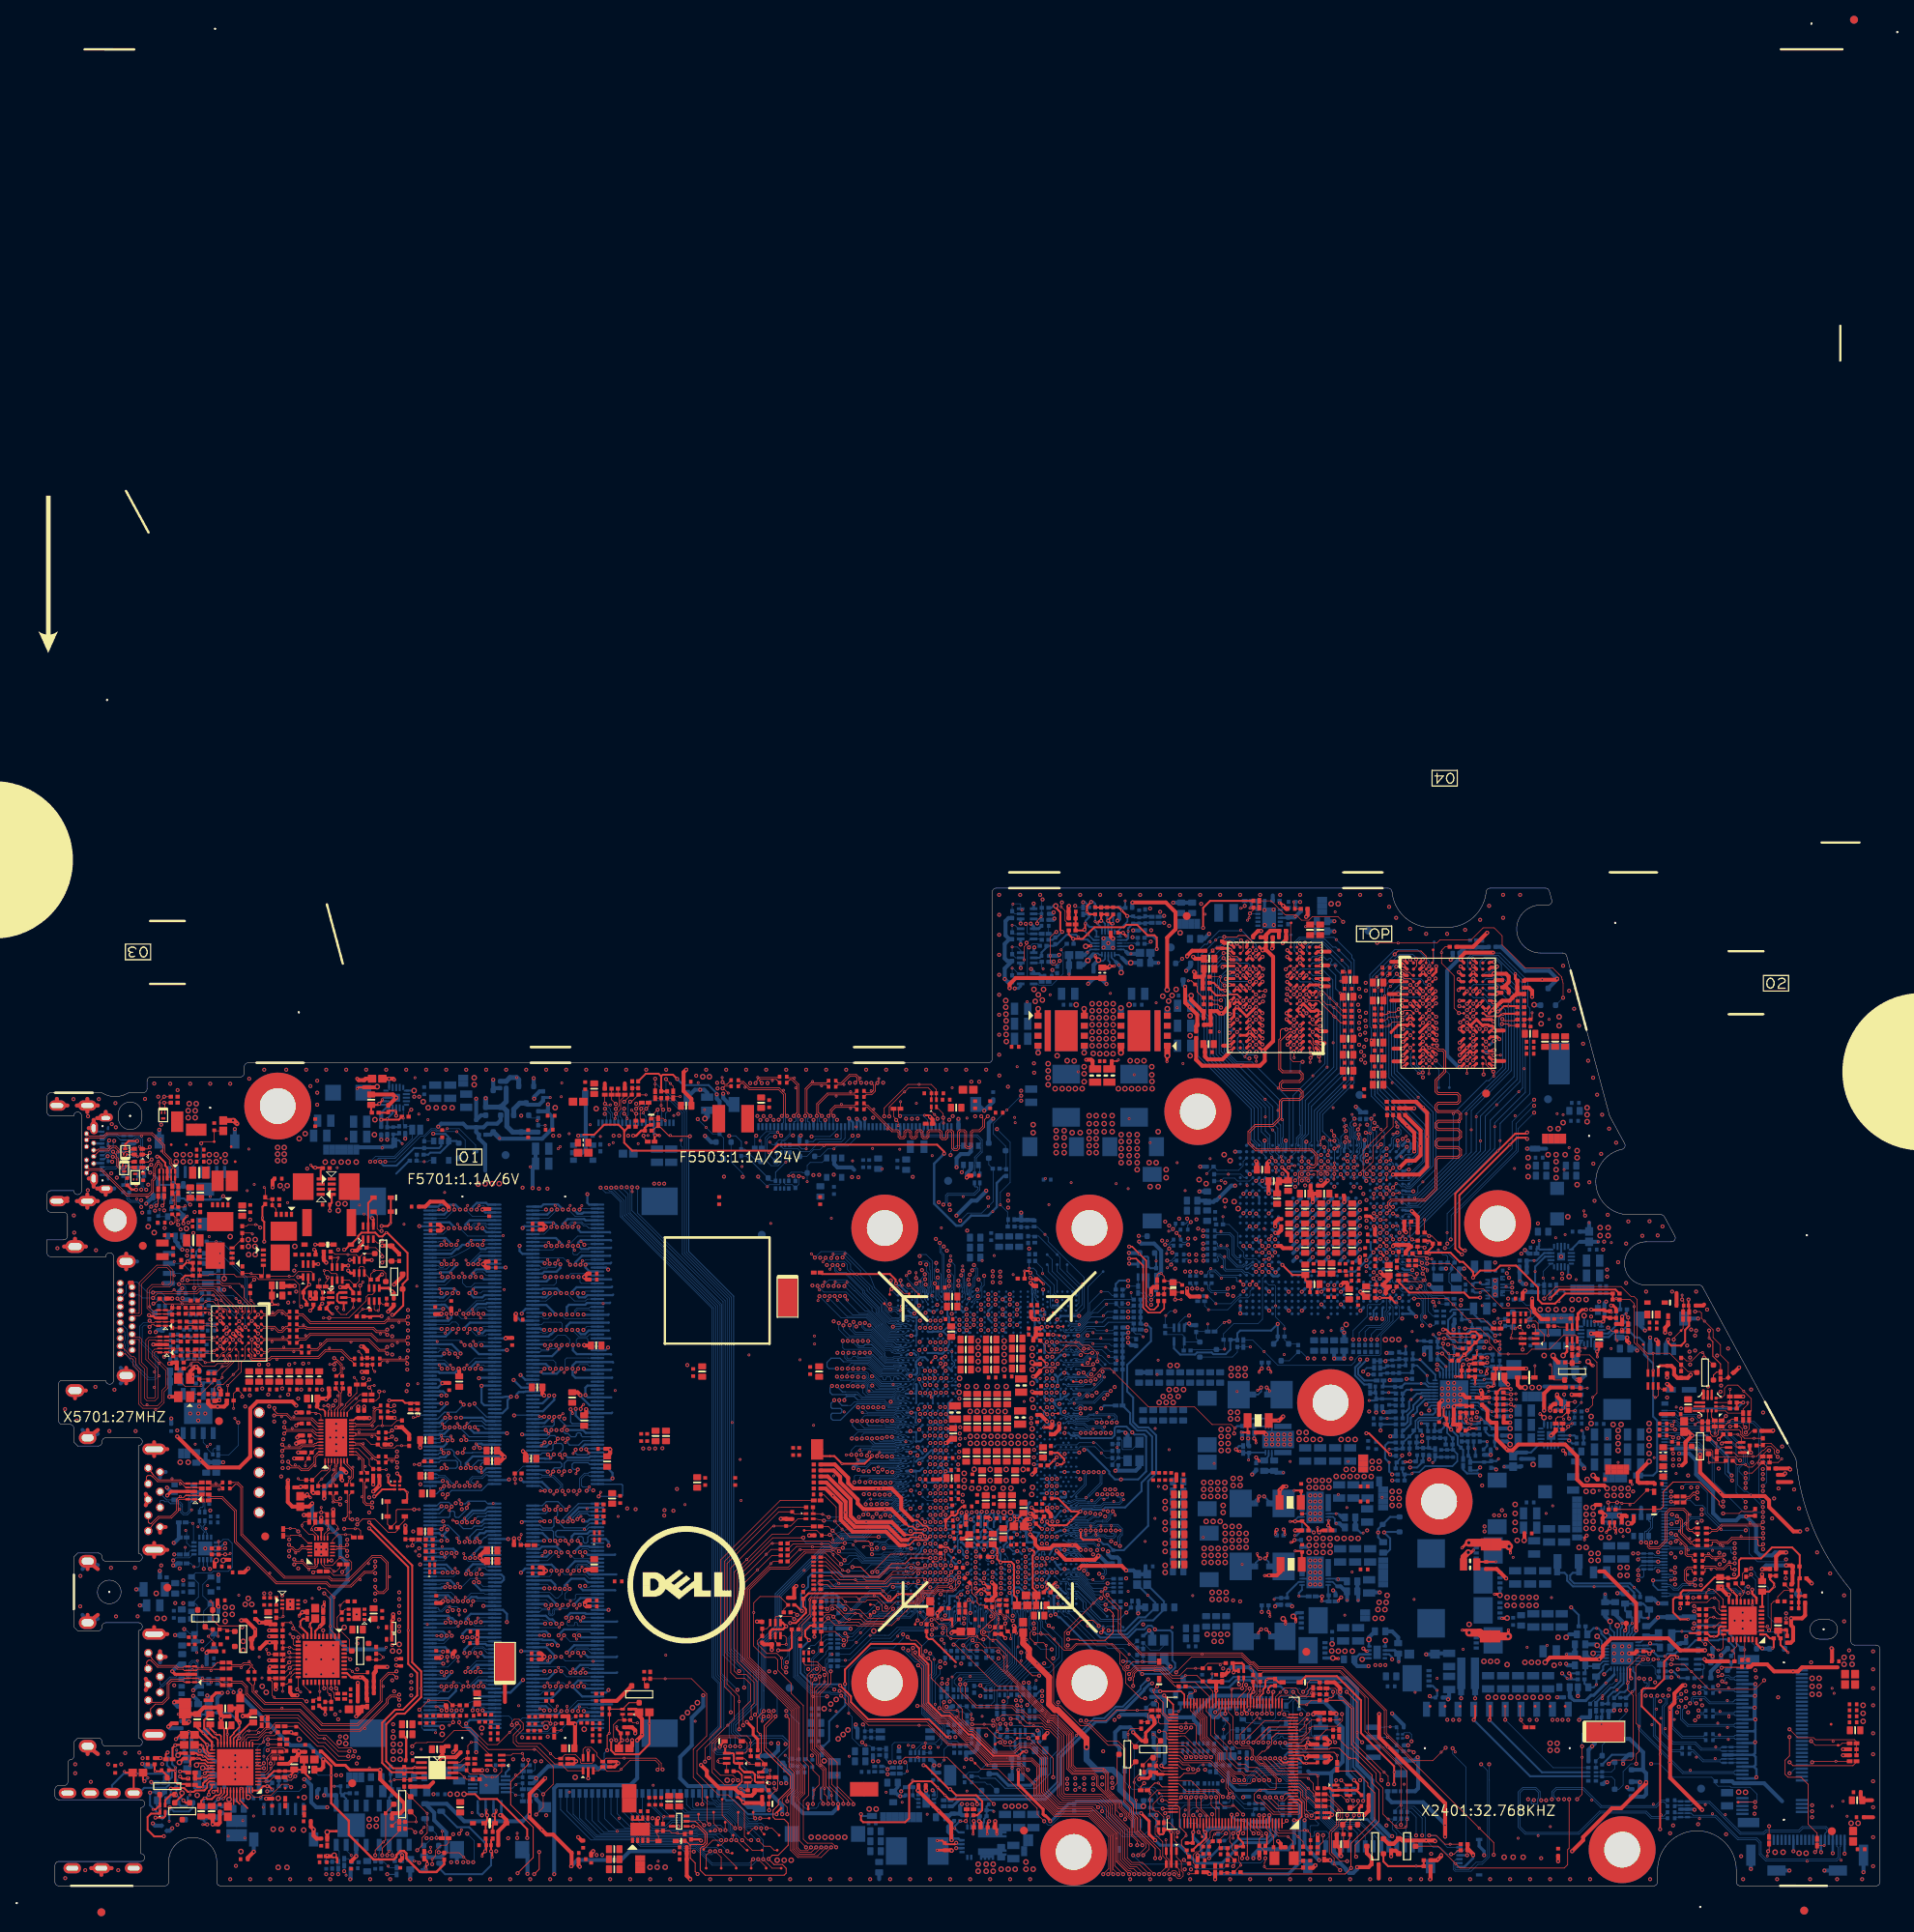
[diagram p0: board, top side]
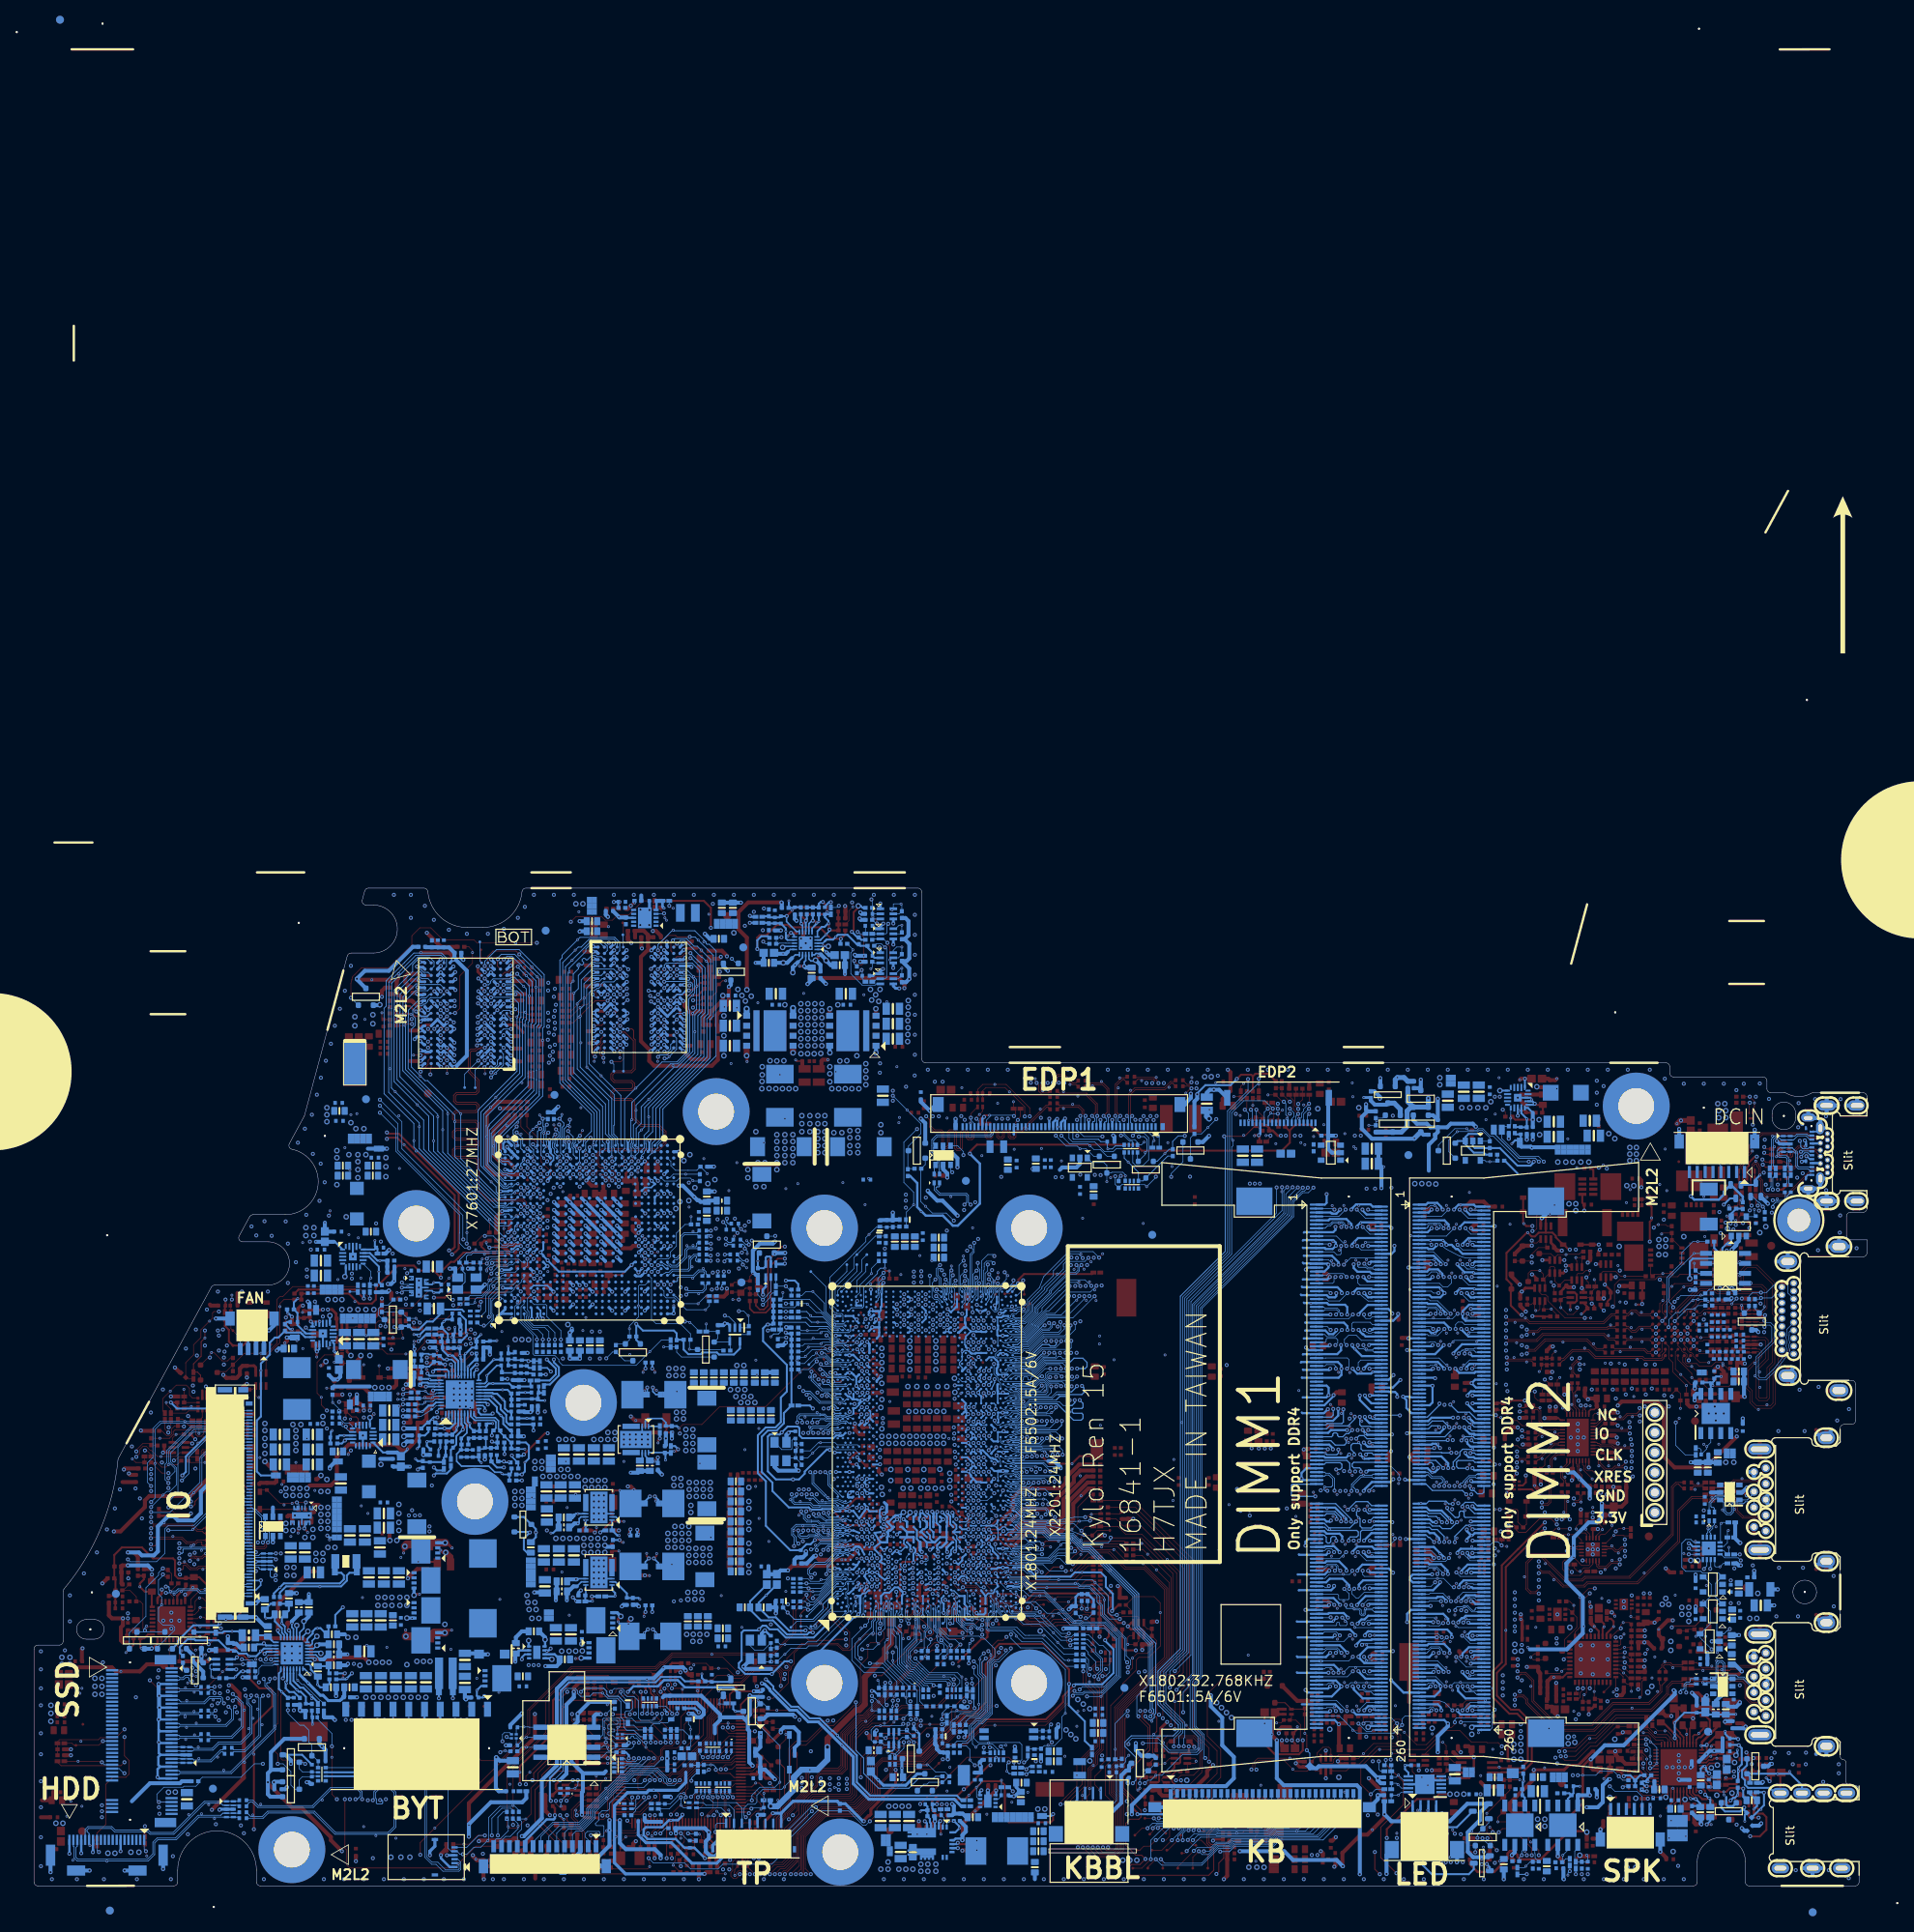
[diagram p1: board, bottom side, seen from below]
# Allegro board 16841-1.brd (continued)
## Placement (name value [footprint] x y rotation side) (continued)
R6801  0R2J-2-GP  [R402H16]  171.22 8.98 180 bottom
R6802  0R2J-2-GP  [R402H16]  171.98 8.98 180 bottom
R6803  0R2J-2-GP  [R402H16]  172.74 8.98 180 bottom
R7002  0R2J-2-GP  [R402H16]  213.66 54.04 90 top
R7003  -  [0R0402-PAD]  218.33 54.57 270 top
R7004  -  [0R0603-PAD]  207.92 58.38 180 top
R7005  10KR2J-3-GP  [R402H16]  214.17 61.43 270 top
R7006  10KR2J-3-GP  [R402H16]  214.17 60.67 90 top
R7007  -  [0R0402-PAD]  214.17 62.19 270 top
R7008  -  [0R0402-PAD]  212.06 54.72 0 top
R7009  -  [0R0402-PAD]  212.24 58.38 270 top
R7010  -  [0R0402-PAD]  210.97 58.51 180 top
R7012  -  [0R0402-PAD]  212.24 59.14 270 top
R7013  -  [0R0402-PAD]  210.21 58.51 180 top
R7014  -  [0R0402-PAD]  215.41 59.65 180 top
R7015  -  [0R0402-PAD]  216.17 59.65 180 top
R7018  100KR2J-1-GP  [R402H16]  213.33 57.39 90 top
R7301  2K49R2F-GP  [R402H16]  147.72 91.4 90 bottom
R7302  10KR2F-2-GP  [R402H16]  148.91 84.06 90 bottom
R7303  10KR2J-3-GP  [R402H16]  156.74 69.81 90 bottom
R7304  0R2J-2-GP  [R402H16]  142.01 70.7 180 bottom
R7305  0R2J-2-GP  [R402H16]  158.9 68.29 0 bottom
R7306  100KR2F-L1-GP  [R402H16]  145.94 70.83 0 bottom
R7307  200R2F-L-GP  [R402H16]  148.23 90 180 bottom
R7312  10KR2J-3-GP  [R402H16]  149.85 69.4 270 bottom
R7313  0R2J-2-GP  [R402H16]  144.8 68.03 270 bottom
R7501  60D4R2F-GP  [R402H16]  170.96 98.39 180 top
R7503  60D4R2F-GP  [R402H16]  170.2 98.39 180 top
R7505  40D2R2F-GP  [R402H16]  170.58 99.66 270 top
R7506  60D4R2F-GP  [R402H16]  171.72 98.39 180 top
R7507  42D2R2F-GP  [R402H16]  172.49 98.39 0 top
R7516  10KR2F-2-GP  [R402H16]  169.06 110.74 270 top
R7518  10KR2J-3-GP  [R402H16]  170.33 75.02 225 top
R7519  0R2J-2-GP  [R402H16]  168.65 75.14 180 top
R7520  10KR2F-2-GP  [R402H16]  167.53 97.88 180 bottom
R7521  10KR2F-2-GP  [R402H16]  166.77 97.88 180 bottom
R7524  10KR2F-2-GP  [R402H16]  165.25 109.69 90 top
R7601  10KR2J-3-GP  [R402H16]  172.99 80.35 270 top
R7602  10KR2J-3-GP  [R402H16]  171.67 81.02 180 top
R7603  1MR2J-1-GP  [R402H16]  178.33 79.21 90 bottom
R7604  1K3R2J-GP  [R402H16]  176.55 79.21 270 bottom
R7605  100KR2J-1-GP  [R402H16]  176.93 71.59 90 bottom
R7607  40K2R2F-GP  [R402H16]  169.23 76.4 270 top
R7608  49K9R2F-L-GP  [R402H16]  168.17 68.29 180 bottom
R7609  49K9R2F-L-GP  [R402H16]  179.6 67.52 270 top
R7610  100KR2J-1-GP  [R402H16]  170.96 76.16 270 top
R7611  49K9R2F-L-GP  [R402H16]  167.41 68.29 180 bottom
R7614  49K9R2F-L-GP  [R402H16]  181 69.05 270 top
R7615  49K9R2F-L-GP  [R402H16]  166.64 68.29 180 bottom
R7617  10KR2J-3-GP  [R402H16]  171.44 79.01 180 top
R7618  10KR2F-2-GP  [R402H16]  174.52 82 270 top
R7619  49K9R2F-L-GP  [R402H16]  180.23 68.29 270 top
R7620  4K99R2F-L-GP  [R402H16]  174.77 80.48 270 top
R7621  4K99R2F-L-GP  [R402H16]  173.63 81.24 270 top
R7623  -  [0R0402-PAD]  212.54 64.86 0 top
R7624  10KR2F-2-GP  [R402H16]  174.52 83.02 270 top
R7625  49K9R2F-L-GP  [R402H16]  181.63 69.81 270 top
R7626  49K9R2F-L-GP  [R402H16]  165.88 68.29 180 bottom
R7627  10KR2J-3-GP  [R402H16]  213.84 64.91 135 top
R7628  49K9R2F-L-GP  [R402H16]  178.84 66.76 270 top
R7629  49K9R2F-L-GP  [R402H16]  168.93 68.29 180 bottom
R7630  -  [0R0402-PAD]  151.94 68.92 180 bottom
R7631  10KR2J-3-GP  [R402H16]  151.18 68.92 180 bottom
R7632  4K99R2F-L-GP  [R402H16]  172.82 84.42 270 top
R7633  10KR2J-3-GP  [R402H16]  185.57 72.22 0 top
R7634  -  [0R0402-PAD]  147.85 70.45 90 bottom
R7635  4K99R2F-L-GP  [R402H16]  176.42 81.62 90 top
R7636  -  [0R0402-PAD]  184.17 70.83 90 top
R7643  10KR2J-3-GP  [R402H16]  168.68 79.21 0 top
R7644  10KR2J-3-GP  [R402H16]  188.62 73.37 180 bottom
R7648  10KR2J-3-GP  [R402H16]  186.71 74.51 90 bottom
R7649  10KR2J-3-GP  [R402H16]  185.19 71.59 180 bottom
R7657  -  [0R0402-PAD]  186.33 72.22 0 top
R7801  40D2R2F-GP  [R402H16]  187.17 109.33 90 top
R7802  40D2R2F-GP  [R402H16]  187.17 110.1 90 top
R7803  931R2F-1-GP  [R402H16]  183.54 119.34 270 bottom
R7804  931R2F-1-GP  [R402H16]  187.17 115.02 90 top
R7805  549R2F-GP  [R402H16]  178.96 118.58 270 bottom
R7806  549R2F-GP  [R402H16]  187.17 114.16 270 top
R7807  1K33R2F-GP  [R402H16]  187.63 112.92 0 top
R7808  121R2F-GP  [R402H16]  187.17 111.67 90 top
R7809  1K33R2F-GP  [R402H16]  182.27 119.72 0 bottom
R7810  1KR2J-1-GP  [R402H16]  178.58 119.34 270 top
R7811  1KR2J-1-GP  [R402H16]  169.06 109.21 90 top
R7812  1KR2J-1-GP  [R402H16]  169.06 109.97 270 top
R7813  121R2F-GP  [R402H16]  187.17 110.88 90 top
R7901  1K33R2F-GP  [R402H16]  156.92 121.38 90 top
R7902  931R2F-1-GP  [R402H16]  146.52 109.42 270 top
R7903  549R2F-GP  [R402H16]  147.79 109.01 180 top
R7904  1K33R2F-GP  [R402H16]  147.33 111.17 270 top
R7905  931R2F-1-GP  [R402H16]  145.94 108.16 180 top
R7906  40D2R2F-GP  [R402H16]  147.36 112.87 270 top
R7907  549R2F-GP  [R402H16]  155.24 120.56 270 top
R7908  40D2R2F-GP  [R402H16]  147.36 112.03 270 top
R7909  1KR2J-1-GP  [R402H16]  147.21 115.53 90 top
R7910  1KR2J-1-GP  [R402H16]  165.25 110.45 90 top
R7911  1KR2J-1-GP  [R402H16]  165.25 111.21 270 top
R7912  121R2F-GP  [R402H16]  147.21 114.01 270 top
R7913  121R2F-GP  [R402H16]  147.21 114.77 270 top
R8301  0R2J-2-GP  [R402H16]  199.28 75.27 270 top
R8303  0R2J-2-GP  [R402H16]  207.54 66.66 0 top
R8304  1MR2J-1-GP  [R402H16]  207.54 64.98 0 top
R8305  0R2J-2-GP  [R402H16]  138.96 119.72 270 bottom
R8306  0R2J-2-GP  [R402H16]  128.29 116.42 0 bottom
R8307  10KR2F-2-GP  [R402H16]  121.81 90.64 0 bottom
R8308  0R2J-2-GP  [R402H16]  120.54 91.15 90 bottom
R9101  0R2J-2-GP  [R402H16]  223.29 36.41 180 top
R9102  0R2J-2-GP  [R402H16]  222.14 40.6 90 top
R9103  0R2J-2-GP  [R402H16]  223.03 39.08 270 top
R9110  0R2J-2-GP  [R402H16]  210.28 36.69 90 top
R9119  10KR2J-3-GP  [R402H16]  207.92 36.66 90 top
R9120  10KR2J-3-GP  [R402H16]  221.13 38.31 90 top
R9129  100R2F-L1-GP-U  [R402H14]  215.79 39.71 180 top
R9130  0R2J-2-GP  [R402H16]  210.28 34.4 270 top
R9131  10KR2J-3-GP  [R402H16]  220.24 36.16 90 top
R9132  33R2J-2-GP  [R402H16]  210.28 35.17 90 top
R9133  0R2J-2-GP  [R402H16]  214.9 38.44 90 top
R9134  33R2J-2-GP  [R402H16]  210.28 31.36 90 top
R9138  10KR2J-3-GP  [R402H16]  222.02 37.55 270 top
R9139  33R2J-2-GP  [R402H16]  210.28 32.88 90 top
R9140  10KR2J-3-GP  [R402H16]  210.28 33.64 90 top
R9141  10KR2J-3-GP  [R402H16]  216.05 28.28 0 top
R9142  0R2J-2-GP  [R402H16]  215.29 28.28 0 top
R9143  0R2J-2-GP  [R402H16]  221 31.33 180 top
R9144  0R2J-2-GP  [R402H16]  219.73 31.46 270 top
R9145  0R2J-2-GP  [R402H16]  218.84 39.84 0 top
R9146  0R2J-2-GP  [R402H16]  219.6 39.84 0 top
R9147  0R2J-2-GP  [R402H16]  213.51 38.7 0 top
R9148  10KR2J-3-GP  [R402H16]  213.89 28.54 270 top
R9149  0R2J-2-GP  [R402H16]  210.28 32.12 90 top
R9150  0R2J-2-GP  [R402H16]  207.92 35.9 90 top
RN801  SRN2K2J-1-GP  [ARES2H16]  125.12 21.8 180 bottom
RN803  SRN2K2J-1-GP  [ARES2H16]  123.59 21.8 180 bottom
RN1201  SRN1KJ-7-GP  [SMD-ARES4H18]  69.83 44.43 0 top
RN1301  SRN1KJ-7-GP  [SMD-ARES4H18]  48.92 40.35 0 top
RN1601  SRN10KJ-6-GP  [ARES8-CN24-MUH20]  135.91 38.19 270 bottom
RN1703  SRN10KJ-5-GP  [ARES2H18]  105.56 14.85 90 bottom
RN1704  SRN10KJ-6-GP  [ARES8-CN24-MUH20]  110.51 16.47 180 bottom
RN1801  SRN20KJ-1-GP  [SMD-ARES4H20]  73.55 22.14 90 top
RN1802  SRN1KJ-7-GP  [SMD-ARES4H18]  96.41 29.17 180 top
RN1803  SRN10J-1-GP  [ARES8-CN24-UH18]  99.97 31.08 90 bottom
RN1807  SRN2K2J-4-GP  [ARES8-CN24-UH20]  115.97 24.47 180 bottom
RN1810  SRN10KJ-5-GP  [ARES2H18]  65.68 15.84 90 top
RN1811  SRN2K2J-1-GP  [ARES2H16]  71.01 15.45 90 top
RN1812  SRN10KJ-6-GP  [ARES8-CN24-MUH20]  97.81 40.93 270 top
RN1813  SRN10KJ-6-GP  [ARES8-CN24-MUH20]  97.81 38.54 270 top
RN1902  SRN33J-5-GP-U  [SMD-ARES4H18]  96.84 46.98 270 top
RN2007  SRN1KJ-7-GP  [SMD-ARES4H18]  121.31 24.73 0 bottom
RN2008  SRN2K2J-1-GP  [ARES2H16]  119.53 24.47 0 bottom
RN2009  SRN10KJ-5-GP  [ARES2H18]  121.38 36 90 top
RN2402  SRN4K7J-8-GP  [SMD-ARES4H18]  161.82 8.98 90 top
RN2403  SRN100KJ-5-GP  [ARES8-CN24H20]  145.31 12.53 0 bottom
RN2404  SRN100KJ-5-GP  [ARES8-CN24H20]  147.85 12.53 0 bottom
RN2405  SRN100KJ-6-GP  [SMD-ARES4]  165.48 12.08 90 bottom
RN2406  SRN100KJ-6-GP  [SMD-ARES4]  151.66 26.88 0 top
RN2407  SRN100KJ-6-GP  [SMD-ARES4]  157.37 10.12 270 bottom
RN2409  SRN100KJ-5-GP  [ARES8-CN24H20]  154.58 23.33 0 bottom
RN2410  SRN100KJ-5-GP  [ARES8-CN24H20]  146.58 17.61 0 bottom
RN2411  SRN100KJ-6-GP  [SMD-ARES4]  144.55 17.61 0 bottom
RN2412  SRN100KJ-5-GP  [ARES8-CN24H20]  158.62 15.33 270 bottom
RN2413  SRN2K2J-1-GP  [ARES2H16]  141.5 7.58 0 top
RN2502  SRN10J-8-GP  [SMD-ARES4-2H18-U]  171.85 19.01 90 bottom
RN2503  SRN10J-8-GP  [SMD-ARES4-2H18-U]  158.39 19.01 90 bottom
RN2602  SRN2K2J-1-GP  [ARES2H16]  53.87 15.84 90 top
RN2701  SRN2K2J-1-GP  [ARES2H16]  30 18.3 270 top
RN2702  SRN1KJ-7-GP  [SMD-ARES4H18]  14.68 9.82 0 top
RN2901  SRN2K2J-1-GP  [ARES2H16]  18.03 16.52 90 top
RN3701  SRN2K2J-1-GP  [ARES2H16]  37.36 24.09 90 top
RN3702  SRN2K2J-1-GP  [ARES2H16]  29.48 27.52 270 top
RN4302  SRN100J-4-GP  [ARES8-CN24H20]  196.24 14.18 270 bottom
RN5501  SRN100J-4-GP  [ARES8-CN24H20]  93.49 93.69 0 bottom
RN5502  SRN100KJ-5-GP  [ARES8-CN24H20]  93.37 89.11 180 bottom
RN5503  SRN33J-5-GP-U  [SMD-ARES4H18]  112.63 99.46 0 top
RN6501  SRN10KJ-5-GP  [ARES2H18]  153.94 10.12 270 bottom
RN6502  SRN33J-5-GP-U  [SMD-ARES4H18]  149.12 10.25 270 bottom
RN6503  SRN2K2J-1-GP  [ARES2H16]  123.77 15.89 180 bottom
RN7401  SRN1K8J-GP  [ARES2H18]  178.25 74.28 90 bottom
RN7601  SRN4K7J-8-GP  [SMD-ARES4H18]  187.48 72.24 0 top
RN7602  SRN10KJ-5-GP  [ARES2H18]  146.58 74.64 90 bottom
RN7604  SRN2K2J-1-GP  [ARES2H16]  173.37 79.17 270 top
RN7605  SRN2K2J-1-GP  [ARES2H16]  172.11 77.3 270 top
RN7610  SRN100KJ-6-GP  [SMD-ARES4]  176.93 72.73 90 bottom
SKT251  SKT-G6179HT0321-001-GP  [G6179HT0321-001]  165.12 18.25 270 bottom
SPI25  MX25L12873FM2I-10G-GP  [SOIC8-1H86]  165.12 18.25 90 bottom
SPK1  ACES-CON6-20-GP-U  [50224-0060N-W01]  30.05 5.9 180 bottom
SPR1  SPRING-171-GP  [SPR5128H111]  94.05 76.6 90 top
SPR2  SPRING-171-GP  [SPR5128H111]  196.05 19.6 180 top
SPR3  SPRING-171-GP  [SPR5128H111]  58.15 26.6 270 top
SPR4  SPRING-63-GP  [SPR5630H142]  192.05 106.6 90 bottom
SSD1  SKT-MINI67P-1-GP-U  [APCI0079-P002A]  220.6 18.4 90 bottom
TC3501  SC100U6D3V6MX-GP  [C1206H71]  13.61 37.68 90 bottom
TCBD1  ACES-CON20-29-GP-U  [51530-02001-W01-U]  74.8 100.15 0 bottom
THM261  NCT7718W-GP  [MSOP8-1H44]  49.55 14.69 270 top
TP401  TPAD14-OP-GP  [TPAD14-OP]  129.05 71.08 270 top
TP402  TPAD14-OP-GP  [TPAD14-OP]  134.13 78.07 270 bottom
TP405  TPAD14-OP-GP  [TPAD14-OP]  132.48 66.98 270 top
TP406  TPAD14-OP-GP  [TPAD14-OP]  131.46 66.22 270 top
TP612  TPAD14-OP-GP  [TPAD14-OP]  127.78 72.86 90 top
TP613  TPAD14-OP-GP  [TPAD14-OP]  127.66 71.08 90 top
TP617  TPAD14-OP-GP  [TPAD14-OP]  113.56 67.02 90 top
TP618  TPAD14-OP-GP  [TPAD14-OP]  112.29 66.51 0 top
TP638  TPAD14-OP-GP  [TPAD14-OP]  134.64 34.25 180 bottom
TP801  TPAD14-OP-GP  [TPAD14-OP]  130.32 64.1 0 top
TP1603  TPAD14-OP-GP  [TPAD14-OP]  116.48 32.47 180 bottom
TP1604  TPAD14-OP-GP  [TPAD14-OP]  117.37 33.36 180 bottom
TP1605  TPAD14-OP-GP  [TPAD14-OP]  134.39 66.25 180 bottom
TP1606  TPAD14-OP-GP  [TPAD14-OP]  128.54 69.94 0 top
TP1705  TPAD14-OP-GP  [TPAD14-OP]  128.29 80.22 270 bottom
TP1708  TPAD14-OP-GP  [TPAD14-OP]  115.16 41.72 270 top
TP1709  TPAD14-OP-GP  [TPAD14-OP]  134.13 32.98 180 bottom
TP1802  TPAD14-OP-GP  [TPAD14-OP]  126.13 60.79 0 top
TP1803  TPAD14-OP-GP  [TPAD14-OP]  128.42 60.03 0 top
TP1903  TPAD14-OP-GP  [TPAD14-OP]  96.16 45.17 0 top
TP2101  TPAD14-OP-GP  [TPAD14-OP]  113.78 40.3 0 top
TP2102  TPAD14-OP-GP  [TPAD14-OP]  112.51 41.2 0 top
TP2301  TPAD14-OP-GP  [TPAD14-OP]  107.03 75.16 0 top
TP2302  TPAD14-OP-GP  [TPAD14-OP]  106.35 74 0 top
TP2303  TPAD14-OP-GP  [TPAD14-OP]  109.5 75.24 0 top
TP2304  TPAD14-OP-GP  [TPAD14-OP]  110.72 75.16 0 top
TP2305  TPAD14-OP-GP  [TPAD14-OP]  104.52 34.53 0 top
TP2306  TPAD14-OP-GP  [TPAD14-OP]  104.57 35.75 0 top
TP2307  TPAD14-OP-GP  [TPAD14-OP]  110.26 33.23 0 top
TP2308  TPAD14-OP-GP  [TPAD14-OP]  135.4 32.98 180 bottom
TP2309  TPAD14-OP-GP  [TPAD14-OP]  136.67 32.85 180 bottom
TP2310  TPAD14-OP-GP  [TPAD14-OP]  128.29 78.95 180 bottom
TP2311  TPAD14-OP-GP  [TPAD14-OP]  129.56 78.95 180 bottom
TP2312  TPAD14-OP-GP  [TPAD14-OP]  127.02 80.22 180 bottom
TP2313  TPAD14-OP-GP  [TPAD14-OP]  127.02 78.95 180 bottom
TP2401  TPAD14-OP-GP  [TPAD14-OP]  160.04 21.17 0 top
TP3701  TPAD14-OP-GP  [TPAD14-OP]  33.42 24.62 0 top
TP4401  TPAD28-2-GP  [TPAD28]  200.55 33.36 90 top
TP4601  TPAD14-OP-GP  [TPAD14-OP]  182.3 60.57 180 bottom
TP7503  TPAD14-OP-GP  [TPAD14-OP]  170.12 89.7 0 top
TP7601  TPAD14-OP-GP  [TPAD14-OP]  151.53 76.87 90 top
TP7602  TPAD14-OP-GP  [TPAD14-OP]  153.97 75.93 0 top
TP7603  TPAD14-OP-GP  [TPAD14-OP]  169.75 81.74 0 top
TP7604  TPAD14-OP-GP  [TPAD14-OP]  168.8 80.96 0 top
TP7605  TPAD14-OP-GP  [TPAD14-OP]  153.11 76.85 90 top
TP7701  TPAD14-OP-GP  [TPAD14-OP]  169.75 80.08 90 top
TP7801  TPAD14-OP-GP  [TPAD14-OP]  176.76 101.44 270 bottom
TP7802  TPAD14-OP-GP  [TPAD14-OP]  176.17 119.97 270 bottom
TP7803  TPAD14-OP-GP  [TPAD14-OP]  176.04 118.96 90 top
TP7804  TPAD14-OP-GP  [TPAD14-OP]  178.1 101.45 270 bottom
TP7901  TPAD14-OP-GP  [TPAD14-OP]  159.16 103.53 90 bottom
TP7902  TPAD14-OP-GP  [TPAD14-OP]  158.01 122.39 270 top
TP7903  TPAD14-OP-GP  [TPAD14-OP]  158.01 120.86 90 bottom
TP7904  TPAD14-OP-GP  [TPAD14-OP]  157.94 103.53 90 bottom
TP8301  TPAD14-OP-GP  [TPAD14-OP]  192.68 75.53 180 bottom
TP8304  TPAD14-OP-GP  [TPAD14-OP]  201.06 27.52 90 top
TPCON1  ACES-CON8-66-GP  [51574-0084N-W01]  141.4 4.65 180 bottom
U3401  TPS2544RTER-GP  [QFN16-G1D8-UH32]  20.09 42.89 0 bottom
U3501  SY6288DAAC-GP  [SOT-23-5H56]  19.58 34.89 90 bottom
U3502  SY6288DAAC-GP  [SOT-23-5H56]  19.58 38.31 90 bottom
U3503  SY6288DAAC-GP  [SOT-23-5H56]  19.96 31.08 90 bottom
U3701  CYPD4125-40LQXI-4-GP  [QFN40G6-G4D7H24]  34.82 28.79 0 top
U3702  TPS70933DRVR-GP-U  [DFN6F2-G1711-UH32]  39.31 34.5 270 top
U3703  AP2151DFMG-7-GP-U  [DFN6G1820-G1511-UH24]  30.88 35.77 90 top
U3801  TUSB546-DCIRNQR-GP  [QFN40J4060-G2848H32]  36.72 56.98 180 top
U3802  TS3DS10224RUKR-GP  [QFN20J3-G1D8H32]  34.82 42.76 180 top
U4001  G5016KD1U-GP  [DFN14J3020-G255D85H32]  198.78 47.08 180 bottom
U4002  TPS22961DNYT-GP  [DFN8F3-G2517H32]  75.33 7.2 180 top
U4006  APE8937GN2-GP-U  [DFN8G2-G1710-U1H32]  111.65 10.78 270 bottom
U4007  TC7SZ08FU-LJ-CT-GP  [SC70-5H44]  80.28 8.22 270 top
U4301  S-1004NA23I-M5T1U-GP  [SOT-23-5H52]  50.06 93.43 0 bottom
U4302  S-1004NA23I-M5T1U-GP  [SOT-23-5H52]  16.28 83.81 180 bottom
U5501  RT9724GB-GP  [SOT-23-5H51]  99.97 91.27 0 bottom
U5502  APL5324BI-TRG-GP  [SOT-23-5H58]  68.09 93.18 90 bottom
U5701  PS175HDMBGA64GTR2-B1-GP  [BGA64D7H51]  24.4 70.19 270 top
U5702  MX25L2006EM1I-12G-GP-U  [SOIC8H69]  17.95 78.47 90 bottom
U5801  AOZ2023PI-GP  [SOIC8-G3627H67]  19.2 60.03 180 bottom
U7001  LNG2DMTR-GP  [LGA12G2H40]  211.17 61.17 270 top
U7301  U74LVC1G08G-AL5-R-GP-U  [SC70-5-1H44]  143.78 70.06 0 bottom
U8301  G5016KD1U-GP  [DFN14J3020-G255D85H32]  183.92 76.03 90 bottom
U9101  NPCT650JB2YX-GP  [QFN32G5-G3D6H32]  215.36 33.71 270 top
USB1  SKT-USB34-20-GP-U  [SKT-USB34-124102-U]  1.25 93.1 90 bottom
USB2  SKT-USB13-18-GP-U  [SKT-USB13-160166-2]  5.15 49.1 90 bottom
USB3  SKT-USB13-18-GP-U  [SKT-USB13-160166-2]  5.15 25.6 90 bottom
VRAM1  H5GQ2H24AFR-T2C-GP  [BGA170D1214H48]  177.95 110.9 0 bottom
VRAM2  H5GQ2H24AFR-T2C-GP  [BGA170D1214H48]  177.95 110.9 0 top
VRAM3  H5GQ2H24AFR-T2C-GP  [BGA170D1214H48]  155.95 112.9 180 top
VRAM4  H5GQ2H24AFR-T2C-GP  [BGA170D1214H48]  155.95 112.9 180 bottom
X1801  XTAL-24MHZ-87-GP  [OSC-3225-4P-4H30]  137.99 55.21 270 bottom
X1802  X-32D768KHZ-65-GP  [SMD-OSC2H56]  108.99 19.26 0 bottom
X2201  XTAL-24MHZ-87-GP  [OSC-3225-4P-4H30]  141.12 30.06 90 bottom
X2401  XTAL-32D768KHZ-89-GP  [SMD49-12H36]  157.12 3.52 90 top
X5701  XTAL-27MHZ-137-GP  [OSC-3225-4P-4H36]  17.42 63.33 90 top
X7601  XTAL-27MHZ-85-GP-U  [OSC-3225-4P-4H30]  177.82 76.54 180 bottom

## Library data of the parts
AFTP2601-AFTP2604 AFTP2901-AFTP2904 AFTP4301-AFTP4316 AFTP6301 AFTP6303 AFTP6304 AFTP6529-AFTP6537 AFTP6540-AFTP6566 = AFTE14P-75: tolerance: ZZ.AFT14.101
BATT1 = A2014WRA-SF-10PNLNG1NS1R: tolerance: 020.F0867.0010
C715 C1120 C1202-C1206 C1208-C1210 C1303-C1310 C1324 C1325 C1704 C2601 C3513 C3514 C3718 C3819 C4006 C4009 C4012 C4013 C5843-C5845 C5853 C5855 C7004 C7323 C7517 C7604 C7804 C7813 C7907 C7918 PC1107-PC1109 = C603H38: tolerance: 78.10610.5BL
C716 C717 C719 C1101-C1111 C1114 C1116 C1117 C1119 C1121 C1124-C1127 C1207 C1214-C1221 C1225 C1226 C1313 C1315-C1322 C1326 C1327 C1805 C1806 C2101-C2109 C2116 C2117 C2120 C2121 C2418 C2714 C3401 C3508 C3516 C3517 C3703 C3704 C3715 C3722 C4031 C4032 C4034 C5508 C5725 C7312 C7319 C7711-C7714 C7728 C7736 C8305 C8307 C8309 C8310 EC1005 = C402H22: tolerance: 78.10523.5FL
C718 C720 C721 C1229 C1301 C1601 C1602 C1613 C1614 C2110-C2112 C2118 C2406-C2408 C2410-C2414 C2416 C2420-C2423 C2428 C2429 C2602 C2605 C2612 C2722 C2726 C2729 C2740 C2742 C2744 C2747-C2749 C3402 C3403 C3507 C3518 C3601-C3604 C3701 C3702 C3705 C3709 C3716 C3717 C3719 C3721 C3723 C3801-C3818 C3861-C3865 C4007 C4033 C5501 C5504 C5506 C5507 C5509-C5511 C5519 C5531-C5533 C5726-C5728 C5731-C5741 C5824-C5826 C5828 C5829 C5834 C5838 C5839 C5846 C5848 C5849 C5858 C6002 C6307 C6501 C6502 C6505 C7003 C7318 C7501 C7502 C7505 C7506 C7601 C7602 C7605 C7729 C7734 C7735 EC2712-EC2714 PC4313 PC4406 PC4420 PC4501 PC4506 PC4508 PC4513 PC4518 PC4521 PC4522 PC4530-PC4532 PC4602 PC4603 PC4630 PC4631 PC4633 PC4634 PC5004 PC5114 PC5116 PC5118 PC5123 PC5204 PC5208 PC5427 PC8202 PC8220 PC8221 PC8225 PC8226 PC8314 PC8319 = C402H22: tolerance: 78.10422.5FLDL
C1112 C1113 C1115 C1118 C2113-C2115 C2119 C2122 C3404 C3405 C3519 C3520 C4035 C4036 C6317 C6318 C7326 C7518 C7520 C7710 C7717 PC1101-PC1106 PC1114 PC1115 = C603H40: tolerance: 78.22610.5BL
C1211 C1212 C1223 C1224 C1227 C1230-C1232 C1311 C1312 C1330 C1331 = C402H22: tolerance: 078.47510.05FD
C1213 C1314 C5856 = C402H22: tolerance: 78.10523.L2L
C1222 C1323 PC4625 PC4626 = C402H22: tolerance: 78.22321.2FL
C1228 C1328 = C402H22: tolerance: 78.10421.L0L
C1329 R1216 = C603H36: tolerance: 78.22523.L1L
C1605-C1612 C3720 C4003 C6302 C6303 C6311-C6316 C7301-C7308 = C402H22: tolerance: 78.22423.5FL
C1701 EC6401 EC6402 = C402H22: tolerance: 78.22124.2FL
C1710 = C402H22: tolerance: 78.47423.5FL
C1711 = C402H22: tolerance: 78.10324.2FL
C1801 C2202 = C402H22: tolerance: 78.15034.1FL
C1802 C2201 = C402H24: tolerance: 78.12034.1FL
C1803 C1804 C2738 EC2708 PC4430 = C402H22: tolerance: 78.10034.1FLDL
C2405 = C402H22: tolerance: 78.10134.1FL
C2409 C5832 C5833 C5837 C5841 C5842 C5847 C5851 C5852 C6001 C6003 C6005 C6006 C7801 C7901 PC4303-PC4305 PC4431 PC4609 PC4613 PC4615 PC4620 PC4622 PC4635 PC4637 PC4644 PC5213 PC8204 PC8309 = C402H22: tolerance: 78.10324.2FLDL
C2424 C2425 EC1801 EC1901 EC2503 EC2601 EC2602 EC4306 EC4309 EC4310 EC6505-EC6507 = C402H22: tolerance: 78.10034.1FL
C2426 = C402H22: tolerance: 78.22523.5FL
C2430 C2431 C2435 C2603 C2607 C9101 C9104 EC8906 EC8933 EC8935 = C402H22: tolerance: 78.22224.2FL
C2501 C5535-C5537 = C805H54: tolerance: 78.10623.51L
C2502 C2608-C2610 C2614 C2721 C3503 C3515 C4017 C6504 C8308 C9102 C9113 EC1707 EC1712 EC1806-EC1808 EC1902 = C402H22: tolerance: 78.10421.2FL
C2503 C5827 C5831 C5836 C5840 C5850 = C402H22: tolerance: 078.47423.05FD
C2604 C5502 C5503 C5505 C5515 C7310 C7315 C7317 C7324 C7513 C7514 C7603 C7701-C7704 C7708 C7709 C7719-C7726 C7730-C7732 C9105 C9106 C9114 = C603H36: tolerance: 78.47520.5BL
C2606 = C603H36: tolerance: 78.47134.1BL
C2613 EC1102 EC2905 EC2906 EC8920 EC8934 PC4310 PC4311 PC4315 = C402H22: tolerance: 78.10134.1FLDL
C2727 C2730-C2736 C2743 C2745 C2907 C2908 PC5122 PC5402 PC5403 PC5413 PC5414 PC8306 PC8307 = C603H36: tolerance: 78.10610.5BLDL
C2737 C7606 PC4524 PC5001 PC5112 PC8317 = C603H36: tolerance: 78.22523.5BLDL
C2739 C2741 PC4301 PC4416 PC4417 PC4419 PC4424-PC4426 PC4439 PC4440 = C603H36: tolerance: 078.10524.05BD
C2746 PC5119 PC5120 PC8201 PC8316 = C402H22: tolerance: 78.10421.2FLDL
C3502 PC4314 = C402H22: tolerance: 078.10522.05FD
C3512 = C805H58: tolerance: 78.22610.51L
C3707 C7805-C7807 C7809-C7812 C7814 C7904-C7906 C7915-C7917 C7919 C7924 = C603H32: tolerance: 78.10524.5BL
C3710 = C603H36: tolerance: 78.22523.5BL
C3711 C3712 = C402H24: tolerance: 78.39124.2FL
C3821 C7316 C7808 C7815-C7825 C7909-C7914 C7920-C7923 C7925 C7926 EC1203 EC1903 EC2101 EC3601 EC3602 EC4302 EC4311 EC4313 EC5502 EC8901-EC8904 EC8908 EC8909 EC8911-EC8915 EC8917 EC8921 EC8923-EC8925 EC8936 EC8938 EC8951-EC8956 EC8958 PC1110-PC1113 PC4312 = C402H22: tolerance: 78.10422.5FL
C4001 C4002 C8302 C8306 = C402H22: tolerance: 78.47124.2FL
C4004 C4005 C5517 C6004 C8301 C8304 EC4301 PC4306 PC4401-PC4405 PC4407-PC4414 PC4427 PC4428 PC4502-PC4505 PC4519 PC4523 PC4701-PC4704 PC4802-PC4805 PC4814-PC4817 PC5002 PC5003 PC5111 PC5115 PC5209-PC5211 PC5216 PC8210 PC8214 PC8215 PC8224 PC8310 PC8315 = C805H58: tolerance: 78.10622.51LDL
C5512 C5516 C5542 EC4308 = C603H36: tolerance: 78.10424.2BL
C5513 C5534 EC2002 EC2709-EC2711 EC2901-EC2904 EC4307 EC4312 EC8907 EC8910 EC8916 EC8919 EC8922 EC8937 EC8941 EC8945 EC8947 EC8957 EC8959 EC8961 EC8963 EC8967 EC8974-EC8977 EC8979 EC8983 EC8984 EC8987 EC8988 EC8994 EC8996 EC8999 PC4307 PC4432 PC4433 PC4435 PC4526 PC4533 PC4616-PC4619 PC4642 PC4643 PC4651 PC4706 PC4810 PC4813 PC5215 PC8203 = C402H22: tolerance: 78.10224.2FLDL
C5514 PC8208 PC8209 PC8212 PC8213 = C805H54: tolerance: 78.47522.51LDL
C5724 = C0201H13: tolerance: 078.R7574.01S1
C5729 C5730 C7607 C7608 = C402H22: tolerance: 78.18034.1FL
C5857 C5860 C5861 = C603H38: tolerance: 78.10610.L0L
C5859 = C402H22: tolerance: 78.68034.1FL
C6304 C6305 EC5505 EC6501-EC6504 EC6601-EC6603 = C402H22: tolerance: 78.33034.1FL
C6306 C6308 = C402H22: tolerance: 78.47322.2FL
C7507 C7525 PC4438 PC4607 PC4708 PC4809 PC4812 PC5110 PC5121 PC5202 PC5401 PC5410 PC8301 PC8318 = C402H22: tolerance: 78.10523.5FLDL
C7802 C7803 C7826 C7902 C7903 C7908 = C402H22: tolerance: 78.82124.2FL
CCGDB1 = JD11P8204-061: tolerance: 21.61836.106
CPU1 = BGA1356M4224-U2H52: tolerance: 071.SKYLA.000U
D502 EC401 EC1701-EC1705 EC1708 EC1709 ED1217 ED1302 ED2403 ED5502 = SOD882-10D6-1H20: tolerance: 83.05725.0A0
D1701 D2402 D2403 D4002-D4005 PD4306-PD4310 PD4407 = SOD323AKH38: tolerance: 83.R2004.G8F
D2401 D2702 D5501 D5502 D8301 PD4401 PD4408 = SOT-23-9H44: tolerance: 75.00054.A7D
D2501 = SOT-23-9H44: tolerance: 75.00040.07D
D2601 = SOD323AKH38: tolerance: 83.R5003.H8H
D3701 D3702 = D1006-0305AK-UH22: tolerance: 083.00520.0F8F
D4001 = SOT23-2D4-312H44: tolerance: 83.00016.P11
D4304-D4306 PD4302 = SOT23-2D4-312H44: tolerance: 75.00099.O7D
D5701 = SOT23-2D4-312H44: tolerance: 83.00056.Y11
D7001 = SOT23-2D4-312H48: tolerance: 75.00054.R7D
D7301 = SOT-23-9H44: tolerance: 75.BAT54.07D
DB1 = DM-87212-1400N-01: tolerance: ZZ.F0765.01401
DBEC1 = 50696-00601-001: tolerance: 20.K0691.006
DCIN1 = 50224-0080N-W02-U: tolerance: 20.F1295.008
DM1 = ADDR0206-P013A: tolerance: 062.10011.01C1
DM2 = ADDR0205-P012A: tolerance: 062.10011.01B1
EC1001-EC1004 EC1006 EC1007 = C402H22: tolerance: 78.10422.L1L
EC1103 EC1202 EC1302 EC1303 EC1710 = C402H22: tolerance: 78.22510.5FLDL
EC1706 EC8905 EC8918 EC8927-EC8929 EC8939 EC8940 EC8942-EC8944 EC8946 EC8948 EC8949 EC8960 EC8962 EC8964-EC8966 EC8968-EC8973 EC8978 EC8980-EC8982 EC8985 EC8986 EC8989 EC8992 EC8993 EC8995 EC8997 EC8998 = C402H22: tolerance: 78.10224.2FL
EC1803 EC2501 EC2502 = C402H22: tolerance: 78.4R7B4.1FL
EC2907 EC2908 PC4621 PC8312 = C402H22: tolerance: 78.68124.2FLDL
EC5501 = C402H22: tolerance: 78.6R874.1FLDL
EC5503 = C402H22: tolerance: 78.22034.1FL
EC5504 PC4610 PC4624 PC4639 = C402H22: tolerance: 78.33034.1FLDL
ED2901-ED2903 = SOT23-2D4-312H46: tolerance: 75.05125.07D
ED3601 ED3603 ED3801 ED3802 ED5701 ED5702 ED6001 ED6301 ED6602 = SLP2510P8-1H22: tolerance: 075.00550.0071
ED3602 ED3604 ED5501 ED6601 = SOT-6H58: tolerance: 75.09904.07C
ED3803-ED3806 = SOT883-1D0-321H20: tolerance: 83.05315.0A0
ED6401 ED6402 = SOD-523-2H26: tolerance: 83.0005V.0AF
EL3602 EL3603 EL3801 EL3802 EL5501 EL6601 EL6603 = L125100-4P-4H24: tolerance: 68.00396.001
EL4301-EL4304 PR4414 PR4420 R705 R2707 R2712 R2739 R4101 = 0R0805-PAD: tolerance: ZZ.R0805.ZZZ
ER5744 ER5745 ER5758 ER5759 = R402H16: tolerance: 63.18134.1DL
F5502 F6501 = POLYSW-2114H50: tolerance: 69.50007.921
F5503 = POLYSW-4633-UH43: tolerance: 69.50007.A31
F5701 = POLYSW-2114H30: tolerance: 69.48001.081
FAN1 = 50224-0040N-001: tolerance: 20.F1639.004
G1801 = CON2O-U: tolerance: ZZ.CON2O.XXX
GPU1 = BGA595M23H83: tolerance: 071.0N16S.0A0U
H1-H8 H11 H12 H14 = HOLE335R178: tolerance: ZZ.00PAD.7F1
HDA27 = QFN48J6-G465H40: tolerance: 071.03254.0003
HDD1 = 50406-02071-001: tolerance: 20.F2036.020
HDMI2 = SKT-HDMI23-187137-1: tolerance: 022.10025.0191
HPMIC1 = AJ3R1S-Y050-412: tolerance: 022.10002.0931
HS2 = STF217R115H101: tolerance: 434.04X0C.1001
IOBD1 = 20525-060E-02-U: tolerance: 020.F0200.0060
KB1 = 196528-30041-3: tolerance: 020.K0210.0030
KBBL2 = 50698-00401-W01-U: tolerance: 020.K0298.0004
KBC24 = TQFP128-2H48: tolerance: 071.01416.000G
L3801 = L402H22: tolerance: 068.00006.0141
L5801-L5805 = L603H38: tolerance: 68.00084.J11
L7301 = L1608-UH38: tolerance: 68.00230.041
L7501 L7601 = L603H38: tolerance: 68.00335.051
L7602 = L603H38: tolerance: 68.00909.261
LCD1 = 300E50-1030RA-G4: tolerance: 020.F0688.0050
LEDCN1 = 50524-00401-001: tolerance: 020.K0037.0004
PC1001-PC1032 PC1034 PC1036-PC1084 PC5201 PC5203 PC5205 PC5206 PC8303 PC8304 PC8311 PC8313 PC8320 PC8321 = C603H40: tolerance: 78.22610.5BLDL
PC4302 PC5214 PC8207 PC8211 PC8216 = C603H35: tolerance: 78.10424.2BLDL
PC4415 PC4421 PC4422 PC4507 PC4520 = C603H36: tolerance: 78.47520.5BLDL
PC4423 PC4436 PC4606 PC4707 PC4808 PC4811 PC5005 = C603H36: tolerance: 78.22422.2BLDL
PC4429 PC5406 = C402H22: tolerance: 78.47224.2FLDL
PC4441-PC4443 = C805H58: tolerance: 078.22612.051D
PC4509-PC4512 PC4514-PC4517 PC4525 PC4527 PC4529 PC5104 PC5105 PC5107 PC5109 PC5124 PC5404 PC5412 = C805H54: tolerance: 78.22610.51LDL
PC4601 PC4611 PC4612 PC4623 PC4632 PC4640 = C402H22: tolerance: 78.22224.2FLDL
PC4604 PC4614 PC4629 PC4638 PC4641 PC8308 = C402H22: tolerance: 78.33124.2FLDL
PC4605 PC4653 = C402H22: tolerance: 078.47322.02FD
PC4608 PC4652 = C402H22: tolerance: 78.22321.2FLDL
PC4628 = C402H22: tolerance: 78.33321.2FLDL
PC5113 = C402H22: tolerance: 78.47124.2FLDL
PC5212 = C402H22: tolerance: 78.22124.2FLDL
PC5405 PC5411 = C402H22: tolerance: 78.68034.1FLDL
PC8205 PC8219 PC8222 PC8322 = C402H22: tolerance: 78.47034.1FLDL
PC8206 PC8218 = C402H22: tolerance: 78.33134.1FLDL
PC8223 = C402H22: tolerance: 78.27224.2FLDL
PC8302 PC8323 = C402H22: tolerance: 78.22034.1FLDL
PD4301 = DO214AAAKH97: tolerance: 83.P6SMB.JAG
PD4303 = SOT23-2D4-312H60: tolerance: 83.03024.0A1
PD4304 = SOD123AK-2H43: tolerance: 83.SMF18.AAH
PD4305 = SOD323AKH38: tolerance: 83.R2004.B8F
PD4404 = SOD323AKH44: tolerance: 83.00355.G1F
PG4401 PG4402 PG4405 PG4406 PG4408 PG4501-PG4524 PG4527-PG4532 PG4701-PG4708 PG4802-PG4806 PG4808-PG4816 PG5001-PG5003 PG5011 PG5105-PG5115 PG5120 PG5121 PG5201 PG5204 PG5206-PG5216 PG5223 PG5405-PG5409 PG5801-PG5803 PG8301-PG8320 = GAP-CLOSE-PWR-3: tolerance: ZZ.CLOSE.001
PL4401 = L11510030H158: tolerance: 68.2R210.20C
PL4501 = L4947-1015H119: tolerance: 68.1R550.20C
PL4502 PL5201 = L7066-1830-UH119: tolerance: 68.1R01A.20B
PL4701 PL4801 PL4802 = L7366-1930H158: tolerance: 68.R1510.20A
PL5001 = L7066-1830-UH119: tolerance: 68.R4710.10M
PL5101 = L4947-1115H119: tolerance: 68.1R010.20R
PL8201 PL8202 = L6965-1530H158: tolerance: 68.R361A.10B
PL8301 = L2520-D620H48: tolerance: 068.1R010.1131
PL8302 = L4947-1015H119: tolerance: 68.R6810.20E
PQ4301 PQ4314 Q501 Q6105 = SOT23DGS2D4H48: tolerance: 84.05067.031
PQ4302 Q2603 = SOT23CBE2D4H46-U: tolerance: 84.T3904.K11
PQ4304 = SOT323CBE2D2H40: tolerance: 84.05212.B11
PQ4305 = SC70-2D2-312H44: tolerance: 84.00024.01K
PQ4306 PQ4312 PQ4402 Q1802 Q2408 Q2414 Q2505 Q2602 Q2701 Q3701 Q6503 Q7301 Q7606 Q7801 Q7901 Q8301 = SOT23DGS2D4H44: tolerance: 84.2N702.031
PQ4307-PQ4311 PQ4313 PQ4405 PQ4415 PQ4416 PQ8301 PQ8305-PQ8308 Q1702 Q1801 Q2416 Q2417 Q2601 Q6504 Q7001 Q7601 = SOT-363H44: tolerance: 84.2N702.A3F
PQ4408 = SOT23CBE2D4H44: tolerance: 84.T3906.A11
PR4302 PR8327 = R402H16: tolerance: 64.15025.6DL
PR4303 PR4335 PR8258 PR8259 R802 R1503 R1606-R1608 R1701 R1707 R1714 R1717 R1726 R1738 R1816 R1820 R1911-R1920 R2002 R2009 R2010 R2029-R2038 R2040-R2047 R2050-R2053 R2415 R2426 R2429 R2430 R2458 R2464 R2473 R2607 R2726 R2743 R3738 R3818 R4003 R4009 R5736 R5737 R5741 R6120 R6303 R6304 R6511 R7005 R7006 R7303 R7312 R7518 R7601 R7602 R7617 R7627 R7631 R7633 R7643 R7644 R7648 R7649 R9119 R9120 R9131 R9138 R9140 R9141 R9148 = R402H16: tolerance: 63.10334.1DL
PR4304 R1836 R2745 R3707 R5751 R5755 = R402H16: tolerance: 63.22234.1DL
PR4305 PR4306 R9132 R9134 R9139 = R402H16: tolerance: 63.33034.1DL
PR4307 = R603H22: tolerance: 63.24434.15L
PR4308 PR4321 R1719 R2517 = R402H16: tolerance: 64.47025.6DL
PR4309 PR4318 PR4345 PR4473 PR4505 PR4510 PR5104 PR5208 PR8203 PR8307 PR8315 PR8317 PR8319 PR8328 R404 R603 R803 R1715 R1727 R1737 R2407 R2417 R2434 R2436 R2449-R2451 R2454 R2480 R2484 R2489 R2496 R2742 R2744 R2747 R3501 R4031 R4032 R5504 R5545 R5758 R6508 R6509 R6604 R7018 R7605 R7610 = R402H16: tolerance: 63.10434.1DL
PR4310 PR8256 PR8310 R401 R417 R419 R604 R605 R1702 R1822-R1825 R1909 R1910 R2007 R2019 R2432 R2463 R3840-R3843 R3845-R3847 R3852 R3870-R3874 R4005 R6513 R7810-R7812 R7909-R7911 = R402H16: tolerance: 63.10234.1DL
PR4311 PR4323 PR4324 PR4332 PR4340 PR4342 PR4347 PR4406 PR4409 PR4417 PR4474 PR4821-PR4824 PR5203 PR5402 PR8304 PR8311 R1716 R2441 R2444 R3730 R3734 R6305 R7306 = R402H16: tolerance: 64.10035.6DL
PR4312 = R402H16: tolerance: 64.47035.6DL
PR4313 = R402H16: tolerance: 64.84525.6DL
PR4315 = R402H16: tolerance: 64.18725.6DL
PR4316 R1731 R2727 = R402H16: tolerance: 63.20334.1DL
PR4317 PR4501 PR4502 PR8210 PR8211 PR8324 R1102-R1104 R1711 R2106-R2111 R2446 R2705 R2724 R2749 R2751 R2906 R2907 R2909 R2911 R2923 R3732 R3736 R3812 R5507 R5520 R5527 R5528 R6006 R6302 R6307 R6514 R7004 = 0R0603-PAD: tolerance: ZZ.R0603.ZZZ
PR4319 PR4343 R2741 = R402H16: tolerance: 64.20035.6DL
PR4320 PR4330 PR4337 = R402H16: tolerance: 64.24035.6DL
PR4322 PR4327 PR4333 PR4450 PR5204 PR5410 R1306 R2001 R2448 R3709 R3725 R3726 R5542 R5803 R7302 R7516 R7520 R7521 R7524 R7618 R7624 R8307 = R402H16: tolerance: 64.10025.6DL
PR4328 PR5101 PR5107 PR8206 PR8222 R2424 R3403 R4006 R6504 = R402H16: tolerance: 64.20025.6DL
PR4336 PR4344 = R402H16: tolerance: 63.68434.1DL
PR4338 = R2512H28: tolerance: 63.10135.17L
PR4339 = R402H16: tolerance: 64.64925.6DL
PR4341 PR4412 PR4462 PR4476 PR4477 PR4504 PR4515 PR4516 PR5114 PR5118 PR5125 PR5209 PR5210 PR5406 PR5408 PR5417 PR8207 PR8220 PR8221 PR8257 PR8308 PR8320-PR8322 PR8325 PR8330 PR8331 R410 R504 R602 R709 R732 R804 R1205 R1210 R1212 R1303 R1311 R1609 R1610 R1704 R1706 R1708 R1713 R1720 R1728 R1812 R1813 R1908 R2003 R2004 R2020 R2021 R2023 R2024 R2101 R2402 R2406 R2428 R2435 R2445 R2447 R2459 R2462 R2470 R2472 R2477 R2478 R2490 R2515 R2602 R2611-R2614 R2617 R2721 R2729 R2730 R2737 R2738 R2740 R2752 R2753 R2905 R2912-R2915 R2921 R2922 R3401 R3402 R3405 R3406 R3605 R3606 R3609-R3614 R3727-R3729 R3731 R3733 R3814 R3816 R3832-R3839 R3849 R3853-R3860 R4002 R4011 R4024 R4029 R4030 R4036 R4038 R4042 R4301 R5501 R5503 R5521-R5523 R5540 R5543 R5544 R5710-R5717 R6001 R6002 R6301 R6308 R6403 R6404 R6510 R6512 R6605 R6606 R7003 R7007-R7010 R7012-R7015 R7623 R7630 R7634 R7636 R7657 = 0R0402-PAD: tolerance: ZZ.R0402.ZZZ
PR4346 = R402H16: tolerance: 64.13735.6DL
PR4401 = R1206H24: tolerance: 64.R0205.81L
PR4402 PR4408 PR4804 PR4810 = R603H22: tolerance: 64.2R205.55L
PR4403 PR4416 = R805H24: tolerance: 63.2R231.16L
PR4404 = R402H16: tolerance: 64.40235.6DL
PR4405 = R402H16: tolerance: 64.4R705.6DL
PR4407 = R3720H40: tolerance: 64.R0105.7FL
PR4410 = R402H16: tolerance: 64.10535.60L
PR4411 PR4636 PR4658 R403 R6401 = R402H16: tolerance: 64.49905.6DL
PR4413 = R402H16: tolerance: 64.60415.6DL
PR4422 PR4423 = R402H16: tolerance: 64.3R305.6DL
PR4424 PR4425 = R402H16: tolerance: 64.1R005.L0L
PR4426 = R402H16: tolerance: 64.19635.6DL
PR4427 PR4429 = R402H16: tolerance: 64.10035.L1L
PR4435 PR4472 = R402H16: tolerance: 64.10035.L3L
PR4436 PR4513 PR4514 PR5105 R1802 R2201 R3706 R4304 R7603 R8304 = R402H16: tolerance: 63.10534.1DL
PR4463 PR4503 PR4530 PR5103 PR5106 PR5126 PR8323 R738 R1809 R1810 R1838 R2025-R2028 R2039 R2202 R2203 R2408 R2409 R2418 R2427 R2439 R2461 R2471 R2475 R2479 R2494 R2499 R2601 R2615 R2616 R2746 R2754 R3861-R3864 R4010 R4017 R4033 R4037 R4305 R4306 R5502 R5761 R6505 R6506 R6801-R6803 R7002 R7304 R7305 R7313 R7519 R8301 R8303 R8305 R8306 R8308 R9101-R9103 R9110 R9130 R9133 R9142-R9147 R9149 R9150 = R402H16: tolerance: 63.R0034.1DL
PR4475 = R402H16: tolerance: 64.68035.6DL
PR4478 PR4627 PR4631 PR4639 PR4659 PR4663 PR8212 PR8213 R503 R719-R722 R726 R734 R735 R1501 R1604 R9129 = R402H14: tolerance: 64.10005.6DL
PR4506 PR4507 PR4509 PR4511 PR4603 PR4615 PR4635 R4303 R5760 = R402H16: tolerance: 64.10015.6DL
PR4508 PR4512 = R402H16: tolerance: 64.20035.L0L
PR4551 = R402H16: tolerance: 64.34835.6DL
PR4601 PR4602 PR4612 PR4613 PR4623 PR4647 PR4649 PR4665-PR4668 PR4701 PR4702 PR4706 PR4802 PR4806 PR4811 PR4812 PR5004 R5801 = 0R0402-PAD: tolerance: ZZ.R0402.001
PR4604 PR4607 = R402H16: tolerance: 64.10005.L1L
PR4605 = R402H16: tolerance: 64.75R05.6DL
PR4606 = R402H16: tolerance: 64.45R35.6DL
PR4608 = R402H16: tolerance: 64.90925.6DL
PR4609 PR4616 PR4662 R1204 R1208 R1211 R1302 R1310 R3742 = R402H15: tolerance: 64.10025.L0L
PR4610 = R402H16: tolerance: 63.1R034.1DL
PR4611 PR4646 PR4650 = NTC-402H22-U: tolerance: 69.60037.011
PR4614 PR4669 R1307 = R402H15: tolerance: 63.R0034.L0L
PR4617 PR4654 = NTC-402H22-U: tolerance: 69.60037.021
PR4618 PR4643 PR4652 = R402H16: tolerance: 64.11025.6DL
PR4620 = R402H16: tolerance: 64.39205.6DL
PR4621 PR4655 = R402H16: tolerance: 64.27425.6DL
PR4622 PR4809 PR4815 = R402H16: tolerance: 64.10R05.L1L
PR4624 = R402H16: tolerance: 64.49R95.L0L
PR4625 PR4641 PR4653 = R402H16: tolerance: 64.26115.6DL
PR4626 = R402H16: tolerance: 64.33015.6DL
PR4628 = R402H16: tolerance: 64.93115.6DL
PR4629 PR4672 PR5201 = R402H16: tolerance: 64.88725.6DL
PR4630 PR4638 PR4657 = R402H16: tolerance: 64.20015.L0L
PR4632 = R402H16: tolerance: 64.30105.6DL
PR4633 = R402H16: tolerance: 64.30115.6DL
PR4637 = R402H16: tolerance: 64.16915.6DL
PR4640 = R402H16: tolerance: 64.24915.L0L
PR4642 = R402H16: tolerance: 64.32405.6DL
PR4644 = R402H16: tolerance: 64.11335.6DL
PR4645 PR4651 = R402H15: tolerance: 64.10015.L3L
PR4648 = R402H16: tolerance: 64.27405.6DL
PR4656 = R402H16: tolerance: 64.28715.6DL
PR4660 = R402H16: tolerance: 64.19115.6DL
PR4661 = R402H16: tolerance: 64.86625.6DL
PR4670 = R402H16: tolerance: 64.26705.6DL
PR4671 = R402H16: tolerance: 64.15415.6DL
PR4703 PR4805 PR4814 = R1206H28: tolerance: 63.2R232.11L
PR4704 PR4803 PR4813 PR8202 PR8301 = R402H16: tolerance: 64.2R205.6DL
PR4705 PR5001 = R603H24: tolerance: 64.2R205.L0L
PR4708 PR4808 PR4816 PR5003 = R402H16: tolerance: 64.36515.6DL
PR4712 PR4817 PR4818 = R402H16: tolerance: 64.51115.6DL
PR5102 = 0R0603-PAD-U: tolerance: ZZ.R0603.001
PR5202 = R402H16: tolerance: 64.25515.6DL
PR5401 PR5409 = R402H16: tolerance: 63.47334.1DL
PR5403 = R402H16: tolerance: 64.16525.6DL
PR5404 = R402H16: tolerance: 64.13325.6DL
PR5419 = R402H16: tolerance: 64.29425.6DL
PR5420 = R402H16: tolerance: 64.13725.6DL
PR8201 = R402H16: tolerance: 64.49935.6DL
PR8208 = R402H16: tolerance: 64.20015.6DL
PR8209 PR8313 = R402H16: tolerance: 64.18025.6DL
PR8215 PR8216 = R805H24: tolerance: 64.2R205.16L
PR8223 = R603H22: tolerance: 63.2R233.15L
PR8224 = R402H16: tolerance: 64.84515.6DL
PR8260 = R402H16: tolerance: 64.13025.6DL
PR8302 = R402H16: tolerance: 64.51025.6DL
PR8303 = R402H16: tolerance: 64.38325.6DL
PR8306 PR8309 PR8316 PR8318 PR8329 R5506 = R402H14: tolerance: 63.10134.1DL
PR8326 = R402H16: tolerance: 64.12025.6DL
PT4402 PT4805 = CT7343H83: tolerance: 79.33612.20L
PT4701 PT4801 PT4803 PT8206-PT8208 = CT7343H83: tolerance: 79.33719.20C
PU4301-PU4304 = PPAK-8P-3232H36: tolerance: 84.07403.037
PU4305 PU4306 = PPAK-8P-2H45: tolerance: 84.07625.037
PU4307 = XSON6H24: tolerance: 73.01G04.01V
PU4401 = QFN32J4-G2D85H34: tolerance: 074.09538.0073
PU4403-PU4406 = PPAK-8P-3232H36: tolerance: 084.07380.0037
PU4412 = PPAK-8P-3232H36: tolerance: 84.07401.037
PU4501 = QFN20Z3-G1D1H36: tolerance: 074.08286.0043
PU4502 = QFN20Z3-G1D1H36: tolerance: 074.08288.0B43
PU4601 = QFN40J5-G3D6-DIFF-H34: tolerance: 074.95859.0B33
PU4701 PU4801 PU4802 = DFN8J4535-G4122-U1H40: tolerance: 074.97396.0043
PU5001 = DFN8G2-G1710-U1H40: tolerance: 074.95808.0B73
PU5002 PU5003 = PPAK-8P-3232H36: tolerance: 84.07410.A37
PU5101 PU8302 = QFN20Z3-G1H36: tolerance: 074.08288.0043
PU5102 = MSOP10-G2D5H44: tolerance: 74.05338.079
PU5201 = QFN22G4-G2PH42: tolerance: 074.02262.0043
PU5401 PU5403 = SOIC8-G3530H63: tolerance: 74.05930.03D
PU8201 = QFN20-G1D75H32: tolerance: 74.08812.073
PU8202 PU8204 PU8206 PU8208 = PPAK-8P-G5324H44-COLAY: tolerance: ZZ.00215.037
PU8301 = DFN10G3-G265175H32: tolerance: 74.08068.A43
PWSW1 = TJE-533-S-V-T-R-744: tolerance: 62.40009.E51
Q1701 Q2001 = SOT-363H44: tolerance: 075.00138.0A7C
Q2702 Q6502 Q9102 = SOT23DGS2D4H48: tolerance: 84.02130.031
Q6401 Q6402 Q6505 = SOT23CBE2D6H62: tolerance: 084.02418.0011
Q6501 = SOT23DGS2D4H44: tolerance: 084.03402.0031
Q9104 = SOT23DGS2D4H44: tolerance: 84.2N702.J31
R402 R406-R409 R416 R421-R423 = R402H16: tolerance: 63.51034.1DL
R412-R415 R601 = R402H16: tolerance: 64.49R95.6DL
R501 R7808 R7813 R7912 R7913 = R402H16: tolerance: 64.12105.6DL
R502 = R402H16: tolerance: 64.80R65.6DL
R505 R5748 = R402H16: tolerance: 64.47005.6DL
R506 = R402H16: tolerance: 64.22035.6DL
R723 = R402H16: tolerance: 64.54R95.6DL
R727 = R402H16: tolerance: 63.56034.1DL
R728 = R402H16: tolerance: 63.22134.1DL
R736 R742 R743 = R805H20: tolerance: 063.R0007.0161
R801 R1209 R1309 = R402H16: tolerance: 64.24R95.6DL
R1101 R4045 = 0R1206-PAD: tolerance: ZZ.R1206.ZZZ
R1206 R1305 = R402H16: tolerance: 64.2R005.6DL
R1215 R1312 = R402H16: tolerance: 64.24005.6DL
R1502 R1901 R7307 = R402H16: tolerance: 64.20005.6DL
R1603 = R402H16: tolerance: 64.11305.6DL
R1730 = R402H16: tolerance: 63.33434.1DL
R1803 = R402H16: tolerance: 64.27015.6DL
R1805 R1827-R1830 = R402H16: tolerance: 64.15R05.6DL
R1811 R2503 R2609 R2908 R2910 = R402H14: tolerance: 64.10R05.6DL
R1815 R2504 = R402H16: tolerance: 63.10634.1DL
R1818 = R402H16: tolerance: 64.82015.6DL
R1837 = R402H16: tolerance: 63.15434.1DL
R2048 R2049 R6507 = R402H16: tolerance: 63.51334.1DL
R2414 R2501 R3724 R3821 R5517 R5518 R5735 R5738-R5740 R5742 R5743 R5754 R5756 R5757 = R402H16: tolerance: 63.47234.1DL
R2421 R2483 R6402 = R402H16: tolerance: 63.33134.1DL
R2437 = R402H16: tolerance: 63.43034.1DL
R2442 = R402H16: tolerance: 64.15435.6DL
R2443 R7608 R7609 R7611 R7614 R7615 R7619 R7625 R7626 R7628 R7629 = R402H16: tolerance: 64.49925.6DL
R2481 = R402H16: tolerance: 64.15035.6DL
R2482 = R402H16: tolerance: 64.11535.6DL
R2505 = R402H16: tolerance: 64.16015.6DL
R2603 R2604 = R402H16: tolerance: 64.75015.6DL
R2608 = R402H16: tolerance: 64.27025.6DL
R2610 = NTC-603H38: tolerance: 69.60035.041
R2748 R2750 R5526 R6502 R6601 R6602 = R603H22: tolerance: 63.00000.00L
R3404 = R402H16: tolerance: 64.22125.6DL
R3708 = R402H16: tolerance: 63.30334.1DL
R3735 = R402H16: tolerance: 63.20534.1DL
R3739 = R402H16: tolerance: 64.90935.6DL
R3740 = R402H16: tolerance: 64.30135.6DL
R3741 = R402H16: tolerance: 64.30025.6DL
R3801 R3802 = R402H15: tolerance: 63.10334.L0L
R3830 R3831 = R402H16: tolerance: 64.20045.6DL
R3844 = R402H16: tolerance: 63.20334.L0L
R5541 = R402H16: tolerance: 64.31625.6DL
R5701-R5708 = R402H16: tolerance: 64.5R105.6DL
R5734 = R402H16: tolerance: 64.43015.6DL
R5750 = R402H16: tolerance: 63.10534.L1L
R5762 R5763 = R402H16: tolerance: 64.68R05.6DL
R5802 = R402H16: tolerance: 64.51015.6DL
R6503 = R603H22: tolerance: 63.10133.15L
R7301 = R402H16: tolerance: 64.24915.6DL
R7501 R7503 R7506 = R402H16: tolerance: 64.60R45.6DL
R7505 R7801 R7802 R7906 R7908 = R402H16: tolerance: 64.40R25.6DL
R7507 = R402H16: tolerance: 64.42R25.6DL
R7604 = R402H16: tolerance: 63.13234.1DL
R7607 = R402H16: tolerance: 64.40225.6DL
R7620 R7621 R7632 R7635 = R402H16: tolerance: 64.49915.6DL
R7803 R7804 R7902 R7905 = R402H16: tolerance: 64.93105.6DL
R7805 R7806 R7903 R7907 = R402H16: tolerance: 64.54905.6DL
R7807 R7809 R7901 R7904 = R402H16: tolerance: 64.13315.6DL
RN801 RN803 RN1811 RN2008 RN2413 RN2602 RN2701 RN2901 RN3701 RN3702 RN6503 RN7604 RN7605 = ARES2H16: tolerance: 66.22236.04L
RN1201 RN1301 RN1802 RN2007 RN2702 = SMD-ARES4H18: tolerance: 66.10236.04L
RN1601 RN1704 RN1812 RN1813 = ARES8-CN24-MUH20: tolerance: 66.10336.08L
RN1703 RN1810 RN2009 RN6501 RN7602 = ARES2H18: tolerance: 66.10336.04L
RN1801 = SMD-ARES4H20: tolerance: 66.20336.04L
RN1803 = ARES8-CN24-UH18: tolerance: 66.10036.08A
RN1807 = ARES8-CN24-UH20: tolerance: 66.22236.A8L
RN1902 RN5503 RN6502 = SMD-ARES4H18: tolerance: 66.33036.04L
RN2402 RN7601 = SMD-ARES4H18: tolerance: 66.47236.04L
RN2403 RN2404 RN2409 RN2410 RN2412 RN5502 = ARES8-CN24H20: tolerance: 66.10436.A8L
RN2405-RN2407 RN2411 RN7610 = SMD-ARES4: tolerance: 66.10436.04L
RN2502 RN2503 = SMD-ARES4-2H18-U: tolerance: 66.10035.04L
RN4302 RN5501 = ARES8-CN24H20: tolerance: 66.10136.A8L
RN7401 = ARES2H18: tolerance: 66.18236.04L
SKT251 = G6179HT0321-001: tolerance: 62.10089.011
SPI25 = SOIC8-1H86: tolerance: 72.12873.001
SPK1 = 50224-0060N-W01: tolerance: 20.F1639.006
SPR1-SPR3 = SPR5128H111: tolerance: 34.4YW18.001
SPR4 = SPR5630H142: tolerance: 34.4Y806.001
SSD1 = APCI0079-P002A: tolerance: 62.10043.J01
TC3501 = C1206H71: tolerance: 78.10710.52L
TCBD1 = 51530-02001-W01-U: tolerance: 20.K0637.020
THM261 = MSOP8-1H44: tolerance: 74.07718.0B9
TP401 TP402 TP405 TP406 TP612 TP613 TP617 TP618 TP638 TP801 TP1603-TP1606 TP1705 TP1708 TP1709 TP1802 TP1803 TP1903 TP2101 TP2102 TP2301-TP2313 TP2401 TP3701 TP4601 TP7503 TP7601-TP7605 TP7701 TP7801-TP7804 TP7901-TP7904 TP8301 TP8304 = TPAD14-OP: tolerance: ZZ.PAD14.001
TP4401 = TPAD28: tolerance: ZZ.PAD28.XXX
TPCON1 = 51574-0084N-W01: tolerance: 020.K0151.0008
U3401 = QFN16-G1D8-UH32: tolerance: 74.02544.073
U3501-U3503 = SOT-23-5H56: tolerance: 074.06288.009B
U3701 = QFN40G6-G4D7H24: tolerance: 074.04125.0A73
U3702 = DFN6F2-G1711-UH32: tolerance: 074.70933.0033
U3703 = DFN6G1820-G1511-UH24: tolerance: 074.02151.0073
U3801 = QFN40J4060-G2848H32: tolerance: 071.00546.0003
U3802 = QFN20J3-G1D8H32: tolerance: 071.10224.0003
U4001 U8301 = DFN14J3020-G255D85H32: tolerance: 074.05016.0093
U4002 = DFN8F3-G2517H32: tolerance: 074.22961.0093
U4006 = DFN8G2-G1710-U1H32: tolerance: 074.08937.0093
U4007 = SC70-5H44: tolerance: 073.7SZ08.000G
U4301 U4302 = SOT-23-5H52: tolerance: 074.01004.00BF
U5501 = SOT-23-5H51: tolerance: 74.09724.09F
U5502 = SOT-23-5H58: tolerance: 074.05324.003F
U5701 = BGA64D7H51: tolerance: 071.17564.0B0U
U5702 = SOIC8H69: tolerance: 72.25200.001
U5801 = SOIC8-G3627H67: tolerance: 074.02023.0031
U7001 = LGA12G2H40: tolerance: 074.LNG2D.00BZ
U7301 = SC70-5-1H44: tolerance: 73.01G08.EHG
U9101 = QFN32G5-G3D6H32: tolerance: 071.00650.0J03
USB1 = SKT-USB34-124102-U: tolerance: 022.10005.M022
USB2 USB3 = SKT-USB13-160166-2: tolerance: 22.10339.331
VRAM1-VRAM4 = BGA170D1214H48: tolerance: 72.05224.A0U
X1801 X2201 = OSC-3225-4P-4H30: tolerance: 82.30004.901
X1802 = SMD-OSC2H56: tolerance: 82.30001.A41
X2401 = SMD49-12H36: tolerance: 082.30003.0201
X5701 = OSC-3225-4P-4H36: tolerance: 82.30034.A61
X7601 = OSC-3225-4P-4H30: tolerance: 82.30034.641

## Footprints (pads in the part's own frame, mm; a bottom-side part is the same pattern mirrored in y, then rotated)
0R0402-PAD
  custom 0.127x0.127 smd: 1(0,0.432) 2(0,-0.432)
0R0603-PAD
  custom 0.254x0.254 smd: 1(0,0.66) 2(0,-0.66)
0R0603-PAD-U
  custom 0.254x0.254 smd: 1(0,0.66) 2(0,-0.66)
0R0805-PAD
  rect 1.549x1.346 smd: 1(0,0.838) 2(0,-0.838)
0R1206-PAD
  rect 1.854x1.829 smd: 1(0,1.347) 2(0,-1.347)
300E50-1030RA-G4
  rect 0.305x0.889 smd: 1(-12.25,2.82) 2(-11.75,2.82) 3(-11.25,2.82) 4(-10.75,2.82) 5(-10.25,2.82) 6(-9.75,2.82) 7(-9.25,2.82) 8(-8.75,2.82) 9(-8.25,2.82) 10(-7.75,2.82) 11(-7.25,2.82) 12(-6.75,2.82) 13(-6.25,2.82) 14(-5.75,2.82) 15(-5.25,2.82) 16(-4.75,2.82) 17(-4.25,2.82) 18(-3.75,2.82) 19(-3.25,2.82) 20(-2.75,2.82) 21(-2.25,2.82) 22(-1.75,2.82) 23(-1.25,2.82) 24(-0.75,2.82) 25(-0.25,2.82) 26(0.25,2.82) 27(0.75,2.82) 28(1.25,2.82) 29(1.75,2.82) 30(2.25,2.82) 31(2.75,2.82) 32(3.25,2.82) 33(3.75,2.82) 34(4.25,2.82) 35(4.75,2.82) 36(5.25,2.82) 37(5.75,2.82) 38(6.25,2.82) 39(6.75,2.82) 40(7.25,2.82) 41(7.75,2.82) 42(8.25,2.82) 43(8.75,2.82) 44(9.25,2.82) 45(9.75,2.82) 46(10.25,2.82) 47(10.75,2.82) 48(11.25,2.82) 49(11.75,2.82) 50(12.25,2.82)
  rect 1.397x1.905 smd: 51(-15.35,0) 52(15.35,0)
  rect 0.559x0.889 smd: 53(-13.15,2.82) 54(13.15,2.82)
20525-060E-02-U
  rect 0.203x0.813 smd: 1(11.8,3.125) 2(11.4,3.125) 3(11,3.125) 4(10.6,3.125) 5(10.2,3.125) 6(9.8,3.125) 7(9.4,3.125) 8(9,3.125) 9(8.6,3.125) 10(8.2,3.125) 11(7.8,3.125) 12(7.4,3.125) 13(7,3.125) 14(6.6,3.125) 15(6.2,3.125) 16(5.8,3.125) 17(5.4,3.125) 18(5,3.125) 19(4.6,3.125) 20(4.2,3.125) 21(3.8,3.125) 22(3.4,3.125) 23(3,3.125) 24(2.6,3.125) 25(2.2,3.125) 26(1.8,3.125) 27(1.4,3.125) 28(1,3.125) 29(0.6,3.125) 30(0.2,3.125) 31(-0.2,3.125) 32(-0.6,3.125) 33(-1,3.125) 34(-1.4,3.125) 35(-1.8,3.125) 36(-2.2,3.125) 37(-2.6,3.125) 38(-3,3.125) 39(-3.4,3.125) 40(-3.8,3.125) 41(-4.2,3.125) 42(-4.6,3.125) 43(-5,3.125) 44(-5.4,3.125) 45(-5.8,3.125) 46(-6.2,3.125) 47(-6.6,3.125) 48(-7,3.125) 49(-7.4,3.125) 50(-7.8,3.125) 51(-8.2,3.125) 52(-8.6,3.125) 53(-9,3.125) 54(-9.4,3.125) 55(-9.8,3.125) 56(-10.2,3.125) 57(-10.6,3.125) 58(-11,3.125) 59(-11.4,3.125) 60(-11.8,3.125)
  rect 0.559x0.889 smd: 61(12.7,3.075) 62(-12.7,3.075)
  rect 0.711x1.295 smd: 63(14.445,2.325) 64(-14.445,2.325)
  rect 0.711x1.854 smd: 65(14.445,0) 66(-14.445,0)
50224-0040N-001
  rect 0.61x1.549 smd: 1(-1.5,3.875) 2(-0.5,3.875) 3(0.5,3.875) 4(1.5,3.875)
  rect 1.194x1.803 smd: 5(-2.797,0) 6(2.797,0)
50224-0060N-W01
  rect 0.406x1.549 smd: 1(-2.5,3.875) 2(-1.5,3.875) 3(-0.5,3.875) 4(0.5,3.875) 5(1.5,3.875) 6(2.5,3.875)
  rect 1.194x1.803 smd: 7(-3.8,0) 8(3.8,0)
50224-0080N-W02-U
  rect 0.406x1.549 smd: 1(-3.5,3.875) 2(-2.5,3.875) 3(-1.5,3.875) 4(-0.5,3.875) 5(0.5,3.875) 6(1.5,3.875) 7(2.5,3.875) 8(3.5,3.875)
  rect 1.194x1.803 smd: 9(-4.797,0) 10(4.797,0)
50406-02071-001
  rect 0.305x1.295 smd: 1(-4.75,-1.95) 2(-4.25,-1.95) 3(-3.75,-1.95) 4(-3.25,-1.95) 5(-2.75,-1.95) 6(-2.25,-1.95) 7(-1.75,-1.95) 8(-1.25,-1.95) 9(-0.75,-1.95) 10(-0.25,-1.95) 11(0.25,-1.95) 12(0.75,-1.95) 13(1.25,-1.95) 14(1.75,-1.95) 15(2.25,-1.95) 16(2.75,-1.95) 17(3.25,-1.95) 18(3.75,-1.95) 19(4.25,-1.95) 20(4.75,-1.95)
  rect 1.194x2.692 smd: 21(-7.15,0) 24(7.15,0)
  rect 2.311x1.295 smd: 22(-3.9,1.95) 23(3.9,1.95)
50524-00401-001
  rect 0.305x1.295 smd: 1(-1.5,5.65) 2(-0.5,5.65) 3(0.5,5.65) 4(1.5,5.65)
  rect 1.803x2.21 smd: 5(-4.15,0) 6(4.15,0)
50696-00601-001
  rect 0.305x0.813 smd: 1(1.25,2.5) 2(0.75,2.5) 3(0.25,2.5) 4(-0.25,2.5) 5(-0.75,2.5) 6(-1.25,2.5)
  rect 0.406x0.813 smd: 7(2.25,0) 8(-2.25,0)
50698-00401-W01-U
  rect 0.305x1.6 smd: 1(1.5,5.2) 2(0.5,5.2) 3(-0.5,5.2) 4(-1.5,5.2)
  rect 1.803x2.007 smd: 5(4.21,0) 6(-4.21,0)
51530-02001-W01-U
  rect 0.305x0.838 smd: 1(-4.75,3.175) 2(-4.25,3.175) 3(-3.75,3.175) 4(-3.25,3.175) 5(-2.75,3.175) 6(-2.25,3.175) 7(-1.75,3.175) 8(-1.25,3.175) 9(-0.75,3.175) 10(-0.25,3.175) 11(0.25,3.175) 12(0.75,3.175) 13(1.25,3.175) 14(1.75,3.175) 15(2.25,3.175) 16(2.75,3.175) 17(3.25,3.175) 18(3.75,3.175) 19(4.25,3.175) 20(4.75,3.175)
  rect 0.813x2.007 smd: 21(-6.45,0) 22(6.45,0)
51574-0084N-W01
  rect 0.305x1.194 smd: 1(-3.5,3.3) 2(-2.5,3.3) 3(-1.5,3.3) 4(-0.5,3.3) 5(0.5,3.3) 6(1.5,3.3) 7(2.5,3.3) 8(3.5,3.3)
  rect 0.406x0.813 smd: 9(-5.185,0) 10(5.185,0)
196528-30041-3
  rect 0.508x1.092 smd: 1(-11.6,1.75) 2(-10.8,1.75) 3(-10,1.75) 4(-9.2,1.75) 5(-8.4,1.75) 6(-7.6,1.75) 7(-6.8,1.75) 8(-6,1.75) 9(-5.2,1.75) 10(-4.4,1.75) 11(-3.6,1.75) 12(-2.8,1.75) 13(-2,1.75) 14(-1.2,1.75) 15(-0.4,1.75) 16(0.4,1.75) 17(1.2,1.75) 18(2,1.75) 19(2.8,1.75) 20(3.6,1.75) 21(4.4,1.75) 22(5.2,1.75) 23(6,1.75) 24(6.8,1.75) 25(7.6,1.75) 26(8.4,1.75) 27(9.2,1.75) 28(10,1.75) 29(10.8,1.75) 30(11.6,1.75)
  rect 1.651x1.295 smd: 31(-13.625,0) 32(13.625,0)
A2014WRA-SF-10PNLNG1NS1R
  round 0.254 hole 1.803 unplated: (-9.2,0) (9.2,0)
  rect 0.889x1.905 smd: 1(9,4.95) 2(7,4.95) 3(5,4.95) 4(3,4.95) 5(1,4.95) 6(-1,4.95) 7(-3,4.95) 8(-5,4.95) 9(-7,4.95) 10(-9,4.95)
ADDR0205-P012A
  round 0.254 hole 1.118 unplated: (-34.4,0)
  round 0.254 hole 1.6 unplated: (34.4,0)
  custom 0.089x0.089 smd: 1(33.375,4.1) 2(33.125,-4.1) 3(32.875,4.1) 4(32.625,-4.1) 5(32.375,4.1) 6(32.125,-4.1) 7(31.875,4.1) 8(31.625,-4.1) 9(31.375,4.1) 10(31.125,-4.1) 11(30.875,4.1) 12(30.625,-4.1) 13(30.375,4.1) 14(30.125,-4.1) 15(29.875,4.1) 16(29.625,-4.1) 17(29.375,4.1) 18(29.125,-4.1) 19(28.875,4.1) 20(28.625,-4.1) 21(28.375,4.1) 22(28.125,-4.1) 23(27.875,4.1) 24(27.625,-4.1) 25(27.375,4.1) 26(27.125,-4.1) 27(26.875,4.1) 28(26.625,-4.1) 29(26.375,4.1) 30(26.125,-4.1) 31(25.875,4.1) 32(25.625,-4.1) 33(25.375,4.1) 34(25.125,-4.1) 35(24.875,4.1) 36(24.625,-4.1) 37(24.375,4.1) 38(24.125,-4.1) 39(23.875,4.1) 40(23.625,-4.1) 41(23.375,4.1) 42(23.125,-4.1) 43(22.875,4.1) 44(22.625,-4.1) 45(22.375,4.1) 46(22.125,-4.1) 47(21.875,4.1) 48(21.625,-4.1) 49(21.375,4.1) 50(21.125,-4.1) 51(20.875,4.1) 52(20.625,-4.1) 53(20.375,4.1) 54(20.125,-4.1) 55(19.875,4.1) 56(19.625,-4.1) 57(19.375,4.1) 58(19.125,-4.1) 59(18.875,4.1) 60(18.625,-4.1) 61(18.375,4.1) 62(18.125,-4.1) 63(17.875,4.1) 64(17.625,-4.1) 65(17.375,4.1) 66(17.125,-4.1) 67(16.875,4.1) 68(16.625,-4.1) 69(16.375,4.1) 70(16.125,-4.1) 71(15.875,4.1) 72(15.625,-4.1) 73(15.375,4.1) 74(15.125,-4.1) 75(14.875,4.1) 76(14.625,-4.1) 77(14.375,4.1) 78(14.125,-4.1) 79(13.875,4.1) 80(13.625,-4.1) 81(13.375,4.1) 82(13.125,-4.1) 83(12.875,4.1) 84(12.625,-4.1) 85(12.375,4.1) 86(12.125,-4.1) 87(11.875,4.1) 88(11.625,-4.1) 89(11.375,4.1) 90(11.125,-4.1) 91(10.875,4.1) 92(10.625,-4.1) 93(10.375,4.1) 94(10.125,-4.1) 95(9.875,4.1) 96(9.625,-4.1) 97(9.375,4.1) 98(9.125,-4.1) 99(8.875,4.1) 100(8.625,-4.1) 101(8.375,4.1) 102(8.125,-4.1) 103(7.875,4.1) 104(7.625,-4.1) 105(7.375,4.1) 106(7.125,-4.1) 107(6.875,4.1) 108(6.625,-4.1) 109(6.375,4.1) 110(6.125,-4.1) 111(5.875,4.1) 112(5.625,-4.1) 113(5.375,4.1) 114(5.125,-4.1) 115(4.875,4.1) 116(4.625,-4.1) 117(4.375,4.1) 118(4.125,-4.1) 119(3.875,4.1) 120(3.625,-4.1) 121(3.375,4.1) 122(3.125,-4.1) 123(2.875,4.1) 124(2.625,-4.1) 125(2.375,4.1) 126(2.125,-4.1) 127(1.875,4.1) 128(1.625,-4.1) 129(1.375,4.1) 130(1.125,-4.1) 131(0.875,4.1) 132(0.625,-4.1) 133(0.375,4.1) 134(0.125,-4.1) 135(-0.125,4.1) 136(-0.375,-4.1) 137(-0.625,4.1) 138(-0.875,-4.1) 139(-1.125,4.1) 140(-1.375,-4.1) 141(-1.625,4.1) 142(-1.875,-4.1) 143(-2.125,4.1) 144(-2.375,-4.1) 145(-4.625,4.1) 146(-4.875,-4.1) 147(-5.125,4.1) 148(-5.375,-4.1) 149(-5.625,4.1) 150(-5.875,-4.1) 151(-6.125,4.1) 152(-6.375,-4.1) 153(-6.625,4.1) 154(-6.875,-4.1) 155(-7.125,4.1) 156(-7.375,-4.1) 157(-7.625,4.1) 158(-7.875,-4.1) 159(-8.125,4.1) 160(-8.375,-4.1) 161(-8.625,4.1) 162(-8.875,-4.1) 163(-9.125,4.1) 164(-9.375,-4.1) 165(-9.625,4.1) 166(-9.875,-4.1) 167(-10.125,4.1) 168(-10.375,-4.1) 169(-10.625,4.1) 170(-10.875,-4.1) 171(-11.125,4.1) 172(-11.375,-4.1) 173(-11.625,4.1) 174(-11.875,-4.1) 175(-12.125,4.1) 176(-12.375,-4.1) 177(-12.625,4.1) 178(-12.875,-4.1) 179(-13.125,4.1) 180(-13.375,-4.1) 181(-13.625,4.1) 182(-13.875,-4.1) 183(-14.125,4.1) 184(-14.375,-4.1) 185(-14.625,4.1) 186(-14.875,-4.1) 187(-15.125,4.1) 188(-15.375,-4.1) 189(-15.625,4.1) 190(-15.875,-4.1) 191(-16.125,4.1) 192(-16.375,-4.1) 193(-16.625,4.1) 194(-16.875,-4.1) 195(-17.125,4.1) 196(-17.375,-4.1) 197(-17.625,4.1) 198(-17.875,-4.1) 199(-18.125,4.1) 200(-18.375,-4.1) 201(-18.625,4.1) 202(-18.875,-4.1) 203(-19.125,4.1) 204(-19.375,-4.1) 205(-19.625,4.1) 206(-19.875,-4.1) 207(-20.125,4.1) 208(-20.375,-4.1) 209(-20.625,4.1) 210(-20.875,-4.1) 211(-21.125,4.1) 212(-21.375,-4.1) 213(-21.625,4.1) 214(-21.875,-4.1) 215(-22.125,4.1) 216(-22.375,-4.1) 217(-22.625,4.1) 218(-22.875,-4.1) 219(-23.125,4.1) 220(-23.375,-4.1) 221(-23.625,4.1) 222(-23.875,-4.1) 223(-24.125,4.1) 224(-24.375,-4.1) 225(-24.625,4.1) 226(-24.875,-4.1) 227(-25.125,4.1) 228(-25.375,-4.1) 229(-25.625,4.1) 230(-25.875,-4.1) 231(-26.125,4.1) 232(-26.375,-4.1) 233(-26.625,4.1) 234(-26.875,-4.1) 235(-27.125,4.1) 236(-27.375,-4.1) 237(-27.625,4.1) 238(-27.875,-4.1) 239(-28.125,4.1) 240(-28.375,-4.1) 241(-28.625,4.1) 242(-28.875,-4.1) 243(-29.125,4.1) 244(-29.375,-4.1) 245(-29.625,4.1) 246(-29.875,-4.1) 247(-30.125,4.1) 248(-30.375,-4.1) 249(-30.625,4.1) 250(-30.875,-4.1) 251(-31.125,4.1) 252(-31.375,-4.1) 253(-31.625,4.1) 254(-31.875,-4.1) 255(-32.125,4.1) 256(-32.375,-4.1) 257(-32.625,4.1) 258(-32.875,-4.1) 259(-33.125,4.1) 260(-33.375,-4.1)
  rect 3.505x4.597 smd: 261(33.8,-12) 262(-33.8,-12)
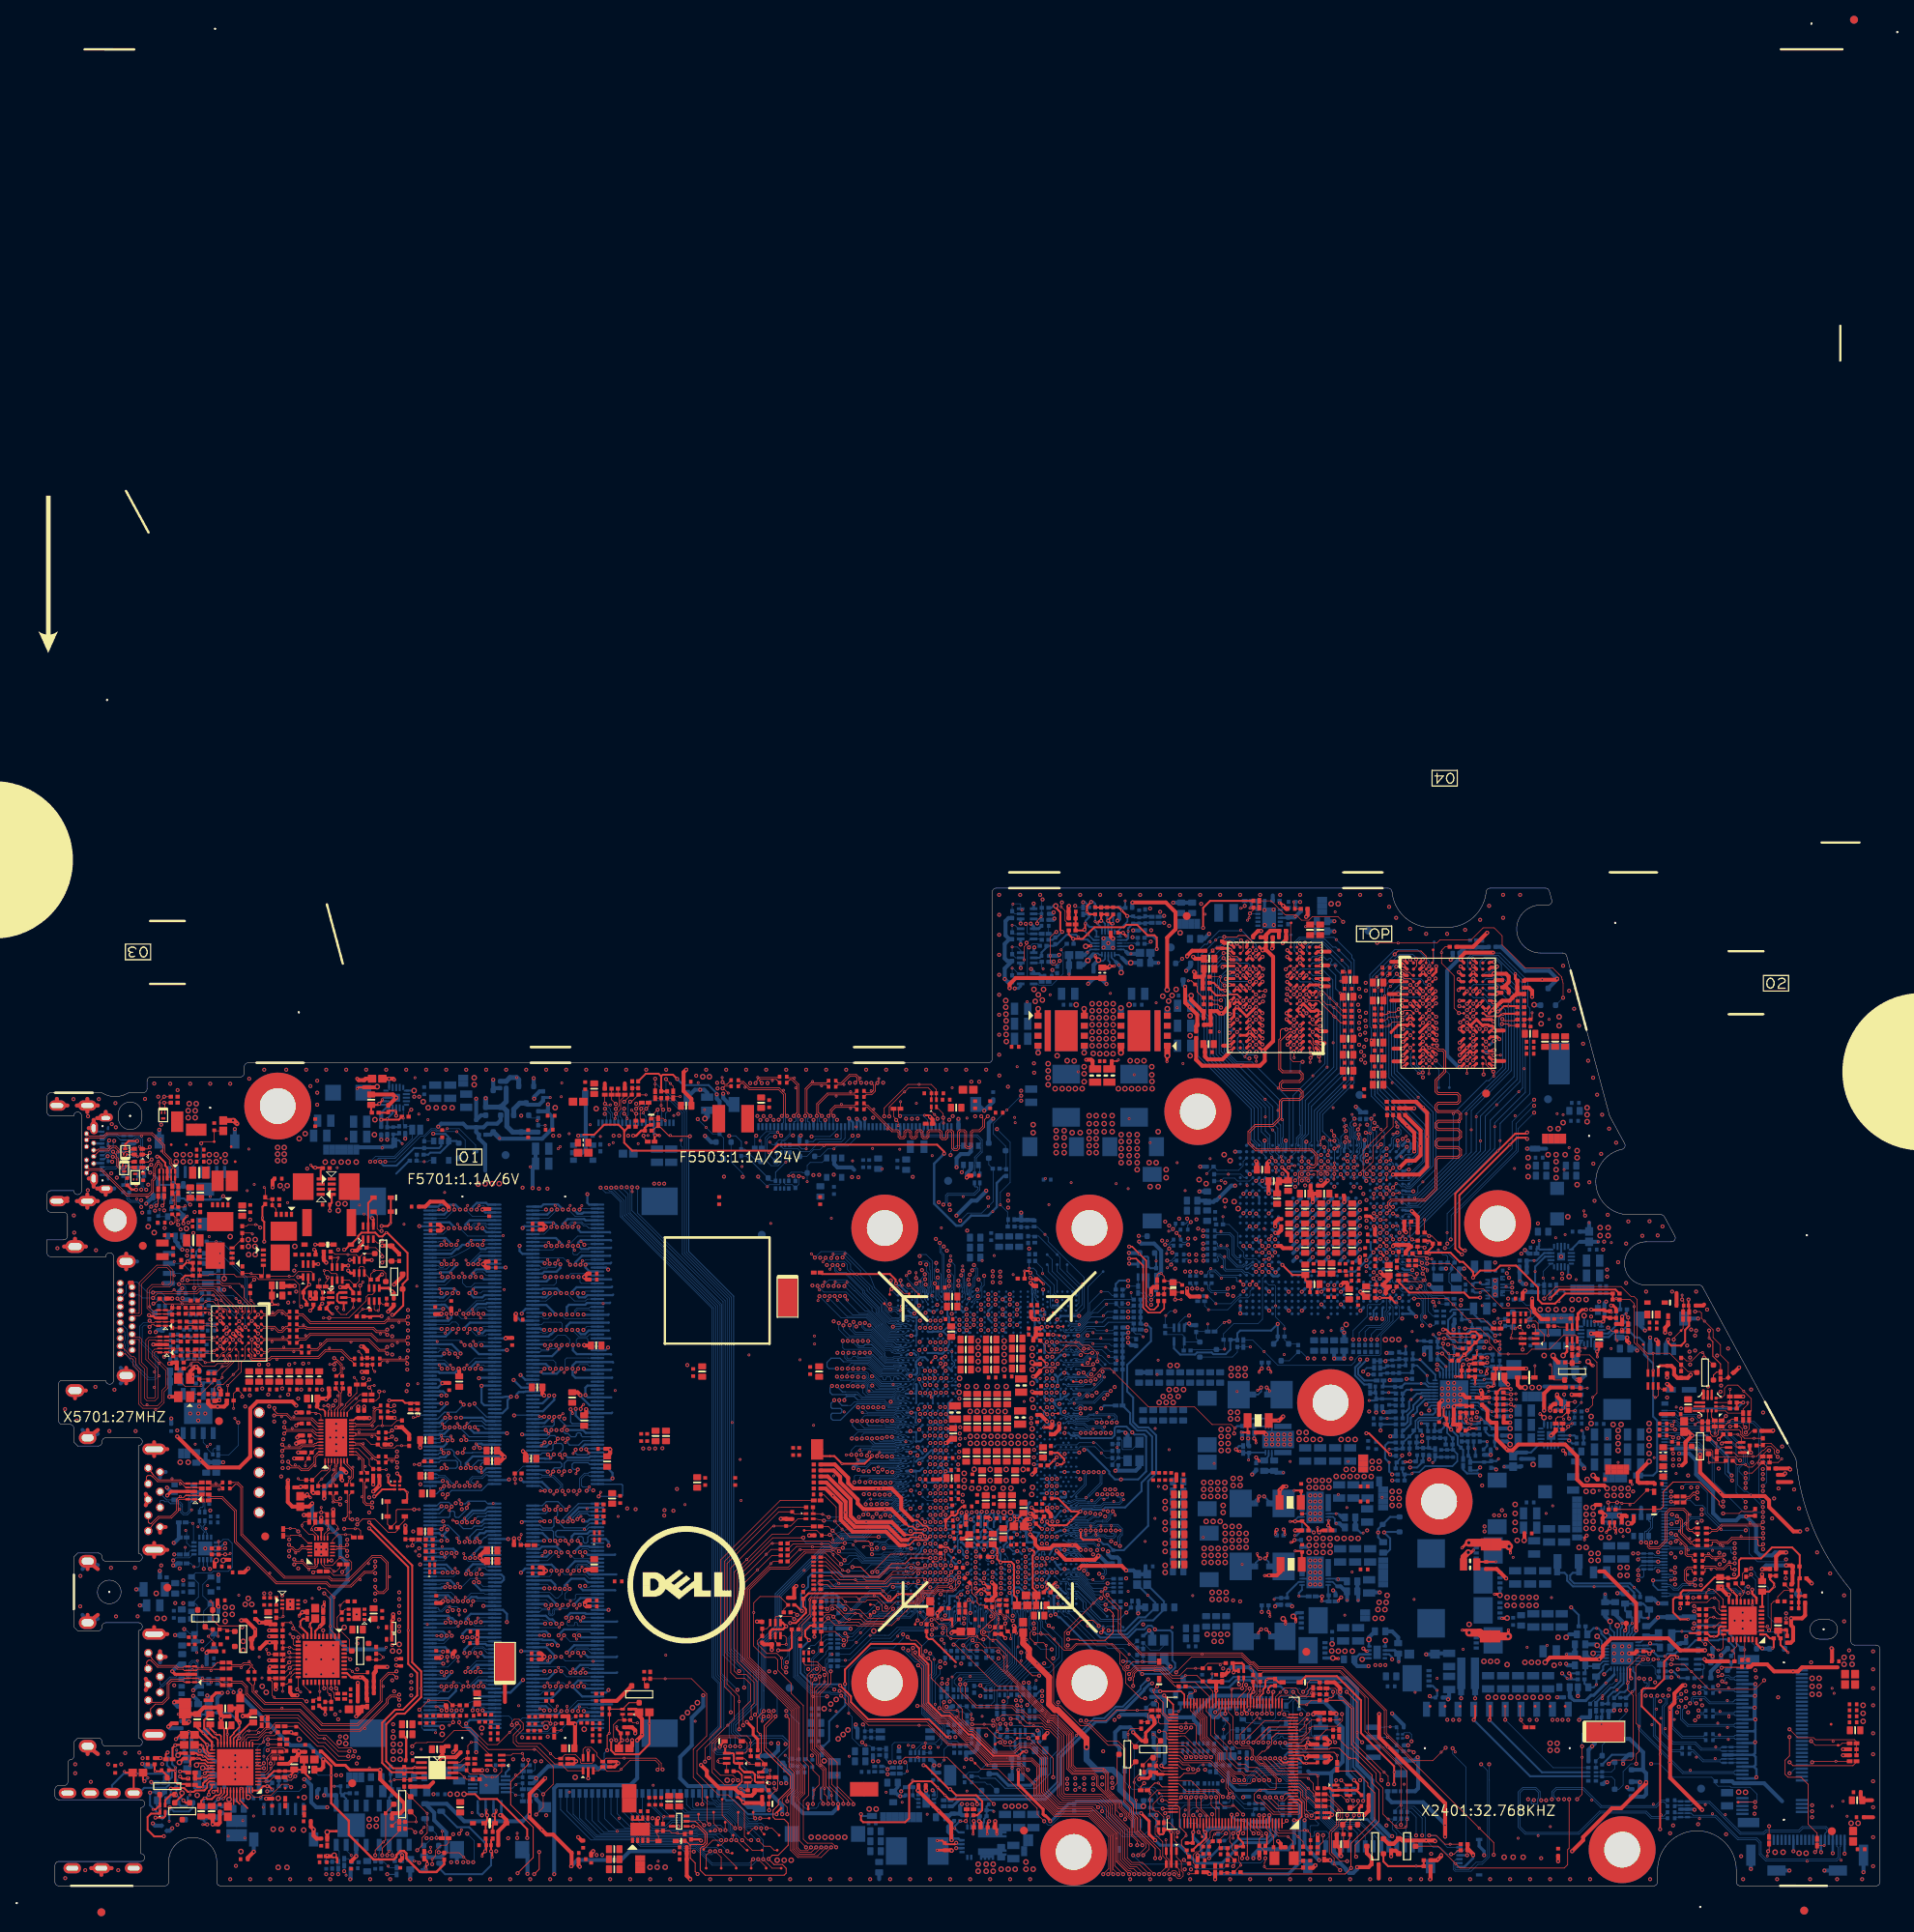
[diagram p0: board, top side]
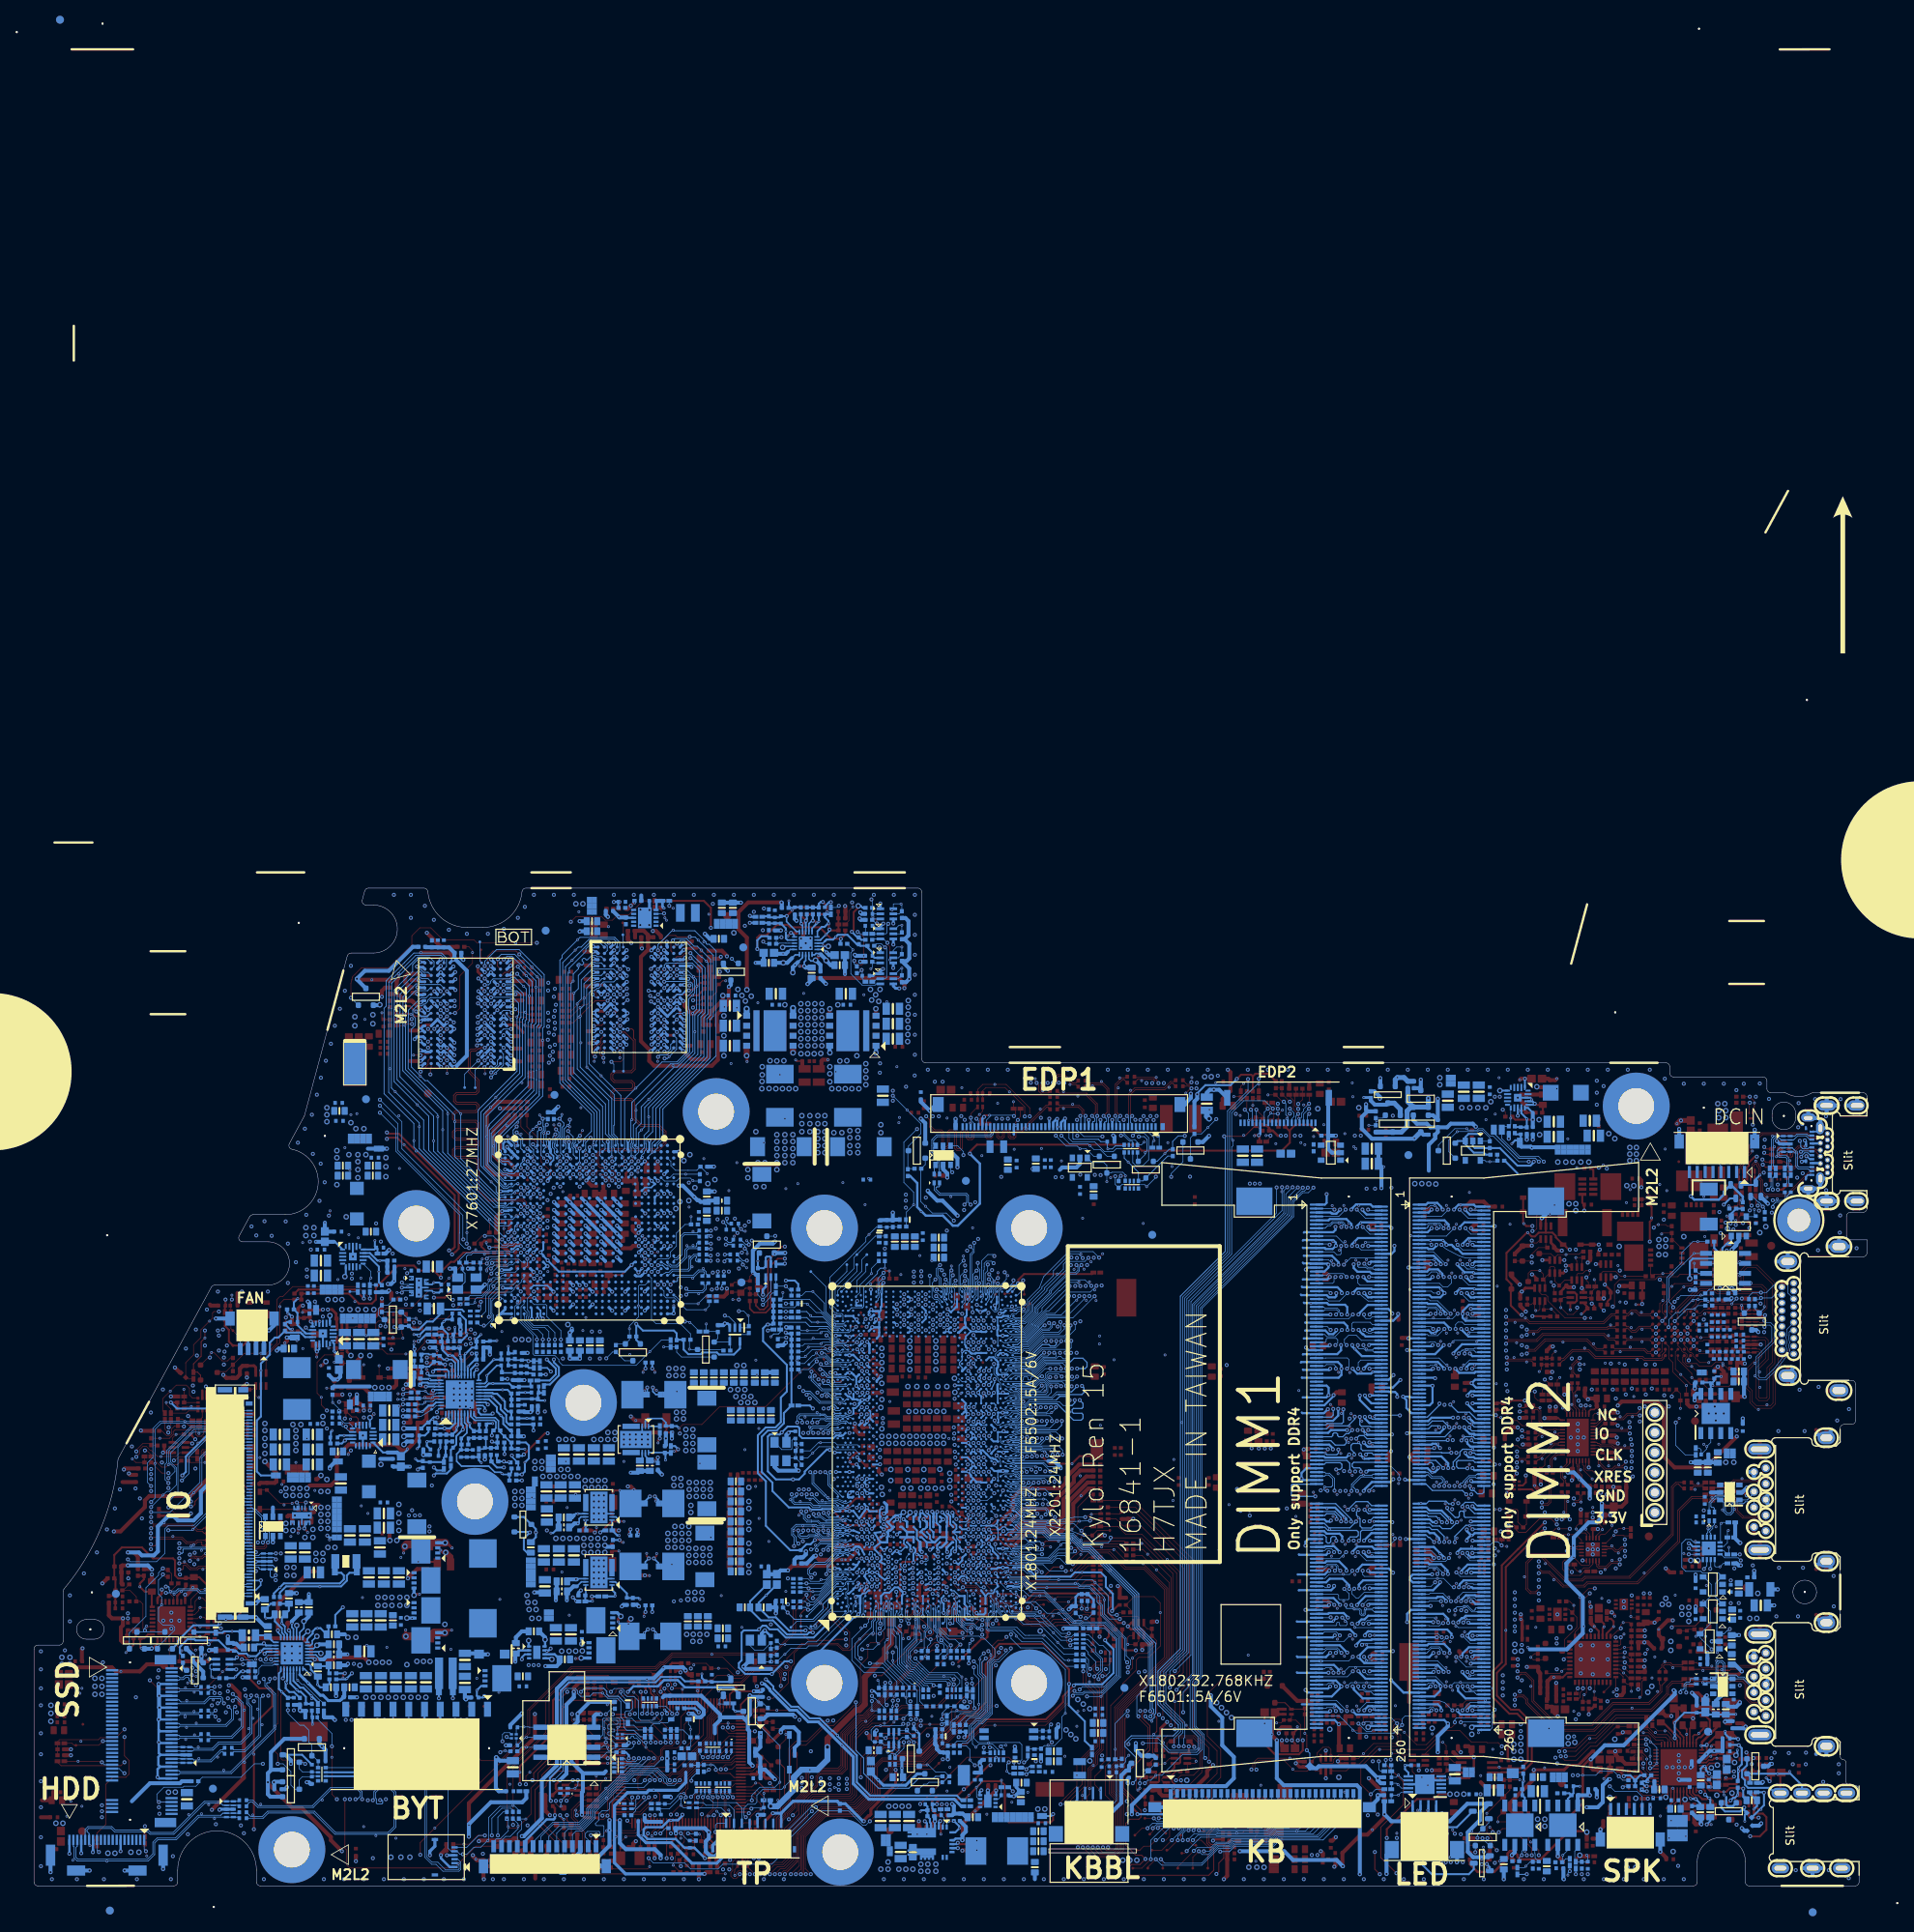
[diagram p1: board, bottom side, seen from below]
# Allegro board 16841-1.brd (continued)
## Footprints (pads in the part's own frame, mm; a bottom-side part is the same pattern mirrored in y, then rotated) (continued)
QFN16-G1D8-UH32
  rect 0.305x0.66 smd: 1(0.75,1.487) 2(0.25,1.487) 3(-0.25,1.487) 4(-0.75,1.487) 9(-0.75,-1.487) 10(-0.25,-1.487) 11(0.25,-1.487) 12(0.75,-1.487)
  rect 0.66x0.305 smd: 5(-1.487,0.75) 6(-1.487,0.25) 7(-1.487,-0.25) 8(-1.487,-0.75) 13(1.487,-0.75) 14(1.487,-0.25) 15(1.487,0.25) 16(1.487,0.75)
  rect 1.778x1.778 smd: 17(0,0)
QFN20-G1D75H32
  rect 0.203x0.66 smd: 1(0.8,1.487) 2(0.4,1.487) 3(0,1.487) 4(-0.4,1.487) 5(-0.8,1.487) 11(-0.8,-1.487) 12(-0.4,-1.487) 13(0,-1.487) 14(0.4,-1.487) 15(0.8,-1.487)
  rect 0.66x0.203 smd: 6(-1.487,0.8) 7(-1.487,0.4) 8(-1.487,0) 9(-1.487,-0.4) 10(-1.487,-0.8) 16(1.487,-0.8) 17(1.487,-0.4) 18(1.487,0) 19(1.487,0.4) 20(1.487,0.8)
  rect 1.753x1.753 smd: 21(0,0)
QFN20J3-G1D8H32
  rect 0.203x0.635 smd: 1(0.8,1.437) 2(0.4,1.437) 3(0,1.437) 4(-0.4,1.437) 5(-0.8,1.437) 11(-0.8,-1.437) 12(-0.4,-1.437) 13(0,-1.437) 14(0.4,-1.437) 15(0.8,-1.437)
  rect 0.635x0.203 smd: 6(-1.437,0.8) 7(-1.437,0.4) 8(-1.437,0) 9(-1.437,-0.4) 10(-1.437,-0.8) 16(1.437,-0.8) 17(1.437,-0.4) 18(1.437,0) 19(1.437,0.4) 20(1.437,0.8)
  rect 1.803x1.803 smd: 21(0,0)
QFN20Z3-G1D1H36
  custom 0.064x0.064 smd: 1(0.9,1.297) 5(-0.9,1.297) 6(-1.297,0.9) 10(-1.297,-0.9) 11(-0.9,-1.297) 15(0.9,-1.297) 16(1.297,-0.9) 20(1.297,0.9)
  rect 0.254x0.914 smd: 2(0.45,1.297) 3(0,1.297) 4(-0.45,1.297) 12(-0.45,-1.297) 13(0,-1.297) 14(0.45,-1.297)
  rect 0.914x0.254 smd: 7(-1.297,0.45) 8(-1.297,0) 9(-1.297,-0.45) 17(1.297,-0.45) 18(1.297,0) 19(1.297,0.45)
  rect 1.092x1.092 smd: 21(0,0)
QFN20Z3-G1H36
  custom 0.064x0.064 smd: 1(0.9,1.297) 5(-0.9,1.297) 6(-1.297,0.9) 10(-1.297,-0.9) 11(-0.9,-1.297) 15(0.9,-1.297) 16(1.297,-0.9) 20(1.297,0.9)
  rect 0.254x0.914 smd: 2(0.45,1.297) 3(0,1.297) 4(-0.45,1.297) 12(-0.45,-1.297) 13(0,-1.297) 14(0.45,-1.297)
  rect 0.914x0.254 smd: 7(-1.297,0.45) 8(-1.297,0) 9(-1.297,-0.45) 17(1.297,-0.45) 18(1.297,0) 19(1.297,0.45)
  rect 0.991x0.991 smd: 21(0,0)
QFN22G4-G2PH42
  rect 0.305x0.66 smd: 1(1.25,1.924) 2(0.75,1.924) 3(0.25,1.924) 4(-0.25,1.924) 5(-0.75,1.924) 6(-1.25,1.924) 16(0.75,-1.924) 17(1.25,-1.924)
  custom 0.326x0.326 smd: 7(-1.924,1.25)
  rect 0.025x0.025 smd: 8(-1.924,0.75) 9(-1.924,0.25) 10(-1.924,-0.75) 13(-0.75,-1.924) 14(-0.25,-1.924) 15(0.25,-1.924)
  custom 0.232x0.232 smd: 11(-1.924,-1.25)
  custom 0.165x0.165 smd: 12(-1.25,-1.924)
  rect 0.66x0.305 smd: 18(1.924,-1.25) 19(1.924,-0.75) 20(1.924,-0.25) 21(1.924,0.25) 22(1.924,1.25)
QFN32G5-G3D6H32
  rect 0.305x0.66 smd: 1(1.75,2.487) 8(-1.75,2.487) 17(-1.75,-2.487) 24(1.75,-2.487)
  rect 0.305x0.737 smd: 2(1.25,2.449) 3(0.75,2.449) 4(0.25,2.449) 5(-0.25,2.449) 6(-0.75,2.449) 7(-1.25,2.449) 18(-1.25,-2.449) 19(-0.75,-2.449) 20(-0.25,-2.449) 21(0.25,-2.449) 22(0.75,-2.449) 23(1.25,-2.449)
  rect 0.66x0.305 smd: 9(-2.487,1.75) 16(-2.487,-1.75) 25(2.487,-1.75) 32(2.487,1.75)
  rect 0.737x0.305 smd: 10(-2.449,1.25) 11(-2.449,0.75) 12(-2.449,0.25) 13(-2.449,-0.25) 14(-2.449,-0.75) 15(-2.449,-1.25) 26(2.449,-1.25) 27(2.449,-0.75) 28(2.449,-0.25) 29(2.449,0.25) 30(2.449,0.75) 31(2.449,1.25)
  rect 3.607x3.607 smd: 33(0,0)
QFN32J4-G2D85H34
  rect 0.203x0.61 smd: 1(1.4,1.958) 2(1,1.958) 3(0.6,1.958) 4(0.2,1.958) 5(-0.2,1.958) 6(-0.6,1.958) 7(-1,1.958) 8(-1.4,1.958) 17(-1.4,-1.958) 18(-1,-1.958) 19(-0.6,-1.958) 20(-0.2,-1.958) 21(0.2,-1.958) 22(0.6,-1.958) 23(1,-1.958) 24(1.4,-1.958)
  rect 0.61x0.203 smd: 9(-1.958,1.4) 10(-1.958,1) 11(-1.958,0.6) 12(-1.958,0.2) 13(-1.958,-0.2) 14(-1.958,-0.6) 15(-1.958,-1) 16(-1.958,-1.4) 25(1.958,-1.4) 26(1.958,-1) 27(1.958,-0.6) 28(1.958,-0.2) 29(1.958,0.2) 30(1.958,0.6) 31(1.958,1) 32(1.958,1.4)
  rect 2.845x2.845 smd: 33(0,0)
QFN40G6-G4D7H24
  rect 0.305x0.66 smd: 1(2.25,2.911) 10(-2.25,2.911) 21(-2.25,-2.911) 30(2.25,-2.911)
  rect 0.305x0.686 smd: 2(1.75,2.911) 3(1.25,2.911) 4(0.75,2.911) 5(0.25,2.911) 6(-0.25,2.911) 7(-0.75,2.911) 8(-1.25,2.911) 9(-1.75,2.911) 22(-1.75,-2.911) 23(-1.25,-2.911) 24(-0.75,-2.911) 25(-0.25,-2.911) 26(0.25,-2.911) 27(0.75,-2.911) 28(1.25,-2.911) 29(1.75,-2.911)
  rect 0.66x0.305 smd: 11(-2.911,2.25) 20(-2.911,-2.25) 31(2.911,-2.25) 40(2.911,2.25)
  rect 0.686x0.305 smd: 12(-2.911,1.75) 13(-2.911,1.25) 14(-2.911,0.75) 15(-2.911,0.25) 16(-2.911,-0.25) 17(-2.911,-0.75) 18(-2.911,-1.25) 19(-2.911,-1.75) 32(2.911,-1.75) 33(2.911,-1.25) 34(2.911,-0.75) 35(2.911,-0.25) 36(2.911,0.25) 37(2.911,0.75) 38(2.911,1.25) 39(2.911,1.75)
  rect 4.699x4.699 smd: 41(0,0)
QFN40J5-G3D6-DIFF-H34
  rect 0.203x0.66 smd: 1(1.8,2.388) 10(-1.8,2.388) 21(-1.8,-2.388) 30(1.8,-2.388)
  rect 0.203x0.737 smd: 2(1.4,2.388) 3(1,2.388) 4(0.6,2.388) 5(0.2,2.388) 6(-0.2,2.388) 7(-0.6,2.388) 8(-1,2.388) 9(-1.4,2.388) 22(-1.4,-2.388) 23(-1,-2.388) 24(-0.6,-2.388) 25(-0.2,-2.388) 26(0.2,-2.388) 27(0.6,-2.388) 28(1,-2.388) 29(1.4,-2.388)
  rect 0.66x0.203 smd: 11(-2.388,1.8) 20(-2.388,-1.8) 31(2.388,-1.8) 40(2.388,1.8)
  rect 0.737x0.203 smd: 12(-2.388,1.4) 13(-2.388,1) 14(-2.388,0.6) 15(-2.388,0.2) 16(-2.388,-0.2) 17(-2.388,-0.6) 18(-2.388,-1) 19(-2.388,-1.4) 32(2.388,-1.4) 33(2.388,-1) 34(2.388,-0.6) 35(2.388,-0.2) 36(2.388,0.2) 37(2.388,0.6) 38(2.388,1) 39(2.388,1.4)
  rect 3.607x3.607 smd: 41(0,0)
QFN40J4060-G2848H32
  rect 0.203x0.635 smd: 1(1.4,2.936) 2(1,2.936) 3(0.6,2.936) 4(0.2,2.936) 5(-0.2,2.936) 6(-0.6,2.936) 7(-1,2.936) 8(-1.4,2.936) 21(-1.4,-2.936) 22(-1,-2.936) 23(-0.6,-2.936) 24(-0.2,-2.936) 25(0.2,-2.936) 26(0.6,-2.936) 27(1,-2.936) 28(1.4,-2.936)
  rect 0.635x0.203 smd: 9(-1.936,2.2) 10(-1.936,1.8) 11(-1.936,1.4) 12(-1.936,1) 13(-1.936,0.6) 14(-1.936,0.2) 15(-1.936,-0.2) 16(-1.936,-0.6) 17(-1.936,-1) 18(-1.936,-1.4) 19(-1.936,-1.8) 20(-1.936,-2.2) 29(1.936,-2.2) 30(1.936,-1.8) 31(1.936,-1.4) 32(1.936,-1) 33(1.936,-0.6) 34(1.936,-0.2) 35(1.936,0.2) 36(1.936,0.6) 37(1.936,1) 38(1.936,1.4) 39(1.936,1.8) 40(1.936,2.2)
  rect 2.794x4.801 smd: 41(0,0)
QFN48J6-G465H40
  rect 0.203x0.711 smd: 1(2.2,2.962) 2(1.8,2.962) 3(1.4,2.962) 4(1,2.962) 5(0.6,2.962) 6(0.2,2.962) 7(-0.2,2.962) 8(-0.6,2.962) 9(-1,2.962) 10(-1.4,2.962) 11(-1.8,2.962) 12(-2.2,2.962) 25(-2.2,-2.962) 26(-1.8,-2.962) 27(-1.4,-2.962) 28(-1,-2.962) 29(-0.6,-2.962) 30(-0.2,-2.962) 31(0.2,-2.962) 32(0.6,-2.962) 33(1,-2.962) 34(1.4,-2.962) 35(1.8,-2.962) 36(2.2,-2.962)
  rect 0.711x0.203 smd: 13(-2.962,2.2) 14(-2.962,1.8) 15(-2.962,1.4) 16(-2.962,1) 17(-2.962,0.6) 18(-2.962,0.2) 19(-2.962,-0.2) 20(-2.962,-0.6) 21(-2.962,-1) 22(-2.962,-1.4) 23(-2.962,-1.8) 24(-2.962,-2.2) 37(2.962,-2.2) 38(2.962,-1.8) 39(2.962,-1.4) 40(2.962,-1) 41(2.962,-0.6) 42(2.962,-0.2) 43(2.962,0.2) 44(2.962,0.6) 45(2.962,1) 46(2.962,1.4) 47(2.962,1.8) 48(2.962,2.2)
  rect 4.648x4.648 smd: 49(0,0)
R402H14
  custom 0.127x0.127 smd: 1(0,0.432) 2(0,-0.432)
R402H15
  custom 0.127x0.127 smd: 1(0,0.432) 2(0,-0.432)
R402H16
  custom 0.127x0.127 smd: 1(0,0.432) 2(0,-0.432)
R603H22
  custom 0.197x0.197 smd: 1(0,0.66) 2(0,-0.66)
R603H24
  custom 0.197x0.197 smd: 1(0,0.66) 2(0,-0.66)
R805H20
  rect 1.549x0.94 smd: 1(0,0.838) 2(0,-0.838)
R805H24
  rect 1.549x0.94 smd: 1(0,0.838) 2(0,-0.838)
R1206H24
  rect 1.854x1.016 smd: 1(0,1.346) 2(0,-1.346)
R1206H28
  rect 1.854x1.016 smd: 1(0,1.346) 2(0,-1.346)
R2512H28
  rect 3.454x1.219 smd: 1(0,2.819) 2(0,-2.819)
R3720H40
  rect 4.013x1.041 smd: 1(0,0.867) 2(0,-0.867)
SC70-2D2-312H44
  custom 0.152x0.152 smd: 1(-0.65,-0.864) 2(0.65,-0.864) 3(0,0.864)
SC70-5-1H44
  rect 0.356x1.092 smd: 1(-0.65,-0.859) 2(0,-0.859) 3(0.65,-0.859) 4(0.65,0.857) 5(-0.65,0.857)
SC70-5H44
  rect 0.356x0.762 smd: 1(0.65,0.935) 2(0,0.935) 3(-0.65,0.935) 4(-0.65,-0.935) 5(0.65,-0.935)
SKT-HDMI23-187137-1
  oval 0.813x0.914 hole 0.559: 1(-4.5,5.75) 2(-4,7.25) 3(-3.5,5.75) 4(-3,7.25) 5(-2.5,5.75) 6(-2,7.25) 7(-1.5,5.75) 8(-1,7.25) 9(-0.5,5.75) 10(0,7.25) 11(0.5,5.75) 12(1,7.25) 13(1.5,5.75) 14(2,7.25) 15(2.5,5.75) 16(3,7.25) 17(3.5,5.75) 18(4,7.25) 19(4.5,5.75)
  oval 1.626x2.413 hole 0.914x1.702: 20(-9.15,0) 21(-7.25,6.5) 22(7.25,6.5) 23(9.15,0)
SKT-USB13-160166-2
  round 1.067 hole 0.711: 1(3.5,9.2) 2(1,9.2) 3(-1,9.2) 4(-3.5,9.2) 5(-4,7.7) 6(-2,7.7) 7(0,7.7) 8(2,7.7) 9(4,7.7)
  oval 1.422x2.997 hole 0.711x2.286: 10(6.4,8.45) 11(-6.4,8.45)
  oval 1.626x2.235 hole 0.914x1.524: 12(7.85,0) 13(-7.85,0)
SKT-USB34-124102-U
  round 0.254 hole 0.762 unplated: (-3.45,5.8) (3.45,5.8)
  oval 1.321x2.134 hole 0.61x1.6: 13(-6.075,0) 22(6.075,0)
  oval 1.321x2.311 hole 0.61x1.6: 14(-6.075,3.865) 21(6.075,3.865)
  oval 1.041x1.829 hole 0.508x1.118: 15(-4.475,6.2) 20(4.475,6.2)
  custom 0.076x0.076 smd: 16(-3.2,6.49) 19(3.2,6.49) A1(-2.75,5.74) A12(2.75,5.74)
  rect 0.508x0.305 smd: 17(-1,6.49) 18(1,6.49)
  rect 0.305x0.61 smd: A2(-2.25,5.74) A3(-1.75,5.74) A4(-1.25,5.74) A5(-0.75,5.74) A6(-0.25,5.74) A7(0.25,5.74) A8(0.75,5.74) A9(1.25,5.74) A10(1.75,5.74) A11(2.25,5.74)
  oval 1.651x0.991 hole 1.016x0.508: B1(3.2,4.665) B12(-3.2,4.665)
  round 0.66 hole 0.406: B2(2.5,3.765) B3(1.7,3.765) B4(1.3,4.665) B5(0.85,3.765) B6(0.4,4.665) B7(-0.4,4.665) B8(-0.85,3.765) B9(-1.3,4.665) B10(-1.7,3.765) B11(-2.5,3.765)
SLP2510P8-1H22
  rect 0.305x0.635 smd: 1(-1,-0.437) 5(1,-0.437) 6(1,0.437) 10(-1,0.437)
  rect 0.203x0.635 smd: 2(-0.5,-0.437) 4(0.5,-0.437) 7(0.5,0.437) 9(-0.5,0.437)
  rect 0.406x0.635 smd: 3(0,-0.437) 8(0,0.437)
SMD49-12H36
  rect 1.753x1.27 smd: 1(0,1.231) 2(0,-1.231)
SMD-ARES4
  rect 0.356x0.61 smd: 1(-0.325,-0.457) 2(0.325,-0.457) 3(0.325,0.457) 4(-0.325,0.457)
SMD-ARES4-2H18-U
  rect 0.305x0.406 smd: 1(-0.25,-0.305) 2(0.25,-0.305) 3(0.25,0.305) 4(-0.25,0.305)
SMD-ARES4H18
  rect 0.356x0.61 smd: 1(-0.325,-0.457) 2(0.325,-0.457) 3(0.325,0.457) 4(-0.325,0.457)
SMD-ARES4H20
  rect 0.356x0.61 smd: 1(-0.325,-0.457) 2(0.325,-0.457) 3(0.325,0.457) 4(-0.325,0.457)
SMD-OSC2H56
  rect 1.194x0.61 smd: 1(-3.147,-0.457) 2(3.147,-0.457) 3(3.147,0.457) 4(-3.147,0.457)
SOD123AK-2H43
  rect 1.143x1.245 smd: A(0,1.631) K(0,-1.631)
SOD323AKH38
  rect 0.559x0.813 smd: A(0,1.1) K(0,-1.1)
SOD323AKH44
  rect 0.559x0.813 smd: A(0,1.1) K(0,-1.1)
SOD882-10D6-1H20
  rect 0.61x0.457 smd: 1(0,0.457) 2(0,-0.457)
SOD-523-2H26
  rect 0.559x0.762 smd: 1(0,0.724) 2(0,-0.724)
SOIC8-1H86
  rect 0.635x1.524 smd: 1(-1.905,-3.442) 2(-0.635,-3.442) 3(0.635,-3.442) 4(1.905,-3.442) 5(1.905,3.442) 6(0.635,3.442) 7(-0.635,3.442) 8(-1.905,3.442)
SOIC8-G3530H63
  rect 0.635x1.524 smd: 1(-1.905,-2.492) 2(-0.635,-2.492) 3(0.635,-2.492) 4(1.905,-2.492) 5(1.905,2.492) 6(0.635,2.492) 7(-0.635,2.492) 8(-1.905,2.492)
  rect 3.505x2.997 smd: 9(0,0)
SOIC8-G3627H67
  rect 0.635x1.524 smd: 1(-1.905,-2.489) 2(-0.635,-2.489) 3(0.635,-2.489) 4(1.905,-2.489) 5(1.905,2.489) 6(0.635,2.489) 7(-0.635,2.489) 8(-1.905,2.489)
  rect 3.607x2.692 smd: 9(0,0)
SOIC8H69
  rect 0.635x1.524 smd: 1(-1.905,-2.477) 2(-0.635,-2.477) 3(0.635,-2.477) 4(1.905,-2.477) 5(1.905,2.477) 6(0.635,2.477) 7(-0.635,2.477) 8(-1.905,2.477)
SOT23-2D4-312H44
  custom 0.171x0.171 smd: 1(-0.95,-1.069) 2(0.95,-1.069) 3(0,1.069)
SOT23-2D4-312H46
  custom 0.171x0.171 smd: 1(-0.95,-1.069) 2(0.95,-1.069) 3(0,1.069)
SOT23-2D4-312H48
  custom 0.171x0.171 smd: 1(-0.95,-1.069) 2(0.95,-1.069) 3(0,1.069)
SOT23-2D4-312H60
  custom 0.171x0.171 smd: 1(-0.95,-1.069) 2(0.95,-1.069) 3(0,1.069)
SOT23CBE2D4H44
  custom 0.165x0.165 smd: B(-0.95,-1.073) C(0,1.073) E(0.95,-1.073)
SOT23CBE2D4H46-U
  custom 0.165x0.165 smd: B(-0.95,-1.073) C(0,1.073) E(0.95,-1.073)
SOT23CBE2D6H62
  custom 0.165x0.165 smd: B(-0.95,-1.016) C(0,1.016) E(0.95,-1.016)
SOT23DGS2D4H44
  custom 0.171x0.171 smd: D(0,1.069) G(-0.95,-1.069) S(0.95,-1.069)
SOT23DGS2D4H48
  custom 0.171x0.171 smd: D(0,1.069) G(-0.95,-1.069) S(0.95,-1.069)
SOT323CBE2D2H40
  custom 0.152x0.152 smd: B(-0.65,-0.864) C(0,0.864) E(0.65,-0.864)
SOT883-1D0-321H20
  rect 0.203x0.305 smd: 1(0.203,-0.35) 2(-0.203,-0.35)
  rect 0.559x0.305 smd: 3(0,0.35)
SOT-6H58
  rect 0.61x0.813 smd: 1(-0.95,-1.219) 2(0,-1.219) 3(0.95,-1.219) 4(0.95,1.219) 5(0,1.219) 6(-0.95,1.219)
SOT-23-5H51
  rect 0.686x0.864 smd: 1(-0.953,-1.232) 2(0,-1.232) 3(0.953,-1.232) 4(0.953,1.232) 5(-0.953,1.232)
SOT-23-5H52
  rect 0.686x0.864 smd: 1(-0.953,-1.232) 2(0,-1.232) 3(0.953,-1.232) 4(0.953,1.232) 5(-0.953,1.232)
SOT-23-5H56
  rect 0.686x0.864 smd: 1(-0.953,-1.232) 2(0,-1.232) 3(0.953,-1.232) 4(0.953,1.232) 5(-0.953,1.232)
SOT-23-5H58
  rect 0.686x0.864 smd: 1(-0.953,-1.232) 2(0,-1.232) 3(0.953,-1.232) 4(0.953,1.232) 5(-0.953,1.232)
SOT-23-9H44
  custom 0.165x0.165 smd: 1(-0.953,-1.056) 2(0.953,-1.056) 3(0,1.056)
SOT-363H44
  rect 0.356x0.965 smd: 1(-0.65,-0.826) 2(0,-0.826) 3(0.65,-0.826) 4(0.65,0.826) 5(0,0.826) 6(-0.65,0.826)
SPR5128H111
  rect 4.801x2.489 smd: 1(-1.397,0)
SPR5630H142
  rect 5.283x2.692 smd: 1(-2.413,0)
STF217R115H101
  round 5.512 hole 2.921: 1(0,0)
TJE-533-S-V-T-R-744
  rect 0.61x0.991 smd: 1(-1.845,2.205) 2(-1.845,-2.205) 3(1.845,2.205) 4(1.845,-2.205)
  rect 0.457x1.397 smd: 5(-2.521,0) 6(2.521,0)
TPAD14-OP
  round 0.356 smd: 1(0,0)
TPAD28
  round 0.711 smd: 1(0,0)
TQFP128-2H48
  rect 0.203x1.27 smd: 1(6.2,7.62) 2(5.8,7.62) 3(5.4,7.62) 4(5,7.62) 5(4.6,7.62) 6(4.2,7.62) 7(3.8,7.62) 8(3.4,7.62) 9(3,7.62) 10(2.6,7.62) 11(2.2,7.62) 12(1.8,7.62) 13(1.4,7.62) 14(0.999,7.62) 15(0.599,7.62) 16(0.199,7.62) 17(-0.199,7.62) 18(-0.599,7.62) 19(-0.999,7.62) 20(-1.4,7.62) 21(-1.8,7.62) 22(-2.2,7.62) 23(-2.6,7.62) 24(-3,7.62) 25(-3.4,7.62) 26(-3.8,7.62) 27(-4.2,7.62) 28(-4.6,7.62) 29(-5,7.62) 30(-5.4,7.62) 31(-5.8,7.62) 32(-6.2,7.62) 65(-6.2,-7.62) 66(-5.8,-7.62) 67(-5.4,-7.62) 68(-5,-7.62) 69(-4.6,-7.62) 70(-4.2,-7.62) 71(-3.8,-7.62) 72(-3.4,-7.62) 73(-3,-7.62) 74(-2.6,-7.62) 75(-2.2,-7.62) 76(-1.8,-7.62) 77(-1.4,-7.62) 78(-0.999,-7.62) 79(-0.599,-7.62) 80(-0.199,-7.62) 81(0.199,-7.62) 82(0.599,-7.62) 83(0.999,-7.62) 84(1.4,-7.62) 85(1.8,-7.62) 86(2.2,-7.62) 87(2.6,-7.62) 88(3,-7.62) 89(3.4,-7.62) 90(3.8,-7.62) 91(4.2,-7.62) 92(4.6,-7.62) 93(5,-7.62) 94(5.4,-7.62) 95(5.8,-7.62) 96(6.2,-7.62)
  rect 1.27x0.203 smd: 33(-7.62,6.2) 34(-7.62,5.8) 35(-7.62,5.4) 36(-7.62,5) 37(-7.62,4.6) 38(-7.62,4.2) 39(-7.62,3.8) 40(-7.62,3.4) 41(-7.62,3) 42(-7.62,2.6) 43(-7.62,2.2) 44(-7.62,1.8) 45(-7.62,1.4) 46(-7.62,0.999) 47(-7.62,0.599) 48(-7.62,0.199) 49(-7.62,-0.199) 50(-7.62,-0.599) 51(-7.62,-0.999) 52(-7.62,-1.4) 53(-7.62,-1.8) 54(-7.62,-2.2) 55(-7.62,-2.6) 56(-7.62,-3) 57(-7.62,-3.4) 58(-7.62,-3.8) 59(-7.62,-4.2) 60(-7.62,-4.6) 61(-7.62,-5) 62(-7.62,-5.4) 63(-7.62,-5.8) 64(-7.62,-6.2) 97(7.62,-6.2) 98(7.62,-5.8) 99(7.62,-5.4) 100(7.62,-5) 101(7.62,-4.6) 102(7.62,-4.2) 103(7.62,-3.8) 104(7.62,-3.4) 105(7.62,-3) 106(7.62,-2.6) 107(7.62,-2.2) 108(7.62,-1.8) 109(7.62,-1.4) 110(7.62,-0.999) 111(7.62,-0.599) 112(7.62,-0.199) 113(7.62,0.199) 114(7.62,0.599) 115(7.62,0.999) 116(7.62,1.4) 117(7.62,1.8) 118(7.62,2.2) 119(7.62,2.6) 120(7.62,3) 121(7.62,3.4) 122(7.62,3.8) 123(7.62,4.2) 124(7.62,4.6) 125(7.62,5) 126(7.62,5.4) 127(7.62,5.8) 128(7.62,6.2)
unnamed#2
  round 0.254 hole 2.184 unplated: (0,0)
XSON6H24
  rect 0.305x0.381 smd: 1(-0.5,-0.417) 2(0,-0.417) 3(0.5,-0.417) 4(0.5,0.417) 5(0,0.417) 6(-0.5,0.417)

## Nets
1.8V_RUN_FB: PC5405.2 PR5403.2 PR5404.1 PU5401.2
3V3_AON_CT_2: C8306.1 U8301.10
3V3_AON_S0: C7315.1 C7316.1 C7324.1 C7704.1 C7735.1 C7736.1 C8301.1 GPU1.AA8 GPU1.AA9 GPU1.AB8 GPU1.G10 GPU1.G12 PR8203.1 PR8258.1 PR8304.1 PR8311.1 PR8316.1 Q7301.G Q7606.G R7303.2 R7312.2 R7605.1 R7609.1 R7614.1 R7617.1 R7619.1 R7625.1 R7628.1 R7631.1 R7633.1 R7643.2 R7649.2 R7657.1 R8301.1 RN7601.3(B) RN7601.4(B) RN7604.1(A) RN7604.2(A) RN7605.1(A) RN7605.2(A) RN7610.3(B) RN7610.4(B) U7301.5 U8301.8 U8301.9
3V3_AON_S0_DISCHG: PQ8306.3 PR8316.2
3V5V_CT1: C4001.1 U4001.12
3V5V_CT2: C4002.1 U4001.10
3V5V_S0_ON: C4003.2 D4005.A R4010.2 U4001.3 U4001.5
3V_5V_EN: C4009.1 D4001.1 PR4515.1 PR4516.1 R4006.1 R4009.1
3V_5V_POK: C1710.1 EC1705.1 PG4529.1 PG4531.1 PR5210.1 PR5406.1 R1728.2 R4033.1
3V_5V_POK#: Q1701.5 Q1701.6 R1726.1
3V_5V_POK_C: Q1701.2 R1727.2 R1728.1
5V_AUX_S5: PG4528.2 PR4510.2
5V_HDD_SIP: C6002.1 HDD1.8 HDD1.9 HDD1.10 HDD1.11 R6006.2
5V_HDMI_S5: C5736.1 F5701.2 HDMI2.18
5V_S0: C4005.1 C5535.1 C5536.1 C6004.1 D5701.3 EC8916.1 EC8917.1 EC8984.1 EC8985.1 EC8986.1 EC8987.1 EC8988.1 EC8989.1 EC8992.1 ED5501.5 F5701.1 F6501.1 PR8223.1 R2612.1 R2705.2 R2707.1 R2712.1 R5507.1 R6006.1 R6510.1 U4001.8 U4001.9 U5502.1 U5502.3 U8301.4
5V_S5: C3402.1 C3502.1 C3503.1 C3515.1 C3516.1 C3704.1 C3705.1 C3718.1 C3719.1 C4031.1 C4032.1 C5856.1 EC8914.1 EC8915.1 EC8941.1 EC8942.1 EC8943.1 EC8944.1 EC8945.1 EC8946.1 EC8947.1 EC8948.1 EC8949.1 ED6601.5 IOBD1.36 IOBD1.37 IOBD1.38 IOBD1.39 IOBD1.40 PC5001.1 PC5202.1 PC5401.1 PC5410.1 PG4507.2 PG4508.2 PG4509.2 PG4510.2 PG4511.2 PG4512.2 PG4513.2 PG4514.2 PR4303.1 PR4610.1 PR4635.1 PR4704.2 PR4803.2 PR4813.2 PR5118.2 PU5001.6 PU5201.21 PU5401.6 PU5403.6 Q6401.E Q6402.E Q6505.E R3402.1 R3405.1 R3406.1 R3734.1 U3401.1 U3501.5 U3502.5 U3503.5 U3703.2 U4001.4 U4001.6 U4001.7 U4002.3 U4006.4 U5801.4
5V_VCONN_EN: R3734.2 U3703.3
5V_VCONN_P1: R3706.1 R3736.1 U3703.5 U3703.6
5V_VCONN_P1_CCG4: R3736.2 U3701.8
20V_DCBATOUT: PC4402.1 PC4403.1 PC4404.1 PC4405.1 PG4402.1 PR4401.2 PU4403.5 PU4403.6 PU4403.7 PU4403.8
+3V_1D8V_AVDD: C2729.1 C2743.1 C2747.1 HDA27.3 R2742.1 R2743.2 R2744.2 R2748.2 R2749.1
+3V_1D8V_AVDD_IO: C2744.1 C2745.1 HDA27.18 R2750.2 R2751.1
+5V_AVDD: C2727.1 C2749.1 HDA27.40 R2705.1
+5V_KB_BL: AFTP6529.1 C6501.1 F6501.2 KBBL2.1
+5V_PVDD: C2732.1 C2733.1 C2742.1 C2748.1 HDA27.41 HDA27.46 R2707.2 R2712.2
+V1.00A_SIP: C1112.1 C2101.1 C2104.1 C2116.1 C2121.1 CPU1.A10 CPU1.A14 CPU1.AB17 CPU1.AB19 CPU1.AB20 CPU1.AK20 CPU1.K17 CPU1.L1 CPU1.L21 CPU1.P18 CPU1.T1 CPU1.Y18 R1102.2 R1803.2 R2108.1 R2109.1 R2110.1 R2111.1
+V1.00U_CPU: C4012.1 R4036.1 R4038.1 U4006.7 U4006.8
+V1.8A: C2714.1 C2722.1 PG5405.2 PG5406.2 PG5407.2 PG5801.1 PG5803.1 Q2702.S R1104.2 R2462.2 R2726.1
+V1.8A_SIP: C2108.1 CPU1.AA1 CPU1.AF11 CPU1.AF16 CPU1.AH10 CPU1.AH11 CPU1.AH12 CPU1.AK15 R1104.1 R1607.1 R1738.1 R1818.2 R1820.1 R1913.1 R1914.1 R1916.1 R1919.1
+V3.3A_SIP: C1113.1 C2105.1 C2106.1 C2107.1 C2109.1 C2110.1 C2111.1 CPU1.AD15 CPU1.AG15 CPU1.AJ16 CPU1.AJ21 CPU1.AK17 CPU1.T16 CPU1.V19 CPU1.Y15 CPU1.Y16 R1103.2 R1701.1 R1731.1 R2101.1
+VCCAMPHYPLL_1P0: C2113.1 CPU1.K15 CPU1.L15 R2107.2
+VCCAPLL_1P0: C2114.1 CPU1.V15 R2108.2
+VCCCLK2: C2115.1 CPU1.K19 R2109.2
+VCCCLK4: C2119.1 CPU1.N20 R2110.2
+VCCCLK5: C2122.1 CPU1.L19 R2111.2
+VCCDSW_1P0: C2103.1 CPU1.AL1
+VCCGT: C1102.1 C1103.1 C1104.1 C1105.1 C1106.1 C1107.1 CPU1.A58 CPU1.A62 CPU1.A66 CPU1.AA63 CPU1.AA64 CPU1.AA66 CPU1.AA67 CPU1.AA69 CPU1.AA70 CPU1.AA71 CPU1.AC64 CPU1.AC65 CPU1.AC66 CPU1.AC67 CPU1.AC68 CPU1.AC69 CPU1.AC70 CPU1.AC71 CPU1.J53 CPU1.J55 CPU1.J56 CPU1.J58 CPU1.J60 CPU1.K53 CPU1.K55 CPU1.K56 CPU1.K58 CPU1.K60 CPU1.L62 CPU1.L63 CPU1.L64 CPU1.L65 CPU1.L66 CPU1.L67 CPU1.L68 CPU1.L69 CPU1.L70 CPU1.L71 CPU1.M62 CPU1.N63 CPU1.N64 CPU1.N66 CPU1.N67 CPU1.N69 CPU1.N70 CPU1.N71 CPU1.R63 CPU1.R64 CPU1.R65 CPU1.R66 CPU1.R67 CPU1.R68 CPU1.R69 CPU1.R70 CPU1.R71 CPU1.T62 CPU1.U65 CPU1.U68 CPU1.U71 CPU1.W63 CPU1.W64 CPU1.W65 CPU1.W66 CPU1.W67 CPU1.W68 CPU1.W69 CPU1.W70 CPU1.W71 CPU1.Y62 EC1005.1 EC1006.1 PC1001.1 PC1037.1 PC1038.1 PC1039.1 PC1040.1 PC1041.1 PC1042.1 PC1043.1 PC1044.1 PC1045.1 PC1046.1 PC1047.1 PC1048.1 PC1049.1 PC1050.1 PC1051.1 PC1052.1 PC1053.1 PC1054.1 PC1055.1 PC1056.1 PC1057.1 PC1058.1 PC1059.1 PC1060.1 PC1061.1 PC1062.1 PC1063.1 PC1064.1 PC1065.1 PC1066.1 PC1067.1 PC1068.1 PC1069.1 PC1070.1 PG4708.2 PL4701.2 PR4663.1 PT4701.1 R721.1 R738.1 R742.2
+VCCIO: C1108.1 C1109.1 C1110.1 C1111.1 CPU1.AK28 CPU1.AK30 CPU1.AL30 CPU1.AL42 CPU1.AM28 CPU1.AM30 CPU1.AM42 EC8972.1 EC8973.1 EC8974.1 PC1102.1 PC1103.1 PC1104.1 R801.1 R4042.1 R4045.2
+VCCIO_SIP: C4007.1 R4045.1 U4002.6 U4002.7 U4002.8
+VCCPAZIO: CPU1.AJ19 R2101.2
+VCCPDSW_3P3: CPU1.AD17 CPU1.AD18 CPU1.AJ17 R1707.1 R1711.2
+VCCPRIM_CORE: C2102.1 C2120.1 CPU1.AF18 CPU1.AF19 CPU1.V20 CPU1.V21 EC2101.1 PC1105.1 PC1106.1 R1101.2
+VCCPRTC_3P3: C2117.1 C2118.1 CPU1.AK19 CPU1.BB14 R2106.2
+VCCSA: CPU1.AK23 CPU1.AK25 CPU1.G23 CPU1.G25 CPU1.G27 CPU1.G28 CPU1.J22 CPU1.J23 CPU1.J27 CPU1.K23 CPU1.K25 CPU1.K27 CPU1.K28 CPU1.K30 EC1001.1 EC1007.1 EC8971.1 PC1071.1 PC1072.1 PC1073.1 PC1074.1 PC1075.1 PC1076.1 PC1077.1 PC1078.1 PG5001.2 PL5001.2 R735.1
+VCCSFR: C720.1 C721.1 CPU1.K20 CPU1.K21 R4038.2
+VCCST_CPU: C716.1 CPU1.A18 PC4602.1 PR4603.1 PR4604.1 PR4605.1 PR4606.1 R419.1 R603.2 R723.1 R726.1 R727.1 R4036.2
+VCCSTG: C717.1 CPU1.A22 CPU1.G20 R401.1 R408.2 R409.2 R416.2 R417.2 R421.2 R422.2 R423.2 R4042.2
+VDDQ_CPU_CLK: C715.1 CPU1.AM40 R705.2
AV1_TP: CPU1.AV1 TP2307.1
AV71_TP: CPU1.AV71 TP2304.1
DVSS: HDA27.13 R2746.2
GND: AFTP2604.1 AFTP4306.1 AFTP4307.1 AFTP4308.1 AFTP6540.1 BATT1.8 BATT1.9 BATT1.10 C715.2 C716.2 C717.2 C718.2 C719.2 C720.2 C721.2 C1101.2 C1102.2 C1103.2 C1104.2 C1105.2 C1106.2 C1107.2 C1108.2 C1109.2 C1110.2 C1111.2 C1112.2 C1113.2 C1114.2 C1115.2 C1116.2 C1117.2 C1118.2 C1119.2 C1120.2 C1121.2 C1124.2 C1125.2 C1126.2 C1127.2 C1202.2 C1203.2 C1204.2 C1205.2 C1206.2 C1207.2 C1208.2 C1209.2 C1210.2 C1211.2 C1212.2 C1213.2 C1214.2 C1215.2 C1216.2 C1217.2 C1218.2 C1219.2 C1220.2 C1221.2 C1223.2 C1224.2 C1225.2 C1226.2 C1227.2 C1228.2 C1229.2 C1230.2 C1231.2 C1232.2 C1301.2 C1303.2 C1304.2 C1305.2 C1306.2 C1307.2 C1308.2 C1309.2 C1310.2 C1311.2 C1312.2 C1313.2 C1314.2 C1315.2 C1316.2 C1317.2 C1318.2 C1319.2 C1320.2 C1321.2 C1322.2 C1324.2 C1325.2 C1326.2 C1327.2 C1328.2 C1329.2 C1330.2 C1331.2 C1701.2 C1704.2 C1710.2 C1711.2 C1801.1 C1802.1 C1803.1 C1804.1 C1805.2 C1806.2 C2101.2 C2102.2 C2103.2 C2104.2 C2105.2 C2106.2 C2107.2 C2108.2 C2109.2 C2110.2 C2111.2 C2112.2 C2113.2 C2114.2 C2115.2 C2116.2 C2117.2 C2118.2 C2119.2 C2120.2 C2121.2 C2122.2 C2201.1 C2202.1 C2405.2 C2406.2 C2409.2 C2410.2 C2411.2 C2412.2 C2413.2 C2414.2 C2416.2 C2418.2 C2420.2 C2421.2 C2423.2 C2424.1 C2425.1 C2426.2 C2428.2 C2429.2 C2501.2 C2502.2 C2503.2 C2601.2 C2602.2 C2603.2 C2604.2 C2605.2 C2608.2 C2609.2 C2610.2 C2614.2 C2721.2 C2722.2 C2729.2 C2732.2 C2733.2 C2736.2 C2738.1 C2742.2 C2743.2 C2744.2 C2745.2 C2746.2 C2747.2 C2748.2 C3401.2 C3402.2 C3403.2 C3404.2 C3405.2 C3502.2 C3503.2 C3507.2 C3508.2 C3512.2 C3513.2 C3514.2 C3515.2 C3516.2 C3517.2 C3518.2 C3519.2 C3520.2 C3701.2 C3702.2 C3703.2 C3704.2 C3705.2 C3707.2 C3709.2 C3710.2 C3711.2 C3712.2 C3715.2 C3716.2 C3717.1 C3718.2 C3719.2 C3720.1 C3721.2 C3722.2 C3723.2 C3815.2 C3816.2 C3817.2 C3818.2 C3819.2 C3821.2 C3865.2 C4001.2 C4002.2 C4003.1 C4004.2 C4005.2 C4006.2 C4007.2 C4009.2 C4012.2 C4013.2 C4017.2 C4031.2 C4032.2 C4033.2 C4034.2 C4035.2 C4036.2 C5502.2 C5503.2 C5505.2 C5507.2 C5508.1 C5512.2 C5513.2 C5514.2 C5515.2 C5516.2 C5517.2 C5534.2 C5535.2 C5536.2 C5537.2 C5542.1 C5725.1 C5726.1 C5729.2 C5730.2 C5736.2 C5824.1 C5825.1 C5826.1 C5827.2 C5828.1 C5829.1 C5831.2 C5832.2 C5833.2 C5834.1 C5836.2 C5837.2 C5838.1 C5839.1 C5840.2 C5841.2 C5842.2 C5843.2 C5844.2 C5845.2 C5846.1 C5847.2 C5848.1 C5849.1 C5850.2 C5851.2 C5852.2 C5853.2 C5855.2 C5856.2 C5857.2 C5858.2 C5860.2 C5861.2 C6002.2 C6004.2 C6304.2 C6305.2 C6306.2 C6307.2 C6308.2 C6317.2 C6318.2 C6501.2 C6504.2 C6505.2 C7003.2 C7004.2 C7310.2 C7312.2 C7315.2 C7316.2 C7317.2 C7318.2 C7319.2 C7323.2 C7324.2 C7326.2 C7501.2 C7502.2 C7505.2 C7506.2 C7507.2 C7513.2 C7514.2 C7517.2 C7518.2 C7520.2 C7525.2 C7601.2 C7602.2 C7603.2 C7604.2 C7605.2 C7606.2 C7607.1 C7608.1 C7701.2 C7702.2 C7703.2 C7704.2 C7708.2 C7709.2 C7710.2 C7711.2 C7712.2 C7713.2 C7714.2 C7717.2 C7719.2 C7720.2 C7721.2 C7722.2 C7723.2 C7724.2 C7725.2 C7726.2 C7728.2 C7729.2 C7730.2 C7731.2 C7732.2 C7734.2 C7735.2 C7736.2 C7801.1 C7802.2 C7803.2 C7804.2 C7805.2 C7806.2 C7807.2 C7808.2 C7809.2 C7810.2 C7811.2 C7812.2 C7813.2 C7814.2 C7815.2 C7816.2 C7817.2 C7818.2 C7819.2 C7820.2 C7821.2 C7822.2 C7823.2 C7824.2 C7825.2 C7826.2 C7901.1 C7902.2 C7903.2 C7904.2 C7905.2 C7906.2 C7907.2 C7908.2 C7909.2 C7910.2 C7911.2 C7912.2 C7913.2 C7914.2 C7915.2 C7916.2 C7917.2 C7918.2 C7919.2 C7920.2 C7921.2 C7922.2 C7923.2 C7924.2 C7925.2 C7926.2 C8301.2 C8302.2 C8304.2 C8305.2 C8306.2 C8307.2 C8308.1 C8309.2 C8310.2 C9101.2 C9102.2 C9104.2 C9105.2 C9106.2 C9113.2 C9114.2 CCGDB1.2 CPU1.AA2 CPU1.AA4 CPU1.AA65 CPU1.AA68 CPU1.AB8 CPU1.AB15 CPU1.AB16 CPU1.AB18 CPU1.AB21 CPU1.AD8 CPU1.AD13 CPU1.AD16 CPU1.AD19 CPU1.AD20 CPU1.AD21 CPU1.AD62 CPU1.AE64 CPU1.AE65 CPU1.AE66 CPU1.AE67 CPU1.AE68 CPU1.AE69 CPU1.AF1 CPU1.AF2 CPU1.AF4 CPU1.AF10 CPU1.AF15 CPU1.AF17 CPU1.AF63 CPU1.AG16 CPU1.AG17 CPU1.AG18 CPU1.AG19 CPU1.AG20 CPU1.AG21 CPU1.AG71 CPU1.AH6 CPU1.AH13 CPU1.AH63 CPU1.AH64 CPU1.AH67 CPU1.AJ4 CPU1.AJ15 CPU1.AJ18 CPU1.AJ20 CPU1.AK8 CPU1.AK11 CPU1.AK16 CPU1.AK18 CPU1.AK21 CPU1.AK22 CPU1.AK27 CPU1.AK63 CPU1.AK68 CPU1.AK69 CPU1.AL2 CPU1.AL4 CPU1.AL28 CPU1.AL32 CPU1.AL35 CPU1.AL38 CPU1.AL45 CPU1.AL48 CPU1.AL52 CPU1.AL55 CPU1.AL58 CPU1.AL64 CPU1.AL65 CPU1.AL66 CPU1.AM8 CPU1.AM13 CPU1.AM21 CPU1.AM25 CPU1.AM27 CPU1.AM43 CPU1.AM45 CPU1.AM46 CPU1.AM55 CPU1.AM60 CPU1.AM61 CPU1.AM68 CPU1.AM71 CPU1.AN20 CPU1.AN23 CPU1.AN28 CPU1.AN30 CPU1.AN32 CPU1.AN33 CPU1.AN35 CPU1.AN37 CPU1.AN38 CPU1.AN40 CPU1.AN42 CPU1.AN58 CPU1.AN63 CPU1.AP10 CPU1.AP18 CPU1.AP20 CPU1.AP23 CPU1.AP28 CPU1.AP32 CPU1.AP35 CPU1.AP38 CPU1.AP42 CPU1.AP58 CPU1.AP63 CPU1.AP68 CPU1.AP70 CPU1.AR5 CPU1.AR8 CPU1.AR11 CPU1.AR15 CPU1.AR16 CPU1.AR20 CPU1.AR23 CPU1.AR28 CPU1.AR35 CPU1.AR42 CPU1.AR43 CPU1.AR45 CPU1.AR46 CPU1.AR48 CPU1.AR50 CPU1.AR52 CPU1.AR53 CPU1.AR55 CPU1.AR58 CPU1.AR63 CPU1.AT2 CPU1.AT4 CPU1.AT20 CPU1.AT23 CPU1.AT28 CPU1.AT35 CPU1.AT42 CPU1.AT56 CPU1.AT58 CPU1.AT63 CPU1.AT68 CPU1.AT71 CPU1.AU10 CPU1.AU15 CPU1.AU20 CPU1.AU32 CPU1.AU38 CPU1.AV68 CPU1.AV69 CPU1.AV70 CPU1.AW6 CPU1.AW8 CPU1.AW10 CPU1.AW12 CPU1.AW14 CPU1.AW16 CPU1.AW18 CPU1.AW21 CPU1.AW23 CPU1.AW26 CPU1.AW28 CPU1.AW30 CPU1.AW32 CPU1.AW34 CPU1.AW36 CPU1.AW38 CPU1.AW41 CPU1.AW43 CPU1.AW45 CPU1.AW47 CPU1.AW49 CPU1.AW51 CPU1.AW53 CPU1.AW55 CPU1.AW57 CPU1.AW60 CPU1.AW62 CPU1.AW64 CPU1.AW66 CPU1.AY66 CPU1.B10 CPU1.B14 CPU1.B18 CPU1.B22 CPU1.B30 CPU1.B34 CPU1.B39 CPU1.B44 CPU1.B48 CPU1.B53 CPU1.B58 CPU1.B62 CPU1.B66 CPU1.BA6 CPU1.BA10 CPU1.BA14 CPU1.BA18 CPU1.BA23 CPU1.BA28 CPU1.BA32 CPU1.BA36 CPU1.BA41 CPU1.BA45 CPU1.BA49 CPU1.BA53 CPU1.BA57 CPU1.BA62 CPU1.BA66 CPU1.BB6 CPU1.BB18 CPU1.BB26 CPU1.BB30 CPU1.BB34 CPU1.BB38 CPU1.BB43 CPU1.BB55 CPU1.BB60 CPU1.BB64 CPU1.C5 CPU1.C25 CPU1.D6 CPU1.D10 CPU1.D11 CPU1.D14 CPU1.D18 CPU1.D22 CPU1.D25 CPU1.D26 CPU1.D30 CPU1.D34 CPU1.D39 CPU1.D44 CPU1.D45 CPU1.D47 CPU1.D48 CPU1.D53 CPU1.D58 CPU1.D62 CPU1.D66 CPU1.D69 CPU1.E6 CPU1.E11 CPU1.E15 CPU1.E18 CPU1.E21 CPU1.E46 CPU1.E50 CPU1.E53 CPU1.E56 CPU1.E65 CPU1.F1 CPU1.F2 CPU1.F4 CPU1.F8 CPU1.F13 CPU1.F22 CPU1.F23 CPU1.F27 CPU1.F28 CPU1.F32 CPU1.F33 CPU1.F35 CPU1.F37 CPU1.F38 CPU1.F40 CPU1.F42 CPU1.F68 CPU1.G5 CPU1.G6 CPU1.G10 CPU1.G22 CPU1.G43 CPU1.G45 CPU1.G48 CPU1.G52 CPU1.G55 CPU1.G58 CPU1.G60 CPU1.G63 CPU1.G66 CPU1.H15 CPU1.H18 CPU1.H71 CPU1.J8 CPU1.J11 CPU1.J13 CPU1.J25 CPU1.J28 CPU1.J32 CPU1.J35 CPU1.J38 CPU1.J42 CPU1.K16 CPU1.K18 CPU1.K22 CPU1.K61 CPU1.K63 CPU1.K64 CPU1.K65 CPU1.K66 CPU1.K67 CPU1.K68 CPU1.K70 CPU1.K71 CPU1.L2 CPU1.L4 CPU1.L8 CPU1.L11 CPU1.L16 CPU1.L17 CPU1.L18 CPU1.L20 CPU1.N6 CPU1.N10 CPU1.N13 CPU1.N19 CPU1.N21 CPU1.N65 CPU1.N68 CPU1.P17 CPU1.P19 CPU1.P20 CPU1.P21 CPU1.R6 CPU1.R13 CPU1.T2 CPU1.T4 CPU1.T15 CPU1.T17 CPU1.T18 CPU1.T21 CPU1.U10 CPU1.U63 CPU1.U64 CPU1.U66 CPU1.U67 CPU1.U69 CPU1.U70 CPU1.V16 CPU1.V17 CPU1.V18 CPU1.W6 CPU1.W9 CPU1.W13 CPU1.Y17 CPU1.Y19 CPU1.Y20 CPU1.Y21 D502.1 D2601.A D4304.1 D4305.1 D4306.1 DB1.3 DB1.15 DB1.16 DBEC1.4 DBEC1.7 DBEC1.8 DCIN1.9 DCIN1.10 DM1.1 DM1.2 DM1.5 DM1.6 DM1.9 DM1.10 DM1.14 DM1.15 DM1.18 DM1.19 DM1.22 DM1.23 DM1.26 DM1.27 DM1.30 DM1.31 DM1.35 DM1.36 DM1.39 DM1.40 DM1.43 DM1.44 DM1.47 DM1.48 DM1.51 DM1.52 DM1.56 DM1.57 DM1.60 DM1.61 DM1.64 DM1.65 DM1.68 DM1.69 DM1.72 DM1.73 DM1.77 DM1.78 DM1.81 DM1.82 DM1.85 DM1.86 DM1.89 DM1.90 DM1.93 DM1.94 DM1.98 DM1.99 DM1.102 DM1.103 DM1.106 DM1.107 DM1.167 DM1.168 DM1.171 DM1.172 DM1.175 DM1.176 DM1.180 DM1.181 DM1.184 DM1.185 DM1.188 DM1.189 DM1.192 DM1.193 DM1.196 DM1.197 DM1.201 DM1.202 DM1.205 DM1.206 DM1.209 DM1.210 DM1.213 DM1.214 DM1.217 DM1.218 DM1.222 DM1.223 DM1.226 DM1.227 DM1.230 DM1.231 DM1.234 DM1.235 DM1.238 DM1.239 DM1.243 DM1.244 DM1.247 DM1.248 DM1.251 DM1.252 DM1.261 DM1.262 DM2.1 DM2.2 DM2.5 DM2.6 DM2.9 DM2.10 DM2.14 DM2.15 DM2.18 DM2.19 DM2.22 DM2.23 DM2.26 DM2.27 DM2.30 DM2.31 DM2.35 DM2.36 DM2.39 DM2.40 DM2.43 DM2.44 DM2.47 DM2.48 DM2.51 DM2.52 DM2.56 DM2.57 DM2.60 DM2.61 DM2.64 DM2.65 DM2.68 DM2.69 DM2.72 DM2.73 DM2.77 DM2.78 DM2.81 DM2.82 DM2.85 DM2.86 DM2.89 DM2.90 DM2.93 DM2.94 DM2.98 DM2.99 DM2.102 DM2.103 DM2.106 DM2.107 DM2.167 DM2.168 DM2.171 DM2.172 DM2.175 DM2.176 DM2.180 DM2.181 DM2.184 DM2.185 DM2.188 DM2.189 DM2.192 DM2.193 DM2.196 DM2.197 DM2.201 DM2.202 DM2.205 DM2.206 DM2.209 DM2.210 DM2.213 DM2.214 DM2.217 DM2.218 DM2.222 DM2.223 DM2.226 DM2.227 DM2.230 DM2.231 DM2.234 DM2.235 DM2.238 DM2.239 DM2.243 DM2.244 DM2.247 DM2.248 DM2.251 DM2.252 DM2.261 DM2.262 EC401.2 EC1001.2 EC1002.2 EC1003.2 EC1004.2 EC1005.2 EC1006.2 EC1007.2 EC1102.2 EC1103.2 EC1202.2 EC1203.2 EC1302.2 EC1303.2 EC1701.2 EC1702.2 EC1703.2 EC1704.2 EC1705.2 EC1706.2 EC1707.2 EC1708.2 EC1709.2 EC1710.2 EC1712.2 EC1801.2 EC1803.1 EC1806.2 EC1807.2 EC1808.2 EC1901.1 EC1902.2 EC1903.2 EC2002.2 EC2101.2 EC2501.2 EC2502.2 EC2503.2 EC2601.2 EC2602.2 EC2708.2 EC2709.2 EC2710.2 EC2711.2 EC2712.2 EC2713.2 EC2714.2 EC2901.2 EC2902.2 EC2903.2 EC2904.2 EC3601.2 EC3602.2 EC4306.1 EC4307.2 EC4308.2 EC4309.2 EC4310.2 EC4311.2 EC5501.2 EC5502.2 EC5503.2 EC5504.2 EC5505.2 EC6401.2 EC6402.2 EC6501.2 EC6502.2 EC6503.2 EC6504.2 EC6505.2 EC6506.2 EC6507.2 EC6601.2 EC6602.2 EC6603.2 EC8901.2 EC8902.2 EC8903.2 EC8904.2 EC8905.2 EC8906.2 EC8907.2 EC8908.2 EC8909.2 EC8910.2 EC8911.2 EC8912.2 EC8913.2 EC8914.2 EC8915.2 EC8916.2 EC8917.2 EC8918.2 EC8919.2 EC8920.2 EC8921.2 EC8922.2 EC8923.2 EC8924.2 EC8925.2 EC8927.2 EC8928.2 EC8929.2 EC8933.2 EC8934.2 EC8935.2 EC8936.2 EC8937.2 EC8938.2 EC8939.2 EC8940.2 EC8941.2 EC8942.2 EC8943.2 EC8944.2 EC8945.2 EC8946.2 EC8947.2 EC8948.2 EC8949.2 EC8951.2 EC8952.2 EC8953.2 EC8954.2 EC8955.2 EC8956.2 EC8957.2 EC8958.2 EC8959.2 EC8960.2 EC8961.2 EC8962.2 EC8963.2 EC8964.2 EC8965.2 EC8966.2 EC8967.2 EC8968.2 EC8969.2 EC8970.2 EC8971.2 EC8972.2 EC8973.2 EC8974.2 EC8975.2 EC8976.2 EC8977.2 EC8978.2 EC8979.2 EC8980.2 EC8981.2 EC8982.2 EC8983.2 EC8984.2 EC8985.2 EC8986.2 EC8987.2 EC8988.2 EC8989.2 EC8992.2 EC8993.2 EC8994.2 EC8995.2 EC8996.2 EC8997.2 EC8998.2 EC8999.2 ED1217.2 ED1302.2 ED2403.2 ED2901.3 ED2902.3 ED2903.3 ED3601.3 ED3601.8 ED3602.2 ED3603.3 ED3603.8 ED3604.2 ED3801.3 ED3801.8 ED3802.3 ED3802.8 ED3803.3 ED3804.3 ED3805.3 ED3806.3 ED5501.2 ED5502.2 ED5701.3 ED5701.8 ED5702.3 ED5702.8 ED6001.3 ED6001.8 ED6301.3 ED6301.8 ED6401.2 ED6402.2 ED6601.2 ED6602.3 ED6602.8 EL4303.2 EL4304.2 FAN1.2 FAN1.5 FAN1.6 G1801.1 GPU1.A2 GPU1.A26 GPU1.AA7 GPU1.AB7 GPU1.AB11 GPU1.AB14 GPU1.AB17 GPU1.AB20 GPU1.AB24 GPU1.AC2 GPU1.AC5 GPU1.AC8 GPU1.AC22 GPU1.AC26 GPU1.AD12 GPU1.AD13 GPU1.AD15 GPU1.AD16 GPU1.AD18 GPU1.AD19 GPU1.AD21 GPU1.AD22 GPU1.AE11 GPU1.AE14 GPU1.AE17 GPU1.AE20 GPU1.AF1 GPU1.AF5 GPU1.AF8 GPU1.AF11 GPU1.AF14 GPU1.AF17 GPU1.AF20 GPU1.AF23 GPU1.AG2 GPU1.AG26 GPU1.B1 GPU1.B5 GPU1.B8 GPU1.B11 GPU1.B14 GPU1.B17 GPU1.B20 GPU1.B23 GPU1.B27 GPU1.E2 GPU1.E5 GPU1.E8 GPU1.E11 GPU1.E14 GPU1.E17 GPU1.E20 GPU1.E22 GPU1.E25 GPU1.H2 GPU1.H5 GPU1.H23 GPU1.H25 GPU1.K11 GPU1.K13 GPU1.K15 GPU1.K17 GPU1.L2 GPU1.L5 GPU1.L10 GPU1.L12 GPU1.L14 GPU1.L16 GPU1.L18 GPU1.L23 GPU1.L25 GPU1.M11 GPU1.M13 GPU1.M15 GPU1.M17 GPU1.N10 GPU1.N12 GPU1.N14 GPU1.N16 GPU1.N18 GPU1.P2 GPU1.P5 GPU1.P11 GPU1.P13 GPU1.P15 GPU1.P17 GPU1.P23 GPU1.P26 GPU1.R10 GPU1.R12 GPU1.R14 GPU1.R16 GPU1.R18 GPU1.T11 GPU1.T13 GPU1.T15 GPU1.T17 GPU1.U2 GPU1.U5 GPU1.U10 GPU1.U12 GPU1.U14 GPU1.U16 GPU1.U18 GPU1.U23 GPU1.U26 GPU1.V11 GPU1.V13 GPU1.V15 GPU1.V17 GPU1.Y2 GPU1.Y5 GPU1.Y23 GPU1.Y26 H1.1 H2.1 H3.1 H4.1 H5.1 H6.1 H7.1 H8.1 H11.1 H12.1 H14.1 HDA27.49 HDD1.2 HDD1.3 HDD1.4 HDD1.7 HDD1.14 HDD1.17 HDD1.20 HDD1.21 HDD1.22 HDD1.23 HDD1.24 HDMI2.2 HDMI2.5 HDMI2.8 HDMI2.11 HDMI2.17 HDMI2.20 HDMI2.21 HDMI2.22 HDMI2.23 HS2.1 IOBD1.3 IOBD1.6 IOBD1.9 IOBD1.12 IOBD1.15 IOBD1.18 IOBD1.21 IOBD1.24 IOBD1.61 IOBD1.62 IOBD1.63 IOBD1.64 IOBD1.65 IOBD1.66 KB1.1 KB1.31 KB1.32 KBBL2.5 KBBL2.6 KBC24.17 KBC24.51 KBC24.64 KBC24.84 KBC24.100 KBC24.124 LCD1.12 LCD1.15 LCD1.18 LCD1.24 LCD1.25 LCD1.26 LCD1.27 LCD1.28 LCD1.39 LCD1.40 LCD1.41 LCD1.51 LCD1.52 LCD1.53 LCD1.54 LEDCN1.1 LEDCN1.4 LEDCN1.5 LEDCN1.6 PC1001.2 PC1002.2 PC1003.2 PC1004.2 PC1005.2 PC1006.2 PC1007.2 PC1008.2 PC1009.2 PC1010.2 PC1011.2 PC1012.2 PC1013.2 PC1014.2 PC1015.2 PC1016.2 PC1017.2 PC1018.2 PC1019.2 PC1020.2 PC1021.2 PC1022.2 PC1023.2 PC1024.2 PC1025.2 PC1026.2 PC1027.2 PC1028.2 PC1029.2 PC1030.2 PC1031.2 PC1032.2 PC1034.2 PC1036.2 PC1037.2 PC1038.2 PC1039.2 PC1040.2 PC1041.2 PC1042.2 PC1043.2 PC1044.2 PC1045.2 PC1046.2 PC1047.2 PC1048.2 PC1049.2 PC1050.2 PC1051.2 PC1052.2 PC1053.2 PC1054.2 PC1055.2 PC1056.2 PC1057.2 PC1058.2 PC1059.2 PC1060.2 PC1061.2 PC1062.2 PC1063.2 PC1064.2 PC1065.2 PC1066.2 PC1067.2 PC1068.2 PC1069.2 PC1070.2 PC1071.2 PC1072.2 PC1073.2 PC1074.2 PC1075.2 PC1076.2 PC1077.2 PC1078.2 PC1079.2 PC1080.2 PC1081.2 PC1082.2 PC1083.2 PC1084.2 PC1101.2 PC1102.2 PC1103.2 PC1104.2 PC1105.2 PC1106.2 PC1107.2 PC1108.2 PC1109.2 PC1110.2 PC1111.2 PC1112.2 PC1113.2 PC1114.2 PC1115.2 PC4302.2 PC4303.2 PC4304.2 PC4305.2 PC4306.2 PC4307.2 PC4311.2 PC4313.1 PC4314.2 PC4315.2 PC4401.2 PC4402.2 PC4403.2 PC4404.2 PC4405.2 PC4406.2 PC4407.2 PC4408.2 PC4409.2 PC4410.2 PC4411.2 PC4412.2 PC4413.2 PC4414.2 PC4416.1 PC4417.1 PC4419.2 PC4420.1 PC4421.2 PC4422.2 PC4424.1 PC4426.1 PC4427.2 PC4428.2 PC4429.2 PC4430.2 PC4431.2 PC4432.2 PC4433.2 PC4435.2 PC4439.1 PC4440.1 PC4441.2 PC4442.2 PC4443.2 PC4501.2 PC4502.2 PC4503.2 PC4504.2 PC4505.2 PC4507.2 PC4508.2 PC4509.2 PC4510.2 PC4511.2 PC4512.2 PC4513.2 PC4514.2 PC4515.2 PC4516.2 PC4517.2 PC4518.2 PC4519.2 PC4520.2 PC4522.2 PC4523.2 PC4524.2 PC4525.2 PC4527.2 PC4529.2 PC4530.2 PC4531.2 PC4532.2 PC4601.2 PC4602.2 PC4603.1 PC4604.1 PC4606.2 PC4607.2 PC4610.1 PC4612.2 PC4613.2 PC4614.2 PC4615.1 PC4620.2 PC4621.1 PC4622.2 PC4624.2 PC4629.1 PC4631.2 PC4633.2 PC4637.2 PC4638.2 PC4639.2 PC4640.2 PC4641.2 PC4644.2 PC4651.2 PC4701.2 PC4702.2 PC4703.2 PC4704.2 PC4706.2 PC4708.2 PC4802.2 PC4803.2 PC4804.2 PC4805.2 PC4809.2 PC4810.2 PC4812.2 PC4813.2 PC4814.2 PC4815.2 PC4816.2 PC4817.2 PC5001.2 PC5002.2 PC5003.2 PC5004.2 PC5104.2 PC5105.2 PC5107.2 PC5109.2 PC5110.2 PC5111.2 PC5112.2 PC5115.2 PC5116.2 PC5118.2 PC5119.2 PC5120.2 PC5121.2 PC5122.2 PC5123.2 PC5124.2 PC5201.2 PC5202.2 PC5203.2 PC5205.2 PC5206.2 PC5208.2 PC5209.2 PC5210.2 PC5211.2 PC5213.2 PC5214.2 PC5215.2 PC5216.2 PC5401.2 PC5402.2 PC5403.2 PC5404.2 PC5406.2 PC5410.2 PC5412.2 PC5413.2 PC5414.2 PC5427.2 PC8202.1 PC8203.1 PC8205.2 PC8206.2 PC8207.2 PC8208.2 PC8209.2 PC8210.2 PC8212.2 PC8213.2 PC8214.2 PC8215.2 PC8218.2 PC8220.2 PC8221.2 PC8222.2 PC8224.2 PC8225.1 PC8226.1 PC8301.2 PC8302.2 PC8303.2 PC8304.2 PC8306.2 PC8307.2 PC8309.2 PC8310.2 PC8311.2 PC8313.2 PC8314.2 PC8315.2 PC8316.2 PC8317.2 PC8318.2 PC8320.2 PC8321.2 PC8322.2 PD4301.A PD4302.1 PD4303.3 PD4304.A PQ4302.E PQ4304.E PQ4306.S PQ4307.1 PQ4307.4 PQ4308.1 PQ4308.4 PQ4309.1 PQ4310.1 PQ4310.4 PQ4311.1 PQ4311.4 PQ4312.S PQ4313.4 PQ4314.S PQ4402.S PQ4405.1 PQ4405.4 PQ4415.1 PQ4415.4 PQ4416.1 PQ4416.4 PQ8301.1 PQ8301.4 PQ8305.1 PQ8305.4 PQ8306.1 PQ8306.4 PQ8307.1 PQ8307.4 PQ8308.1 PQ8308.4 PR4302.2 PR4308.2 PR4313.2 PR4315.1 PR4316.2 PR4323.2 PR4324.2 PR4328.1 PR4332.2 PR4340.2 PR4344.1 PR4347.2 PR4406.2 PR4410.1 PR4413.2 PR4417.1 PR4426.2 PR4436.2 PR4474.1 PR4475.2 PR4508.2 PR4512.2 PR4513.2 PR4514.2 PR4530.2 PR4551.2 PR4608.1 PR4614.2 PR4617.2 PR4621.1 PR4627.1 PR4628.2 PR4629.2 PR4639.2 PR4644.2 PR4654.2 PR4655.1 PR4659.1 PR4661.2 PR4672.1 PR4712.2 PR4817.2 PR4818.2 PR5101.2 PR5105.2 PR5106.1 PR5203.2 PR5204.2 PR5401.2 PR5404.2 PR5409.2 PR5420.2 PR8213.2 PR8224.2 PR8259.2 PR8302.2 PR8313.2 PR8323.1 PR8326.2 PT4402.2 PT4701.2 PT4801.2 PT4803.2 PT4805.2 PT8206.2 PT8207.2 PT8208.2 PU4307.3 PU4401.33 PU4404.1 PU4404.2 PU4404.3 PU4406.1 PU4406.2 PU4406.3 PU4501.7 PU4501.8 PU4501.18 PU4501.21 PU4502.7 PU4502.8 PU4502.18 PU4502.21 PU4601.41 PU4701.3 PU4701.9 PU4801.3 PU4801.9 PU4802.3 PU4802.9 PU5001.4 PU5001.9 PU5003.1 PU5003.2 PU5003.3 PU5101.7 PU5101.8 PU5101.18 PU5101.21 PU5102.4 PU5102.8 PU5102.11 PU5201.4 PU5201.12 PU5201.13 PU5201.14 PU5201.15 PU5201.19 PU5401.1 PU5403.1 PU8201.21 PU8202.5 PU8202.6 PU8202.7 PU8204.5 PU8204.6 PU8204.7 PU8206.5 PU8206.6 PU8206.7 PU8208.5 PU8208.6 PU8208.7 PU8301.11 PU8302.7 PU8302.8 PU8302.18 PU8302.21 PWSW1.1 PWSW1.2 PWSW1.5 PWSW1.6 Q1701.1 Q1701.4 Q1702.1 Q1702.4 Q1802.S Q2001.1 Q2001.4 Q2408.S Q2505.S Q2701.S Q3701.S Q6501.S Q6503.S Q7001.1 Q7001.4 Q7801.S Q7901.S Q8301.S Q9104.S R402.2 R406.2 R407.2 R412.2 R413.2 R414.2 R415.2 R501.2 R502.2 R503.2 R601.2 R602.2 R604.2 R605.2 R720.2 R722.2 R734.2 R803.1 R1205.2 R1209.2 R1210.2 R1212.2 R1216.2 R1303.2 R1307.2 R1309.2 R1311.2 R1501.2 R1502.2 R1603.2 R1609.2 R1610.2 R1714.2 R1715.2 R1717.2 R1719.2 R1816.2 R1823.2 R1825.2 R1901.2 R1911.2 R1915.2 R1917.2 R1918.2 R1920.2 R2002.1 R2009.2 R2019.2 R2030.2 R2031.1 R2032.1 R2033.1 R2034.1 R2035.1 R2036.1 R2037.2 R2051.2 R2417.2 R2426.1 R2436.2 R2445.1 R2448.2 R2449.1 R2454.2 R2504.2 R2517.2 R2611.2 R2739.2 R2745.2 R2746.1 R3403.1 R3404.1 R3501.2 R3709.2 R3726.1 R3735.2 R3740.2 R3741.2 R3802.1 R3830.2 R3831.2 R3841.2 R3843.2 R3844.2 R3846.2 R3857.1 R3858.1 R3870.2 R3872.2 R3873.2 R4006.2 R4301.1 R4303.2 R4304.2 R5501.2 R5542.2 R5545.1 R5734.2 R5735.1 R5741.2 R5743.1 R5754.1 R5757.1 R5758.1 R5762.2 R5763.2 R5803.2 R6304.2 R6508.2 R6509.2 R7007.1 R7301.2 R7302.2 R7306.2 R7506.2 R7507.1 R7518.2 R7520.1 R7521.1 R7601.2 R7602.2 R7607.1 R7608.2 R7610.2 R7611.2 R7615.2 R7621.2 R7624.2 R7626.2 R7627.2 R7629.2 R7632.2 R7807.2 R7808.2 R7809.2 R7810.1 R7811.1 R7813.2 R7901.2 R7904.2 R7909.1 R7911.1 R7912.2 R7913.2 R8304.2 R9131.2 R9148.2 RN1201.2(A) RN1301.2(A) RN1703.1(A) RN1703.2(A) RN2009.1(A) RN2009.2(A) RN5502.1(A) RN5502.2(A) RN5502.3(A) RN5502.4(A) RN7401.3(B) RN7401.4(B) RN7602.1(A) RN7602.2(A) SKT251.4 SPI25.4 SPK1.6 SPK1.7 SPK1.8 SPR1.1 SPR2.1 SPR3.1 SPR4.1 SSD1.1 SSD1.3 SSD1.9 SSD1.15 SSD1.21 SSD1.27 SSD1.33 SSD1.39 SSD1.45 SSD1.51 SSD1.57 SSD1.71 SSD1.73 SSD1.75 SSD1.76 SSD1.77 TC3501.2 TCBD1.9 TCBD1.10 TCBD1.11 TCBD1.12 TCBD1.21 TCBD1.22 THM261.5 TPCON1.5 TPCON1.9 TPCON1.10 U3401.14 U3401.17 U3501.2 U3502.2 U3503.2 U3701.41 U3702.3 U3702.7 U3703.1 U3703.7 U3801.41 U3802.5 U3802.21 U4001.11 U4001.15 U4002.5 U4006.5 U4006.9 U4007.3 U4301.3 U4302.3 U5501.2 U5502.2 U5701.B3 U5701.B6 U5701.D4 U5701.D5 U5701.E4 U5701.E5 U5701.G3 U5701.G6 U5702.4 U5801.8 U5801.9 U7001.5 U7001.6 U7001.7 U7001.8 U7301.3 U8301.11 U8301.15 U9101.9 U9101.16 U9101.23 U9101.32 U9101.33 USB1.13 USB1.14 USB1.15 USB1.16 USB1.17 USB1.18 USB1.19 USB1.20 USB1.21 USB1.22 USB1.A1 USB1.A12 USB1.B1 USB1.B12 USB2.4 USB2.7 USB2.10 USB2.11 USB2.12 USB2.13 USB3.4 USB3.7 USB3.10 USB3.11 USB3.12 USB3.13 VRAM1.A1 VRAM1.A3 VRAM1.A12 VRAM1.A14 VRAM1.B5 VRAM1.B10 VRAM1.C1 VRAM1.C3 VRAM1.C4 VRAM1.C11 VRAM1.C12 VRAM1.C13 VRAM1.C14 VRAM1.D10 VRAM1.E1 VRAM1.E3 VRAM1.E12 VRAM1.E14 VRAM1.F5 VRAM1.F10 VRAM1.G5 VRAM1.G10 VRAM1.H1 VRAM1.H2 VRAM1.H13 VRAM1.H14 VRAM1.K1 VRAM1.K2 VRAM1.K13 VRAM1.K14 VRAM1.L5 VRAM1.L10 VRAM1.M5 VRAM1.M10 VRAM1.N1 VRAM1.N3 VRAM1.N12 VRAM1.N14 VRAM1.P10 VRAM1.R1 VRAM1.R3 VRAM1.R4 VRAM1.R11 VRAM1.R12 VRAM1.R14 VRAM1.T5 VRAM1.T10 VRAM1.U1 VRAM1.U3 VRAM1.U12 VRAM1.U14 VRAM2.A1 VRAM2.A3 VRAM2.A12 VRAM2.A14 VRAM2.B5 VRAM2.B10 VRAM2.C1 VRAM2.C3 VRAM2.C4 VRAM2.C11 VRAM2.C12 VRAM2.C13 VRAM2.C14 VRAM2.D10 VRAM2.E1 VRAM2.E3 VRAM2.E12 VRAM2.E14 VRAM2.F5 VRAM2.F10 VRAM2.G5 VRAM2.G10 VRAM2.H1 VRAM2.H2 VRAM2.H13 VRAM2.H14 VRAM2.K1 VRAM2.K2 VRAM2.K13 VRAM2.K14 VRAM2.L5 VRAM2.L10 VRAM2.M5 VRAM2.M10 VRAM2.N1 VRAM2.N3 VRAM2.N12 VRAM2.N14 VRAM2.P10 VRAM2.R1 VRAM2.R3 VRAM2.R4 VRAM2.R11 VRAM2.R12 VRAM2.R14 VRAM2.T5 VRAM2.T10 VRAM2.U1 VRAM2.U3 VRAM2.U12 VRAM2.U14 VRAM3.A1 VRAM3.A3 VRAM3.A12 VRAM3.A14 VRAM3.B5 VRAM3.B10 VRAM3.C1 VRAM3.C3 VRAM3.C4 VRAM3.C11 VRAM3.C12 VRAM3.C13 VRAM3.C14 VRAM3.D10 VRAM3.E1 VRAM3.E3 VRAM3.E12 VRAM3.E14 VRAM3.F5 VRAM3.F10 VRAM3.G5 VRAM3.G10 VRAM3.H1 VRAM3.H2 VRAM3.H13 VRAM3.H14 VRAM3.K1 VRAM3.K2 VRAM3.K13 VRAM3.K14 VRAM3.L5 VRAM3.L10 VRAM3.M5 VRAM3.M10 VRAM3.N1 VRAM3.N3 VRAM3.N12 VRAM3.N14 VRAM3.P10 VRAM3.R1 VRAM3.R3 VRAM3.R4 VRAM3.R11 VRAM3.R12 VRAM3.R14 VRAM3.T5 VRAM3.T10 VRAM3.U1 VRAM3.U3 VRAM3.U12 VRAM3.U14 VRAM4.A1 VRAM4.A3 VRAM4.A12 VRAM4.A14 VRAM4.B5 VRAM4.B10 VRAM4.C1 VRAM4.C3 VRAM4.C4 VRAM4.C11 VRAM4.C12 VRAM4.C13 VRAM4.C14 VRAM4.D10 VRAM4.E1 VRAM4.E3 VRAM4.E12 VRAM4.E14 VRAM4.F5 VRAM4.F10 VRAM4.G5 VRAM4.G10 VRAM4.H1 VRAM4.H2 VRAM4.H13 VRAM4.H14 VRAM4.K1 VRAM4.K2 VRAM4.K13 VRAM4.K14 VRAM4.L5 VRAM4.L10 VRAM4.M5 VRAM4.M10 VRAM4.N1 VRAM4.N3 VRAM4.N12 VRAM4.N14 VRAM4.P10 VRAM4.R1 VRAM4.R3 VRAM4.R4 VRAM4.R11 VRAM4.R12 VRAM4.R14 VRAM4.T5 VRAM4.T10 VRAM4.U1 VRAM4.U3 VRAM4.U12 VRAM4.U14 X1801.2 X1801.4 X2201.2 X2201.4 X5701.2 X5701.4 X7601.2 X7601.4
V0.85A_VID0: CPU1.AN11 TP2101.1
V0.85A_VID1: CPU1.AN13 TP2102.1
VBUS_PRODECT#: PQ4311.5 PQ4311.6 PR4337.1
VBUS_PRODECT_G: PQ4314.G PR4345.2 U4301.1
VBUS_SENSE: PR4346.2 PR4347.1 U4301.5
VCC1R05VIDEO_PEX_PLLVDD: C7317.1 C7318.1 C7319.1 GPU1.AA14 GPU1.AA15 L7301.1
VCC3PD: D3701.K D3702.K PR4337.2 PR4342.1 PR4345.1 R3732.1 R3733.1 U4301.2
VCC_CORE: C1101.1 C1124.1 C1125.1 C1126.1 C1127.1 CPU1.A30 CPU1.A34 CPU1.A39 CPU1.A44 CPU1.AK33 CPU1.AK35 CPU1.AK37 CPU1.AK38 CPU1.AK40 CPU1.AL33 CPU1.AL37 CPU1.AL40 CPU1.AM32 CPU1.AM33 CPU1.AM35 CPU1.AM37 CPU1.AM38 CPU1.G30 CPU1.G32 CPU1.G33 CPU1.G35 CPU1.G37 CPU1.G38 CPU1.G40 CPU1.G42 CPU1.J30 CPU1.J33 CPU1.J37 CPU1.J40 CPU1.K33 CPU1.K35 CPU1.K37 CPU1.K38 CPU1.K40 CPU1.K42 CPU1.K43 EC1002.1 EC1003.1 EC1004.1 EC8969.1 EC8970.1 PC1002.1 PC1003.1 PC1004.1 PC1005.1 PC1006.1 PC1007.1 PC1008.1 PC1009.1 PC1010.1 PC1011.1 PC1012.1 PC1013.1 PC1014.1 PC1015.1 PC1016.1 PC1017.1 PC1018.1 PC1019.1 PC1020.1 PC1021.1 PC1022.1 PC1023.1 PC1024.1 PC1025.1 PC1026.1 PC1027.1 PC1028.1 PC1029.1 PC1030.1 PC1031.1 PC1032.1 PC1034.1 PC1036.1 PC1079.1 PC1080.1 PC1081.1 PC1082.1 PC1083.1 PC1084.1 PG4809.2 PG4815.2 PL4801.2 PL4802.2 PR4631.2 PT4801.1 PT4803.1 R719.1 R736.1 R743.1
VCC_SENSE: CPU1.E32 PR4665.1 R719.2
VCCG0: CPU1.K32
VCCG1: CPU1.AK32
VCCGT_SENSE: CPU1.J70 PR4667.1 R721.2
VCCPD_VBUS: C3707.1 C3821.1 PC4310.2 PR4319.1 PR4336.2 PR4338.1 PR4343.1 PR4346.1 PU4303.1 PU4303.2 PU4303.3 PU4305.5 PU4305.6 PU4305.7 PU4305.8 R3730.1 R3739.1 U3702.6 USB1.A4 USB1.A9 USB1.B4 USB1.B9
VCCRTCEXT: C2112.1 CPU1.BB10
VCCSA_SENSE: CPU1.H20 PR4601.2 R735.2
VCCSTG_EN_L: R4037.1 U4007.4
VCCSTG_EN_R: C4033.1 D4004.A R4003.2 R4017.2 R4037.2 U4002.4
VCCSTU_EN_R: C4034.1 R4024.2 U4006.3
VDD: PC4422.1 PR4405.2 PR4427.1 PR4429.1 PU4401.18
VDD12: C5828.2 C5829.2 C5832.1 C5833.1 C5843.1 L5802.2 U5701.D6 U5701.F5
VDD33: C5824.2 C5825.2 C5826.2 C5855.1 L5801.2 U5701.B2 U5701.G2 U5701.G4
VDDA12: C5834.2 C5837.1 C5844.1 L5803.2 U5701.F4
VDDD: C3701.1 C3702.1 C3703.1 CCGDB1.1 R3708.1 R3724.1 R3725.1 R3732.2 R3742.1 RN3701.1(A) RN3701.2(A) RN3702.1(A) RN3702.2(A) U3701.31
VDDIO: C3721.1 C3722.1 C3723.1 R3733.2 U3701.32
VDDRX12: C5838.2 C5839.2 C5841.1 C5842.1 C5845.1 C5846.2 C5847.1 L5804.2 U5701.B4 U5701.B5 U5701.B7
VDDTX12: C5848.2 C5849.2 C5851.1 C5852.1 C5853.1 L5805.2 U5701.G5 U5701.G7
VSS_AY71: CPU1.AY71 R602.1
VSS_SENSE: CPU1.E33 PR4666.1 R720.1
VSSGT_SENSE: CPU1.J69 PR4668.1 R722.1
VSSSA_SENSE: CPU1.H21 PR4602.2 R734.1
0D6V_PWR: PC5124.1 PG5120.1 PG5121.1 PU5102.3 PU5102.5
0D6V_S0: C1223.1 C1224.1 C1225.1 C1226.1 C1227.1 C1230.1 C1324.1 C1325.1 C1326.1 C1327.1 DM1.258 DM2.258 PG5120.2 PG5121.2
1D0V_PWR: PC5201.1 PC5203.1 PC5205.1 PC5206.1 PC5208.1 PG5201.1 PG5204.1 PG5206.1 PG5207.1 PG5208.1 PG5209.1 PG5211.1 PG5213.1 PG5215.1 PG5216.1 PG5223.2 PL5201.2
1D0V_S5: C1114.1 C1115.1 C1116.1 C1117.1 C1118.1 C1119.1 C1120.1 C1121.1 C1704.1 C4013.1 CPU1.AF20 CPU1.AF21 CPU1.N15 CPU1.N16 CPU1.N17 CPU1.N18 CPU1.P15 CPU1.P16 CPU1.T19 CPU1.T20 EC1710.1 PG5201.2 PG5204.2 PG5206.2 PG5207.2 PG5208.2 PG5209.2 PG5211.2 R1101.1 R1102.1 R2107.1 R2402.1 U4006.1 U4006.2
1D0V_S5_PWRGD: PR5209.1 R4029.1
1D0V_S5_VCCIO: C4006.1 C4035.1 C4036.1 PG5213.2 PG5215.2 PG5216.2 U4002.1 U4002.2 U4002.9
1D2V_HDMI: C5831.1 C5836.1 C5840.1 C5850.1 L5802.1 L5803.1 L5804.1 L5805.1 PG5802.2
1D2V_HDMI_EN: R5801.1 U5701.G8
1D2V_HDMI_EN_R: C5858.1 R5801.2 U5801.2
1D2V_HDMI_FB: C5859.2 R5802.2 R5803.1 U5801.7
1D2V_HDMI_VIN: C5857.1 PG5801.2 PG5803.2 U5801.3
1D2V_S3: C718.1 C719.1 C1202.1 C1203.1 C1204.1 C1205.1 C1206.1 C1208.1 C1209.1 C1210.1 C1214.1 C1215.1 C1216.1 C1217.1 C1218.1 C1219.1 C1220.1 C1221.1 C1303.1 C1304.1 C1305.1 C1306.1 C1307.1 C1308.1 C1309.1 C1310.1 C1315.1 C1316.1 C1317.1 C1318.1 C1319.1 C1320.1 C1321.1 C1322.1 CPU1.AL23 CPU1.AU23 CPU1.AU28 CPU1.AU35 CPU1.AU42 CPU1.BB23 CPU1.BB32 CPU1.BB41 CPU1.BB47 CPU1.BB51 DM1.12 DM1.33 DM1.54 DM1.75 DM1.96 DM1.111 DM1.112 DM1.117 DM1.118 DM1.123 DM1.124 DM1.129 DM1.130 DM1.135 DM1.136 DM1.141 DM1.142 DM1.147 DM1.148 DM1.153 DM1.154 DM1.159 DM1.160 DM1.163 DM1.178 DM1.199 DM1.220 DM1.241 DM2.12 DM2.33 DM2.54 DM2.75 DM2.96 DM2.111 DM2.112 DM2.117 DM2.118 DM2.123 DM2.124 DM2.129 DM2.130 DM2.135 DM2.136 DM2.141 DM2.142 DM2.147 DM2.148 DM2.153 DM2.154 DM2.159 DM2.160 DM2.163 DM2.178 DM2.199 DM2.220 DM2.241 EC1102.1 EC1103.1 EC1202.1 EC1203.1 EC1303.1 EC8918.1 EC8919.1 EC8920.1 EC8921.1 EC8922.1 EC8923.1 EC8924.1 EC8925.1 EC8933.1 EC8934.1 EC8935.1 EC8936.1 EC8937.1 EC8938.1 PC1101.1 PC1107.1 PC1108.1 PC1109.1 PC1110.1 PC1111.1 PC1112.1 PC1113.1 PC1114.1 PC1115.1 PC5118.1 PC5122.1 PG5106.2 PG5107.2 PG5108.2 PG5109.2 PG5111.2 PG5115.2 PU5102.1 PU5102.2 Q501.G R505.1 R705.1 R1215.1 R1312.1 RN1201.1(A) RN1301.1(A)
1D2V_VTT_PWRGD: PG5114.1 R4011.1
1D05V_PWR: PC8303.1 PC8304.1 PC8323.1 PG8304.2 PG8305.2 PG8306.2 PG8307.2 PL8301.2 PR8303.1
1D05V_VGA_EN: C8308.2 PQ8301.2 PR8308.1 PR8310.2 R8305.2
1D05V_VGA_EN#: PQ8301.5 PQ8301.6 PR8307.2
1D05V_VGA_S0: C7310.1 C7312.1 C7323.1 C7326.1 GPU1.AA10 GPU1.AA12 GPU1.AA13 GPU1.AA16 GPU1.AA18 GPU1.AA19 GPU1.AA20 GPU1.AA21 GPU1.AA22 GPU1.AB22 GPU1.AB23 GPU1.AC23 GPU1.AC24 GPU1.AD24 GPU1.AD25 GPU1.AE25 GPU1.AE26 GPU1.AE27 GPU1.AF26 GPU1.AF27 L7301.2 L7501.2 L7601.1 L7602.1 PG8304.1 PG8305.1 PG8306.1 PG8307.1 PR8306.1
1D05V_VGA_S0_DISCHG: PQ8301.3 PR8306.2
1D05V_VGA_S0_PWRGD: D8301.2 PR8320.2 R8303.1
1D8V_EN#: Q2701.D R2726.2 R2727.1
1D8V_EN_R#: C2714.2 Q2702.G R2727.2
1D8V_PWR: PC5402.1 PC5404.1 PC5405.1 PG5405.1 PG5406.1 PG5407.1 PR5403.1 PU5401.3 PU5401.4
1D8V_S0: C2721.1 Q2702.D R2724.1 R2748.1 R2750.1 R6120.1
1D8V_S5_KBC: C2423.1 KBC24.54 R2462.1 R2464.2
1D35V_PGOOD: PR8321.1 TP8301.1
1D35V_PWR: PC8311.1 PC8313.1 PC8314.1 PC8320.1 PC8321.1 PG8308.1 PG8309.1 PG8310.1 PG8311.1 PG8312.1 PG8313.1 PG8318.1 PG8319.1 PG8320.1 PL8302.2
1D35V_VGA_EN: D8301.3 PQ8308.2 PR8322.1 R8303.2 R8304.1
1D35V_VGA_EN#: PQ8308.5 PQ8308.6 PR8328.1
1D35V_VGA_S0: C7501.1 C7502.1 C7507.1 C7513.1 C7514.1 C7517.1 C7520.1 C7525.1 C7804.1 C7805.1 C7806.1 C7807.1 C7808.1 C7809.1 C7810.1 C7811.1 C7812.1 C7813.1 C7814.1 C7815.1 C7816.1 C7817.1 C7818.1 C7819.1 C7820.1 C7821.1 C7822.1 C7823.1 C7824.1 C7825.1 C7904.1 C7905.1 C7906.1 C7907.1 C7909.1 C7910.1 C7911.1 C7912.1 C7913.1 C7914.1 C7915.1 C7916.1 C7917.1 C7918.1 C7919.1 C7920.1 C7921.1 C7922.1 C7923.1 C7924.1 C7925.1 C7926.1 GPU1.B26 GPU1.C25 GPU1.E23 GPU1.E26 GPU1.F14 GPU1.F21 GPU1.G13 GPU1.G14 GPU1.G15 GPU1.G16 GPU1.G18 GPU1.G19 GPU1.G20 GPU1.G21 GPU1.H24 GPU1.H26 GPU1.J21 GPU1.K21 GPU1.L22 GPU1.L24 GPU1.L26 GPU1.M21 GPU1.N21 GPU1.R21 GPU1.T21 GPU1.V21 GPU1.W21 PG8308.2 PG8309.2 PG8310.2 PG8311.2 PG8312.2 PG8318.2 PG8319.2 PG8320.2 R7501.2 R7503.2 R7505.2 R7516.2 R7524.2 R7805.1 R7806.1 R7812.2 R7903.1 R7907.1 R7910.2 VRAM1.B1 VRAM1.B3 VRAM1.B12 VRAM1.B14 VRAM1.C5 VRAM1.C10 VRAM1.D1 VRAM1.D3 VRAM1.D11 VRAM1.D12 VRAM1.D14 VRAM1.E5 VRAM1.E10 VRAM1.F1 VRAM1.F3 VRAM1.F12 VRAM1.F14 VRAM1.G1 VRAM1.G2 VRAM1.G4 VRAM1.G11 VRAM1.G13 VRAM1.G14 VRAM1.H3 VRAM1.H12 VRAM1.K3 VRAM1.K12 VRAM1.L1 VRAM1.L2 VRAM1.L4 VRAM1.L11 VRAM1.L13 VRAM1.L14 VRAM1.M1 VRAM1.M3 VRAM1.M12 VRAM1.M14 VRAM1.N5 VRAM1.N10 VRAM1.P1 VRAM1.P3 VRAM1.P11 VRAM1.P12 VRAM1.P14 VRAM1.R5 VRAM1.R10 VRAM1.T1 VRAM1.T3 VRAM1.T12 VRAM1.T14 VRAM2.B1 VRAM2.B3 VRAM2.B12 VRAM2.B14 VRAM2.C5 VRAM2.C10 VRAM2.D1 VRAM2.D3 VRAM2.D11 VRAM2.D12 VRAM2.D14 VRAM2.E5 VRAM2.E10 VRAM2.F1 VRAM2.F3 VRAM2.F12 VRAM2.F14 VRAM2.G1 VRAM2.G2 VRAM2.G4 VRAM2.G11 VRAM2.G13 VRAM2.G14 VRAM2.H3 VRAM2.H12 VRAM2.K3 VRAM2.K12 VRAM2.L1 VRAM2.L2 VRAM2.L4 VRAM2.L11 VRAM2.L13 VRAM2.L14 VRAM2.M1 VRAM2.M3 VRAM2.M12 VRAM2.M14 VRAM2.N5 VRAM2.N10 VRAM2.P1 VRAM2.P3 VRAM2.P11 VRAM2.P12 VRAM2.P14 VRAM2.R5 VRAM2.R10 VRAM2.T1 VRAM2.T3 VRAM2.T12 VRAM2.T14 VRAM3.B1 VRAM3.B3 VRAM3.B12 VRAM3.B14 VRAM3.C5 VRAM3.C10 VRAM3.D1 VRAM3.D3 VRAM3.D11 VRAM3.D12 VRAM3.D14 VRAM3.E5 VRAM3.E10 VRAM3.F1 VRAM3.F3 VRAM3.F12 VRAM3.F14 VRAM3.G1 VRAM3.G2 VRAM3.G4 VRAM3.G11 VRAM3.G13 VRAM3.G14 VRAM3.H3 VRAM3.H12 VRAM3.K3 VRAM3.K12 VRAM3.L1 VRAM3.L2 VRAM3.L4 VRAM3.L11 VRAM3.L13 VRAM3.L14 VRAM3.M1 VRAM3.M3 VRAM3.M12 VRAM3.M14 VRAM3.N5 VRAM3.N10 VRAM3.P1 VRAM3.P3 VRAM3.P11 VRAM3.P12 VRAM3.P14 VRAM3.R5 VRAM3.R10 VRAM3.T1 VRAM3.T3 VRAM3.T12 VRAM3.T14 VRAM4.B1 VRAM4.B3 VRAM4.B12 VRAM4.B14 VRAM4.C5 VRAM4.C10 VRAM4.D1 VRAM4.D3 VRAM4.D11 VRAM4.D12 VRAM4.D14 VRAM4.E5 VRAM4.E10 VRAM4.F1 VRAM4.F3 VRAM4.F12 VRAM4.F14 VRAM4.G1 VRAM4.G2 VRAM4.G4 VRAM4.G11 VRAM4.G13 VRAM4.G14 VRAM4.H3 VRAM4.H12 VRAM4.K3 VRAM4.K12 VRAM4.L1 VRAM4.L2 VRAM4.L4 VRAM4.L11 VRAM4.L13 VRAM4.L14 VRAM4.M1 VRAM4.M3 VRAM4.M12 VRAM4.M14 VRAM4.N5 VRAM4.N10 VRAM4.P1 VRAM4.P3 VRAM4.P11 VRAM4.P12 VRAM4.P14 VRAM4.R5 VRAM4.R10 VRAM4.T1 VRAM4.T3 VRAM4.T12 VRAM4.T14
1D35V_VGA_S0_DISCHG: PQ8308.3 PR8329.2
2D5V_S3: C1207.1 C1211.1 C1212.1 C1213.1 C1231.1 C1232.1 C1311.1 C1312.1 C1313.1 C1314.1 C1330.1 C1331.1 DM1.257 DM1.259 DM2.257 DM2.259 PG5408.2 PG5409.2
3D3V_AUX_S5: PG4532.2 PR4503.1 PR4505.1 PR8307.1 PR8315.2 PR8317.2 PR8319.2 PR8328.2 R1726.2 R1727.1 R1737.1 R2463.1 R2505.1 R2754.1
3D3V_CABLE: IOBD1.44 IOBD1.45 R6601.2 R6602.1
3D3V_CAMERA_S0: C5503.1 EC5502.1 F5502.2 LCD1.37
3D3V_GSEN2: C7003.1 C7004.1 R7004.2 R7005.1 R7006.2 U7001.9 U7001.10
3D3V_LDO: R5507.2 R5526.2 R5527.1 R5541.1 U5502.5
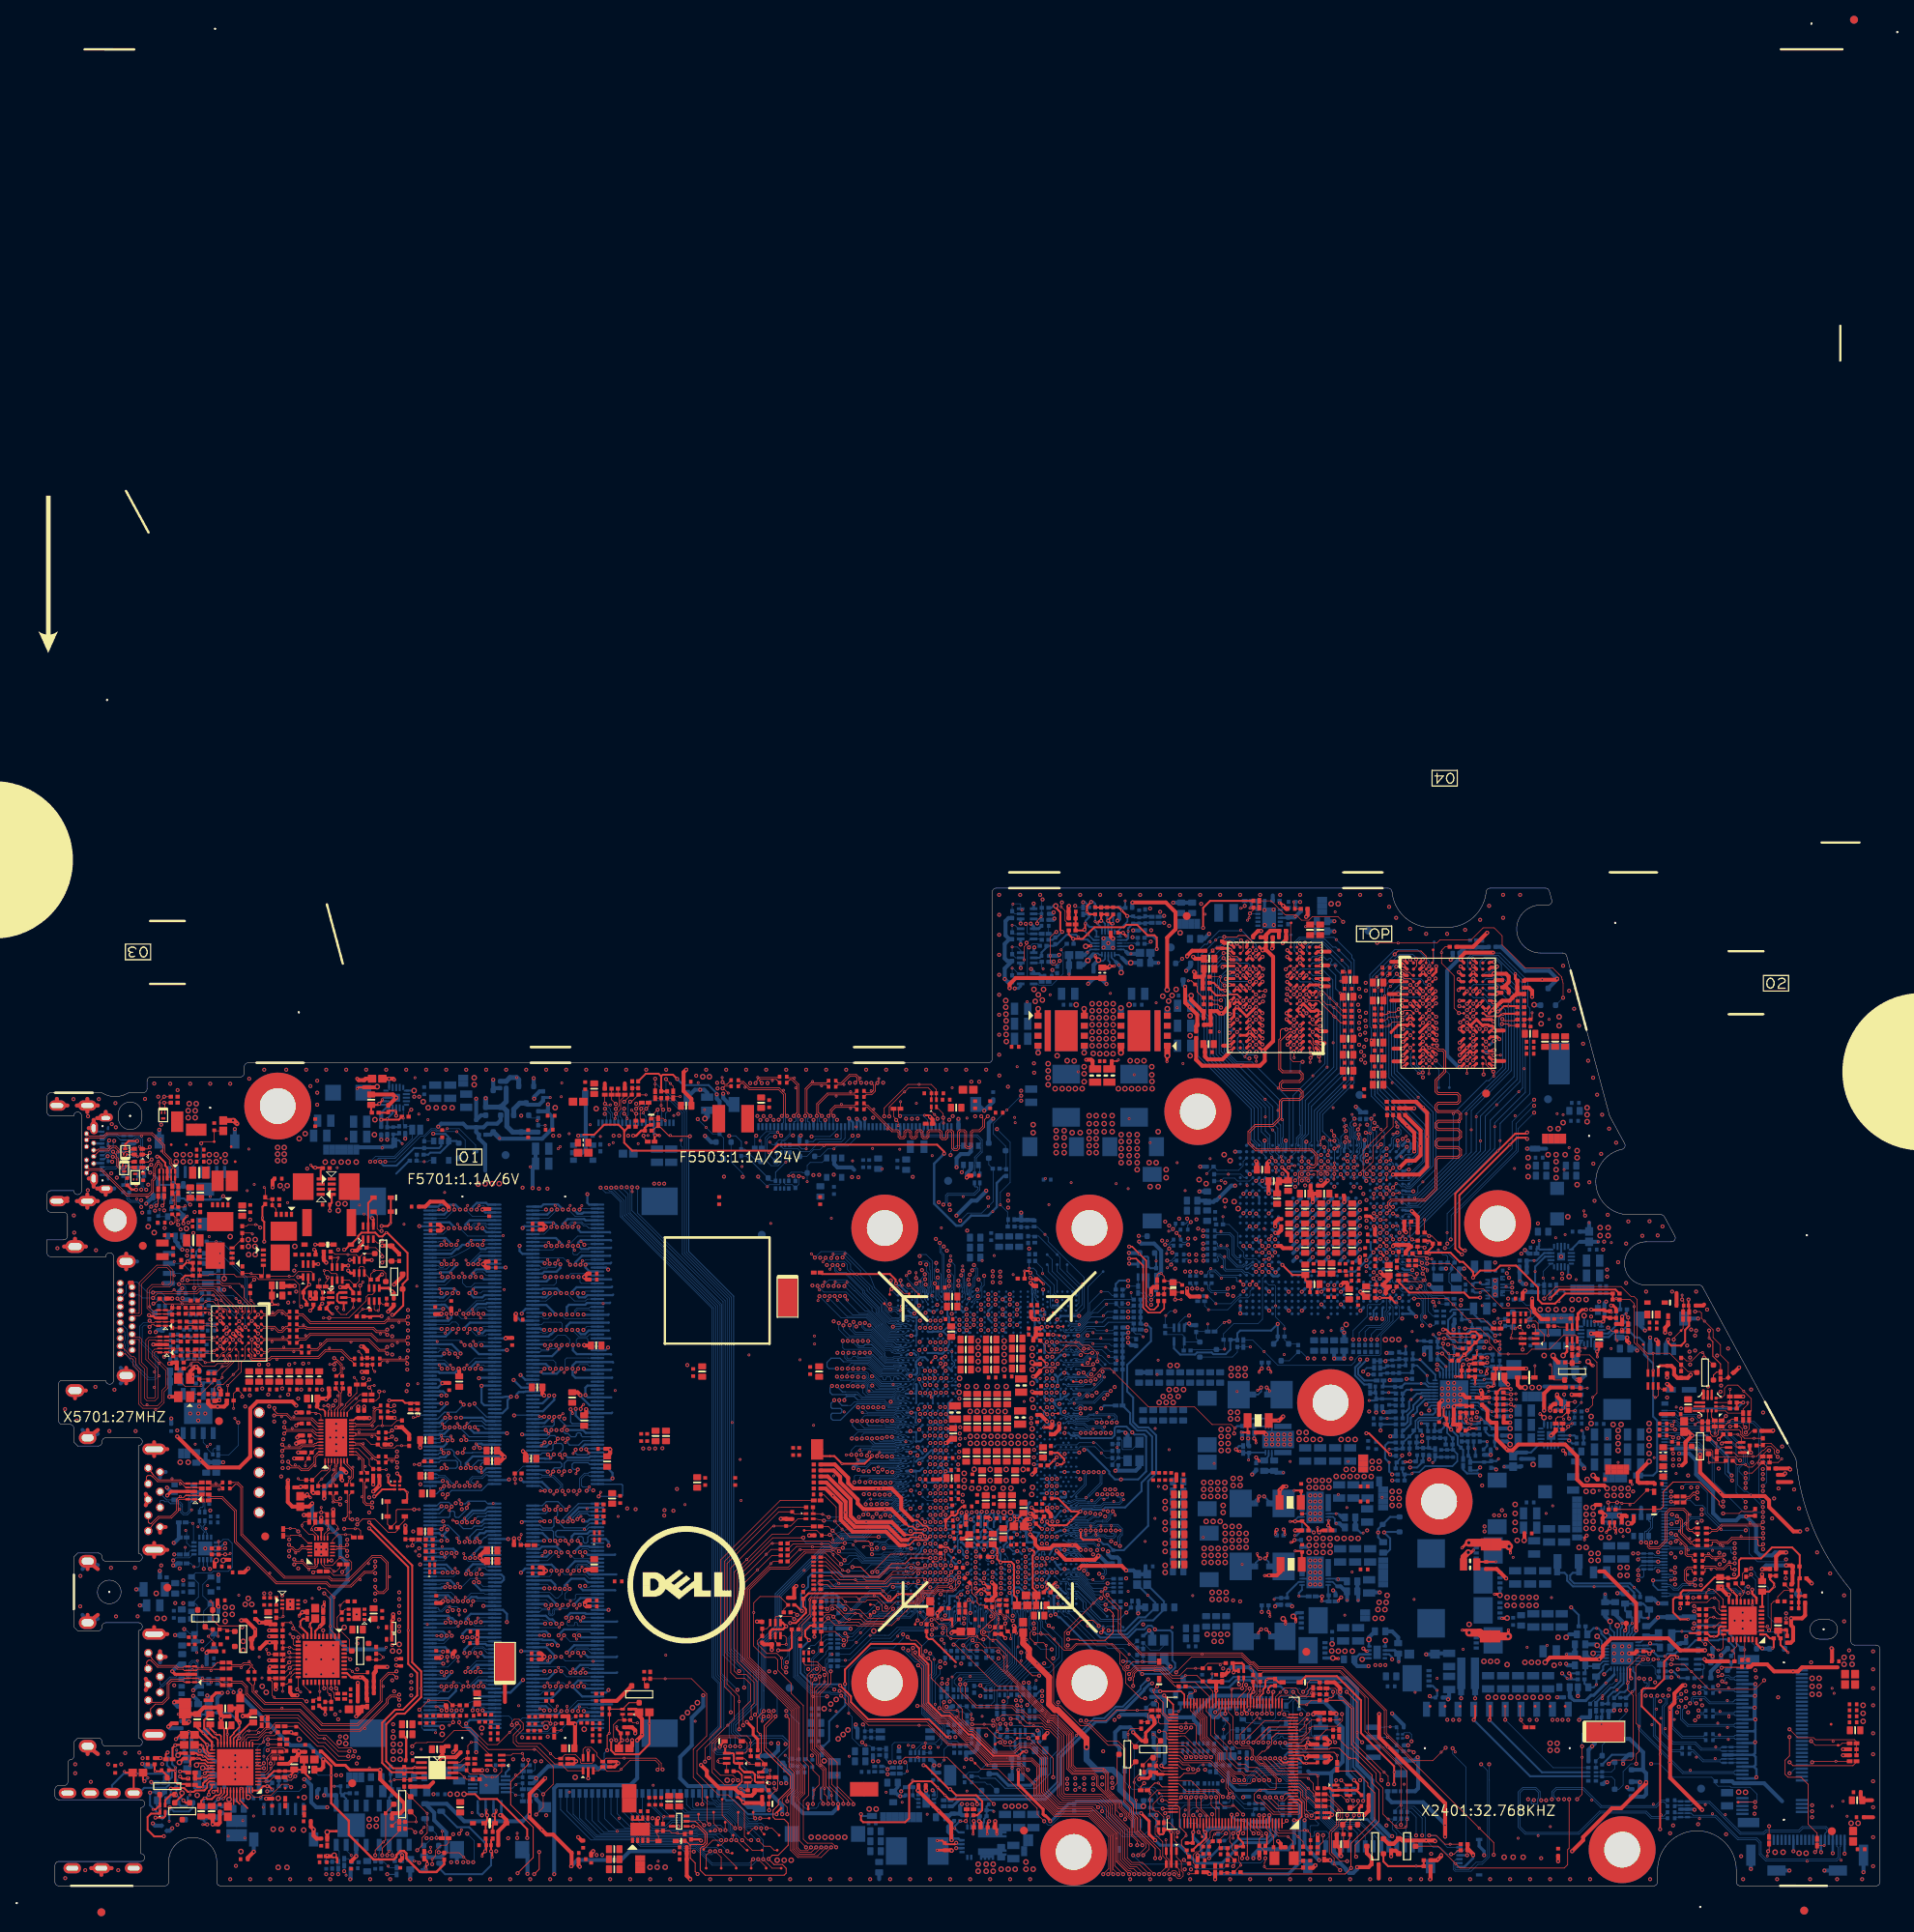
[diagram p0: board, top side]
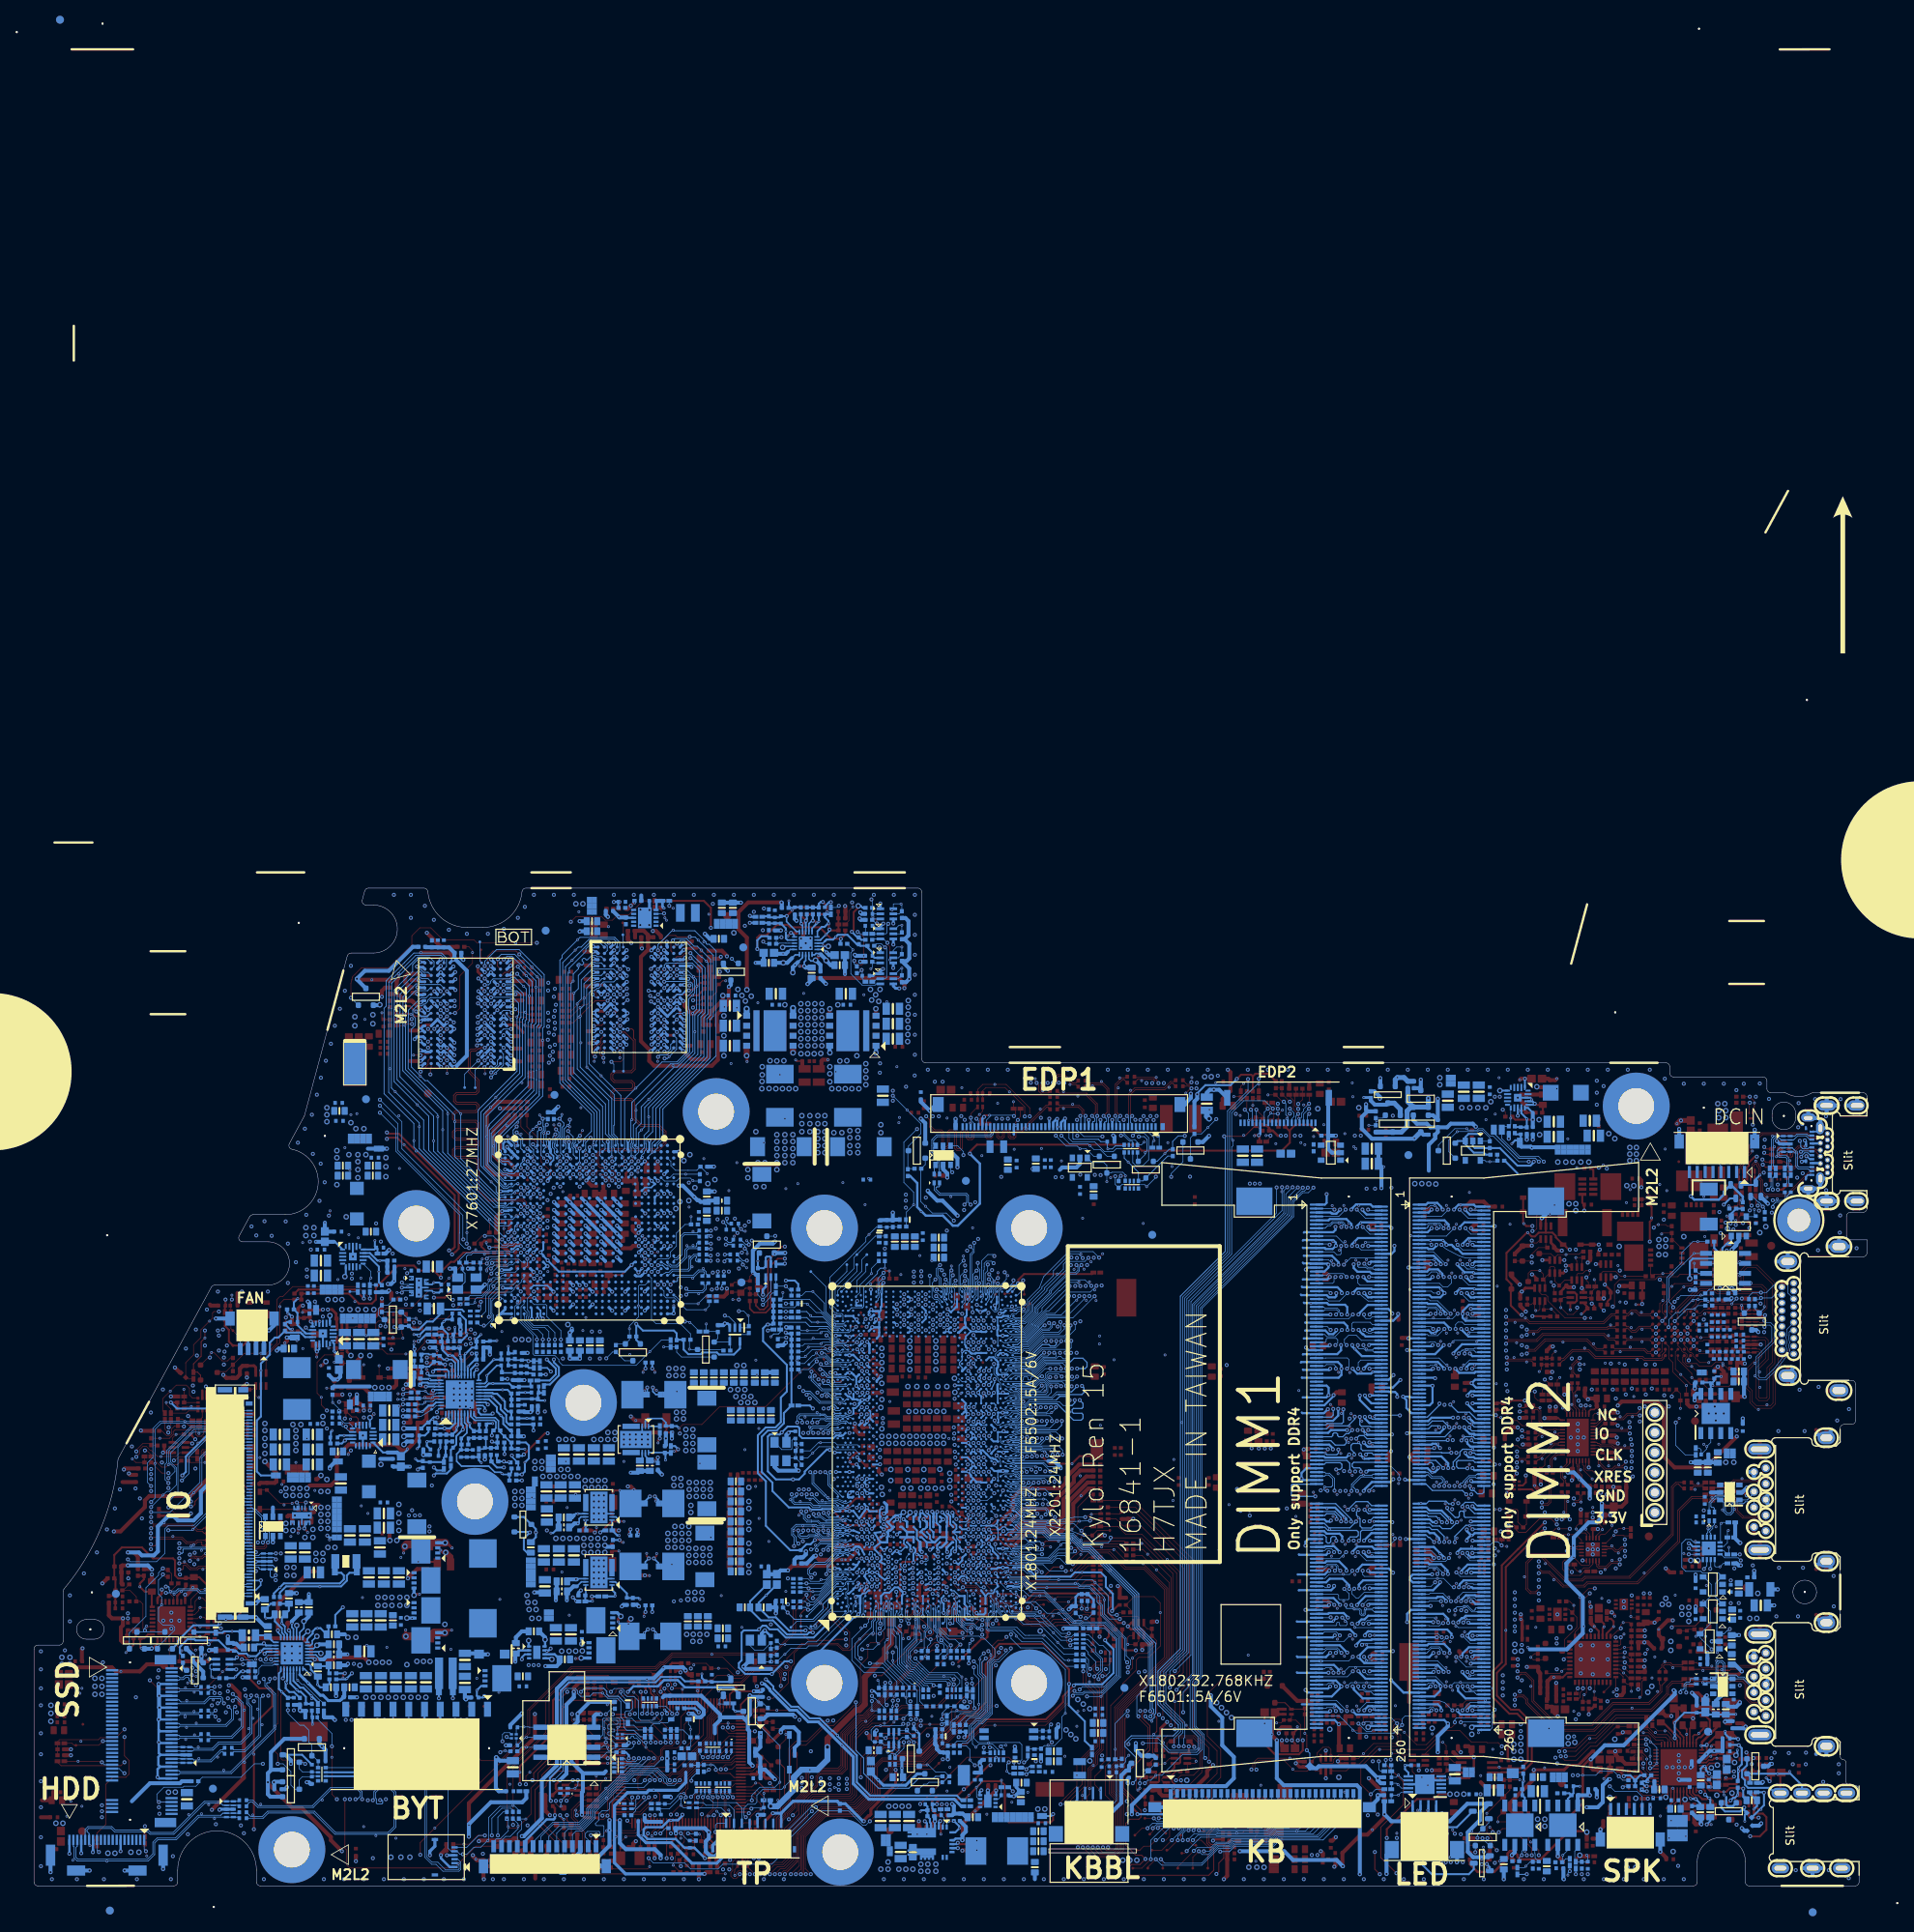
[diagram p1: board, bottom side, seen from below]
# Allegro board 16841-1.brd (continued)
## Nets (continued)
3D3V_LDO_SET: R5541.2 R5542.1 U5502.4
3D3V_MUX: C3815.1 C3816.1 C3817.1 C3818.1 C3819.1 L3801.2 R3801.1 R3818.1 R3821.1 R3840.1 R3842.1 R3845.1 R3847.1 R3852.1 R3871.1 R3874.1 U3801.1 U3801.6 U3801.20 U3801.28
3D3V_MUX2: C3865.1 R3812.2 U3802.13
3D3V_RTC_SYS: D2501.1 R2505.2 R2517.1
3D3V_S0: C1228.1 C1328.1 C1329.1 C2601.1 C2602.1 C4004.1 C5726.2 C5827.1 C8305.1 C8307.1 DB1.10 DM1.255 DM2.255 EC8909.1 EC8910.1 EC8911.1 EC8975.1 EC8976.1 EC8977.1 EC8978.1 EC8979.1 EC8980.1 EC8981.1 EC8982.1 EC8983.1 F5502.1 IOBD1.42 IOBD1.43 L5801.1 PG8301.2 PG8302.2 PG8303.2 PR4609.1 PR8325.2 Q1801.2 Q1801.5 Q2414.G Q2601.2 Q2601.5 R506.1 R802.2 R1204.2 R1208.2 R1211.2 R1216.1 R1302.2 R1306.2 R1310.2 R1503.1 R1606.1 R1608.1 R1910.1 R2010.1 R2029.1 R2038.1 R2042.1 R2043.1 R2044.1 R2045.1 R2046.1 R2047.1 R2048.1 R2049.1 R2052.1 R2053.1 R2429.2 R2430.2 R2489.2 R2603.1 R2604.1 R2609.1 R2749.2 R2751.2 R4003.1 R4005.1 R5504.2 R5517.1 R5518.1 R5526.1 R5528.1 R5736.1 R5737.1 R5738.1 R5739.1 R5740.2 R5742.2 R5756.1 R6302.1 R6307.1 R6502.1 R6602.2 R7004.1 R7018.1 R7648.2 R8307.1 R9102.1 R9120.2 R9141.2 R9145.1 RN801.1(A) RN801.2(A) RN803.1(A) RN803.2(A) RN1810.1(A) RN1810.2(A) RN1812.1(A) RN1812.2(A) RN1812.3(A) RN1813.1(A) RN1813.2(A) RN1813.3(A) RN2007.3(B) RN2007.4(B) RN2008.3(B) RN2008.4(B) RN2602.1(A) RN2602.2(A) RN2701.3(B) RN2701.4(B) THM261.1 U4001.13 U4001.14 U5702.8 U8301.1 U8301.2 U8301.6 U8301.7
3D3V_S5: C2416.1 C2421.1 C5502.1 C6502.1 D3701.A EC1302.1 EC8912.1 EC8939.1 EC8940.1 EC8993.1 EC8994.1 EC8995.1 EC8996.1 EC8997.1 EC8998.1 EC8999.1 IOBD1.46 IOBD1.47 L3801.1 PC5110.1 PC5403.1 PC5414.1 PD4302.2 PG4519.2 PG4520.2 PG4521.2 PG4522.2 PG4523.2 PG4524.2 PR4304.1 PR4335.1 PR4435.1 PR4450.2 PR4472.1 PR5104.1 PR5208.1 PR5402.1 PR5410.1 PU4307.6 PU5101.15 PU5401.5 PU5401.9 PU5403.5 PU5403.9 Q2416.2 Q2416.5 Q6502.S R1711.1 R1912.1 R2001.1 R2050.2 R2407.2 R2434.1 R2442.1 R2446.1 R2607.1 R3738.1 R3812.1 R4031.1 R4101.1 R6601.1 R6604.2 R9101.1 R9143.1 R9146.1 RN1704.1(A) RN1704.2(A) RN1704.3(A) RN1704.4(A) RN2405.3(B) RN2405.4(B) RN2406.3(B) RN2406.4(B) U4001.1 U4001.2 U4007.5 U4302.2 U5501.4 U5501.5
3D3V_S5_KBC: C2410.1 C2411.1 C2412.1 C2413.1 C2414.1 C2420.1 C2422.1 C2429.1 D4304.2 D4305.2 D4306.2 DBEC1.1 KBC24.5 KBC24.19 KBC24.22 KBC24.43 KBC24.65 KBC24.82 KBC24.103 KBC24.115 Q2417.2 Q2417.5 R2414.2 R2415.2 R2424.2 R2443.1 R2446.2 R2450.2 R2458.1 R2473.2 R2480.2 R2484.1 R2608.1 R3707.1 R4032.1 RN2402.1(A) RN2402.2(A) RN2403.1(A) RN2403.2(A) RN2403.3(A) RN2403.4(A) RN2404.1(A) RN2404.2(A) RN2404.3(A) RN2404.4(A) RN2407.1(A) RN2407.2(A) RN2409.1(A) RN2409.2(A) RN2409.3(A) RN2409.4(A) RN2410.1(A) RN2410.2(A) RN2410.3(A) RN2411.1(A) RN2411.2(A) RN2412.1(A) RN2412.2(A) RN2412.3(A) RN2412.4(A) RN2413.1(A) RN2413.2(A)
3D3V_S5_PCH: R404.1 R1103.1 R1822.1 R1824.1 R1836.1 R1837.1 R2007.1 R2040.1 R2041.1 R2501.2 R2515.1 R4101.2 R9103.1 RN1601.1(A) RN1601.2(A) RN1601.3(A) RN1601.4(A) RN1802.1(A) RN1802.2(A) RN1807.1(A) RN1807.2(A) RN1807.3(A) RN1807.4(A) RN1811.1(A) RN1811.2(A)
3D3V_SEN_S0: C5515.1 EC5505.1 R5528.2 TCBD1.1
3D3V_SPIVCC1: C2501.1 C2502.1 R2515.2 SKT251.8 SPI25.8
3D3V_SSD: AFTP6304.1 C6304.1 C6305.1 C6306.1 C6307.1 C6308.1 C6317.1 C6318.1 R6302.2 R6303.1 R6305.1 R6307.2 SSD1.2 SSD1.4 SSD1.12 SSD1.14 SSD1.16 SSD1.18 SSD1.70 SSD1.72 SSD1.74
3D3V_TPM: C9101.1 C9102.1 C9104.1 C9105.1 Q9102.S R9101.2 R9102.2 R9103.2 R9119.1 R9138.1 R9140.1 R9147.1 R9149.1
3D3V_TPM_1: C9106.1 C9113.1 R9143.2 R9144.1
3D3V_VGA_CT_1: C8302.1 U8301.12
3D3V_VGA_S0: C7703.1 C7728.1 C7729.1 C7734.1 C8304.1 GPU1.G8 GPU1.G9 PR8256.1 PR8310.1 PR8318.1 PR8329.1 R7618.1 R7620.1 R7635.1 R8301.2 U8301.13 U8301.14
3D3V_VGA_S0_DISCHG: PQ8307.3 PR8318.2
27MHZ_IN: C7607.2 GPU1.C11 R7603.1 X7601.1
27MHZ_OUT: GPU1.B10 R7603.2 R7604.2
27MHZ_OUT_R: C7608.2 R7604.1 X7601.3
+DC_IN: EC8913.1 EL4301.2 EL4302.2 PC4301.1 PC4302.1 PQ4305.2 PR4307.1 PR4312.1 PU4301.1 PU4301.2 PU4301.3
+DC_IN_C: AFTP4303.1 AFTP4305.1 AFTP4316.1 DCIN1.6 DCIN1.7 DCIN1.8 EC4301.1 EC4302.1 EC4312.1 EC4313.1 EL4301.1 EL4302.1 PD4301.K
+RTC_VCC: D2501.2 IOBD1.48 Q2505.G R2504.1
+SDC_IN: EC8960.1 EC8961.1 EC8962.1 EC8963.1 EC8964.1 EC8965.1 EC8966.1 EC8967.1 PC4401.1 PG4401.1 PR4318.1 PR4320.1 PR4401.1 PU4302.1 PU4302.2 PU4302.3 PU4304.1 PU4304.2 PU4304.3 PU4401.16
+SDC_IN_SW: PR4318.2 PR4333.2 PU4302.4
+SDC_IN_SW_R1: PQ4310.3 PR4333.1
+UZ12_TPM: C9114.1 R9145.2 R9146.2 U9101.8
+V_VREF_PATH1: C1222.2 R1209.1
+V_VREF_PATH2: C1323.2 R1309.1
A5_TP: CPU1.A5 TP2309.1
A67_TP: CPU1.A67 TP2311.1
A70_TP: CPU1.A70 TP2310.1
AC_DIS: KBC24.69 PD4309.A R4306.1
AC_DIS_R: PD4309.K PD4310.K PQ4304.B R4303.1 R4306.2
AC_IN#_G: PR4312.2 PR4313.1 R2499.1 R4305.1 U4302.5
AC_PRESENT: CPU1.AY15 D1701.A EC1707.1 Q1702.3 RN1704.8(B)
ACOK#: PQ4415.2 PQ4415.3 PR4427.2
ACOK_IN_M: D1701.K PD4305.K PD4306.K PQ4415.6
AD+: PC4303.1 PC4304.1 PC4305.1 PC4306.1 PD4401.1 PD4408.1 PR4311.1 PR4316.1 PR4473.1 PU4301.5 PU4301.6 PU4301.7 PU4301.8 PU4302.5 PU4302.6 PU4302.7 PU4302.8
AD_IA: PC4432.1 PR4412.2 R2421.1 R2481.1 R2483.1
AD_OFF_L: PQ4304.C PQ4305.1
AD_OFF_R: PC4301.2 PQ4305.3 PR4307.2 PR4308.1 PU4301.4
ALERT#: R2603.2 THM261.6
ALWON: KBC24.121 R4009.2
AMBER_LED_BAT: EC6401.1 Q6402.C R6401.2
AUD_AGND: C2727.2 C2730.2 C2731.1 C2734.1 C2735.2 C2737.1 C2740.2 C2741.2 C2749.2 EC2709.1 EC2710.1 EC2711.1 EC2712.1 EC2713.1 EC2714.1 EC2905.2 EC2906.2 EC2907.2 EC2908.2 EC8901.1 EC8902.1 EC8903.1 EC8904.1 HDA27.22 HDA27.37 HPMIC1.MS R2739.1 R2747.1 R2905.2
AUD_HP1_JACK_L: HDA27.27 R2907.2
AUD_HP1_JACK_L1: EC2907.1 R2907.1 R2908.1 R2922.2
AUD_HP1_JACK_R: HDA27.26 R2909.2
AUD_HP1_JACK_R1: EC2908.1 R2909.1 R2910.1 R2921.2
AUD_PC_BEEP: HDA27.34 R2729.2
AUD_PC_BEEP_C: C2726.1 D2702.3 R2745.1
AUD_PC_BEEP_R: C2726.2 R2729.1
AUD_PORTA_L_R_B: ED2903.1 HPMIC1.1 R2908.2
AUD_PORTA_R_R_B: ED2901.2 HPMIC1.2 R2910.2
AUD_SENSE: R2741.2 R2923.2
AUD_SENSE_A: C2746.1 HDA27.48 R2741.1 R2742.2
AUD_SPK_L+: EC2904.1 HDA27.42 R2912.2
AUD_SPK_L+_C: AFTP2902.1 R2912.1 SPK1.1
AUD_SPK_L-: EC2903.1 HDA27.43 R2913.2
AUD_SPK_L-_C: AFTP2901.1 R2913.1 SPK1.2
AUD_SPK_R+: EC2902.1 HDA27.45 R2914.2
AUD_SPK_R+_C: AFTP2904.1 R2914.1 SPK1.4
AUD_SPK_R-: EC2901.1 HDA27.44 R2915.2
AUD_SPK_R-_C: AFTP2903.1 R2915.1 SPK1.3
AUD_VREF: C2737.2 HDA27.38
AUDIO_47: HDA27.47 R2744.1
AUX_EN_WOWL: CPU1.BB17 IOBD1.50 R2409.1
AUX_EN_WOWL_EC: KBC24.41 R2409.2
AUX_MODE: HDA27.33 R2753.2 R2754.2
AUX_ON: IOBD1.49 KBC24.3
B71_TP: CPU1.B71 TP2312.1
BA1_TP: CPU1.BA1 TP2305.1
BA2_TP: CPU1.BA2 TP2306.1
BA71_TP: CPU1.BA71 TP2303.1
BAT1_LED#: KBC24.106 Q2416.4 RN2405.1(A)
BAT2_LED#: KBC24.1 Q2416.1 RN2405.2(A)
BAT_AMBER: ED6401.1 LEDCN1.2 R6401.1
BAT_WHITE: ED6402.1 LEDCN1.3 R6402.1
BATT_WHITE_LED#: Q2416.6 R6404.1
BATT_WHITE_LED_R#: Q6105.D Q6401.B R6404.2
BB67_TP: CPU1.BB67 TP2302.1
BB70_TP: CPU1.BB70 TP2301.1
BEEP: KBC24.45 RN2702.1(A)
BKLT_CTRL: D5502.3 R5502.1 RN5501.5(B) RN5502.5(B)
BKLT_IN_EC: KBC24.67 R2435.1
BLON_OUT_C: LCD1.23 RN5501.2(A) RN5502.6(B)
BLUETOOTH_EN: CPU1.AB2 IOBD1.56 R2042.2
BOARD_ID: C2408.2 KBC24.111 R2443.2 R2444.1 R2494.2
BOARD_ID1: CPU1.AC1 R2009.1 R2010.2
BOARD_ID2: CPU1.AB3 R2051.1 R2052.2
BOT_MUX_N: ED3805.1 EL3802.2 R3864.2 USB1.B7
BOT_MUX_N_L: EL3802.1 R3864.1 U3802.9
BOT_MUX_P: ED3805.2 EL3802.3 R3863.2 USB1.B6
BOT_MUX_P_L: EL3802.4 R3863.1 U3802.8
BREATH_LED#: IOBD1.51 KBC24.70
BT+: AFTP4312.1 AFTP4313.1 AFTP4314.1 BATT1.1 BATT1.2 BATT1.3 EC4307.1 EC4308.1 PD4304.K PR4478.2 PU4412.5 PU4412.6 PU4412.7 PU4412.8
C1_TP: CPU1.C1 TP2308.1
CAD_SNK: R3818.2 U3801.29
CAP_LED: AFTP6541.1 KB1.4 R6513.2
CAP_LED#: KBC24.93 Q2414.S R2489.1
CAP_LED#_R: Q2414.D R6512.1
CAP_LED_Q: EC6507.1 Q6505.C R6513.1
CAP_LED_R#: Q6505.B R6512.2
CBN: C2739.1 HDA27.24
CBP: C2739.2 HDA27.23
CCG4_FLIP#: R3855.1 R3856.1 U3701.5
CCG4_GPIO21: TP3701.1 U3701.21
CCG4_I2C_INT#: KBC24.32 R3731.1
CCG4_I2C_SCL: Q2417.6 RN3702.3(B) U3701.17
CCG4_I2C_SDA: Q2417.3 RN3702.4(B) U3701.16
CCG4_ID_1: R3708.2 R3709.1 U3701.25
CCG4_ID_2: R3741.1 R3742.2 U3701.27
CCG4_OVP_TRIP_P1: PQ4311.2 PR4341.2 U3701.14
CCG4_OVP_TRIP_P1_G: PC4313.2 PQ4309.2 PR4340.1 PR4341.1
CFG3: CPU1.D67 R604.1
CFG4: CPU1.E70 R605.1
CFG_RCOMP: CPU1.E60 R601.1
CHG_AMBER_LED#: Q2416.3 R6403.1
CHG_AMBER_LED_R#: Q6402.B R6403.2
CLK_PCIE_LAN_REQ#: CPU1.AT8 IOBD1.59 RN1813.6(B)
CLK_PCIE_NVME_REQ#: CPU1.AU8 RN1812.6(B) SSD1.52
CLK_PCIE_PEG_REQ#: CPU1.AR10 Q7301.D R7305.1 RN1812.7(B)
CLK_PCIE_SD_REQ#: CPU1.AT10 RN1812.8(B)
CLK_PCIE_TBT_REQ#: CPU1.AU7 RN1813.8(B)
CLK_PCIE_VGA: CPU1.C42 GPU1.AE8
CLK_PCIE_VGA#: CPU1.D42 GPU1.AD8
CLK_PCIE_WLAN_REQ#: CPU1.AT7 IOBD1.53 RN1813.7(B)
CLK_TP_SIO: EC6501.1 KBC24.78 RN6501.3(B) RN6502.2(A)
CLKRUN#: CPU1.AW11 R1818.1 R2439.1
CLKRUN#_EC: KBC24.63 R2439.2
CMP_VIN0: KBC24.20 R2470.2
CMP_VIN0_R: C2612.1 C2613.1 R2470.1 R2494.1 R2608.2 R2609.2 R2610.1
CMP_VIN1: C2430.1 KBC24.21 R2481.2 R2482.1
CMP_VOUT0: KBC24.85 R2602.2 R2607.2 R2615.2
CODEC_BITCLK_R: HDA27.14 R2752.2
CODEC_SDOUT_R: HDA27.17 R2740.2
CPU_DP1_CTRL_CLK: CPU1.L13 RN801.3(B)
CPU_DP1_CTRL_DATA: CPU1.L12 RN801.4(B)
CPU_DP1_HPD: CPU1.L9 R5760.1
CPU_DP1_HPD_R: R5760.2 U5701.B1
CPU_DP2_CTRL_CLK: CPU1.N7 RN803.4(B)
CPU_DP2_CTRL_DATA: CPU1.N8 RN803.3(B)
CPU_DP2_HPD: CPU1.L7 R803.2 R804.1
CPU_DP_HPD_MUX: R3729.1 U3701.18
CPU_DP_HPD_R: R804.2 R3725.2 R3729.2 R3849.1
CPU_POPIRCOMP: CPU1.AT16 R412.1
CPU_RXN_C_DGPU_TXN0: C7302.1 CPU1.H13
CPU_RXN_C_DGPU_TXN1: C7304.1 CPU1.G11
CPU_RXN_C_DGPU_TXN2: C7306.1 CPU1.H16
CPU_RXN_C_DGPU_TXN3: C7308.1 CPU1.G15
CPU_RXP_C_DGPU_TXP0: C7301.1 CPU1.G13
CPU_RXP_C_DGPU_TXP1: C7303.1 CPU1.F11
CPU_RXP_C_DGPU_TXP2: C7305.1 CPU1.G16
CPU_RXP_C_DGPU_TXP3: C7307.1 CPU1.F15
CPVDD: C2730.1 C2740.1 HDA27.20 R2724.2
CPVEE: C2741.1 HDA27.25
CSI2_COMP: CPU1.E13 R1501.1
CTL1: R3401.2 U3401.6
CTL2: R3406.2 U3401.7
CTL3: R3402.2 U3401.8
DAT_TP_SIO: EC6502.1 KBC24.79 RN6501.4(B) RN6502.1(A)
DBC_EN_R: LCD1.6 R5503.1
DBC_PANEL_EN: CPU1.AM5 R2043.2 R5503.2
DC_IN_OK: PD4305.A PD4307.A PQ4306.G PQ4310.5 PR4311.2 PR4315.2 PR4335.2 PU4307.2 R2475.1 U4302.1
DC_IN_OK#: PD4310.A PU4307.4
DC_IN_OK_R: PD4307.K PD4308.K PQ4308.2 R4304.1 R4305.2
DCBATOUT: C5514.1 EC8905.1 EC8906.1 EC8907.1 EC8908.1 EC8927.1 EC8928.1 EC8929.1 EC8951.1 EC8952.1 EC8953.1 EC8954.1 EC8955.1 EC8956.1 EC8957.1 EC8958.1 EC8959.1 F5503.2 PC4406.1 PC4407.1 PC4408.1 PC4409.1 PC4410.1 PC4411.1 PC4412.1 PC4413.1 PC4414.1 PC4439.2 PC4441.1 PC4442.1 PC4443.1 PC8208.1 PC8209.1 PC8210.1 PC8212.1 PC8213.1 PC8214.1 PC8215.1 PC8220.1 PC8221.1 PC8224.1 PD4407.A PG4405.1 PG4501.1 PG4502.1 PG4503.1 PG4504.1 PG4505.1 PG4506.1 PG4515.1 PG4516.1 PG4517.1 PG4518.1 PG4701.1 PG4702.1 PG4703.1 PG4704.1 PG4705.1 PG4706.1 PG4802.2 PG4803.2 PG4804.2 PG4805.2 PG4806.2 PG4810.2 PG4811.2 PG4812.2 PG4814.2 PG4816.2 PG5002.2 PG5003.2 PG5105.1 PG5110.1 PG5210.1 PG5212.1 PG5214.1 PG8314.1 PG8315.1 PG8316.1 PG8317.1 PR4407.1 PR4477.1 PR4509.1 PR4511.1 PR4612.1 PR8202.1 PT4402.1 PT4805.1 PU4401.3 PU4405.5 PU4405.6 PU4405.7 PU4405.8 PU8202.2 PU8202.3 PU8202.4 PU8202.10 PU8204.2 PU8204.3 PU8204.4 PU8204.10 PU8206.2 PU8206.3 PU8206.4 PU8206.10 PU8208.2 PU8208.3 PU8208.4 PU8208.10 R5520.2
DCBATOUT_CAMERA: C5534.1 C5542.2 LCD1.49 LCD1.50 R5520.1
DCBATOUT_LCD: C5512.1 C5513.1 F5503.1 LCD1.1 LCD1.2 LCD1.3 LCD1.4
DDC_CLK_HDMI: HDMI2.15 R5755.2 U5701.E1
DDC_CLK_PH1: D5701.2 R5755.1
DDC_DATA_HDMI: HDMI2.16 R5751.2 U5701.F1
DDC_DATA_PH2: D5701.1 R5751.1
DDR4_DRAMRST#: DM1.108 DM2.108 ED1217.1 ED1302.1 R504.2
DDR_VREF_S3: PC5123.1 PU5102.6
DGPU_HOLD_RST#: CPU1.P3 EC2002.1 R7304.1 RN2009.4(B) U7301.1
DGPU_PWR_EN: PQ8306.2 PR8260.1 PR8331.1 Q8301.D R8307.2 R8308.1
DGPU_PWR_EN#: CPU1.U1 Q8301.G R8308.2 RN2009.3(B)
DGPU_PWR_EN_L: PQ8306.5 PQ8306.6 PR8317.1
DGPU_PWR_EN_R: C8310.1 PR8331.2 R8306.1 U8301.5
DGPU_PWROK: CPU1.C8 PR8203.2 PU8201.13 R2471.1 R8305.1
DGPU_RXN_C_CPU_TXN0: C1606.1 GPU1.AG7
DGPU_RXN_C_CPU_TXN1: C1608.1 GPU1.AE7
DGPU_RXN_C_CPU_TXN2: C1610.1 GPU1.AF9
DGPU_RXN_C_CPU_TXN3: C1612.1 GPU1.AG10
DGPU_RXP_C_CPU_TXP0: C1605.1 GPU1.AG6
DGPU_RXP_C_CPU_TXP1: C1607.1 GPU1.AF7
DGPU_RXP_C_CPU_TXP2: C1609.1 GPU1.AE9
DGPU_RXP_C_CPU_TXP3: C1611.1 GPU1.AG9
DGPU_TXN_CPU_RXN0: C7302.2 GPU1.AB9
DGPU_TXN_CPU_RXN1: C7304.2 GPU1.AC10
DGPU_TXN_CPU_RXN2: C7306.2 GPU1.AC11
DGPU_TXN_CPU_RXN3: C7308.2 GPU1.AB12
DGPU_TXP_CPU_RXP0: C7301.2 GPU1.AC9
DGPU_TXP_CPU_RXP1: C7303.2 GPU1.AB10
DGPU_TXP_CPU_RXP2: C7305.2 GPU1.AD11
DGPU_TXP_CPU_RXP3: C7307.2 GPU1.AC12
DGPUHOT#: GPU1.D7 PQ4402.D R2477.1 R7605.2
DMIC_CLK: C2738.2 EC5504.1 R2721.1 RN5503.4(B)
DMIC_CLK_C: LCD1.46 RN5503.1(A)
DMIC_CLK_R: HDA27.5 R2721.2
DMIC_DATA: EC5503.1 R2738.1 RN5503.3(B)
DMIC_DATA_C: LCD1.47 RN5503.2(A)
DMIC_DATA_R: HDA27.4 R2738.2
DOCK_USB_EN_A: R3859.2 U3701.26
DOCK_USB_EN_B: R3860.2 U3701.36
DP_DATA0_N: C5731.1 CPU1.E55
DP_DATA0_N_R: C5731.2 U5701.A7
DP_DATA0_P: C5737.1 CPU1.F55
DP_DATA0_P_R: C5737.2 U5701.A8
DP_DATA1_N: C5734.1 CPU1.E58
DP_DATA1_N_R: C5734.2 U5701.A5
DP_DATA1_P: C5732.1 CPU1.F58
DP_DATA1_P_R: C5732.2 U5701.A6
DP_DATA2_N: C5727.1 CPU1.F53
DP_DATA2_N_R: C5727.2 U5701.A3
DP_DATA2_P: C5728.1 CPU1.G53
DP_DATA2_P_R: C5728.2 U5701.A4
DP_DATA3_N: C5733.1 CPU1.F56
DP_DATA3_N_R: C5733.2 U5701.A1
DP_DATA3_P: C5735.1 CPU1.G56
DP_DATA3_P_R: C5735.2 U5701.A2
DPB_AUXN: C3802.1 CPU1.E48
DPB_AUXN_C: C3802.2 R3801.2 U3801.25
DPB_AUXP: C3801.1 CPU1.F48
DPB_AUXP_C: C3801.2 R3802.2 U3801.24
DPEQ0_A1: R3871.2 R3872.1 U3801.14
DPEQ1: R3847.2 R3870.1 U3801.2
E71_TP: CPU1.E71 TP2313.1
EAPD#: HDA27.2 R2737.2
EC_AGND: C2407.1 C2408.1 C2422.2 C2430.2 C2431.2 C2435.2 KBC24.112 R2441.2 R2444.2 R2445.2 R2482.2
EC_SLP_S0IX#: KBC24.88 R2478.2
EC_VCIN1#: KBC24.126 R2496.1
ECVBAT: C2428.1 KBC24.122 R2451.2 R2472.1 R2496.2
EDP_AUX: C5510.1 LCD1.7
EDP_AUX#: C5511.1 LCD1.8
EDP_AUX_DN: C5511.2 CPU1.E45
EDP_AUX_DP: C5510.2 CPU1.F45
EDP_COMP: CPU1.E52 R801.2
EDP_DISP_UTIL: CPU1.B52 TP801.1
EDP_HPD: CPU1.L10 R5506.2 RN5502.7(B)
EDP_HPD_CONN: LCD1.21 R5506.1
EDP_TX0: C5509.1 LCD1.20
EDP_TX0#: C5506.1 LCD1.19
EDP_TX0_DN: C5506.2 CPU1.C47
EDP_TX0_DP: C5509.2 CPU1.C46
EDP_TX1: C5504.1 LCD1.17
EDP_TX1#: C5501.1 LCD1.16
EDP_TX1_DN: C5501.2 CPU1.D46
EDP_TX1_DP: C5504.2 CPU1.C45
EDP_TX2: C5519.1 LCD1.14
EDP_TX2#: C5533.1 LCD1.13
EDP_TX2_DN: C5533.2 CPU1.A45
EDP_TX2_DP: C5519.2 CPU1.B45
EDP_TX3: C5531.1 LCD1.11
EDP_TX3#: C5532.1 LCD1.10
EDP_TX3_DN: C5532.2 CPU1.A47
EDP_TX3_DP: C5531.2 CPU1.B47
EDP_VDD_EN: CPU1.U13 D5501.1
EDRAM_OPIO_RCOMP: CPU1.H66 R414.1
EMMC_RCOMP: CPU1.AT1 R1502.1
EOPIO_RCOMP: CPU1.H65 R415.1
EQ0: R3842.2 R3843.1 U3801.38
EQ1: R3840.2 R3841.1 U3801.35
ESPI_ALERT#: CPU1.AY11 KBC24.55 R2464.1
ESPI_CLK: DB1.2 EC1801.1 KBC24.57 R1805.2
ESPI_CS#: CPU1.BA12 DB1.5 KBC24.58
ESPI_IO0: DB1.9 KBC24.59 R1827.1
ESPI_IO1: DB1.8 KBC24.60 R1828.1
ESPI_IO2: DB1.7 KBC24.61 R1829.1
ESPI_IO3: DB1.6 KBC24.62 R1830.1
ESPI_RESET#: CPU1.BA11 DB1.4 KBC24.53
EXT_PWR_GATE#: CPU1.AM10 R1731.2
FALL_INT2: Q7001.2 Q7001.3 R7018.2
FAN1_PWM: EC2601.1 KBC24.47 R2614.1
FAN1_TACH: D2403.A KBC24.40 R2430.1
FAN_PWM1_C: AFTP2602.1 FAN1.4 R2614.2
FAN_TACH1: D2403.K EC2602.1 R2613.1
FAN_TACH1_C: AFTP2601.1 FAN1.3 R2613.2
FAN_VCC_1: AFTP2603.1 C2603.1 C2604.1 C2605.1 D2601.K FAN1.1 R2612.2
FB_CAL_PD_VDDQ: GPU1.D22 R7505.1
FB_CAL_PU_GND: GPU1.C24 R7507.2
FB_CAL_TERM_GND: GPU1.B25 R7506.1
FB_CLAM: GPU1.F3 R7518.1 R7519.1
FB_VREF: GPU1.D23 TP7503.1
FBA_CLK0_MIDPT: C7801.2 R7801.2 R7802.2
FBA_CLK0N: GPU1.D25 R7802.1 VRAM1.J11 VRAM2.J11
FBA_CLK0P: GPU1.D24 R7801.1 VRAM1.J12 VRAM2.J12
FBA_CLK1_MIDPT: C7901.2 R7906.2 R7908.2
FBA_CLK1N: GPU1.M22 R7906.1 VRAM3.J11 VRAM4.J11
FBA_CLK1P: GPU1.N22 R7908.1 VRAM3.J12 VRAM4.J12
FBA_CMD0: GPU1.C27 VRAM1.G12 VRAM2.L12
FBA_CMD1: GPU1.C26 VRAM1.H10 VRAM2.K10
FBA_CMD2: GPU1.E24 VRAM1.H11 VRAM2.K11
FBA_CMD3: GPU1.F24 VRAM1.K11 VRAM2.H11
FBA_CMD4: GPU1.D27 VRAM1.K10 VRAM2.H10
FBA_CMD5: GPU1.D26 VRAM1.L12 VRAM2.G12
FBA_CMD6: GPU1.F25 VRAM1.K4 VRAM2.H4
FBA_CMD7: GPU1.F26 VRAM1.K5 VRAM2.H5
FBA_CMD8: GPU1.F23 VRAM1.J4 VRAM2.J4
FBA_CMD9: GPU1.G22 VRAM1.J5 VRAM2.J5
FBA_CMD10: GPU1.G23 VRAM1.H4 VRAM2.K4
FBA_CMD11: GPU1.G24 VRAM1.H5 VRAM2.K5
FBA_CMD12: GPU1.F27 VRAM1.G3 VRAM2.L3
FBA_CMD13: GPU1.G25 R7520.2 VRAM1.J2 VRAM2.J2
FBA_CMD14: GPU1.G27 R7516.1 VRAM1.J3 VRAM2.J3
FBA_CMD15: GPU1.G26 VRAM1.L3 VRAM2.G3
FBA_CMD16: GPU1.M24 VRAM3.G12 VRAM4.L12
FBA_CMD17: GPU1.M23 VRAM3.H10 VRAM4.K10
FBA_CMD18: GPU1.K24 VRAM3.H11 VRAM4.K11
FBA_CMD19: GPU1.K23 VRAM3.K11 VRAM4.H11
FBA_CMD20: GPU1.M27 VRAM3.K10 VRAM4.H10
FBA_CMD21: GPU1.M26 VRAM3.L12 VRAM4.G12
FBA_CMD22: GPU1.M25 VRAM3.K4 VRAM4.H4
FBA_CMD23: GPU1.K26 VRAM3.K5 VRAM4.H5
FBA_CMD24: GPU1.K22 VRAM3.J4 VRAM4.J4
FBA_CMD25: GPU1.J23 VRAM3.J5 VRAM4.J5
FBA_CMD26: GPU1.J25 VRAM3.H4 VRAM4.K4
FBA_CMD27: GPU1.J24 VRAM3.H5 VRAM4.K5
FBA_CMD28: GPU1.K27 VRAM3.G3 VRAM4.L3
FBA_CMD29: GPU1.K25 R7521.2 VRAM3.J2 VRAM4.J2
FBA_CMD30: GPU1.J27 R7524.1 VRAM3.J3 VRAM4.J3
FBA_CMD31: GPU1.J26 VRAM3.L3 VRAM4.G3
FBA_D0: GPU1.E18 VRAM1.A4
FBA_D1: GPU1.F18 VRAM1.A2
FBA_D2: GPU1.E16 VRAM1.B4
FBA_D3: GPU1.F17 VRAM1.B2
FBA_D4: GPU1.D20 VRAM1.E4
FBA_D5: GPU1.D21 VRAM1.E2
FBA_D6: GPU1.F20 VRAM1.F4
FBA_D7: GPU1.E21 VRAM1.F2
FBA_D8: GPU1.E15 VRAM2.U11
FBA_D9: GPU1.D15 VRAM2.U13
FBA_D10: GPU1.F15 VRAM2.T11
FBA_D11: GPU1.F13 VRAM2.T13
FBA_D12: GPU1.C13 VRAM2.N11
FBA_D13: GPU1.B13 VRAM2.N13
FBA_D14: GPU1.E13 VRAM2.M11
FBA_D15: GPU1.D13 VRAM2.M13
FBA_D16: GPU1.B15 VRAM1.U11
FBA_D17: GPU1.C16 VRAM1.U13
FBA_D18: GPU1.A13 VRAM1.T11
FBA_D19: GPU1.A15 VRAM1.T13
FBA_D20: GPU1.B18 VRAM1.N11
FBA_D21: GPU1.A18 VRAM1.N13
FBA_D22: GPU1.A19 VRAM1.M11
FBA_D23: GPU1.C19 VRAM1.M13
FBA_D24: GPU1.B24 VRAM2.A4
FBA_D25: GPU1.C23 VRAM2.A2
FBA_D26: GPU1.A25 VRAM2.B4
FBA_D27: GPU1.A24 VRAM2.B2
FBA_D28: GPU1.A21 VRAM2.E4
FBA_D29: GPU1.B21 VRAM2.E2
FBA_D30: GPU1.C20 VRAM2.F4
FBA_D31: GPU1.C21 VRAM2.F2
FBA_D32: GPU1.R22 VRAM3.A4
FBA_D33: GPU1.R24 VRAM3.A2
FBA_D34: GPU1.T22 VRAM3.B4
FBA_D35: GPU1.R23 VRAM3.B2
FBA_D36: GPU1.N25 VRAM3.E4
FBA_D37: GPU1.N26 VRAM3.E2
FBA_D38: GPU1.N23 VRAM3.F4
FBA_D39: GPU1.N24 VRAM3.F2
FBA_D40: GPU1.V23 VRAM4.U11
FBA_D41: GPU1.V22 VRAM4.U13
FBA_D42: GPU1.T23 VRAM4.T11
FBA_D43: GPU1.U22 VRAM4.T13
FBA_D44: GPU1.Y24 VRAM4.N11
FBA_D45: GPU1.AA24 VRAM4.N13
FBA_D46: GPU1.Y22 VRAM4.M11
FBA_D47: GPU1.AA23 VRAM4.M13
FBA_D48: GPU1.AD27 VRAM3.U11
FBA_D49: GPU1.AB25 VRAM3.U13
FBA_D50: GPU1.AD26 VRAM3.T11
FBA_D51: GPU1.AC25 VRAM3.T13
FBA_D52: GPU1.AA27 VRAM3.N11
FBA_D53: GPU1.AA26 VRAM3.N13
FBA_D54: GPU1.W26 VRAM3.M11
FBA_D55: GPU1.Y25 VRAM3.M13
FBA_D56: GPU1.R26 VRAM4.A4
FBA_D57: GPU1.T25 VRAM4.A2
FBA_D58: GPU1.N27 VRAM4.B4
FBA_D59: GPU1.R27 VRAM4.B2
FBA_D60: GPU1.V26 VRAM4.E4
FBA_D61: GPU1.V27 VRAM4.E2
FBA_D62: GPU1.W27 VRAM4.F4
FBA_D63: GPU1.W25 VRAM4.F2
FBA_DEBUG0: GPU1.F22 R7501.1
FBA_DEBUG1: GPU1.J22 R7503.1
FBA_DQM0: GPU1.D19 VRAM1.D2
FBA_DQM1: GPU1.D14 VRAM2.P13
FBA_DQM2: GPU1.C17 VRAM1.P13
FBA_DQM3: GPU1.C22 VRAM2.D2
FBA_DQM4: GPU1.P24 VRAM3.D2
FBA_DQM5: GPU1.W24 VRAM4.P13
FBA_DQM6: GPU1.AA25 VRAM3.P13
FBA_DQM7: GPU1.U25 VRAM4.D2
FBA_EDC0: GPU1.E19 VRAM1.C2
FBA_EDC1: GPU1.C15 VRAM2.R13
FBA_EDC2: GPU1.B16 VRAM1.R13
FBA_EDC3: GPU1.B22 VRAM2.C2
FBA_EDC4: GPU1.R25 VRAM3.C2
FBA_EDC5: GPU1.W23 VRAM4.R13
FBA_EDC6: GPU1.AB26 VRAM3.R13
FBA_EDC7: GPU1.T26 VRAM4.C2
FBA_MF1: R7811.2 VRAM1.J1
FBA_MF2: R7812.1 VRAM2.J1
FBA_MF3: R7911.2 VRAM3.J1
FBA_MF4: R7910.1 VRAM4.J1
FBA_PLL_AVDD: C7505.1 C7506.1 C7518.1 GPU1.F16 GPU1.H22 GPU1.P22 L7501.1
FBA_SEN0: R7810.2 VRAM1.J10 VRAM2.J10
FBA_SEN2: R7909.2 VRAM3.J10 VRAM4.J10
FBA_VREF_FET_H: Q7901.D R7902.2 R7905.2
FBA_VREF_FET_L: Q7801.D R7803.2 R7804.2
FBA_VREFC0: C7803.1 R7804.1 R7806.2 R7807.1 VRAM1.J14 VRAM2.J14
FBA_VREFC1: C7902.1 R7902.1 R7903.2 R7904.1 VRAM3.J14 VRAM4.J14
FBA_VREFD_H: C7903.1 C7908.1 R7901.1 R7905.1 R7907.2 VRAM3.A10 VRAM3.U10 VRAM4.A10 VRAM4.U10
FBA_VREFD_L: C7802.1 C7826.1 R7803.1 R7805.2 R7809.1 VRAM1.A10 VRAM1.U10 VRAM2.A10 VRAM2.U10
FBA_WCK01: GPU1.D18 VRAM1.D4 VRAM2.P4
FBA_WCK01#: GPU1.C18 VRAM1.D5 VRAM2.P5
FBA_WCK23: GPU1.D17 VRAM1.P4 VRAM2.D4
FBA_WCK23#: GPU1.D16 VRAM1.P5 VRAM2.D5
FBA_WCK45: GPU1.T24 VRAM3.D4 VRAM4.P4
FBA_WCK45#: GPU1.U24 VRAM3.D5 VRAM4.P5
FBA_WCK67: GPU1.V24 VRAM3.P4 VRAM4.D4
FBA_WCK67#: GPU1.V25 VRAM3.P5 VRAM4.D5
FBA_ZQ0: R7808.1 VRAM1.J13
FBA_ZQ1: R7813.1 VRAM2.J13
FBA_ZQ2: R7912.1 VRAM3.J13
FBA_ZQ3: R7913.1 VRAM4.J13
FFS_INT1: CPU1.M3 R7012.1
FFS_INT2: CPU1.AC2 D7001.3 R2044.2 R7008.2
FFS_INT2_Q: Q7001.6 R6001.1
FFS_INT2_Q_R: HDD1.1 R6001.2
FP1_USB20_N: CPU1.AG1 TP1603.1
FP1_USB20_P: CPU1.AG2 TP1604.1
FPR_SCAN#: KBC24.42 R2458.2
GC6_FB_EN: D8301.1 R2004.1 R7519.2 R7623.1
GC6_FB_EN_GPU: GPU1.C6 R7623.2 R7627.1
GC6_FB_EN_MCP: CPU1.AP7 R2004.2
GC6_THM_DIS#: CPU1.AB13 R2490.1
GC6_THM_DIS#_EC: KBC24.23 R2426.2 R2471.2 R2490.2
GPD11/LANPHYPC: CPU1.AW17 RN1704.5(B)
GPIO5_GC6_PWR_EN: PQ8307.2 PR8330.1 R7633.2 R7636.2
GPIO5_GC6_PWR_EN#: PQ8307.5 PQ8307.6 PR8319.1
GPIO5_GC6_PWR_EN_GPU: GPU1.A3 R7636.1
GPIO5_GC6_PWR_EN_R: C8309.1 PR8330.2 R8306.2 U8301.3
GPIO9_ALERT: GPU1.F8 RN7610.2(A)
GPIO10_FBVREF: GPU1.C5 Q7801.G Q7901.G R7610.1
GPU_CLKREQ#: GPU1.AC6 Q7301.S R7303.1 R7305.2
GPU_EVENT#: Q7606.D R2003.1 R7644.1 R7648.1
GPU_EVENT_GPU#: GPU1.A4 Q7606.S R7644.2 R7649.1
GPU_EVENT_MCP#: CPU1.AN8 R2003.2
GPU_I2CA_SCL: GPU1.B7 RN7401.1(A)
GPU_I2CA_SDA: GPU1.A7 RN7401.2(A)
GPU_NC_F11: GPU1.F11 TP7701.1
GPU_PEX_RST#: D7301.3 GPU1.AC7 R7312.1 R7313.2
GPU_PEX_RST_HOLD: D7301.1 R7630.2 R7631.2
GPU_PEX_RST_HOLD_GPU#: GPU1.C4 R7630.1
GPU_PLL_VDD: C7605.1 C7606.1 GPU1.L6 L7601.2
GPU_PWR_LEVEL: KBC24.10 R2477.2
GPU_ROM_SCLK: GPU1.C12 R7620.2 R7621.1
GPU_ROM_SI: GPU1.B12 R7624.1 R7635.2
GPU_ROM_SO: GPU1.A12 R7618.2 R7632.1
GPU_THM_SMBCLK: KBC24.12 R2459.1
GPU_THM_SMBDAT: KBC24.11 R2447.1
GSEN2_INT1: R7009.2 R7012.2 U7001.12
GSEN2_INT1_C: R2025.2 R7009.1
GSEN2_INT1_ISH: CPU1.BA7 R2025.1 R2033.2
GSEN2_INT2: R7010.2 R7013.2 U7001.11
GSEN2_INT2_C: R2026.2 R7010.1
GSEN2_INT2_ISH: CPU1.AY7 R2026.1 R2034.2
GSEN_INT1: R2023.2 TCBD1.5
GSEN_INT1_ISH: CPU1.BA8 R2023.1 R2031.2
GSEN_INT2: R2024.2 TCBD1.6
GSEN_INT2_ISH: CPU1.BB7 R2024.1 R2032.2
GSENSOR_CS: R7006.1 U7001.2
GSENSOR_SDO: R7005.2 R7007.2 U7001.3
GT_CORE: CPU1.A48 CPU1.A53 CPU1.J43 CPU1.J45 CPU1.J46 CPU1.J48 CPU1.J50 CPU1.J52 CPU1.K48 CPU1.K50 R736.2 R742.1
GTX_CORE: CPU1.AK42 CPU1.AK43 CPU1.AK45 CPU1.AK46 CPU1.AK48 CPU1.AK50 CPU1.AL43 CPU1.AL46 CPU1.AL50 CPU1.AM48 CPU1.AM50 CPU1.AM52 R743.2
GYRO_DRDY: R2028.2 TCBD1.8
GYRO_DRDY_ISH: CPU1.AP13 R2028.1 R2036.2 R2053.2
GYRO_INT: R7002.2 R7003.2 TCBD1.7
GYRO_INT_C: R2027.2 R7003.1
GYRO_INT_ISH: CPU1.AW7 R2027.1 R2035.2
GYRO_INT_P11: D7001.1 R7002.1
H_CATERR#: CPU1.D63 TP401.1
H_CPU_SVIDALRT#: CPU1.B63 R728.2
H_CPU_SVIDCLK: CPU1.A63 R732.1
H_CPU_SVIDDAT: CPU1.D64 R709.1 R726.2
H_CPUPWRGD: CPU1.A68 EC1701.1 R1714.1 TP1705.1
H_PECI: C2405.1 KBC24.94 R2437.1
H_PECI_CPU: CPU1.A54 R2437.2
H_PROCHOT#: ED2403.1 PQ4416.3 PR4476.2 PR4603.2 PR4607.1 Q2408.D R401.2 R403.1 R2418.2
H_PROCHOT#_R: CPU1.C65 R403.2
H_VCCST_PWRGD: C1711.1 CPU1.B65 EC1708.1 R1716.2 R1719.1
HDA_BITCLK: CPU1.AY22 RN1902.3(B)
HDA_CODEC_BITCLK: EC1901.2 EC2708.1 R2752.1 RN1902.2(A)
HDA_CODEC_SDIN0: HDA27.16 R2730.2
HDA_CODEC_SDOUT: EC1903.1 R2740.1 RN1902.1(A)
HDA_CODEC_SYNC: HDA27.15 R1908.1
HDA_RST#: CPU1.AW22 EC1902.1 TP1903.1
HDA_SDIN0: CPU1.BA21 R2730.1
HDA_SDOUT: CPU1.BB22 R1909.2 RN1902.4(B)
HDA_SPKR_R: D2702.2 RN2702.3(B)
HDA_SYNC: CPU1.BA22 R1908.2
HDD_DEVSLP: CPU1.J1 R6002.1
HDD_DEVSLP_R: HDD1.13 R6002.2
HDMI_27MHZ_OUT: C5730.1 R5748.1 X5701.3
HDMI_AUXN: C5739.1 CPU1.G50
HDMI_AUXN_L: C5739.2 C5741.1 R5763.1
HDMI_AUXN_R: C5741.2 U5701.C8
HDMI_AUXP: C5738.1 CPU1.F50
HDMI_AUXP_L: C5738.2 C5740.1 R5762.1
HDMI_AUXP_R: C5740.2 U5701.C7
HDMI_CEC: R5761.1 U5701.F2
HDMI_CEC_C: HDMI2.13 R5761.2
HDMI_CLK#_C: R5708.1 R5716.2
HDMI_CLK#_L_C: C5724.2 R5716.1 U5701.H1
HDMI_CLK#_R_C: ED5702.5 ED5702.6 ER5745.1 HDMI2.12 R5708.2
HDMI_CLK_C: R5707.1 R5717.2
HDMI_CLK_L_C: C5724.1 R5717.1 U5701.H2
HDMI_CLK_R_C: ED5702.4 ED5702.7 ER5745.2 HDMI2.10 R5707.2
HDMI_DATA0#_C: R5706.1 R5714.2
HDMI_DATA0#_L_C: R5714.1 U5701.H3
HDMI_DATA0#_R_C: ED5702.2 ED5702.9 ER5759.2 HDMI2.9 R5706.2
HDMI_DATA0_C: R5705.1 R5715.2
HDMI_DATA0_L_C: R5715.1 U5701.H4
HDMI_DATA0_R_C: ED5702.1 ED5702.10 ER5759.1 HDMI2.7 R5705.2
HDMI_DATA1#_C: R5704.1 R5712.2
HDMI_DATA1#_L_C: R5712.1 U5701.H5
HDMI_DATA1#_R_C: ED5701.5 ED5701.6 ER5758.2 HDMI2.6 R5704.2
HDMI_DATA1_C: R5703.1 R5713.2
HDMI_DATA1_L_C: R5713.1 U5701.H6
HDMI_DATA1_R_C: ED5701.4 ED5701.7 ER5758.1 HDMI2.4 R5703.2
HDMI_DATA2#_C: R5702.1 R5711.2
HDMI_DATA2#_L_C: R5711.1 U5701.H7
HDMI_DATA2#_R_C: ED5701.2 ED5701.9 ER5744.2 HDMI2.3 R5702.2
HDMI_DATA2_C: R5701.1 R5710.2
HDMI_DATA2_L_C: R5710.1 U5701.H8
HDMI_DATA2_R_C: ED5701.1 ED5701.10 ER5744.1 HDMI2.1 R5701.2
HOLD#_HDMI: R5742.1 U5702.7
HOST_DEBUG_TX: DBEC1.5 KBC24.81 R2480.1 R6801.1
HOST_DEBUG_TX_CON: DB1.11 R6801.2
HPD_HDMI_CON: HDMI2.19 R5758.2 U5701.G1
HPDIN: R3821.2 U3801.32
HW_ACAV_IN: KBC24.128 PG4408.2 PQ4415.5
HW_ACAVIN_NB: KBC24.24 R2475.2 R2499.2
I2C0_SCL_R: AFTP6534.1 Q6504.6 R6505.2 RN6503.3(B) TPCON1.6
I2C0_SCL_TCH_PAD: CPU1.U6 EC6503.1 Q6504.1 R6505.1
I2C0_SCL_TCH_PNL: CPU1.U9 R5521.2
I2C0_SDA_R: AFTP6535.1 Q6504.3 R6506.2 RN6503.4(B) TPCON1.7
I2C0_SDA_TCH_PAD: CPU1.U7 EC6504.1 Q6504.4 R6506.1
I2C0_SDA_TCH_PNL: CPU1.U8 R5522.2
I2C1_SCL: CPU1.N2 RN2008.1(A)
I2C1_SDA: CPU1.N1 RN2008.2(A)
I2C_CLK_PD: R3814.1 RN3701.3(B) U3701.29
I2C_CLK_PD_MUX: R3814.2 U3801.21
I2C_DATA_PD: R3816.1 RN3701.4(B) U3701.28
I2C_DATA_PD_MUX: R3816.2 U3801.22
I2CB_SCL: GPU1.C9 RN7605.3(B)
I2CB_SDA: GPU1.C8 RN7605.4(B)
I2CC_SCL: GPU1.A9 RN7604.4(B)
I2CC_SDA: GPU1.B9 RN7604.3(B)
I2CEN: R3873.1 R3874.2 U3801.17
I_ADP: C2435.1 KBC24.110 R2421.2
I_BATT: C2431.1 KBC24.114 R2483.2
IC_DELAY: PC4307.1 U4302.4
ICSP_CLK: DBEC1.2 KBC24.101
ICSP_CLR: DBEC1.6 KBC24.87 R2414.1
ICSP_DAT: DBEC1.3 KBC24.102
IE_DELAY_G: PC4315.1 PQ4313.2 PQ4313.3 PR4343.2
IE_DELAY_S: PC4314.1 PQ4313.1 PR4344.2
ILIM_HI: R3404.2 U3401.16
ILIM_LO: R3403.2 U3401.15
ILIM_SEL: R3405.2 U3401.4
INT2_SELECT: D7001.2 Q7001.5 R7008.1 R7013.1
INT#_TYPEC_R: R3707.2 R3731.2 U3701.15
IR_CAM_DET#: CPU1.P4 R2046.2 R5540.2
IR_CAMERA_DET#_R: LCD1.44 R5540.1
ISH_I2C0_SCL: CPU1.N3 R2020.1 RN2007.1(A)
ISH_I2C0_SDA: CPU1.M4 R2021.1 RN2007.2(A)
ISH_KB_DISABLE: CPU1.AY8 Q2001.2
ITP_PMODE: CPU1.E8 TP638.1
JACK_PLUG: ED2902.1 HPMIC1.5 R2923.1
JACK_PLUG_DET: ED2902.2 HPMIC1.6 R2905.1
JGND: AFTP4301.1 AFTP4302.1 DCIN1.1 DCIN1.2 DCIN1.3 EC4301.2 EC4302.2 EC4312.2 EC4313.2 EL4303.1 EL4304.1
KB_BL_CTRL#: AFTP6530.1 EC6505.1 KBBL2.4 Q6501.D
KB_DET#: CPU1.AD4 KB1.30 R2045.2
KB_DISABLE_CPU_R: Q2001.5 Q2001.6 R2001.2
KB_LED_BL_DET: CPU1.W8 R6507.1 R6508.1
KB_LED_DET_C: C6504.1 EC6506.1 KBBL2.2 R6507.2
KB_LED_PWM: KBC24.44 Q6501.G R6509.1
KBC_BEEP_R: D2702.1 RN2702.4(B)
KBC_PWRBTN#: EC6601.1 IOBD1.54 PWSW1.3 PWSW1.4 R2432.1
KSI0: AFTP6548.1 KB1.22 KBC24.98 RN2403.7(B)
KSI1: AFTP6547.1 KB1.24 KBC24.99 RN2403.6(B)
KSI2: AFTP6545.1 KB1.26 KBC24.6 RN2407.3(B)
KSI3: AFTP6550.1 KB1.23 KBC24.7 RN2407.4(B)
KSI4: AFTP6544.1 KB1.27 KBC24.104 RN2403.5(B)
KSI5: AFTP6546.1 KB1.25 KBC24.105 RN2404.8(B)
KSI6: AFTP6543.1 KB1.28 KBC24.107 RN2404.7(B)
KSI7: AFTP6542.1 KB1.29 KBC24.108 RN2404.6(B)
KSO0: AFTP6557.1 KB1.13 KBC24.2 R2484.2
KSO1: AFTP6558.1 KB1.15 KBC24.14 RN2412.6(B)
KSO2: AFTP6556.1 KB1.14 KBC24.15 RN2412.7(B)
KSO3: AFTP6555.1 KB1.16 KBC24.16 RN2412.8(B)
KSO4: AFTP6551.1 KB1.20 KBC24.37 RN2409.5(B)
KSO5: AFTP6549.1 KB1.21 KBC24.38 RN2409.6(B)
KSO6: AFTP6553.1 KB1.18 KBC24.39 RN2409.7(B)
KSO7: AFTP6552.1 KB1.19 KBC24.50 RN2412.5(B)
KSO8: AFTP6554.1 KB1.17 KBC24.46 RN2409.8(B)
KSO9: AFTP6563.1 KB1.7 KBC24.68 R2449.2 R2450.1
KSO10: AFTP6566.1 KB1.5 KBC24.72 RN2410.6(B)
KSO11: AFTP6565.1 KB1.6 KBC24.74 RN2410.7(B)
KSO12: AFTP6559.1 KB1.12 KBC24.75 RN2410.8(B)
KSO13: AFTP6562.1 KB1.9 KBC24.76 RN2411.3(B)
KSO14: AFTP6564.1 KB1.8 KBC24.77 RN2411.4(B)
KSO15: AFTP6561.1 KB1.10 KBC24.86 RN2404.5(B)
KSO16: AFTP6560.1 KB1.11 KBC24.92 RN2403.8(B)
L_BKLT_CTRL: CPU1.R11 D5502.1 R5502.2
L_BKLT_EN: CPU1.R12 R2427.2 R2435.2 R2436.1
L_BKLT_EN_L: D2401.2 R2427.1
LAN_CLK_CPU: CPU1.C41 IOBD1.23
LAN_CLK_CPU#: CPU1.D41 IOBD1.22
LAN_WAKE#: CPU1.AM15 R1707.2 R2408.1 R2428.1
LANWAKE#: KBC24.35 R2428.2
LANWAKE#_IC: IOBD1.60 R2406.2 R2408.2
LCD_BRIGHTNESS: EC5501.1 LCD1.22 RN5501.4(A)
LCD_CBL_DET#: CPU1.W4 R2039.2
LCD_TST: D5502.2 KBC24.26 RN5501.8(B)
LCD_TST_C: LCD1.9 RN5501.1(A)
LCD_VCC_TEST_EN: D5501.2 KBC24.113
LCDVDD: C5505.1 C5507.1 C5508.2 LCD1.30 LCD1.31 LCD1.32 LCD1.33 U5501.3
LDO1_CAP: C2731.2 HDA27.39 R2747.2
LDO2_CAP: C2734.2 HDA27.21
LDO3_CAP: C2736.1 HDA27.19
LID_CL_SIO#: D2402.K IOBD1.30 KBC24.66 RN2406.1(A)
LID_CL_SIO_TAB#: IOBD1.27 KBC24.97 R6604.1
LINE1-L_C: C2907.2 R2922.1
LINE1-L_R: C2908.2 R2921.1
LINE1_L: C2907.1 HDA27.36
LINE1_R: C2908.1 HDA27.35
LVDS_VDD_EN_R: D5501.3 RN5502.8(B) U5501.1
M2_SSD_PEDET: AFTP6303.1 CPU1.G4 R6305.2 SSD1.69
M_A_A0: CPU1.AY50 DM1.144
M_A_A1: CPU1.BB50 DM1.133
M_A_A2: CPU1.AY51 DM1.132
M_A_A3: CPU1.BA50 DM1.131
M_A_A4: CPU1.BB52 DM1.128
M_A_A5: CPU1.BA51 DM1.126
M_A_A6: CPU1.BA52 DM1.127
M_A_A7: CPU1.AW52 DM1.122
M_A_A8: CPU1.AY52 DM1.125
M_A_A9: CPU1.BB54 DM1.121
M_A_A10: CPU1.AT50 DM1.146
M_A_A11: CPU1.BA54 DM1.120
M_A_A12: CPU1.AW54 DM1.119
M_A_A13: CPU1.AU46 DM1.158
M_A_A14: CPU1.AT46 DM1.151
M_A_A15: CPU1.AU48 DM1.156
M_A_A16: CPU1.AU50 DM1.152
M_A_ACT_N: CPU1.BA55 DM1.114
M_A_ALERT_N: CPU1.AW50 DM1.116
M_A_BA0: CPU1.AU52 DM1.150
M_A_BA1: CPU1.AT48 DM1.145
M_A_BG0: CPU1.AY55 DM1.115
M_A_BG1: CPU1.AY54 DM1.113
M_A_CKE0: CPU1.BA56 DM1.109
M_A_CKE1: CPU1.BB56 DM1.110
M_A_CLK0: CPU1.AT53 DM1.137
M_A_CLK1: CPU1.AT55 DM1.138
M_A_CLK#0: CPU1.AU53 DM1.139
M_A_CLK#1: CPU1.AU55 DM1.140
M_A_CS#0: CPU1.AU45 DM1.149
M_A_CS#1: CPU1.AU43 DM1.157
M_A_DIMA_ODT0: CPU1.AT45 DM1.155
M_A_DIMA_ODT1: CPU1.AT43 DM1.161
M_A_DQ0: CPU1.AL71 DM1.8
M_A_DQ1: CPU1.AL68 DM1.7
M_A_DQ2: CPU1.AN68 DM1.20
M_A_DQ3: CPU1.AN69 DM1.21
M_A_DQ4: CPU1.AL70 DM1.4
M_A_DQ5: CPU1.AL69 DM1.3
M_A_DQ6: CPU1.AN70 DM1.16
M_A_DQ7: CPU1.AN71 DM1.17
M_A_DQ8: CPU1.AR70 DM1.28
M_A_DQ9: CPU1.AR68 DM1.29
M_A_DQ10: CPU1.AU71 DM1.41
M_A_DQ11: CPU1.AU68 DM1.42
M_A_DQ12: CPU1.AR71 DM1.24
M_A_DQ13: CPU1.AR69 DM1.25
M_A_DQ14: CPU1.AU70 DM1.38
M_A_DQ15: CPU1.AU69 DM1.37
M_A_DQ16: CPU1.BB65 DM1.50
M_A_DQ17: CPU1.AW65 DM1.49
M_A_DQ18: CPU1.AW63 DM1.62
M_A_DQ19: CPU1.AY63 DM1.63
M_A_DQ20: CPU1.BA65 DM1.46
M_A_DQ21: CPU1.AY65 DM1.45
M_A_DQ22: CPU1.BA63 DM1.58
M_A_DQ23: CPU1.BB63 DM1.59
M_A_DQ24: CPU1.BA61 DM1.70
M_A_DQ25: CPU1.AW61 DM1.71
M_A_DQ26: CPU1.BB59 DM1.83
M_A_DQ27: CPU1.AW59 DM1.84
M_A_DQ28: CPU1.BB61 DM1.66
M_A_DQ29: CPU1.AY61 DM1.67
M_A_DQ30: CPU1.BA59 DM1.79
M_A_DQ31: CPU1.AY59 DM1.80
M_A_DQ32: CPU1.AY39 DM1.174
M_A_DQ33: CPU1.AW39 DM1.173
M_A_DQ34: CPU1.AY37 DM1.187
M_A_DQ35: CPU1.AW37 DM1.186
M_A_DQ36: CPU1.BB39 DM1.170
M_A_DQ37: CPU1.BA39 DM1.169
M_A_DQ38: CPU1.BA37 DM1.183
M_A_DQ39: CPU1.BB37 DM1.182
M_A_DQ40: CPU1.AY35 DM1.195
M_A_DQ41: CPU1.AW35 DM1.194
M_A_DQ42: CPU1.AY33 DM1.207
M_A_DQ43: CPU1.AW33 DM1.208
M_A_DQ44: CPU1.BB35 DM1.191
M_A_DQ45: CPU1.BA35 DM1.190
M_A_DQ46: CPU1.BA33 DM1.203
M_A_DQ47: CPU1.BB33 DM1.204
M_A_DQ48: CPU1.AY31 DM1.216
M_A_DQ49: CPU1.AW31 DM1.215
M_A_DQ50: CPU1.AY29 DM1.228
M_A_DQ51: CPU1.AW29 DM1.229
M_A_DQ52: CPU1.BB31 DM1.211
M_A_DQ53: CPU1.BA31 DM1.212
M_A_DQ54: CPU1.BA29 DM1.224
M_A_DQ55: CPU1.BB29 DM1.225
M_A_DQ56: CPU1.AY27 DM1.237
M_A_DQ57: CPU1.AW27 DM1.236
M_A_DQ58: CPU1.AY25 DM1.249
M_A_DQ59: CPU1.AW25 DM1.250
M_A_DQ60: CPU1.BB27 DM1.232
M_A_DQ61: CPU1.BA27 DM1.233
M_A_DQ62: CPU1.BA25 DM1.245
M_A_DQ63: CPU1.BB25 DM1.246
M_A_DQS_DN0: CPU1.AM70 DM1.11
M_A_DQS_DN1: CPU1.AT69 DM1.32
M_A_DQS_DN2: CPU1.BA64 DM1.53
M_A_DQS_DN3: CPU1.AY60 DM1.74
M_A_DQS_DN4: CPU1.BA38 DM1.177
M_A_DQS_DN5: CPU1.AY34 DM1.198
M_A_DQS_DN6: CPU1.BA30 DM1.219
M_A_DQS_DN7: CPU1.AY26 DM1.240
M_A_DQS_DP0: CPU1.AM69 DM1.13
M_A_DQS_DP1: CPU1.AT70 DM1.34
M_A_DQS_DP2: CPU1.AY64 DM1.55
M_A_DQS_DP3: CPU1.BA60 DM1.76
M_A_DQS_DP4: CPU1.AY38 DM1.179
M_A_DQS_DP5: CPU1.BA34 DM1.200
M_A_DQS_DP6: CPU1.AY30 DM1.221
M_A_DQS_DP7: CPU1.BA26 DM1.242
M_A_PARITY: CPU1.AT52 DM1.143
M_B_A0: CPU1.BA46 DM2.144
M_B_A1: CPU1.AY46 DM2.133
M_B_A2: CPU1.AY47 DM2.132
M_B_A3: CPU1.BB46 DM2.131
M_B_A4: CPU1.BA47 DM2.128
M_B_A5: CPU1.AY48 DM2.126
M_B_A6: CPU1.BA48 DM2.127
M_B_A7: CPU1.AP48 DM2.122
M_B_A8: CPU1.BB48 DM2.125
M_B_A9: CPU1.AP50 DM2.121
M_B_A10: CPU1.AW46 DM2.146
M_B_A11: CPU1.AN48 DM2.120
M_B_A12: CPU1.AN50 DM2.119
M_B_A13: CPU1.BA43 DM2.158
M_B_A14: CPU1.AY44 DM2.151
M_B_A15: CPU1.AY43 DM2.156
M_B_A16: CPU1.AW44 DM2.152
M_B_ACT_N: CPU1.AN53 DM2.114
M_B_ALERT_N: CPU1.AN43 DM2.116
M_B_BA0: CPU1.BB44 DM2.150
M_B_BA1: CPU1.BA44 DM2.145
M_B_BG0: CPU1.AP52 DM2.115
M_B_BG1: CPU1.AN52 DM2.113
M_B_CKE0: CPU1.AN56 DM2.109
M_B_CKE1: CPU1.AP55 DM2.110
M_B_CLK0: CPU1.AP45 DM2.137
M_B_CLK1: CPU1.AP46 DM2.138
M_B_CLK#0: CPU1.AN45 DM2.139
M_B_CLK#1: CPU1.AN46 DM2.140
M_B_CS#0: CPU1.BB42 DM2.149
M_B_CS#1: CPU1.AY42 DM2.157
M_B_DIMB_ODT0: CPU1.BA42 DM2.155
M_B_DIMB_ODT1: CPU1.AW42 DM2.161
M_B_DQ0: CPU1.AF65 DM2.28
M_B_DQ1: CPU1.AF64 DM2.29
M_B_DQ2: CPU1.AK65 DM2.41
M_B_DQ3: CPU1.AK64 DM2.42
M_B_DQ4: CPU1.AF66 DM2.24
M_B_DQ5: CPU1.AF67 DM2.25
M_B_DQ6: CPU1.AK67 DM2.38
M_B_DQ7: CPU1.AK66 DM2.37
M_B_DQ8: CPU1.AF70 DM2.8
M_B_DQ9: CPU1.AF68 DM2.7
M_B_DQ10: CPU1.AH71 DM2.20
M_B_DQ11: CPU1.AH68 DM2.21
M_B_DQ12: CPU1.AF71 DM2.4
M_B_DQ13: CPU1.AF69 DM2.3
M_B_DQ14: CPU1.AH70 DM2.16
M_B_DQ15: CPU1.AH69 DM2.17
M_B_DQ16: CPU1.AT66 DM2.50
M_B_DQ17: CPU1.AU66 DM2.49
M_B_DQ18: CPU1.AP65 DM2.62
M_B_DQ19: CPU1.AN65 DM2.63
M_B_DQ20: CPU1.AN66 DM2.46
M_B_DQ21: CPU1.AP66 DM2.45
M_B_DQ22: CPU1.AT65 DM2.58
M_B_DQ23: CPU1.AU65 DM2.59
M_B_DQ24: CPU1.AT61 DM2.70
M_B_DQ25: CPU1.AU61 DM2.71
M_B_DQ26: CPU1.AP60 DM2.83
M_B_DQ27: CPU1.AN60 DM2.84
M_B_DQ28: CPU1.AN61 DM2.66
M_B_DQ29: CPU1.AP61 DM2.67
M_B_DQ30: CPU1.AT60 DM2.79
M_B_DQ31: CPU1.AU60 DM2.80
M_B_DQ32: CPU1.AU40 DM2.174
M_B_DQ33: CPU1.AT40 DM2.173
M_B_DQ34: CPU1.AT37 DM2.187
M_B_DQ35: CPU1.AU37 DM2.186
M_B_DQ36: CPU1.AR40 DM2.170
M_B_DQ37: CPU1.AP40 DM2.169
M_B_DQ38: CPU1.AP37 DM2.183
M_B_DQ39: CPU1.AR37 DM2.182
M_B_DQ40: CPU1.AT33 DM2.195
M_B_DQ41: CPU1.AU33 DM2.194
M_B_DQ42: CPU1.AU30 DM2.207
M_B_DQ43: CPU1.AT30 DM2.208
M_B_DQ44: CPU1.AR33 DM2.191
M_B_DQ45: CPU1.AP33 DM2.190
M_B_DQ46: CPU1.AR30 DM2.203
M_B_DQ47: CPU1.AP30 DM2.204
M_B_DQ48: CPU1.AU27 DM2.216
M_B_DQ49: CPU1.AT27 DM2.215
M_B_DQ50: CPU1.AT25 DM2.228
M_B_DQ51: CPU1.AU25 DM2.229
M_B_DQ52: CPU1.AP27 DM2.211
M_B_DQ53: CPU1.AN27 DM2.212
M_B_DQ54: CPU1.AN25 DM2.224
M_B_DQ55: CPU1.AP25 DM2.225
M_B_DQ56: CPU1.AT22 DM2.237
M_B_DQ57: CPU1.AU22 DM2.236
M_B_DQ58: CPU1.AU21 DM2.249
M_B_DQ59: CPU1.AT21 DM2.250
M_B_DQ60: CPU1.AN22 DM2.232
M_B_DQ61: CPU1.AP22 DM2.233
M_B_DQ62: CPU1.AP21 DM2.245
M_B_DQ63: CPU1.AN21 DM2.246
M_B_DQS_DN0: CPU1.AH66 DM2.32
M_B_DQS_DN1: CPU1.AG69 DM2.11
M_B_DQS_DN2: CPU1.AR66 DM2.53
M_B_DQS_DN3: CPU1.AR61 DM2.74
M_B_DQS_DN4: CPU1.AT38 DM2.177
M_B_DQS_DN5: CPU1.AT32 DM2.198
M_B_DQS_DN6: CPU1.AR25 DM2.219
M_B_DQS_DN7: CPU1.AR22 DM2.240
M_B_DQS_DP0: CPU1.AH65 DM2.34
M_B_DQS_DP1: CPU1.AG70 DM2.13
M_B_DQS_DP2: CPU1.AR65 DM2.55
M_B_DQS_DP3: CPU1.AR60 DM2.76
M_B_DQS_DP4: CPU1.AR38 DM2.179
M_B_DQS_DP5: CPU1.AR32 DM2.200
M_B_DQS_DP6: CPU1.AR27 DM2.221
M_B_DQS_DP7: CPU1.AR21 DM2.242
M_B_PARITY: CPU1.AP43 DM2.143
M_VREF_CA_DIMMA: C1229.1 DM1.164 R1206.1 RN1201.3(B) RN1201.4(B)
M_VREF_CA_DIMMB: C1301.1 DM2.164 R1305.1 RN1301.3(B) RN1301.4(B)
MASK_SATA_LED#: KBC24.56 Q6105.G R6120.2
ME_FWP: KBC24.80 R1909.1
ME_SUS_PWR_ACK_R: CPU1.AR13 R1708.1 R1738.2
MEC_XTAL1_R: C2425.2 KBC24.123 X2401.1
MEC_XTAL2: C2424.2 KBC24.125 R2461.2 X2401.2
MEM_SMBCLK: CPU1.R7 Q1801.3 RN1811.4(B)
MEM_SMBDATA: CPU1.R8 Q1801.6 RN1811.3(B)
MIC2_VREFO_L: HDA27.28 RN2901.2(A)
MIC2_VREFO_R: HDA27.29 RN2901.1(A)
MIC_CAP: C2735.1 HDA27.32
MIC_GND: LCD1.45 R5501.1
MODEL_ID: C2407.2 KBC24.109 R2441.1 R2442.2
MSATA_CLK_CPU: CPU1.A40 SSD1.55
MSATA_CLK_CPU#: CPU1.B40 SSD1.53
MSATA_DEVSLP_R: AFTP6301.1 R6301.2 SSD1.38
MSATA_RST#: R6308.2 SSD1.50
MSM#: CPU1.AP56 TP617.1
MUX_ENA_L: R3859.1 U3802.16
MUX_ENB_L: R3860.1 U3802.10
MUX_HPD_PD: R3849.2 U3801.23
MUX_INB_N: R3854.2 U3802.4
MUX_INB_P: R3853.2 U3802.3
MUX_SAI: R3855.2 U3802.14
MUX_SAO: R3857.2 U3802.15
MUX_SBI: R3856.2 U3802.12
MUX_SBO: R3858.2 U3802.11
MUX_TYPEC_RXN1: R3835.1 U3801.31
MUX_TYPEC_RXN2: R3837.1 U3801.39
MUX_TYPEC_RXP1: R3834.1 U3801.30
MUX_TYPEC_RXP2: R3836.1 U3801.40
MUX_TYPEC_TXN1: C3863.1 U3801.34
MUX_TYPEC_TXN1_C: C3863.2 R3833.1
MUX_TYPEC_TXN2: C3862.1 U3801.36
MUX_TYPEC_TXN2_C: C3862.2 R3839.1
MUX_TYPEC_TXP1: C3864.1 U3801.33
MUX_TYPEC_TXP1_C: C3864.2 R3832.1
MUX_TYPEC_TXP2: C3861.1 U3801.37
MUX_TYPEC_TXP2_C: C3861.2 R3838.1
N12P_JTAG_TCK: GPU1.AE5 RN7602.4(B)
N12P_JTAG_TDI: GPU1.AE6 TP7605.1
N12P_JTAG_TDO: GPU1.AF6 TP7601.1
N12P_JTAG_TMS: GPU1.AD6 TP7602.1
N12P_JTAG_TRST: GPU1.AG4 RN7602.3(B)
N12P_XTAL_OUTBUFF: GPU1.C10 R7602.1 R7617.2
NB_MODE#: KBC24.96 Q2001.3 R2002.2 R2050.1
NB_MUTE#: KBC24.119 R2737.1 R2743.1
NCT7718_DXN: C2606.2 C2607.2 Q2603.E THM261.3
NCT7718_DXP: C2606.1 C2607.1 Q2603.B Q2603.C THM261.2
NRB_BIT: CPU1.AR7 R2007.2 R2019.1
OVERT_GPU#: GPU1.A6 RN7610.1(A)
P2800_VGA_DXN: GPU1.E12 TP7603.1
P2800_VGA_DXP: GPU1.F12 TP7604.1
P_SYS: PR4413.1 PU4401.30
PANEL_BKEN: D2401.3 RN5501.7(B)
PANEL_BKEN_EC: D2401.1 KBC24.117
PBAT_CHG_SMBCLK: D4306.3 EC4309.1 KBC24.9 PU4401.22 RN2402.3(B) RN4302.3(A)
PBAT_CHG_SMBDAT: D4305.3 EC4310.1 KBC24.8 PU4401.21 RN2402.4(B) RN4302.2(A)
PBAT_PRES1#: AFTP4309.1 BATT1.6 RN4302.8(B)
PBAT_PRES#: D4304.3 EC4306.2 KBC24.29 PQ4313.5 PR4409.2 R2415.1 RN4302.1(A)
PBAT_SMBCLK1: AFTP4311.1 BATT1.4 RN4302.6(B)
PBAT_SMBDAT1: AFTP4310.1 BATT1.5 RN4302.7(B)
PCH_BATLOW#: CPU1.AU13 RN1704.6(B)
PCH_DPC_N0: C3813.1 CPU1.C50
PCH_DPC_N0_C: C3813.2 U3801.10
PCH_DPC_N1: C3807.1 CPU1.C52
PCH_DPC_N1_C: C3807.2 U3801.13
PCH_DPC_N2: C3808.1 CPU1.A50
PCH_DPC_N2_C: C3808.2 U3801.16
PCH_DPC_N3: C3810.1 CPU1.D51
PCH_DPC_N3_C: C3810.2 U3801.19
PCH_DPC_P0: C3812.1 CPU1.D50
PCH_DPC_P0_C: C3812.2 U3801.9
PCH_DPC_P1: C3814.1 CPU1.D52
PCH_DPC_P1_C: C3814.2 U3801.12
PCH_DPC_P2: C3809.1 CPU1.B50
PCH_DPC_P2_C: C3809.2 U3801.15
PCH_DPC_P3: C3811.1 CPU1.C51
PCH_DPC_P3_C: C3811.2 U3801.18
PCH_DPWROK: CPU1.BB20 R1704.2
PCH_ESPI_CLK: CPU1.AW9 R1805.1
PCH_ESPI_IO0: CPU1.AY13 R1827.2
PCH_ESPI_IO1: CPU1.BA13 R1828.2
PCH_ESPI_IO2: CPU1.BB13 R1829.2
PCH_ESPI_IO3: CPU1.AY12 R1830.2
PCH_JTAG_TCK: CPU1.B56 R407.1
PCH_JTAG_TDI: CPU1.D59 R408.1
PCH_JTAG_TDO: CPU1.A56 R409.1
PCH_JTAG_TMS: CPU1.C59 R416.1
PCH_PLTRST#: CPU1.AN10 R1713.2
PCH_POPIRCOMP: CPU1.AU16 R413.1
PCH_RSMRST#: EC1712.1 KBC24.27 R1702.2 TP2401.1
PCH_SMBCLK: DM1.253 DM2.253 Q1801.4 RN1810.3(B)
PCH_SMBDATA: DM1.254 DM2.254 Q1801.1 RN1810.4(B)
PCH_THERMTRIP#: CPU1.C63 EC401.1 R419.2
PCIE_CLK_XDP_N: CPU1.F43 TP1802.1
PCIE_CLK_XDP_P: CPU1.E43 TP1803.1
PCIE_RCOMPN: CPU1.F5 R1604.1
PCIE_RCOMPP: CPU1.E5 R1604.2
PCIE_RX_CPU_N5: CPU1.F16 IOBD1.17
PCIE_RX_CPU_N6: CPU1.G18 IOBD1.1
PCIE_RX_CPU_N9: CPU1.E22 SSD1.5
PCIE_RX_CPU_N10: CPU1.F25 SSD1.17
PCIE_RX_CPU_N11: CPU1.E28 SSD1.29
PCIE_RX_CPU_P5: CPU1.E16 IOBD1.16
PCIE_RX_CPU_P6: CPU1.F18 IOBD1.2
PCIE_RX_CPU_P9: CPU1.E23 SSD1.7
PCIE_RX_CPU_P10: CPU1.E25 SSD1.19
PCIE_RX_CPU_P11: CPU1.E27 SSD1.31
PCIE_TX_CON_N9: C6316.1 SSD1.11
PCIE_TX_CON_N10: C6314.1 SSD1.23
PCIE_TX_CON_N11: C6312.1 SSD1.35
PCIE_TX_CON_P9: C6315.1 SSD1.13
PCIE_TX_CON_P10: C6313.1 SSD1.25
PCIE_TX_CON_P11: C6311.1 SSD1.37
PCIE_TX_CPU_N5: C1601.2 CPU1.C19
PCIE_TX_CPU_N6: C1613.2 CPU1.D20
PCIE_TX_CPU_N9: C6316.2 CPU1.B23
PCIE_TX_CPU_N10: C6314.2 CPU1.D23
PCIE_TX_CPU_N11: C6312.2 CPU1.D24
PCIE_TX_CPU_P5: C1602.2 CPU1.D19
PCIE_TX_CPU_P6: C1614.2 CPU1.C20
PCIE_TX_CPU_P9: C6315.2 CPU1.A23
PCIE_TX_CPU_P10: C6313.2 CPU1.C23
PCIE_TX_CPU_P11: C6311.2 CPU1.C24
PCIE_TX_LAN_N5: C1601.1 IOBD1.19
PCIE_TX_LAN_P5: C1602.1 IOBD1.20
PCIE_TX_WLAN_N6: C1613.1 IOBD1.4
PCIE_TX_WLAN_P6: C1614.1 IOBD1.5
PCIE_WAKE#: KBC24.4 R2406.1 R2407.1
PCIE_WAKE#_CPU: CPU1.BB15 RN1704.7(B)
PD4403_A: PD4404.A PQ4408.B
PD4403_K: PD4404.K PR4477.2
PD_CC1: R3728.1 U3701.9
PD_CC2: R3727.1 U3701.7
PD_SWD_CLK: CCGDB1.4 U3701.2
PD_SWD_IO: CCGDB1.5 U3701.1
PD_VBUS_C_CTRL1: PQ4312.G PR4323.1 U3701.12
PD_VBUS_C_CTRL1_A: PC4311.1 PQ4306.D PQ4307.5 PQ4307.6 PQ4311.3 PQ4313.6 PR4319.2
PD_VBUS_C_CTRL1_R: PQ4307.2 PQ4312.D PR4342.2
PD_VBUS_DISCHG: PQ4310.2 PR4332.1 U3701.20
PD_VBUS_P_CTRL1: PD4308.A PR4310.1 U3701.11
PD_VBUS_P_CTRL1_R: PQ4309.5 PQ4314.D PR4310.2 PR4324.1
PD_VBUS_R: C3717.2 R3726.2 R3730.2 U3701.13
PD_VCCD: C3715.1 U3701.33
PD_XRES: C3716.1 CCGDB1.3 R3724.2 U3701.10
PEG_CLK1_CPU: CPU1.A42 IOBD1.8
PEG_CLK1_CPU#: CPU1.B42 IOBD1.7
PEG_TX_CPU_N0: C1606.2 CPU1.B17
PEG_TX_CPU_N1: C1608.2 CPU1.D16
PEG_TX_CPU_N2: C1610.2 CPU1.D17
PEG_TX_CPU_N3: C1612.2 CPU1.B19
PEG_TX_CPU_P0: C1605.2 CPU1.A17
PEG_TX_CPU_P1: C1607.2 CPU1.C16
PEG_TX_CPU_P2: C1609.2 CPU1.C17
PEG_TX_CPU_P3: C1611.2 CPU1.A19
PEX_TERMP: GPU1.AF25 R7301.1
PEXTSTCLK_OUT: GPU1.AF22 R7307.1
PEXTSTCLK_OUT#: GPU1.AE22 R7307.2
PIRQA#: CPU1.BB11 R1607.2
PLT_RST#: C1701.1 EC1703.1 EC6602.1 IOBD1.52 R1713.1 R1715.1 R2616.1 R6308.1 R9110.1 U7301.2
PLT_RST#_Q_TPM2: R9110.2 U9101.17
PM_PCH_PWROK: CPU1.BA20 R1706.2 RN1703.3(B)
PM_RSMRST#: CPU1.AY17 Q1701.3 R1702.1 R1704.1 R1720.2 RN1703.4(B)
PM_RSMRST#_M: Q1702.5 Q1702.6 R1737.2
PM_RSMRST#_R: Q1702.2 R1720.1
POWER_SW_IN#: C2426.1 KBC24.127 R2432.2 R2451.1
PQ3802_1: PQ4302.B PR4302.1 PR4309.2
PQ4405_2: PQ4405.2 PR4462.1 PR4463.1
PQ4405_3: PQ4405.3 PR4476.1
PQ4405_5: PC4438.1 PQ4405.5 PR4474.2
PQ4405_6: PC4438.2 PQ4405.6 PR4450.1
PQ4408_C: PQ4408.C PR4462.2 PR4475.1
PQ4408_E: PQ4408.E PR4436.1 PR4473.2
PRIM_PWRGD: KBC24.30 PR5408.1 R4030.1
PROC_SELECT#: CPU1.C64 R603.1
PROCHOT: KBC24.83 Q2408.G R2417.1 R2418.1
PROJECT_ID0: CPU1.AK6 R1916.2 R1920.1
PROJECT_ID1: CPU1.AK7 R1915.1 R1919.2
PROJECT_ID2: CPU1.AK9 R1914.2 R1918.1
PROJECT_ID3: CPU1.AK10 R1913.2 R1917.1
PS175_CEC_EN: R5756.2 R5757.2 U5701.E7
PS175_CSCL: R5739.2 U5701.E6
PS175_CSDA: R5738.2 U5701.F6
PS175_GPIO0: R5735.2 U5701.C4
PS175_GPIO2: R5754.2 U5701.E3
PS175_PD#: R5736.2 U5701.C3
PS175_RST#: C5725.2 R5737.2 U5701.B8
PS_ID: KBC24.36 PD4302.3 PR4304.2 PR4305.2
PS_ID_R: AFTP4304.1 DCIN1.4 EC4311.1 PR4317.1
PS_ID_R1: PQ4301.S PR4305.1 PR4306.2
PS_ID_R2: PD4303.1 PD4303.2 PQ4301.D PR4306.1 PR4309.1 PR4317.2
PSID_DISABLE#_R_C: PQ4301.G PQ4302.C PR4303.2
PSYS: PR4614.1 PU4601.1
PTP_DIS#: AFTP6537.1 KBC24.90 TPCON1.3
PURE_HW_SHUTDOWN#: C2610.1 D4001.3 Q2602.D R2615.1
PWR_0D6V_S3EN: PC5120.1 PR5125.2 PR5126.2 PU5102.7
PWR_0D6V_S5EN: PC5119.1 PR5114.2 PU5102.9
PWR_0D6V_VCNTL: PC5121.1 PR5118.1 PU5102.10
PWR_1D0V_BT: PC5204.1 PU5201.20
PWR_1D0V_EN: PC5215.1 PR5210.2 PU5201.2
PWR_1D0V_FB: PC5212.2 PR5202.2 PR5204.1 PU5201.5
PWR_1D0V_FB_A: PC5212.1 PG5223.1 PR5202.1
PWR_1D0V_PFM: PR5203.1 PU5201.3
PWR_1D0V_PG: PR5208.2 PR5209.2 PU5201.1
PWR_1D0V_PH: PC5204.2 PL5201.1 PU5201.10 PU5201.11 PU5201.16 PU5201.17 PU5201.18
PWR_1D0V_SS: PC5213.1 PU5201.22
PWR_1D0V_TON: PR5201.2 PU5201.6
PWR_1D2V: C5859.1 C5860.1 C5861.1 PG5802.1 R5802.1 U5801.6
PWR_1D05V_EN: PC8302.1 PR8308.2 PU8301.5
PWR_1D05V_FB: PC8312.1 PC8323.2 PR8302.1 PR8303.2 PU8301.6
PWR_1D05V_FB_R: PC8312.2 PR8313.1
PWR_1D05V_PGOOD: PR8304.2 PR8320.1 PU8301.4
PWR_1D05V_PHASE: PL8301.1 PU8301.1 PU8301.2 PU8301.3
PWR_1D05V_PVDD: PC8306.1 PC8307.1 PG8301.1 PG8302.1 PG8303.1 PR8301.1 PU8301.9 PU8301.10
PWR_1D05V_SVIN: PC8301.1 PR8301.2 PU8301.8
PWR_1D8V_EN: PC5406.1 PR5401.1 PR5406.2 PU5401.8
PWR_1D8V_POK: PR5402.2 PR5408.2 PU5401.7
PWR_1D35V_BOOT: PR8324.1 PU8302.1
PWR_1D35V_BOOT_R: PC8319.1 PR8324.2
PWR_1D35V_BYP: PC8318.1 PR8325.1 PU8302.15
PWR_1D35V_EN: PC8316.1 PR8322.2 PU8302.11
PWR_1D35V_IMAX: PR8323.2 PU8302.13
PWR_1D35V_LDO_P5: PC8317.1 PU8302.16 PU8302.17
PWR_1D35V_PGOOD: PR8311.2 PR8321.2 PU8302.9 PU8302.10
PWR_1D35V_PHASE: PC8319.2 PL8302.1 PU8302.6 PU8302.19 PU8302.20
PWR_1D35V_VFB: PC8308.2 PR8326.1 PR8327.2 PU8302.14
PWR_1D35V_VFB1: PC8308.1 PG8313.2 PR8327.1
PWR_2D5V: PC5411.1 PC5412.1 PC5413.1 PG5408.1 PG5409.1 PR5419.1 PU5403.3 PU5403.4
PWR_2D5V_EN: PC5427.1 PR5409.1 PR5417.2 PU5403.8
PWR_2D5V_FB: PC5411.2 PR5419.2 PR5420.1 PU5403.2
PWR_2D5V_PG: PG5112.1 PR5114.1 PR5410.2 PU5403.7
PWR_3D3V: PC4509.1 PC4510.1 PC4511.1 PC4512.1 PC4513.1 PC4525.1 PG4519.1 PG4520.1 PG4521.1 PG4522.1 PG4523.1 PG4524.1 PG4530.2 PL4501.2
PWR_3D3V_BOOT: PR4501.1 PU4501.1
PWR_3D3V_BOOT_A: PC4506.1 PR4501.2
PWR_3D3V_EN: PC4508.1 PR4508.1 PR4509.2 PU4501.11
PWR_3D3V_EN1: PC4532.1 PR4514.1 PR4516.2 PU4501.12
PWR_3D3V_FB: PC4533.1 PU4501.13
PWR_3D3V_FB2: PC4533.2 PR4506.2
PWR_3D3V_LDO: PC4507.1 PG4532.1 PU4501.16 PU4501.17
PWR_3D3V_PH: PC4506.2 PL4501.1 PU4501.6 PU4501.19 PU4501.20
PWR_3D3V_VOUT: PG4530.1 PR4506.1 PU4501.14
PWR_3V_PG: PG4531.2 PR4505.2 PU4501.9 PU4501.10
PWR_5V: PC4514.1 PC4515.1 PC4516.1 PC4517.1 PC4518.1 PC4527.1 PC4529.1 PG4507.1 PG4508.1 PG4509.1 PG4510.1 PG4511.1 PG4512.1 PG4513.1 PG4514.1 PG4527.2 PL4502.1
PWR_5V_BOOT: PR4502.1 PU4502.1
PWR_5V_BOOT_A: PC4521.1 PR4502.2
PWR_5V_EN: PC4530.1 PR4511.2 PR4512.1 PU4502.11
PWR_5V_EN1: PC4531.1 PR4504.2 PR4513.1 PU4502.12
PWR_5V_EN1_R: PR4503.2 PR4504.1 PR4515.2 PR4530.1
PWR_5V_FB: PC4526.1 PR4551.1 PU4502.13
PWR_5V_FB_A: PC4526.2 PR4507.1
PWR_5V_LDO: PC4520.1 PG4528.1 PU4502.15
PWR_5V_PG: PG4529.2 PR4510.1 PU4502.9 PU4502.10
PWR_5V_PH: PC4521.2 PL4502.2 PU4502.6 PU4502.19 PU4502.20
PWR_5V_VCC: PC4524.1 PU4502.16 PU4502.17
PWR_5V_VOUT: PG4527.1 PR4507.2 PU4502.14
PWR_CHG_ACIN: PC4420.2 PR4404.2 PR4406.1 PU4401.19
PWR_CHG_ACOK: PG4408.1 PR4426.1 PR4429.2 PR4463.2 PU4401.24
PWR_CHG_AIN: PD4408.3 PR4404.1
PWR_CHG_AMON: PR4412.1 PU4401.29
PWR_CHG_ASGATE: PU4401.13 TP4401.1
PWR_CHG_BATGONE: PC4430.1 PR4409.1 PU4401.25
PWR_CHG_BGATE: PC4429.1 PU4401.32 PU4412.4
PWR_CHG_BOOT1: PR4402.2 PU4401.12
PWR_CHG_BOOT2: PR4408.2 PU4401.4
PWR_CHG_BT1_R: PC4436.2 PR4402.1
PWR_CHG_BT2_R: PC4423.1 PR4408.1
PWR_CHG_COMP: PC4433.1 PR4411.1 PU4401.28
PWR_CHG_COMP_R: PC4431.1 PR4411.2
PWR_CHG_CSIN: PC4415.1 PC4417.2 PR4423.2 PU4401.14
PWR_CHG_CSIN_R: PG4402.2 PR4423.1
PWR_CHG_CSIP: PC4415.2 PC4416.2 PR4422.2 PU4401.15
PWR_CHG_CSIP_R: PG4401.2 PR4422.1
PWR_CHG_CSON: PC4425.2 PC4426.2 PR4425.2 PU4401.1
PWR_CHG_CSON_R: PG4406.2 PR4425.1
PWR_CHG_CSOP: PC4424.2 PC4425.1 PR4424.2 PU4401.2
PWR_CHG_CSOP_R: PG4405.2 PR4424.1
PWR_CHG_DCIN: PC4419.1 PR4403.1 PU4401.17
PWR_CHG_DCIN_R: PD4401.3 PD4407.K PR4403.2
PWR_CHG_HG1_R: PR4414.1 PU4403.4
PWR_CHG_HG2_R: PR4420.2 PU4405.4
PWR_CHG_LGATE1: PU4401.9 PU4404.4
PWR_CHG_LGATE2: PU4401.7 PU4406.4
PWR_CHG_OTGEN: PR4417.2 PU4401.20
PWR_CHG_OTGPG: PU4401.26 TP8304.1
PWR_CHG_PHASE1: PC4436.1 PL4401.1 PR4416.1 PU4401.10 PU4403.1 PU4403.2 PU4403.3 PU4404.5 PU4404.6 PU4404.7 PU4404.8
PWR_CHG_PHASE2: PC4423.2 PL4401.2 PU4401.6 PU4405.1 PU4405.2 PU4405.3 PU4406.5 PU4406.6 PU4406.7 PU4406.8
PWR_CHG_PROCHOT#: PQ4416.2 PR4435.2 PU4401.23
PWR_CHG_PROCHOT#_R: PQ4402.G PQ4416.5 PQ4416.6 PR4472.2
PWR_CHG_PROG: PR4410.2 PU4401.27
PWR_CHG_SNB: PC4435.1 PR4416.2
PWR_CHG_UGATE1: PR4414.2 PU4401.11
PWR_CHG_UGATE2: PR4420.1 PU4401.5
PWR_CHG_VBAT1: PC4440.2 PR4478.1 PU4401.31
PWR_CHG_VBATIN: PC4427.1 PC4428.1 PG4406.1 PR4407.2 PU4412.1 PU4412.2 PU4412.3
PWR_CHG_VDDP: PC4421.1 PR4405.1 PU4401.8
PWR_DCBATOUT_1D0V: PC5209.1 PC5210.1 PC5211.1 PC5214.1 PC5216.1 PG5210.2 PG5212.2 PG5214.2 PR5201.1 PU5201.7 PU5201.8 PU5201.9
PWR_DCBATOUT_1D35V: PC8309.1 PC8310.1 PC8315.1 PG8314.2 PG8315.2 PG8316.2 PG8317.2 PU8302.2 PU8302.3 PU8302.4 PU8302.5
PWR_DCBATOUT_3D3V: PC4501.1 PC4502.1 PC4503.1 PC4504.1 PG4515.2 PG4516.2 PG4517.2 PG4518.2 PU4501.2 PU4501.3 PU4501.4 PU4501.5
PWR_DCBATOUT_5V: PC4505.1 PC4519.1 PC4522.1 PC4523.1 PG4501.2 PG4502.2 PG4503.2 PG4504.2 PG4505.2 PG4506.2 PU4502.2 PU4502.3 PU4502.4 PU4502.5
PWR_DCBATOUT_VCCGTA: PC4802.1 PC4803.1 PC4804.1 PC4805.1 PG4802.1 PG4803.1 PG4804.1 PG4805.1 PG4806.1 PU4801.5
PWR_DCBATOUT_VCCGTB: PC4814.1 PC4815.1 PC4816.1 PC4817.1 PG4810.1 PG4811.1 PG4812.1 PG4814.1 PG4816.1 PU4802.5
PWR_DCBATOUT_VCCSA: PC5002.1 PC5003.1 PC5004.1 PG5002.1 PG5003.1 PU5002.5 PU5002.6 PU5002.7 PU5002.8
PWR_DCBATOUT_VCORE: PC4701.1 PC4702.1 PC4703.1 PC4704.1 PG4701.2 PG4702.2 PG4703.2 PG4704.2 PG4705.2 PG4706.2 PU4701.5
PWR_DCBATOUT_VDDQ: PC5111.1 PC5115.1 PC5116.1 PG5105.2 PG5110.2 PU5101.2 PU5101.3 PU5101.4 PU5101.5
PWR_VCCGT_BOOTA: PR4804.2 PU4801.7
PWR_VCCGT_BOOTA_RC: PC4808.1 PR4804.1
PWR_VCCGT_BOOTB: PR4810.2 PU4802.7
PWR_VCCGT_BOOTB_RC: PC4811.1 PR4810.1
PWR_VCCGT_BOOTRA: PC4808.2 PU4801.6
PWR_VCCGT_BOOTRB: PC4811.2 PU4802.6
PWR_VCCGT_COMP: PC4610.2 PR4626.2 PU4601.4
PWR_VCCGT_COMP1: PC4612.1 PC4651.1 PR4626.1
PWR_VCCGT_FB: PR4630.2 PR4633.2 PR4636.2 PR4671.2 PU4601.5
PWR_VCCGT_FB1: PC4614.1 PR4630.1
PWR_VCCGT_FB2: PC4615.2 PC4618.2 PC4619.1 PR4631.1 PR4633.1 PR4665.2 PR4671.1
PWR_VCCGT_FB_RC: PC4618.1 PR4636.1
PWR_VCCGT_FCCM#: PR4806.2 PR4812.2 PU4601.11
PWR_VCCGT_FCCM#_RA: PR4806.1 PU4801.1
PWR_VCCGT_FCCM#_RB: PR4812.1 PU4802.1
PWR_VCCGT_IMON: PC4604.2 PR4608.2 PR4672.2 PU4601.2
PWR_VCCGT_ISEN1: PC4625.1 PR4669.2 PR4821.1 PR4824.2 PU4601.9
PWR_VCCGT_ISEN2: PC4626.1 PR4635.2 PR4669.1 PR4822.2 PR4823.1 PU4601.10
PWR_VCCGT_ISUMN: PC4625.2 PC4626.2 PC4630.2 PC4633.1 PR4642.2 PR4643.2 PR4645.2 PR4646.2 PR4647.1 PR4670.2 PR4809.2 PR4815.2
PWR_VCCGT_ISUMN_GA: PG4809.1 PR4809.1 PR4822.1
PWR_VCCGT_ISUMN_GB: PG4815.1 PR4815.1 PR4824.1
PWR_VCCGT_ISUMN_P_1: PC4609.2 PC4628.2 PC4653.2 PR4647.2
PWR_VCCGT_ISUMN_P_2: PR4641.2 PR4646.1
PWR_VCCGT_ISUMN_RC: PC4623.1 PR4645.1
PWR_VCCGT_ISUMNB: PC4623.2 PR4642.1 PR4670.1 PU4601.8
PWR_VCCGT_ISUMP: PC4609.1 PC4628.1 PC4630.1 PC4653.1 PR4641.1 PR4643.1 PR4808.1 PR4816.1 PU4601.7
PWR_VCCGT_ISUMP_GA: PG4808.1 PR4808.2 PR4821.2
PWR_VCCGT_ISUMP_GB: PG4813.1 PR4816.2 PR4823.2
PWR_VCCGT_NTC: PR4616.1 PU4601.3
PWR_VCCGT_NTC1: PR4616.2 PR4617.1 PR4621.2
PWR_VCCGT_PWMA: PR4802.2 PU4601.12
PWR_VCCGT_PWMA_RA: PR4802.1 PR4817.1 PU4801.8
PWR_VCCGT_PWMB: PR4811.2 PU4601.13
PWR_VCCGT_PWMB_RA: PR4811.1 PR4818.1 PU4802.8
PWR_VCCGT_RTN: PC4619.2 PC4622.1 PR4639.1 PR4666.2 PU4601.6
PWR_VCCGT_SNB1: PC4810.1 PR4805.2
PWR_VCCGT_SNB2: PC4813.1 PR4814.2
PWR_VCCGT_SWA: PG4808.2 PL4801.1 PR4805.1 PU4801.4
PWR_VCCGT_SWB: PG4813.2 PL4802.1 PR4814.1 PU4802.4
PWR_VCCGT_VCCDA: PC4809.1 PR4803.1 PU4801.2
PWR_VCCGT_VCCDB: PC4812.1 PR4813.1 PU4802.2
PWR_VCCSA_BST: PR5001.2 PU5001.2
PWR_VCCSA_BST_RC: PC5005.1 PR5001.1
PWR_VCCSA_COMP: PC4624.1 PR4640.1 PU4601.24
PWR_VCCSA_COMP_RC: PC4601.1 PR4640.2
PWR_VCCSA_DRVH: PU5001.1 PU5002.4
PWR_VCCSA_DRVL: PU5001.5 PU5003.4
PWR_VCCSA_FB: PR4632.2 PR4637.1 PR4638.2 PU4601.25
PWR_VCCSA_FB1: PC4621.2 PR4638.1
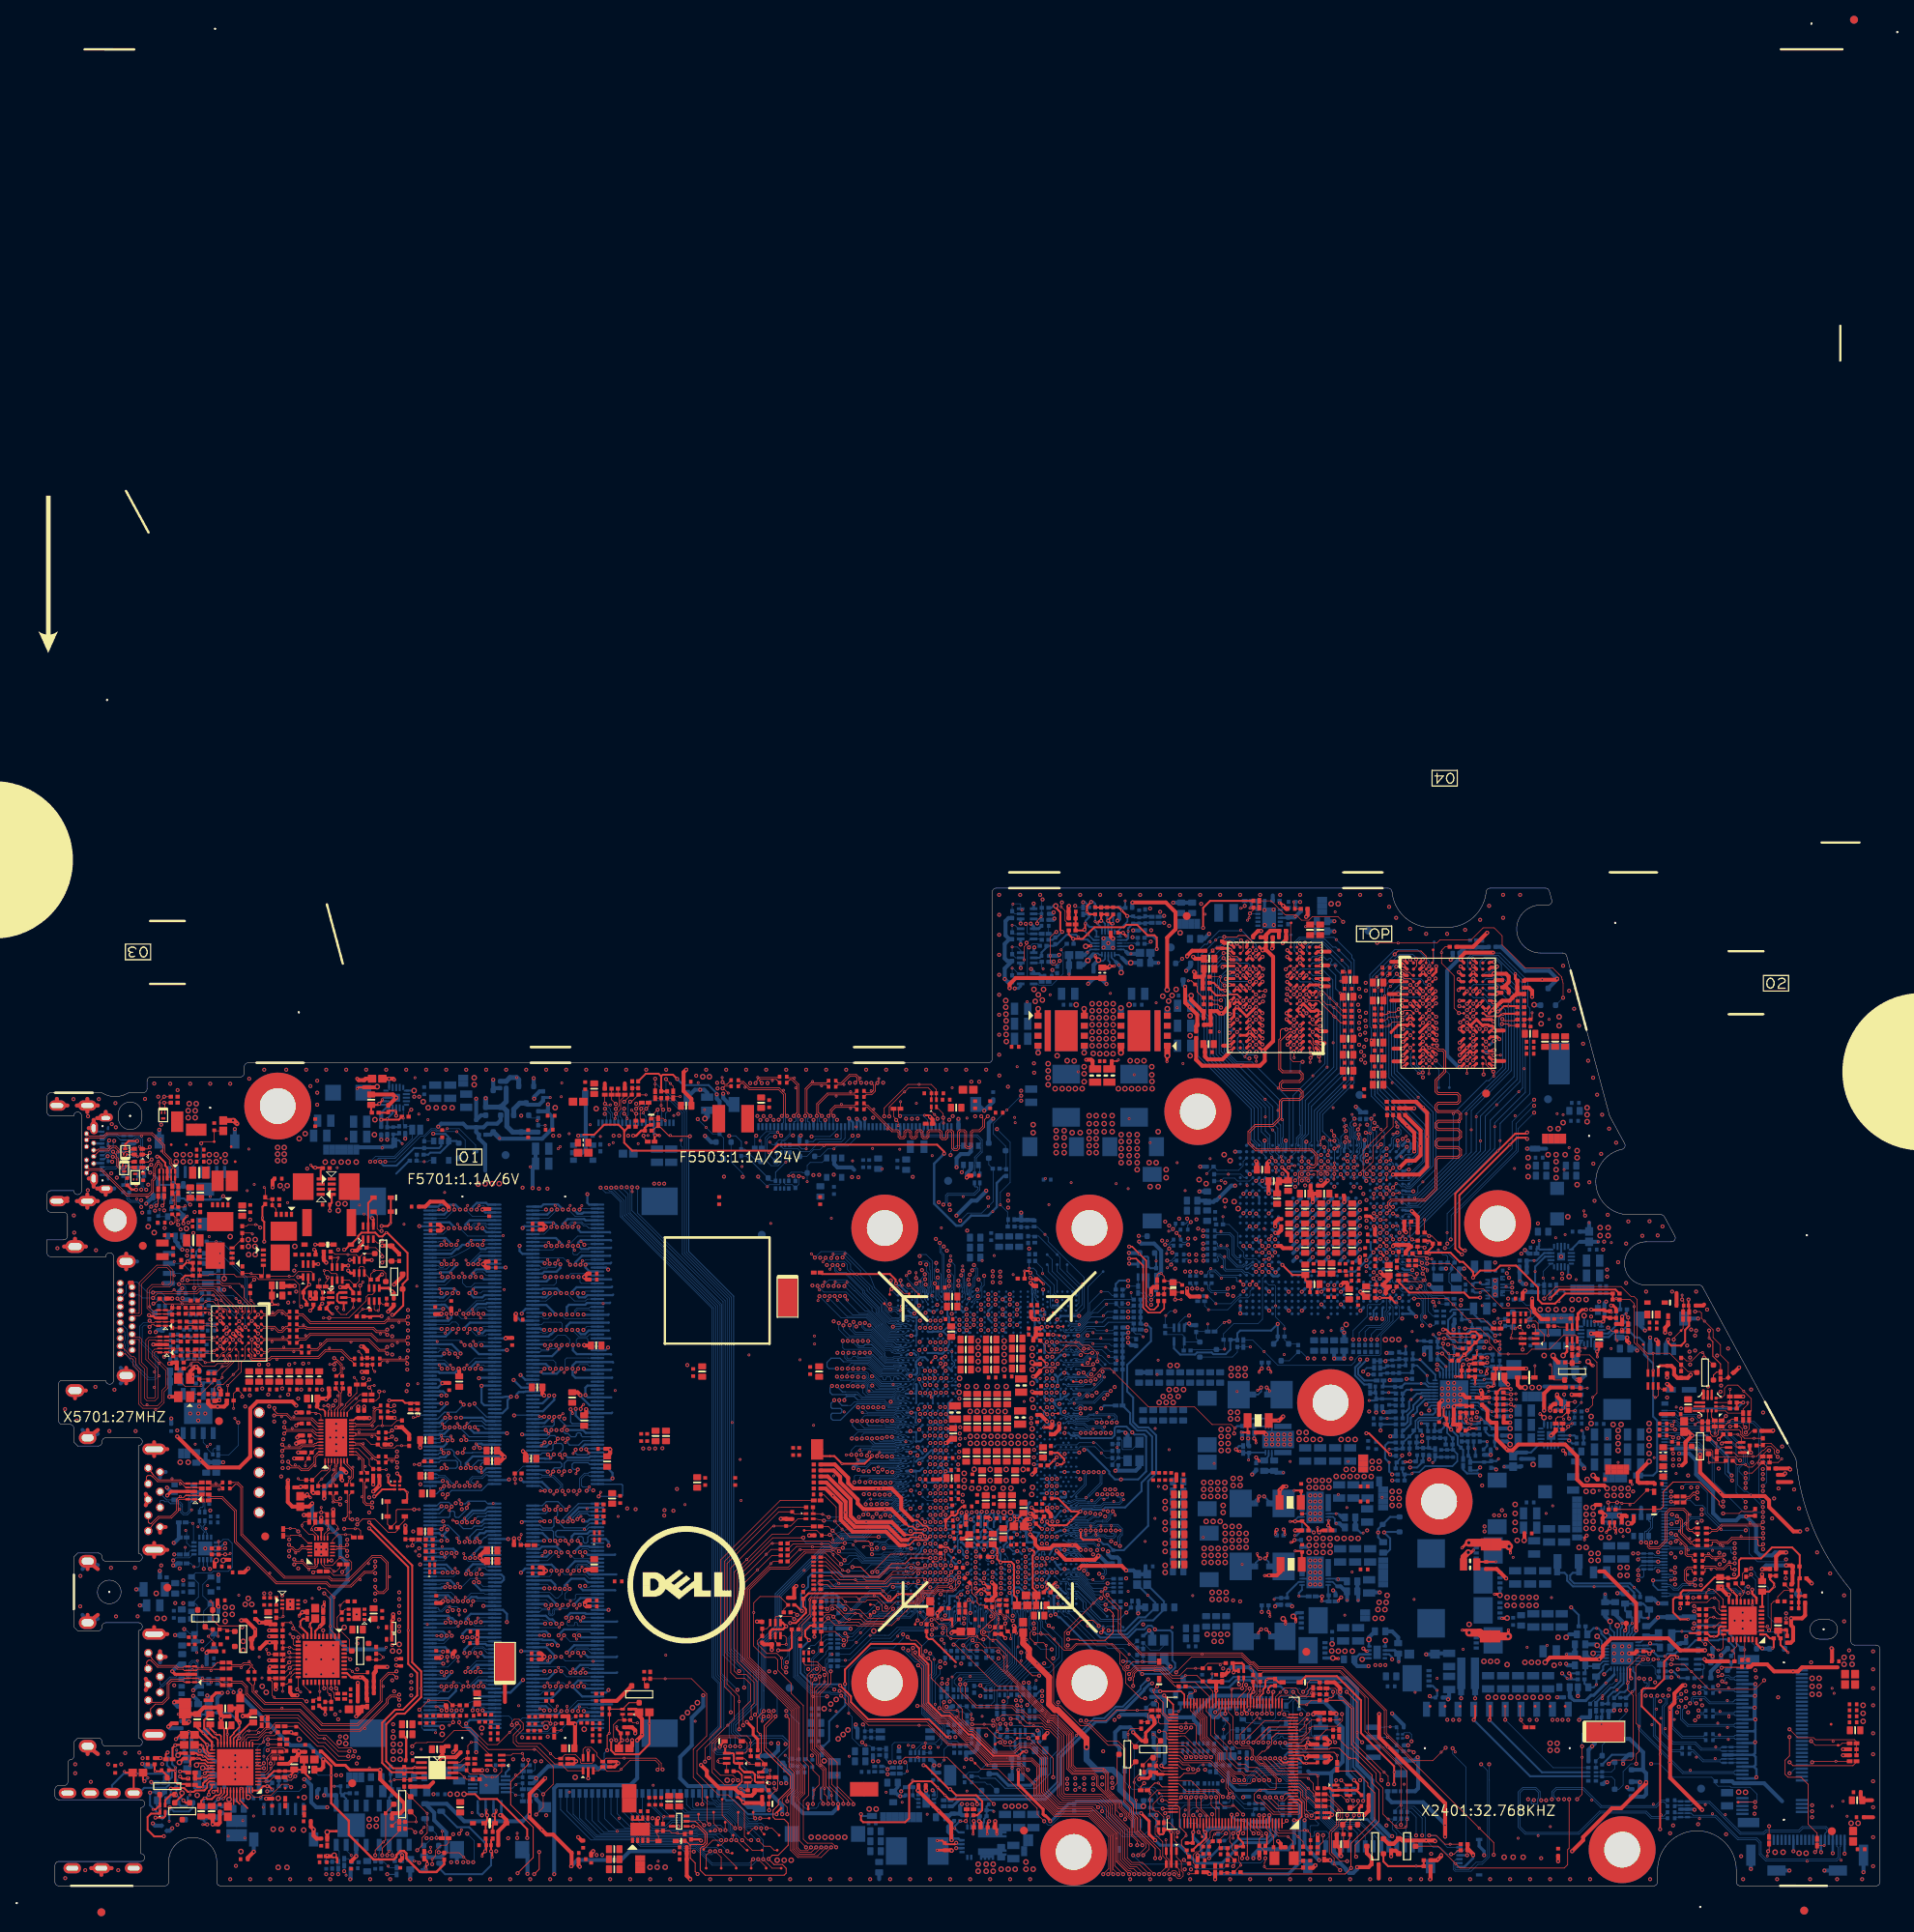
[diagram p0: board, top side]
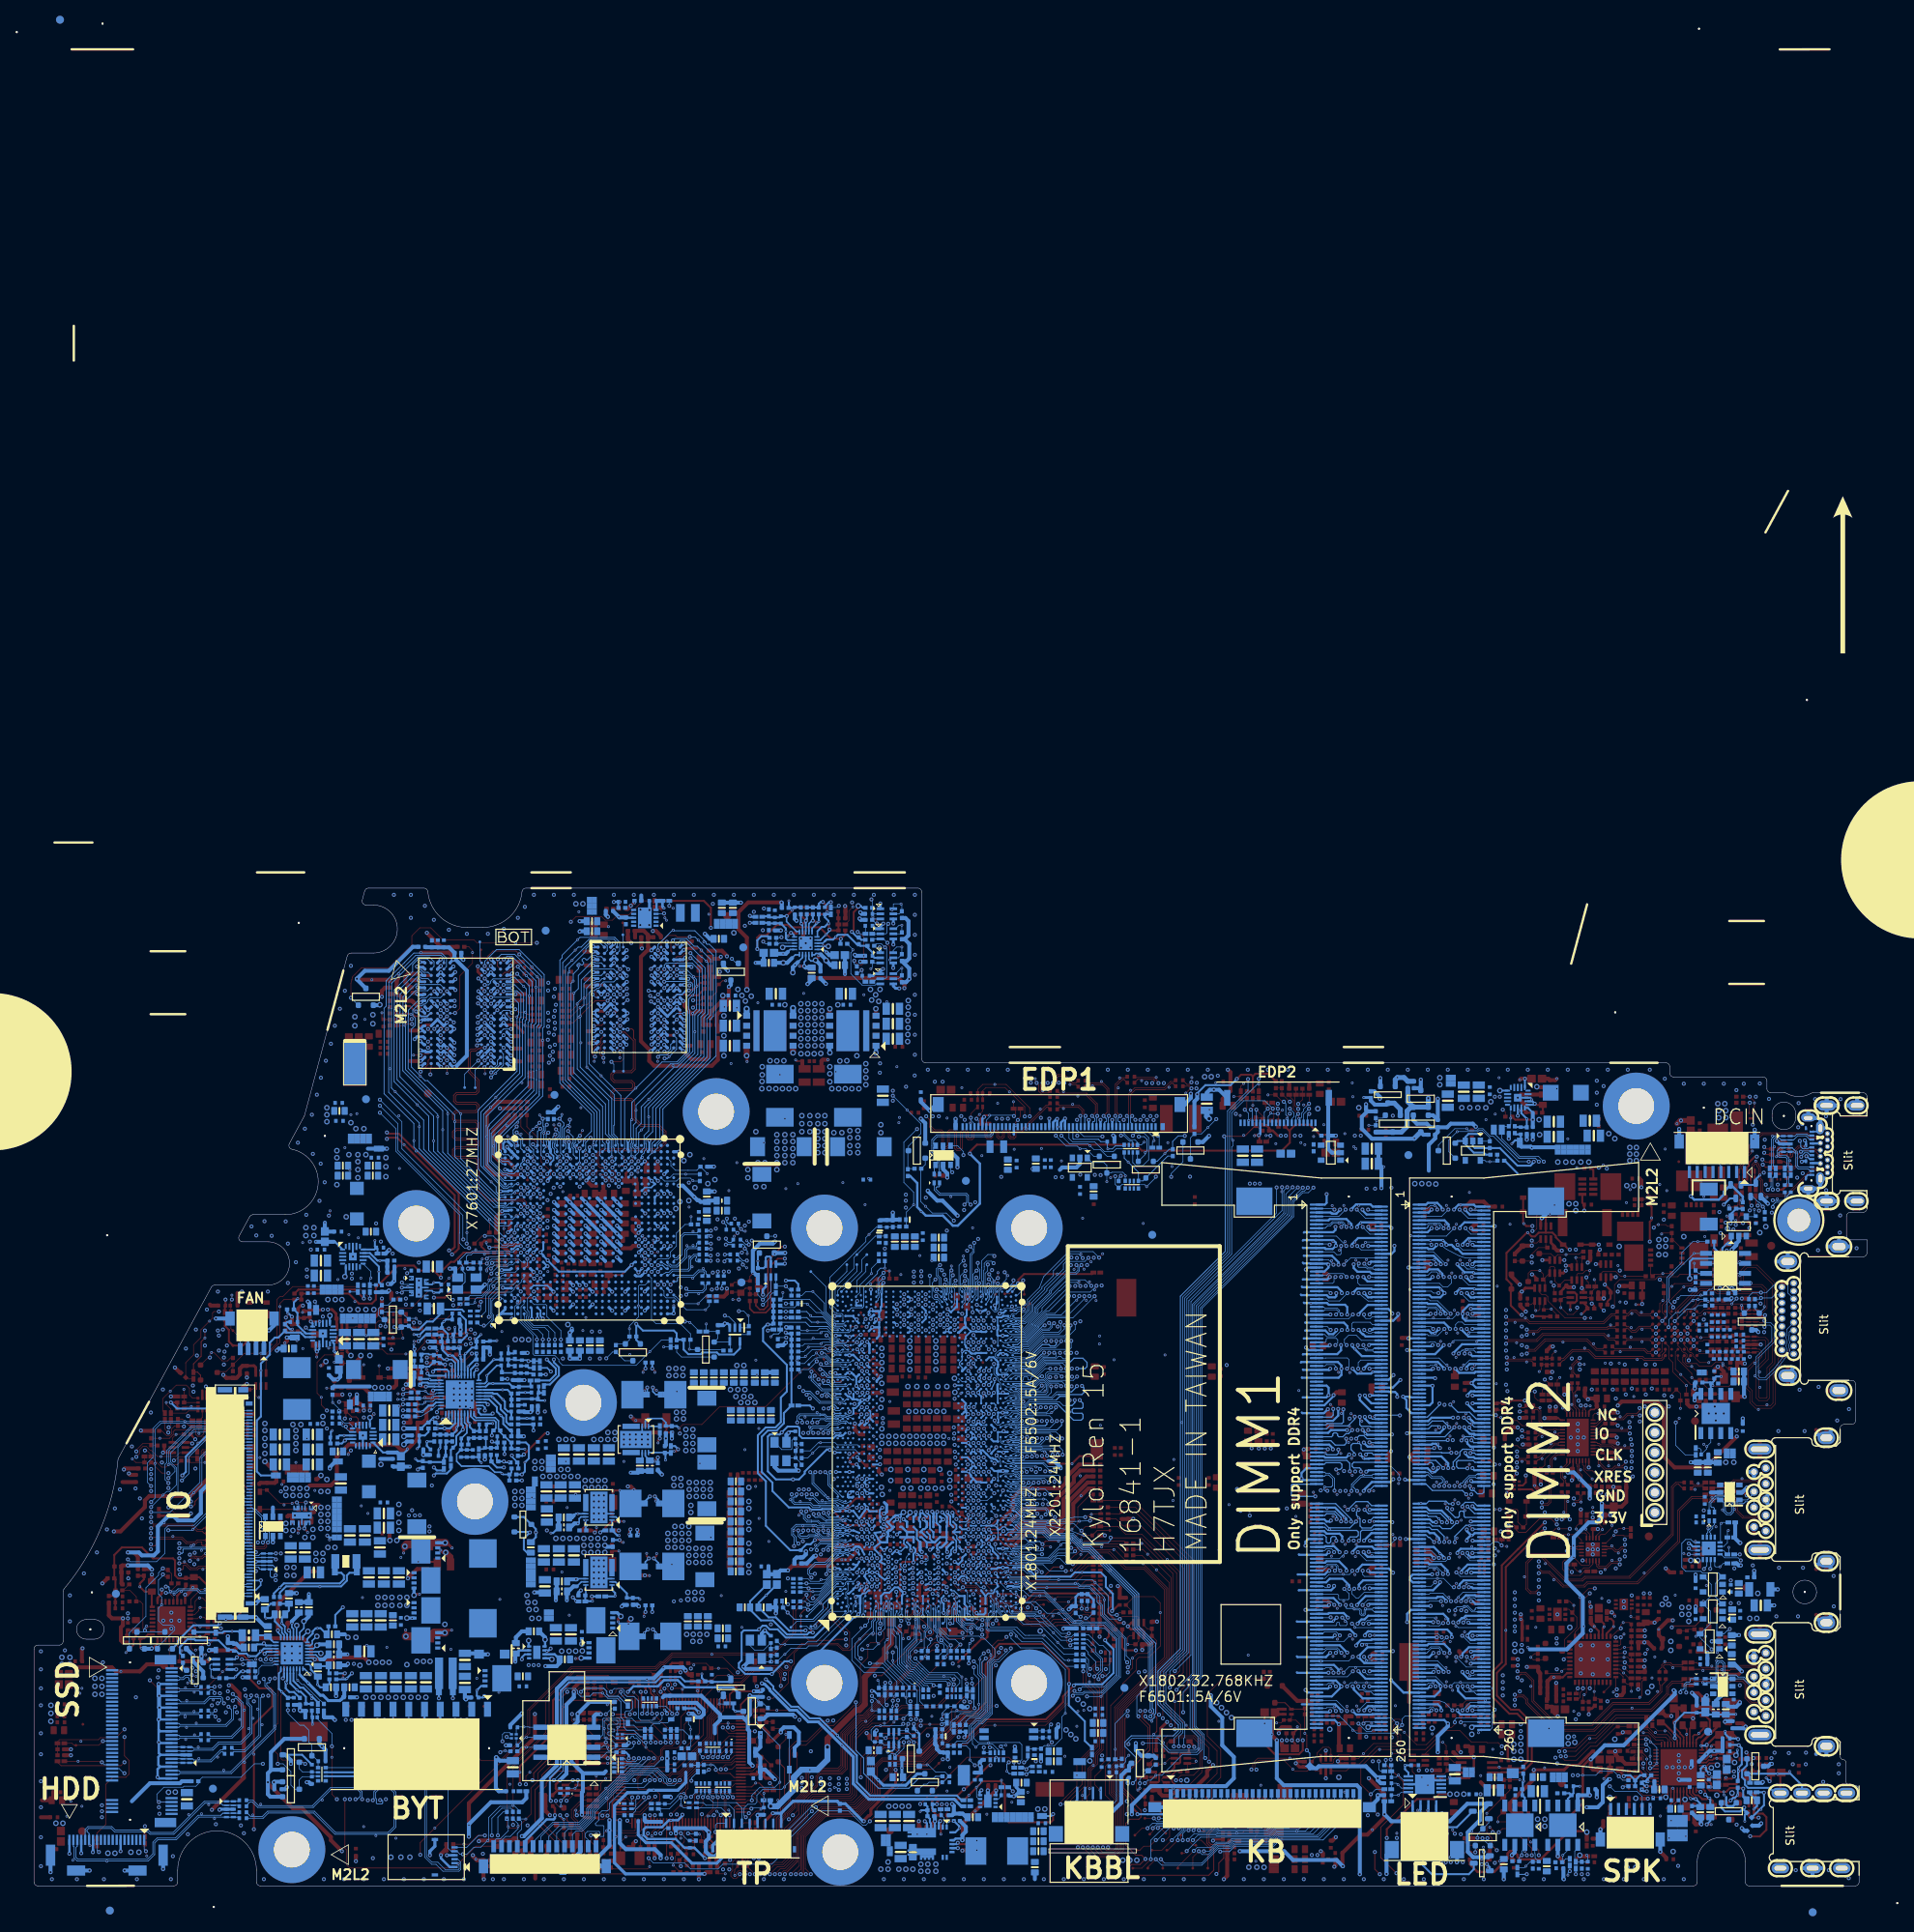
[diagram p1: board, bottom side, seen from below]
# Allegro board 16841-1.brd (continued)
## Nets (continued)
PWR_VCCSA_FB2: PC4616.2 PC4617.2 PC4620.1 PR4601.1 PR4637.2
PWR_VCCSA_FB_RC: PC4617.1 PR4632.1
PWR_VCCSA_FCCM: PU4601.29 PU5001.7
PWR_VCCSA_IMON: PC4629.2 PR4644.1 PU4601.23
PWR_VCCSA_ISUMN: PC4603.2 PC4605.1 PR4611.1 PR4613.1 PR4615.1 PR4618.2 PR4620.1 PR5004.2
PWR_VCCSA_ISUMN_P_1: PC4608.2 PR4613.2
PWR_VCCSA_ISUMN_P_2: PR4611.2 PR4625.2
PWR_VCCSA_ISUMN_R: PG5001.1 PR5004.1
PWR_VCCSA_ISUMN_RC: PC4611.2 PR4615.2
PWR_VCCSA_ISUMNB: PC4611.1 PR4620.2 PU4601.28
PWR_VCCSA_ISUMP: PC4605.2 PC4608.1 PR4618.1 PR4625.1 PR5003.2 PU4601.27
PWR_VCCSA_ISUMP_R: PG5011.1 PR5003.1
PWR_VCCSA_PWM: PU4601.30 PU5001.3
PWR_VCCSA_RTN: PC4613.1 PC4616.1 PR4602.1 PR4627.2 PU4601.26
PWR_VCCSA_SW: PC5005.2 PG5011.2 PL5001.1 PU5001.8 PU5002.1 PU5002.2 PU5002.3 PU5003.5 PU5003.6 PU5003.7 PU5003.8
PWR_VCORE_ALERT#: PR4623.2 PU4601.36
PWR_VCORE_BOOT: PR4705.2 PU4701.7
PWR_VCORE_BOOT_RC: PC4707.1 PR4705.1
PWR_VCORE_BOOTR: PC4707.2 PU4701.6
PWR_VCORE_COMP: PC4639.1 PR4656.1 PU4601.16
PWR_VCORE_COMP1: PC4640.1 PR4656.2
PWR_VCORE_FB: PR4657.1 PR4658.1 PR4660.1 PU4601.17
PWR_VCORE_FB1: PC4641.1 PR4657.2
PWR_VCORE_FB2: PC4642.2 PC4643.2 PC4644.1 PR4660.2 PR4663.2 PR4667.2
PWR_VCORE_FB_RC: PC4643.1 PR4658.2
PWR_VCORE_FCCM#: PR4706.2 PU4601.21
PWR_VCORE_FCCM#_R: PR4706.1 PU4701.1
PWR_VCORE_IMON: PC4638.1 PR4661.1 PU4601.14
PWR_VCORE_ISUMN: PC4631.1 PC4634.1 PR4648.2 PR4649.2 PR4650.1 PR4651.2 PR4652.2 PR4701.2
PWR_VCORE_ISUMN_G: PG4708.1 PR4701.1
PWR_VCORE_ISUMN_P_1: PC4635.1 PC4652.1 PR4649.1
PWR_VCORE_ISUMN_P_2: PR4650.2 PR4653.2
PWR_VCORE_ISUMN_RC: PC4632.1 PR4651.1
PWR_VCORE_ISUMNA: PC4632.2 PR4648.1 PU4601.20
PWR_VCORE_ISUMP: PC4634.2 PC4635.2 PC4652.2 PR4652.1 PR4653.1 PR4708.2 PU4601.19
PWR_VCORE_ISUMP_G: PG4707.1 PR4708.1
PWR_VCORE_NTC: PR4662.1 PU4601.15
PWR_VCORE_NTC1: PR4654.1 PR4655.2 PR4662.2
PWR_VCORE_PROG1: PR4629.1 PU4601.32
PWR_VCORE_PROG2: PR4628.1 PU4601.31
PWR_VCORE_PWM: PR4702.2 PU4601.22
PWR_VCORE_PWM_R: PR4702.1 PR4712.1 PU4701.8
PWR_VCORE_RTN: PC4637.1 PC4642.1 PR4659.2 PR4668.2 PU4601.18
PWR_VCORE_SCLK: PR4624.2 PU4601.37
PWR_VCORE_SDIO: PR4622.2 PU4601.35
PWR_VCORE_SNB: PC4706.1 PR4703.2
PWR_VCORE_SW: PG4707.2 PL4701.1 PR4703.1 PU4701.4
PWR_VCORE_VCC: PC4607.1 PR4610.2 PU4601.34
PWR_VCORE_VCC_R: PC4708.1 PR4704.1 PU4701.2
PWR_VCORE_VIN: PC4606.1 PR4612.2 PU4601.33
PWR_VCORE_VRHOT#: PR4607.2 PU4601.38
PWR_VDDQ: PC5104.1 PC5105.1 PC5107.1 PC5109.1 PG5106.1 PG5107.1 PG5108.1 PG5109.1 PG5111.1 PG5113.2 PG5115.1 PL5101.2
PWR_VDDQ_BOOT: PR5102.1 PU5101.1
PWR_VDDQ_BOOT_A: PC5114.1 PR5102.2
PWR_VDDQ_EN: PG5112.2 PR5105.1 PU5101.11
PWR_VDDQ_FB: PC5113.2 PR5101.1 PR5107.2 PU5101.14
PWR_VDDQ_FB_A: PC5113.1 PG5113.1 PR5107.1
PWR_VDDQ_ILMT: PR5103.1 PR5106.2 PU5101.13
PWR_VDDQ_PG: PG5114.2 PR5104.2 PU5101.9 PU5101.10
PWR_VDDQ_PH: PC5114.2 PL5101.1 PU5101.6 PU5101.19 PU5101.20
PWR_VDDQ_VCC: PC5112.1 PR5103.2 PU5101.16 PU5101.17
PWR_VGA_CORE_BOOT1: PR8210.1 PU8201.1
PWR_VGA_CORE_BOOT1_1: PC8211.1 PR8210.2
PWR_VGA_CORE_BOOT2: PR8211.1 PU8201.15
PWR_VGA_CORE_BOOT2_1: PC8216.1 PR8211.2
PWR_VGA_CORE_EN: PC8225.2 PQ8305.2 PR8256.2 PR8260.2 PU8201.3
PWR_VGA_CORE_EN#: PQ8305.5 PQ8305.6 PR8315.1
PWR_VGA_CORE_LGATE1: PR8224.1 PU8201.19 PU8202.8 PU8204.8
PWR_VGA_CORE_LGATE2: PU8201.17 PU8206.8 PU8208.8
PWR_VGA_CORE_PHASE1: PC8211.2 PL8201.1 PR8216.1 PU8201.20 PU8202.9 PU8204.9
PWR_VGA_CORE_PHASE2: PC8216.2 PL8202.1 PR8215.1 PU8201.16 PU8206.9 PU8208.9
PWR_VGA_CORE_PSI: PC8226.2 PR8257.2 PR8258.2 PR8259.1 PU8201.4
PWR_VGA_CORE_REFADJ: PR8222.1 PU8201.6
PWR_VGA_CORE_REFIN: PC8204.1 PR8208.1 PR8209.1 PU8201.7
PWR_VGA_CORE_RGND: PC8201.1 PC8204.2 PC8219.2 PC8223.2 PC8322.1 PR8209.2 PR8213.1 PR8220.1 PU8201.10
PWR_VGA_CORE_SS: PC8205.1 PU8201.11
PWR_VGA_CORE_TON: PR8201.2 PU8201.9
PWR_VGA_CORE_TON_1: PC8202.2 PR8201.1 PR8202.2
PWR_VGA_CORE_UGATE1: PU8201.2 PU8202.1 PU8204.1
PWR_VGA_CORE_UGATE2: PU8201.14 PU8206.1 PU8208.1
PWR_VGA_CORE_VID: PC8203.2 PR8207.2 PU8201.5
PWR_VGA_CORE_VREF: PC8201.2 PR8206.1 PU8201.8
PWR_VGA_CORE_VSNS: PC8219.1 PC8222.1 PR8212.2 PR8221.1 PU8201.12
PWR_VGA_SNUB1: PC8206.1 PR8216.2
PWR_VGA_SNUB2: PC8218.1 PR8215.2
Q6204_G: Q6504.2 Q6504.5 R6510.2
Q6205_Q: Q6503.D R6503.2
Q6502_D: Q6502.D R6514.1
Q7601_G: Q7601.2 Q7601.5 R7657.2
Q9102_G: Q9102.G R9129.1
REFIN_VREF: PC8223.1 PR8206.2 PR8208.2 PR8222.2
RESET_OUT#: EC1704.1 KBC24.73 R1706.1 R2617.1
RESET_OUT#_G: C2614.1 Q2602.G R2616.2 R2617.2
REXT: R5734.1 U5701.C6
RING2: EC2905.1 HDA27.30 R2906.2 RN2901.3(B)
RING2_R: ED2901.1 HPMIC1.3 R2906.1
RSMRST_PWRGD#: D4002.K R4029.2 R4030.2 R4031.2 R4032.2 R4033.2
RSVD_F65: CPU1.F65 TP612.1
RSVD_G65: CPU1.G65 TP613.1
RT8812_PVCC: PC8207.1 PR8223.2 PU8201.18
RTC_AUX_S5: C2503.1 D2501.3 R1730.1 R2106.1 R2472.2 R2753.1 RN1801.1(A) RN1801.2(A)
RTC_DET#: CPU1.P1 Q2505.D R2040.2
RTC_RST#: C1806.1 CPU1.AM16 EC1807.1 G1801.2 Q1802.D RN1801.3(B)
RTC_X1: C1804.2 CPU1.AM18 R1815.1 X1802.1
RTC_X2: C1803.2 CPU1.AM20 R1815.2 X1802.4
RTCRST_ON: EC1808.1 KBC24.31 Q1802.G R1816.1
RUNPWROK: D4002.A D4003.A EC1709.1 KBC24.48 R1716.1 R4002.1 R4005.2 R4011.2
SA0_CHA_DIM0: DM1.256 R1204.1 R1205.1
SA0_CHB_DIM0: DM2.256 R1302.1 R1303.1
SA1_CHA_DIM0: DM1.260 R1208.1 R1210.1
SA1_CHB_DIM0: DM2.260 R1306.1 R1307.1
SA2_CHA_DIM0: DM1.166 R1211.1 R1212.1
SA2_CHB_DIM0: DM2.166 R1310.1 R1311.1
SATA_LED#: CPU1.H1 Q6105.S R1606.2
SATA_RX_CPU_N0: C6006.1 CPU1.F20
SATA_RX_CPU_N2: CPU1.E30 ED6301.4 ED6301.7 SSD1.43
SATA_RX_CPU_P0: C6005.1 CPU1.E20
SATA_RX_CPU_P2: CPU1.F30 ED6301.5 ED6301.6 SSD1.41
SATA_RXN0_R: C6006.2 ED6001.4 ED6001.7 HDD1.18
SATA_RXP0_R: C6005.2 ED6001.5 ED6001.6 HDD1.19
SATA_TX_CPU_N0: C6003.1 CPU1.B21
SATA_TX_CPU_N2: C6303.2 CPU1.A25
SATA_TX_CPU_N2_C: C6303.1 ED6301.2 ED6301.9 SSD1.47
SATA_TX_CPU_P0: C6001.1 CPU1.A21
SATA_TX_CPU_P2: C6302.2 CPU1.B25
SATA_TX_CPU_P2_C: C6302.1 ED6301.1 ED6301.10 SSD1.49
SATA_TXN0_R: C6003.2 ED6001.1 ED6001.10 HDD1.16
SATA_TXP0_R: C6001.2 ED6001.2 ED6001.9 HDD1.15
SD_RCOMP: CPU1.AB7 R1901.1
SENSOR_I2C_SCL: R2020.2 R7014.1 TCBD1.4
SENSOR_I2C_SCL_2G: R7014.2 U7001.1
SENSOR_I2C_SDA: R2021.2 R7015.1 TCBD1.3
SENSOR_I2C_SDA_2G: R7015.2 U7001.4
SERIRQ_TPM: R9148.1 U9101.27
SIO_EXT_SCI#: CPU1.J2 R1608.2
SIO_EXT_SMI#: CPU1.L6 R802.1
SIO_EXT_WAKE#: CPU1.AD3 KBC24.116 R2041.2
SIO_PWRBTN#: CPU1.BA15 KBC24.52
SIO_RCIN#: CPU1.AW13 R1820.2
SIO_SLP_S0#: CPU1.AT11 R2478.1 R9142.2 U4007.2
SIO_SLP_S3#: CPU1.AP15 D4003.K D4004.K D4005.K PR5126.1 Q2701.G R2479.1 R4010.1 R4017.1 U4007.1
SIO_SLP_S3#_EC: KBC24.34 R2479.2
SIO_SLP_S4#: CPU1.BA16 PR5417.1 R4024.1
SKTOCC#: CPU1.A65 TP402.1
SLEEVE: EC2906.1 HDA27.31 R2911.2 RN2901.4(B)
SLEEVE_R: ED2903.2 HPMIC1.4 R2911.1
SM_DRAMRST#: CPU1.AT13 D502.2 R504.1 R505.2
SM_INTRUDER#: CPU1.AP16 R1730.2
SM_PGCNTL: CPU1.AW67 Q501.S
SM_PGCNTL_R: PR5125.1 Q501.D R506.2
SM_RCOMP_0: CPU1.AR18 R501.1
SM_RCOMP_1: CPU1.AT18 R502.1
SM_RCOMP_2: CPU1.AU18 R503.1
SMB_ALERT#: CPU1.R10 R1836.2
SMBC_THERM_NV: GPU1.D9 Q7601.1 RN7601.2(A)
SMBD_THERM_NV: GPU1.D8 Q7601.4 RN7601.1(A)
SML0_ALERT#: CPU1.W1 R1822.2 R1823.1
SML0_SMBCLK: CPU1.R9 RN1807.5(B)
SML0_SMBDATA: CPU1.W2 RN1807.6(B)
SML1_SMBCLK: CPU1.W3 Q2601.3 Q7601.6 R2459.2 RN1807.7(B)
SML1_SMBDATA: CPU1.V3 Q2601.6 Q7601.3 R2447.2 RN1807.8(B)
SML1ALERT#: CPU1.AM7 R1837.2
SP_PLLVDD: C7601.1 C7602.1 C7603.1 C7604.1 GPU1.M6 GPU1.N6 L7602.2
SPI_CK_OUT_HDMI: R5743.2 U5701.D2 U5702.6
SPI_CLK_CPU: CPU1.AV2 RN1803.8(B)
SPI_CLK_ROM: R9132.1 RN1803.1(A) RN2502.4(B)
SPI_CLK_ROM_R: EC2503.1 RN2502.1(A) SKT251.6 SPI25.6
SPI_CLK_ROM_TPM2: R9132.2 U9101.19
SPI_CS2#_R_TPM2: R9130.1 R9140.2 U9101.20
SPI_CS_CPU_N0: CPU1.AU3 R1812.2
SPI_CS_CPU_N1: CPU1.AU1 R1838.2
SPI_CS_HDMI: R5740.1 U5701.C1 U5702.1
SPI_CS_ROM_N0: R1812.1 R2501.1 SKT251.1 SPI25.1
SPI_CS_ROM_N1: Q9104.G R1838.1 R9129.2 R9130.2 R9133.2
SPI_D_IN_HDMI: U5701.C2 U5702.2
SPI_D_OUT_HDMI: U5701.D1 U5702.5
SPI_HOLD_CPU: CPU1.AU4 R1811.2
SPI_HOLD_ROM: R1811.1 R2503.2 RN1802.4(B)
SPI_HOLD_ROM_R: R2503.1 SKT251.7 SPI25.7
SPI_IRQ#_TPM2: R9119.2 R9150.2 U9101.18
SPI_SI_CPU: CPU1.AV3 R1824.2 R1825.1 RN1803.6(B)
SPI_SI_ROM: R9139.1 RN1803.3(A) RN2502.3(B)
SPI_SI_ROM_R: EC2501.1 RN2502.2(A) SKT251.5 SPI25.5
SPI_SI_ROM_TPM2: R9139.2 U9101.21
SPI_SO_CPU: CPU1.AW3 RN1803.7(B)
SPI_SO_ROM: R9134.1 RN1803.2(A) RN2503.1(A)
SPI_SO_ROM_R: EC2502.1 RN2503.4(B) SKT251.2 SPI25.2
SPI_SO_ROM_TPM2: R9134.2 U9101.24
SPI_WP_CPU: CPU1.AW2 RN1803.5(B)
SPI_WP_ROM: RN1802.3(B) RN1803.4(A) RN2503.2(A)
SPI_WP_ROM_R: RN2503.3(B) SKT251.3 SPI25.3
SPI_WR_PROT_HDMI: R5741.1 U5701.E2 U5702.3
SPK_I2C_CLK: HDA27.7 RN2701.2(A)
SPK_I2C_DATA: HDA27.6 RN2701.1(A)
SPK_ID: CPU1.AB1 R2047.2 SPK1.5
SPKR: CPU1.AW5 R1910.2 RN2702.2(A)
SRTC_RST#: C1805.1 CPU1.AN18 EC1806.1 RN1801.4(B)
SSD_DEVSLP: CPU1.J3 R6301.1 R6303.2 R6304.1
SSEQ0_A0: R3845.2 R3846.1 U3801.11
SSEQ1: R3844.1 R3852.2 U3801.3
STRAP0: GPU1.D1 R7608.1 R7619.2
STRAP1: GPU1.D2 R7609.2 R7611.1
STRAP2: GPU1.E4 R7614.2 R7615.1
STRAP3: GPU1.E3 R7625.2 R7626.1
STRAP4: GPU1.D3 R7628.2 R7629.1
STRAP_REF0_GND_N9: GPU1.F6 R7607.2
SUS_CLK: R1813.1 R2461.1
SUSACK#_R: CPU1.AP11 R1708.2
SUSCLK: CPU1.BA17 EC1803.2 R1813.2
SYS_PEX_RST_MON#: D7301.2 R7304.2 R7306.1 R7313.1 R7634.2 U7301.4
SYS_PEX_RST_MON_GPU#: GPU1.E9 R7634.1 R7643.1
SYS_PRES1#: AFTP4315.1 BATT1.7 R4301.2
SYS_PWROK: CPU1.B6 EC1702.1 KBC24.28 R1717.1
SYSPWR_PRES: KBC24.120 R2454.1 R2463.2
T_CRIT#: R2601.1 R2604.2 THM261.4
TCH_I2C_SCL: ED5501.3 R5517.2 R5521.1 TCBD1.18
TCH_I2C_SDA: ED5501.4 R5518.2 R5522.1 TCBD1.17
TCH_INTR#: ED5502.1 R5523.1 TCBD1.16
TCH_REPORT_SWITCH: R5543.1 TCBD1.14
TCH_RST#: R5544.1 TCBD1.15
TESTMODE: GPU1.AD9 R7302.1
THERM_SYS_SHDN#: Q2602.S R2601.2 R2602.1
THM_SML1_CLK: C2608.1 Q2601.4 RN2602.3(B) THM261.8
THM_SML1_DATA: C2609.1 Q2601.1 RN2602.4(B) THM261.7
TOP_MUX_N: ED3804.1 EL3801.3 R3862.2 USB1.A7
TOP_MUX_N_L: EL3801.4 R3862.1 U3802.17
TOP_MUX_P: ED3804.2 EL3801.2 R3861.2 USB1.A6
TOP_MUX_P_L: EL3801.1 R3861.1 U3802.18
TOUCH_DETECT: R2039.1 R5504.1 TCBD1.13
TOUCH_PAD_INTR#: CPU1.BA5 R404.2 R410.2
TOUCH_PANEL_INTR#: CPU1.A7 R2429.1 R5523.2 R5545.2
TOUCH_PANEL_PD#: CPU1.AY5 R5544.2
TOUCH_REPORT_SW: D2402.A R5543.2
TP_EN#: KBC24.49 R6504.1 RN2406.2(A)
TP_ON#_GATE: C6502.2 Q6502.G Q6503.G R6504.2
TP_VDD: AFTP6531.1 C6505.1 R6502.2 R6503.1 R6511.1 R6514.2 RN6501.1(A) RN6501.2(A) RN6503.1(A) RN6503.2(A) TPCON1.8
TP_VPPNC3: TP7803.1 VRAM2.A5
TP_VPPNC4: TP7804.1 VRAM2.U5
TP_VPPNC5: TP7901.1 VRAM3.A5
TP_VPPNC6: TP7902.1 VRAM3.U5
TP_VPPNC7: TP7903.1 VRAM4.A5
TP_VPPNC8: TP7904.1 VRAM4.U5
TP_WAKE_KBC#: AFTP6536.1 KBC24.33 R410.1 R6511.2 TPCON1.4
TPAN_VDD: C5516.1 C5517.1 C5537.1 R5527.2 TCBD1.20
TPCLK_C: AFTP6532.1 RN6502.3(B) TPCON1.1
TPDATA_C: AFTP6533.1 RN6502.4(B) TPCON1.2
TPM_GPIO0: R9141.1 R9142.1 U9101.29
TPM_GPIO2: Q9102.D Q9104.D R9120.1 R9131.1 R9138.2 U9101.3
TPM_GPIO4: R9133.1 U9101.13
TPM_ID: CPU1.D8 R1911.1 R1912.2
TPM_SPI_IRQ#: CPU1.M2 R9150.1
TPM_VDD14: R9147.2 U9101.14
TPM_VDD22: R9149.2 U9101.22
TPM_VSB: R9144.2 U9101.1
TPS70933_EN: Q3701.D R3739.2 R3740.1 U3702.4
TPS70933_EN_G: C3720.2 Q3701.G R3738.2
TS#_DIMM0_1: DM1.134 R1215.2
TS#_DIMM1_1: DM2.134 R1312.2
TYPEC_5V: PQ4309.3 PR4339.2
TYPEC_5V_L: PQ4309.4 PQ4309.6
TYPEC_5V_SW: PC4312.2 PR4330.2 PU4305.1 PU4305.2 PU4305.3 PU4306.1 PU4306.2 PU4306.3
TYPEC_5V_SW_R: PC4312.1 PR4330.1 PR4339.1 PU4305.4 PU4306.4
TYPEC_CON_RXN1: ED3801.4 ED3801.7 R3835.2 USB1.B10
TYPEC_CON_RXN2: ED3802.2 ED3802.9 R3837.2 USB1.A10
TYPEC_CON_RXP1: ED3801.5 ED3801.6 R3834.2 USB1.B11
TYPEC_CON_RXP2: ED3802.1 ED3802.10 R3836.2 USB1.A11
TYPEC_CON_TXN1: ED3802.4 ED3802.7 R3833.2 USB1.A3
TYPEC_CON_TXN2: ED3801.2 ED3801.9 R3839.2 USB1.B3
TYPEC_CON_TXP1: ED3802.5 ED3802.6 R3832.2 USB1.A2
TYPEC_CON_TXP2: ED3801.1 ED3801.10 R3838.2 USB1.B2
TYPEC_SMBCLK: KBC24.91 Q2417.1 R3853.1 RN2413.3(B)
TYPEC_SMBDA: KBC24.89 Q2417.4 R3854.1 RN2413.4(B)
U22_POWER_K52: CPU1.K52 R738.2
U4006_CT: C4017.1 U4006.6
UART_2_CRXD_DTXD: CPU1.AD1 R2048.2 R6803.1
UART_2_CRXD_DTXD_CON: DB1.14 R6803.2
UART_2_CTXD_DRXD: CPU1.AD2 R2049.2 R6802.1
UART_2_CTXD_DRXD_CON: DB1.13 R6802.2
USB2_ID: CPU1.AG3 R1609.1
USB2_VBUSSENSE: CPU1.AG4 R1610.1
USB20_DN0_C: ED3602.1 EL3602.2 USB2.2
USB20_DN1_C: ED3604.1 EL3603.2 USB3.2
USB20_DP0_C: ED3602.6 EL3602.3 USB2.3
USB20_DP1_C: ED3604.6 EL3603.3 USB3.3
USB30_RX_CPU_N1: CPU1.H8 R3609.1
USB30_RX_CPU_N2: CPU1.J6 R3612.1
USB30_RX_CPU_N3: CPU1.J10 ED6602.2 ED6602.9 IOBD1.11
USB30_RX_CPU_N4: C3806.1 CPU1.E10
USB30_RX_CPU_N4_C: C3806.2 U3801.4
USB30_RX_CPU_P1: CPU1.G8 R3610.1
USB30_RX_CPU_P2: CPU1.H6 R3613.1
USB30_RX_CPU_P3: CPU1.H10 ED6602.1 ED6602.10 IOBD1.10
USB30_RX_CPU_P4: C3805.1 CPU1.F10
USB30_RX_CPU_P4_C: C3805.2 U3801.5
USB30_RXDN1_C: ED3601.1 ED3601.10 R3609.2 USB2.5
USB30_RXDN2_C: ED3603.1 ED3603.10 R3612.2 USB3.5
USB30_RXDP1_C: ED3601.2 ED3601.9 R3610.2 USB2.6
USB30_RXDP2_C: ED3603.2 ED3603.9 R3613.2 USB3.6
USB30_TX_CPU_N1: C3601.1 CPU1.C13
USB30_TX_CPU_N2: C3603.1 CPU1.B13
USB30_TX_CPU_N3: CPU1.B15 ED6602.4 ED6602.7 IOBD1.13
USB30_TX_CPU_N4: C3804.1 CPU1.C15
USB30_TX_CPU_N4_C: C3804.2 U3801.7
USB30_TX_CPU_P1: C3602.1 CPU1.D13
USB30_TX_CPU_P2: C3604.1 CPU1.A13
USB30_TX_CPU_P3: CPU1.A15 ED6602.5 ED6602.6 IOBD1.14
USB30_TX_CPU_P4: C3803.1 CPU1.D15
USB30_TX_CPU_P4_C: C3803.2 U3801.8
USB30_TXDN1_C: ED3601.4 ED3601.7 R3605.2 USB2.8
USB30_TXDN1_R: C3601.2 R3605.1
USB30_TXDN2_C: ED3603.4 ED3603.7 R3611.2 USB3.8
USB30_TXDN2_R: C3603.2 R3611.1
USB30_TXDP1_C: ED3601.5 ED3601.6 R3606.2 USB2.9
USB30_TXDP1_R: C3602.2 R3606.1
USB30_TXDP2_C: ED3603.5 ED3603.6 R3614.2 USB3.9
USB30_TXDP2_R: C3604.2 R3614.1
USB30_VCCA: C3401.1 C3403.1 C3404.1 C3405.1 EC3601.1 ED3602.5 U3401.12 USB2.1
USB30_VCCB: C3507.1 C3508.1 C3512.1 C3513.1 C3514.1 PU4306.5 PU4306.6 PU4306.7 PU4306.8 R3501.1 TC3501.1 U3501.1 U3502.1
USB30_VCCC: C3517.1 C3518.1 C3519.1 C3520.1 EC3602.1 ED3604.5 U3503.1 USB3.1
USB_ADT: PD4401.2 PD4408.2 PR4327.2 PU4303.5 PU4303.6 PU4303.7 PU4303.8 PU4304.5 PU4304.6 PU4304.7 PU4304.8
USB_ADT_R1: PD4306.A PQ4308.5 PQ4308.6 PR4327.1 PR4328.2
USB_ADT_SW: PR4320.2 PR4321.1 PU4304.4
USB_ADT_SW_R: PQ4308.3 PR4321.2
USB_CAMERA_N: ED5501.1 EL5501.2 LCD1.43
USB_CAMERA_P: ED5501.6 EL5501.3 LCD1.42
USB_CPU_PN0: CPU1.AB9 U3401.2
USB_CPU_PN1: CPU1.AD6 EL3603.1
USB_CPU_PN2: CPU1.AH3 EL6601.2
USB_CPU_PN2_C: ED6601.1 EL6601.1 IOBD1.28
USB_CPU_PN3: CPU1.AD9 U3802.2
USB_CPU_PN4: CPU1.AJ1 EL5501.1
USB_CPU_PN5: CPU1.AF6 EL6603.3
USB_CPU_PN5_C: EL6603.4 IOBD1.25
USB_CPU_PN7: CPU1.AH1 R6606.2
USB_CPU_PN7_C: IOBD1.31 R6606.1
USB_CPU_PP0: CPU1.AB10 U3401.3
USB_CPU_PP1: CPU1.AD7 EL3603.4
USB_CPU_PP2: CPU1.AJ3 EL6601.3
USB_CPU_PP2_C: ED6601.6 EL6601.4 IOBD1.29
USB_CPU_PP3: CPU1.AD10 U3802.1
USB_CPU_PP4: CPU1.AJ2 EL5501.4
USB_CPU_PP5: CPU1.AF7 EL6603.2
USB_CPU_PP5_C: EL6603.1 IOBD1.26
USB_CPU_PP7: CPU1.AH2 R6605.2
USB_CPU_PP7_C: IOBD1.32 R6605.1
USB_EN#: IOBD1.58 KBC24.13 R2434.2 U3501.4 U3502.4 U3503.4
USB_OC0#: CPU1.A9 RN1601.6(B) U3401.13 U3501.3 U3502.3 U3503.3
USB_OC1#: CPU1.C9 IOBD1.57 RN1601.7(B)
USB_OC2#: CPU1.D9 RN1601.8(B)
USB_OC3#: CPU1.B9 RN1601.5(B)
USB_PN0_R: EL3602.1 U3401.11
USB_POWERSHARE_VBUS_EN: KBC24.71 U3401.5
USB_PP0_R: EL3602.4 U3401.10
USB_PWR_SHR_EN_L#: KBC24.118 R2473.1 R3401.1
USB_TYPEC_DIS: PQ4310.6 PR4338.2
USB_TYPEC_R: PC4310.1 PR4322.1 PR4336.1 PU4303.4
USB_TYPEC_SW: PQ4307.3 PR4322.2
USBC1_CC1_CONN: C3711.1 ED3806.2 R3728.2 USB1.A5
USBC1_CC2_CONN: C3712.1 ED3806.1 R3727.2 USB1.B5
USBC_DPAUX1: ED3803.2 R3830.1 U3801.27 USB1.A8
USBC_DPAUX2: ED3803.1 R3831.1 U3801.26 USB1.B8
USBCOMP: CPU1.AB6 R1603.1
V_SM_VREF_CNTA: C1222.1 CPU1.AY67 R1206.2
V_SM_VREF_CNTB: C1323.1 CPU1.BA67 R1305.2
VCONN_MON_P1: R3706.2 R3735.1 U3701.19
VCREF0: C2409.1 KBC24.25 R2424.1 R2448.1
VD_IN1_C: C2612.2 C2613.2 R2610.2 R2611.1
VGA_CORE: C7701.1 C7702.1 C7708.1 C7709.1 C7710.1 C7711.1 C7712.1 C7713.1 C7714.1 C7717.1 C7719.1 C7720.1 C7721.1 C7722.1 C7723.1 C7724.1 C7725.1 C7726.1 C7730.1 C7731.1 C7732.1 EC8968.1 GPU1.K10 GPU1.K12 GPU1.K14 GPU1.K16 GPU1.K18 GPU1.L11 GPU1.L13 GPU1.L15 GPU1.L17 GPU1.M10 GPU1.M12 GPU1.M14 GPU1.M16 GPU1.M18 GPU1.N11 GPU1.N13 GPU1.N15 GPU1.N17 GPU1.P10 GPU1.P12 GPU1.P14 GPU1.P16 GPU1.P18 GPU1.R11 GPU1.R13 GPU1.R15 GPU1.R17 GPU1.T10 GPU1.T12 GPU1.T14 GPU1.T16 GPU1.T18 GPU1.U11 GPU1.U13 GPU1.U15 GPU1.U17 GPU1.V10 GPU1.V12 GPU1.V14 GPU1.V16 GPU1.V18 PL8201.2 PL8202.2 PR8212.1 PR8309.1 PT8206.1 PT8207.1 PT8208.1
VGA_CORE_DISCHG: PQ8305.3 PR8309.2
VGA_CORE_PSI: GPU1.B4 PR8257.1
VGA_CORE_VID: GPU1.E7 PR8207.1
VGACORE_GND_SENSE_1: GPU1.F1 PR8220.2
VGACORE_VDD_SENSE_1: GPU1.F2 PR8221.2
VIDEO_CLK_XTAL_SS: GPU1.A10 R7601.1
VPP1: TP7801.1 VRAM1.A5
VPP2: TP7802.1 VRAM1.U5
VR_CAP: C2418.1 KBC24.18
VR_EN: PU4601.40 R4002.2
VR_RDY: PR4609.2 PU4601.39 TP4601.1
VR_SVID_ALERT#: PR4605.2 PR4623.1 R727.2 R728.1
VR_SVID_CLK: PR4606.2 PR4624.1 R723.2 R732.2
VR_SVID_DATA: PR4604.2 PR4622.1 R709.2
VRALERT#: CPU1.AM11 TP1708.1
VRAM_ID1: CPU1.AP8 R2029.2 R2030.1
VRAM_ID2: CPU1.U2 R2037.1 R2038.2
VREF_CPU: C2406.1 KBC24.95 R2402.2
VREG3PD: C3709.1 C3710.1 D3702.A U3702.1
WHITE_LED_BAT: EC6402.1 Q6401.C R6402.2
WIFI_RF_EN: CPU1.B7 EC6603.1 IOBD1.55 R1503.2
XCLK_BIASREF: CPU1.E42 R1803.1
XDP_BPM0: CPU1.C55 TP405.1
XDP_BPM1: CPU1.D55 TP406.1
XDP_DBRESET#: CPU1.B5 EC1706.1 R1701.2 TP1709.1
XDP_PRDY#: CPU1.D56 TP1605.1
XDP_PREQ#: CPU1.D61 TP1606.1
XDP_TCK_JTAGX: CPU1.A59 R417.1
XDP_TCLK: CPU1.B61 R406.1
XDP_TDI: CPU1.D60 R422.1
XDP_TDO_CPU: CPU1.A61 R423.1
XDP_TMS: CPU1.C60 R421.1
XDP_TRST#: CPU1.B59 CPU1.C61 R402.1
XTAL24_IN: CPU1.E37 R1809.2
XTAL24_IN_R: C1801.2 R1802.1 R1809.1 X1801.1
XTAL24_IN_R_U42: C2201.2 R2201.1 R2203.1 X2201.1
XTAL24_IN_U42: CPU1.E3 R2203.2
XTAL24_OUT: CPU1.E35 R1810.2
XTAL24_OUT_R: C1802.2 R1802.2 R1810.1 X1801.3
XTAL24_OUT_R_U42: C2202.2 R2201.2 R2202.1 X2201.3
XTAL24_OUT_U42: CPU1.C7 R2202.2
XTLI_HDMI: C5729.1 R5750.1 U5701.E8 X5701.1
XTLO_HDMI: R5748.2 R5750.2 U5701.F8
ZVM#: CPU1.AR56 TP618.1

Pads without a net: CCGDB1 6; CPU1 A3 A4 A6 A11 A26 A27 A29 A31 A33 A36 A38 A52 A69 AB4 AB11 AB12 AB62 AC3 AC63 AD11 AD12 AE62 AE63 AF8 AF9 AF12 AF13 AG62 AH7 AH8 AH9 AJ62 AK12 AK13 AK52 AK53 AK55 AK56 AK58 AK60 AK62 AK70 AL25 AL27 AL53 AL56 AL60 AL61 AL63 AM1 AM2 AM3 AM4 AM22 AM23 AM53 AM56 AM58 AN1 AN2 AN3 AN5 AN7 AN15 AN16 AN55 AP1 AP2 AP3 AP4 AP5 AP53 AT5 AT15 AU2 AU5 AU11 AU56 AU58 AU63 AW1 AW15 AW20 AW48 AW56 AW68 AW69 AW70 AW71 AY1 AY2 AY3 AY4 AY9 AY16 AY20 AY21 AY56 AY68 B2 B3 B11 B26 B27 B29 B31 B33 B36 B38 B54 B67 B69 B70 BA3 BA4 BA9 BA68 BA70 BB2 BB3 BB4 BB5 BB9 BB57 BB66 BB68 BB69 C2 C4 C11 C12 C21 C27 C28 C29 C31 C32 C33 C36 C37 C38 C40 C54 C56 C67 C68 C70 C71 D1 D3 D4 D5 D7 D12 D21 D27 D28 D29 D31 D32 D33 D36 D37 D38 D40 D54 D65 D68 D71 E1 E2 E38 E40 E61 E63 E66 E68 F6 F21 F46 F52 F60 F61 F63 F66 F70 F71 G1 G2 G3 G21 G46 G61 G68 G69 G70 G71 H2 H3 H5 H11 H63 H69 H70 J4 J5 J68 J71 K45 K46 M1 N9 N11 N12 P2 P62 U3 U4 U11 U12 V1 V2 V62 W7 W10 W11 W12; D4001 2; DB1 1 12; DCIN1 5; DM1 87 88 91 92 95 97 100 101 104 105 162 165; DM2 87 88 91 92 95 97 100 101 104 105 162 165; ED3602 3 4; ED3604 3 4; ED6601 3 4; GPU1 A16 A22 AA1 AA2 AA3 AA4 AA5 AA6 AB1 AB2 AB3 AB4 AB5 AB6 AB13 AB15 AB16 AB18 AB19 AB21 AB27 AC3 AC4 AC13 AC14 AC15 AC16 AC17 AC18 AC19 AC20 AC21 AD1 AD2 AD3 AD4 AD5 AD7 AD10 AD14 AD17 AD20 AD23 AE1 AE2 AE3 AE4 AE10 AE12 AE13 AE15 AE16 AE18 AE19 AE21 AE23 AE24 AF2 AF3 AF4 AF10 AF12 AF13 AF15 AF16 AF18 AF19 AF21 AF24 AG3 AG12 AG13 AG15 AG16 AG18 AG19 AG21 AG22 AG24 AG25 B2 B3 B6 B19 C1 C2 C3 C7 C14 D4 D5 D6 D10 D11 D12 E6 E10 F4 F5 F7 F9 F10 F19 G1 G2 G3 G4 G5 G6 G7 H3 H4 H6 J1 J2 J3 J4 J5 J6 J7 K1 K2 K3 K4 K5 K6 K7 L3 L4 M1 M2 M3 M4 M5 M7 N1 N2 N3 N4 N5 N7 P3 P4 P6 P25 R1 R2 R3 R4 R5 R6 R7 T1 T2 T3 T4 T5 T6 T7 T27 U3 U4 U6 V1 V2 V3 V4 V5 V6 V7 W1 W2 W3 W4 W5 W6 W7 W22 Y3 Y4 Y6; HDA27 1 8 9 10 11 12; HDD1 5 6 12; HDMI2 14; IOBD1 33 34 35 41; KB1 2 3; KBBL2 3; LCD1 5 29 34 35 36 38 48; PU4307 1 5; PU4501 15; PU5101 12; PU8301 7; PU8302 12; RN1812 4 5; RN1813 4 5; RN2410 4 5; RN4302 4 5; RN5501 3 6; SSD1 6 8 10 20 22 24 26 28 30 32 34 36 40 42 44 46 48 54 56 58 67 68; TCBD1 2 19; U3401 9; U3701 3 4 6 22 23 24 30 34 35 37 38 39 40; U3702 2 5; U3703 4; U3802 6 7 19 20; U4301 4; U5701 C5 D3 D7 D8 F3 F7; U5801 1 5; U9101 2 4 5 6 7 10 11 12 15 25 26 28 30 31; VRAM1 A11 A13 B11 B13 D13 E11 E13 F11 F13 M2 M4 N2 N4 P2 R2 T2 T4 U2 U4; VRAM2 A11 A13 B11 B13 D13 E11 E13 F11 F13 M2 M4 N2 N4 P2 R2 T2 T4 U2 U4; VRAM3 A11 A13 B11 B13 D13 E11 E13 F11 F13 M2 M4 N2 N4 P2 R2 T2 T4 U2 U4; VRAM4 A11 A13 B11 B13 D13 E11 E13 F11 F13 M2 M4 N2 N4 P2 R2 T2 T4 U2 U4; X1802 2 3

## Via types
v1: diameter 0.356, hole 0.178, TOP to BOTTOM, 1764 vias
v2: diameter 0.508, hole 0.254, TOP to BOTTOM, 4267 vias
v3: diameter 0.711, hole 0.406, TOP to BOTTOM, 759 vias

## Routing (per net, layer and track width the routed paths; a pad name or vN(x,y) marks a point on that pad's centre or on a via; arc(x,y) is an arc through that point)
1.8V_RUN_FB: length 4.6
  BOTTOM w0.254: PR5404.1 37.79,11.77 PR5403.2 ; PR5404.1 37.99,11.06 PU5401.2 ; PR5404.1 37.28,11.77 PC5405.2 v1(36.47,12.66)
3V3_AON_CT_2: length 2.1
  BOTTOM w0.203: U8301.10 182.25,75.63 v1(182.01,75.4)
  BOTTOM w0.254: C8306.1 181.33,75.4 v1(182.01,75.4)
3V3_AON_S0: length 186.3
  TOP w0.254: C7735.1 160.4,76.36 C7324.1 159.81,76.95 C7315.1 158.17,77.63 v2(156.9,78.91) ; v2(177.31,70.7) 177.7,70.7 178.21,70.19 180.61,70.19 180.87,70.45 181.43,70.45 R7625.1 182.06,69.68 R7614.1 R7619.1 180.66,68.16 R7609.1 R7628.1 ; v2(146.83,121.75) 146.83,124.29 147.72,125.18 PR8304.1 ; v2(190.9,74.64) 192.04,75.78 199.21,75.78 R8301.1 ; RN7605.2 171.66,76.75 172.89,75.53 173.02,75.39 179.99,75.39 180.61,74.76 v2(182.01,74.76) ; v2(140.94,119.06) 140.94,120.51 140.63,120.81 139.77,120.81 138.45,122.13 137.08,122.13 136.76,121.82 133,121.82 131.54,120.36 v2(130.32,120.36) 129.76,120.92 PR8258.1
  L3 w0.254: v2(140.94,119.06) 143.36,119.06 146.05,121.75 v2(146.83,121.75) 147.59,121.75 148.1,121.25 148.1,120.36 147.69,119.94 147.69,104.26 149.88,102.07 149.88,96.86 152.17,94.58 152.17,92.8 149.63,90.26 v2(149.63,89.37)
  L4 w0.254: v2(149.63,89.37) 149.63,89.02 152.58,86.07 153.82,86.07 155.41,84.47 156.05,84.47 156.74,83.78 156.74,79.07 v2(156.9,78.91) 156.9,78.84 v2(156.03,77.97)
  L6 w0.254: v2(190.9,74.64) 190.27,75.27 188.23,75.27 187.73,74.76 187.15,74.76 186.08,73.69 186.08,73.66 185.78,73.37 184.3,73.37 183.92,73.75 183.03,73.75 v2(182.01,74.76) ; v2(156.31,71.41) 156.03,71.69 v2(156.03,77.97)
  BOTTOM w0.254: GPU1.G12 168.11,80.87 v2(168.47,80.51) 168.11,80.15 GPU1.G10 168.11,80.05 v2(167.55,79.5) 167.55,79.48 166.14,78.07 157.74,78.07 v2(156.9,78.91) 156.53,79.28 GPU1.AA9 ; 178.2,72.99 178.46,73.24 180.61,73.24 ; v2(130.32,120.36) 130.37,120.31 PR8316.1 ; v2(140.94,119.06) 140.94,120.16 140.42,120.69 139.59,120.69 PR8203.1 ; Q7301.G 156.31,69.39 R7303.2 v2(156.31,71.41) 155.47,70.57 151.53,70.57 151.18,70.22 R7631.1 151.12,69.4 R7312.2 150.29,68.16 149.7,67.58 148.13,67.58 147.91,67.79 146.07,67.79 145.8,67.52 143.91,67.52 143.13,68.3 U7301.5 ; GPU1.AB8 155.59,78.41 v2(156.03,77.97) 156.45,78.39 GPU1.AA8 ; 181.25,72.6 182.14,71.72 182.9,71.72 183.92,70.7 184.73,70.7 R7649.2 186.01,71.16 Q7606.G ; PR8311.1 v2(190.9,74.64)
  vias: v1(182.27,73.75)
3V3_AON_S0_DISCHG: length 8.6
  BOTTOM w0.089: PQ8306.3 125.83,114.63 125.98,114.47 127.61,114.47 129.05,115.91 129.05,118.58 128.8,118.83 v1(128.8,118.96) 128.8,119.01 PR8316.2
3V5V_CT1: length 2.2
  TOP w0.254: v1(198.04,44.92) 198.04,44.99 v2(198.48,45.43) 198.47,45.43 C4001.1
  BOTTOM w0.203: v2(198.48,45.43) 198.38,45.53 U4001.12
3V5V_CT2: length 2.1
  TOP w0.254: v1(199.26,44.84) 199.26,45.3 v2(199.13,45.43) 199.08,45.48 C4002.1
  BOTTOM w0.203: U4001.10 199.18,45.47 v2(199.13,45.43)
3V5V_S0_ON: length 9.2
  TOP w0.089: R4010.2 198.34,48.65 v2(198.27,48.73) v2(199.41,48.73) 199.89,48.73 v1(200.02,48.6) 201.52,48.6 C4003.2 203.89,50.3 D4005.A
  BOTTOM w0.089: U4001.3 198.38,48.62 v2(198.27,48.73) ; U4001.5 199.18,48.49 v2(199.41,48.73)
3V_5V_EN: length 127.5
  TOP w0.127: R4009.1 165.5,6.05 165.06,5.61 165.06,5.34 C4009.1 164.66,5.65 R4006.1 164.55,6.68 D4001.1 165.12,8.35 v2(165.12,8.98) ; v2(193.31,59.4) 193.19,59.52 PR4515.1 ; v1(194.08,60.41) 194.03,60.36 PR4515.1 ; PR4515.1 192.43,59.6 191.87,59.6 191.61,59.35 PR4516.1
  L4 w0.127: v2(215.72,48.09) 214.26,48.09 208.47,53.89 208.47,55.25 207.62,56.09 206.24,56.09 205.38,56.96 205.38,57.27 205.38,59.28 205.13,59.54 197.49,59.54 196.17,60.86 194.95,60.86 193.49,59.4 v2(193.31,59.4)
  L6 w0.127: v2(165.12,8.98) 165.56,8.53 167.67,8.53 169.47,10.34 179.5,10.34 180.87,11.71 190.86,11.71 191.9,12.75 195.85,12.75 197.12,14.02 198.07,14.02 198.51,14.46 200.61,14.46 200.91,14.76 204.2,14.76 204.39,14.95 212,14.95 218.52,21.47 218.52,27.15 218.4,27.28 218.4,28.41 217.23,29.58 217.23,33.09 217.25,33.11 217.25,38 215.98,39.27 215.98,40.53 216.24,40.79 216.24,47.58 v2(215.72,48.09)
3V_5V_POK: length 316.8
  TOP w0.102: v2(91.71,9.61) EC1705.1 91.74,10.45 C1710.1 v1(92.61,12.18) 92.81,12.38 92.81,13.52 R1728.2
  L3 w0.102: v2(131.72,12.91) 132.18,13.37 132.18,13.99 133.71,15.52 134.69,15.52 136.86,17.69 149.62,17.69 149.87,17.44 151.79,17.44 v2(152.57,18.22) 153.36,19.01 158.26,19.01 159.46,17.82 165.7,17.82 166.57,18.68 167.86,18.68 173.79,12.75 193,12.75 195.41,12.75 197.11,11.05 207.58,11.05 210.18,13.65 214.78,13.65 218.53,17.41 220.77,17.41 222.02,18.66 222.02,20.16 221.71,20.47 221.71,29.22 220.11,30.82 220.11,34.89 221.58,36.36 221.58,43.8 220.44,44.95 220.44,49.36 218.79,51.01 218.79,53.38 217.39,54.77 217.39,57.94 214.35,60.99 214.35,64.27 212.57,66.05 212.57,67.58 211.53,68.62 211.53,68.85 211.27,69.1 210.48,69.1 210.03,69.56 210.03,70.6 209.62,71 209.16,71 208.58,71.59 207.22,71.59 205.75,73.06 200.76,73.06 198.93,74.89 197.75,74.89 197.38,74.52 197.38,74.51 v2(197.12,74.26)
  L4 w0.102: v2(116.86,10.37) 116.35,10.88 115.56,10.88 115.02,10.34 110.7,10.34 108.37,8.01 96.69,8.01 94.7,9.99 92.1,9.99 v2(91.71,9.61) 91.68,9.64 88.89,9.64 88.27,9.03 83.85,9.03 82.48,7.66 82.48,7.39 81.45,6.36 72.84,6.36 71.59,5.11 64.83,5.11 64.64,4.91 58.95,4.91 58.01,3.97 50.95,3.97 50.32,3.35 47.08,3.35 46.23,2.5 39.64,2.5 38.5,1.36 37.1,1.36 v2(36.98,1.48)
  L6 w0.102: v2(131.72,12.91) 131.21,13.43 131.21,14.06 130.96,14.31 129.36,14.31 128.87,13.82 128.87,12.88 128.33,12.34 127.25,12.34 126.15,11.24 117.72,11.24 v2(116.86,10.37) ; v2(192.68,62.44) 193.19,61.94 193.35,61.94 193.4,61.89 193.82,61.89 193.87,61.94 195.02,61.94 197.38,59.57 202.23,59.57 204.5,61.85 204.5,67.9 200.64,71.77 199.61,71.77 v2(197.12,74.26)
  BOTTOM w0.102: R4033.1 152.67,18.33 v2(152.57,18.22) ; PG4529.1 196.97,74.1 v2(197.12,74.26) ; PG4531.1 v2(192.68,62.44) ; v2(116.86,10.37) 116.78,10.3 PR5210.1 ; PR5406.1 v2(36.98,1.48)
3V_5V_POK#: length 3.5
  TOP w0.089: v1(88.08,12.41) 88.29,12.41 88.54,12.15 R1726.1 88.98,12.17 Q1701.6 89.31,13.15 89.56,13.4 89.56,13.58 89.33,13.8 Q1701.5
3V_5V_POK_C: length 3.9
  TOP w0.089: R1728.1 91.29,13.43 91.29,12.5 R1727.2 ; R1728.1 91.84,13.98 v1(91.84,14.69) ; R1728.1 Q1701.2
5V_AUX_S5: length 8
  TOP w0.508: v2(200.68,69.68) 200.68,69.25 v1(200.93,69)
  L3 w0.508: v2(198.01,74.26) 198.01,72.23 198.27,71.98 198.27,71.97 200.55,69.68 v2(200.68,69.68)
  BOTTOM w0.508: v2(198.01,74.26) 197.81,74.05 PR4510.2 ; PG4528.2 v2(200.68,69.68)
5V_HDD_SIP:
  vias: v1(223.54,3.14) v1(227.86,3.26) v3(222.52,4.15) v3(223.41,4.15)
5V_HDMI_S5: length 1.3
  TOP w0.508: 10.48,76.68 HDMI2.18 10.8,76.68
  vias: v1(16.15,79.34)
5V_S0: length 270.5
  TOP w0.508: v2(67.65,2.44) 67.51,2.58 EC8988.1 ; v2(205.51,70.32) 205.51,70.93 205.89,71.31 R2612.1 ; v2(122.25,114.09) 122.25,114.59 123.04,115.38 PR8223.1 ; v2(25.55,40.35) 25.04,39.84 EC8992.1 ; EC8987.1 201.52,46.32 201.26,46.06 v3(200.81,46.06) ; EC8985.1 v2(191.92,3.14)
  L3 w0.254: v2(205.76,62.06) 204.29,63.54 204.29,68.11 203.09,69.3 203.09,69.89 203.52,70.32 v2(205.51,70.32)
  L3 w0.508: v2(122.25,114.09) 122.25,113.46 122.66,113.05 122.66,103.52 116.89,97.75 116.89,92.7 v2(115.51,91.32) ; v2(64.28,95.34) 64.28,95.97 66.44,98.13 66.44,99.78 65.36,100.86 51.39,100.86 50.3,101.95 43.72,101.95 43.71,101.94 43.07,101.94 41.94,103.08 27.44,103.08 25.67,101.31 17.93,101.31 15.26,98.64 15.26,95.08 14.75,94.58 14.75,88.81 13.78,87.84 11.6,87.84 11.15,87.39 11.15,85.48 v3(12.85,83.78)
  L4 w0.254: v2(205.51,70.32) 202.77,73.05 197.06,73.05 196.24,73.87 187.85,73.87 187.09,74.64 187.09,75.4 186.46,76.03 v2(186.08,76.03)
  L4 w0.508: v2(65.04,95.34) 67.46,92.92 82.25,92.92 82.5,93.18 112.74,93.18 114.6,91.32 v2(115.51,91.32)
  L6 w0.508: v2(205.76,62.06) 205.63,62.06 202.33,58.76 202.33,50.9 202.46,50.77 202.46,47.46 201.06,46.06 v3(200.81,46.06) ; v3(98.7,15.89) 94.74,11.92 87.44,11.92 86.56,11.04 85.41,11.04 83.71,9.33 82.36,9.33 81.22,8.2 81.22,7.17 79.6,5.55 75.42,5.55 72.31,2.44 v2(67.65,2.44)
  BOTTOM w0.203: U8301.4 v2(186.08,76.03)
  BOTTOM w0.508: v2(13.8,70.38) 14.06,70.65 D5701.3 ; v2(115.51,91.32) 115.51,92.47 116.05,93 117.01,93 117.34,93.32 ED5501.5
  vias: v1(23.01,6.31) v1(64.92,93.69) v1(65.17,93.94) v1(200.17,44.41) v1(228.62,8.85) v2(206.27,42.25) v2(206.78,41.74) v3(13.61,83.02) v3(24.62,4.37) v3(28.72,7.2) v3(29.36,2.35) v3(29.74,7.2) v3(30.47,2.35) v3(199.92,45.17) v3(200.81,45.17) v3(214.85,11.92) v3(215.72,11.9) v3(229.13,7.96) v3(230.02,7.96)
5V_S5: length 384.3
  TOP w0.254: v2(170.58,54.82) 167.89,57.52 v2(167.56,57.52)
  TOP w0.381: EC8948.1 44.42,28.87 v2(44.34,28.79)
  TOP w0.508: EC8947.1 51.94,17.33 v2(51.58,16.98) ; PC5410.1 45.11,3.47 v2(45.11,3.9) ; v2(66.57,2.5) 66.62,2.55 EC8946.1 64.28,6.51 63.44,6.51 v1(62.83,7.13) 61.28,8.67 v2(61.28,9.1) 61.28,11.7 v2(63.27,13.68) ; v2(114.89,5.8) 114.84,5.86 114.84,7.93 v1(113.25,9.51) 110.67,12.1 110.64,12.1 v2(110.61,12.13) 110.69,12.21 EC8941.1 ; PC5401.1 38.63,3.14 v2(39.26,3.77) ; PR4610.1 182.95,60.44 182.95,59.32 183.41,58.86 EC8944.1 184.09,56.78 185.52,55.36 186.13,55.36 186.86,56.09 192.81,56.09 194.33,54.57 194.33,51.65 195.09,50.89 197.76,50.89 v3(198.14,50.51) ; v3(21.48,41.36) 21.28,41.16 EC8949.1 ; v2(31.64,61.05) 31.14,61.56 26.69,61.56 25.8,60.67 25.8,54.54 24.44,53.17 20.47,53.17 v1(19.52,54.12) v2(16.53,57.11) ; v3(22.37,41.36) 22.45,41.44 C3402.1 ; PR4813.2 v2(158.52,45.17)
  L4 w0.508: v2(31.64,75.53) 31.9,75.53 32.53,76.16 32.53,78.03 35.37,80.86 v2(36.98,80.86) ; v2(39.26,3.77) 40.15,4.66 44.34,4.66 v2(45.11,3.9) 45.36,4.15 45.36,6.82 48.19,9.65 59.04,9.65 59.58,9.1 v2(61.28,9.1)
  L6 w0.254: v2(151.79,56.86) 153.69,54.95 166.31,54.95 167.56,56.2 v2(167.56,57.52)
  L6 w0.508: 152.93,35.47 152.8,35.34 152.8,30.54 155.69,27.65 167.56,27.65 v2(167.84,27.93) 169.13,26.63 191.91,26.63 192.16,26.38 195.85,26.38 197.26,27.79 201.45,27.79 201.82,28.15 201.82,30.44 202.46,31.08 202.46,35.65 198.9,39.2 198.9,41.49 196.64,43.75 194.99,43.75 194.33,44.41 194.33,50.13 195.09,50.89 197.76,50.89 v3(198.14,50.51) ; 152.93,35.47 153.18,35.72 155.77,35.72 v2(155.98,35.52) ; 152.93,35.47 152.93,42.12 154.45,43.65 ; 154.45,43.65 153.56,44.54 153.56,45.81 152.42,46.95 152.42,53.94 151.79,54.57 v2(151.79,56.86) ; 154.45,43.65 156.99,43.65 v2(158.52,45.17) ; v2(36.98,80.86) 36.98,81.24 39.31,83.57 39.31,87.25 46.55,94.5 46.55,95.48 49.07,98 58.45,98 60.48,100.04 v2(61.87,100.04) ; v2(31.64,75.53) 31.64,72.73 33.42,70.95 33.42,65.75 31.26,63.59 31.26,61.43 v2(31.64,61.05)
  BOTTOM w0.254: PR4635.1 170.76,54.65 v2(170.58,54.82)
  BOTTOM w0.305: PC5001.1 166.67,29.43 PU5001.6 ; Q6505.E 143.34,24.54 144.04,25.23 150.13,25.23 151.04,26.14 152.79,26.14 153.56,25.36 156.67,25.36 v2(157.37,24.66) ; PU5201.21 115.95,5.8 115.74,6.01 115.09,6.01 v2(114.89,5.8) ; U4006.4 v2(110.61,12.13)
  BOTTOM w0.508: Q6402.E 48.09,3.64 50,3.64 50.69,4.34 50.69,6.82 49.17,8.34 49.17,9.29 Q6401.E 50.76,10.44 52.98,8.22 60.4,8.22 v2(61.28,9.1) PR5118.2 ; PU5403.6 44.72,4.28 v2(45.11,3.9) ; R3402.1 16.73,44.41 R3406.1 16.16,43.59 v2(16.09,43.59) ; PR4803.2 156.18,35.72 v2(155.98,35.52) ; PC5202.1 114.45,7.5 114.45,6.9 114.89,6.46 114.89,5.8 v2(114.89,5.8) ; PU5401.6 v2(39.26,3.77) ; v2(16.02,40.73) 16.29,40.73 16.54,40.98 R3405.1 ; v2(61.87,100.04) 61.87,100.29 62.55,100.98 PR4303.1 ; v2(66.57,2.5) 67.36,3.29 72.89,3.29 74.01,4.41 v2(79.65,4.41) ; v2(167.84,27.93) 166.42,27.93 166.03,28.31 PC5001.1 ; PR4704.2 v2(151.79,56.86) ; ED6601.5 202.46,48.09
  vias: v1(24.35,36.94) v1(201.04,48.42) v1(201.32,51.01) v2(16.53,57.87) v2(201.44,50.13) v3(22.63,35.39) v3(22.63,34.5) v3(22.63,33.62) v3(23.52,35.39) v3(23.52,34.5) v3(43.96,18.88) v3(43.96,17.99) v3(43.96,17.11) v3(44.85,17.99) v3(44.85,17.11) v3(198.14,49.62) v3(199.03,50.51) v3(199.03,49.62) v3(199.92,50.51) v3(199.92,49.62) v3(200.81,50.51) v3(200.81,49.62)
5V_VCONN_EN: length 2
  TOP w0.089: R3734.2 29.81,34.07 v1(29.99,34.25) 29.99,35.16 U3703.3
5V_VCONN_P1: length 15.5
  TOP w0.508: R3706.1 v2(29.05,24.98)
  L3 w0.508: v2(29.05,24.98) 28.85,24.98 27.33,26.5 27.33,29.81 27.66,30.14 28.75,30.14 29.76,31.15 29.76,33.13 v2(32.79,36.16)
  vias: v1(33.68,36.54)
5V_VCONN_P1_CCG4: length 2.6
  TOP w0.254: U3701.8 33.57,32.76 v1(33.4,32.93) 33.4,33.31 R3736.2
20V_DCBATOUT:
  vias: v1(186.2,41.74)
+3V_1D8V_AVDD: length 14
  TOP w0.203: 28,13.77 27.91,13.68 27.62,13.68 27.61,13.67 HDA27.3
  TOP w0.254: C2743.1 31.41,14.77 R2748.2 ; C2743.1 31.19,14.59 C2729.1 C2747.1 28.82,14.59 28,13.77 ; C2743.1 31.39,14.52 31.01,14.14 31.01,14.06 v2(30.88,13.93) ; v1(33.42,13.63) 32.63,14.42 R2748.2 ; R2748.2 R2749.1
  BOTTOM w0.254: R2743.2 30.07,14.06 30.75,14.06 v2(30.88,13.93) ; R2743.2 28.8,14.06 R2742.1 ; R2743.2 R2744.2
+3V_1D8V_AVDD_IO: length 11.3
  TOP w0.203: HDA27.18 24.1,18.47 v2(24.4,18.78)
  BOTTOM w0.254: v2(24.4,18.78) 24.4,20.79 23.18,22.01 C2744.1 20.59,22.01 R2751.1 20.21,21.78 R2750.2 C2745.1 17.8,21.78 17.77,21.8 v1(16.66,21.8)
+5V_AVDD: length 1.1
  TOP w0.203: 22.44,11.15 22.9,11.61 HDA27.40
  vias: v1(22.44,11.13)
+5V_KB_BL: length 0.7
  TOP w0.254: v2(96.62,10.4) 96.67,10.35 AFTP6529.1
  vias: v1(98.27,15.3)
+5V_PVDD: length 2.2
  TOP w0.203: HDA27.46 25.3,11.51 v3(25.55,11.26) ; HDA27.41 23.3,11.17 v3(23.11,10.98)
  vias: v1(24.66,12.41)
+V1.00A_SIP: length 50
  TOP w0.508: v2(131.08,40.35) 131.4,40.66 136.48,40.66 v2(137.05,40.09) ; C2121.1 119.57,46.82 v2(119.8,46.59) ; R1803.2 127.93,57.39 128.54,58 v2(128.54,58.76) ; R2110.1 124.11,46.33 124.35,46.57 124.37,46.57 124.42,46.57 124.5,46.6 124.54,46.61 v2(124.86,46.61) ; v2(131.29,42.69) 130.68,43.3 v1(130.2,43.3) 127.81,43.3 127.4,42.89 126,42.89 125.5,43.39 125.5,44.03 124.87,44.66 v2(124.86,44.66)
  L3 w0.508: v2(131.29,42.69) 131.08,42.49 v2(131.08,40.35)
  L6 w0.508: 124.1,46.95 124.1,50.6 125.03,51.52 125.22,51.52 126,52.31 126,56.22 v2(128.54,58.76)
  BOTTOM w0.127: v2(125.32,33.36) 125.32,35.1 CPU1.L1 ; v2(122.65,34.33) 122.58,34.4 122.58,35.09 CPU1.T1
  BOTTOM w0.152: v2(131.29,42.69) CPU1.A14 ; CPU1.AK20 114.39,46.26 114.13,46.53 v2(114.13,47.15)
  BOTTOM w0.254: CPU1.K17 125.21,44.31 v2(124.86,44.66) ; CPU1.A10 130.53,40.35 v2(131.08,40.35) ; v2(123.19,44.66) 122.88,44.96 CPU1.P18 ; CPU1.AB19 119.69,45.33 119.88,45.33 CPU1.Y18 120.06,44.96 CPU1.AB17
  BOTTOM w0.305: v2(124.86,46.61) 124.74,46.61 CPU1.L21 ; CPU1.AB19 CPU1.AB20 119.5,46.26 119.8,46.57 119.8,46.59 v2(119.8,46.59)
  BOTTOM w0.508: C2101.1 139.52,39.81 R2111.1 R2109.1 137.97,40.09 v2(137.05,40.09)
+V1.00U_CPU:
  vias: v1(111.78,9.1)
+V1.8A: length 240.1
  TOP w0.508: v2(150.05,27.37) 150.05,27.27 149.61,26.83 149.32,26.83 149.3,26.81 R2462.2 ; v2(114.88,32.14) 115.06,32.32 R1104.2
  L3 w0.508: v2(93.37,9.1) 93.37,8.72 93.87,8.22 103.5,8.22 104.01,8.73 109.56,8.73 111.31,10.48 115.38,10.48 115.94,11.04 124.88,11.04 126.81,9.1 132.13,9.1 134.54,6.69 141.24,6.69 142.77,5.17 146.71,5.17 149.09,7.55 152.95,7.55 153.2,7.3 155.1,7.3 156.09,6.31 156.62,6.31 157.13,5.8 162.71,5.8 163.22,6.31 v2(170.84,6.31)
  L4 w0.508: v2(39.34,15.56) 41.09,13.8 61.23,13.8 61.97,14.54 69.97,14.54 72.92,17.49 77.86,17.49 83.33,22.96 v2(83.33,24.22)
  L6 w0.508: v2(114.88,32.14) 114.7,32.32 114.7,34.59 114,35.29 109.42,35.29 107.8,33.67 101.21,33.67 98.14,30.59 93.27,30.59 93.24,30.62 89.73,30.62 v2(83.33,24.22)
  BOTTOM w0.508: v2(150.05,27.37) 150.05,27.43 150.39,27.77 152.67,27.77 154.07,26.38 165.07,26.38 166.39,25.06 166.39,15.33 168.3,13.42 168.3,8.59 170.57,6.31 v2(170.84,6.31) ; v2(93.37,9.1) 93.37,10.25 90.94,12.68 81.41,12.68 80.41,13.68 80.41,16.39 81.88,17.87 81.88,21.37 83.33,22.82 v2(83.33,24.22)
  vias: v1(26.94,29.09) v1(27.3,26.43) v3(16.91,53.83) v3(17.93,53.83) v3(24.91,31.08) v3(24.91,29.93) v3(27.33,25.36) v3(27.83,24.6)
+V1.8A_SIP: length 68.7
  TOP w0.203: v2(114.86,42.56) 114.39,43.03 113.94,43.03 113.83,43.14 R1607.1
  TOP w0.254: v2(96.77,31.23) 96.77,31.23 96.29,31.71 96.29,32.45 96.92,33.08 R1919.1 R1914.1 R1916.1 R1913.1 R1820.1 ; v2(114.65,18.89) 114.29,18.89 112.01,21.16 104.29,21.16 102.1,23.35 102.1,24.09 v2(100.73,25.46)
  L3 w0.508: v2(117.97,42.48) 117.31,43.14 115.44,43.14 v2(114.86,42.56)
  L6 w0.254: v2(116.86,40.98) 116.86,40.93 116.38,40.45 116.38,38.42 114.07,36.11 109.58,36.11 107.64,34.17 100.71,34.17 99.53,33 98,33 96.77,31.76 v2(96.77,31.23)
  BOTTOM w0.178: CPU1.AA1 119.91,35.21 v2(119.91,34.25)
  BOTTOM w0.254: R1738.1 R1818.2 114.45,19.09 v2(114.65,18.89) ; v2(96.77,31.23) 96.77,31.15 95.7,30.09 95.7,27.04 97.12,25.61 100.58,25.61 v2(100.73,25.46) ; CPU1.AF16 118.11,43.29 118.11,42.85 117.97,42.72 v2(117.97,42.48)
  BOTTOM w0.305: v2(114.86,42.56) 115.22,42.92 CPU1.AK15
  vias: v1(118.38,32.98) v2(117.93,41.19)
+V3.3A_SIP: length 8.3
  BOTTOM w0.254: v2(121.38,42.6) 121.5,42.72 121.5,43.24 121.55,43.28 CPU1.T16 ; CPU1.Y16 120.67,44.08 120.67,45.19 CPU1.V19
  BOTTOM w0.279: v2(114.69,44.4) 114.74,44.4 114.83,44.31 CPU1.AK17
  BOTTOM w0.305: v2(116.82,42.44) 116.89,42.51 CPU1.AG15 116.83,43.01 116.18,43.66 CPU1.AJ16 ; CPU1.AD15 118.87,42.71 v2(118.99,42.71) ; CPU1.AJ21 116.06,47.33 v2(116.15,47.43)
  BOTTOM w0.406: v2(120.04,42.44) 120.25,42.65 CPU1.Y15 CPU1.Y16
  vias: v1(115.34,43.14) v2(113.49,37.07)
+VCCAMPHYPLL_1P0: length 8.9
  TOP w0.254: v2(124.82,42.68) 125.17,42.68 125.37,42.48 v1(125.37,42.16) 125.19,41.98 125.19,40.96 125.19,40.95 125.19,40.55 125.19,40.55 125.19,37.86 125.65,37.4 R2107.2 125.62,36.89 C2113.1
  BOTTOM w0.254: CPU1.K15 124.95,42.68 124.83,42.68 v2(124.82,42.68) 124.81,42.69 124.76,42.69 CPU1.L15
+VCCAPLL_1P0: length 12.1
  TOP w0.254: R2108.2 123.18,36.56 122.8,36.94 122.8,40.83 122.45,41.19 121.19,41.19 v2(121.1,41.1) 120.67,41.53 v1(120.67,42.09) 120.67,42.85 C2114.1
  BOTTOM w0.254: v2(121.1,41.1) 121.1,42.19 120.85,42.45 120.85,42.77 CPU1.V15
+VCCCLK2: length 32.6
  L3 w0.254: v2(134.81,32.47) 134.77,32.42 134.77,32.37 134.01,31.61 132,31.61 129.94,33.67 129.94,33.73 129.85,33.82 129.85,34.1 129.85,38.02 128.74,39.14 128.74,41.23 127.84,42.13 126.55,42.13 124.38,44.3 124.38,44.86 124.82,45.3 v2(124.86,45.3)
  BOTTOM w0.254: CPU1.K19 v2(124.86,45.3) ; R2109.2 v1(139.81,36.93) 140.76,35.98 C2115.1 139.49,34.12 138.58,34.12 136.88,32.42 134.86,32.42 v2(134.81,32.47)
+VCCCLK4: length 3.3
  TOP w0.254: v2(123.18,46.57) 124,47.38 C2119.1 ; v2(123.18,46.57) 122.85,46.9 v1(122.85,47.02) ; v2(123.18,46.57) 122.79,46.18 R2110.2
  BOTTOM w0.254: CPU1.N20 v2(123.18,46.57)
+VCCCLK5: length 34.7
  TOP w0.254: v2(133.88,32.2) 134.13,32.45 v1(134.13,32.73)
  L3 w0.254: v2(133.88,32.2) 131.95,32.2 130.2,33.96 130.2,40.57 128.71,42.06 128.71,42.78 128.43,43.06 128.03,43.06 127.98,43.01 126.15,43.01 125.37,43.79 125.37,45.47 124.89,45.95 v2(124.86,45.95)
  BOTTOM w0.254: v2(133.88,32.2) 134.36,32.2 134.62,31.95 137.16,31.95 138.96,33.74 140.48,33.74 141.85,35.11 C2122.1 141.85,36.16 R2111.2 ; CPU1.L19 v2(124.86,45.95)
+VCCDSW_1P0: length 4.3
  TOP w0.254: v1(114.96,32.98) 114.96,33.79 C2103.1 114.85,33.84 113.69,33.84 v2(113.66,33.87)
  BOTTOM w0.254: v2(113.66,33.87) 113.69,33.84 114.3,33.84 114.62,34.16 114.62,35.2 CPU1.AL1
+VCCGT: length 23.2
  TOP w0.508: v3(125.12,66.51) 125.32,66.31 R738.1
  L6 w0.508: v2(168.8,60.16) 168.8,61.05 165.5,64.35 156.1,64.35 155.6,64.86 v3(152.17,64.86)
  BOTTOM w0.152: CPU1.A58 131.29,67.47 v2(131.29,67.47)
  BOTTOM w0.254: CPU1.A66 v2(131.08,72.43) ; v2(130.96,69.93) 130.94,69.95 CPU1.A62
  BOTTOM w0.508: PR4663.1 v2(168.8,60.16)
  vias: v1(117.11,74.64) v1(117.25,70.95) v1(118.77,79.46) v1(120.29,80.1) v1(122.7,77.68) v1(131.08,71.33) v1(135.91,66.76) v1(140.99,64.98) v1(151.15,62.83) v2(119.54,75.19) v2(119.55,74.54) v2(119.55,73.85) v2(119.53,70.62) v2(120.11,78.11) v2(120.11,77.48) v2(120.11,76.72) v2(120.45,75.19) v2(120.47,74.54) v2(120.44,73.87) v2(120.45,72.58) v2(120.44,71.94) v2(120.47,71.28) v2(120.44,70.64) v2(121.05,78.07) v2(121.05,77.43) v2(121.05,76.67) v2(121.38,73.29) v2(121.38,71.33) v2(122.28,75.19) v2(122.3,74.54) v2(122.28,73.89) v2(122.28,72.58) v2(122.3,71.92) v2(122.28,71.28) v2(123.16,72.58) v2(123.21,73.93) v3(118.26,69.25) v3(118.26,68.41) v3(118.26,67.52) v3(118.26,66.64) v3(118.26,65.62) v3(125.12,68.31) v3(125.12,67.4) v3(125.12,65.62) v3(141.24,61.43) v3(141.75,62.19) v3(142.13,61.43) v3(142.51,63.07) v3(142.64,62.19) v3(143.02,61.43) v3(143.4,63.07) v3(143.66,62.19) v3(144.34,63.07) v3(150.39,65.75) v3(150.39,64.86) v3(150.31,60.18) v3(150.31,59.35) v3(151.28,65.75) v3(151.28,64.86) v3(151.2,60.18) v3(151.2,59.35) v3(152.17,65.75)
+VCCIO: length 15.8
  TOP w0.508: v2(125.12,62.83) 125.27,62.67 125.52,62.67 125.54,62.65 R801.1
  L6 w0.508: v2(115.97,58.27) 115.97,60.92 117.37,62.32 124.61,62.32 v2(125.12,62.83)
  BOTTOM w0.254: v2(133.88,60.67) 134.26,61.05 R4042.1
  vias: v1(76.98,12.79) v1(82.32,20.92) v1(130.45,61.3) v3(80.71,21.38) v3(81.34,22.02) v3(81.98,22.65) v3(82.6,23.29) v3(116.48,52.43) v3(116.48,51.54) v3(116.48,50.65)
+VCCIO_SIP:
  vias: v1(72.66,8.6)
+VCCPAZIO: length 2.9
  TOP w0.254: R2101.2 116.71,47.42 v2(116.79,47.5)
  BOTTOM w0.254: CPU1.AJ19 116.43,45.99 116.43,47 116.79,47.35 v2(116.79,47.5)
+VCCPDSW_3P3: length 64
  TOP w0.254: v1(72.34,20.22) 72.34,19.92 R1707.1 72.87,18.68 v2(73.05,18.5) 72.64,18.1 R1711.2
  L4 w0.254: v2(115.85,42.49) 115.85,42.78 119.3,46.23 119.3,47.48 v2(119.35,47.53)
  L6 w0.102: 113.66,41.24 113.65,41.23 113.18,41.23
  L6 w0.254: 111.27,41.74 110.35,41.74 106.49,37.89 104.86,37.89 101.6,34.63 100.15,34.63 100.08,34.71 99.33,34.71 99.16,34.53 96.97,34.53 94.91,32.47 89.17,32.47 76.61,19.91 73.94,19.91 73.05,19.01 v2(73.05,18.5)
  BOTTOM w0.203: v2(115.85,42.49) 115.66,42.68 115.66,43.84 116.06,44.23 CPU1.AJ17
  BOTTOM w0.229: v2(119.35,47.53) 119.35,47.38 119,47.02 119,45.39 CPU1.AD18
  BOTTOM w0.254: CPU1.AD17 CPU1.AD18
+VCCPRIM_CORE: length 4.2
  BOTTOM w0.254: v2(118.08,47.53) 118.18,47.43 118.18,46.16 117.73,45.71 CPU1.AF19
  BOTTOM w0.305: v2(120.8,47.5) 120.8,47.12 121.01,46.91 CPU1.V21 CPU1.V20 ; CPU1.AF18 CPU1.AF19
  vias: v1(99.46,22.31) v1(100.22,22.19) v1(101.87,16.47) v3(98.7,22.52) v3(99.54,23.1) v3(100.22,23.68)
+VCCPRTC_3P3: length 83.2
  TOP w0.203: C2118.1 116.23,48.22 115.67,47.67 115.67,47.38 115.58,47.29
  TOP w0.254: 115.58,47.29 115.37,47.08 114.81,47.08 114.36,46.63 114.3,46.63 C2117.1 114.13,46.43 v2(114.13,45.32) ; v2(71.65,18.5) 71.65,17.22 72.14,16.72 75.2,16.72 76.5,18.02 v1(76.5,20.64) R2106.2
  L3 w0.203: v2(114.13,45.32) 114.13,46.28 113.71,46.69 111.3,46.69
  L3 w0.254: v2(71.65,18.5) 71.65,18.97 73.2,20.52 80.71,20.52 86.88,26.69 87.8,26.69 89.17,26.69 89.68,26.19 93.75,26.19 95.12,27.56 95.12,28.59 95.6,29.07 98.55,29.07 99.97,30.48 99.97,32.09 101.11,33.23 104.29,33.23 106.07,35.01 106.07,35.9 106.37,36.21 107.19,36.21 107.99,37.01 107.99,41.19 v2(106.27,42.91) 106.3,42.93 107.24,42.93 108.88,44.58 108.88,45.46 109.8,46.39 111,46.39 111.3,46.69
  BOTTOM w0.127: CPU1.BB14 106.31,42.87 v2(106.27,42.91)
  BOTTOM w0.254: CPU1.AK19 114.92,45.32 v2(114.13,45.32)
+VCCSA: length 2.7
  TOP w0.508: v2(124.86,47.31) 125.04,47.31 125.45,46.9 R735.1
  BOTTOM w0.381: v2(124.86,47.31) 124.73,47.31 124.5,47.54 124.5,48.42 124.81,48.73
  vias: v1(124.1,50.25) v1(131.97,49.36) v1(139.47,43.78) v1(142.9,32.85) v1(146.71,29.42) v1(149,28.08) v2(116.3,49.69) v2(116.28,48.85) v2(131.21,51.7) v2(134.39,50.38) v2(135.02,50.38) v2(135.66,50.38) v3(117.45,50.53) v3(118.34,50.53) v3(119.28,50.54) v3(120.17,50.54) v3(121.44,50.54) v3(122.42,50.53) v3(125.06,49.74) v3(125.16,50.65) v3(147.34,31.96) v3(148.23,31.96) v3(148.23,31.08) v3(149.07,31.96) v3(149.12,31.08) v3(149.91,31.96)
+VCCSFR: length 70.9
  TOP w0.254: C720.1 126.39,47.62 C721.1 125.51,47.62 v2(125.06,48.07)
  L3 w0.381: 125.78,44.89 125.78,47.35 v2(125.06,48.07) ; v2(140.36,25.74) 140.61,26 140.61,26.88 136.21,31.29 136.21,33.55 135.91,33.84 135.91,41.24 137.31,42.63 137.31,43.9 136.61,44.6 130.51,44.6 129.92,44.01 128.93,44.01
  BOTTOM w0.254: v2(125.06,48.07) 125.37,47.76 125.37,47.01 CPU1.K21 125.35,46.84 125.35,46.33 CPU1.K20
  BOTTOM w0.381: v2(140.36,25.74) 140.27,25.66 140.02,25.66 139.34,24.98 139.34,24.85 136.81,22.33 135.93,22.33 134.45,20.85 133.18,20.85 v1(130.18,17.85) 128.73,16.4 128.73,12.98 126.77,11.01 115.92,11.01 115.03,10.12 R4038.2
+VCCST_CPU: length 157.5
  TOP w0.254: v2(185.9,63.13) 185.82,63.21 184.63,63.21 PR4604.1 PR4605.1 PR4606.1 PR4603.1 184.12,59.68 PC4602.1 ; v2(131.29,45.17) 131.29,44.28 131.59,43.98 133.52,43.98 133.55,43.95 v2(133.62,43.95)
  L3 w0.254: v2(133.62,43.95) 134.18,43.39 134.72,43.39 135.45,42.66 135.45,33.38 135.76,33.07 135.76,31.07 139.85,26.99 v2(139.85,26.25)
  L4 w0.254: v2(139.59,71.33) 140.27,71.33 142.75,68.86 151.48,68.86 152.04,68.3 156.46,68.3 159.93,68.3 160.55,67.68 162.48,67.68 162.86,67.3 162.86,66.48 163.72,65.61 164.79,65.61 167.77,62.63 175.05,62.63 177.42,65 180.85,65 181.76,64.1 183.46,64.1 184.42,63.13 v2(185.9,63.13)
  BOTTOM w0.152: v2(131.29,45.17) CPU1.A18
  BOTTOM w0.254: R4036.2 115,10.88 115.59,11.48 126.6,11.48 128.29,13.17 128.29,16.58 130.75,19.05 v1(130.75,19.14) 131.31,19.7 131.4,19.7 133,21.29 134.27,21.29 135.75,22.77 136.63,22.77 138.89,25.04 138.89,25.35 139.54,26 139.59,26 v2(139.85,26.25) ; v2(133.62,43.95) 134.16,43.42 134.69,43.42 135.4,42.71 C716.1 136.75,42.66 139.85,45.76 139.85,51.42 140.86,52.44 140.86,57.26 139.87,58.25 138.63,58.25 137.94,58.94 137.94,62.06 137.18,62.83 137.18,66.2 140.2,69.23 140.2,70.85 139.72,71.33 v2(139.59,71.33) 139.01,71.33 R726.1 R723.1 R727.1 R419.1 R603.2
+VCCSTG: length 53.3
  TOP w0.254: C717.1 128.42,49.24 130.07,47.59 v2(131.24,47.59) v1(130.03,46.38) 129.49,45.84 128.58,45.84 128.57,45.83 128.56,45.83 128.55,45.82 128.15,45.82 128.14,45.83 127.88,45.83 127.87,45.81 127.47,45.81 127.46,45.83 127.44,45.83 127.43,45.84 127.32,45.84 127.03,46.13 127.03,46.29 v2(127.02,46.3)
  L4 w0.254: v2(137.33,70.32) 137.21,70.32 136.75,70.79 136.75,76.62 137.05,76.92 v2(137.31,76.92)
  BOTTOM w0.254: R401.1 135.73,76.49 136.16,76.92 v2(137.31,76.92) ; CPU1.A22 130.45,47.59 v2(131.24,47.59) 131.24,47.64 131.49,47.89 132.71,47.89 132.77,47.83 134.14,47.83 134.41,48.09 136.93,48.09 139.01,50.18 139.01,51.24 140.36,52.59 140.36,57.1 139.58,57.87 138.47,57.87 137.56,58.78 137.56,59.35 137.56,59.35 137.56,60.08 R4042.2 R422.2 R409.2 R408.2 R417.2 R416.2 R421.2 R423.2 137.2,70.19 v2(137.33,70.32) ; CPU1.G20 127.02,46.24 v2(127.02,46.3)
+VDDQ_CPU_CLK: length 18.9
  TOP w0.254: C715.1 115.05,58.12 v2(114.16,58.12) ; R705.2 99.45,54.62 99.46,54.62 100,54.62 v1(100.96,53.65) 103.83,53.65 104.77,54.59 v2(104.77,54.64)
  L4 w0.127: 113.76,58.53 113.74,58.55 112.09,58.55
  L4 w0.254: v2(104.77,54.64) 104.77,54.78 106.12,56.12 109.66,56.12 111.22,57.69 111.33,57.69
  BOTTOM w0.254: v2(114.16,58.12) 114.45,57.83 CPU1.AM40
AV1_TP: length 1.8
  TOP w0.089: TP2307.1 110.26,33.43 110.57,33.74 v2(110.57,33.75)
  BOTTOM w0.089: CPU1.AV1 110.57,33.75 v2(110.57,33.75)
AV71_TP: length 3.3
  TOP w0.089: TP2304.1 109.62,76.26 109.61,76.26 109.5,76.36 v2(109.4,76.36)
  BOTTOM w0.089: v2(109.4,76.36) 109.67,76.36 110.08,75.94 110.11,75.94 110.5,75.56 CPU1.AV71
DVSS: length 4.1
  TOP w0.089: HDA27.13 27.24,18.04 v1(27.5,18.3) 27.5,18.81 27.79,19.09 28.88,19.09 R2746.2
GND: length 2295.7
  TOP w0.203: v2(154.44,116.53) 154.06,116.9 VRAM3.P10 ; U3802.5 36.07,41.32 v2(36.11,41.36) ; v2(145.56,6.82) 145.56,6.84 145.64,6.92 KBC24.100 ; KBC24.17 157.6,15.78 157.48,15.66 157.01,15.66 156.61,16.06 v2(156.61,16.22) ; Q7001.4 212.85,56.36 v2(212.71,56.22) ; KBC24.124 v2(155.24,8.98) ; KBC24.64 144.44,24.32 144.04,24.73 v2(141.37,24.73) ; KBC24.84 141.75,14.18 ; KBC24.51 v2(149.64,21.88)
  TOP w0.254: ED1217.2 ED1302.2 45.46,61.38 45.16,61.68 v2(43.45,61.68) ; C1106.2 126.23,67.07 v2(126.97,66.33) ; ED3801.3 15.26,91.27 15.01,91.53 15.01,91.91 14.24,92.67 v2(13.99,92.67) ; PU4307.3 42.57,50.39 41.68,49.49 v2(41.55,49.49) ; v2(151.79,3.52) 151.79,3.95 C2420.2 ; R1825.2 v2(97.45,31.66) ; Q1701.1 90.06,13.15 89.9,13.32 89.9,14.17 89.61,14.45 Q1701.4 88.52,14.45 87.97,15.01 Q1702.1 87.36,15.57 87.23,15.69 87.23,16.74 87.1,16.87 Q1702.4 86.22,16.87 86.13,16.96 v2(86.13,17.72) ; PR4344.1 40.96,72.35 PC4314.2 41.17,72.4 v2(42.49,72.4) ; C2413.2 145.51,6.77 v2(145.56,6.82) ; ED3805.3 9.93,94.23 10.36,94.66 v2(11.45,94.66)
  TOP w0.305: THM261.5 50.53,13.72 49.93,14.31 v2(49.93,16.34) ; Q2001.4 91.85,32.35 92.1,32.6 93.47,32.6 93.71,32.85 93.74,32.85 v2(93.87,32.98) 93.39,33.46 Q2001.1 ; VRAM3.U1 161.69,119.3 v2(161.79,119.4) ; R3709.2 34.95,22.52 R3741.2 v2(35.33,21.8) ; v2(88.42,10.64) 87.79,11.26 AFTP6540.1 ; U7001.5 211.42,62.95 ; v2(213.61,37.02) U9101.16 ; v2(216.56,37.66) 216.56,37.48 216.58,37.46 216.58,37.12 217.11,36.59 U9101.9 ; v2(11.32,88.48) 10.74,88.48 C3711.2 ; U7001.8 209.32,61.42 ; v2(24.4,70.19) U5701.D5 ; PC4311.2 38.5,75.96 38.5,75.92 38.88,75.54 PR4324.2 ; v2(178.71,60.92) 178.89,61.1 PC4604.1 180.11,61.1 PR4608.1 PR4614.2 ; v2(74.44,95.34) 74.82,95.34 75.46,95.97 R5545.1 75.92,96.3 76.27,96.66 ED5502.2 ; v2(150.34,106.09) 150.74,106.5 VRAM3.A14 ; v2(26.8,70.99) U5701.B3 ; v2(215.36,32.69) 215.12,32.46 U9101.23 ; ED3801.8 ED3801.3 ; v2(26.8,68.59) U5701.B6 ; v3(192.55,67.4) 193.04,67.89 PQ4405.1 ; C2405.2 C2413.2 ; C7520.2 157.63,90.55 v2(156.86,91.32) ; EC2708.2 31.21,19.32 v2(31.01,19.52) ; C1325.2 45.61,18.73 45.61,16.04 C2602.2 ; v2(12.95,72.52) 13.06,72.4 13.51,72.4 13.74,72.17 ED5702.8 ; U9101.32 217.11,30.78 217.7,30.19 v2(217.85,30.19) ; U7001.6 210.92,62.91
  TOP w0.33: v2(179.42,104.77) 179.95,105.3 VRAM2.T10 ; VRAM2.R11 180.75,106.1 v2(180.34,105.7)
  TOP w0.356: v2(216.41,55.06) Q7001.1 ; v2(159.13,107.69) 159.54,108.1 VRAM3.C3 ; VRAM2.R14 183.46,106.1 183.56,106.2 v2(183.74,106.2) ; VRAM2.C4 174.79,116.06 174.79,116.08 v2(174.77,116.1) 174.77,116.08 174.39,115.7 VRAM2.C3 ; 151.15,112.51 151.15,112.5 150.75,112.1 VRAM3.H14 ; 151.15,112.51 151.55,112.11 VRAM3.H13 ; 151.15,112.51 v2(151.15,112.52) ; PQ4311.4 37.69,78.83 v2(38.25,78.83) ; v2(157.53,118.91) 157.94,118.5 VRAM3.T5 ; v2(158.34,107.72) 158.37,107.72 VRAM3.C4 ; U5701.E4 v2(24.4,70.19) ; v2(154.38,114.91) 153.97,114.5 VRAM3.L10 ; VRAM3.E14 150.72,109.7 150.29,109.27 v2(150.21,109.27) ; PR4328.1 34.11,80.68 v2(33.93,80.86) ; VRAM2.R12 181.15,105.7 v2(181.14,105.7) 180.75,106.09 VRAM2.R11 ; v2(195.47,73.24) 194.95,73.24 194.43,72.72 194.43,72.15 PR4474.1 194.35,72.06 PQ4405.4 ; v2(24.4,70.95) 24.44,70.95 U5701.D4 ; v2(41.23,79.53) PQ4307.1 ; 152.76,108.5 v2(152.76,108.51) ; 152.76,108.5 152.76,108.49 VRAM3.C11 153.15,108.09 153.54,107.7 v2(153.54,107.7) ; 152.76,108.5 VRAM3.C12 VRAM3.C13 ; v2(159.15,115.7) 159.55,116.1 VRAM3.N3 ; v2(184.45,107.61) 184.16,107.9 183.35,107.9 VRAM2.N14 ; v2(157.56,106.91) VRAM3.B5 ; v2(154.35,115.7) 153.96,115.3 VRAM3.M10 ; v2(181.15,113.7) 181.55,114.1 VRAM2.E12 ; v2(172.34,104.09) 172.74,104.5 VRAM2.U1 ; VRAM2.H2 173.15,112.1 v2(173.15,112.1) ; v2(179.38,112.47) 179.4,112.5 VRAM2.G10 ; v2(154.36,110.08) 154.36,110.09 VRAM3.F10 ; v2(179.53,116.84) 179.57,116.84 179.92,116.5 VRAM2.B10 ; VRAM2.T5 175.94,105.3 v2(175.54,105.7) 175.54,105.7 175.15,106.09 VRAM2.R4 174.75,106.5 174.75,106.5 ; 173.15,110.51 173.55,110.11 VRAM2.K2 ; 173.15,110.51 173.15,110.5 172.75,110.1 VRAM2.K1 ; 173.15,110.51 v2(173.15,110.52) ; VRAM3.R3 159.53,117.7 v2(159.13,118.1) 158.75,117.72 VRAM3.R4 ; v2(176.48,108.92) 176.33,108.92 VRAM2.L5 ; VRAM2.A12 181.55,117.31 181.15,117.71 v2(181.15,117.73) ; VRAM3.R12 152.37,117.7 v2(152.77,118.1) 152.77,118.03 153.1,117.7 VRAM3.R11 ; v2(153.54,118.11) 153.56,118.11 VRAM3.T10 ; VRAM2.D10 179.6,114.9 v2(179.28,115.23) ; PR4332.2 39.72,81.32 40.14,81.74 PQ4310.1 ; v2(181.1,104.07) 181.18,104.14 181.19,104.14 VRAM2.U12 ; PQ4309.1 36.02,75.78 v2(36.22,75.97) 36.2,75.99 PQ4311.1 ; U5701.E5 23.64,70.15 23.64,70.16 v2(23.63,70.18) ; v2(152.75,115.7) VRAM3.N12 ; v2(174.73,117.73) 174.49,117.5 174.49,117.44 VRAM2.A3 ; v2(161.7,107.73) 161.32,108.1 VRAM3.C1 ; VRAM2.C11 181.13,116.08 v2(181.13,116.09) 181.16,116.09 VRAM2.C12 ; v2(180.34,105.7) 179.95,105.3 VRAM2.T10 ; VRAM3.K13 151.15,114.1 v2(151.15,114.1) 150.75,113.7 VRAM3.K14 ; VRAM3.K2 v2(160.75,113.3) 161.15,113.7 VRAM3.K1 ; v2(159.15,109.3) 159.55,109.7 VRAM3.E3 ; VRAM2.H1 172.27,111.7 v2(172.08,111.88) ; VRAM2.H13 v2(182.75,111.3) 183.15,111.7 VRAM2.H14 ; VRAM2.L10 179.82,109.3 v2(179.42,108.91) 179.83,108.5 VRAM2.M10 ; VRAM3.N1 v2(161.74,116.1) ; v2(184.11,114.21) 184.01,114.1 VRAM2.E14 ; v2(152.75,110.1) 152.35,109.7 VRAM3.E12 ; VRAM2.F5 175.96,113.3 v2(176.35,113.7) ; PQ4313.4 43.39,75.97 v2(43.84,75.53) ; PQ8308.1 204.63,65.89 204.85,66.1 205.73,66.1 EC8980.2 ; v2(150.08,117.96) 150.34,117.7 VRAM3.R14 ; VRAM3.E1 161.53,110.08 161.67,110.08 v2(161.7,110.11) ; v2(152.77,106.9) 152.37,106.5 VRAM3.A12 ; VRAM3.H1 160.76,111.71 v2(160.73,111.71) 160.35,112.09 VRAM3.H2 ; VRAM3.B10 154.32,106.93 v2(154.36,106.93) ; v2(172.21,107.27) 172.29,107.27 172.72,107.7 VRAM2.N1 ; VRAM2.N3 174.35,107.7 v2(174.75,108.1) ; v2(183.79,117.4) 183.25,117.4 VRAM2.A14 ; v2(181.15,107.3) 181.55,107.7 VRAM2.N12 ; VRAM3.U14 150.75,119.32 v2(150.34,119.73) ; VRAM3.L5 157.91,114.5 157.53,114.88 v2(157.5,114.88) ; v2(150.21,107.52) 150.21,107.54 150.75,108.08 VRAM3.C14 ; v2(159.15,119.73) 159.15,119.71 159.55,119.31 VRAM3.U3 ; VRAM2.R1 172.75,106.06 v2(172.21,105.52) ; VRAM2.U14 183.23,104.5 183.62,104.11 v2(183.7,104.11) ; v2(34.44,79.02) PQ4308.4 ; VRAM3.N14 150.27,116.1 v2(150.21,116.04) ; v2(152.42,119.98) 152.42,119.43 152.35,119.36 VRAM3.U12 ; VRAM2.E1 v2(172.11,114.1) ; VRAM2.C1 172.49,115.7 172.29,115.91 172.14,115.91 v2(172.08,115.96) ; v2(159.1,106.07) 159.18,106.14 159.2,106.14 VRAM3.A3 ; VRAM3.G5 157.82,111.3 v2(157.42,110.91) 157.83,110.5 VRAM3.F5 ; VRAM3.G10 154.34,110.91 v2(154.36,110.91) ; VRAM2.R3 174.75,106.5 ; 174.75,106.5 v2(174.75,106.51) ; v2(41.3,84.87) 41.44,84.72 PQ4310.4 ; v2(183.69,109.85) 183.44,110.1 VRAM2.K14 VRAM2.K13 ; v2(174.75,113.7) VRAM2.E3 ; v2(180.35,113.7) 179.95,113.3 VRAM2.F10 ; VRAM2.G5 175.97,112.5 v2(176.38,112.91) ; v2(154.38,108.51) 153.99,108.9 VRAM3.D10 ; v2(176.48,108.13) 176.43,108.13 176.06,108.5 VRAM2.M5 ; v2(38.25,78.19) 38.56,77.88 PQ4307.4 ; VRAM2.A1 172.34,117.71 v2(172.34,117.73) ; v2(161.76,117.85) 161.61,117.7 VRAM3.R1 ; VRAM3.A1 161.46,106.19 v2(161.46,106.01) ; v2(175.54,116.11) 175.93,116.5 VRAM2.B5 ; v2(158.35,115.7) 157.95,115.3 VRAM3.M5 ; VRAM2.U3 174.36,104.5 v2(174.76,104.9) ; VRAM2.C13 VRAM2.C14 183.49,115.7 v2(183.75,115.96) ; v2(31.9,77.37) PQ4308.1 ; VRAM2.P10 179.4,106.35 v2(179.4,106.35)
  TOP w0.381: PR4512.2 197.91,73.04 PC4530.2 196.16,73.19 v2(196.11,73.24) ; v2(42.31,14.74) 38.45,14.74 37.87,15.33 36.65,15.33 34.89,17.08 EC8975.2 ; v2(216.41,55.06) 216.25,55.23 R2034.1 ; EC1712.2 90.27,18.63 89.68,19.21 89.68,20.03 v2(88.89,20.83) ; v2(44.34,28.03) 44.42,27.95 EC8948.2
  TOP w0.406: 141.75,14.18 141.07,14.18 R2417.2 140.81,14.44 ED2403.2 140.18,14.01 139.85,13.68 138.83,13.68 v2(138.7,13.55) ; U7001.7 210.36,62.92 ; R2449.1 140.56,21.3 140.56,21.16 140.66,21.06 R2436.2 140.66,20.59 139.53,19.46 Q2408.S 139.03,18.43 v2(137.94,19.52) ; v2(22.22,24.52) 21.46,24.52 20.92,23.99 EC8901.2 EC2710.2 ; v2(15.9,27.27) 16.28,26.88 ED3603.8 ED3603.3 ; v2(15.26,49.62) 15.77,50.13 ED3601.8 ED3601.3 ; v2(22.8,69.39) U5701.G6 ; v2(13.48,68.79) ED5701.8 ED5701.3 ; ED5702.3 ED5702.8 ; v2(22,71.79) U5701.G3
  TOP w0.508: v2(60.44,55.23) 60.82,54.86 C1204.2 ; PC4602.2 EC8944.2 185.8,58.86 v2(185.82,58.89) ; C7513.2 160.75,87.67 v2(160.75,86.9) ; C7513.2 C7514.2 ; C7513.2 160.47,88 C7506.2 ; C2426.2 v2(161.39,6.49) ; v2(44.09,76.41) 45.16,77.48 PQ4306.S ; v2(145.69,116.17) 145.82,116.04 C7901.1 145.87,115.53 R7909.1 ; R7624.2 174.09,85.02 v2(173.35,85.75) ; v2(185.57,63.71) 185.08,64.2 PC4606.2 ; C1318.2 54.68,31.64 v2(54.63,31.59) EC8938.2 ; C1205.2 71.52,54.98 v2(71.52,55.46) 71.44,55.54 C1219.2 ; EC8994.2 197.45,47.51 v2(197.89,47.08) 197.56,46.75 C4001.2 ; C4002.2 199.99,46.75 v2(199.66,47.08) 200.48,47.08 EC8987.2 ; EC8996.2 167.84,11.49 EC8979.2 167.84,9.54 v2(167.28,8.98) ; v2(156.94,119.82) 157.37,120.25 C7908.2 157.37,121.36 R7901.2 ; C7312.2 158.01,82.61 C7730.2 ; 184.98,114.18 185.64,114.85 185.64,115.58 185.31,115.91 183.79,115.91 v2(183.75,115.96) ; 184.98,114.18 C7817.2 ; 184.98,114.18 185.34,114.18 185.64,113.88 C7816.2 ; EC1801.2 C2112.2 94.89,37.85 v2(95.14,38.11) ; C1315.2 50.25,63.92 v2(50.21,63.88) ; C1310.2 v2(47.39,55.71) ; v2(43.2,27.82) C3720.1 41.75,27.77 41.75,27.27 C3715.2 41.5,27.01 C3722.2 C3721.2 C3723.2 ; EC2709.2 15.84,20.66 v2(15.41,20.23) ; PR4475.2 191.28,67.22 v3(191.28,67.4) ; AFTP2604.1 204.62,69.16 v2(204.36,69.41) ; v2(68.29,40.05) 68.43,40.19 C1209.2 ; C1206.2 68.46,60.05 v2(68.46,60.58) ; v2(36.34,47.84) R3858.1 ; R2035.1 221.25,53.05 v2(221.38,52.92) ; EC6401.2 57.31,6.93 ED6401.2 58.33,8.38 57.74,8.98 v2(57.55,8.98) ; PC4435.2 184.12,40.27 v2(185.31,39.08) ; C2736.2 26.03,22.08 25.55,21.6 24.86,21.6 v2(24.84,21.58) ; C1304.2 55.38,41.29 v2(55,41.67) 55,41.98 55.65,42.63 C1305.2 ; C2608.2 51.89,16.34 v2(49.93,16.34) 50.21,16.62 C2601.2 50.59,17.74 EC8947.2 ; C2503.2 169.13,0.93 ; PC8205.2 135.1,120.66 v2(135.38,120.38) ; EC8910.2 226.72,28.59 226.72,30.11 v2(226.64,30.19) ; R2454.2 v2(153.97,3.52) ; R2448.2 161.46,21.98 C2409.2 161,22.01 v2(160.8,21.81) ; 2.58,87.4 USB1.13 2.58,87.02 ; v2(50.29,36.18) 50.06,35.95 C1316.2 ; v2(120.05,41.8) 119.52,41.8 C2107.2 ; C3821.2 28.65,89.62 v2(28.65,88.78) ; C6306.2 230.35,11.09 C6317.2 231.8,10.88 ; PC4311.2 37.97,76.08 v2(37.23,76.08) ; C2428.2 160.78,2.3 v2(161.1,2.62) ; PC4706.2 154.58,57.62 v2(154.83,57.36) ; EC8980.2 206.32,66.08 206.65,65.75 206.65,64.98 207.08,64.55 R8304.2 208.38,64.55 v2(208.76,64.93) ; v3(145.31,113.14) 145.31,112.58 146.72,111.17 R7904.2 146.9,110.31 C7902.2 ; v3(196.36,52.16) 196.84,51.68 EC8945.2 ; R4006.2 163.8,5.4 C4009.2 164.23,4.76 164.23,3.92 v2(164.36,3.8) ; v2(170.71,3.77) R2504.2 171.28,4.48 Q2505.S ; 2.17,81.25 HDMI2.23 ; HDMI2.23 4.93,81.25 ; HDMI2.23 3.55,82.24 ; C1321.2 55.72,79.34 v2(55.39,79.01) 55.82,78.57 EC8923.2 ; PR4514.2 191.61,57.82 v2(191.03,57.24) ; C1220.2 68.6,36.28 68.31,36 v2(68.31,35.71) 68.5,35.52 EC1203.2 ; v2(140.21,75.12) 140.23,75.14 140.23,75.83 140.51,76.11 R2611.2 ; v2(81.17,103.72) 80.84,103.39 EC8907.2 80.84,101 81.83,100.01 C5516.2 ; v2(50.11,29.11) 49.97,28.97 C1317.2 ; 5.92,97.34 USB1.B1 5.29,96.3 ; v2(178.71,60.92) 178.66,60.87 PC4622.2 178.63,59.37 PR4639.2 PR4672.1 179.47,58.28 179.45,58.26 179.45,58.08 PC4610.1 ; v3(203.47,53.94) 202.03,52.49 EC8915.2 202.2,51.22 C4003.1 204.06,51.22 EC8976.2 ; v2(118.38,8.21) 118.56,8.03 PR5203.2 ; v2(50.74,22.31) 50.74,22.85 R1307.2 ; R601.2 C1104.2 ; C1104.2 C1105.2 126.16,70.83 v2(126.33,71) ; C1104.2 125.6,69.89 125.27,69.56 R407.2 ; v2(156.36,5.68) 156.69,5.35 C2425.1 C2424.1 ; C2738.1 31.92,17.16 v2(31.97,17.11) ; C1126.2 C1124.2 ; 5.15,40.26 USB2.13 6.45,40.26 ; EC2901.2 33.5,7.54 v2(33.85,7.18) 33.85,6.39 34.23,6.01 EC2903.2 ; v2(58.23,69.58) 58.28,69.63 C1320.2 ; C2418.2 162.58,15.71 v2(163.09,16.22) 162.84,16.47 C2410.2 ; USB1.14 6.45,87.02 ; USB1.14 5.12,86.19 ; USB1.14 3.78,87.02 ; USB1.14 5.12,87.86 ; C715.2 114.8,56.83 114.26,56.29 v2(114.13,56.29) ; R7912.2 R7913.2 R7909.1 ; v2(34.82,46.82) C3865.2 ; EC8977.2 187.42,75.35 v2(187.73,75.65) ; C5855.2 29.94,76.24 C5827.2 v2(31.47,76.24) ; v2(88.42,10.64) 88.53,10.53 90.7,10.53 EC1705.2 90.83,10.45 C1710.2 ; 12.54,26.32 USB3.7 12.54,24.88 ; C1113.2 116.56,44.13 C2109.2 ; 6.36,88.62 USB1.15 7.45,87.84 ; v2(38.76,80.73) 39.34,80.73 PR4332.2 ; v2(52.27,65.73) 52.34,65.65 C1303.2 ; 1.25,100.01 USB1.22 2.58,99.17 ; R2426.1 162.45,18.76 v2(162.96,18.25) 162.71,17.99 C2429.2 ; 210.46,73.87 210.33,73.75 EC2602.2 ; v2(37.49,51.55) 37.36,51.68 C3818.2 ; EC8925.2 68.55,77.05 v2(68.22,77.39) 68.64,77.81 C1214.2 ; R2002.1 90.77,33.59 v2(90.16,33.59) ; v2(31.01,19.52) R2746.1 ; 12.54,48.38 USB2.7 12.54,49.82 ; 5.29,89.9 USB1.B12 5.92,88.86 ; SPR3.1 58.15,23.36 ; 10.05,65.84 HDMI2.21 10.05,63.86 ; C3701.2 C3703.2 C3702.2 v2(39.47,25.79) ; EC1302.2 48.03,86.32 48.66,86.96 50.31,86.96 51.03,86.24 v2(51.03,85.95) ; EC8935.2 62.72,29.55 v2(63.16,29.11) 62.84,28.79 C1218.2 ; 5.12,98.34 USB1.21 ; USB1.21 5.12,100.01 ; USB1.21 6.45,99.17 ; USB1.21 3.78,99.17 ; 6.45,57.94 USB2.12 5.15,57.94 ; R3872.2 45.99,57.36 R3873.2 44.37,58.28 v2(44.34,58.25) ; 6.45,16.76 USB3.13 5.15,16.76 ; v2(51.35,72.71) 51.35,72.97 51.33,73 EC8920.2 ; R4304.2 v2(33.42,74.66) 33.45,74.64 PR4340.2 34.13,75.37 PC4313.1 ; PC4524.2 197.02,70.19 v2(196.11,70.19) ; v2(124.91,76.64) 125.31,76.24 R722.2 ; v2(129.79,124.52) 129.74,124.47 PC8226.1 129.74,122.99 PR8259.2 ; 206.95,75.35 EC2601.2 ; v2(120.01,38.57) 120.47,38.11 R1901.2 120.37,37.83 120.37,37.25 R1603.2 120.46,36.92 120.04,36.49 R2051.2 119.32,36.31 EC1706.2 ; 113.48,51.72 113.41,51.65 EC8924.2 ; EC2902.2 27.83,11.09 v2(27.83,11.09) ; v2(93.19,46.65) EC1901.1 93.9,46.62 EC1903.2 ; v2(51.54,29.11) 51.54,29.37 51.56,29.39 51.56,29.58 EC8922.2 ; C7907.2 147.06,106.77 C7914.2 147.06,105.4 147.42,105.04 149.28,105.04 v2(150.34,106.09) ; v2(21.86,63.21) 22.07,63 R5734.2 ; EC8962.2 176.8,61.3 v2(177.19,61.68) ; v2(31.97,17.11) 31.97,16.84 31.86,16.73 31.86,16.59 C2743.2 31.27,16.12 30.66,15.51 C2729.2 C2747.2 ; v2(31.97,17.11) 32.05,17.03 EC8911.2 ; v2(63.14,62.32) 62.91,62.55 C1202.2 ; R3841.2 32.02,57.24 v2(31.77,56.98) ; R3843.2 v2(31.9,55.08) ; PC4607.2 180.23,62.06 179.85,62.44 v2(179.47,62.44) ; 81.71,0.88 v2(81.68,0.85) 81.25,1.28 EC8943.2 C4031.2 C4032.2 ; R6304.2 v2(228.11,16.6) ; 13.6,32.89 USB3.10 15.28,32 ; v2(59.55,72.69) 59.51,72.65 C1215.2 ; C7818.2 149.45,119.85 150.22,119.85 v2(150.34,119.73) ; R7506.2 R7507.1 v2(173.63,98.82) ; v2(145.56,118.07) 145.81,117.82 C7904.2 ; v2(67.74,62.37) 67.38,62.72 C1203.2 ; R5763.2 v2(39.97,65.32) ; R7810.1 181.12,119.34 v2(182.9,121.12) ; v2(55.29,85.95) 55.37,86.02 EC1103.2 ; C7726.2 156.23,89.32 C7326.2 157.53,89.55 C7520.2 ; EC8916.2 25.5,3.58 v2(26.25,4.34) ; R9148.2 210.79,28.54 v2(210.52,28.81) ; 10.05,78.36 HDMI2.22 10.05,80.34 ; v2(32.61,47.13) R3857.1 ; v2(200.93,29.55) 201.65,29.55 PR4417.1 ; R7007.1 v2(215.41,62.19) ; C7910.2 145.43,118.84 144.8,118.21 v2(144.8,118.13) ; v2(175.66,0.85) 175.71,0.9 R2517.2 ; v2(43.84,75.53) 44.04,75.32 PC4315.2 ; PR4530.2 191.33,61.23 190.9,60.79 v2(190.9,60.41) ; R3870.2 33.68,50.08 v2(33.8,49.95) R3844.2 ; C2722.2 20.44,29.81 v2(20.26,29.63) ; X5701.2 18.18,65.36 18.79,65.97 v2(18.94,65.97) 18.97,65.97 19.32,65.62 C5730.2 ; v2(159.91,123.15) 160.09,123.33 PR8313.2 ; v2(77.62,8.6) 77.46,8.44 C4033.2 ; USB2.10 13.6,56.39 ; USB2.10 13.6,54.61 ; USB2.10 15.28,55.5 ; EC8960.2 117.04,90.26 v2(116.81,90.03) ; R7627.2 214.24,65.21 v2(214.9,65.87) ; C7003.2 204.92,59.96 ; v2(39.52,60.9) C3817.2 ; R3735.2 30.88,24.59 31.14,24.22 v2(31.77,24.22) ; v2(213.61,37.02) 213.38,37.02 C9105.2 ; C1221.2 72.35,23.51 Q1802.S ; v2(144.8,75.91) 144.8,75.27 145.18,74.89 EC8957.2 ; v2(164.75,86.9) 164.75,87.66 C7501.2 ; C1805.2 EC1806.2 74.32,20.15 74.7,19.77 v2(74.7,19.4) ; 3.55,61.96 HDMI2.20 4.93,62.95 ; C2609.2 v2(55.27,14.69) ; C1216.2 62.99,83.4 v2(63.33,83.74) 62.91,84.16 EC8919.2 ; USB2.11 13.6,43.59 ; USB2.11 15.28,42.7 ; USB2.11 13.6,41.81 ; v2(190.14,60.41) 190.14,62.57 190.9,63.33 PR4436.2 ; EC1902.2 v2(96.79,44.54) ; C7703.2 167.44,74.87 v2(166.81,75.5) ; R5762.2 40.66,68.03 40.15,68.55 v2(39.9,68.55) ; C2614.2 43.81,9.13 C2610.2 44.85,9.23 45.36,9.74 45.36,10.5 42.31,13.55 v2(42.31,14.74) ; 6.36,97.57 USB1.20 7.45,98.36 ; v2(38.42,62.44) R3802.1 ; C1306.2 57.6,53.99 v2(58.11,54.49) 57.27,55.33 C1307.2 ; v2(122.78,33.06) 122.88,32.96 R2037.2 ; C1322.2 49.98,83.27 v2(50.29,83.58) 49.84,84.03 EC8918.2 ; 14.35,44.89 USB2.4 15.06,45.6 ; v2(68.22,68.72) 68.27,68.67 C1210.2 ; R3846.2 v2(41.42,51.01) ; C1319.2 50.03,72.66 v2(50.08,72.71) ; PC4531.2 200.02,71.41 PR4513.2 v2(200.05,72.33) ; v2(127.02,48.07) 127.02,47.71 127.48,47.25 R734.2 ; EC8978.2 221.56,51.32 ; R7909.1 146.93,115.68 C7807.2 ; EC8942.2 26.51,33.92 v2(26.97,33.46) C3718.2 28.32,33.23 C3716.2 ; R2033.1 219.17,57.82 v2(219.22,57.87) ; EC8936.2 62.94,40.47 v2(63.36,40.05) 63.02,39.71 C1217.2 ; 5.15,34.44 USB3.12 6.45,34.44 ; C1127.2 126.18,59.85 v2(127,59.04) ; v2(21.76,35.5) 21.66,35.6 EC8914.2 ; v2(169.33,78.01) 169.77,77.57 C7704.2 170.4,77.13 R7607.1 169.9,76.16 R7610.2 170.02,75.65 R7518.2 ; v3(187.6,43.9) 187.65,43.95 EC8961.2 ; R2739.2 16.23,23.41 v2(16.15,23.33) ; C7323.2 154.99,91.85 v2(155.23,92.09) ; R5758.1 v2(15.9,74.64) ; C7318.2 156.74,83.35 156.66,83.28 156.66,83.27 156.37,82.98 v2(156.02,82.98) ; R5757.1 21.5,61.63 21.58,61.72 v2(21.88,61.72) ; C3717.1 29.03,30.92 R3726.1 v2(28.26,30.95) 27.83,30.95 27.07,30.19 C2721.2 ; EC8941.2 111.6,12.18 v2(111.65,12.13) ; R2031.1 70.84,101.99 ; v2(40.28,60.9) C3815.2 ; C7903.2 153.18,120.74 153.79,121.35 v2(154.2,121.35) ; PC5112.2 43.94,100.57 v2(44.34,100.16) 43.38,99.2 PR5106.1 ; X5701.4 v2(15.54,62.16) ; PR4323.2 44.72,80.34 PQ4312.S 43.7,81.37 v2(42.57,81.37) ; R7632.2 172.38,83.26 v2(172.59,83.05) ; v2(148.36,0.85) R2445.1 ; EC8984.2 231.92,8.72 ; R7601.2 172.56,80.61 R7621.2 172.99,81.45 R7602.2 171.09,81.45 v2(170.95,81.31) ; C9114.2 v2(217.83,39.58) ; R2032.1 73.38,101.99
  L3 w0.305: v2(15.64,101.94) 15.77,101.94
  L3 w0.508: 2.58,87.02 USB1.13 2.58,87.4 ; 6.36,97.57 USB1.20 7.45,98.36 ; 5.12,98.34 USB1.21 ; USB1.21 6.45,99.17 ; USB1.21 5.12,100.01 ; USB1.21 3.78,99.17 ; 9.36,65.84 HDMI2.21 9.36,63.86 ; HDMI2.23 4.93,81.25 ; HDMI2.23 3.55,82.24 ; HDMI2.23 2.17,81.25 ; USB1.15 8.54,88.62 ; USB1.15 7.45,87.84 ; USB1.15 6.36,88.62 ; HDMI2.22 11.44,79.35 ; HDMI2.22 10.05,78.36 ; HDMI2.22 10.05,80.34 ; 4.5,57.94 USB2.12 6.45,57.45 ; 3.78,87.02 USB1.14 ; USB1.14 5.12,86.19 ; USB1.14 6.45,87.02 ; USB1.14 5.12,87.86 ; 12.54,26.32 USB3.7 12.54,24.88 ; 12.54,48.38 USB2.7 12.54,49.82 ; 5.92,97.34 USB1.B1 5.29,96.3 ; 2.58,99.17 USB1.22 1.25,100.01 ; 4.5,40.26 USB2.13 6.45,40.75 ; 5.29,89.9 USB1.B12 5.92,88.86 ; 4.5,34.44 USB3.12 6.45,33.95
  L4 w0.127: v2(112.81,39.83) 112.83,39.83 113.28,39.38 113.66,39.38 114.12,38.92 v2(114.13,38.92) ; 155.59,125.79 154.55,125.79
  L4 w0.508: 6.36,97.57 USB1.20 7.45,98.36 ; 1.25,100.01 USB1.22 2.58,99.17 ; 5.12,98.34 USB1.21 ; USB1.21 3.78,99.17 ; USB1.21 6.45,99.17 ; USB1.21 5.12,100.01 ; 6.45,57.45 USB2.12 4.5,57.94 ; 12.54,49.82 USB2.7 12.54,48.38 ; 5.12,86.19 USB1.14 ; USB1.14 5.12,87.86 ; USB1.14 3.78,87.02 ; USB1.14 6.45,87.02 ; 5.29,96.3 USB1.B1 5.92,97.34 ; 4.5,34.44 USB3.12 6.45,33.95 ; v2(112.83,40.75) 112.83,40.74 112.83,39.84 v2(112.81,39.83) ; 5.92,88.86 USB1.B12 5.29,89.9 ; HDMI2.22 10.05,80.34 ; HDMI2.22 10.05,78.36 ; HDMI2.22 11.44,79.35 ; HDMI2.23 3.55,82.24 ; HDMI2.23 4.93,81.25 ; HDMI2.23 2.17,81.25 ; 12.54,24.88 USB3.7 12.54,26.32 ; 6.36,88.62 USB1.15 ; USB1.15 8.54,88.62 ; USB1.15 7.45,87.84 ; 2.58,87.02 USB1.13 2.58,87.4 ; 6.45,40.75 USB2.13 4.5,40.26 ; 9.36,65.84 HDMI2.21 9.36,63.86
  L6 w0.127: v2(114.13,38.92) 113.7,39.35 113.31,39.35 112.83,39.83 v2(112.81,39.83)
  L6 w0.508: 5.12,98.34 USB1.21 ; USB1.21 6.45,99.17 ; USB1.21 5.12,100.01 ; USB1.21 3.78,99.17 ; USB1.14 6.45,87.02 ; USB1.14 5.12,86.19 ; USB1.14 3.78,87.02 ; USB1.14 5.12,87.86 ; 6.36,88.62 USB1.15 7.45,87.84 ; HDMI2.23 3.55,82.24 ; HDMI2.23 2.17,81.25 ; HDMI2.23 4.93,81.25 ; 4.5,34.44 USB3.12 6.45,33.95 ; 6.45,40.75 USB2.13 4.5,40.26 ; 12.54,26.32 USB3.7 12.54,24.88 ; 9.36,78.36 HDMI2.22 9.36,80.34 ; 5.29,89.9 USB1.B12 5.92,88.86 ; 2.58,99.17 USB1.22 1.25,100.01 ; 5.29,96.3 USB1.B1 5.92,97.34 ; 4.5,57.94 USB2.12 6.45,57.45 ; 2.58,87.4 USB1.13 2.58,87.02 ; 7.45,98.36 USB1.20 6.36,97.57 ; 9.36,63.86 HDMI2.21 9.36,65.84 ; 12.54,49.82 USB2.7 12.54,48.38
  BOTTOM w0.089: 103.98,53.99 107.64,53.99 107.67,54.02 CPU1.BB34 ; EC401.2 v2(137.31,74)
  BOTTOM w0.102: CPU1.P21 122.77,46.9 122.77,46.27 CPU1.P20 ; CPU1.D44 128.95,59.8 129.15,59.8 129.27,59.82 129.41,59.84 CPU1.B44
  BOTTOM w0.127: CPU1.AR42 112.48,58.55 111.88,58.55 CPU1.AT42 ; CPU1.BB60 108.1,68.79 107.87,68.79 107.52,69.14 106.69,69.14 104.6,71.23 v2(104.44,71.23) ; CPU1.AT71 111.89,76 v2(111.59,76.42) ; CPU1.BB38 107.79,56.37 107.66,56.24 105.15,56.24 104.77,56.62 v2(104.77,56.85) ; CPU1.BB43 107.46,58.97 v2(107.33,59.1) ; CPU1.AP70 112.88,74.65 112.88,76.45 v2(112.75,76.57) ; CPU1.AW60 110.39,68.67 110.39,69.89 CPU1.AW62 ; v2(107.44,71.06) 107.47,71.09 CPU1.BB64 ; CPU1.AG71 116.9,76.2 v2(117.11,76.41) ; CPU1.BB55 108.39,66.12 107.54,66.12 107.47,66.05 106.37,66.05 104.9,67.49 v2(104.5,67.76) ; CPU1.BB30 107.36,51.39 107.21,51.24 v2(107.13,51.24) ; v2(107.03,49.7) 107.23,49.91 107.83,49.91 107.98,50.06 108.75,50.06 CPU1.BA28 ; CPU1.BB26 107.77,49.03 107.29,48.55 106.67,48.55 v2(106.67,48.55) ; CPU1.AW32 110.39,52.68 110.39,51.92 110.36,51.89 CPU1.AW30 ; v2(114.57,77.51) 114.57,77.5 114.13,77.07 114.13,76.07 114.25,75.96 CPU1.AM71
  BOTTOM w0.152: CPU1.AP42 113.18,58.55 113.78,58.55 CPU1.AN42 ; v2(153.53,78.87) 152.97,78.87 152.54,78.44 GPU1.AF8 ; CPU1.AK16 115.22,43.78 115.59,44.15 115.59,44.5 CPU1.AJ18 ; CPU1.AW16 CPU1.AW18 110.09,45.29 109.85,45.52 109.85,45.52 109.76,45.62 109.47,45.62 109.14,45.29 CPU1.BA18 ; CPU1.AR20 CPU1.AT20 ; CPU1.AJ4 115.94,37.5 116.22,37.5 CPU1.AH6 ; v2(114.13,68.18) 114.27,68.04 114.59,68.04 114.93,67.7 CPU1.AL58 114.93,66.82 115.26,66.49 115.26,66.22 114.93,65.89 CPU1.AL55
  BOTTOM w0.178: 110.45,72.24 110.42,72.21 110.42,71.25 CPU1.AW64 ; CPU1.T15 122.19,43.01 122.65,42.55 123.19,42.55 ; CPU1.AP20 113.17,45.76 113.79,45.76 CPU1.AN20 ; CPU1.AM61 114.58,69.42 114.58,68.76 CPU1.AM60
  BOTTOM w0.203: IOBD1.21 v2(206.27,44.8) ; CPU1.BB18 CPU1.BA18 ; CPU1.G43 126.57,59.61 126.57,60.28 CPU1.G45 ; USB1.A1 7.51,90.35 7.74,90.12 USB1.16 ; IOBD1.9 v2(204.62,40) ; GPU1.E5 169.36,76.29 167.6,76.29 GPU1.H5 ; v2(124.91,76.64) 125.09,76.46 125.09,75.81 125.09,75.81 125.09,75.24 CPU1.K71 CPU1.K70 ; USB1.A12 6.36,95.85 USB1.B1 ; CPU1.AN63 114.3,70.96 CPU1.AL64 ; CPU1.AN63 CPU1.AP63 ; CPU1.AN63 114.45,69.81 CPU1.AM61 ; 119.89,36.84 119.89,35.88 CPU1.AA2 ; U4001.11 U4001.15 ; CPU1.T15 121.92,43.1 122.32,43.5 122.32,43.92 CPU1.T17 ; IOBD1.6 204.01,38.8 ; 204.01,38.8 204.01,38.21 204.62,37.6 IOBD1.3 ; 204.01,38.8 v2(203.98,38.82) ; v2(156.36,56.73) 155.56,57.53 PU4701.3 ; CPU1.E46 128.01,61.3 128.01,61.14 128.44,60.71 CPU1.D45 ; CPU1.AR45 112.5,60.4 112.34,60.23 112.24,60.1 112.24,60.02 v2(112.19,59.97) 112.24,59.92 112.24,59.75 112.49,59.49 CPU1.AR43 ; GPU1.AD21 154.4,88.75 155.2,88.75 GPU1.AB20 ; IOBD1.15 v2(204.62,42.4) ; CPU1.AW43 110.31,58.92 110.31,59.31 110.39,59.39 110.39,59.7 110.36,59.72 CPU1.AW45 v2(109.77,60.15) ; 110.38,56.49 110.38,57.65 CPU1.AW41 109.77,57.67 v2(109.64,57.79) ; CPU1.AW47 110.4,61.4 110.4,62.52 CPU1.AW49 109.89,62.56 v2(109.74,62.71) ; R2030.2 v2(114.07,28.28) ; CPU1.AR46 CPU1.AR48 112.54,62.23 112.71,62.41 v2(112.87,62.68) 112.7,62.98 112.53,63.15 CPU1.AR50 ; CPU1.AT20 CPU1.AU20 ; v2(160.42,47.33) 160.38,47.29 PU4802.3 ; CPU1.AR52 112.75,64.31 v2(112.75,64.51) ; v2(109.66,55.07) 110.13,55.19 CPU1.AW36 ; VRAM3.P10 154.06,116.9 v2(154.44,116.53) ; U8301.11 v2(183.92,76.03) ; IOBD1.24 v2(206.33,46) ; CPU1.AW53 109.83,64.96 v2(109.67,64.8) ; IOBD1.18 v2(206.22,43.6) ; GPU1.B11 171.94,80.92 171.55,81.31 v2(170.95,81.31) ; IOBD1.12 v2(204.62,41.2) ; PU4801.3 160.26,39.04 v2(161.06,39.84) ; CPU1.AJ15 116.06,42.95 116.33,42.67 CPU1.AH13 ; CPU1.AF2 117.54,36.14 117.54,36.56 CPU1.AF4 ; CPU1.G5 126.82,37.55 127.19,37.18 127.52,37.18 CPU1.F4 ; v2(126.98,39.84) v2(126.35,39.84) v2(125.71,39.84) ; CPU1.AW6 110.83,37.6 110.83,37.36 111.01,37.18 111.61,37.18 CPU1.AT4 ; CPU1.AL52 v2(115.84,63.61) ; v2(109.77,69.92) CPU1.AW62
  BOTTOM w0.229: CPU1.AJ20 115.64,45.85 115.64,45.39 116.06,44.98 CPU1.AJ18 ; CPU1.AL2 114.61,35.78 114.27,35.44 114.27,34.63 114.06,34.41 v2(114.06,34.37) ; CPU1.AB18 118.99,44.55 118.99,44.08 CPU1.AD16
  BOTTOM w0.254: v2(114.13,52.68) 114.18,52.63 CPU1.AL32 ; v2(114.13,52.68) CPU1.AN30 113.8,52.04 113.48,51.72 ; v2(114.13,52.68) 113.8,53.01 CPU1.AN32 113.54,53.36 v2(113.54,53.55) ; v2(131.72,55.41) 131.77,55.46 132.1,55.46 134.91,52.65 134.91,52.38 135.64,51.65 v2(136.4,51.65) 138.57,51.65 139.59,52.68 139.59,57.11 139.34,57.36 138.09,57.36 v2(137.83,57.62) 137.08,58.37 135.78,58.37 135.59,58.18 135.59,57.25 135.23,56.89 134.17,56.89 134.17,56.89 131.27,56.89 130.92,57.24 130.6,57.24 130.59,57.22 130.53,57.22 130.49,57.19 130.29,57.19 130.25,57.22 130.07,57.22 CPU1.B39 ; CPU1.AV70 CPU1.AV69 110.5,74.03 v2(110.77,73.77) 110.69,73.49 CPU1.AV68 ; CPU1.E11 128.25,40.75 ; 128.25,40.75 CPU1.D11 ; 128.25,40.75 CPU1.D10 129.17,40.21 v2(129.23,40.27) 129.26,40.27 129.3,40.22 129.31,40.22 129.32,40.21 CPU1.B10 ; v2(122.25,37.24) 122.56,36.93 CPU1.T4 CPU1.T2 ; CPU1.AL38 v2(114.13,56.29) 114.13,56.16 CPU1.AN37 ; 113.48,51.72 113.8,51.39 CPU1.AN28 ; 113.48,51.72 113.15,51.39 CPU1.AP28 113.09,51.32 112.56,51.32 CPU1.AR28 CPU1.AT28 ; 123.19,42.55 v2(123.21,42.55) ; v2(123.21,42.55) 122.83,42.17 CPU1.R13 ; v2(123.21,42.55) 123.42,42.55 CPU1.N13 ; U3401.14 22.11,43.14 22.5,43.52 v2(22.63,43.52) ; v2(116.8,70.62) 116.62,70.81 116.6,70.81 116.44,70.96 CPU1.AH64 ; v2(116.8,70.62) 116.49,70.31 CPU1.AH63 ; v2(116.8,70.62) 117.11,70.31 CPU1.AF63 ; CPU1.AW32 110.83,52.72 CPU1.AU32 ; CPU1.AW38 110.38,56.49 110.94,56.49 CPU1.AU38 ; CPU1.U67 121.69,72.91 v2(121.37,72.59) 121.69,72.26 CPU1.U66 ; CPU1.AM13 114.86,41.76 114.9,41.71 114.9,41.35 CPU1.AK11 v2(115.86,41.18) ; CPU1.AW34 110.69,54.25 110.92,54.25 111.05,54.37 111.31,54.37 CPU1.AT35 112.3,55.37 112.82,55.37 ; 112.83,58.94 112.83,58.9 CPU1.AR42 ; 112.83,58.94 v2(112.83,59.01) ; 112.83,58.94 113.15,58.62 CPU1.AP42 ; GPU1.AB17 v2(155.17,85.46) ; CPU1.T17 CPU1.T18 ; CPU1.D30 v2(129.23,52.6) CPU1.B30 ; CPU1.Y19 CPU1.Y20 120.39,46.41 120.39,46.77 CPU1.Y21 ; PU5101.18 v2(44.34,100.16) ; CPU1.K18 CPU1.H18 125.57,44.08 CPU1.K16 CPU1.H15 126.04,42.77 CPU1.J13 125.12,41.84 125.12,41.48 CPU1.J11 CPU1.L11 ; v2(111.53,43.49) CPU1.AU15 111.03,42.86 111.03,42.56 110.36,41.89 CPU1.AW12 ; CPU1.D44 128.72,60.67 CPU1.D45 ; CPU1.B22 v2(129.23,47.65) CPU1.D22 CPU1.E21 CPU1.F22 v2(127.02,48.07) ; U4301.3 51.01,94.26 49.93,93.18 48.66,93.18 48.41,92.92 PR4347.2 ; U4301.3 51.01,95.15 50.59,95.57 49.3,95.57 49.27,95.59 v2(49.04,95.59) ; U4301.3 52.01,94.66 PQ4314.S ; v2(109.66,55.07) 109.4,55.19 CPU1.BA36 ; v2(117.45,47.48) 116.89,46.92 CPU1.AG21 116.83,46.85 116.83,46.33 CPU1.AG20 116.89,46.24 116.84,46.18 116.84,45.78 116.89,45.72 CPU1.AG19 CPU1.AG18 CPU1.AG17 ; v2(126.51,75.78) 126.5,75.76 CPU1.H71 ; GPU1.AC22 v2(154.35,89.6) GPU1.AD21 ; CPU1.AU10 110.52,40.29 CPU1.AW10 v2(109.73,40.45) CPU1.BA10 ; GPU1.AD22 v2(153.55,89.6) ; v2(155.23,92.09) 155.61,91.7 GPU1.AB24 ; CPU1.U64 121.69,70.96 v2(121.37,70.64) 121.69,70.31 CPU1.U63 ; CPU1.AJ4 CPU1.AL4 ; USB1.18 7.74,94.58 v2(7.89,94.73) ; 136.68,28.54 137.47,28.54 v2(139.09,26.93) 142.47,26.93 143.28,27.73 143.28,28.31 142.92,28.66 142.92,32.19 142.64,32.47 140.85,32.47 v2(140.71,32.61) 140.26,33.06 139.82,33.06 139.36,32.6 138.35,32.6 137.32,31.57 133.77,31.57 v2(132.23,33.11) ; CPU1.K66 CPU1.K67 125.25,73.14 CPU1.K68 125.14,73.65 CPU1.K70 ; v2(114.17,59.95) 114.45,59.67 CPU1.AM43 ; CPU1.AG16 CPU1.AG17 ; CPU1.AG17 CPU1.AF17 ; CPU1.AW8 v2(110.67,39.73) ; v2(126.97,50.81) CPU1.F28 v2(126.99,51.73) CPU1.J28 ; v2(127.02,48.07) 127.02,48.1 127.32,48.52 CPU1.F23 ; v2(127.02,48.07) CPU1.G22 CPU1.K22 ; CPU1.AL45 114.72,60.16 114.7,60.16 CPU1.AM45 114.45,60.54 114.56,60.64 114.56,61.04 114.45,61.15 CPU1.AM46 114.91,61.78 CPU1.AL48 ; CPU1.AM68 114.34,72.47 CPU1.AL66 CPU1.AL65 114.54,71.6 114.54,71.49 114.48,71.43 114.48,71.04 114.54,70.98 114.54,70.98 CPU1.AL64 ; v2(109.64,57.79) 109.52,57.67 CPU1.BA41 ; 120.09,47.55 119.61,47.08 119.6,47.08 119.44,46.91 CPU1.AB21 ; v2(126.39,24.77) 126.1,24.77 125.63,24.29 R803.1 ; CPU1.BA6 109.06,38.11 108.49,38.11 CPU1.BB6 107.46,38.03 v2(107.44,38) ; CPU1.AR5 CPU1.AT4 CPU1.AT2 ; CPU1.G6 CPU1.F8 v2(126.98,39.84) CPU1.G10 ; CPU1.F68 CPU1.D69 128.37,74.2 v2(128.24,74.33) ; GPU1.AD13 v2(153.55,82.16) GPU1.AD12 ; CPU1.AD13 118.14,41.84 v2(117.99,41.84) ; CPU1.U69 121.69,74.21 v2(121.37,74.54) 121.69,74.86 CPU1.U70 ; CPU1.AW6 v2(110.64,38.71) ; CPU1.AR15 v2(112.18,43.49) CPU1.AR16 ; CPU1.AW64 110.36,70.72 110.46,70.63 110.46,70.01 CPU1.AW62 ; PU4502.18 v2(196.11,70.19) ; CPU1.AW66 110.45,72.24 109.89,72.24 CPU1.AY66 CPU1.BA66 ; CPU1.AD16 CPU1.AB16 ; CPU1.AB16 CPU1.AB15 ; CPU1.AB16 120.06,44.31 CPU1.Y17 ; PR4551.2 200.65,72.94 v2(200.05,72.33) ; CPU1.K61 125.73,69.58 125.72,69.64 125.45,69.9 CPU1.K63 CPU1.K64 CPU1.K65 ; v2(109.77,60.15) CPU1.BA45 ; GPU1.AF11 v2(151.95,81.32) ; CPU1.L2 CPU1.L4 124.8,37.25 124.17,37.25 CPU1.N6 123.48,37.93 123.05,37.93 CPU1.R6 ; CPU1.E18 CPU1.D18 v2(129.23,45.17) CPU1.B18 ; CPU1.BA14 v2(109.73,42.87) CPU1.AW14 ; v2(117.26,34.68) CPU1.AF1 CPU1.AF2 ; CPU1.AA68 119.54,73.11 v2(119.54,72.59) 119.54,72.06 CPU1.AA65 ; GPU1.E2 169.58,73.38 v2(169.58,72.04) ; v2(131.59,125.01) 131.82,125.01 132.35,124.48 PC8203.1 ; CPU1.D62 v2(129.2,69.76) CPU1.B62 ; GPU1.AF1 151.6,72.7 v2(151.55,72.75) ; CPU1.D58 128.06,66.81 CPU1.E56 ; CPU1.F27 v2(126.97,49.9) ; CPU1.AP38 113.15,56.88 v2(113.48,57.21) ; CPU1.AR53 112.65,64.83 112.75,64.69 v2(112.75,64.51) ; v2(192.3,79.97) PU8302.18 ; CPU1.AR11 v2(112.83,40.75) CPU1.AP10 ; CPU1.AR8 v2(112.81,39.83) ; v2(135.68,52.77) 136.06,53.15 C1802.1 ; v2(116.75,73.31) 116.35,72.91 CPU1.AH67 115.69,73.56 CPU1.AK68 CPU1.AK69 ; 112.82,55.37 v2(112.83,55.38) ; 112.82,55.37 112.5,55.05 CPU1.AR35 ; EC4310.2 197.63,15.53 197.63,15.54 198.75,16.66 200.86,16.66 ; v2(123.2,71.29) 123.52,71.61 CPU1.N65 ; v2(127,59.04) 127,59.22 126.72,59.49 CPU1.G43 126.68,59.49 CPU1.J42 ; CPU1.L20 124.42,46.28 124.23,46.28 CPU1.N21 ; CPU1.D47 128.86,61.84 129.24,62.22 129.44,62.22 CPU1.B48 ; CPU1.D47 128.3,61.84 128.21,61.75 v2(127.61,61.75) 127.59,61.75 127.56,61.78 v2(126.95,61.78) ; CPU1.D47 128.72,61.88 CPU1.D48 ; CPU1.BA62 v2(109.77,69.92) ; CPU1.F13 127.59,42.58 127.59,42.67 127.91,43.03 CPU1.E15 ; CPU1.AP35 113.48,55.24 v2(113.48,55.38) 113.8,55.05 CPU1.AN35 ; CPU1.E65 128.29,71.77 128.29,71.97 v2(128.29,71.98) 128.38,71.98 128.72,72.32 CPU1.D66 CPU1.B66 ; CPU1.U10 v2(121.18,40.42) ; CPU1.AP68 112.93,73.1 v2(112.6,72.93) ; v2(123.2,73.24) 123.33,73.24 CPU1.N68 ; CPU1.E50 127.99,63.16 128.35,63.52 v2(128.35,63.54) 128.36,63.56 128.36,64.63 CPU1.D53 128.94,65.21 v2(129.2,65.21) 129.53,65.21 CPU1.B53 ; CPU1.F2 CPU1.F1 127.87,34.74 v2(128.09,34.52) 128.48,34.12 128.67,34.12 130.44,32.36 130.44,32.35 132.99,29.79 ; CPU1.D14 v2(129.23,42.69) CPU1.B14 ; C1801.1 136.78,57.77 v2(136.97,57.58) ; CPU1.AT56 111.48,67.17 110.94,67.17 110.61,66.84 110.6,66.84 110.36,66.61 CPU1.AW55 110.36,65.95 110.54,65.77 ; v2(118.38,8.21) PU5201.4 ; v2(153.55,87.92) GPU1.AD19 GPU1.AD18 ; CPU1.AL35 114.26,54.46 CPU1.AN33 113.54,53.74 v2(113.54,53.55) ; CPU1.W13 v2(120.05,41.8) ; CPU1.AT58 CPU1.AR58 CPU1.AP58 113.23,67.64 113.72,67.64 CPU1.AN58 114.13,68.05 v2(114.13,68.18) 114.45,68.5 CPU1.AM60 ; DM1.231 68.4,27.07 v2(68.39,27.09) ; GPU1.AD16 v2(153.55,85.44) ; GPU1.AE17 v2(152.75,85.48) ; GPU1.AF20 v2(151.95,87.96) ; v2(124.26,39.23) CPU1.L8 CPU1.J8 v2(125.71,39.84) ; v2(125.34,53.58) 125.38,53.55 CPU1.J32 ; v2(112.79,65.4) 112.78,65.4 112.78,65.41 112.66,65.74 CPU1.AR55 ; CPU1.AW57 110.36,67.44 110.11,67.7 109.82,67.7 v2(109.72,67.59) 109.69,67.57 109.27,67.57 CPU1.BA57 ; CPU1.E6 v2(128.29,38.04) CPU1.D6 128.72,37.67 129.31,37.15 CPU1.C5 ; CPU1.AD8 v2(117.94,39.13) ; GPU1.AF5 v2(151.95,75.55) ; CPU1.AP32 113.15,53.17 v2(113.54,53.55) ; CPU1.BA49 109.57,62.56 109.68,62.67 109.7,62.67 v2(109.74,62.71) ; CPU1.AU20 110.62,45.78 v2(110.59,45.8) ; v2(114.13,38.92) CPU1.AM8 114.98,39.37 115.39,38.97 CPU1.AK8 ; GPU1.AE20 v2(152.75,87.96) ; v2(126.97,64.5) 126.97,64.34 CPU1.G52 ; v2(123.36,40.52) 123.36,40.5 CPU1.N10 ; CPU1.BA53 109.51,64.96 v2(109.67,64.8) ; GPU1.AF17 v2(151.95,85.48) ; v2(110.59,45.8) CPU1.AW21 ; v2(110.59,45.8) CPU1.AW18 ; CPU1.AK18 CPU1.AJ18 ; R2009.2 v2(118.1,30.52) ; CPU1.AT63 111.93,70.39 112.43,70.39 CPU1.AR63 112.53,70.44 113.13,70.44 CPU1.AP63 ; GPU1.AE11 v2(152.75,81.32) ; PU4501.18 v2(191.03,57.24)
  BOTTOM w0.279: DM2.5 56.85,85.57 55.66,85.57 v2(55.29,85.95) ; DM1.44 62.88,75.82 62.96,75.9 64.75,75.9 65.09,75.56 65.09,75.51 v2(65.27,75.33) ; DM1.217 66.95,30.57 66.02,29.65 v2(66.01,29.65) ; CPU1.AA4 119.89,36.84 ; DM2.201 53.82,34.57 53.18,33.94 53.18,33.53 53.19,33.53 v2(53.19,33.42) ; v2(66.01,72.61) 66.01,73.57 66.29,73.85 68.35,73.85 68.57,74.07 DM1.51 71.47,74.07 71.52,74.13 ; v2(64.87,30.55) 64.87,30.61 64.69,30.8 64.69,30.83 64.28,31.24 62.97,31.24 62.89,31.32 DM1.214 ; v2(50.25,39.81) 50.23,39.82 DM2.180 ; DM2.222 49.9,29.32 v2(50.11,29.11) ; DM2.99 57.77,62.07 58.27,62.17 v2(58.92,62.17) 58.49,61.74 58.49,60.73 57.83,60.07 DM2.107 ; DM2.68 50.62,69.82 51.36,70.56 51.36,70.6 v2(51.54,70.78) ; v2(51.99,25.36) 51.94,25.31 51.94,24.78 50.99,23.82 DM2.244 ; v2(50.44,67.65) 50.11,67.32 48.65,67.32 DM2.78 ; DM1.168 62.57,42.82 62.86,43.12 64.71,43.12 65.32,42.5 v2(65.32,42.35) ; DM1.26 60.37,80.32 60.01,80.68 v2(60.01,81.34) ; v2(55.04,27.19) 55.16,27.07 DM2.231 ; DM1.60 60.16,71.82 59.55,72.44 v2(59.55,72.69) ; DM1.188 63.15,37.82 v2(63.16,37.82) ; v2(64.76,35.69) 64.59,35.87 64.59,35.92 63.68,36.82 DM1.192 ; DM1.10 61.7,84.32 64.3,84.32 64.76,83.87 v2(64.76,83.71) ; DM1.9 69.9,84.57 68.39,84.57 68.23,84.74 66.11,84.74 65.47,84.1 v2(65.47,83.71) ; DM2.48 49.82,74.82 49.87,74.78 50.3,74.78 50.63,75.11 50.63,75.16 v2(50.8,75.33) ; DM2.239 55.78,25.07 55.49,25.36 v2(55.41,25.36) ; v2(66.97,42.4) 66.97,42.46 67.67,43.16 68.81,43.16 68.89,43.07 DM1.167 ; v2(68.29,40.05) 68.39,40.05 68.86,39.57 DM1.181 72.27,39.57 72.28,39.58 ; v2(68.31,35.71) 68.45,35.57 DM1.197 ; v2(50.11,79.01) 49.79,79.32 DM2.30 ; v2(65.93,34.09) 66.11,34.27 66.11,34.31 66.46,34.67 66.47,34.67 68.33,34.67 68.42,34.57 DM1.201 ; v2(50.9,77.39) 50.72,77.21 50.72,77.16 50.39,76.82 DM2.40 ; DM1.22 61.7,81.32 63.34,81.32 v2(63.34,81.32) ; DM2.44 49.82,75.82 49.92,75.92 51.68,75.92 52.04,75.56 52.04,75.51 v2(52.22,75.33) ; DM2.184 51.23,38.82 51.73,38.32 51.73,38.05 v2(51.83,37.96) ; v2(64.59,27.28) 64.41,27.1 64.41,27.06 63.67,26.32 DM1.234 ; v2(50.08,81.47) 50.06,81.47 49.91,81.32 48.65,81.32 DM2.22 ; DM2.230 49.97,27.32 v2(50.11,27.19) ; DM2.167 55.01,43.07 53.83,41.89 53.83,41.77 v2(53.73,41.67) ; v2(50.08,25.36) 50.03,25.36 50,25.32 DM2.238 ; 71.65,62.06 71.64,62.07 DM1.99 68.67,62.07 v2(68.37,62.37) 68.37,62.37 68.37,63.31 68.64,63.57 DM1.93 ; v2(54.63,31.59) 55.93,31.59 55.94,31.57 DM2.213 ; v2(67.4,75.33) 67.4,74.94 67.55,74.79 68.34,74.79 68.62,75.07 DM1.47 71.83,75.07 71.9,75.14 ; 71.65,77.05 71.62,77.07 DM1.39 68.53,77.07 v2(68.22,77.39) ; v2(52.01,42.3) 51.99,42.33 51.99,42.45 51.6,42.84 49.79,42.84 49.78,42.82 DM2.168 ; v2(159.93,94.57) 159.84,94.48 159.84,93.37 GPU1.U26 ; DM1.40 63.44,76.82 63.77,77.16 63.77,77.21 v2(63.95,77.39) ; DM2.36 49.87,77.82 50.02,77.98 51.1,77.98 51.91,78.78 51.91,78.9 v2(52.01,79.01) ; 71.78,60.16 71.69,60.07 DM1.107 68.97,60.07 v2(68.46,60.58) ; v2(64.97,31.83) 64.97,31.91 65.65,32.59 69.89,32.59 DM1.209 ; v2(51.03,85.95) 51.03,85.89 50.46,85.32 48.65,85.32 DM2.6 ; GPU1.AC26 154.8,93.37 154.65,93.53 v2(154.65,94.72) ; 71.65,79.21 71.55,79.11 70.72,79.11 70.68,79.07 DM1.31 68.52,79.07 v2(68.39,78.94) 68.39,78.59 68.9,78.07 DM1.35 ; DM2.206 50.49,33.32 v2(50.62,33.46) ; v2(54.12,79.01) 54.12,79.18 55.01,80.07 DM2.27 ; DM1.56 62.95,72.82 v2(63.16,72.61) ; DM2.188 50.05,37.82 50.19,37.96 v2(50.56,37.96) ; DM2.223 55.59,29.07 v2(55.06,29.6) ; v2(53.51,72.71) 53.59,72.78 53.59,72.91 54.64,73.96 55.76,73.96 55.88,74.07 DM2.51 ; v2(67.74,62.37) 67.76,62.34 67.76,62.22 68.91,61.07 DM1.103 ; DM2.171 55.4,42.07 v2(55,41.67) ; GPU1.AE14 153.15,83.42 v2(152.75,83.82) 152.35,83.42 GPU1.AF14 ; v2(53.74,77.39) 53.92,77.56 53.92,77.78 54.49,78.35 55.57,78.35 55.85,78.07 DM2.35 ; v2(64.59,72.61) 64.41,72.79 64.41,72.84 63.42,73.82 DM1.52 ; v2(52.96,70.78) 53.14,70.96 53.14,71.01 53.7,71.57 DM2.61 ; v2(65.98,70.65) 65.98,71.13 66.43,71.57 DM1.61 71.32,71.57 71.34,71.59 ; v2(55.41,35.57) 56.85,35.57 DM2.197 ; v2(52.01,22.31) 51.96,22.26 51.96,22.14 51.6,21.78 49.8,21.78 49.75,21.82 DM2.252 ; v2(167.61,92.9) 167.52,92.81 GPU1.H25 ; v2(68.14,72.61) 68.18,72.57 69.9,72.57 DM1.57 71.27,72.57 71.34,72.64 ; DM1.252 62.8,21.82 62.86,21.77 64.86,21.77 v2(65.32,22.23) ; DM1.98 v2(63.14,62.32) ; DM1.222 61.7,29.33 62.95,29.33 v2(63.16,29.11) ; DM2.14 48.65,83.32 50.03,83.32 v2(50.29,83.58) ; DM1.94 60.22,63.32 v2(59.26,64.29) ; v2(68.35,42.4) 68.68,42.07 DM1.171 72.11,42.07 72.16,42.12 ; DM2.19 53.88,82.07 53.49,81.68 53.49,81.55 v2(53.4,81.47) 52.74,81.47 52.52,81.25 52.52,81.25 52.21,80.94 51.97,80.94 51.36,80.32 DM2.26 ; v2(64.48,37.82) 64.53,37.87 64.53,38.28 63.99,38.82 DM1.184 ; GPU1.E20 170.12,87.99 v2(170.12,87.94) ; v2(63.21,79.12) 63,79.32 DM1.30 ; DM2.185 56.85,38.57 57.68,38.57 58.01,38.9 58.01,39.25 57.68,39.57 56.85,39.57 DM2.181 55.25,39.57 v2(55.23,39.6) ; v2(172.83,94.72) 173.2,94.35 173.2,93.7 172.95,93.45 GPU1.A26 ; v2(55.17,68.72) 55.32,68.57 56.85,68.57 DM2.73 ; DM2.192 49.67,36.82 49.77,36.93 50.93,36.93 51.56,36.3 v2(51.56,36.18) ; v2(55.39,79.01) 55.46,79.07 DM2.31 ; v2(173.53,88.27) 172.57,88.27 172.54,88.3 172.48,88.36 GPU1.B20 ; DM1.72 63.14,68.82 v2(63.24,68.72) ; GPU1.E22 169.37,89.62 v2(169.28,89.62) ; v2(162.62,90.48) 162.62,90.53 GPU1.P23 ; v2(68.22,68.72) 68.37,68.57 69.9,68.57 DM1.73 ; DM1.193 67.74,36.57 66.92,35.75 v2(66.92,35.71) ; v2(66.79,68.72) 66.79,68.06 67.28,67.57 69.9,67.57 DM1.77 70.71,67.57 70.72,67.57 71.61,67.57 71.65,67.52 ; DM2.72 51.42,68.82 52.52,67.72 v2(52.52,67.65) ; 71.52,80.1 71.5,80.07 DM1.27 67.94,80.07 67.12,79.25 v2(67.12,78.94) ; 72.41,33.62 72.37,33.57 DM1.205 67.87,33.57 v2(67.35,34.09) ; 71.52,83.02 71.47,83.07 DM1.15 67.78,83.07 67.5,83.36 v2(67.5,83.74) ; DM2.172 49.83,41.82 49.89,41.77 50.33,41.77 50.64,42.08 50.64,42.2 v2(50.74,42.3) ; 71.52,69.56 71.5,69.57 69.9,69.57 DM1.69 ; v2(53.74,68.72) 53.92,68.55 53.92,68.5 54.85,67.57 56.85,67.57 DM2.77 ; v2(63.85,22.31) 63.85,22.35 63.36,22.84 62.85,22.84 62.84,22.82 DM1.248 ; v2(68.17,29.62) 68.71,29.07 DM1.223 72.31,29.07 72.41,29.17 ; v2(50.08,72.71) 50.02,72.71 49.9,72.82 DM2.56 ; v2(63.34,35.69) 63.2,35.82 DM1.196 ; DM1.180 63.08,39.82 63.31,40.05 v2(63.36,40.05) ; v2(67.68,38.12) 67.68,37.95 68.05,37.57 DM1.189 72.13,37.57 72.16,37.55 ; DM1.251 69.9,22.07 68.32,22.07 v2(68.17,22.23) ; DM2.227 54.53,28.07 53.77,27.31 v2(53.77,27.19) ; DM1.235 69.87,26.1 67.45,26.1 66.92,25.57 66.92,25.53 v2(66.74,25.35) 66.92,25.17 66.92,25.12 67.97,24.07 DM1.243 ; v2(63.85,75.33) 63.67,75.15 63.67,75.11 63.36,74.79 62.92,74.79 62.89,74.82 DM1.48 ; v2(64.73,40.05) 64.73,40.11 64.59,40.26 64.59,40.31 64.07,40.82 DM1.176 ; v2(54.38,70.78) 54.56,70.6 54.56,70.56 54.87,70.25 55.32,70.25 55.65,70.57 DM2.65 ; v2(64.08,85.95) 64.08,85.85 63.55,85.32 61.7,85.32 DM1.6 ; v2(67.58,31.84) 67.85,31.57 DM1.213 72.27,31.57 72.28,31.58 ; v2(65.19,78.99) 65.19,78.53 64.71,78.05 63.14,78.05 62.92,77.82 DM1.36 ; GPU1.P26 162.25,93.82 v2(162.22,93.86) ; DM2.60 50.98,71.82 51.35,72.2 v2(51.35,72.71) 51.35,73.03 50.52,73.86 50.07,73.86 50.03,73.82 DM2.52 ; DM1.230 63.12,27.32 v2(63.16,27.28) ; DM2.18 48.65,82.32 50.62,82.32 51.3,81.64 51.3,81.52 v2(51.35,81.47) ; DM2.205 55.15,33.57 v2(55.09,33.51) ; DM2.193 56.85,36.57 54.69,36.57 54.55,36.71 53.88,36.71 53.49,36.33 53.49,36.21 v2(53.46,36.18) ; v2(64.69,33.33) 64.51,33.5 64.51,33.55 64.2,33.86 63.81,33.86 63.35,34.32 DM1.202 ; DM2.202 50.98,34.32 51.28,34.02 51.46,34.02 51.81,33.67 51.81,33.59 v2(51.91,33.49) ; v2(68.62,87.91) 68.62,86.8 68.85,86.57 DM1.1 ; v2(66.92,85.95) 66.92,85.89 67.38,85.44 67.4,85.44 67.42,85.42 67.85,85.42 67.86,85.44 67.98,85.44 68.12,85.57 69.9,85.57 DM1.5 ; DM2.248 49.87,22.82 49.89,22.85 50.33,22.85 50.64,22.53 50.64,22.41 v2(50.74,22.31) ; DM2.93 55.2,63.57 v2(55.18,63.55) 55.18,61.43 55.53,61.07 DM2.103 ; v2(53.87,85.95) 54.05,86.12 54.05,86.28 54.57,86.8 55.77,86.8 56,86.57 DM2.1 ; v2(68.17,25.35) 68.44,25.07 DM1.239 ; v2(50.29,36.18) 50.08,36.18 49.73,35.82 DM2.196 ; DM2.251 55.55,22.07 v2(55.32,22.31) ; v2(50.08,61.32) 48.65,61.32 DM2.102 ; v2(54.21,38.6) 54.25,38.56 54.25,38.42 55.1,37.57 56.85,37.57 DM2.189 ; DM2.82 50.47,66.32 50.85,65.95 v2(50.85,65.73) ; v2(53.14,83.58) 53.14,84.06 53.65,84.57 56.85,84.57 DM2.9 ; v2(67.12,27.1) 67.12,27.5 67.69,28.07 DM1.227 ; DM1.64 62.65,70.82 62.78,70.7 63.09,70.7 v2(63.14,70.65) ; DM1.68 63.68,69.82 63.98,70.12 64.07,70.12 64.38,70.43 64.38,70.48 v2(64.56,70.65) ; DM2.106 48.65,60.32 49.84,60.32 50.77,61.25 v2(50.77,61.33) ; v2(65.32,25.35) 65.17,25.2 65.17,24.96 64.04,23.82 DM1.244 ; DM2.23 55.83,81.07 55.69,80.94 55.09,80.94 54.73,81.29 54.73,81.41 v2(54.67,81.47) ; v2(60.14,64.92) 60.73,64.32 DM1.90 ; DM1.86 62.76,65.32 62.99,65.1 64.74,65.1 65.32,65.68 v2(65.32,65.73) ; DM1.14 61.7,83.32 63.08,83.32 63.33,83.58 v2(63.33,83.74) ; 71.65,65.62 71.6,65.57 DM1.85 ; v2(52.73,31.61) 52.78,31.66 52.78,32.05 53.3,32.57 DM2.209 ; v2(54.05,22.31) 54.12,22.39 54.12,22.7 54.5,23.07 56.85,23.07 ; 71.34,70.57 71.33,70.57 DM1.65 68.79,70.57 68.34,70.12 67.78,70.12 67.4,70.5 v2(67.4,70.65) ; DM2.98 48.65,62.32 v2(50.09,62.32) ; GPU1.U23 159.77,90.85 v2(159.37,90.45) ; 71.9,66.51 71.84,66.57 DM1.81 67.19,66.57 66.74,66.13 v2(66.74,65.73) 66.74,64.94 67.11,64.57 DM1.89 71.75,64.57 71.78,64.6 ; DM2.90 49.77,64.32 v2(50.21,63.88) 49.66,63.32 48.65,63.32 DM2.94 ; DM2.176 50.72,40.82 51.48,40.07 51.48,39.88 v2(51.52,39.84) ; v2(65.75,37.74) 65.75,38.2 66.59,39.04 68.22,39.04 68.68,38.57 DM1.185 ; GPU1.AC8 v2(155.17,78.02) GPU1.AB7 155.72,77.47 156.32,77.47 GPU1.AA7 ; DM2.64 50.07,70.82 v2(50.11,70.78) ; v2(51.71,83.58) 51.71,83.73 51.12,84.32 DM2.10 ; GPU1.Y23 157.28,90.9 v2(156.86,91.32) ; DM1.172 63.42,41.82 63.93,42.33 v2(63.93,42.43) ; DM2.217 55.85,30.57 55.68,30.75 53.71,30.75 53,30.04 v2(53,29.6) ; v2(172.59,83.05) 172.51,83.05 172.17,83.4 GPU1.B14 ; DM2.15 55.79,83.07 v2(55.29,83.58) ; v2(63.77,31.83) 63.7,31.9 63.7,32.02 63.4,32.32 63.38,32.32 63.35,32.35 62.92,32.35 62.89,32.32 DM1.210 ; GPU1.B23 172.47,90.85 172.62,91.01 172.93,91.01 v2(172.96,91.03) ; DM2.43 54.34,76.07 53.64,75.38 v2(53.64,75.33) 54.18,74.79 55.29,74.79 55.57,75.07 DM2.47 ; v2(63.19,25.35) 63.16,25.32 DM1.238 ; v2(58.23,69.58) 58.23,69.57 56.85,69.57 DM2.69 ; v2(66.74,22.23) 66.74,22.29 67.53,23.07 DM1.247 69.9,23.07 71.78,23.07 ; v2(65.5,85.95) 65.32,86.12 65.32,86.17 64.88,86.61 63.05,86.61 62.77,86.32 DM1.2 ; 71.78,76.16 71.69,76.07 DM1.43 67.24,76.07 66.69,75.52 v2(66.69,75.33) ; v2(52.27,65.73) 52.09,65.55 52.09,65.51 51.78,65.19 49.85,65.19 49.72,65.32 DM2.86 ; v2(165.15,92.87) 165.14,92.87 164.77,92.5 GPU1.L25 ; DM2.218 50.57,30.32 51.36,29.53 51.36,29.29 v2(51.54,29.11) ; v2(55.12,65.73) 55.27,65.57 56.85,65.57 DM2.85 ; v2(63.77,62.32) 63.72,62.27 63.72,62.11 62.93,61.32 DM1.102 ; DM1.226 63.84,28.32 64.41,28.89 64.41,28.93 v2(64.59,29.11) 64.41,29.29 64.41,29.34 63.42,30.32 DM1.218 ; v2(63.9,65.73) 63.72,65.9 63.72,65.95 63.34,66.32 DM1.82 ; DM2.243 54.92,24.07 54.17,24.82 54.17,25.33 v2(54.14,25.36) 54.22,25.44 54.22,25.56 54.77,26.11 55.84,26.11 55.88,26.07 DM2.235 ; 72.41,27.14 72.35,27.07 DM1.231 ; DM2.2 49.68,86.32 49.92,86.56 51.88,86.56 52.27,86.17 52.27,86.12 v2(52.45,85.95) ; DM2.214 49.77,31.32 49.84,31.25 50.31,31.25 50.62,31.57 50.62,31.64 v2(50.77,31.79) 50.77,31.86 50.3,32.32 DM2.210 ; v2(65.4,81.33) 65.4,81.42 65.39,81.42 65.39,81.56 64.63,82.32 61.7,82.32 DM1.18 ; DM1.206 63.26,33.32 v2(63.26,33.33) ; v2(55.17,77.39) 55.48,77.07 DM2.39 ; DM2.175 55.78,41.07 55.58,40.88 54.09,40.88 53.26,40.05 53.26,39.68 v2(53.21,39.64) ; v2(64.41,62.32) 64.41,61.75 62.98,60.32 DM1.106 ; GPU1.H23 167.61,90.5 v2(167.61,90.46) ; DM2.226 50.22,28.32 v2(50.31,28.23) ; v2(65.37,68.72) 65.37,68.55 64.14,67.32 DM1.78 ; v2(55.41,72.71) 55.44,72.71 55.57,72.57 56.85,72.57 DM2.57 ; 71.65,82 71.58,82.07 DM1.19 67.78,82.07 67.45,81.74 v2(67.45,81.35) 67.86,80.95 68.74,80.95 68.85,81.05 68.85,81.05 68.88,81.07 DM1.23 71.61,81.07 71.65,81.11 ; v2(66.1,40.05) 66.1,40.31 67.05,41.25 68.65,41.25 68.83,41.07 DM1.175 ; v2(53.69,65.73) 53.87,65.9 53.87,65.95 54.5,66.57 56.85,66.57 DM2.81 ; DM2.234 50.63,26.32 51.28,26.97 51.28,27.09 v2(51.38,27.19) ; DM2.89 54.91,64.57 v2(54.85,64.51)
  BOTTOM w0.305: ED6602.3 ED6602.8 204.58,41.24 v2(204.62,41.2) ; CPU1.G63 126.33,70.94 v2(126.33,71) 126.31,70.98 CPU1.K64 ; 216.97,19.84 216.78,19.65 SSD1.33 ; 216.97,19.84 216.97,18.29 v2(216.94,18.25) ; 216.97,19.84 v2(216.97,21.15) SSD1.27 ; CPU1.R6 122.36,37.24 v2(122.25,37.24) ; v2(8.27,92.03) 8.2,92.1 USB1.17 ; v2(225.32,4.28) 225.32,4.53 225.3,4.55 HDD1.14 ; C2202.1 139.29,31.79 v2(139.97,32.47) ; CPU1.AM55 114.91,65.43 CPU1.AL55 ; v2(120.09,39.86) 120.3,39.86 CPU1.W9 ; CPU1.K67 125.55,73.03 126.25,73.03 v2(126.46,73.24) 126.75,72.94 CPU1.G66 ; v2(57.55,8.98) 57.7,9.13 LEDCN1.1 ; CPU1.AW51 110.43,63.68 110.43,62.92 110.39,62.88 110.39,62.58 CPU1.AW49 ; v2(97.35,97.34) 97.35,97.34 LCD1.15 ; CPU1.N21 123.55,46.91 123.39,47.08 122.97,47.08 122.84,46.95 122.8,46.95 CPU1.P21 122.76,47.15 122.43,47.48 v3(122.37,47.48) ; CPU1.P19 122.57,45.61 CPU1.T18 CPU1.V18 ; v2(173.41,78.25) 173.38,78.25 173.34,78.29 172.36,78.29 172.2,78.44 GPU1.B8 ; v2(169.31,82.97) 169.74,83.4 GPU1.E14 ; CPU1.J25 126.96,49.89 v2(126.97,49.9) ; CPU1.G48 126.69,62.04 v2(126.95,61.78) ; PQ4415.4 207.12,27.5 v2(207.12,27.51) ; v2(145.05,71.46) 144.69,71.46 144.43,71.21 U7301.3 ; CPU1.AM45 114.45,60.23 v2(114.17,59.95) ; v2(118.72,47.55) 118.59,47.43 118.59,47.32 118.55,47.28 118.55,46.93 CPU1.AD21 CPU1.AD20 CPU1.AD19 ; LCD1.12 95.85,97.33 v2(95.85,97.33) ; 216.78,15.15 217,15.37 217,16.38 216.73,16.65 ; 216.78,15.15 SSD1.51 ; 216.78,15.15 217.1,14.83 v2(217.1,13.8) 216.95,13.65 SSD1.57 ; SSD1.39 216.83,18.15 v2(216.94,18.25) ; CPU1.K16 CPU1.L16 CPU1.L17 124.33,44.42 124.33,44.85 CPU1.L18 124.22,45.18 124.04,45.18 CPU1.N19 123.79,45.61 CPU1.L20 ; GPU1.Y26 157.29,93.48 157.38,93.56 157.38,94.66 v2(157.32,94.71) ; CPU1.AG16 117.54,43.01 CPU1.AF15 ; v2(140.21,75.12) 140.23,75.14 140.23,75.78 139.86,76.15 PQ4416.1 ; SSD1.15 v2(216.91,24.15) ; CPU1.V16 CPU1.V17 CPU1.T17 CPU1.P17 ; CPU1.AT68 111.97,73.16 v2(112.6,72.93) ; R1915.2 98.22,36.37 98.91,37.07 R1917.2 R1920.2 100.15,37.07 100.5,36.71 R1918.2 ; VRAM2.A14 183.25,117.4 v2(183.79,117.4) ; v2(121.05,20.59) EC6504.2 121.01,19.98 120.36,19.33 Q6503.S ; LCD1.26 v2(102.85,97.47) 102.92,97.47 103.35,97.04 LCD1.27 ; CPU1.AF10 117.4,40.17 116.92,39.69 v2(116.89,39.69) ; 110.54,65.77 110.52,65.74 110.52,65.18 110.36,65.02 CPU1.AW53 ; CPU1.AL4 CPU1.AL2 ; v2(216.94,18.25) 216.94,16.85 216.73,16.65 ; CPU1.E15 128.07,43.11 128.45,43.11 128.72,42.84 CPU1.D14 ; CPU1.T21 121.54,47.3 v3(121.54,47.45) ; LEDCN1.4 54.7,9.29 55.01,8.98 55.23,8.98 v2(55.24,8.97) ; v2(116.81,41.79) 116.79,41.81 116.66,41.81 116.33,42.14 CPU1.AH13 ; PQ4415.1 v2(210.52,28.81) ; GPU1.B17 172.48,85.88 172.57,85.79 173.31,85.79 v2(173.35,85.75) ; v2(68.17,65.73) 68.32,65.57 DM1.85 ; GPU1.E17 169.73,85.88 v2(169.32,85.48) ; VRAM3.A14 150.74,106.5 v2(150.34,106.09) ; v2(127,59.04) 127,58.88 127.3,58.58 CPU1.F42 ; GPU1.AD15 153.95,84.21 v2(153.54,83.81) ; LCD1.18 98.85,97.32 v2(98.83,97.33) ; 216.73,16.65 SSD1.45 213.91,16.65 ED6301.8 213.63,16.64 ; CPU1.Y21 120.25,47.29 120.09,47.46 v2(120.09,47.59) ; v2(128.42,36.71) 128.3,36.84 CPU1.F4 ; GPU1.E25 170.09,92.89 v2(170.12,92.89) ; CPU1.AK63 115.34,70.31 114.69,70.96 CPU1.AL64 ; CPU1.AD16 118.38,43.66 CPU1.AF17 ; CPU1.B58 129.28,67.47 v2(129.23,67.42) 129.18,67.47 CPU1.D58 ; v2(216.97,25.65) SSD1.9 ; DBEC1.4 v2(180.36,3.89) ; v2(115.46,4.8) PU5201.19 ; LCD1.25 102.35,97.02 v2(101.85,97.52) LCD1.24 ; HDD1.20 v2(228.3,4.09) ; CPU1.G58 CPU1.G60 126.69,68.84 v2(126.98,69.13) ; 55.65,13.42 PU5102.4 ; v2(173.25,76.01) 173.23,76.01 173.16,75.95 GPU1.B5 ; 128.36,64.63 128.02,64.98 CPU1.E53 ; CPU1.D25 128.85,49.36 129.33,49.36 CPU1.C25 129.41,49.74 v2(129.23,49.92) 129.03,50.12 CPU1.D26 ; v2(126.97,66.33) 126.97,66.17 CPU1.G55 ; GPU1.AG2 v2(151.55,72.75) ; GPU1.B1 173.53,72.7 ; v2(112.47,12.15) 112.7,11.92 U4006.5 ; PU5102.8 PU5102.11 ; HDD1.7 v2(221.8,4.41) ; CPU1.AN40 113.48,57.34 v2(113.48,57.21) 113.48,57.07 CPU1.AN38 ; HDD1.17 v2(226.8,4.15) ; v2(140.9,8.98) TPCON1.5 ; VRAM3.U1 161.69,119.3 v2(161.79,119.4) ; LCD1.28 v2(103.85,97.5) ; SSD1.21 v2(216.87,22.65)
  BOTTOM w0.33: v2(181.15,117.73) 181.15,117.71 181.55,117.31 VRAM2.A12 ; v2(180.34,105.7) 180.75,106.1 VRAM2.R11 ; VRAM3.U3 159.55,119.31 159.15,119.71 v2(159.15,119.73) ; v2(172.21,107.27) 172.32,107.27 VRAM2.N1 ; VRAM3.E14 150.32,109.27 v2(150.21,109.27)
  BOTTOM w0.356: v2(183.74,106.2) 183.56,106.2 183.46,106.1 VRAM2.R14 183.04,105.99 182.46,105.99 VRAM1.C13 ; v2(124.97,116.52) 125.31,116.19 PQ8306.1 125.99,115.93 126.26,115.66 C8310.2 ; VRAM2.B5 175.93,116.5 v2(175.54,116.11) ; VRAM3.U12 152.35,119.36 152.42,119.43 v2(152.42,119.98) ; v2(184.45,107.61) 184.16,107.9 183.35,107.9 VRAM2.N14 ; VRAM2.K1 173.15,110.5 173.15,110.51 ; 173.15,110.51 v2(173.15,110.52) ; 173.15,110.51 173.55,110.11 VRAM2.K2 ; v2(179.53,116.84) 179.57,116.84 179.92,116.5 VRAM2.B10 ; VRAM3.E1 161.53,110.08 161.67,110.08 v2(161.7,110.11) ; v2(159.13,107.69) 159.54,108.1 VRAM3.C3 ; v2(125.39,119.26) 125.32,119.19 PQ8305.1 ; VRAM3.F5 157.83,110.5 v2(157.42,110.91) 157.82,111.3 VRAM3.G5 ; VRAM3.C1 161.32,108.1 v2(161.7,107.73) ; VRAM2.U3 174.36,104.5 v2(174.76,104.9) ; VRAM2.C1 172.69,115.76 172.28,115.76 v2(172.08,115.96) ; VRAM3.G10 154.34,110.91 v2(154.36,110.91) ; VRAM3.C14 150.75,108.08 150.21,107.54 v2(150.21,107.52) ; VRAM2.C3 174.37,115.7 v2(174.77,116.1) 174.77,116.07 175.13,115.7 VRAM2.C4 ; VRAM3.K2 v2(160.75,113.3) 161.15,113.7 VRAM3.K1 ; VRAM2.L5 176.33,108.92 v2(176.48,108.92) ; 151.15,112.5 150.75,112.1 VRAM3.H14 ; 151.15,112.5 151.15,112.5 VRAM3.H13 ; 151.15,112.5 v2(151.15,112.52) ; v2(161.46,106.01) 161.46,106.19 VRAM3.A1 ; v2(174.75,108.1) 174.35,107.7 VRAM2.N3 ; GPU1.AB14 155.6,83.4 v2(156.02,82.98) ; v2(179.42,104.77) 179.95,105.3 VRAM2.T10 179.95,105.3 v2(180.34,105.7) ; 174.75,106.5 v2(174.75,106.51) ; 174.75,106.5 174.75,106.5 VRAM2.R4 175.15,106.09 v2(175.54,105.7) 175.94,105.3 VRAM2.T5 ; 174.75,106.5 VRAM2.R3 ; VRAM3.R11 152.77,118.08 v2(152.77,118.1) 152.37,117.7 VRAM3.R12 ; GPU1.H5 v2(166.81,75.5) ; v2(172.08,111.88) 172.27,111.7 VRAM2.H1 ; VRAM3.A12 152.37,106.5 v2(152.77,106.9) ; VRAM2.H2 173.55,111.7 v2(173.15,112.1) ; VRAM3.D10 153.99,108.9 v2(154.38,108.51) ; v2(155.98,80.52) 155.59,80.9 GPU1.AB11 ; VRAM2.A3 174.35,117.36 v2(174.73,117.73) ; GPU1.P5 v2(161.85,75.5) ; CPU1.F4 CPU1.F2 ; VRAM3.R1 161.39,117.7 161.47,117.78 161.68,117.78 v2(161.76,117.85) ; v2(174.75,113.7) VRAM2.E3 ; v2(158.35,115.7) 157.95,115.3 VRAM3.M5 ; v2(150.08,117.96) 150.34,117.7 VRAM3.R14 VRAM4.C13 ; PQ8305.4 v2(123.67,116.65) ; VRAM3.R3 159.53,117.7 v2(159.13,118.1) 158.75,117.72 VRAM3.R4 ; PQ8306.4 123.65,114.35 123.36,114.06 122.91,114.06 v2(122.9,114.05) ; CPU1.E46 127.61,61.7 v2(127.61,61.75) ; VRAM2.G10 179.4,112.5 v2(179.38,112.47) ; v2(172.34,104.09) 172.74,104.5 VRAM2.U1 ; VRAM3.F10 154.36,110.09 v2(154.36,110.08) ; VRAM2.F10 179.95,113.3 v2(180.35,113.7) ; VRAM3.C12 152.35,108.1 v2(152.76,108.51) 153.15,108.11 VRAM3.C11 ; v2(154.38,114.91) 153.97,114.5 VRAM3.L10 ; VRAM2.G5 175.97,112.5 v2(176.38,112.91) ; v2(157.5,114.88) 157.53,114.88 157.91,114.5 VRAM3.L5 ; VRAM3.B10 154.32,106.93 v2(154.36,106.93) ; VRAM3.T5 157.94,118.5 v2(157.53,118.91) ; VRAM2.R11 180.75,106.09 v2(181.14,105.7) 181.54,106.1 VRAM2.R12 ; VRAM3.M10 153.96,115.3 v2(154.35,115.7) ; C8309.2 125.94,121.64 PQ8307.1 125.31,121.92 v2(124.94,122.29) ; VRAM2.M5 176.06,108.5 176.43,108.13 v2(176.48,108.13) ; VRAM2.U14 183.23,104.5 183.62,104.11 v2(183.7,104.11) ; VRAM2.H14 183.15,111.7 v2(182.75,111.3) VRAM2.H13 ; v2(184.11,114.21) 184.09,114.18 183.83,114.18 183.8,114.15 183.2,114.15 VRAM2.E14 ; VRAM3.K14 150.75,113.7 v2(151.15,114.1) 151.55,113.7 VRAM3.K13 ; VRAM2.E1 v2(172.11,114.1) ; GPU1.B27 172.15,94.14 172.73,94.72 v2(172.83,94.72) ; v2(170.16,80.48) 170.16,80.51 GPU1.E11 ; GPU1.H2 v2(166.81,73.1) ; VRAM2.K13 182.73,110.1 182.75,110.08 183.13,110.08 VRAM2.K14 183.18,110.07 183.47,110.07 v2(183.69,109.85) ; v2(179.4,106.35) 179.4,106.35 VRAM2.P10 ; VRAM3.H1 160.76,111.71 v2(160.73,111.71) 160.35,112.09 VRAM3.H2 ; v2(137.43,79.08) 137.5,79.02 PQ4416.4 ; GPU1.U2 v2(159.37,73.1) ; VRAM2.C12 181.16,116.09 v2(181.13,116.09) 181.13,116.09 180.75,115.71 VRAM2.C11 ; PQ8301.1 v2(125.31,124.84) ; v2(109.73,52.75) 109.37,52.72 CPU1.BA32 ; GPU1.A2 172.95,73.28 v2(173.88,72.35) ; VRAM2.C14 183.46,115.7 183.62,115.87 183.66,115.87 v2(183.75,115.96) ; v2(181.15,113.7) 181.55,114.1 VRAM2.E12 ; VRAM2.R1 172.75,106.06 v2(172.21,105.52) ; v2(159.15,109.3) 159.55,109.7 VRAM3.E3 ; v2(152.75,110.1) 152.35,109.7 VRAM3.E12 ; VRAM2.M10 179.83,108.5 v2(179.42,108.91) 179.82,109.3 VRAM2.L10 ; v2(150.21,116.04) 150.27,116.1 VRAM3.N14 ; v2(159.15,115.7) 159.55,116.1 VRAM3.N3 ; VRAM2.U12 181.53,104.5 v2(181.1,104.07) ; VRAM3.U14 150.75,119.32 v2(150.34,119.73) ; VRAM2.F5 175.96,113.3 v2(176.35,113.7) ; GPU1.E8 169.75,78.43 v2(169.33,78.01) ; GPU1.L5 v2(164.33,75.5) ; GPU1.U5 v2(159.37,75.5) ; PQ8307.4 v2(123.65,119.63) ; VRAM3.A3 159.53,106.5 v2(159.1,106.07) ; v2(179.28,115.23) 179.6,114.9 VRAM2.D10 ; VRAM2.N12 181.55,107.7 v2(181.15,107.3) ; GPU1.P2 v2(161.85,73.9) ; GPU1.L2 v2(164.33,73.9) ; v2(153.54,118.11) 153.93,118.5 VRAM3.T10 ; GPU1.AF23 v2(152.75,90.45) ; v2(158.34,107.72) 158.37,107.72 VRAM3.C4 ; v2(172.34,117.73) 172.34,117.71 VRAM2.A1 ; v2(152.75,115.7) VRAM3.N12 ; v2(157.56,106.91) VRAM3.B5 ; VRAM3.N1 v2(161.74,116.1) ; PQ8301.4 v2(123.65,122.3)
  BOTTOM w0.381: PC8302.2 154.63,125.16 v2(154.63,124.01) ; GPU1.L23 v2(165.13,90.5) ; v2(155.22,73.11) 154.84,73.5 GPU1.AC2 ; GPU1.Y2 157.32,73.5 v2(157.72,73.1) ; GPU1.Y5 157.3,75.9 v2(157.7,75.5) ; v2(109.73,52.75) 110,52.72 CPU1.AW32 ; v2(108.37,11.39) 108.91,11.39 C4034.2 ; v2(155.21,75.53) 155.21,75.54 GPU1.AC5
  BOTTOM w0.406: v2(145.56,6.82) 145.56,6.18 146.58,5.16 TPCON1.9 ; v2(11.45,94.66) 11.09,94.3 10.62,94.3 ED3802.3 ED3802.8 ; DBEC1.8 181.88,5.04 182.52,4.41 v2(182.52,3.9) ; v2(163.34,37.55) 163.65,37.25 163.65,36.92 PR4817.2 ; v2(209.24,9.67) 209.17,9.74 ED6001.3 ED6001.8 ; GPU1.AG26 150.9,93.3 v2(150.9,93.31) ; C1115.2 108.05,12.53 C4013.2 107.65,11.76 107.86,11.76 108.03,11.58 108.03,11.58 108.22,11.39 v2(108.37,11.39) ; ED6301.3 213.63,16.64
  BOTTOM w0.457: GPU1.U18 v2(158.75,86.9) GPU1.V17 ; GPU1.V15 v2(158.75,84.9) GPU1.U16 GPU1.T17 v2(160.75,86.9) GPU1.R18 ; GPU1.L18 v2(164.75,86.9) GPU1.M17 GPU1.N16 v2(162.75,84.9) GPU1.P15 GPU1.R14 v2(160.75,82.9) GPU1.T13 GPU1.U12 v2(158.75,80.9) GPU1.V11 ; GPU1.K11 v2(166.75,80.9) ; 135.66,18.09 136.18,17.57 PWSW1.6 ; GPU1.K13 v2(166.75,82.9) ; X2201.2 140.36,32.08 140.1,32.34 140.1,32.35 v2(139.97,32.47) ; GPU1.V13 v2(158.75,82.9) GPU1.U14 GPU1.T15 v2(160.75,84.9) GPU1.R16 GPU1.P17 v2(162.75,86.9) GPU1.N18 ; GPU1.M11 v2(164.75,80.9) ; GPU1.T11 v2(160.75,80.9) ; GPU1.P11 v2(162.75,80.9) ; GPU1.K15 v2(166.75,84.9) ; GPU1.M13 v2(164.75,82.9) ; GPU1.K17 v2(166.75,86.9) ; GPU1.M15 v2(164.75,84.9) ; GPU1.P13 v2(162.75,82.9)
  BOTTOM w0.508: ED3604.2 19.07,25.36 v2(18.56,24.85) ; PC1045.2 PC1070.2 ; v3(188.87,111.97) 188.92,111.92 Q7801.S ; 6.45,57.45 USB2.12 4.5,57.94 ; v2(41.3,84.87) 40.75,85.41 DM2.261 ; v2(209.7,72.1) 207.9,72.1 FAN1.6 ; v2(62.12,13.68) 62,13.8 PC5120.2 ; v2(62.12,13.68) 63.65,15.2 69.62,15.2 69.87,14.95 G1801.1 ; v2(62.12,13.68) 62.12,13.42 61.74,13.04 PC5119.2 ; KB1.1 v2(88.42,10.64) 89.06,10 KB1.31 ; v2(61.67,88.68) 61.67,91.4 C5535.2 C5536.2 ; EC2711.2 23.82,13.47 v2(23.9,13.55) ; LCD1.51 86.61,99.3 86.51,99.4 86.51,99.5 85.87,100.13 v2(85.87,100.67) ; v2(92.86,18.12) 92.86,17.23 92.16,16.53 Q6501.S 90.58,16.53 R6509.2 ; 1.25,100.01 USB1.22 2.58,99.17 ; PR4617.2 160.12,43.09 v3(160.29,43.27) ; v2(101.37,35.14) 100.96,35.55 R1918.2 ; Q8301.S 119.6,96.94 v2(120.16,97.5) ; R1719.2 v2(123.72,85.56) ; R1719.2 123.64,84.67 EC1709.2 ; R1719.2 123.74,84.62 C1711.2 EC1708.2 ; v2(136.97,57.58) 137.24,57.31 X1801.4 ; PC8304.2 PC8303.2 v2(143.02,124.95) ; 4.5,40.26 USB2.13 6.45,40.75 ; v2(67.46,95.34) R5542.2 ; R5542.2 68.42,100.08 TCBD1.21 ; R5542.2 68.42,93.64 67.97,93.18 U5502.2 ; v2(17.2,74.68) 17.34,74.54 R5741.2 ; EC8993.2 C2416.2 152.37,16.18 v2(152.38,16.19) 152.37,16.2 C2421.2 ; 9.36,65.84 HDMI2.21 9.36,63.86 ; v2(102.42,53.08) 102.42,53.14 102.44,53.15 102.44,53.22 103.21,53.99 103.98,53.99 ; USB1.15 8.54,88.62 ; USB1.15 7.45,87.84 ; USB1.15 6.36,88.62 ; v2(61.02,1.52) 61.02,3.93 LEDCN1.5 ; v2(169.26,37.3) 167.99,37.3 PC4803.2 ; v2(21.86,63.21) 21.86,63.87 R5803.2 ; C5858.2 20.14,53.91 C3404.2 ; 5.29,96.3 USB1.B1 5.92,97.34 ; PC4427.2 176.38,29.55 PD4304.A 176.25,29.42 v2(175.15,29.42) ; PC4417.1 v2(199.44,37.2) ; v2(149.64,21.88) 149.16,21.88 148.71,21.44 148.11,21.44 147.74,21.81 147.74,22.34 148.65,23.25 C2414.2 ; R1715.2 118.31,19.04 EC1703.2 C1701.2 118.33,17.97 118.13,17.77 118.13,17.39 117.72,16.98 117.34,16.98 117.29,16.93 R2019.2 v2(116.73,16.09) ; EC2501.2 172.31,20.43 170.84,21.9 v2(170.84,21.91) ; v2(21.76,39.55) C3502.2 ; v2(128.54,118.32) 128.42,118.2 PC8225.1 ; v2(137.26,71) 137.21,70.95 R406.2 ; PC4431.2 198.34,22.16 PC4433.2 198.95,22.24 v2(199.03,22.31) PR4410.1 199.05,23 PC4430.2 ; v2(216.97,21.15) 216.87,21.24 v2(216.87,22.65) 216.91,22.69 v2(216.91,24.15) 216.97,24.21 v2(216.97,25.65) ; v2(164.36,3.8) 163.95,3.8 163.41,4.33 DB1.3 ; EC8999.2 35.4,11.72 v2(35.2,11.52) PR5404.2 36.72,11.47 PU5401.1 ; v2(187.73,75.65) 187.9,75.48 PR8323.1 188.64,75.45 PC8316.2 ; C4012.2 114.4,8.72 114.85,9.18 PC5202.2 PC5213.2 ; USB1.14 5.12,87.86 ; USB1.14 6.45,87.02 ; USB1.14 5.12,86.19 ; USB1.14 3.78,87.02 ; C2201.1 142.4,27.57 v2(142.68,27.86) 141.87,28.67 X2201.4 ; v2(118.38,8.21) 118.38,8.77 PR5204.2 ; EC6501.2 155.06,8.14 C6505.2 155.24,8.32 v2(155.24,8.98) ; 6.45,33.95 USB3.12 4.5,34.44 ; DB1.15 160.8,2.5 160.91,2.62 v2(161.1,2.62) ; PC5213.2 116.17,8.98 PC5215.2 ; PC5213.2 115.97,10.17 v2(116.2,10.4) ; C2746.2 26.99,12.28 C2733.2 ; HDD1.21 v2(216.4,2.15) ; FAN1.5 202.3,71.24 v2(202.95,70.59) ; v2(23.85,96.18) DCIN1.10 ; PC4809.2 157.96,35.7 v2(158.14,35.52) ; PC4603.1 184.5,64.58 PR4628.2 PR4629.2 v2(185.57,63.71) ; v2(14.32,40.04) R3501.2 ; v2(145.05,71.46) 145.26,71.26 R7306.2 ; PR5101.2 v2(43.2,94.83) ; v3(185.82,57.11) 185.69,57.24 PC4651.2 ; HDMI2.22 10.05,80.34 ; HDMI2.22 11.44,79.35 ; HDMI2.22 10.05,78.36 ; v2(15.24,50.61) 15.85,50 ED3602.2 ; PC8301.2 160.18,123.42 v2(159.91,123.15) ; PC4520.2 201.7,68.29 v2(201.95,68.03) ; U5501.2 99.97,91.73 100.4,91.3 102.2,91.3 102.51,90.99 ; TCBD1.22 82.28,101.18 v2(82.95,101.18) 83.46,101.18 83.84,100.8 C5514.2 ; PC4419.2 203.5,33.01 v2(204.59,34.1) 204.65,34.15 IOBD1.63 206.26,34.12 208.52,34.12 IOBD1.65 ; PC4633.2 v2(175.53,54.19) ; LCD1.52 118.24,99.3 v2(119.03,98.51) 120.16,99.65 EC8927.2 ; EC1702.2 138.63,35.47 R1717.2 ; v2(175.53,76.41) 176.16,75.79 X7601.2 ; PC4614.2 v2(183.36,54.77) PC4615.1 ; PC4422.2 206.62,30.29 207.11,30.77 PC4420.1 207.51,30.87 PR4406.2 v2(208.17,31.71) ; 2.58,87.4 USB1.13 2.58,87.02 ; EC5501.2 95.57,95.21 v2(95.73,95.36) ; v2(138.58,34.63) 138.55,35 138.55,35.34 R1717.2 ; 6.45,16.76 USB3.13 5.15,16.76 ; R1501.2 136.21,41.46 135.94,41.73 135.41,41.73 C716.2 135.15,41.74 134.77,42.12 134.77,42.49 v2(134.75,42.51) ; v2(141.37,24.73) 140.43,24.73 C2412.2 ; PQ4304.E 13.47,87.58 v2(12.59,86.7) ; C5861.2 C5860.2 15.62,62.24 v2(15.54,62.16) ; PR8302.2 155.67,125.87 ; EC8982.2 202.28,13.12 v2(202.33,13.17) 202.27,13.23 D4306.1 ; 5.12,98.34 USB1.21 ; USB1.21 6.45,99.17 ; USB1.21 5.12,100.01 ; USB1.21 3.78,99.17 ; v2(127.85,123.72) 127.67,123.53 C8308.1 ; KB1.32 63.13,10 62.12,11.01 v2(62.12,11.52) PC5121.2 ; v2(22.37,15.07) 22.25,15.2 EC8904.2 ; EC6505.2 93.87,13.6 v2(93.87,13.04) ; PC4631.2 v2(170.12,67.73) ; v2(54.5,100.04) EC8912.2 55.11,97.93 PD4302.1 ; v2(111.65,12.13) U4006.9 ; v2(179.98,78.45) C7607.1 179.29,77.6 X7601.4 ; v2(198.14,13.17) 197.89,13.17 197.68,12.97 EC4309.2 ; HDD1.24 v2(230.7,1.74) ; C3404.2 18.99,53.83 C5857.2 ; C3404.2 C3405.2 v2(22.37,53.83) ; C2502.2 173.76,12.03 174.14,12.41 174.14,16.29 v2(174.09,16.34) 173.65,15.91 C2501.2 ; 12.54,48.38 USB2.7 12.54,49.82 ; PR4712.2 152.55,56.02 v2(152.55,56.86) PC4708.2 ; v2(22.22,24.52) 21.61,23.92 C2744.2 ; PWSW1.2 140.55,14.78 140.55,16.31 PWSW1.5 140.55,17.65 140.55,19.18 PWSW1.1 ; PWSW1.2 140.53,14.76 C2411.2 ; PWSW1.2 140.54,14.78 139.93,14.78 v2(138.7,13.55) ; U5801.8 21.66,62.52 21.88,62.3 v2(21.88,61.72) ; v2(21.76,35.5) C3503.2 ; v2(15.9,7.33) 15.57,7 EC8902.2 ; v2(137.94,19.52) 137.94,19.77 137.56,20.15 136.28,20.15 135.66,19.52 135.66,18.09 ; v2(132.23,114.64) 132.91,115.33 PR8224.2 ; PC4638.2 171.28,57.15 PR4661.2 v2(170.6,57.13) ; PR4302.2 56.94,101.38 PD4303.3 v2(56.66,102.45) ; v2(192.93,28.22) 193.12,28.03 PC4424.1 ; 5.29,89.9 USB1.B12 5.92,88.86 ; v2(20.26,29.63) C3516.2 C3515.2 ; ED2902.3 12.54,15.2 12.24,15.51 v2(12.09,15.51) ; SPI25.4 161.68,21.55 161.42,21.81 v2(160.8,21.81) ; EC4306.1 195.78,17.28 v2(196.24,17.74) 196.56,18.06 D4304.1 ; PC8306.2 163.46,121.32 v2(163.49,121.28) ; PC4612.2 185.44,56.48 v3(185.82,56.09) ; v2(144.67,116.29) 145.24,116.86 Q7901.S ; PC8202.1 136.16,122.88 v2(135.94,122.66) ; EC1707.2 112.36,16.01 112.66,15.71 v2(112.66,15.32) 112.54,15.2 C4017.2 EC8997.2 ; ED6601.2 v2(202.46,43.65) ; PR4413.2 195.98,21.5 PC4432.2 194.91,21.42 v2(194.58,21.09) ; R1717.2 138.63,35.41 138.65,35.39 C2115.2 ; v2(137.4,80.45) 137.42,80.43 PQ4402.S ; C2745.2 17.6,22.77 EC3602.2 16.6,22.77 16.15,23.22 v2(16.15,23.33) ; C3520.2 16.76,28.13 v2(15.9,27.27) ; R7520.1 R7521.1 166.77,98.47 v2(166.23,99.01) ; PC4644.2 169.57,60.39 v2(169.74,60.21) PC4641.2 170.53,60.29 PC4639.2 ; v2(146.35,88.25) C7518.2 ; PR4654.2 153.56,52.79 v2(153.06,52.28) ; 12.54,24.88 USB3.7 12.54,26.32 ; v2(204.36,69.41) 204.6,69.18 FAN1.2 ; PC4421.2 193.31,31.96 ; v2(174.9,67.52) PC4601.2 174.98,68.41 PC4624.2 PC4629.1 175.71,67.17 175.74,67.14 PR4644.2 ; v2(151.91,11.26) 151.99,11.34 EC6502.2 ; v2(11.32,37.68) TC3501.2 ; IOBD1.61 v2(204.62,35.9) 204.08,36.44 PC4416.1 ; X1801.2 138.75,53.25 138.27,52.77 v2(135.68,52.77) ; 6.36,97.57 USB1.20 7.45,98.36 ; D4305.1 200.86,16.66 200.17,15.97 v2(200.17,15.51) ; v2(52.09,3.01) 52.05,3.05 LEDCN1.6 ; R7301.2 v2(146.45,91.4) ; v2(14.25,96.09) DCIN1.9 ; C7310.2 146.96,120.36 v2(147.59,120.99) ; v2(134.55,114.61) 134.55,114.61 134.03,115.13 PC8207.2 ; C1803.1 C1804.1 102.94,19.95 102.71,20.18 v2(102.71,20.51) ; PC5110.2 v2(42.44,94.83) ; HDD1.23 v2(225.74,1.95) ; C7608.1 v2(177.69,78.45) ; PR4426.2 v2(206.32,26.5) ; v2(116.81,90.03) 116.81,90.56 117.34,91.08 ED5501.2 ; PC4613.2 v2(182.52,68.41) ; EC2502.2 157.55,17.87 v2(157.25,18.17) ; v2(114.23,22.76) 114.3,22.69 114.87,22.69 114.99,22.82 R1823.2 ; v2(11.79,35.65) C3512.2 ; PR4621.1 v3(185.82,58.13) ; v2(125.8,19.75) 126,19.54 EC6503.2 ; SPK1.7 v2(33.85,7.18) ; R402.2 138.23,68.71 137.65,68.71 137.31,69.05 v2(137.31,69.05) ; v2(170.53,64.27) PR4659.1 171.95,64.27 PC4637.2 ; v2(115.75,97.47) LCD1.54 ; PC8222.2 v2(137.94,121.42) ; PC8307.2 v2(163.49,122.59) ; HDD1.22 v2(221.3,1.95) ; v2(19.71,31.08) U3503.2 ; EC8903.2 15.62,20.03 v2(15.41,20.23) ; PC4426.1 v2(194.43,24.12) ; EC2503.2 v2(172.87,17.87) ; SPK1.8 v2(26.25,4.34) ; C2406.2 140.85,9.03 v2(140.9,8.98) ; C5726.1 v2(22.5,75.75) ; PC4429.2 177.72,23.94 v2(177.95,23.71) 178.07,23.84 PC4428.2 ; v2(16.25,31.86) C3519.2 ; PR4627.1 v2(182.77,69.18) ; PC4620.2 178.76,71.46 178.63,71.33 v2(178.63,70.7) PC4621.1 ; Q9104.S 217.9,30.13 v2(217.85,30.19) ; v2(108.22,17.69) 108.2,17.66 EC1704.2 ; PR5105.2 v2(45.49,94.96) ; PC5414.2 v2(46.12,0.85) ; 2.17,81.25 HDMI2.23 ; HDMI2.23 4.93,81.25 ; HDMI2.23 3.55,82.24 ; EC8940.2 38.55,0.9 v2(38.5,0.85) ; PC5206.2 105.68,0.85 ; v2(61.8,102.64) PQ4302.E ; v2(15.77,59.4) C5856.2
  vias: v1(19.17,45.63) v1(20.39,38.16) v1(20.72,56.12) v1(25.62,93.64) v1(48.38,97.37) v1(53.97,9.31) v1(59.89,22.9) v1(62.25,97.24) v1(65.37,102.04) v1(78.58,29.32) v1(81.02,48.45) v1(88.14,48.98) v1(89.15,67.47) v1(91.92,84.19) v1(95.63,66.86) v1(97.35,58.53) v1(97.46,69.88) v1(97.48,68.87) v1(99.61,84.85) v1(99.92,52.11) v1(102.76,96.46) v1(110.41,99.45) v1(112.39,75.04) v1(113.58,83.63) v1(114.93,67.91) v1(116.83,97.57) v1(122.88,97.65) v1(123.82,124.01) v1(127.25,86.57) v1(128.37,35.85) v1(135.05,113.42) v1(140.71,46.7) v1(141.12,66.81) v1(141.14,50.76) v1(142.51,55.43) v1(144.27,104.51) v1(145.51,36.89) v1(145.87,27.65) v1(163.95,39) v1(164,49.74) v1(186.38,91.17) v1(190.77,110.12) v1(190.93,7.53) v1(191.08,36.64) v1(197.53,23.79) v1(198.67,81.75) v1(213.61,21.45) v2(1.32,81.04) v2(2.28,60.59) v2(3.35,99.99) v2(3.4,85.2) v2(3.45,83.02) v2(3.58,15.45) v2(3.78,59.14) v2(4.24,39.38) v2(4.21,35.52) v2(5.18,88.4) v2(5.2,97.8) v2(6.14,63.41) v2(6.22,80.78) v2(6.57,99.99) v2(7.74,16.93) v2(7.77,15.45) v2(7.92,57.8) v2(8.16,90.56) v2(8.12,40.42) v2(8.22,96.81) v2(8.55,63.05) v2(8.68,99.48) v2(8.76,34.25) v2(9.42,15.45) v2(9.93,16.88) v2(11.17,40.42) v2(11.25,57.8) v2(11.5,34.25) v2(11.73,16.93) v2(12.09,85.56) v2(12.14,16.23) v2(12.44,100.01) v2(12.85,89.11) v2(12.97,94.83) v2(13.06,70.38) v2(13.1,90.64) v2(13.61,101.97) v2(13.71,85.81) v2(14.12,100.29) v2(14.5,96.73) v2(14.88,85.85) v2(14.88,67.25) v2(14.93,83.6) v2(16.28,35.94) v2(16.58,101.13) v2(16.55,7.78) v2(16.96,83.43) v2(17.29,38.82) v2(17.29,35.93) v2(17.77,80.1) v2(17.8,80.73) v2(17.95,84.3) v2(18.18,101.94) v2(18.18,60.03) v2(18.59,82.97) v2(18.74,85.64) v2(19.2,60.03) v2(19.2,59.14) v2(19.32,60.92) v2(20.09,60.03) v2(20.09,42.89) v2(20.72,101.94) v2(20.72,71.97) v2(20.72,47.71) v2(23.13,15.07) v2(23.26,101.94) v2(23.26,0.85) v2(23.9,16.6) v2(23.9,15.84) v2(23.9,15.07) v2(23.9,14.31) v2(24.66,15.07) v2(25.42,15.07) v2(25.67,102.58) v2(25.75,62.34) v2(25.8,84.67) v2(25.8,0.85) v2(27.58,103.72) v2(27.58,37.17) v2(28.09,62.44) v2(28.21,60.92) v2(28.34,37.17) v2(28.34,0.85) v2(28.85,59.02) v2(29.87,54.62) v2(29.89,53.91) v2(29.87,36.91) v2(29.99,56.76) v2(29.92,53.1) v2(30.17,58.94) v2(30.37,103.72) v2(30.63,62.44) v2(30.75,44.03) v2(30.75,41.87) v2(30.88,36.16) v2(30.88,35.39) v2(30.88,0.85) v2(31.9,61.94) v2(31.9,40.35) v2(32.91,103.72) v2(32.91,30.57) v2(32.91,28.79) v2(32.91,26.88) v2(33.42,0.85) v2(34.18,42.76) v2(34.31,102.32) v2(34.31,100.8) v2(34.31,99.27) v2(34.82,43.39) v2(34.82,42.76) v2(34.82,42.12) v2(34.82,30.57) v2(34.82,28.79) v2(34.82,26.88) v2(35.45,103.72) v2(35.45,42.76) v2(35.45,1.48) v2(35.96,56.98) v2(35.96,0.85) v2(36.22,1.48) v2(36.34,30.57) v2(36.34,28.79) v2(36.34,27.01) v2(36.47,65.62) v2(36.63,61.66) v2(36.72,58.71) v2(36.72,57.85) v2(36.72,56.98) v2(36.72,56.12) v2(36.72,55.26) v2(37.49,67.02) v2(37.61,56.98) v2(37.99,103.72) v2(38.12,43.99) v2(38.12,41.93) v2(39.39,46.57) v2(39.31,34.5) v2(39.42,31.46) v2(39.41,30.81) v2(39.57,16.29) v2(40.53,103.72) v2(40.91,49.36) v2(40.91,47.46) v2(41.04,0.85) v2(41.68,41.24) v2(41.68,38.87) v2(41.68,36.28) v2(43.07,103.72) v2(43.58,0.85) v2(43.84,71.08) v2(43.84,69.86) v2(43.84,68.71) v2(43.84,67.52) v2(43.84,26.12) v2(43.96,20.53) v2(43.96,19.67) v2(44.09,24.73) v2(44.34,56.73) v2(44.44,55.21) v2(44.44,53.17) v2(44.72,37.3) v2(44.72,34.71) v2(44.72,32.35) v2(44.72,22.95) v2(45.61,103.72) v2(45.74,65.62) v2(45.84,73.18) v2(45.84,70.59) v2(45.84,68.03) v2(46.25,26.76) v2(46.25,24.2) v2(46.5,45.05) v2(46.63,100.29) v2(47.26,100.29) v2(47.26,42) v2(47.42,51.04) v2(48.15,103.72) v2(48.66,0.85) v2(49.08,11.66) v2(50.25,49.76) v2(50.69,103.72) v2(51.2,0.85) v2(51.77,58.28) v2(51.94,59.5) v2(51.91,48.64) v2(52.15,55.04) v2(52.38,50.82) v2(52.6,56.65) v2(52.68,47.87) v2(53.04,50.82) v2(53.05,43.71) v2(53.23,103.72) v2(53.74,0.85) v2(54.97,50.82) v2(55.77,103.72) v2(55.9,14.69) v2(56.28,0.85) v2(58.31,103.72) v2(58.82,0.85) v2(59.2,16.09) v2(60.35,18.88) v2(60.85,103.72) v2(61.36,0.85) v2(63.39,103.72) v2(63.6,18.96) v2(63.88,46.33) v2(63.9,0.85) v2(64.69,57.92) v2(64.99,52.67) v2(65.19,43.89) v2(65.24,47.81) v2(65.37,77.39) v2(65.5,56.83) v2(65.7,59.39) v2(65.93,103.72) v2(66.22,50.2) v2(66.42,52.72) v2(66.44,0.85) v2(66.79,77.39) v2(66.91,50.18) v2(68.47,103.72) v2(68.98,0.85) v2(69.37,50.26) v2(69.79,3.92) v2(70.51,3.92) v2(71.01,103.72) v2(71.52,0.85) v2(73.55,103.72) v2(73.68,47.97) v2(73.81,95.34) v2(74.06,0.85) v2(75.71,55.59) v2(76.09,103.72) v2(76.47,55.59) v2(76.6,0.85) v2(76.89,8.6) v2(77.11,89.24) v2(77.24,55.59) v2(77.74,89.24) v2(78.15,55.62) v2(78.38,89.24) v2(78.39,47.06) v2(78.42,47.75) v2(78.63,103.72) v2(79.14,0.85) v2(79.55,47.67) v2(80,50.44) v2(81.32,66.19) v2(82.57,10.37) v2(83.71,103.72) v2(84.22,0.85) v2(85.11,102.06) v2(85.16,101.34) v2(85.97,90.13) v2(86.25,103.72) v2(86.76,0.85) v2(88.79,103.72) v2(89.3,102.02) v2(89.3,0.85) v2(91.33,103.72) v2(91.51,102.02) v2(91.84,0.85) v2(92.92,97.35) v2(93.87,103.72) v2(94.39,97.34) v2(94.38,0.85) v2(96.41,103.72) v2(96.67,27.55) v2(96.92,0.85) v2(97.14,16.56) v2(97.2,76.3) v2(98.19,79.83) v2(98.76,74.95) v2(98.95,103.72) v2(99.05,78.9) v2(99.22,76.24) v2(99.46,0.85) v2(99.91,71.74) v2(100.33,97.34) v2(100.34,79.8) v2(100.38,67.74) v2(100.55,76.23) v2(100.71,74.95) v2(100.98,65.73) v2(100.97,64.71) v2(101.01,63.49) v2(101.11,78.89) v2(101.49,103.72) v2(101.49,71.75) v2(101.69,69.26) v2(101.95,102.04) v2(102,0.85) v2(102.23,90.08) v2(102.48,67.74) v2(102.77,71.08) v2(102.84,56.82) v2(103,64.68) v2(102.97,63.48) v2(103.04,90.05) v2(103.03,65.73) v2(103.12,46.87) v2(103.61,69.25) v2(104.03,103.72) v2(104.06,102.04) v2(104.29,60.81) v2(104.37,52.68) v2(104.41,49.78) v2(104.54,0.85) v2(104.67,48.51) v2(104.79,59.08) v2(104.85,46.87) v2(104.91,97.61) v2(105.2,51.24) v2(105.56,60.82) v2(105.54,52.59) v2(105.56,15.84) v2(105.76,49.71) v2(106.19,102.07) v2(106.57,103.72) v2(106.67,57.05) v2(107.08,0.85) v2(109.11,103.72) v2(109.1,97.5) v2(109.62,0.85) v2(109.85,97.48) v2(109.95,90.11) v2(110.56,97.51) v2(111.12,78.26) v2(111.65,103.72) v2(112.16,0.85) v2(112.36,31.91) v2(112.88,82.22) v2(112.83,45.32) v2(113.25,86.88) v2(114.19,103.72) v2(114.13,49.89) v2(114.13,48.98) v2(114.29,80.73) v2(114.55,78.84) v2(114.68,85.89) v2(114.7,0.85) v2(115.64,46.61) v2(115.74,76.28) v2(116.73,103.72) v2(116.86,83.27) v2(117.19,77.68) v2(117.24,0.85) v2(117.88,97.8) v2(118.62,73.89) v2(118.62,73.24) v2(118.62,71.94) v2(118.62,71.29) v2(118.62,70.64) v2(119.27,103.72) v2(119.78,0.85) v2(120.92,125.94) v2(120.92,123.4) v2(120.92,120.86) v2(120.92,118.32) v2(120.92,115.78) v2(120.92,113.24) v2(120.92,110.7) v2(120.92,108.16) v2(120.92,105.62) v2(122.32,0.85) v2(123.59,125.94) v2(124.73,80.99) v2(124.86,0.85) v2(126.13,125.94) v2(128.67,125.94) v2(129.23,57.56) v2(129.26,54.9) v2(129.64,30.57) v2(131.21,125.94) v2(132.51,60.67) v2(132.86,42.12) v2(132.94,52.58) v2(133.17,64.37) v2(133.19,57.56) v2(133.3,62.69) v2(133.39,49.76) v2(133.75,125.94) v2(134.18,120.41) v2(134.18,119.24) v2(134.26,61.93) v2(134.39,46.95) v2(134.46,45.17) v2(134.59,58.89) v2(134.78,119.8) v2(135.1,57.56) v2(135.15,43.8) v2(135.3,49.76) v2(135.38,119.21) v2(135.59,63.4) v2(136.29,125.94) v2(136.67,28.54) v2(137.56,0.85) v2(138.83,125.94) v2(140.1,124.21) v2(140.1,0.85) v2(141.37,125.94) v2(141.37,123.79) v2(141.63,82) v2(142.01,84.42) v2(142.51,122.01) v2(142.51,83.91) v2(142.64,0.85) v2(142.9,80.48) v2(143.28,78.45) v2(143.78,84.8) v2(143.91,125.94) v2(144.55,78.07) v2(145.18,0.85) v2(145.82,82.26) v2(145.98,84.71) v2(145.94,80.22) v2(145.94,79.46) v2(146.2,83.53) v2(146.45,125.94) v2(146.58,77.94) v2(146.71,75.78) v2(148.99,125.94) v2(149.37,27.62) v2(150.26,0.85) v2(150.67,76.07) v2(150.64,74.97) v2(151.53,125.94) v2(152.8,0.85) v2(154.07,125.94) v2(154.66,122.11) v2(154.83,56.73) v2(154.83,56.09) v2(155.34,0.85) v2(155.6,57.36) v2(155.6,56.73) v2(155.6,56.09) v2(155.77,124.07) v2(155.8,122.11) v2(156.36,57.36) v2(156.36,56.09) v2(156.61,125.94) v2(157.12,57.36) v2(157.12,56.73) v2(157.12,56.09) v2(157.88,57.36) v2(157.88,56.73) v2(157.88,56.09) v2(157.88,0.85) v2(159.15,125.94) v2(160.42,49.62) v2(160.42,48.86) v2(160.42,48.09) v2(160.42,46.57) v2(160.42,41.36) v2(160.42,40.6) v2(160.42,39.84) v2(160.42,39.08) v2(160.42,38.31) v2(160.42,0.85) v2(160.93,67.02) v2(161.06,49.62) v2(161.06,48.86) v2(161.06,48.09) v2(161.06,47.33) v2(161.06,46.57) v2(161.06,41.36) v2(161.06,40.6) v2(161.06,39.08) v2(161.06,38.31) v2(161.69,49.62) v2(161.69,48.86) v2(161.69,48.09) v2(161.69,47.33) v2(161.69,46.57) v2(161.69,41.36) v2(161.69,40.6) v2(161.69,39.84) v2(161.69,39.08) v2(161.69,38.31) v2(162.2,67.02) v2(162.96,0.85) v2(164.23,125.94) v2(165.5,0.85) v2(165.63,67.02) v2(166.52,111.97) v2(166.64,114.01) v2(166.64,111.21) v2(166.64,108.93) v2(166.64,106.89) v2(166.77,125.94) v2(166.77,112.99) v2(166.77,108.16) v2(166.9,106.01) v2(166.89,104.99) v2(167.28,106.64) v2(167.28,105.49) v2(167.48,114.77) v2(167.41,108.42) v2(167.41,104.61) v2(167.51,113.78) v2(167.51,109.21) v2(167.53,107.53) v2(167.66,45.17) v2(167.91,60.29) v2(168.04,0.85) v2(168.7,28.05) v2(169.31,125.94) v2(169.34,28.05) v2(169.97,28.05) v2(170.45,124.42) v2(170.58,0.85) v2(171.34,123.02) v2(173.12,121.63) v2(173.12,0.85) v2(174.52,0.85) v2(175.15,120.99) v2(177.19,63.21) v2(177.19,62.44) v2(177.82,120.99) v2(177.95,63.92) v2(177.95,63.21) v2(177.95,62.44) v2(177.95,61.68) v2(177.95,60.92) v2(178.2,0.85) v2(178.71,63.92) v2(178.71,63.21) v2(178.73,62.43) v2(178.71,61.68) v2(179.47,63.21) v2(179.47,61.68) v2(179.6,74.46) v2(179.55,73.79) v2(180.11,121.5) v2(180.74,0.85) v2(182.01,122.77) v2(182.27,50.89) v2(183.15,124.55) v2(183.28,0.85) v2(183.79,73.11) v2(183.92,79.21) v2(183.92,76.92) v2(183.92,75.14) v2(184.93,125.94) v2(184.93,123.02) v2(185.82,0.85) v2(187.09,125.94) v2(187.25,80.35) v2(188.11,11.01) v2(188.31,21.09) v2(188.36,0.85) v2(188.74,81.88) v2(189.2,21.09) v2(189.35,84.19) v2(189.76,3.52) v2(190.39,10.88) v2(190.9,59.52) v2(190.9,0.85) v2(191.2,21.09) v2(191.84,21.09) v2(192.17,28.22) v2(192.43,77.81) v2(192.43,77.18) v2(192.47,21.09) v2(192.55,116.93) v2(192.68,11.01) v2(193.2,21.09) v2(193.31,113.75) v2(193.44,0.85) v2(193.95,111.47) v2(194.58,109.31) v2(195.09,107.02) v2(195.6,58.13) v2(195.73,104.86) v2(195.88,89.42) v2(195.98,0.85) v2(196.11,72.35) v2(196.36,102.7) v2(196.39,91.78) v2(196.54,87.06) v2(196.87,100.54) v2(197.38,93.03) v2(197.51,98) v2(198.22,85.28) v2(198.39,96.23) v2(199.03,30.44) v2(199.03,29.55) v2(199.03,28.66) v2(199.28,94.45) v2(199.54,79.26) v2(199.79,22.31) v2(200.05,30.44) v2(200.05,29.55) v2(200.05,28.66) v2(200.55,81.62) v2(200.55,76.62) v2(200.83,84.44) v2(200.93,30.44) v2(200.93,28.66) v2(201.44,42.25) v2(202.1,38.85) v2(202.2,26.38) v2(202.61,82.61) v2(203.09,75.53) v2(203.04,24.17) v2(203.52,84.47) v2(203.6,0.85) v2(204.24,25.87) v2(204.36,43.65) v2(204.57,82.66) v2(204.87,23.46) v2(205.18,83.81) v2(206.01,24.98) v2(206.14,6.69) v2(206.27,50.13) v2(206.4,75.53) v2(206.78,40.47) v2(206.78,38.31) v2(207.03,22.06) v2(208.17,24.73) v2(208.17,23.84) v2(208.43,22.06) v2(208.81,70.7) v2(209.19,25.36) v2(209.19,24.47) v2(209.31,21.04) v2(209.44,75.53) v2(209.56,46.19) v2(209.61,50.65) v2(209.7,7.83) v2(210.05,38.92) v2(210.05,38.21) v2(210.16,47.84) v2(210.21,22.95) v2(210.84,73.24) v2(210.97,63.46) v2(212.24,70.7) v2(212.24,27.27) v2(212.24,25.49) v2(212.39,42.33) v2(212.44,40.88) v2(213.25,6.56) v2(213.51,68.29) v2(214.27,39.58) v2(214.35,43.54) v2(214.35,41.63) v2(214.34,33.71) v2(215.16,3.77) v2(215.36,34.72) v2(215.36,33.71) v2(215.41,0.85) v2(216.37,33.71) v2(216.43,63.08) v2(216.87,9.16) v2(216.97,27.4) v2(216.94,9.99) v2(217.95,60.16) v2(217.93,46.88) v2(217.95,44.82) v2(217.95,42.78) v2(219.73,0.85) v2(220.37,55.84) v2(220.87,34.63) v2(220.87,34) v2(221.89,50.38) v2(222.52,47.97) v2(223.54,45.3) v2(223.92,0.85) v2(224.81,42.38) v2(226.46,39.71) v2(227.35,0.85) v2(228.24,36.92) v2(228.24,33.62) v2(228.87,29.93) v2(230.53,0.85) v2(231.92,29.81) v2(231.92,27.52) v2(231.92,25.11) v2(231.92,22.95) v2(231.92,19.39) v2(231.92,16.72) v2(231.92,13.3) v2(231.92,9.99) v2(231.92,6.18) v2(231.92,2.5) v3(17.7,83.53) v3(17.93,98.51) v3(17.93,97.62) v3(18.05,99.4) v3(18.82,98.51) v3(18.82,97.62) v3(18.94,99.4) v3(32.02,94.96) v3(32.79,95.59) v3(41.57,95.46) v3(41.64,97.37) v3(47.77,99.66) v3(48.41,98.89) v3(49.42,98.89) v3(50.44,98.89) v3(51.46,98.89) v3(97.05,6.18) v3(97.94,6.18) v3(98.8,6.18) v3(99.64,6.18) v3(100.48,6.18) v3(101.32,6.18) v3(117.24,60.3) v3(117.75,52.94) v3(118.13,60.3) v3(118.26,2.75) v3(118.26,1.87) v3(119.02,60.3) v3(119.27,2.75) v3(119.27,1.87) v3(119.78,52.92) v3(119.91,60.3) v3(120.16,2.75) v3(120.16,1.87) v3(120.8,60.3) v3(121.18,2.12) v3(121.56,69.25) v3(121.56,68.41) v3(121.56,67.52) v3(121.56,66.64) v3(121.56,65.62) v3(121.69,60.29) v3(121.76,112.51) v3(121.76,111.67) v3(121.79,110.78) v3(121.79,109.05) v3(121.71,10.12) v3(121.81,109.94) v3(121.81,108.19) v3(121.84,107.3) v3(121.81,52.92) v3(122.07,2.12) v3(122.55,10.12) v3(122.96,2.12) v3(123.39,10.13) v3(123.97,52.92) v3(124.23,10.12) v3(125.24,96.73) v3(125.24,95.72) v3(130.7,111.97) v3(132.74,112.1) v3(132.74,111.21) v3(132.74,110.32) v3(132.74,109.43) v3(132.74,108.55) v3(132.74,107.66) v3(132.74,106.77) v3(132.87,105.79) v3(133.62,112.1) v3(133.62,111.21) v3(133.62,110.32) v3(133.62,109.43) v3(133.62,108.55) v3(133.62,107.66) v3(133.62,106.77) v3(133.71,105.75) v3(134.51,112.1) v3(134.51,111.21) v3(134.51,110.32) v3(134.51,109.43) v3(134.51,108.55) v3(134.51,107.66) v3(134.51,106.77) v3(134.55,105.75) v3(135.39,105.75) v3(135.4,112.1) v3(135.4,111.21) v3(135.4,110.32) v3(135.4,109.43) v3(135.4,108.55) v3(135.4,107.66) v3(135.4,106.77) v3(137.43,111.97) v3(141.12,95.85) v3(142.01,50.63) v3(142.01,48.86) v3(142.01,47.97) v3(142.01,46.19) v3(142.01,45.3) v3(142.01,43.52) v3(142.01,42.51) v3(142.01,40.73) v3(142.01,39.84) v3(142.64,66.14) v3(143.53,66.14) v3(145.18,110.58) v3(145.18,108.04) v3(145.18,105.5) v3(147.98,37.3) v3(147.98,36.41) v3(148.86,37.3) v3(148.86,36.41) v3(149.12,58) v3(149.12,57.11) v3(149.12,56.22) v3(149.12,55.33) v3(149.75,37.3) v3(149.75,36.41) v3(150.01,58) v3(150.01,57.11) v3(150.01,56.22) v3(150.01,55.33) v3(159.02,57.62) v3(159.02,56.73) v3(159.91,57.62) v3(159.91,56.73) v3(160.29,51.52) v3(160.29,50.63) v3(160.29,44.16) v3(160.29,42.38) v3(160.8,56.73) v3(161.13,51.52) v3(161.13,50.63) v3(161.18,44.16) v3(161.18,43.27) v3(161.18,42.38) v3(161.69,56.73) v3(161.97,51.52) v3(161.97,50.63) v3(162.07,44.16) v3(162.07,43.27) v3(162.07,42.38) v3(162.81,51.52) v3(162.81,50.63) v3(162.96,44.16) v3(162.96,43.27) v3(162.96,42.38) v3(163.16,29.86) v3(163.22,30.75) v3(163.72,52.03) v3(163.85,44.16) v3(164,29.83) v3(164.36,56.73) v3(164.61,52.03) v3(164.74,44.16) v3(164.84,29.83) v3(165.25,56.73) v3(165.5,52.03) v3(165.63,44.16) v3(165.78,29.83) v3(166.14,56.73) v3(166.39,52.03) v3(166.52,44.16) v3(167.28,52.03) v3(168.17,52.03) v3(183.03,23.96) v3(183.99,23.96) v3(184.93,23.96) v3(185.44,36.66) v3(185.44,35.65) v3(185.9,23.96) v3(186.33,36.66) v3(186.33,35.65) v3(186.46,48.47) v3(186.46,47.33) v3(186.46,46.19) v3(186.46,45.17) v3(186.71,43.9) v3(186.84,23.96) v3(187.35,36.66) v3(187.35,35.65) v3(187.8,23.96) v3(188.11,92.54) v3(188.11,91.4) v3(188.11,90.13) v3(188.23,36.66) v3(188.23,35.65) v3(188.74,23.96) v3(189.12,36.66) v3(189.12,35.65) v3(189.76,110.7) v3(189.76,109.56) v3(189.71,23.96) v3(190.14,67.4) v3(190.65,23.96) v3(191.41,28.03) v3(191.92,31.58) v3(192.04,110.45) v3(192.04,109.31) v3(192.93,31.58) v3(194.33,93.43) v3(194.33,92.54) v3(194.33,89.11) v3(195.6,98.89) v3(195.6,98) v3(195.6,97.12) v3(195.6,51.65) v3(196.11,59.65) v3(196.11,58.76) v3(197.25,83.65) v3(197.25,82.64) v3(198.27,83.65) v3(198.27,82.64) v3(199.79,40.47) v3(199.79,39.46) v3(200.68,40.47) v3(200.68,39.46) v3(203.47,58.76) v3(203.47,57.87) v3(203.47,56.86) v3(203.47,55.97) v3(203.47,54.95) v3(219.48,4.28) v3(220.49,4.28) v3(230.65,22.95) v3(230.65,21.93) v3(230.65,20.92)
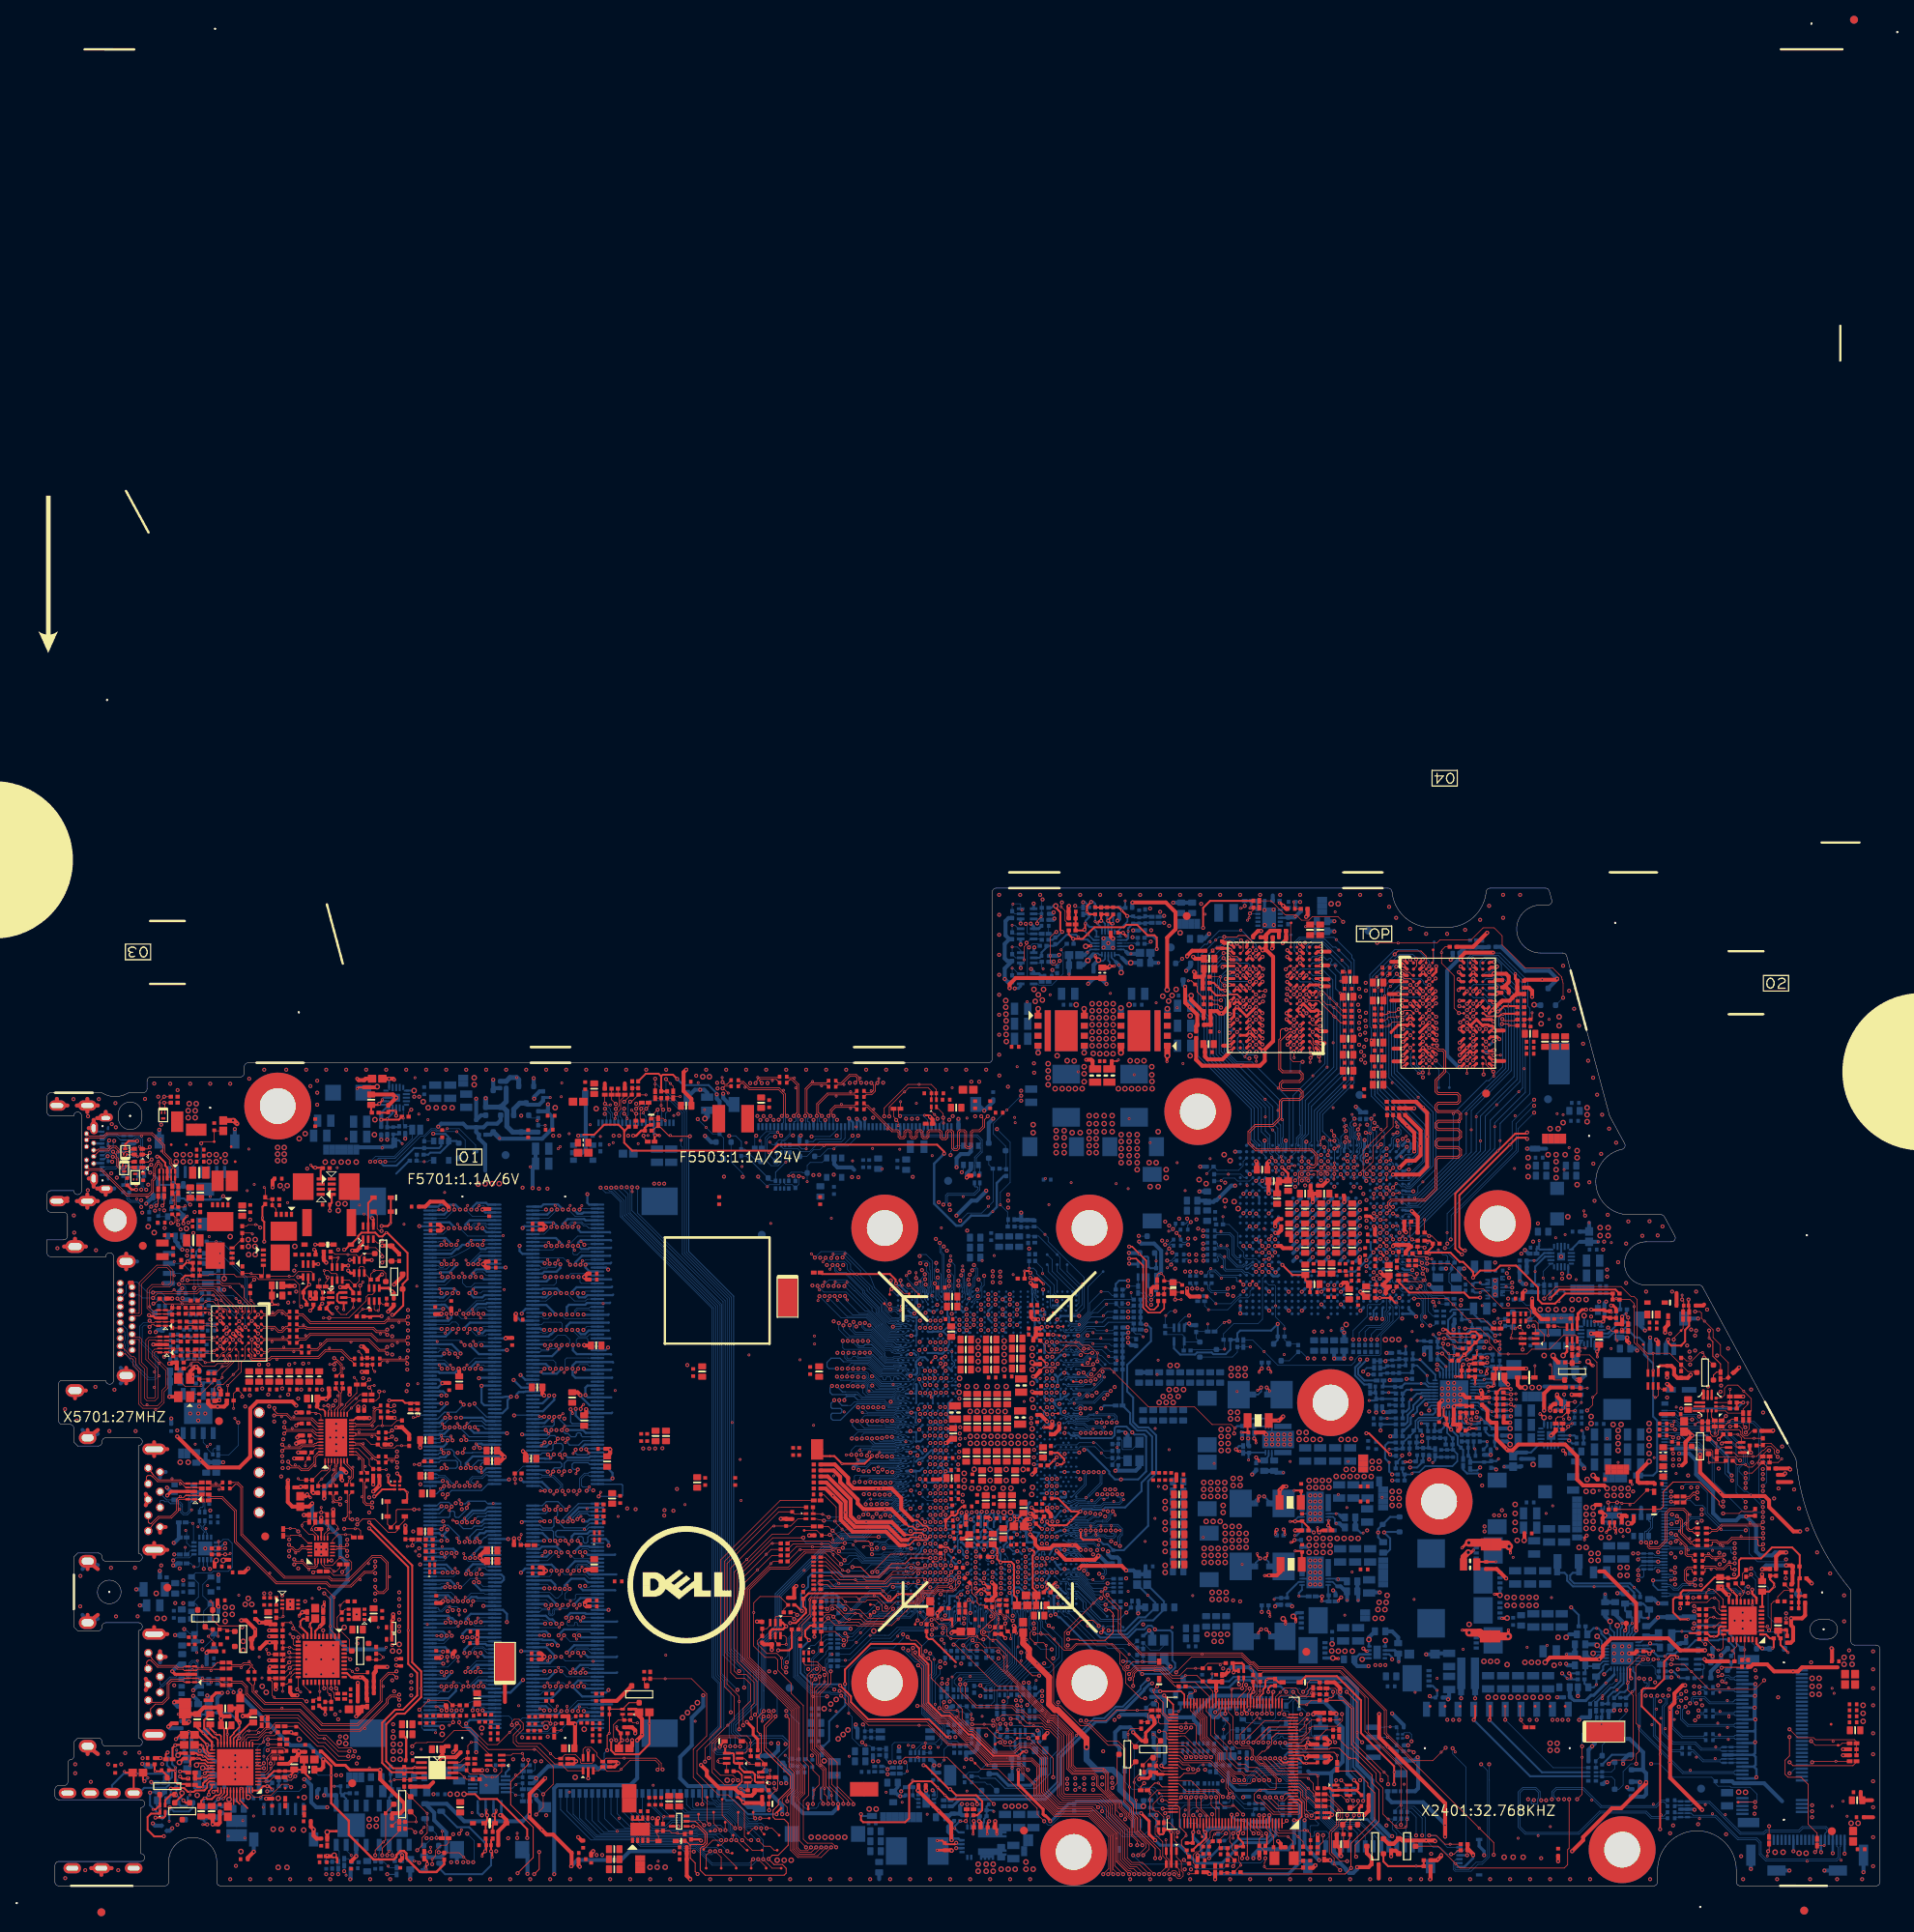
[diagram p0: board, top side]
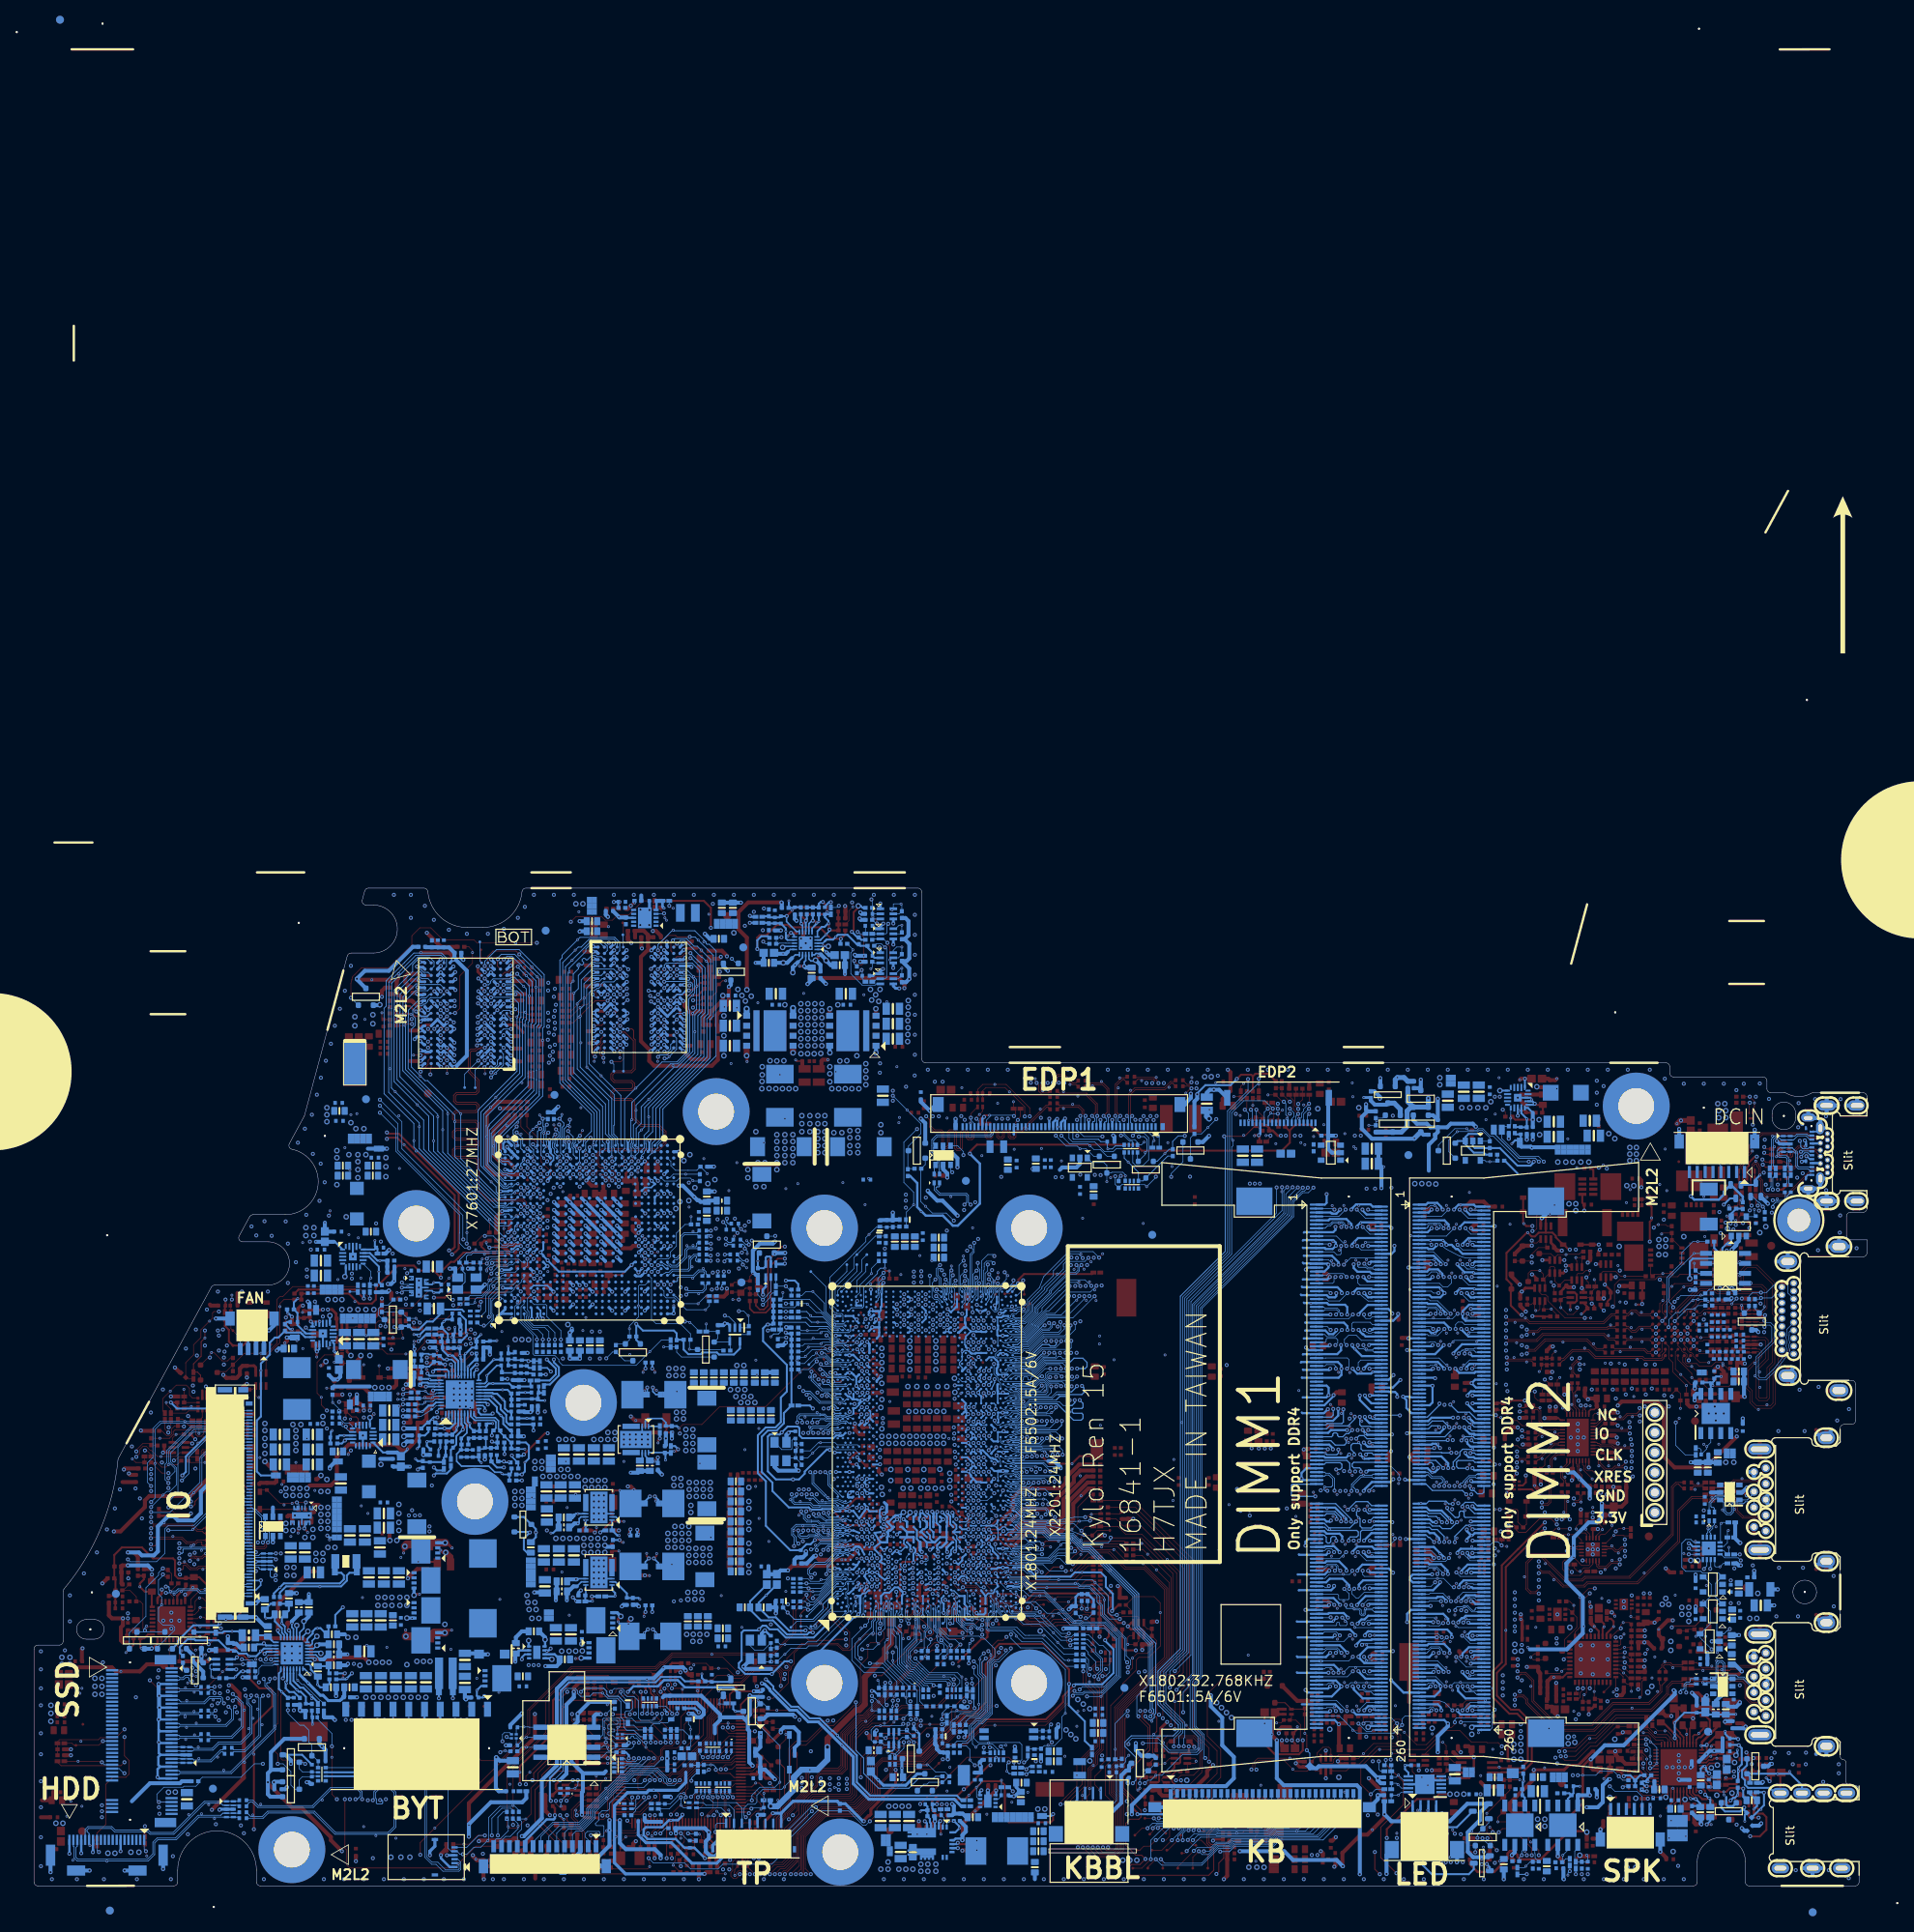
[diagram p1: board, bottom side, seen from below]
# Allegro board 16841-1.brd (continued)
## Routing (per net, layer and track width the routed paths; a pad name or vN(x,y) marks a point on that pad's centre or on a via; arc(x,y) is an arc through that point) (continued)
V0.85A_VID0: length 1.2
  TOP w0.089: v2(114.13,40.75) 113.78,40.4 TP2101.1
  BOTTOM w0.089: CPU1.AN11 v2(114.13,40.75)
V0.85A_VID1: length 1.7
  TOP w0.089: v2(113.48,41.64) 113.05,41.2 TP2102.1
  BOTTOM w0.089: CPU1.AN13 v2(113.48,41.64)
VBUS_PRODECT#: length 3.5
  TOP w0.089: PQ4311.6 36.2,79.66 PR4337.1 v1(36.98,79.84) 36.98,79.56 36.85,79.44 PQ4311.5
VBUS_PRODECT_G: length 10.4
  BOTTOM w0.089: U4301.1 49.07,94.63 PR4345.2 47.9,95.07 48.87,96.04 49.25,96.04 49.42,95.86 52.03,95.86 v1(52.05,95.85) 53.11,94.79 53.11,93.3 PQ4314.G
VBUS_SENSE: length 3.1
  BOTTOM w0.089: PR4347.1 46.93,92.9 PR4346.2 47.06,92.04 v1(47.9,92.04) 48.37,92.04 48.53,92.2 U4301.5
VCC1R05VIDEO_PEX_PLLVDD: length 1.4
  TOP w0.508: C7318.1 156.39,84.75 155.99,84.34 v2(155.99,83.82)
  vias: v1(149.6,86.27)
VCC3PD: length 113.6
  TOP w0.406: D3701.K D3702.K 43.79,33.7 v1(43.96,33.87)
  TOP w0.508: PR4342.1 PR4337.2 35.15,79.51 v2(35.45,79.21) ; R3733.1 40,22.77 R3732.1 39.67,21.96 v2(39.26,21.55) ; v2(43.96,34.5) v1(43.96,33.87)
  L3 w0.508: v2(43.96,34.5) 43.96,34.35 42.1,32.49 42.1,27.69 40.28,25.87 40.28,22.44 39.39,21.55 v2(39.26,21.55)
  L6 w0.254: v2(42.31,92.04) 42.31,91.86 38.45,88 38.45,84.11 35.45,81.11 v2(35.45,79.21)
  L6 w0.508: v2(39.26,21.55) 39.26,24.98 37.74,26.5 37.74,31.33 36.85,32.22 36.85,38.21 38.17,39.53 38.17,40.98 37.36,41.79 37.36,43.01 35.66,44.72 33.92,44.72 31.57,47.07 31.57,51.09 34.22,53.74 34.22,63.25 35.58,64.61 35.58,67.52 36.89,68.84 36.89,72.31 35.58,73.62 35.58,76.36 36.28,77.06 36.28,78.39 v2(35.45,79.21)
  BOTTOM w0.254: v2(42.31,92.04) 42.44,91.91 42.44,91.83 42.74,91.53 44.38,91.53 46.62,93.76 PR4345.1 49.8,93.76 50.06,94.02 U4301.2
VCC_CORE: length 45.1
  TOP w0.508: C1125.1 125.52,52.69 v2(125.12,52.28)
  L4 w0.254: v3(152.29,44.79) 152.62,44.46 159.23,44.46 160.19,45.43 162.38,45.43 162.63,45.17 166.39,45.17 167.03,45.81 168.96,45.81 170.61,47.46 173.25,47.46 173.88,48.09 173.88,50.33 175.2,51.65 182.77,51.65 v2(184.04,52.92)
  L6 w0.508: v2(115.97,56.83) 114.98,56.83 114.62,57.19 v2(114.19,57.19) ; v2(114.19,55.36) 115.67,55.36 v2(115.84,55.18)
  BOTTOM w0.152: v2(131.29,60.04) CPU1.A44 ; v2(131.29,57.56) CPU1.A39
  BOTTOM w0.203: CPU1.A34 v2(131.08,55.08) ; CPU1.A30 v2(130.94,52.6)
  BOTTOM w0.254: PR4631.2 183.84,53.12 v2(184.04,52.92)
  vias: v1(116.61,56.86) v1(126.13,57.11) v1(129.33,58.21) v1(135.91,55.71) v1(140.74,58.13) v1(146.83,44.28) v1(148.23,53.68) v1(151.79,40.85) v2(114.2,53.55) v2(115.79,54.44) v2(115.72,53.55) v2(115.87,56.04) v2(115.92,57.49) v2(124.99,59.45) v2(124.99,58.81) v2(125.37,55.41) v2(125.34,54.47) v3(116.86,63.46) v3(117.27,57.13) v3(117.27,56.24) v3(118,63.46) v3(118.11,57.13) v3(118.11,56.24) v3(119,57.13) v3(119,56.24) v3(119.4,63.46) v3(119.78,51.52) v3(119.89,57.13) v3(119.89,56.24) v3(120.67,63.46) v3(120.72,57.13) v3(120.72,56.24) v3(121.56,57.13) v3(121.56,56.24) v3(121.81,63.46) v3(121.81,51.52) v3(122.45,57.13) v3(122.45,56.24) v3(123.34,57.13) v3(123.34,56.24) v3(123.97,51.52) v3(124.23,57.13) v3(124.23,56.24) v3(125.12,58.08) v3(125.12,57.13) v3(125.12,56.24) v3(146.91,51.27) v3(146.91,50.38) v3(146.91,49.49) v3(146.96,42.89) v3(146.96,42) v3(146.96,41.11) v3(147.21,46.32) v3(147.8,51.27) v3(147.8,50.38) v3(147.8,49.49) v3(147.85,42.89) v3(147.85,42) v3(147.85,41.11) v3(148.1,46.32) v3(148.69,51.27) v3(148.69,50.38) v3(148.69,49.49) v3(148.74,42.89) v3(148.74,42) v3(148.74,41.11) v3(148.99,46.32) v3(149.37,48.35) v3(149.37,47.46) v3(149.58,51.27) v3(149.58,50.38) v3(149.58,49.49) v3(149.63,45.68) v3(149.63,44.79) v3(149.63,43.9) v3(149.63,42.89) v3(149.63,42) v3(149.63,41.11) v3(150.52,45.68) v3(150.52,44.79) v3(150.52,43.9) v3(150.52,43.01) v3(150.64,51.78) v3(150.64,50.89) v3(151.4,45.68) v3(151.4,44.79) v3(151.4,43.9) v3(151.4,43.01) v3(151.53,51.78) v3(151.53,50.89) v3(152.29,43.9) v3(152.29,43.01)
VCC_SENSE: length 72.1
  TOP w0.254: v2(128.32,53.55) 128.88,53.55 v1(129.19,53.86) 129.19,54.25 128.41,55.03 R719.2
  L4 w0.254: v2(128.32,53.55) 128.03,53.8 127.63,53.77 127.14,54.26 127.14,55.08 128.66,56.6 129.71,56.6 130.22,57.11 130.22,58.05 131.31,59.14 131.97,59.14 132.86,60.03 141.25,60.03 148.01,53.28 154.3,53.28 154.83,53.81 163.6,53.81 165.63,55.84 170.99,55.84 171.6,55.24 171.6,53.17 172.36,52.41 174.11,52.41 174.61,52.92 181.76,52.92 v2(182.01,53.17)
  BOTTOM w0.254: PR4665.1 180.94,52.79 181.63,52.79 v2(182.01,53.17) ; CPU1.E32 127.99,53.23 v2(128.32,53.55)
VCCGT_SENSE: length 63
  TOP w0.254: v2(124.89,77.92) 124.66,78.15 v1(124.16,78.15) 124.15,78.14 R721.2
  L4 w0.254: v2(166.77,66.89) 167.28,66.38 168.04,66.38 168.3,66.64 168.3,67.68 167.95,68.03 165.78,68.03 164.36,69.46 161.11,69.46 160.06,70.51 143.43,70.51 140.95,72.99 139.69,72.99 138.96,73.72 138.96,77.05 137.82,78.19 129.2,78.19 128.67,77.66 125.64,77.66 125.39,77.92 v2(124.89,77.92)
  BOTTOM w0.089: CPU1.J70 125.62,75.07 125.62,75.28 125.56,75.41 125.56,75.6 125.56,75.6 125.61,75.73 125.62,75.78 125.62,77.18 v2(124.89,77.92)
  BOTTOM w0.254: v2(166.77,66.89) 166.77,66.54 166.14,65.9 166.14,64.86 167.28,63.71 167.84,63.71 PR4667.1
VCCPD_VBUS: length 20
  TOP w0.305: v2(42.54,77.71) 42.46,77.71 41.98,77.23 PR4319.1
  TOP w0.508: v2(43.33,72.99) 44.01,73.67 PR4343.1 ; v2(28.21,31.71) R3730.1
  L4 w0.508: v3(37.74,32.85) 37.23,33.36 30.63,33.36 28.98,31.71 v2(28.21,31.71)
  L6 w0.508: 5.92,94.91 USB1.B4 6.42,94.4 ; 5.92,91.29 USB1.B9 6.42,91.8
  BOTTOM w0.254: PR4346.1 45.99,92.16 44.34,90.51
  BOTTOM w0.305: USB1.A9 5.97,94.35 USB1.B4 ; USB1.A4 5.97,91.85 USB1.B9
  vias: v1(30.07,88.48) v1(30.55,86.83) v3(29.61,88.99) v3(30.5,88.99)
VCCRTCEXT: length 18.7
  TOP w0.254: C2112.1 95.07,35.7 95.83,34.94 v2(95.88,34.94)
  BOTTOM w0.254: v2(95.88,34.94) 95.78,35.04 95.78,37.12 96.67,38.01 96.67,39.2 97.3,39.84 v1(99.72,39.84) 100.6,39.84 101.14,39.3 105.51,39.3 106.18,39.97 106.4,39.97 106.93,40.49 108.37,40.49 CPU1.BB10
VCCSA_SENSE: length 105.2
  TOP w0.254: v2(126.37,45.38) 126.36,45.39 126.24,45.39 125.6,46.04 R735.2
  L3 w0.254: v2(151.53,36.16) 151.42,36.16 150.49,35.22 142.54,35.22 140.2,37.57 140.2,37.63 137.94,39.88 137.94,44.41 136.55,45.81 135.52,45.81 135.51,45.82 127.87,45.82 127.87,45.81 127.22,45.81 127.22,45.81 126.67,45.81 126.39,45.53 126.39,45.39 v2(126.37,45.38)
  L4 w0.254: v2(183.92,69.94) 183.97,69.89 184.47,69.89 186.71,67.65 188.11,67.65 191.28,64.48 191.28,62.38 187.59,58.69 187.59,52.7 179.3,44.41 178.88,44.41 170.92,44.41 166.64,40.14 166.64,37.34 164.31,35.01 160.8,35.01 159.66,36.16 v2(151.53,36.16)
  BOTTOM w0.254: PR4601.2 183.03,70.83 v2(183.92,69.94) 184.04,70.06 v1(184.55,70.06) ; v2(126.37,45.38) 126.37,45.41 126.11,45.67 CPU1.H20
VCCSTG_EN_L: length 2
  TOP w0.089: U4007.4 78.39,8.87 v1(78.33,8.81) 78.23,8.7 R4037.1
VCCSTG_EN_R: length 7.3
  TOP w0.089: R4003.2 81.17,6.77 R4017.2 80.18,6.59 v1(80.06,6.72) 79.34,6.72 79.06,7 R4037.2 78.2,6.97 C4033.1 77.46,6.54 77.66,6.34 D4004.A 77.66,5.68 77.55,5.79 U4002.4
VCCSTU_EN_R: length 2.9
  BOTTOM w0.089: U4006.3 110.31,11.03 109.95,11.39 C4034.1 109.95,12.51 R4024.2 v1(109.93,13.42)
VDD: length 26.9
  L3 w0.254: v2(203.6,30.82) 204.54,29.88 204.54,28.99 v2(206.27,27.27)
  L4 w0.254: v2(203.6,30.82) 202.97,31.46 201.57,31.46 201.06,31.96 201.06,34 199.66,35.39 v2(193.57,35.39)
  BOTTOM w0.203: 202.71,30.55 PU4401.18
  BOTTOM w0.254: 202.71,30.55 203.33,30.55 v2(203.6,30.82) 203.73,30.69 204.44,30.69 PC4422.1 ; PR4429.1 v2(206.27,27.27) 206.52,27.27 v1(207.21,26.58) 207.39,26.4 PR4427.1 ; v2(193.57,35.39) 194.53,34.43 PR4405.2
VDD12: length 1.1
  TOP w0.254: v2(23.6,69.39) U5701.F5 ; U5701.D6 24.8,69 v2(24.43,69.38)
  vias: v1(21.23,68.03) v2(28.09,66.25)
VDD33: length 4.9
  TOP w0.254: v2(26.8,72.59) U5701.B2 ; v2(22.8,70.98) 22.41,70.59 U5701.G4 ; v1(29.36,73.87) 28.62,73.87 v2(28.54,73.95) 28.57,73.98 L5801.2 28.54,75.04 C5855.1 ; v2(22,72.59) U5701.G2
  vias: v1(20.59,72.71)
VDDA12: length 22
  TOP w0.254: v2(22.8,70.19) U5701.F4
  L6 w0.254: v2(32.52,66.37) 30.63,64.48 21.1,64.48 19.58,66 19.58,69.56 20.21,70.19 v2(22.8,70.19)
  vias: v1(33.24,66.43)
VDDD: length 50.1
  TOP w0.457: RN3702.1 v2(28.3,27.85) 28.21,27.77 R3725.1 28.22,27.18 RN3702.2
  TOP w0.508: v2(28.21,32.47) R3724.1
  L3 w0.508: CCGDB1.1 28.98,45.43 28.98,36.16 28.21,35.39 v2(28.21,32.47)
  L4 w0.508: v2(28.21,32.47) 27.96,32.47 27.52,32.03 27.52,28.07 ; 27.52,28.07 27.55,28.03 28.12,28.03 v2(28.3,27.85) ; 27.52,28.07 25.6,26.15 22.14,26.15 21.37,25.37 21.37,24.33 22.85,22.85 28.77,22.85 30.45,21.17 35.96,21.17 v2(36.6,21.8)
  vias: v1(37.23,22.19)
VDDIO: length 5.7
  TOP w0.254: 39.01,26.5 38.62,26.5 38.08,27.04 U3701.32
  TOP w0.508: 39.01,26.5 v1(39.77,26.5) 40.08,26.5 C3722.1 C3721.1 C3723.1 40.58,23.71 R3733.2
VDDRX12: length 1.7
  TOP w0.254: v2(26.8,69.39) U5701.B5 ; v2(26.8,67.79) U5701.B7 ; v2(26.8,70.19) U5701.B4
  vias: v1(31.47,66.43) v2(30.75,66.25)
VDDTX12: length 1.1
  TOP w0.254: v2(22,69.39) U5701.G5 ; v2(22,68.59) U5701.G7
  vias: v1(21.1,69.68) v2(26.94,66.25)
VSS_AY71: length 12.2
  TOP w0.254: v2(107.83,76.57) 107.77,76.63 107.77,77.04 107.05,77.76 v1(102.84,77.76) 98.42,77.76 R602.1
  BOTTOM w0.254: CPU1.AY71 109.11,75.51 108.3,76.32 108.05,76.32 107.83,76.55 v2(107.83,76.57)
VSS_SENSE: length 70.4
  TOP w0.254: R720.1 127.21,53.43 v1(127.85,54.07) 128.24,54.46 v2(128.24,54.47)
  L4 w0.254: v2(182.01,52.16) 181.63,52.54 174.77,52.54 174.26,52.03 172.2,52.03 171.22,53.02 171.22,55.08 170.84,55.46 165.79,55.46 163.75,53.43 154.99,53.43 154.46,52.89 147.85,52.89 141.1,59.65 133.02,59.65 132.13,58.76 131.47,58.76 130.6,57.89 130.6,56.95 129.87,56.22 128.82,56.22 127.52,54.92 127.52,54.41 127.77,54.16 127.99,54.18 v2(128.24,54.47)
  BOTTOM w0.254: v2(128.24,54.47) 127.99,54.22 CPU1.E33 ; v2(182.01,52.16) 181.76,52.41 180.36,52.41 179.85,52.92 PR4666.1
VSSGT_SENSE: length 60.3
  TOP w0.254: v2(124.89,77.28) 125.07,77.1 R722.1 125.92,77.1 v1(126.54,76.48)
  L4 w0.254: v2(124.89,77.28) 128.83,77.28 129.36,77.81 137.66,77.81 138.58,76.89 138.58,73.56 139.53,72.6 140.8,72.6 143.27,70.13 159.9,70.13 160.95,69.07 164.2,69.07 165.62,67.65 167.41,67.65 167.66,67.4 v2(167.66,66.89)
  BOTTOM w0.089: CPU1.J69 125.61,74.44 125.61,74.63 125.43,74.81 125.43,75.27 125.37,75.39 125.37,75.64 125.43,75.77 125.43,76.74 v2(124.89,77.28)
  BOTTOM w0.254: PR4668.1 167.31,64.22 166.52,65.02 166.52,65.75 v2(167.66,66.89)
VSSSA_SENSE: length 103.2
  TOP w0.254: v1(184.52,69.2) 183.99,69.2 v2(183.96,69.22) ; v2(126.36,46.29) 126.36,46.68 R734.1
  L3 w0.254: v2(150.64,36.28) 150.13,35.77 142.77,35.77 138.45,40.09 138.45,44.66 136.8,46.32 136.33,46.32 129.94,46.32 129.43,46.82 126.64,46.82 126.36,46.54 v2(126.36,46.29)
  L4 w0.254: v2(183.96,69.22) 184.01,69.18 184.42,69.18 186.46,67.14 187.9,67.14 188.7,66.34 189.5,65.54 190.77,64.27 190.77,62.59 187.08,58.9 187.08,52.91 179.09,44.92 170.71,44.92 166.14,40.35 166.14,37.55 164.1,35.52 161.01,35.52 159.87,36.66 151.02,36.66 v2(150.64,36.28)
  BOTTOM w0.254: v2(183.96,69.22) 183.87,69.22 183.03,70.06 PR4602.2 ; CPU1.H21 126.35,46.29 v2(126.36,46.29)
0D6V_PWR:
  vias: v1(49.06,14.01)
0D6V_S0: length 3.3
  BOTTOM w0.279: DM1.258 63.2,20.32 v3(63.36,20.16) ; 50.02,20.32 DM2.258
  BOTTOM w0.305: v3(50.19,20.15) 50.02,20.32
  vias: v1(49.34,19.47) v3(50.19,19.26)
1D0V_PWR:
  vias: v1(77.62,3.14) v3(76.58,2.36) v3(77.49,2.37) v3(78.51,2.37) v3(92.73,3.26) v3(93.62,3.26) v3(94.51,3.26)
1D0V_S5: length 70.3
  TOP w0.762: R1102.1 123.97,30.82 124.71,30.08 124.71,29.08 127.27,26.52 127.27,23.06 127.99,22.35 128.38,22.35 132.02,18.71 v3(132.02,17.64)
  L3 w0.762: v3(139.24,10.12) 136.98,10.12 136.66,9.8 136.17,9.8 134.96,8.6 133.82,8.6 132.55,9.87 127.12,9.87 125.19,11.8 115.62,11.8 115.19,11.37 111.12,11.37 109.25,9.49 105.58,9.49 v3(105.3,9.77)
  BOTTOM w0.305: CPU1.AF21 v2(117.32,46.56) CPU1.AF20 ; v2(122.37,46.59) CPU1.T20 CPU1.T19
  BOTTOM w0.508: v3(139.24,10.12) 139.29,10.17 R2402.1
  BOTTOM w0.762: v3(139.24,10.12) 138.38,10.12 136.29,12.21 136.29,13.8 135.34,14.76 v1(134.26,14.76) 133.31,14.76 132.02,16.04 v3(132.02,17.64)
  vias: v1(100.35,20.28) v1(106.57,11.9) v1(108.61,10.63) v1(123.97,44.41) v1(124.73,39.58) v2(124.05,42.62) v3(100.48,18.68) v3(101.11,19.24) v3(101.72,19.82) v3(104.41,9.77)
1D0V_S5_PWRGD: length 43.7
  TOP w0.089: v2(117.5,10.37) 117.67,10.2 PR5209.1
  L3 w0.089: v2(130.58,12.2) 131.3,12.92 131.3,13.85 131.55,14.1 131.59,14.1 133.39,15.91 134.53,15.91 136.83,18.2 149.65,18.2 150.03,17.82 150.68,17.82 v2(151.09,18.23)
  L6 w0.089: v2(117.5,10.37) 118.16,11.04 126.24,11.04 127.33,12.14 128.41,12.14 129.06,12.8 129.06,13.74 129.44,14.11 130.88,14.11 131.01,13.98 131.01,12.46 130.75,12.2 v2(130.58,12.2)
  BOTTOM w0.089: v2(130.58,12.2) 130.89,12.51 v1(131.13,12.51) ; v2(151.09,18.23) 151.15,18.29 R4029.1
1D0V_S5_VCCIO:
  vias: v1(72.41,6.95)
1D2V_HDMI:
  vias: v1(29.61,62.19) v2(27.33,63.21) v2(29.87,63.21) v2(32.28,63.08) v2(34.95,63.08)
1D2V_HDMI_EN: length 15.9
  TOP w0.089: v2(24.28,58.89) 23.85,59.32 v1(23.85,59.42) ; v2(22.63,66.79) 22.63,67.17 U5701.G8
  L3 w0.089: v2(22.63,66.79) 24.28,65.14 v2(24.28,58.89)
  BOTTOM w0.089: v2(24.28,58.89) 24.28,55.97 23.08,54.77 R5801.1
1D2V_HDMI_EN_R: length 4.6
  BOTTOM w0.089: R5801.2 21.28,55.64 21.05,55.41 C5858.1 20.34,55.54 v1(20.34,55.84) 19.83,56.35 U5801.2
1D2V_HDMI_FB: length 4.3
  BOTTOM w0.254: U5801.7 19.83,63.77 R5802.2 ; R5802.2 19.88,63.97 R5803.1 ; R5802.2 19.4,64.2 C5859.2 19.17,64.73 v1(18.51,64.73)
1D2V_HDMI_VIN:
  vias: v1(18.82,56.13)
1D2V_S3: length 259
  TOP w0.254: v2(60.98,6.09) 60.98,7.2 57.14,11.04 54.99,11.04 54.36,11.66 v3(52.95,11.66)
  L3 w0.254: v2(104.9,15.84) 103.68,14.62 92.17,14.62 90.15,12.6 87.72,12.6 87.15,12.03 82.64,12.03 77.31,6.69 61.59,6.69 v2(60.98,6.09)
  L4 w0.508: v2(83.56,95.31) 83.56,94.32 83.18,93.94 82.19,93.94 81.94,93.69 71.39,93.69 67.46,97.62 63.77,97.62 60.4,94.25 v2(60.4,88.73)
  BOTTOM w0.089: v2(107.35,52.58) 107.37,52.58 107.47,52.68 CPU1.BB32
  BOTTOM w0.127: v2(102.25,59.09) 102.28,59.06 102.28,58.53 102.86,57.95 103.73,57.95 103.74,57.95 107.6,57.95 107.72,57.82 107.94,57.76 108.4,57.76 CPU1.BB41 ; v2(107.15,61.53) 107.35,61.33 CPU1.BB47 ; CPU1.BB51 108.37,63.83 105.97,63.83 105.05,64.75 v2(104.77,64.75)
  BOTTOM w0.203: CPU1.BB23 108.39,47.63 108.15,47.63 107.55,47.03 107.52,47.01 107.48,46.99 v2(107.08,46.99) ; CPU1.AU23 111.2,48.39 v2(110.88,48.06)
  BOTTOM w0.254: v2(110.87,51.73) 111.2,51.39 CPU1.AU28 ; CPU1.AL23 v2(114.23,48.06) ; v2(110.59,55.75) 110.59,55.63 111.2,55.02 CPU1.AU35 ; CPU1.AU42 111.2,58.57 110.79,58.16 110.79,58.02 v2(110.77,57.99)
  BOTTOM w0.279: DM2.124 50.36,55.82 50.74,56.21 50.74,56.49 v2(50.86,56.61) ; DM1.199 v2(71.32,35.07) ; DM2.130 48.65,54.32 49.78,54.32 49.93,54.48 50.59,54.48 51,54.89 v2(51,55.03) ; DM2.178 50,40.32 50.03,40.35 50.47,40.35 50.82,39.99 50.82,39.87 v2(50.88,39.81) ; v2(50.72,62.32) 50.61,62.43 50.61,62.54 50.3,62.85 49.87,62.85 49.85,62.82 DM2.96 ; v2(71.32,43.24) 71.32,43.73 70.97,44.07 DM1.163 ; DM1.12 60.62,83.82 v2(60.4,83.6) ; v2(71.27,78.32) 71.01,78.57 69.9,78.57 DM1.33 ; DM1.135 71.21,53.07 71.81,52.47 v2(71.81,51.8) 71.59,51.57 DM1.141 ; v2(59.66,62.16) 59.67,62.16 59.67,62.5 59.93,62.77 60.51,62.77 60.53,62.79 60.73,62.79 60.76,62.82 DM1.96 ; DM1.220 60.22,29.82 v2(60.21,29.83) ; v2(52.57,59.5) 55.3,59.5 55.72,59.07 DM2.111 ; v2(50.3,73.33) 50.3,73.32 DM2.54 ; DM2.199 57.9,35.07 58.4,34.57 v2(58.4,33.53) ; DM1.147 67.55,48.07 66.15,46.68 v2(66.15,46.3) ; DM2.163 v2(58.57,44.07) ; v2(47.28,83.84) 47.3,83.82 DM2.12 ; DM2.159 55.78,45.07 55.53,44.83 54.97,44.83 54.32,44.17 v2(54.32,43.71) ; v2(67.15,60.62) 67.15,59.77 67.82,59.1 68.7,59.1 68.73,59.07 DM1.111 ; DM2.220 50.23,29.82 v2(50.29,29.77) ; DM1.124 63.41,55.82 63.9,56.32 v2(63.9,56.34) ; DM2.141 58.59,51.57 v2(58.67,51.65) ; DM2.142 48.65,51.32 50.11,51.32 v2(50.26,51.47) ; v2(64.05,57.94) 63.87,57.76 63.87,57.72 63.48,57.32 DM1.118 60.39,57.32 v2(60.34,57.37) ; v2(71.25,68.41) 70.91,68.07 DM1.75 ; DM1.241 71,24.57 71.31,24.88 v2(71.31,24.89) ; DM2.135 55.79,53.07 55.31,52.59 54.87,52.59 54.53,52.93 54.53,53.05 v2(54.45,53.12) ; DM1.117 68.42,57.57 68.07,57.92 v2(66.03,57.92) ; v2(50.1,48.25) 49.68,47.82 DM2.148 ; v2(63.87,43.87) 63.87,43.89 62.94,44.82 DM1.160 ; v2(58.23,78.58) 58.23,78.57 56.85,78.57 DM2.33 ; DM1.154 60.4,46.32 60.3,46.23 60.3,46.23 v2(60.29,46.21) ; DM1.148 61.7,47.82 63.13,47.82 v2(63.16,47.8) ; v2(67.83,55.47) 67.83,55.61 68.3,56.07 DM1.123 ; DM2.123 55.3,56.07 55.19,56.19 54.74,56.19 54.23,55.67 v2(54.23,55.65) ; v2(50.57,59.5) 50.2,59.13 50.17,59.13 49.86,58.82 DM2.112 ; v2(60.16,51.68) 60.52,51.32 DM1.142 62.87,51.32 63.77,50.43 63.77,50.34 v2(63.92,50.19) ; DM2.136 49.86,52.82 50.11,53.07 v2(50.11,53.09) ; DM1.159 68.94,45.07 68.62,44.76 66.98,44.76 66.64,44.42 v2(66.64,43.85) ; v2(65.75,54.81) 66.14,54.43 68.81,54.43 68.95,54.57 DM1.129 ; DM2.154 50.1,46.32 50.11,46.32 v2(50.31,46.32) ; v2(68.08,46.43) 68.09,46.43 68.2,46.31 68.21,46.31 68.23,46.3 68.63,46.3 68.91,46.57 DM1.153 ; DM2.160 49.82,44.82 50.06,44.58 50.29,44.58 ; DM2.147 55.93,48.07 55.56,47.7 54.03,47.7 52.73,46.4 52.73,46.24 v2(52.7,46.22) ; DM1.136 61.7,52.82 63.31,52.82 63.49,52.64 v2(63.6,52.64) ; DM1.54 60.78,73.32 60.29,72.83 v2(60.29,72.72) ; v2(51.14,58.28) 51.14,58.13 50.45,57.44 49.89,57.44 49.77,57.32 48.65,57.32 DM2.118 ; v2(58.41,57.52) 58.36,57.57 DM2.117 54.23,57.57 53.77,58.04 53.77,58.19 v2(53.68,58.28) ; v2(60.18,39.8) 60.71,40.32 DM1.178 ; v2(64.36,54.83) 64.36,54.8 63.84,54.28 63.27,54.28 63.23,54.32 DM1.130 ; v2(54.73,46.21) 55.17,46.21 55.53,46.57 DM2.153 ; v2(58.4,68.1) 58.38,68.07 DM2.75 ; DM1.112 63.19,58.82 63.77,59.41 v2(63.77,59.6) ; v2(53.18,53.1) 53.18,53.71 54.05,54.57 DM2.129
  BOTTOM w0.305: v2(50.82,45.29) 50.82,45.11 50.29,44.58 50.82,44.05 v2(50.82,43.87) ; v2(60.44,26.16) 58.85,24.57 56.85,24.57 DM2.241
  BOTTOM w0.508: v2(83.56,95.31) 84.35,94.53 Q501.G ; R505.1 v2(104.9,15.84)
  vias: v1(48.28,33.23) v1(49.55,69.18) v1(56.66,48.6) v1(57.93,82.64) v1(58.06,75.78) v1(69.36,28.54) v1(70.63,74) v1(72.16,62.95) v1(87.02,58.89) v1(88.03,54.19) v1(101.24,60.23) v1(103.25,55.35) v1(107.46,63.71) v1(109.07,56.44) v2(47.39,40.85) v2(50.89,34.91) v2(52.32,77.39) v2(53.09,34.98) v2(53.65,61.14) v3(35.33,91.99) v3(36.34,91.99) v3(37.36,91.99) v3(38.25,91.99) v3(39.26,91.99) v3(51.2,11.66) v3(52.09,11.66)
1D2V_VTT_PWRGD: length 233.4
  TOP w0.127: v1(47.9,7.45) 47.52,7.07 v2(47.52,6.82)
  L3 w0.127: v2(154.48,18.22) 153.26,17 149.69,17 149.44,17.26 137.04,17.26 134.87,15.09 133.98,15.09 132.87,13.98 v2(132.87,13.68)
  L4 w0.127: v2(132.87,13.68) 132.18,14.36 129.36,14.36 128.16,13.16 127.81,13.16 127.69,13.04 118.37,13.04 117.42,13.99 114.21,13.99 113.66,13.44 108.69,13.44 107.54,12.29 96.64,12.29 93.33,15.6 85.28,15.6 82.79,13.11 75.14,13.11 70.12,8.09 52.6,8.09 51.63,8.09 51.61,8.11 48.81,8.11 v2(47.52,6.82)
  L6 w0.127: v2(41.68,92.04) 41.68,92.21 41.31,92.58 34.35,92.58 33.48,91.72 33.48,78.12 34.12,77.48 34.12,72.14 34.48,71.78 34.48,65 33.17,63.69 33.17,54.19 29.48,50.51 29.48,41.24 34.15,36.57 34.15,15.87 39.52,10.5 39.52,7.58 40.74,6.36 47.05,6.36 v2(47.52,6.82)
  BOTTOM w0.127: PG5114.1 47.39,95.66 44.21,92.48 42.12,92.48 v2(41.68,92.04) ; R4011.1 154.45,18.25 v2(154.48,18.22)
1D05V_PWR: length 14.2
  L3 w0.254: v2(146.58,124.8) 147.06,125.28 158.91,125.28 v2(159.15,125.04)
  BOTTOM w0.254: PR8303.1 158.59,124.32 PC8323.1 159.14,125.06 v2(159.15,125.04)
  vias: v1(147.09,123.48)
1D05V_VGA_EN: length 40.7
  TOP w0.089: v1(151.61,124.24) 151.81,124.24 v2(152.12,124.55)
  L3 w0.089: v2(152.12,124.55) 151.73,124.93 147.34,124.93 145.56,123.15 145.56,121.71 143.85,120 v2(140.18,120) 140.94,120.76 140.94,121.9 139.95,122.89 138.21,122.89 137.34,123.76 132.45,123.76 131.03,122.34 127.31,122.34 126.41,123.24 126.41,125.33 v2(126.44,125.36)
  BOTTOM w0.089: PQ8301.2 C8308.2 126.31,124.27 PR8310.2 126.33,125.26 v2(126.44,125.36) ; PR8308.1 v2(152.12,124.55) ; R8305.2 139.9,119.72 v2(140.18,120)
1D05V_VGA_EN#: length 3.7
  BOTTOM w0.089: PQ8301.5 122.91,123.53 PR8307.2 122.58,124.67 v1(122.68,124.78) 122.7,124.8 123.59,124.8 123.65,124.74 PQ8301.6
1D05V_VGA_S0: length 28.5
  TOP w0.508: C7323.1 153.66,91.99 v2(153.56,92.09) ; v2(155.17,88.01) 155.14,88.04 C7326.1 ; C7312.1 156.99,81.04 156.71,81.32 v2(155.98,81.32)
  L3 w0.508: v3(143.91,121.12) 143.91,123.15 142.01,125.06 138.84,125.06 138.07,124.28 132.34,124.28 131.02,122.96 127.98,122.96 v2(127.94,122.92)
  BOTTOM w0.508: PR8306.1 127.79,122.77 v2(127.94,122.92) ; L7602.1 v2(163.47,67.02) v2(164.74,67.02) L7601.1
  vias: v1(144.55,88.35) v1(147.72,92.42) v2(155.98,82.16) v3(149.5,92.92) v3(150.26,92.16)
1D05V_VGA_S0_DISCHG: length 2.9
  TOP w0.089: v1(126.26,123.15) 125.75,122.64 v2(125.75,122.31)
  BOTTOM w0.089: PQ8301.3 126.22,122.88 PR8306.2 125.88,122.31 v2(125.75,122.31)
1D05V_VGA_S0_PWRGD: length 105.1
  TOP w0.089: PR8320.2 155.47,125.18 157.25,123.4 158.64,123.4 159.32,122.73 160.25,122.73 160.68,123.15 163.98,123.15 v2(164.61,122.52) ; R8303.1 207.84,67.09 208.22,66.72 208.89,66.72 209.95,67.78 v1(210.26,67.78) 210.46,67.58 v2(210.46,67.14) 210.69,67.14 D8301.2
  L6 w0.089: v2(164.61,122.52) 169.95,122.52 172.3,120.17 183.98,120.17 193.63,110.51 193.63,104.17 194.97,102.84 194.97,97.24 194.37,96.65 194.37,94.4 194.97,93.81 194.97,87.62 198.14,84.44 198.52,84.44 198.9,84.06 198.9,77.61 201.01,75.51 201.76,75.19 201.78,75.19 201.81,75.18 201.81,75.18 202.16,75.11 202.65,75.02 205.63,75.02 207.41,73.24 207.41,73.06 209.31,71.16 209.45,71.16 209.87,70.75 209.87,70.27 209.95,70.19 209.95,67.65 v2(210.46,67.14)
1D8V_EN#: length 3.5
  TOP w0.089: R2726.2 21.18,31 v1(20.47,31.71) 21.05,32.3 R2727.1 20.41,32.6 Q2701.D
1D8V_EN_R#: length 3
  TOP w0.089: v1(21.74,31.71) 21.74,32.42 R2727.2 22.7,32.6 C2714.2 23.75,32.42 Q2702.G
1D8V_PWR:
  vias: v1(40.94,15)
1D8V_S0: length 68.6
  TOP w0.305: v2(35.07,16.09) 35.22,16.09 36.09,15.22 36.09,10.5 38.32,8.27 38.32,6.5 41.46,3.36 44.06,3.36 44.37,3.68 44.37,3.92 44.88,4.43 45.33,4.43 45.64,4.12 45.64,3.48 47.35,1.77 49.45,1.77 50.44,2.75 R6120.1
  TOP w0.508: v2(35.07,16.09) 35.07,15.07 34.77,14.77 R2748.1 ; R2724.1 v2(24.53,24.85) ; C2721.1 25.98,30.31 Q2702.D 26.44,31.84 v1(26.44,32.6) 25.29,33.74 v2(24.66,33.74)
  L3 w0.508: v2(24.66,33.74) 23.83,32.92 23.83,29.11 24.53,28.41 v2(24.53,24.85) 24.53,24.22 23.52,23.2 19.45,23.2 18.56,24.09 v2(18.56,24.15)
  BOTTOM w0.508: v2(18.56,24.15) 18.56,24.13 19.2,23.49 R2750.1 ; v2(35.07,16.09) 33.29,17.87 30.88,17.87 24.4,24.34 24.4,24.73 v2(24.53,24.85)
1D8V_S5_KBC: length 4.4
  TOP w0.203: KBC24.54 148.44,24.71 v1(148.51,24.78)
  TOP w0.508: R2464.2 147.7,25.95 148.46,25.95 C2423.1 ; C2423.1 148.51,25.95 R2462.1 ; C2423.1 148.48,24.8 v1(148.51,24.78)
1D35V_PGOOD: length 1
  BOTTOM w0.089: PR8321.1 192.63,75.48 TP8301.1
1D35V_PWR: length 1.1
  BOTTOM w0.508: PG8313.1 190.39,93.69
  vias: v1(192.68,91.02) v1(193.31,93.81) v3(190.65,92.92) v3(191.66,92.92) v3(191.66,92.04) v3(191.66,91.02) v3(191.66,90) v3(192.81,92.92)
1D35V_VGA_EN: length 32
  TOP w0.089: R8304.1 R8303.2 ; R8303.2 206.08,67.69 v1(203.98,67.69) ; R8303.2 208.41,65.36 209.41,65.36 D8301.3 ; v2(190.14,74.64) 191.66,76.16 199.92,76.16 201.19,74.89 201.57,74.89 201.95,74.51 201.95,68.96 203.22,67.69 v1(203.98,67.69) ; v1(203.98,67.69) PQ8308.2
  BOTTOM w0.089: PR8322.1 v2(190.14,74.64)
1D35V_VGA_EN#: length 4.3
  TOP w0.089: PQ8308.5 203.98,62.32 v1(204.24,62.06) 204.38,62.06 204.63,62.32 PQ8308.6 205.08,63.08 PR8328.1
1D35V_VGA_S0: length 189.7
  TOP w0.089: 161.35,90.72 161.53,90.89 162.24,90.89 162.35,90.78 ; 163.09,91.13 163.09,91.13 163.09,91.46 163.09,91.46
  TOP w0.102: 160.02,90.05 159.78,89.81 159.78,89.48 ; 160.02,90.05 160.3,90.05 160.3,90.05 ; 160.02,90.05 159.09,90.05 ; 161.35,90.23 161.35,90.72 161.21,90.86 159.2,90.86 158.97,90.62 158.97,90.17 159.09,90.05 ; 163.89,90.89 163.88,90.89 163.35,90.89 163.34,90.89 ; 159.09,90.05 158.95,89.91 158.95,89.09 158.94,89.07 ; 162.22,90.18 162.22,90.65 162.46,90.89 163.06,90.89
  TOP w0.203: VRAM3.P11 153.15,116.9 v2(153.56,116.5)
  TOP w0.305: VRAM3.G13 VRAM3.F12
  TOP w0.356: VRAM3.E5 157.86,109.7 v2(157.43,110.13) ; C7818.1 150.07,119.14 v2(150.26,118.95) 150.71,118.5 VRAM3.T14 ; VRAM2.T1 172.75,105.25 172.27,104.78 v2(172.22,104.78) ; VRAM3.P1 161.73,116.9 v2(161.8,116.98) ; 173.15,109.7 v2(173.15,109.71) ; 173.15,109.7 VRAM2.L1 172.62,109.43 171.63,109.43 170.71,108.51 170.71,108.42 ; 173.15,109.7 173.55,109.3 VRAM2.L2 ; v2(180.35,112.09) 180.75,112.49 VRAM2.G11 ; VRAM2.M14 183.2,108.5 183.42,108.72 183.74,108.72 v2(183.75,108.7) 183.75,109.08 183.53,109.3 VRAM2.L14 183.02,109.43 182.53,109.43 182.39,109.3 VRAM2.L13 VRAM2.K12 VRAM2.L11 ; VRAM3.L13 151.55,114.5 v2(151.95,114.1) 152.35,113.7 VRAM3.K12 ; VRAM2.M1 172.73,108.5 v2(172.21,107.98) ; v2(174.77,105.7) 174.37,105.3 VRAM2.T3 ; v2(179.42,105.57) VRAM2.R10 v2(180.35,106.5) VRAM2.P11 ; v2(157.52,115.64) 157.52,115.67 VRAM3.N5 ; v2(181.13,104.9) 181.53,105.3 VRAM2.T12 ; VRAM3.F1 161.22,110.5 161.67,110.95 v2(161.7,110.95) 161.34,111.3 VRAM3.G1 161,111.15 160.5,111.15 VRAM3.G2 VRAM3.H3 159.55,112.1 159.16,111.71 159.16,111.71 v2(159.16,111.7) 159.15,111.7 VRAM3.G4 v2(159.15,110.9) VRAM3.F3 ; VRAM3.D12 152.35,108.91 v2(152.75,109.3) ; VRAM3.D11 v2(153.54,108.51) ; v2(153.55,111.7) VRAM3.G11 VRAM3.F12 ; VRAM3.R5 157.88,117.7 v2(157.51,118.07) ; VRAM2.F12 181.55,113.3 v2(181.95,113.7) ; VRAM3.N10 153.95,116.08 v2(153.55,115.67) ; VRAM2.D11 181.1,115.25 181.12,115.25 v2(181.15,115.28) 181.54,114.9 VRAM2.D12 ; VRAM3.M3 159.55,115.3 v2(159.95,115.7) ; v2(174.75,107.3) 174.35,106.91 VRAM2.P3 ; v2(161.74,114.32) 161.57,114.5 VRAM3.L1 VRAM3.L2 160.35,114.5 v2(159.95,114.1) 159.55,113.7 VRAM3.K3 ; v2(172.17,112.52) 172.19,112.5 VRAM2.G1 ; VRAM3.D1 161.31,108.9 161.6,108.61 v2(161.7,108.61) ; VRAM2.K3 174.35,110.11 v2(174.75,110.5) ; VRAM3.C5 157.56,107.71 v2(157.56,107.69) ; v2(150.17,114.52) 150.19,114.5 VRAM3.L14 ; v2(171.63,113.34) 171.67,113.3 VRAM2.F1 ; v2(179.28,113.85) 179.52,114.1 VRAM2.E10 ; VRAM2.R5 176.36,105.69 v2(176.38,105.69) ; VRAM3.L4 158.75,114.49 v2(158.35,114.09) ; VRAM2.D14 183.73,114.9 183.92,115.09 v2(183.94,115.09) ; VRAM2.D1 172.15,114.9 v2(172.06,114.99) ; v2(175.57,113.71) 175.95,114.09 VRAM2.E5 ; VRAM3.M14 149.74,115.3 v2(149.7,115.26) ; VRAM2.G2 v2(173.95,112.1) 174.35,111.7 VRAM2.H3 ; v2(161.72,107.09) 161.58,107.09 161.37,107.3 VRAM3.B1 ; VRAM2.L11 v2(181.15,108.9) VRAM2.M12 ; VRAM2.L11 180.35,109.7 v2(180.35,109.71) ; v2(150.21,109.98) 150.73,110.5 VRAM3.F14 VRAM3.G14 151.15,111.7 ; VRAM3.M1 161.66,115.3 v2(161.74,115.21) ; v2(151.95,115.7) VRAM3.M12 ; 151.15,111.7 151.55,111.3 VRAM3.G13 ; 151.15,111.7 v2(151.15,111.71) ; VRAM2.M3 VRAM2.L4 v2(175.55,109.7) ; v2(173.94,114.5) 174.34,114.9 VRAM2.D3 ; VRAM2.G4 175.15,112.5 v2(175.55,112.9) ; v2(159.13,106.91) 159.13,106.91 159.53,107.3 VRAM3.B3 ; VRAM3.L11 153.15,114.5 v2(153.55,114.9) ; v2(154.38,107.69) 154.36,107.69 VRAM3.C10 ; v2(176.45,107.45) 176.2,107.45 VRAM2.N5 ; v2(172.19,106.41) 172.68,106.9 VRAM2.P1 ; v2(184.15,113.38) 184.07,113.3 VRAM2.F14 ; VRAM2.P12 181.54,106.9 v2(181.15,106.51) ; v2(152.77,107.7) 152.37,107.3 VRAM3.B12 ; VRAM2.C10 179.73,115.7 v2(179.3,116.12) ; v2(154.36,109.32) 154.23,109.45 154.2,109.45 VRAM3.E10 ; VRAM2.N10 v2(179.41,107.16) ; VRAM2.T14 183.22,105.3 v2(183.69,104.83) ; VRAM3.P3 159.53,116.9 v2(159.15,117.28) ; v2(183.69,112.25) 183.69,112.29 183.48,112.5 VRAM2.G14 ; v2(151.94,116.5) 152.34,116.9 VRAM3.P12 ; v2(176.43,116.87) 176.43,116.18 VRAM2.C5 ; v2(173.95,113.7) VRAM2.F3 ; v2(149.3,116.78) 149.42,116.9 VRAM3.P14 ; v2(159.13,108.51) 159.52,108.9 VRAM3.D3 ; VRAM2.G13 182.35,112.5 v2(181.95,112.1) 181.55,111.7 VRAM2.H12 ; v2(150.22,106.78) 150.43,106.98 150.43,106.98 VRAM3.B14 ; v2(172.26,116.95) 172.71,116.5 VRAM2.B1 ; v2(154.38,118.08) 154.33,118.08 VRAM3.R10 ; VRAM3.H12 152.03,111.78 152.03,111.77 v2(151.97,111.71)
  TOP w0.381: C7818.1 149.22,119.16 148.56,119.16
  TOP w0.406: v2(184.16,116.82) 184.06,116.72 183.37,116.72 VRAM2.B14 ; v2(174.78,116.9) 174.38,116.5 VRAM2.B3 ; v2(159.13,118.9) 159.15,118.9 159.55,118.5 VRAM3.T3 ; v2(152.78,118.9) 152.58,118.71 152.56,118.71 VRAM3.T12 ; VRAM3.T1 161.38,118.73 v2(161.79,118.73) ; v2(181.13,116.9) 181.15,116.9 181.55,116.5 VRAM2.B12
  TOP w0.508: 162.77,114.32 v2(161.74,114.32) ; C7816.1 184.27,113.5 v2(184.15,113.38) ; R7806.1 188.21,114.16 188.62,113.75 v2(188.62,112.99) ; v2(172.26,116.95) 171.77,117.44 170.71,117.44 ; v2(168.52,83.81) 168.65,83.68 C7502.1 ; v2(183.94,115.09) 183.95,115.1 C7817.1 ; 171.27,107.98 v2(172.21,107.98) ; 185,108.7 v2(183.75,108.7) ; R7907.1 155.67,119.21 v2(155.6,119.14) ; 162.26,107.09 v2(161.72,107.09) ; 162.9,118.73 v2(161.79,118.73) ; 185.06,104.83 v2(183.69,104.83) ; 162.76,116.98 v2(161.8,116.98) ; 170.99,106.41 v2(172.19,106.41) ; 149.36,106.78 v2(150.22,106.78) ; 170.99,104.78 v2(172.22,104.78) ; 170.73,112.52 v2(172.17,112.52) ; 162.48,108.61 v2(161.7,108.61) ; 162.77,115.21 v2(161.74,115.21) ; 170.4,113.34 v2(171.63,113.34) ; 170.61,114.99 v2(172.06,114.99)
  BOTTOM w0.203: GPU1.H26 167.21,93.15 166.82,92.75 166.82,92.24 167.21,91.85 GPU1.H24 ; VRAM3.P11 153.15,116.9 v2(153.56,116.5)
  BOTTOM w0.305: v2(164.3,91.29) 164.71,91.7 GPU1.L24 ; v2(170.14,93.71) 170.11,93.71 GPU1.E26 ; GPU1.L26 164.73,93.63 164.85,93.75 164.85,94.52 v2(164.85,94.52) ; v2(171.63,113.34) 171.69,113.34 171.73,113.3 VRAM2.F1 ; VRAM3.M14 150.56,115.3 150.52,115.27 149.71,115.27 v2(149.7,115.26) ; v2(183.94,115.09) 183.92,115.09 183.73,114.9 VRAM2.D14 ; VRAM3.F12 VRAM3.G13 ; VRAM3.P1 161.73,116.9 v2(161.8,116.98)
  BOTTOM w0.33: v2(150.21,109.98) 150.73,110.5 VRAM3.F14
  BOTTOM w0.356: VRAM2.B14 183.38,116.73 183.8,116.73 183.89,116.82 v2(184.16,116.82) ; VRAM3.K12 152.35,113.7 v2(151.95,114.1) 151.55,114.5 VRAM3.L13 ; v2(181.13,104.9) 181.53,105.3 VRAM2.T12 ; GPU1.H26 167.21,93.59 167.32,93.7 167.32,94.78 v2(167.33,94.79) ; VRAM2.N5 176.2,107.45 v2(176.45,107.45) ; VRAM3.M1 161.36,115.3 161.66,115.3 v2(161.74,115.21) ; VRAM3.F12 VRAM3.G11 v2(153.55,111.7) ; v2(179.28,113.85) 179.52,114.1 VRAM2.E10 ; v2(154.38,118.08) 154.33,118.08 VRAM3.R10 ; v2(172.22,104.78) 172.3,104.78 172.75,105.23 VRAM2.T1 ; 151.15,111.7 v2(151.15,111.71) ; 151.15,111.7 VRAM3.G14 ; 151.15,111.7 151.55,111.3 VRAM3.G13 ; v2(169.3,90.4) 169.3,90.45 GPU1.E23 ; v2(159.15,117.28) 159.17,117.28 VRAM3.P3 ; v2(176.38,105.69) 176.36,105.69 VRAM2.R5 ; VRAM2.B1 172.38,116.87 172.34,116.87 v2(172.26,116.95) ; v2(161.7,108.61) 161.6,108.61 161.31,108.9 VRAM3.D1 ; VRAM2.D11 181.1,115.25 181.12,115.25 v2(181.15,115.28) 181.54,114.9 VRAM2.D12 ; v2(159.13,108.51) 159.16,108.51 159.55,108.9 VRAM3.D3 ; VRAM2.L13 VRAM2.K12 VRAM2.L11 180.35,109.7 v2(180.35,109.71) ; 173.15,109.7 173.55,109.3 VRAM2.L2 ; 173.15,109.7 VRAM2.L1 ; 173.15,109.7 v2(173.15,109.71) ; VRAM2.M14 183.2,108.5 183.42,108.72 183.74,108.72 v2(183.75,108.7) 183.75,108.86 183.31,109.3 VRAM2.L14 ; VRAM3.P14 149.42,116.9 v2(149.3,116.78) ; v2(153.55,115.67) 153.95,116.08 VRAM3.N10 ; VRAM3.R5 157.88,117.7 v2(157.51,118.07) ; v2(150.19,108.41) 150.68,108.9 VRAM3.D14 ; VRAM2.G2 v2(173.95,112.1) 174.35,111.7 VRAM2.H3 ; v2(153.55,114.9) 153.15,114.5 VRAM3.L11 ; v2(179.3,116.12) 179.73,115.7 VRAM2.C10 ; v2(150.22,106.78) 150.43,106.98 150.43,106.98 VRAM3.B14 ; v2(161.74,114.32) 161.62,114.32 161.53,114.41 161.41,114.41 161.32,114.5 VRAM3.L1 ; VRAM2.G1 172.19,112.5 v2(172.17,112.52) ; v2(181.95,113.7) 181.55,113.3 VRAM2.F12 ; VRAM2.G4 175.15,112.5 v2(175.55,112.9) ; v2(151.95,115.7) VRAM3.M12 ; v2(154.36,109.32) 154.23,109.45 154.2,109.45 VRAM3.E10 ; v2(173.95,113.7) VRAM2.F3 ; v2(172.06,114.99) 172.15,114.9 VRAM2.D1 ; v2(183.74,107.37) 183.27,106.9 VRAM2.P14 ; VRAM3.L14 150.19,114.5 v2(150.17,114.52) ; v2(161.72,107.09) 161.72,107.09 161.36,107.09 VRAM3.B1 ; v2(157.52,115.64) 157.52,115.67 VRAM3.N5 ; v2(152.77,107.7) 152.37,107.3 VRAM3.B12 ; v2(172.71,93.91) 172.71,93.86 172.15,93.3 GPU1.B26 GPU1.C25 ; VRAM2.M3 VRAM2.L4 v2(175.55,109.7) ; VRAM2.T3 174.37,105.3 v2(174.77,105.7) ; v2(183.69,112.25) 183.56,112.39 183.48,112.39 183.37,112.5 VRAM2.G14 ; VRAM3.T1 161.37,118.72 161.78,118.72 v2(161.79,118.73) ; v2(174.75,110.5) 174.35,110.11 VRAM2.K3 ; VRAM2.P3 174.35,106.91 v2(174.75,107.3) ; v2(150.26,118.95) 150.34,118.87 150.38,118.87 VRAM3.T14 ; VRAM2.D3 174.34,114.9 v2(173.94,114.5) ; VRAM2.N10 v2(179.41,107.16) ; VRAM3.B3 159.53,107.3 159.13,106.91 v2(159.13,106.91) ; VRAM3.L4 158.75,114.49 v2(158.35,114.09) ; VRAM3.P12 152.34,116.9 v2(151.94,116.5) ; VRAM3.L2 160.35,114.5 v2(159.95,114.1) 159.55,113.7 VRAM3.K3 ; VRAM2.F14 183.35,113.3 183.42,113.22 183.99,113.22 v2(184.15,113.38) ; v2(183.69,104.83) 183.62,104.91 183.54,104.91 VRAM2.T14 ; v2(151.97,111.71) 152.03,111.77 152.03,111.78 VRAM3.H12 ; VRAM3.D11 v2(153.54,108.51) ; v2(172.19,106.41) 172.68,106.9 VRAM2.P1 ; VRAM2.H12 181.55,111.7 v2(181.95,112.1) 182.35,112.5 VRAM2.G13 ; VRAM2.P12 181.54,106.9 v2(181.15,106.51) 180.75,106.9 VRAM2.P11 v2(180.35,106.5) ; VRAM2.G11 180.75,112.49 v2(180.35,112.09) ; v2(179.42,105.57) VRAM2.R10 ; VRAM2.M1 172.73,108.5 v2(172.21,107.98) ; VRAM3.F1 161.22,110.5 161.67,110.95 v2(161.7,110.95) 161.34,111.3 VRAM3.G1 ; v2(159.15,110.9) VRAM3.F3 ; VRAM3.E5 157.86,109.7 v2(157.43,110.13) ; VRAM3.G2 VRAM3.H3 159.16,111.71 159.16,111.71 v2(159.16,111.7) 159.15,111.7 VRAM3.G4 ; VRAM3.C10 154.36,107.69 v2(154.38,107.69) ; v2(159.95,115.7) 159.55,115.3 VRAM3.M3 ; VRAM3.D12 152.35,108.91 v2(152.75,109.3) ; v2(181.15,108.9) VRAM2.M12 ; VRAM3.C5 157.56,107.71 v2(157.56,107.69)
  BOTTOM w0.406: v2(174.78,116.9) 174.38,116.5 VRAM2.B3 ; v2(159.13,118.9) 159.15,118.9 VRAM3.T3 ; v2(152.78,118.9) 152.38,118.5 VRAM3.T12 ; v2(181.13,116.9) 181.15,116.9 VRAM2.B12
  BOTTOM w0.508: v2(178.28,117.69) 178.53,117.94 R7805.1
  vias: v1(147.72,119.98) v1(148.86,108.55) v1(163.34,107.15) v1(163.34,98.89) v1(163.6,116.93) v1(165.63,88.23) v1(170.84,102.07) v1(171.98,92.67) v1(186.46,97.88) v1(187.6,103.85) v1(191.79,98.13) v1(192.55,98) v2(158.53,88.86) v2(159.79,119.85) v2(159.79,89.01) v2(163.49,88.86) v2(165.97,88.86) v2(166.64,109.69) v2(166.77,110.45) v2(166.8,88.73) v2(167.18,87.95) v2(167.44,109.97) v2(167.51,110.96) v2(167.58,87.15) v2(167.58,84.54) v2(167.58,83.67) v3(190.9,96.23) v3(191.92,96.23) v3(192.55,96.99)
1D35V_VGA_S0_DISCHG: length 11.6
  TOP w0.089: PR8329.2 201.06,74.51 201.57,74 v1(201.57,73.62) 201.57,69.05 203.33,67.29 PQ8308.3
2D5V_S3:
  vias: v1(55.21,19.32) v3(43.96,16.09) v3(44.85,16.09) v3(55.21,20.03) v3(68.22,19.9)
3D3V_AUX_S5: length 483.6
  TOP w0.203: R1737.1 87.78,14.57 88.25,14.1 88.25,13.24 87.95,12.94 87.93,12.94 87.4,12.41 ; v2(154.83,6.67) 154.93,6.56 154.93,5.29 R2463.1
  TOP w0.254: R2754.1 17.16,13.63 v2(16.89,13.9)
  TOP w0.508: v2(83.06,15.36) 83.8,14.61 83.8,13.99 85.39,12.41 87.4,12.41 87.4,12.3 87.85,11.85 88.08,11.85 88.47,11.46 89.5,11.46 89.86,11.82 R1726.2 R1727.1 ; PR8328.2 206.32,63.29 205.89,63.71 205.83,63.71 v2(205.76,63.78) ; v2(208.05,25.49) 207.73,25.49 206.7,24.45 206.7,23.25 206.14,22.69 206.14,13.73 v2(210.21,9.66) ; v2(191.79,62.44) 191.79,62.19 192.3,61.68 PR4503.1 ; R2505.1 176.55,3.26 v1(176.68,3.39) 177.06,3.77 v2(177.06,3.9)
  L3 w0.508: v2(210.21,9.66) 209.57,10.3 199.08,10.3 195.22,6.44 179.6,6.44 v2(177.06,3.9) 175.8,5.15 174.42,5.15 174.41,5.17 172.47,5.17 172.45,5.15 162.96,5.15 162.84,5.04 156.09,5.04 154.83,6.3 v2(154.83,6.67) ; v2(191.79,62.44) 192.04,62.19 192.04,62.18 192.67,61.56 192.93,61.56 194.58,59.9 194.58,53.68 v2(195.22,53.05) 195.67,53.05 195.9,53.28 197.34,53.28 198.4,52.22 202.82,52.22 203.14,51.9 208.17,51.9 v2(208.43,52.16) 208.99,52.16 210.24,50.91 210.24,48.66 210.8,48.1 210.8,42.97 207.54,39.71 207.54,38.06 205.76,36.28 205.76,34.5 206.9,33.36 206.9,30.82 208.05,29.68 v2(208.05,25.49)
  L4 w0.254: v2(121.64,115.25) 121.64,114.37 121.62,114.35 121.62,113.82 122.68,112.76 122.68,99.81 124.35,98.13 124.35,95.57 128.14,91.78 135.5,91.78 137,90.28 138.76,90.28 139.19,90.71 139.19,92.42 141.73,94.96 151.91,94.96 153.94,92.92 153.94,92.39 157.98,88.35 162.2,88.35 163.47,87.08 163.47,81.11 164.17,80.42 167.59,80.42 168.93,79.08 170.98,79.08 173.85,81.95 173.85,83.75 178.2,88.1 185.82,88.1 188.62,85.3 188.62,84.03 191.16,81.49 197.38,81.49 v2(197.76,81.88)
  L4 w0.508: v2(154.83,6.67) 153.98,5.82 142.86,5.82 141.37,7.3 139.36,7.3 136.06,10.6 136.06,14 134.83,15.23 127.43,15.23 125.9,13.7 118.64,13.7 117.69,14.65 113.91,14.65 113.36,14.1 108.41,14.1 107.27,12.95 96.92,12.95 93.4,16.47 85.31,16.47 84.84,16.94 83.77,16.94 82.9,16.08 82.9,15.51 v2(83.06,15.36) 83.06,15.03 81.58,13.55 74.96,13.55 71.91,10.5 36.09,10.5 v2(35.58,9.99) ; v2(16.89,13.9) 17.87,12.91 27.2,12.91 28.85,14.57 32.28,14.57 32.66,14.18 v2(32.66,13.55)
  L6 w0.508: v2(208.43,52.16) 208.43,55.21 208.01,55.62 206.56,55.62 205.38,56.8 205.38,58.82 206.21,59.65 207.42,59.65 208.17,60.4 208.17,62.32 206.71,63.78 v2(205.76,63.78) 205.57,63.97 205.5,63.97 205.13,64.34 205.13,69.8 204.87,70.06 204.87,70.06 203.47,71.46 202.47,71.46 201.07,72.86 200.62,72.86 197.63,75.84 197.48,75.84 196.49,76.84 196.49,78.07 198.39,79.97 198.39,81.24 v2(197.76,81.88)
  BOTTOM w0.508: v2(32.66,13.55) 32.79,13.55 33.55,12.79 33.55,10.63 34.18,9.99 v2(35.58,9.99) ; PR8317.2 122.04,114.85 v2(121.64,115.25) 121.64,116.6 PR8315.2 121.97,117.54 121.63,117.87 121.63,119.72 122.22,120.31 ; 122.22,120.31 121.73,120.79 121.73,122.61 122.12,123 PR8307.1 ; 122.22,120.31 PR8319.2 ; v2(195.22,53.05) 195.22,53.22 PG4532.2 ; PR4505.1 v2(191.79,62.44)
3D3V_CABLE:
  vias: v1(204.11,54.42) v2(206.52,54.19) v2(207.28,54.19)
3D3V_CAMERA_S0: length 1
  BOTTOM w0.305: 108.35,95.52 LCD1.37
  vias: v1(108.3,93.61)
3D3V_GSEN2: length 12.2
  TOP w0.254: 209.19,60.92 U7001.9 ; v2(215.41,61.43) R7005.1 R7006.2 ; U7001.10 209.11,60.37
  BOTTOM w0.254: v2(207.54,60.67) 214.65,60.67 v2(215.41,61.43)
  vias: v1(206.93,60.84)
3D3V_LDO:
  vias: v1(71.39,94.19) v1(71.9,94.45) v2(71.95,95.34) v2(72.66,95.34)
3D3V_LDO_SET:
  vias: v1(70.28,95.24)
3D3V_MUX: length 67.2
  TOP w0.203: C3817.1 39.19,59.45 38.92,59.18 U3801.20 ; U3801.1 v2(35.32,53.18) ; C3818.1 37.32,53.03 U3801.6 ; U3801.28 35.32,60.29 35.07,60.54 34.64,60.54 C3816.1
  TOP w0.305: v2(31.64,58.51) 31.9,58.76 R3821.1
  TOP w0.508: R3874.1 43.32,59.48 v2(44.13,59.48) ; L3801.2 32.13,50.63 v2(32.2,50.71) R3847.1 ; v2(31.64,56.22) 31.72,56.22 31.85,56.35 32.03,56.35 32.16,56.48 R3840.1 ; C3817.1 C3815.1 v2(40.96,59.45) ; R3842.1 v2(31.39,54.32) ; R3801.1 35.78,63.01 35.83,62.96 35.83,62.24 v2(35.43,61.84) 35.33,61.94 C3819.1 34.34,61 C3816.1 ; R3871.1 v2(43.71,56.09) ; v2(37.99,52.54) 37.54,53 C3818.1 ; R3852.1 v2(35.2,49.24) ; R3818.1 v2(31.64,60.16) ; R3845.1 42.21,52.08 v1(42.21,50.86) 41.47,50.13 v2(41.42,50.13)
  L3 w0.508: v2(40.96,59.45) 44.1,59.45 v2(44.13,59.48) 44.13,59.11 43.17,58.15 43.17,56.63 v2(43.71,56.09) 43.58,56.09 40.53,53.05 40.53,50.38 40.79,50.13 v2(41.42,50.13) ; v2(32.2,50.71) 32.2,53.5 v2(31.39,54.32)
  L6 w0.508: v2(35.2,49.24) 35.2,49.45 33.94,50.71 v2(32.2,50.71) 33.98,52.49 34.63,52.49 v2(35.32,53.18) 35.07,53.43 35.07,61.43 35.4,61.76 35.4,61.81 v2(35.43,61.84) 35.53,61.94 35.58,61.94 38.16,64.52 v2(40.15,64.52)
  BOTTOM w0.508: v2(35.2,49.24) 35.2,50.51 37.23,52.54 v2(37.99,52.54)
3D3V_MUX2: length 8.2
  TOP w0.203: U3802.13 C3865.1
  TOP w0.356: v2(33.04,49.74) v1(33.45,49.34)
  TOP w0.508: R3812.2 32.81,49.52 v2(33.04,49.74) ; C3865.1 v2(34.18,45.35)
  L6 w0.508: v2(33.04,49.74) 33.04,48.3 33.68,47.66 33.68,45.86 v2(34.18,45.35)
3D3V_RTC_SYS: length 7.1
  TOP w0.254: D2501.1 169.73,3.1 170.33,2.5 v1(173.88,2.5) R2517.1 R2505.2
3D3V_S0: length 672.2
  TOP w0.203: v2(137.43,79.72) 138.32,79.72 139.21,78.83 139.21,73.49 139.85,72.86 141.37,72.86 141.88,73.37 R2609.1
  TOP w0.254: v2(80.03,102.55) 79.5,103.08 78.2,103.08 78,102.88 ; R5517.1 R5518.1 78,102.88 ; R2043.1 111.7,31.63 111.98,31.36 112.47,31.36 113.23,30.59 113.25,30.59 115.44,28.41 ; R7018.1 212.9,57.34 v2(212.31,56.76) ; 68.09,95.46 69.49,95.46 70.76,96.73 72.59,96.73 73.36,95.96 ; 73.36,95.96 73.3,95.9 73.3,94.45 74.32,93.43 92.1,93.43 92.86,94.19 113.05,94.19 113.94,93.31 v2(113.94,93.05) ; 73.36,95.96 R5504.2 ; R2430.2 155.44,25.44 155.11,25.11 v2(155.11,24.66) ; 78,102.88 77.67,103.21 76.04,103.21 R2053.1
  TOP w0.305: R4003.1 82.9,5.9 v2(83.05,5.75) ; v2(121.71,31.48) R2038.1 R2052.1 ; EC8979.1 166.64,9.87 v2(166.64,8.98)
  TOP w0.356: Q1801.2 v2(68.73,13.68) ; Q1801.5 v2(68.73,17.19)
  TOP w0.406: RN1810.2 66.87,16.17 v2(67.2,15.84) 66.87,15.5 RN1810.1
  TOP w0.508: R1216.1 67.05,17.56 67.05,20.51 v2(67.08,20.53) 66.95,20.66 R1208.2 C1228.1 R1204.2 ; EC8980.1 v2(205.76,64.6) ; R5737.1 22.83,61.25 22.49,60.91 v2(21.66,60.91) 20.84,60.91 20.47,61.28 R5756.1 ; v2(220.87,40.73) 221.58,40.73 R9102.1 221.71,39.86 R2046.1 221.69,38.44 R9120.2 ; R1211.2 v2(59.3,44.16) ; 227.41,27.77 222.91,27.77 222.39,27.26 v1(221.76,27.26) 219.36,27.26 218.46,28.15 216.68,28.15 216.38,27.85 R9141.2 ; R2604.1 48.48,12.61 49.04,13.17 ; R7004.1 208.45,57.72 v2(208.94,57.24) 208.1,56.4 EC8981.1 208.1,53.86 207.67,53.43 ; R2045.1 126.64,19.01 v2(127.05,19.42) ; v2(15.51,66.38) 15.8,66.38 15.92,66.51 R5738.1 R5739.1 ; EC8983.1 69.11,4.15 v2(69.36,4.41) ; v2(45.51,45.78) R1310.2 ; v2(220.75,52.41) 220.57,52.23 EC8978.1 ; v2(217.83,40.22) 217.88,40.27 R9145.1
  L3 w0.254: v2(118.54,24.14) 121.36,26.96 121.36,31.13 v2(121.71,31.48) ; v2(148.37,22.07) 146.87,22.07 146.63,22.31 136.95,22.31 v2(136.14,21.5) ; v2(137.05,35.77) 137.05,35.48 137.59,34.94 137.59,31.12 142.09,26.61 153.33,26.61 154.68,25.26 154.68,25.09 v2(155.11,24.66) 155.24,24.78 155.24,25.39 155.98,26.12 165.4,26.12 166.5,25.02 173.79,25.02 174.9,26.12 178.93,26.12 179.95,27.14 186.2,27.14 186.84,27.77 186.84,28.92 187.98,30.06 189.89,30.06 190.77,30.95 190.77,39.64 188.54,41.87 188.54,44.94 187.57,45.91 187.57,48.5 ; v3(197.38,45.3) 197.23,45.45 197.23,50.43 196.69,50.96 194.56,50.96 193.97,50.38 193.97,49.52 192.96,48.5 187.57,48.5 ; 187.57,48.5 186.08,50 186.08,54.82 186.84,55.59 186.84,59.14 186.31,59.67 v2(185.93,59.67) ; v2(137.43,79.72) 123.72,79.72 120.67,82.76 120.67,88.23 119.78,89.11 116.61,89.11 113.94,91.78 v2(113.94,93.05) ; v2(212.31,56.76) 212.41,56.86 213,56.86 213.96,55.89 v2(213.96,52.16)
  L3 w0.508: v2(187.7,80.81) 187.69,80.81 187.51,80.98 184.8,80.98 184.3,80.48 ; v3(64.54,98.89) 64.16,98.51 62.12,98.51 61.11,99.53 58.69,99.53 57.23,98.07 48.01,98.07 47.06,97.12 43.96,97.12 42.57,98.51 40.28,98.51 39.33,97.56 31.78,97.56 30.48,96.26 27.73,96.26 24.15,92.67 24.15,86.32 22.5,84.67 v3(22.5,77.18) ; v2(127.05,19.42) 129.94,22.31 135.33,22.31 v2(136.14,21.5) ; v2(68.73,13.68) 68.73,14.31 v2(67.2,15.84) ; v2(21.66,60.91) 21.66,46.24 18.82,43.39 18.82,37.54 21.23,35.13 21.23,27.22 19.93,25.92 19.93,24.6 v2(20.34,24.19)
  L4 w0.254: v2(96.03,38.12) 96.03,36.66 90.88,31.51 89.32,31.51 78.62,20.81 73.86,20.81
  L4 w0.508: v2(59.3,44.16) 59.3,43.91 ; 59.3,43.91 56.25,40.85 48.29,40.85 47.65,40.22 47.13,40.22 45.51,41.84 v2(45.51,45.78) ; 59.3,43.91 59.3,21.32 59.33,21.3 ; v2(20.34,24.19) 20.31,24.17 20.31,23.55 21.65,22.21 27.3,22.21 30.87,18.64 v3(32.02,18.64) 32.92,18.64 34.31,20.03 38.37,20.03 43.05,15.35 45.64,15.35 46.38,16.09 v2(46.38,16.85)
  L6 w0.254: v2(123.06,23.58) 123.06,23.94 123.85,24.73 124.34,24.73 125.82,26.21 126.96,26.21 131.32,30.57 134.51,30.57 137.94,34 137.94,34.89 v2(137.05,35.77)
  L6 w0.508: 17.83,76.04 18.97,77.18 v3(22.5,77.18) ; 17.83,76.04 17.3,76.04 17.22,75.96 v2(17.17,75.96) ; 17.83,76.04 17.83,68.42 15.8,66.38 v2(15.51,66.38) 15.51,66.27 16.16,65.62 16.95,65.62 v2(21.66,60.91) ; v3(64.54,98.89) 65.93,100.29 80.16,100.29 81.05,99.4 83.87,99.4 v2(85.06,100.6)
  BOTTOM w0.254: v3(22.5,77.18) 22.5,79.34 22.12,79.72 19.32,79.72 18.94,80.1 18.94,80.61 19.4,81.06 R5736.1 ; v2(213.96,52.16) 213.51,52.62 213.51,54.57 210.84,57.24 v2(208.94,57.24) ; v2(80.03,102.55) 80.82,101.76 84.02,101.76 85.06,100.72 v2(85.06,100.6)
  BOTTOM w0.279: v2(67.08,20.53) 67.62,21.07 DM1.255 ; DM2.255 53.68,21.07 v2(53.22,20.61)
  BOTTOM w0.305: v2(166.64,8.98) 166.64,8.6 166.8,8.44 167.69,8.44 170.41,5.72 DB1.10 ; R8307.1 121.51,90.21 120.62,89.32 120.62,86.27 119.53,85.18 117.37,85.18 116.1,83.91 115.46,83.91 112.67,86.7 112.67,91.78 v2(113.94,93.05) ; R4005.1 148.86,22.57 v2(148.37,22.07)
  BOTTOM w0.508: v2(17.17,75.96) 16.73,75.53 R5740.2 ; v2(200.68,12.53) 200.93,12.28 EC8982.1 ; PR8325.2 188.16,80.35 187.7,80.81 v2(187.7,80.81) ; v2(136.14,21.5) 136.39,21.75 R2489.2 140.11,21.24 Q2414.G ; v2(20.34,24.19) 20.52,24.01 R2751.2 ; v2(53.22,20.61) 53.22,20.29 54.5,19.01 v2(54.5,16.98) ; R506.1 85.41,99.69 85.06,100.05 v2(85.06,100.6) ; v2(220.87,40.73) 218.33,40.73 v2(217.83,40.22) ; PR4609.1 v2(185.93,59.67)
  vias: v1(31.36,74.21) v1(47.52,17.36) v1(55.77,12.79) v1(65.3,100.29) v1(66.31,95.59) v1(96.16,40.09) v1(112.42,92.8) v1(115.34,27.9) v1(117.24,26.63) v1(122.07,23.96) v1(127.15,20.92) v1(163.6,123.79) v1(185.31,76.16) v1(185.69,78.45) v1(206.9,52.41) v2(30.63,74.13) v2(116.1,28.25) v2(121.48,23.46) v2(185.41,77.86) v2(185.57,74.64) v2(185.57,73.87) v2(185.68,77.29) v2(206.52,53.43) v2(207.28,53.43) v3(163.09,124.8) v3(163.98,124.8) v3(197.38,44.28) v3(198.39,44.28) v3(228.24,29.04) v3(228.24,28.15) v3(229.26,29.04) v3(229.26,28.15)
3D3V_S5: length 374.1
  TOP w0.254: v2(111.32,15.34) 111.41,15.25 111.6,15.25 114.57,12.28 v2(114.7,12.28) 115.46,11.52 118,11.52 118.77,10.76 118.77,9.61 118.13,8.98 PR5208.1 ; PU4307.6 44.89,52 v2(44.47,52.41) ; v2(42.44,97.37) 44.67,97.37 PR5104.1
  TOP w0.305: v2(166.01,13.42) 166.52,12.91 166.52,12.36 166.31,12.15 ; R6604.2 215.87,47.03 v2(215.79,46.95) ; 166.31,12.15 EC8996.1 ; 166.31,12.15 Q2416.5 Q2416.2 163.22,12.15 162.96,12.41 R2434.1 ; RN2406.4 150.9,27.34 v2(150.69,27.14) 150.69,28.18 R1912.1 151.76,28.31 151.98,28.08 RN2406.3 ; U4007.5 v2(80.16,7.57)
  TOP w0.508: v2(74.32,18.5) 74.32,17.84 R1711.1 ; v2(147.64,1.52) 147.61,1.52 147.39,1.74 R2442.1 ; v3(196.36,48.09) 196.69,48.42 EC8994.1 ; PR4450.2 189.81,72.02 188.89,72.93 188.89,73.24 188.62,73.52 v2(188.62,74.64) ; R9101.1 223.29,34.38 222.91,34 v2(221.51,34) 221.51,33.11 221.76,32.85 221.76,31.2 221.46,30.9 R9143.1 ; v2(67.46,6.18) 67.89,5.75 EC8998.1 ; v2(164.23,24.66) 164.23,25.16 163.52,25.87 R2407.2 ; v2(92.04,29.98) R2001.1 91.03,30.69 R2050.2 ; v2(33.68,48.6) 33.27,48.2 R3812.1 31.16,48.2 30.58,48.78 L3801.1 30.58,51.52 v1(30.63,51.57) ; v2(220.87,42.38) 220.11,42.38 219.6,41.87 R9146.1
  L3 w0.254: v2(206.52,54.95) 208.05,56.48 208.05,62.7 207.28,63.46 207.28,69.56 206.65,70.19 v2(206.14,70.19)
  L3 w0.508: v2(33.45,101.64) 33.01,102.07 27.33,102.07 25.94,100.67 18.19,100.67 15.9,98.38 15.9,94.82 15.51,94.44 15.51,91.05 19.45,87.11 19.45,82.51 18.94,82 17.93,82 17.17,81.24 v2(17.17,80.86) ; v2(42.44,97.37) 43.33,96.48 v2(49.68,96.48) ; v2(99.92,90.38) 100.68,91.15 111.27,91.15 115.5,86.92 v2(115.5,85.18)
  L4 w0.254: v2(206.14,70.19) 206.14,70.57 203.28,73.44 199.98,73.44 198.27,75.14 189.12,75.14 v2(188.62,74.64) ; v2(92.04,29.98) 91.23,30.8 89.15,30.8 76.35,17.99 74.57,17.99 74.32,18.25 v2(74.32,18.5)
  L4 w0.508: v2(119.27,88.35) 119.78,88.35 120.29,87.84 120.29,86.71 122.27,84.73 123.98,84.73 128.11,80.61 134.76,80.61 136.03,81.88 v2(138.7,81.88) ; v2(220.87,42.38) 221.51,41.74 v2(221.51,34) ; v2(33.45,101.64) 33.45,98.87 34.08,98.23 41.96,98.23 42.44,97.75 v2(42.44,97.37)
  L6 w0.254: v2(164.23,24.66) 164.19,24.66 163.68,25.16 154.9,25.16 152.62,27.44 150.95,27.44 150.69,27.19 v2(150.69,27.14)
  BOTTOM w0.254: 42.44,98.26 43.05,98.87 PU5101.15
  BOTTOM w0.406: 150.01,14.44 150.01,13.17 151.02,12.15 v1(154.1,12.15) 154.71,12.15 155.01,11.85 157.42,11.85 159.07,10.2 159.07,2.93 157.67,1.52 v2(147.64,1.52)
  BOTTOM w0.508: v2(115.5,85.18) 117.4,87.08 118.08,87.08 119.27,88.28 v2(119.27,88.35) ; v2(33.68,48.6) 33.68,46.82 34.31,46.19 35.33,46.19 37.23,44.28 37.23,41.92 38.17,40.98 38.17,38.75 36.09,36.66 36.09,32.09 38.12,30.06 42.82,30.06 ; EC8912.1 55.44,96.4 55.9,96.86 57.17,96.86 57.61,97.3 PD4302.2 ; EC8912.1 54.5,95.8 PR4304.1 54.83,95.01 55.65,94.19 55.65,90.89 ; EC8912.1 53.31,96.4 52.85,96.86 50.06,96.86 v2(49.68,96.48) ; v2(164.23,24.66) 164.23,23.96 165.17,23.02 165.17,14.26 v2(166.01,13.42) ; 42.44,98.26 v2(42.44,97.37) PC5110.1 ; v2(138.7,81.88) 138.96,81.62 140.61,81.62 141.5,80.73 141.5,78.06 141.07,77.63 PR4472.1 PR4435.1 ; EC8999.1 34.31,12.1 v2(34.31,11.26) ; v2(207.28,54.95) 208.55,54.95 209.44,54.06 209.44,52.28 211.6,50.13 211.6,47.37 212.53,46.44 214.52,46.44 215.03,46.95 v2(215.79,46.95) 217.06,45.68 217.06,42.51 217.57,42 219.1,42 219.48,42.38 v2(220.87,42.38) ; U4302.2 16.28,81.95 PR4335.1 16.61,81.42 v2(17.17,80.86)
  vias: v1(43.07,30.31) v1(45.33,84.09) v1(46.96,76.21) v1(47.09,63.82) v1(50.49,88.12) v1(66.34,11.92) v1(116.83,12.05) v1(197.12,50.25) v2(37.21,18.99) v2(43.84,30.62) v2(45.66,62.88) v2(45.84,63.69) v2(63.39,8.97) v2(97.33,90.33) v2(98.06,90.36) v2(151.45,16.22) v3(37.1,18.25) v3(37.94,18.91) v3(37.94,18.07) v3(40.91,8.47) v3(40.91,7.58) v3(41.83,8.47) v3(41.8,7.58) v3(43.89,29.86) v3(44.72,30.69) v3(44.72,29.81) v3(54.76,89.19) v3(55.65,89.22) v3(56.54,89.24) v3(57.42,89.24) v3(67.08,13.8) v3(86.38,13.42) v3(190.9,18.12) v3(190.9,17.23) v3(191.79,18.12) v3(191.79,17.23) v3(195.47,50.13) v3(195.47,48.09) v3(195.47,47.2) v3(195.47,46.32) v3(195.47,45.43) v3(196.36,50.13) v3(196.36,47.2) v3(196.36,46.32) v3(196.36,45.43)
3D3V_S5_KBC: length 628.4
  TOP w0.203: KBC24.103 146.84,7.06 v2(147.09,6.82) ; v2(141.53,15.28) 141.82,14.98 KBC24.82 ; v2(158.39,8.34) 158.92,8.34 159.35,8.77 159.35,10.58 158.95,10.98 KBC24.5 ; v2(153.21,24.66) 152.84,24.29 KBC24.43 ; v2(160.17,18.25) 159.7,17.78 KBC24.22 ; v2(159.93,16.22) 159.57,16.58 KBC24.19 ; KBC24.65 143.02,23.05 v2(141.88,24.2) ; R2608.1 141.12,73.75 140.61,73.24 140.1,73.24 139.59,73.75 139.59,79.46 v1(138.74,80.32) 137.82,81.24 v2(137.43,81.24) ; KBC24.115 151.64,7.1 151.28,6.73 v2(151.28,6.67)
  TOP w0.254: RN2413.1 141.16,6.69 141.29,6.56 141.71,6.56 141.83,6.69 RN2413.2 ; C2413.1 145.51,4.56 146.22,5.27 146.35,5.27 147.21,6.13 147.21,6.69 v2(147.09,6.82) ; R2458.1 153.18,25.34 153.23,25.29 153.23,24.68 v2(153.21,24.66) ; v2(151.28,6.67) 151.28,6.11 151.91,5.47 C2420.1 151.05,4.99 R2443.1
  TOP w0.305: RN2413.2 142.45,7.14 v2(142.77,6.82) 142.79,6.79 Q2417.2 Q2417.5
  TOP w0.356: RN2402.2 162.95,9.3 v2(163.22,9.04) 162.83,8.65 RN2402.1
  TOP w0.508: v2(203.09,13.17) 203.09,13.03 199.93,9.87 198.76,9.87 195.09,6.2 195.09,5.8 v2(193.7,4.41) ; v2(160.17,18.25) 160.42,17.99 C2429.1 ; C2410.1 160.18,16.47 v2(159.93,16.22) ; R2424.2 163.01,21.93 163.67,21.93 v2(163.75,21.86) ; v2(28.21,28.66) R3707.1 ; C2422.1 v2(146.12,3.9) ; R2414.2 R2480.2 180.62,4.53 181.12,4.03 v2(181.12,3.9)
  L3 w0.508: v2(153.21,3.52) 153.21,4.47 ; 153.21,4.47 153.52,4.79 154.96,4.79 155.34,4.41 163.11,4.41 163.22,4.52 172.72,4.52 172.73,4.53 173.26,4.53 173.27,4.52 173.61,4.52 173.62,4.53 174.15,4.53 174.16,4.52 175.35,4.52 v2(175.79,4.08) ; 153.21,4.47 151.28,6.4 v2(151.28,6.67) ; v2(181.12,3.9) 181.12,4.03 182.64,5.55 192.56,5.55 193.44,4.67 193.44,4.66 v2(193.7,4.41) 194.97,4.41 199.54,8.98 210.71,8.98 218.71,16.98 220.95,16.98 222.45,18.48 222.45,20.34 222.14,20.65 222.14,43.9 220.87,45.17 220.87,50.51 219.35,52.03 219.35,53.43 217.83,54.95 217.83,58.12 214.78,61.17 214.78,64.45 213,66.23 213,67.78 211.96,68.82 211.96,69.03 211.27,69.71 211.02,69.71 210.46,70.27 210.46,70.78 209.8,71.44 209.34,71.44 208.68,72.1 207.32,72.1 205.67,73.75 200.68,73.75 199.11,75.32 189.93,75.32 189.5,74.9 189.5,74.48 188.67,73.64 188.67,72.43 189.91,71.19 189.91,70.47 189.25,69.81 185.31,69.81 184.55,70.57 182.77,70.57 181.65,71.69 177.41,71.69 176.08,70.37 174.3,70.37 173.27,71.4 166.71,71.4 164.36,69.05 151.79,69.05 145.88,74.95 144.74,74.95 138.45,81.24 v2(137.43,81.24) ; v2(119.53,87.46) 117.37,87.46 108.48,96.35 81.81,96.35 81.17,96.99 81.17,98.39 79.99,99.57 77.53,99.57 75.26,101.84 69.62,101.84 68.56,100.78 68.56,98.08 68.73,97.91 68.73,94.19 68.09,93.56 63.14,93.56 62,94.7 50.95,94.7 50.31,94.07 41.04,94.07 39.98,95.13 33.37,95.13 32.33,94.09 31.39,94.09 30.75,94.73 28.75,94.73 27.96,93.94 27.96,86.57 28.98,85.56 28.98,75.27 29.87,74.38 29.87,69.18 31.77,67.27 33.42,67.27 37.1,63.59 37.1,62.7 38.73,61.07 38.73,49.9 40.09,48.54 40.09,33.04 40.91,32.22 40.91,28.28 40.15,27.52 v2(39.39,27.52) ; v2(141.88,24.2) 152.75,24.2 v2(153.21,24.66) ; v2(147.09,6.82) 147.09,6.72 146.55,6.18 143.15,6.18 142.77,6.56 v2(142.77,6.82)
  L4 w0.508: v2(163.22,9.04) 162.69,9.56 158.85,9.56 158.39,9.1 v2(158.39,8.34) ; v2(119.53,87.46) 119.53,86.57 122,84.1 123.72,84.1 127.85,79.97 135.02,79.97 136.29,81.24 v2(137.43,81.24) ; v2(28.21,28.66) 28.6,28.66 30.37,26.88 31.52,26.88 32.41,27.77 39.14,27.77 v2(39.39,27.52)
  L6 w0.508: v2(181.12,3.9) 181.12,3.76 180.62,3.26 176.6,3.26 v2(175.79,4.08) ; v2(153.21,24.66) 153.21,24.17 154.43,22.95 162.66,22.95 v2(163.75,21.86) ; v2(160.17,18.25) 160.17,16.45 v2(159.93,16.22)
  BOTTOM w0.305: v2(181.12,3.9) 181.12,3.52 180,2.39 DBEC1.1
  BOTTOM w0.508: 145.67,21.42 145.67,21.78 148.05,24.17 C2414.1 152.72,24.17 152.93,23.96 ; 145.67,21.42 142.77,21.42 142.13,20.79 ; 145.67,21.42 145.67,21.06 146.32,20.41 146.32,19.39 ; v2(141.53,15.28) 141.96,15.7 141.96,19.69 142.13,19.87 142.13,20.79 ; 142.13,20.79 142.13,21.5 141.88,21.75 v2(141.88,24.2) 141.7,24.01 C2412.1 ; 202.65,14.76 203.09,14.31 v2(203.09,13.17) 203.09,11.64 202.78,11.33 D4306.2 ; 202.65,14.76 202.71,14.82 202.71,16.98 201.01,18.68 D4304.2 ; 202.65,14.76 D4305.2 ; 163.09,14.31 163.09,11.99 163.22,11.86 v2(163.22,9.04) ; 163.09,14.31 160.42,14.31 160.17,14.57 ; 163.09,14.31 164.54,15.76 164.54,20.08 163.75,20.87 v2(163.75,21.86) 162.22,23.38 R2415.2 ; v2(153.21,3.52) 153.21,3.92 153.94,4.66 157.63,4.66 158.39,5.42 v2(158.39,8.34) ; v2(146.12,3.9) 146.25,3.77 146.89,3.77 147.47,4.35 147.47,5.68 147.09,6.06 v2(147.09,6.82) 147.59,7.33 R2473.2 151.28,7.25 v2(151.28,6.67)
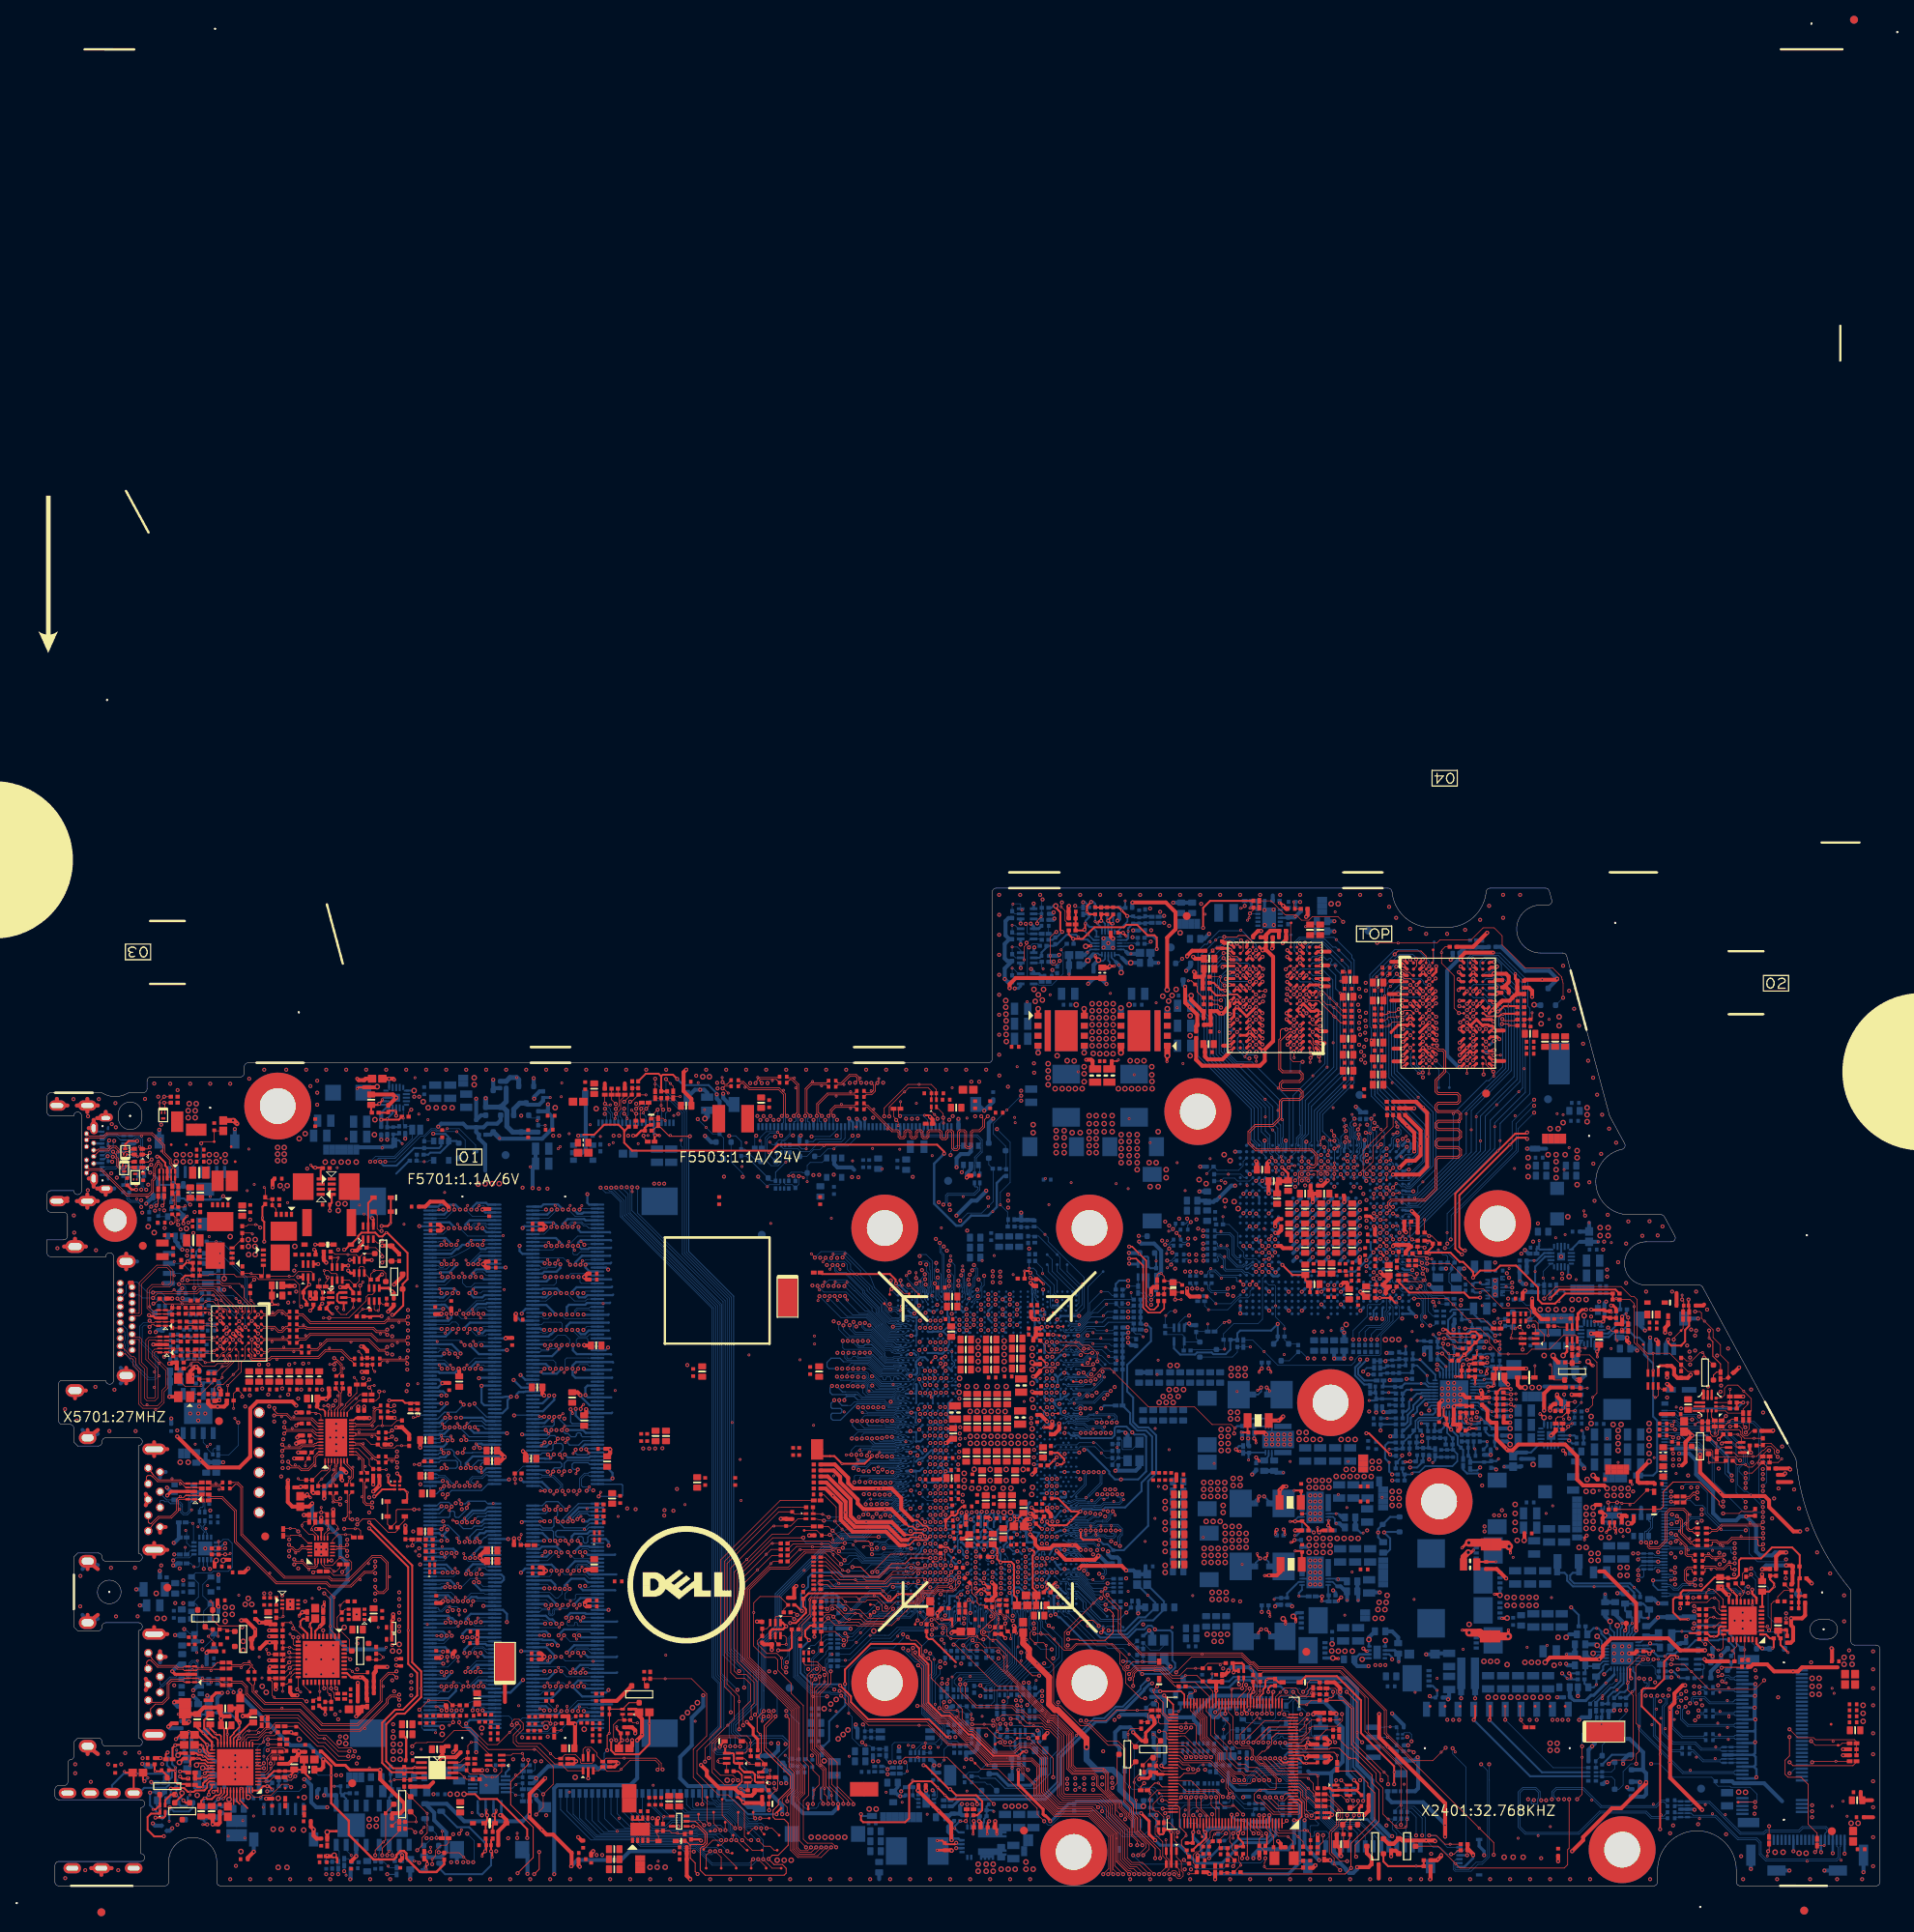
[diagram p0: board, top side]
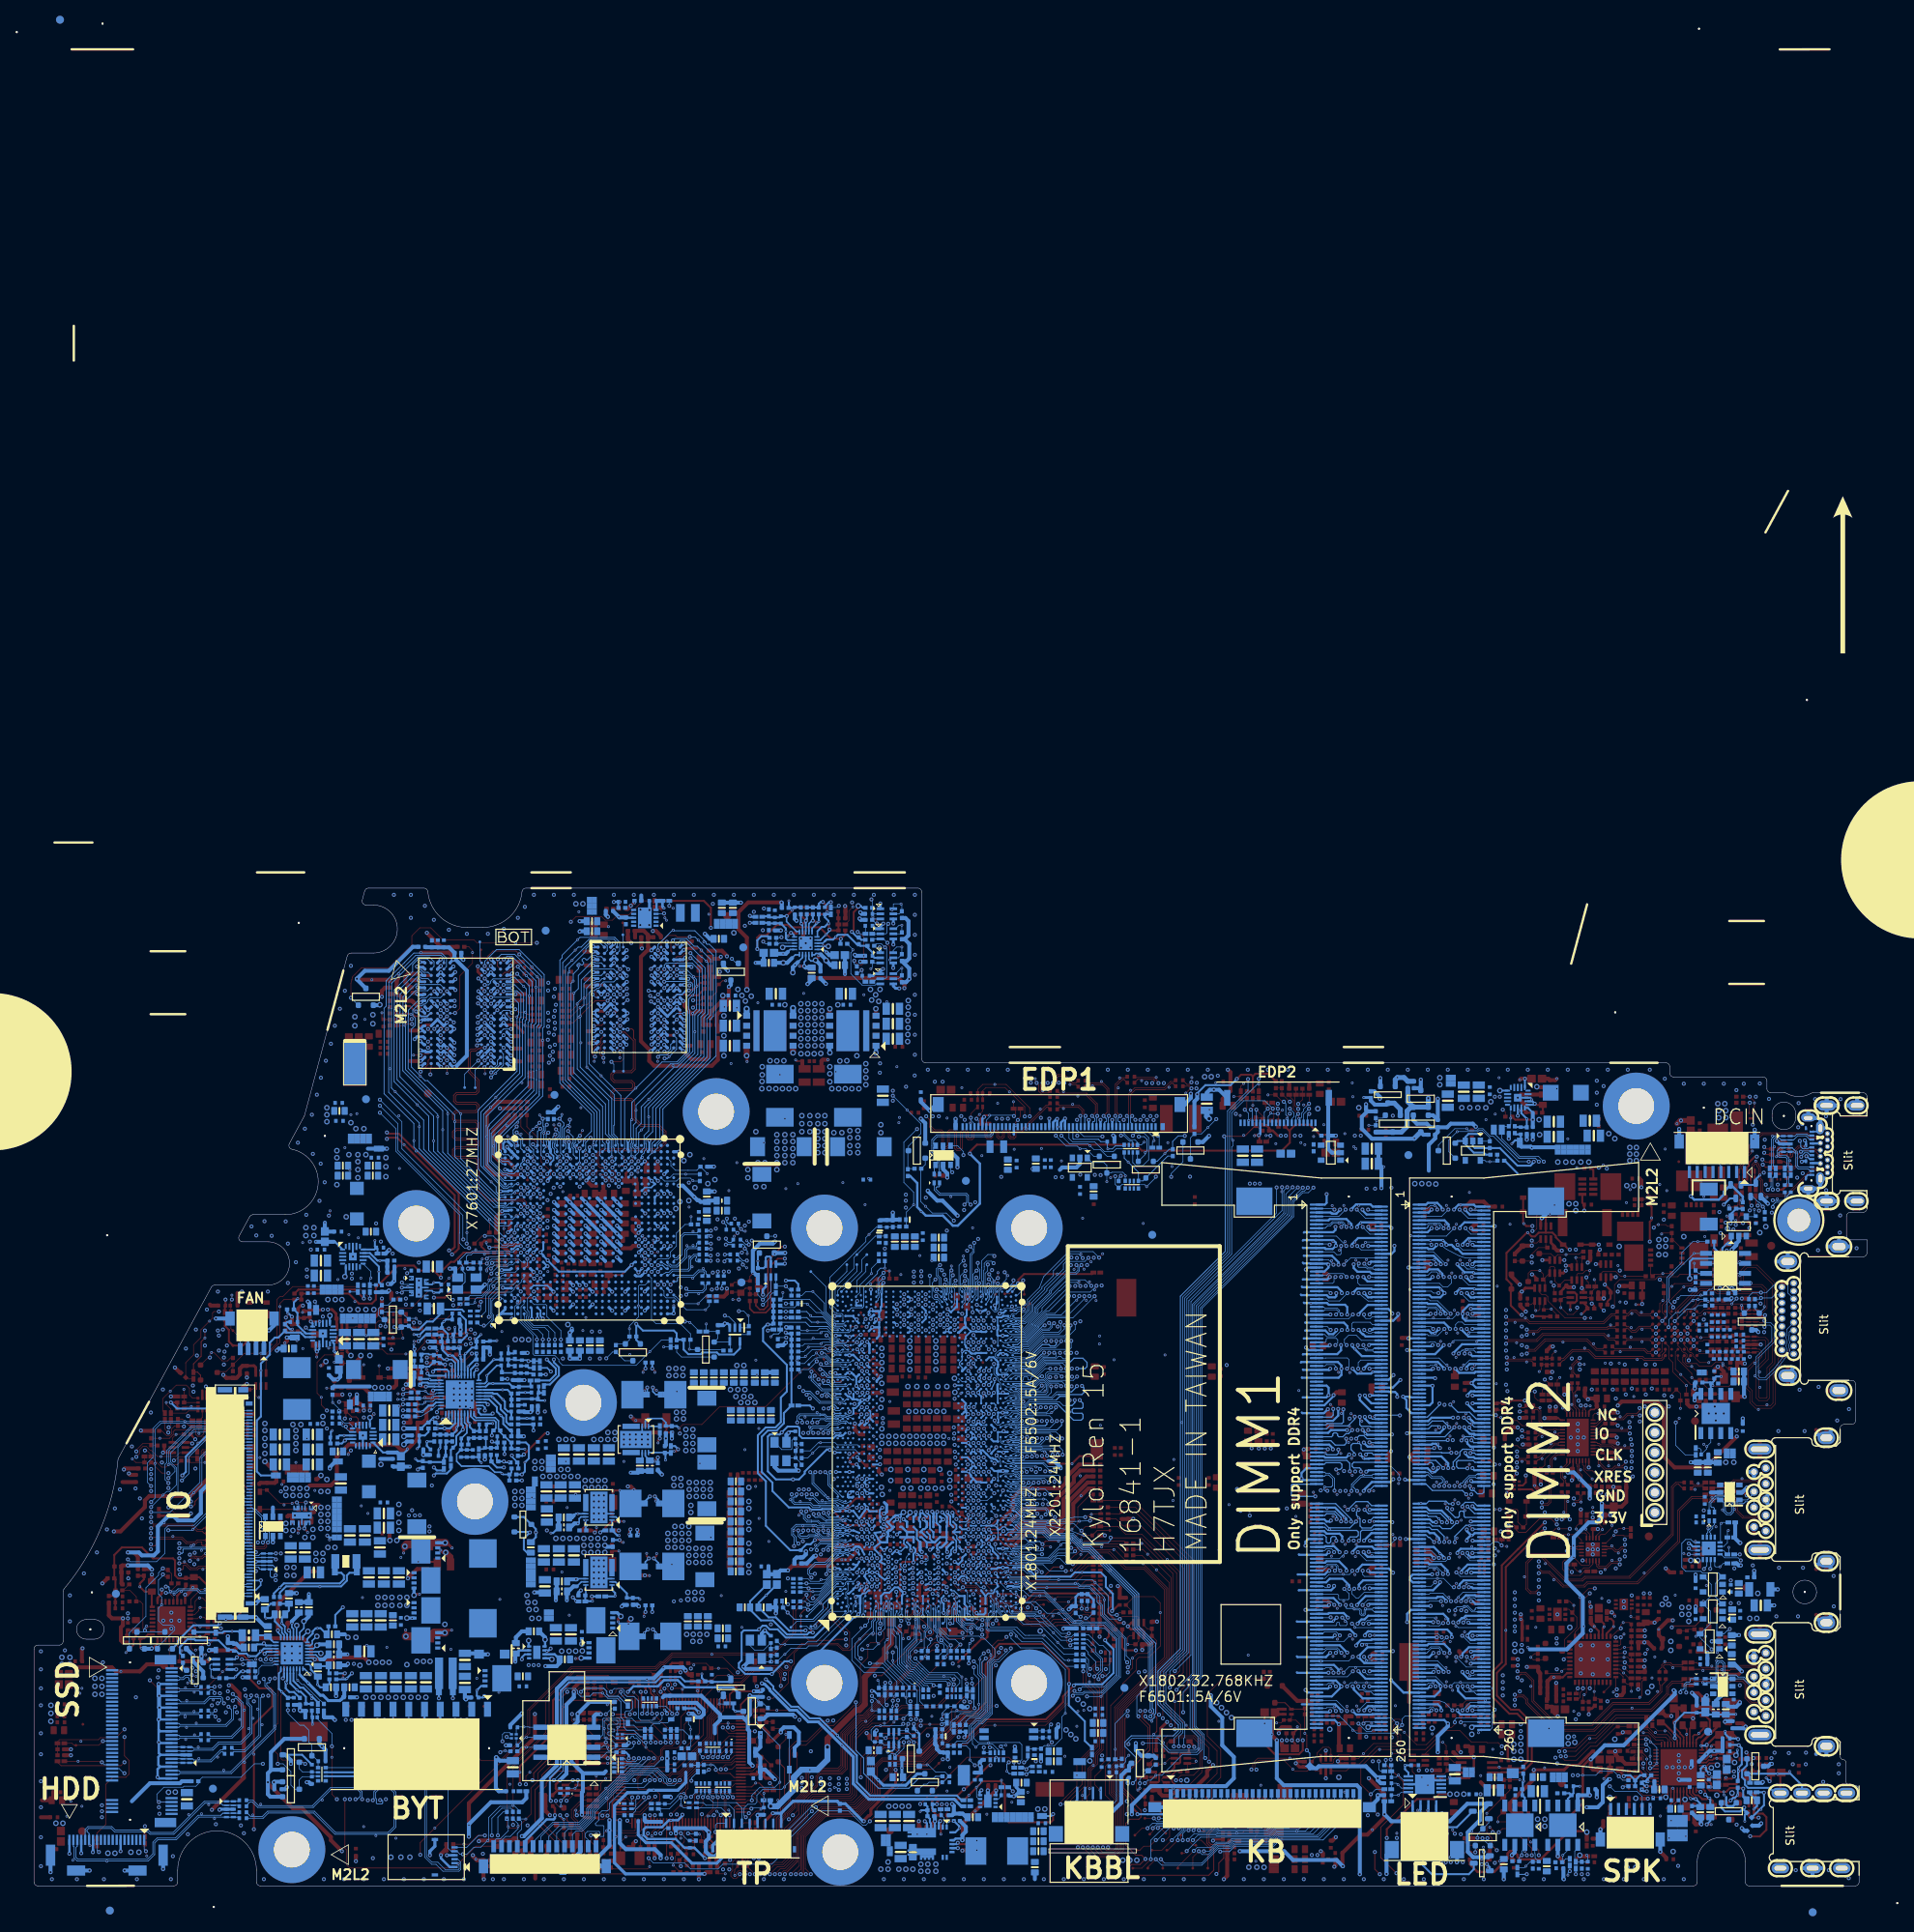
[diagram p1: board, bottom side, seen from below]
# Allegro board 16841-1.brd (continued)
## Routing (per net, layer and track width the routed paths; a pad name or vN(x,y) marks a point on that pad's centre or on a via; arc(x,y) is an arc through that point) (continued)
3D3V_S5_PCH: length 248
  TOP w0.406: RN1811.2 72.33,15.79 v2(72.54,15.58) 72.08,15.12 RN1811.1
  TOP w0.508: v2(169.18,21.84) 169.18,18.88 177.57,10.5 v1(177.57,7.71) v2(177.57,6.26) ; R9103.1 v2(224.12,38.44)
  L3 w0.254: v2(157.25,16.22) 158.14,15.33 169.39,15.33 173.12,11.6 173.12,10.71 v2(177.57,6.26)
  L4 w0.254: v2(224.12,38.44) 223.23,37.55 223.23,18.18 225.55,15.86 225.55,7.43 225.03,6.91 214.81,6.91 213.33,8.4 205.94,8.4 205.56,8.01 197.05,8.01 194.34,5.3 186.08,5.3 185.12,6.26 v2(177.57,6.26) ; v2(91.71,27.27) 90.7,27.27 89.4,25.97 89.4,23.47 84.94,19.01 81.09,19.01 79.01,16.93 73.88,16.93 v2(72.54,15.58)
  L6 w0.254: v2(91.71,27.27) 91.71,27.14 92.27,26.58 92.73,26.58 93.24,27.09 93.24,28.79 94.18,29.73 97.29,29.73 v2(97.3,29.73)
  L6 w0.508: 141.63,31.57 141.63,32.98 139.72,34.89 139.72,36.41 v2(137.05,39.08) ; 141.63,31.57 139.56,29.5 131.28,29.5 127.18,25.4 126.12,25.4 125.62,24.9 125.62,22.79 122.57,19.73 119.86,19.73 v2(119.27,19.14) ; 141.63,31.57 142.66,31.57 147.8,26.42 151,26.42 151.04,26.46 152.69,26.46 153.84,25.3 153.84,24.9 154.91,23.84 167.18,23.84 v2(169.18,21.84)
  BOTTOM w0.254: v2(157.25,16.22) 157.25,16.6 157.63,16.98 R2501.2
  BOTTOM w0.508: R2515.1 170.28,11.14 170.78,10.63 174.77,10.63 177.57,7.83 v2(177.57,6.26) ; v2(102.06,32.67) 102,32.73 R404.1
  vias: v1(99.72,29.42) v1(110.89,34.76) v1(116.48,15.07) v1(118.77,21.55) v1(137.31,37.43) v2(114.65,23.43) v3(105,32.39)
3D3V_SEN_S0:
  vias: v1(68.98,96.73) v3(69.74,98.77)
3D3V_SPIVCC1:
  vias: v1(172.36,12.91)
3D3V_SSD: length 9.5
  TOP w0.508: R6303.1 v2(228.11,17.36)
  BOTTOM w0.508: R6305.1 214.02,13.3 214.27,13.04 218.08,13.04 220.37,10.76
  vias: v1(226.72,25.11) v1(226.72,10.12) v1(226.84,18.38) v1(226.97,24.47) v1(228.11,10.76) v2(224.18,10.25) v2(224.18,9.49) v2(224.18,8.72) v3(224.18,26.38) v3(224.18,25.36) v3(224.18,24.34) v3(225.06,26.38) v3(225.06,25.36) v3(225.06,24.34)
3D3V_TPM: length 41.2
  TOP w0.254: C9101.1 C9102.1 C9104.1 ; 208.58,32.12 R9149.1 ; v1(208.43,33.87) 207.41,33.87 206.52,34.76 206.52,36.41 206.78,36.66 R9119.1 207.49,37.25 207.79,37.55 210.13,37.55 211.81,39.23 C9105.1 212.59,39.13 R9147.1 213.57,39.07 214.48,39.07 214.89,39.48 214.89,41.36 215.14,41.62 217.7,41.62 219.1,43.01 221.64,43.01 222.6,42.05 222.6,40.63 R9102.2 222.6,40.58 R9103.2 222.45,38.92 R9138.1 222.47,36.89 C9104.1 ; C9104.1 222.52,36.84 R9101.2
  BOTTOM w0.254: Q9102.S 214.52,30.83 214.52,31.15 212.57,33.11 209.44,33.11 v2(209.19,33.36)
3D3V_TPM_1: length 5.2
  TOP w0.254: v1(221.13,29.65) 220.16,30.62 R9144.1 219.86,31.76 C9106.1 219.93,32.52 C9113.1 221,32.4 R9143.2
3D3V_VGA_CT_1: length 2.1
  BOTTOM w0.203: U8301.12 182.25,76.43 v1(182.01,76.67)
  BOTTOM w0.254: v1(182.01,76.67) 181.33,76.67 C8302.1
3D3V_VGA_S0: length 176.2
  TOP w0.254: R7618.1 175.61,82 R7635.1 175.99,81.27 R7620.1 178.24,80.48 179.42,79.3 179.85,79.3 181.12,78.02 v2(181.12,77.3) 182.01,78.19 183.92,78.19 184.55,78.83 186.58,78.83 189.38,76.03 189.38,74.5 189.88,74 191.54,74 192.81,75.27 R8301.2 PR8329.1 ; v2(128.93,121.25) 128.69,121.48 128.69,123.74 128.11,124.32 v3(128.11,124.54)
  L3 w0.254: v2(181.12,77.3) 181.12,77.05 177.69,73.62 174.39,73.62 v2(174.14,73.87) ; v2(167.58,78.74) 167.58,75.36 170.84,72.1 v2(172.11,72.1)
  L6 w0.254: v3(128.11,124.54) 128.89,123.76 137.59,123.76 138.88,125.06 142.2,125.06 144.91,122.35 147.76,122.35 148.74,121.37 151.02,121.37 151.75,120.64 151.85,120.64 152.01,120.48 171.22,120.48 171.98,119.72 183.66,119.72 192.93,110.45 192.93,103.47 194.08,102.32 194.08,95.11 193.04,94.07 190.93,94.07 189.25,92.39 189.25,90 188.21,88.96 188.21,80.24 186.54,78.57 182.39,78.57 v2(181.12,77.3) ; v2(172.11,72.1) 173.88,73.87 v2(174.14,73.87)
  BOTTOM w0.254: GPU1.G8 168.03,78.44 167.73,78.74 v2(167.58,78.74) 167.58,78.75 GPU1.G9 ; PR8318.1 127.73,120.23 PR8256.1 128.21,120.53 v2(128.93,121.25) ; PR8310.1 127.54,124.29 127.78,124.54 v3(128.11,124.54)
  vias: v1(167.53,78.07)
3D3V_VGA_S0_DISCHG: length 4.5
  TOP w0.089: v1(124.1,117.69) 124.1,119.34 124.4,119.65 v2(124.4,119.85)
  BOTTOM w0.089: v2(124.4,119.85) 124.9,120.34 PQ8307.3 126.22,120.34 PR8318.2
27MHZ_IN: length 12.6
  BOTTOM w0.089: v1(176.7,80.83) 176.7,80.68 ; 176.7,80.68 177.13,80.68 177.37,80.44 177.86,80.44 178.76,79.54 R7603.1 178.38,78.83 C7607.2 178.38,78.16 178.06,77.84 178.06,76.72 X7601.1 ; 176.7,80.68 172.43,80.68 172.33,80.58 171.89,80.58 171.55,80.92 GPU1.C11
27MHZ_OUT: length 7.9
  BOTTOM w0.089: GPU1.B10 172.39,80.32 172.4,80.32 172.53,80.44 175.58,80.44 ; 175.58,80.44 177.03,80.44 177.27,80.2 177.67,80.2 177.9,79.97 R7603.2 R7604.2 ; 175.58,80.44 v1(175.58,80.28)
27MHZ_OUT_R: length 2.2
  BOTTOM w0.14: X7601.3 176.09,77.85 C7608.2 176.12,78.47 R7604.1
+DC_IN: length 9.1
  BOTTOM w0.305: v2(22.37,87.64) 21.94,87.21 18.82,87.21 18.18,87.84 18.18,88.22 PQ4305.2 17.27,89.09 15.77,87.59 PR4312.1
  vias: v1(25.42,88.35)
+DC_IN_C:
  vias: v3(20.59,92.92) v3(20.59,92.04) v3(21.48,92.92) v3(21.48,92.04) v3(22.63,92.92) v3(22.63,92.04)
+RTC_VCC: length 117
  TOP w0.508: D2501.2 170.38,5.35 R2504.1 171.03,5.35 Q2505.G 171.92,5.99 172.14,5.76 v1(175.15,5.76) 176.21,5.76 v2(176.3,5.68) ; v2(209.95,54.82) 209.95,52.53 212.94,49.54 218.15,49.54 218.71,48.98 218.71,48.14 221.81,45.05 v2(222.65,45.05)
  L3 w0.508: v2(222.65,45.05) 222.69,45.01 222.74,44.85 223.1,44.17 223.1,29.36 v2(224.05,28.41)
  L6 w0.508: v2(176.3,5.68) 176.6,5.37 195.47,5.37 198.45,8.36 203.19,8.36 205.74,10.91 212.44,10.91 214.83,8.53 217.89,8.53 225.57,16.21 225.57,23.16 225.8,23.39 225.8,26.68 225.37,27.11 225.34,27.11 v2(224.05,28.41)
  BOTTOM w0.203: 206.78,55.6 IOBD1.48
  BOTTOM w0.508: v2(209.95,54.82) 209.95,55.33 209.68,55.6 206.78,55.6
+SDC_IN: length 10.9
  TOP w0.508: v2(201.82,32.47) 201.82,35.93 197.78,39.97 197.12,39.97
  BOTTOM w0.203: v2(201.82,32.47) 201.82,32.22 201.45,31.84 PU4401.16
  vias: v1(26.31,89.14) v1(37.99,94.93) v1(61.36,91.38) v1(88.26,91.42) v1(106.07,91.12) v1(120.11,85.69) v1(131.52,76.52) v1(157.12,67.52) v1(191.23,48.3) v3(25.55,82.13) v3(25.57,81.27) v3(25.6,80.22) v3(26.44,82.13) v3(26.41,81.27) v3(26.44,80.22) v3(29.28,93.84) v3(29.28,93) v3(29.28,92.16) v3(30.12,93.84) v3(30.12,93) v3(30.12,92.16) v3(194.58,43.01) v3(195.47,43.01) v3(196.11,42.25) v3(196.11,41.36) v3(197,42.25) v3(197,41.36)
+SDC_IN_SW: length 4
  TOP w0.089: v1(26.08,82.84) 25.95,82.97 PR4333.2 PR4318.2 24.58,82.05 23.6,81.07 PU4302.4
+SDC_IN_SW_R1: length 22.1
  TOP w0.089: PQ4310.3 41.93,81.7 42.26,81.7 v2(42.57,82) ; v2(27.07,83.65) 26.69,84.03 v1(26.49,84.03) 25.55,84.03 25.34,83.83 PR4333.1
  L4 w0.089: v2(42.57,82) 42.06,82.51 33.65,82.51 31.69,80.56 29.7,80.56 27.07,83.18 v2(27.07,83.65)
+UZ12_TPM: length 6.1
  TOP w0.254: U9101.8 217.84,37.38 C9114.1 218.74,37.4 v1(219.35,38.01) 219.35,38.44 218.84,38.95 R9145.2 R9146.2
+V_VREF_PATH1:
  vias: v1(68.57,47.94)
+V_VREF_PATH2:
  vias: v1(50.21,44.51)
A5_TP: length 8.1
  BOTTOM w0.089: TP2309.1 135.91,33.62 133.75,33.62 131.97,35.39 131.97,35.96 130.78,37.15 CPU1.A5
A67_TP: length 7
  BOTTOM w0.089: CPU1.A67 131.47,73.85 131.47,76.16 129.56,78.07 TP2311.1
A70_TP: length 4.9
  BOTTOM w0.089: CPU1.A70 130.71,75.64 128.29,78.07 TP2310.1
AC_DIS: length 188.6
  TOP w0.102: v2(52.34,6.63) 52.62,6.91 v1(52.62,7.11) ; KBC24.69 143.99,20.18 v2(144.04,20.13) ; PD4309.A 45.44,46.48 R4306.1 44.52,45.22 44.22,44.92 43.33,44.92 41.63,46.62 40.08,46.62 v2(39.39,45.93)
  L3 w0.102: v2(129.56,12.31) 130.15,12.89 130.15,13.86 130.4,14.11 130.7,14.11 133.09,16.5 134.28,16.5 136.65,18.86 138.33,18.86 139.82,20.36 143.81,20.36 v2(144.04,20.13) ; v2(29.74,52.03) 29.74,51.29 35.1,45.93 v2(39.39,45.93)
  L4 w0.102: v2(52.34,6.63) 52.78,6.2 56.55,6.2 57.17,6.82 70.61,6.82 75.84,12.05 83.58,12.05 86.1,14.57 88.38,14.57 90.7,12.25 90.71,12.25 90.75,12.21 90.92,12.21 94.27,12.21 95.39,11.09 106.58,11.09 107.37,10.31 108.77,10.31 110.06,11.59 113.3,11.59 114.67,12.96 116.99,12.96 117.94,12.01 129.27,12.01 v2(129.56,12.31)
  L6 w0.102: v2(29.74,52.03) 29.24,51.54 29.24,41.14 33.9,36.47 33.9,15.61 38.95,10.57 38.95,7.64 40.48,6.11 47.58,6.11 48.03,6.56 50.48,6.56 50.93,6.11 51.82,6.11 v2(52.34,6.63)
AC_DIS_R: length 88.1
  TOP w0.102: PD4310.K PD4309.K 43.24,45.97 R4306.2 44.34,46.24 44.34,47.71 44.47,47.84 v2(46.63,47.84) v1(47.26,47.84)
  L3 w0.102: v2(46.63,47.84) 46.63,57.62 47.76,58.75 47.76,62.38 44.27,65.87 43.33,65.87 38.88,70.32 34.44,70.32 33.93,70.83 33.93,75.14 32.86,76.21 32.86,90.97 v2(33.04,91.15)
  L6 w0.102: v2(13.23,86.32) 13.23,87.08 14.24,88.1 31.39,88.1 33.04,89.75 v2(33.04,91.15)
  BOTTOM w0.102: PQ4304.B 14.5,87.59 13.79,86.88 13.68,86.88 13.43,86.63 13.43,86.52 v2(13.23,86.32) 12.97,86.07 R4303.1
AC_IN#_G: length 38.9
  TOP w0.254: v2(17.17,76.97) 17.17,77.18 17.55,77.56 R2499.1 ; v2(17.32,84.19) 17.32,84.64 v1(17.8,85.13) ; v2(33.42,73.11) 33.83,73.52 R4305.1
  L3 w0.254: v2(17.32,84.19) 16.76,84.75 15.36,84.75 14.42,83.81 14.42,79.72 v2(17.17,76.97)
  L6 w0.254: v2(33.42,73.11) 33.42,73.75 32.79,74.38 32.79,75.78 31.71,76.86 31.69,76.86 31.39,77.16 31.39,77.28 30.35,78.32 17.8,78.32 17.17,77.68 v2(17.17,76.97)
  BOTTOM w0.254: PR4312.2 15.81,86.07 PR4313.1 17.23,85.44 U4302.5 17.23,84.28 v2(17.32,84.19)
AC_PRESENT: length 92.5
  TOP w0.089: v2(87.75,13.42) 87.12,14.06 85.53,14.06 84.73,14.86 84.73,17.23 v1(84.86,17.36) 84.86,18.13 85.56,18.83 87.65,18.83 88.11,18.38 D1701.A 88.67,18.38 88.92,18.12 88.92,17.11 88.68,16.87 Q1702.3
  L3 w0.089: v2(87.75,13.42) 87.95,13.63 89.27,13.63 90.79,15.15 103.35,15.15 106.34,18.14 111.61,18.14 v2(112.16,17.59)
  L4 w0.089: v2(104.77,42.15) 104.44,42.15 103.81,41.52 103.81,40.55 99.74,36.49 98.7,36.49 97.84,35.62 97.84,34.45 94.97,31.59 94.97,20.47 97.77,17.67 100.21,17.67 100.84,17.04 109.44,17.04 109.64,16.85 111.41,16.85 v2(112.16,17.59)
  BOTTOM w0.089: RN1704.8 112.15,16.92 EC1707.1 v2(112.16,17.59) ; CPU1.AY15 109.35,43.49 108.76,42.9 108.76,42.81 108.59,42.63 108.49,42.61 108.32,42.61 108.2,42.65 107.73,42.65 107.48,42.4 106.27,42.4 106.01,42.15 v2(104.77,42.15)
ACOK#: length 4.2
  BOTTOM w0.127: PR4427.2 210.05,26.4 v1(210.21,26.55) 210.32,26.67 210.32,27.5 ; 210.32,27.5 PQ4415.3 ; 210.32,27.5 210.46,27.65 210.46,28.03 210.33,28.15 PQ4415.2
ACOK_IN_M: length 286.9
  TOP w0.254: D1701.K 85.62,17.95 85.62,17.84 v2(85.44,17.66) ; v2(204.87,7.2) v1(204.87,16.72) 204.87,20.48 202.53,22.82 202.53,24.85 202.79,25.11 204.19,25.11 205.38,26.29 205.38,28.49 206.18,29.3 206.78,29.3 v2(207.03,29.04) ; v2(34.06,81.49) PD4306.K PD4305.K
  L4 w0.254: v2(204.87,7.2) 204.75,7.32 197.62,7.32 194.2,3.9 191.41,3.9 190.62,4.69 185.82,4.69 185.57,4.94 173.38,4.94 172.74,5.57 161.36,5.57 160.5,6.44 156.36,6.44 155.47,7.33 151.67,7.33 151.48,7.52 147.41,7.52 147.39,7.54 146.83,7.54 146.62,7.75 142.21,7.75 141.75,8.22 140.36,8.22 139.85,8.73 139.85,10.37 139.78,10.44 137.1,13.12 137.1,14.85 135.8,16.15 126.91,16.15 126.07,15.31 118.33,15.31 118.05,15.58 115.72,15.58 115.46,15.84 112.46,15.84 112.03,15.41 112.03,15.33 111.52,14.82 108.11,14.82 106.97,13.68 97.22,13.68 93.69,17.21 85.9,17.21 v2(85.44,17.66) 81.96,17.66 79.96,15.66 74.96,15.66 71.56,12.27 39.15,12.27 v2(37.36,14.06)
  L6 w0.254: v2(37.36,14.06) 37.36,14.57 34.46,17.46 34.46,25.64 35.33,26.5 35.33,31.08 34.54,31.86 34.54,36.64 29.8,41.38 29.8,50.37 33.48,54.05 33.48,63.56 34.61,64.68 34.79,64.87 34.79,71.45 34.79,71.91 34.44,72.27 34.44,77.91 33.93,78.42 33.93,79.23 34.44,79.74 34.44,81.07 34.06,81.45 v2(34.06,81.49)
  BOTTOM w0.254: PQ4415.6 207.27,28.81 v2(207.03,29.04)
AD+: length 311.2
  TOP w0.508: PR4473.1 193.68,62.39 v2(193.63,62.44)
  L3 w0.508: v2(212.62,29.32) 212.62,28.55 211.6,27.53 210.2,27.53 209.06,28.66 209.06,31.84 208.81,32.09 208.8,32.09 208.3,32.59 208.3,39.4 211.56,42.65 211.56,48.42 211,48.97 211,51.36 209.44,52.92 208.11,52.92 207.86,52.67 204.36,52.67 203.86,53.17 198.52,53.17 196.84,54.85 196.84,60.95 195.35,62.44 v2(193.63,62.44)
  L4 w0.254: v3(23.26,82.51) 24.4,83.65 26.21,83.65 31.74,89.19 31.74,90.94 34.59,93.79 45.77,93.79 46.18,93.37 50.5,93.37 58.82,101.69 63.14,101.69 63.9,102.45 76.46,102.45 77.06,101.86 81.13,101.86 83.03,99.96 87.93,99.96 89.19,101.22 120.15,101.22 123.59,97.79 123.59,95.25 127.82,91.02 135.19,91.02 136.69,89.52 139.52,89.52 144.32,94.32 151.53,94.32 152.8,93.05 152.8,92.16 153.11,91.86 153.59,91.38 154.17,90.79 154.84,90.79 157.64,88 161.03,88 161.95,87.08 161.95,79.72 162.45,79.21 165.88,79.21 166.9,78.19 167.79,78.19 168.17,78.57 170.98,78.57 174.39,81.99 174.39,83.4 178.58,87.59 185.57,87.59 187.85,85.3 187.85,83.66 190.78,80.73 197.51,80.73 v2(197.63,80.86)
  L6 w0.508: v2(193.63,62.44) 193.73,62.55 195.24,62.55 197.66,60.13 202,60.13 203.94,62.08 203.94,67.67 200.71,70.9 199.34,70.9 196.49,73.76 196.49,75.4 195.73,76.16 195.73,78.95 v2(197.63,80.86)
  BOTTOM w0.508: PD4408.1 211.31,27.23 212.62,28.55 v2(212.62,29.32) PD4401.1
  vias: v1(20.59,82.51)
AD_IA: length 62.6
  TOP w0.089: v2(194.33,11.01) 194.97,11.64 v1(194.97,16.34) v2(194.97,17.74) ; R2481.1 148.91,4.94 R2421.1 148.91,5.85 v2(149.73,6.67)
  L6 w0.089: v2(194.33,11.01) 192.98,9.66 181.21,9.66 180.97,9.43 169.8,9.43 168.05,7.68 164.12,7.68 163.92,7.89 160.89,7.89 160.05,7.05 157.21,7.05 156.69,7.57 150.63,7.57 v2(149.73,6.67)
  BOTTOM w0.089: PR4412.2 196.74,21.5 PC4432.1 196.82,21.23 194.97,19.37 v2(194.97,17.74) ; R2483.1 149.68,6.62 v2(149.73,6.67)
AD_OFF_L: length 3.2
  BOTTOM w0.254: v1(13.58,90.33) 14.12,89.8 PQ4304.C 14.35,89.09 PQ4305.1
AD_OFF_R: length 1.9
  BOTTOM w0.254: PQ4305.3 17.39,87.36 v2(18.18,86.57)
  vias: v1(20.72,87.59)
ALERT#: length 2.9
  TOP w0.102: THM261.6 52.43,14.37 v1(52.98,13.82) 53.25,13.55 R2603.2
ALWON: length 16.9
  TOP w0.127: KBC24.121 154.04,8.88 v2(153.94,8.98) ; R4009.2 165.5,8.21 165.99,8.7 v2(165.99,8.98)
  L3 w0.127: v2(153.94,8.98) 153.94,8.67 154.1,8.52 155.9,8.52 156.81,7.61 159.89,7.61 160.5,8.22 165.23,8.22 v2(165.99,8.98)
  BOTTOM w0.127: v2(165.99,8.98) 165.94,8.93 165.94,8.91 v1(165.5,8.47)
AMBER_LED_BAT: length 12.3
  TOP w0.254: R6401.2 56.39,5.8 EC6401.1 v2(56.39,4.41) 56.54,4.26 v1(56.54,3.64)
  BOTTOM w0.254: v2(56.39,4.41) 56.39,2.61 55.27,1.48 50.57,1.48 49.93,2.12 Q6402.C
AUD_AGND: length 43
  TOP w0.203: HDA27.37 21.29,12.11 v2(21.13,11.95) ; HDA27.22 22.5,20 C2734.1
  TOP w0.508: 6.9,1.41 HPMIC1.MS ; HPMIC1.MS 8.2,2.25 ; HPMIC1.MS 5.6,2.25 ; v2(18.03,20.87) 17.83,20.66 EC2709.1 17.37,21.58 R2739.1 17.62,21.83 C2741.2 19.91,22.67 EC2710.1 EC8901.1 21.86,22.67 C2730.2 21.97,21.93 22.09,21.8 v2(22.09,21.3) ; v2(22.09,21.3) C2734.1 ; v2(22.09,21.3) 22.35,21.55 C2740.2 ; C2737.1 C2727.2 21.03,8.7 v2(21.03,7.83) EC2712.1 21.94,8.04 C2749.2 ; EC2713.1 v2(14.4,16.24)
  L3 w0.508: HPMIC1.MS 8.2,2.25 ; HPMIC1.MS 6.9,1.41 ; HPMIC1.MS 5.6,2.25
  L4 w0.508: 5.6,2.25 HPMIC1.MS ; HPMIC1.MS 8.2,2.25 ; HPMIC1.MS 6.9,1.41
  BOTTOM w0.508: v2(18.03,20.87) 17.95,20.94 EC8903.1 ; 18.33,17.16 EC2907.2 EC2908.2 ; 18.33,17.16 v2(19.4,17.16) 19.98,17.16 v1(20.39,16.75) EC8904.1 ; 18.33,17.16 EC2906.2 ; v2(21.03,7.83) 21.1,7.91 21.1,8.62 C2731.1 21.64,8.7 R2747.1 ; EC8902.1 13.72,7.65 v2(13.43,7.94) ; v2(13.23,13.19) 13.33,13.09 R2905.2 ; 6.9,1.41 HPMIC1.MS ; HPMIC1.MS 8.2,2.25 ; HPMIC1.MS 5.6,2.25
  vias: v2(2.31,0.98) v2(3.58,14.31) v2(4.85,1.99) v2(5.56,13.22) v2(9.04,1.99) v2(14.63,15.48)
AUD_HP1_JACK_L: length 3.1
  TOP w0.203: HDA27.27 20.54,16.47 19.96,17.05 19.96,17.28
  TOP w0.254: 19.96,17.28 19.96,17.32 19.83,17.44 19.83,17.68 v1(19.77,17.74) 19.59,17.92 R2907.2
AUD_HP1_JACK_L1: length 9.1
  TOP w0.254: R2907.1 16.33,17.92 v2(16.28,17.87) 15.95,17.54 R2922.2
  BOTTOM w0.254: R2907.1 16.33,17.92 v2(16.28,17.87) 15.9,17.49 15.9,15.45 v1(16.32,15.03) 16.37,14.98 16.37,13.38 R2908.1
AUD_HP1_JACK_R: length 4.4
  TOP w0.203: HDA27.26 20.61,16.87 20.34,17.14 20.34,17.44
  TOP w0.254: 20.34,17.44 v2(20.34,17.92) 19.07,19.19 R2909.2
  BOTTOM w0.254: v2(20.34,17.92) 20.44,17.82 v1(21.08,17.82)
AUD_HP1_JACK_R1: length 16.6
  TOP w0.254: R2909.1 16.9,19.19 v2(16.36,18.65)
  L3 w0.254: v2(13.08,11.85) 13.86,12.64 13.86,16.43 16.09,18.65 v2(16.36,18.65)
  BOTTOM w0.254: v2(16.36,18.65) 16.44,18.73 EC2908.1 18,19.32 v1(18,19.65) ; R2921.2 13.13,11.9 v2(13.08,11.85) 13.08,10.25 R2910.1
AUD_PC_BEEP: length 3
  TOP w0.203: 20.02,13.23 20.13,13.34 20.22,13.34 20.55,13.67 HDA27.34
  TOP w0.254: 20.02,13.23 19.8,13.01 v1(19.8,12.56) 19.07,12.56 R2729.2
AUD_PC_BEEP_C: length 3.1
  TOP w0.254: D2702.3 15.26,13.98 C2726.1 14.42,14.57 v1(13.74,14.57) 13.66,14.64 R2745.1
AUD_PC_BEEP_R: length 4
  TOP w0.254: R2729.1 17.71,12.84 17.61,12.94 16.58,12.94 16.28,13.25 v1(16.28,14.57) 16.15,14.69 C2726.2
AUD_PORTA_L_R_B: length 16.4
  TOP w0.254: ED2903.1 17.62,10.55 v2(17.32,10.86)
  L3 w0.254: HPMIC1.1 12.85,2.25 13.2,2.6 13.2,6.54 14.36,7.7 14.36,9.73 15.49,10.86 v2(17.32,10.86)
  BOTTOM w0.254: v2(17.32,10.86) 17,11.18 16.79,11.18 v1(16.41,11.56) 16.4,11.57 16.4,12.47 R2908.2
AUD_PORTA_R_R_B: length 17.9
  L6 w0.254: v2(15.59,9.97) 15.59,10.12 13.2,12.51 12.34,12.51 11.86,12.99 6.69,12.99 HPMIC1.2
  BOTTOM w0.254: v1(15.51,8.22) 15.51,9.03 R2910.2 15.59,9.61 v2(15.59,9.97) 16.1,9.46 18.03,9.46 18.5,9.93 ED2901.2
AUD_SENSE: length 20.1
  TOP w0.254: v2(12.36,13.3) 12.19,13.47 R2923.2
  L4 w0.254: v2(12.36,13.3) 13.01,12.65 13.9,12.65 16.25,10.3 26.23,10.3 v2(27.96,12.03)
  BOTTOM w0.254: R2741.2 28.39,12.03 v2(27.96,12.03) ; v1(12.8,13.74) v2(12.36,13.3)
AUD_SENSE_A: length 5.4
  TOP w0.254: v1(28.57,12.28) 28.19,12.66 v2(27.96,12.66) 27.45,12.66 26.9,12.11 HDA27.48
  BOTTOM w0.254: v2(27.96,12.66) 28.16,12.66 R2741.1 28.39,13.3 C2746.1 27.91,13.55 R2742.2
AUD_SPK_L+: length 1.7
  TOP w0.203: 23.69,10.36 23.69,10.88 23.7,10.89 HDA27.42
  vias: v1(25.13,6.07)
AUD_SPK_L+_C: length 8.1
  TOP w0.305: AFTP2902.1 36.85,3.52 v3(36.47,3.9)
  TOP w0.508: R2912.1 36.34,3.77 v3(36.47,3.9)
  L4 w1.016: v3(36.47,3.9) 34.33,3.9 32.59,5.63 v3(32.59,7.09)
AUD_SPK_L-: length 1.9
  TOP w0.203: 24.48,10.39 24.1,10.77 HDA27.43
  vias: v1(24.86,8.29)
AUD_SPK_L-_C: length 7.8
  TOP w0.305: AFTP2901.1 35.69,6.95 v3(35.58,6.84)
  TOP w0.508: R2913.1 v3(35.58,6.84)
  L4 w1.016: v3(35.58,6.84) 34.01,8.4 32.08,8.4 31.26,7.58 v3(31.26,7.2)
AUD_SPK_R+: length 1
  TOP w0.203: HDA27.45 24.9,11.14 24.94,11.1
  vias: v1(27.45,9.99)
AUD_SPK_R+_C:
  vias: v3(29.36,11.14)
AUD_SPK_R-: length 2.7
  TOP w0.203: 25.48,9.86 24.5,10.84 HDA27.44
  vias: v1(26.23,8.88)
AUD_SPK_R-_C:
  vias: v3(32.66,11.24)
AUD_VREF: length 4
  TOP w0.203: HDA27.38 22.1,11.79 21.82,11.52 21.41,11.52 21.2,11.31
  TOP w0.254: C2737.2 19.58,10.79 v1(19.96,11.17) 20.2,11.17 20.35,11.02 20.92,11.02 21.2,11.31
AUDIO_47: length 7.4
  TOP w0.089: HDA27.47 25.7,11.88 26.28,11.29 v1(27.15,11.29) 27.38,11.52 28.44,11.52 29.84,12.91 30.63,12.91 v2(31.01,12.53)
  BOTTOM w0.089: R2744.1 30.88,12.66 v2(31.01,12.53)
AUX_EN_WOWL: length 269.7
  TOP w0.089: v2(171.95,7.75) v1(171.95,10.25) 171.95,15.08 167.38,19.66 167.38,23.97 164.17,27.18 154.45,27.18 R2409.1 ; v2(94,9.1) 94,9.99 93.37,10.63 93.37,11.05 94.64,12.32 94.64,14.24 91.31,17.56 91.31,20.13 92.53,21.35 v2(92.53,21.55)
  L3 w0.089: v2(94,9.1) 102.74,9.1 104.33,10.69 107.15,10.69 107.81,10.04 109.02,10.04 110.12,11.14 110.12,12.24 110.59,12.71 115.29,12.71 115.65,12.35 125.42,12.35 125.45,12.32 127.35,10.42 136.49,10.42 136.75,10.67 139.59,10.67 140.1,10.17 140.1,8.98 141.11,7.97 148.26,7.97 148.72,8.43 153.32,8.43 153.54,8.21 155.44,8.21 155.71,7.94 156.41,7.24 159.85,7.24 160.37,7.75 167.69,7.75 168.27,7.17 171.38,7.17 v2(171.95,7.75)
  L6 w0.089: v2(171.95,7.75) 172.34,8.14 194.18,8.14 196.92,10.88 202.79,10.88 205.11,13.21 212.89,13.21 215.83,16.14 216.96,16.14 219.98,19.15 219.98,22.09 221.15,23.27 221.15,26.3 219.65,27.8 219.65,30.49 219.53,30.61 219.53,32.42 218.51,33.44 218.51,35.19 218.97,35.65 218.97,41.16 217.52,42.6 217.52,43.7 217.49,43.73 217.49,47.08 v2(217.93,47.51)
  BOTTOM w0.089: v2(217.93,47.51) 217.87,47.46 215.54,47.46 211.73,51.27 211.73,54.45 209.83,56.35 206.17,56.35 206.12,56.4 IOBD1.50 ; v2(92.53,21.55) 92.53,21.58 92.73,21.78 92.73,24.09 91.26,25.56 91.26,30.7 93.23,32.67 93.23,36.8 98.93,42.51 99.79,42.51 100.22,42.94 100.22,43.05 101.15,43.97 101.49,43.97 101.51,43.95 103.95,43.95 104.76,44.76 105.78,44.76 105.91,44.63 CPU1.BB17
AUX_EN_WOWL_EC: length 2.9
  TOP w0.089: R2409.2 154.05,25.92 v1(154.05,24.78) 154.05,24.45 153.64,24.05 KBC24.41
AUX_MODE: length 3.1
  TOP w0.203: HDA27.33 20.48,14.07 20.21,13.8 19.74,13.8 v1(19.71,13.84)
  TOP w0.254: v1(19.71,13.84) 19.49,13.63 R2754.2
  TOP w0.508: R2754.2 R2753.2
AUX_ON: length 109.9
  TOP w0.089: KBC24.3 156.42,10.18 v2(155.34,11.26)
  L6 w0.089: v2(212.87,48.86) 213.79,47.94 213.79,45.36 213.71,45.28 213.71,39.92 212.97,39.18 212.97,33.96 213.35,33.57 213.35,30.98 214.45,29.89 214.45,21.47 210.77,17.79 205.91,17.79 205.66,18.04 197.16,18.04 194.64,15.53 189.51,15.53 187.86,17.18 181.02,17.18 177.43,13.59 170.34,13.59 169.51,12.76 158.17,12.76 157.18,11.77 155.77,11.77 155.34,11.34 v2(155.34,11.26)
  BOTTOM w0.089: IOBD1.49 206.24,56 206.27,56.03 209.86,56.03 211.48,54.42 211.48,51.01 v1(212.52,49.97) 212.87,49.62 v2(212.87,48.86)
B71_TP: length 6
  BOTTOM w0.089: TP2312.1 127.66,79.59 127.66,78.11 CPU1.B71
BA1_TP: length 4.2
  TOP w0.089: TP2305.1 104.78,34.53 v2(105.05,34.8)
  BOTTOM w0.089: v2(105.05,34.8) 108.47,34.8 CPU1.BA1
BA2_TP: length 4.9
  TOP w0.089: TP2306.1 105.02,35.75 v2(105.51,35.26)
  BOTTOM w0.089: v2(105.51,35.26) 106.2,35.95 107.13,35.95 107.22,36.03 107.63,36.03 107.96,35.7 108.35,35.7 108.53,35.51 CPU1.BA2
BA71_TP: length 5.5
  TOP w0.089: v2(107.17,76.95) 107.17,76.65 107.66,76.16 107.96,76.16 108.88,75.24 TP2303.1
  BOTTOM w0.089: CPU1.BA71 108.3,75.76 108.3,75.81 108.29,75.83 108.29,75.84 108.09,76.04 108.08,76.04 108.07,76.05 107.63,76.05 107.37,76.32 107.37,76.73 107.17,76.93 v2(107.17,76.95)
BAT1_LED#: length 22.8
  TOP w0.089: v2(165.88,10.82) 165.76,10.82 165.31,11.27 Q2416.4 ; v2(147.98,9.1) 148.04,9.04 KBC24.106
  L3 w0.089: v2(147.98,9.1) 149.29,10.42 159.84,10.42 159.89,10.37 165.44,10.37 v2(165.88,10.82)
  BOTTOM w0.089: RN2405.1 165.02,11.68 v2(165.88,10.82) v1(165.88,10.12)
BAT2_LED#: length 18.6
  TOP w0.089: v2(163.72,13.42) 163.66,13.36 Q2416.1 ; v2(153.89,11.35) 155.86,9.38 KBC24.1
  L6 w0.089: v2(153.89,11.35) 153.94,11.35 154.64,12.05 157.12,12.05 158.02,12.95 163.25,12.95 v2(163.72,13.42)
  BOTTOM w0.089: v2(163.72,13.42) 163.72,12.76 v1(164.08,12.4) RN2405.2
BAT_AMBER: length 4.4
  TOP w0.254: R6401.1 56.6,7.67 ED6401.1 56.89,8.78 56.7,8.97 v2(56.7,8.98) 57.04,9.32 v1(57.04,9.61)
  BOTTOM w0.254: LEDCN1.2 v2(56.7,8.98)
BAT_WHITE: length 4.4
  TOP w0.254: R6402.1 55.71,7.8 ED6402.1 55.9,8.32 v2(55.9,8.98) 55.79,9.09 v1(55.79,9.62)
  BOTTOM w0.254: v2(55.9,8.98) 55.7,9.18 LEDCN1.3
BATT_WHITE_LED#: length 130.7
  TOP w0.089: Q2416.6 164.98,12.8 v2(164.36,13.42) ; v2(48.92,2.75) v1(48.92,3.39) 49.31,3.79 49.31,4.46 50.03,5.17 50.69,5.17 51,5.47 R6404.1
  L3 w0.089: v2(134.01,13.8) 134.59,14.38 135.16,14.38 136.94,16.15 142.64,16.15 143.34,15.45 149.11,15.45 149.88,14.68 158.87,14.68 159.12,14.44 163.34,14.44 v2(164.36,13.42)
  L4 w0.089: v2(134.01,13.8) 133.78,13.8 133.29,13.32 133.29,11.97 132,10.67 120.97,10.67 120.67,10.37 120.67,10.12 120.42,9.87 110.51,9.87 108.37,7.73 96.69,7.73 94.68,9.74 92.44,9.74 91.81,9.1 88.63,9.1 88.35,8.83 83.93,8.83 82.68,7.57 82.68,7.3 81.54,6.16 73.03,6.16 71.78,4.91 64.91,4.91 63.71,3.71 51.26,3.71 50.31,2.75 v2(48.92,2.75)
BATT_WHITE_LED_R#: length 4.6
  TOP w0.089: v2(49.47,6.1) 49.51,6.1 49.55,6.06 R6404.2 50.19,6.11 v1(50.19,6.95)
  BOTTOM w0.089: Q6401.B 48.03,8.01 Q6105.D 49.47,6.57 v2(49.47,6.1)
BB67_TP: length 2.1
  TOP w0.089: TP2302.1 107.06,73.28 v2(107.11,73.28)
  BOTTOM w0.089: CPU1.BB67 108.04,73.1 107.83,73.31 107.16,73.31 107.13,73.28 v2(107.11,73.28)
BB70_TP: length 2
  TOP w0.089: v2(107.26,75.85) 107.03,75.62 TP2301.1
  BOTTOM w0.089: v2(107.26,75.85) 107.31,75.8 107.31,75.66 107.92,75.05 CPU1.BB70
BEEP: length 160.3
  TOP w0.203: v2(152.39,21.88) 152.24,22.03 152.24,22.07 152.04,22.28 KBC24.45
  TOP w0.254: RN2702.1 14.17,9.18 13.2,9.18 12.77,8.75 12.77,7.12 13.61,6.29 14.8,6.29 v2(14.83,6.31)
  L6 w0.254: v2(14.83,6.31) 14.9,6.31 15.29,6.69 16.15,6.69 16.73,7.27 16.76,7.27 16.98,7.5 19.93,7.5 20.13,7.3 20.37,7.3 24.53,3.14 38.88,3.14 38.92,3.1 39.2,2.82 45.56,2.82 46.2,2.18 47.72,2.18 47.72,2.18 50.03,2.18 50.05,2.16 54.56,2.16 55.29,2.89 64.02,2.89 65.51,1.4 72.64,1.4 76.16,4.91 80.11,4.91 82.55,7.36 82.55,8.01 83.05,8.51 83.84,8.51 85.29,9.95 86.97,9.95 88.31,11.29 95,11.29 97.62,13.91 98.56,13.91 99.89,13.91 102.97,16.99 104.03,16.99 104.31,17.26 107.52,17.26 107.65,17.13 110.21,17.13 111.19,18.11 113.5,18.11 114.04,17.57 123.38,17.57 124.07,18.26 124.82,18.26 125.15,18.58 125.15,19.87 127.15,21.87 133.87,21.87 135.03,23.03 137.31,23.03 137.71,22.63 151.72,22.63 152.27,22.09 152.27,22.01 v2(152.39,21.88)
  BOTTOM w0.254: v2(152.39,21.88) 152.39,22.06 v1(152.7,22.36)
BKLT_CTRL: length 10
  BOTTOM w0.114: R5502.1 88.8,92.75 D5502.3 91.95,89.6 RN5502.5 92.53,90.69 v1(93.83,91.99) 94.33,92.49 RN5501.5
BKLT_IN_EC: length 3.8
  TOP w0.089: KBC24.67 142.43,20.98 142.21,21.21 142.21,21.27 R2435.1 141.17,23.2 v1(140.84,23.53)
BLON_OUT_C: length 23.9
  L3 w0.089: v2(94.74,95.36) 90.32,90.94 v2(90.32,90.13)
  BOTTOM w0.089: v2(94.74,95.36) 94.38,95.36 93.66,94.64 93.33,94.64 93.24,94.55 RN5501.2 93.24,93.96 93.52,93.69 95.35,93.69 95.72,93.31 96.84,93.31 98.07,94.55 100.89,94.55 101.35,95.01 LCD1.23 ; RN5502.6 93.11,89.25 92.98,89.11 91.74,89.11 v1(91.49,88.86) 90.32,90.03 v2(90.32,90.13)
BLUETOOTH_EN: length 177.8
  TOP w0.089: v2(138.45,5.17) 138.45,5.67 137.69,6.43 137.69,8.31 137.14,8.86 137.14,9.16 136.29,10.01 136.29,10.51 135.26,11.54 134.63,12.18 134.63,14.26 134.12,14.76 130.58,14.76 130.12,15.22 130.12,19.36 127.93,21.55 127.45,21.55 126.94,22.05 121.56,27.44 121.56,29.04 v1(121.52,29.09) v2(120.8,29.81)
  L6 w0.089: v2(215.72,51.19) 216.68,50.24 216.68,43.39 216.69,43.38 216.71,43.13 216.71,42.27 217.27,41.71 217.32,41.65 217.32,39.48 217.69,39.11 217.69,32.93 217.67,32.9 217.67,31.32 218.84,30.15 218.84,27.46 218.97,27.34 218.97,21.28 212.19,14.5 204.57,14.5 204.39,14.32 201.1,14.32 200.79,14.01 199.62,14.01 197.78,12.18 194.89,12.18 193.9,11.19 193.9,10.98 192.78,9.87 181.12,9.87 180.89,9.63 169.7,9.63 167.95,7.89 164.21,7.89 164.01,8.09 160.8,8.09 160.09,7.38 157.17,7.38 156.71,7.83 150.39,7.83 149.65,7.09 149.55,7.09 148.71,6.25 145.41,6.25 144.47,5.31 140.5,5.31 139.75,6.06 138.78,6.06 138.45,5.73 v2(138.45,5.17)
  BOTTOM w0.089: v2(120.8,29.81) 120.1,29.81 R2042.2 119.73,30.18 119.73,32.4 119.31,32.82 119.31,34.5 119.47,34.67 119.51,34.8 119.51,34.97 119.46,35.16 119.46,35.32 CPU1.AB2 ; v2(215.72,51.19) 216.16,51.62 216.16,53.57 215.92,53.81 215.92,55.33 212.8,58.45 207.39,58.45 206.9,58.94 206.19,58.94 206.05,58.8 IOBD1.56
BOARD_ID: length 8.9
  TOP w0.089: R2444.1 149.85,1.69 C2408.2 150.64,1.66 R2494.2 v1(151.61,2.63) 151.61,2.88 151.35,3.14 151.35,3.78 R2443.2 150.52,4.61 150.52,5.29 150.21,5.6 150.21,6.9 150.04,7.06 KBC24.111
BOARD_ID1: length 7.2
  BOTTOM w0.089: R2010.2 117.24,29.88 R2009.1 117.24,30.59 117.45,30.8 117.72,30.8 118.11,31.19 v1(118.11,31.71) 118.11,32.09 118.56,32.55 118.56,35.19 CPU1.AC1
BOARD_ID2: length 8.9
  TOP w0.089: R2051.1 120.04,35 120.37,34.67 120.85,34.19 v1(120.85,33.87) 120.85,33.34 R2052.2 119.76,32.24 v2(118.99,32.24)
  BOTTOM w0.089: v2(118.99,32.24) 118.89,32.35 118.89,35.59 119.25,35.95 CPU1.AB3
BOT_MUX_N: length 6.6
  TOP w0.102: v1(8.96,93.26) 9.08,93.37 ; 9.08,93.37 8.67,93.78 8.2,93.78 7.81,93.4 6.61,93.4 USB1.B7 ; 9.08,93.37 9.44,93.01 9.44,92.73 9.55,92.63 9.9,92.63 10.13,92.86 ED3805.1 10.14,92.97 EL3802.2
BOT_MUX_N_L: length 73.6
  TOP w0.102: v2(13.05,93.16) 12.85,92.97 EL3802.1 ; U3802.9 36.75,43.16 36.83,43.07 37.28,43.07 ; 37.28,43.07 37.83,43.07 v2(38.11,43.36) ; 37.28,43.07 v1(37.28,43.24)
  L4 w0.14: v2(13.05,93.16) 13.31,93.42 14.37,93.42 15.25,92.54 15.25,91.67 20.87,86.05 20.87,81.89 25.12,77.64 26.54,77.64 29.34,74.83 29.34,71.68 34.78,66.25 34.78,64.77 35.41,64.14 35.41,62.91 34.44,61.93 34.44,54.06 31.38,51 31.38,46.67 33.52,44.53 38.77,44.53 39.25,44.04 39.25,43.25 39.14,43.14 38.33,43.14 v2(38.11,43.36)
BOT_MUX_P: length 6.2
  TOP w0.102: EL3802.3 10.77,93.65 10.43,93.31 9.97,93.31 9.72,93.05 9.72,93.05 ; 9.72,93.05 8.77,94.01 8.1,94.01 7.98,93.88 ; 9.72,93.05 ED3805.2 ; USB1.B6 6.39,93.5 6.52,93.62 7.72,93.62 7.98,93.88 ; 7.98,93.88 v1(7.87,93.99)
BOT_MUX_P_L: length 74.4
  TOP w0.102: EL3802.4 12.8,93.65 v2(13.04,93.89) ; U3802.8 36.75,42.76 36.83,42.85 37.83,42.85 v2(38.11,42.57)
  L4 w0.14: v2(38.11,42.57) 38.42,42.87 39.25,42.87 39.52,43.14 39.52,44.15 38.88,44.79 33.63,44.79 31.64,46.78 31.64,50.89 34.7,53.95 34.7,61.82 35.68,62.8 35.68,64.25 35.05,64.88 35.05,66.36 29.61,71.79 29.61,74.94 26.65,77.9 25.23,77.9 21.13,82 21.13,86.16 15.51,91.78 15.51,92.65 14.48,93.69 13.25,93.69 v2(13.04,93.89)
BREATH_LED#: length 109.5
  TOP w0.089: KBC24.70 143.78,19.78 143.91,19.65 144.19,19.65 v2(144.67,20.13)
  L6 w0.089: v2(144.67,20.13) 144.67,20.41 144.93,20.66 145.94,20.66 146.4,20.2 157.2,20.2 157.5,20.51 164.74,20.51 165.17,20.08 173.53,20.08 174.98,21.53 178.02,21.53 178.02,21.53 185.02,21.53 185.02,21.53 185.38,21.53 185.38,21.53 189.55,21.53 190.39,22.36 198.09,22.36 198.77,21.68 205.16,21.68 206.97,23.5 206.97,25.79 208.31,27.13 208.31,30.15 207.67,30.8 207.67,33.49 208.25,34.07 208.25,35.37 208.99,36.11 210.28,36.11 211.04,36.87 211.04,40.02 210.66,40.4 210.66,45.38 210.92,45.63 210.92,55.97 210.26,56.63 207.52,56.63 v2(207.21,56.93)
  BOTTOM w0.089: v2(144.67,20.13) 144.65,20.16 v1(144.65,20.69) ; v2(207.21,56.93) 206.83,56.55 206.26,56.55 206.01,56.8 IOBD1.51
BT+: length 14.5
  L3 w0.508: v2(179.34,21.09) 180.82,22.57 190.39,22.57 v2(191.79,23.96)
  BOTTOM w0.508: PR4478.2 v2(191.79,23.96)
  vias: v2(177.84,21.11) v2(178.58,21.09)
C1_TP: length 7.1
  BOTTOM w0.089: CPU1.C1 131.7,34.89 132.86,33.73 132.86,33.18 133.41,32.63 134.28,32.63 134.64,32.98 TP2308.1
CAD_SNK: length 2.3
  TOP w0.089: R3818.2 34.03,60.16 v1(34.16,60.03) 34.56,60.03 34.79,59.81 U3801.29
CAP_LED: length 123.2
  TOP w0.254: AFTP6541.1 92.65,9.28 v2(92.65,9.1)
  L3 w0.254: v2(92.65,9.1) 92.65,9.16 93.11,9.61 102.86,9.61 104.22,10.97 107.27,10.97 107.92,10.31 108.91,10.31 109.85,11.26 109.85,12.35 110.47,12.98 115.78,12.98 116.14,12.62 125.53,12.62 125.56,12.6 125.62,12.54 127.46,10.69 136.38,10.69 136.67,10.98 140.2,10.98 140.74,11.52 142.01,11.52 143.78,9.74 146.4,9.74 147.54,8.6 148.23,8.6 149.78,10.15 159.05,10.15 159.18,10.02 166.75,10.02 167.15,10.43 v2(167.15,10.81)
  BOTTOM w0.254: v2(92.65,9.1) 91.38,9.1 91.38,9.1 89.51,9.1 89.51,9.1 89.02,9.1 87.24,10.88 86.25,10.88 86.02,11.12 KB1.4 ; R6513.2 150.13,26 150.68,26.55 153.18,26.55 153.86,25.87 164.86,25.87 165.88,24.85 165.88,15.12 167.28,13.72 167.28,10.93 v2(167.15,10.81)
CAP_LED#: length 19.1
  TOP w0.089: KBC24.93 142.44,10.58 142.16,10.87 v2(141.63,10.87)
  BOTTOM w0.089: R2489.1 140.11,23.14 Q2414.S 141.14,22.55 141.14,20.87 138.07,17.8 v1(138.07,13.17) 138.7,12.53 140.61,12.53 141.63,11.52 v2(141.63,10.87)
CAP_LED#_R: length 2.2
  BOTTOM w0.254: R6512.1 143.99,22.46 v1(143.71,22.18) 143.71,22.19 Q2414.D
CAP_LED_Q: length 4.5
  BOTTOM w0.254: v1(147.98,26.94) 147.98,26.43 R6513.1 146.78,26 EC6507.1 144.62,25.92 Q6505.C
CAP_LED_R#: length 2.3
  BOTTOM w0.089: R6512.2 144.94,23.11 v1(145.77,23.11) 145.77,23.69 Q6505.B
CBN: length 5
  TOP w0.203: HDA27.24 21.7,18.54 21.36,18.88 21.1,18.88
  TOP w0.254: C2739.1 19.96,21.07 19.96,20.03 21.1,18.88
CBP: length 3.3
  TOP w0.203: HDA27.23 22.1,19.03 21.93,19.2 21.55,19.2 v1(21.36,19.39)
  TOP w0.254: v1(21.36,19.39) 20.72,20.03 C2739.2
CCG4_FLIP#: length 35
  TOP w0.089: v1(34.82,48.09) v2(34.82,47.46) ; v2(34.82,47.46) 35.25,47.46 R3856.1 ; v2(34.82,47.46) 34.39,47.46 R3855.1 ; v2(35.07,32.47) U3701.5
  L4 w0.089: v2(35.07,32.47) 35.45,32.09 38.4,32.09 38.76,32.45 43.33,32.45 43.97,31.82 45.03,31.82 45.28,32.07 45.28,37.46 42.25,40.49 42.25,42.13 38.57,45.81 36.47,45.81 v2(34.82,47.46)
CCG4_GPIO21: length 1.6
  TOP w0.089: TP3701.1 32.57,25.48 U3701.21
CCG4_I2C_INT#: length 160
  TOP w0.089: v2(159.28,21.81) 159.25,21.78 KBC24.32 ; R3731.1 28.23,29.42 v2(28.15,29.5) 27.88,29.77 v1(27.88,30.06)
  L3 w0.089: v2(28.15,29.5) 28.61,29.04 31.14,29.04 32.48,27.7 32.48,25.1 34.22,23.37 35.97,23.37 37.49,21.85 37.49,20.95 36.04,19.5 36.04,14.14 37.77,12.41 38.88,12.41 46.13,5.16 50.29,5.16 50.47,5.33 57.71,5.33 58.07,4.97 61.36,4.97 61.79,5.41 77.09,5.41 80.85,9.16 83.34,9.16 85.27,11.09 87.45,11.09 88.02,11.66 94.22,11.66 95.75,13.19 106.75,13.19 107.84,14.29 122.24,14.29 122.61,13.91 126.38,13.91 132.49,20.03 136.36,20.03 137.68,21.35 146.12,21.35 146.77,20.69 158.16,20.69 v2(159.28,21.81)
CCG4_I2C_SCL: length 147
  TOP w0.089: Q2417.6 143.44,2.43 143.8,2.08 143.8,1.81 143.89,1.73 143.89,1.43 v1(143.78,1.33) 143.57,1.54 143.57,1.66 143.33,1.91 142.94,1.91 v2(142.51,1.48) ; U3701.17 31.15,28.04 v2(30.82,27.71) 30.29,27.18 RN3702.3
  L3 w0.127: v2(30.82,27.71) 30.82,21.23 34.56,17.49 34.56,14.51 39.43,9.65 39.43,9.56 39.43,9.55 39.43,4.24 40.68,2.99 44.91,2.99 45.8,2.1 49.21,2.1 50.95,3.83 54.46,3.83 54.5,3.8 54.51,3.8 55.8,2.5 58.94,2.5 59.58,3.14 64.38,3.14 64.76,3.52 68.12,3.52 69.14,2.5 75.17,2.5 75.97,3.3 78.94,3.3 79.49,2.75 83.49,2.75 84.04,2.21 100.8,2.21 100.8,2.21 101.12,2.21 105.71,6.8 110.38,6.8 112.13,8.54 115.1,8.54 116.26,7.39 116.58,7.39 124.17,7.39 125.12,6.44 128.78,6.44 129.3,6.95 131.53,6.95 133.05,5.43 133.05,3.61 133.97,2.69 141.82,2.69 142.51,1.99 v2(142.51,1.48)
CCG4_I2C_SDA: length 148.4
  TOP w0.089: v1(142.11,5.85) 142.11,4.45 Q2417.3 142.14,3.68 142.47,3.36 142.47,2.07 v2(141.88,1.48) ; RN3702.4 30.2,27.85 v2(30.75,28.41) 30.89,28.54 U3701.16
  L3 w0.127: v2(30.75,28.41) 30.37,28.03 30.37,18.07 38.82,9.62 38.82,3.48 39.69,2.61 44.75,2.61 45.64,1.71 49.37,1.71 51.1,3.45 54.31,3.45 55.65,2.12 59.1,2.12 59.74,2.75 64.54,2.75 64.92,3.14 67.97,3.14 68.98,2.12 75.33,2.12 76.13,2.92 78.78,2.92 79.33,2.37 83.34,2.37 83.88,1.83 100.64,1.83 100.96,1.83 101.28,1.83 105.87,6.42 110.54,6.42 112.28,8.16 114.95,8.16 116.1,7.01 116.74,7.01 123.55,7.01 128.11,2.45 128.94,1.61 132.58,1.61 133.28,2.31 141.31,2.31 141.88,1.74 v2(141.88,1.48)
CCG4_ID_1: length 3
  TOP w0.089: U3701.25 34.57,24.77 v1(34.64,24.7) 34.64,23.84 R3709.1 34.06,23.76 R3708.2
CCG4_ID_2: length 3.5
  TOP w0.089: U3701.27 35.57,25.34 35.62,25.28 35.62,24.58 v1(35.91,24.29) 36.09,24.12 R3742.2 R3741.1
CCG4_OVP_TRIP_P1: length 73
  TOP w0.089: v2(30.75,29.68) 30.88,29.68 31.02,29.54 U3701.14 ; PQ4311.2 36.85,77.68 36.72,77.81 36.11,77.81 35.73,78.19 v1(35.2,78.19) 35.2,77.76 v2(35.63,77.33) 35.63,76.95 35.38,76.69 PR4341.2
  L4 w0.089: v2(30.75,29.68) 30.75,31.68 31.09,32.01 33.69,32.01 33.8,31.9 38.48,31.9 38.84,32.26 43.16,32.26 43.8,31.63 45.11,31.63 45.47,31.99 45.47,37.56 42.45,40.58 42.45,42.37 39.9,44.92 39.9,47.33 39.39,47.84 39.39,60.16 38.88,60.67 38.88,62.98 38.69,63.17 38.69,72.89 35.63,75.95 v2(35.63,77.33)
CCG4_OVP_TRIP_P1_G: length 3.8
  TOP w0.089: PQ4309.2 35.33,74.76 35.2,74.64 PR4340.1 35,75.25 35.02,75.27 PC4313.2 35.02,75.45 34.51,75.96 PR4341.1 34.51,76.93 v1(34.63,77.05)
CFG3: length 9.4
  BOTTOM w0.114: R604.1 v1(124.73,78.5) 125.28,78.5 125.68,78.1 125.68,77.81 127.43,76.06 127.43,74.71 127.42,74.7 127.42,73.64 127.6,73.46 128.96,73.46 129.32,73.1 CPU1.D67
CFG4: length 5.8
  BOTTOM w0.089: CPU1.E70 128.41,74.9 127.91,75.4 127.91,76.34 v1(126.44,77.81) 126.44,78.47 R605.1
CFG_RCOMP: length 0.6
  BOTTOM w0.305: v2(127.62,69.12) 127.62,69.01 CPU1.E60
  vias: v1(127.25,68.62)
CHG_AMBER_LED#: length 126.2
  TOP w0.089: Q2416.3 164.37,11.5 165.06,10.82 v2(165.15,10.82) ; R6403.1 v2(48.66,4.33) 48.71,4.38 v1(48.71,4.91)
  L3 w0.089: v2(165.15,10.82) 160.1,10.82 158.62,12.31 158.13,12.79 140.66,12.79 139.7,11.83 136.32,11.83 136.04,11.55 128.9,11.55 126.99,13.47 116.98,13.47 116.6,13.84 108.41,13.84 107.32,12.75 95.93,12.75 94.4,11.22 88.2,11.22 87.63,10.65 85.46,10.65 83.28,8.47 82.24,8.47 78.73,4.96 61.98,4.96 61.54,4.53 57.89,4.53 57.53,4.89 50.68,4.89 50.5,4.7 49.04,4.7 v2(48.66,4.33)
CHG_AMBER_LED_R#: length 2.5
  TOP w0.254: R6403.2 47.95,3.47 48.28,3.14 v2(48.28,2.77) 48.15,2.64 v1(48.15,2.23)
  BOTTOM w0.254: v2(48.28,2.77) 48.28,2.75 47.9,2.37 Q6402.B
CLK_PCIE_LAN_REQ#: length 222.4
  TOP w0.089: v2(106.99,36.69) v1(106.19,37.49) 105.87,37.81 99.59,37.81 99.11,38.29 RN1813.6 ; v2(136.67,1.48) 135.6,2.56 135.6,6.56 132.58,9.59 128.29,9.59 126.09,11.79 126.09,15.27 125.11,16.24 121.89,16.24 120.01,16.24 117.33,18.92 116.9,18.92 114.55,21.27 113.51,21.27 111.63,23.15 111.63,28.05 110.26,29.42 v2(110.26,29.68)
  L4 w0.089: v2(112.16,39.84) 111.77,40.24 111.36,40.24 111.26,40.14 110.5,40.14 110.26,39.9 110.26,39.18 110.04,38.96 110.04,38.11 110.95,37.2 110.95,36.54 109.88,35.46 109.88,32.98 110.42,32.43 110.42,30.02 110.26,29.85 v2(110.26,29.68)
  L6 w0.089: v2(112.16,39.84) 112.16,39.84 111.65,39.32 110.5,39.32 107.84,36.66 107.02,36.66 v2(106.99,36.69) ; v2(136.67,1.48) 136.83,1.48 137.51,2.16 138.08,2.16 140.45,4.53 144.86,4.53 145.5,5.17 147.81,5.17 148.06,5.42 149.21,5.42 149.39,5.24 156.54,5.24 156.85,5.56 162.17,5.56 162.71,6.11 167.91,6.11 168.7,5.33 171.05,5.33 173.38,7.65 194.45,7.65 197.2,10.4 203.04,10.4 205.35,12.71 212.93,12.71 215.99,15.76 217.27,15.76 220.36,18.85 220.36,21.94 221.81,23.39 221.81,28.95 221.43,29.33 221.43,29.39 220.01,30.81 220.01,32.62 219.32,33.31 219.32,35.32 219.45,35.45 219.45,42.48 218.64,43.29 218.64,47.44 218.61,47.47 218.61,50.13 v2(217.93,50.81)
  BOTTOM w0.089: v2(217.93,50.81) 218.38,51.27 218.38,53.76 217.7,54.44 217.7,58.13 216.81,59.02 209.82,59.02 209.13,59.7 207.1,59.7 206.81,60 IOBD1.59 ; CPU1.AT8 111.85,39.53 v2(112.16,39.84)
CLK_PCIE_NVME_REQ#: length 160.3
  TOP w0.089: RN1812.6 98.94,40.68 100.73,38.89 v1(102.66,38.89) 102.94,38.62 106.37,38.62 107.32,39.57 109.94,39.57 110.5,40.13 110.83,40.13 111.13,39.83 v2(111.53,39.83)
  L4 w0.089: v2(111.53,39.83) 111.39,39.83 110.68,39.12 110.48,39.12 110.24,38.88 110.24,38.18 111.13,37.29 111.13,34.76 111.42,34.47 111.42,31.94 110.68,31.2 110.68,28.68 110.21,28.21 110.21,27.85 112.83,25.23 114.45,25.23 115.72,23.96 115.72,19.34 118.88,16.18 125.71,16.18 126.59,17.06 133.2,17.06 133.67,17.53 135.4,17.53 137.99,14.94 137.99,13.28 140.83,10.44 142,10.44 143.89,8.55 146.97,8.55 147.24,8.28 155.78,8.28 156.68,7.38 164.19,7.38 164.81,6.76 172.78,6.76 173.55,5.98 175.71,5.98 176.42,6.69 185.67,6.69 186.73,5.62 193.67,5.62 196.45,8.39 204.92,8.39 205.76,9.23 214.85,9.23 219.93,14.31 v2(221.31,14.31)
  BOTTOM w0.089: CPU1.AU8 111.2,39.5 v2(111.53,39.83) ; SSD1.52 221.98,14.9 221.39,14.31 v2(221.31,14.31)
CLK_PCIE_PEG_REQ#: length 289.4
  TOP w0.089: RN1812.7 98.92,41.18 100.86,39.25 103.58,39.25 104.03,38.8 106.3,38.8 107.47,39.97 v1(109.11,39.97) 109.9,39.97 110.26,40.32 111.75,40.32 v2(112.18,40.75) ; v2(109.97,30.25) 109.97,30.16 109.82,30.01 109.82,29.45 111.32,27.95 111.32,23.17 113.47,21.02 114.5,21.02 116.81,18.71 117.23,18.71 119.94,16 125.08,16 125.9,15.19 125.9,11.71 128.21,9.4 132.5,9.4 135.41,6.49 135.41,2.11 v2(136.04,1.48)
  L3 w0.089: v2(160.12,67.04) 160.68,67.61 165.07,67.61 165.45,67.99 168.97,67.99 169.66,67.3 170.25,67.3 170.41,67.14 171.54,67.14 173.49,65.19 176.73,65.19 177.57,66.03 177.57,67.4 179.13,68.97 179.64,68.97 180.36,69.68 182.9,69.68 183.9,68.68 184.28,68.68 184.98,69.38 189.43,69.38 190.34,70.29 190.34,71.37 189.1,72.61 189.1,73.46 189.41,73.77 197.25,73.77 197.58,74.1 197.58,74.43 197.83,74.69 198.84,74.69 200.67,72.86 205.67,72.86 210.9,67.63 210.9,66.1 213.3,63.69 213.3,60.55 214.46,59.39 214.46,57.3 215.46,56.3 215.46,53.88 215.29,53.71 215.29,50.99 v2(215.72,50.56)
  L4 w0.089: v2(109.97,30.25) 109.97,32.25 109.47,32.76 109.47,35.67 109.33,35.8 109.33,40.62 109.57,40.85 109.9,40.85 110.19,40.57 110.78,40.57 111.12,40.91 111.12,40.92 111.36,41.15 111.77,41.15 v2(112.18,40.75)
  L6 w0.089: v2(215.72,50.56) 216.48,49.8 216.48,43.3 216.5,43.29 216.5,43.13 216.5,42.18 216.9,41.79 216.99,41.68 216.99,38.7 217.49,38.2 217.49,33.01 217.47,32.99 217.47,31.23 218.64,30.07 218.64,27.38 218.76,27.25 218.76,21.37 212.1,14.71 204.49,14.71 204.3,14.52 201.01,14.52 200.71,14.22 198.61,14.22 198.17,13.78 197.22,13.78 195.85,12.41 191.9,12.41 190.96,11.47 182.15,11.47 180.72,10.04 169.52,10.04 167.77,8.29 164.54,8.29 164.33,8.5 160.57,8.5 159.86,7.78 157.34,7.78 156.88,8.24 150.09,8.24 149.46,7.61 145.21,7.61 144.93,7.33 144.93,6.33 144.3,5.7 141.75,5.7 140.91,6.55 138.29,6.55 136.04,4.29 v2(136.04,1.48)
  BOTTOM w0.089: CPU1.AR10 v2(112.18,40.75) ; v2(160.12,67.04) 159.3,67.86 R7305.1 157.78,66.74 Q7301.D
CLK_PCIE_SD_REQ#: length 15.9
  TOP w0.089: v2(111.53,40.75) 111.3,40.52 110.33,40.52 109.95,40.91 109.47,40.91 108.98,40.42 v1(107.97,40.42) 107,40.42 105.71,39.13 104.06,39.13 103.73,39.46 101.11,39.46 98.8,41.77 RN1812.8
  BOTTOM w0.089: v2(111.53,40.75) 111.85,40.42 CPU1.AT10
CLK_PCIE_TBT_REQ#: length 14.6
  TOP w0.089: v2(111.53,38.92) 111.33,39.12 107.25,39.12 106.57,38.44 102.86,38.44 102.86,38.45 v1(100.56,38.45) 99.62,39.38 RN1813.8
  BOTTOM w0.089: CPU1.AU7 111.2,38.59 v2(111.53,38.92)
CLK_PCIE_VGA: length 57.8
  L6 w0.127: v2(135.22,58.89) 135.22,59.3 135.3,59.37 135.95,59.37 136.22,59.65 136.86,59.65 140.96,63.75 140.96,67.29 141.65,67.97 141.65,75.41 139.81,77.25 139.81,83.94 141.44,85.57 146.46,85.57 148.55,83.48 148.55,81.81 153.08,77.28 153.77,77.28 153.98,77.49 153.98,77.82 153.76,78.04 v2(153.55,78.04)
  BOTTOM w0.089: 132.93,59.75 132.91,59.75 132.89,59.78 132.43,59.78 132.1,59.44 131.04,59.44 130.87,59.62 130.6,59.62 130.48,59.58 130.26,59.58 130.16,59.62 129.96,59.62 129.68,59.52 CPU1.C42
  BOTTOM w0.102: v1(134.87,59.57) 134.87,59.75 ; 134.87,59.75 132.93,59.75 ; 134.87,59.75 135.49,59.75 135.66,59.58 135.66,59.4 135.58,59.32 135.3,59.32 135.22,59.24 v2(135.22,58.89) ; GPU1.AE8 v2(153.55,78.04)
CLK_PCIE_VGA#: length 57.7
  L6 w0.127: v2(154.35,78.04) 154.24,77.93 154.24,77.38 153.88,77.01 152.97,77.01 148.28,81.7 148.28,83.37 146.35,85.3 141.55,85.3 140.08,83.83 140.08,77.36 141.92,75.52 141.92,67.86 141.23,67.18 141.23,63.64 136.98,59.38 136.33,59.38 135.86,58.91 v2(135.86,58.89)
  BOTTOM w0.089: CPU1.D42 129.33,59.64 129.6,59.68 129.93,59.8 130.2,59.8 130.29,59.76 130.45,59.76 130.58,59.8 130.94,59.8 131.12,59.62 132.03,59.62 132.36,59.96 132.89,59.96 132.91,59.98 132.93,59.98
  BOTTOM w0.102: v1(133.34,60.16) 133.34,59.98 ; 133.34,59.98 135.58,59.98 135.88,59.68 135.88,58.92 v2(135.86,58.89) ; 133.34,59.98 132.93,59.98 ; GPU1.AD8 v2(154.35,78.04)
CLK_PCIE_WLAN_REQ#: length 211.6
  TOP w0.089: v2(112.18,38.92) 111.57,38.31 110.47,38.31 110.35,38.43 v1(109.37,38.43) 107.14,38.43 106.77,38.06 99.97,38.06 99.24,38.79 RN1813.7 ; v2(110.64,28.03) 111.09,27.58 111.09,23.12 113.41,20.79 114.44,20.79 116.72,18.5 117.15,18.5 119.84,15.81 125,15.81 125.71,15.11 125.71,11.63 128.13,9.21 132.42,9.21 135.22,6.41 135.22,1.67 v2(135.4,1.48)
  L4 w0.089: v2(112.18,38.92) 111.77,39.32 111.36,39.32 111.05,39.01 111.05,38.55 110.93,38.43 110.93,37.76 111.46,37.23 111.46,34.68 111.61,34.53 111.61,30.69 111.15,30.22 111.15,28.54 v2(110.64,28.03)
  L6 w0.089: v2(215.72,48.81) 215.29,48.37 215.29,44.54 215.69,44.14 215.69,39.22 217.01,37.9 217.01,33.21 216.99,33.19 216.99,29.48 217.6,28.86 217.6,21.17 212.14,15.71 205.16,15.71 204.5,16.37 197.87,16.37 195.38,13.88 191.43,13.88 190.39,12.84 180.4,12.84 179.03,11.47 159.45,11.47 156.43,8.44 150.01,8.44 149.37,7.8 145.13,7.8 144.74,7.41 144.74,6.41 144.22,5.89 141.83,5.89 140.99,6.74 138.21,6.74 135.08,3.61 135.08,1.8 v2(135.4,1.48)
  BOTTOM w0.089: v2(112.18,38.92) 111.85,38.6 CPU1.AT7 ; v2(215.72,48.81) 214.52,50.01 214.52,55.7 212.55,57.67 207.99,57.67 207.89,57.57 206.32,57.57 206.29,57.6 IOBD1.53
CLK_TP_SIO: length 17.5
  TOP w0.089: v2(150.64,11.26) 150.64,11.86 149.99,12.51 149.99,13.74 147.82,15.92 144.47,15.92 143.8,16.58 KBC24.78
  BOTTOM w0.089: EC6501.1 153.18,9.46 RN6501.3 152.12,9.79 v2(150.64,11.26) 150.64,10.25 v1(150.63,10.24) 150.32,9.92 RN6502.2
CLKRUN#: length 71.1
  TOP w0.102: v2(121.69,18.25) 121.18,18.76 120.72,18.76 119.42,20.06 117.36,20.06 116.23,21.19 116.23,22.47 113.97,24.73 v1(113.94,24.73) 113.94,24.75 112.31,26.38 112.31,28.52 v2(111.91,28.92) 111.91,28.92 111.63,28.92 111.07,29.47 111.07,30.52 110.38,31.21 109.7,31.21 v2(109.28,31.63) ; v2(137.94,25.41) 137.94,26.12 137.94,26.12 137.94,26.45 138.09,26.6 138.09,26.96 138.49,27.36 140.56,27.36 140.63,27.29 141.35,27.29 143.28,25.36 R2439.1
  L4 w0.102: v2(110.61,40.98) 110.05,40.98 109.98,41.04 109.49,41.04 109.14,40.69 109.14,35.73 109.28,35.59 v2(109.28,31.63)
  L6 w0.102: v2(137.94,25.41) 137.51,25.41 136.03,23.93 134.66,23.93 133.59,22.87 130.56,22.87 129.55,23.88 128.24,23.88 127.64,23.28 127.64,22.97 123.36,18.69 122.12,18.69 v2(121.69,18.25)
  BOTTOM w0.102: R1818.1 114.45,20.9 114.43,20.92 114.41,20.92 113.93,21.4 112.7,21.4 111.9,22.19 111.9,26.56 112.42,27.08 112.42,28.42 v2(111.91,28.92) ; CPU1.AW11 110.53,41.06 v2(110.61,40.98)
CLKRUN#_EC: length 3.7
  TOP w0.089: R2439.2 145.26,25.36 v1(145.84,24.78) 145.47,24.41 145.12,24.41 144.84,24.13 KBC24.63
CMP_VIN0: length 6.7
  TOP w0.114: R2470.2 v1(163.85,16.6) 163.47,16.98 KBC24.20
CMP_VIN0_R: length 243.4
  TOP w0.114: R2494.1 151.8,1.52 164.87,1.52 v2(165.63,2.27) 165.6,2.3 165.6,5.39 168.63,8.41 168.63,11.82 167.75,12.7 167.75,13.06 166.22,14.6 164.02,14.6 R2470.1 ; R2610.1 142.44,75.96 C2612.1 R2609.2 R2608.2 ; R2610.1 143.28,75.12 v2(143.28,74.51) v1(144.04,74.51) ; R2610.1 143.1,75.45 C2613.1
  L4 w0.114: v2(212.54,62.8) 209.85,65.49 206.14,65.49 202.47,69.16 199.17,69.16 197.6,70.73 193.53,70.73 192.54,71.72 186.32,71.72 185.91,72.13 183.58,72.13 181.57,70.12 177.37,70.12 176.93,69.68 173.88,69.68 173.15,70.41 167.26,70.41 164.86,72.81 161.71,72.81 160.99,73.53 152.94,73.53 152.86,73.44 150.15,73.44 149.48,72.76 148.45,72.76 147.99,73.22 144.57,73.22 v2(143.28,74.51)
  L6 w0.102: v2(212.54,62.8) 216.35,59 216.35,56.86 216.65,56.55 216.65,55.59 220.94,51.31 220.94,51.04 221.19,50.46 221.44,49.82 221.44,49.81 221.44,48.39 221.95,47.88 221.95,45.11 223.37,43.69 223.37,33.22 223.31,33.15 223.31,31.83 224.14,31 224.29,30.84 224.39,30.84 227.74,27.49 227.74,22.58 227.52,22.35 227.52,7.8 225.43,5.71 214.89,5.71 212.34,8.27 206.5,8.27 206.09,7.86 206.09,7.66 203.52,5.08 203.52,3.59 201.36,1.44 166.46,1.44 v2(165.63,2.27)
CMP_VIN1: length 42.7
  TOP w0.114: R2481.2 149.93,4.05 C2430.1 150.06,4.02 R2482.1 150.82,2.68 v2(150.64,2.5) ; KBC24.21 162.86,17.38 162.99,17.51 164.08,17.51 v1(165.37,16.22) 166.16,16.22 168.28,14.1 168.28,13.08 169.16,12.2 169.16,8.19 166.14,5.17 166.14,3.83 v2(166.26,3.71)
  L6 w0.102: v2(166.26,3.71) 164.93,3.71 164.17,2.95 163.84,2.95 163.07,2.18 150.96,2.18 v2(150.64,2.5)
CMP_VOUT0: length 7.2
  TOP w0.114: v2(146.2,14.76) 146.2,14.69 145.8,14.3 144.41,14.3 143.89,13.78 KBC24.85
  BOTTOM w0.114: R2607.2 148.53,15.33 R2602.2 R2615.2 v1(146.83,15.38) 146.5,15.38 146.2,15.07 v2(146.2,14.76)
CODEC_BITCLK_R: length 4.7
  TOP w0.089: R2752.2 28.49,19.47 v1(28.39,19.47) 27.73,19.47 26.79,18.53 25.95,18.53 25.7,18.27 HDA27.14
CODEC_SDOUT_R: length 4.2
  TOP w0.089: HDA27.17 24.5,18.27 24.84,18.61 24.84,19.19 25.34,19.7 v1(25.65,19.7) 26.55,19.7 R2740.2
CPU_DP1_CTRL_CLK: length 22.8
  L3 w0.127: v2(126.38,24.13) 126.29,24.13 125.88,24.54 125.88,24.97 126.79,25.88 126.79,26.61 124.92,28.47 124.92,31.03 124.9,31.05 124.9,34.22 125.25,34.56 125.25,40.86 v2(124.28,41.83)
  BOTTOM w0.089: RN801.3 124.78,22.62 v1(125.53,23.37) 126,23.84 126.12,23.84 126.38,24.11 v2(126.38,24.13) ; CPU1.L13 v2(124.28,41.83)
CPU_DP1_CTRL_DATA: length 21.7
  L3 w0.127: v2(124.27,41.18) 125.03,40.42 125.03,35.16 124.54,34.67 124.54,28.31 125.48,27.38 125.48,24.4 v2(126.39,23.49)
  BOTTOM w0.089: v2(126.39,23.49) v1(126.39,22.31) 126.32,22.25 RN801.4 ; CPU1.L12 v2(124.27,41.18)
CPU_DP1_HPD: length 194.8
  TOP w0.089: v1(59.71,6.69) v2(59.71,6.09) ; v2(26.31,77.05) 25.8,76.54 R5760.1
  L3 w0.089: v2(25.17,60.92) 25.17,61.05 26.44,62.32 26.44,63.59 26.46,63.61 26.46,63.61 27.66,64.82 27.66,66.43 28.09,66.86 28.09,72.35 27.34,73.09 27.34,75.1 27.66,75.42 27.66,75.7 v2(26.31,77.05) ; v2(59.71,6.09) 61.02,7.4 71.19,7.4 74.29,10.5 78.38,10.5 81.5,13.61 84.11,13.61 85.26,14.76 89.7,14.76 91.17,16.23 94.58,16.23 95.44,17.08 103.07,17.08 104.31,18.31 105.65,18.31 105.96,18.63 113.1,18.63 113.79,17.94 116.78,17.94 117.34,18.5 119.45,18.5 120.14,19.19 122.47,19.19 125.12,21.84 125.12,27.23 124.18,28.16 124.18,30.57 124.35,30.73 124.35,34.75 124.83,35.24 124.83,39.36 124.33,39.87 v2(124.25,39.87)
  L6 w0.089: v2(25.17,60.92) 25.17,59.65 26.18,58.63 27.58,58.63 28.58,57.63 28.58,39.98 31.97,36.59 31.97,32.84 32.41,32.41 32.41,20.01 32.77,19.65 32.77,15.32 37.37,10.72 37.37,7.78 39.83,5.32 58.94,5.32 v2(59.71,6.09)
  BOTTOM w0.089: CPU1.L9 124.44,39.87 v2(124.25,39.87)
CPU_DP1_HPD_R: length 2.6
  TOP w0.089: U5701.B1 26.31,73.09 26.31,74 v1(25.93,74.38) 25.8,74.51 R5760.2
CPU_DP2_CTRL_CLK: length 19
  TOP w0.089: v2(123.72,23.53) 123.72,23.84 v1(123.46,24.09)
  L4 w0.102: v2(123.31,38.56) 123.31,37.95 123.82,37.45 123.82,37.27
  L4 w0.127: v2(123.72,23.53) 125.13,24.94 125.13,29.73 124.44,30.41 124.44,34.07 123.82,34.69 123.82,37.27
  BOTTOM w0.089: RN803.4 123.74,22.43 123.74,22.71 123.72,22.73 v2(123.72,23.53) ; CPU1.N7 v2(123.31,38.56)
CPU_DP2_CTRL_DATA: length 20.4
  TOP w0.089: v2(123.21,22.95) 123.35,22.81 v1(123.75,22.81)
  L4 w0.102: v2(123.31,39.23) 123.78,38.76 123.78,37.75 124.04,37.5 124.04,37.32
  L4 w0.127: 124.04,37.32 124.04,34.78 124.66,34.16 124.66,30.74 125.51,29.88 125.51,24.7 123.76,22.95 v2(123.21,22.95)
  BOTTOM w0.089: RN803.3 123.26,22.9 v2(123.21,22.95) ; CPU1.N8 123.31,39.2 v2(123.31,39.23)
CPU_DP2_HPD: length 17.1
  L3 w0.089: v2(124.69,25.82) 124.35,26.15 124.35,27.39 123.24,28.51 123.24,29.46 123.24,30 124.06,30.83 124.06,34.77 124.62,35.33 124.62,38.23 v2(124.26,38.59)
  BOTTOM w0.089: v1(125.62,26.12) 125.5,26 R803.2 R804.1 124.73,25.77 v2(124.69,25.82) ; CPU1.L7 v2(124.26,38.59)
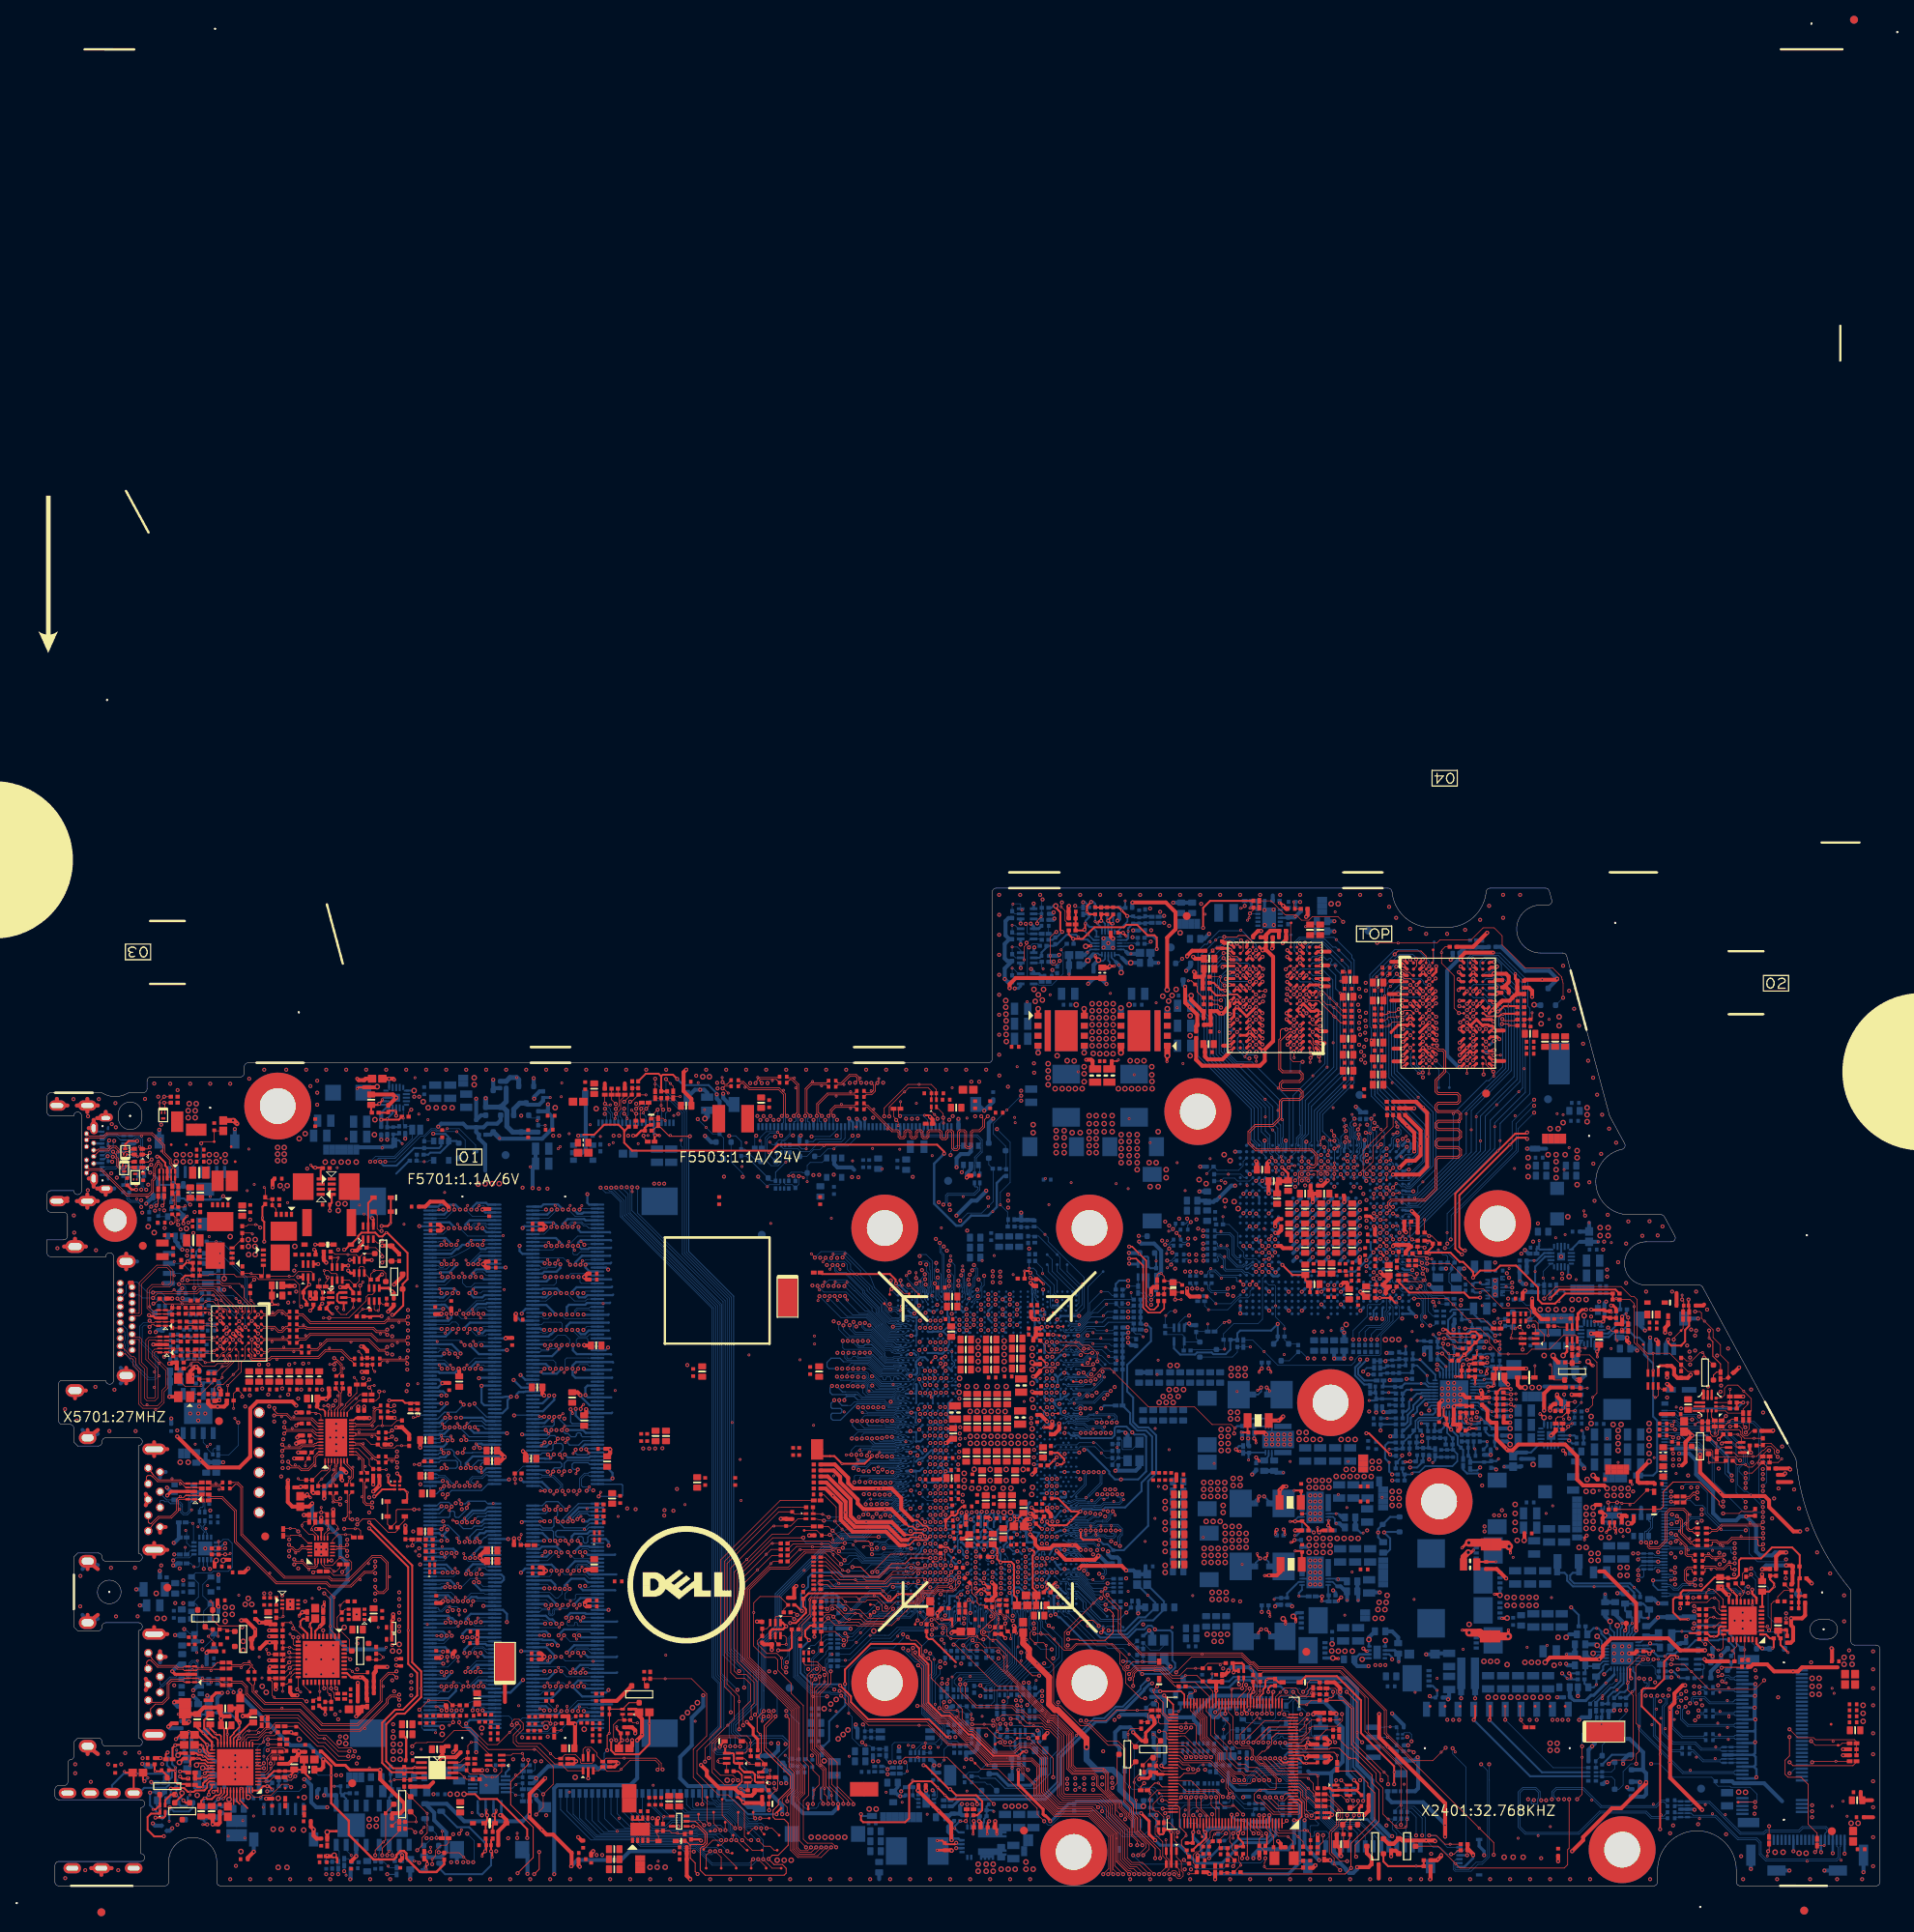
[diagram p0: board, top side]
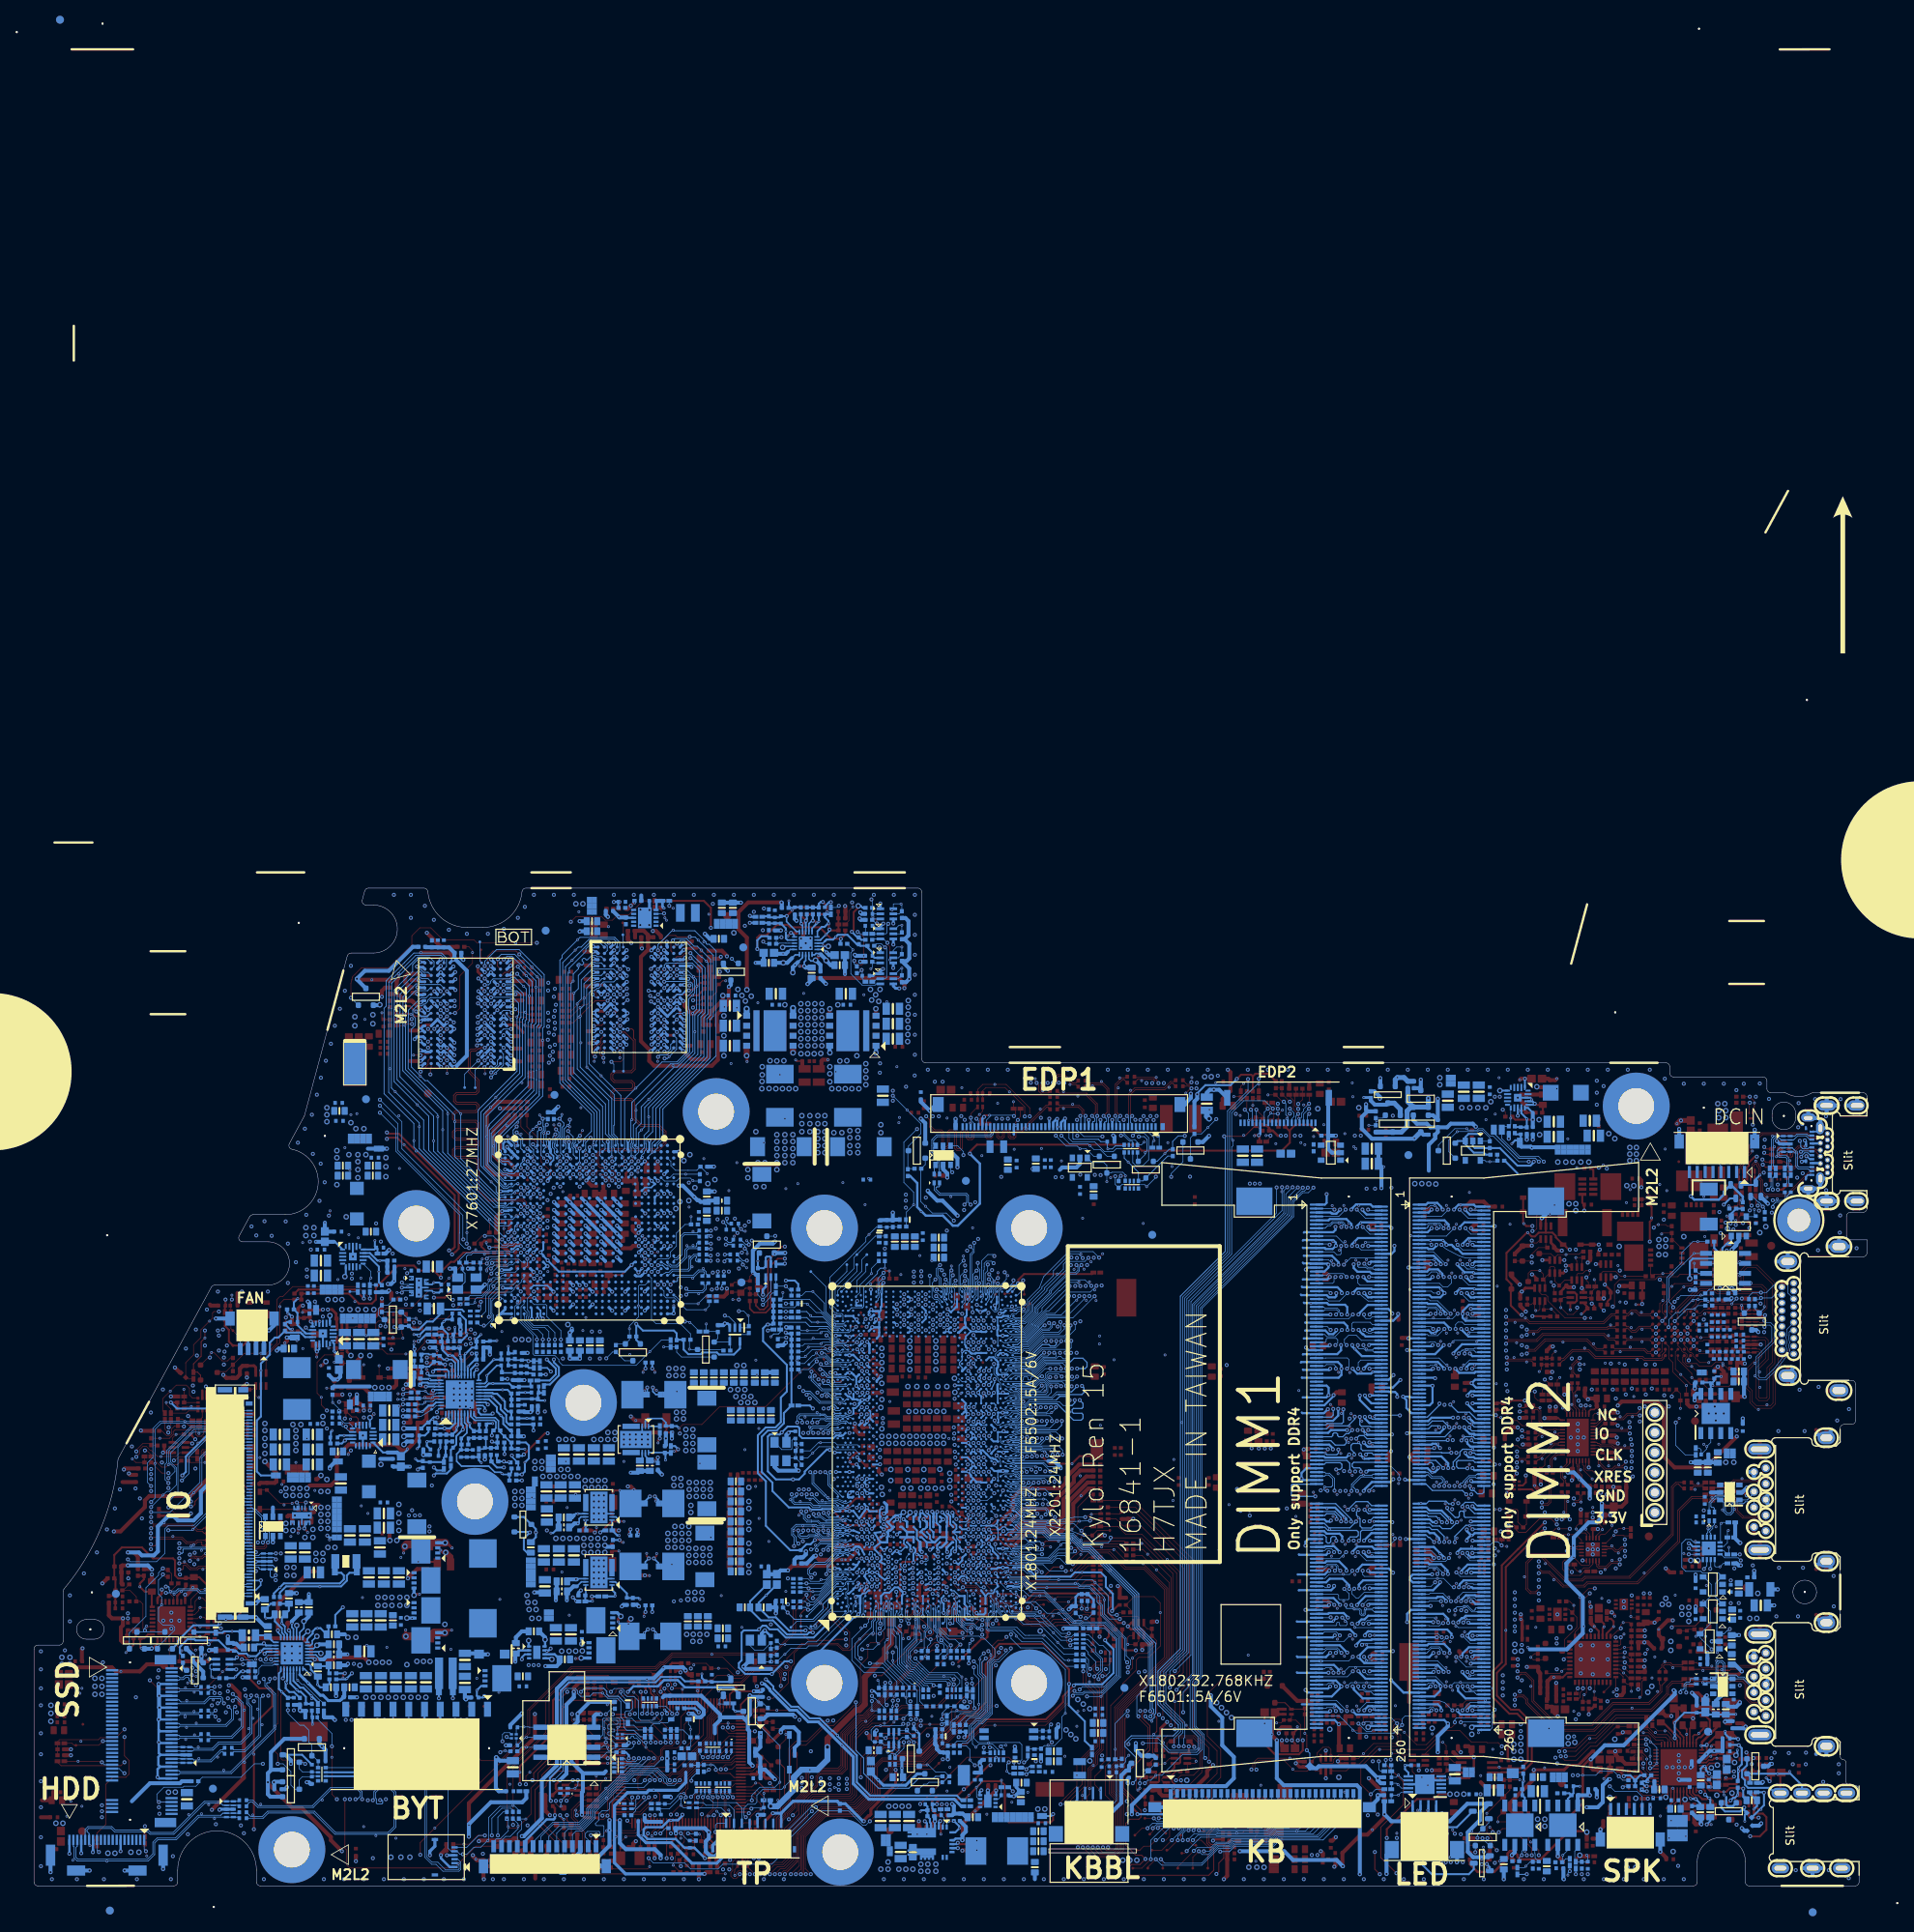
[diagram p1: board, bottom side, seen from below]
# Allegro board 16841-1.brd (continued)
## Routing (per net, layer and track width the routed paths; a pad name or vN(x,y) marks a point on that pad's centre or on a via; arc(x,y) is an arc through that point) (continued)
CPU_DP_HPD_MUX: length 2.5
  TOP w0.089: U3701.18 31.38,27.54 v1(30.91,27.06) 30.22,26.38 R3729.1
CPU_DP_HPD_R: length 187.1
  TOP w0.089: R3849.1 40.58,64.1 40.66,64.1 v2(40.91,64.35) ; R3729.2 28.26,26.38 R3725.2 28.6,25.95 28.6,24.22 v1(28.85,23.96) 29.02,23.79 32.49,23.79 32.82,23.46 v2(32.96,23.46)
  L3 w0.089: v2(124.49,22.99) 123.57,22.06 123.57,21 122.49,19.92 117.98,19.92 116.39,18.33 113.94,18.33 113.14,19.13 103.43,19.13 101.83,17.52 94.79,17.52 94.13,16.86 91.09,16.86 89.47,15.24 84.9,15.24 83.78,14.12 80.78,14.12 77.89,11.23 74.48,11.23 71.09,7.84 60.35,7.84 v2(58.57,6.06)
  L4 w0.089: v2(40.91,64.35) 42.2,64.35 43.71,62.85 43.71,62.19 43.96,61.94 43.96,61.56 42.82,60.41 42.82,52.03 44.47,50.38 44.47,41.24 47.89,37.82 47.89,22.05 47.14,21.3 42.31,21.3 41.3,22.31 36.69,22.31 35.55,23.46 v2(32.96,23.46)
  L6 w0.089: v2(58.57,6.06) 58.02,5.51 39.91,5.51 37.56,7.85 37.56,10.8 32.96,15.4 v2(32.96,23.46)
  BOTTOM w0.089: R804.2 124.73,23.23 v2(124.49,22.99)
CPU_POPIRCOMP: length 18.5
  TOP w0.203: 108.91,44.6 109.86,44.6 110.12,44.86 111.08,44.86 111.35,44.59 111.35,44.59 v2(111.53,44.41)
  TOP w0.508: 108.91,44.6 107.27,46.24 v1(104.03,46.24) 102.81,46.24 102.05,47 102.05,49.14 99.16,52.03 R412.1
  BOTTOM w0.305: CPU1.AT16 111.55,44.25 111.55,44.39 v2(111.53,44.41)
CPU_RXN_C_DGPU_TXN0: length 49
  L6 w0.127: v2(125.72,41.64) 125.74,41.64 126.19,41.19 126.48,41.19 126.55,41.12 126.69,40.98 126.93,40.74 128.25,40.74 129.51,42 129.52,42 129.92,42.4 129.92,42.41 129.96,42.45 129.96,43.7 130.72,44.47 130.72,47.92 133.74,50.94 136.8,50.94 137.31,51.45 137.31,52.07 146.55,61.32 146.55,74.44 146.07,74.93 v2(146.07,75.91)
  BOTTOM w0.102: CPU1.H13 v2(125.72,41.64) ; v2(146.07,75.91) 145.94,76.03 C7302.1
CPU_RXN_C_DGPU_TXN1: length 51.1
  L6 w0.089: v2(127.03,41.65) 127.48,41.2 127.86,41.2 128.8,42.15 128.8,42.83 128.85,42.88 128.85,42.99
  L6 w0.127: 128.85,42.99 128.85,43.73 129.39,44.27 130.02,44.9 130.02,48.4 133.26,51.64 135.67,51.64 145.85,61.82 145.85,72.69 144.95,73.59 144.95,74.96 144.14,75.77 144.14,76.37 142.77,77.74 v2(142.77,78.95)
  BOTTOM w0.102: v1(142.29,78.55) 142.36,78.55 v2(142.77,78.95) 142.77,79.13 143.1,79.46 C7304.1 ; CPU1.G11 126.69,41.31 v2(127.03,41.65)
CPU_RXN_C_DGPU_TXN2: length 54.3
  L6 w0.089: v2(126.33,44.41) 126.33,44.54 125.75,45.12 125.75,46.59 126.32,47.16 126.32,47.29 126.28,47.33
  L6 w0.127: v2(142.01,81.49) 142.01,81.19 141.36,80.54 141.36,77.78 143.17,75.97 143.17,75.37 143.99,74.56 143.99,68.76 144.89,67.86 144.89,62.22 136.49,53.82 130.54,53.82 129.93,53.21 129.93,49.93 129.11,49.11 126.82,49.11 126.28,48.57 126.28,47.33
  BOTTOM w0.102: CPU1.H16 v2(126.33,44.41) ; v1(142.27,81.99) 142.01,81.73 v2(142.01,81.49) 142.39,81.49 143.02,82.13 C7306.1
CPU_RXN_C_DGPU_TXN3: length 55.8
  L6 w0.089: v2(126.35,43.5) 126.11,43.73 125.78,43.73 125.38,44.13 125.38,47.15 125.36,47.18
  L6 w0.127: v2(143,83.48) 143,83.21 142.65,82.87 141.22,82.87 140.62,82.27 140.62,77.53 142.48,75.68 142.48,67.7 141.74,66.96 141.74,63.43 134.42,56.11 128.51,56.11 127.21,54.81 127.21,52.91 126.28,51.98 126.28,50.58 125.61,49.91 125.61,47.95 125.36,47.7 125.36,47.18
  BOTTOM w0.102: v1(142.46,83.2) 142.72,83.2 v2(143,83.48) 143.33,83.81 C7308.1 ; CPU1.G15 v2(126.35,43.5)
CPU_RXP_C_DGPU_TXP0: length 50.1
  TOP w0.102: v2(126.38,41.63) 126.87,41.14 v1(126.87,40.8)
  L6 w0.127: v2(145.44,75.91) 145.44,75.5 145.54,75.4 145.73,75.4 145.8,75.32 145.8,74.81 146.29,74.33 146.29,61.43 137.04,52.18 137.04,51.56 136.69,51.21 133.63,51.21 130.46,48.03 130.46,44.58 129.69,43.82 129.69,42.56 129.65,42.52 129.65,42.52 129.4,42.27 129.4,42.27 128.14,41.01 127.04,41.01 126.74,41.31 126.41,41.63 v2(126.38,41.63)
  BOTTOM w0.102: C7301.1 145.44,76.34 v2(145.44,75.91) ; v2(126.38,41.63) 126.33,41.68 126.33,42.43 126.4,42.5 126.62,42.5 126.69,42.43 CPU1.G13
CPU_RXP_C_DGPU_TXP1: length 51
  TOP w0.102: v1(128.29,41.62) 127.69,41.62 v2(127.68,41.61)
  L6 w0.089: v2(127.68,41.61) 128.01,41.61 128.63,42.22 128.63,42.94 128.59,42.98 128.59,42.99
  L6 w0.127: v2(142.26,79.46) 142.26,78.83 142.5,78.59 142.5,77.63 143.87,76.26 143.87,75.66 144.69,74.85 144.69,73.48 145.59,72.58 145.59,61.93 135.56,51.9 133.15,51.9 129.75,48.51 129.75,45.01 129.2,44.45 128.59,43.84 128.59,42.99
  BOTTOM w0.102: v2(127.68,41.61) 127.34,41.27 CPU1.F11 ; v2(142.26,79.46) 142.77,79.46 143.45,80.14 C7303.1
CPU_RXP_C_DGPU_TXP2: length 54.4
  L6 w0.089: 126.55,47.33 126.51,47.3 126.51,47.08 125.94,46.51 125.94,45.2 126.27,44.87 126.77,44.87 126.97,44.67 v2(126.97,44.38)
  L6 w0.127: v2(142.51,80.99) 142.18,80.99 141.63,80.43 141.63,77.89 143.44,76.08 143.44,75.48 144.25,74.67 144.25,68.87 145.16,67.97 145.16,62.11 136.6,53.55 130.65,53.55 130.2,53.1 130.2,49.82 129.22,48.84 126.93,48.84 126.55,48.46 126.55,47.33
  BOTTOM w0.102: CPU1.G16 126.95,44.38 v2(126.97,44.38) ; C7305.1 142.92,81.52 142.74,81.52 142.51,81.3 v2(142.51,80.99) 142.21,80.68 v1(142.21,80.35)
CPU_RXP_C_DGPU_TXP3: length 55.7
  TOP w0.102: v1(143.86,82.56) v2(143.45,82.97)
  L6 w0.089: 125.62,47.18 125.62,47.17 125.57,47.12 125.57,44.21 125.86,43.92 126.56,43.92 v2(126.98,43.5)
  L6 w0.127: v2(143.45,82.97) 143.13,82.97 142.76,82.6 141.33,82.6 140.89,82.16 140.89,77.64 142.74,75.79 142.74,67.59 142.01,66.85 142.01,63.32 134.53,55.84 128.62,55.84 127.48,54.7 127.48,52.8 126.55,51.87 126.55,50.47 125.88,49.8 125.88,47.84 125.62,47.59 125.62,47.18
  BOTTOM w0.102: v2(143.45,82.97) 143.89,83.4 C7307.1 ; CPU1.F15 v2(126.98,43.5)
CPVDD: length 6.6
  TOP w0.203: HDA27.20 23.3,18.47 23.28,18.48 23.28,18.91 23.72,19.34 23.72,19.47 24.28,20.03 24.28,20.03 24.44,20.19 v1(24.44,20.69)
  TOP w0.508: C2730.1 24.51,22.57 R2724.2 24.1,22.11 C2740.1 24.1,21.17 24.44,20.83 v1(24.44,20.69)
CPVEE: length 4
  TOP w0.203: HDA27.25 20.93,17.78
  TOP w0.305: C2741.1 19.07,20.15 v1(19.83,19.39) 20.93,18.29 20.93,17.78
CSI2_COMP: length 8.8
  TOP w0.508: v2(128.23,42.58) 129.37,41.44 v1(130.2,41.44) 133.06,41.44 133.52,41.9 v2(133.52,41.96)
  BOTTOM w0.254: CPU1.E13 v2(128.23,42.58)
  BOTTOM w0.508: v2(133.52,41.96) 133.58,41.9 133.72,41.9 134.64,40.98 R1501.1
CTL1: length 2
  BOTTOM w0.089: v1(17.55,43.01) 17.55,42.3 R3401.2 18.24,42.64 U3401.6
CTL2: length 2.7
  BOTTOM w0.089: U3401.7 18.19,43.14 17.72,43.6 R3406.2 17.72,45.06 v1(17.61,45.17)
CTL3: length 3.4
  BOTTOM w0.089: R3402.2 18.38,46.19 v1(18.51,46.06) 18.6,45.97 U3401.8
DAT_TP_SIO: length 16.1
  TOP w0.089: v2(150.01,11.26) 150.01,12.12 149.73,12.4 149.73,13.63 147.71,15.65 144.26,15.65 143.73,16.18 KBC24.79
  BOTTOM w0.089: RN6502.1 150.08,10.57 150.26,10.76 150.26,11.01 v2(150.01,11.26) 150.01,11.52 v1(150.26,11.77) 150.74,11.77 151.07,11.44 151.07,11.35 151.99,10.43 EC6502.1 152.7,10.46 RN6501.4
DBC_EN_R: length 4.5
  BOTTOM w0.089: R5503.1 90.75,94.5 v1(90.55,94.7) 90.55,95.07 91.32,95.85 92.6,95.85 92.85,96.09 LCD1.6
DBC_PANEL_EN: length 137.4
  TOP w0.089: v1(73.68,97.5) 73.68,97.75 v2(73.3,98.13) ; v2(112.34,33.81) 111.76,33.23 R2043.2
  L3 w0.089: v2(87.68,24.91) 88.13,24.47 89.16,24.47 89.45,24.77 98.07,24.77 99.64,26.34 99.92,26.34 104.28,30.7 106.26,30.7 108.24,32.68 111.21,32.68 v2(112.34,33.81) ; v2(73.3,98.13) 73.3,97.75 75.08,95.97 75.08,93.56 73.63,92.11 v2(73.63,88.78)
  L4 w0.089: v2(90.06,95.34) 89.22,96.18 85.39,96.18 85.06,96.5 82.4,96.5 79.7,99.2 77.41,99.2 76.98,98.77 76.98,98 76.35,97.37 73.81,97.37 73.3,97.88 v2(73.3,98.13)
  BOTTOM w0.089: R5503.2 89.89,95.16 v2(90.06,95.34) ; v2(87.68,24.91) 86.42,26.18 86.42,26.23 85.67,26.98 85.67,73.91 74.06,85.52 74.06,88.35 v2(73.63,88.78) ; v2(112.34,33.81) 112.89,33.81 113.56,34.48 113.56,35.57 113.86,35.87 114.05,35.87 114.25,36.07 114.25,37.34 CPU1.AM5
DC_IN_OK: length 77.3
  TOP w0.254: PD4307.A 40.79,86.79 PQ4310.5 40.79,83.02 ; 40.79,83.02 39.94,83.02 39.52,82.59 39.52,82.43 PD4305.A 38.5,81.49 37.87,80.86 v2(37.74,80.86) ; 40.79,83.02 41.68,83.02 42.16,82.54 42.59,82.54 v1(43.07,83.02) 43.2,83.02 45.78,80.44 45.78,77.09 45.16,76.47 PQ4306.G 45.16,75.73 45.23,75.65 45.23,73.75 44.04,72.56 v2(43.84,72.56) ; R2475.1 PR4311.2 18.03,79.18 v2(17.85,79.36) 17.14,78.65 PR4315.2 ; PU4307.2 43.71,50.89 43.33,51.27 v2(43.33,52.16)
  L4 w0.254: v2(43.84,72.56) 43.84,72.35 42.57,71.08 42.57,64.86 44.22,63.21 44.22,62.32 45.11,61.43 45.11,56.6 43.33,54.82 v2(43.33,52.16) ; v2(31.39,78.19) 31.98,78.19 35.16,81.37 37.23,81.37 v2(37.74,80.86)
  L6 w0.254: v2(31.39,78.19) 30.75,78.83 23.9,78.83 23.36,79.36 v2(17.85,79.36)
  BOTTOM w0.254: v2(17.85,79.36) 18.36,79.87 18.36,81.06 17.8,81.62 PR4335.2 17.23,81.86 U4302.1
DC_IN_OK#: length 2.3
  TOP w0.254: PD4310.A 45.74,49.15 v1(45.74,50) 45.35,50.39 PU4307.4
DC_IN_OK_R: length 21.2
  TOP w0.254: v2(42.49,83.86) 43.28,83.86 v1(43.58,84.16) 43.67,84.25 PD4308.K PD4307.K ; PQ4308.2 33.17,76.54 v2(33.29,76.41) 32.56,75.68 R4304.1 32.56,74.66 32.96,74.26 R4305.2
  L3 w0.254: v2(42.49,83.86) 42.26,83.86 41.68,83.27 41.68,82.64 39.14,80.1 37.61,80.1 35.96,78.45 35.33,78.45 v2(33.29,76.41)
DCBATOUT: length 54.1
  TOP w0.381: v2(198.65,73.75) 198.9,73.75 199.28,73.37 PR4511.1
  TOP w0.508: PR4477.1 186.79,63.64 187.09,63.33 v3(187.73,63.33) ; v2(210.57,29.93) 207.41,29.93 205.89,31.46 198.65,31.46 197.61,30.42 197.61,29.27 v2(197.12,28.79) 194.84,28.79 194.61,29.02 190.88,29.02 v3(190.27,28.41) ; PR4612.1 v2(187.85,65.75) ; v2(137.86,124.98) 142.09,124.98 143.33,123.73 143.33,121.58 142.26,120.51 v3(142.26,113.88)
  BOTTOM w0.203: PU4401.3 197.29,28.95 v2(197.12,28.79)
  BOTTOM w0.508: v2(210.57,29.93) 210.53,29.98 PD4407.A ; PR4509.1 194.71,63.46 190.14,63.46 ; PR8202.1 137.82,124.93 v2(137.86,124.98)
  BOTTOM w0.711: C5514.1 83.84,97.79 v3(83.55,97.5)
  vias: v1(82.7,102.07) v1(83.51,98.64) v1(122.96,96.99) v1(123.21,104.1) v1(124.48,112.36) v1(126.79,89.9) v1(127.4,113.24) v1(137.31,88.61) v1(140.86,112.23) v1(143.53,111.59) v1(149.88,81.37) v1(151.55,73.74) v1(156.04,73.72) v1(162.71,72.22) v1(169.57,49.36) v1(173.38,70.45) v1(173.63,36.41) v1(173.76,24.6) v1(186.84,6.06) v1(187.98,30.31) v1(190.52,30.57) v1(192.04,74.26) v2(82.44,102.96) v2(117.39,102.2) v2(118.38,102.2) v2(120.95,102.98) v2(125.34,104.53) v2(125.37,103.34) v2(144.5,2.09) v2(145.28,2.09) v2(182.57,45.68) v2(182.57,45.05) v2(183.79,47.1) v2(184.42,47.08) v2(184.78,47.74) v2(185.19,47.08) v3(54.25,102.7) v3(54.25,101.81) v3(83.28,102.83) v3(84.12,102.83) v3(124.33,3.03) v3(124.33,2.12) v3(125.24,2.12) v3(125.34,113.93) v3(125.51,112.41) v3(125.9,113.24) v3(126.41,112.58) v3(126.56,113.93) v3(141.7,113.07) v3(142.45,112.44) v3(142.89,113.16) v3(143.4,113.93) v3(164.99,71.33) v3(168.3,53.94) v3(168.3,53.05) v3(168.68,34) v3(169.03,35.11) v3(169.18,53.94) v3(169.18,53.05) v3(169.18,36.03) v3(169.57,34) v3(169.98,69.4) v3(169.92,35.11) v3(170.07,36.03) v3(170.2,36.92) v3(170.84,69.43) v3(170.84,50.13) v3(170.84,49.24) v3(170.84,48.35) v3(171.67,69.43) v3(171.72,50.13) v3(171.72,49.24) v3(171.72,48.35) v3(182.49,28.54) v3(183.33,28.54) v3(184.17,28.54) v3(185.06,3.64) v3(185.44,28.12) v3(186.2,3.64) v3(187.47,3.64) v3(187.7,28.41) v3(188.54,28.41) v3(188.62,63.33) v3(189.38,28.41) v3(189.5,63.33) v3(189.63,73.24) v3(190.65,73.24) v3(191.66,73.24) v3(192.68,73.24) v3(193.7,74.51) v3(193.7,73.24) v3(194.53,74.51) v3(195.47,74.51)
DCBATOUT_CAMERA:
  vias: v1(114.96,101.43) v2(114.59,97.36) v2(115.03,97.83)
DCBATOUT_LCD:
  vias: v1(88.79,94.45) v2(90.22,97.84) v2(90.6,97.33) v2(91,97.83) v2(91.43,97.34) v2(91.87,97.83) v2(92.27,97.34)
DDC_CLK_HDMI: length 20.5
  TOP w0.089: U5701.E1 24,73.13 21.24,75.89 19.31,75.89 18.92,75.51 16.4,75.51 v1(16.13,75.78) 15.86,75.51 13.56,75.51 v2(13.46,75.4)
  BOTTOM w0.089: HDMI2.15 10.03,75.32 10.03,76.26 10.49,76.72 11.45,76.72 12.77,75.4 v2(13.46,75.4) 14.52,75.4 14.98,74.94 R5755.2
DDC_CLK_PH1: length 2.3
  BOTTOM w0.089: v1(15.92,73.77) 15.92,73.13 D5701.2 14.98,73.38 R5755.1
DDC_DATA_HDMI: length 15.2
  TOP w0.089: U5701.F1 23.2,73.3 v1(22.12,74.38) 22.12,74.64 21.14,75.62 19.42,75.62 19.03,75.24 13.98,75.24 v2(13.46,74.71)
  BOTTOM w0.089: R5751.2 13.61,74.56 v2(13.46,74.71) 12.11,74.71 11.72,75.1 HDMI2.16
DDC_DATA_PH2: length 2.2
  BOTTOM w0.089: R5751.1 14.22,73.33 D5701.1 13.02,73.44 v1(13.02,73.62)
DDR4_DRAMRST#: length 149.2
  TOP w0.127: ED1302.1 ED1217.1 47.14,60.39 v2(47.14,59.82) 46.84,59.52 v1(46.5,59.52)
  L3 w0.127: v2(47.14,59.82) 46.06,58.75 46.06,51.33 43.73,49 43.73,36.17 41.42,33.87 41.42,28.16 40.27,27.01 38.76,27.01 38.01,26.27 38.01,21.06 36.28,19.33 36.28,16.33 38.04,14.57 38.04,13.68 46.33,5.39 50.19,5.39 50.37,5.57 57.81,5.57 58.17,5.21 61.26,5.21 61.7,5.64 76.89,5.64 82.76,11.52 87.27,11.52 87.9,12.15 94.11,12.15 95.64,13.69 104.93,13.69 106.79,15.55 106.91,15.55 v2(107.06,15.7)
  L4 w0.127: v2(59.32,59.79) 58.82,60.29 49.3,60.29 48.84,59.82 v2(47.14,59.82)
  BOTTOM w0.127: DM2.108 v2(47.14,59.82) ; R504.2 106.57,16.06 106.94,15.7 v2(107.06,15.7) ; v2(59.32,59.79) 59.35,59.82 DM1.108
DDR_VREF_S3: length 2.4
  BOTTOM w0.254: PU5102.6 58.24,14.39 58.67,14.82 v1(58.67,15.33) PC5123.1
DGPU_HOLD_RST#: length 266.7
  TOP w0.089: v2(139.21,3.9) 139.97,4.66 139.97,5.19 138.27,6.9 138.27,8.53 137.71,9.09 137.71,9.95 136.93,10.73 136.93,17.49 136.04,18.38 134.62,18.38 132.43,20.57 131.81,20.57 131.37,21.02 v2(131.29,21.02) ; v2(122.65,33.69) 122.55,33.69 121.83,34.42 121.5,34.42 EC2002.1 121.05,35.56 RN2009.4
  L4 w0.089: v2(217.93,50.18) 217.24,50.18 216.95,49.88 214.64,49.88 213.25,51.28 213.25,52.71 209.61,56.36 209.61,57.52 209.21,57.91 208.59,57.91 205.83,60.67 197.96,60.67 196.58,62.06 195.27,62.06 193.09,64.25 193.09,68.94 192.31,69.72 188.22,69.72 187.99,69.94 185.69,69.94 184.74,70.9 183.5,70.9 180.72,68.12 173.79,68.12 171.93,69.99 167.08,69.99 165.05,72.02 151.68,72.02 150.95,71.3 149.81,71.3 149.79,71.32 148.81,71.32 148.15,71.97 144.34,71.97 v2(143.28,73.04) ; v2(131.29,21.02) 130.02,21.02 128.76,22.27 122.93,22.27 122.37,22.84 122.37,23.77 122.69,24.1 122.69,30.51 123.48,31.3 123.48,33.32 123.11,33.69 v2(122.65,33.69)
  L6 w0.089: v2(217.93,50.18) 218.37,49.73 218.37,47.37 218.4,47.34 218.4,43.19 219.21,42.38 219.21,35.55 219.08,35.42 219.08,33.21 219.77,32.52 219.77,30.71 221.19,29.29 221.19,29.2 221.55,28.84 221.55,23.4 220.17,22.02 220.17,19 217.12,15.95 215.91,15.95 212.9,12.95 205.25,12.95 202.94,10.64 197.1,10.64 194.35,7.89 173.35,7.89 170.97,5.52 169.19,5.52 168.36,6.35 162.61,6.35 162.18,5.92 156.74,5.92 156.54,6.12 156.17,6.12 155.66,5.61 145.63,5.61 144.74,4.72 140.04,4.72 v2(139.21,3.9)
  BOTTOM w0.089: v2(122.65,33.69) 123.05,34.09 123.05,34.58 122.82,34.82 122.82,35.71 123.23,36.11 CPU1.P3 ; U7301.1 142.21,70.92 R7304.1 142.01,72.4 v1(142.08,72.48) 142.64,73.04 v2(143.28,73.04)
DGPU_PWR_EN: length 39.8
  L4 w0.089: v2(123.72,100.42) 123.21,100.93 123.21,113.24 123.59,113.63 123.59,115.66 124.15,116.22 124.15,118.96 124.45,119.26 v2(124.71,119.26)
  BOTTOM w0.089: PR8260.1 125.83,119.72 125.17,119.72 v2(124.71,119.26) 124.51,119.06 124.51,115.45 124.68,115.28 PQ8306.2 125.75,115.28 126.13,114.9 PR8331.1 ; R8308.1 121.74,91.15 R8307.2 121.81,93.36 Q8301.D 121.74,94.01 120.16,95.59 120.16,96.86 v1(121.91,98.61) v2(123.72,100.42)
DGPU_PWR_EN#: length 77.8
  TOP w0.089: RN2009.3 120.51,36.34 120.45,36.28 120.45,34.86 120.84,34.47 121.18,34.47 v2(121.66,33.99)
  L3 w0.089: v2(121.66,33.99) 121.55,34.1 121.55,38.95 121.58,38.98 121.58,39.61 121.59,39.61 121.59,40.58 121.55,40.62 121.55,41.41 122.15,42.01 122.15,44.81 123.73,46.39 123.73,47.68 123.39,48.02 115.38,48.02 114.6,48.81 114.6,53.38 114.6,53.38 114.6,64.12 114.73,64.24 114.73,64.73 114.6,64.86 114.6,71.72 115.65,72.77 115.65,75.08 116.31,75.74 116.31,77.08 116.69,77.46 116.69,78.76 117.68,79.74 117.68,83.34 116.86,84.16 116.35,84.16 v2(115.97,84.54)
  BOTTOM w0.089: Q8301.G 119.6,91.66 R8308.2 120.16,91.1 120.16,86.96 v1(119.57,86.36) 118.71,85.5 116.93,85.5 v2(115.97,84.54) ; CPU1.U1 121.9,34.23 v2(121.66,33.99)
DGPU_PWR_EN_L: length 3.5
  BOTTOM w0.089: PQ8306.6 123.37,115.93 122.68,116.62 v1(122.58,116.62) PR8317.1 123.01,115.28 PQ8306.5
DGPU_PWR_EN_R: length 114.6
  L3 w0.089: v2(122.07,86.19) 124.61,88.73 124.61,100.16 v2(123.72,101.05)
  L4 w0.089: v2(122.07,86.19) 122.49,86.61 134.11,86.61 135.99,84.73 137.77,84.73 138.72,84.73 139.54,83.91 139.54,79.28 140.71,78.11 142.29,76.53 147.47,76.53 149.68,74.32 152.49,74.32 152.86,74.69 158.78,74.69 158.96,74.52 162.39,74.52 162.59,74.72 163.72,74.72 163.92,74.52 164.48,74.52 167.66,71.34 173.52,71.34 174.22,70.64 174.84,70.64 175.15,70.95 175.15,71.33 175.53,71.72 176.38,71.72 176.8,72.14 181.63,72.14 183.49,74 184.3,74 185.7,75.4 v2(186.08,75.4) ; v2(127.68,116.39) 126.46,116.39 124.09,114.02 124.09,101.42 v2(123.72,101.05)
  BOTTOM w0.089: R8306.1 128.09,115.99 v2(127.68,116.39) 127.6,116.32 C8310.1 127.6,115.3 PR8331.2 ; v1(186.68,75.4) v2(186.08,75.4) 185.84,75.63 U8301.5
DGPU_PWROK: length 332.5
  TOP w0.089: v2(134.68,36.98) 136.37,35.29 136.37,32.22 138.99,29.6 151.78,29.6 152.9,28.49 153.25,28.49 153.9,27.84 164.6,27.84 170.1,22.34 170.1,19.44 173.63,15.91 175.99,15.91 v1(177.07,16.99) 177.63,17.54 v2(177.63,17.54) ; v2(163.6,18.25) 163.34,18.5 R2471.1
  L3 w0.089: v2(122.04,101.56) 121.81,101.33 121.81,98.13 122.07,97.88 v2(122.07,87.84)
  L4 w0.089: v2(122.07,87.84) 123.21,87.84 123.95,87.11 134.32,87.11 136.2,85.23 137.56,85.23 143.27,85.23 144.08,86.04 147.06,86.04 148.2,87.18 148.2,89.36 148.74,89.9 150.09,89.9 150.29,89.7 150.29,88.74 152.43,86.61 154.32,86.61 154.66,86.27 155.1,86.27 157.45,83.92 157.45,77.58 158.19,76.84 158.19,75.82 159.12,74.9 162.23,74.9 162.43,75.1 163.88,75.1 164.08,74.9 165.24,74.9 166.63,73.51 172.88,73.51 173.41,74.03 173.73,74.03 174.21,74.51 175.66,74.51 178.77,77.61 178.77,80.41 179.67,81.32 180.43,81.32 182.36,79.39 182.82,79.39 183.64,78.57 185.37,78.57 187.02,76.92 189,76.92 190.48,75.44 198.39,75.44 200.1,73.73 203.46,73.73 207.16,70.04 207.16,67.91 207.92,67.14 v2(208.68,67.14)
  L6 w0.089: v2(137.87,120.56) 137.87,120.69 136.59,121.97 126.6,121.97 125.37,120.74 123.72,120.74 123.08,120.1 123.08,115.4 123.46,115.02 123.46,102.98 v2(122.04,101.56) ; v2(208.68,67.14) 209.56,66.27 209.56,66.22 209.57,66.21 209.57,64.43 208.98,63.84 208.98,60.07 208.43,59.52 208.43,58.91 211.24,56.1 211.24,44.87 210.97,44.6 210.97,40.48 211.35,40.1 211.35,33.14 211.09,32.88 211.09,32.32 211.35,32.06 211.35,30.95 211.98,30.31 211.98,28.92 211.49,28.43 211.49,23.91 211.8,23.61 211.8,22.29 211.49,21.98 211.49,20.69 210.22,19.41 207.71,19.41 207.43,19.7 190.17,19.7 189.67,19.19 178.87,19.19 177.63,17.95 v2(177.63,17.54) 175.76,15.67 166.56,15.67 164.46,17.77 164.08,17.77 v2(163.6,18.25)
  BOTTOM w0.089: CPU1.C8 129.9,38.97 130,38.88 130.94,38.88 133.74,36.08 134.21,36.08 134.68,36.55 v2(134.68,36.98) ; v2(137.87,120.56) 137.94,120.48 PR8203.2 R8305.1 138.22,119.72 138.13,119.81 137.3,119.81 137.29,119.8 136.93,119.8 136.93,119.8 PU8201.13
DGPU_RXN_C_CPU_TXN0: length 5.3
  BOTTOM w0.102: 147.8,78.27 148.41,78.27 149.08,77.6 GPU1.AG7 ; 147.8,78.27 v1(147.8,78.45) ; 147.8,78.27 147.64,78.27 147.42,78.04 147.42,77.78 C1606.1
DGPU_RXN_C_CPU_TXN1: length 6.7
  BOTTOM w0.102: C1608.1 148.33,80.25 149.02,80.25 149.42,79.84 ; 149.42,79.84 149.61,79.66 149.61,78.51 149.76,78.36 151.77,78.36 152.16,77.97 152.5,77.97 GPU1.AE7 ; 149.42,79.84 v1(149.55,79.97)
DGPU_RXN_C_CPU_TXN2: length 6.4
  BOTTOM w0.102: C1610.1 148.53,81.75 148.64,81.65 148.64,81.32 148.74,81.22 149.09,81.22 ; 149.09,81.22 149.75,81.22 150.13,80.83 150.13,79.93 151.2,78.87 151.85,78.87 151.99,79.01 152.27,79.01 152.35,79.09 GPU1.AF9 ; 149.09,81.22 v1(149.09,81.39)
DGPU_RXN_C_CPU_TXN3: length 6.4
  BOTTOM w0.102: 149.09,83.01 148.57,83.01 C1612.1 ; 149.09,83.01 v1(149.09,83.17) ; 149.09,83.01 150.24,83.01 150.74,82.5 150.74,80.27 151.22,79.79 151.45,79.79 151.55,79.9 GPU1.AG10
DGPU_RXP_C_CPU_TXP0: length 5.4
  BOTTOM w0.102: GPU1.AG6 151.17,76.8 151.07,76.9 151.07,77.28 150.98,77.37 149.14,77.37 ; 149.14,77.37 148.98,77.37 148.31,78.04 147.74,78.04 147.65,77.95 147.65,77.78 C1605.1 ; 149.14,77.37 v1(149.14,77.23)
DGPU_RXP_C_CPU_TXP1: length 6.7
  BOTTOM w0.102: v1(149.22,78.68) 149.38,78.68 ; 149.38,78.68 149.38,78.42 149.67,78.13 151.67,78.13 152.21,77.6 GPU1.AF7 ; 149.38,78.68 149.38,79.56 148.92,80.02 148.71,80.02 148.64,79.95 148.64,79.82 148.76,79.7 148.76,79.43 148.69,79.36 148.41,79.36 C1607.1
DGPU_RXP_C_CPU_TXP2: length 6.5
  BOTTOM w0.102: GPU1.AE9 152.34,78.78 152.08,78.78 151.94,78.64 151.1,78.64 149.91,79.84 149.91,80.74 149.66,80.99 C1609.1
DGPU_RXP_C_CPU_TXP3: length 6.2
  BOTTOM w0.102: C1611.1 148.57,82.78 150.15,82.78 150.52,82.41 150.52,80.17 151.12,79.57 151.45,79.57 151.55,79.46 GPU1.AG9
DGPU_TXN_CPU_RXN0: length 16.6
  TOP w0.102: v2(155.19,78.88) 155.6,78.48 v1(155.6,78.47)
  L4 w0.14: v2(145.94,78.07) 145.94,77.94 146.39,77.49 148.59,77.49 148.73,77.63 148.73,78.15 149.03,78.45 149.53,78.45 149.82,78.15 149.82,77.63 149.96,77.49 150.45,77.49 150.69,77.73 150.69,78.36 151.05,78.71 151.55,78.71 151.91,78.36 151.91,77.63 152.12,77.43 152.46,77.43 152.66,77.63 152.66,79.19 153.03,79.56 153.93,79.56 153.95,79.55 154.52,79.55 v2(155.19,78.88)
  BOTTOM w0.102: C7302.2 v2(145.94,78.07) ; GPU1.AB9 v2(155.19,78.88)
DGPU_TXN_CPU_RXN1: length 16.9
  TOP w0.102: v1(155.67,80.02) 155.21,80.48 v2(155.19,80.48)
  L4 w0.14: v2(145.1,79.36) 145.1,79.54 144.68,79.96 144.02,79.96 143.78,79.72 143.78,79.08 144.03,78.84 147.74,78.84 148.5,79.6 151.29,79.6 151.79,80.1 154.13,80.1 154.17,80.05 154.76,80.05 v2(155.19,80.48)
  BOTTOM w0.102: GPU1.AC10 154.79,80.08 v2(155.19,80.48) ; v2(145.1,79.36) 145.1,79.41 144.85,79.67 144.57,79.67 C7304.2
DGPU_TXN_CPU_RXN2: length 17.4
  TOP w0.102: v2(154.35,80.48) 153.66,80.48 v1(153.56,80.58)
  L4 w0.14: v2(154.35,80.48) 154.06,80.77 153.49,80.77 153.19,80.47 150.4,80.47 146.89,83.98 145.9,83.98 145.46,83.54 144.56,83.54 144.18,83.16 144.18,81.91 144.33,81.76 144.55,81.76 144.68,81.9 144.68,82.01 v2(144.93,82.26)
  BOTTOM w0.102: C7306.2 143.99,82.03 144.26,81.75 144.57,81.75 144.93,82.11 v2(144.93,82.26) ; v2(154.35,80.48) 154.75,80.88 GPU1.AC11
DGPU_TXN_CPU_RXN3: length 14.3
  TOP w0.102: v1(155.49,82.64) 155.49,82.46 v2(155.19,82.16)
  L4 w0.14: v2(155.19,82.16) 154.8,82.16 153.94,83.02 149.24,83.02 146.76,85.5 145.76,85.5 145.06,84.8 v2(144.8,84.8)
  BOTTOM w0.102: GPU1.AB12 v2(155.19,82.16) ; v2(144.8,84.8) 144.8,84.31 144.65,84.16 C7308.2
DGPU_TXP_CPU_RXP0: length 16.5
  TOP w0.102: v2(154.35,78.88) 154.35,78.88 v1(153.94,78.47)
  L4 w0.14: v2(145.18,78.07) 145.63,77.62 145.89,77.62 146.28,77.22 148.7,77.22 149,77.52 149,78.04 149.14,78.18 149.42,78.18 149.56,78.04 149.56,77.52 149.85,77.22 150.56,77.22 150.96,77.62 150.96,78.25 151.16,78.45 151.44,78.45 151.65,78.25 151.65,77.52 152,77.16 152.57,77.16 152.93,77.52 152.93,79.08 153.14,79.3 153.82,79.3 153.84,79.28 154.13,79.28 154.35,79.06 v2(154.35,78.88)
  BOTTOM w0.102: GPU1.AC9 v2(154.35,78.88) ; C7301.2 v2(145.18,78.07)
DGPU_TXP_CPU_RXP1: length 16.9
  TOP w0.102: v2(155.19,79.68) 154.62,79.68 v1(154.53,79.59)
  L4 w0.14: v2(155.19,79.68) 155.08,79.79 154.06,79.79 154.02,79.83 151.9,79.83 151.4,79.34 148.61,79.34 147.85,78.57 143.91,78.57 143.52,78.97 143.52,79.83 143.91,80.22 v2(145.05,80.22)
  BOTTOM w0.102: v2(145.05,80.22) 145.03,80.25 C7303.2 ; v2(155.19,79.68) GPU1.AB10
DGPU_TXP_CPU_RXP2: length 17.5
  TOP w0.102: v2(154.35,81.32) 154.15,81.52 v1(154.15,82.05)
  L4 w0.14: v2(144.93,81.49) 144.22,81.49 143.91,81.8 143.91,83.27 144.45,83.81 145.35,83.81 145.79,84.25 147,84.25 150.52,80.73 153.08,80.73 153.38,81.03 154.06,81.03 v2(154.35,81.32)
  BOTTOM w0.102: C7305.2 144.11,81.49 v2(144.93,81.49) ; v2(154.35,81.32) GPU1.AD11
DGPU_TXP_CPU_RXP3: length 14.4
  TOP w0.102: v1(154.76,80.94) 154.77,80.94 v2(155.17,81.34)
  L4 w0.14: v2(155.17,81.34) 155.17,81.42 153.83,82.75 149.13,82.75 146.65,85.23 145.87,85.23 145.26,84.62 v2(145.26,84.36)
  BOTTOM w0.102: C7307.2 144.88,83.98 v2(145.26,84.36) ; v2(155.17,81.34) GPU1.AC12
DGPUHOT#: length 222.6
  TOP w0.089: R2477.1 162.96,10.12 163.85,9.23 v2(163.85,8.98)
  L4 w0.089: v2(163.85,8.98) 163.85,8.52 165.17,7.2 185.44,7.2 186.83,5.81 193.57,5.81 196.36,8.6 203.98,8.6 205.51,10.12 215.39,10.12 220.21,14.95 221.51,14.95 221.89,15.33 221.89,16.22 220.87,17.23 220.87,21.42 222.53,23.08 222.53,42.65 218.66,46.52 218.66,47.03 220.62,48.98 220.62,50.69 218.35,52.95 218.35,54.3 217.52,55.13 217.52,57.46 213.72,61.26 213.72,63.74 210.73,66.72 206.69,66.72 205.13,68.29 205.13,69.94 202.31,72.76 197.28,72.76 196.19,71.67 193.87,71.67 192.91,72.62 186.69,72.62 186.08,73.24 185.31,73.24 185.01,73.54 183.61,73.54 182.02,71.95 176.88,71.95 176.14,71.21 v2(175.66,71.21) 175.66,71.08 175.03,70.45 174.14,70.45 173.5,71.08 167.53,71.08 165.12,73.49 163.22,73.49 162.38,74.33 158.88,74.33 158.83,74.38 152.86,74.38 152.58,74.1 149.4,74.1 148.23,75.27 144.55,75.27 143.78,76.03 142.39,76.03 139.21,79.21 139.21,82.04 v2(138.65,82.6)
  BOTTOM w0.089: v2(163.85,8.98) 163.98,9.1 v1(163.98,9.61) ; PQ4402.D 138.69,82.56 v2(138.65,82.6) ; R7605.2 176.12,71.21 v2(175.66,71.21) 175.41,71.21 174.63,71.99 174.63,72.47 174.84,72.68 174.84,74.57 173.95,75.46 172.16,75.46 171.79,75.82 171.79,75.99 171.48,76.31 171.36,76.31 170.91,76.76 170.91,76.95 170.55,77.3 GPU1.D7
DMIC_CLK: length 188.6
  TOP w0.089: R2721.1 29.76,16.98 30.25,16.98 C2738.2 30.01,17.57 28.35,17.57 v2(28.01,17.23) ; v2(106.97,97.79) 106.97,99.01 108.86,100.9 v1(108.91,100.9) 109.46,101.45 111.89,101.45 112.32,101.02 EC5504.1 112.32,99.93 RN5503.4
  L3 w0.127: v2(106.97,97.79) 106.97,98.37 106.32,99.02 88.48,99.02 87.97,98.51 83.01,98.51 80.79,100.74 78.02,100.74 75.63,103.12 68.96,103.12 67.39,101.55 67.39,97.6 67.51,97.48 67.51,96.15 66.12,94.77 63.58,94.77 62.5,95.85 62.5,96.44 62.5,96.86 60.47,98.89 58.95,98.89 57.55,97.5 52.22,97.5 49.87,95.15 48.34,95.15 47.58,95.91 43.09,95.91 42.18,96.82 31.86,96.82 30.72,95.68 28.36,95.68 27.01,94.34 27.01,86.18 28.02,85.16 28.02,75.27 27.71,74.95 27.71,73.24 28.6,72.35 28.6,65.24 26.82,63.46 26.82,61.43 26.8,61.41 26.8,61.41 25.42,60.03 25.42,44.82 26.56,43.68 26.56,34.66 26.05,34.15 26.05,24.14 27.2,23 27.2,18.05 v2(28.01,17.23)
DMIC_CLK_C: length 3
  TOP w0.089: v2(113.09,97.49) 113.09,97.66 v1(112.72,98.03) 112.3,98.45 RN5503.1
  BOTTOM w0.089: v2(113.09,97.49) 113.06,97.49 112.85,97.27 LCD1.46
DMIC_CLK_R: length 4
  TOP w0.089: HDA27.5 27.73,14.47 27.98,14.72 27.98,15.13 27.97,15.14 v1(27.97,16.12) 27.97,16.38 28.64,17.06 R2721.2
DMIC_DATA: length 189.9
  TOP w0.089: R2738.1 29.76,16.37 29.52,16.62 28.58,16.62 28.39,16.43 v2(28.39,15.56) ; RN5503.3 112.93,99.93 EC5503.1 112.93,101.22 112.3,101.85 v1(110.76,101.85) 109.33,101.85 106.33,98.86 v2(106.33,97.8)
  L3 w0.127: v2(106.33,97.8) 106.33,98 105.8,98.53 88.53,98.53 88.13,98.13 82.86,98.13 80.63,100.35 77.86,100.35 75.49,102.72 69.12,102.72 67.77,101.37 67.77,97.76 67.9,97.62 67.9,95.15 67.13,94.39 63.43,94.39 62.12,95.69 62.12,96.6 60.4,98.32 58.92,98.32 57.71,97.12 52.38,97.12 50.03,94.77 48.19,94.77 47.55,95.4 43.06,95.4 42.07,96.39 31.96,96.39 30.87,95.3 28.51,95.3 27.39,94.18 27.39,86.34 28.4,85.32 28.4,74.95 28.1,74.65 28.1,73.48 28.98,72.6 28.98,62.31 27.77,61.11 27.77,60.74 27.96,60.55 27.96,59.41 27.44,58.89 26.44,58.89 26.04,58.5 26.04,44.74 26.94,43.84 26.94,34.5 26.52,34.09 26.52,24.21 28.51,22.23 28.51,15.67 v2(28.39,15.56)
DMIC_DATA_C: length 3.8
  TOP w0.089: RN5503.2 113.81,98.14 v2(113.81,97.62) 113.86,97.57 v1(113.86,96.94)
  BOTTOM w0.089: v2(113.81,97.62) 113.81,97.32 113.35,96.86 LCD1.47
DMIC_DATA_R: length 3.5
  TOP w0.089: R2738.2 28.9,15.46 v1(28.42,14.98) 28.42,14.76 27.73,14.07 HDA27.4
DOCK_USB_EN_A: length 24.7
  TOP w0.089: v2(35.2,25.11) 35.07,25.24 U3701.26 ; R3859.2 30.07,45.43 v1(30.88,45.43) 31.52,45.43 v2(31.9,45.05)
  L6 w0.089: v2(31.9,45.05) 32.79,44.16 32.79,42.51 33.38,41.92 33.38,39.66 35.71,37.33 35.71,31.52 35.82,31.42 35.82,25.72 v2(35.2,25.11)
DOCK_USB_EN_B: length 21.3
  TOP w0.089: v2(37.74,45.38) v1(39.14,45.38) 39.56,45.38 39.82,45.12 R3860.2 ; U3701.36 38.25,29.04 v2(38.5,28.79)
  L3 w0.089: v2(38.5,28.79) 38.5,35.01 39.14,35.65 39.14,43.99 v2(37.74,45.38)
DP_DATA0_N: length 136.8
  TOP w0.102: v1(34.72,68.9) 34.82,68.79 ; 34.82,68.79 35.51,69.48 40.92,69.48 42.22,68.18 42.9,68.18 v2(43.2,68.48) ; 34.82,68.79 34.31,68.28 33.52,68.28 C5731.1
  L6 w0.127: v2(128.36,66.35) 128.61,66.6 129.54,66.6 130.07,67.13 130.07,67.65 130.54,68.12 130.54,71.5 128.4,73.63 127.64,73.63 125.73,75.54 125.23,75.54 124.37,76.4 124.37,78.26 120.34,82.28 120.34,83.47 117.85,85.96 117.85,87.14 112.54,92.45 52.25,92.45 46.2,86.39 46.2,74.71 45.11,73.62 45.11,68.92 44.42,68.24 43.45,68.24 v2(43.2,68.48)
  BOTTOM w0.102: v2(128.36,66.35) 128.36,66.26 CPU1.E55
DP_DATA0_N_R: length 5.7
  TOP w0.102: C5731.2 32.06,68.29 30.07,68.29 ; 30.07,68.29 28.21,68.29 27.83,67.91 27.49,67.91 U5701.A7 ; 30.07,68.29 v1(30.07,68.46)
DP_DATA0_P: length 136.7
  TOP w0.102: 38.6,69.25 35.6,69.25 34.4,68.05 33.52,68.05 C5737.1 ; 38.6,69.25 40.82,69.25 42.12,67.95 42.9,67.95 v2(43.2,67.65) ; 38.6,69.25 v1(38.6,69.1)
  L6 w0.127: v2(43.2,67.65) 43.52,67.97 44.53,67.97 45.37,68.81 45.37,73.51 46.46,74.6 46.46,86.28 52.36,92.18 112.43,92.18 117.58,87.03 117.58,85.85 120.07,83.36 120.07,82.17 124.1,78.15 124.1,76.29 125.12,75.27 125.62,75.27 127.53,73.37 128.29,73.37 130.27,71.39 130.27,68.23 129.8,67.76 129.8,67.24 129.43,66.86 128.21,66.86 v2(127.71,66.36)
  BOTTOM w0.102: v2(127.71,66.36) 127.71,66.26 CPU1.F55
DP_DATA0_P_R: length 5.7
  TOP w0.102: 31.34,68.06 28.31,68.06 27.93,67.68 27.49,67.68 U5701.A8 ; 31.34,68.06 32.05,68.06 C5737.2 ; 31.34,68.06 v1(31.34,67.88)
DP_DATA1_N: length 137.9
  TOP w0.102: v2(45.84,69.72) 45.54,69.42 41.98,69.42 41.21,70.19 33.34,70.19 32.96,69.81 ; 32.96,69.81 32.76,69.61 31.88,69.61 C5734.1 ; 32.96,69.81 v1(32.84,69.94)
  L6 w0.127: v2(128.24,68.19) 127.77,68.66 126.52,68.66 125.6,69.57 125.6,69.75 125.99,70.14 125.99,70.54 125.56,70.96 125.16,70.96 124.78,70.58 124.6,70.58 124.24,70.94 124.24,71.78 123.86,72.16 123.86,72.57 124.24,72.95 124.24,74.37 123.1,75.51 123.1,77.29 118.65,81.73 118.65,82.88 116.3,85.23 116.3,86.5 111.9,90.9 101.73,90.9 100.46,89.62 87.86,89.62 87.73,89.75 87.73,90.3 87.45,90.59 86.85,90.59 86.57,90.3 86.57,89.75 86.44,89.62 85.75,89.62 84.47,90.9 83.31,90.9 83.03,90.61 83.03,89.6 82.94,89.52 82.48,89.52 82.39,89.6 82.39,90.61 82.11,90.9 81.46,90.9 81.17,90.62 81.17,89.99 81.05,89.86 80.67,89.86 80.54,89.99 80.54,90.62 80.26,90.9 52.91,90.9 48.52,86.51 48.52,70.97 47.28,69.72 v2(45.84,69.72)
  BOTTOM w0.102: CPU1.E58 127.99,67.94 v2(128.24,68.19)
DP_DATA1_N_R: length 4
  TOP w0.102: 29.97,69.56 30.59,69.56 C5734.2 ; 29.97,69.56 v1(29.97,69.73) ; 29.97,69.56 27.44,69.56 U5701.A5
DP_DATA1_P: length 137.8
  TOP w0.102: 44.5,69.19 41.89,69.19 41.12,69.96 33.44,69.96 32.86,69.38 32.09,69.38 C5732.1 ; 44.5,69.19 45.54,69.19 v2(45.84,68.89) ; 44.5,69.19 v1(44.5,69.02)
  L6 w0.127: v2(45.84,68.89) 46.02,68.89 46.15,69.02 46.15,69.33 46.27,69.46 47.39,69.46 48.79,70.86 48.79,86.4 53.02,90.63 80.14,90.63 80.27,90.51 80.27,89.88 80.56,89.59 81.16,89.59 81.44,89.88 81.44,90.51 81.57,90.63 82,90.63 82.13,90.5 82.13,89.49 82.37,89.25 83.05,89.25 83.29,89.49 83.29,90.5 83.42,90.63 84.36,90.63 85.63,89.36 86.55,89.36 86.83,89.64 86.83,90.19 86.96,90.32 87.34,90.32 87.47,90.19 87.47,89.64 87.75,89.36 100.57,89.36 101.84,90.63 111.79,90.63 116.03,86.39 116.03,85.12 118.38,82.77 118.38,81.62 122.83,77.18 122.83,75.4 123.97,74.26 123.97,73.06 123.59,72.68 123.59,72.05 123.97,71.67 123.97,70.83 124.49,70.31 124.89,70.31 125.27,70.7 125.45,70.7 125.72,70.43 125.72,70.25 125.34,69.86 125.34,69.46 126.41,68.39 127.38,68.39 v2(127.6,68.16)
  BOTTOM w0.102: v2(127.6,68.16) 127.6,67.85 127.48,67.72 CPU1.F58
DP_DATA1_P_R: length 4
  TOP w0.102: C5732.2 30.49,69.33 28.57,69.33 ; U5701.A6 27.54,69.33 28.57,69.33 ; 28.57,69.33 v1(28.57,69.15)
DP_DATA2_N: length 138.6
  TOP w0.102: 32.56,71.11 32.89,71.11 33.01,70.98 41.47,70.98 41.9,70.55 43.06,70.55 v2(43.2,70.69) ; 32.56,71.11 31.99,71.11 C5727.1 ; 32.56,71.11 v1(32.56,71.28)
  L6 w0.127: v2(43.2,70.69) 43.32,70.57 44.08,70.57 44.33,70.83 44.33,73.99 45.42,75.08 45.42,86.71 51.93,93.22 112.86,93.22 118.63,87.46 118.63,86.33 121.12,83.84 121.12,82.7 124.25,79.56 128.67,75.14 129.06,74.75 129.06,73.73 131.72,71.08 131.72,69.55 131.23,69.06 131.23,68 130.87,67.64 130.87,67.11 129.75,65.99 129.18,65.99 128.79,65.59 127.78,65.59 v2(127.63,65.44)
  BOTTOM w0.102: CPU1.F53 127.63,65.27 v2(127.63,65.44)
DP_DATA2_N_R: length 4.4
  TOP w0.102: C5727.2 30.54,71.11 30.3,71.11 30.05,70.85 ; 30.05,70.85 29.8,70.6 29.43,70.6 28.92,71.11 27.49,71.11 U5701.A3 ; 30.05,70.85 v1(29.94,70.95)
DP_DATA2_P: length 138.6
  TOP w0.102: v2(43.21,70.04) 42.93,70.32 42.34,70.32 ; 42.34,70.32 41.8,70.32 41.37,70.75 32.92,70.75 32.79,70.88 31.99,70.88 C5728.1 ; 42.34,70.32 v1(42.34,70.14)
  L6 w0.127: v2(126.99,65.4) 127.21,65.61 127.21,65.62 127.46,65.86 128.67,65.86 129.07,66.25 129.64,66.25 130.6,67.22 130.6,67.75 130.96,68.11 130.96,69.17 131.45,69.66 131.45,70.97 128.8,73.62 128.8,74.64 125.67,77.76 124.06,79.38 120.85,82.59 120.85,83.73 118.36,86.22 118.36,87.35 112.75,92.96 52.04,92.96 45.69,86.6 45.69,74.97 44.6,73.87 44.6,70.72 44.19,70.31 43.48,70.31 v2(43.21,70.04)
  BOTTOM w0.102: CPU1.G53 126.99,65.28 v2(126.99,65.4)
DP_DATA2_P_R: length 4.4
  TOP w0.102: 28.57,70.88 27.49,70.88 U5701.A4 ; 28.57,70.88 v1(28.57,70.73) ; 28.57,70.88 28.82,70.88 29.33,70.37 29.89,70.37 30.4,70.88 30.54,70.88 C5728.2
DP_DATA3_N: length 139.2
  TOP w0.102: 43.38,72 45.52,72 v2(45.84,72.32) ; 43.38,72 43.11,72 42.8,71.69 33.5,71.69 32.48,72.71 31.99,72.71 C5733.1 ; 43.38,72 v1(43.38,72.17)
  L6 w0.127: v2(127.67,67.24) 127.89,67.46 128.55,67.46 129.89,68.8 129.89,71.38 128.53,72.74 125.73,72.74 125.13,73.35 125.13,74.62 123.73,76.02 123.73,77.8 119.43,82.1 119.43,83.24 117.08,85.59 117.08,86.82 112.22,91.67 92.27,91.67 91.99,91.39 91.99,90.52 91.86,90.4 91.48,90.4 91.35,90.52 91.35,91.39 91.07,91.67 52.58,91.67 47.75,86.84 47.75,86.07 47.62,85.95 47.26,85.95 46.97,85.66 46.97,85.06 47.26,84.78 47.62,84.78 47.75,84.65 47.75,81.75 47.62,81.62 47.27,81.62 46.98,81.34 46.98,80.74 47.27,80.46 47.62,80.46 47.75,80.33 47.75,79.95 47.62,79.82 47.27,79.82 46.98,79.54 46.98,78.93 47.27,78.65 47.62,78.65 47.75,78.52 47.75,78.14 47.62,78.02 47.27,78.02 46.98,77.73 46.98,77.13 47.27,76.85 47.62,76.85 47.75,76.72 47.75,73.21 46.65,72.11 46.04,72.11 v2(45.84,72.32)
  BOTTOM w0.102: CPU1.F56 127.67,67.14 v2(127.67,67.24)
DP_DATA3_N_R: length 4.4
  TOP w0.102: U5701.A1 27.49,72.71 28.65,72.71 ; v1(28.65,72.88) 28.65,72.71 ; 28.65,72.71 28.83,72.71 29.31,73.19 29.92,73.19 30.4,72.71 30.54,72.71 C5733.2
DP_DATA3_P: length 139.1
  TOP w0.102: v1(44.7,71.61) 44.7,71.77 ; 44.7,71.77 43.2,71.77 42.89,71.46 33.4,71.46 32.39,72.48 31.99,72.48 C5735.1 ; 44.7,71.77 45.52,71.77 v2(45.84,71.45)
  L6 w0.127: v2(127.02,67.25) 127.5,67.73 128.44,67.73 129.62,68.91 129.62,71.27 128.42,72.48 125.62,72.48 124.86,73.24 124.86,74.51 123.46,75.91 123.46,77.68 119.16,81.99 119.16,83.13 116.81,85.48 116.81,86.71 112.11,91.41 92.38,91.41 92.25,91.28 92.25,90.41 91.97,90.13 91.37,90.13 91.08,90.41 91.08,91.28 90.96,91.41 52.69,91.41 48.01,86.73 48.01,85.96 47.73,85.68 47.37,85.68 47.24,85.55 47.24,85.17 47.37,85.04 47.73,85.04 48.01,84.76 48.01,81.64 47.73,81.36 47.38,81.36 47.25,81.23 47.25,80.85 47.38,80.72 47.73,80.72 48.01,80.44 48.01,79.84 47.73,79.55 47.38,79.55 47.25,79.43 47.25,79.05 47.38,78.92 47.73,78.92 48.01,78.64 48.01,78.03 47.73,77.75 47.38,77.75 47.25,77.62 47.25,77.24 47.38,77.11 47.73,77.11 48.01,76.83 48.01,73.1 46.76,71.84 46.23,71.84 v2(45.84,71.45)
  BOTTOM w0.102: v2(127.02,67.25) 127.02,67.14 CPU1.G56
DP_DATA3_P_R: length 4.4
  TOP w0.102: C5735.2 30.54,72.48 30.3,72.48 29.96,72.82 ; 29.96,72.82 29.82,72.96 29.41,72.96 28.93,72.48 27.49,72.48 U5701.A2 ; 29.96,72.82 v1(29.87,72.73)
DPB_AUXN: length 159.8
  TOP w0.102: v1(35.91,66.28) v2(36.47,66.28) 36.47,66.48 36.59,66.61 36.8,66.61 36.8,66.61 37.26,66.15 37.26,65.21 36.85,64.81 C3802.1
  L6 w0.127: v2(36.47,66.28) 36.77,66.13 36.95,66.13 37.03,66.18 37.13,66.31 37.1,66.56 36.99,66.71 36.91,66.94 36.91,67.13 37.86,68.08 37.86,75.39 40.67,78.21 40.67,87.22 47.52,94.07 47.52,95.08 49.44,97 60.87,97 61.23,97.37 61.28,97.37 61.31,97.4 81.33,97.4 82.37,98.44 84.27,98.44 84.83,99.01 115.45,99.01 116.2,98.25 116.2,96.94 125.83,87.31 125.83,83.82 127.69,81.95 127.69,81.22 135.55,73.36 135.55,68.48 135.71,68.33 136.19,67.84 136.19,65.72 136.17,65.7 136.17,65.69 135.87,65.39 135.86,65.39 133.94,63.47 131.1,63.47 129.91,62.28 128.07,62.28 127.85,62.49 127.79,62.49 127.62,62.66 v2(127.58,62.69)
  BOTTOM w0.102: v2(127.58,62.69) 127.58,62.41 127.75,62.23 CPU1.E48
DPB_AUXN_C: length 4.6
  TOP w0.102: U3801.25 36.52,60.49 37.1,61.07 37.1,62.29 ; 37.1,62.29 v1(36.93,62.29) ; 37.1,62.29 37.1,62.75 R3801.2 36.72,63.28 C3802.2
DPB_AUXP: length 159.7
  TOP w0.102: v2(36.47,67.07) 36.91,66.81 36.93,66.8 36.95,66.78 37.49,66.25 37.49,65.77 ; 37.49,65.77 v1(37.65,65.77) ; 37.49,65.77 C3801.1
  L6 w0.127: v2(36.47,67.07) 37.59,68.19 37.59,75.5 40.41,78.32 40.41,87.33 47.25,94.18 47.25,95.19 49.33,97.27 60.76,97.27 61.15,97.66 81.21,97.66 82.26,98.7 84.16,98.7 84.72,99.27 115.56,99.27 116.47,98.36 116.47,97.05 126.09,87.42 126.09,83.93 127.96,82.06 127.96,81.33 131.38,77.91 135.82,73.47 135.82,68.59 136.46,67.95 136.46,67.73 136.46,65.61 136.44,65.59 136.44,65.58 135.98,65.12 135.97,65.12 134.05,63.2 131.21,63.2 130.03,62.01 127.95,62.01 127.74,62.22 127.53,62.22 127.3,62.34 v2(126.93,62.69)
  BOTTOM w0.102: CPU1.F48 v2(126.93,62.69)
DPB_AUXP_C: length 4.4
  TOP w0.102: 37.33,61.17 37.33,60.98 36.92,60.57 U3801.24 ; 37.33,61.17 v1(37.49,61.17) ; 37.33,61.17 37.33,62.6 R3802.2 37.49,63.28 C3801.2
DPEQ0_A1: length 7.9
  TOP w0.089: U3801.14 40.48,56.78 41.17,56.09 R3871.2 42.44,55.66 44.11,55.66 44.39,55.94 v1(45.03,55.94) 45.97,55.94 R3872.1
DPEQ1: length 5.6
  TOP w0.089: U3801.2 35.72,53.39 35.75,53.36 35.75,52.97 35.54,52.75 34.85,52.75 R3870.1 R3847.2 32.07,51.57 v1(31.9,51.75)
E71_TP: length 4
  BOTTOM w0.089: TP2313.1 127.15,78.83 127.15,78.07 128.3,76.91 CPU1.E71
EAPD#: length 2.7
  TOP w0.089: HDA27.2 27.78,13.27 v1(27.79,13.27) 28.19,13.27 28.72,13.8 R2737.2
EC_AGND: length 16.6
  TOP w0.203: KBC24.112 v2(150.44,9.04)
  BOTTOM w0.305: v2(150.44,9.04) 150.44,8.92 151.02,8.34 v1(151.91,8.34) 152.17,8.34 153.06,7.45 155.09,7.45 155.37,7.17 155.37,6.45 154.88,5.96 151.3,5.96 150.18,4.84 C2431.2 148.91,4.84 v2(147.59,3.52)
EC_SLP_S0IX#: length 3.8
  TOP w0.127: KBC24.88 141.63,12.58 v1(141.14,13.07) 140.69,13.07 R2478.2
EC_VCIN1#: length 5.7
  TOP w0.089: KBC24.126 156.04,7.01 156.36,6.69 158.44,6.69 v1(158.9,6.23) 159.53,5.6 R2496.1
ECVBAT: length 13
  TOP w0.203: KBC24.122 154.44,8.84 v2(154.58,8.98)
  L3 w0.508: v2(154.58,8.98) 154.61,9 154.61,9.24 154.98,9.61 158.26,9.61 158.64,9.23 158.65,9.23 159.02,8.86 159.02,8.85 159.53,8.34 v2(159.71,8.34)
  BOTTOM w0.508: v2(161.56,3.27) 161.44,3.39 161.43,3.39 159.71,5.11 v1(159.71,7.07) v2(159.71,8.34)
EDP_AUX: length 11
  TOP w0.102: v2(93.32,97.84) 93.54,98.05 93.54,100.56 92.91,101.18 89.17,101.18 88.76,101.6 ; 88.76,101.6 88.36,101.99 88.16,101.99 C5510.1 ; 88.76,101.6 v1(88.64,101.48)
  BOTTOM w0.102: LCD1.7 93.35,96.85 93.54,97.04 93.54,97.63 v2(93.32,97.84)
EDP_AUX#: length 11.2
  TOP w0.102: v1(93.54,101.1) 93.43,100.99 ; 93.43,100.99 93.01,101.41 89.27,101.41 88.46,102.22 87.96,102.22 C5511.1 ; 93.43,100.99 93.77,100.65 93.77,98.07 v2(93.99,97.84)
  BOTTOM w0.102: v2(93.99,97.84) 93.77,97.61 93.77,96.97 93.85,96.88 LCD1.8
EDP_AUX_DN: length 103.2
  TOP w0.102: v1(85.75,102.73) 85.75,102.18 v2(85.8,102.13) 86.08,101.85 86.35,101.85 C5511.2
  L6 w0.127: v2(127.66,60.82) 127.88,60.59 127.89,60.59 129.61,58.87 132.7,58.87 133.17,59.34 134.81,59.34 135.63,60.15 136.65,60.15 140.46,63.96 140.46,67.5 141.14,68.18 141.14,75.2 137.93,78.41 137.21,78.41 136.87,78.75 136.87,84.23 136.87,85.52 133.88,88.51 130.55,88.51 123.72,95.34 123.72,99.02 119.75,102.99 88.47,102.99 87.61,102.13 v2(85.8,102.13)
  BOTTOM w0.102: v2(127.66,60.82) 127.99,60.48 CPU1.E45
EDP_AUX_DP: length 103.7
  TOP w0.102: C5510.2 86.08,101.62 v2(85.8,101.34) 85.91,101.34 v1(86.51,100.75)
  L6 w0.127: v2(126.99,60.82) 127.41,61.24 127.83,61.24 128.07,60.99 128.07,60.78 129.72,59.13 132.59,59.13 133.06,59.6 134.7,59.6 135.52,60.42 136.54,60.42 140.19,64.07 140.19,67.61 140.88,68.29 140.88,75.08 137.82,78.14 137.1,78.14 136.6,78.64 136.6,84.34 136.6,85.41 133.77,88.24 130.44,88.24 123.45,95.23 123.45,98.91 119.64,102.72 88.58,102.72 87.72,101.87 86.25,101.87 85.8,101.41 v2(85.8,101.34)
  BOTTOM w0.102: CPU1.F45 127.34,60.47 v2(126.99,60.82)
EDP_COMP: length 0.5
  BOTTOM w0.305: CPU1.E52 127.68,64.37 v2(127.68,64.48)
  vias: v1(126.13,64.48)
EDP_DISP_UTIL: length 2.4
  TOP w0.089: v2(131.29,64.09) 130.33,64.09 TP801.1
  BOTTOM w0.089: v2(131.29,64.09) 131.16,63.96 130.42,63.96 CPU1.B52
EDP_HPD: length 91.1
  TOP w0.089: v1(96.06,89.99) 95.87,90.18 v2(95.47,90.18)
  L3 w0.089: v2(95.47,90.18) 95.47,92.37 98.9,95.8 108.38,95.8 119.07,85.1 119.07,78.2 118.61,77.74 118.61,77.34 118.72,77.24 118.72,74.59 117.24,73.11 117.24,69.94 116.53,69.23 116.53,66.24 115.34,65.05 115.34,63.99 115.31,63.96 115.31,49.93 115.99,49.26 123.05,49.26 124.36,47.95 124.36,45.21 124.11,44.97 124.11,43.53 123.65,43.06 123.65,42.25 123.74,42.16 123.74,41.13 124.27,40.6 v2(124.27,40.54)
  BOTTOM w0.089: v2(95.47,90.18) 95.47,89.14 R5506.2 94.62,89.13 93.8,89.13 93.62,89.32 RN5502.7 ; CPU1.L10 v2(124.27,40.54)
EDP_HPD_CONN: length 11.3
  TOP w0.089: v1(94.18,90.24) 94.19,90.23 v2(94.76,90.23)
  L3 w0.089: v2(97.1,95.24) 94.76,92.9 v2(94.76,90.23)
  BOTTOM w0.089: v2(97.1,95.24) 99.46,95.24 100.35,96.13 LCD1.21 ; v2(94.76,90.23) 95.04,89.95 R5506.1
EDP_TX0: length 5.7
  TOP w0.102: v2(99.91,97.84) 99.7,98.05 99.7,98.5 100.15,98.94 102.05,98.94 ; 102.05,98.94 102.59,98.94 C5509.1 ; 102.05,98.94 v1(102.05,98.79)
  BOTTOM w0.102: v2(99.91,97.84) 99.85,97.79 LCD1.20
EDP_TX0#: length 6.1
  TOP w0.102: 100.88,99.17 100.05,99.17 99.47,98.59 99.47,98.08 v2(99.24,97.84) ; 100.88,99.17 102.56,99.17 C5506.1 ; 100.88,99.17 v1(100.88,99.33)
  BOTTOM w0.102: v2(99.24,97.84) 99.35,97.73 LCD1.19
EDP_TX0_DN: length 83.5
  TOP w0.102: v1(105,98.72) 104.87,98.59 ; 104.87,98.59 107.39,96.07 108.08,96.07 108.32,95.84 108.32,95.29 108.42,95.19 108.72,95.19 108.83,95.29 108.83,95.84 109.06,96.07 109.56,96.07 109.79,95.84 109.79,95.29 109.89,95.19 110.2,95.19 110.3,95.29 110.3,95.84 110.53,96.07 111.03,96.07 111.26,95.84 111.26,95.29 111.37,95.19 111.67,95.19 111.77,95.29 111.77,95.84 112.01,96.07 113.42,96.07 113.65,95.84 113.65,95.16 113.76,95.06 114.06,95.06 114.16,95.16 114.16,95.84 114.4,96.07 114.89,96.07 115.13,95.84 115.13,93.81 115.25,93.69 115.51,93.69 115.64,93.81 115.64,95.84 115.87,96.07 116.54,96.07 116.78,95.84 116.78,94.07 116.91,93.94 117.16,93.94 117.29,94.07 117.29,95.84 117.52,96.07 118.39,96.07 118.85,96.53 118.85,97.6 v2(118.65,97.8) ; 104.87,98.59 104.27,99.19 104.02,99.19 C5506.2
  L6 w0.127: v2(118.65,97.8) 118.93,97.52 118.93,96.41 129.26,86.09 129.26,81.85 133.37,77.74 136.66,74.45 137.49,74.45 137.78,74.15 137.78,64.95 135.58,62.75 135.25,62.75 v2(135.09,62.9)
  BOTTOM w0.102: v2(135.09,62.9) 135.04,62.85 134.22,62.85 132.93,61.56 129.9,61.56 129.62,61.84 CPU1.C47
EDP_TX0_DP: length 83.9
  TOP w0.102: v1(106.73,96.2) 106.83,96.31 ; 106.83,96.31 104.18,98.96 104.02,98.96 C5509.2 ; 106.83,96.31 107.29,95.85 107.99,95.85 108.09,95.74 108.09,95.19 108.32,94.96 108.82,94.96 109.05,95.19 109.05,95.74 109.16,95.85 109.46,95.85 109.56,95.74 109.56,95.19 109.8,94.96 110.29,94.96 110.53,95.19 110.53,95.74 110.63,95.85 110.93,95.85 111.04,95.74 111.04,95.19 111.27,94.96 111.77,94.96 112,95.19 112,95.74 112.1,95.85 113.32,95.85 113.43,95.74 113.43,95.07 113.66,94.83 114.16,94.83 114.39,95.07 114.39,95.74 114.49,95.85 114.8,95.85 114.9,95.74 114.9,93.72 115.16,93.46 115.6,93.46 115.86,93.72 115.86,95.74 115.97,95.85 116.45,95.85 116.55,95.74 116.55,93.97 116.81,93.71 117.25,93.71 117.51,93.97 117.51,95.74 117.62,95.85 118.48,95.85 119.08,96.44 119.08,97.4 v2(119.48,97.8)
  L6 w0.127: v2(119.48,97.8) 119.2,97.52 119.2,96.52 129.52,86.2 129.52,81.96 133.63,77.85 136.77,74.71 137.6,74.71 138.05,74.26 138.05,64.84 135.69,62.48 134.73,62.48 v2(134.67,62.42)
  BOTTOM w0.102: CPU1.C46 130.01,61.27 130.07,61.33 133.02,61.33 134.26,62.57 134.51,62.57 v2(134.67,62.42)
EDP_TX1: length 8.9
  TOP w0.102: v2(98.41,97.84) 97.98,98.28 97.98,99.3 99.2,100.52 100.22,100.52 ; C5504.1 102.59,100.52 100.22,100.52 ; 100.22,100.52 v1(100.22,100.37)
  BOTTOM w0.102: v2(98.41,97.84) 98.08,97.51 98.08,97.22 98.15,97.14 98.26,97.14 98.35,97.06 LCD1.17
EDP_TX1#: length 8.9
  TOP w0.102: v2(97.75,97.84) 97.75,99.4 99.11,100.75 102.05,100.75 ; v1(102.05,100.93) 102.05,100.75 ; 102.05,100.75 102.56,100.75 C5501.1
  BOTTOM w0.102: v2(97.75,97.84) 97.85,97.75 LCD1.16
EDP_TX1_DN: length 80.6
  TOP w0.102: 104.8,100.92 104.97,101.1 104.97,101.76 v2(104.69,102.04) ; 104.8,100.92 104.65,100.77 104.01,100.77 C5501.2 ; 104.8,100.92 v1(104.67,101.05)
  L6 w0.127: v2(104.69,102.04) 104.93,101.8 104.93,101.63 105.23,101.33 119.89,101.33 122.44,98.78 122.44,95.1 130.07,87.46 133.45,87.46 135.83,85.08 135.83,84.66 135.83,84.66 135.83,77.77 136.23,77.37 137.5,77.37 139.33,75.53 139.33,72.36 140.1,71.59 140.1,68.61 139.42,67.93 139.42,64.39 136.22,61.2 135.3,61.2 135.05,60.95 134.22,60.12 132.87,60.12 132.36,59.62 130.56,59.62 129.5,60.68 129.14,60.68 v2(128.58,61.24)
  BOTTOM w0.102: v2(128.58,61.24) 128.62,61.27 CPU1.D46
EDP_TX1_DP: length 81
  TOP w0.102: C5504.2 104.03,100.54 104.74,100.54 105.2,101 105.2,101.79 v2(105.46,102.04) 105.63,102.22 v1(105.63,102.58)
  L6 w0.127: v2(105.46,102.04) 105.33,102.04 105.2,101.92 105.2,101.74 105.34,101.6 120,101.6 122.7,98.89 122.7,95.21 130.18,87.73 133.56,87.73 136.1,85.19 136.1,84.55 136.1,77.88 136.34,77.63 137.61,77.63 139.6,75.64 139.6,72.47 140.37,71.7 140.37,68.5 139.68,67.82 139.68,64.28 136.33,60.93 135.41,60.93 135.16,60.68 134.33,59.86 132.98,59.86 132.47,59.35 130.45,59.35 129.57,60.24 v2(129.21,60.24)
  BOTTOM w0.102: CPU1.C45 129.21,60.51 v2(129.21,60.24)
EDP_TX2: length 8.5
  TOP w0.102: v1(98.37,101.66) 98.37,101.83 ; 98.37,101.83 98.99,101.83 C5519.1 ; 98.37,101.83 97.12,101.83 96.52,101.23 96.52,98.28 v2(96.95,97.84)
  BOTTOM w0.102: v2(96.95,97.84) 96.67,97.57 96.66,97.57 96.58,97.48 96.58,97.18 96.68,97.08 96.78,97.08 96.85,97.01 LCD1.14
EDP_TX2#: length 8.4
  TOP w0.102: v1(97.23,102.22) 97.23,102.06 ; 97.23,102.06 97.02,102.06 96.29,101.32 v2(96.29,97.84) ; 97.23,102.06 98.99,102.06 C5533.1
  BOTTOM w0.102: LCD1.13 96.35,97.78 v2(96.29,97.84)
EDP_TX2_DN: length 81.7
  TOP w0.102: 103.09,102.65 103.09,102.81 102.79,103.11 101.9,103.11 100.84,102.06 100.44,102.06 C5533.2 ; 103.09,102.65 v1(103.27,102.65) ; 103.09,102.65 103.09,102.37 v2(103.4,102.07)
  L6 w0.127: v2(131.88,60.67) 132.3,61.09 134.41,61.09 134.97,61.64 134.99,61.64 135.05,61.7 136.01,61.7 138.83,64.52 138.83,74.58 137.92,75.49 137.09,75.49 135.32,77.26 135.32,78.05 135.04,78.34 134.51,78.34 134.39,78.46 134.39,78.84 134.51,78.97 135.04,78.97 135.32,79.25 135.32,79.86 135.04,80.14 134.39,80.14 134.26,80.27 134.26,80.65 134.39,80.77 135.04,80.77 135.32,81.06 135.32,84.87 133.24,86.96 129.86,86.96 121.69,95.13 121.69,98.38 119.25,100.82 103.58,100.82 103.22,101.18 103.22,101.89 v2(103.4,102.07)
  BOTTOM w0.102: v2(131.88,60.67) 131.45,61.1 131.07,61.1 130.71,60.74 CPU1.A45
EDP_TX2_DP: length 81.6
  TOP w0.102: 101.08,101.97 100.94,101.83 100.44,101.83 C5519.2 ; 101.08,101.97 v1(101.21,101.84) ; 101.08,101.97 101.99,102.88 102.69,102.88 102.86,102.71 102.86,102.3 v2(102.64,102.07)
  L6 w0.127: v2(131.24,60.67) 131.93,61.35 134.3,61.35 134.7,61.75 134.7,61.75 134.86,61.91 134.88,61.91 134.94,61.97 135.9,61.97 138.56,64.63 138.56,74.47 137.81,75.22 136.98,75.22 135.05,77.15 135.05,77.94 134.93,78.07 134.4,78.07 134.12,78.35 134.12,78.95 134.4,79.24 134.93,79.24 135.05,79.36 135.05,79.75 134.93,79.87 134.28,79.87 133.99,80.16 133.99,80.76 134.28,81.04 134.93,81.04 135.05,81.17 135.05,84.76 133.13,86.69 129.75,86.69 121.42,95.02 121.42,98.27 119.14,100.56 103.47,100.56 102.95,101.07 102.95,101.75 v2(102.64,102.07)
  BOTTOM w0.102: CPU1.B45 130.16,60.71 130.46,60.41 130.99,60.41 v2(131.24,60.67)
EDP_TX3: length 7.5
  TOP w0.102: C5531.1 94.08,102.7 94.64,102.7 94.79,102.55 ; 94.79,102.55 95.47,101.87 v2(95.47,97.84) ; 94.79,102.55 v1(94.91,102.68)
  BOTTOM w0.102: LCD1.11 95.35,97.73 v2(95.47,97.84)
EDP_TX3#: length 7.7
  TOP w0.102: v2(94.83,97.84) 95.24,98.26 95.24,101.41 ; C5532.1 94.36,102.48 94.54,102.48 95.24,101.78 95.24,101.41 ; 95.24,101.41 v1(95.09,101.41)
  BOTTOM w0.102: LCD1.10 94.85,97.08 94.9,97.13 95.03,97.13 95.12,97.22 95.12,97.55 v2(94.83,97.84)
EDP_TX3_DN: length 82.9
  TOP w0.102: 92.12,102.5 92.6,102.5 C5532.2 ; 92.12,102.5 90.6,102.5 90.49,102.4 90.49,102.3 v2(90.78,102.02) ; 92.12,102.5 v1(92.12,102.34)
  L6 w0.127: v2(132.1,62.26) 132.49,61.87 133.44,61.87 134.16,62.59 134.16,62.63 135.56,64.03 135.98,64.03 137.24,65.28 137.24,68.27 136.64,68.87 136.64,73.75 128.73,81.65 128.73,85.88 126.8,87.81 126.8,87.81 126.19,88.42 117.24,97.37 117.24,98.69 115.88,100.05 90.91,100.05 90.25,100.71 90.25,101.65 90.62,102.02 v2(90.78,102.02)
  BOTTOM w0.102: CPU1.A47 130.77,61.84 130.78,61.84 131.41,61.84 131.84,62.26 v2(132.1,62.26)
EDP_TX3_DP: length 83.1
  TOP w0.102: v2(89.99,102.02) 90.27,102.5 90.4,102.62 ; C5531.2 92.93,102.73 90.5,102.73 90.4,102.62 ; 90.4,102.62 v1(90.27,102.75)
  L6 w0.127: v2(89.99,102.02) 89.99,100.6 90.8,99.78 115.77,99.78 116.97,98.58 116.97,97.26 126.62,87.62 126.69,87.54 128.47,85.77 128.47,81.54 136.37,73.64 136.37,68.76 136.97,68.16 136.97,65.39 135.87,64.29 135.45,64.29 133.89,62.74 133.89,62.7 133.47,62.27 132.78,62.27 132.77,62.29 v2(132.74,62.29)
  BOTTOM w0.102: v2(132.74,62.29) 132.36,62.67 131.93,62.67 131.76,62.49 131.74,62.49 131.32,62.06 130.91,62.06 130.87,62.1 130.33,62.1 CPU1.B47
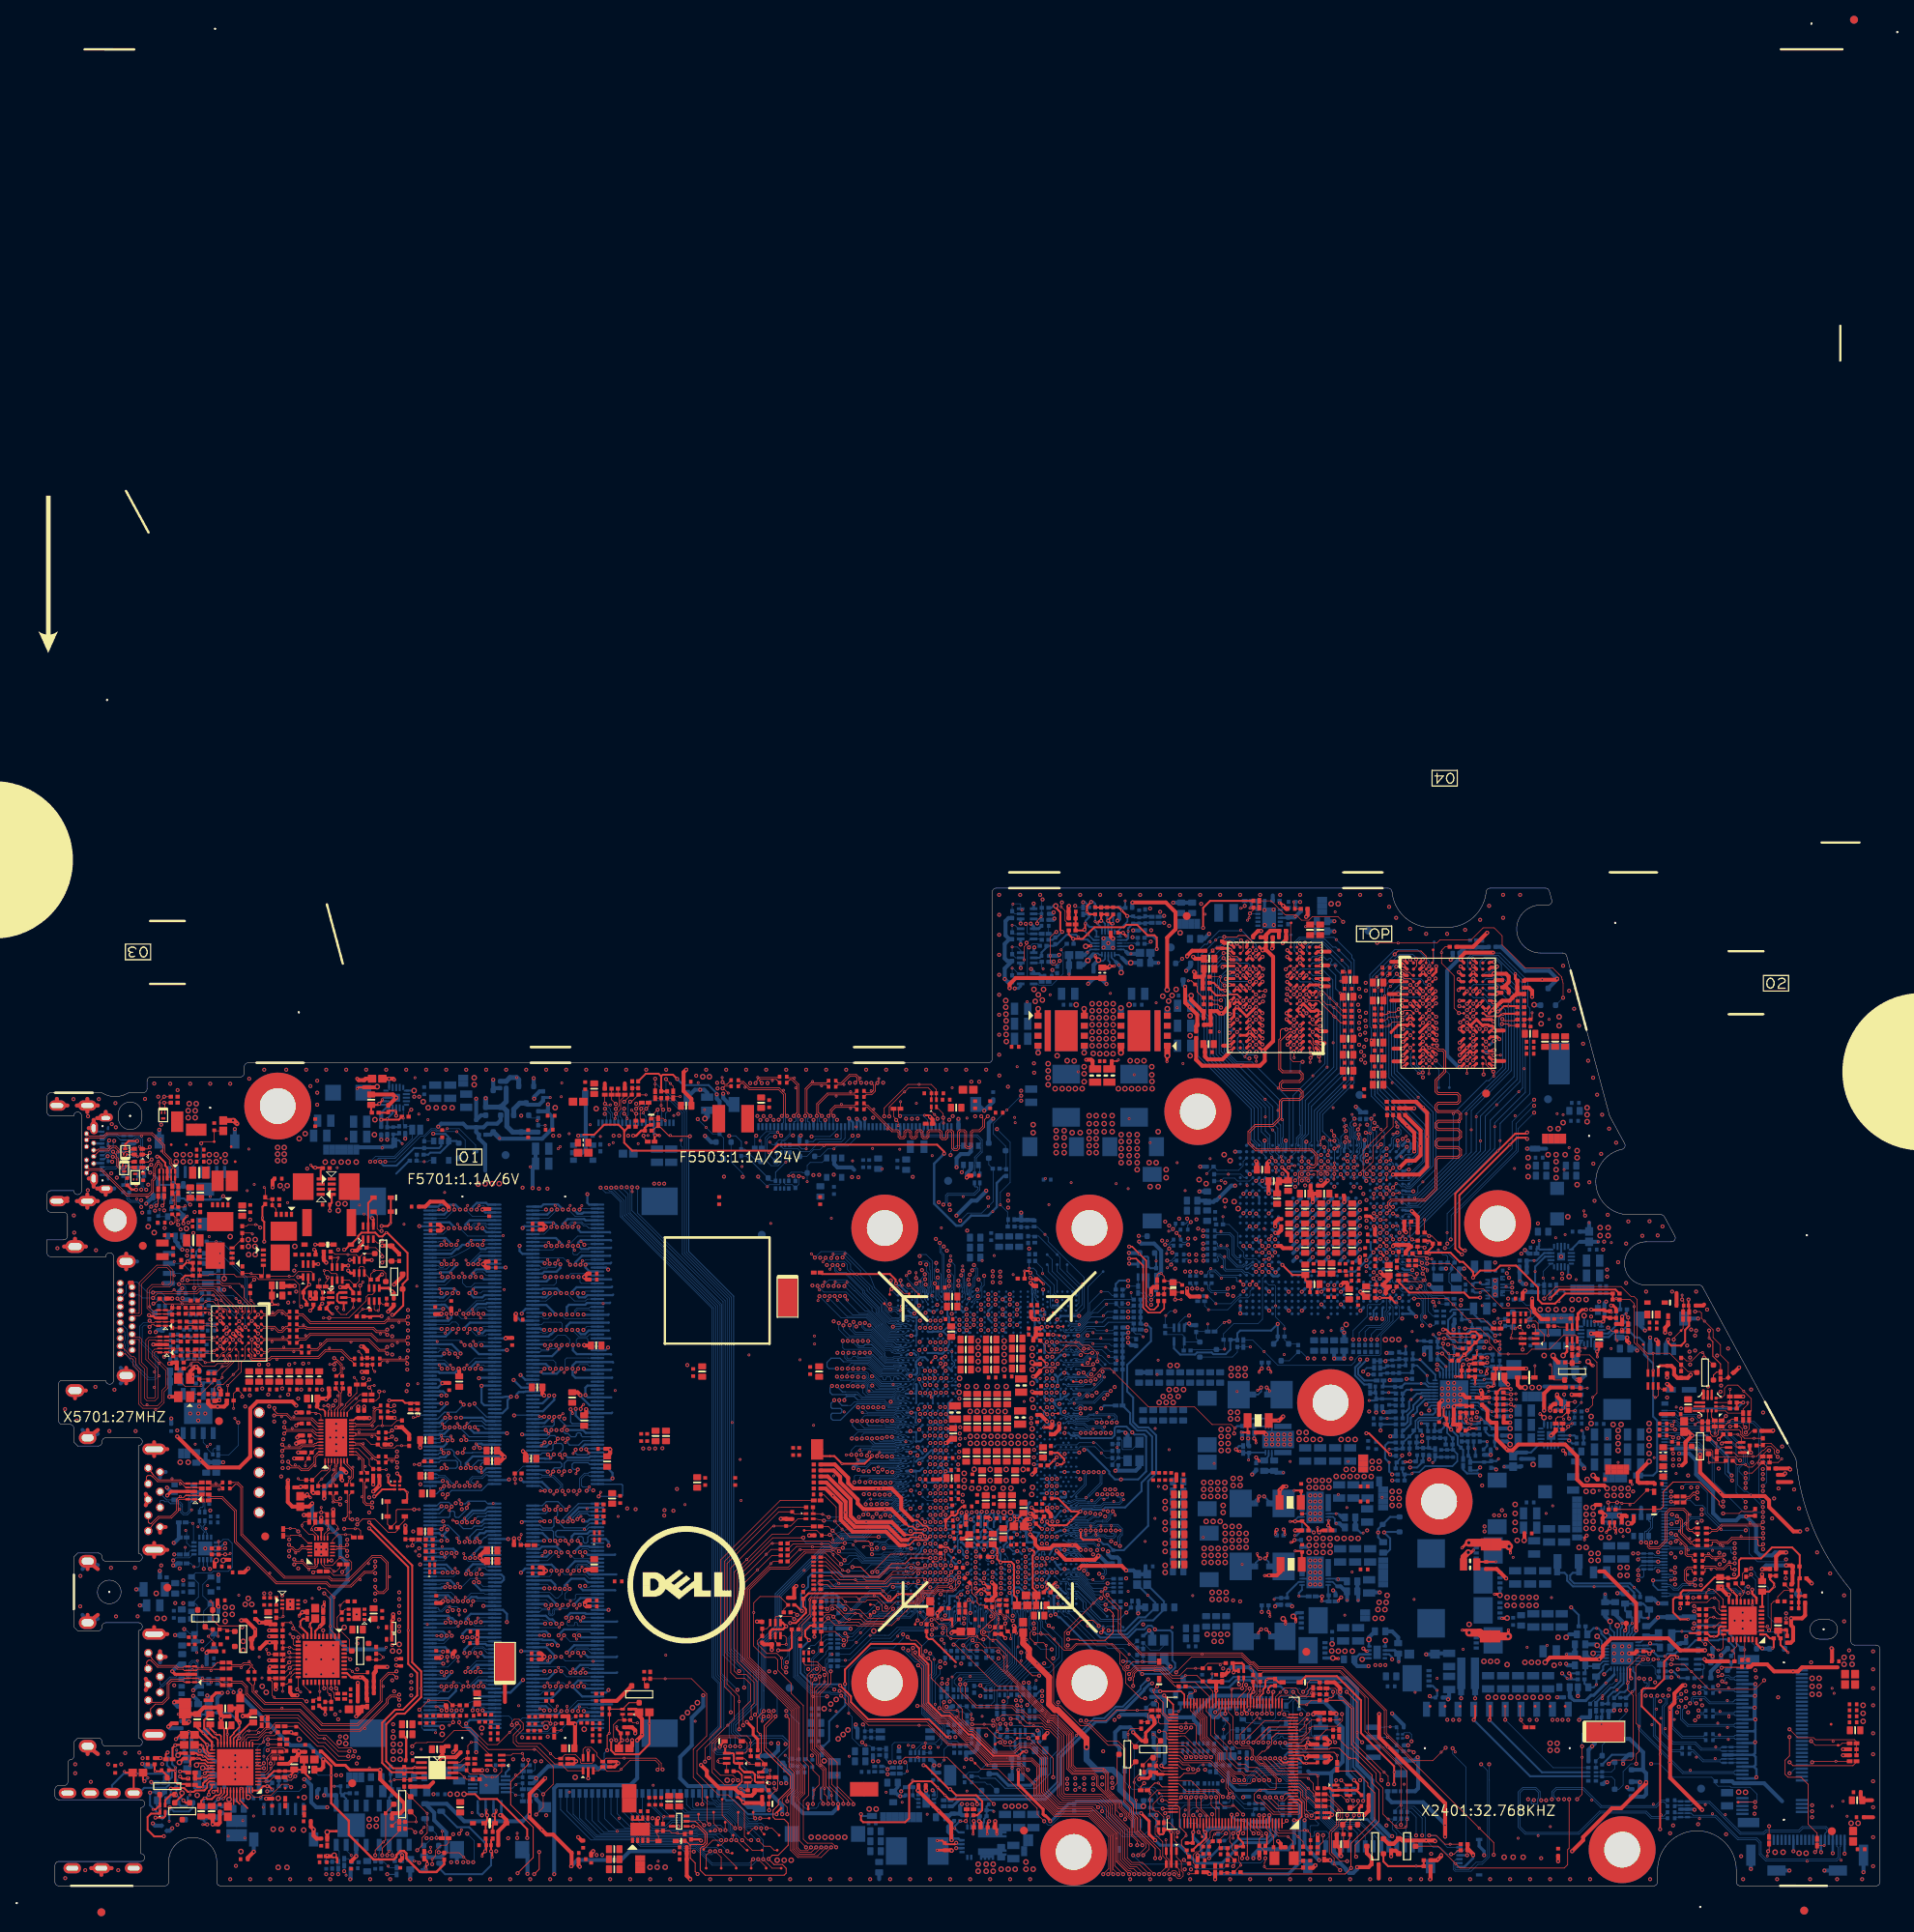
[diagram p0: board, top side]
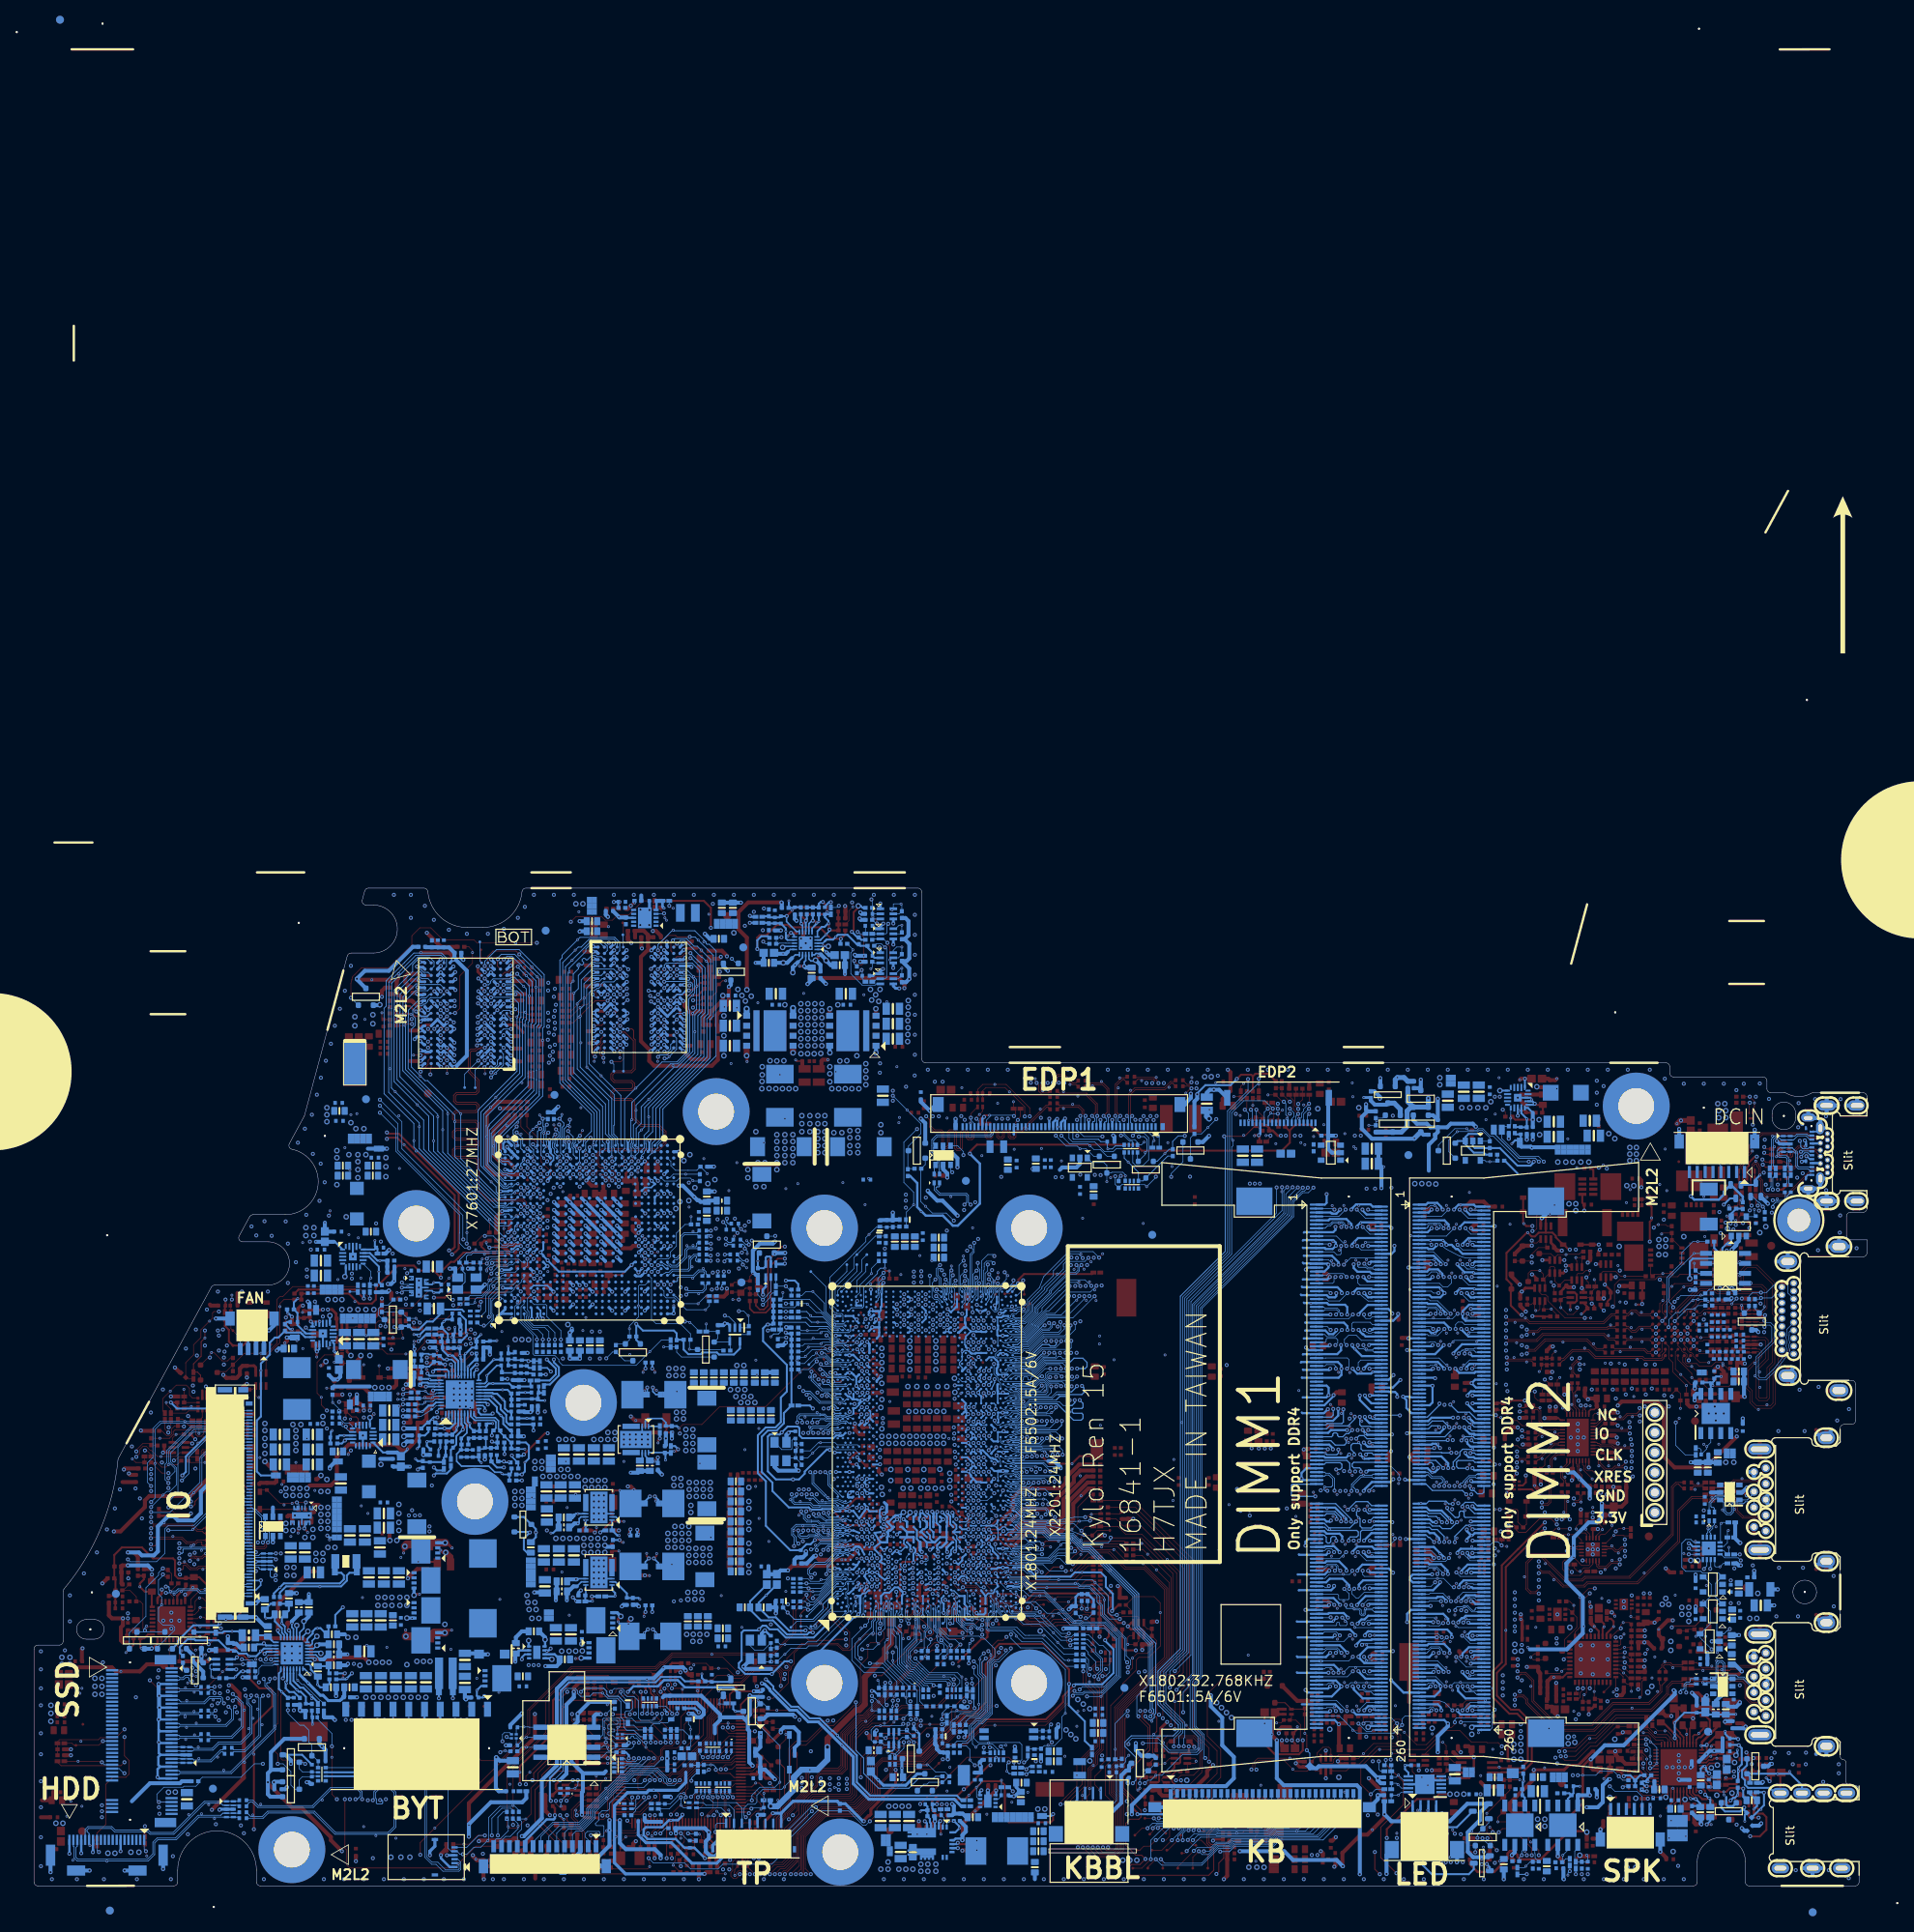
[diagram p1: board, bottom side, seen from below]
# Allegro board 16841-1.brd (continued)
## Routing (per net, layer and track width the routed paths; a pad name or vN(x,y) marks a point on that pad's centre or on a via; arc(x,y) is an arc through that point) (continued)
EDP_VDD_EN: length 85.1
  L3 w0.089: v2(102.31,95.34) 102.81,94.83 109.07,94.83 118.59,85.31 118.59,78 117.75,77.17 117.75,75.95 116.33,74.53 116.33,66.32 115.13,65.13 115.13,64.07 115.08,64.02 115.08,49.06 115.72,48.43 123.55,48.43 124.15,47.83 124.15,45.29 123.91,45.05 123.91,44.25 122.78,43.12 122.78,41.86 122.47,41.55 122.47,40.97 v2(122.2,40.7)
  BOTTOM w0.089: CPU1.U13 122.02,41.74 v2(122.2,40.7) ; D5501.1 96.5,92.71 97.38,93.59 98.19,93.59 v1(98.67,94.07) 98.93,94.32 101.29,94.32 v2(102.31,95.34)
EDRAM_OPIO_RCOMP: length 0.7
  BOTTOM w0.305: v2(126.52,72.05) 126.52,72.19 126.17,72.55 CPU1.H66
  vias: v1(126.64,72.6)
EMMC_RCOMP: length 3.3
  TOP w0.356: v2(113.08,34.68) 113.12,34.64 v1(113.12,34.01)
  TOP w0.508: v2(113.08,34.68) 113.63,35.23 R1502.1
  BOTTOM w0.254: v2(113.08,34.68) 112.9,34.5 112.14,34.5 111.96,34.68 CPU1.AT1
EOPIO_RCOMP: length 2.2
  TOP w0.508: R415.1 124.99,72.28 125.27,72 v1(125.27,71.99) v2(125.88,71.99)
  BOTTOM w0.305: v2(125.88,71.99) 125.88,71.76 CPU1.H65
EQ0: length 3.4
  TOP w0.089: v1(32.81,53.38) 32.81,53.91 R3842.2 33.22,54.7 R3843.1 34.1,55.58 U3801.38
EQ1: length 2.4
  TOP w0.089: U3801.35 34.06,56.78 33.6,57.24 R3841.1 33.34,56.6 R3840.2
ESPI_ALERT#: length 94.4
  TOP w0.089: v2(137.43,26.93) 137.43,26.93 137.48,26.93 138.32,27.77 140.73,27.77 140.8,27.7 141.57,27.7 142.9,26.38 144.22,26.38 v1(144.57,26.73) 146.04,26.73 R2464.1 148.04,24.73 KBC24.55
  L4 w0.127: v2(105.44,39.91) 105.02,40.32 104.52,40.32 99.94,35.75 98.98,35.75 98.52,35.29 98.52,34.45 95.4,31.33 95.4,20.65 97.95,18.1 100.88,18.1 101.46,17.52 106.31,17.52 106.94,18.16 108.93,18.16 109.82,17.27 110.44,17.27 110.95,17.78 110.95,17.79 111.29,18.12 114.57,18.12 v2(115.36,18.91)
  L6 w0.102: v2(115.36,18.91) 115.67,18.6 120.06,18.6 120.76,19.3 123.1,19.3 127.03,23.23 127.03,24.65 131.46,29.07 133.89,29.07 136.03,26.93 v2(137.43,26.93)
  BOTTOM w0.089: CPU1.AY11 109.07,40.75 106.81,40.75 106.28,40.23 105.76,40.23 v2(105.44,39.91)
ESPI_CLK: length 136
  TOP w0.089: KBC24.57 147.24,22.19 147.8,21.63 147.8,19.18 149.83,17.15 149.83,16.21 151.1,14.93 152.04,14.93 152.42,14.55 153.21,14.55 153.51,14.55 154.44,13.63 154.44,13.56 v2(154.58,13.42) ; v2(100.22,4.9) 99.7,5.42 96.57,5.42 96.05,5.94 96.05,10.84 96.74,11.53 96.74,15.18 96.05,15.87 96.05,22.92 94.53,24.44 94.53,25.7 92.78,27.44 92.78,28.74 92.48,29.04 91.18,29.04 89.74,30.49 89.74,34.69 89.76,34.71 v1(89.76,34.73) 89.76,35.98 90.55,36.77 93.06,36.77 EC1801.1 93.57,35.14 R1805.2
  L6 w0.102: v2(100.22,4.9) 102.12,4.9 103.57,6.36 106.65,6.36 110.5,10.2 115.61,10.2 115.94,9.87 121.13,9.87 121.9,9.1 124.88,9.1 126.11,10.34 126.53,10.34 126.59,10.4 130.84,10.4 132.08,11.64 135.7,11.64 136.58,12.52 139.55,12.52 140.46,13.42 147.72,13.42 148.68,14.38 153.7,14.38 154.45,13.63 154.45,13.55 v2(154.58,13.42)
  BOTTOM w0.089: v2(154.58,13.42) 154.58,13.28 155.35,12.5 157.69,12.5 159.73,10.47 159.73,9.75 159.93,9.54 160.66,9.54 161.03,9.17 161.03,8.39 161.49,7.93 161.49,7.78 161.36,7.66 160.5,7.66 160.41,7.57 160.41,6.37 160.5,6.29 160.87,6.29 160.95,6.37 160.95,6.84 161.03,6.92 162.5,6.92 162.76,6.66 162.76,6.18 162.41,5.84 DB1.2
ESPI_CS#: length 155.4
  TOP w0.089: v2(97.03,4.9) 96.6,4.47 95.71,4.47 95.34,4.85 95.34,11.13 96.03,11.82 96.03,14.89 95.34,15.57 95.34,22.62 90.46,27.5 89.03,28.94 89.03,37.74 91.77,40.47 94.13,40.47 96.17,42.52 99.45,42.52 v1(99.84,42.12) 99.84,41.92 v2(100.86,40.9) ; KBC24.58 146.84,22.74 146.75,22.65 146.75,21.98 147.3,21.42 147.3,18.97 149.33,16.94 149.33,16 150.9,14.44 151.84,14.44 152.22,14.06 153.31,14.06 v2(153.94,13.42)
  L6 w0.102: v2(97.03,4.9) 98.56,3.36 102.31,3.36 102.69,3.36 104.26,4.93 105.17,4.93 105.17,4.93 107.24,4.93 111.09,8.77 115.02,8.77 115.35,8.44 115.87,8.44 116.66,7.66 125.45,7.66 126.7,8.91 127.12,8.91 127.18,8.98 134.13,8.98 135.38,10.22 136.73,10.22 137.61,11.1 140.14,11.1 141.05,12 151.12,12 151.95,12.83 153.36,12.83 v2(153.94,13.42)
  BOTTOM w0.089: CPU1.BA12 108.81,41.38 108.46,41.38 108.33,41.51 107.85,41.51 107.69,41.36 106.55,41.36 106.22,41.03 103.5,41.03 102.92,41.61 102.5,41.61 101.79,40.9 v2(100.86,40.9) ; v2(153.94,13.42) 154.62,14.1 156.55,14.1 157.43,13.23 157.98,13.23 161.74,9.46 161.74,8.68 163.23,7.2 164.97,7.2 165.41,6.75 DB1.5
ESPI_IO0: length 140.5
  TOP w0.089: v2(152.05,13.42) 152.05,13.92 151.75,14.22 150.81,14.22 149.12,15.91 149.12,16.85 147.09,18.88 147.09,21.33 146.44,21.98 KBC24.59 ; R1827.1 92.22,41.24 v1(91.93,40.94) 88.81,37.83 88.81,28.83 95.12,22.52 95.12,15.48 95.81,14.8 95.81,11.91 95.12,11.22 95.12,4.76 95.62,4.26 97.04,4.26 v2(97.68,4.9)
  L6 w0.102: v2(97.68,4.9) 98.99,3.59 102.41,3.59 102.41,3.59 102.6,3.59 103.9,4.89 104.17,5.16 105.26,5.16 107.15,5.16 110.99,9 115.12,9 115.45,8.67 116.02,8.67 116.02,8.67 120.64,8.67 121.43,7.89 125.35,7.89 126.61,9.14 127.02,9.14 127.09,9.21 131.33,9.21 132.58,10.45 136.64,10.45 137.52,11.33 140.05,11.33 140.95,12.23 150.86,12.23 v2(152.05,13.42)
  BOTTOM w0.089: v2(152.05,13.42) 153.59,14.97 156.91,14.97 157.78,14.09 158.34,14.09 162.61,9.82 162.61,9.04 163.58,8.06 166.92,8.06 169.41,5.57 DB1.9
ESPI_IO1: length 140.9
  TOP w0.089: KBC24.60 146.04,22.07 146.87,21.24 146.87,18.79 148.9,16.76 148.9,15.82 150.79,13.93 150.91,13.93 v2(151.42,13.42) ; R1828.1 92.07,42 v1(90.24,40.17) 88.6,38.52 88.6,28.74 94.91,22.43 94.91,15.39 95.59,14.71 95.59,12 94.91,11.31 94.91,4.67 95.53,4.04 97.46,4.04 v2(98.32,4.9)
  L6 w0.102: v2(98.32,4.9) 99.39,3.82 102.5,3.82 103.67,4.99 104.07,5.39 105.36,5.39 107.05,5.39 110.9,9.23 115.21,9.23 115.54,8.9 115.92,8.9 115.92,8.9 120.73,8.9 121.52,8.11 125.26,8.11 126.51,9.37 126.93,9.37 126.99,9.44 131.24,9.44 132.48,10.68 136.55,10.68 137.42,11.56 139.96,11.56 140.86,12.46 150.45,12.46 v2(151.42,13.42)
  BOTTOM w0.089: DB1.8 168.41,6.27 166.83,7.85 163.5,7.85 162.39,8.95 162.39,9.73 158.25,13.87 157.69,13.87 156.82,14.75 153.68,14.75 152.48,13.54 152.48,13.25 152.23,13 151.84,13 v2(151.42,13.42)
ESPI_IO2: length 140.8
  TOP w0.089: v2(150.77,13.43) 150.77,13.65 148.69,15.73 148.69,16.67 146.66,18.7 146.66,21.15 145.64,22.17 KBC24.61 ; R1829.1 91.97,42.76 v1(91.36,42.15) 88.38,39.17 88.38,28.65 94.69,22.34 94.69,15.3 95.38,14.62 95.38,12.09 94.69,11.4 94.69,4.58 95.44,3.82 97.88,3.82 v2(98.95,4.9)
  L6 w0.102: v2(150.77,13.43) 150.03,12.69 140.76,12.69 139.86,11.78 137.17,11.78 136.29,10.91 132.39,10.91 131.28,9.8 131.14,9.66 126.9,9.66 126.83,9.6 126.42,9.6 125.16,8.34 121.62,8.34 120.83,9.13 115.64,9.13 115.31,9.46 110.8,9.46 106.96,5.62 103.98,5.62 103.44,5.08 102.52,4.17 99.69,4.17 v2(98.95,4.9)
  BOTTOM w0.089: DB1.7 167.41,6.3 166.09,7.63 163.41,7.63 162.17,8.86 162.17,9.64 158.16,13.66 157.61,13.66 156.73,14.53 153.77,14.53 152.85,13.61 152.85,13.31 152.32,12.78 151.46,12.78 150.81,13.43 v2(150.77,13.43)
ESPI_IO3: length 144.1
  TOP w0.089: v2(153.27,13.43) 152.83,12.99 150.61,12.99 150.26,13.34 150.26,13.85 148.47,15.64 148.47,16.58 146.44,18.61 146.44,19.15 146.44,21.07 145.24,22.26 KBC24.62 ; R1830.1 v1(92.12,43.52) 91.97,43.52 88.16,39.72 88.16,28.54 93.49,23.21 94.04,22.66 94.06,22.66 94.48,22.25 94.48,15.21 95.16,14.53 95.16,12.18 94.43,11.45 94.43,4.53 95.35,3.61 98.3,3.61 v2(99.59,4.9)
  L6 w0.102: v2(99.59,4.9) 99.71,4.77 99.71,4.69 100.01,4.39 102.33,4.39 103.78,5.85 106.87,5.85 110.71,9.69 115.4,9.69 115.73,9.36 120.92,9.36 121.71,8.57 125.07,8.57 126.32,9.83 126.74,9.83 126.8,9.89 131.05,9.89 132.29,11.14 135.91,11.14 136.79,12.01 139.77,12.01 140.67,12.91 149.64,12.91 150.59,13.86 152.84,13.86 v2(153.27,13.43)
  BOTTOM w0.089: v2(153.27,13.43) 154.16,14.32 156.64,14.32 157.52,13.44 158.07,13.44 161.96,9.55 161.96,8.77 163.32,7.42 165.69,7.42 166.41,6.69 DB1.6
ESPI_RESET#: length 152.1
  TOP w0.089: v2(96.39,4.9) 95.55,5.74 95.55,11.04 96.24,11.73 96.24,14.98 95.56,15.66 95.56,22.71 94.12,24.15 89.24,29.03 89.24,37.65 91.86,40.26 94.29,40.26 96.33,42.3 98.86,42.3 v1(101.04,40.12) 101.15,40.01 v2(101.75,40.01) ; KBC24.53 148.84,21.91 148.29,21.36 148.29,19.38 150.32,17.35 150.32,16.41 151.31,15.43 152.25,15.43 152.63,15.05 153.72,15.05 155.07,13.69 155.07,13.56 v2(155.21,13.42)
  L6 w0.102: v2(155.21,13.42) 154.22,12.43 152.62,12.43 151.96,11.77 141.14,11.77 140.24,10.87 137.71,10.87 137.23,10.4 136.83,9.99 135.47,9.99 134.23,8.75 128.76,8.75 127.44,7.43 116.75,7.43 116.56,7.43 115.77,8.22 115.26,8.22 114.93,8.55 111.18,8.55 107.34,4.7 105.08,4.7 105.07,4.7 104.35,4.7 102.79,3.14 102.22,3.14 98.15,3.14 v2(96.39,4.9)
  BOTTOM w0.089: v2(101.75,40.01) 103.83,40.01 104.65,40.82 106.3,40.82 106.63,41.15 107.77,41.15 107.92,41.31 108.25,41.31 108.32,41.24 108.35,41.24 108.38,41.2 108.54,41.2 CPU1.BA11 ; v2(155.21,13.42) 155.64,13 157.9,13 161.53,9.37 161.53,8.59 163.14,6.98 163.94,6.98 164.41,6.51 DB1.4
EXT_PWR_GATE#: length 2
  TOP w0.127: v1(114.5,39.38) v2(114.85,39.86) 115.44,40.45 115.46,40.45
  BOTTOM w0.127: CPU1.AM10 114.45,40.26 v2(114.85,39.86)
FALL_INT2: length 4.1
  TOP w0.089: Q7001.2 214.65,55.71 214.52,55.84 214.52,56.24 214.65,56.36 Q7001.3 215.22,56.9 v1(214.76,57.36) 214.73,57.39 R7018.2
FAN1_PWM: length 136.3
  TOP w0.102: R2614.1 207.79,73.67 EC2601.1 207.87,74.31 v2(207.67,74.51) v1(207.67,75.07) ; KBC24.47 151.24,23.83 152.29,24.87 v2(152.29,25.54)
  L3 w0.102: v2(152.29,25.54) 153.31,25.54 153.64,25.22 153.64,24.14 154.03,23.75 172.67,23.75 177,19.41 183.8,19.41 189.11,14.11 198.93,14.11 199.52,14.69 201.67,14.69 206.39,19.41 209.72,19.41 215.72,25.42 215.72,30.98 218.76,34.02 218.76,35.37 219.24,35.85 219.24,40.78 217.24,42.78 217.24,47.9 214.63,50.51 214.42,50.51 213.53,51.39 213.53,54.67 211.73,56.48 211.73,57.49 212.73,58.49 212.73,62 212.97,62.24 212.97,63.23 v2(212.62,63.59)
  L6 w0.102: v2(212.62,63.59) 212.62,68.29 212.36,68.54 212.36,69.47 211.49,71.08 211.22,71.08 210.13,72.17 210.13,72.28 209.82,72.58 209.82,73.87 208.76,74.94 208.1,74.94 v2(207.67,74.51)
FAN1_TACH: length 5.6
  TOP w0.203: 154.45,24.98 154.45,24.47 154.04,24.06 KBC24.40
  TOP w0.254: D2403.A 156.41,25.87 R2430.1 155.93,26.35 155.06,26.35 v1(154.96,26.25) 154.73,26.02 154.73,25.26 154.45,24.98
FAN_PWM1_C: length 4.3
  TOP w0.089: R2614.2 207.79,70.83 AFTP2602.1 206.6,69.63 v2(206.6,69.43)
  BOTTOM w0.089: v2(206.6,69.43) FAN1.4
FAN_TACH1: length 128.2
  TOP w0.254: v2(171.09,12.91) v1(171.09,14.44) 171.09,15.2 166.87,19.42 166.87,23.59 163.81,26.65 159.89,26.65 D2403.K ; R2613.1 208.55,73.67 EC2602.1 v2(208.48,74.51)
  L6 w0.254: v2(208.48,74.51) 208.48,72.6 209.49,71.59 209.63,71.59 210.46,70.76 210.46,67.91 211.86,66.51 211.86,59.14 213.25,57.75 213.25,50.12 214.45,48.92 214.45,44.15 214.85,43.75 214.85,34.94 214.85,34.93 214.85,30.88 215.09,30.64 215.09,21.23 211.01,17.15 205.65,17.15 205.4,17.41 197.44,17.41 194.94,14.92 189.22,14.92 187.92,16.22 181.73,16.22 178.43,12.91 v2(171.09,12.91)
FAN_TACH1_C: length 7.3
  TOP w0.254: v2(205.89,69.43) 205.89,69.05 206.27,68.67 AFTP2601.1 208.05,69.18 208.05,70.66 208.55,71.17 R2613.2
  BOTTOM w0.254: v2(205.89,69.43) 205.6,69.14 FAN1.3
FAN_VCC_1: length 1.5
  BOTTOM w0.508: FAN1.1 v2(203.6,69.68)
FB_CAL_PD_VDDQ: length 17
  TOP w0.508: R7505.1 173.88,99.66 175.28,98.26 v1(175.28,95.21) 175.28,91.4 174.28,90.4 v2(170.95,90.4)
  BOTTOM w0.356: GPU1.D22 v2(170.95,90.4)
FB_CAL_PU_GND: length 9.9
  TOP w0.508: v2(171.76,91.25) 172.67,92.16 173.76,92.16 174.44,92.85 v1(174.44,94.02) 174.44,96 R7507.2
  BOTTOM w0.305: GPU1.C24 171.76,91.29 v2(171.76,91.25)
FB_CAL_TERM_GND: length 7.3
  TOP w0.508: R7506.1 171.72,97.64 172.15,97.22 172.15,97.2 v1(172.74,96.61) 173.65,95.7 v2(173.65,93.35)
  BOTTOM w0.127: GPU1.B25 172.57,92.92 173.22,92.92 v2(173.65,93.35)
FB_CLAM: length 3.6
  TOP w0.254: v1(171.42,74.1) 171.24,74.1 R7518.1 170.62,74.72 v2(169.26,74.72) 169.25,74.71 R7519.1
  BOTTOM w0.254: GPU1.F3 168.85,74.31 v2(169.26,74.72)
FB_VREF: length 1.4
  TOP w0.089: TP7503.1 170.12,90.45 v2(170.12,90.45)
  BOTTOM w0.089: GPU1.D23 170.47,90.85 170.12,90.49 v2(170.12,90.45)
FBA_CLK0_MIDPT: length 2.5
  TOP w0.114: 187.6,109.33 R7802.2 188.39,110.1 C7801.2 188.62,110.32 v1(188.62,110.96)
FBA_CLK0N: length 47.4
  TOP w0.114: v2(184.84,110.16) 185.06,109.94 186.33,109.94 186.48,110.1 R7802.1 ; VRAM2.J11 180.76,110.9 v2(181.15,111.29) ; v1(170.56,90.84) v2(170.97,91.26)
  L3 w0.14: v2(181.15,111.29) 181.29,111.16 182.12,111.16 182.51,110.76 183.93,110.76 184.53,110.16 v2(184.84,110.16) 185.33,109.67 185.33,100.3 173.83,88.8 173.12,88.8 172.8,88.48 172.8,87.8 172.52,87.52 171.74,87.52 171.46,87.8 171.46,90.27 171.74,90.55 173.32,90.55 173.45,90.68 173.45,91.61 173.32,91.74 171.45,91.74 v2(170.97,91.26)
  BOTTOM w0.114: v2(170.97,91.26) 170.97,91.78 170.55,92.19 GPU1.D25 ; VRAM2.J11 180.76,110.9 v2(181.15,111.29)
FBA_CLK0P: length 46.5
  TOP w0.114: v2(184.78,109.53) 185.52,109.53 v1(185.69,109.36) 185.72,109.33 R7801.1 ; v2(181.15,110.49) 181.55,110.89 VRAM2.J12
  L3 w0.14: v2(181.15,110.49) 181.15,110.72 181.31,110.89 182.01,110.89 182.4,110.49 183.82,110.49 v2(184.78,109.53) 185.06,109.26 185.06,100.41 173.72,89.06 173,89.06 172.53,88.59 172.53,87.91 172.41,87.79 171.85,87.79 171.72,87.91 171.72,90.16 171.85,90.28 173.43,90.28 173.72,90.57 173.72,91.73 173.43,92.01 171.34,92.01 171.01,91.68 170.3,91.68 170.12,91.5 v2(170.12,91.24)
  BOTTOM w0.114: GPU1.D24 170.32,91.7 170.12,91.5 v2(170.12,91.24) ; v2(181.15,110.49) 181.55,110.89 VRAM2.J12
FBA_CLK1_MIDPT: length 4.1
  TOP w0.114: v1(144.95,115.02) 145.36,115.02 C7901.2 146.07,114.31 146.07,113.63 146.83,112.87 R7906.2 R7908.2
FBA_CLK1N: length 47.4
  TOP w0.114: v2(149.09,112.54) 148.12,112.54 R7906.1 ; v1(164.66,89.85) v2(164.31,90.43) ; v2(152.73,112.49) 153.13,112.9 VRAM3.J11
  L6 w0.14: v2(164.31,90.43) 164.31,88.65 163.45,87.79 160.83,87.79 160.3,88.32 159.45,88.32 158.92,87.79 157.01,87.79 156.79,87.79 155.79,88.79 155.79,88.8 155.71,88.87 152.56,92.03 152.56,100.53 148.1,104.99 148.1,111.95 148.56,112.41 148.95,112.41 v2(149.09,112.54) 149.27,112.73 149.58,112.73 150.13,113.28 152.27,113.28 152.57,112.97 152.57,112.65 v2(152.73,112.49)
  BOTTOM w0.114: GPU1.M22 163.93,90.06 v2(164.31,90.43) ; v2(152.73,112.49) 152.74,112.49 VRAM3.J11
FBA_CLK1P: length 47.5
  TOP w0.114: VRAM3.J12 152.35,112.9 v2(151.94,112.49) ; v1(163.44,89.82) v2(163.49,90.48) ; R7908.1 148.68,112.03 v2(149.1,111.62)
  L6 w0.14: v2(151.94,112.49) 152.2,112.49 152.3,112.6 152.3,112.86 152.16,113.01 150.24,113.01 149.77,112.54 149.77,111.77 149.64,111.64 149.13,111.64 v2(149.1,111.62) 149.1,111.91 148.87,112.14 148.67,112.14 148.37,111.84 148.37,105.1 152.83,100.64 152.83,92.14 155.98,88.98 156.9,88.06 158.81,88.06 159.34,88.59 160.41,88.59 160.94,88.06 163.34,88.06 164.04,88.76 164.04,90.06 163.85,90.25 163.85,90.35 163.73,90.48 v2(163.49,90.48)
  BOTTOM w0.114: v2(151.94,112.49) 152.35,112.9 VRAM3.J12 ; v2(163.49,90.48) 163.22,90.48 163.09,90.35 GPU1.N22
FBA_CMD0: length 41
  TOP w0.114: v2(181.95,108.9) 181.95,108.9 VRAM2.L12 ; v2(171.54,94.72) 171.54,94.06 v1(171.59,94.01)
  L3 w0.127: v2(181.95,108.9) 181.95,108.55 182.13,108.37 182.67,108.37 182.8,108.24 182.8,107.91 182.67,107.78 181.86,107.78 181.73,107.66 181.73,106 181.86,105.88 183.04,105.88 183.21,105.71 183.21,105.38 183.04,105.22 181.76,105.22 181.63,105.09 181.63,104.68 181.76,104.56 183.04,104.56 183.21,104.39 183.21,104.06 183.04,103.89 182.12,103.89 181.95,103.73 181.95,101.81 182.11,101.66 183.92,101.66 184.02,101.56 184.02,101.13 183.89,101 181.99,101 181.86,100.88 181.86,100.44 181.99,100.32 182.93,100.32 183.05,100.19 183.05,99.77 175.6,92.32 174.65,92.32 174.09,92.88 171.07,92.88 170.78,93.17 170.78,93.96 v2(171.54,94.72)
  BOTTOM w0.114: VRAM2.L12 181.95,108.9 v2(181.95,108.9) ; GPU1.C27 171.35,94.53 v2(171.54,94.72)
FBA_CMD1: length 38.2
  TOP w0.114: VRAM2.K10 179.84,110.1 v2(179.48,109.74) ; v1(172.64,95.26) v2(172.17,94.92)
  L3 w0.127: v2(172.17,94.92) 172.18,94.92 172.31,94.8 172.31,94.14 172.18,94.02 171.55,94.02 171.42,93.89 171.42,93.37 171.55,93.25 172.78,93.25 173.44,93.91 174.04,93.91 174.16,93.78 174.16,93.43 174.29,93.31 174.59,93.31 174.72,93.43 174.72,93.78 174.85,93.91 175.15,93.91 175.28,93.78 175.28,93.28 175.41,93.15 175.75,93.15 175.88,93.28 175.88,93.74 176.04,93.91 176.55,93.91 176.99,94.36 176.99,94.86 177.37,95.24 177.57,95.24 177.99,95.24 178.47,95.73 178.47,95.91 178.27,96.11 178.27,96.31 178.57,96.61 178.7,96.61 178.94,96.37 179.12,96.37 179.3,96.55 179.3,96.73 179.17,96.86 179.17,97.04 179.35,97.22 179.53,97.22 179.66,97.09 179.84,97.09 180.02,97.27 180.02,97.45 179.89,97.58 179.89,97.76 180.16,98.03 180.26,98.03 180.44,97.85 180.59,97.85 182.14,99.39 182.14,99.78 181.99,99.94 181.71,99.94 181.48,100.16 181.48,103.18 181.18,103.48 179.99,103.48 179.87,103.61 179.87,106.91 179.99,107.04 180.54,107.04 180.66,107.17 180.66,107.56 180.54,107.68 179.55,107.68 179.42,107.81 179.42,108.27 179.55,108.39 179.73,108.39 179.86,108.52 179.86,109.36 v2(179.48,109.74)
  BOTTOM w0.114: GPU1.C26 171.78,93.72 171.78,94.35 172.17,94.75 v2(172.17,94.92) ; VRAM2.K10 179.84,110.1 v2(179.48,109.74)
FBA_CMD2: length 39.9
  TOP w0.114: v2(180.35,110.5) 180.35,110.5 VRAM2.K11 ; v1(170.66,92.24) v2(170.1,92.09)
  L3 w0.127: v2(170.1,92.09) 170.13,92.09 170.5,92.46 174.09,92.46 174.21,92.33 174.21,90.87 174.34,90.74 174.67,90.74 174.8,90.87 174.8,91.4 175,91.6 175.53,91.6 184.48,100.56 184.48,101.92 184.35,102.04 182.57,102.04 182.44,102.17 182.44,102.55 182.57,102.68 184.35,102.68 184.48,102.81 184.48,106.41 184.12,106.76 183.34,106.76 183.21,106.89 183.21,109.76 183.09,109.88 180.97,109.88 v2(180.35,110.5)
  BOTTOM w0.114: VRAM2.K11 180.75,110.11 v2(180.35,110.5) ; v2(170.1,92.09) 169.71,91.7 GPU1.E24
FBA_CMD3: length 39.5
  TOP w0.114: v2(180.35,111.29) 180.35,111.3 VRAM2.H11 ; v1(169.49,92.67) v2(169.31,92.1)
  L3 w0.127: v2(169.31,92.1) 169.65,92.44 169.65,93.83 171.04,95.22 171.73,95.22 172.08,95.57 173.27,95.57 173.4,95.44 173.4,94.47 173.53,94.34 176.44,94.34 176.61,94.51 176.61,95.02 177.22,95.63 177.72,95.63 177.89,95.79 177.89,96.12 177.72,96.29 177.22,96.29 177.01,96.49 177.01,98.28 177.14,98.41 177.53,98.41 177.66,98.28 177.66,97.66 177.66,97.66 177.66,97.23 177.89,96.99 178.58,96.99 178.93,97.34 178.93,98.06 179.29,98.41 180.46,98.41 181.05,99 181.05,102.85 180.82,103.08 179.37,103.08 178.96,103.49 178.96,109.91 v2(180.35,111.29)
  BOTTOM w0.114: v2(180.35,111.29) 180.75,111.69 VRAM2.H11 ; v2(169.31,92.1) 168.91,91.7 GPU1.F24
FBA_CMD4: length 40
  TOP w0.114: v2(179.37,111.8) 179.46,111.7 VRAM2.H10 ; v1(170.94,95.54) v2(171.49,95.75)
  L3 w0.127: v2(171.49,95.75) 171.76,96.02 173.71,96.02 173.88,95.85 173.88,95.14 174.25,94.77 174.58,94.77 174.74,94.94 174.74,95.94 174.87,96.07 175.28,96.07 175.41,95.94 175.41,94.91 175.53,94.78 175.94,94.78 176.07,94.91 176.07,95.58 176.63,96.15 176.63,98.57 176.85,98.79 177.91,98.79 178.04,98.67 178.04,97.5 178.17,97.37 178.42,97.37 178.55,97.5 178.55,98.67 178.68,98.79 180,98.79 180.63,99.42 180.63,101.21 180.47,101.37 179.08,101.37 178.92,101.54 178.92,101.87 179.08,102.03 180.47,102.03 180.63,102.2 180.63,102.51 180.39,102.75 179.29,102.75 178.67,103.37 178.67,111.57 178.89,111.8 v2(179.37,111.8)
  BOTTOM w0.114: v2(179.37,111.8) 179.46,111.7 VRAM2.H10 ; GPU1.D27 170.73,94.28 170.73,95 v2(171.49,95.75)
FBA_CMD5: length 38.9
  TOP w0.114: v2(181.15,112.1) 181.15,112.1 VRAM2.G12 ; v1(171.34,97.04) v2(171.49,96.5)
  L3 w0.127: v2(181.15,112.1) 181.15,112.43 181.28,112.56 182.24,112.56 182.37,112.68 182.37,113.11 182.24,113.24 180.65,113.24 180.49,113.07 180.49,112.79 180.32,112.63 179.99,112.63 179.83,112.79 179.83,113.07 179.66,113.24 178.5,113.24 178.38,113.11 178.38,103.01 178.47,102.92 178.47,101.33 178.85,100.94 180.06,100.94 180.21,100.79 180.21,99.76 179.62,99.17 176.4,99.17 176.21,98.99 176.21,96.91 175.81,96.5 v2(171.49,96.5)
  BOTTOM w0.114: v2(181.15,112.1) 181.55,112.5 VRAM2.G12 ; v2(171.49,96.5) 171.95,96.04 171.95,95.57 171.66,95.29 171.45,95.29 170.98,94.81 170.98,93.73 170.81,93.56 GPU1.D26
FBA_CMD6: length 41.8
  TOP w0.114: VRAM2.H4 175.55,112.1 v2(175.55,112.1)
  L3 w0.127: v2(168.59,96.98) 168.66,97.05 168.66,102.56 169.58,103.48 169.58,109.82 169.21,110.2 169.21,114.86 169.33,114.99 169.69,114.99 169.82,114.86 169.82,114.48 169.95,114.36 170.2,114.36 170.32,114.23 170.32,113.97 170.2,113.85 169.95,113.85 169.82,113.72 169.82,113.47 169.95,113.34 170.2,113.34 170.32,113.21 170.32,112.96 170.2,112.83 169.95,112.83 169.82,112.7 169.82,112.45 169.95,112.32 170.2,112.32 170.32,112.2 170.32,111.94 170.2,111.82 169.95,111.82 169.82,111.69 169.82,110.63 170.5,109.94 171.34,109.94 171.91,110.51 172.46,110.51 172.96,111.02 173.5,111.02 173.63,110.89 173.63,109.56 173.76,109.43 174.14,109.43 174.26,109.56 174.26,110.82 v2(175.55,112.1)
  BOTTOM w0.114: VRAM2.H4 175.15,111.7 v2(175.55,112.1) ; GPU1.F25 169.35,93 169.35,93.55 169.84,94.04 169.84,95.72 v1(169.42,96.15) v2(168.59,96.98)
FBA_CMD7: length 38.7
  TOP w0.114: v2(176.4,112.15) 175.96,111.7 VRAM2.H5 ; v2(169.43,94.24) v1(169.03,93.84)
  L3 w0.127: v2(169.43,94.24) 171.03,95.84 171.03,96.69 171.31,96.96 171.7,96.96 171.73,96.94 175.65,96.94 175.79,97.08 175.79,98.44 175.67,98.56 174.39,98.56 174.26,98.69 174.26,99.5 174.39,99.62 176.42,99.62 176.42,99.62 178.1,99.62 178.27,99.79 179.65,99.79 179.78,99.91 179.78,100.39 179.65,100.51 178.31,100.51 178.05,100.77 178.05,102.8 178.09,102.84 178.09,111.61 177.82,111.87 177.82,113.57 177.7,113.7 177.16,113.7 177.04,113.57 177.04,112.27 176.91,112.15 v2(176.4,112.15)
  BOTTOM w0.114: GPU1.F26 168.85,93.61 169.43,94.19 v2(169.43,94.24) ; v2(176.4,112.15) 175.96,111.7 VRAM2.H5
FBA_CMD8: length 39.8
  TOP w0.114: v2(175.55,111.3) 175.19,110.95 175.19,110.94 VRAM2.J4
  L3 w0.127: v2(169.29,91.3) 168.86,91.73 168.86,92.27 168.92,92.33 168.92,94.39 170.71,96.18 170.71,98.28 170.84,98.41 171.11,98.41 171.24,98.28 171.24,97.48 171.37,97.36 171.67,97.36 171.8,97.48 171.8,98.26 171.93,98.39 172.21,98.39 172.33,98.26 172.33,97.48 172.46,97.36 175.24,97.36 175.37,97.49 175.37,97.9 175.25,98.02 173.1,98.02 172.97,98.15 172.97,99.88 173.1,100 177.5,100 177.63,100.13 177.63,102.87 177.79,103.03 177.79,110.92 177.41,111.3 v2(175.55,111.3)
  BOTTOM w0.114: VRAM2.J4 175.15,110.91 v2(175.55,111.3) ; GPU1.F23 168.9,90.9 v2(169.29,91.3)
FBA_CMD9: length 40.4
  TOP w0.114: VRAM2.J5 175.97,110.9 v2(176.43,110.44) ; v1(167.99,90.92) v2(168.44,90.46)
  L3 w0.127: v2(168.44,90.46) 168.01,90.89 168.01,91.85 168.09,91.92 168.09,92.34 168.34,92.59 168.34,94.68 169.95,96.29 169.95,100.29 170.25,100.6 171.42,100.6 172.8,101.97 172.8,102.53 172.63,102.69 172.27,102.69 172.11,102.86 172.11,103.19 172.27,103.36 172.63,103.36 172.8,103.52 172.8,105.87 172.92,106 173.33,106 173.46,105.87 173.46,101.07 173.61,100.92 175.22,100.92 175.45,101.15 175.45,102.2 175.75,102.5 175.75,103.06 177.21,104.51 177.21,107.37 176.96,107.62 176.96,107.88 177.21,108.13 177.21,108.39 176.96,108.64 176.96,108.9 177.21,109.15 177.21,109.87 176.63,110.44 v2(176.43,110.44)
  BOTTOM w0.114: VRAM2.J5 175.97,110.9 v2(176.43,110.44) ; v2(168.44,90.46) 168.05,90.06 GPU1.G22
FBA_CMD10: length 39
  TOP w0.114: v2(175.54,110.5) 175.15,110.11 VRAM2.K4
  L3 w0.127: v2(175.54,110.5) 175.96,110.92 177.07,110.92 177.5,110.49 177.5,103.6 177.23,103.32 176.66,103.32 176.53,103.19 176.53,102.79 176.66,102.66 177.04,102.66 177.21,102.5 177.21,100.59 177.08,100.46 176.66,100.46 176.53,100.59 176.53,101.71 176.4,101.83 176,101.83 175.87,101.71 175.87,100.59 175.74,100.46 173.2,100.46 173.07,100.59 173.07,100.93 172.94,101.05 172.44,101.05 171.6,100.21 170.5,100.21 170.38,100.09 170.38,99.58 170.5,99.45 172.44,99.45 172.54,99.35 172.54,98.89 172.44,98.79 170.45,98.79 170.33,98.67 170.33,96.25 169.08,95.01 168.63,94.55 168.63,92.47 168.46,92.3 v2(168.46,91.3)
  BOTTOM w0.114: v2(168.46,91.3) 168.06,90.9 GPU1.G23 ; v2(175.54,110.5) 175.15,110.11 VRAM2.K4
FBA_CMD11: length 40.2
  TOP w0.114: VRAM2.K5 176.01,110.1 v2(176.43,109.68) ; v1(168.04,92.49) v2(167.63,92.08)
  L3 w0.127: v2(176.43,109.68) 176.02,109.27 176.02,106.68 176.37,106.33 176.54,106.33 176.86,106.01 176.86,104.58 175.34,103.05 175.34,102.62 175.07,102.36 175.07,101.87 174.94,101.74 174.04,101.74 173.91,101.87 173.91,108.14 173.43,108.62 172.74,108.62 172.56,108.44 172.03,108.44 171.65,108.07 171.65,101.69 170.94,100.98 169.73,100.98 169.5,100.75 169.5,96.38 168.06,94.94 168.06,92.69 167.63,92.26 v2(167.63,92.08)
  BOTTOM w0.114: v2(167.63,92.08) 167.67,92.08 GPU1.G24 ; v2(176.43,109.68) 176.01,110.1 VRAM2.K5
FBA_CMD12: length 38.5
  TOP w0.114: v1(168.97,96.5) v2(168.49,96.22) ; v2(174.75,109.7) 174.75,109.7 VRAM2.L3
  L3 w0.127: v2(168.49,96.22) 168.82,96.22 169.12,96.52 169.12,101.23 169.25,101.36 170.76,101.36 170.89,101.48 170.89,101.81 170.76,101.94 169.16,101.94 169.04,102.06 169.04,102.41 169.24,102.6 171.07,102.6 171.23,102.77 171.23,103.1 171.07,103.26 170.17,103.26 170,103.43 170,103.76 170.17,103.92 171.07,103.92 171.23,104.09 171.23,104.42 171.07,104.58 170.17,104.58 170,104.75 170,105.08 170.17,105.24 171.07,105.24 171.23,105.41 171.23,105.74 171.07,105.9 170.17,105.9 170,106.07 170,106.4 170.17,106.56 171.07,106.56 171.23,106.73 171.23,107.06 171.07,107.22 170.17,107.22 170,107.39 170,107.72 170.17,107.89 171.07,107.89 171.23,108.05 171.23,108.64 171.11,108.77 170.2,108.77 170.08,108.89 170.08,109.43 170.2,109.56 172.55,109.56 172.96,109.15 173.61,109.15 174.04,108.72 174.73,108.72 174.97,108.96 174.97,109.48 v2(174.75,109.7)
  BOTTOM w0.114: VRAM2.L3 174.73,109.68 174.73,109.68 v2(174.75,109.7) ; GPU1.F27 168.85,95.86 168.52,96.18 168.49,96.22 v2(168.49,96.22)
FBA_CMD13: length 41
  TOP w0.114: v2(172.1,110.96) 172.4,111.25 173.2,111.25 VRAM2.J2
  L3 w0.127: v2(172.1,110.96) 171.65,110.96 171.27,110.58 170.83,110.58 170.71,110.7 170.71,115.15 170.26,115.6 169.66,115.6 169.47,115.79 169.47,116.06 169.66,116.26 170.26,116.26 170.42,116.42 170.42,116.74 170.22,116.95 168.99,116.95 168.79,116.74 168.79,110.02 169.16,109.65 169.16,103.72 168.14,102.69 168.14,97.54 v2(168.19,97.49)
  BOTTOM w0.114: v2(168.19,97.49) 168.13,97.55 167.63,97.55 R7520.2 ; v2(168.19,97.49) 168.15,97.46 168.15,96.56 168.08,96.48 168.08,96.05 168.4,95.73 168.4,92.85 GPU1.G25 ; v2(168.19,97.49) 168.57,97.88 v1(168.57,97.95) ; v2(172.1,110.96) 172.4,111.25 173.2,111.25 VRAM2.J2
FBA_CMD14: length 40.6
  TOP w0.114: v2(173.95,111.3) 174.35,110.9 VRAM2.J3 ; v2(171.66,111.41) 171.28,111.04 v1(170.4,111.04) 170.11,110.74 R7516.1
  L3 w0.127: v2(167.66,96.73) 167.59,96.81 167.59,100.22 167.46,100.34 167.08,100.34 166.95,100.47 166.95,100.72 167.08,100.85 167.46,100.85 167.59,100.98 167.59,101.23 167.46,101.36 167.08,101.36 166.95,101.49 166.95,101.74 167.08,101.87 167.46,101.87 167.59,101.99 167.59,102.68 168.74,103.84 168.74,109.47 168.37,109.85 168.37,117.2 168.57,117.4 170.64,117.4 170.84,117.2 170.84,115.78 171.15,115.47 171.15,111.92 v2(171.66,111.41) 173.83,111.41 v2(173.95,111.3)
  BOTTOM w0.114: v2(167.66,96.73) 167.79,96.61 167.79,96.59 167.86,96.52 167.86,95.96 168.05,95.77 GPU1.G27 ; v2(173.95,111.3) 173.95,111.3 VRAM2.J3
FBA_CMD15: length 38.6
  TOP w0.114: v1(168.04,95.64) v2(167.49,95.72) ; VRAM2.G3 174.35,112.5 v2(174.75,112.1)
  L3 w0.127: v2(167.49,95.72) 167.49,95.88 167.17,96.19 167.17,96.72 167.17,96.72 167.17,99 166.57,99.61 166.57,102.25 168.33,104.01 168.33,109.3 167.95,109.68 167.95,117.37 168.4,117.82 171.11,117.82 171.8,117.13 171.8,116.67 172.03,116.44 172.41,116.44 172.66,116.19 172.66,113.34 173.05,112.96 173.9,112.96 v2(174.75,112.1)
  BOTTOM w0.114: v2(167.49,95.72) 167.75,95.47 167.75,94.62 167.7,94.57 167.7,93.96 168.05,93.61 GPU1.G26 ; v2(174.75,112.1) 174.35,112.5 VRAM2.G3
FBA_CMD16: length 40.5
  TOP w0.114: VRAM3.G12 152.75,111.7 v2(152.75,111.7) ; v1(164.05,93.99) v2(163.5,93.7)
  L3 w0.127: v2(152.75,111.7) 152.27,111.21 152.27,110.62 152.1,110.46 151.83,110.46 151.66,110.29 151.66,109.96 151.83,109.79 152.1,109.79 152.27,109.63 152.27,109.3 152.1,109.13 151.83,109.13 151.66,108.97 151.66,108.64 151.83,108.47 152.1,108.47 152.27,108.31 152.27,107.89 152.1,107.73 150.85,107.73 150.72,107.6 150.72,107.2 150.85,107.07 152.1,107.07 152.27,106.9 152.27,106.57 152.1,106.41 150.95,106.41 150.82,106.28 150.82,105.88 150.95,105.75 152.12,105.75 152.24,105.62 152.24,104.58 152.45,104.38 154.44,104.38 154.57,104.25 154.57,103.7 154.44,103.57 153.79,103.57 153.66,103.45 153.66,103.19 153.79,103.07 154.44,103.07 154.57,102.94 154.57,102.68 154.44,102.56 153.79,102.56 153.66,102.43 153.66,102.18 153.79,102.05 154.44,102.05 154.57,101.92 154.57,98.22 157.58,95.2 160.64,95.2 161.25,94.59 162.54,94.59 163.44,93.7 v2(163.5,93.7)
  BOTTOM w0.114: v2(163.5,93.7) 163.5,93.69 163.51,93.68 163.51,92.08 GPU1.M24 ; VRAM3.G12 152.73,111.68 152.73,111.68 v2(152.75,111.7)
FBA_CMD17: length 39.5
  TOP w0.114: VRAM3.H10 154.13,112.1 v2(154.43,112.39) ; v1(163.49,91.88) v2(163.49,91.29)
  L3 w0.127: v2(163.49,91.29) 163.49,92.7 162.79,93.4 157.43,93.4 156.33,94.5 156.33,95.38 152.9,98.81 152.9,102.22 149.28,105.85 149.28,111.12 149.56,111.4 149.56,113.06 150.08,113.57 153.02,113.57 153.24,113.79 153.9,113.79 154.08,113.61 154.08,112.75 v2(154.43,112.39)
  BOTTOM w0.114: GPU1.M23 163.88,90.9 v2(163.49,91.29) ; v2(154.43,112.39) 154.13,112.1 VRAM3.H10
FBA_CMD18: length 40.7
  TOP w0.114: v1(164.61,92.39) v2(165.17,92.1) ; v2(153.54,112.5) 153.15,112.11 VRAM3.H11
  L3 w0.127: v2(153.54,112.5) 155.04,111.01 155.04,104.6 154.95,104.51 154.95,98.37 155.12,98.21 155.39,98.21 155.52,98.34 155.52,103.06 155.65,103.19 155.9,103.19 156.03,103.06 156.03,97.3 157.59,95.74 162.09,95.74 162.57,95.26 162.57,94.99 163.32,94.24 163.61,94.24 164.25,93.6 164.25,93.02 v2(165.17,92.1)
  BOTTOM w0.114: VRAM3.H11 153.15,112.11 v2(153.54,112.5) ; GPU1.K24 v2(165.17,92.1)
FBA_CMD19: length 40.4
  TOP w0.114: VRAM3.K11 153.15,113.67 v2(153.54,113.28)
  L3 w0.127: v2(165.17,91.3) 163.85,92.62 163.85,92.71 162.7,93.86 162.7,94.03 162.41,94.31 161.68,94.31 161.35,93.98 157.35,93.98 156.79,94.55 156.79,95.46 153.28,98.96 153.28,99.74 153.41,99.87 154.06,99.87 154.19,99.99 154.19,100.25 154.06,100.37 153.41,100.37 153.28,100.5 153.28,100.75 153.41,100.88 154.06,100.88 154.19,101.01 154.19,101.26 154.06,101.39 153.41,101.39 153.28,101.52 153.28,103.17 151.11,105.34 150.19,105.34 149.75,105.78 149.75,111.23 149.85,111.34 149.85,112.63 150.32,113.1 153.36,113.1 v2(153.54,113.28)
  BOTTOM w0.114: VRAM3.K11 153.15,113.67 v2(153.54,113.28) ; GPU1.K23 v2(165.17,91.3)
FBA_CMD20: length 38.9
  TOP w0.114: v2(154.74,113.76) 154.67,113.7 VRAM3.K10 ; v1(162.91,94.75) v2(163.5,94.7)
  L3 w0.127: v2(154.74,113.76) 155.33,113.17 155.33,104.33 156.41,103.26 156.41,97.85 156.53,97.73 156.81,97.73 156.94,97.85 156.94,102.37 157.07,102.5 157.37,102.5 157.5,102.37 157.5,97.88 157.77,97.61 157.77,97.43 157.24,96.9 157.24,96.72 157.42,96.54 157.6,96.54 158.13,97.07 158.31,97.07 159.25,96.13 162.05,96.13 163.48,94.7 v2(163.5,94.7)
  BOTTOM w0.114: GPU1.M27 163.89,94.12 163.5,94.5 v2(163.5,94.7) ; VRAM3.K10 154.67,113.7 v2(154.74,113.76)
FBA_CMD21: length 39.2
  TOP w0.114: VRAM3.L12 152.35,114.5 v2(152.75,114.1) ; v1(163.14,96) v2(163.46,95.33)
  L3 w0.127: v2(163.46,95.33) 163.46,95.33 163.31,95.33 162.03,96.61 159.31,96.61 158.49,97.43 158.49,97.89 158.36,98.02 158.06,98.02 157.93,98.15 157.93,98.4 158.06,98.53 158.36,98.53 158.49,98.65 158.49,99.04 157.88,99.64 157.88,101.69 158.06,101.87 158.85,101.87 158.97,101.99 158.97,102.73 158.85,102.86 157.99,102.86 157.29,103.55 157.11,103.55 156.97,103.41 156.79,103.41 156.61,103.59 156.61,103.77 156.75,103.91 156.75,104.09 156.57,104.27 156.4,104.27 156.25,104.13 156.07,104.13 155.89,104.31 155.89,104.49 156.04,104.63 156.04,104.81 155.75,105.1 155.75,116.3 155.57,116.48 155.12,116.48 154.89,116.25 154.89,114.54 154.62,114.27 152.91,114.27 v2(152.75,114.1)
  BOTTOM w0.114: v2(152.75,114.1) 152.35,114.5 VRAM3.L12 ; GPU1.M26 163.98,93.39 163.98,93.69 164.24,93.96 164.24,94.24 164.05,94.43 164.05,94.8 163.52,95.33 v2(163.46,95.33)
FBA_CMD22: length 39.3
  TOP w0.114: v2(158.35,113.29) 158.35,113.3 VRAM3.K4 ; v1(164.76,96.48) v2(164.96,95.93)
  L3 w0.127: v2(164.96,95.93) 164.74,95.93 164.14,96.53 163.85,96.83 163.85,97.24 162.22,98.87 162.22,99.5 162.1,99.63 160.68,99.63 160.55,99.75 160.55,100.01 160.68,100.13 162.1,100.13 162.22,100.26 162.22,100.51 162.1,100.64 160.68,100.64 160.55,100.77 160.55,101.02 160.68,101.15 162.1,101.15 162.22,101.28 162.22,101.53 162.1,101.66 160.68,101.66 160.55,101.78 160.55,102.04 160.68,102.17 162.7,102.17 162.86,102.32 162.86,104.41 162.73,104.53 160.47,104.53 159.73,105.27 158.47,105.27 156.94,106.79 156.94,109.03 157.87,109.95 157.87,110.73 158.43,111.29 158.43,113.1 158.35,113.17 v2(158.35,113.29)
  BOTTOM w0.114: GPU1.M25 164.31,92.92 164.31,93.68 164.46,93.83 164.46,94.33 164.32,94.47 164.32,95.2 164.96,95.83 v2(164.96,95.93) ; v2(158.35,113.29) 158.75,113.69 VRAM3.K4
FBA_CMD23: length 40.4
  TOP w0.114: VRAM3.K5 157.61,114.04 v2(157.5,114.04) ; v1(165.41,94.58) v2(165.01,95.15)
  L3 w0.127: v2(165.01,95.15) 165.01,95.23 163.89,96.35 163.69,96.35 163.47,96.57 163.47,96.99 162.71,97.75 161.84,97.75 161.71,97.88 161.71,99.12 161.59,99.24 161.33,99.24 161.21,99.12 161.21,97.88 161.08,97.75 160.83,97.75 160.7,97.88 160.7,99.12 160.57,99.24 160.32,99.24 160.19,99.12 160.19,97.9 160.06,97.78 159.76,97.78 159.63,97.9 159.63,99.55 160.17,100.09 160.17,102.2 160.52,102.55 162.38,102.55 162.48,102.65 162.48,103.87 162.35,104 158.47,104 158.34,104.13 158.34,104.81 156.67,106.48 156.67,111.28 157,111.61 157.49,111.61 158.13,112.25 158.13,112.87 157.91,113.09 157.91,113.64 v2(157.5,114.04)
  BOTTOM w0.114: v2(165.01,95.15) 165.01,95.01 165.33,94.69 165.33,94.37 165.22,94.26 165.22,93.75 165.57,93.4 GPU1.K26 ; v2(157.5,114.04) 157.56,114.04 157.9,113.7 VRAM3.K5
FBA_CMD24: length 40.5
  TOP w0.114: v1(166.01,89.9) v2(165.97,90.47) ; VRAM3.J4 158.76,112.9 v2(159.15,113.29)
  L3 w0.127: v2(165.97,90.47) 166.99,91.49 166.99,93.04 166.69,93.35 166.69,93.59 167.02,93.92 167.02,94.16 166.79,94.39 166.56,94.39 166.22,94.05 165.98,94.05 165.61,94.43 165.61,95.92 164.79,96.73 164.61,96.73 164.23,97.12 164.23,97.59 163,98.83 163,98.86 162.78,99.07 162.78,101.38 163.28,101.88 163.28,107.89 163.02,108.15 161.5,108.15 161.19,107.84 161.19,106.55 161.06,106.42 159.79,106.42 159.61,106.6 159.61,107.34 159.78,107.51 160.29,107.51 160.45,107.67 160.45,108 160.29,108.17 159.79,108.17 159.66,108.29 159.66,108.82 159.83,108.98 161.11,108.98 161.24,109.11 161.24,109.51 161.11,109.64 159.83,109.64 159.66,109.81 159.66,110.29 159.54,110.41 158.84,110.41 158.71,110.54 158.71,112.85 v2(159.15,113.29)
  BOTTOM w0.114: VRAM3.J4 158.76,112.9 v2(159.15,113.29) ; v2(165.97,90.47) 165.97,90.46 GPU1.K22
FBA_CMD25: length 39.9
  TOP w0.114: v1(166.49,91.55) v2(165.97,91.3) ; v2(157.47,113.31) 157.88,112.9 VRAM3.J5
  L3 w0.127: v2(157.47,113.31) 157.47,113.14 157.58,113.04 157.86,112.76 157.86,112.39 157.53,112.06 156.74,112.06 156.38,111.7 156.38,106.19 157.64,104.93 157.96,104.61 157.96,103.97 158.31,103.62 161.89,103.62 162.02,103.49 162.02,103.05 161.89,102.93 160.36,102.93 159.79,102.35 159.79,100.34 159.66,100.21 159.38,100.21 159.25,100.34 159.25,100.98 159.13,101.1 158.77,101.1 158.64,100.98 158.64,99.96 159.25,99.35 159.25,97.75 159.63,97.37 162.33,97.37 163.63,96.06 163.77,96.06 164.4,95.43 164.4,94.34 164.66,94.07 165.16,94.07 166.42,92.8 166.42,91.75 v2(165.97,91.3)
  BOTTOM w0.114: GPU1.J23 v2(165.97,91.3) ; v2(157.47,113.31) 157.88,112.9 VRAM3.J5
FBA_CMD26: length 39
  TOP w0.114: v1(166.59,94.91) v2(166.59,95.51) ; v2(159.16,112.5) 159.15,112.5 VRAM3.H4
  L3 w0.127: v2(159.16,112.5) 159.75,111.9 160.06,111.9 160.68,112.52 161.27,112.52 161.61,112.86 162.39,112.86 162.61,113.08 162.61,114.58 162.73,114.7 163.14,114.7 163.27,114.58 163.27,113.13 163.39,113 163.83,113 163.96,113.13 163.96,114.55 164.08,114.68 164.6,114.68 164.73,114.55 164.73,108.4 164.57,108.23 164.3,108.23 164.13,108.07 164.13,107.74 164.3,107.57 164.57,107.57 164.73,107.41 164.73,107.08 164.57,106.91 164.3,106.91 164.13,106.75 164.13,106.42 164.3,106.25 164.57,106.25 164.73,106.09 164.73,105.76 164.57,105.59 164.3,105.59 164.13,105.43 164.13,105.1 164.3,104.93 164.57,104.93 164.73,104.77 164.73,101.86 164,101.12 164,98.91 165.23,97.68 165.23,96.79 166.31,95.7 166.4,95.7 v2(166.59,95.51)
  BOTTOM w0.114: GPU1.J25 166.37,92.81 166.72,93.16 166.72,93.61 166.96,93.86 166.96,94.34 166.9,94.41 166.9,95.2 v2(166.59,95.51) ; v2(159.16,112.5) 158.76,112.11 158.76,112.11 VRAM3.H4
FBA_CMD27: length 38.8
  TOP w0.114: v2(157.4,112.57) 157.48,112.57 VRAM3.H5 ; v1(166.09,92.75) v2(165.97,92.1)
  L3 w0.127: v2(165.97,92.1) 165.77,92.3 165.77,92.89 165.2,93.46 164.9,93.46 164.87,93.47 164.06,94.28 164.06,95.38 163.65,95.78 163.34,95.78 162.13,96.99 159.47,96.99 158.87,97.59 158.87,99.19 158.26,99.8 158.26,101.13 158.61,101.48 159.23,101.48 159.35,101.61 159.35,103.11 159.23,103.24 158.15,103.24 157.58,103.81 157.58,104.4 156.09,105.89 156.09,115.85 156.23,116 156.72,116 156.87,115.85 156.87,113.11 v2(157.4,112.57)
  BOTTOM w0.114: VRAM3.H5 157.48,112.57 v2(157.4,112.57) ; GPU1.J24 v2(165.97,92.1)
FBA_CMD28: length 37.9
  TOP w0.114: v2(159.95,110.9) 159.95,110.9 159.56,111.3 VRAM3.G3
  L3 w0.127: v2(159.95,110.9) 160.94,110.9 161.2,111.16 161.2,112.04 161.73,112.57 164.17,112.57 164.31,112.42 164.31,112.07 164.15,111.91 162.37,111.91 162.2,111.74 162.2,111.41 162.37,111.25 164.15,111.25 164.31,111.08 164.31,110.75 164.15,110.59 162.37,110.59 162.2,110.42 162.2,110.09 162.37,109.93 164.15,109.93 164.31,109.76 164.31,109.43 164.15,109.27 162.37,109.27 162.2,109.1 162.2,108.77 162.37,108.61 163.37,108.61 163.7,108.28 163.7,104.19 163.83,104.06 164.22,104.06 164.35,103.93 164.35,103.68 164.22,103.55 163.83,103.55 163.7,103.43 163.7,101.62 163.38,101.29 163.38,98.99 164.74,97.62 v2(164.74,97.37)
  BOTTOM w0.114: VRAM3.G3 v2(159.95,110.9) ; GPU1.K27 165.57,94.92 165.45,95.04 165.45,96.2 v1(165,96.65) 164.74,96.91 v2(164.74,97.37)
FBA_CMD29: length 41
  TOP w0.114: VRAM3.J2 160.33,112.9 v2(159.94,113.29)
  L3 w0.127: v2(159.94,113.29) 160.45,113.81 160.45,114.7 160.81,115.06 160.81,117.19 161.05,117.44 162.34,117.44 162.49,117.58 162.49,119.19 162.65,119.35 162.98,119.35 163.15,119.19 163.15,117.58 163.31,117.42 165.27,117.42 165.57,117.12 165.57,101.12 165.18,100.73 165.18,98.8 166.05,97.93 v2(166.05,97.49)
  BOTTOM w0.114: R7521.2 166.1,97.45 v2(166.05,97.49) ; v2(166.05,97.49) 165.5,96.94 165.5,96.61 165.69,96.42 165.69,95.14 165.92,94.91 165.92,93.14 165.57,92.79 GPU1.K25 ; v2(166.05,97.49) 165.76,97.79 v1(165.76,98.03) ; VRAM3.J2 160.33,112.9 v2(159.94,113.29)
FBA_CMD30: length 45.3
  TOP w0.114: VRAM3.J3 159.94,112.51 v2(159.94,112.49) 161.5,112.49 v1(163.58,110.41) 164.31,109.69 R7524.1
  L3 w0.127: v2(159.94,112.49) 160.3,112.85 160.92,112.85 161.19,113.12 161.19,116.33 161.38,116.52 162.19,116.52 162.34,116.37 162.34,115.29 162.51,115.12 163.04,115.12 163.17,115.25 163.17,116.61 163.3,116.74 163.7,116.74 163.83,116.61 163.83,115.25 163.96,115.12 164.36,115.12 164.49,115.25 164.49,116.66 164.62,116.79 165.02,116.79 165.15,116.66 165.15,101.67 164.59,101.11 164.59,98.85 165.61,97.84 165.61,97.25 v2(166.1,96.75)
  BOTTOM w0.114: v2(166.1,96.75) 165.93,96.58 165.93,95.2 166.37,94.76 GPU1.J27 ; v2(159.94,112.49) 159.94,112.51 VRAM3.J3
FBA_CMD31: length 40.2
  TOP w0.114: v2(159.15,114.1) 159.55,114.5 VRAM3.L3 ; v1(166.77,96.71) v2(166.5,96.14)
  L3 w0.127: v2(159.15,114.1) 159.15,114.8 159.44,115.09 160.27,115.09 160.4,115.21 160.4,119.48 160.76,119.84 163.77,119.84 165.99,117.63 165.99,100.42 165.78,100.21 165.78,98.75 166.64,97.88 166.64,96.29 v2(166.5,96.14)
  BOTTOM w0.114: v2(166.5,96.14) 166.15,95.79 166.15,95.3 166.63,94.81 166.63,94.33 166.72,94.24 166.72,93.96 166.37,93.61 GPU1.J26 ; v2(159.15,114.1) 159.55,114.5 VRAM3.L3
FBA_D0: length 24.1
  TOP w0.114: v1(175.51,103.21) 175.51,103.96 v2(175.59,104.04)
  L6 w0.127: v2(175.59,104.04) 175.59,103.27 176.03,102.83 176.03,90.63 174.18,88.78 173.42,88.78 171.46,86.82 169.9,86.82 v2(169.37,86.29)
  BOTTOM w0.114: VRAM1.A4 175.59,104.06 v2(175.59,104.04) ; GPU1.E18 169.75,86.67 v2(169.37,86.29)
FBA_D1: length 24.8
  TOP w0.114: v2(174.73,103.38) 174.61,103.26 v1(174.16,103.26)
  L6 w0.127: v2(168.52,86.29) 168.54,86.29 169.39,87.14 171.34,87.14 173.3,89.1 173.73,89.1 175.68,91.04 175.68,98.43 175.27,98.84 175.27,102.89 174.77,103.38 v2(174.73,103.38)
  BOTTOM w0.114: GPU1.F18 168.91,86.68 v2(168.52,86.29) ; v2(174.73,103.38) 174.58,103.38 173.55,104.41 VRAM1.A2
FBA_D2: length 27
  TOP w0.114: v2(169.33,84.64) 169.33,84.63 v1(170.09,84.63)
  L6 w0.127: v2(169.33,84.64) 171.29,84.64 176.75,90.09 176.75,103.87 175.9,104.72 175.73,104.72 v2(175.55,104.9)
  BOTTOM w0.114: v2(175.55,104.9) VRAM1.B4 ; v2(169.33,84.64) 169.73,85.04 GPU1.E16
FBA_D3: length 29.3
  TOP w0.114: v2(168.52,85.48) 168.93,85.07 v1(168.94,85.07)
  L6 w0.127: v2(174.75,104.02) 175.2,104.46 175.82,104.46 176.39,103.89 176.39,90.24 176.02,89.87 176.02,89.82 171.12,84.92 169.92,84.92 169.78,85.06 168.94,85.06 v2(168.52,85.48)
  BOTTOM w0.114: v2(168.52,85.48) 168.91,85.87 GPU1.F17 ; VRAM1.B2 173.94,104.91 173.94,104.36 174.28,104.02 v2(174.75,104.02)
FBA_D4: length 25.9
  TOP w0.114: v1(171.34,89.26) v2(170.95,88.75)
  L6 w0.127: v2(170.95,88.75) 171.67,88.75 174.07,91.15 174.07,96.52 172.76,97.83 172.76,106.12 172.68,106.2 172.68,106.76 174.44,108.52 174.92,108.52 175.34,108.1 v2(175.55,108.1)
  BOTTOM w0.114: VRAM1.E4 175.15,107.7 v2(175.55,108.1) ; v2(170.95,88.75) 170.94,88.75 GPU1.D20
FBA_D5: length 26.6
  TOP w0.114: v1(170.55,88.34) v2(170.15,88.76)
  L6 w0.127: v2(170.15,88.76) 170.65,89.26 171.4,89.26 172.7,90.56 173.12,90.56 173.39,90.83 173.39,92.25 170.49,95.15 170.49,100.63 171.76,101.9 171.76,102.06 171.77,102.07 171.77,103 171.76,103.01 171.76,108.16 172.03,108.43 172.5,108.43 172.82,108.11 v2(173.15,108.11)
  BOTTOM w0.114: GPU1.D21 170.55,89.16 v2(170.15,88.76) ; v2(173.15,108.11) 173.15,108.1 VRAM1.E2
FBA_D6: length 31.6
  TOP w0.114: v2(168.51,87.96) 168.5,87.95 v1(168.5,87.33)
  L6 w0.127: v2(175.55,108.91) 175.3,109.15 172.82,109.15 172.55,109.41 171.95,109.41 171.06,108.52 171.06,102.42 169.35,100.72 169.35,95.23 172.18,92.4 172.18,90.92 171.14,89.88 170.2,89.88 169.52,89.2 169.16,89.2 168.87,88.91 168.87,88.32 v2(168.51,87.96)
  BOTTOM w0.114: v2(175.55,108.91) 175.15,108.51 VRAM1.F4 ; GPU1.F20 168.91,88.36 v2(168.51,87.96)
FBA_D7: length 27
  TOP w0.114: v2(169.33,88.78) 169.29,88.73 168.83,88.73 v1(168.69,88.6)
  L6 w0.127: v2(172.21,108.89) 172.12,108.89 171.41,108.18 171.41,102.21 169.92,100.73 169.92,95.21 172.53,92.6 172.53,90.9 171.12,89.49 170.17,89.49 169.46,88.78 v2(169.33,88.78)
  BOTTOM w0.114: VRAM1.F2 173.16,108.89 v2(172.21,108.89) ; GPU1.E21 169.75,89.2 v2(169.33,88.78)
FBA_D8: length 31.6
  TOP w0.114: v1(180.33,103.26) 180.33,104.04 v2(180.33,104.04) 180.33,104.08 VRAM2.U11
  L6 w0.127: v2(170.13,83.81) 170.33,83.81 170.73,83.41 171.18,83.41 171.57,83.81 171.88,83.81 172.1,84.03 173.01,84.03 179.36,90.38 179.36,99.23 182.94,102.8 182.94,103.32 182.65,103.6 180.77,103.6 v2(180.33,104.04)
  BOTTOM w0.114: v2(170.13,83.81) 169.75,84.19 GPU1.E15
FBA_D9: length 34.7
  TOP w0.114: v2(170.93,83.83) 170.98,83.88 v1(171.52,83.88) ; VRAM2.U13 182.35,103.89 182.45,103.78 v2(182.45,103.12)
  L6 w0.127: v2(170.93,83.83) 171.23,83.83 171.46,84.06 171.78,84.06 172.27,84.56 173.2,84.56 174.24,85.6 174.24,85.77 178.15,89.67 178.15,90.73 178.27,90.85 178.88,90.85 179.01,90.98 179.01,91.23 178.88,91.36 178.27,91.36 178.15,91.49 178.15,91.74 178.27,91.87 178.88,91.87 179.01,92 179.01,92.25 178.88,92.38 178.27,92.38 178.15,92.5 178.15,92.76 178.27,92.89 178.88,92.89 179.01,93.01 179.01,95.78 178.88,95.91 178.27,95.91 178.15,96.04 178.15,96.29 178.27,96.42 178.88,96.42 179.01,96.55 179.01,96.8 178.88,96.93 178.27,96.93 178.15,97.05 178.15,97.31 178.27,97.43 178.88,97.43 179.01,97.56 179.01,97.82 178.88,97.94 178.27,97.94 178.15,98.07 178.15,98.82 v2(182.45,103.12)
  BOTTOM w0.114: v2(170.93,83.83) 170.55,84.21 GPU1.D15
FBA_D10: length 35.7
  TOP w0.114: v2(180.35,104.9) 180.75,105.3 VRAM2.T11 ; v2(169.33,83.8) 169.72,83.41 v1(169.72,83.37)
  L6 w0.127: v2(169.33,83.8) 169.85,84.31 171.66,84.31 172.33,84.99 173.24,84.99 173.99,85.74 173.99,86.09 177.79,89.89 177.79,93.78 177.92,93.9 178.46,93.9 178.58,94.03 178.58,94.29 178.46,94.41 177.92,94.41 177.79,94.54 177.79,94.79 177.92,94.92 178.46,94.92 178.58,95.05 178.58,95.3 178.46,95.43 177.92,95.43 177.79,95.56 177.79,100.5 178.18,100.89 178.36,100.89 178.95,100.3 179.13,100.3 179.31,100.48 179.31,100.66 178.72,101.25 178.72,101.43 178.9,101.61 179.08,101.61 179.67,101.02 179.85,101.02 180.03,101.2 180.03,101.38 179.44,101.97 179.44,102.15 180.35,103.06 180.35,103.24 179.87,103.73 179.87,104.42 v2(180.35,104.9)
  BOTTOM w0.114: GPU1.F15 168.91,84.22 v2(169.33,83.8)
FBA_D11: length 36.3
  TOP w0.114: v1(183.74,102.91) 183.74,103.43 v2(183.69,103.48) 183.69,103.48 183.65,103.48 182.74,104.39 182.74,104.91 VRAM2.T13
  L6 w0.127: v2(169.31,82.15) 169.31,82.26 169.73,82.68 169.73,83.13 169.99,83.38 170.34,83.38 170.57,83.16 171.3,83.16 171.7,83.55 171.99,83.55 172.21,83.77 173.26,83.77 174.75,85.27 174.75,85.27 179.73,90.25 179.73,99.1 179.99,99.35 180.17,99.35 180.73,98.79 180.91,98.79 181.09,98.97 181.09,99.15 180.53,99.71 180.53,99.89 180.7,100.07 180.88,100.07 181.45,99.51 181.63,99.51 181.81,99.69 181.81,99.87 181.24,100.43 181.24,100.61 183.69,103.06 v2(183.69,103.48)
  BOTTOM w0.114: v2(169.31,82.15) 168.91,82.55 GPU1.F13
FBA_D12: length 38.7
  TOP w0.114: v2(181.15,108.11) 180.75,107.71 VRAM2.N11 ; v1(172.18,82.59) v2(171.76,82.16)
  L6 w0.127: v2(181.15,108.11) 181.23,108.03 184.63,108.03 184.87,107.78 184.87,106.84 185.23,106.47 185.23,100.89 181.23,96.89 181.23,89.63 174.07,82.47 174.07,82.19 173.58,81.7 172.22,81.7 v2(171.76,82.16)
  BOTTOM w0.114: GPU1.C13 171.36,82.56 v2(171.76,82.16)
FBA_D13: length 33.2
  TOP w0.114: v2(182.75,107.29) 182.75,107.3 VRAM2.N13
  L6 w0.127: v2(172.54,82.16) 172.73,82.16 173.31,82.75 173.84,82.75 180.88,89.78 180.88,97.03 184.88,101.03 184.88,106.02 183.98,106.91 183.13,106.91 v2(182.75,107.29)
  BOTTOM w0.114: v2(172.54,82.16) 172.15,82.55 GPU1.B13
FBA_D14: length 43.9
  TOP w0.114: VRAM2.M11 180.75,108.5 v2(180.35,108.9)
  L6 w0.127: v2(180.35,108.9) 180.87,109.42 184.27,109.42 185.94,107.74 185.94,100.59 185.74,100.38 181.94,96.59 181.94,89.27 176.04,83.37 176.04,82.38 175.57,81.91 174.5,81.91 173.81,81.22 171.73,81.22 171.22,81.73 170.78,81.73 170.36,82.15 v2(170.15,82.15)
  BOTTOM w0.114: GPU1.E13 169.75,82.55 v2(170.15,82.15)
FBA_D15: length 39.4
  TOP w0.114: v2(182.75,108.9) 182.35,108.5 VRAM2.M13 ; v1(170.75,82.67) v2(170.95,82.15)
  L6 w0.127: v2(182.75,108.9) 183.04,109.19 183.99,109.19 185.59,107.59 185.59,100.74 181.59,96.74 181.59,89.42 174.59,82.42 174.59,82.37 173.7,81.47 171.81,81.47 171.29,81.99 171.12,81.99 v2(170.95,82.15)
  BOTTOM w0.114: GPU1.D13 170.55,82.56 v2(170.95,82.15)
FBA_D16: length 47.8
  BOTTOM w0.114: GPU1.B15 172.5,83.89 174.06,83.89 183.87,93.7 v1(183.87,96.48) 183.87,96.96 187.75,100.85 187.75,111.63 187.72,111.66 187.72,114.85 184.32,118.25 181.08,118.25 180.74,117.91 180.74,117.5 180.75,117.49 VRAM1.U11
FBA_D17: length 44.4
  BOTTOM w0.114: VRAM1.U13 182.87,117.82 183.97,117.82 184.71,117.07 184.71,116.2 187.04,113.87 187.04,111.37 187.06,111.35 187.06,102.21 v1(184.12,99.27) 182.67,97.82 182.67,93.47 173.89,84.69 172.01,84.69 171.66,85.04 GPU1.C16
FBA_D18: length 50
  BOTTOM w0.114: VRAM1.T11 180.41,116.84 180.41,117.92 181.03,118.54 184.55,118.54 185.74,117.36 185.74,117.35 188.07,115.02 188.07,111.8 188.34,111.53 188.34,100.67 184.55,96.89 v1(184.55,94.7) 184.55,93.9 173.21,82.56 GPU1.A13
FBA_D19: length 45.1
  BOTTOM w0.114: GPU1.A15 173.92,84.24 183.31,93.62 183.31,97.31 v1(186.92,100.92) 187.41,101.41 187.41,111.49 187.38,111.52 187.38,114.71 184.05,118.03 182.57,118.03 181.99,117.45 181.99,116.86 VRAM1.T13
FBA_D20: length 39.6
  BOTTOM w0.114: GPU1.B18 172.46,86.72 172.81,86.37 173.09,86.37 173.19,86.46 174.1,86.46 180.89,93.25 v1(180.89,96.09) 180.89,98.52 185.96,103.6 185.96,110.89 185.93,110.92 185.93,112.97 184.29,114.62 183.94,114.62 183.87,114.55 181.2,114.55 VRAM1.N11
FBA_D21: length 35.5
  BOTTOM w0.114: GPU1.A18 173.87,86.72 180.25,93.1 v1(180.25,98.12) 180.25,98.37 185.62,103.74 185.62,110.49 185.59,110.51 185.59,112.52 184.32,113.79 183.95,113.79 183.92,113.76 182.81,113.76 182.47,114.1 VRAM1.N13
FBA_D22: length 34.6
  BOTTOM w0.114: VRAM1.M11 181.17,112.88 182.45,112.88 182.79,112.54 182.79,112.39 183.11,112.06 183.3,112.06 183.52,111.84 184.15,111.84 184.69,111.3 184.69,110.6 184.37,110.28 184.37,109.36 184.86,108.87 184.86,104.07 183.13,102.33 182.81,102.33 v1(178.6,98.12) 178.6,92.42 176.03,89.85 176.03,89.83 173.73,87.52 GPU1.A19
FBA_D23: length 35.2
  BOTTOM w0.114: GPU1.C19 171.7,87.17 173.84,87.17 179.36,92.7 v1(179.36,97.11) 179.36,97.97 185.27,103.88 185.27,110.35 185.25,110.37 185.25,111.28 183.67,112.86 183,112.86 182.57,113.3 VRAM1.M13
FBA_D24: length 37
  TOP w0.114: v2(171.16,118.38) 171.58,118.81 174.5,118.81 175.15,118.16 VRAM2.A4
  BOTTOM w0.114: v2(171.16,118.38) v1(169.57,116.79) 168.34,115.57 168.34,109.33 168.63,109.04 168.63,103.8 168.63,103.8 168.63,102.32 168.63,102.32 168.63,100.9 168.63,100.9 168.63,100.61 168.63,100.61 168.63,100.43 174.3,94.76 174.3,93.06 173.34,92.09 172.54,92.09 GPU1.B24
FBA_D25: length 35.6
  TOP w0.114: VRAM2.A2 173.55,117.31 v2(173.13,117.73)
  BOTTOM w0.114: v2(173.13,117.73) 172.71,118.15 172.09,118.15 170.94,116.99 170.94,116.91 169.05,115.03 v1(169.05,114.22) 169.05,109.63 169.31,109.36 169.31,103.52 169.31,103.52 169.31,102.6 169.31,101.05 174.73,95.63 174.73,92.16 173.16,90.59 172.67,90.59 172.58,90.5 171.85,90.5 171.5,90.85 GPU1.C23
FBA_D26: length 37.2
  TOP w0.114: v2(175.55,116.9) 175.15,116.5 VRAM2.B4
  BOTTOM w0.114: v2(175.55,116.9) 175.55,117.5 174.06,118.98 171.18,118.98 168,115.81 168,109.19 168.2,108.99 v1(168.2,107.43) 168.2,100.37 172.17,96.4 174.08,94.49 174.08,93.15 173.44,92.5 GPU1.A25
FBA_D27: length 35.2
  TOP w0.114: v2(173.88,117.77) 173.96,117.69 173.96,116.91 VRAM2.B2
  BOTTOM w0.114: v2(173.88,117.77) 173.88,117.94 173.44,118.39 171.75,118.39 v1(168.87,115.51) 168.69,115.33 168.69,109.47 168.97,109.19 168.97,103.66 168.97,102.46 168.97,102.46 168.97,100.76 174.52,95.21 174.52,92.97 173.31,91.76 173.01,91.76 GPU1.A24
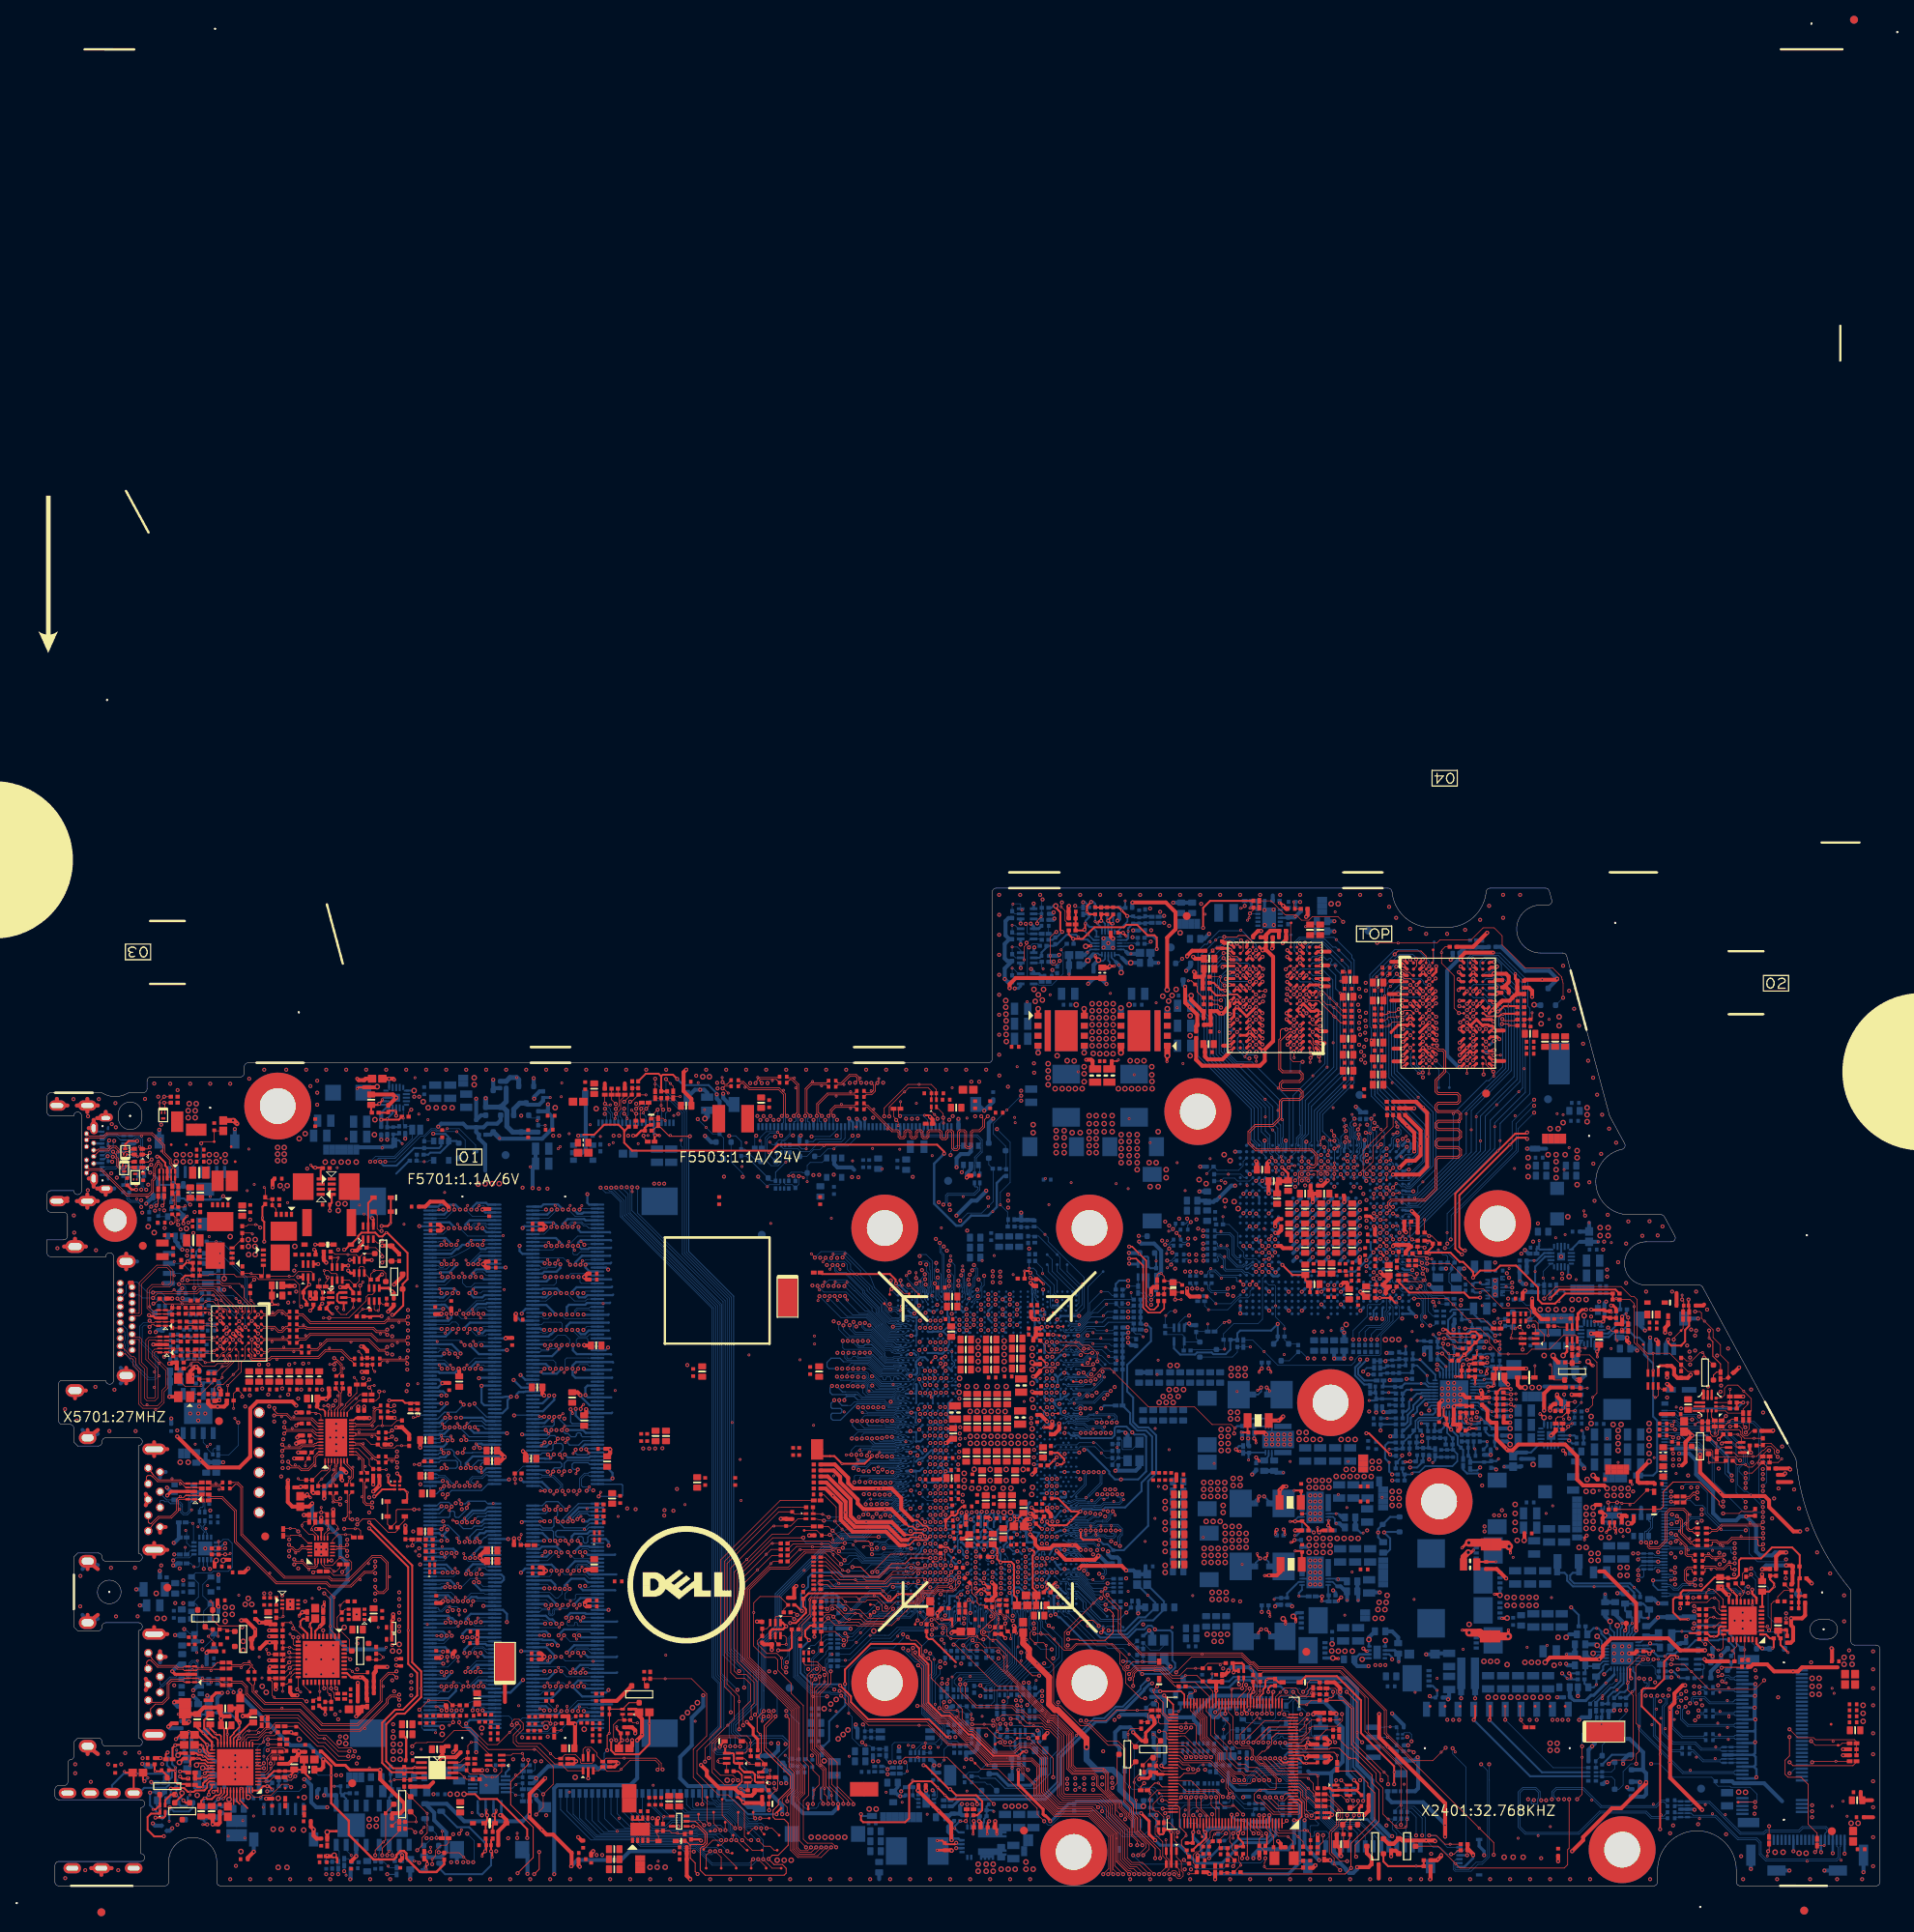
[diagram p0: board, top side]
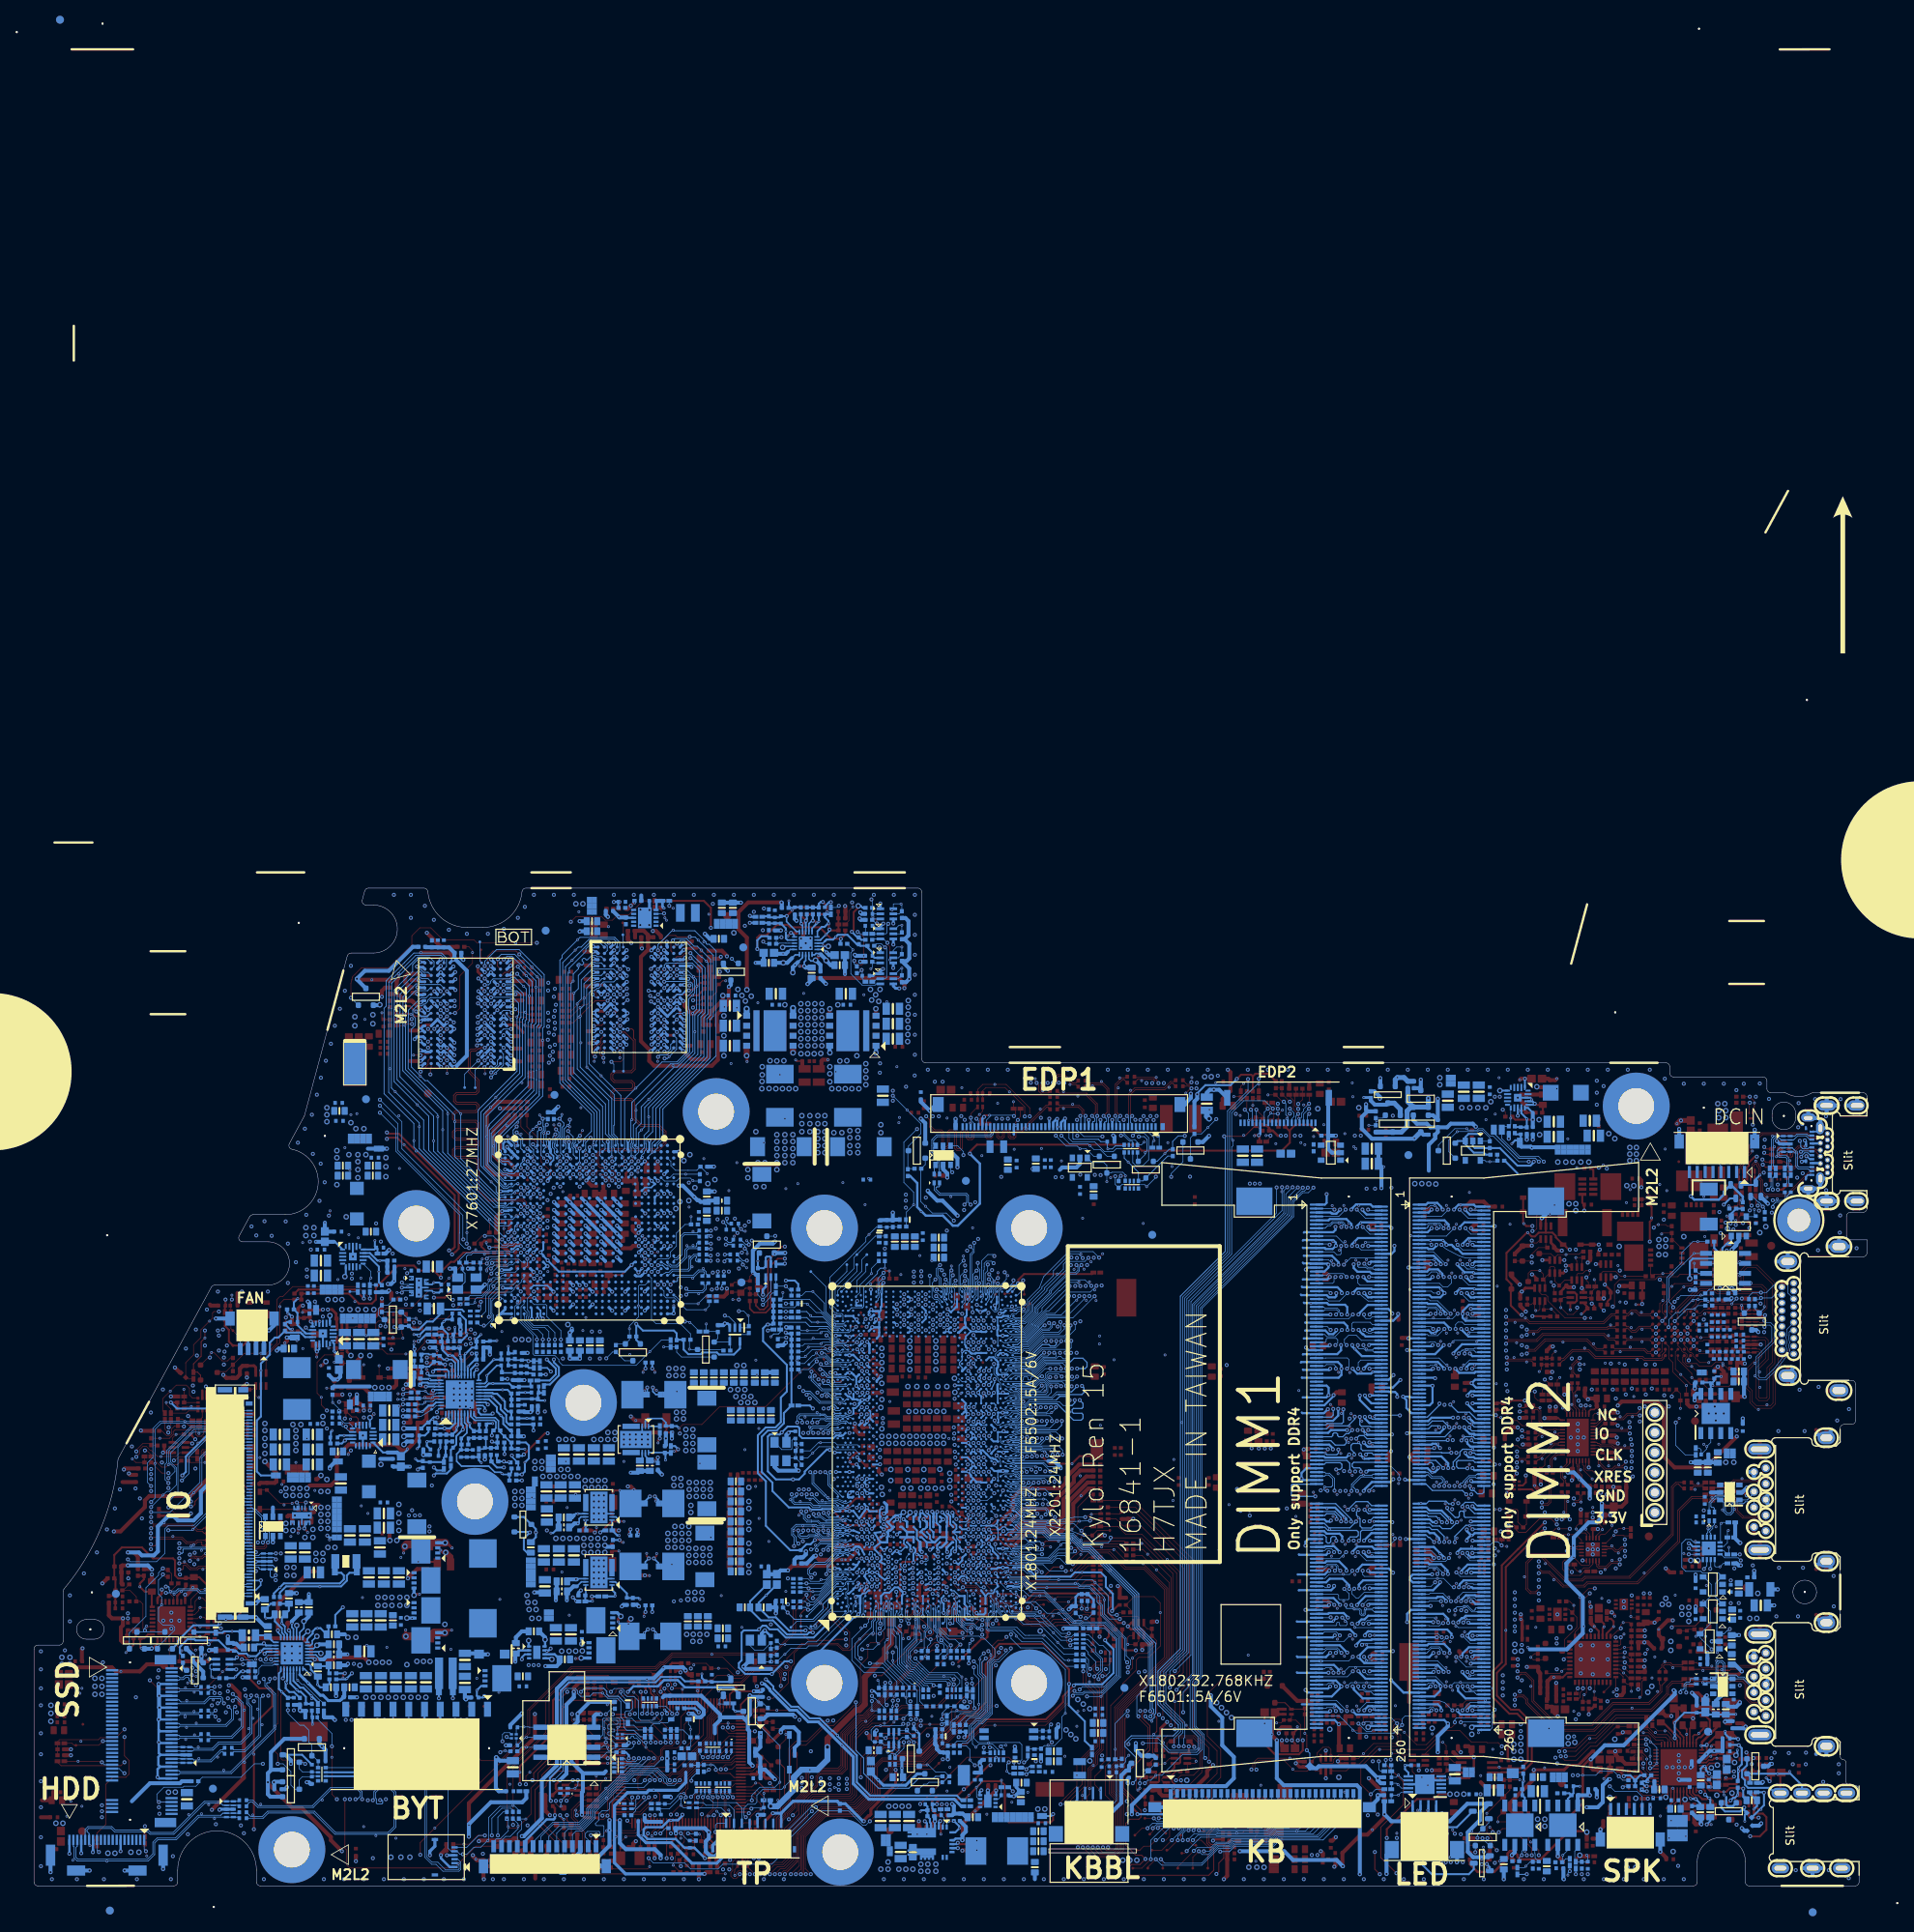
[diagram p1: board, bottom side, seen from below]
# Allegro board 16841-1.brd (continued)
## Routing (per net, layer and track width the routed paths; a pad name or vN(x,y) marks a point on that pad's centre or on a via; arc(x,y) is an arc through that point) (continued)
FBA_D28: length 34.8
  TOP w0.114: VRAM2.E4 175.55,114.5 v2(175.55,114.51)
  BOTTOM w0.114: GPU1.A21 175.38,91.63 175.38,96.58 175.36,96.6 175.36,97.78 170.42,102.71 170.42,109.94 170.28,110.08 170.28,114 v1(170.61,114.33) 171.68,115.4 172.23,115.4 172.37,115.26 174.5,115.26 174.81,114.95 174.81,114.76 175.07,114.51 v2(175.55,114.51)
FBA_D29: length 32.4
  TOP w0.114: v2(173.15,114.5) VRAM2.E2
  BOTTOM w0.114: GPU1.B21 172.46,89.2 172.81,88.85 173.09,88.85 175.7,91.45 175.7,98.06 v1(174.8,98.95) 170.76,102.99 170.76,110.08 170.62,110.22 170.62,113.39 171.74,114.51 173.14,114.51 v2(173.15,114.5)
FBA_D30: length 34.6
  TOP w0.114: v2(174.75,112.9) 175.15,113.3 VRAM2.F4
  BOTTOM w0.114: GPU1.C20 171.66,88.36 172.15,87.87 173.09,87.87 173.17,87.8 173.69,87.8 174.1,88.2 174.1,88.83 v1(174.74,89.47) 176.38,91.12 176.38,98.6 171.45,103.54 171.45,110.52 171.25,110.72 171.25,112.17 172,112.93 174.73,112.93 v2(174.75,112.9)
FBA_D31: length 33
  TOP w0.114: v2(173.16,113.7) 173.55,113.31 VRAM2.F2
  BOTTOM w0.114: v2(173.16,113.7) 173.14,113.69 171.9,113.69 171.84,113.75 171.46,113.75 170.96,113.25 170.96,110.36 171.11,110.22 171.11,103.27 v1(174.14,100.23) 176.04,98.33 176.04,91.49 173.18,88.63 172.68,88.63 172.46,88.85 172.01,88.85 171.66,89.2 GPU1.C21
FBA_D32: length 19.8
  TOP w0.114: v1(158.39,105.24) 158.39,105.98 v2(158.33,106.04) 158.33,106.08 VRAM3.A4
  L6 w0.127: v2(161.81,89.67) 160.88,90.59 160.88,92.41 160.52,92.78 160.52,95.59 159.99,96.11 159.99,102.83 158.33,104.49 v2(158.33,106.04)
  BOTTOM w0.114: v2(161.81,89.67) 161.42,90.06 GPU1.R22
FBA_D33: length 17
  TOP w0.114: v2(161.83,91.29) 162.21,91.67 v1(162.27,91.67) ; v2(160.5,105.87) 160.35,106.02 VRAM3.A2
  L6 w0.127: v2(160.5,105.87) 160.93,105.44 160.93,96.3 161.02,96.21 161.02,92.99 161.4,92.61 161.4,91.72 v2(161.83,91.29)
  BOTTOM w0.114: GPU1.R24 161.43,91.7 v2(161.83,91.29)
FBA_D34: length 20
  TOP w0.114: v2(158.34,106.88) 158.34,106.9 158.75,107.3 VRAM3.B4
  L6 w0.127: v2(158.34,106.88) 157.87,106.4 157.87,103.73 159.49,102.1 159.49,95.25 159.49,93.44 160.62,92.31 160.62,91.95 160.62,91.94 160.62,90.11 160.19,89.68 v2(160.19,89.64)
  BOTTOM w0.114: v2(160.19,89.64) 160.6,90.06 GPU1.T22
FBA_D35: length 19
  TOP w0.114: v1(160.42,104.66) 160.42,105.18 v2(160.47,105.23) 160.91,105.67 160.91,106.22 160.79,106.35 160.79,106.81 160.55,107.05 160.55,107.1 VRAM3.B2
  L6 w0.127: v2(161.79,90.48) 161.79,90.49 161.14,91.15 161.14,92.51 160.77,92.88 160.77,95.9 160.47,96.2 v2(160.47,105.23)
  BOTTOM w0.114: v2(161.79,90.48) 161.79,90.49 161.41,90.88 GPU1.R23
FBA_D36: length 23.6
  TOP w0.114: VRAM3.E4 158.74,109.7 158.34,109.31 v2(158.34,109.29) ; v1(162.78,93.48) v2(162.67,92.87)
  L6 w0.127: v2(158.34,109.29) 158.77,109.72 160.38,109.72 160.45,109.65 161.33,109.65 161.37,109.69 161.92,109.69 163.78,107.83 163.78,99.46 162.67,98.35 v2(162.67,92.87)
  BOTTOM w0.114: v2(162.67,92.87) 163.04,92.5 GPU1.N25
FBA_D37: length 20.3
  TOP w0.114: v1(161.75,94.17) 161.75,94.71 v2(162.12,95.08) ; VRAM3.E2 160.69,109.36 161.6,109.36 v2(161.7,109.27)
  L6 w0.127: v2(161.7,109.27) 161.81,109.27 163.42,107.65 163.42,99.61 162.12,98.3 v2(162.12,95.08)
  BOTTOM w0.114: GPU1.N26 162.74,93.65 162.74,94.45 v2(162.12,95.08)
FBA_D38: length 27.5
  TOP w0.114: VRAM3.F4 158.37,110.12 v2(158.37,110.11)
  L6 w0.127: v2(162.67,91.29) 163.95,92.57 163.95,97.95 164.92,98.92 164.92,101.94 164.57,102.29 164.57,108.73 161.89,111.41 161.27,111.41 159.97,110.11 v2(158.37,110.11)
  BOTTOM w0.114: GPU1.N23 163.07,90.9 v2(162.67,91.29)
FBA_D39: length 22.5
  TOP w0.114: VRAM3.F2 160.73,110.12 v2(160.73,110.11)
  L6 w0.127: v2(160.73,110.11) 161.15,110.53 161.87,110.53 164.21,108.19 164.21,99.25 163.04,98.09 163.04,93.26 163.14,93.16 163.14,92.54 v2(162.7,92.1)
  BOTTOM w0.114: v2(162.7,92.1) 162.7,92.09 GPU1.N24
FBA_D40: length 19
  L6 w0.127: v2(158.53,90.45) 158.61,90.53 158.61,91.71 158.69,91.8 158.69,94.54 156.87,96.36 156.87,102.36 154.31,104.92 154.31,105.24 153.59,105.96 v2(153.59,106.04)
  BOTTOM w0.114: VRAM4.U11 153.59,106.06 v2(153.59,106.04) ; v2(158.53,90.45) 158.93,90.85 GPU1.V23
FBA_D41: length 21.7
  TOP w0.114: v1(153.59,104.79) 153.59,105.31 v2(153.54,105.36)
  L6 w0.127: v2(158.52,89.66) 158.11,90.07 158.11,90.63 158.38,90.89 158.38,91.81 158.38,91.81 158.38,94.34 156.38,96.34 156.38,102.34 153.54,105.18 v2(153.54,105.36)
  BOTTOM w0.114: GPU1.V22 158.93,90.06 v2(158.52,89.66) ; v2(153.54,105.36) 153.3,105.6 152.36,105.6 151.55,106.41 VRAM4.U13
FBA_D42: length 21.6
  TOP w0.114: v1(160.87,90.4) 160.22,90.4 v2(160.17,90.45)
  L6 w0.127: v2(153.55,106.9) 153.63,106.82 153.88,106.82 154.18,106.51 154.74,106.51 155.02,106.23 155.02,105.21 158.64,101.59 158.64,95.77 159.26,95.15 159.26,92.84 159.78,92.31 159.78,91.91 159.77,91.9 159.77,90.85 v2(160.17,90.45)
  BOTTOM w0.114: GPU1.T23 160.61,90.89 v2(160.17,90.45) ; v2(153.55,106.9) VRAM4.T11
FBA_D43: length 24
  TOP w0.114: v2(152.73,106.04) 152.14,105.45 v1(152.14,105.37)
  L6 w0.127: v2(152.73,106.04) 153.15,106.46 153.84,106.46 153.93,106.37 154.04,106.27 154.04,105.86 154.66,105.24 154.66,105.06 157.58,102.15 157.58,96.15 158.94,94.79 158.94,91.66 158.88,91.6 158.88,90.93 158.95,90.85 158.95,90.06 158.97,90.05 v2(159.37,89.64)
  BOTTOM w0.114: v2(159.37,89.64) 159.77,90.04 GPU1.U22 ; v2(152.73,106.04) 152.7,106.02 152.28,106.02 151.94,106.36 151.94,106.91 VRAM4.T13
FBA_D44: length 24.8
  TOP w0.114: v1(156.74,92.67) v2(156.88,92.08)
  L6 w0.127: v2(156.88,92.08) 156.72,92.08 155.13,93.67 155.13,94.91 154.52,95.52 154.52,102.02 150.76,105.79 150.76,107.69 150.66,107.79 150.66,108.7 152.49,110.52 153.13,110.52 v2(153.54,110.11)
  BOTTOM w0.114: VRAM4.N11 153.54,110.09 v2(153.54,110.11) ; v2(156.88,92.08) 157.26,91.7 GPU1.Y24
FBA_D45: length 24.2
  TOP w0.114: v1(155.52,92.59) v2(156.04,92.1)
  L6 w0.127: v2(156.04,92.1) 156.04,92.22 154.17,94.09 154.17,101.46 149.73,105.9 149.73,110.13 150,110.4 150.42,110.4 150.71,110.11 v2(151.15,110.11)
  BOTTOM w0.114: v2(156.04,92.1) 156.44,91.7 GPU1.AA24 ; VRAM4.N13 151.15,110.1 v2(151.15,110.11)
FBA_D46: length 30
  L6 w0.127: v2(153.55,110.91) 151.19,110.91 150.82,111.28 150.02,111.28 149.06,110.32 149.06,105.36 153.41,101 153.41,93.72 154.2,92.94 154.2,92.04 155.75,90.49 v2(156.89,90.49)
  BOTTOM w0.114: VRAM4.M11 153.15,110.51 v2(153.55,110.91) ; GPU1.Y22 157.29,90.09 v2(156.89,90.49)
FBA_D47: length 25.8
  TOP w0.114: v1(156.1,90.69) v2(156.05,91.3)
  L6 w0.127: v2(156.05,91.3) 155.34,91.3 154.67,91.97 154.67,92.98 153.79,93.85 153.79,101.26 149.41,105.64 149.41,110.21 150.02,110.82 v2(150.22,110.82)
  BOTTOM w0.114: GPU1.AA23 156.45,90.9 v2(156.05,91.3) ; VRAM4.M13 151.16,110.89 150.29,110.89 v2(150.22,110.82)
FBA_D48: length 35.9
  TOP w0.114: VRAM3.U11 153.15,119.89 152.26,120.78 151.31,120.78 151.1,120.57 149.54,120.57 v2(149.51,120.6)
  BOTTOM w0.114: GPU1.AD27 153.95,94.17 153.31,94.81 153.31,98.84 146.96,105.19 146.96,110.09 146.52,110.53 146.52,118.27 v1(148.44,120.19) 148.82,120.57 149.47,120.57 149.5,120.6 v2(149.51,120.6)
FBA_D49: length 34.2
  TOP w0.114: v2(151.13,119.73) 151.55,119.31 VRAM3.U13
  BOTTOM w0.114: v2(151.13,119.73) 150.71,120.15 150.17,120.15 148.05,118.03 147.93,118.03 v1(147.42,117.52) 147.2,117.3 147.2,110.81 147.72,110.29 147.72,105.4 154.22,98.9 154.22,95.85 155.1,94.97 155.1,94.35 155.06,94.31 155.06,93.57 155.3,93.33 155.3,93.16 155.65,92.81 GPU1.AB25
FBA_D50: length 39.4
  TOP w0.114: VRAM3.T11 153.15,118.5 v2(153.55,118.9)
  BOTTOM w0.114: v2(153.55,118.9) 153.55,119.61 151.7,121.46 v1(151.61,121.46) 151.58,121.46 151.49,121.37 148.86,121.37 147.44,119.94 147.44,119.77 147.33,119.66 147.02,119.66 146.17,118.82 146.17,105.49 152.93,98.73 152.93,94.85 153.6,94.18 153.6,93.79 153.95,93.44 GPU1.AD26
FBA_D51: length 36.4
  TOP w0.114: VRAM3.T13 151.58,118.5 151.91,118.83 151.91,119.9 v2(151.65,120.16)
  BOTTOM w0.114: GPU1.AC25 154.8,92.66 154.3,93.16 154.3,94.36 153.82,94.84 153.82,98.81 147.34,105.29 147.34,110.19 146.86,110.67 146.86,117.72 v1(148.06,118.92) 148.55,119.42 148.95,119.42 149.92,120.39 151.42,120.39 v2(151.65,120.16)
FBA_D52: length 31.6
  TOP w0.114: VRAM3.N11 153.14,116.11 153.13,116.11 v2(152.74,116.5)
  BOTTOM w0.114: GPU1.AA27 156.32,94.23 156.32,96.28 155.68,96.92 155.68,99 v1(154.71,99.97) 148.86,105.82 148.86,110.71 148.31,111.27 148.31,116.38 149.19,117.26 152.5,117.26 152.74,117.02 v2(152.74,116.5)
FBA_D53: length 29.3
  TOP w0.114: v2(151.15,116.5) VRAM3.N13
  BOTTOM w0.114: v2(151.15,116.5) 150.86,116.5 150.85,116.49 149.94,116.49 148.65,115.2 148.65,111.42 149.12,110.95 149.12,106.05 151.12,104.05 151.51,104.05 156.34,99.22 v1(156.34,98.56) 156.34,97.02 156.67,96.69 156.67,94.37 156.8,94.24 156.8,93.96 156.45,93.61 GPU1.AA26
FBA_D54: length 30.5
  TOP w0.114: VRAM3.M11 153.15,115.3 v2(152.76,114.91)
  BOTTOM w0.114: GPU1.W26 158.13,93.35 157.78,93.7 157.78,99.96 v1(156.36,101.38) 153.03,104.71 151.14,104.71 149.77,106.08 149.77,111.19 149.87,111.28 149.87,112.97 149.13,113.7 149.13,114.61 149.37,114.85 149.9,114.85 149.98,114.93 152.51,114.93 152.53,114.91 v2(152.76,114.91)
FBA_D55: length 30.1
  TOP w0.114: VRAM3.M13 151.55,115.31 v2(151.16,115.7)
  BOTTOM w0.114: v2(151.16,115.7) 150.64,115.7 150.57,115.63 149.96,115.63 149.86,115.73 149.52,115.73 148.89,115.1 148.89,113.47 149.65,112.71 149.65,111.41 149.51,111.27 149.51,106 151.04,104.47 151.95,104.47 156.88,99.54 v1(156.88,97.36) 156.99,97.25 156.99,95.13 156.89,95.02 156.89,94.46 157.04,94.31 157.04,93.86 156.94,93.76 156.94,92.85 GPU1.Y25
FBA_D56: length 34.8
  BOTTOM w0.114: VRAM4.A4 158.75,119.49 158.74,119.5 158.74,119.91 159.13,120.3 162.31,120.3 163.3,119.31 163.67,119.31 v1(164.06,118.92) 165.65,117.33 165.65,102.19 161.65,98.19 161.65,94.72 161.76,94.6 161.76,93.65 GPU1.R26
FBA_D57: length 32.2
  BOTTOM w0.114: GPU1.T25 160.96,92.85 160.96,98.52 164.96,102.52 164.96,115.99 v1(164.82,116.13) 164.82,116.64 162.71,118.75 162.71,119.07 161.97,119.82 160.87,119.82 VRAM4.A2
FBA_D58: length 36.5
  BOTTOM w0.114: GPU1.N27 163.03,94.16 163.03,94.86 162,95.88 162,98.04 166,102.04 166,117.65 165.72,117.93 165.72,118.27 v1(163.74,120.25) 163.45,120.54 159.03,120.54 158.41,119.92 158.41,118.84 VRAM4.B4
FBA_D59: length 32.4
  BOTTOM w0.114: GPU1.R27 161.41,94.61 161.3,94.72 161.3,98.35 165.3,102.35 165.3,116.8 v1(164.46,117.65) 164.46,117.67 162.07,120.06 160.6,120.06 159.99,119.45 159.99,118.86 VRAM4.B2
FBA_D60: length 29.3
  BOTTOM w0.114: VRAM4.E4 159.16,116.51 161.91,116.51 163.3,115.13 163.3,112.7 163.8,112.19 v1(163.8,112.06) 163.8,103.82 159.8,99.82 159.8,95.5 159.28,94.97 159.28,93.96 159.08,93.76 159.08,93.45 GPU1.V26
FBA_D61: length 25.8
  BOTTOM w0.114: VRAM4.E2 160.75,115.7 161.47,115.7 161.51,115.66 161.93,115.66 162.95,114.64 162.95,111.9 163.42,111.43 v1(163.42,110.54) 163.42,104.05 159.42,100.05 159.42,95.46 158.93,94.97 GPU1.V27
FBA_D62: length 25.6
  BOTTOM w0.114: VRAM4.F4 159.17,114.88 160.48,114.88 160.79,114.57 160.79,114.35 161.08,114.06 161.3,114.06 161.59,113.77 162.03,113.77 162.3,113.5 162.3,104.49 v1(160.77,102.96) 158.27,100.46 158.27,94.24 GPU1.W27
FBA_D63: length 26.3
  BOTTOM w0.114: GPU1.W25 158.13,92.81 158.58,93.26 158.58,94.24 158.69,94.35 158.69,95.07 159.17,95.55 159.17,96.62 159.08,96.71 159.08,100.55 v1(162.58,104.05) 162.61,104.08 162.61,114.1 161.94,114.77 161.56,114.77 161.42,114.92 161.02,114.92 160.64,115.3 VRAM4.F2
FBA_DEBUG0: length 11.3
  TOP w0.089: R7501.1 170.96,96.48 v1(169.63,95.15) 168.4,93.92 168.4,92.02 167.21,90.84 167.21,90.27 167.48,90.01 168.04,90.01 v2(168.42,89.62)
  BOTTOM w0.089: GPU1.F22 168.47,89.62 v2(168.42,89.62)
FBA_DEBUG1: length 9.5
  TOP w0.089: R7503.1 170.2,96.48 v1(167.71,93.99) 167.15,93.43 167.15,91.05 166.77,90.66 v2(166.77,90.46)
  BOTTOM w0.089: GPU1.J22 v2(166.77,90.46)
FBA_DQM0: length 22.5
  TOP w0.114: v1(171.74,88.07) v2(170.96,87.93)
  L6 w0.127: v2(173.15,106.51) 173.15,98.03 174.32,96.85 174.32,91.05 171.2,87.93 v2(170.96,87.93)
  BOTTOM w0.114: VRAM1.D2 173.53,106.9 v2(173.15,106.51) ; GPU1.D19 170.96,87.93 v2(170.96,87.93)
FBA_DQM1: length 34.5
  TOP w0.114: v2(182.75,106.52) 182.37,106.9 VRAM2.P13
  L6 w0.127: v2(170.16,82.96) 170.55,82.58 172.76,82.58 173.4,83.22 173.78,83.22 180.5,89.94 180.5,97.19 184.5,101.19 184.5,106.04 183.92,106.62 182.87,106.62 182.77,106.52 v2(182.75,106.52)
  BOTTOM w0.114: v2(170.16,82.96) 170.55,83.35 GPU1.D14
FBA_DQM2: length 40.4
  BOTTOM w0.114: VRAM1.P13 182.74,115.29 183.56,115.29 183.77,115.5 184.11,115.5 186.3,113.32 186.3,111.07 186.33,111.04 186.33,102.84 181.52,98.04 v1(181.52,97.74) 181.52,93.36 174.4,86.25 173.28,86.25 173.18,86.15 172.64,86.15 172.57,86.23 171.7,86.23 GPU1.C17
FBA_DQM3: length 34.4
  TOP w0.114: v2(171.42,115.91) 171.79,115.54 172.14,115.54 172.4,115.28 173.17,115.28 VRAM2.D2
  BOTTOM w0.114: GPU1.C22 171.7,89.65 173.09,89.65 175.16,91.72 175.16,96.42 174.99,96.59 174.99,96.75 170.05,101.68 170.05,102.91 170.05,109.73 169.9,109.89 v1(169.9,113.12) 169.9,114.38 v2(171.42,115.91)
FBA_DQM4: length 19.9
  TOP w0.114: VRAM3.D2 160.37,108.9 v2(160.75,108.52)
  L6 w0.127: v2(160.75,108.52) 161.12,108.15 161.87,108.15 162.95,107.07 162.95,100.03 161.73,98.81 161.73,95.44 161.65,95.36 161.65,93.74 162.23,93.16 162.23,92.52 v2(161.82,92.12)
  BOTTOM w0.114: v2(161.82,92.12) 162.24,91.7 GPU1.P24
FBA_DQM5: length 20.9
  TOP w0.114: v1(158.01,92.65) v2(157.69,92.09)
  L6 w0.127: v2(151.15,108.51) 151.15,106.01 154.96,102.2 154.96,95.6 157.69,92.88 v2(157.69,92.09)
  BOTTOM w0.114: GPU1.W24 158.08,91.7 v2(157.69,92.09) ; VRAM4.P13 151.53,108.9 v2(151.15,108.51)
FBA_DQM6: length 32.2
  TOP w0.114: VRAM3.P13 151.53,116.9 151.12,117.31 150.01,117.31 149.42,117.89 v2(149.42,117.91)
  BOTTOM w0.114: GPU1.AA25 156.45,92.79 156,93.24 156,95.71 155.65,96.06 v1(155.65,96.07) 155.63,96.07 155.24,96.47 155.24,98.92 148.48,105.68 148.48,110.57 147.94,111.12 147.94,116.53 149.31,117.91 v2(149.42,117.91)
FBA_DQM7: length 29.8
  BOTTOM w0.114: GPU1.U25 159.42,92.85 159.42,93.79 159.5,93.87 159.5,94.85 160.22,95.58 160.22,99.36 164.22,103.36 v1(164.22,113.46) 163.66,114.02 163.66,115.7 161.97,117.39 161.6,117.39 161.5,117.29 160.74,117.29 VRAM4.D2
FBA_EDC0: length 25
  TOP w0.114: v1(169.71,87.36) 169.71,87.56 v2(169.33,87.94)
  L6 w0.127: v2(169.33,87.94) 169.81,87.46 171.28,87.46 173.22,89.41 173.61,89.41 175.3,91.1 175.3,98.2 174.75,98.75 v2(174.75,102.75)
  BOTTOM w0.114: v2(174.75,102.75) 173.19,104.31 173.19,105.74 VRAM1.C2 ; v2(169.33,87.94) 169.75,87.52 GPU1.E19
FBA_EDC1: length 35.9
  TOP w0.114: VRAM2.R13 182.74,105.71 183.57,105.71 183.71,105.57 v2(183.72,105.57) 183.72,105.57 v1(184.6,105.57)
  L6 w0.127: v2(183.72,105.57) 183.72,105.56 184.14,105.13 184.14,103.04 184.11,103.01 184.11,101.45 183.69,101.03 183.51,101.03 182.98,101.57 182.8,101.57 182.62,101.39 182.62,101.21 183.16,100.68 183.16,100.5 182.98,100.32 182.8,100.32 182.26,100.85 182.08,100.85 181.91,100.67 181.91,100.49 182.44,99.96 182.44,99.78 180.11,97.45 180.11,90.09 173.55,83.53 172.44,83.53 171.92,83 v2(171.76,83)
  BOTTOM w0.114: GPU1.C15 171.76,83.83 v2(171.76,83)
FBA_EDC2: length 41.4
  BOTTOM w0.114: GPU1.B16 172.5,85.39 173.09,85.39 173.2,85.28 173.96,85.28 182.05,93.37 v1(182.05,94.68) 182.05,97.82 186.7,102.47 186.7,111.2 186.67,111.22 186.67,113.62 183.92,116.37 183.57,116.37 183.29,116.09 182.74,116.09 VRAM1.R13
FBA_EDC3: length 34.1
  TOP w0.114: v2(171.35,116.82) 171.63,116.82 172.05,116.39 172.31,116.39 172.6,116.1 173.01,116.1 173.41,115.7 VRAM2.C2
  BOTTOM w0.114: GPU1.B22 172.34,90.19 172.6,90.19 172.77,90.35 173.23,90.35 174.95,92.07 174.95,96.05 169.68,101.32 169.68,102.75 169.68,102.75 169.68,103.36 169.68,103.36 169.68,109.51 169.53,109.66 169.53,114.93 v1(170.28,115.67) 171.35,116.74 v2(171.35,116.82)
FBA_EDC4: length 20.8
  TOP w0.114: v1(161.64,104.79) 161.64,105.29 v2(161.55,105.39) 161.88,105.71 161.88,106.29 161.33,106.83 161.32,106.83 161.22,106.94 161,106.94 160.79,107.15 160.79,107.66 VRAM3.C2
  L6 w0.127: v2(161.55,105.39) 161.55,104.83 161.67,104.7 162.36,104.7 162.48,104.57 162.48,104.32 162.36,104.19 161.67,104.19 161.55,104.07 161.55,103.81 161.67,103.68 162.36,103.68 162.48,103.56 162.48,103.3 162.36,103.18 161.67,103.18 161.31,102.81 161.31,93.39 v2(161.81,92.89)
  BOTTOM w0.114: v2(161.81,92.89) 161.42,92.5 GPU1.R25
FBA_EDC5: length 26.4
  TOP w0.114: v1(158.48,91.52) 157.93,91.52 v2(157.69,91.29)
  L6 w0.127: v2(152.7,105.15) 155.95,101.91 155.95,101.21 155.82,101.08 155.47,101.08 155.34,100.95 155.34,100.7 155.47,100.57 155.82,100.57 155.95,100.44 155.95,100.19 155.82,100.06 155.47,100.06 155.34,99.94 155.34,99.68 155.47,99.55 155.82,99.55 155.95,99.43 155.95,99.17 155.82,99.05 155.47,99.05 155.34,98.92 155.34,98.67 155.47,98.54 155.82,98.54 155.95,98.41 155.95,98.16 155.82,98.03 155.47,98.03 155.34,97.9 155.34,97.65 155.47,97.52 155.82,97.52 155.95,97.4 155.95,97.14 155.82,97.01 155.47,97.01 155.34,96.89 155.34,96.63 155.47,96.51 155.82,96.51 155.95,96.38 155.95,95.22 158.15,93.02 158.15,91.74 v2(157.69,91.29)
  BOTTOM w0.114: v2(152.7,105.15) 152.68,105.13 152.37,105.13 151.19,106.31 151.19,107.74 VRAM4.R13 ; v2(157.69,91.29) 158.08,90.9 GPU1.W23
FBA_EDC6: length 31.9
  TOP w0.114: v2(149.43,118.54) 150.1,118.54 150.54,118.1 151.15,118.1 VRAM3.R13
  BOTTOM w0.114: GPU1.AB26 155.65,93.45 155.3,93.8 155.3,94.24 155.31,94.26 155.31,95.37 154.73,95.95 v1(154.73,97.73) 154.76,97.75 154.76,98.88 148.1,105.54 148.1,110.43 147.57,110.97 147.57,116.68 v2(149.43,118.54)
FBA_EDC7: length 31.3
  BOTTOM w0.114: VRAM4.C2 160.74,118.09 161.29,118.09 161.47,118.27 161.93,118.27 162.51,117.69 162.67,117.69 162.86,117.88 163.02,117.88 163.18,117.72 163.18,117.56 162.99,117.37 162.99,117.21 163.15,117.04 163.31,117.04 163.5,117.23 163.66,117.23 163.83,117.07 163.83,116.91 163.64,116.72 163.64,116.56 164.31,115.89 v1(164.31,114.98) 164.59,114.71 164.59,103.06 160.59,99.06 160.59,94.57 160.26,94.24 160.26,93.65 GPU1.T26
FBA_MF1: length 4.1
  TOP w0.089: R7811.2 170.32,109.21 v1(170.45,109.35) 170.9,109.79 171.87,109.79 v2(172.14,110.06)
  BOTTOM w0.089: v2(172.14,110.06) 172.75,110.68 VRAM1.J1
FBA_MF2: length 3.6
  TOP w0.089: VRAM2.J1 172.33,110.48 171.53,110.48 v1(171.47,110.43) 170.4,110.43 169.95,109.97 R7812.1
FBA_MF3: length 5.2
  TOP w0.089: VRAM3.J1 161.42,113.17 161.42,113.45 161.52,113.55 161.52,113.55 161.68,113.71 162.03,113.71 v1(162.94,112.81) 164.54,111.21 R7911.2
FBA_MF4: length 5.4
  TOP w0.089: R7910.1 164.62,110.45 v1(163.44,111.62) 163.11,111.96 162.57,111.96 161.85,112.67 v2(161.85,113.3)
  BOTTOM w0.089: VRAM4.J1 161.46,112.9 v2(161.85,113.3)
FBA_PLL_AVDD: length 10.2
  TOP w0.406: C7505.1 168.05,85.1 v2(168.52,84.64)
  TOP w0.508: C7506.1 162,88.99 v2(162.65,89.64)
  BOTTOM w0.356: v2(168.52,84.64) 168.52,84.65 GPU1.F16 ; v2(162.65,89.64) 162.25,90.04 GPU1.P22 ; v2(167.55,89.59) 167.55,89.72 GPU1.H22
  BOTTOM w0.508: v2(150.9,88.99) 150.39,88.99 v1(148.95,87.55) 148.53,87.13 148.36,87.13 148.15,86.93 C7518.1 147.19,87.08 L7501.1
FBA_SEN0: length 11.4
  TOP w0.089: R7810.2 177.57,119.34 177.11,118.88 v1(177.11,118.6) 177.11,117.26 178.71,115.66 178.71,111.54 v2(179.32,110.93) 179.35,110.9 VRAM2.J10
  BOTTOM w0.089: v2(179.32,110.93) 179.35,110.9 VRAM2.J10
FBA_SEN2: length 9.6
  TOP w0.089: VRAM3.J10 154.3,112.9 154.51,113.1 v2(154.53,113.1) ; v2(149.54,114.43) 149.02,114.96 v1(149.02,115.53) R7909.2
  L6 w0.089: v2(149.54,114.43) 149.66,114.43 150.45,113.65 153.32,113.65 153.37,113.7 153.94,113.7 v2(154.53,113.1)
  BOTTOM w0.089: v2(154.53,113.1) 154.51,113.1 154.3,112.9 VRAM3.J10
FBA_VREF_FET_H: length 7.3
  TOP w0.508: R7905.2 145.94,109.27 R7902.2 146.09,110.71 v1(145.1,111.7) 144.55,112.25 v2(144.55,114.26)
  BOTTOM w0.508: Q7901.D 144.29,114.51 v2(144.55,114.26)
FBA_VREF_FET_L: length 15.5
  TOP w0.508: v2(191.79,115.28) 191.66,115.15 v1(189.89,115.15) 187.73,115.15 R7804.2
  BOTTOM w0.508: Q7801.D 191.79,115.2 v2(191.79,115.28) 190.77,116.29 187.73,116.29 184.68,119.34 R7803.2
FBA_VREFC0: length 8.8
  TOP w0.356: v2(183.57,111.28) 183.53,111.28 VRAM2.J14 ; v1(186.48,115.91) 186.48,115.28 R7804.1
  TOP w0.508: R7807.1 186.79,113.35 C7803.1 ; C7803.1 186.63,113.37 186.41,113.14 186.35,113.14 186.13,112.92 186.13,112.87 185.74,112.48 184.81,112.48 184.68,112.36 184.66,112.36 183.94,111.64 183.93,111.64 v2(183.57,111.28) ; C7803.1 186.74,113.4 R7806.2 186.74,115.02 R7804.1
  BOTTOM w0.356: v2(183.57,111.28) 183.53,111.28 VRAM2.J14
FBA_VREFC1: length 7.5
  TOP w0.33: VRAM3.J14 150.75,112.87 v2(150.33,112.45)
  TOP w0.356: 150.16,112.28 v2(150.33,112.45)
  TOP w0.508: 150.16,112.28 150.16,111.82 149.79,111.45 149.79,111.33 149.34,110.88 v1(149.14,110.88) 148.9,110.88 148.61,111.17 R7904.1 147.76,110.31 C7902.1 147.79,109.45 R7903.2 146.98,109.44 R7902.1
  BOTTOM w0.356: v2(150.33,112.45) 150.33,112.46 150.75,112.87 VRAM3.J14
FBA_VREFD_H: length 35.6
  TOP w0.305: v2(154.46,106.09) 154.45,106.09 154.05,106.5 VRAM3.A10
  TOP w0.356: VRAM3.U10 153.99,119.3 v2(154.39,118.9)
  TOP w0.508: C7908.1 156.46,121.35 R7901.1 155.35,121.38 154.81,120.84 R7907.2 ; R7905.1 145.94,104.99 146.71,104.23 v1(151.66,104.23) 154.05,104.23 154.66,104.84 154.66,105.89 v2(154.46,106.09) 155.72,107.35 155.72,118.07 154.88,118.9 v2(154.39,118.9) 154.81,119.32 R7907.2 ; R7907.2 C7903.1
  BOTTOM w0.356: VRAM3.A10 154.36,106.09 v2(154.46,106.09) ; VRAM3.U10 153.99,119.3 v2(154.39,118.9)
FBA_VREFD_L: length 27.6
  TOP w0.356: v2(179.55,117.73) 179.95,117.34 VRAM2.A10 ; v2(179.4,104.05) 179.55,104.05 179.95,104.45 VRAM2.U10
  TOP w0.508: v2(179.55,117.73) 179.55,118.05 180.11,118.6 v1(183.66,118.6)
  BOTTOM w0.356: v2(179.55,117.73) 179.95,117.34 VRAM2.A10 ; VRAM2.U10 179.95,104.42 179.58,104.05 v2(179.4,104.05)
  BOTTOM w0.508: v2(179.4,104.05) 179.28,104.05 177.82,105.51 177.82,116.29 179.26,117.73 v2(179.55,117.73) 179.39,117.89 R7805.2 180.08,119.26 C7802.1 C7826.1 181.53,119.29 R7809.1 183.05,119.29 R7803.1
FBA_WCK01: length 51.1
  TOP w0.114: v1(173.71,87.41) 173.71,87.26 ; 173.71,87.26 170.66,87.26 170.25,86.85 170.25,86.4 v2(170.14,86.28) ; 173.71,87.26 174.92,87.26 176.28,88.62 176.28,92.38 176.63,92.72 179.15,92.72 179.41,92.98 179.41,93.46 179.15,93.71 176.63,93.71 176.28,94.06 176.28,94.66 176.63,95.01 179.15,95.01 179.41,95.26 179.41,95.74 179.15,96 176.63,96 176.28,96.34 176.28,96.95 176.63,97.29 179.15,97.29 179.41,97.55 179.41,98.03 179.15,98.28 176.63,98.28 176.28,98.63 176.28,99.23 176.63,99.58 179.06,99.58 179.27,99.78 179.27,100.37 179.06,100.57 176.63,100.57 176.28,100.91 176.28,102.41 177.4,103.53 177.4,105.92 177.21,106.11 176.67,106.11 176.38,106.4 176.19,106.4 176.07,106.51 v2(175.54,106.51) VRAM2.P4
  BOTTOM w0.114: VRAM2.P4 v2(175.54,106.51) ; v2(170.14,86.28) 170.14,86.31 GPU1.D18
FBA_WCK01#: length 51.4
  TOP w0.114: 172.05,87.02 170.76,87.02 170.49,86.75 170.49,86.51 170.73,86.28 v2(170.94,86.28) ; 172.05,87.02 v1(172.05,86.85) ; 172.05,87.02 175.02,87.02 176.52,88.52 176.52,92.28 176.73,92.48 179.25,92.48 179.65,92.88 179.65,93.56 179.25,93.95 176.73,93.95 176.52,94.16 176.52,94.56 176.73,94.77 179.25,94.77 179.65,95.16 179.65,95.84 179.25,96.24 176.73,96.24 176.52,96.44 176.52,96.85 176.73,97.05 179.25,97.05 179.65,97.45 179.65,98.13 179.25,98.52 176.73,98.52 176.52,98.73 176.52,99.13 176.73,99.34 179.16,99.34 179.51,99.68 179.51,100.47 179.16,100.81 176.73,100.81 176.52,101.01 176.52,102.31 177.64,103.43 177.64,106.02 177.31,106.35 176.77,106.35 176.54,106.58 v2(176.54,106.82) 176.38,106.97 176.02,106.97 VRAM2.P5
  BOTTOM w0.114: v2(176.54,106.82) 176.38,106.97 176.02,106.97 VRAM2.P5 ; GPU1.C18 171.07,86.72 170.94,86.59 v2(170.94,86.28)
FBA_WCK23: length 47.1
  TOP w0.114: v2(175.55,115.3) 175.15,114.9 VRAM2.D4 ; v1(170.55,85.88) v2(170.16,85.48)
  L3 w0.127: v2(170.16,85.48) 170.37,85.48 170.75,85.85 171.31,85.85
  L3 w0.14: 171.31,85.85 171.79,85.85 185.97,100.03 185.97,110.59 183.87,112.69 183.83,112.69 182.12,114.41 176.28,114.41 175.71,114.97 175.71,115.14 v2(175.55,115.3)
  BOTTOM w0.114: GPU1.D17 170.16,85.49 v2(170.16,85.48) ; VRAM2.D4 175.15,114.9 v2(175.55,115.3)
FBA_WCK23#: length 47.2
  TOP w0.114: VRAM2.D5 176.33,115.28 176.33,115.29 v2(176.36,115.32) ; v1(171.55,85.17) v2(170.95,85.43)
  L3 w0.14: v2(176.36,115.32) 176.1,115.32 175.98,115.2 175.98,115.08 176.39,114.67 182.23,114.67 183.95,112.96 183.98,112.96 184,112.93 186.23,110.7 186.23,99.92 171.87,85.56 171.08,85.56 v2(170.95,85.43)
  BOTTOM w0.114: v2(176.36,115.32) 176.33,115.29 176.33,115.28 VRAM2.D5 ; GPU1.D16 170.55,85.23 170.76,85.43 v2(170.95,85.43)
FBA_WCK45: length 41.4
  TOP w0.114: v2(160.19,91.27) 160.93,91.27 161.36,91.7 161.36,92.96 160.67,93.65 156.23,93.65 ; 156.23,93.65 153.58,93.65 152.77,94.47 152.77,95.76 153.52,96.52 155.74,96.52 156.77,97.55 156.77,99.62 156.97,99.82 159.14,99.82 159.53,100.22 159.53,100.9 159.14,101.29 156.97,101.29 156.77,101.5 156.77,101.9 156.97,102.11 159.14,102.11 159.53,102.5 159.53,103.18 159.14,103.58 156.97,103.58 156.68,103.87 156.68,107.42 157.77,108.51 v2(158.37,108.51) 158.75,108.89 VRAM3.D4 ; 156.23,93.65 v1(156.23,93.81)
  BOTTOM w0.114: GPU1.T24 160.61,91.69 v2(160.19,91.27) ; VRAM3.D4 158.75,108.89 v2(158.37,108.51)
FBA_WCK45#: length 41.5
  TOP w0.114: 154.25,93.41 160.57,93.41 161.11,92.86 161.11,91.8 160.91,91.6 160.62,91.6 160.5,91.72 160.41,91.72 160.2,91.92 v2(160.2,92.08) ; 154.25,93.41 v1(154.25,93.26) ; 154.25,93.41 153.48,93.41 152.53,94.37 152.53,95.86 153.42,96.76 155.63,96.76 156.53,97.65 156.53,99.72 156.87,100.06 159.04,100.06 159.29,100.32 159.29,100.8 159.04,101.05 156.87,101.05 156.53,101.4 156.53,102 156.87,102.35 159.04,102.35 159.29,102.6 159.29,103.08 159.04,103.34 156.87,103.34 156.44,103.77 156.44,107.52 156.64,107.72 156.64,108.7 156.87,108.93 157.31,108.93 v2(157.4,108.84) 157.47,108.9 VRAM3.D5
  BOTTOM w0.114: GPU1.U24 160.01,91.7 160.2,91.9 v2(160.2,92.08) ; v2(157.4,108.84) 157.47,108.9 VRAM3.D5
FBA_WCK67: length 42.2
  TOP w0.114: VRAM3.P4 158.75,116.9 v2(158.36,116.51)
  L3 w0.14: v2(158.36,116.51) 158.11,116.76 158.11,116.98 157.84,117.25 150.44,117.25 148.4,115.21 148.4,104.37 151.01,101.76 151.01,98.99 157.43,92.57 157.95,92.57 158.24,92.28 158.24,91.62 158.58,91.28 159.33,91.28 v2(159.34,91.29)
  BOTTOM w0.114: v2(158.36,116.51) 158.75,116.9 VRAM3.P4 ; v2(159.34,91.29) GPU1.V24
FBA_WCK67#: length 43.3
  TOP w0.114: VRAM3.P5 157.74,116.9 v2(157.33,116.48) ; v2(159.36,92.08) 159.4,92.12 v1(159.4,92.66)
  L3 w0.14: v2(159.36,92.08) 159.36,91.85 159.22,91.71 159.15,91.71 158.99,91.55 158.69,91.55 158.51,91.73 158.51,92.39 158.06,92.84 157.54,92.84 157.46,92.92 151.28,99.1 151.28,101.87 148.67,104.48 148.67,115.1 150.55,116.99 157.73,116.99 157.84,116.87 157.84,116.33 157.73,116.22 157.44,116.22 157.33,116.33 v2(157.33,116.48)
  BOTTOM w0.114: v2(157.33,116.48) 157.74,116.9 VRAM3.P5 ; v2(159.36,92.08) 159.05,92.08 158.93,92.21 GPU1.V25
FBA_ZQ0: length 5.1
  TOP w0.254: R7808.1 186.61,111.8 v1(185.59,111.8) 185.05,111.8 184.38,111.13 v2(184.28,111.13)
  BOTTOM w0.203: VRAM1.J13 182.46,110.9 182.86,110.51 183.65,110.51 v2(184.28,111.13)
FBA_ZQ1: length 4.7
  TOP w0.203: VRAM2.J13 182.47,110.9 182.85,110.52 184.43,110.52 184.66,110.75 v1(184.93,110.75)
  TOP w0.254: v1(184.93,110.75) 185.02,110.83 186.68,110.83 R7813.1
FBA_ZQ2: length 4.5
  TOP w0.203: VRAM3.J13 151.15,113.3 150.06,113.3 149.93,113.17 v1(149.12,113.17)
  TOP w0.254: v1(149.12,113.17) 148.48,113.17 R7912.1
FBA_ZQ3: length 4.7
  TOP w0.254: v2(149.62,113.8) 149.52,113.89 149.06,113.89 v1(148.61,114.34) 148.18,114.77 R7913.1
  BOTTOM w0.203: 150.23,113.54 150.48,113.29 151.12,113.29 151.51,112.9 VRAM4.J13
  BOTTOM w0.254: v2(149.62,113.8) 149.98,113.8 150.23,113.54
FFS_INT1: length 174.5
  TOP w0.089: v2(125.4,32.72) 124.86,32.18 124.86,31.46 125.42,30.9 126.56,30.9 v1(126.89,30.57) 126.89,29.01 127.84,28.06 127.84,23.28 128.22,22.9 128.72,22.9 131.24,20.38 132.26,20.38 134.77,17.87 136.16,17.87 136.74,17.3 136.74,10.65 137.52,9.87 137.52,9.01 138.08,8.46 138.08,6.82 139.59,5.3 139.59,4.91 v2(138.58,3.9) ; v2(213.22,59.71) 213.22,59.7 R7012.1
  L6 w0.089: v2(138.58,3.9) 139.6,4.92 144.65,4.92 145.59,5.85 155.56,5.85 156.07,6.36 156.64,6.36 156.84,6.16 160.42,6.16 161.18,6.92 163.63,6.92 163.76,6.79 170.09,6.79 171.84,8.54 194.01,8.54 196.76,11.29 202.62,11.29 204.94,13.61 212.76,13.61 215.67,16.52 216.77,16.52 219.6,19.35 219.6,22.25 220.75,23.4 220.75,26.13 219.25,27.63 219.25,30.32 218.08,31.49 218.08,32.74 218.1,32.76 218.1,35.84 218.46,36.2 218.46,41.09 217.11,42.44 217.11,43.15 217.09,43.55 217.09,43.56 217.09,52.67 216.13,53.63 216.13,54.13 214.78,55.49 214.78,58.15 213.22,59.71 v2(213.22,59.71)
  BOTTOM w0.089: v2(125.4,32.72) 125.38,32.72 124.91,33.19 124.91,34.04 125.04,34.17 125.04,34.94 124.99,34.99 124.95,35.12 124.95,35.29 124.93,35.5 CPU1.M3
FFS_INT2: length 178.5
  TOP w0.089: D7001.3 209.32,55.43 211.37,55.43 211.56,55.24 211.56,54.44 211.7,54.29 R7008.2 212.27,54.5 214.41,54.5 214.85,54.06 v2(215.03,54.06) ; v2(117.55,31.2) 117.81,30.95 118.38,30.95 119.07,30.26 120.94,30.26 121.94,29.26 v1(121.94,27.9) 121.94,27.33 127.02,22.24 127.53,21.74 128.06,21.74 130.31,19.49 130.31,18.94 130.31,15.35 130.7,14.95 134.2,14.95 134.82,14.34 134.82,12.26 135.45,11.62 136.48,10.59 136.48,10.09 137.33,9.24 137.33,8.93 137.88,8.39 137.88,6.51 139.11,5.28 v2(139.11,5.17)
  L6 w0.089: v2(215.03,54.06) 215.43,54.06 216.89,52.61 216.89,43.47 216.89,43.46 216.91,43.14 216.91,42.35 218.26,41.01 218.26,36.28 217.9,35.92 217.9,32.84 217.88,32.82 217.88,31.4 219.04,30.23 219.04,27.55 220.54,26.05 220.54,23.47 219.41,22.33 219.41,19.45 216.67,16.71 215.59,16.71 212.69,13.82 204.86,13.82 202.53,11.49 196.67,11.49 193.92,8.75 171.77,8.75 170.02,7 163.84,7 163.71,7.12 161.09,7.12 160.33,6.36 156.93,6.36 156.73,6.56 155.99,6.56 155.48,6.06 145.48,6.06 144.54,5.12 139.16,5.12 v2(139.11,5.17)
  BOTTOM w0.089: CPU1.AC2 118.31,35.58 118.31,35.15 118.36,35.02 118.36,32.6 117.75,32 117.75,31.4 v2(117.55,31.2) 116.78,30.43 116.78,29.49 R2044.2
FFS_INT2_Q: length 65.2
  TOP w0.089: R6001.1 v2(218.71,7.58) ; Q7001.6 214.27,55.06 214.76,54.57 v1(216.68,54.57) 217.11,54.57 217.88,55.33 218.02,55.33 218.52,55.84 218.97,55.84 219.37,55.44 219.37,54.96 v2(219.81,54.52)
  L4 w0.089: v2(219.81,54.52) 219.81,52.21 221.1,50.91 221.1,44.98 222.73,43.35 222.73,18.18 225.24,15.67 225.24,7.55 224.91,7.22 219.08,7.22 v2(218.71,7.58)
FFS_INT2_Q_R: length 3.2
  TOP w0.089: v1(218.49,3.8) 218.49,4.3 v2(218.59,4.41) 218.71,4.53 R6001.2
  BOTTOM w0.089: HDD1.1 218.8,4.62 v2(218.59,4.41)
FP1_USB20_N: length 2.7
  BOTTOM w0.089: 116.88,33.87 116.88,34.23 116.67,34.44 116.67,34.82 CPU1.AG1
  BOTTOM w0.102: TP1603.1 116.88,32.87 116.88,33.87
FP1_USB20_P: length 2.5
  BOTTOM w0.089: 117.11,33.87 117.11,33.88 117.08,33.91 117.08,33.95 117.07,33.96 117.07,34.31 116.86,34.52 116.86,35.04 116.6,35.3 CPU1.AG2
  BOTTOM w0.102: 117.11,33.87 117.11,33.57 117.32,33.36 TP1604.1
FPR_SCAN#: length 5
  TOP w0.089: KBC24.42 153.24,24.02 153.65,24.43 153.65,26.34 R2458.2 153.18,27.42 v1(152.88,27.72)
GC6_FB_EN: length 249.8
  TOP w0.127: v2(113.34,22.59) 113.41,22.59 113.94,22.07 114.65,22.07 117.11,19.61 117.54,19.61 120.29,16.86 122.91,16.86 123.63,17.58 124.82,17.58 126.32,16.08 126.32,11.89 128.39,9.82 132.67,9.82 135.84,6.66 135.84,6.04 135.84,3.08 v2(137.43,1.48) ; v2(169.31,75.53) 169.26,75.58 R7519.2 ; D8301.1 211.64,64.9 212.03,65.29 R7623.1 212.54,66.34 211.57,67.31 211.57,69.16 v1(211.09,69.63) v2(211.09,70.57)
  L3 w0.127: v2(169.31,75.53) 169.31,75.5 172.46,72.35 172.91,72.35 174.47,70.79 174.82,70.79 175.24,71.21 175.24,71.38 176,72.14 181.84,72.14 182.96,71.02 184.74,71.02 185.5,70.26 187.2,70.26 187.71,70.76 187.71,74.36 189.12,75.77 199.29,75.77 200.86,74.19 205.86,74.19 207.51,72.54 209.88,72.54 211.09,71.33 v2(211.09,70.57)
  L4 w0.127: v2(211.09,70.57) 212.17,69.49 212.17,68.4 212.87,67.7 212.87,66 214.14,64.73 214.14,61.44 218.33,57.24 218.33,56.6 219.22,55.71 219.22,52.41 220.86,50.78 220.86,48.46 v2(219.1,46.7)
  L6 w0.127: v2(137.43,1.48) 137.44,1.48 137.88,1.93 138.18,1.93 140.53,4.28 144.93,4.28 145.59,4.94 147.95,4.94 148.42,4.47 149.3,4.47 149.84,5 156.64,5 156.93,5.29 161.73,5.29 161.75,5.28 162.28,5.28 162.83,5.82 167.87,5.82 168.6,5.09 171.15,5.09 173.47,7.41 194.55,7.41 197.3,10.16 203.14,10.16 205.45,12.47 213.02,12.47 216.08,15.52 217.36,15.52 220.59,18.76 220.59,21.84 222.05,23.29 222.05,29.12 220.25,30.91 220.25,32.72 219.61,33.36 219.61,35.27 219.69,35.34 219.69,42.59 219.1,43.18 v2(219.1,46.7)
  BOTTOM w0.127: R2004.1 113.43,23.91 113.43,22.68 v2(113.34,22.59)
GC6_FB_EN_GPU: length 59.6
  TOP w0.089: R7623.2 213.35,64.43 R7627.1 213.53,66.48 212.54,67.48 212.54,68.75 211.6,69.68 211.6,70.67 v1(210.5,71.77) 210.12,72.15 210.12,72.81 209.95,72.99 v2(209.32,72.99)
  L3 w0.089: v2(175.03,72.31) 175.37,72.65 182.05,72.65 182.47,72.22 184.81,72.22 186.52,70.51 187.12,70.51 187.47,70.86 187.47,74.48 189.01,76.02 199.62,76.02 201.14,74.51 206.14,74.51 207.67,72.99 v2(209.32,72.99)
  BOTTOM w0.089: GPU1.C6 171.5,76.8 171.89,76.41 173.5,76.41 175.03,74.89 v2(175.03,72.31)
GC6_FB_EN_MCP: length 15.6
  L4 w0.089: v2(112.17,37.94) 112.17,37.93 112.66,37.44 112.66,34.29 112.84,34.11 112.84,31.41 112.73,31.3 112.73,26.66 v2(113.66,25.72)
  BOTTOM w0.089: R2004.2 113.56,25.62 v2(113.66,25.72) 113.69,25.75 v1(113.69,26.38) ; CPU1.AP7 112.64,37.94 v2(112.17,37.94)
GC6_THM_DIS#: length 118.3
  TOP w0.089: v2(143.4,27.14) 145.33,29.07 151.76,29.07 152.73,28.1 153.09,28.1 153.81,27.37 164.25,27.37 167.79,23.84 167.79,19.52 172.74,14.57 v1(172.74,8.47) 172.74,7.71 172.36,7.33 171.47,7.33 169.68,9.12 169.68,12.42 168.8,13.3 168.8,14.31 165.63,17.49 165.25,17.49 164.1,18.63 R2490.1
  L3 w0.089: v2(139.21,33.23) 139.21,29.92 141.99,27.14 v2(143.4,27.14)
  L4 w0.089: v2(120.05,41.15) 120.05,40.87 119.61,40.43 119.61,35.86 120.5,34.96 120.5,34.01 120.11,33.61 119.83,33.61 119.32,33.1 119.32,32.74 119.92,32.15 119.92,31.34 119.53,30.95 119.53,28.41 120.66,27.27 120.66,21.93 v2(121.43,21.16)
  L6 w0.089: v2(139.21,33.23) 135.91,29.93 131.11,29.93 127.04,25.87 125.9,25.87 124.35,24.32 124.35,23.46 123.85,22.95 123.85,22.69 123.21,22.06 122.07,22.06 121.43,21.42 v2(121.43,21.16)
  BOTTOM w0.089: v2(120.05,41.15) 119.97,41.24 119.66,41.24 119.65,41.23 119.41,41.23 119.25,41.4 119.25,41.88 CPU1.AB13
GC6_THM_DIS#_EC: length 6.6
  TOP w0.089: KBC24.23 159.29,18.18 159.91,18.81 v1(160.12,18.81) 161.34,18.81 R2426.2 162.45,19.82 R2471.2 R2490.2
GPD11/LANPHYPC: length 40.7
  L4 w0.089: v2(110,17.72) 109.32,18.39 106.59,18.39 105.96,17.76 103.25,17.76 102.28,18.73 102.28,23.42 102.01,23.69 102.01,31.88 102.38,32.25 102.38,32.26 104.12,34 104.29,34 104.41,34.12 104.41,35.01 106.89,37.49 106.89,38.12 107.71,38.94 107.71,41.6 108.4,42.3 108.4,43.54 109.67,44.81 v2(109.67,45.09)
  BOTTOM w0.089: CPU1.AW17 110.04,44.73 v2(109.67,45.09) ; RN1704.5 109.67,17.39 109.67,17.39 v2(110,17.72) 109.85,17.87 v1(109.37,17.87)
GPIO5_GC6_PWR_EN: length 130.5
  TOP w0.089: v1(195.19,85.79) 195.19,85.33 v2(195.35,85.18) ; R7633.2 184.77,71.79 v2(184.55,71.58) 184.6,71.53 R7636.2
  L4 w0.089: v2(124.3,122.26) 127.51,125.47 168.14,125.47 173.12,120.49 185.08,120.49 187.52,118.06 187.52,116.88 193.57,110.83 193.57,94.96 195.35,93.18 v2(195.35,85.18)
  L6 w0.089: v2(195.35,85.18) 195.17,85.01 195.17,77.01 193.95,75.78 192.68,75.78 191.03,74.13 187.08,74.13 185.95,73 185.95,72.97 v2(184.55,71.58)
  BOTTOM w0.089: v2(124.3,122.26) 124.48,122.08 124.48,121.12 124.61,120.99 PQ8307.2 PR8330.1
GPIO5_GC6_PWR_EN#: length 3.3
  BOTTOM w0.089: PQ8307.6 123.37,121.64 122.93,122.08 v1(122.58,122.08) PR8319.1 122.75,120.99 PQ8307.5
GPIO5_GC6_PWR_EN_GPU: length 12.5
  TOP w0.089: R7636.1 183.66,70.83 182.39,72.1 180.36,72.1 v1(178.59,73.87) 177.82,74.64 v2(173.63,74.64)
  BOTTOM w0.089: GPU1.A3 173.29,74.64 v2(173.63,74.64)
GPIO5_GC6_PWR_EN_R: length 120.2
  TOP w0.089: v2(128.18,121.23) 128.09,121.23 127.41,120.56 v1(127.41,118.2) 127.41,117.28 127.67,117.02 128.08,117.02 v2(128.62,117.56)
  L3 w0.089: v2(122.07,87.08) 123.97,88.99 123.97,99.53 v2(123.72,99.78)
  L4 w0.089: v2(123.72,99.78) 124.61,100.67 124.61,113.97 125.98,115.34 127.25,115.34 128.62,116.71 v2(128.62,117.56) ; v2(122.07,87.08) 122.32,87.34 123.08,87.34 123.55,86.87 134.22,86.87 136.1,84.99 137.66,84.99 138.82,84.99 139.8,84.01 139.8,79.39 140.89,78.29 142.4,76.78 147.59,76.78 149.82,74.55 152.39,74.55 152.73,74.88 158.86,74.88 159.04,74.71 162.31,74.71 162.51,74.91 163.8,74.91 164,74.71 164.61,74.71 167.75,71.56 173.76,71.56 174.1,71.91 176.3,71.91 176.85,72.45 181.59,72.45 183.39,74.26 183.66,74.26 v2(186.08,76.67)
  BOTTOM w0.089: v2(186.08,76.67) 185.84,76.43 U8301.3 ; v2(128.62,117.56) 128.62,117.18 R8306.2 ; v2(128.18,121.23) 128.11,121.23 127.87,120.99 PR8330.2 127.2,121.98 C8309.1
GPIO9_ALERT: length 13.1
  TOP w0.089: v2(176.04,74.24) 176.3,73.98 v1(176.3,73.7)
  L3 w0.089: v2(168.49,77.98) 168.85,77.62 168.85,76.87 169.94,75.79 169.94,75.57 171.64,73.87 173.5,73.87 174.26,74.64 175.64,74.64 v2(176.04,74.24)
  BOTTOM w0.089: RN7610.2 176.22,73.06 176.04,73.24 v2(176.04,74.24) ; GPU1.F8 168.91,78.4 v2(168.49,77.98)
GPIO10_FBVREF: length 130.4
  TOP w0.089: v2(168.93,119.85) 168.96,119.82 v1(171.6,119.82) 176.52,119.82 176.93,120.23 180.87,120.23 182.39,121.75 183.79,121.75 184.81,120.74 184.81,119.59 187.73,116.67 191.2,116.67 192.03,115.85 192.34,115.54 192.38,115.4 192.38,115.38 192.43,115.18 192.43,115.14 192.55,114.7 v2(192.55,112.86) ; v2(170.97,75.54) 171.39,75.96 R7610.1
  L3 w0.089: v2(170.97,75.54) 170.97,77.73 175.4,82.16 v2(178.28,82.16)
  L4 w0.089: v2(188.87,99.15) 186.66,101.36 186.66,112.73 184.56,114.83 184.56,117.3 183.69,118.17 172.08,118.17 170.96,119.29 169.44,119.29 168.93,119.8 v2(168.93,119.85) 168.88,119.85 168.51,120.22 160.73,120.22 159.91,119.41 159.91,118.2 159.4,117.68 158.98,117.68 158.86,117.56 150.26,117.56 150.01,117.31 144.67,117.31 v2(144.17,117.82)
  BOTTOM w0.089: Q7901.G 143.58,117.23 v2(144.17,117.82) ; v2(192.55,112.86) 191.61,111.92 Q7801.G ; v2(178.28,82.16) 178.33,82.21 178.33,85.22 186.59,93.47 186.59,96.87 v2(188.87,99.15) ; v2(170.97,75.54) 170.98,75.54 170.98,75.59 171.34,75.95 GPU1.C5
GPU_CLKREQ#: length 10.8
  BOTTOM w0.089: R7305.2 158.74,68.87 Q7301.S 157.17,69.39 R7303.1 v1(157.17,70.8) 157.17,71.16 156.03,72.3 156.03,76.23 155.89,76.38 155.17,76.38 GPU1.AC6
GPU_EVENT#: length 213.6
  TOP w0.089: v2(138.07,1.48) 138.04,1.48 137.61,1.91 137.34,1.91 136.07,3.18 136.07,6.79 132.8,10.06 128.48,10.06 126.56,11.99 126.56,16.18 124.9,17.83 123.55,17.83 122.81,17.09 120.41,17.09 117.64,19.86 117.22,19.86 115.81,21.27 115.81,22.09 v1(115.58,22.32) 114.04,22.32 113.78,22.58 113.78,23.22 v2(113.91,23.35)
  L4 w0.089: v2(217.93,51.7) 216.72,52.91 213.74,52.91 210.33,56.32 210.33,57.48 209.4,58.41 208.65,58.41 205.99,61.07 198.13,61.07 196.74,62.45 195.44,62.45 193.57,64.32 193.57,69.14 192.32,70.38 188.42,70.38 188.16,70.65 v2(188.16,71.08)
  L6 w0.089: v2(217.93,51.7) 217.93,51.45 218.85,50.52 218.85,47.57 219.93,46.49 219.93,35.22 219.84,35.14 219.84,33.49 220.51,32.83 220.51,31.02 222.29,29.24 222.29,23.2 220.83,21.74 220.83,18.66 217.46,15.29 216.18,15.29 213.1,12.21 205.55,12.21 203.24,9.9 197.4,9.9 194.66,7.16 173.55,7.16 171.24,4.86 168.5,4.86 167.77,5.59 162.93,5.59 162.38,5.04 157.03,5.04 156.74,4.75 149.97,4.75 149.44,4.22 148.33,4.22 147.85,4.7 145.69,4.7 145.01,4.02 140.61,4.02 v2(138.07,1.48)
  BOTTOM w0.089: v2(188.16,71.08) 188.16,71.84 Q7606.D 188.49,71.97 189.04,72.52 189.04,73.37 R7644.1 187.85,73.8 R7648.1 ; R2003.1 114.32,23.9 114.26,23.84 114.26,23.69 v2(113.91,23.35)
GPU_EVENT_GPU#: length 20.8
  L3 w0.089: v2(174.65,71.21) 175.83,72.39 181.94,72.39 182.75,71.59 183.78,71.59 v2(183.8,71.57)
  BOTTOM w0.089: v2(174.65,71.21) 174.65,71.7 174.44,71.91 174.44,72.55 174.65,72.76 174.65,74.35 173.9,75.1 GPU1.A4 ; R7644.2 186.16,72.94 Q7606.S 185.25,72.02 R7649.1 185.08,72.12 v1(184.3,72.12) 183.8,71.62 v2(183.8,71.57)
GPU_EVENT_MCP#: length 16.7
  TOP w0.089: v1(114.45,26.25) 114.45,25.82 v2(114.32,25.69)
  L4 w0.089: v2(114.32,25.69) 114.11,25.9 114.11,25.91 112.99,27.03 112.99,31.25 113.23,31.5 113.23,32.81 114.48,34.05 114.48,34.88 113.94,35.41 113.94,37.23 113.48,37.69 v2(113.48,38.92)
  BOTTOM w0.089: v2(113.48,38.92) 113.8,39.24 CPU1.AN8 ; v2(114.32,25.69) R2003.2
GPU_I2CA_SCL: length 7.7
  BOTTOM w0.089: RN7401.1 176.99,73.95 v1(176.8,74.13) 176.8,74.51 176.56,74.75 175.91,74.75 174.94,75.72 174.94,76.31 174.14,77.11 173.55,77.11 173.49,77.18 172.57,77.18 GPU1.B7
GPU_I2CA_SDA: length 6.6
  BOTTOM w0.089: RN7401.2 177.41,75.02 175.92,75.02 175.13,75.8 175.13,76.66 v1(174.77,77.02) 174.49,77.3 173.63,77.3 173.33,77.6 GPU1.A7
GPU_NC_F11: length 1.2
  TOP w0.254: TP7701.1 v2(169.37,80.49)
  BOTTOM w0.254: v2(169.37,80.49) 168.93,80.92 GPU1.F11
GPU_PEX_RST#: length 17.9
  BOTTOM w0.089: GPU1.AC7 154.75,77.6 154.37,77.22 154.37,72.01 153.82,71.46 150.72,71.46 149.42,70.17 R7312.1 149.55,69.28 v1(149.55,68.21) 149.5,68.16 D7301.3 145.36,68.16 R7313.2
GPU_PEX_RST_HOLD: length 7.3
  BOTTOM w0.089: v1(152.83,68.49) R7630.2 R7631.2 151.18,67.83 150.55,67.21 D7301.1
GPU_PEX_RST_HOLD_GPU#: length 28.7
  BOTTOM w0.089: GPU1.C4 170.96,74.71 170.96,74.13 171.23,73.86 171.5,73.86 171.73,73.63 171.73,72.29 169.44,70 169.44,67.62 169.22,67.4 166.64,67.4 166.14,66.89 166.14,66.64 165.65,66.15 156.33,66.15 v1(154.58,67.91) 153.13,69.35 R7630.1
GPU_PLL_VDD: length 4
  TOP w0.508: C7606.1 165.15,76.08 165.15,76.54 C7605.1 164.66,76.67 v2(164.31,76.32)
  BOTTOM w0.356: GPU1.L6 v2(164.31,76.32)
  BOTTOM w0.508: v1(164.49,70.83) 164.49,70.57 v2(164.74,70.32) L7601.2
GPU_PWR_LEVEL: length 4.8
  TOP w0.089: KBC24.10 159.08,12.98 159.89,12.18 159.89,11.37 v1(160.1,11.17) 160.31,11.17 161.36,10.12 R2477.2
GPU_ROM_SCLK: length 6.5
  TOP w0.089: v2(174.96,81.11) 174.83,81.24 R7621.1 174.06,80.76 R7620.2
  BOTTOM w0.089: GPU1.C12 171.65,81.76 172,81.4 172.44,81.4 172.66,81.18 174.89,81.18 v2(174.96,81.11) 175.35,81.51 v1(175.35,81.75)
GPU_ROM_SI: length 8.2
  TOP w0.089: R7635.2 175.88,82.59 v2(175.53,82.59) 175.11,83.02 R7624.1 174.95,83.78 174.94,83.79 v1(174.94,84.68)
  BOTTOM w0.089: v2(175.53,82.59) 174.47,82.59 173.3,81.42 172.75,81.42 172.41,81.76 GPU1.B12
GPU_ROM_SO: length 3.8
  TOP w0.089: R7632.1 173.12,84.29 v1(173.12,83.53) 173.12,82.39 v2(173.37,82.15) 173.51,82 R7618.2
  BOTTOM w0.089: v2(173.37,82.15) 173.34,82.15 172.95,81.76 GPU1.A12
GPU_THM_SMBCLK: length 4.5
  TOP w0.089: R2459.1 160.83,12.2 160.83,13.02 v1(160.19,13.65) 160.06,13.78 KBC24.12
GPU_THM_SMBDAT: length 4.3
  TOP w0.089: KBC24.11 159.19,13.38 v1(160.17,12.41) 160.86,11.72 160.86,11.41 R2447.1
GSEN2_INT1: length 3.1
  TOP w0.102: v1(211.84,57.49) 211.84,58.34 R7009.2 R7012.2 211.42,59.53 U7001.12
GSEN2_INT1_C: length 2.2
  TOP w0.102: R7009.1 213,58.38 v1(213.63,59.02) 213.94,59.32 R2025.2
GSEN2_INT1_ISH: length 210.9
  TOP w0.089: v2(134.13,1.48) 134.83,2.19 134.83,6.25 132.26,8.82 127.94,8.82 125.32,11.44 125.32,12.84 123.79,14.37 123.79,14.92 123.48,15.23 119.44,15.23 116.8,17.87 114.45,17.87 111.91,20.41 v1(110.76,20.41) 104.33,20.41 101.42,23.32 101.42,23.61 v2(100.86,24.17) ; R2033.2 216.57,57.82 215.94,57.19 215.93,57.19 215.92,57.19 215.57,57.19 215.32,57.44 215.32,58.07 214.93,58.46 R2025.1 213.84,58.46 v2(213.76,58.38)
  L6 w0.089: v2(213.76,58.38) 214.27,57.87 214.27,55.33 214.57,55.03 214.57,52.67 214.89,52.35 214.89,44.33 215.29,43.93 215.29,37.1 215.79,36.6 215.79,32.09 215.52,31.82 215.52,21.06 211.18,16.72 205.47,16.72 205.22,16.98 197.61,16.98 195.13,14.49 181.19,14.49 178.76,12.06 159.2,12.06 157.04,9.89 149.52,9.89 147.85,8.22 145,8.22 144.88,8.1 144.35,7.57 144.35,6.57 144.06,6.28 142.06,6.28 141.21,7.12 138.05,7.12 134.64,3.72 134.64,1.99 v2(134.13,1.48)
  BOTTOM w0.089: CPU1.BA7 108.51,38.59 108.24,38.32 107.78,38.32 107.67,38.43 107.3,38.43 106.15,37.28 104.51,37.28 100.8,33.58 99.85,33.58 99.62,33.35 96.8,33.35 95.01,31.56 95.01,26.62 97.13,24.5 99.38,24.5 99.55,24.33 100.69,24.33 v2(100.86,24.17)
GSEN2_INT2: length 3.2
  TOP w0.089: v1(209.32,58.63) 209.62,58.94 R7013.2 R7010.2 210.92,58.99 U7001.11
GSEN2_INT2_C: length 8.8
  TOP w0.102: R2026.2 v1(216.81,56.88) 216.81,56.88 215.59,56.88 215.36,57.11 215.12,57.35 215.12,57.72 214.89,57.95 212.34,57.95 212.24,57.85 212.24,57.36 212.01,57.14 211.57,57.14 211.27,57.43 211.27,57.77 R7010.1
GSEN2_INT2_ISH: length 216.2
  TOP w0.089: v2(219.81,55.21) 219.81,55.38 218.97,56.22 218.13,56.22 R2026.1 217.88,55.97 R2034.2
  L3 w0.089: v2(206.52,7.68) 207.31,8.47 213.63,8.47 220.75,15.58 220.75,15.84 221.25,16.34 221.51,16.34 222.88,17.72 222.88,20.52 222.6,20.8 222.6,44.06 221.31,45.35 221.31,50.71 219.98,52.03 219.98,53.68 219.35,54.32 219.35,54.75 v2(219.81,55.21)
  L4 w0.089: v2(206.52,7.68) 206.5,7.66 197.12,7.66 194.46,5 185.95,5 185.7,5.24 173.73,5.24 173.1,5.88 165.41,5.88 164.11,7.17 156.33,7.17 155.47,8.04 147.04,8.04 146.78,8.29 143.87,8.29 141.92,10.25 140.75,10.25 137.6,13.39 137.6,15.05 136.01,16.64 126.71,16.64 125.86,15.8 118.72,15.8 117.61,16.91 112.18,16.91 111.73,16.46 109.48,16.46 109.28,16.66 100.65,16.66 100.02,17.28 97.61,17.28 93.45,21.44 93.45,22.68 94.3,23.53 94.3,28.06 v2(93.96,28.41)
  BOTTOM w0.089: CPU1.AY7 109.1,38.65 108.89,38.86 107.2,38.86 106.24,37.9 v1(104.16,37.9) 100.16,37.9 100.1,37.84 98.76,37.84 97.78,36.87 97.78,36.08 97.29,35.58 97.29,34.4 94.28,31.39 94.28,28.73 v2(93.96,28.41)
GSEN_INT1: length 4.8
  TOP w0.089: R2023.2 70.84,99.43 v2(70.86,99.4) 71.01,99.25 v1(71.55,99.25)
  BOTTOM w0.089: v2(70.86,99.4) 71.55,98.72 71.55,98.46 71.82,98.19 71.82,97.68 72.05,97.44 TCBD1.5
GSEN_INT1_ISH: length 113.3
  TOP w0.089: v1(74.32,88.23) 74.32,88.76 v2(74.29,88.78) ; R2031.2 R2023.1 71.7,99.91 v2(72.23,99.38)
  L3 w0.089: v2(72.23,99.38) 72.42,99.19 73.51,99.19 73.81,98.89 73.81,97.75 75.33,96.23 75.33,93.43 74.29,92.39 v2(74.29,88.78) ; v2(87.9,27.29) 89,27.29 89.81,26.48 93.02,26.48 93.45,26.91 93.45,27.32 93.87,27.74 v2(93.87,27.77)
  BOTTOM w0.089: CPU1.BA8 109.06,39.21 108.94,39.1 107.16,39.1 106.32,38.26 100.25,38.26 100.02,38.03 98.68,38.03 97.43,36.78 97.43,36 97.1,35.67 97.1,34.48 94.08,31.46 94.08,29.25 93.53,28.7 93.53,28.12 v2(93.87,27.77) ; v2(87.9,27.29) 85.86,29.34 85.86,74.24 74.29,85.81 v2(74.29,88.78)
GSEN_INT2: length 4.8
  TOP w0.089: R2024.2 73.38,100.37 72.85,99.84 72.85,98.71 v2(72.24,98.11) 72.16,98.02 v1(72.16,97.52)
  BOTTOM w0.089: v2(72.24,98.11) 72.55,97.8 TCBD1.6
GSEN_INT2_ISH: length 125.9
  TOP w0.089: v2(72.23,98.74) 72.66,99.17 72.66,100.4 R2024.1 R2032.2
  L3 w0.089: v2(99.06,24.07) 97.89,22.9 90.24,22.9 89.72,22.39 87.17,22.39 86.89,22.11 86.89,22.1 v2(86.84,22.06) ; v2(72.94,88.78) 72.94,92.52 71.27,94.19 71.27,96.23 71.76,96.72 71.76,98.27 v2(72.23,98.74)
  BOTTOM w0.089: v2(86.84,22.06) 86.84,24.64 86.23,25.26 86.23,26.15 85.48,26.9 85.48,73.81 73.81,85.48 73.81,87.92 v2(72.94,88.78) ; CPU1.BB7 107.78,38.59 107.75,38.62 107.24,38.62 106.15,37.53 104.49,37.53 100.73,33.77 99.77,33.77 99.54,33.54 96.72,33.54 94.81,31.63 94.81,26.54 v1(97.28,24.07) v2(99.06,24.07)
GSENSOR_CS: length 1.9
  TOP w0.089: R7006.1 213.48,60.92 v1(212.82,60.92) U7001.2
GSENSOR_SDO: length 3.5
  TOP w0.089: U7001.3 213.73,61.42 R7005.2 R7007.2 213.74,63.08 v1(213.76,63.11)
GT_CORE: length 1.4
  BOTTOM w0.203: v2(131.01,65.16) 130.85,64.99 CPU1.A53
  BOTTOM w0.254: v2(131.11,62.47) 131.07,62.51 CPU1.A48
  vias: v1(124.1,61.56) v3(125.12,63.86) v3(125.12,61.81) v3(125.24,60.79)
GTX_CORE: length 1.1
  BOTTOM w0.102: CPU1.AM52 114.92,64.06 115.34,64.48
  vias: v1(115.08,62.57) v2(115.87,61.91) v3(115.89,64.5) v3(115.84,62.72)
GYRO_DRDY: length 5.3
  TOP w0.102: v1(76.07,100.52) 75.15,100.52 R2028.2 74.24,99.66 v2(74.06,99.66)
  BOTTOM w0.102: TCBD1.8 73.55,97.73 73.81,97.99 73.81,99.4 v2(74.06,99.66)
GYRO_DRDY_ISH: length 164.5
  TOP w0.089: R2053.2 R2036.2 74.32,100.6 R2028.1 74.19,100.54 v2(73.3,99.66)
  L3 w0.089: v2(108.73,30.19) 109.12,30.58 109.54,30.58 109.92,30.95 109.92,30.99 110.43,31.5 112.53,31.5 112.77,31.74 112.77,32.06 112.82,32.12 112.82,34.02 110.72,36.12 110.72,37.11 110.06,37.76 110.06,38.95 110.21,39.1 110.21,41.14 111.23,42.17 112.42,42.17 v2(112.83,42.57) ; v2(91.71,13.04) 92.27,12.48 94.1,12.48 95.54,13.93 104.63,13.93 106.82,16.13 107.27,16.13 v2(107.69,15.71) ; v2(71.01,88.73) 71.01,89.24 70.63,89.62 70.63,93.27 70.16,93.74 70.16,96.68 70.25,96.77 70.25,98.53 70.27,98.55 70.27,98.99 70.25,99 70.25,99.53 70.38,99.66 70.38,99.91 70.51,100.04 72.92,100.04 v2(73.3,99.66)
  BOTTOM w0.089: CPU1.AP13 v2(112.83,42.57) ; v2(91.71,13.04) 91.33,13.42 90.95,13.42 v1(90.32,14.06) 89.56,14.06 86.91,16.7 85.04,16.7 84.42,17.32 84.42,19.2 85.43,20.2 85.43,25.82 84.67,26.58 84.67,73.46 73.11,85.01 73.11,85.04 73.01,85.15 73.01,87 71.7,88.31 71.44,88.31 v2(71.01,88.73) ; v2(108.73,30.19) 108.73,29.96 110.23,28.46 110.82,28.46 111.09,28.19 111.09,21.85 112.36,20.58 112.76,20.58 113.41,19.94 113.41,18.73 112.9,18.22 107.61,18.22 107.34,17.94 107.34,16.03 107.66,15.71 v2(107.69,15.71)
GYRO_INT: length 193.8
  TOP w0.089: R7002.2 214.61,53.52 v1(215.73,53.52) 216.02,53.22 216.58,53.22 217.45,54.09 217.45,54.12 R7003.2 217.9,54.77 218.46,55.33 v2(218.71,55.33)
  L4 w0.089: v2(218.71,55.33) 217.95,56.09 217.95,57.29 213.91,61.34 213.91,64.31 210.01,68.2 210.01,70.6 207.56,73.06 206.83,73.06 205.29,74.6 200.46,74.6 198.75,76.31 190.83,76.31 189.35,77.79 187.41,77.79 184.86,80.34 182.67,80.34 180.62,82.38 179.47,82.38 177.27,80.18 177.27,77.51 175.41,75.65 174.26,75.65 173.5,76.41 172.74,76.41 170.64,74.32 168.6,74.32 165.57,77.35 160.73,77.35 158.26,79.81 158.26,84.26 155.44,87.08 154.99,87.08 154.39,87.68 154.39,87.97 153.75,88.61 153.28,88.61 151.82,90.07 151.07,90.07 150.26,90.87 146.8,90.87 146.71,90.78 145.72,90.78 144.88,89.94 144.88,88.11 142.9,86.13 136.56,86.13 134.66,88.02 126.7,88.02 118.04,96.68 85.15,96.68 85.14,96.69 82.48,96.69 79.78,99.39 77.22,99.39 76.73,98.89 76.73,98.26 76.09,97.62 74.44,97.62 v2(73.3,98.77)
  BOTTOM w0.089: TCBD1.7 73.05,97.49 72.79,97.75 72.79,98.26 v2(73.3,98.77)
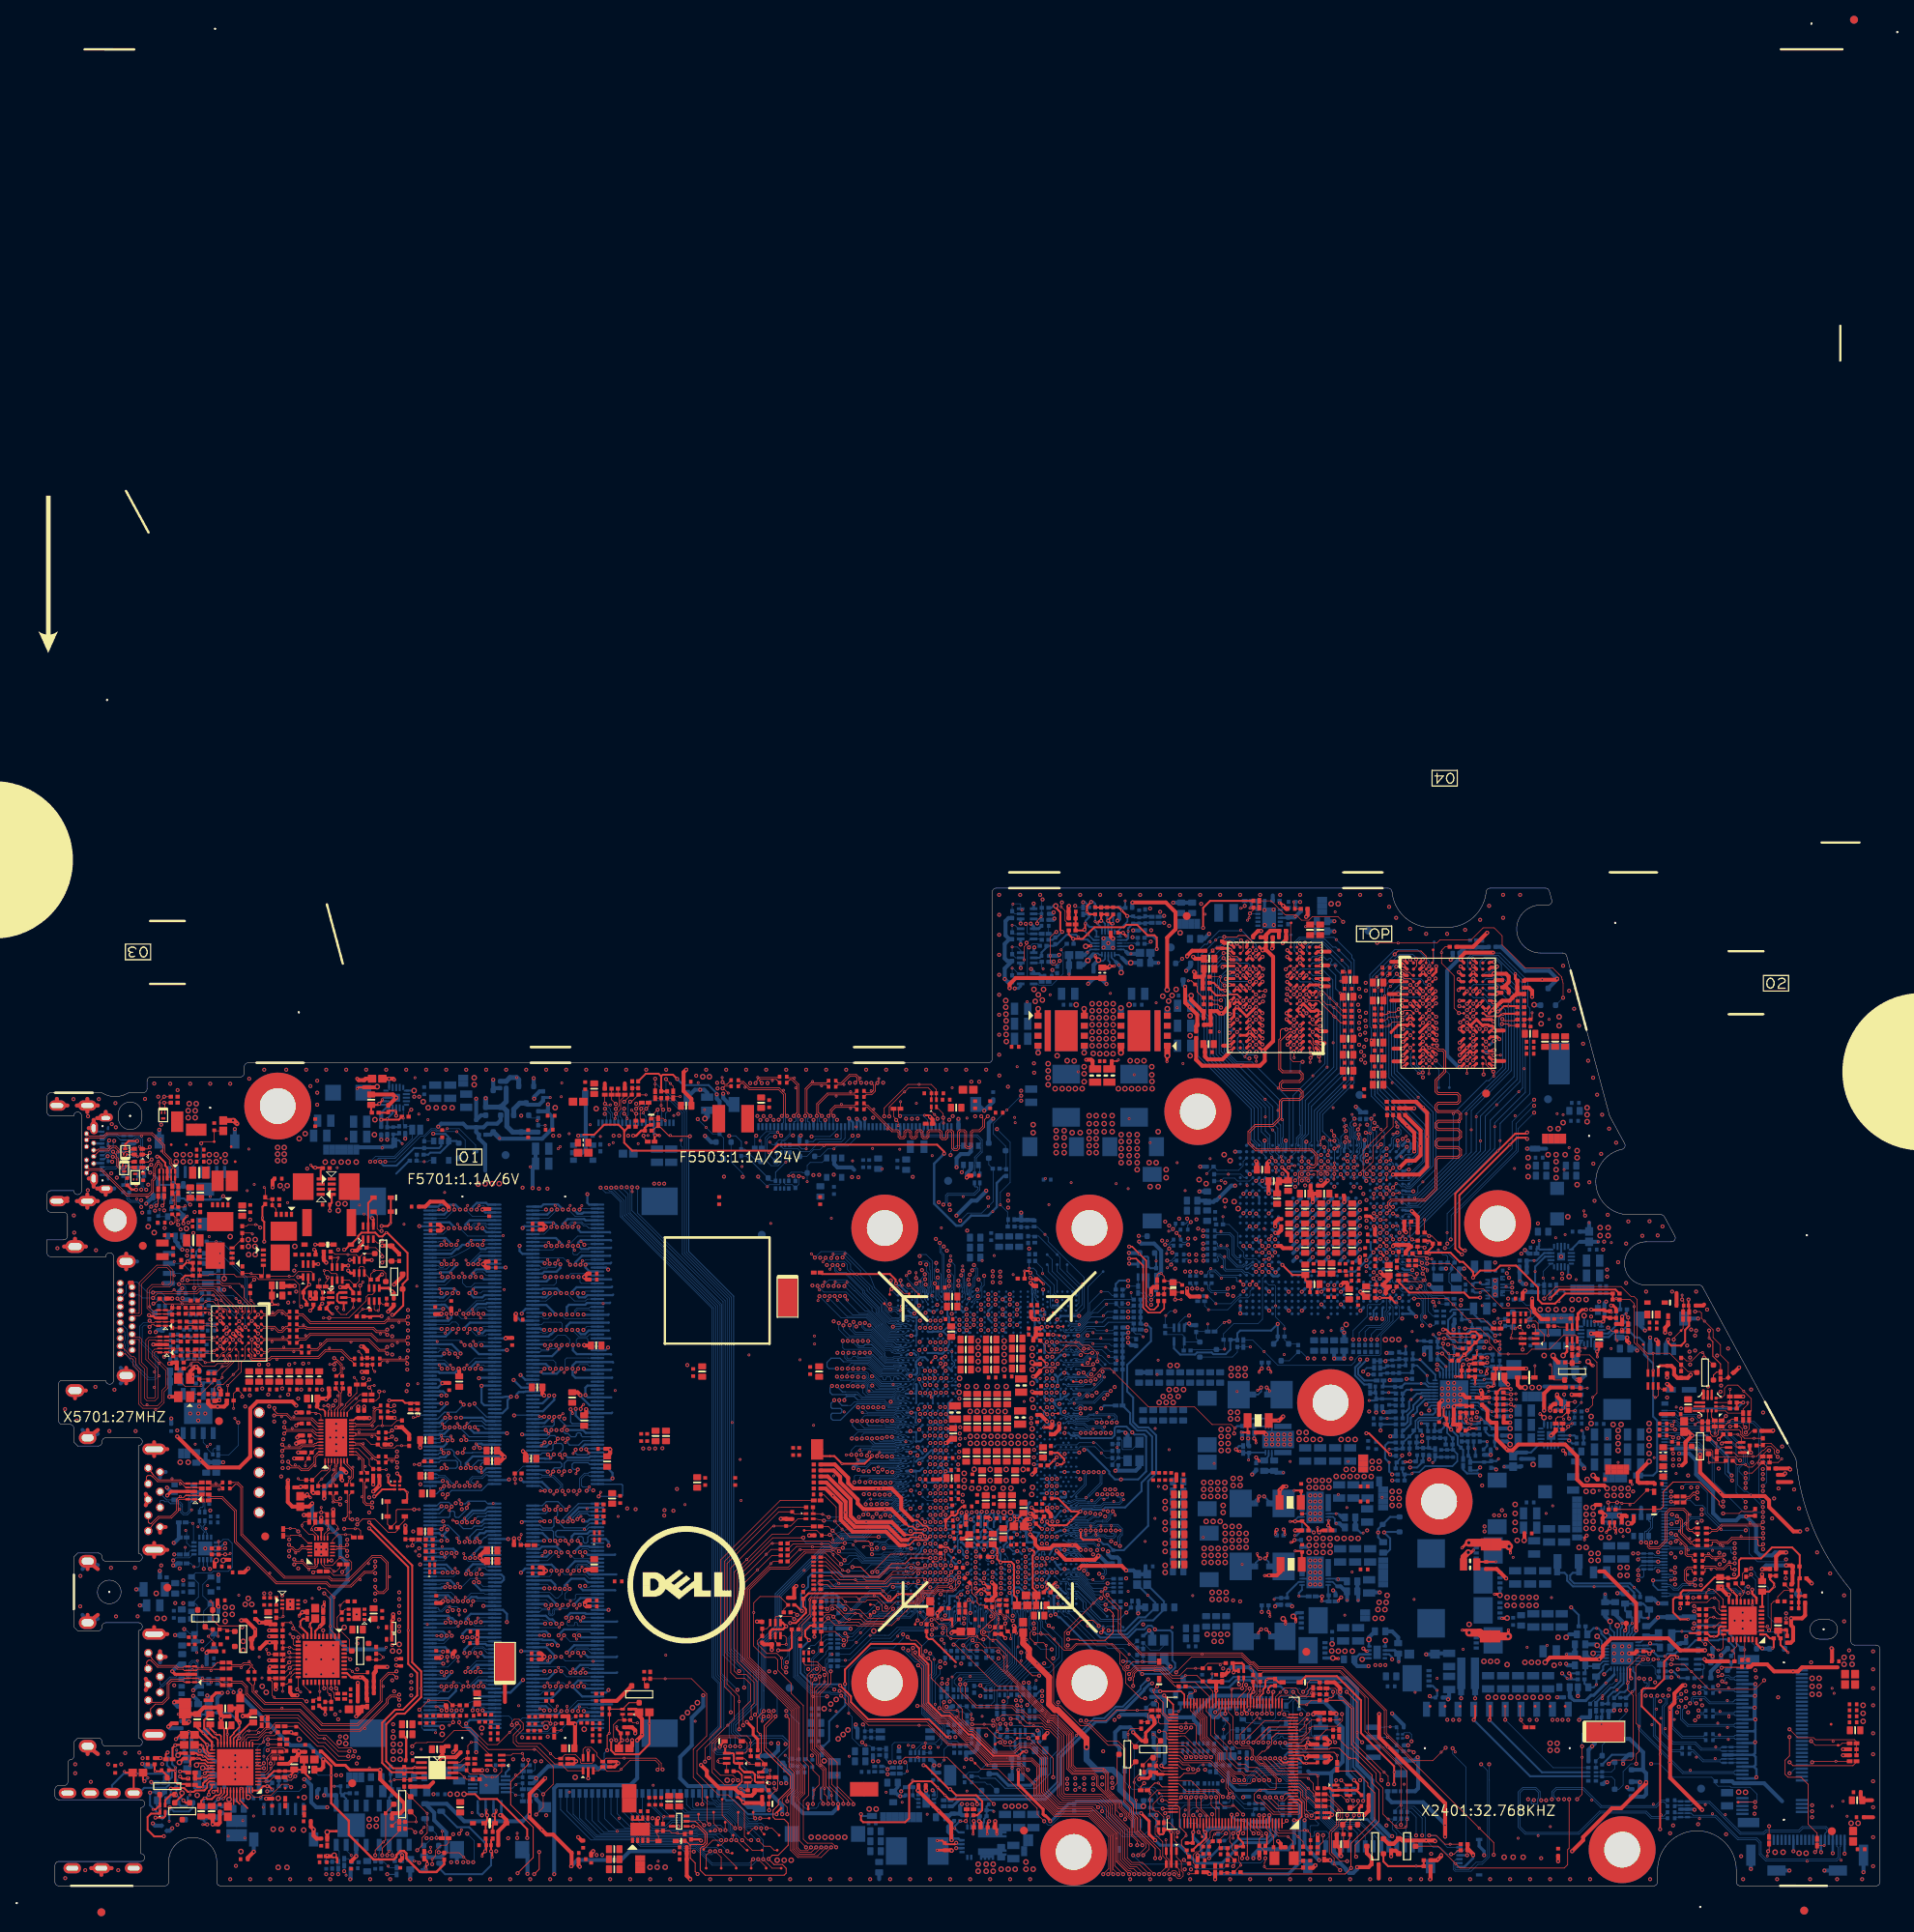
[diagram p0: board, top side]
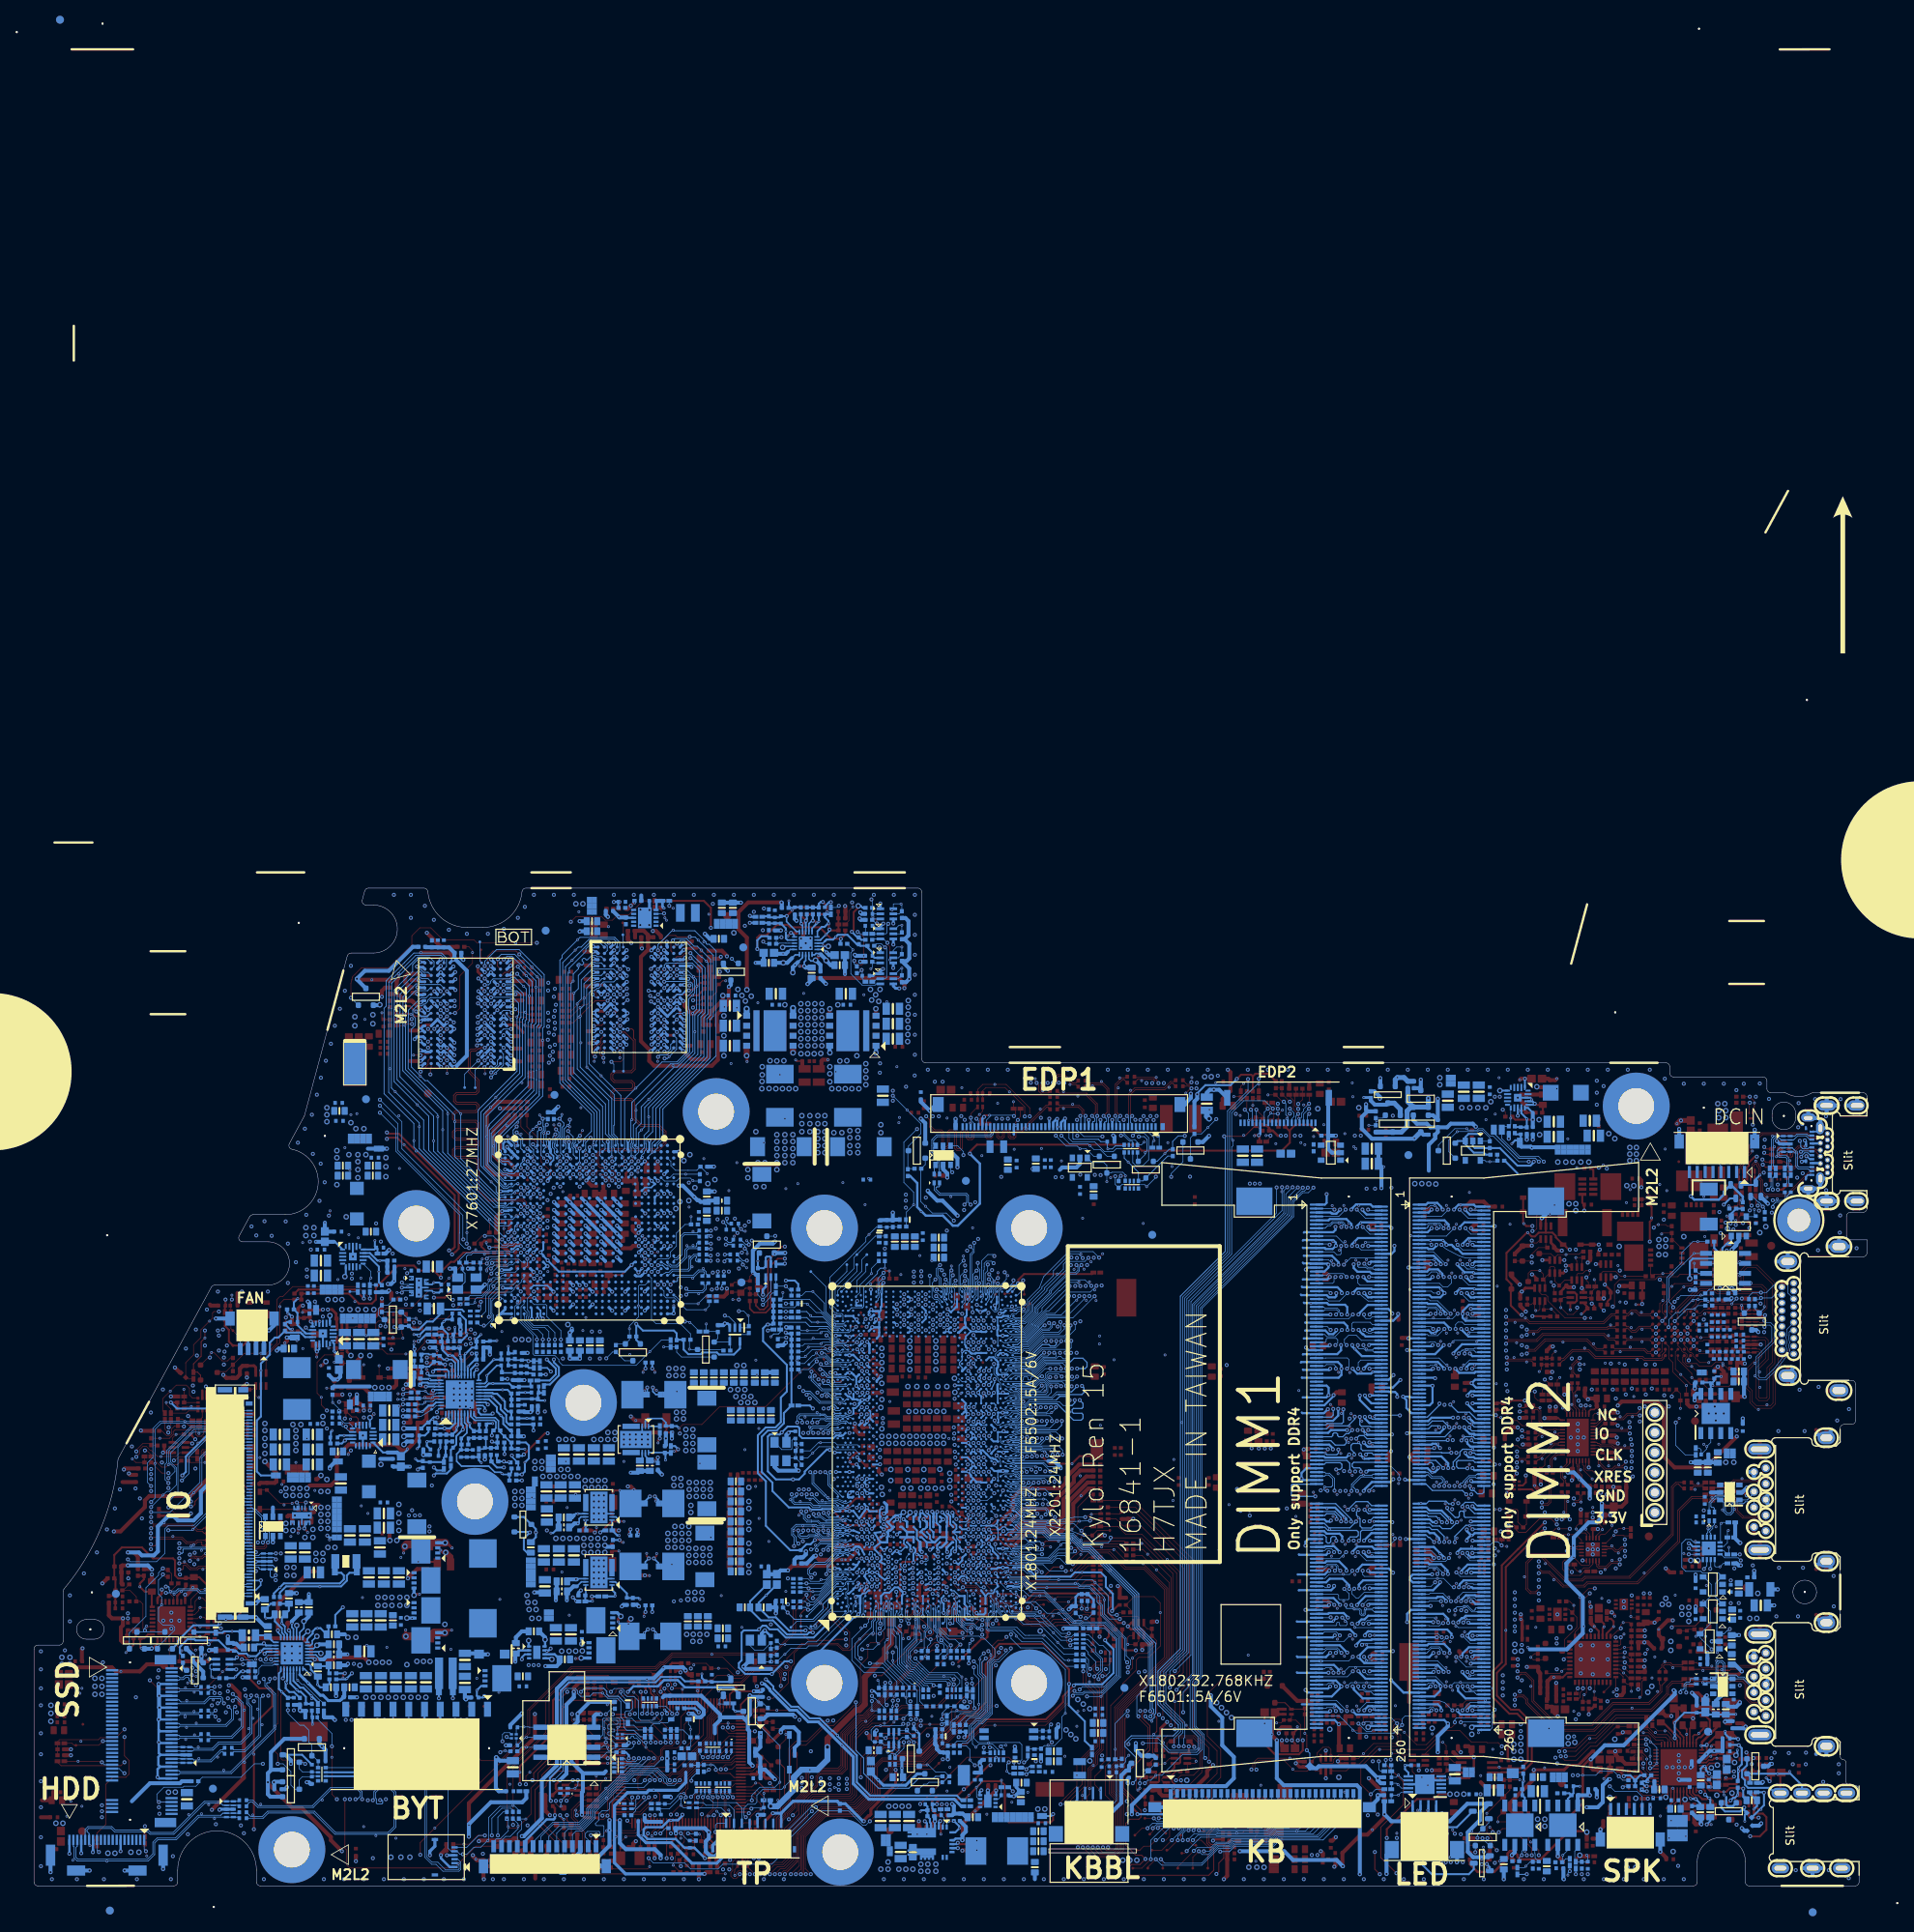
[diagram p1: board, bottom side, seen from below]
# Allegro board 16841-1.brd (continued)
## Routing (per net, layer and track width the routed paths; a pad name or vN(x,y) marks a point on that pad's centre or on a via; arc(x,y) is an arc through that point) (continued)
GYRO_INT_C: length 2.5
  TOP w0.089: v1(220.31,54.27) 220.31,54.26 219.86,53.81 R2027.2 R7003.1
GYRO_INT_ISH: length 206.3
  TOP w0.089: R2035.2 R2027.1 216.56,52.46 v2(215.72,52.46) ; v2(100.65,24.78) 100.96,24.78 101.77,23.96 101.77,23.25 104.17,20.86 111.73,20.86 114.52,18.07 116.88,18.07 119.52,15.43 123.55,15.43 124.05,14.93 124.05,14.38 124.69,13.74 125.52,12.91 125.52,11.52 128.02,9.02 132.34,9.02 135.03,6.33 135.03,1.75 v2(134.77,1.48)
  L6 w0.089: v2(215.72,52.46) 215.09,51.83 215.09,44.41 215.49,44.01 215.49,37.19 216.8,35.87 216.8,33.29 216.78,33.27 216.78,29.75 215.73,28.7 215.73,24.88 215.72,24.86 215.72,20.6 211.64,16.52 205.39,16.52 205.13,16.77 197.7,16.77 195.21,14.29 191.27,14.29 190.22,13.25 180.23,13.25 178.85,11.86 159.28,11.86 157.11,9.69 149.6,9.69 147.9,7.99 145.05,7.99 144.55,7.48 144.55,6.48 144.14,6.08 141.91,6.08 141.06,6.93 138.13,6.93 134.89,3.69 134.89,1.61 v2(134.77,1.48)
  BOTTOM w0.089: v2(100.65,24.78) 100.41,24.53 99.63,24.53 99.46,24.71 97.21,24.71 95.21,26.7 95.21,31.39 96.97,33.16 99.7,33.16 99.93,33.39 100.88,33.39 104.37,36.87 v1(105.05,36.87) 106.48,36.87 106.55,36.93 106.55,36.96 106.79,37.2 106.81,37.2 107.18,37.56 107.68,37.56 107.87,37.75 108.61,37.75 108.64,37.78 108.91,37.78 108.99,37.7 109.23,37.7 110.04,38.51 CPU1.AW7
GYRO_INT_P11: length 3.4
  TOP w0.089: R7002.1 213,53.81 v1(211.09,53.81) 211.02,53.88 D7001.1
H_CATERR#: length 1.3
  TOP w0.089: TP401.1 128.41,71.08 v2(128.39,71.05)
  BOTTOM w0.089: v2(128.39,71.05) 128.76,70.68 CPU1.D63
H_CPU_SVIDALRT#: length 6.6
  BOTTOM w0.114: R728.2 134.68,72.99 v1(134.16,72.47) 134,72.31 132.58,72.31 131.17,70.9 130.53,70.9 130.25,70.62 CPU1.B63
H_CPU_SVIDCLK: length 5.7
  BOTTOM w0.114: CPU1.A63 131.18,70.62 132.19,71.63 133.26,71.63 v1(133.27,71.63) 134.05,71.63 134.64,72.22 R732.1
H_CPU_SVIDDAT: length 12.8
  BOTTOM w0.114: CPU1.D64 129.09,70.53 129.29,70.32 130.7,70.32 130.72,70.34 131.24,70.34 131.97,71.08 134.26,71.08 134.8,71.62 137.86,71.62 R726.2 R709.1 138.02,70.37 138.25,70.14 138.86,70.14 v1(139.21,69.79)
H_CPUPWRGD: length 12.4
  BOTTOM w0.089: CPU1.A68 131.04,74.08 131.04,76.07 128.67,78.45 128.67,79.84 TP1705.1 125.93,82.59 EC1701.1 124.63,82.59 R1714.1
H_PECI: length 8.2
  TOP w0.114: KBC24.94 143.62,10.18 143.84,9.96 143.84,7.51 144.67,6.68 v1(144.67,6.39) 144.08,5.8 144.08,5.2 C2405.1 144.75,4 R2437.1
H_PECI_CPU: length 248.4
  TOP w0.089: v2(144.39,3.29) 144.86,2.83 R2437.2 ; v2(150.77,57.49) 150.77,58.25 150.39,58.63 147.98,58.63 145.74,60.87 139.9,60.87 v1(135.5,65.27) 135,65.77 133.9,65.77 133.66,65.53 133.66,65.48 132.79,64.61 132.26,64.61 v2(131.65,65.22)
  L4 w0.089: v2(219.35,49.24) 218.97,49.62 214.19,49.62 209.21,54.6 209.21,55.56 207.67,57.11 207.67,58.28 205.66,60.28 197.8,60.28 196.42,61.66 195.11,61.66 192.47,64.31 192.47,64.97 191.81,65.63 191.81,67.62 190.44,68.99 187.92,68.99 187.35,69.55 185.42,69.55 184.6,70.37 184.1,70.37 184.09,70.37 183.74,70.37 183.48,70.12 183.48,69.76 183.48,69.76 183.48,68.9 183.72,68.67 183.72,67.54 187.09,64.16 187.09,60.67 186.41,59.98 186.41,55.92 186.04,55.56 185.6,55.56 182.48,58.69 178.05,58.69 177.25,57.88 173.5,57.88 171.73,59.65 166.01,59.65 165.04,58.68 160.24,58.68 159.81,58.25 154.76,58.25 153.99,57.49 v2(150.77,57.49)
  L6 w0.089: v2(219.35,49.24) 219.35,47.77 220.16,46.96 220.16,44.44 221.61,42.99 221.61,37.91 221.2,37.51 221.2,35.62 220.44,34.86 220.44,33.77 221.13,33.08 221.13,31.28 222.93,29.47 222.93,18.28 219.34,14.69 216.43,14.69 213.32,11.59 205.81,11.59 203.32,9.1 197.73,9.1 194.46,5.83 177.29,5.83 177.01,6.11 175.97,6.11 173.06,3.21 169.31,3.21 167.52,4.99 163.18,4.99 162.6,4.42 157.29,4.42 157,4.13 151.63,4.13 151.13,3.63 148.09,3.63 147.77,3.94 147.42,3.94 146.77,3.29 v2(144.39,3.29)
  BOTTOM w0.089: CPU1.A54 131.16,65.67 131.61,65.22 v2(131.65,65.22)
H_PROCHOT#: length 247.8
  TOP w0.089: v2(141.37,3.52) 141.37,4.53 138.83,7.07 138.83,8.72 138.32,9.23 v1(138.32,10.88) 138.07,11.14 138.07,13.55 138.96,14.44 ED2403.1 139.26,15.23 R2418.2 140.12,16.29 Q2408.D ; v2(185.93,60.43) 185.91,60.41 PR4603.2
  L3 w0.127: v2(185.93,60.43) 189.53,60.43 189.95,60.86 191.09,60.86 191.47,60.48 193.12,60.48 194.01,59.59 194.01,53.44 194.98,52.48 195.91,52.48 196.14,52.7 196.96,52.7 198.01,51.65 202.59,51.65 203.6,50.63 v2(207.67,50.63)
  L4 w0.127: v2(185.93,60.43) 186.37,60.88 186.37,64.23 184.54,66.06 181.38,66.06 180.86,65.54 177.12,65.54 174.75,63.17 167.86,63.17 164.21,66.82 164.21,67.8 163.76,68.25 160.61,68.25 159.56,69.3 142.93,69.3 140.45,71.78 139.19,71.78 137.75,73.22 137.75,73.9 137.75,75.77 v2(137.31,76.21)
  L6 w0.102: v2(220.87,41.49) 221.3,41.05 221.3,38.04 220.9,37.63 220.9,35.75 220.14,34.99 220.14,33.64 220.82,32.96 220.82,31.15 222.61,29.37 222.61,18.41 219.18,14.99 216.3,14.99 213.21,11.89 205.68,11.89 203.38,9.59 197.53,9.59 194.79,6.84 173.65,6.84 171.37,4.56 168.38,4.56 167.65,5.29 163.05,5.29 162.49,4.72 157.17,4.72 156.87,4.43 151.38,4.43 150.87,3.92 148.21,3.92 147.73,4.41 145.82,4.41 145.14,3.73 141.58,3.73 v2(141.37,3.52)
  BOTTOM w0.089: v2(220.87,41.49) 220.59,41.2 217.22,41.2 216.17,42.25 216.17,45.36 215.73,45.81 212.49,45.81 210.86,47.43 210.86,49.99 209.78,51.07 208.1,51.07 v2(207.67,50.63) ; PQ4416.3 138.56,76.23 PR4476.2 v2(137.31,76.21) 136.88,75.78 R401.2 R403.1 ; PR4607.1 v2(185.93,60.43)
H_PROCHOT#_R: length 9
  BOTTOM w0.089: CPU1.C65 129.65,71.75 129.93,71.47 130.98,71.47 132.41,72.91 132.41,74.06 v1(133.88,75.53) 134.77,75.53 135.28,75.02 R403.2
H_VCCST_PWRGD: length 18.5
  BOTTOM w0.089: R1716.2 123.67,83.78 R1719.1 124.45,83.73 C1711.1 EC1708.1 125.83,83.7 v1(126.74,82.79) 127.15,82.38 127.15,81.88 128.43,80.59 128.44,80.59 128.66,80.38 128.66,80.36 129.7,79.32 129.71,79.32 131.72,77.32 131.72,73.49 131.07,72.84 130.91,72.84 130.8,72.73 130.2,72.73 130.06,72.6 CPU1.B65
HDA_BITCLK: length 12.6
  TOP w0.089: v2(98.67,46.42) 97.61,46.63 RN1902.3
  BOTTOM w0.089: v2(98.67,46.42) v1(100.02,46.34) 100.55,46.32 102.53,46.32 102.66,46.29 107,46.29 107.65,46.61 107.76,46.65 108.05,46.73 108.28,46.82 108.39,46.94 108.39,47.11 108.58,47.31 108.83,47.31 108.99,47.24 CPU1.AY22
HDA_CODEC_BITCLK: length 105
  TOP w0.089: v2(38.88,16.47) 38.37,15.96 36.88,15.96 35.11,17.74 34.33,17.74 33.94,18.13 31.84,20.23 EC2708.1 31.59,20.28 R2752.1 ; RN1902.2 95.34,46.63 94.44,45.73 EC1901.2 v1(92.32,45.73) 92.17,45.73 86.83,40.39 86.83,27.1 87.53,26.4 88.6,26.4 88.96,26.04 89.34,25.66 89.34,23.49 88.42,22.57 88.42,20.41 v2(88.41,20.41)
  L3 w0.127: v2(38.88,16.47) 38.88,15.32 39.31,14.89 39.31,14.16 45.32,8.15 54.01,8.15 54.69,7.47 57.93,7.47 60.09,9.63 70.89,9.63 78.32,17.05 82.22,17.05 83.92,18.76 87.39,18.76 88.41,19.78 v2(88.41,20.41)
HDA_CODEC_SDIN0: length 4.5
  TOP w0.089: HDA27.16 24.9,18.27 25.06,18.44 25.06,18.91 25.37,19.21 26.59,19.21 v1(26.87,19.49) 27.1,19.49 R2730.2
HDA_CODEC_SDOUT: length 107.6
  TOP w0.089: v2(39.09,17.09) 38.65,17.53 37.07,17.53 35.45,19.16 34.44,19.16 31.88,21.72 27.71,21.72 R2740.1 ; v2(87.9,19.9) v1(87.9,23.43) 87.9,24.09 86.36,25.63 86.36,40.96 92.93,47.54 EC1903.1 94.89,47.28 RN1902.1
  L3 w0.127: v2(39.09,17.09) 39.76,17.09 40.04,16.82 40.04,14.13 45.52,8.65 54.21,8.65 54.5,8.36 54.9,7.96 57.73,7.96 59.89,10.12 70.68,10.12 78.11,17.55 82.01,17.55 84.36,19.9 v2(87.9,19.9)
HDA_CODEC_SYNC: length 112.1
  TOP w0.089: R1908.1 95.14,45.68 94.17,44.71 92.11,44.71 v1(88.88,41.47) 87.3,39.9 87.3,27.29 87.73,26.87 88.8,26.87 89.81,25.85 89.81,23.2 89.43,22.82 v2(89.43,21.3) ; HDA27.15 25.3,18.63 25.57,18.91 26.87,18.91 27.89,19.93 28.29,19.93 28.72,20.37 28.72,20.44 29.03,20.75 31.95,20.75 34.49,18.21 35.3,18.21 37.04,16.47 v2(38.25,16.47)
  L3 w0.127: v2(89.43,21.3) 89.43,20.08 87.6,18.25 84.13,18.25 82.43,16.55 78.53,16.55 70.45,8.47 60.14,8.47 58.63,6.96 54.48,6.96 53.8,7.64 45.11,7.64 38.81,13.95 38.81,14.68 38.25,15.24 v2(38.25,16.47)
HDA_RST#: length 15.7
  TOP w0.089: TP1903.1 97.76,45.17 EC1902.1 99.33,44.54 v2(99.41,44.61) 99.51,44.61 99.82,44.3 v1(99.82,43.94)
  BOTTOM w0.089: v2(99.41,44.61) 99.8,44.61 101.24,45.19 104.32,45.87 107.44,45.87 107.86,46.29 108.29,46.29 108.66,46.66 108.91,46.77 109.37,46.79 109.54,46.79 CPU1.AW22
HDA_SDIN0: length 118.9
  TOP w0.089: R2730.1 28.06,21.32 31.84,21.32 34.42,18.73 v1(35.2,18.73) 35.35,18.73 36.98,17.11 v2(38.37,17.11) ; v2(96.06,44.26) 95.74,44.26 95.7,44.23 92.15,44.23 87.67,39.74 87.67,28.51 90.18,26.01 90.18,22.03 89.91,21.77 v2(89.91,21.75)
  L3 w0.127: v2(89.91,21.75) 89.87,21.79 89.1,21.79 88.54,21.23 85.14,21.23 81.85,17.94 77.95,17.94 70.52,10.51 59.71,10.51 58,8.8 58,8.79 57.56,8.36 55.12,8.36 54.44,9.04 45.69,9.04 40.43,14.3 40.43,16.98 39.82,17.59 38.86,17.59 v2(38.37,17.11)
  BOTTOM w0.089: v2(96.06,44.26) 96.06,43.92 96.37,43.62 99.62,43.62 100.8,44.8 101.83,44.8 101.85,44.79 103.5,44.79 104.38,45.67 107.49,45.67 107.93,46.11 108.37,46.11 108.73,46.48 CPU1.BA21
HDA_SDOUT: length 11.9
  TOP w0.089: R1909.2 97.28,47.33 RN1902.4 98.29,47.28 v1(98.5,47.22) v2(99.28,46.86)
  BOTTOM w0.089: CPU1.BB22 107.63,46.8 107.57,46.77 106.96,46.47 102.68,46.47 100.63,46.86 v2(99.28,46.86)
HDA_SPKR_R: length 2.1
  TOP w0.254: D2702.2 15.73,11.6 15,10.88 RN2702.3
HDA_SYNC: length 13.2
  TOP w0.089: R1908.2 99.23,45.68 v2(99.77,45.14) 100.79,44.12 v1(101.03,44.12)
  BOTTOM w0.089: v2(99.77,45.14) 99.82,45.14 100.73,46.06 107.37,46.06 107.79,46.47 108.22,46.47 108.74,46.98 CPU1.BA22
HDD_DEVSLP: length 128.9
  TOP w0.102: v2(221.3,18.92) 221.3,16.52 220.75,15.96 220.75,14.18 221.13,13.8 222.78,13.8 223.67,12.91 223.67,7.83 224.81,6.69 R6002.1
  L3 w0.102: v2(221.3,18.92) 220.2,17.82 218.37,17.82 214.61,14.06 210.03,14.06 207.42,11.45 197.27,11.45 195.58,13.14 188.71,13.14 183.83,18.02 176.67,18.02 172.16,22.53 147.39,22.53 147.18,22.74 130.57,22.74 128.93,24.39 128.93,27.77 v2(127.78,28.92)
  BOTTOM w0.102: v2(127.78,28.92) 128.16,29.3 128.16,30.42 126.44,32.14 v1(126.21,32.14) 126.21,33.54 125.93,33.82 125.93,34.83 CPU1.J1
HDD_DEVSLP_R: length 3.5
  TOP w0.089: v1(225.7,5.12) R6002.2 224.81,4.55 v2(224.56,4.3)
  BOTTOM w0.089: HDD1.13 224.8,4.54 v2(224.56,4.3)
HDMI_27MHZ_OUT: length 5.6
  TOP w0.089: X5701.3 16.66,64.34 17.55,63.46 19.45,63.46 v1(19.58,63.59) 19.58,63.97 19.32,64.22 C5730.1 20.37,64.4 R5748.1
HDMI_AUXN: length 124.5
  TOP w0.102: 43.23,66.72 v1(43.23,66.59) ; 43.23,66.72 42.63,66.72 42.26,66.36 C5739.1 ; 43.23,66.72 45.61,66.72 45.74,66.6 v2(45.74,66.37)
  L4 w0.14: v2(45.74,66.37) 45.74,66.52 46.11,66.89 47.19,66.89 48.04,67.74 48.04,82.65 49.91,84.53 58.42,84.53 60.84,86.94 63.76,86.94 64.55,87.73 64.55,88.75 66.3,90.5 82.82,90.5 83.2,90.88 112.05,90.88 122.87,80.06 122.87,75.86 124.23,74.51 124.23,70.7 126,68.92 126,64.21 126.44,63.77 126.81,63.77 v2(126.97,63.61)
  BOTTOM w0.102: v2(126.97,63.61) 127.07,63.51 127.07,63.28 126.94,63.15 CPU1.G50
HDMI_AUXN_L: length 2.4
  TOP w0.102: C5741.1 40.58,66.25 R5763.1 40.74,66.25 C5739.2 41.35,65.65 v1(41.63,65.37)
HDMI_AUXN_R: length 15.2
  TOP w0.102: v1(29.18,66.89) 29.18,67.04 ; 29.18,67.04 28.56,67.04 28.31,66.79 26.03,66.79 25.8,67.02 25.8,67.19 U5701.C8 ; 29.18,67.04 34.53,67.04 35.42,67.93 37.33,67.93 38.48,66.79 38.6,66.79 39.06,66.33 C5741.2
HDMI_AUXP: length 124.4
  TOP w0.102: v1(44.83,67.14) 44.83,66.95 ; 44.83,66.95 42.32,66.95 C5738.1 ; 44.83,66.95 45.54,66.95 v2(45.74,67.16)
  L4 w0.14: v2(45.74,67.16) 47.08,67.16 47.77,67.85 47.77,82.76 49.8,84.8 58.31,84.8 60.73,87.21 63.65,87.21 64.28,87.84 64.28,88.86 66.19,90.77 82.71,90.77 83.09,91.15 112.16,91.15 123.14,80.17 123.14,75.97 124.49,74.62 124.49,70.81 126.27,69.03 126.27,64.32 126.55,64.04 127.2,64.04 v2(127.68,63.56)
  BOTTOM w0.102: CPU1.F50 v2(127.68,63.56)
HDMI_AUXP_L: length 2.5
  TOP w0.102: v1(39.57,67.93) 39.97,67.52 C5740.1 40.58,67.02 R5762.1 40.74,67.02 C5738.2
HDMI_AUXP_R: length 15.5
  TOP w0.102: C5740.2 38.57,67.02 37.43,68.16 35.86,68.16 ; 35.86,68.16 v1(35.86,68.34) ; 35.86,68.16 35.33,68.16 34.44,67.27 28.47,67.27 28.21,67.02 26.12,67.02 26.03,67.11 26.03,67.47 25.6,67.89 U5701.C7
HDMI_CEC: length 6.2
  TOP w0.089: U5701.F2 22.85,72.55 22.85,73.05 22.55,73.35 22.34,73.35 21.74,73.95 21.74,74.45 v1(21.11,75.08) 19.82,75.08 R5761.1
HDMI_CEC_C: length 13.6
  TOP w0.089: v2(16.56,74.64) 16.96,74.23 18.1,74.23 R5761.2
  L3 w0.089: v2(16.56,74.64) 14.5,76.69 10.36,76.69 9.96,76.3 9.96,74 9.56,73.6 HDMI2.13
  BOTTOM w0.089: v1(17.17,73.95) 17.17,74.03 v2(16.56,74.64)
HDMI_CLK#_C: length 1.1
  TOP w0.076: R5708.1 17.83,73.24 18.26,73.24 R5716.2
HDMI_CLK#_L_C: length 2.8
  TOP w0.076: U5701.H1 21.36,72.74 21.19,72.74 20.67,73.27 20.21,73.27 C5724.2 19.96,73.27 19.55,73.27 R5716.1
HDMI_CLK#_R_C: length 21.8
  TOP w0.076: R5708.2 ER5745.1 15.6,73.17 ED5702.5 ED5702.6 13.7,73.17 13.61,73.08 13.47,73.08 13,73.54 13,75.68 13.43,76.11 15.59,76.11 16,76.52 16,77.56 ; 16,77.56 v1(16.15,77.56) ; 16,77.56 16,78.24 15.36,78.88 13.94,78.88 11.7,76.64 11.7,75.65 11.71,75.65 11.71,72.83 11.63,72.75 11.15,72.75 HDMI2.12
HDMI_CLK_C: length 1.1
  TOP w0.076: R5717.2 18.26,72.94 17.83,72.94 R5707.1
HDMI_CLK_L_C: length 2.8
  TOP w0.076: R5717.1 19.6,72.96 19.96,72.96 C5724.1 20.21,72.96 20.54,72.96 21.06,72.44 21.36,72.44 U5701.H2
HDMI_CLK_R_C: length 21.8
  TOP w0.076: 14.7,76.41 13.3,76.41 12.69,75.8 12.69,73.42 13.34,72.77 13.61,72.77 13.7,72.67 ED5702.7 ED5702.4 15.83,72.67 ER5745.2 16,72.71 R5707.2 ; 14.7,76.41 15.46,76.41 15.69,76.64 15.69,78.12 15.24,78.57 14.07,78.57 12.01,76.52 12.01,72.7 11.76,72.45 11.15,72.45 HDMI2.10 ; 14.7,76.41 v1(14.7,76.59)
HDMI_DATA0#_C: length 1.2
  TOP w0.076: R5706.1 17.95,71.49 18.54,71.49 R5714.2
HDMI_DATA0#_L_C: length 2.1
  TOP w0.076: R5714.1 19.86,71.49 20.77,71.49 20.87,71.39 U5701.H3
HDMI_DATA0#_R_C: length 22.3
  TOP w0.076: R5706.2 16.81,71.77 ER5759.2 15.8,71.67 ED5702.2 ED5702.9 13.7,71.67 13.56,71.54 13.31,71.54 v2(13.02,71.83)
  BOTTOM w0.076: 13.79,65.32 v1(13.63,65.32) ; 13.79,65.32 13.79,64.81 13.58,64.6 12.92,64.6 11.78,65.75 10.26,67.73 10.11,68.07 10.15,68.21 10.29,68.62 10.13,69.07 10.28,69.69 10.18,70.01 10.18,70.72 HDMI2.9 ; 13.79,65.32 13.79,67.09 11.78,69.1 11.78,71.13 12.21,71.56 12.76,71.56 v2(13.02,71.83)
HDMI_DATA0_C: length 1.2
  TOP w0.076: R5715.2 18.54,71.18 17.95,71.18 R5705.1
HDMI_DATA0_L_C: length 2.5
  TOP w0.076: R5715.1 19.86,71.18 20.65,71.18 20.74,71.09 21.4,71.09 21.6,70.88 U5701.H4
HDMI_DATA0_R_C: length 22
  TOP w0.076: v2(13.02,71.04) 13.29,71.31 13.56,71.31 13.7,71.17 ED5702.10 ED5702.1 15.63,71.17 ER5759.1 16.81,70.9 R5705.2
  BOTTOM w0.076: v2(13.02,71.04) 12.8,71.26 12.34,71.26 12.09,71 12.09,69.23 14.09,67.22 14.09,66.43 ; 14.09,66.43 v1(14.24,66.43) ; 14.09,66.43 14.09,64.68 13.71,64.3 12.8,64.3 11.68,65.42 11.55,65.55 11.45,65.67 11.35,65.81 11.16,66.06 10.78,66.55 9.99,67.57 9.78,68.05 9.87,68.31 9.97,68.62 9.81,69.06 9.96,69.68 9.87,69.97 9.87,70.4 9.67,70.6 HDMI2.7
HDMI_DATA1#_C: length 1.2
  TOP w0.076: R5712.2 18.66,69.71 18.08,69.71 R5704.1
HDMI_DATA1#_L_C: length 2.1
  TOP w0.076: U5701.H5 21.36,69.54 20.99,69.54 20.82,69.71 19.98,69.71 R5712.1
HDMI_DATA1#_R_C: length 22.9
  TOP w0.076: HDMI2.6 11.15,69.75 11.76,69.75 12.01,69.5 12.01,66.52 12.69,65.83 12.69,62.09 12.81,61.97 13.6,61.97 13.76,62.14 13.76,63.36 ; v1(13.61,63.36) 13.76,63.36 ; 13.76,63.36 13.76,65.7 12.54,66.92 12.54,69.35 12.89,69.7 13.76,69.7 13.85,69.79 ED5701.6 ED5701.5 15.83,69.79 ER5758.2 16.07,69.94 R5704.2
HDMI_DATA1_C: length 1.2
  TOP w0.076: R5713.2 18.66,69.4 18.08,69.4 R5703.1
HDMI_DATA1_L_C: length 2.1
  TOP w0.076: R5713.1 19.98,69.4 20.7,69.4 20.86,69.24 21.36,69.24 U5701.H6
HDMI_DATA1_R_C: length 22.9
  TOP w0.076: v1(14.22,64.81) 14.07,64.81 ; 14.07,64.81 14.07,65.82 12.85,67.04 12.85,69.23 13.01,69.39 13.76,69.39 13.85,69.3 ED5701.7 ED5701.4 15.85,69.3 ER5758.1 16.07,69.18 R5703.2 ; 14.07,64.81 14.07,62.01 13.72,61.67 12.68,61.67 12.39,61.96 12.39,65.71 11.71,66.39 11.71,69.37 11.63,69.45 11.15,69.45 HDMI2.4
HDMI_DATA2#_C: length 1.2
  TOP w0.076: R5702.1 18.08,67.93 18.66,67.93 R5711.2
HDMI_DATA2#_L_C: length 2
  TOP w0.076: R5711.1 19.97,67.94 21.36,67.94 U5701.H7
HDMI_DATA2#_R_C: length 22.8
  TOP w0.076: v1(12.69,61.15) 12.69,61 ; 12.69,61 14.02,61 14.56,61.55 14.56,62.92 15.06,63.42 15.06,65.52 13.33,67.25 13.33,67.88 13.66,68.21 13.96,68.21 14.05,68.29 ED5701.9 ED5701.2 15.94,68.29 ER5744.2 16.94,68.21 R5702.2 ; 12.69,61 12.29,61 11.93,61.35 11.93,65.52 11.25,66.2 11.25,67.02 10.97,67.3 10.71,67.3 9.41,68.6 HDMI2.3
HDMI_DATA2_C: length 1.2
  TOP w0.076: R5710.2 18.66,67.63 18.08,67.63 R5701.1
HDMI_DATA2_L_C: length 2.1
  TOP w0.076: R5710.1 20,67.64 21.36,67.64 U5701.H8
HDMI_DATA2_R_C: length 22.7
  TOP w0.076: v1(13.79,60.54) 13.79,60.69 ; 13.79,60.69 14.14,60.69 14.87,61.42 14.87,62.8 15.36,63.29 15.36,65.65 13.63,67.37 13.63,67.75 13.79,67.91 13.99,67.91 14.1,67.79 ED5701.10 ED5701.1 15.57,67.79 ER5744.1 16.94,67.35 R5701.2 ; 13.79,60.69 12.16,60.69 11.63,61.23 11.63,65.39 10.94,66.08 10.94,66.89 10.84,66.99 10.59,66.99 9.98,67.6 HDMI2.1
HOLD#_HDMI: length 2.5
  BOTTOM w0.089: U5702.7 21.38,77.84 R5742.1 21.91,78.37 v1(21.91,79.13)
HOST_DEBUG_TX: length 66.9
  TOP w0.089: v2(144.93,14.82) 144.17,14.82 143.61,15.38 KBC24.81 ; v2(178.33,4.02) 178.7,4.02 179.21,4.53 R2480.1 ; v2(178.52,17.49) 178.84,17.16 v1(178.84,17.02)
  L6 w0.089: v2(178.52,17.49) 178.52,16.95 176.71,15.14 148.09,15.14 147.28,14.33 145.42,14.33 v2(144.93,14.82)
  BOTTOM w0.089: v2(178.52,17.49) 178.52,16.79 180.22,15.09 180.22,4.81 179.8,4.39 DBEC1.5 179.07,4.39 178.7,4.02 v2(178.33,4.02) 177.82,4.02 176.93,4.91 176.04,4.91 175.07,5.89 175.07,8.68 173.63,10.12 171.72,10.12 171.22,9.61 R6801.1
HOST_DEBUG_TX_CON: length 4.7
  BOTTOM w0.089: 171.17,8.5 170.89,8.22 170.89,7.17 171.41,6.65 DB1.11 ; 171.17,8.5 R6801.2 ; 171.17,8.5 v1(170.33,8.5)
HPD_HDMI_CON: length 16.4
  TOP w0.089: v2(13.51,74) 13.69,74 R5758.2 15.01,73.95 19.85,73.95 v1(20.18,74.29) 21.07,74.29 21.78,73.58 21.82,73.58 U5701.G1
  L4 w0.089: HDMI2.19 9.93,76.6 10.25,76.92 11.91,76.92 12.52,76.32 12.52,74.99 v2(13.51,74)
HPDIN: length 1.9
  TOP w0.089: R3821.2 33.42,58.76 34.2,57.98 U3801.32
HW_ACAV_IN: length 88.5
  TOP w0.089: v2(218.08,26.12) 216.94,24.98 211.09,24.98 v1(208.86,27.21) 207.92,28.15 v2(206.27,28.15) ; KBC24.128 157.12,7.96 v2(157.44,8.28)
  L6 w0.089: v2(218.08,26.12) 218.08,21.36 211.9,15.19 205.39,15.19 204.42,16.16 197.95,16.16 195.47,13.68 191.52,13.68 190.48,12.64 180.49,12.64 179.12,11.26 160.42,11.26 v2(157.44,8.28)
  BOTTOM w0.089: PG4408.2 v2(206.27,28.15) PQ4415.5
HW_ACAVIN_NB: length 240.4
  TOP w0.089: R2475.2 R2499.2 20.47,77.56 20.61,77.7 23.75,77.7 24.04,77.41 26.07,77.41 26.13,77.48 26.49,77.48 26.77,77.19 26.77,77.19 26.91,77.05 31.39,77.05 32.07,76.37 32.07,73.83 v2(32.28,73.62) ; KBC24.24 159.32,18.58 160.37,19.63 v1(160.37,20) 160.38,20 160.66,20.28 163.81,20.28 164.53,21 164.53,21.77 v2(164.46,21.84)
  L3 w0.089: v2(164.46,21.84) 164.46,21.4 163.27,20.2 146.57,20.2 145.92,20.86 137.96,20.86 136.58,19.48 132.94,19.48 130.83,17.37 129.56,16.1 v2(129.56,13.6)
  L4 w0.089: v2(129.56,13.6) 129.46,13.6 128.37,12.51 118.15,12.51 117.2,13.45 114.45,13.45 113.87,12.88 109.67,12.88 108.99,12.19 108.99,11.29 108.58,10.89 107.59,10.89 106.88,11.59 96.56,11.59 93.09,15.07 85.89,15.07 83.4,12.57 83.01,12.57 83.01,12.57 82.56,12.57 75.36,12.57 70.35,7.56 49.63,7.56 48.28,6.21 48.28,6.13 v2(48.21,6.06)
  L6 w0.089: v2(32.28,73.62) 32.28,73.2 33.93,71.55 33.93,65.45 31.77,63.29 31.77,62.87 32.41,62.23 32.41,60.2 31.85,59.65 31.14,59.65 31.01,59.78 30.04,59.78 29.36,59.1 29.36,58.32 28.94,57.9 28.94,40.77 33.6,36.11 33.6,30.86 33.6,30.85 33.6,15.19 37.86,10.93 37.86,7.98 40.03,5.81 47.96,5.81 v2(48.21,6.06)
I2C0_SCL_R: length 30.9
  TOP w0.089: v2(122.32,18.25) 122.7,18.25 AFTP6534.1 123.24,18.79 v2(124.64,18.79) 124.7,18.79 125.42,18.06 127.09,16.4 127.09,16.18 127.09,12.21 128.71,10.59 133.5,10.59 134.01,10.09 v2(134.01,9.49)
  BOTTOM w0.089: v2(134.01,9.49) 134.89,8.6 134.9,8.6 136.96,6.53 139.39,6.53 139.9,7.04 TPCON1.6 ; R6505.2 124.84,18.79 v2(124.64,18.79) 124.24,19.18 Q6504.6 ; RN6503.3 123.43,16.38 122.32,17.49 v2(122.32,18.25)
I2C0_SCL_TCH_PAD: length 28
  L4 w0.127: v2(121.14,37.84) 121.57,37.41 121.57,36.97 121.23,36.63 121.23,31.84 120.35,30.96 120.35,28.73 122.01,27.07 122.01,22.66 122.91,21.76 122.91,21.1 v2(122.4,20.59)
  BOTTOM w0.089: v2(121.14,37.84) 121.37,37.61 CPU1.U6 ; v2(122.4,20.59) 122.42,20.59 122.66,20.35 v1(125.29,20.35) 125.93,20.35 126.48,19.8 126.48,18.55 126.23,18.3 EC6503.1 125.27,18.3 R6505.1 124.85,17.93 Q6504.1
I2C0_SCL_TCH_PNL: length 143
  TOP w0.089: R5521.2 79.52,101.61 v1(79.17,101.97) v2(78.61,102.53)
  L3 w0.127: v2(88.03,17.72) 91.22,20.9 98.76,20.9 101.29,23.44 105.06,23.44 105.07,23.42 106.17,22.33 112.2,22.33 114.5,24.62 116.98,24.62 117.68,25.33 117.68,28.5 120.5,31.32 120.5,39.06 121.18,39.74 v2(121.18,39.78)
  BOTTOM w0.089: v2(78.61,102.53) 78.61,101.08 81.22,98.47 81.22,80.51 86.91,74.82 86.91,30.03 89.76,27.18 89.76,23.16 87.17,20.57 87.17,19.6 88.03,18.74 v2(88.03,17.72) ; v2(121.18,39.78) 121.45,39.78 CPU1.U9
I2C0_SDA_R: length 32.3
  TOP w0.089: AFTP6535.1 120.67,18.25 v2(121.05,18.25) 121.51,17.79 123.13,17.79 123.44,18.1 125.01,18.1 126.82,16.29 126.82,12.1 128.6,10.33 133.16,10.33 v2(133.5,9.99)
  BOTTOM w0.089: TPCON1.7 138.9,7.17 138.53,6.8 137.33,6.8 134.13,9.99 v2(133.5,9.99) ; v2(121.05,18.25) 121.71,18.91 R6506.2 122.5,18.91 122.94,18.47 Q6504.3 122.94,17.93 122.94,17.25 123.37,16.82 123.91,16.82 124.1,16.62 RN6503.4
I2C0_SDA_TCH_PAD: length 24
  TOP w0.089: v1(121.94,19.9) 121.94,20.15 121.76,20.33 v2(121.76,20.59)
  L4 w0.127: v2(121.76,20.59) 121.94,20.76 121.94,22.19 121.03,23.1 121.03,27.51 119.97,28.57 119.97,30.89 121.01,31.93 121.01,35.69 120.73,35.97 120.73,38.07 v2(121.13,38.48)
  BOTTOM w0.089: 121.94,19.77 122.75,19.77 Q6504.4 ; 121.94,19.77 121.94,20.41 v2(121.76,20.59) ; 121.94,19.77 121.23,19.06 EC6504.1 ; CPU1.U7 121.34,38.26 v2(121.13,38.48)
I2C0_SDA_TCH_PNL: length 143.6
  TOP w0.089: R5522.2 v1(77.24,101.89) v2(77.24,102.58)
  L3 w0.127: v2(87.4,17.74) 87.4,17.72 87.85,17.27 88.28,17.27 91.53,20.52 98.91,20.52 101.45,23.06 104.9,23.06 106.01,21.94 114.18,21.94 116.48,24.24 117.14,24.24 118.07,25.17 118.07,28.35 120.71,31 120.71,38.68 v2(121.18,39.15)
  BOTTOM w0.089: v2(77.24,102.58) 77.24,102.07 80.95,98.35 80.95,80.4 86.65,74.71 86.65,29.92 89.31,27.25 89.31,23.09 86.9,20.68 86.9,19.46 87.4,18.96 v2(87.4,17.74) ; v2(121.18,39.15) 121.19,39.15 121.42,38.91 CPU1.U8
I2C1_SCL: length 13.4
  BOTTOM w0.089: CPU1.N2 123.84,35.86 123.63,35.65 123.63,32.58 v1(123.14,32.1) 122.86,31.82 122.86,28.23 121.59,26.95 121.3,26.95 120.55,26.21 120.5,26.21 119.77,25.47 119.34,25.47 119.19,25.32 RN2008.1
I2C1_SDA: length 12.2
  BOTTOM w0.089: CPU1.N1 123.8,35.13 123.8,32.09 123.32,31.6 123.32,30.38 v1(123.32,30.37) 123.13,30.18 123.13,28.12 121.7,26.69 121.41,26.69 120.66,25.94 120.62,25.94 119.86,25.19 RN2008.2
I2C_CLK_PD: length 57.4
  TOP w0.089: R3814.1 41.8,61.68 42.18,62.06 v2(42.18,62.83) v1(42.82,62.83) ; RN3701.3 36.92,24.91 v2(36.72,25.11) 36.57,25.26 U3701.29
  L4 w0.127: v2(42.18,62.83) 41.55,62.19 41.55,51.65 43.47,49.73 43.47,40.67 46.76,37.39 46.76,23.61 45.57,22.42 42.62,22.42 41.6,23.44 38.39,23.44 v2(36.72,25.11)
I2C_CLK_PD_MUX: length 3.1
  TOP w0.089: R3814.2 39.62,61.68 v1(38.65,60.72) 38.12,60.19 U3801.21
I2C_DATA_PD: length 61.3
  TOP w0.089: RN3701.4 36.64,23.76 36.43,23.97 36.43,24.54 36.07,24.9 v2(36.07,25.11) U3701.28 ; v1(41.55,63.59) 41.17,63.59 v2(40.91,63.33) 41.22,63.03 R3816.1
  L4 w0.127: v2(40.91,63.33) 42.44,63.33 42.69,63.08 42.69,62.44 41.93,61.68 41.93,51.9 43.85,49.98 43.85,40.83 47.14,37.54 47.14,23.46 45.73,22.04 42.46,22.04 41.45,23.06 38.12,23.06 v2(36.07,25.11)
I2C_DATA_PD_MUX: length 4
  TOP w0.089: U3801.22 37.72,60.52 39.14,61.94 v1(39.26,61.94) 39.77,62.44 R3816.2
I2CB_SCL: length 7.6
  TOP w0.089: v2(174.71,77.81) 175.03,77.5 v1(175.03,76.99) 174.84,76.8 172.72,76.8 RN7605.3
  BOTTOM w0.089: GPU1.C9 171.64,79.28 172,78.92 172.46,78.92 172.7,78.68 173.9,78.68 174.71,77.87 v2(174.71,77.81)
I2CB_SDA: length 5.1
  TOP w0.089: RN7605.4 173.29,77.64 v1(173.76,77.18) 173.99,77.41 v2(173.99,77.79)
  BOTTOM w0.089: v2(173.99,77.79) 173.65,77.79 173.59,77.85 173.24,77.85 173.11,77.99 171.68,77.99 171.6,78.07 171.35,78.31 GPU1.C8
I2CC_SCL: length 4
  TOP w0.089: RN7604.4 174.36,79.5 174.62,79.24 v2(174.62,79.17)
  BOTTOM w0.089: v1(175.28,78.14) 175.28,78.51 v2(174.62,79.17) 174.43,79.17 174.31,79.28 GPU1.A9
I2CC_SDA: length 4.7
  TOP w0.089: v1(175.34,78.28) 175.17,78.45 v2(174.77,78.45) 174.39,78.83 RN7604.3
  BOTTOM w0.089: GPU1.B9 172.4,79.28 172.79,78.9 174.29,78.9 174.45,78.74 174.48,78.74 v2(174.77,78.45)
I2CEN: length 8
  TOP w0.089: v1(42.57,58.48) 42.57,59.37 R3874.2 ; v1(42.57,58.48) 42.03,58.48 41.53,57.98 39.8,57.98 39.76,58.02 39.47,58.02 39.44,57.98 U3801.17 ; v1(42.57,58.48) 43.78,58.48 44.44,59.14 45.08,59.14
I_ADP: length 4.2
  TOP w0.089: KBC24.110 149.64,7.29 149.14,6.79 148.53,6.79 v1(148.31,6.56) 148.05,6.31 R2421.2 147.59,5.22 C2435.1
I_BATT: length 4.4
  TOP w0.089: v1(150.64,6.06) v2(150.64,6.68) 151.24,7.28 KBC24.114
  BOTTOM w0.089: v2(150.64,6.68) 149.71,5.75 C2431.1 R2483.2
IC_DELAY: length 2.2
  BOTTOM w0.089: U4302.4 14.2,85.05 PC4307.1 14.29,85.3 v1(14.29,85.97)
ICSP_CLK: length 59.4
  TOP w0.089: v2(145.56,8.98) 145.69,8.98 146.04,8.62 KBC24.101
  L6 w0.089: v2(145.56,8.98) 146.45,9.87 148.44,9.87 148.85,10.28 156.82,10.28 159.03,12.48 178.61,12.48 181.58,15.45 v2(182.14,15.45)
  BOTTOM w0.089: v2(145.56,8.98) 146.07,9.49 v1(146.1,9.49) ; v2(182.14,15.45) 182.95,14.64 182.95,3.72 182.24,3.01 181.5,3.01 180.56,2.06 178.9,2.06 178.8,2.17 178.8,2.62 179.07,2.89 DBEC1.2
ICSP_CLR: length 44.7
  TOP w0.089: R2414.1 v1(178.2,5.29) 177.57,5.29 176.45,6.41 v2(175.53,6.41) ; KBC24.87 143.75,12.98 144.71,12.03 148.36,12.03 148.91,11.47 148.91,10.58 149.37,10.12 150.85,10.12 v2(151.91,9.06)
  L4 w0.089: v2(175.53,6.41) 175.38,6.41 174.84,6.95 164.89,6.95 164.13,7.71 156.64,7.71 155.86,8.48 152.49,8.48 v2(151.91,9.06)
  BOTTOM w0.089: v2(175.53,6.41) 176.33,6.41 177.84,4.89 DBEC1.6
ICSP_DAT: length 60.3
  TOP w0.089: KBC24.102 v2(146.44,8.98)
  L6 w0.089: v2(146.44,8.98) 147.14,9.68 148.52,9.68 148.93,10.09 156.92,10.09 159.11,12.28 178.69,12.28 181.36,14.95 182.65,14.95 v2(183.15,15.45)
  BOTTOM w0.089: v2(146.44,8.98) 146.54,8.88 v1(147.21,8.88) ; v2(183.15,15.45) 183.15,13.46 183.18,13.43 183.18,3.64 182.29,2.74 181.74,2.74 180.86,1.86 178.82,1.86 178.6,2.08 178.6,3.02 178.97,3.39 DBEC1.3
IE_DELAY_G: length 4.8
  TOP w0.089: PQ4313.2 41.55,73.27 41.7,73.11 v1(42.06,73.11) 42.2,73.26 PQ4313.3 42.64,73.87 PR4343.2 43.12,73.9 PC4315.1
IE_DELAY_S: length 3.5
  TOP w0.089: PQ4313.1 40.9,73.97 41.04,73.82 PC4314.1 40.93,73.3 v1(40.09,73.3) 39.34,72.55 PR4344.2
ILIM_HI: length 2.6
  TOP w0.089: R3404.2 22.61,42.12 v2(22.63,42.14) 22.64,42.12 23.13,42.12 v1(23.26,42.25)
  BOTTOM w0.089: v2(22.63,42.14) U3401.16
ILIM_LO: length 2.9
  TOP w0.089: v1(21.79,43.78) R3403.2 v2(22.63,42.89)
  BOTTOM w0.089: U3401.15 22.38,42.64 v2(22.63,42.89)
ILIM_SEL: length 2.6
  BOTTOM w0.089: U3401.4 19.34,40.67 19.21,40.54 18.67,40.54 v1(18.66,40.55) 18.23,40.98 R3405.2
INT2_SELECT: length 5.7
  TOP w0.089: Q7001.5 212.62,55.71 R7008.1 212.06,56.18 v1(211.96,56.28) 211.42,56.82 D7001.2 210.21,57.63 R7013.1
INT#_TYPEC_R: length 2.9
  TOP w0.089: U3701.15 v1(30.86,29.04) 30.37,29.04 30,28.66 R3707.2 R3731.2
IR_CAM_DET#: length 361.1
  TOP w0.089: R2046.2 v2(220.82,39.08) ; R5540.2 107.51,97.78 107.84,97.45 v2(107.84,97.33) 108.1,97.08 v1(108.1,96.61)
  L3 w0.089: v2(74.82,99.4) 74.82,100.42 74.57,100.67 70,100.67 69.22,99.89 69.22,98.55 69.97,97.79 69.97,93.66 70.3,93.33 v2(70.3,88.73) ; v2(212.11,67.4) 212.36,67.14 212.36,65.97 214.15,64.19 214.15,60.9 217.19,57.86 217.19,54.69 218.59,53.29 218.59,50.9 220.24,49.25 220.24,44.79 221.3,43.73 221.3,40.52 220.82,40.04 v2(220.82,39.08) ; v2(84.04,16.24) 84.53,16.24 85.02,15.75 88.22,15.75 88.84,15.75 92.14,19.05 99.52,19.05 102.06,21.59 104.21,21.59 105.32,20.48 114.79,20.48 116.88,22.57 118.65,22.57 122.56,26.48 122.56,30.68 123.43,31.55 123.43,35.56 123.29,35.7 v2(123.29,37.38)
  L4 w0.089: v2(212.11,67.4) 211.52,67.99 211.52,69.55 210.46,70.61 210.46,72.99 209.32,74.13 209.32,74.38 208.72,74.98 200.62,74.98 198.91,76.69 190.99,76.69 189.51,78.17 187.6,78.17 185.03,80.75 182.85,80.75 180.6,83 178.24,83 176.55,81.31 176.55,78.46 174.88,76.8 171.72,76.8 170.85,75.93 167.53,75.93 165.73,77.73 160.88,77.73 159.61,79 159.61,85.07 159.19,85.5 157.56,85.5 155.6,87.46 155.15,87.46 154.77,87.84 154.77,88.41 154.2,88.99 153.44,88.99 151.79,90.64 151.15,90.64 150.53,91.25 147.74,91.25 147.16,91.83 145.49,91.83 144.48,90.83 144.48,89.32 141.97,86.8 136.46,86.8 134.32,88.94 126.74,88.94 121.51,94.17 121.51,96.38 121.02,96.87 108.31,96.87 v2(107.84,97.33) 107.38,96.87 85.23,96.87 85.22,96.88 82.6,96.88 79.78,99.7 75.12,99.7 v2(74.82,99.4)
  BOTTOM w0.089: v2(84.04,16.24) 84.22,16.42 84.22,19.26 85.24,20.28 85.24,25.74 84.48,26.5 84.48,73.38 72.82,85.04 72.82,86.92 71.64,88.1 70.94,88.1 v2(70.3,88.73) ; CPU1.P4 123.23,37.31 v2(123.29,37.38)
IR_CAMERA_DET#_R: length 6.7
  TOP w0.089: v2(108.34,97.83) 108.15,98.02 108.15,98.54 R5540.1 108.4,98.79 v1(108.4,99.66)
  BOTTOM w0.089: LCD1.44 111.85,97.3 111.21,97.94 108.45,97.94 v2(108.34,97.83)
ISH_I2C0_SCL: length 15.8
  BOTTOM w0.089: R2020.1 120.62,22.78 120.62,24.83 RN2007.1 120.98,25.49 121.14,25.65 121.34,25.65 121.84,26.14 121.93,26.14 124.4,28.62 v1(124.4,29.63) 124.4,30.31 124,30.72 124,34.87 124.07,34.94 124.15,35.11 124.15,35.31 124.11,35.39 124.11,35.68 124.15,35.76 124.15,35.96 124.1,36.06 124.1,36.23 123.93,36.46 CPU1.N3
ISH_I2C0_SDA: length 16
  BOTTOM w0.089: CPU1.M4 124.29,36.58 124.29,36.09 124.33,36 124.33,35.72 124.29,35.64 124.29,35.44 124.33,35.35 124.33,35.07 124.27,34.96 124.27,31.43 v1(124.41,31.3) 124.75,30.95 124.75,28.43 121.73,25.41 121.73,25.28 RN2007.2 121.98,24.83 121.98,23.23 R2021.1
ISH_KB_DISABLE: length 21.8
  TOP w0.089: v2(94.89,33.91) 94.55,34.25 92.6,34.25 92.5,34.15 Q2001.2
  BOTTOM w0.089: CPU1.AY8 109.55,39.21 109.25,39.51 108.92,39.51 108.71,39.3 107.08,39.3 106.24,38.46 100.18,38.46 99.94,38.22 98.39,38.22 96.85,36.68 v1(96.85,36.36) 96.85,34.55 96.22,33.91 v2(94.89,33.91)
ITP_PMODE: length 8.9
  BOTTOM w0.102: TP638.1 132.99,35.9 132.99,35.94 130.91,38.03 130.03,38.03 129.75,38.3 129.75,38.48 129.53,38.7 129.29,38.7 129.27,38.68 128.91,38.68 128.88,38.7 128.67,38.7 CPU1.E8
JACK_PLUG: length 12.4
  TOP w0.254: HPMIC1.5 11,14.25 R2923.1 9.98,14.39 v1(9.82,14.54)
  BOTTOM w0.254: ED2902.1 15.24,15.32 15.86,14.7 15.86,13.8 15.49,13.43 15.49,12.85 15.1,12.46 12.34,12.46 11.68,11.8 HPMIC1.5
JACK_PLUG_DET: length 9.9
  BOTTOM w0.254: R2905.1 14.85,13.87 ED2902.2 v1(11.35,14.25) 9.71,14.25 8.25,12.79 HPMIC1.6
JGND:
  vias: v3(16.4,92.92) v3(16.4,92.04) v3(17.29,92.92) v3(17.29,92.04) v3(18.18,92.92) v3(18.18,92.04)
KB_BL_CTRL#: length 14.9
  TOP w0.254: v2(100.48,10.4) AFTP6530.1
  BOTTOM w0.254: v2(100.48,10.4) 100.48,10.76 100.3,10.93 KBBL2.4
  BOTTOM w0.508: Q6501.D 93.72,15.28 EC6505.1 94.08,14.67 94.72,14.03 94.72,10.55 96.03,9.23 99.72,9.23 100.48,9.99 v2(100.48,10.4)
KB_DET#: length 102.8
  TOP w0.102: v2(127.78,13.8) 127.78,16.22 125.78,18.22 R2045.2 125.19,19.39 120.92,19.39 v1(120.67,19.65) 120.61,19.71 120.61,20.55 v2(120.16,21)
  L4 w0.102: v2(120.16,21) 120.16,27.5 119.33,28.33 119.33,29.82 118.51,30.64 118.51,32.61 119.7,33.79 120.03,33.79 120.32,34.08 120.32,34.89 118.67,36.54 v2(118.67,37.11)
  L6 w0.102: v2(82.14,4.36) 82.39,4.36 84.35,6.31 87.75,6.31 88.26,6.82 91.59,6.82 92.2,7.43 106.21,7.43 110.05,11.28 115.27,11.28 116.01,12.01 125.83,12.01 127.62,13.8 v2(127.78,13.8)
  BOTTOM w0.102: KB1.30 65.22,9.69 69.07,5.84 74.55,5.84 75.35,5.03 80.29,5.03 80.97,4.36 v2(82.14,4.36) ; CPU1.AD4 v2(118.67,37.11)
KB_DISABLE_CPU_R: length 4
  TOP w0.089: Q2001.5 92.5,31.11 R2001.2 v1(93.87,30.69) 93.87,31.58 93.65,31.81 Q2001.6
KB_LED_BL_DET: length 51.8
  L3 w0.089: v2(119.75,32.96) 119.75,32.96 119.94,32.77 119.94,31.57 117.04,28.66 117.04,25.47 116.74,25.18 110.97,25.18 107.7,28.44 105.31,28.44 103.38,26.51 103.38,26.08 100.94,23.63 100.93,23.63 99.28,21.98 96.42,21.98 96.42,21.98 94.67,21.98 94.42,22.24 v2(93.89,22.24)
  L4 w0.089: v2(120.09,39.23) 120.5,38.82 120.5,35.91 120.81,35.6 120.81,33.98 120.76,33.93 120.76,33.89 120.23,33.36 120.11,33.36 119.75,33 v2(119.75,32.96)
  BOTTOM w0.089: CPU1.W8 120.29,39.23 v2(120.09,39.23) ; v2(93.89,22.24) 95.47,20.65 v1(95.47,17.36) R6508.1 94.69,16.09 R6507.1
KB_LED_DET_C: length 11.7
  BOTTOM w0.089: v1(93.75,16.6) 94.13,16.22 94.13,15.79 R6507.2 94.71,15.2 C6504.1 EC6506.1 95.32,10.83 96.29,9.87 97.68,9.87 97.98,10.17 97.98,10.44 98.3,10.76 KBBL2.2
KB_LED_PWM: length 75.7
  TOP w0.089: v2(152.72,25.08) 152.72,24.65 152.44,24.37 KBC24.44
  L6 w0.089: v2(92.35,13.04) 92.92,13.61 95.06,13.61 98.17,16.72 99.16,16.72 99.52,16.37 101.48,16.37 102.71,17.6 103.78,17.6 104.48,18.31 109.72,18.31 110.22,18.81 113.67,18.81 114.3,18.19 120.23,18.19 120.93,18.88 123.27,18.88 127.45,23.06 127.45,23.36 128.16,24.07 129.63,24.07 130.64,23.06 133.51,23.06 134.58,24.13 135.95,24.13 138.58,26.76 138.58,27.14 138.85,27.41 141.73,27.41 143.15,26 151.15,26 151.19,26.03 152.4,26.03 152.72,25.71 v2(152.72,25.08)
  BOTTOM w0.089: R6509.1 90.51,15.4 Q6501.G 92.35,13.56 v2(92.35,13.04) v1(92.35,12.41)
KBC_BEEP_R: length 2.5
  TOP w0.254: v1(13.46,9.71) 13.79,9.71 RN2702.4 14.35,11.56 D2702.1
KBC_PWRBTN#: length 153.1
  TOP w0.089: R2432.1 162.07,5.63 v2(162.07,6.44) ; EC6601.1 v2(206.78,58)
  L4 w0.089: v2(162.07,6.44) 162.07,6.56 161.66,6.98 156.25,6.98 155.39,7.84 146.95,7.84 146.74,8.05 143.06,8.05 142.39,8.72 v2(142.39,8.72)
  L6 w0.089: v2(217.93,48.15) 217.29,47.51 217.29,43.64 217.32,43.16 217.32,43.16 217.32,42.52 218.76,41.07 218.76,35.73 218.3,35.27 218.3,32.67 218.28,32.65 218.28,31.57 219.45,30.4 219.45,27.72 220.95,26.22 220.95,23.34 219.79,22.17 219.79,19.25 216.87,16.33 215.75,16.33 212.83,13.41 205.03,13.41 202.7,11.09 196.84,11.09 194.09,8.34 171.92,8.34 170.17,6.59 162.33,6.59 162.17,6.44 v2(162.07,6.44)
  BOTTOM w0.089: v2(142.39,8.72) 142.39,8.73 142.64,8.98 142.64,9.87 142.13,10.37 141.24,10.37 140.99,10.63 140.99,11.52 140.23,12.28 137.82,12.28 136.85,13.24 136.85,14.77 PWSW1.4 PWSW1.3 ; IOBD1.54 v2(206.78,58) 212.49,58 215.46,55.03 215.46,53.88 214.71,53.13 214.71,50.96 215.55,50.13 215.95,50.13 v1(216.41,49.67) v2(217.93,48.15)
KSI0: length 90.2
  TOP w0.089: v2(86.25,5.83) 85.59,5.17 AFTP6548.1 ; v2(144.67,11.26) 144.92,11.02 144.92,8.85 144.84,8.77 KBC24.98
  L6 w0.089: v2(86.25,5.83) 86.92,5.17 88.98,5.17 89.2,5.39 95.03,5.39 96.25,4.17 97.7,2.72 102.96,2.72 104.53,4.29 104.9,4.29 107.51,4.29 111.35,8.13 114.76,8.13 115.09,7.8 115.6,7.8 116.39,7.02 116.92,7.02 127.61,7.02 128.81,8.21 134.52,8.21 135.89,9.58 138.01,9.58 138.78,8.81 139.55,8.81 140.74,9.99 140.74,10.76 141.28,11.29 143.4,11.29 143.86,10.84 144.37,10.84 144.67,11.14 v2(144.67,11.26)
  BOTTOM w0.089: v2(144.67,11.26) 145.06,11.65 RN2403.7 ; v2(86.25,5.83) 85.45,6.64 82.62,6.64 82.54,6.56 75.99,6.56 75.18,7.37 73.39,7.37 71.62,9.14 KB1.22
KSI1: length 91.7
  TOP w0.089: v2(145.31,11.26) 145.14,11.09 145.14,8.8 145.24,8.7 KBC24.99 ; AFTP6547.1 86.66,4.15 v2(86.4,4.42)
  L6 w0.089: v2(145.31,11.26) 145.31,11.01 144.95,10.65 142.01,10.65 141.8,10.44 141.57,10.44 139.47,8.34 137.56,8.34 137.05,7.83 131.94,7.83 131.76,8.01 128.89,8.01 127.7,6.83 117,6.83 116.31,6.82 115.52,7.61 115.01,7.61 114.68,7.94 111.43,7.94 107.59,4.1 104.6,4.1 103.04,2.53 97.62,2.53 96.06,4.09 94.95,5.2 89.28,5.2 88.51,4.42 v2(86.4,4.42)
  BOTTOM w0.089: RN2403.6 145.56,11.51 v2(145.31,11.26) ; KB1.24 70.02,8.26 71.29,6.99 75.02,6.99 75.83,6.18 84.63,6.18 v2(86.4,4.42)
KSI2: length 109.1
  TOP w0.089: AFTP6545.1 83.71,3.9 v2(84.22,4.41) ; v2(156.08,11.26) 156.52,10.82 157.12,10.82 157.68,11.38 KBC24.6
  L3 w0.089: v2(156.08,11.26) 155.65,10.84 153.48,10.84 151.91,12.41 140.97,12.41 140.01,11.45 136.48,11.45 136.19,11.16 127.66,11.16 125.73,13.09 116.82,13.09 116.47,13.44 109.98,13.44 109.33,12.79 109.33,11.39 108.71,10.78 108.11,10.78 107.44,11.45 96.08,11.45 94.71,10.08 93.62,10.08 93.14,10.56 90.64,10.56 88.67,8.58 88.67,7.01 88.22,6.56 85.02,6.56 84.22,5.77 v2(84.22,4.41)
  BOTTOM w0.089: v2(84.22,4.41) 83.51,4.41 82.56,5.35 81.06,5.35 80.61,5.8 75.67,5.8 74.87,6.61 70.33,6.61 68.42,8.52 KB1.26 ; v2(156.08,11.26) 156.36,10.98 156.36,10.05 156.61,9.8 RN2407.3
KSI3: length 103.8
  TOP w0.089: AFTP6550.1 84.55,5.8 v2(85.62,5.8) ; v2(156.81,11.25) 157.35,11.78 KBC24.7
  L3 w0.089: v2(85.62,5.8) 86.13,6.31 88.24,6.31 88.86,6.93 88.86,8.5 90.72,10.37 93.06,10.37 93.54,9.89 94.79,9.89 96.14,11.24 107.38,11.24 107.6,11.02 108.03,10.59 108.79,10.59 109.52,11.31 109.52,12.71 110.06,13.25 116.39,13.25 116.74,12.9 125.65,12.9 127.58,10.97 136.27,10.97 136.56,11.26 140.09,11.26 141.05,12.22 151.72,12.22 153.29,10.65 156.22,10.65 v2(156.81,11.25)
  BOTTOM w0.089: RN2407.4 156.92,11.14 v2(156.81,11.25) ; v2(85.62,5.8) 84.97,6.45 82.7,6.45 82.62,6.37 75.91,6.37 75.1,7.18 72.18,7.18 70.82,8.54 KB1.23
KSI4: length 98.4
  TOP w0.089: KBC24.104 147.24,8.82 145.94,10.12 v2(145.94,11.26) ; v2(84.86,4.41) 85.62,3.64 AFTP6544.1
  L6 w0.089: v2(84.86,4.41) 85.32,4.87 85.67,4.87 85.92,4.62 85.92,4.29 86.25,3.96 88.31,3.96 89.36,5.01 94.78,5.01 97.45,2.34 103.12,2.34 104.68,3.91 107.67,3.91 111.51,7.75 114.6,7.75 114.93,7.42 115.44,7.42 116.23,6.63 117.08,6.63 127.78,6.63 128.97,7.82 131.68,7.82 131.86,7.64 137.13,7.64 137.6,8.11 142.93,8.11 143.2,8.38 143.2,9.44 144.11,10.36 145.04,10.36 v2(145.94,11.26)
  BOTTOM w0.089: v2(145.94,11.26) 146.15,11.47 RN2403.5 ; v2(84.86,4.41) 84.43,3.98 83.66,3.98 82.48,5.16 80.98,5.16 80.53,5.61 75.59,5.61 74.79,6.42 69.83,6.42 67.62,8.63 KB1.27
KSI5: length 97.5
  TOP w0.089: AFTP6546.1 87.52,2.42 v2(85.5,4.45) ; v2(146.58,11.26) 146.58,9.79 147.64,8.73 KBC24.105
  L6 w0.089: v2(85.5,4.45) 86.17,3.77 88.39,3.77 89.44,4.82 94.7,4.82 97.37,2.15 103.19,2.15 104.76,3.72 107.75,3.72 111.59,7.56 114.52,7.56 114.85,7.23 115.37,7.23 116.15,6.44 127.86,6.44 129.05,7.63 131.6,7.63 131.8,7.43 137.22,7.43 137.7,7.92 143.01,7.92 143.39,8.3 143.39,9.37 144.19,10.17 145.24,10.17 145.91,10.84 146.15,10.84 v2(146.58,11.26)
  BOTTOM w0.089: KB1.25 69.22,8.3 70.72,6.8 74.95,6.8 75.75,5.99 80.69,5.99 81.14,5.54 82.64,5.54 83.32,4.86 85.08,4.86 v2(85.5,4.45) ; v2(146.58,11.26) 147.01,11.7 RN2404.8
KSI6: length 99.4
  TOP w0.089: KBC24.107 148.44,9.65 147.85,10.25 v2(147.85,11.26) ; AFTP6543.1 89.43,3.14 v2(89.68,3.39)
  L6 w0.089: v2(147.85,11.26) 147.21,10.63 146.02,10.63 145.37,9.97 144.27,9.97 143.58,9.29 143.58,8.23 143.07,7.71 137.76,7.71 137.3,7.24 131.72,7.24 131.52,7.44 129.12,7.44 127.94,6.25 117.24,6.25 116.07,6.25 115.29,7.04 114.77,7.04 114.44,7.37 111.67,7.37 107.81,3.52 104.92,3.52 103.27,1.87 97.33,1.87 94.57,4.63 90.92,4.63 v2(89.68,3.39)
  BOTTOM w0.089: v2(147.85,11.26) 147.6,11.51 RN2404.7 ; KB1.28 66.82,9.11 69.7,6.23 74.71,6.23 75.52,5.42 80.45,5.42 80.9,4.97 82.4,4.97 84.49,2.88 89.17,2.88 v2(89.68,3.39)
KSI7: length 101.1
  TOP w0.089: v2(148.48,11.26) 148.48,10.12 148.84,9.76 KBC24.108 ; AFTP6542.1 91.33,2.37 v2(90.32,3.39)
  L6 w0.089: v2(148.48,11.26) 147.66,10.44 146.1,10.44 145.45,9.78 144.35,9.78 143.78,9.21 143.78,8.15 143.15,7.52 137.84,7.52 137.38,7.05 131.64,7.05 131.44,7.25 129.2,7.25 128.01,6.06 117.32,6.06 115.99,6.06 115.21,6.85 114.69,6.85 114.36,7.18 111.75,7.18 107.89,3.33 105,3.33 103.35,1.68 97.25,1.68 94.49,4.44 91.36,4.44 v2(90.32,3.39)
  BOTTOM w0.089: KB1.29 66.02,9.53 69.51,6.04 74.63,6.04 75.44,5.23 80.37,5.23 80.82,4.78 82.32,4.78 84.48,2.63 89.56,2.63 v2(90.32,3.39) ; RN2404.6 148.1,11.65 v2(148.48,11.26)
KSO0: length 97.1
  TOP w0.089: v2(154.71,11.26) 156.19,9.78 KBC24.2 ; AFTP6557.1 85.75,8.98 v2(87.4,7.33)
  L3 w0.089: v2(154.71,11.26) 153.37,12.6 140.89,12.6 139.93,11.64 136.4,11.64 136.12,11.36 127.72,11.36 125.81,13.28 116.9,13.28 116.54,13.63 109.9,13.63 109.14,12.87 109.14,11.56 108.54,10.97 108.19,10.97 107.52,11.64 96,11.64 94.63,10.27 93.7,10.27 93.22,10.75 90.56,10.75 87.4,7.58 v2(87.4,7.33)
  BOTTOM w0.089: v2(154.71,11.26) 155.13,10.84 155.25,10.84 156.4,9.68 156.4,9.52 R2484.2 ; v2(87.4,7.33) 87.4,7.9 86.21,9.09 80.18,9.09 78.82,10.44 KB1.13
KSO1: length 97.1
  TOP w0.089: v2(87.52,5.8) 88.79,4.53 AFTP6558.1 ; v2(154.71,16.22) 156.34,14.58 KBC24.14
  L6 w0.089: v2(154.71,16.22) 154.22,15.73 144.11,15.73 143.65,16.19 139.24,16.19 137.94,14.89 129.12,14.89 128.29,14.06 128.29,13.12 128.09,12.92 127.01,12.92 125.91,11.82 116.14,11.82 115.41,11.08 110.13,11.08 106.29,7.24 92.28,7.24 91.67,6.62 88.34,6.62 v2(87.52,5.8)
  BOTTOM w0.089: KB1.15 77.22,9.95 78.47,8.7 86,8.7 86.78,7.93 86.78,7.04 87.52,6.3 v2(87.52,5.8) ; 158.14,15.08 157.82,15.08 157.51,15.39 155.54,15.39 v2(154.71,16.22)
KSO2: length 96.4
  TOP w0.089: v2(155.34,16.22) 156.58,14.98 KBC24.15 ; v2(88.29,5.8) 89.56,4.53 AFTP6556.1
  L6 w0.089: v2(155.34,16.22) 155.34,15.86 155.02,15.54 144.03,15.54 143.57,15.99 139.32,15.99 138.02,14.7 129.2,14.7 128.48,13.98 128.48,13.04 128.16,12.72 127.09,12.72 125.99,11.63 116.22,11.63 115.48,10.89 110.21,10.89 106.37,7.05 92.36,7.05 91.75,6.43 88.91,6.43 v2(88.29,5.8)
  BOTTOM w0.089: KB1.14 78.02,9.97 79.1,8.9 86.08,8.9 86.97,8 86.97,7.12 v2(88.29,5.8) ; v2(155.34,16.22) 155.98,15.58 158.14,15.58
KSO3: length 95.6
  TOP w0.089: KBC24.16 156.81,15.38 v2(155.98,16.22) ; AFTP6555.1 87.14,6.06 v2(86.89,5.8)
  L6 w0.089: v2(155.98,16.22) 155.98,15.84 155.49,15.35 143.95,15.35 143.49,15.8 139.4,15.8 138.1,14.51 129.28,14.51 128.67,13.9 128.67,12.96 128.24,12.53 127.17,12.53 126.07,11.44 116.3,11.44 115.56,10.7 110.29,10.7 106.45,6.86 92.44,6.86 91.83,6.24 89.1,6.24 88.71,5.85 88.71,5.63 88.46,5.38 87.31,5.38 v2(86.89,5.8)
  BOTTOM w0.089: v2(86.89,5.8) 86.89,6.66 86.59,6.96 86.59,7.85 85.92,8.51 78.33,8.51 76.42,10.43 KB1.16 ; 158.14,16.17 157.8,16.17 157.49,15.85 157.48,15.85 157.42,15.79 156.4,15.79 v2(155.98,16.22)
KSO4: length 99
  TOP w0.089: KBC24.37 155.24,22.22 v2(155.57,21.89) ; AFTP6551.1 84.65,7.95 v2(85.53,7.07)
  L6 w0.089: v2(155.57,21.89) 155.55,21.89 154.49,20.83 148.1,20.83 147.34,21.59 137.26,21.59 136.92,21.93 135.34,21.93 133.55,20.14 128.61,20.14 124.83,16.36 118.03,16.36 117.82,16.57 111.2,16.57 110.76,16.13 107.23,16.13 107.11,16.26 104.72,16.26 104.45,15.99 103.39,15.99 100.31,12.91 98.03,12.91 94.88,9.76 92.89,9.76 92.49,10.16 89.45,10.16 88.06,8.77 87.19,8.77 85.62,7.2 85.62,7.16 v2(85.53,7.07)
  BOTTOM w0.089: RN2409.5 155.42,22.04 v2(155.57,21.89) ; v2(85.53,7.07) 85.09,7.51 84.69,7.51 84.27,7.09 82.53,7.09 82.38,6.95 76.15,6.95 75.34,7.75 74.78,7.75 73.22,9.32 KB1.20
KSO5: length 98
  TOP w0.089: KBC24.38 154.84,21.98 v2(154.93,21.89) ; v2(84.86,7.07) 84.73,6.95 AFTP6549.1
  L6 w0.089: v2(84.86,7.07) 86.74,8.96 87.98,8.96 89.37,10.35 92.57,10.35 92.97,9.95 94.8,9.95 97.95,13.1 100.23,13.1 103.31,16.18 104.37,16.18 104.64,16.45 107.19,16.45 107.31,16.32 110.68,16.32 111.12,16.76 117.9,16.76 118.11,16.55 124.75,16.55 126.61,18.41 126.61,20.01 126.93,20.33 133.47,20.33 135.37,22.22 136.9,22.22 137.34,21.78 147.41,21.78 148.18,21.02 153.96,21.02 154.41,21.46 154.48,21.46 154.9,21.89 v2(154.93,21.89)
  BOTTOM w0.089: KB1.21 72.42,9.16 74.02,7.56 75.26,7.56 76.07,6.76 82.46,6.76 82.6,6.9 84.68,6.9 v2(84.86,7.07) ; RN2409.6 154.83,21.99 v2(154.93,21.89)
KSO6: length 95.8
  TOP w0.089: AFTP6553.1 82.75,8.42 v2(83.46,7.71) ; v2(154.3,21.89) 154.44,22.03 KBC24.39
  L6 w0.089: v2(154.3,21.89) 154.28,21.89 153.6,21.21 148.26,21.21 147.49,21.97 137.41,21.97 136.97,22.41 135.29,22.41 133.39,20.52 126.85,20.52 126.42,20.09 126.42,18.49 125.42,17.49 124.18,17.49 123.64,16.95 111.04,16.95 110.6,16.52 107.39,16.52 107.26,16.64 104.56,16.64 104.29,16.37 103.23,16.37 100.15,13.29 97.87,13.29 94.72,10.14 93.05,10.14 92.65,10.54 89.29,10.54 87.9,9.15 86.33,9.15 84.51,7.33 83.84,7.33 v2(83.46,7.71)
  BOTTOM w0.089: v2(83.46,7.71) 83.08,8.09 79.4,8.09 78.63,7.33 76.86,7.33 74.82,9.37 KB1.18 ; v2(154.3,21.89) 154.33,21.92 RN2409.7
KSO7: length 104.1
  TOP w0.089: v2(153.02,16.19) 153.02,17.23 152.76,17.49 151.15,17.49 150.64,17.99 150.64,21.48 150.04,22.08 KBC24.50 ; AFTP6552.1 86.13,7.11 v2(86.16,7.07)
  L6 w0.089: v2(86.16,7.07) 87.35,8.26 88.2,8.26 89.31,9.36 91.36,9.36 91.54,9.19 91.89,9.19 92.24,9.54 102.19,9.54 103.62,10.97 106.11,10.97 108.52,13.38 109.91,13.38 110,13.47 121.16,13.47 121.27,13.35 125.11,13.35 128.28,16.52 137.34,16.52 138.35,17.53 147.58,17.53 148.46,16.64 150.12,16.64 150.12,16.64 152.73,16.64 153.02,16.36 v2(153.02,16.19)
  BOTTOM w0.089: v2(153.02,16.19) 154.01,15.2 157.19,15.2 157.89,14.49 158.14,14.49 ; KB1.19 74.02,9.34 76.23,7.14 82.3,7.14 82.45,7.28 84.19,7.28 84.61,7.7 85.54,7.7 v2(86.16,7.07)
KSO8: length 95.7
  TOP w0.089: v2(151.76,21.87) 151.64,21.99 KBC24.46 ; AFTP6554.1 83.84,8.09 v2(84.11,7.82)
  L6 w0.089: v2(84.11,7.82) 85.81,9.52 88,9.52 89.21,10.73 92.73,10.73 93.13,10.33 94.64,10.33 97.79,13.48 98.38,13.48 100.07,13.48 103.15,16.56 104.21,16.56 104.48,16.83 107.34,16.83 107.47,16.71 110.52,16.71 110.96,17.14 123.56,17.14 124.24,17.83 125.49,17.83 126.23,18.57 126.23,20.34 127.32,21.44 131.46,21.44 131.47,21.44 134.04,21.44 135.21,22.6 137.05,22.6 137.49,22.16 147.57,22.16 148.28,21.46 151.34,21.46 v2(151.76,21.87)
  BOTTOM w0.089: KB1.17 75.62,8.94 76.98,7.58 78.51,7.58 79.25,8.32 83.61,8.32 v2(84.11,7.82) ; v2(151.76,21.87) 151.76,22.03 152.57,22.85 RN2409.8
KSO9: length 84
  TOP w0.089: v2(147.85,16.34) 145.94,18.25 145.94,20.33 145.69,20.58 KBC24.68 141.37,20.58 141.17,20.79 R2449.2 ; v2(91.37,7.33) 92.1,7.33 AFTP6563.1
  L6 w0.089: v2(147.85,16.34) 147.42,15.92 144.45,15.92 143.98,16.39 138.83,16.39 137.58,15.14 128.51,15.14 125.58,12.21 115.93,12.21 115.19,11.47 109.96,11.47 106.12,7.64 91.68,7.64 v2(91.37,7.33)
  BOTTOM w0.089: KB1.7 83.62,11.1 84.12,10.6 84.89,10.6 85.26,10.23 86.83,10.23 89.09,7.97 90.72,7.97 v2(91.37,7.33) ; R2450.1 148.23,16.72 v2(147.85,16.34)
KSO10: length 75.4
  TOP w0.089: v2(147.21,16.34) 144.5,19.06 143.99,19.06 143.91,18.98 KBC24.72 ; AFTP6566.1 89.68,8.84 v2(89.94,8.59)
  L6 w0.089: v2(147.21,16.34) 146.22,17.34 138.43,17.34 137.18,16.09 128.12,16.09 125.19,13.16 121.19,13.16 121.08,13.28 110.08,13.28 109.99,13.19 108.6,13.19 106.19,10.78 103.7,10.78 101.6,8.68 91.56,8.68 91.13,9.1 90.45,9.1 v2(89.94,8.59)
  BOTTOM w0.089: KB1.5 85.22,11.03 85.64,10.61 87.06,10.61 89.08,8.59 v2(89.94,8.59) ; RN2410.6 146.83,16.73 v2(147.21,16.34)
KSO11: length 74.6
  TOP w0.089: AFTP6565.1 90.58,8.6 v2(90.57,8.59) ; v2(146.58,16.34) 144.74,18.18 KBC24.74
  L6 w0.089: v2(90.57,8.59) 90.67,8.49 101.68,8.49 103.78,10.59 106.26,10.59 108.68,13 110.07,13 110.16,13.09 121,13.09 121.11,12.97 125.27,12.97 128.2,15.9 137.26,15.9 138.51,17.15 145.77,17.15 v2(146.58,16.34)
  BOTTOM w0.089: v2(146.58,16.34) 146.33,16.59 RN2410.7 ; v2(90.57,8.59) 90.15,8.16 89.23,8.16 86.97,10.42 85.44,10.42 85.01,10.84 84.64,10.84 84.42,11.07 KB1.6
KSO12: length 80.1
  TOP w0.089: AFTP6559.1 87.78,7.57 v2(88.05,7.3) ; v2(145.94,16.34) 144.51,17.78 KBC24.75
  L6 w0.089: v2(145.94,16.34) 145.33,16.96 138.59,16.96 137.34,15.71 128.27,15.71 125.35,12.78 121.04,12.78 120.92,12.9 110.24,12.9 109.48,12.13 109.48,11.85 105.92,8.3 90.88,8.3 90.75,8.16 88.91,8.16 v2(88.05,7.3)
  BOTTOM w0.089: RN2410.8 145.74,16.55 v2(145.94,16.34) ; KB1.12 79.62,10.66 81.01,9.28 86.4,9.28 88.05,7.63 v2(88.05,7.3)
KSO13: length 75.5
  TOP w0.089: v2(90.06,7.36) 89.71,7.36 AFTP6562.1 ; KBC24.76 144.27,17.38 v2(145.31,16.34)
  L6 w0.089: v2(145.31,16.34) 144.88,16.77 138.67,16.77 137.42,15.52 128.35,15.52 125.43,12.59 120.96,12.59 120.84,12.71 110.32,12.71 109.75,12.14 109.75,11.81 106.04,8.11 90.96,8.11 90.83,7.97 90.68,7.97 v2(90.06,7.36)
  BOTTOM w0.089: v2(90.06,7.36) 89.84,7.58 88.9,7.58 86.64,9.85 82.17,9.85 82.02,9.99 KB1.9 ; RN2411.3 144.87,16.78 v2(145.31,16.34)
KSO14: length 71.6
  TOP w0.089: v2(144.67,16.34) 144.04,16.98 KBC24.77 ; AFTP6564.1 90.7,6.95 v2(90.7,7.33)
  L6 w0.089: v2(90.7,7.33) 91.21,7.83 106.04,7.83 109.87,11.66 115.1,11.66 115.84,12.4 125.5,12.4 128.43,15.33 137.5,15.33 138.75,16.58 144.44,16.58 v2(144.67,16.34)
  BOTTOM w0.089: KB1.8 82.82,11.42 83.87,10.37 84.75,10.37 85.08,10.04 86.72,10.04 88.97,7.78 90.24,7.78 v2(90.7,7.33) ; RN2411.4 144.22,16.8 v2(144.67,16.34)
KSO15: length 92.1
  TOP w0.089: v2(149.35,11.31) 148.44,12.22 146.45,12.22 145.29,13.38 KBC24.86 ; AFTP6561.1 92.1,2.25 v2(90.95,3.39)
  L6 w0.089: v2(90.95,3.39) 91.81,4.25 94.41,4.25 97.18,1.48 103.43,1.48 105.08,3.14 107.97,3.14 111.83,6.99 114.28,6.99 114.61,6.66 115.13,6.66 115.92,5.87 117.4,5.87 128.09,5.87 129.28,7.06 131.36,7.06 131.56,6.86 137.46,6.86 137.92,7.33 143.23,7.33 143.97,8.07 143.97,9.13 144.43,9.59 145.53,9.59 146.18,10.25 148.28,10.25 v2(149.35,11.31)
  BOTTOM w0.089: v2(90.95,3.39) 90.95,5.8 89.36,7.39 88.83,7.39 86.56,9.66 81.89,9.66 81.22,10.33 KB1.10 ; RN2404.5 148.69,11.98 v2(149.35,11.31)
KSO16: length 77.7
  TOP w0.089: v2(90.32,5.82) 91.09,5.04 91.84,5.04 92.35,4.53 AFTP6560.1 ; KBC24.92 143.78,10.98 144.04,11.24 v2(144.04,11.26)
  L6 w0.089: v2(90.32,5.82) 94.87,5.82 96.44,4.25 97.78,2.91 102.88,2.91 104.45,4.48 104.98,4.48 107.43,4.48 111.27,8.32 114.84,8.32 115.17,7.99 115.68,7.99 116.47,7.21 116.84,7.21 127.53,7.21 128.73,8.4 134.44,8.4 135.81,9.77 136.92,9.77 137.45,10.3 137.8,10.65 140.33,10.65 141.2,11.52 143.78,11.52 v2(144.04,11.26)
  BOTTOM w0.089: v2(144.04,11.26) 144.47,11.7 RN2403.8 ; KB1.11 80.42,10.37 81.32,9.47 86.48,9.47 90.13,5.82 v2(90.32,5.82)
L_BKLT_CTRL: length 99.8
  L3 w0.114: v2(122.2,40.04) 121.78,40.45 121.78,41.16 122.57,41.95 122.57,44.82 123.92,46.17 123.92,47.76 123.46,48.22 115.66,48.22 114.89,48.98 114.89,64.13 114.93,64.16 114.93,71.57 116.1,72.74 116.1,74.82 117.53,76.24 117.53,77.33 118.16,77.96 118.16,85.27 108.99,94.45 101.19,94.45 v2(100.3,95.34)
  L4 w0.114: v2(86.63,95.31) 89.47,95.31 89.88,94.9 90.24,94.9 91.67,96.33 99.31,96.33 v2(100.3,95.34)
  BOTTOM w0.114: v2(86.63,95.31) 87.47,95.31 88.18,94.6 88.18,93.64 R5502.2 88.62,93.61 v1(89.17,93.05) 90.15,92.08 D5502.1 ; v2(122.2,40.04) 122.35,40.27 122.37,40.27 122.73,40.67 CPU1.R11
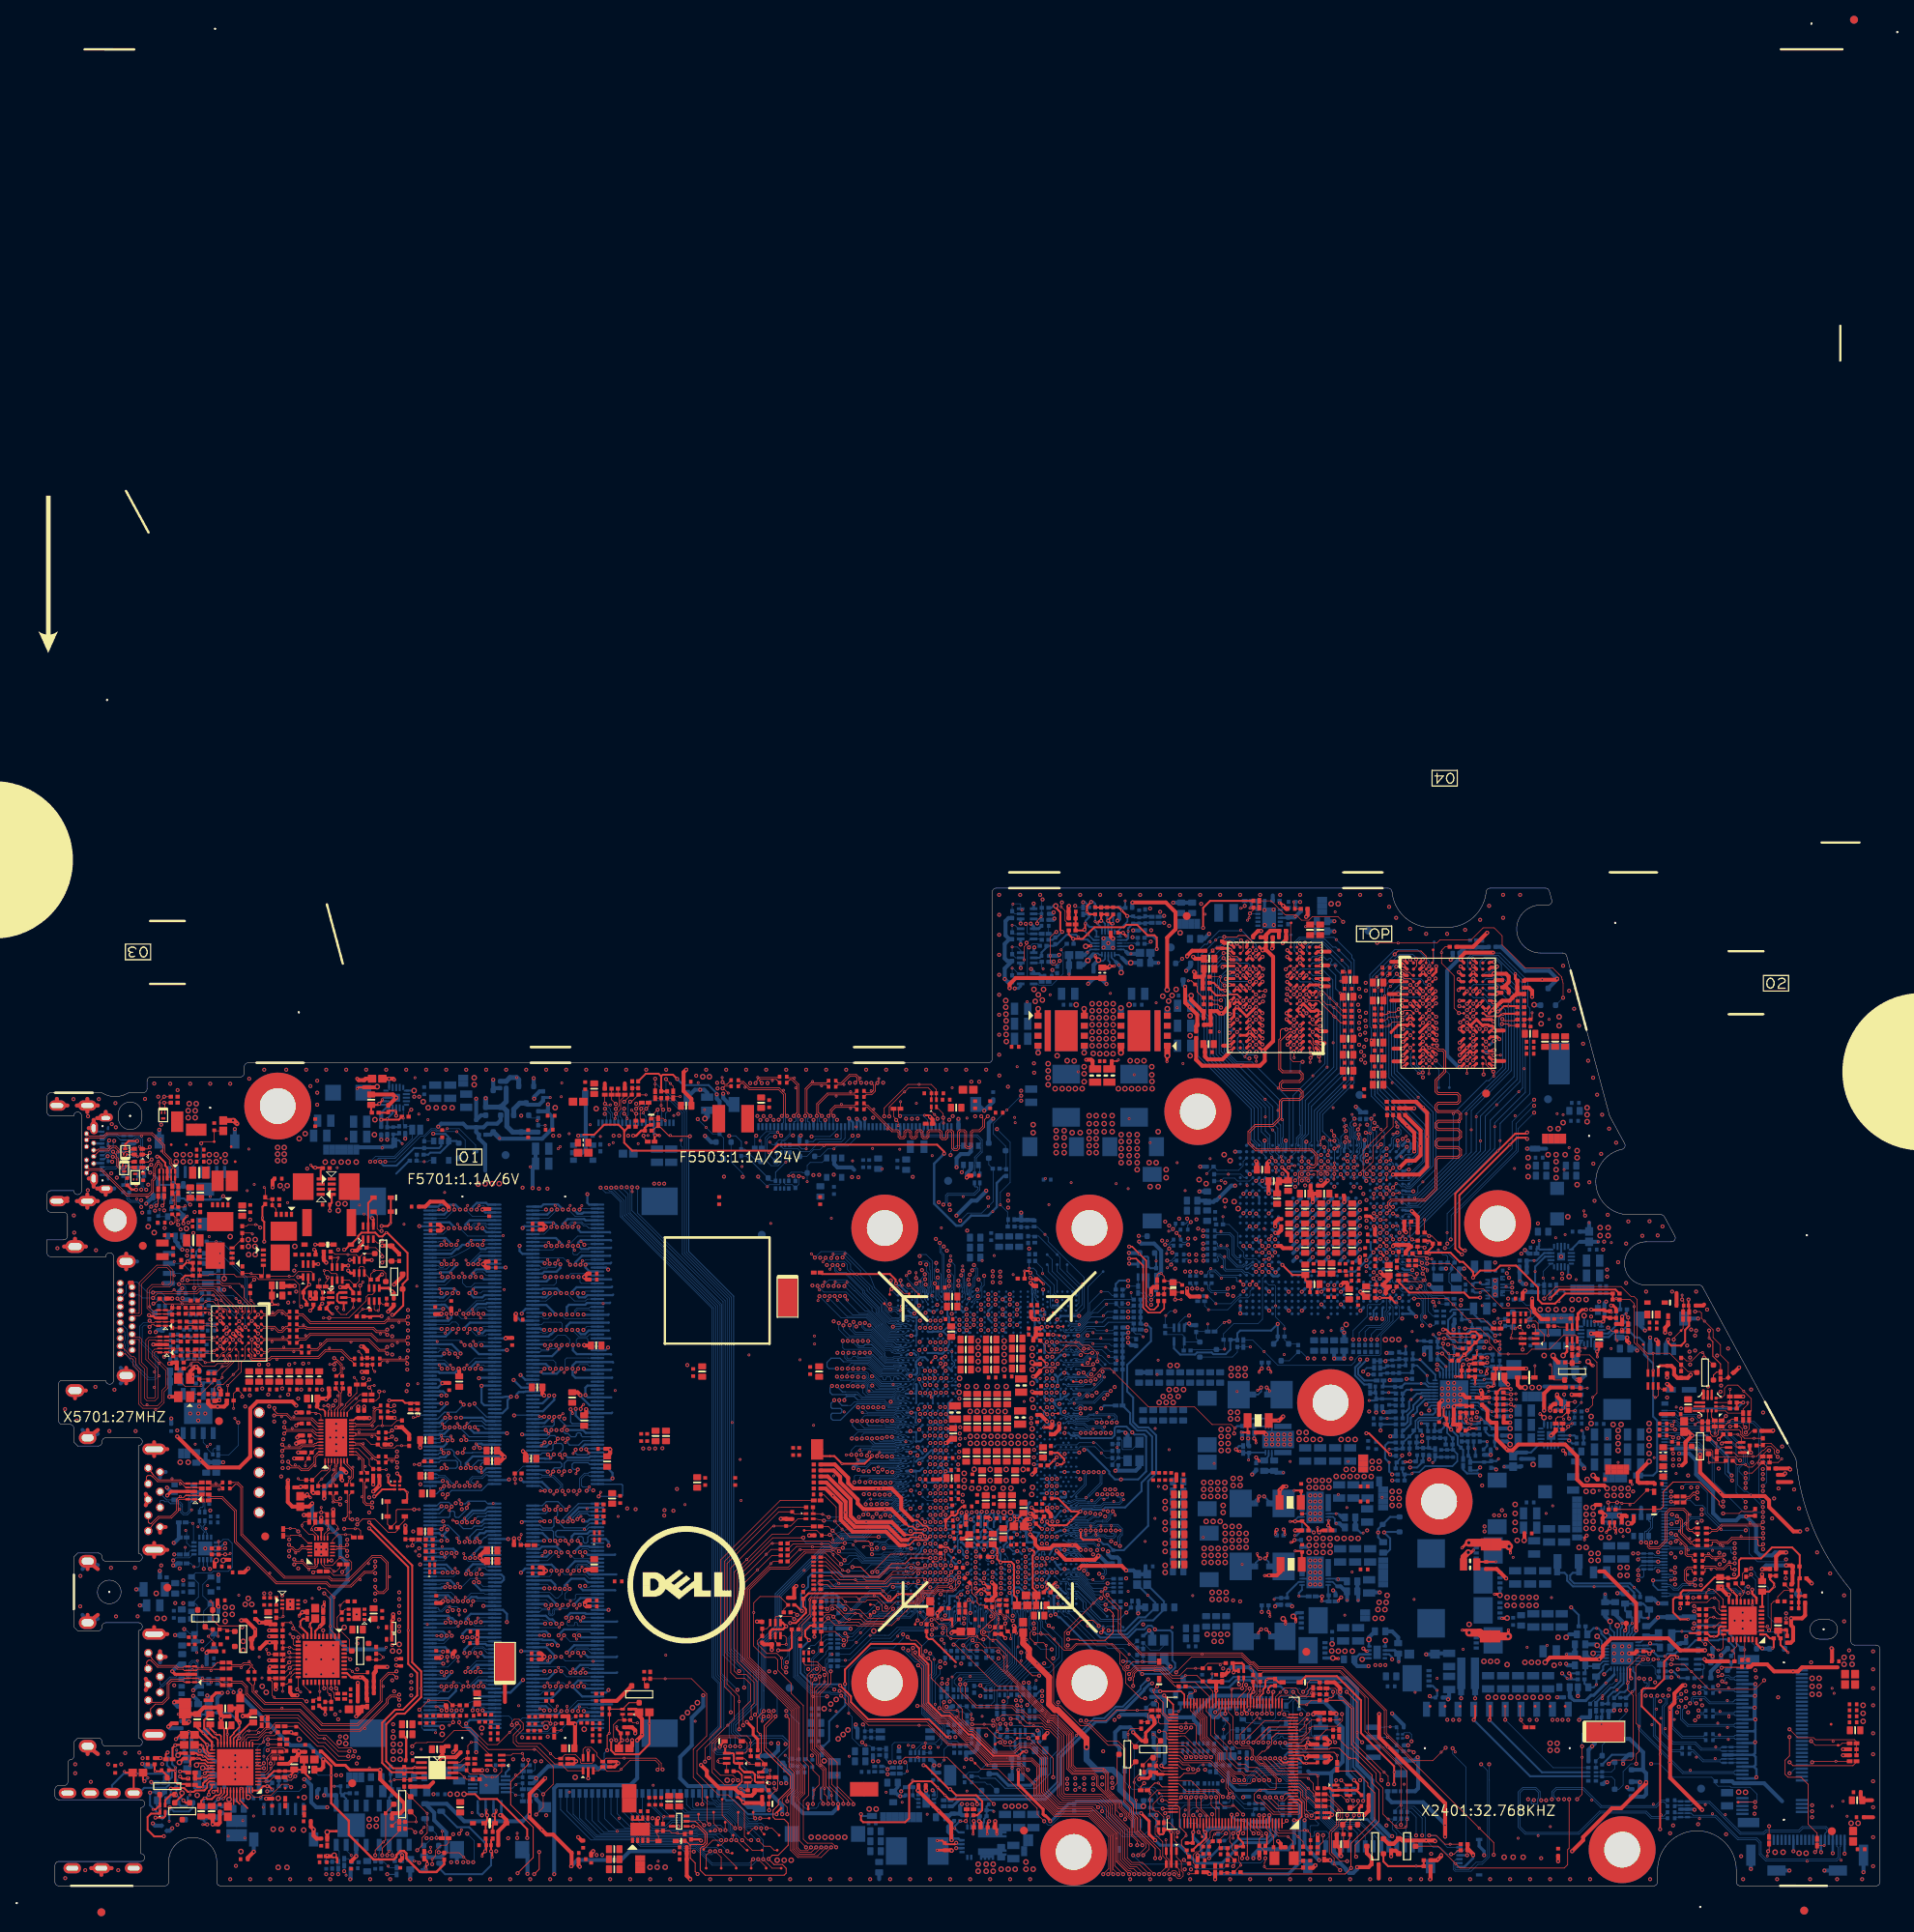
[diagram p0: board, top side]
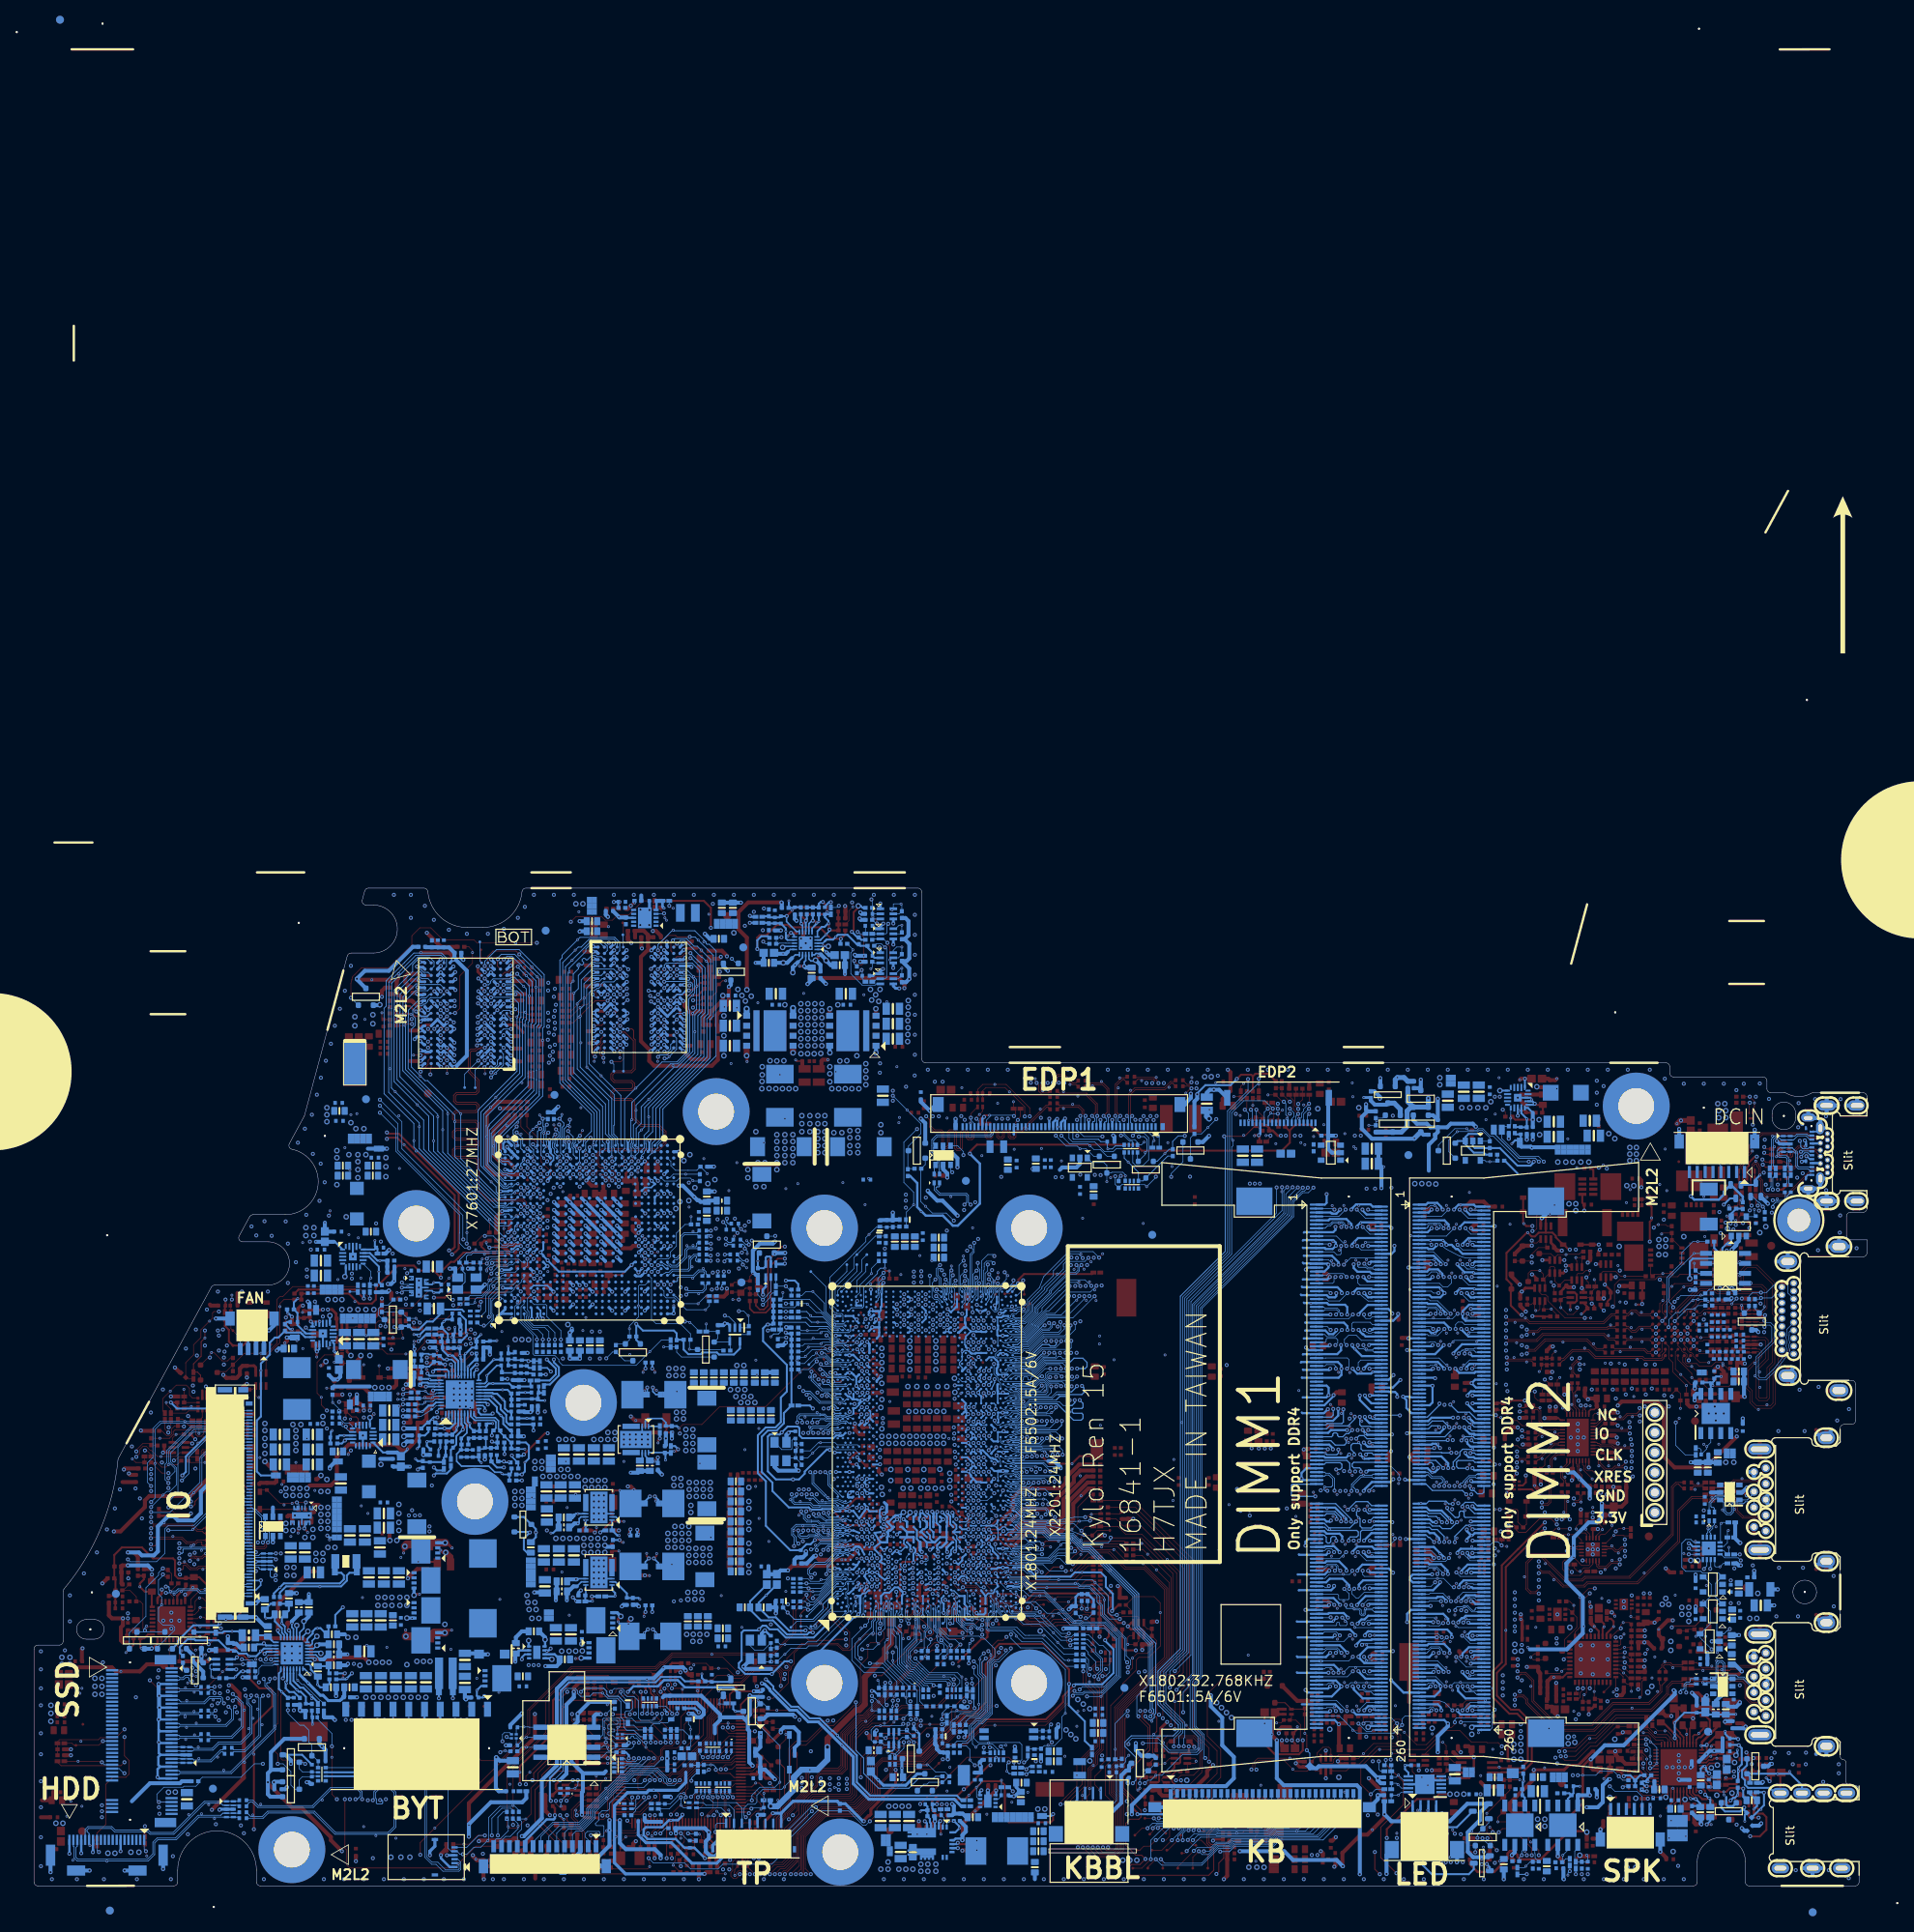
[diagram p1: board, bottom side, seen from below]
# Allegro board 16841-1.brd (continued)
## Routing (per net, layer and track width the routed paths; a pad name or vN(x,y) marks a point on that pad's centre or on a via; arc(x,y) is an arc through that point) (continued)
L_BKLT_EN: length 41.6
  TOP w0.089: R2427.2 139.75,20.84 R2436.1 139.8,21.8 R2435.2 v1(138.45,22.31) 135.82,22.31 134.51,21 v2(131.99,21)
  L4 w0.089: v2(131.99,21) 131.49,21.5 130.43,21.5 129.42,22.52 123.03,22.52 122.61,22.94 122.61,23.75 122.93,24.07 122.93,30.47 123.68,31.22 123.68,34.01 122.69,35 122.69,40.53 123.28,41.12 v2(123.28,41.21)
  BOTTOM w0.089: CPU1.R12 v2(123.28,41.21)
L_BKLT_EN_L: length 4.2
  TOP w0.089: R2427.1 137.64,19.98 137.31,19.65 v1(137.31,19.26) 137.31,18.63 D2401.2
LAN_CLK_CPU: length 130.6
  L4 w0.14: v2(210.16,47.19) 210.42,46.93 211.19,46.93 211.49,46.63 211.49,38.3 211.49,38.08 210.54,37.13 210.54,32.33 208.31,30.1 206.86,30.1 205.91,29.15 205.91,28.46 205.76,28.31 204.44,26.99 203.78,26.99 200.78,26.99 199.97,26.17 177.28,26.17 177.16,26.3 166.49,26.3 166.11,26.68 154.28,26.68 150.63,30.33 150.63,32.65 149.06,34.21 147.79,34.21 145.05,36.95 145.05,52.9 141.24,56.72 134.22,56.72 133.97,56.97 133.97,57.42 v2(133.83,57.56)
  BOTTOM w0.102: v1(132.86,58.05) 132.86,58.2 ; 132.86,58.2 133.86,58.2 134.01,58.06 134.01,57.73 v2(133.83,57.56) ; 132.86,58.2 132.08,58.2 131.68,58.61 130.67,58.61 130.43,58.73 130.28,58.8 CPU1.C41 ; v2(210.16,47.19) 209.88,46.91 208.77,46.91 207.37,45.51 206.08,45.51 206,45.6 IOBD1.23
LAN_CLK_CPU#: length 130.6
  L4 w0.14: v2(134.46,57.56) 134.23,57.33 134.23,57.08 134.33,56.98 141.35,56.98 145.32,53.01 145.32,37.06 147.9,34.48 149.17,34.48 150.9,32.76 150.9,30.44 154.39,26.95 166.22,26.95 166.6,26.57 177.27,26.57 177.39,26.44 199.85,26.44 200.67,27.25 203.89,27.25 204.32,27.25 205.65,28.57 205.65,29.26 206.75,30.36 208.2,30.36 210.27,32.44 210.27,37.24 211.22,38.19 211.22,46.52 211.08,46.66 210.42,46.66 v2(210.16,46.4)
  BOTTOM w0.102: 134.18,58.2 133.95,58.43 132.18,58.43 131.77,58.84 130.72,58.84 130.33,59.02 130,59.02 129.94,59.09 129.62,59.09 129.33,58.8 CPU1.D41 ; 134.18,58.2 134.23,58.15 134.23,57.79 v2(134.46,57.56) ; 134.18,58.2 v1(134.31,58.33) ; IOBD1.22 206,45.2 206.08,45.29 207.47,45.29 208.86,46.68 209.88,46.68 v2(210.16,46.4)
LAN_WAKE#: length 157.7
  TOP w0.089: v2(124.58,14.74) 123.71,15.62 119.76,15.62 117.11,18.27 116.68,18.27 114.37,20.59 113.35,20.59 111.06,22.87 v2(110.54,22.87) ; v2(73.68,18.5) 73.73,18.55 R1707.2 ; v2(158.26,24.66) 158.89,24.03 160.54,24.03 R2428.1 160.85,24.34 R2408.1 ; v1(114.05,41.46) 114.05,42.49 v2(114.13,42.57)
  L3 w0.089: v2(124.58,14.74) 124.58,16.06 130.2,21.68 133.5,21.68 134.51,20.66 136.04,20.66 137.38,22.01 146.5,22.01 147.24,21.27 152.41,21.27 v2(153.03,21.88) ; v2(110.54,22.87) 112.65,24.99 116.83,24.99 117.32,25.48 117.32,28.67 118.98,30.34 118.98,30.34 120.3,31.66 120.3,33.1 119.07,34.33 119.07,35.9 117.47,37.51 117.47,39.82 116.7,40.58 116.69,40.58 116.28,41 116.28,41.41 115.79,41.9 114.32,41.9 114.13,42.09 v2(114.13,42.57) 114.52,43.23 114.53,43.24 114.53,43.95 113.66,44.82 110.73,44.82 108.73,42.82 108.73,34.5 105.87,31.64 104.03,31.64 103.42,31.64 100.33,28.55 96.1,28.55 95.61,28.06 95.61,27.35 93.94,25.69 89.48,25.69 89.03,26.14 87.56,26.14 87.15,26.14 80.98,19.96 74.12,19.96 73.68,19.52 v2(73.68,18.5)
  BOTTOM w0.089: v2(158.26,24.66) 158.26,24.34 157.63,23.71 156.99,23.71 156.74,23.46 156.74,22.57 157.07,22.24 157.58,22.24 157.75,22.06 157.75,21.55 157.5,21.3 156.87,21.3 156.36,20.79 153.44,20.79 153.03,21.2 v2(153.03,21.88) ; CPU1.AM15 114.45,42.9 v2(114.13,42.57)
LANWAKE#: length 7.1
  TOP w0.089: KBC24.35 156.04,24.03 v1(156.61,24.6) 157.17,25.16 158.59,25.16 158.9,24.85 158.9,24.6 159.28,24.22 159.91,24.22 160.17,24.47 160.17,24.75 160.57,25.16 R2428.2
LANWAKE#_IC: length 111.8
  TOP w0.089: v2(170.33,12.91) 170.33,13.93 v1(169.82,14.44) 165.98,18.28 165.98,22.57 164.49,24.07 164.22,24.07 163.81,24.48 163.81,24.9 163.6,25.11 R2406.2 R2408.2
  L6 w0.089: v2(170.33,12.91) 170.45,12.91 170.92,13.38 178.29,13.38 181.55,16.65 188.1,16.65 189.41,15.34 194.76,15.34 197.26,17.84 205.57,17.84 205.83,17.59 210.84,17.59 214.65,21.4 214.65,29.97 213.58,31.04 213.58,33.63 213.17,34.04 213.17,39.09 213.91,39.83 213.91,45.2 213.99,45.27 213.99,48.75 212.75,50 212.75,55.56 210.46,57.85 210.46,59.02 v2(209.82,59.65)
  BOTTOM w0.089: IOBD1.60 206.97,60.4 207.47,59.91 209.57,59.91 v2(209.82,59.65)
LCD_BRIGHTNESS: length 9.3
  BOTTOM w0.114: RN5501.4 94.46,94.04 95.46,94.04 95.84,93.66 v1(96.41,93.66) 96.49,93.74 EC5501.1 97.3,94.58 97.61,94.88 100.76,94.88 100.85,94.97 LCD1.22
LCD_CBL_DET#: length 143.6
  TOP w0.089: R2039.2 75.33,97.55 75.33,98.64 v2(75.46,98.77)
  L3 w0.089: v2(86.76,17.74) 87.65,16.85 88.38,16.85 91.68,20.15 99.06,20.15 101.6,22.69 103.75,22.69 104.67,22.69 105.78,21.58 114.33,21.58 116.43,23.68 117.08,23.68 118.26,24.85 118.64,24.85 119.65,25.87 119.65,29.42 120.92,30.69 120.92,32.22 121.15,32.45 v2(121.15,37.15)
  BOTTOM w0.089: v2(121.15,37.15) 120.84,36.84 CPU1.W4 ; v2(86.76,17.74) 86.76,18.76 86.63,18.88 86.63,20.79 89.05,23.2 89.05,27.14 86.38,29.81 86.38,74.6 80.68,80.29 80.68,93.89 80.54,94.04 v1(80.54,94.75) 80.68,94.9 80.68,98.24 79.14,99.78 76.47,99.78 v2(75.46,98.77)
LCD_TST: length 272.8
  TOP w0.102: KBC24.26 156.1,19.38 155.54,18.82 155.54,18.02 154.63,17.11 154.35,17.11 153.64,16.4 153.64,16.04 154.1,15.58 154.43,15.58 156.56,13.45 v2(156.56,13.42)
  L4 w0.102: v2(92.48,95.22) 92.48,95.21 93.03,94.65 118.85,94.65 126.16,87.34 134.38,87.34 136.25,85.46 143.17,85.46 144.04,86.32 146.84,86.32 148,87.49 148,89.53 148.61,90.14 150.12,90.14 150.49,89.78 150.49,88.82 152.35,86.96 154.25,86.96 154.74,86.47 155.18,86.47 157.65,84 157.65,77.67 158.39,76.92 158.39,75.91 159.2,75.09 162.15,75.09 162.45,75.4 163.86,75.4 164.16,75.09 164.94,75.09 165.01,75.17 165.48,75.17 166.94,73.7 172,73.7 173.34,75.04 173.8,75.04 173.98,74.87 175.74,74.87 178.57,77.7 178.57,80.49 179.7,81.62 180.44,81.62 182.47,79.59 182.9,79.59 183.71,78.78 185.45,78.78 187.11,77.12 189.08,77.12 190.56,75.64 198.47,75.64 200.18,73.93 203.55,73.93 207.41,70.07 207.41,68.54 208.06,67.89 v2(208.6,67.89)
  L6 w0.102: v2(156.56,13.42) 157.25,13.42 158.3,14.48 177.06,14.48 180.97,18.39 189.81,18.39 190.38,18.96 206,18.96 206.28,18.68 210.43,18.68 213.49,21.74 213.49,29.59 212.47,30.62 212.47,33.21 212.08,33.59 212.08,40.05 211.45,40.68 211.45,44.4 211.73,44.68 211.73,56.29 210,58.02 210,58.84 209.32,59.52 209.32,63.71 210,64.4 210,66.05 209.75,66.3 209.75,66.74 v2(208.6,67.89)
  BOTTOM w0.102: RN5501.8 92.65,92.19 D5502.2 91.66,92.95 v1(91.66,93.2) 91.43,93.43 91.43,94.86 91.79,95.22 v2(92.48,95.22)
LCD_TST_C: length 4.4
  BOTTOM w0.089: LCD1.9 94.35,95.6 93.58,94.83 92.98,94.83 92.65,94.5 RN5501.1 92.14,94.17 v1(91.79,94.52)
LCD_VCC_TEST_EN: length 267.3
  TOP w0.089: v2(151.16,9.08) 150.84,8.76 KBC24.113
  L3 w0.089: v2(217.06,26.5) 216.54,27.03 216.54,30.93 219.37,33.77 219.37,35.12 219.83,35.58 219.83,41.26 219.56,41.53 219.56,48.04 218.19,49.42 217.72,49.42 216.81,50.33 216.81,52.26 215.68,53.39 215.68,56.38 214.66,57.39 214.66,59.46 213.49,60.63 213.49,63.77 211.09,66.17 211.09,67.71 209.44,69.36 209.44,69.81 v2(209.32,69.94)
  L4 w0.089: v2(209.32,69.94) 208.97,69.94 204.78,74.13 200.26,74.13 198.55,75.84 190.64,75.84 189.16,77.32 187.2,77.32 184.67,79.84 182.5,79.84 180.48,81.87 179.67,81.87 178.37,80.57 178.37,77.78 175.66,75.06 174.06,75.06 173.88,75.24 173.26,75.24 171.92,73.9 167.34,73.9 164.31,76.93 160.41,76.93 157.84,79.5 157.84,84.08 155.26,86.66 154.82,86.66 153.96,87.52 153.38,87.52 153.15,87.75 153.15,88.14 151.64,89.65 150.9,89.65 150.21,90.34 148.48,90.34 147.74,89.6 147.74,87.86 146.59,86.72 144.15,86.72 143.09,85.66 136.34,85.66 134.46,87.54 126.31,87.54 118.51,95.34 v2(103.02,95.34)
  L6 w0.089: v2(151.16,9.08) 151.57,9.49 157.18,9.49 159.36,11.67 178.95,11.67 180.32,13.04 190.31,13.04 191.35,14.08 195.3,14.08 197.78,16.57 204.77,16.57 205.38,15.96 211.86,15.96 216.17,20.28 216.17,25.61 v2(217.06,26.5)
  BOTTOM w0.089: D5501.2 98.2,92.71 99.16,93.66 v1(99.94,93.66) 100.3,94.02 101.7,94.02 v2(103.02,95.34)
LCDVDD:
  vias: v1(102.31,92.14) v1(104.85,93.71)
LDO1_CAP: length 4.4
  TOP w0.152: v2(21.74,11.04) 21.79,11.09 21.82,11.09 22.5,11.76 HDA27.39
  BOTTOM w0.254: v1(22.35,11.06) 21.76,11.06 v2(21.74,11.04) 21.18,10.48 C2731.2 21.31,10.15 R2747.2
LDO2_CAP: length 2.6
  TOP w0.203: HDA27.21 22.9,19.26 v1(22.9,19.26) 22.9,19.9
  TOP w0.254: C2734.2 22.9,19.9
LDO3_CAP: length 4
  TOP w0.203: v1(24.45,19.34) 24.38,19.26 24.2,19.26 23.7,18.76 HDA27.19
  TOP w0.254: C2736.1 25.88,20.76 v1(24.45,19.34)
LID_CL_SIO#: length 127.4
  TOP w0.102: RN2406.1 151.33,25.66 v2(151.39,25.61) ; KBC24.66 142.41,21.38 141.75,22.04 141.75,23.3 140.53,24.52 v1(140.53,24.85) 140.53,24.9 v2(140.99,25.36) 141.24,25.61 D2402.K
  L3 w0.102: v2(140.99,25.36) 141.17,25.54 141.5,25.54 141.55,25.59 151.38,25.59 v2(151.39,25.61) 151.84,26.05 153.09,26.05 153.84,25.3 153.84,24.24 154.13,23.95 172.75,23.95 176.86,19.85 183.66,19.85 189.19,14.31 198.85,14.31 199.5,14.96 200.49,14.96 205.38,19.85 209.81,19.85 215.49,25.53 215.49,31.03 218.56,34.11 218.56,35.46 219.02,35.91 219.02,40.71 216.43,43.31 216.43,44.51 v2(215.74,45.19)
  BOTTOM w0.102: v2(215.74,45.19) 212.72,45.19 210.59,47.32 210.59,48.02 210.26,48.35 209.37,48.35 208.69,49.02 207.33,49.02 206.7,48.4 IOBD1.30
LID_CL_SIO_TAB#: length 120.7
  TOP w0.089: R6604.1 216.63,47.59 215.16,47.59 214.9,47.33 v2(212.87,47.33) ; v2(144.44,8.98) KBC24.97
  L4 w0.089: v2(206.39,47.2) 206.39,47.66 208.3,49.57 208.3,50.89 208.81,51.4 210.46,51.4 212.36,49.49 212.36,47.84 v2(212.87,47.33)
  L6 w0.089: v2(212.87,47.33) 211.96,46.42 211.96,44.63 211.65,44.32 211.65,40.77 212.19,40.23 212.29,40.14 212.29,33.67 212.67,33.29 212.67,30.7 213.77,29.6 213.77,21.74 210.5,18.47 206.2,18.47 205.92,18.76 190.46,18.76 189.89,18.19 181.05,18.19 177.14,14.27 158.68,14.27 157.07,12.66 154.91,12.66 154.33,12.08 153.74,12.08 152.13,10.47 148.77,10.47 148.36,10.06 146.26,10.06 145.61,9.4 144.87,9.4 v2(144.44,8.98)
  BOTTOM w0.089: v2(144.44,8.98) 144.44,9.51 v1(144.57,9.64) ; IOBD1.27 v2(206.39,47.2)
LINE1-L_C: length 14.6
  TOP w0.254: v2(15.31,16.95) 15.08,16.72 R2922.1 ; v2(20.34,7.81) 20.33,7.8 v1(19.78,7.8)
  L3 w0.254: v2(15.31,16.95) 15.31,13.93 16.5,12.74 17.8,12.74 18.31,12.23 18.31,9.84 v2(20.34,7.81)
  BOTTOM w0.254: C2907.2 19.9,8.25 v2(20.34,7.81)
LINE1-L_R: length 2.8
  BOTTOM w0.254: v1(14.37,9.74) 13.96,10.15 C2908.2 14.07,10.88 14.88,11.69 R2921.1
LINE1_L: length 3.3
  TOP w0.203: v2(20.54,11.59) 20.54,12.05 20.93,12.44 HDA27.36
  BOTTOM w0.254: C2907.1 19.9,10.95 v1(20.09,11.14) v2(20.54,11.59)
LINE1_R: length 7.9
  TOP w0.203: 20.03,12.18 20.34,12.49 20.34,13 20.62,13.27 HDA27.35
  TOP w0.254: 20.03,12.18 19.98,12.13 18.82,12.13 18.64,11.95 v1(18.18,11.95) 17.89,11.95 17.4,12.43 15.79,12.43 v2(15.72,12.36)
  BOTTOM w0.254: v2(15.72,12.36) 15.72,11.31 C2908.1
LVDS_VDD_EN_R: length 8.2
  BOTTOM w0.089: U5501.1 98.45,91.93 96.92,91.93 96.54,91.55 D5501.3 ; D5501.3 96,90.6 95.91,90.69 94.51,90.69 94.2,90.38 RN5502.8 ; D5501.3 v1(96.54,89.5)
M2_SSD_PEDET: length 110.3
  TOP w0.089: AFTP6303.1 214.76,10.65 v2(216.94,10.65)
  L3 w0.089: v2(203.73,15.51) 201.75,13.53 199.1,13.53 198.32,12.74 197.96,12.74 197.71,12.99 197.71,13.35 197.53,13.53 188.87,13.53 183.7,18.7 176.71,18.7 172.37,23.04 147.6,23.04 147.38,23.26 140.88,23.26 138.18,25.95 138.18,27.63 135.3,30.52 132.56,30.52 129.06,34.01 127.83,34.01 v2(127.47,34.37)
  BOTTOM w0.089: v2(127.47,34.37) 127.47,36.57 CPU1.G4 ; SSD1.69 v2(216.94,10.65) 217.19,10.9 217.19,11.64 216.3,12.53 213.89,12.53 213.76,12.66 212.24,12.66 211.93,12.97 R6305.2 211.42,13.8 206.52,13.8 204.81,15.51 v2(203.73,15.51)
M_A_A0: length 57.4
  TOP w0.152: v1(62.66,50.2) 63.22,50.2 v2(63.23,50.21)
  L3 w0.089: 99.15,64.5 100.1,64.5 v2(100.32,64.72)
  L3 w0.203: 99.15,64.5 99.07,64.42 98.63,64.42 98.32,64.11 89.18,64.11 83.59,58.52 75.26,58.52 71.71,54.96 70.93,54.96 69.9,53.94 66.97,53.94 66.79,53.76 64.03,53.76 63.11,52.84 63.11,50.61 63.23,50.49 v2(63.23,50.21)
  BOTTOM w0.089: v2(100.32,64.72) 100.8,64.24 103.9,64.24 104.39,63.75 104.39,63.42 104.91,62.9 107.62,62.9 107.84,62.68 108.74,62.68 108.87,62.82 CPU1.AY50
  BOTTOM w0.152: v2(63.23,50.21) 62.62,50.82 DM1.144
M_A_A1: length 56.5
  TOP w0.152: v1(67.18,52.39) v2(67.41,52.92)
  L3 w0.089: 98.89,63.43 98.89,63.59 99.42,64.11 102.52,64.11 102.68,64.28 103.44,64.28 103.73,64.57 v2(103.73,64.65)
  L3 w0.203: 98.89,63.43 98.55,63.09 89.6,63.09 83.14,56.63 82.63,56.63 82.43,56.83 82.43,57.3 82.23,57.5 81.82,57.5 81.62,57.3 81.62,56.83 81.41,56.63 81.01,56.63 80.8,56.83 80.8,57.3 80.6,57.5 80.19,57.5 79.99,57.3 79.99,56.83 79.79,56.63 79.38,56.63 79.18,56.83 79.18,57.3 78.97,57.5 78.57,57.5 78.37,57.3 78.37,56.83 78.16,56.63 77.76,56.63 77.55,56.83 77.55,57.3 77.35,57.5 76.94,57.5 76.74,57.3 76.74,56.83 76.54,56.63 74.84,56.63 72.14,53.94 71.34,53.94 70.32,52.92 v2(67.41,52.92)
  BOTTOM w0.089: CPU1.BB50 107.84,63.26 105.69,63.26 104.96,63.99 104.42,63.99 103.76,64.65 v2(103.73,64.65)
  BOTTOM w0.152: v2(67.41,52.92) 66.89,52.92 66.69,53.12 66.69,53.57 66.89,53.78 68.72,53.78 68.92,53.57 DM1.133
M_A_A2: length 58.5
  TOP w0.152: v1(63.95,52.21) v2(64.28,52.67)
  L3 w0.089: 98.88,63.95 98.98,64.05 99.1,64.05 99.35,64.29 101.88,64.29 102.27,64.68 v2(102.27,64.73)
  L3 w0.203: v2(64.28,52.67) 64.28,53.03 64.49,53.23 66.99,53.23 67.18,53.43 70.11,53.43 71.13,54.44 71.93,54.44 74.63,57.14 76.02,57.14 76.23,57.34 76.23,57.8 76.43,58.01 82.44,58.01 82.73,57.71 83.5,57.71 89.39,63.6 98.53,63.6 98.88,63.95
  BOTTOM w0.089: v2(102.27,64.73) 102.32,64.73 102.67,65.08 103.93,65.08 104.14,64.88 104.14,64.52 104.5,64.17 105.08,64.17 105.79,63.45 108,63.45 108.07,63.39 108.16,63.39 108.31,63.34 108.51,63.34 108.71,63.4 109.18,63.4 CPU1.AY51
  BOTTOM w0.152: DM1.132 61.7,53.82 65.18,53.82 65.39,53.62 65.39,53.33 65.18,53.12 64.43,53.12 64.28,52.97 v2(64.28,52.67)
M_A_A3: length 57.9
  TOP w0.152: v1(65.37,52.18) v2(65.68,52.69)
  L3 w0.089: 99.05,63.1 99.16,63.21 99.16,63.57 99.53,63.94 102.95,63.94 102.95,63.94 104.44,63.94 v2(104.8,63.58)
  L3 w0.203: 99.05,63.1 98.53,62.58 89.81,62.58 83.34,56.11 81.48,56.11 81.27,55.9 81.27,55.68 81.07,55.48 80.66,55.48 80.46,55.68 80.46,55.9 80.26,56.11 79.85,56.11 79.65,55.9 79.65,55.68 79.45,55.48 79.04,55.48 78.84,55.68 78.84,55.9 78.63,56.11 75.03,56.11 72.23,53.3 71.42,53.3 70.53,52.41 67.49,52.41 66.58,51.5 65.7,51.5 65.41,51.78 65.41,52.43 v2(65.68,52.69)
  BOTTOM w0.089: CPU1.BA50 108.35,62.86 107.91,62.86 107.69,63.08 105.3,63.08 v2(104.8,63.58)
  BOTTOM w0.152: v2(65.68,52.69) 65.68,53.69 66.06,54.07 DM1.131
M_A_A4: length 57.4
  TOP w0.152: v1(63.98,54.37) v2(63.62,54.82)
  L3 w0.102: 99.38,65.33 100.81,65.33 100.81,65.33 101.31,65.33 101.49,65.14 102.16,65.14 102.36,65.35 v2(102.36,65.73)
  L3 w0.203: v2(63.62,54.82) 63.62,55.16 63.78,55.32 65.5,55.32 65.5,55.31 65.96,55.31 66.32,54.95 69.46,54.95 70.97,56.46 71.68,56.46 74.83,59.61 79.89,59.61 80.1,59.81 80.1,60.25 80.3,60.45 80.71,60.45 80.91,60.25 80.91,59.81 81.11,59.61 81.52,59.61 81.72,59.81 81.72,60.25 81.92,60.45 82.33,60.45 82.53,60.25 82.53,59.81 82.74,59.61 83.25,59.61 89.08,65.44 99.04,65.44 99.16,65.33 99.38,65.33
  BOTTOM w0.089: v2(102.36,65.73) 102.36,66.07 102.54,66.25 104.2,66.25 105.77,64.68 106.08,64.68 106.17,64.59 106.17,64.39 106.26,64.3 106.48,64.3 106.57,64.39 106.57,64.59 106.65,64.68 107.05,64.68 107.13,64.6 107.13,64.33 107.22,64.25 107.44,64.25 107.53,64.33 107.53,64.6 107.61,64.68 107.85,64.68 CPU1.BB52
  BOTTOM w0.152: v2(63.62,54.82) 63.44,55.01 62.89,55.01 62.71,54.82 61.71,54.82 DM1.128
M_A_A5: length 58.5
  TOP w0.152: v1(65.45,54.34) v2(65.12,54.81)
  L3 w0.089: v2(101.6,64.73) 101.6,64.73 101.18,65.14 100.74,65.14 100.74,65.15 100,65.15 99.79,64.94 99.36,64.94
  L3 w0.203: 99.36,64.94 97.99,64.94 97.67,64.62 97.17,64.62 96.85,64.94 96.36,64.94 96.04,64.62 95.55,64.62 95.23,64.94 94.74,64.94 94.42,64.62 93.92,64.62 93.6,64.94 93.11,64.94 92.79,64.62 92.3,64.62 91.98,64.94 91.48,64.94 91.16,64.62 90.67,64.62 90.35,64.94 89.29,64.94 83.46,59.1 83.04,59.1 83.03,59.1 75.07,59.1 74.99,59.02 74.97,59.02 71.9,55.95 71.18,55.95 69.67,54.44 66.76,54.44 66.58,54.27 65.28,54.27 65.12,54.43 v2(65.12,54.81)
  BOTTOM w0.089: v2(101.6,64.73) 101.6,65.12 101.8,65.31 104.09,65.31 104.32,65.09 104.32,64.6 104.57,64.34 105.15,64.34 105.87,63.63 108.08,63.63 108.11,63.6 108.16,63.6 108.19,63.57 108.34,63.52 108.48,63.52 108.68,63.58 CPU1.BA51
  BOTTOM w0.152: v2(65.12,54.81) 65.12,55.05 65.52,55.45 65.52,55.99 65.29,56.23 64.45,56.23 64.25,56.02 64.25,55.53 64.05,55.32 DM1.126
M_A_A6: length 57.7
  TOP w0.152: v1(66.82,54.95) v2(67.14,55.44)
  L3 w0.203: v2(67.14,55.44) 67.35,55.65 67.35,55.67 67.63,55.96 67.63,55.96 68.29,56.62 69.7,56.62 70.55,57.47 71.26,57.47 75.81,62.02 77.42,62.02 77.62,62.23 77.62,62.78 77.82,62.98 78.23,62.98 78.43,62.78 78.43,62.23 78.64,62.02 79.14,62.02 79.35,62.23 79.35,62.83 79.55,63.03 79.96,63.03 80.16,62.83 80.16,62.23 80.36,62.02 80.77,62.02 80.97,62.23 80.97,62.83 81.18,63.03 81.58,63.03 81.79,62.83 81.79,62.23 81.99,62.02 82.4,62.02 82.6,62.23 82.6,62.83 82.8,63.03 83.21,63.03 83.41,62.83 83.41,62.23 83.62,62.02 84.12,62.02 88.56,66.46 99.04,66.46 99.25,66.25 101.2,66.25 v2(101.71,65.74)
  BOTTOM w0.089: v2(101.71,65.74) 101.71,65.99 102.14,66.43 104.33,66.43 105.89,64.86 108.15,64.86 CPU1.BA52
  BOTTOM w0.152: v2(67.14,55.44) 67.14,54.99 67.34,54.79 68.6,54.79 68.89,55.07 DM1.127
M_A_A7: length 60.5
  TOP w0.152: v1(62.78,55.94) v2(63.19,56.36)
  L3 w0.203: v2(103.72,65.73) 106.12,65.73 106.32,65.94 106.32,66.34 106.12,66.54 99.54,66.54 99.11,66.97 88.35,66.97 84.92,63.54 77.25,63.54 76.86,63.15 76.22,63.15 71.05,57.98 70.34,57.98 69.49,57.13 68.08,57.13 66.76,55.82 65.72,55.82 65.71,55.82 63.72,55.82 v2(63.19,56.36)
  BOTTOM w0.089: CPU1.AW52 109.87,64.35 109.58,64.06 106.05,64.06 104.37,65.73 v2(103.72,65.73)
  BOTTOM w0.152: v2(63.19,56.36) 63.15,56.32 DM1.122
M_A_A8: length 58.4
  TOP w0.152: v1(68.8,55.03) v2(68.46,55.49)
  L3 w0.203: v2(68.46,55.49) 68.46,55.91 68.67,56.12 69.91,56.12 70.76,56.97 71.47,56.97 74.62,60.12 75.38,60.12 75.62,60.36 75.62,61.11 76.02,61.51 76.74,61.51 76.95,61.31 76.95,60.33 77.15,60.13 77.56,60.13 77.76,60.33 77.76,61.31 77.96,61.51 78.37,61.51 78.57,61.31 78.57,60.33 78.78,60.13 79.18,60.13 79.38,60.33 79.38,61.31 79.59,61.51 80.1,61.51 80.3,61.31 80.3,61.16 80.5,60.96 80.91,60.96 81.11,61.16 81.11,61.31 81.32,61.51 81.72,61.51 81.92,61.31 81.92,61.16 82.13,60.96 82.53,60.96 82.74,61.16 82.74,61.31 82.94,61.51 84.43,61.51 88.87,65.95 99.04,65.95 99.25,65.74 v2(100.32,65.74)
  BOTTOM w0.089: 101.16,66.6 104.4,66.6 105.96,65.04 108.66,65.04 109.02,64.68 109.03,64.68 CPU1.AY52
  BOTTOM w0.152: DM1.125 68.61,55.57 68.52,55.49 v2(68.46,55.49) ; 101.16,66.6 100.71,67.06 99.59,67.06 99.06,66.53 99.06,65.98 99.3,65.74 v2(100.32,65.74)
M_A_A9: length 57
  TOP w0.152: v1(65.83,56.35) v2(66.14,56.83)
  L3 w0.203: v2(101.79,67.75) 101.79,67.74 101.33,67.28 100.19,67.28 99.92,67.55 99.92,67.6 99.48,68.04 87.98,68.04 84.54,64.6 84.03,64.6 83.83,64.8 83.83,65.34 83.63,65.55 83.22,65.55 83.02,65.34 83.02,64.8 82.81,64.6 82.41,64.6 82.2,64.8 82.2,64.97 82,65.18 81.59,65.18 81.39,64.97 81.39,64.8 81.19,64.6 80.64,64.6 79.8,65.43 76.9,65.43 70.56,59.09 70.14,59.09 70.01,59.09 69.07,58.15 67.66,58.15 66.34,56.83 v2(66.14,56.83)
  BOTTOM w0.089: CPU1.BB54 106.04,65.48 104.53,66.98 103,66.98 102.7,67.28 102.38,67.28 102.09,66.98 101.71,66.98 101.58,67.11 101.58,67.55 v2(101.79,67.75)
  BOTTOM w0.152: DM1.121 68.08,56.57 67.52,56.02 66.36,56.02 66.14,56.24 v2(66.14,56.83)
M_A_A10: length 58.6
  TOP w0.152: v1(66.34,48.22) v2(65.94,47.8)
  L3 w0.089: v2(111.54,62.63) 110.83,61.93 109.18,61.93 107.31,60.06 100.44,60.06 100.3,59.92
  L3 w0.203: v2(65.94,47.8) 66.14,48 69.41,48 69.59,47.81 69.69,47.81 69.69,47.81 72.69,47.81 72.69,47.81 72.76,47.81 75.58,50.63 79.43,50.63 79.73,50.92 80.47,50.92 80.83,50.56 81.28,50.56 81.64,50.92 82.1,50.92 82.45,50.56 82.91,50.56 83.27,50.92 84.33,50.92 91.73,58.32 98.7,58.32 100.3,59.92
  BOTTOM w0.152: DM1.146 62.91,48.32 63.41,48.83 64.89,48.83 65.92,47.8 v2(65.94,47.8) ; CPU1.AT50 v2(111.54,62.63)
M_A_A11: length 58.1
  TOP w0.152: v1(64.54,56.35) v2(64.87,56.83)
  L3 w0.089: 99.74,68.54 99.75,68.55 100.16,68.55 100.97,67.74 v2(101.09,67.74)
  L3 w0.203: v2(64.87,56.83) 65.02,56.98 65.02,57.03 65.4,57.42 66.21,57.42 66.55,57.75 66.55,58.37 66.83,58.66 68.86,58.66 69.96,59.76 69.96,60.13 70.4,60.56 70.68,60.56 70.85,60.39 71.14,60.39 71.43,60.68 71.43,60.96 71.26,61.14 71.26,61.42 71.55,61.71 71.83,61.71 72,61.54 72.29,61.54 72.58,61.83 72.58,62.11 72.41,62.29 72.41,62.57 72.69,62.86 72.98,62.86 73.15,62.69 73.44,62.69 73.73,62.98 73.73,63.26 73.56,63.43 73.56,63.72 73.84,64.01 74.13,64.01 74.3,63.84 74.59,63.84 76.83,66.08 80.75,66.08 81.12,65.71 82.38,65.71 82.75,66.08 85.31,66.08 87.77,68.54 99.74,68.54
  BOTTOM w0.089: CPU1.BA54 108.48,65.22 106.05,65.22 104.46,66.81 101.6,66.81 101.31,67.1 101.31,67.52 v2(101.09,67.74)
  BOTTOM w0.152: DM1.120 63.5,56.82 63.9,57.23 64.47,57.23 v2(64.87,56.83)
M_A_A12: length 59.4
  TOP w0.152: v1(65.73,58.41) v2(65.37,57.92)
  L3 w0.089: v2(103.23,67.75) 102.8,68.18 100.81,68.18 99.94,69.05 99.69,69.05
  L3 w0.203: v2(65.37,57.92) 65.37,58.34 66.2,59.17 68.65,59.17 69.46,59.97 69.46,60.34 74.11,64.99 74.4,64.99 74.57,64.82 74.86,64.82 75.14,65.11 75.14,65.4 74.97,65.57 74.97,65.86 75.86,66.75 85.25,66.75 87.56,69.05 99.69,69.05
  BOTTOM w0.089: v2(103.23,67.75) 103.09,67.75 102.99,67.65 102.99,67.26 103.09,67.16 104.62,67.16 106.12,65.66 107.71,65.66 107.78,65.74 108.19,65.74 108.27,65.7 108.52,65.7 108.64,65.74 108.82,65.74 108.99,65.69 109.07,65.61 109.07,65.44 109.29,65.22 109.9,65.22 110.04,65.36 CPU1.AW54
  BOTTOM w0.152: v2(65.37,57.92) 65.39,57.92 65.85,57.47 66.17,57.47 66.56,57.07 67.08,57.07 67.23,57.23 67.23,57.42 67.38,57.57 67.69,57.57 67.84,57.42 67.84,57.23 67.99,57.07 DM1.119
M_A_A13: length 60.8
  TOP w0.152: v1(64.87,43.39) v2(64.53,43.86)
  L3 w0.089: 101.83,58.51 101.86,58.48 108.14,58.48 108.52,58.85 109.06,58.85 109.43,58.48 109.9,58.48 110.11,58.68 110.11,59.75 110.67,60.31 v2(110.67,60.58)
  L3 w0.203: v2(64.53,43.86) 64.51,43.88 64.51,44.55 64.81,44.85 77.17,44.85 79.48,47.16 79.73,47.16 80.4,47.84 83.2,47.84 83.71,47.33 84.67,47.33 93.01,55.67 98.31,55.67 101.15,58.51 101.83,58.51
  BOTTOM w0.152: DM1.158 62.68,45.32 62.8,45.21 64.12,45.21 64.32,45 64.32,44.06 64.52,43.86 v2(64.53,43.86) ; CPU1.AU46 110.87,61.32 110.67,61.12 v2(110.67,60.58)
M_A_A14: length 58.5
  TOP w0.152: v1(67.81,46.95) v2(67.36,46.61)
  L3 w0.089: v2(112.14,60.86) 112.31,60.86 112.5,61.05 112.5,61.3 112.31,61.48 109.42,61.48 107.63,59.7 101.91,59.7 101.65,59.44 101.42,59.44
  L3 w0.203: 101.42,59.44 100.8,59.44 98.63,57.26 92.25,57.26 84.42,49.44 77.19,49.44 76.43,48.68 76.14,48.68 75.78,49.04 75.5,49.04 75.21,48.75 75.21,48.47 75.57,48.11 75.57,47.67 75.39,47.5 75.39,46.92 75.19,46.72 74.82,46.72 74.6,46.94 74.12,46.94 73.9,46.72 69.03,46.72 68.81,46.95 67.7,46.95 v2(67.36,46.61)
  BOTTOM w0.152: DM1.151 68.85,47.07 68.63,47.3 67.67,47.3 67.36,46.98 v2(67.36,46.61) ; CPU1.AT46 111.85,61.15 v2(112.14,60.86)
M_A_A15: length 59.1
  TOP w0.152: v1(64.87,48.27) v2(64.55,47.8)
  L3 w0.089: 101.5,60.33 101.59,60.24 107.1,60.24 109.12,62.25 109.92,62.25 110.33,62.67 v2(110.89,62.67)
  L3 w0.203: v2(64.55,47.8) 64.55,47.82 64.9,48.17 64.91,48.17 65.04,48.3 65.05,48.3 65.27,48.52 69.61,48.52 69.8,48.32 69.9,48.32 69.9,48.32 72.48,48.32 72.48,48.32 72.55,48.32 75.37,51.14 79.22,51.14 79.52,51.43 83.89,51.43 91.33,58.87 98.69,58.87 100.15,60.33 101.5,60.33
  BOTTOM w0.152: v2(64.55,47.8) 64.82,47.53 64.82,47.1 64.38,46.65 64.38,45.73 64.13,45.49 62.98,45.49 62.64,45.82 61.7,45.82 DM1.156 ; v2(110.89,62.67) CPU1.AU48
M_A_A16: length 60.1
  TOP w0.152: v1(62.61,46.32) v2(63.17,46.33)
  L3 w0.089: 102.54,61.47 104.48,61.47 106.7,61.76 106.81,61.8 106.94,61.93 107.42,61.93 107.69,62.05 109.55,63.58 110.17,64.02 110.25,64.11 110.37,64.22 v2(110.79,64.39)
  L3 w0.203: 102.54,61.47 102.31,61.25 99.51,61.25 98.67,60.4 90.7,60.4 83.42,53.13 75.16,53.13 72.28,50.25 70.05,50.25 69.42,49.62 64.3,49.62 62.67,48 62.67,47.6 62.96,47.32 62.98,47.32 63.17,47.12 v2(63.17,46.33)
  BOTTOM w0.152: v2(63.17,46.33) 62.68,46.82 61.7,46.82 DM1.152 ; v2(110.79,64.39) 110.79,63.97 CPU1.AU50
M_A_ACT_N: length 57.2
  TOP w0.152: v1(64.16,59.07) v2(64.41,59.6)
  L3 w0.203: v2(64.41,59.6) 64.41,60.19 67.19,62.97 69.21,62.97 75.21,68.97 84.53,68.97 86.64,71.08 99.45,71.08 100.18,70.35 100.78,70.35 101.06,70.08 v2(101.06,69.26)
  BOTTOM w0.089: CPU1.BA55 108.78,66.35 108.68,66.35 108.49,66.4 108.32,66.4 108.19,66.36 106.44,66.36 105.72,67.09 105.72,67.16 104.7,68.18 101.26,68.18 101.06,68.38 v2(101.06,69.26)
  BOTTOM w0.152: DM1.114 62.98,58.32 63.05,58.4 64.21,58.4 64.41,58.6 v2(64.41,59.6)
M_A_ALERT_N: length 59.3
  TOP w0.152: v1(63.72,57.47) v2(63.34,57.94)
  L3 w0.203: v2(63.34,57.94) 64.11,57.17 64.11,56.89 64.67,56.33 65.92,56.33 65.93,56.32 66.55,56.32 67.87,57.64 69.28,57.64 70.13,58.49 70.84,58.49 76.01,63.66 76.65,63.66 77.04,64.05 84.71,64.05 88.14,67.48 99.32,67.48 99.86,66.94 110.27,66.94 v2(110.87,66.34)
  BOTTOM w0.089: v2(110.87,66.34) 110.88,66.33 110.88,65.07 110.36,64.54 110.36,64.22 110.04,63.9 CPU1.AW50
  BOTTOM w0.152: DM1.116 63.23,57.82 v2(63.34,57.94)
M_A_BA0: length 58.4
  TOP w0.152: v1(63.42,48.3) v2(63.81,47.8)
  L3 w0.089: 102.01,60.65 102.25,60.41 106.86,60.41 109.32,62.87 109.32,62.87 109.57,63.12 109.85,63.12 110.37,63.64 111.48,63.64 111.49,63.66 v2(111.51,63.66)
  L3 w0.203: 102.01,60.65 100.02,60.65 98.74,59.37 97.03,59.37 97.03,59.37 91.12,59.37 91.11,59.37 91.1,59.37 83.79,52.06 79.42,52.06 79.01,51.64 75.16,51.64 72.34,48.83 72.27,48.83 72.27,48.83 70.11,48.83 70.11,48.83 70.01,48.83 69.82,49.03 64.42,49.03 63.81,48.42 v2(63.81,47.8)
  BOTTOM w0.152: CPU1.AU52 111.5,63.68 111.5,63.66 v2(111.51,63.66) ; DM1.150 63.34,47.32 v2(63.81,47.8)
M_A_BA1: length 60.6
  TOP w0.152: v1(112.3,62.07) v2(112.18,62.63)
  L3 w0.089: 101.5,59.75 101.63,59.88 107.5,59.88 109.34,61.72 111.27,61.72 v2(112.18,62.63)
  L3 w0.203: 101.5,59.75 100.61,59.75 98.66,57.8 91.94,57.8 84.1,49.96 75.69,49.96 74.16,48.43 74.16,47.77 73.7,47.31 72.9,47.31 72.9,47.3 69.48,47.3 69.48,47.31 69.38,47.31 69.23,47.45 66.62,47.45 65.52,46.35 v2(65.52,46.3)
  BOTTOM w0.152: v2(65.52,46.3) 65.52,46.61 67.48,48.57 DM1.145 ; CPU1.AT48 v2(112.18,62.63)
M_A_BG0: length 58.4
  TOP w0.152: v1(65.53,60.01) v2(65.05,59.63)
  L3 w0.089: v2(102.33,69.24) 102.33,69.04 102.15,68.86 100.89,68.86 100.47,69.27 100.47,69.65
  L3 w0.203: 100.47,69.65 99.55,70.58 86.85,70.58 84.68,68.4 75.36,68.4 68.82,61.86 66.8,61.86 65.05,60.11 v2(65.05,59.63)
  BOTTOM w0.089: v2(102.33,69.24) 102.33,69.11 103.07,68.37 104.79,68.37 105.9,67.26 105.9,67.16 106.52,66.54 108.17,66.54 108.3,66.58 108.51,66.58 108.71,66.53 109.42,66.53 CPU1.AY55
  BOTTOM w0.152: v2(65.05,59.63) 65.05,59.32 65.9,58.47 68.24,58.47 68.63,58.07 DM1.115
M_A_BG1: length 59.3
  TOP w0.152: v2(66.5,60.57) 66.75,60.22 v1(66.75,60.03)
  L3 w0.089: v2(103.86,67.75) 104.36,67.25 105.09,67.25 105.29,67.45 105.29,68.07 105.11,68.25 104.35,68.25 104.21,68.39 100.85,68.39 99.88,69.36
  L3 w0.203: v2(66.5,60.57) 66.5,59.86 66.68,59.68 68.44,59.68 68.95,60.18 68.95,60.55 75.67,67.27 85.04,67.27 87.32,69.56 99.68,69.56 99.88,69.36
  BOTTOM w0.089: v2(103.86,67.75) 103.86,67.52 104.05,67.34 104.77,67.34 106.27,65.84 107.56,65.84 107.63,65.91 108.23,65.91 108.31,65.88 108.49,65.88 108.62,65.91 108.84,65.91 108.98,65.88 109.09,65.88 109.39,65.58 CPU1.AY54
  BOTTOM w0.152: v2(66.5,60.57) 66.5,58.94 66.7,58.75 68.56,58.75 68.73,58.57 DM1.113
M_A_CKE0: length 57.3
  TOP w0.152: v1(68.14,61.17) 67.91,60.94 v2(67.79,60.61)
  L3 w0.089: v2(104.28,69.24) 104.28,69.76 104.49,69.96 106.35,69.96 106.56,69.76 106.56,68.75 106.27,68.46 104.39,68.46 104.28,68.57 100.93,68.57 100.16,69.34 100.16,69.55
  L3 w0.203: v2(67.79,60.61) 67.79,61.15 67.99,61.35 69.03,61.35 75.46,67.78 84.78,67.78 87.07,70.07 99.64,70.07 100.16,69.55
  BOTTOM w0.089: v2(104.28,69.24) 104.3,69.24 104.33,69.26 104.6,69.26 106.25,67.61 106.25,67.31 106.62,66.94 107.49,66.94 107.61,67.06 108.21,67.06 CPU1.BA56
  BOTTOM w0.152: v2(67.79,60.61) 67.79,59.83 68.04,59.57 DM1.109
M_A_CKE1: length 57.2
  TOP w0.152: v1(62.55,59.65) v2(63.14,59.63)
  L3 w0.203: v2(63.14,59.63) 63.14,60.18 63.32,60.36 63.85,60.36 64.04,60.55 64.04,61.08 64.27,61.3 64.8,61.3 66.97,63.48 69,63.48 75.02,69.5 84.34,69.5 86.43,71.59 99.41,71.59 100.28,70.73 101.31,70.73 101.61,70.43 101.61,69.94 101.81,69.74 102.22,69.74 102.42,69.94 102.42,70.16 102.62,70.37 103.12,70.37 103.32,70.16 103.32,69.61 103.15,69.44 103.15,69.43 v2(102.96,69.24)
  BOTTOM w0.089: 105.97,67.56 106.07,67.45 106.07,67.24 106.58,66.73 107.72,66.73 CPU1.BB56
  BOTTOM w0.152: 105.97,67.56 104.72,68.8 103.91,68.8 103.71,68.6 103.17,68.6 102.96,68.81 v2(102.96,69.24) ; DM1.110 62.84,59.32 v2(63.14,59.63)
M_A_CLK0: length 59.4
  TOP w0.102: v1(67.3,49.74) v2(67.63,50.23)
  L3 w0.089: 109.16,64.45 109.22,64.39 109.95,64.39 110.53,64.97 111.19,64.97 111.26,64.9 111.55,64.9 111.74,64.83 112.11,64.52 112.11,64.51 v2(112.11,64.51)
  L3 w0.14: v2(67.63,50.23) 67.63,50.65 68.05,51.07 71.89,51.07 74.77,53.95 83.09,53.95 90.37,61.23 98.49,61.23 99.68,62.42 101.63,62.42 101.98,62.07 102.67,62.07 103.01,62.42 103.9,62.42 104.21,62.11 105,62.11 106,63.11 106.42,63.11 107.05,62.49 107.28,62.49 107.44,62.65 107.44,62.88 106.82,63.51 106.82,63.92 107.74,64.85 108.52,64.85 108.92,64.45 109.16,64.45
  BOTTOM w0.102: CPU1.AT53 112.11,64.55 112.11,64.51 v2(112.11,64.51) ; DM1.137 68.88,52.57 68.74,52.44 68.26,52.44 67.63,51.81 v2(67.63,50.23)
M_A_CLK1: length 59.5
  TOP w0.102: v1(65.78,49.69) v2(65.47,50.19)
  L3 w0.089: 109.87,65.29 109.91,65.33 110.25,65.33 110.42,65.16 111.25,65.16 111.34,65.08 111.78,65.08 v2(112.14,65.44)
  L3 w0.14: v2(65.47,50.19) 65.94,50.65 66.89,50.65 67.83,51.59 70.87,51.59 71.69,52.41 72.5,52.41 74.58,54.49 82.88,54.49 90.15,61.76 98.63,61.76 99.65,62.77 105.03,62.77 107.55,65.29 109.87,65.29
  BOTTOM w0.102: v2(65.47,50.19) 65.47,51.02 64.3,52.19 62.86,52.19 62.72,52.32 DM1.138 ; CPU1.AT55 v2(112.14,65.44)
M_A_CLK#0: length 59.5
  TOP w0.102: v1(68.88,50.71) v2(68.53,50.21)
  L3 w0.089: 109.15,64.18 109.17,64.18 109.2,64.22 110.02,64.22 110.6,64.79 111.09,64.79 111.27,64.62 111.39,64.5 v2(111.48,64.5)
  L3 w0.14: v2(68.53,50.21) 68.51,50.19 68.31,50.19 68,50.49 68,50.65 68.16,50.81 72,50.81 74.88,53.68 83.2,53.68 90.48,60.96 98.6,60.96 99.79,62.15 101.52,62.15 101.87,61.8 102.78,61.8 103.12,62.15 103.79,62.15 104.1,61.85 105.12,61.85 106.11,62.84 106.31,62.84 106.86,62.3 106.93,62.22 107.39,62.22 107.71,62.54 107.71,62.99 107.08,63.62 107.08,63.81 107.85,64.58 108.41,64.58 108.81,64.18 109.15,64.18
  BOTTOM w0.102: v2(111.48,64.5) 111.2,64.77 CPU1.AU53 ; DM1.139 68.88,52.07 68.74,52.21 68.35,52.21 67.86,51.72 67.86,50.88 68.06,50.68 68.81,50.68 68.94,50.55 68.94,50.33 68.81,50.21 v2(68.53,50.21)
M_A_CLK#1: length 59.5
  TOP w0.102: v1(64.36,49.77) v2(64.76,50.19)
  L3 w0.089: 109.87,65.56 109.92,65.51 110.32,65.51 110.49,65.34 111.04,65.34 111.18,65.48 v2(111.5,65.48)
  L3 w0.14: 109.87,65.56 107.44,65.56 104.92,63.04 99.54,63.04 98.52,62.03 90.04,62.03 82.77,54.76 74.47,54.76 72.39,52.68 71.58,52.68 70.76,51.86 67.72,51.86 66.92,51.06 66.78,50.92 65.26,50.92 64.76,50.41 v2(64.76,50.19)
  BOTTOM w0.102: CPU1.AU55 v2(111.5,65.48) ; v2(64.76,50.19) 65.24,50.67 65.24,50.93 64.21,51.96 62.86,51.96 62.72,51.82 DM1.140
M_A_CS#0: length 61.5
  TOP w0.152: v1(66.36,46.82) v2(66.79,46.33)
  L3 w0.089: v2(111.48,60.86) 111.16,61.18 109.44,61.18 109.23,60.98 109.23,60.64 109.03,60.44 108.73,60.44 108.5,60.21 108.5,60.08 108.63,59.96 108.63,59.83 108.48,59.68 108.35,59.68 108.22,59.8 108.1,59.8 107.82,59.53 102.09,59.53 101.7,59.14
  L3 w0.203: v2(66.79,46.33) 66.79,46.06 66.98,45.87 68.68,45.87 69.03,46.21 69.54,46.21 69.84,45.91 70.35,45.91 70.65,46.21 71.16,46.21 71.46,45.91 71.98,45.91 72.28,46.21 72.79,46.21 73.09,45.91 73.6,45.91 73.9,46.21 74.42,46.21 74.72,45.91 76.77,45.91 76.98,46.11 76.98,46.53 76.77,46.73 76.16,46.73 75.96,46.93 75.96,47.34 76.16,47.54 77.16,47.54 77.28,47.67 77.28,48.81 77.41,48.93 84.71,48.93 92.48,56.7 98.49,56.7 100.93,59.14 101.7,59.14
  BOTTOM w0.152: CPU1.AU45 111.48,60.68 v2(111.48,60.86) ; v2(66.79,46.33) 66.79,46.81 67.55,47.57 DM1.149
M_A_CS#1: length 64
  TOP w0.152: v1(66.29,43.39) v2(65.83,43.87)
  L3 w0.089: 101.04,57.97 101.32,58.25 110.46,58.25 110.95,58.75 111.16,58.75 111.4,58.99 111.4,59.47 v2(110.89,59.97)
  L3 w0.203: v2(65.83,43.87) 66.3,44.34 75.26,44.34 75.77,43.83 76.87,43.83 79.69,46.66 80.58,46.66 80.78,46.86 80.78,47.1 80.98,47.3 81.39,47.3 81.59,47.1 81.59,46.86 81.8,46.66 82.2,46.66 82.41,46.86 82.41,47.1 82.61,47.3 83.02,47.3 83.22,47.1 83.22,46.86 83.42,46.66 84.78,46.66 93.29,55.17 98.24,55.17 101.04,57.97
  BOTTOM w0.152: DM1.157 68.85,45.57 68.45,45.17 64.8,45.17 64.6,44.98 64.6,44.54 64.8,44.34 65.63,44.34 65.83,44.14 v2(65.83,43.87) ; CPU1.AU43 v2(110.89,59.97)
M_A_DIMA_ODT0: length 63.3
  TOP w0.152: v1(64.59,46.8) v2(64.88,46.3)
  L3 w0.089: 101.86,58.84 102.04,58.65 107.7,58.65 110.05,61 110.81,61 111.07,60.75 111.07,60.73 111.08,60.72 111.08,60.7 111.53,60.25 v2(111.53,60)
  L3 w0.203: 101.86,58.84 101.04,58.84 98.4,56.19 92.81,56.19 84.97,48.35 78.34,48.35 77.85,47.86 77.85,46.25 76.96,45.36 64.54,45.36 64.32,45.59 64.32,46.1 64.52,46.3 v2(64.88,46.3)
  BOTTOM w0.152: DM1.155 68.91,46.07 68.34,45.5 65.67,45.5 65.06,46.11 65.06,46.12 v2(64.88,46.3) ; CPU1.AT45 v2(111.53,60)
M_A_DIMA_ODT1: length 63.4
  TOP w0.152: v1(67.81,43.45) v2(67.4,43.86)
  L3 w0.203: v2(67.4,43.86) 67.51,43.75 69.25,43.75 69.45,43.55 69.45,43.5 69.66,43.3 70.06,43.3 70.27,43.5 70.27,43.55 70.47,43.75 71.87,43.75 72.08,43.55 72.08,43.47 72.28,43.27 72.68,43.27 72.89,43.47 72.89,43.55 73.09,43.75 73.5,43.75 73.7,43.55 73.7,43.47 73.9,43.27 74.31,43.27 74.51,43.47 74.51,43.55 74.72,43.75 75.12,43.75 75.33,43.55 75.33,43.47 75.53,43.27 77.02,43.27 79.9,46.15 85.25,46.15 93.76,54.66 98.23,54.66 101.56,57.99 107.85,57.99 108.05,57.79 108.05,55.83 108.26,55.62 109.68,55.62 109.88,55.83 109.88,56.6 109.64,56.84 109.64,57.12 109.93,57.41 110.22,57.41 110.46,57.17 110.75,57.17 111.44,57.87 111.44,58.67 111.76,58.98 v2(112.19,58.98)
  BOTTOM w0.152: CPU1.AT43 v2(112.19,58.98) ; DM1.161 68.94,44.57 68.67,44.31 68.67,43.74 68.51,43.57 68.27,43.57 68.1,43.74 68.1,44.2 67.9,44.4 67.57,44.4 67.4,44.23 v2(67.4,43.86)
M_A_DQ0: length 67.8
  TOP w0.089: v1(64.54,86.47) v2(64.79,85.95)
  L3 w0.127: v2(64.79,85.95) 65.23,85.5 67.98,85.5 68.6,86.12 68.87,86.12 69.14,86.38 69.84,86.38 70.11,86.12 73.51,86.12 73.64,86.24 73.64,86.51 73.76,86.64 74.02,86.64 74.14,86.51 74.14,86.24 74.27,86.12 74.52,86.12 74.65,86.24 74.65,86.51 74.78,86.64 78.62,86.64 80.77,88.79 109.58,88.79 115.17,83.19 115.17,78.83 v2(114.5,78.16)
  BOTTOM w0.089: v2(64.79,85.95) 63.67,84.82 DM1.8 ; v2(114.5,78.16) 115.13,77.53 115.13,75.74 CPU1.AL71
M_A_DQ1: length 68.8
  TOP w0.089: v1(66.44,86.47) v2(66.21,85.95)
  L3 w0.127: v2(114.55,76.24) 115.26,76.95 115.89,78.53 115.89,83.49 109.87,89.5 80.27,89.5 78.57,87.8 74.04,87.8 73.82,87.58 69.09,87.58 68.51,87 67.26,87 v2(66.21,85.95)
  BOTTOM w0.089: DM1.7 67.08,85.07 v2(66.21,85.95) ; v2(114.55,76.24) 114.55,75.82 114.47,75.74 114.47,75.37 114.51,75.29 114.51,75.09 114.47,74.98 114.47,74.75 114.53,74.56 114.53,74.22 114.91,73.71 CPU1.AL68
M_A_DQ2: length 69.4
  TOP w0.089: v1(63.7,81.77) v2(64.05,81.32)
  L3 w0.127: v2(113.58,72.9) 113.58,74.97 112.71,75.84 112.33,76.4 112.33,77.12 112.95,77.73 113.22,77.73 113.73,78.24 113.73,80.03 112.03,81.73 112.03,83.64 108.62,87.05 92.61,87.05 92.48,86.92 92.48,86.57 92.36,86.45 92,86.45 91.87,86.57 91.87,86.92 91.75,87.05 91.49,87.05 91.37,86.92 91.37,86.57 91.24,86.45 80.91,86.45 78.73,84.26 69.72,84.26 68.22,82.76 65.49,82.76 v2(64.05,81.32)
  BOTTOM w0.089: v2(113.58,72.9) 113.58,73.46 CPU1.AN68 ; DM1.20 63.55,81.82 v2(64.05,81.32)
M_A_DQ3: length 68.7
  TOP w0.089: v1(67.81,81.9) v2(68.24,81.48)
  L3 w0.127: v2(68.24,81.48) 70.23,83.48 78.95,83.48 81.21,85.73 98.22,85.73 98.34,85.86 98.34,86.21 98.47,86.34 98.72,86.34 98.85,86.21 98.85,85.86 98.98,85.73 99.23,85.73 99.36,85.86 99.36,86.21 99.49,86.34 99.74,86.34 99.87,86.21 99.87,85.86 99.99,85.73 100.25,85.73 100.38,85.86 100.38,86.21 100.5,86.34 100.76,86.34 100.88,86.21 100.88,85.86 101.01,85.73 101.26,85.73 101.39,85.86 101.39,86.21 101.52,86.34 101.87,86.34 102,86.21 102,85.54 102.13,85.41 102.38,85.41 102.51,85.54 102.51,86.21 102.64,86.34 102.89,86.34 103.02,86.21 103.02,85.54 103.14,85.41 103.4,85.41 103.52,85.54 103.52,86.21 103.65,86.34 108.32,86.34 110.51,84.15 110.51,83.97 109.99,83.45 109.99,83.27 110.17,83.09 110.35,83.09 110.87,83.61 111.05,83.61 111.3,83.36 111.3,82.24 111.18,82.11 110.29,82.11 110.16,81.98 110.16,81.73 110.29,81.6 111.18,81.6 111.3,81.47 111.3,81.12 112.93,79.5 v2(112.93,79.17)
  BOTTOM w0.089: DM1.21 69.9,81.57 68.33,81.57 v2(68.24,81.48) ; CPU1.AN69 113.42,74.56 113.11,74.98 113.11,75.78 113.15,75.82 113.15,76.41 113.15,76.41 113.15,76.74 112.97,76.92 112.96,76.92 112.67,77.21 112.67,78.34 112.93,78.6 v2(112.93,79.17)
M_A_DQ4: length 68.5
  L3 w0.127: v2(63.37,85.95) 64.17,85.15 68.2,85.15 68.82,85.76 75.04,85.76 75.16,85.89 75.16,86.16 75.29,86.29 75.54,86.29 75.67,86.16 75.67,85.89 75.8,85.76 76.05,85.76 76.18,85.89 76.18,86.16 76.31,86.29 76.56,86.29 76.69,86.16 76.69,85.89 76.81,85.76 77.07,85.76 77.2,85.89 77.2,86.16 77.32,86.29 77.58,86.29 77.7,86.16 77.7,85.89 77.83,85.76 78.25,85.76 80.92,88.43 109.43,88.43 114.73,83.13 v2(114.73,79.46)
  BOTTOM w0.089: CPU1.AL70 115.31,75.27 115.31,78.88 v2(114.73,79.46) 114.73,80.02 v1(114.75,80.04) ; DM1.4 63.25,85.82 v2(63.37,85.95)
M_A_DQ5: length 68.9
  TOP w0.089: v1(67.91,86.45) v2(67.63,85.95)
  L3 w0.127: v2(114.57,76.88) 115.03,77.34 115.03,78.19 115.53,78.68 115.53,83.34 109.72,89.14 80.62,89.14 78.92,87.44 77.58,87.44 77.46,87.32 77.46,87.12 77.33,87 77.08,87 76.95,87.12 76.95,87.32 76.82,87.44 76.57,87.44 76.44,87.32 76.44,87.12 76.31,87 76.06,87 75.93,87.12 75.93,87.32 75.81,87.44 75.55,87.44 75.43,87.32 75.43,87.12 75.3,87 74.94,87 74.82,87.12 74.82,87.32 74.69,87.44 74.43,87.44 74.31,87.32 74.31,87.12 74.18,87 73.19,87 73.07,86.87 73.07,86.6 72.94,86.47 72.68,86.47 72.56,86.6 72.56,86.87 72.43,87 72.18,87 72.05,86.87 72.05,86.6 71.92,86.47 71.67,86.47 71.54,86.6 71.54,86.87 71.41,87 71.16,87 71.03,86.87 71.03,86.6 70.91,86.47 70.65,86.47 70.53,86.6 70.53,86.87 70.4,87 69.17,87 68.79,86.62 67.85,86.62 67.63,86.4 v2(67.63,85.95)
  BOTTOM w0.089: CPU1.AL69 114.7,74.42 114.7,74.59 114.65,74.78 114.65,74.96 114.68,75.06 114.68,75.34 114.65,75.41 114.65,75.67 114.96,75.97 114.96,76.48 114.57,76.87 v2(114.57,76.88) ; DM1.3 67.76,86.07 v2(67.63,85.95)
M_A_DQ6: length 67.3
  TOP w0.089: v1(64.31,84.24) v2(64.05,83.74)
  L3 w0.127: v2(113.12,77.32) 114.08,78.27 114.08,80.18 112.38,81.88 112.38,83.49 112.38,83.79 108.76,87.4 90.96,87.4 90.83,87.27 90.83,86.93 90.7,86.8 90.45,86.8 90.32,86.93 90.32,87.27 90.19,87.4 89.94,87.4 89.81,87.27 89.81,86.93 89.68,86.8 89.43,86.8 89.3,86.93 89.3,87.27 89.18,87.4 88.92,87.4 88.8,87.27 88.8,86.93 88.67,86.8 80.76,86.8 78.58,84.62 69.32,84.62 67.98,83.27 64.52,83.27 v2(64.05,83.74)
  BOTTOM w0.089: v2(64.05,83.74) 63.13,82.82 DM1.16 ; v2(113.12,77.32) 113.12,77.26 113.34,77.04 113.34,75.75 113.28,75.7 113.28,75.16 CPU1.AN70
M_A_DQ7: length 66.6
  TOP w0.089: v1(66.29,81.88) v2(66.13,81.33)
  L3 w0.127: v2(113.08,78.19) 113.08,78.62 113.37,78.92 113.37,79.88 111.67,81.59 111.67,83.5 108.47,86.69 98.05,86.69 97.45,86.09 96.75,86.09 96.62,86.22 96.62,86.57 96.5,86.69 96.24,86.69 96.12,86.57 96.12,86.22 95.99,86.09 95.73,86.09 95.61,86.22 95.61,86.57 95.48,86.69 95.23,86.69 95.1,86.57 95.1,86.22 94.97,86.09 94.62,86.09 94.49,86.22 94.49,86.57 94.36,86.69 94.11,86.69 93.98,86.57 93.98,86.22 93.85,86.09 93.6,86.09 93.47,86.22 93.47,86.57 93.35,86.69 93.09,86.69 92.97,86.57 92.97,86.22 92.84,86.09 81.06,86.09 78.8,83.83 69.84,83.83 68.42,82.41 67.21,82.41 v2(66.13,81.33)
  BOTTOM w0.089: CPU1.AN71 113.54,75.56 113.54,77.73 v2(113.08,78.19) ; DM1.17 69.9,82.57 67.38,82.57 v2(66.13,81.33)
M_A_DQ8: length 61.6
  TOP w0.089: v1(66.14,79.44) v2(66.43,78.94)
  L3 w0.127: v2(66.43,78.94) 67.69,80.2 69.13,80.2 70.72,81.78 79.3,81.78 81.42,83.9 89.56,83.9 89.68,84.03 89.68,84.21 89.81,84.34 90.07,84.34 90.19,84.21 90.19,84.03 90.32,83.9 90.57,83.9 90.7,84.03 90.7,84.21 90.83,84.34 91.08,84.34 91.21,84.21 91.21,84.03 91.34,83.9 91.59,83.9 91.72,84.03 91.72,84.21 91.84,84.34 100.67,84.34 105.44,79.56 110.49,79.56 v2(110.92,79.13)
  BOTTOM w0.089: v2(66.43,78.94) 65.55,79.82 DM1.28 ; v2(110.92,79.13) 111.18,79.39 111.83,79.39 112.12,79.1 112.12,78.69 112.11,78.68 112.11,78.29 112.17,78.23 112.17,76.28 112.19,76.27 112.26,76.13 112.27,76.11 112.29,76.06 112.29,75.43 112.35,75.24 112.35,75.07 CPU1.AR70
M_A_DQ9: length 61.7
  TOP w0.089: v1(67.99,79.46) v2(67.75,78.94)
  L3 w0.127: v2(113.05,73.84) 113.05,73.9 112.01,74.95 112.01,77.96 111.29,78.69 110.65,78.69 110.12,79.21 105.29,79.21 100.95,83.54 100.13,83.54 100,83.67 100,83.85 99.87,83.98 99.62,83.98 99.49,83.85 99.49,83.67 99.36,83.54 99.11,83.54 98.98,83.67 98.98,83.85 98.86,83.98 98.6,83.98 98.47,83.85 98.47,83.67 98.35,83.54 98.09,83.54 97.97,83.67 97.97,83.85 97.84,83.98 97.59,83.98 97.46,83.85 97.46,83.67 97.33,83.54 97.08,83.54 96.95,83.67 96.95,83.85 96.82,83.98 96.57,83.98 96.44,83.85 96.44,83.67 96.32,83.54 96.06,83.54 95.93,83.67 95.93,83.85 95.81,83.98 95.55,83.98 95.43,83.85 95.43,83.67 95.3,83.54 94.94,83.54 94.82,83.67 94.82,83.85 94.69,83.98 94.44,83.98 94.31,83.85 94.31,83.67 94.18,83.54 93.93,83.54 93.8,83.67 93.8,83.85 93.67,83.98 93.42,83.98 93.29,83.85 93.29,83.67 93.17,83.54 92.91,83.54 92.78,83.67 92.78,83.85 92.66,83.98 92.4,83.98 92.28,83.85 92.28,83.67 92.15,83.54 81.57,83.54 79.45,81.42 70.86,81.42 69.28,79.84 68.02,79.84 67.75,79.57 v2(67.75,78.94)
  BOTTOM w0.089: v2(67.75,78.94) 68.39,79.57 69.9,79.57 DM1.29 ; CPU1.AR68 v2(113.05,73.84)
M_A_DQ10: length 59.3
  TOP w0.089: v2(110.38,77.24) 110.38,77.91 v1(110.36,77.93)
  L3 w0.127: v2(67.51,77.39) 67.95,76.94 68.54,76.94 70.75,79.15 71.95,79.15 72.08,79.28 72.08,79.41 72.21,79.54 72.46,79.54 72.59,79.41 72.59,79.28 72.72,79.15 72.97,79.15 73.1,79.28 73.1,79.41 73.22,79.54 73.48,79.54 73.6,79.41 73.6,79.28 73.73,79.15 74.09,79.15 74.21,79.28 74.21,79.41 74.34,79.54 74.6,79.54 74.72,79.41 74.72,79.28 74.85,79.15 75.1,79.15 75.23,79.28 75.23,79.41 75.36,79.54 75.61,79.54 75.74,79.41 75.74,79.28 75.87,79.15 76.22,79.15 76.35,79.28 76.35,79.41 76.48,79.54 76.73,79.54 76.86,79.41 76.86,79.28 76.98,79.15 77.24,79.15 77.36,79.28 77.36,79.41 77.49,79.54 77.75,79.54 77.87,79.41 77.87,79.28 78,79.15 78.25,79.15 78.38,79.28 78.38,79.41 78.51,79.54 78.76,79.54 78.89,79.41 78.89,79.28 79.02,79.15 79.76,79.15 80.1,79.49 80.1,79.67 79.99,79.77 79.99,79.95 80.17,80.13 80.35,80.13 80.46,80.03 80.64,80.03 80.81,80.21 80.81,80.39 80.71,80.49 80.71,80.67 80.89,80.85 81.07,80.85 81.17,80.75 81.35,80.75 81.53,80.93 81.53,81.11 81.43,81.21 81.43,81.39 81.61,81.57 81.79,81.57 81.89,81.46 82.07,81.46 82.77,82.16 100.38,82.16 102.6,79.94 102.6,78.65 103.32,77.92 108.61,77.92 108.92,77.6 108.92,77.09 109.16,76.85 109.98,76.85 110.37,77.24 v2(110.38,77.24)
  BOTTOM w0.089: v2(110.38,77.24) 110.49,77.13 110.58,77.13 110.79,76.92 110.79,76.14 111.23,75.7 CPU1.AU71 ; v2(67.51,77.39) 67.69,77.21 67.69,76.75 67.86,76.57 69.9,76.57 DM1.41
M_A_DQ11: length 61.6
  TOP w0.089: v1(108.61,76.29) 108.4,76.5 v2(108.4,76.95)
  L3 w0.127: v2(64.66,77.39) 65.46,76.59 68.69,76.59 70.9,78.8 79.91,78.8 82.92,81.8 100.23,81.8 102.12,79.92 102.12,78.27 102.93,77.46 103.55,77.46 103.68,77.33 103.68,76.72 103.81,76.6 104.06,76.6 104.19,76.72 104.19,77.33 104.32,77.46 107.49,77.46 107.88,77.07 108.28,77.07 v2(108.4,76.95)
  BOTTOM w0.089: DM1.42 64.37,76.32 64.66,76.61 v2(64.66,77.39) ; CPU1.AU68 111.25,73.39 110.81,72.94 110.57,72.94 110.39,73.13 110.39,73.36 110.21,73.54 110.21,75.56 109.92,75.85 109.3,75.85 108.42,76.72 108.42,76.93 v2(108.4,76.95)
M_A_DQ12: length 59.9
  TOP w0.089: v1(65.04,81.83) v2(64.74,81.32)
  L3 w0.127: v2(64.74,81.32) 65.51,80.55 68.99,80.55 70.57,82.13 79.16,82.13 81.28,84.26 89.15,84.26 89.59,84.69 100.81,84.69 105.46,80.04 v2(110.83,80.04)
  BOTTOM w0.089: CPU1.AR71 112.55,76.15 112.35,76.35 112.35,76.82 112.43,76.9 112.43,78.55 112.43,78.56 112.43,79.45 111.64,80.24 111.02,80.24 v2(110.83,80.04) ; v2(64.74,81.32) 64.24,80.82 DM1.24
M_A_DQ13: length 61.5
  TOP w0.089: v1(67,80.78) v2(66.79,81.33)
  L3 w0.127: v2(66.79,81.33) 67.21,80.91 68.84,80.91 70.42,82.49 79.01,82.49 81.13,84.61 86.45,84.61 86.58,84.74 86.58,84.92 86.7,85.05 86.96,85.05 87.08,84.92 87.08,84.74 87.21,84.61 87.47,84.61 87.59,84.74 87.59,84.92 87.72,85.05 87.97,85.05 88.1,84.92 88.1,84.74 88.23,84.61 88.48,84.61 88.61,84.74 88.61,84.92 88.74,85.05 100.96,85.05 105.5,80.51 111.41,80.51 112.04,79.88 112.04,79.34 v2(111.66,78.96)
  BOTTOM w0.089: CPU1.AR69 112.39,74.58 112.17,74.87 112.17,75.21 112.12,75.4 112.11,76.03 111.99,76.21 111.99,77.84 111.68,78.16 111.68,78.94 v2(111.66,78.96) ; DM1.25 69.9,80.57 67.71,80.57 67.34,80.21 66.92,80.21 66.79,80.34 66.79,80.83 66.79,80.83 v2(66.79,81.33)
M_A_DQ14: length 59.5
  TOP w0.089: v1(110.89,76.81) 110.67,76.81 v2(110.39,76.54)
  L3 w0.127: v2(110.39,76.54) 110.39,75.69 109.71,75.01 104.4,75.01 101.63,77.78 101.63,79.9 100.08,81.45 83.06,81.45 79.75,78.14 71.72,78.14 71.45,77.88 70.48,77.88 68.82,76.21 63.61,76.21 63.24,76.58 v2(63.24,77.39)
  BOTTOM w0.089: CPU1.AU70 110.94,75.4 110.94,75.74 110.73,75.95 110.56,76.09 110.39,76.26 v2(110.39,76.54) ; DM1.38 62.8,77.32 62.86,77.39 v2(63.24,77.39)
M_A_DQ15: length 60.5
  TOP w0.089: v1(109.11,77.56) 109.14,77.56 109.52,77.93 v2(109.52,77.98)
  L3 w0.127: v2(109.52,77.98) 109.37,78.13 104.9,78.13 100.52,82.52 82.05,82.52 79.43,79.89 79.07,79.89 78.94,80.02 78.94,80.25 78.82,80.38 78.56,80.38 78.44,80.25 78.44,80.02 78.31,79.89 78.06,79.89 77.93,80.02 77.93,80.25 77.8,80.38 77.55,80.38 77.42,80.25 77.42,80.02 77.29,79.89 77.04,79.89 76.91,80.02 76.91,80.25 76.79,80.38 76.53,80.38 76.4,80.25 76.4,80.02 76.28,79.89 75.92,79.89 75.79,80.02 75.79,80.25 75.67,80.38 75.41,80.38 75.29,80.25 75.29,80.02 75.16,79.89 74.91,79.89 74.78,80.02 74.78,80.25 74.65,80.38 74.4,80.38 74.27,80.25 74.27,80.02 74.14,79.89 73.52,79.89 73.11,80.31 72.24,80.31 71.82,79.89 70.9,79.89 68.85,77.84 66.54,77.84 v2(66.08,77.39)
  BOTTOM w0.089: v2(66.08,77.39) 66.51,77.81 68.39,77.81 68.63,77.57 69.9,77.57 DM1.37 ; CPU1.AU69 110.89,74.77 110.77,75.19 110.76,75.67 110.61,75.82 110.23,76.13 109.99,76.37 109.99,76.4 109.3,77.09 109.3,77.77 v2(109.52,77.98)
M_A_DQ16: length 54.2
  TOP w0.089: v1(98.55,79.31) v2(98.88,79.81)
  L3 w0.127: v2(64.56,75.33) 65.36,74.53 69.58,74.53 71.19,76.14 80.33,76.14 83.4,79.2 83.41,79.2 83.46,79.25 97.03,79.25 97.15,79.37 98.43,79.37 v2(98.88,79.81)
  BOTTOM w0.089: v2(98.88,79.81) 99.34,79.35 101.25,79.35 101.64,78.96 101.64,78.34 104.15,75.82 104.15,75.63 105.94,73.84 105.94,73 107.1,71.84 107.77,71.84 CPU1.BB65 ; DM1.50 63.36,74.32 v2(64.56,75.33)
M_A_DQ17: length 56.7
  TOP w0.089: v1(97.07,80.33) v2(97.52,79.84)
  L3 w0.127: v2(97.52,79.84) 97.11,79.84 96.88,79.61 83.31,79.61 83.26,79.55 83.25,79.55 80.19,76.49 71.04,76.49 69.43,74.88 66.43,74.88 v2(65.98,75.33)
  BOTTOM w0.089: v2(97.52,79.84) 98.29,80.61 101.38,80.61 104.58,77.41 104.58,77.39 104.84,76.7 105.11,76.02 106.63,74.5 106.63,73.16 106.9,72.88 107.28,72.88 107.43,73.04 107.71,73.04 108.07,72.68 108.49,72.68 108.65,72.64 108.74,72.47 108.74,72.4 108.77,72.3 108.88,72.19 109,72.15 109.14,72.11 109.31,72.11 CPU1.AW65 ; DM1.49 68.61,74.57 68.37,74.33 66.98,74.33 v2(65.98,75.33)
M_A_DQ18: length 57
  TOP w0.089: v1(98.75,76.77) v2(98.51,76.25)
  L3 w0.127: v2(65.27,70.65) 66.05,71.44 68.95,71.44 71.91,74.4 81.07,74.4 84.18,77.51 94.35,77.51 94.76,77.1 97.66,77.1 v2(98.51,76.25)
  BOTTOM w0.089: v2(65.27,70.65) 65.44,70.82 65.44,71.44 65.25,71.63 63.11,71.63 62.8,71.32 DM1.62 ; CPU1.AW63 109.55,70.83 108.33,70.83 108.32,70.84 108.19,70.87 107.85,70.87 107.64,70.66 107.27,70.66 106.5,71.44 106.5,71.61 105.28,72.83 105.28,73.31 101.58,77.01 99.31,77.01 98.55,76.25 v2(98.51,76.25)
M_A_DQ19: length 55.8
  TOP w0.089: v1(98.09,75.73) v2(97.86,76.26)
  L3 w0.127: v2(68.12,70.65) 68.67,70.65 72.05,74.04 81.47,74.04 83.86,76.44 88.04,76.44 88.17,76.56 88.17,77.03 88.3,77.16 88.55,77.16 88.68,77.03 88.68,76.56 88.8,76.44 89.06,76.44 89.19,76.56 89.19,77.03 89.31,77.16 89.57,77.16 89.69,77.03 89.69,76.56 89.82,76.44 90.07,76.44 90.2,76.56 90.2,77.03 90.33,77.16 90.58,77.16 90.71,77.03 90.71,76.56 90.84,76.44 91.09,76.44 91.22,76.56 91.22,77.03 91.34,77.16 91.6,77.16 91.73,77.03 91.73,76.56 91.85,76.44 92.11,76.44 92.23,76.56 92.23,77.03 92.36,77.16 92.61,77.16 92.74,77.03 92.74,76.56 92.87,76.44 93.12,76.44 93.25,76.56 93.25,76.99 93.38,77.11 93.63,77.11 93.76,76.99 93.76,76.73 93.93,76.56 94.37,76.56 94.55,76.74 97.38,76.74 97.64,76.48 97.64,76.47 v2(97.86,76.26)
  BOTTOM w0.089: v2(97.86,76.26) 97.86,76.26 98.65,75.46 101.5,75.46 103.91,73.05 104.22,73.05 105.89,71.38 105.89,71.25 107.01,70.13 108.84,70.13 CPU1.AY63 ; v2(68.12,70.65) 68.54,71.07 DM1.63
M_A_DQ20: length 54.6
  TOP w0.089: v1(101.34,80.35) v2(101.04,79.86)
  L3 w0.127: v2(101.04,79.86) 100.58,80.32 99.83,80.32 99.42,80.73 83.42,80.73 79.89,77.2 70.74,77.2 69.4,75.86 63.67,75.86 v2(63.14,75.33)
  BOTTOM w0.089: DM1.46 63.13,75.32 v2(63.14,75.33) ; CPU1.BA65 108.22,72 108.17,72.02 107.97,72.02 107.96,72.01 107.18,72.01 106.12,73.07 106.12,74.11 104.47,75.76 104.47,75.96 102.05,78.37 102.05,79 101.19,79.86 v2(101.04,79.86)
M_A_DQ21: length 55.6
  TOP w0.089: v1(99.84,80.3) v2(99.6,79.78)
  L3 w0.127: v2(68.12,75.33) 68.24,75.45 69.49,75.45 70.89,76.85 80.04,76.85 83.1,79.91 83.11,79.91 83.17,79.96 87.26,79.96 87.39,80.09 87.39,80.25 87.52,80.38 87.77,80.38 87.9,80.25 87.9,80.09 88.02,79.96 88.28,79.96 88.41,80.09 88.41,80.25 88.53,80.38 88.79,80.38 88.91,80.25 88.91,80.09 89.04,79.96 89.4,79.96 89.52,80.09 89.52,80.25 89.65,80.38 89.9,80.38 90.03,80.25 90.03,80.09 90.16,79.96 90.41,79.96 90.54,80.09 90.54,80.25 90.67,80.38 90.92,80.38 91.05,80.25 91.05,80.09 91.17,79.96 91.43,79.96 91.56,80.09 91.56,80.25 91.68,80.38 91.94,80.38 92.06,80.25 92.06,80.09 92.19,79.96 92.55,79.96 92.67,80.09 92.67,80.25 92.8,80.38 93.05,80.38 93.18,80.25 93.18,80.09 93.31,79.96 93.56,79.96 93.69,80.09 93.69,80.25 93.82,80.38 94.07,80.38 94.2,80.25 94.2,80.09 94.32,79.96 94.58,79.96 94.7,80.09 94.7,80.25 94.83,80.38 95.09,80.38 95.21,80.25 95.21,80.09 95.34,79.96 95.59,79.96 95.72,80.09 95.72,80.25 95.85,80.38 96.1,80.38 96.23,80.25 96.23,80.09 96.36,79.96 96.71,79.96 97.03,80.28 99.1,80.28 v2(99.6,79.78)
  BOTTOM w0.089: CPU1.AY65 109,71.97 108.62,72.07 108.5,72.12 108.27,72.18 108.19,72.2 107.8,72.2 107.8,72.19 107.34,72.19 106.4,73.14 106.4,74.29 105.33,75.36 105.32,75.36 104.79,75.89 104.79,76.09 103.32,77.56 103.32,78.18 101.22,80.29 100.11,80.29 v2(99.6,79.78) ; v2(68.12,75.33) 68.36,75.57 69.9,75.57 DM1.45
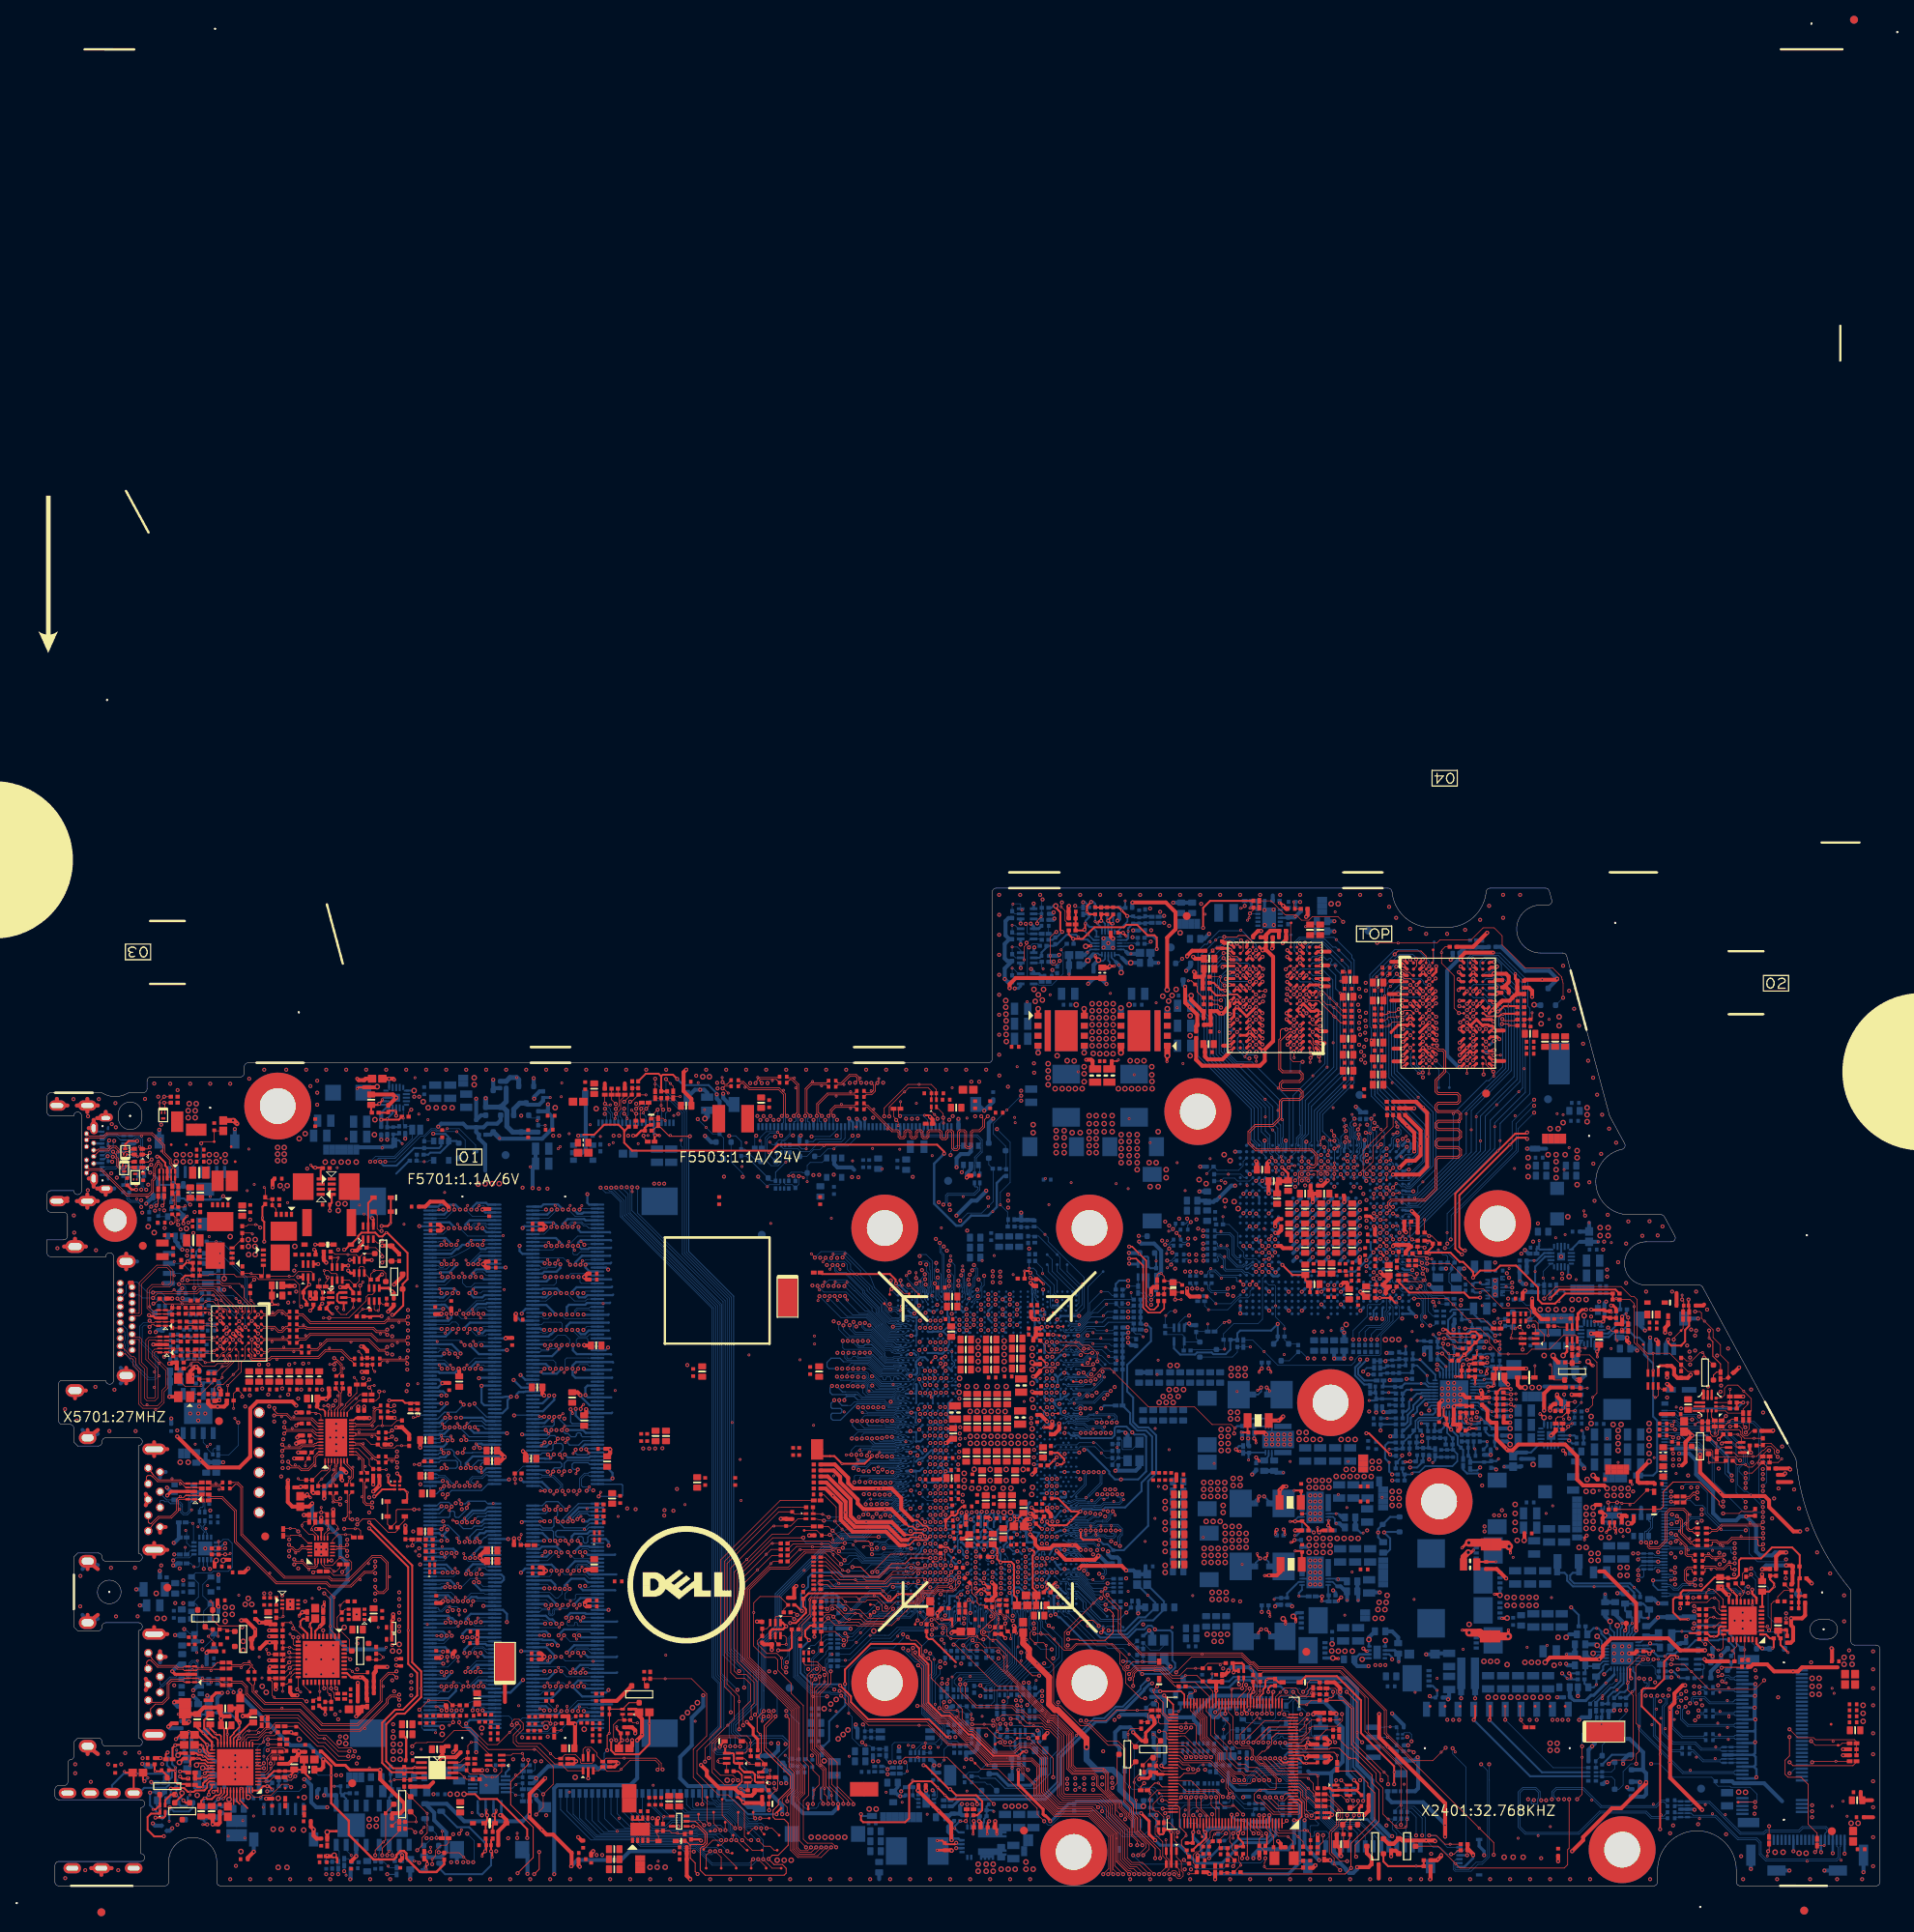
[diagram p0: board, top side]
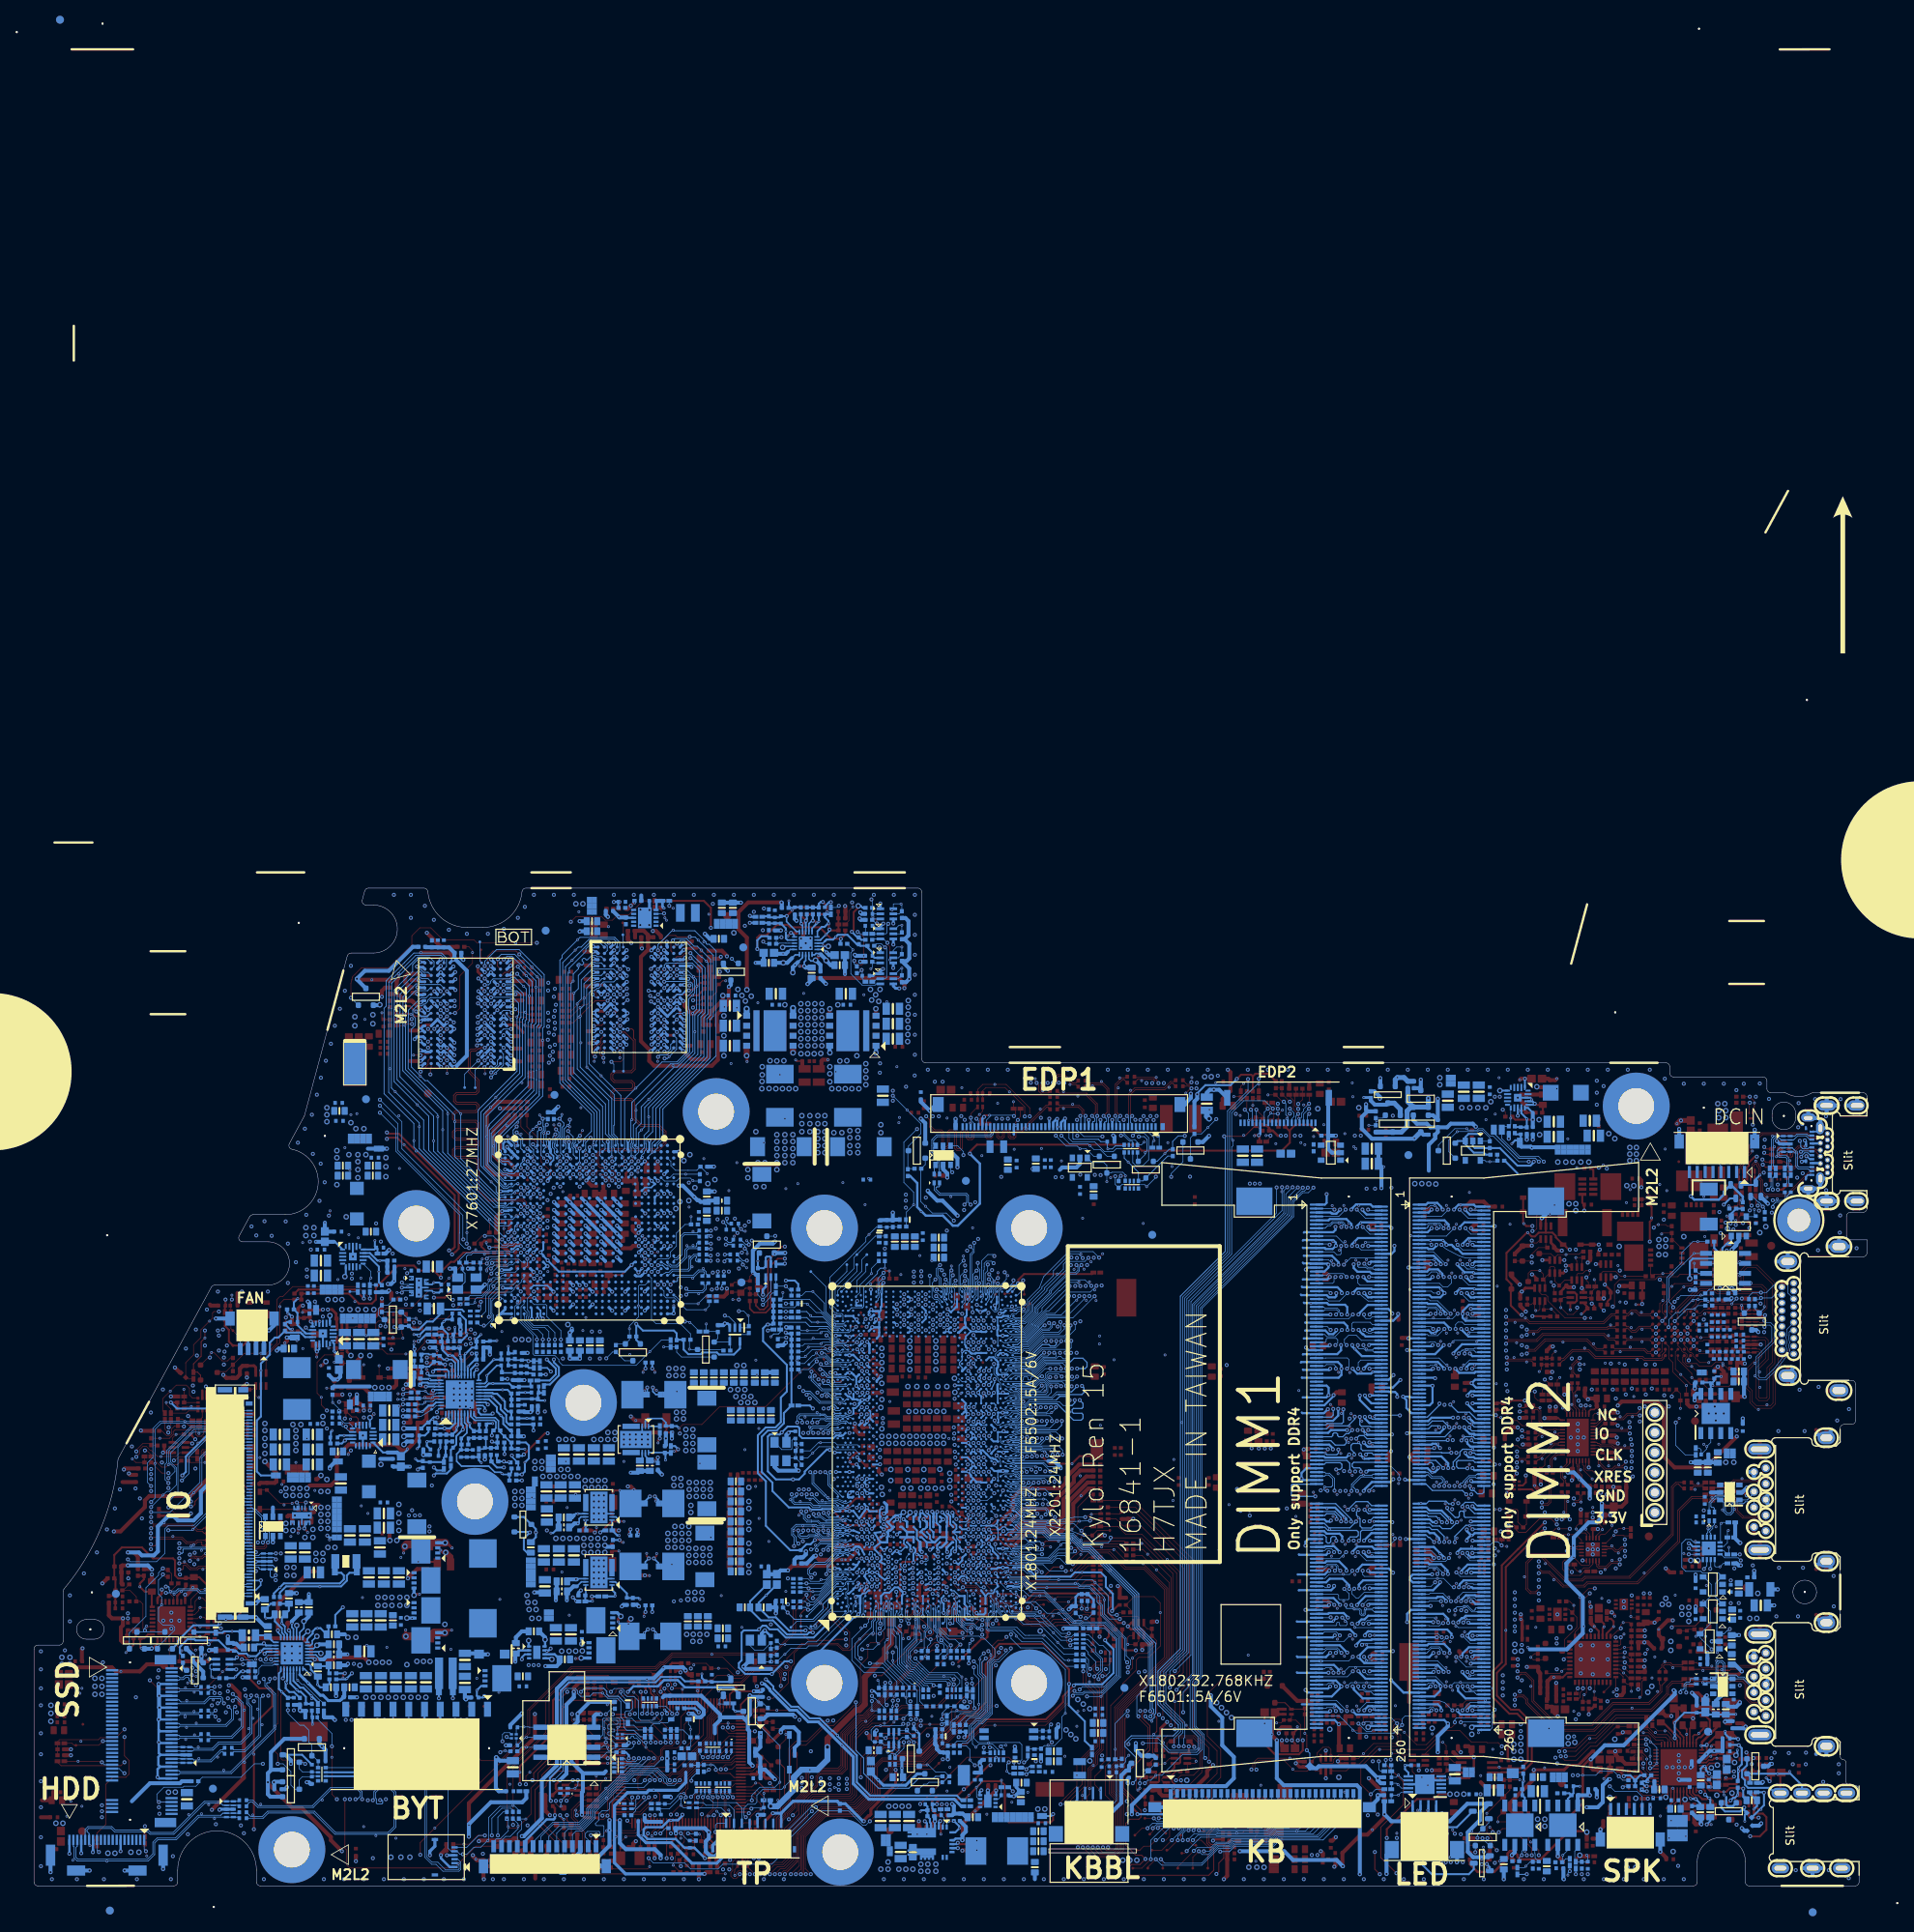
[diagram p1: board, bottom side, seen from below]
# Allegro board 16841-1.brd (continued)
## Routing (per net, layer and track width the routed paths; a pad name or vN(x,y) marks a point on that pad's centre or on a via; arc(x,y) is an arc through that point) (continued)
M_A_DQ22: length 55.1
  TOP w0.089: v1(100.1,76.77) v2(99.9,76.23)
  L3 w0.127: v2(63.87,72.61) 64.69,71.79 68.8,71.79 71.76,74.75 80.92,74.75 84.03,77.87 94.5,77.87 94.91,77.45 99,77.45 99.9,76.56 v2(99.9,76.23)
  BOTTOM w0.089: v2(63.87,72.61) 63.87,72.33 63.64,72.1 63.08,72.1 62.85,72.32 DM1.58 ; v2(99.9,76.23) 100.37,76.7 101.45,76.7 102.5,75.64 102.59,75.64 104.77,73.45 104.77,73.06 106.24,71.59 106.24,71.4 107.16,70.48 107.71,70.48 107.92,70.69 108.17,70.69 108.34,70.65 CPU1.BA63
M_A_DQ23: length 54.4
  TOP w0.089: v1(101.59,76.72) v2(101.26,76.23)
  L3 w0.127: v2(65.3,72.61) 65.74,72.17 68.67,72.17 71.61,75.11 80.77,75.11 83.89,78.22 94.64,78.22 95.06,77.81 99.9,77.81 101.26,76.44 v2(101.26,76.23)
  BOTTOM w0.089: v2(101.26,76.23) 101.44,76.05 101.47,76.05 106.07,71.46 106.07,71.32 107.08,70.31 107.84,70.31 CPU1.BB63 ; DM1.59 65.83,72.07 v2(65.3,72.61)
M_A_DQ24: length 55.6
  TOP w0.089: v1(100.38,74.43) v2(100.04,74.96)
  L3 w0.127: v2(100.04,74.96) 100.04,74.95 99.56,74.47 85.25,74.47 83.09,72.32 73.03,72.32 68.58,67.86 68.11,67.86 67.81,68.16 67.25,68.16 66.95,67.86 66.41,67.86 66.08,68.18 v2(66.08,68.72)
  BOTTOM w0.089: v2(66.08,68.72) 66.37,69.01 66.37,69.44 65.82,69.99 64.87,69.99 64.21,69.32 DM1.70 ; v2(100.04,74.96) 100.12,74.88 100.12,74.76 102.34,72.55 104.19,72.55 105.53,71.2 105.53,71.1 106.89,69.75 108.28,69.75 CPU1.BA61
M_A_DQ25: length 57
  TOP w0.089: v1(97.91,74.38) v2(98.1,74.94)
  L3 w0.127: v2(67.51,68.72) 67.25,68.98 67.25,69.3 67.45,69.5 68.44,69.5 68.64,69.3 68.64,68.98 68.79,68.83 69,68.83 69.15,68.98 69.15,69.3 69.35,69.5 69.71,69.5 69.97,69.75 69.97,70.03 70.19,70.25 70.46,70.25 70.68,70.47 70.68,70.75 70.9,70.97 71.18,70.97 71.4,71.19 71.4,71.47 71.62,71.69 71.9,71.69 72.12,71.91 72.12,72.19 72.34,72.41 72.62,72.41 72.89,72.67 82.95,72.67 84.47,74.2 84.47,74.38 84.32,74.53 84.32,74.71 84.5,74.89 84.67,74.89 84.83,74.73 85.01,74.73 85.3,75.03 86.1,75.03 86.3,74.82 86.6,74.82 86.81,75.03 87.11,75.03 87.32,74.82 87.62,74.82 87.82,75.03 88.13,75.03 88.33,74.82 88.64,74.82 88.84,75.03 89.14,75.03 89.35,74.82 89.65,74.82 89.86,75.03 90.16,75.03 90.36,74.82 90.67,74.82 90.87,75.03 91.18,75.03 91.38,74.82 91.68,74.82 91.89,75.03 92.19,75.03 92.4,74.82 92.7,74.82 92.9,75.03 93.21,75.03 93.41,74.82 93.72,74.82 93.92,75.03 94.22,75.03 94.43,74.82 94.73,74.82 94.94,75.03 95.24,75.03 95.44,74.82 95.75,74.82 95.95,75.03 96.26,75.03 96.46,74.82 96.76,74.82 96.97,75.03 98.01,75.03 v2(98.1,74.94)
  BOTTOM w0.089: v2(98.1,74.94) 100.85,72.18 104.05,72.18 105.18,71.05 105.18,70.96 106.77,69.36 107.68,69.36 107.93,69.11 108.92,69.11 109.08,69.05 109.15,69.02 109.61,69.02 CPU1.AW61 ; v2(67.51,68.72) 67.22,69.01 67.22,69.4 67.4,69.58 68.56,69.58 68.69,69.45 68.69,69.21 68.82,69.07 DM1.71
M_A_DQ26: length 55.1
  TOP w0.089: v1(67.1,65.26) v2(67.46,65.73)
  L3 w0.127: v2(67.46,65.73) 67.46,66.36 67.73,66.63 68.8,66.63 69.35,67.18 69.53,67.18 69.62,67.09 69.8,67.09 69.98,67.27 69.98,67.45 69.89,67.54 69.89,67.72 70.07,67.9 70.25,67.9 70.34,67.81 70.52,67.81 70.7,67.99 70.7,68.17 70.61,68.26 70.61,68.44 71.95,69.78 72.13,69.78 72.39,69.51 72.57,69.51 72.75,69.69 72.75,69.87 72.49,70.14 72.49,70.32 72.67,70.5 72.85,70.5 73.11,70.23 73.29,70.23 73.47,70.41 73.47,70.59 73.21,70.85 73.21,71.03 73.46,71.29 83.52,71.29 85.67,73.44 100.6,73.44 100.73,73.31 100.73,73 100.85,72.88 101.11,72.88 101.23,73 101.23,73.31 101.36,73.44 101.72,73.44 102.75,72.41 102.75,71.97 v2(102.44,71.66)
  BOTTOM w0.089: v2(67.46,65.73) 67.46,66.02 67.68,66.25 68.65,66.25 68.83,66.07 DM1.83 ; v2(102.44,71.66) 102.36,71.58 102.36,70.69 102.69,70.36 104.64,70.36 106.49,68.51 107.19,68.51 107.54,68.15 107.84,68.15 CPU1.BB59
M_A_DQ27: length 57.8
  TOP w0.089: v1(62.76,65.32) v2(63.19,65.73)
  L3 w0.127: v2(100.56,71.53) 100.56,71.77 99.95,72.37 86.11,72.37 83.96,70.22 74.79,70.22 69.02,64.45 68.73,64.45 64.46,64.45 v2(63.19,65.73)
  BOTTOM w0.089: DM1.84 63.09,65.82 v2(63.19,65.73) ; CPU1.AW59 110.14,68.05 110.32,67.96 110.7,67.58 110.7,67.3 110.5,67.1 108.86,67.1 108.74,67.16 108.46,67.16 108.21,67.25 107.55,67.25 107.41,67.12 106.69,67.12 106.43,67.38 106.43,67.77 104.52,69.67 101.59,69.67 100.56,70.71 v2(100.56,71.53)
M_A_DQ28: length 55
  TOP w0.089: v1(99.16,74.41) v2(99.41,74.94)
  L3 w0.127: v2(63.85,70.65) 63.85,70.3 64.29,69.85 65.01,69.85 65.14,69.73 65.14,69.42 65.27,69.3 65.52,69.3 65.65,69.42 65.65,69.73 65.78,69.85 69.29,69.85 72.46,73.03 82.13,73.03 82.46,73.36 82.64,73.36 82.8,73.21 82.98,73.21 83.16,73.39 83.16,73.57 83,73.72 83,73.9 83.18,74.08 83.36,74.08 83.52,73.93 83.7,73.93 83.88,74.11 83.88,74.29 83.72,74.44 83.72,74.62 84.53,75.42 99.04,75.42 99.4,75.06 99.4,74.94 v2(99.41,74.94)
  BOTTOM w0.089: v2(99.41,74.94) 99.43,74.92 99.43,74.56 101.62,72.37 104.11,72.37 105.35,71.13 105.35,71.03 106.83,69.55 107.84,69.55 108,69.49 CPU1.BB61 ; DM1.66 62.87,70.32 62.96,70.23 63.31,70.23 63.41,70.32 63.52,70.32 v2(63.85,70.65)
M_A_DQ29: length 56.2
  TOP w0.089: v1(101.65,74.46) v2(101.34,74.97)
  L3 w0.127: v2(101.34,74.97) 101.67,74.64 102.67,74.64 102.88,74.85 102.88,75.58 102.67,75.79 101.45,75.79 101.45,75.78 101.08,75.78 101.07,75.79 84.34,75.79 81.93,73.38 72.31,73.38 69.14,70.21 67.14,70.21 v2(66.69,70.65)
  BOTTOM w0.089: v2(66.69,70.65) 67.55,69.8 68.6,69.8 68.88,70.07 DM1.67 ; v2(101.34,74.97) 101.34,74.55 103.15,72.75 104.23,72.75 105.71,71.28 105.71,71.18 106.96,69.93 108.59,69.93 108.72,69.79 109.15,69.48 CPU1.AY61
M_A_DQ30: length 56.1
  TOP w0.089: v1(65.68,65.24) v2(66.03,65.73)
  L3 w0.127: v2(66.03,65.73) 66.48,65.28 68.52,65.28 71.1,67.87 71.43,67.87 71.94,68.38 71.94,68.56 71.68,68.82 71.68,69 71.86,69.18 72.04,69.18 72.3,68.92 72.48,68.92 74.5,70.93 83.67,70.93 85.82,73.08 100.06,73.08 100.87,72.27 101.61,72.27 101.93,71.96 v2(101.93,71.25)
  BOTTOM w0.089: v2(101.93,71.25) 101.93,70.78 102.58,70.13 104.57,70.13 106.42,68.28 107.08,68.28 107.4,67.96 107.73,67.96 107.87,67.82 108.18,67.82 108.31,67.86 108.41,67.97 CPU1.BA59 ; v2(66.03,65.73) 65.8,65.96 65.8,66.89 66,67.09 68.7,67.09 68.72,67.07 DM1.79
M_A_DQ31: length 56.6
  TOP w0.089: v1(64.26,65.26) v2(64.61,65.73)
  L3 w0.127: v2(101.14,71.23) 100.99,71.38 100.99,71.76 100.02,72.73 85.97,72.73 83.81,70.58 74.64,70.58 68.88,64.81 65.97,64.81 65.84,64.94 65.84,65.15 65.71,65.27 65.46,65.27 65.33,65.15 65.33,64.94 65.21,64.81 64.85,64.81 64.61,65.05 v2(64.61,65.73)
  BOTTOM w0.089: DM1.80 64.29,66.82 64.61,66.5 v2(64.61,65.73) ; v2(101.14,71.23) 101.17,71.2 101.17,70.67 101.93,69.9 104.55,69.9 106.39,68.05 107.05,68.05 107.31,67.79 107.31,67.79 107.32,67.78 107.34,67.78 107.72,67.64 108.21,67.64 108.49,67.73 108.78,67.73 CPU1.AY59
M_A_DQ32: length 58.8
  TOP w0.089: v1(64.97,41.85) v2(64.65,42.41)
  L3 w0.127: v2(102.21,56.85) 101.92,56.85 98.19,53.12 95.12,53.12 86.4,44.4 81.22,44.4 78.03,41.21 67.49,41.21 67.07,40.78 66.71,40.78 66.59,40.91 66.59,41.61 66.46,41.74 66.21,41.74 66.08,41.61 66.08,40.91 65.95,40.78 65.36,40.78 64.65,41.49 v2(64.65,42.41)
  BOTTOM w0.089: v2(102.21,56.85) 102.23,56.88 102.23,56.93 103,57.7 107.43,57.7 108.18,57.49 108.49,57.35 108.85,57.35 CPU1.AY39 ; v2(64.65,42.41) 63.57,41.32 DM1.174
M_A_DQ33: length 56.9
  TOP w0.089: v1(66.52,41.9) v2(66.15,42.41)
  L3 w0.127: v2(104.14,56.9) 103.55,57.49 101.87,57.49 98.22,53.83 94.5,53.83 85.78,45.11 80.43,45.11 77.4,42.09 69.29,42.09 68.53,42.85 68.52,42.85 68.51,42.86 66.6,42.86 v2(66.15,42.41)
  BOTTOM w0.089: v2(66.15,42.41) 66.99,41.57 DM1.173 ; v2(104.14,56.9) 104.82,56.19 104.97,56.04 107.73,56.04 107.84,56.15 108.23,56.15 108.31,56.11 108.51,56.11 108.59,56.15 108.84,56.15 108.98,56.11 109.47,56.11 109.85,56.21 109.98,56.33 110.04,56.55 CPU1.AW39
M_A_DQ34: length 58.3
  TOP w0.089: v2(102.16,54.79) 101.52,54.79 v1(101.5,54.77)
  L3 w0.127: v2(102.16,54.79) 101.8,54.79 98.39,51.38 95.84,51.38 86.96,42.5 81.78,42.5 77.61,38.33 76.28,38.33 76.15,38.45 76.15,38.86 76.02,38.98 75.77,38.98 75.64,38.86 75.64,38.45 75.51,38.33 75.16,38.33 75.03,38.45 75.03,38.86 74.9,38.98 74.65,38.98 74.52,38.86 74.52,38.45 74.4,38.33 74.14,38.33 74.02,38.45 74.02,38.86 73.89,38.98 73.63,38.98 73.51,38.86 73.51,38.45 73.38,38.33 73.02,38.33 72.9,38.45 72.9,38.86 72.77,38.98 72.52,38.98 72.39,38.86 72.39,38.45 72.26,38.33 72.01,38.33 71.88,38.45 71.88,38.86 71.75,38.98 71.5,38.98 71.37,38.86 71.37,38.45 71.25,38.33 70.99,38.33 70.87,38.45 70.87,38.86 70.74,38.98 70.48,38.98 70.36,38.86 70.36,38.45 70.23,38.33 69.98,38.33 69.85,38.45 69.85,38.86 69.72,38.98 69.47,38.98 69.34,38.86 69.34,38.45 69.21,38.33 68.54,38.33 v2(68.34,38.12)
  BOTTOM w0.089: CPU1.AY37 108.92,55.94 108.91,55.94 108.81,55.97 108.64,55.97 108.55,55.93 108.27,55.93 108.19,55.97 107.91,55.97 107.8,55.86 104.84,55.86 104.79,55.91 102.69,55.91 102.16,55.38 v2(102.16,54.79) ; v2(68.34,38.12) 68.56,37.9 68.8,37.9 68.97,38.07 DM1.187
M_A_DQ35: length 58.8
  TOP w0.089: v2(104.14,54.67) 104.14,54.82 v1(104.47,55.15)
  L3 w0.127: v2(104.14,54.67) 103.83,54.36 101.74,54.36 98.41,51.03 95.99,51.03 87.11,42.14 81.93,42.14 77.76,37.97 68.82,37.97 68.52,37.68 67.49,37.68 67.23,37.94 67.23,38.26 66.93,38.57 63.6,38.57 63.47,38.44 63.47,38.16 v2(63.82,37.82)
  BOTTOM w0.089: DM1.186 63.55,38.32 63.82,38.06 v2(63.82,37.82) ; v2(104.14,54.67) 104.19,54.72 104.19,55.1 104.32,55.23 104.84,55.23 104.93,55.33 107.74,55.33 107.79,55.27 107.8,55.27 107.81,55.27 108.55,55.27 108.55,55.27 108.57,55.27 108.75,55.45 108.89,55.45 108.94,55.49 109.61,55.49 CPU1.AW37
M_A_DQ36: length 56.3
  TOP w0.089: v1(62.89,41.97) v2(63.29,42.46)
  L3 w0.127: v2(107.31,57.06) 106.66,57.7 101.76,57.7 98.24,54.19 94.35,54.19 85.63,45.47 80.28,45.47 77.26,42.44 69.44,42.44 68.68,43.2 68.67,43.2 68.66,43.21 66.21,43.21 66.06,43.36 62.67,43.36 62.55,43.23 62.55,42.58 62.67,42.46 v2(63.29,42.46)
  BOTTOM w0.089: CPU1.BB39 107.33,57.03 v2(107.31,57.06) ; DM1.170 63.16,42.32 v2(63.29,42.46)
M_A_DQ37: length 57.5
  TOP w0.089: v1(68.02,41.9) v2(67.68,42.41)
  L3 w0.127: v2(67.68,42.41) 67.36,42.09 67.36,41.69 67.49,41.56 68.16,41.56 68.29,41.69 68.29,41.81 68.41,41.94 68.67,41.94 68.8,41.81 68.8,41.69 68.92,41.56 69.28,41.56 69.45,41.73 69.79,41.73 69.96,41.56 70.29,41.56 70.46,41.73 70.8,41.73 70.97,41.56 71.31,41.56 71.48,41.73 71.82,41.73 71.99,41.56 72.33,41.56 72.5,41.73 72.83,41.73 73,41.56 73.34,41.56 73.51,41.73 73.85,41.73 74.02,41.56 74.36,41.56 74.53,41.73 74.87,41.73 75.04,41.56 75.37,41.56 75.54,41.73 75.88,41.73 76.05,41.56 76.39,41.56 76.56,41.73 76.9,41.73 77.07,41.56 77.88,41.56 78.14,41.82 78.14,42 78.07,42.07 78.07,42.25 78.25,42.43 78.43,42.43 78.5,42.36 78.68,42.36 78.86,42.54 78.86,42.72 78.79,42.79 78.79,42.97 78.97,43.15 79.15,43.15 79.22,43.08 79.4,43.08 79.58,43.26 79.58,43.44 79.51,43.51 79.51,43.69 79.69,43.87 79.87,43.87 79.94,43.8 80.12,43.8 81.08,44.76 85.93,44.76 86.3,45.13 86.62,45.13 86.82,45.32 86.82,45.65 87.01,45.84 87.34,45.84 87.54,46.04 87.54,46.37 87.73,46.56 88.06,46.56 88.26,46.76 88.26,47.09 88.45,47.28 88.78,47.28 88.98,47.48 88.98,47.81 89.17,48 89.5,48 89.69,48.2 89.69,48.53 89.89,48.72 90.22,48.72 90.41,48.91 90.41,49.24 90.61,49.44 90.94,49.44 91.13,49.63 91.13,49.96 91.33,50.16 91.66,50.16 91.85,50.35 91.85,50.68 92.05,50.88 92.38,50.88 92.57,51.07 92.57,51.4 92.76,51.6 93.09,51.6 93.29,51.79 93.29,52.12 94.65,53.48 98.19,53.48 101.98,57.27 103.08,57.27 v2(103.5,56.85)
  BOTTOM w0.089: v2(67.68,42.41) 67.68,42.52 67.99,42.84 68.65,42.84 68.91,42.57 DM1.169 ; v2(103.5,56.85) 103.5,57.29 103.73,57.52 107.41,57.52 108.12,57.33 108.35,57.22 108.52,57.14 CPU1.BA39
M_A_DQ38: length 57.5
  TOP w0.089: v1(65.04,39.56) v2(65.37,40.05)
  L3 w0.127: v2(65.37,40.05) 65.37,39.57 65.66,39.28 66.29,39.28 66.41,39.41 66.41,39.48 66.54,39.61 66.79,39.61 66.92,39.48 66.92,39.41 67.05,39.28 67.3,39.28 67.43,39.41 67.43,39.48 67.56,39.61 68.82,39.61 68.91,39.69 77.97,39.69 81.49,43.21 86.67,43.21 95.55,52.09 98.29,52.09 101.63,55.44 102.78,55.44 v2(103.43,54.79)
  BOTTOM w0.089: CPU1.BA37 108.25,55.44 107.88,55.44 107.82,55.5 104.83,55.5 104.75,55.43 103.71,55.43 103.45,55.17 103.45,54.82 v2(103.43,54.79) ; DM1.183 68.83,39.07 68.34,39.57 65.72,39.57 65.42,39.87 65.42,40 v2(65.37,40.05)
M_A_DQ39: length 56.8
  TOP w0.089: v2(102.79,54.79) 102.79,54.34 v1(103.02,54.11)
  L3 w0.127: v2(102.79,54.79) 102.36,55.22 101.8,55.22 98.32,51.74 95.7,51.74 86.82,42.86 81.64,42.86 78.12,39.34 69.05,39.34 68.64,38.93 63.87,38.93 63.66,39.13 63.66,39.67 v2(64.05,40.05)
  BOTTOM w0.089: v2(102.79,54.79) 102.79,55.12 103.31,55.64 104.71,55.64 104.75,55.68 107.84,55.68 CPU1.BB37 ; DM1.182 63.81,39.32 64.05,39.56 v2(64.05,40.05)
M_A_DQ40: length 61.3
  TOP w0.089: v1(67.28,35.27) v2(67.65,35.71)
  L3 w0.127: v2(107.31,54.56) 107.31,54.86 107.19,54.98 106.77,54.98 106.64,55.11 106.64,55.65 106.77,55.78 107.56,55.78 108.02,55.31 108.94,55.31 109.17,55.07 109.17,53.75 108.56,53.14 108.21,53.14 108.08,53.27 108.08,53.66 107.96,53.78 107.7,53.78 107.58,53.66 107.58,53.27 107.45,53.14 106.59,53.14 106.23,53.5 102.24,53.5 101.03,52.29 101.03,52.29 100.37,51.62 100.37,51.62 98.21,49.46 97.64,49.46 93.67,45.49 93,45.49 88.07,40.56 82.83,40.56 78.48,36.21 68.16,36.21 v2(67.65,35.71)
  BOTTOM w0.089: DM1.195 68.55,36.07 68.49,36.13 68.14,36.13 68.08,36.07 68.02,36.07 v2(67.65,35.71) ; v2(107.31,54.56) 107.47,54.4 108.15,54.4 108.27,54.45 108.54,54.45 108.64,54.42 108.84,54.42 108.94,54.46 108.99,54.46 CPU1.AY35
M_A_DQ41: length 62.1
  TOP w0.089: v1(63.7,35.22) v2(64.05,35.69)
  L3 w0.127: v2(106.68,54.56) 105.83,53.71 102.15,53.71 100.15,51.71 100.15,51.71 98.28,49.84 97.51,49.84 93.52,45.85 92.85,45.85 87.93,40.92 82.64,40.92 78.29,36.57 67.86,36.57 67.46,36.18 64.65,36.18 64.53,36.3 64.53,36.68 64.4,36.81 62.82,36.81 62.7,36.68 62.7,35.2 62.82,35.07 63.43,35.07 v2(64.05,35.69)
  BOTTOM w0.089: v2(64.05,35.69) 63.42,36.32 DM1.194 ; v2(106.68,54.56) 107.08,54.16 107.48,54.16 107.54,54.22 108.18,54.22 108.22,54.24 108.22,54.24 108.31,54.28 108.51,54.28 108.6,54.24 108.88,54.24 108.97,54.28 109.49,54.28 CPU1.AW35
M_A_DQ42: length 61.8
  TOP w0.089: v1(66.26,33.62) v2(66.64,34.09)
  L3 w0.089: v2(106.72,52.62) 106.72,52.02 106.62,51.93 102.3,51.93 102.16,51.8
  L3 w0.127: 102.16,51.8 101.62,51.25 101.62,50.98 94.39,43.75 94.12,43.75 93.28,42.91 93.1,42.91 93.08,42.93 92.9,42.93 92.72,42.75 92.72,42.57 92.74,42.55 92.74,42.37 92.56,42.19 92.38,42.19 92.36,42.21 92.18,42.21 92,42.03 92,41.85 92.02,41.83 92.02,41.65 91.84,41.47 91.66,41.47 91.64,41.49 91.46,41.49 91.28,41.31 91.28,41.13 91.3,41.11 91.3,40.93 91.13,40.75 90.95,40.75 90.92,40.77 90.75,40.77 90.57,40.59 90.57,40.41 90.59,40.39 90.59,40.21 90.41,40.03 90.23,40.03 90.21,40.05 90.03,40.05 89.85,39.87 89.85,39.69 89.87,39.67 89.87,39.49 89.69,39.31 89.51,39.31 89.49,39.33 89.31,39.33 88.24,38.27 87.36,38.27 87.24,38.39 87.24,38.7 87.11,38.82 86.85,38.82 86.73,38.7 86.73,38.39 86.6,38.27 86.35,38.27 86.22,38.39 86.22,38.7 86.09,38.82 85.84,38.82 85.71,38.7 85.71,38.39 85.58,38.27 85.33,38.27 85.2,38.39 85.2,38.7 85.08,38.82 84.82,38.82 84.7,38.7 84.7,38.39 84.57,38.27 84.21,38.27 79.59,33.65 67.08,33.65 v2(66.64,34.09)
  BOTTOM w0.089: CPU1.AY33 109.28,53.25 108.86,53.06 108.72,53.06 108.37,52.98 108.31,52.94 108.22,52.92 108.19,52.91 107.86,52.91 107.78,52.99 106.96,52.99 106.72,52.74 v2(106.72,52.62) ; DM1.207 67.43,33.07 67.34,33.16 67.34,33.41 67.26,33.5 67.08,33.5 66.99,33.41 66.99,33.16 66.9,33.07 66.16,33.07 66,33.23 66,33.54 66.29,33.82 66.37,33.82 v2(66.64,34.09)
M_A_DQ43: length 60.3
  TOP w0.089: v1(65.04,32.85) v2(65.4,33.33)
  L3 w0.089: v2(110.55,54.72) 107.58,51.75 102.42,51.75 102.16,51.49
  L3 w0.127: 102.16,51.49 101.85,51.18 101.85,50.83 99.62,48.6 99.62,48.48 94.53,43.39 94.27,43.39 88.79,37.91 84.36,37.91 79.74,33.29 65.43,33.29 v2(65.4,33.33)
  BOTTOM w0.089: v2(65.4,33.33) 64.9,32.82 DM1.208 ; CPU1.AW33 110.07,54.04 110.17,54.31 110.55,54.68 v2(110.55,54.72)
M_A_DQ44: length 60.2
  TOP w0.089: v1(66.06,38.21) v2(66.38,37.74)
  L3 w0.127: v2(66.38,37.74) 66.39,37.74 66.39,37.39 66.3,37.3 65.13,37.3 65,37.17 65,36.68 65.13,36.56 67.34,36.56 67.71,36.92 78.15,36.92 82.5,41.27 87.78,41.27 92.71,46.2 93.37,46.2 97.43,50.26 98.39,50.26 99.93,51.8 99.93,51.8 102.06,53.93 105.41,53.93 v2(106.04,54.56)
  BOTTOM w0.089: v2(106.04,54.56) 106.04,54.87 106.14,54.96 107.48,54.96 107.76,54.68 CPU1.BB35 ; DM1.191 67.23,37.07 67.1,36.95 67.1,36.5 66.97,36.38 65.9,36.38 65.77,36.5 65.77,37.13 v2(66.38,37.74)
M_A_DQ45: length 60.9
  TOP w0.089: v2(105.41,54.62) 105.41,54.74 v1(105.74,55.07)
  L3 w0.127: v2(105.41,54.62) 104.94,54.15 101.97,54.15 99.72,51.89 99.72,51.89 98.44,50.61 97.28,50.61 97.07,50.4 96.3,50.4 96.04,50.14 96.04,49.96 96.24,49.75 96.24,49.57 96.06,49.39 95.88,49.39 95.68,49.6 95.5,49.6 95.32,49.42 95.32,49.24 95.52,49.03 95.52,48.86 95.34,48.68 95.16,48.68 94.96,48.88 94.78,48.88 94.6,48.7 94.6,48.52 94.8,48.32 94.8,48.14 94.62,47.96 94.44,47.96 94.24,48.16 94.06,48.16 93.88,47.98 93.88,47.8 94.08,47.6 94.08,47.42 93.9,47.24 93.72,47.24 93.52,47.44 93.34,47.44 87.53,41.63 82.35,41.63 78.04,37.32 67.11,37.32 66.88,37.56 66.88,38.1 66.76,38.22 65.37,38.22 65.11,37.96 v2(65.11,37.77)
  BOTTOM w0.089: CPU1.BA35 108.05,55.07 107.75,55.07 107.68,55.14 105.93,55.14 v2(105.41,54.62) ; DM1.190 63.83,37.32 64.57,36.59 64.88,36.59 65.4,37.11 65.4,37.47 v2(65.11,37.77)
M_A_DQ46: length 60.4
  TOP w0.089: v1(67.76,33.67) v2(68.11,34.13)
  L3 w0.089: v2(106.11,52.9) 106.11,52.23 105.98,52.11 102.16,52.11 101.87,51.81
  L3 w0.127: 101.87,51.81 101.3,51.25 101.3,51.04 98.43,48.17 98.3,48.17 94.24,44.11 93.95,44.11 93.58,44.11 88.65,39.18 83.4,39.18 83.15,38.93 83.15,38.75 83.58,38.32 83.58,38.14 83.4,37.96 83.22,37.96 82.79,38.39 82.61,38.39 82.43,38.21 82.43,38.03 82.86,37.6 82.86,37.42 82.68,37.24 82.5,37.24 82.07,37.67 81.89,37.67 81.71,37.49 81.71,37.31 82.14,36.88 82.14,36.7 81.96,36.52 81.78,36.52 81.35,36.95 81.17,36.95 80.99,36.77 80.99,36.59 81.42,36.16 81.42,35.98 81.24,35.8 81.06,35.8 80.64,36.23 80.46,36.23 80.28,36.05 80.28,35.87 80.71,35.44 80.71,35.26 80.53,35.08 80.35,35.08 79.92,35.51 79.74,35.51 79.56,35.33 79.56,35.15 79.99,34.72 79.99,34.54 79.45,34 72.01,34 71.79,34.22 71.44,34.22 71.22,34 70.93,34 70.71,34.22 70.42,34.22 70.2,34 69.91,34 69.69,34.22 69.4,34.22 69.18,34 68.9,34 68.68,34.22 68.2,34.22 v2(68.11,34.13)
  BOTTOM w0.089: DM1.203 68.17,34.07 v2(68.11,34.13) ; CPU1.BA33 108.42,53.23 108.29,53.15 108.27,53.12 108.25,53.11 108.17,53.09 107.93,53.09 107.86,53.17 106.37,53.17 v2(106.11,52.9)
M_A_DQ47: length 59.4
  L3 w0.089: v2(105.02,52.98) 104.91,52.87 104.91,52.56 104.63,52.28 102.03,52.28 101.76,52.02
  L3 w0.127: v2(63.98,33.33) 63.98,33.64 63.85,33.77 63.27,33.77 63.14,33.9 63.14,34.59 63.27,34.71 63.58,34.71 63.93,35.06 65.46,35.06 65.94,34.58 71.94,34.58 72.16,34.36 76.74,34.36 76.87,34.48 76.87,35.04 76.99,35.17 77.25,35.17 77.37,35.04 77.37,34.48 77.5,34.36 78.08,34.36 83.26,39.53 88.5,39.53 93.43,44.46 94.09,44.46 98.02,48.39 98.21,48.39 98.34,48.39 101.09,51.13 101.09,51.35 101.76,52.02
  BOTTOM w0.089: DM1.204 62.98,33.82 63.05,33.75 63.44,33.75 63.87,33.33 v2(63.98,33.33) ; v2(105.02,52.98) 105.27,53.23 v1(105.55,53.23) 105.66,53.35 107.49,53.35 CPU1.BB33
M_A_DQ48: length 61.6
  TOP w0.089: v1(63.55,30.64) v2(64.13,30.63)
  L3 w0.127: v2(104.57,51.32) 103.96,50.72 103.21,50.72 100.49,47.99 100.49,44.84 99.61,43.96 98.87,43.96 95.83,40.92 94.25,40.92 89.53,36.2 85.09,36.2 79.92,31.03 68.76,31.03 68.63,30.9 68.63,30.37 68.5,30.24 66.73,30.24 66.61,30.37 66.61,30.9 66.48,31.03 66.23,31.03 66.1,30.9 66.1,30.37 65.97,30.24 65.72,30.24 65.59,30.37 65.59,30.9 65.46,31.03 64.53,31.03 v2(64.13,30.63)
  BOTTOM w0.089: v2(104.57,51.32) 104.89,51.64 107.74,51.64 107.8,51.71 107.88,51.71 107.89,51.72 108.2,51.72 108.23,51.69 108.9,51.69 CPU1.AY31 ; DM1.216 63.94,30.82 v2(64.13,30.63)
M_A_DQ49: length 62.6
  TOP w0.089: v1(65.32,31.36) v2(65.65,31.84)
  L3 w0.127: v2(65.65,31.84) 65.65,32.51 65.78,32.64 67.92,32.64 67.92,32.63 68.62,32.63 68.75,32.5 68.75,32.22 68.88,32.1 69.13,32.1 69.26,32.22 69.26,32.5 69.38,32.63 69.64,32.63 69.76,32.5 69.76,32.22 69.89,32.1 70.15,32.1 70.27,32.22 70.27,32.5 70.4,32.63 70.76,32.63 70.88,32.5 70.88,32.23 71.01,32.1 71.26,32.1 71.39,32.23 71.39,32.5 71.52,32.63 80.01,32.63 84.64,37.27 89.09,37.27 93.81,41.98 94.61,41.98 95.39,41.98 99.84,46.44 99.84,48.51 102.53,51.2 102.53,51.28 v2(102.53,51.29)
  BOTTOM w0.089: v2(65.65,31.84) 66.42,31.07 DM1.215 ; v2(102.53,51.29) 102.53,52.05 102.66,52.18 107.52,52.18 107.85,52.51 108.22,52.51 108.37,52.44 108.44,52.37 109.54,52.37 CPU1.AW31
M_A_DQ50: length 61.3
  TOP w0.089: v1(66.8,27.57) v2(66.48,27.09)
  L3 w0.127: v2(66.48,27.09) 66.54,27.15 66.54,27.18 66.9,27.54 71.37,27.54 72.36,28.54 79.89,28.54 79.96,28.61 79.96,28.61 85.81,34.46 90.34,34.46 94.81,38.92 96.84,38.92 100.02,42.11 100.81,42.11 101.74,43.04 101.74,45.83 101.62,45.95 101.62,47.49 103.27,49.14 105.09,49.14 105.12,49.17 106.02,49.17 106.39,49.53 106.39,49.71 v2(106.39,49.72)
  BOTTOM w0.089: CPU1.AY29 108.92,50.49 108.83,50.43 108.64,50.38 108.52,50.25 107.9,50.25 107.75,50.1 106.78,50.1 v2(106.39,49.72) ; v2(66.48,27.09) 66.48,27.12 65.78,27.82 DM1.228
M_A_DQ51: length 61.2
  TOP w0.089: v1(68.07,27.57) v2(67.75,27.09)
  L3 w0.127: v2(110.61,50.91) 109.57,50.91 107.63,48.96 106.85,48.96 106.84,48.97 106.5,48.97 106.48,48.95 105.21,48.95 105.18,48.92 103.36,48.92 101.83,47.4 101.83,46.04 101.95,45.92 101.95,42.95 100.9,41.89 100.31,41.89 96.98,38.57 94.96,38.57 90.49,34.1 85.96,34.1 80.04,28.18 75.6,28.18 75.47,28.05 75.47,27.78 75.35,27.65 75.09,27.65 74.97,27.78 74.97,28.05 74.84,28.18 74.58,28.18 74.46,28.05 74.46,27.78 74.33,27.65 74.08,27.65 73.95,27.78 73.95,28.05 73.82,28.18 72.67,28.18 71.67,27.19 69.12,27.19 68.57,26.64 68.2,26.64 67.76,27.09 v2(67.75,27.09)
  BOTTOM w0.089: v2(110.61,50.91) CPU1.AW29 ; v2(67.75,27.09) 67.75,27.39 68.11,27.75 68.71,27.75 68.88,27.57 DM1.229
M_A_DQ52: length 60.2
  TOP w0.089: v1(67.25,31.36) v2(66.95,31.84)
  L3 w0.127: v2(66.95,31.84) 66.95,31.06 66.96,31.05 66.96,30.79 67.09,30.67 68.15,30.67 68.27,30.79 68.27,31.19 68.47,31.39 74.4,31.39 74.53,31.51 74.53,31.79 74.65,31.92 74.91,31.92 75.04,31.79 75.04,31.51 75.16,31.39 75.42,31.39 75.54,31.51 75.54,31.79 75.67,31.92 75.92,31.92 76.05,31.79 76.05,31.51 76.18,31.39 76.53,31.39 76.66,31.51 76.66,31.79 76.79,31.92 77.04,31.92 77.17,31.79 77.17,31.51 77.3,31.39 77.55,31.39 77.68,31.51 77.68,31.79 77.8,31.92 78.06,31.92 78.19,31.79 78.19,31.51 78.31,31.39 78.57,31.39 78.69,31.51 78.69,31.79 78.82,31.92 79.07,31.92 79.2,31.79 79.2,31.51 79.33,31.39 79.78,31.39 84.94,36.55 89.39,36.55 94.11,41.27 95.68,41.27 98.89,44.48 98.89,44.86 100.27,46.24 100.27,48.08 103.12,50.93 103.59,50.93 v2(103.93,51.28)
  BOTTOM w0.089: CPU1.BB31 107.82,51.89 107.73,51.89 107.66,51.82 104.48,51.82 v2(103.93,51.28) ; v2(66.95,31.84) 67.37,32.26 68.91,32.26 69.1,32.07 DM1.211
M_A_DQ53: length 60.4
  TOP w0.089: v1(62.55,31.84) v2(63.14,31.83)
  L3 w0.127: v2(63.14,31.83) 63.58,31.39 65.87,31.39 66.76,32.28 67.77,32.28 67.78,32.27 67.95,32.27 68.07,32.15 68.07,31.87 68.2,31.74 71.75,31.74 71.87,31.87 71.87,32.15 72,32.27 72.25,32.27 72.38,32.15 72.38,31.87 72.51,31.74 72.76,31.74 72.89,31.87 72.89,32.15 73.02,32.27 73.27,32.27 73.4,32.15 73.4,31.87 73.52,31.74 73.78,31.74 73.9,31.87 73.9,32.15 74.03,32.27 80.15,32.27 84.79,36.91 89.24,36.91 93.96,41.63 94.47,41.63 95.53,41.63 98.64,44.74 98.64,44.91 100.06,46.33 100.06,48.31 102.61,50.87 102.71,50.87 103.19,51.35 v2(103.2,51.35)
  BOTTOM w0.089: CPU1.BA31 108.37,52.18 108.32,52.24 108.27,52.28 108.18,52.31 108.15,52.33 107.92,52.33 107.67,52.08 107.67,52.08 107.59,52 103.33,52 103.2,51.87 v2(103.2,51.35) ; DM1.212 63.05,31.82 63.06,31.83 v2(63.14,31.83)
M_A_DQ54: length 60
  TOP w0.089: v1(63.6,28.61) v2(63.87,29.11)
  L3 w0.127: v2(63.87,29.11) 63.87,28.43 64.13,28.17 71.47,28.17 72.19,28.89 79.74,28.89 79.85,29 85.67,34.81 90.19,34.81 94.66,39.28 96.66,39.28 99.07,41.69 99.07,41.91 101.4,44.24 101.4,47.58 103.18,49.36 104.72,49.36 v2(105.1,49.73)
  BOTTOM w0.089: DM1.224 62.7,28.82 62.86,28.66 63.43,28.66 v2(63.87,29.11) ; CPU1.BA29 108.34,50.5 108.14,50.43 107.82,50.43 107.68,50.29 105.68,50.29 105.12,49.73 v2(105.1,49.73)
M_A_DQ55: length 59
  L3 w0.127: v2(65.3,29.11) 65.87,29.11 66.45,28.53 71.2,28.53 71.92,29.25 79.6,29.25 85.52,35.17 90.01,35.17 94.48,39.64 96.51,39.64 98.72,41.85 98.72,41.89 101.19,44.35 101.19,47.67 103.15,49.64 103.59,49.64 v2(103.73,49.78)
  BOTTOM w0.089: CPU1.BB29 107.74,50.61 107.61,50.47 105.3,50.47 v1(105.28,50.45) 104.4,50.45 v2(103.73,49.78) ; DM1.225 65.83,28.57 v2(65.3,29.11)
M_A_DQ56: length 65.5
  TOP w0.089: v1(67.81,25.82) v2(67.46,25.35)
  L3 w0.127: v2(67.46,25.35) 67.9,24.91 68.37,24.91 68.82,25.35 70.01,25.35 70.14,25.23 70.14,24.85 70.27,24.72 70.52,24.72 70.65,24.85 70.65,25.23 70.78,25.35 72.3,25.35 72.43,25.23 72.43,24.85 72.55,24.72 72.81,24.72 72.94,24.85 72.94,25.23 73.06,25.35 73.32,25.35 73.44,25.23 73.44,24.85 73.57,24.72 73.82,24.72 73.95,24.85 73.95,25.23 74.08,25.35 74.33,25.35 74.46,25.23 74.46,24.85 74.59,24.72 74.84,24.72 74.97,24.85 74.97,25.23 75.09,25.35 75.45,25.35 75.58,25.23 75.58,24.85 75.7,24.72 75.96,24.72 76.08,24.85 76.08,25.23 76.21,25.35 76.47,25.35 76.59,25.23 76.59,24.95 76.72,24.83 76.97,24.83 77.1,24.95 77.1,25.23 77.23,25.35 79.23,25.35 86.03,32.16 90.61,32.16 95.2,36.75 95.5,36.75 96.82,36.75 98.1,38.04 99.85,38.04 100.17,38.35 100.17,38.53 100.06,38.63 100.06,38.81 100.24,38.99 100.42,38.99 100.53,38.89 100.7,38.89 101.16,39.35 101.16,40.04 102.6,41.48 102.6,46.19 102.48,46.3 102.48,47.13 103.19,47.84 104.99,47.84 105.17,48.03 105.18,48.03 105.18,48.03 105.54,48.03 v2(106.04,48.53)
  BOTTOM w0.089: v2(106.04,48.53) 106.45,48.95 107.41,48.95 107.7,49.24 108.13,49.24 108.17,49.26 108.25,49.27 108.5,49.34 108.54,49.35 108.87,49.35 109.03,49.42 109.1,49.48 CPU1.AY27 ; v2(67.46,25.35) 67.88,25.78 68.39,25.78 68.59,25.57 DM1.237
M_A_DQ57: length 65.8
  TOP w0.089: v1(66.36,25.84) v2(66.03,25.35)
  L3 w0.127: v2(109.73,50.25) 109.41,50.25 106.98,47.81 105.27,47.81 105.08,47.63 103.28,47.63 102.7,47.04 102.7,46.39 102.82,46.27 102.82,41.85 102.82,41.85 102.82,41.49 102.82,41.49 102.82,40.46 100.04,37.68 98.25,37.68 96.96,36.39 95.35,36.39 90.71,31.75 86.13,31.75 78.75,24.37 78.33,24.37 78.2,24.49 78.2,24.73 78.08,24.85 77.82,24.85 77.69,24.73 77.69,24.49 77.57,24.37 66.27,24.37 66.03,24.61 v2(66.03,25.35)
  BOTTOM w0.089: v2(66.03,25.35) 65.56,25.82 DM1.236 ; CPU1.AW27 v2(109.73,50.25)
M_A_DQ58: length 65.1
  TOP w0.089: v1(67.61,22.77) v2(67.46,22.23)
  L3 w0.127: v2(67.46,22.23) 67.9,21.78 78.62,21.78 85.94,29.1 87.45,29.1 87.58,28.97 87.58,28.49 87.71,28.36 88.06,28.36 88.19,28.49 88.19,28.97 88.32,29.1 88.57,29.1 88.7,28.97 88.7,28.49 88.83,28.36 89.18,28.36 89.31,28.49 89.31,28.97 89.43,29.1 89.69,29.1 89.82,28.97 89.82,28.49 89.94,28.36 90.2,28.36 90.32,28.49 90.32,28.76 90.45,28.89 90.7,28.89 90.83,28.76 90.83,28.49 90.96,28.36 91.31,28.36 91.44,28.49 91.44,28.74 91.57,28.87 91.82,28.87 91.95,28.74 91.95,28.49 92.08,28.36 92.69,28.36 97.51,33.18 97.51,34.48 98.95,35.92 100.9,35.92 104.07,39.09 104.07,44.44 106.47,46.85 106.47,47.13 v2(106.46,47.14)
  BOTTOM w0.089: v2(106.46,47.14) 106.47,47.14 106.47,47.17 106.69,47.39 107.52,47.39 107.55,47.42 108,47.87 108.61,48.06 108.73,48.06 CPU1.AY25 ; DM1.249 68.68,22.57 68.59,22.66 67.89,22.66 v2(67.46,22.23)
M_A_DQ59: length 64.9
  TOP w0.089: v1(62.6,22.52) v2(63.14,22.3)
  L3 w0.127: v2(109.67,47.94) 109.15,47.42 108.62,47.42 107.68,46.48 106.77,46.48 105.56,45.27 105.25,45.27 104.29,44.31 104.29,38.77 101.06,35.55 100.73,35.55 99.92,34.73 99.16,34.73 98.01,33.59 98.01,33.18 92.79,27.95 87.23,27.95 87.1,28.08 87.1,28.43 86.97,28.56 86.72,28.56 86.59,28.43 86.59,28.08 86.46,27.95 85.3,27.95 78.77,21.43 64.01,21.43 v2(63.14,22.3)
  BOTTOM w0.089: v2(63.14,22.3) 63.11,22.32 DM1.250 ; CPU1.AW25 v2(109.67,47.94)
M_A_DQ60: length 63.4
  L3 w0.127: v2(103.98,48.51) 103.89,48.51 103.85,48.54 103.28,48.54 102.05,47.31 102.05,46.13 102.17,46.01 102.17,42.86 100.32,41.01 100.32,40.11 98.96,38.75 97.81,38.75 96.59,37.52 94.98,37.52 90.37,32.92 85.79,32.92 79.83,26.96 76.72,26.96 76.59,26.83 76.59,26.37 76.47,26.25 76.21,26.25 76.09,26.37 76.09,26.71 75.96,26.83 75.71,26.83 75.58,26.71 75.58,26.37 75.45,26.25 75.2,26.25 75.07,26.37 75.07,26.83 74.94,26.96 74.59,26.96 74.46,26.83 74.46,26.44 74.27,26.25 66.31,26.25 65.95,26.61 65.95,27.58 65.8,27.73 64.32,27.73 v2(63.87,27.28)
  BOTTOM w0.089: DM1.232 63.42,26.82 v2(63.87,27.28) ; v2(103.98,48.51) 103.98,48.84 104.29,49.15 v1(104.59,49.15) 105.75,49.15 105.9,49.3 107.26,49.3 107.57,49.61 107.72,49.61 CPU1.BB27
M_A_DQ61: length 64.6
  TOP w0.089: v1(64.94,27.75) v2(65.29,27.28)
  L3 w0.127: v2(65.29,27.28) 65.06,27.04 65.06,26.27 65.43,25.89 77.13,25.89 77.26,26.02 77.26,26.28 77.39,26.4 77.64,26.4 77.77,26.28 77.77,26.02 77.9,25.89 78.15,25.89 78.28,26.02 78.28,26.39 78.4,26.52 79.89,26.52 85.91,32.54 90.49,32.54 95.12,37.17 96.74,37.17 97.96,38.39 99.1,38.39 102.39,41.67 102.39,46.1 102.27,46.21 102.27,47.22 103.12,48.07 104.91,48.07 105.19,48.35 105.2,48.35 105.36,48.51 105.36,48.51 v2(105.38,48.53)
  BOTTOM w0.089: v2(65.29,27.28) 65.99,26.57 DM1.233 ; CPU1.BA27 108.27,49.46 108.11,49.42 107.63,49.42 107.33,49.12 105.97,49.12 105.38,48.54 v2(105.38,48.53)
M_A_DQ62: length 64.3
  TOP w0.089: v1(66.03,22.82) v2(66.03,22.23)
  L3 w0.127: v2(105.86,46.89) 105.86,46.82 103.85,44.8 103.85,39.38 100.75,36.28 98.81,36.28 96.95,34.42 96.95,33.12 93.29,29.46 91.35,29.46 91.23,29.58 91.23,29.96 91.1,30.09 90.85,30.09 90.72,29.96 90.72,29.76 90.59,29.63 90.34,29.63 90.21,29.76 90.21,30.03 90.08,30.16 89.83,30.16 89.7,30.03 89.7,29.58 89.58,29.46 85.8,29.46 79.1,22.76 66.57,22.76 v2(66.03,22.23)
  BOTTOM w0.089: CPU1.BA25 108.29,48.15 107.93,48.03 107.91,48.03 107.44,47.56 106.3,47.56 105.86,47.13 v2(105.86,46.89) ; DM1.245 67.38,23.57 v2(66.03,22.23)
M_A_DQ63: length 63.5
  TOP w0.089: v1(64.81,22.86) v2(64.56,22.31)
  L3 w0.127: v2(105.35,47.28) 105.35,46.68 103.6,44.94 103.6,39.63 100.6,36.63 98.66,36.63 97.39,35.36 97.18,35.36 94.89,33.07 94.89,32.9 95.32,32.46 95.32,32.28 93.63,30.59 93.28,30.59 93.15,30.72 93.15,30.98 93.02,31.1 92.77,31.1 92.64,30.98 92.64,30.72 92.52,30.59 86.43,30.59 78.95,23.12 65.37,23.12 v2(64.56,22.31)
  BOTTOM w0.089: v2(105.35,47.28) 105.81,47.74 107.32,47.74 107.82,48.24 CPU1.BB25 ; DM1.246 63.54,23.32 v2(64.56,22.31)
M_A_DQS_DN0: length 69.3
  TOP w0.089: v1(65.78,84.21) v2(66.1,83.74)
  L3 w0.14: v2(113.89,81.26) 113.89,81.68 114.27,82.05 114.27,83.05 109.27,88.05 88.32,88.05 88.04,87.76 88.04,87.58 87.9,87.44 87.62,87.44 87.48,87.58 87.48,87.76 87.19,88.05 86.52,88.05 86.23,87.76 86.23,87.58 86.09,87.44 85.81,87.44 85.67,87.58 85.67,87.76 85.39,88.05 84.9,88.05 84.61,87.76 84.61,87.58 84.47,87.44 84.19,87.44 84.05,87.58 84.05,87.76 83.76,88.05 83.27,88.05 82.98,87.76 82.98,87.58 82.84,87.44 82.56,87.44 82.42,87.58 82.42,87.76 82.13,88.05 81.1,88.05 78.31,85.26 69.06,85.26 68.56,84.76 66.36,84.76 66.1,84.5 v2(66.1,83.74)
  BOTTOM w0.089: CPU1.AM70 114.04,74.74 114.04,74.92 113.99,75.1 113.99,75.28 114.02,75.39 114.02,75.66 113.99,75.73 113.99,75.92 113.91,76 113.91,80.26 113.58,80.59 113.58,80.95 v2(113.89,81.26) ; DM1.11 68.22,84.07 68.01,84.29 68.01,84.29 67.89,84.4 66.73,84.4 66.57,84.4 66.33,84.16 66.33,83.97 v2(66.1,83.74)
M_A_DQS_DN1: length 60.9
  TOP w0.089: v1(63.57,79.59) v2(63.84,79.07)
  L3 w0.14: v2(63.84,79.07) 63.84,79.77 64.12,80.05 65.14,80.05 65.93,79.25 65.93,78.8 66.26,78.48 68.58,78.48 71.12,81.02 79.65,81.02 81.78,83.16 100.79,83.16 105.29,78.66 110.12,78.66 111.05,77.73 v2(111.48,77.73)
  BOTTOM w0.089: CPU1.AT69 111.5,74.53 111.5,74.91 111.45,75.09 111.45,75.28 111.5,75.46 111.5,75.48 111.5,75.68 110.99,76.19 110.99,77.09 v2(111.48,77.73) ; v2(63.84,79.07) 63.38,78.6 62.78,78.6 62.56,78.82 DM1.32
M_A_DQS_DN2: length 55.3
  TOP w0.089: v1(99.44,78.37) v2(99.77,78.9)
  L3 w0.14: v2(66.72,72.61) 67.05,72.94 67.05,73.81 67.38,74.14 68.13,74.14 68.44,73.83 69.43,73.83 71.35,75.75 80.51,75.75 83.62,78.86 94.91,78.86 95.32,78.45 95.62,78.45 96.03,78.86 96.53,78.86 96.95,78.45 97.24,78.45 97.65,78.86 98.39,78.86 98.8,78.45 99.69,78.45 99.77,78.53 v2(99.77,78.9)
  BOTTOM w0.089: v2(99.77,78.9) 100.03,78.64 100.03,78.16 100.44,77.75 101.45,77.75 103.62,75.58 103.62,75.33 105.51,73.44 105.51,72.85 106.89,71.47 107.61,71.47 107.77,71.31 108.19,71.31 108.34,71.36 108.48,71.36 108.68,71.3 CPU1.BA64 ; DM1.53 69.9,73.57 69,73.57 68.83,73.41 67.27,73.41 66.98,73.13 66.98,72.87 v2(66.72,72.61)
M_A_DQS_DN3: length 56.1
  TOP w0.089: v1(63.6,68.24) v2(63.95,68.72)
  L3 w0.14: v2(103.25,71.5) 103.25,72.42 101.84,73.83 85.51,73.83 83.36,71.67 73.3,71.67 68.64,67.02 64.72,67.02 64.18,67.56 64.18,68.49 v2(63.95,68.72)
  BOTTOM w0.089: CPU1.AY60 109.12,68.36 108.71,68.36 108.51,68.3 108.31,68.3 108.16,68.34 107.61,68.34 107.26,68.7 106.58,68.7 104.7,70.58 103.88,70.58 103.48,70.99 103.48,71.27 v2(103.25,71.5) ; v2(63.95,68.72) 63.95,68.57 63.55,68.16 62.75,68.16 62.59,68.32 DM1.74
M_A_DQS_DN4: length 57.4
  TOP w0.089: v1(66.49,39.61) v2(66.89,40.05)
  L3 w0.14: v2(105.41,56.9) 105.18,56.62 104.86,56.3 104.86,55.63 104.69,55.46 103.91,55.46 103.73,55.63 103.73,55.97 103.35,56.35 101.83,56.35 98.22,52.73 95.28,52.73 86.56,44.01 81.38,44.01 77.71,40.34 76.21,40.34 75.73,40.82 75.24,40.82 74.95,40.53 74.95,40.48 74.81,40.34 74.53,40.34 74.39,40.48 74.39,40.53 74.1,40.82 73.5,40.82 73.21,40.53 73.21,40.48 73.07,40.34 72.79,40.34 72.65,40.48 72.65,40.53 72.36,40.82 71.87,40.82 71.58,40.53 71.58,40.48 71.44,40.34 71.16,40.34 71.02,40.48 71.02,40.53 70.74,40.82 70.24,40.82 69.96,40.53 69.96,40.48 69.82,40.34 69.54,40.34 69.4,40.48 69.4,40.53 69.11,40.82 67.65,40.82 67.32,40.49 67.32,40.48 v2(66.89,40.05)
  BOTTOM w0.089: v2(105.41,56.9) 105.41,56.84 105.81,56.44 107.49,56.44 107.52,56.47 107.71,56.6 108.19,56.6 108.32,56.63 108.49,56.63 108.68,56.58 CPU1.BA38 ; DM1.177 68.85,40.57 68.53,40.9 67.42,40.9 67.18,40.66 67.18,40.34 v2(66.89,40.05)
M_A_DQS_DN5: length 61.8
  TOP w0.089: v1(65.12,35.19) v2(65.47,35.69)
  L3 w0.089: v2(103.71,52.68) 103.46,52.68 103.24,52.46 101.85,52.46 101.35,51.97 101.35,51.94
  L3 w0.14: 101.35,51.94 100.84,51.42 100.84,51.2 98.41,48.77 97.85,48.77 93.93,44.85 93.27,44.85 88.34,39.92 83.1,39.92 78.75,35.57 76.49,35.57 76.35,35.43 76.35,35.03 76.06,34.74 75.57,34.74 75.28,35.03 75.28,35.43 75.14,35.57 74.87,35.57 74.73,35.43 74.73,35.03 74.44,34.74 73.95,34.74 73.66,35.03 73.66,35.43 73.52,35.57 73.24,35.57 73.1,35.43 73.1,35.03 72.81,34.74 72.32,34.74 72.03,35.03 72.03,35.43 71.89,35.57 71.17,35.57 70.73,35.13 69.87,35.13 69.69,35.31 69,35.31 68.69,35 66.16,35 v2(65.47,35.69)
  BOTTOM w0.089: DM1.198 62.7,35.32 62.77,35.26 63.66,35.26 63.87,35.06 63.87,34.62 63.97,34.52 64.12,34.52 64.22,34.62 64.22,35.06 64.42,35.26 65.06,35.26 65.21,35.41 v2(65.47,35.69) ; CPU1.AY34 109.24,53.68 109.09,53.63 108.71,53.63 108.51,53.57 108.31,53.57 108.16,53.62 104.64,53.62 v2(103.71,52.68)
M_A_DQS_DN6: length 60.7
  TOP w0.089: v1(66.36,29.2) v2(66.74,29.62)
  L3 w0.14: v2(66.74,29.62) 67.45,28.91 69.01,28.91 69.3,29.2 69.3,30.11 69.43,30.24 69.73,30.24 69.86,30.11 69.86,29.2 70.15,28.91 70.75,28.91 71.04,29.2 71.04,29.7 71.18,29.84 79.64,29.84 85.36,35.56 89.8,35.56 94.39,40.14 96.47,40.14 100.96,44.64 100.96,47.79 103.41,50.24 105.58,50.24 106.09,50.75 106.09,50.86 v2(106.47,51.24)
  BOTTOM w0.089: v2(106.47,51.24) 106.87,50.84 107.45,50.84 107.57,50.95 107.79,51.17 108.19,51.17 108.34,51.12 108.48,51.12 108.68,51.18 CPU1.BA30 ; v2(66.74,29.62) 67.03,29.9 67.03,30 67.26,30.24 68.69,30.24 68.85,30.07 DM1.219
M_A_DQS_DN7: length 65.1
  TOP w0.089: v1(63.55,25.82) v2(63.9,25.35)
  L3 w0.14: v2(104.31,47.2) 104.31,46.54 103.3,45.53 103.3,39.89 100.43,37.02 98.5,37.02 97.23,35.75 95.91,35.75 91.17,31.01 86.3,31.01 78.82,23.53 64.61,23.53 63.9,24.24 v2(63.9,25.35)
  BOTTOM w0.089: CPU1.AY26 109.44,48.94 109.38,48.88 109.09,48.65 108.71,48.65 108.51,48.59 108.31,48.59 108.16,48.64 107.92,48.64 107.2,47.92 105.74,47.92 105.69,47.87 104.36,47.87 104.17,47.68 104.17,47.34 v2(104.31,47.2) ; DM1.240 63.63,24.82 63.9,25.09 v2(63.9,25.35)
M_A_DQS_DP0: length 69.2
  TOP w0.089: v1(67.05,84.24) v2(66.76,83.74)
  L3 w0.14: v2(66.76,83.74) 66.36,84.15 66.36,84.4 66.46,84.5 68.66,84.5 69.16,85 78.42,85 81.21,87.79 82.03,87.79 82.17,87.65 82.17,87.48 82.46,87.19 82.95,87.19 83.24,87.48 83.24,87.65 83.38,87.79 83.65,87.79 83.79,87.65 83.79,87.48 84.08,87.19 84.57,87.19 84.86,87.48 84.86,87.65 85,87.79 85.28,87.79 85.42,87.65 85.42,87.48 85.71,87.19 86.2,87.19 86.49,87.48 86.49,87.65 86.63,87.79 87.08,87.79 87.22,87.65 87.22,87.48 87.51,87.19 88,87.19 88.29,87.48 88.29,87.65 88.43,87.79 109.16,87.79 114.02,82.94 114.02,82.16 113.57,81.72 v2(113.38,81.72)
  BOTTOM w0.089: DM1.13 68.81,83.57 68.5,83.88 68.14,83.88 67.93,84.1 67.93,84.1 67.81,84.21 66.65,84.21 66.52,84.08 66.52,83.98 v2(66.76,83.74) ; v2(113.38,81.72) 113.39,81.71 113.39,80.52 113.72,80.18 113.72,75.9 113.81,75.81 113.81,75.69 113.84,75.62 113.84,75.42 113.81,75.31 113.81,75.08 113.86,74.89 113.86,74.54 114.25,74.04 CPU1.AM69
M_A_DQS_DP1: length 60.8
  TOP w0.089: v1(64.92,79.51) v2(64.53,79.09)
  L3 w0.14: v2(64.53,79.09) 64.1,79.53 64.1,79.66 64.23,79.79 65.04,79.79 65.68,79.15 65.68,78.69 66.15,78.22 68.69,78.22 71.23,80.77 79.75,80.77 81.89,82.9 100.69,82.9 105.18,78.41 110.01,78.41 110.93,77.48 110.93,77.21 111.06,77.09 111.52,77.09 v2(111.53,77.09)
  BOTTOM w0.089: CPU1.AT70 111.68,74.75 111.68,74.93 111.63,75.12 111.63,75.26 111.66,75.4 111.67,75.43 111.68,75.45 111.68,75.75 111.17,76.26 111.17,76.74 v2(111.53,77.09) ; v2(64.53,79.09) 64.69,78.94 64.69,78.75 64.56,78.62 63.67,78.62 63.46,78.41 62.7,78.41 62.62,78.32 DM1.34
M_A_DQS_DP2: length 55.3
  TOP w0.089: v1(100.71,78.35) v2(100.4,78.9)
  L3 w0.14: v2(100.4,78.9) 100.05,78.46 99.8,78.2 98.69,78.2 98.28,78.61 97.76,78.61 97.35,78.2 96.84,78.2 96.43,78.61 96.13,78.61 95.72,78.2 95.22,78.2 94.8,78.61 83.73,78.61 80.61,75.5 71.45,75.5 69.54,73.58 68.33,73.58 68.03,73.89 67.49,73.89 67.3,73.7 67.3,72.74 v2(67.43,72.61)
  BOTTOM w0.089: v2(67.43,72.61) 67.17,72.87 67.17,73.05 67.34,73.22 68.85,73.22 68.99,73.07 DM1.55 ; v2(100.4,78.9) 100.22,78.71 100.22,78.24 100.52,77.94 101.53,77.94 103.81,75.66 103.81,75.41 105.7,73.52 105.7,72.93 106.97,71.66 107.69,71.66 107.86,71.49 108.16,71.49 108.31,71.54 108.51,71.54 108.71,71.48 109.11,71.48 CPU1.AY64
M_A_DQS_DP3: length 56.2
  TOP w0.089: v1(65.02,68.21) v2(64.66,68.72)
  L3 w0.14: v2(103.88,71.54) 103.5,71.92 103.5,72.53 101.95,74.08 85.41,74.08 83.25,71.93 73.19,71.93 68.54,67.27 64.82,67.27 64.43,67.66 64.43,68.5 v2(64.66,68.72)
  BOTTOM w0.089: CPU1.BA60 108.68,68.54 108.48,68.47 108.34,68.47 108.19,68.52 107.71,68.52 107.34,68.89 106.66,68.89 104.78,70.77 103.96,70.77 103.67,71.07 103.67,71.33 v2(103.88,71.54) ; v2(64.66,68.72) 64.66,68.41 64.53,68.28 63.93,68.28 63.63,67.97 62.74,67.97 62.59,67.82 DM1.76
M_A_DQS_DP4: length 57.5
  TOP w0.089: v1(67.94,40.52) v2(67.58,40.05)
  L3 w0.14: v2(67.58,40.05) 67.58,40.38 67.76,40.57 69,40.57 69.14,40.43 69.14,40.37 69.43,40.08 69.92,40.08 70.21,40.37 70.21,40.43 70.35,40.57 70.63,40.57 70.77,40.43 70.77,40.37 71.06,40.08 71.55,40.08 71.84,40.37 71.84,40.43 71.98,40.57 72.26,40.57 72.4,40.43 72.4,40.37 72.68,40.08 73.17,40.08 73.46,40.37 73.46,40.43 73.6,40.57 74,40.57 74.13,40.43 74.13,40.37 74.42,40.08 74.91,40.08 75.2,40.37 75.2,40.43 75.34,40.57 75.62,40.57 76.11,40.08 77.81,40.08 81.49,43.76 86.67,43.76 95.39,52.48 98.32,52.48 101.94,56.09 103.25,56.09 103.48,55.86 103.48,55.53 103.8,55.2 104.79,55.2 105.11,55.52 105.11,56.2 105.34,56.42 105.86,56.42 106.04,56.61 v2(106.04,56.93)
  BOTTOM w0.089: DM1.179 69.08,40.07 68.45,40.71 67.5,40.71 67.37,40.58 67.37,40.25 v2(67.58,40.05) ; v2(106.04,56.93) 106.04,56.82 106.23,56.63 107.41,56.63 107.44,56.66 107.61,56.77 108.17,56.77 108.3,56.81 108.51,56.81 108.71,56.76 108.99,56.76 CPU1.AY38
M_A_DQS_DP5: length 61.9
  TOP w0.089: v1(66.47,36.21) v2(66.19,35.69)
  L3 w0.089: 101.12,52.06 101.18,52.12 101.24,52.12 101.26,52.15 101.27,52.15 101.77,52.65 102.86,52.65 v2(103.07,52.86)
  L3 w0.14: 101.12,52.06 100.59,51.53 100.59,51.31 98.3,49.02 97.74,49.02 93.83,45.1 93.16,45.1 88.23,40.18 82.99,40.18 78.64,35.83 76.39,35.83 76.1,35.54 76.1,35.14 75.96,35 75.68,35 75.54,35.14 75.54,35.54 75.25,35.83 74.76,35.83 74.47,35.54 74.47,35.14 74.33,35 74.05,35 73.91,35.14 73.91,35.54 73.62,35.83 73.13,35.83 72.85,35.54 72.85,35.14 72.71,35 72.43,35 72.29,35.14 72.29,35.54 72,35.83 71.07,35.83 70.62,35.38 69.98,35.38 69.79,35.57 68.9,35.57 68.59,35.26 66.27,35.26 66.19,35.34 v2(66.19,35.69)
  BOTTOM w0.089: DM1.200 62.57,34.82 62.82,35.07 63.59,35.07 63.67,34.98 63.67,34.54 63.89,34.33 64.2,34.33 64.41,34.54 64.41,34.98 64.5,35.07 65.14,35.07 65.34,35.26 66.09,35.26 66.19,35.36 v2(66.19,35.69) ; CPU1.BA34 108.68,53.81 108.48,53.75 108.34,53.75 108.19,53.8 104.55,53.8 104.05,53.29 103.06,53.29 102.93,53.17 102.93,52.99 103.06,52.86 v2(103.07,52.86)
M_A_DQS_DP6: length 60.8
  TOP w0.089: v1(67.81,29.17) v2(67.46,29.62)
  L3 w0.14: v2(105.84,51.24) 105.84,50.86 105.48,50.49 103.31,50.49 100.71,47.9 100.71,44.74 96.36,40.4 94.28,40.4 89.7,35.81 85.25,35.81 79.53,30.09 71.08,30.09 70.79,29.8 70.79,29.31 70.65,29.17 70.26,29.17 70.12,29.31 70.12,30.22 69.84,30.49 69.32,30.49 69.05,30.22 69.05,29.31 68.91,29.17 67.64,29.17 67.46,29.36 v2(67.46,29.62)
  BOTTOM w0.089: v2(105.84,51.24) 106.43,50.65 107.53,50.65 107.7,50.82 107.88,50.99 108.16,50.99 108.31,50.95 108.51,50.95 108.71,51.01 109.09,51.01 CPU1.AY30 ; v2(67.46,29.62) 67.34,29.62 67.22,29.75 67.22,29.92 67.34,30.05 68.61,30.05 69.09,29.57 DM1.221
M_A_DQS_DP7: length 65.2
  TOP w0.089: v1(64.94,25.84) v2(64.61,25.35)
  L3 w0.14: v2(64.61,25.35) 64.15,24.89 64.15,24.34 64.71,23.79 78.72,23.79 86.2,31.27 91.06,31.27 95.8,36 97.12,36 98.39,37.27 100.33,37.27 103.05,39.99 103.05,45.63 104,46.59 104,46.85 v2(103.67,47.18)
  BOTTOM w0.089: DM1.242 62.65,24.32 62.96,24.63 63.71,24.63 64,24.92 64.49,24.92 64.61,25.04 v2(64.61,25.35) ; v2(103.67,47.18) 103.98,47.48 103.98,47.76 104.28,48.06 105.61,48.06 105.66,48.11 107.13,48.11 107.83,48.82 108.19,48.82 108.34,48.77 108.48,48.77 108.68,48.83 CPU1.BA26
M_A_PARITY: length 57.7
  TOP w0.152: v2(70.06,49.5) 70.3,49.93 v1(70.3,50.02)
  L3 w0.089: 102.56,61.04 102.82,61.29 106.59,61.29 106.78,61.11 107.3,61.11 109.49,63.3 109.56,63.35 109.79,63.35 110.27,63.83 110.99,63.83 111.26,64.1 111.73,64.1 v2(112.16,63.66)
  L3 w0.203: v2(70.06,49.5) 70.22,49.34 70.58,49.34 70.99,49.74 71.3,49.74 71.71,49.34 72.13,49.34 75.4,52.61 83.62,52.61 83.63,52.62 83.64,52.62 90.89,59.88 90.9,59.88 90.91,59.88 97.03,59.88 97.03,59.88 98.63,59.88 99.69,60.94 102.47,60.94 102.56,61.04
  BOTTOM w0.152: v2(70.06,49.5) 72.97,49.5 73.1,49.63 73.1,50.91 72.97,51.04 70.72,51.04 70.68,51.07 DM1.143 ; CPU1.AT52 v2(112.16,63.66)
M_B_A0: length 72
  TOP w0.152: v1(49.96,50.48) v2(50.43,50.81)
  L6 w0.165: v2(100.61,61.73) 100.09,61.2 83.72,61.2 78.63,56.11 75.12,56.11 74.95,55.94 74.95,55.63 74.79,55.47 74.46,55.47 74.29,55.63 74.29,55.94 74.13,56.11 73.8,56.11 73.63,55.94 73.63,55.63 73.47,55.47 73.14,55.47 72.97,55.63 72.97,55.94 72.81,56.11 70.72,56.11 70.55,55.94 70.55,55.63 70.39,55.47 70.06,55.47 69.89,55.63 69.89,55.94 69.73,56.11 66.77,56.11 66.02,55.36 62.87,55.36 60.55,53.04 57.74,53.04 57.12,52.42 56.89,52.18 54.07,52.18 53.71,52.54 53.37,52.54 53.01,52.18 52.42,52.18 52.06,52.54 50.77,52.54 50.45,52.22 50.45,52.02 50.77,51.71 50.77,51.26 50.54,51.03 50.54,51.01 50.46,50.94 50.46,50.85 v2(50.43,50.81)
  BOTTOM w0.089: 101.65,61.05 102.09,61.05 102.54,61.5 106.36,61.5 106.92,60.95 106.94,60.92 108.17,60.92 108.39,60.87 CPU1.BA46
  BOTTOM w0.152: v2(100.61,61.73) 100.61,61.4 100.96,61.05 101.65,61.05 ; DM2.144 48.65,50.03 48.85,49.83 49.47,49.83 49.88,50.24 50.22,50.24 50.43,50.44 v2(50.43,50.81)
M_B_A1: length 72.7
  TOP w0.152: v1(55.19,52.51) v2(55.09,53.12)
  L6 w0.165: v2(55.09,53.12) 56.5,53.12 57.35,53.98 60.15,53.98 63.62,57.45 66.45,57.45 66.71,57.7 67.18,57.7 67.35,57.87 67.35,58.06 67.51,58.22 67.84,58.22 68.01,58.06 68.01,57.87 68.17,57.7 68.5,57.7 68.67,57.87 68.67,58.06 68.83,58.22 69.16,58.22 69.33,58.06 69.33,57.87 69.49,57.7 69.82,57.7 69.99,57.87 69.99,58.06 70.15,58.22 70.48,58.22 70.65,58.06 70.65,57.87 70.81,57.7 71.84,57.7 72.02,57.52 72.02,57.2 72.17,57.05 72.64,57.05 72.81,57.21 72.81,58.06 72.97,58.22 73.3,58.22 73.47,58.06 73.47,57.21 73.63,57.05 73.96,57.05 74.13,57.21 74.13,58.06 74.29,58.22 74.62,58.22 74.79,58.06 74.79,57.21 74.95,57.05 75.28,57.05 75.45,57.21 75.45,58.06 75.61,58.22 75.94,58.22 76.11,58.06 76.11,57.21 76.27,57.05 76.74,57.05 76.91,57.21 76.91,58.06 77.07,58.22 77.4,58.22 77.57,58.06 77.57,57.21 77.73,57.05 78.24,57.05 83.36,62.17 100.84,62.17 101.26,61.74 v2(101.26,61.73)
  BOTTOM w0.089: CPU1.AY46 109.1,61.05 108.39,61.05 108.19,61.1 107.02,61.1 106.99,61.13 106.36,61.75 102.97,61.75
  BOTTOM w0.152: v2(55.09,53.12) 55.09,53.58 55.3,53.8 55.57,53.8 55.79,53.57 DM2.133 ; v2(101.26,61.73) 101.26,61.73 101.28,61.75 101.28,61.9 101.58,62.21 102.51,62.21 102.97,61.75
M_B_A2: length 73.2
  TOP w0.152: v1(50.49,53.58) v2(50.74,53.07)
  L6 w0.165: v2(50.74,53.07) 50.74,53.11 50.42,53.43 50.42,53.91 50.6,54.09 51.2,54.09 51.35,53.94 51.35,53.24 51.54,53.05 51.82,53.05 52.01,53.24 52.01,53.94 52.16,54.09 53.85,54.09 53.89,54.13 53.9,54.13 53.9,54.13 56.18,54.13 57.71,55.67 59.43,55.67 62.64,58.87 66.02,58.87 66.31,59.16 79.02,59.16 82.97,63.11 97.82,63.11 97.82,63.1 99.28,63.1 99.29,63.09 100.12,63.09 100.34,63.32 v2(100.34,63.51)
  BOTTOM w0.089: 101.41,62.78 102.91,62.78 103.57,62.12 107.38,62.12 107.59,61.91 107.59,61.91 107.77,61.73 108.17,61.73 108.3,61.76 108.51,61.76 108.83,61.69 109.11,61.69 CPU1.AY47
  BOTTOM w0.152: v2(50.74,53.07) 51.92,53.07 52.12,53.28 52.12,53.86 51.92,54.06 50.01,54.06 49.78,53.82 DM2.132 ; v2(100.34,63.51) 100.34,63.46 101.02,62.78 101.41,62.78
M_B_A3: length 72.5
  TOP w0.152: v1(53.44,53.61) v2(53.82,53.1)
  L6 w0.165: v2(99.98,61.73) 99.46,61.73 99.41,61.67 83.53,61.67 78.44,56.58 71.69,56.58 71.53,56.74 71.53,57.07 71.36,57.23 71.03,57.23 70.87,57.07 70.87,56.74 70.7,56.58 70.37,56.58 70.21,56.74 70.21,57.07 70.04,57.23 69.71,57.23 69.55,57.07 69.55,56.74 69.38,56.58 69.05,56.58 68.89,56.74 68.89,57.07 68.72,57.23 68.39,57.23 68.23,57.07 68.23,56.74 68.06,56.58 67.73,56.58 67.57,56.74 67.57,57.07 67.4,57.23 67.07,57.23 66.91,57.07 66.91,56.74 66.74,56.58 66.57,56.58 65.82,55.83 62.68,55.83 60.36,53.51 57.55,53.51 56.69,52.65 54.27,52.65 53.82,53.1 v2(53.82,53.1)
  BOTTOM w0.089: 105.88,61.27 106.34,61.27 106.84,60.77 106.84,60.77 106.87,60.75 107.84,60.75 CPU1.BB46
  BOTTOM w0.152: DM2.131 54.76,54.07 53.84,53.16 53.84,53.12 v2(53.82,53.1) ; 105.88,61.27 102.85,61.27 100.77,59.19 99.79,59.19 99.57,59.42 99.57,59.91 99.72,60.06 100.78,60.06 100.94,60.21 100.94,60.52 100.78,60.67 99.72,60.67 99.57,60.82 99.57,61.31 v2(99.98,61.73)
M_B_A4: length 72.5
  TOP w0.152: v1(50.06,55.51) v2(50.36,55.01)
  L6 w0.165: v2(99.7,63.53) 99.69,63.54 99.39,63.54 99.36,63.57 82.77,63.57 78.83,59.63 77.35,59.63 77.18,59.8 77.18,60.09 77.02,60.26 76.69,60.26 76.52,60.09 76.52,59.8 76.36,59.63 76.03,59.63 75.86,59.8 75.86,60.09 75.7,60.26 75.37,60.26 75.2,60.09 75.2,59.8 75.04,59.63 74.71,59.63 74.54,59.8 74.54,60.09 74.38,60.26 74.05,60.26 73.88,60.09 73.88,59.8 73.72,59.63 73.25,59.63 73.08,59.8 73.08,60.05 72.92,60.22 72.59,60.22 72.42,60.05 72.42,59.8 72.26,59.63 71.93,59.63 71.76,59.8 71.76,60.05 71.6,60.22 71.27,60.22 71.1,60.05 71.1,59.8 70.93,59.63 70.6,59.63 70.44,59.8 70.44,60.05 70.27,60.22 69.94,60.22 69.78,60.05 69.78,59.8 69.61,59.63 66.3,59.63 66.29,59.63 66.11,59.63 65.66,60.09 62.95,60.09 60.7,57.84 60.14,57.84 59.84,57.54 59.84,56.74 59.24,56.14 57.52,56.14 56.01,54.63 53.6,54.63 53.54,54.56 50.81,54.56 50.36,55.01 v2(50.36,55.01)
  BOTTOM w0.089: CPU1.BA47 108.7,61.54 108.49,61.59 108.33,61.59 108.2,61.55 107.7,61.55 107.3,61.94 103.46,61.94 102.97,62.44 102.79,62.44
  BOTTOM w0.152: DM2.128 49.66,54.82 49.85,55.01 v2(50.36,55.01) ; 102.79,62.44 102.62,62.44 102.61,62.45 101.48,62.45 101.47,62.44 99.72,62.44 99.45,62.71 99.45,63.28 v2(99.7,63.53)
M_B_A5: length 72.9
  L6 w0.165: v2(101.71,63.53) 101.9,63.33 101.9,63.32 102.33,62.9 102.33,62.62 101.86,62.15 101.57,62.15 101.08,62.63 97.63,62.63 97.62,62.64 83.16,62.64 79.22,58.69 66.5,58.69 66.21,58.4 62.83,58.4 62.48,58.05 62.48,57.81 62.78,57.51 62.78,57.27 62.55,57.04 62.32,57.04 62.01,57.35 61.77,57.35 61.54,57.11 61.54,56.88 61.85,56.57 61.85,56.34 61.62,56.11 61.38,56.11 61.07,56.41 60.84,56.41 59.95,55.52 59.95,55.11 59.39,54.55 58.86,54.55 58.44,54.96 57.67,54.96 56.36,53.66 54.09,53.66 54.08,53.66 54.05,53.62 53.05,53.62 52.6,53.17 52.6,53.15 v2(52.55,53.1)
  BOTTOM w0.089: CPU1.AY48 108.92,62.28 108.26,62.44 107.82,62.44 107.54,62.72 104.57,62.72 v1(104.39,62.89) 104.21,63.07 104.21,63.68 103.83,64.06 102.21,64.06 101.71,63.56 v2(101.71,63.53)
  BOTTOM w0.152: DM2.126 48.65,55.32 50.01,55.32 50.16,55.47 50.79,55.47 50.81,55.49 51.35,55.49 51.69,55.14 51.69,54.72 52.55,53.86 v2(52.55,53.1)
M_B_A6: length 71.8
  TOP w0.152: v1(53.03,55.59) v2(52.79,55.04)
  L6 w0.165: v2(52.79,55.04) 53.35,55.04 53.49,55.18 55.9,55.18 57.32,56.61 59.04,56.61 59.37,56.94 59.37,58.07 59.61,58.31 60.34,58.31 60.5,58.31 63.05,60.85 63.88,60.85 64.18,60.56 64.54,60.56 64.84,60.85 65.56,60.85 66.3,60.1 66.49,60.1 66.49,60.1 68.83,60.1 69.46,60.73 77.65,60.73 77.82,60.56 77.82,60.28 77.98,60.11 78.31,60.11 78.48,60.28 78.48,60.56 78.64,60.73 79.26,60.73 79.6,61.06 79.6,61.3 79.51,61.38 79.51,61.61 79.74,61.85 79.98,61.85 80.06,61.76 80.3,61.76 80.53,62 80.53,62.23 80.45,62.31 80.45,62.55 80.68,62.78 80.91,62.78 81,62.7 81.23,62.7 81.46,62.93 81.46,63.16 81.38,63.25 81.38,63.48 81.61,63.72 81.85,63.72 81.93,63.63 82.16,63.63 82.58,64.04 83.25,64.04 83.41,64.21 83.41,64.54 83.58,64.7 83.91,64.7 84.07,64.54 84.07,64.21 84.24,64.04 84.57,64.04 84.73,64.21 84.73,64.54 84.9,64.7 85.23,64.7 85.39,64.54 85.39,64.21 85.56,64.04 99.03,64.04 99.07,64.01 102.01,64.01 102.34,63.68 v2(102.34,63.5)
  BOTTOM w0.089: CPU1.BA48 108.28,62.24 108.19,62.26 107.74,62.26 107.5,62.51 104.27,62.51 104.04,62.74 104.04,63.61 103.76,63.89 102.73,63.89 102.35,63.5 v2(102.34,63.5)
  BOTTOM w0.152: v2(52.79,55.04) 52.81,55.03 54,55.03 54.05,55.07 DM2.127
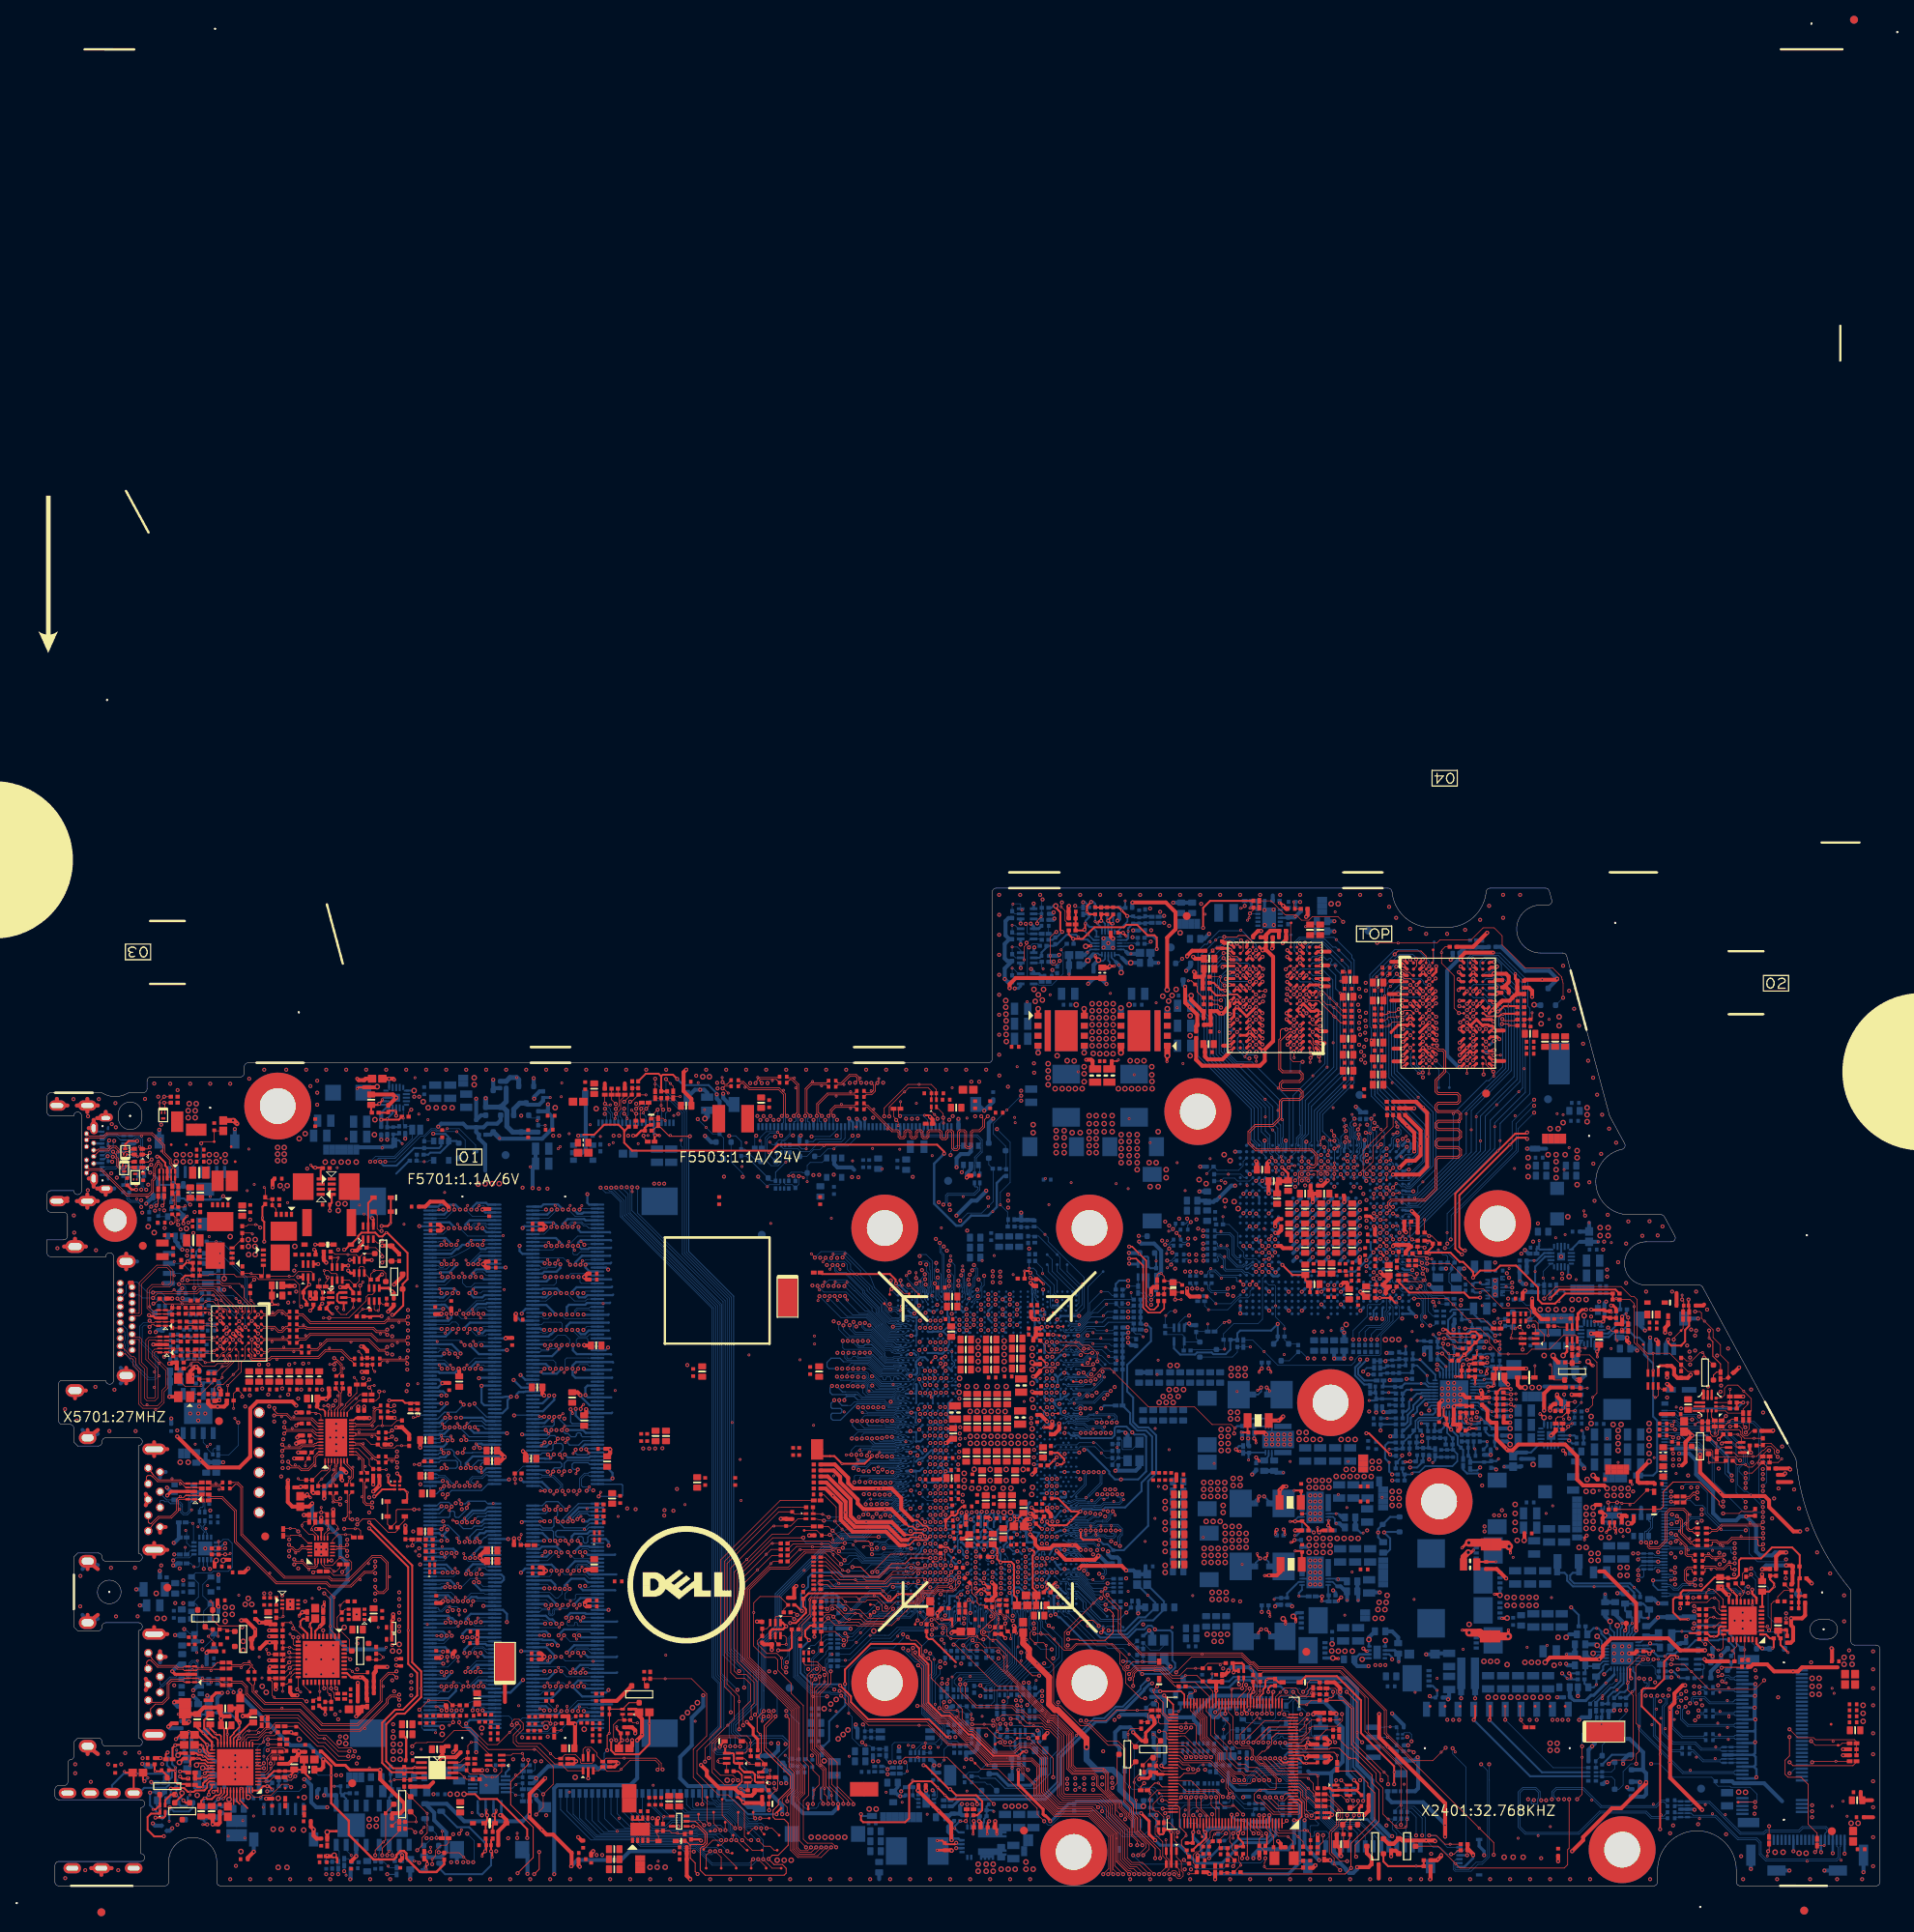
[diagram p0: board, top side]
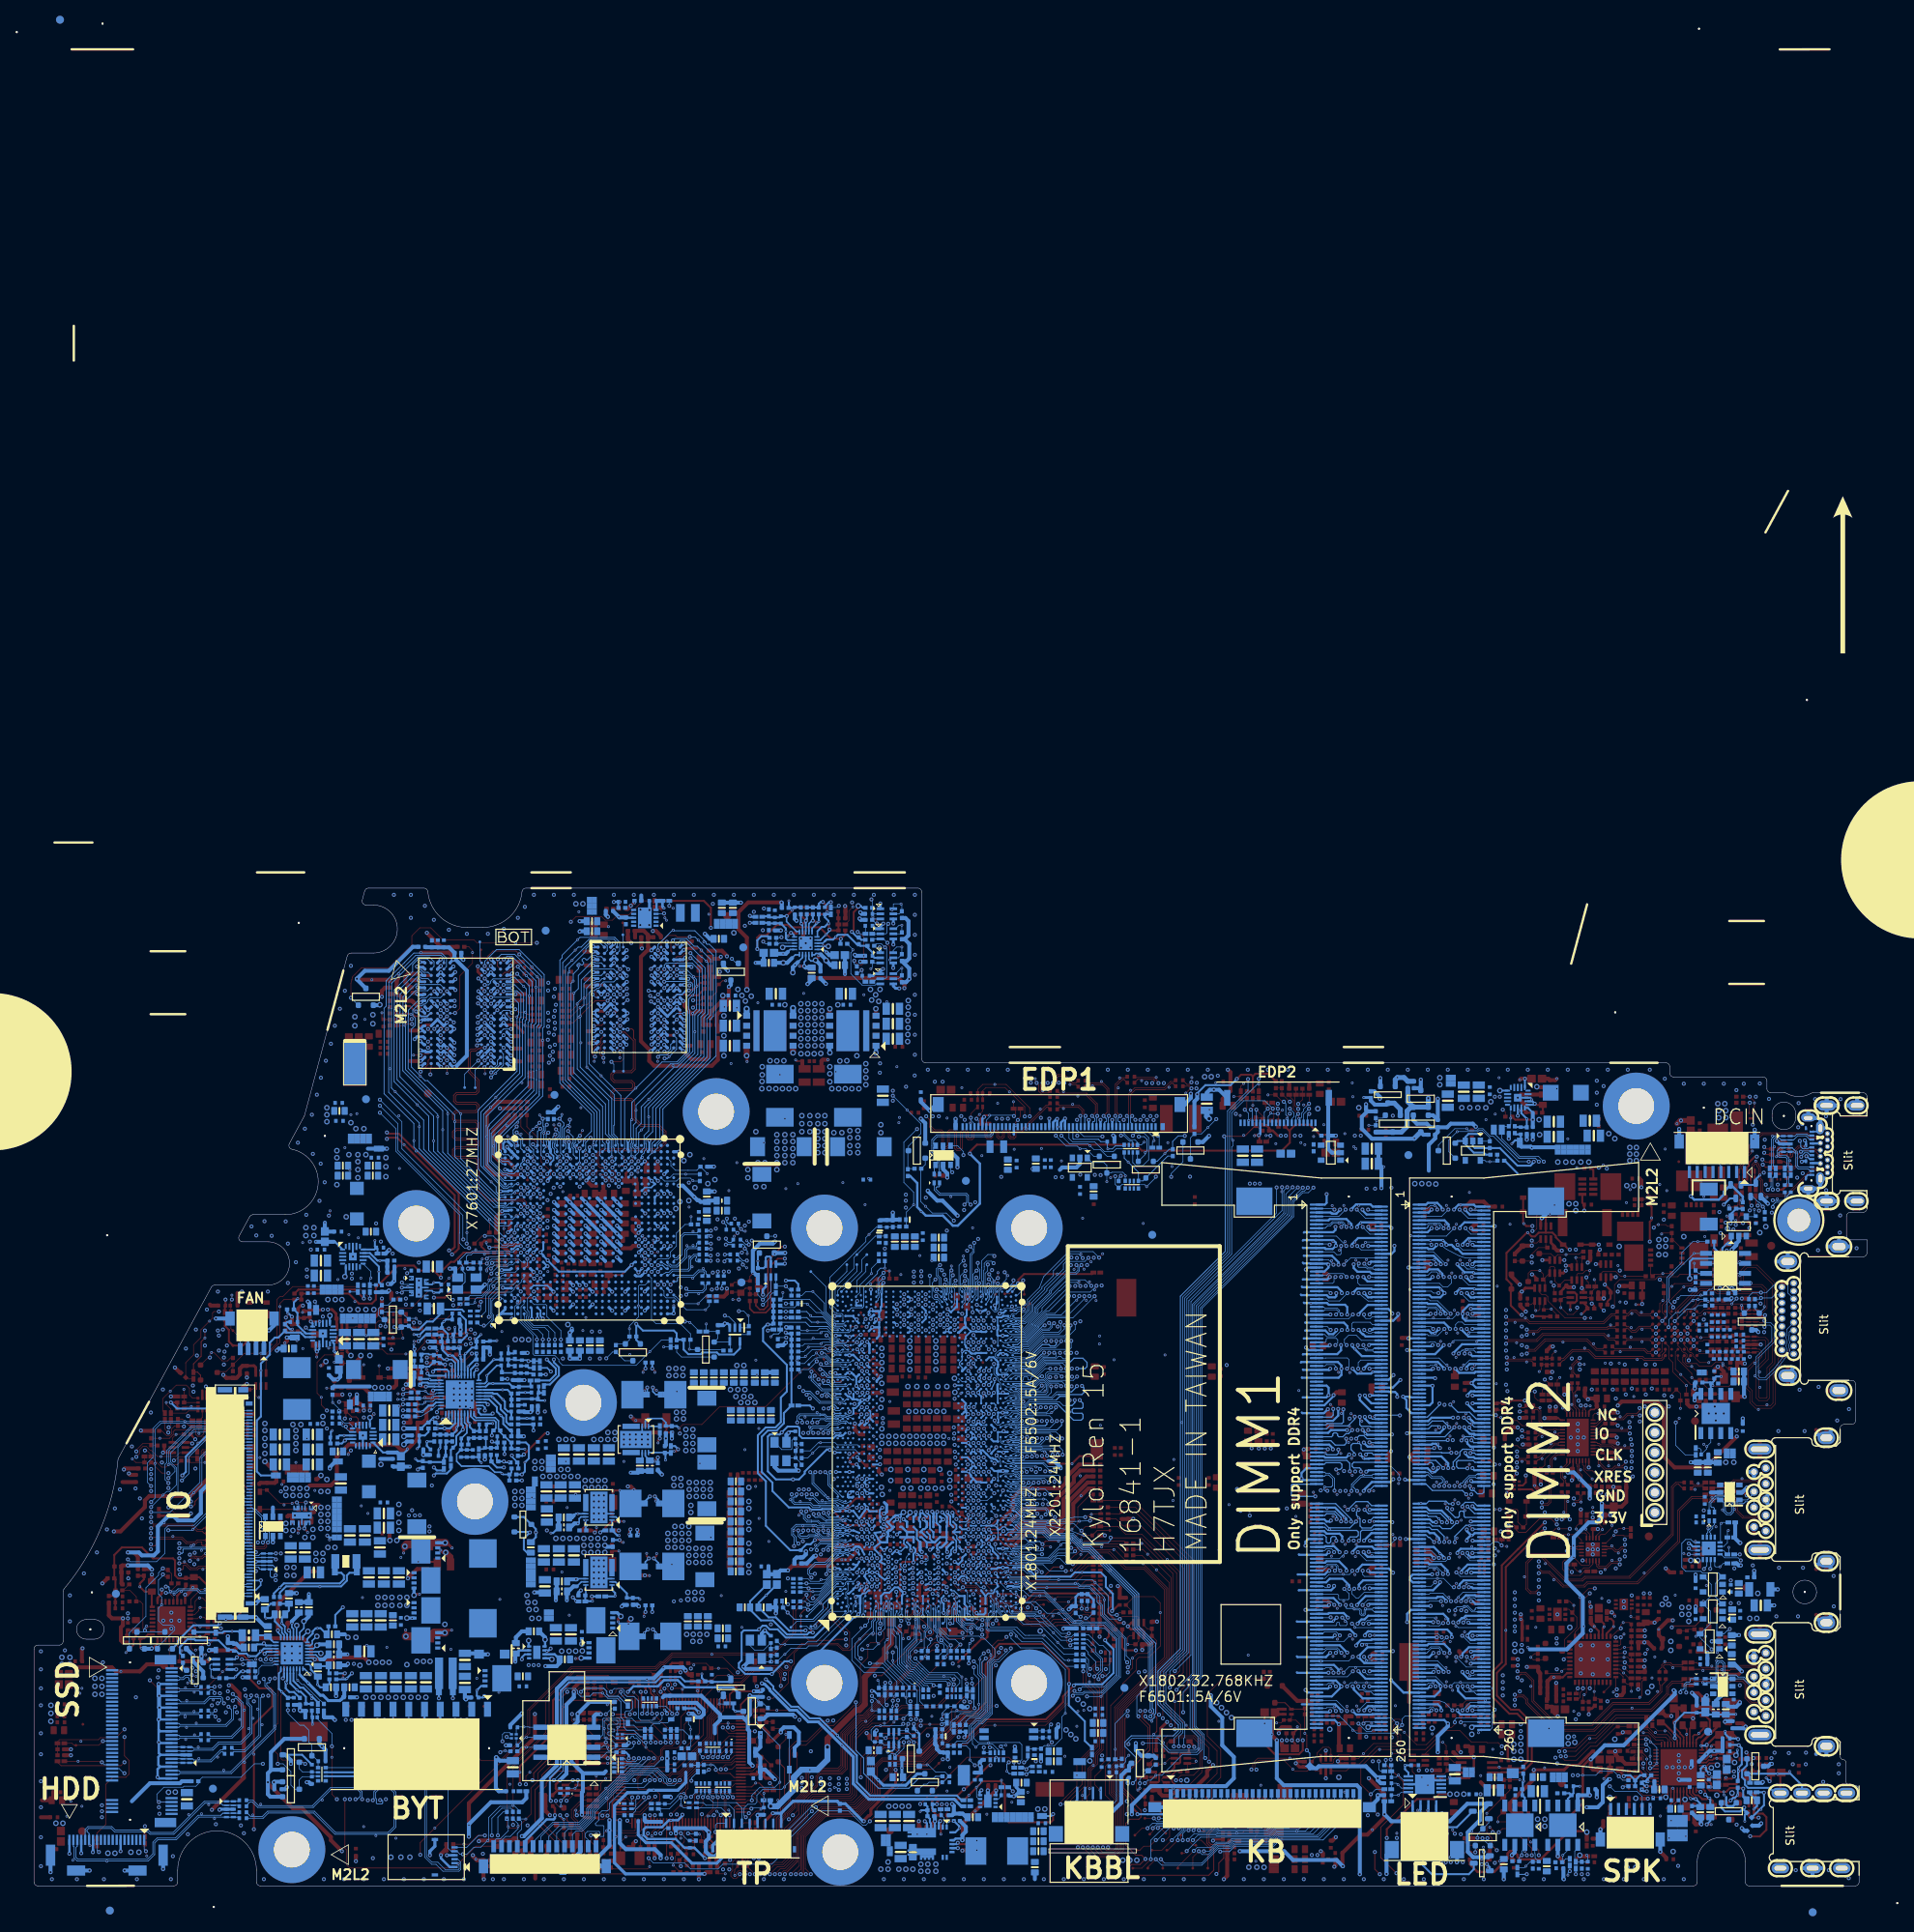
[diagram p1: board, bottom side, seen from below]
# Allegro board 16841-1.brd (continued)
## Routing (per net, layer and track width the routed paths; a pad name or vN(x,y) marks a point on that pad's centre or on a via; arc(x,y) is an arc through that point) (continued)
M_B_A7: length 73.8
  TOP w0.152: v1(50.08,57.21) v2(50.23,56.63)
  L6 w0.102: 109.4,62.39 109.56,62.22 113.07,62.22 v2(113.53,62.68)
  L6 w0.165: v2(50.23,56.63) 50.09,56.49 50.09,55.87 50.29,55.67 50.75,55.67 51.08,56 51.45,56 51.78,55.67 53.59,55.67 54.33,56.41 55.54,56.41 58.38,59.25 60.1,59.25 62.64,61.79 78.26,61.79 81.66,65.19 82.34,65.19 82.8,65.64 99.42,65.64 99.87,65.19 104.99,65.19 105.44,64.74 105.44,63.87 105.94,63.38 108.4,63.38 109.4,62.39
  BOTTOM w0.152: DM2.122 48.65,56.32 49.92,56.32 v2(50.23,56.63) ; CPU1.AP48 v2(113.53,62.68)
M_B_A8: length 69.8
  TOP w0.152: v1(54.48,56.17) v2(54.96,55.65)
  L6 w0.165: v2(103.61,63.47) 103.61,63.49 103.55,63.54 103.55,63.67 102.98,64.24 102.82,64.24 102.79,64.27 99.91,64.27 99.01,65.17 97.56,65.17 97.39,65.01 97.39,64.68 97.23,64.51 96.9,64.51 96.73,64.68 96.73,65.01 96.57,65.17 96.24,65.17 96.07,65.01 96.07,64.68 95.91,64.51 95.58,64.51 95.41,64.68 95.41,65.01 95.25,65.17 94.92,65.17 94.75,65.01 94.75,64.68 94.59,64.51 94.26,64.51 94.09,64.68 94.09,65.01 93.93,65.17 93.6,65.17 93.43,65.01 93.43,64.68 93.27,64.51 92.94,64.51 92.77,64.68 92.77,65.01 92.61,65.17 92.28,65.17 92.11,65.01 92.11,64.68 91.94,64.51 91.61,64.51 91.45,64.68 91.45,65.01 91.28,65.17 90.95,65.17 90.79,65.01 90.79,64.68 90.62,64.51 90.29,64.51 90.13,64.68 90.13,65.01 89.96,65.17 89.63,65.17 89.47,65.01 89.47,64.68 89.3,64.51 88.97,64.51 88.81,64.68 88.81,65.01 88.64,65.17 88.17,65.17 88.01,65.01 88.01,64.71 87.84,64.54 87.51,64.54 87.35,64.71 87.35,65.01 87.18,65.17 86.85,65.17 86.69,65.01 86.69,64.71 86.52,64.54 86.19,64.54 86.03,64.71 86.03,65.01 85.86,65.17 82.99,65.17 82.54,64.72 81.95,64.72 78.55,61.32 62.85,61.32 60.31,58.78 58.57,58.78 55.73,55.94 55.25,55.94 v2(54.96,55.65)
  BOTTOM w0.089: CPU1.BB48 107.72,62.03 107.67,62.09 107.66,62.09 107.45,62.3 104,62.3 103.6,62.69 103.6,63.41 103.61,63.42 v2(103.61,63.47)
  BOTTOM w0.152: v2(54.96,55.65) 55.04,55.57 DM2.125
M_B_A9: length 71.4
  TOP w0.152: v1(52.95,57.16) v2(53.24,56.66)
  L6 w0.089: 107.06,64.27 107.54,63.79 110.79,63.79 111.32,63.26 112.48,63.26 112.83,63.61 v2(112.93,63.61)
  L6 w0.165: 107.06,64.27 104.66,66.67 80.35,66.67 78.61,64.93 78.61,63.54 77.81,62.73 69.6,62.73 69.03,63.3 62.79,63.3 60.21,60.72 58.52,60.72 55.15,57.35 54.07,57.35 54.07,57.34 53.92,57.34 v2(53.24,56.66)
  BOTTOM w0.152: v2(112.93,63.61) 112.94,63.6 112.94,63.45 CPU1.AP50 ; v2(53.24,56.66) 53.32,56.57 DM2.121
M_B_A10: length 71.8
  TOP w0.152: v1(51.07,47.71) v2(51.38,48.2)
  L6 w0.102: v2(106.21,60.83) 106.21,60.74 105.12,59.65 102.92,59.65 102.79,59.52 102.04,59.52 101.38,58.86 101.12,58.86 100.28,58.02 99.42,58.02
  L6 w0.165: v2(51.38,48.2) 51.38,48.16 50.66,47.44 50.66,46.62 50.91,46.38 51.47,46.38 51.6,46.5 51.6,47.07 51.89,47.37 53.69,47.37 53.97,47.65 61.37,47.65 62.41,48.69 62.49,48.76 70.98,48.76 72.54,50.32 73.71,51.49 79.64,51.49 79.64,51.5 80.08,51.5 80.6,52.02 80.6,52.02 85.81,57.23 98.62,57.23 99.42,58.02
  BOTTOM w0.089: v2(106.21,60.83) 106.48,60.56 107.76,60.56 107.78,60.55 107.93,60.4 108.89,60.4 108.98,60.45 109.4,60.45 109.59,60.51 CPU1.AW46
  BOTTOM w0.152: DM2.146 49.52,48.32 49.94,48.74 51.03,48.74 51.38,48.39 51.38,48.21 v2(51.38,48.2)
M_B_A11: length 75
  TOP w0.152: v1(51.3,57.16) v2(51.5,56.62)
  L6 w0.102: 106.73,63.96 107.08,63.61 110.71,63.61 111.25,63.07 112.64,63.07 112.67,63.11 113.77,63.11 v2(114.19,62.69)
  L6 w0.165: v2(51.5,56.62) 51.97,56.14 53.39,56.14 54.13,56.88 55.34,56.88 58.72,60.25 60.41,60.25 62.99,62.83 64.71,62.83 64.87,62.67 64.87,62.44 65.04,62.28 65.37,62.28 65.53,62.44 65.53,62.67 65.69,62.83 66.16,62.83 66.33,62.67 66.33,62.43 66.49,62.26 66.82,62.26 66.99,62.43 66.99,62.67 67.15,62.83 68.84,62.83 69,62.67 69,62.43 69.17,62.26 78,62.26 81.4,65.66 81.61,65.66 82.13,66.18 102.44,66.18 102.46,66.2 104.08,66.2 104.49,65.8 104.89,65.8 106.73,63.96
  BOTTOM w0.152: DM2.120 49.78,56.82 50.04,57.08 51.03,57.08 51.46,56.66 51.46,56.66 v2(51.5,56.62) ; CPU1.AN48 v2(114.19,62.69)
M_B_A12: length 75.8
  TOP w0.152: v1(52.12,58.76) v2(52.41,58.28)
  L6 w0.102: v2(114.18,63.58) 114.55,64.1 114.62,64.33 114.62,64.7 114.27,65.05 113.97,65.05 113.73,65.29 113.73,65.3 112.98,66.05 112.6,66.05 112.27,66.38 111.54,66.38 111.04,65.89 110.77,65.89 110.77,65.89 109.82,65.89
  L6 w0.165: v2(52.41,58.28) 52.42,58.29 52.42,58.33 52.64,58.55 52.74,58.66 53.43,59.35 54.49,59.35 58.36,63.22 60.05,63.22 62.01,65.18 73.99,65.18 77.48,68.67 100.26,68.67 100.39,68.54 104.85,68.54 107.24,66.15 109.15,65.89 109.82,65.89
  BOTTOM w0.152: CPU1.AN50 v2(114.18,63.58) ; v2(52.41,58.28) 52.42,58.27 52.42,58.26 53.6,57.07 DM2.119
M_B_A13: length 70.3
  TOP w0.152: v1(50.46,45.76) v2(50.08,45.32)
  L6 w0.102: 98.23,55.35 98.85,55.35 101.55,58.04 104.37,58.04 105.41,59.09 v2(105.43,59.09)
  L6 w0.165: 98.23,55.35 87.44,55.35 80.53,48.44 73.31,48.44 72.66,47.78 72.66,46.29 72.13,45.76 62.14,45.76 61.5,45.11 53.73,45.11 53.07,44.45 52.6,44.45 52.43,44.61 52.43,45.26 52.27,45.42 51.94,45.42 51.77,45.26 51.77,44.61 51.61,44.45 50.95,44.45 v2(50.08,45.32)
  BOTTOM w0.089: v2(105.43,59.09) 105.91,59.57 107.48,59.57 107.86,59.2 108.2,59.2 108.33,59.23 108.49,59.23 108.64,59.19 CPU1.BA43
  BOTTOM w0.152: v2(50.08,45.32) 50.08,45.32 DM2.158
M_B_A14: length 73.1
  TOP w0.152: v1(54.35,46.65) v2(53.97,46.21)
  L6 w0.102: 99.77,57.06 99.96,57.06 101.35,58.45 102.88,58.45 v2(103.52,59.09)
  L6 w0.165: 99.77,57.06 99,56.29 87.05,56.29 80.14,49.38 79.21,49.38 79.05,49.54 79.05,50.39 78.88,50.55 78.55,50.55 78.39,50.39 78.39,49.54 78.22,49.38 77.89,49.38 77.73,49.54 77.73,50.39 77.56,50.55 77.23,50.55 77.07,50.39 77.07,49.54 76.9,49.38 76.57,49.38 76.4,49.54 76.4,50.39 76.24,50.55 75.91,50.55 75.74,50.39 75.74,49.54 75.58,49.38 75.25,49.38 75.08,49.54 75.08,50.39 74.92,50.55 74.59,50.55 74.42,50.39 74.42,49.54 74.26,49.38 72.93,49.38 71.26,47.71 66.66,47.71 66.29,47.33 62.39,47.33 61.73,46.68 54.43,46.68 v2(53.97,46.21)
  BOTTOM w0.089: CPU1.AY44 108.83,59.33 108.51,59.41 108.3,59.41 108.17,59.37 107.93,59.37 107.55,59.75 103.81,59.75 103.52,59.46 v2(103.52,59.09)
  BOTTOM w0.152: DM2.151 55.83,47.07 55.7,46.94 54.7,46.94 v2(53.97,46.21)
M_B_A15: length 74.2
  TOP w0.152: v1(52.06,44.21) v2(52.34,43.67)
  L6 w0.102: 100.58,55.96 102.05,57.43 106.4,57.43 108.11,59.14 v2(110.79,59.14)
  L6 w0.165: 100.58,55.96 98.56,53.94 88.03,53.94 78.44,44.35 77.61,44.35 77.45,44.19 77.45,43.89 77.28,43.73 76.95,43.73 76.79,43.89 76.79,44.19 76.62,44.35 76.29,44.35 76.13,44.19 76.13,43.89 75.96,43.73 75.63,43.73 75.46,43.89 75.46,44.19 75.3,44.35 62.96,44.35 62.69,44.08 61.75,43.14 52.86,43.14 52.34,43.65 v2(52.34,43.67)
  BOTTOM w0.089: v2(110.79,59.14) 110.79,58.88 110.49,58.58 110.17,58.58 110.16,58.59 CPU1.AY43
  BOTTOM w0.152: v2(52.34,43.67) 52.34,44.41 50.93,45.82 DM2.156
M_B_A16: length 72.8
  TOP w0.152: v1(53.56,48.58) v2(53.31,48.04)
  L6 w0.102: 99.37,58.51 100.5,58.51 101.04,59.05 101.3,59.05 101.96,59.71 102.71,59.71 102.88,59.87 103.61,59.87 103.71,59.98 103.71,60.3 103.81,60.4 104.02,60.4 104.12,60.3 104.12,59.98 104.22,59.87 104.62,59.87 104.92,60.17 v2(104.92,60.82)
  L6 w0.165: 99.37,58.51 98.56,57.7 85.61,57.7 80.41,52.49 79.89,51.97 79.45,51.97 79.44,51.96 73.52,51.96 72.34,50.79 72.34,50.79 71.55,50 69.77,50 69.45,49.67 68.15,49.67 67.99,49.51 67.99,49.4 67.82,49.23 67.49,49.23 67.33,49.4 67.33,49.51 67.16,49.67 66.83,49.67 66.67,49.51 66.67,49.4 66.5,49.23 66.17,49.23 66.01,49.4 66.01,49.51 65.84,49.67 65.51,49.67 65.35,49.51 65.35,49.4 65.18,49.23 64.85,49.23 64.69,49.4 64.69,49.51 64.52,49.67 64.19,49.67 64.03,49.51 64.03,49.4 63.86,49.23 63.53,49.23 63.37,49.4 63.37,49.51 63.2,49.67 62.73,49.67 61.54,48.48 61.51,48.48 61.21,48.18 53.44,48.18 v2(53.31,48.04)
  BOTTOM w0.089: CPU1.AW44 109.65,59.69 109.52,59.83 108.97,59.83 108.58,60.22 107.86,60.22 107.71,60.37 105.4,60.37 104.95,60.82 v2(104.92,60.82)
  BOTTOM w0.152: DM2.152 51.02,46.82 51.17,46.98 51.17,47.47 51.32,47.62 51.63,47.62 51.78,47.47 51.78,46.98 51.93,46.82 52.3,46.82 53.29,47.81 53.29,48.02 v2(53.31,48.04)
M_B_ACT_N: length 72.9
  TOP w0.152: v1(50.92,60.01) v2(51.2,59.5)
  L6 w0.102: v2(114.13,65.46) 113.89,65.7 113.62,65.7 113.08,66.24 113.07,66.24 112.93,66.38 112.54,66.38 112.18,66.75 111.81,66.75 111.81,66.74 110.47,66.74 110.27,66.55 109.67,66.55
  L6 w0.165: v2(51.2,59.5) 51.7,60 54.38,60 58.2,63.82 59.99,63.82 62.36,66.19 74.33,66.19 77.28,69.14 100.26,69.14 100.61,68.8 104.96,68.8 107.21,66.55 109.67,66.55
  BOTTOM w0.152: DM2.114 49.87,58.33 50.32,58.78 50.49,58.78 51.15,59.44 51.15,59.45 v2(51.2,59.5) ; CPU1.AN53 113.8,65.13 v2(114.13,65.46)
M_B_ALERT_N: length 77.6
  TOP w0.152: v1(50.21,58.74) v2(50.5,58.25)
  L6 w0.089: 107.69,64.14 107.85,63.99 111.27,63.99 111.35,64.06 111.68,64.06 111.68,64.06 113.08,64.06 113.96,63.18 114.26,63.18 114.59,62.86 114.59,59.55 114.13,59.09 v2(114.13,59.03)
  L6 w0.165: v2(50.5,58.25) 50.51,58.25 50.95,57.81 53.87,57.81 53.87,57.82 54.95,57.82 58.33,61.19 60.02,61.19 62.6,63.77 69.24,63.77 69.77,63.24 74.82,63.24 76.94,65.37 78.38,65.37 80.16,67.14 99.95,67.14 100.17,66.93 104.91,66.93 107.69,64.14
  BOTTOM w0.152: v2(50.5,58.25) 50.5,58.15 50.18,57.82 DM2.116 ; v2(114.13,59.03) CPU1.AN43
M_B_BA0: length 70.6
  L6 w0.102: v2(103.01,60.82) 102.66,60.82 101.93,60.09 101.78,60.09 101.16,59.47 100.31,59.47 100.18,59.34
  L6 w0.165: v2(50.73,48.21) 50.73,48.91 50.94,49.12 52.17,49.12 52.34,49.28 52.34,49.63 52.5,49.79 52.83,49.79 53,49.63 53,49.28 53.16,49.12 60.82,49.12 62.89,51.19 62.92,51.19 63.38,51.65 67.09,51.65 67.5,51.25 68.06,51.25 68.3,51.48 68.3,52.44 68.76,52.9 69.21,52.9 69.37,52.74 69.37,52.5 69.54,52.34 69.87,52.34 70.03,52.5 70.03,52.74 70.2,52.9 70.53,52.9 70.69,52.74 70.69,52.5 70.86,52.34 71.19,52.34 71.35,52.5 71.35,52.74 71.52,52.9 79.05,52.9 79.06,52.91 79.5,52.91 79.88,53.3 79.88,53.73 80.13,53.98 80.57,53.98 80.82,54.23 80.82,54.67 81.07,54.92 81.5,54.92 81.75,55.17 81.75,55.6 82,55.85 82.44,55.85 82.69,56.1 82.69,56.54 82.94,56.79 83.37,56.79 83.62,57.03 83.62,57.47 83.87,57.72 84.1,57.72 84.31,57.72 85.22,58.63 98.23,58.63 98.94,59.34 100.18,59.34
  BOTTOM w0.089: v2(103.01,60.82) 103.01,60.65 103.51,60.16 v1(103.56,60.16) 103.71,60.01 104.17,60.01 104.2,59.97 107.61,59.97 107.71,59.87 107.85,59.87 CPU1.BB44
  BOTTOM w0.152: DM2.150 49.85,47.32 v2(50.73,48.21)
M_B_BA1: length 72.1
  TOP w0.152: v1(52.34,49.06) v2(52.61,48.54)
  L6 w0.102: 99.55,59.02 100.67,59.02 100.92,59.27 101.25,59.27 101.88,59.9 102.63,59.9 103,60.27 103.1,60.27 v2(103.65,60.82)
  L6 w0.165: 99.55,59.02 99.32,59.02 98.47,58.16 85.42,58.16 80.21,52.96 79.69,52.44 79.25,52.44 79.25,52.43 73.26,52.43 71.55,50.72 71.08,50.72 70.91,50.89 70.91,51.67 70.72,51.87 70.45,51.87 70.25,51.67 70.25,50.89 70.09,50.72 69.56,50.72 69.43,50.86 69.43,51.6 69.22,51.81 68.97,51.81 68.77,51.6 68.77,50.86 68.63,50.72 67.23,50.72 67.06,50.89 67.06,51.01 66.9,51.18 66.57,51.18 66.4,51.01 66.4,50.89 66.24,50.72 65.91,50.72 65.74,50.89 65.74,51.01 65.58,51.18 65.25,51.18 65.08,51.01 65.08,50.89 64.92,50.72 64.59,50.72 64.42,50.89 64.42,51.01 64.26,51.18 63.93,51.18 63.76,51.01 63.76,50.89 63.6,50.72 63.09,50.72 61.01,48.65 52.79,48.65 52.69,48.54 v2(52.61,48.54)
  BOTTOM w0.089: v2(103.65,60.82) 103.65,60.7 104.17,60.18 107.65,60.18 107.79,60.05 108.32,60.05 CPU1.BA44
  BOTTOM w0.152: v2(52.61,48.54) 53.11,48.54 53.46,48.89 55.64,48.89 55.96,48.57 DM2.145
M_B_BG0: length 72.7
  TOP w0.152: v1(54.78,57.92) v2(54.31,58.29)
  L6 w0.102: v2(113.56,64.52) 113.16,64.92 111.81,64.92 111.7,65.03 110.54,65.03 110.29,64.78 110.29,64.5 110.14,64.36 109.32,64.36
  L6 w0.165: 109.32,64.36 108.09,64.36 105.17,67.27 100.22,67.27 99.88,67.61 78.52,67.61 78.16,67.25 78.16,67.01 78.63,66.54 78.63,66.31 78.39,66.08 78.16,66.08 77.69,66.55 77.46,66.55 75.15,64.24 73.59,64.24 73.42,64.08 73.42,63.89 73.26,63.72 72.93,63.72 72.76,63.89 72.76,64.08 72.6,64.24 72.27,64.24 72.1,64.08 72.1,63.89 71.94,63.72 71.61,63.72 71.44,63.89 71.44,64.08 71.28,64.24 70.94,64.24 70.78,64.08 70.78,63.89 70.61,63.72 70.28,63.72 70.12,63.89 70.12,64.08 69.95,64.24 62.4,64.24 59.82,61.66 58.13,61.66 54.76,58.29 v2(54.31,58.29)
  BOTTOM w0.152: CPU1.AP52 113.51,64.52 v2(113.56,64.52) ; DM2.115 55.69,58.07 55.3,58.46 54.49,58.46 v2(54.31,58.29)
M_B_BG1: length 73.1
  TOP w0.152: v1(53.33,58.79) v2(53.04,58.28)
  L6 w0.102: 109.73,65.33 109.73,65.33 109.75,65.36 110.78,65.36 111.57,66.15 112.24,66.15 112.52,65.86 112.9,65.86 113.19,65.57 113.19,65.55 113.89,64.86 113.89,64.84 v2(114.2,64.53)
  L6 w0.165: 109.73,65.33 107.7,65.33 104.84,68.2 78.38,68.2 74.9,64.71 62.21,64.71 60.24,62.75 58.66,62.75 58.59,62.68 58.49,62.68 54.56,58.76 53.5,58.76 53.22,58.47 53.22,58.45 v2(53.04,58.28)
  BOTTOM w0.152: v2(53.04,58.28) 53.22,58.46 53.22,58.47 53.83,59.08 55.2,59.08 55.71,58.57 DM2.113 ; CPU1.AN52 114.14,64.4 114.14,64.47 v2(114.2,64.53)
M_B_CKE0: length 71
  TOP w0.152: v1(113.74,65.88) v2(114.13,66.32)
  L6 w0.102: 108.81,67.11 108.95,67.11 109.07,66.99 110.05,66.99 110.18,67.12 111.65,67.12 111.65,67.13 112.34,67.13 112.66,66.81 112.99,66.81 113.04,66.86 113.64,66.86 114.13,66.37 v2(114.13,66.32)
  L6 w0.165: v2(54.29,61.29) 54.33,61.33 54.33,63.36 54.99,64.01 56.5,64.01 57.34,64.85 58.5,64.85 60.78,67.13 73.95,67.13 76.98,70.17 104.48,70.17 106.3,68.35 107.56,68.35 108.81,67.11
  BOTTOM w0.152: v2(54.29,61.29) 54.31,61.27 54.31,61.09 55.82,59.57 DM2.109 ; v2(114.13,66.32) CPU1.AN56
M_B_CKE1: length 72.5
  TOP w0.152: v1(52.5,61.53) v2(52.92,61.16)
  L6 w0.102: 108.19,67.02 108.53,67.02 108.69,66.87 108.93,66.87 108.99,66.8 110.12,66.8 110.26,66.93 111.73,66.93 111.73,66.94 112.26,66.94 112.58,66.62 113.26,66.62 113.45,66.43 113.47,66.43 v2(113.49,66.41)
  L6 w0.165: 108.19,67.02 107.18,68.03 106.26,68.03 104.59,69.7 77.18,69.7 74.14,66.66 60.98,66.66 58.69,64.38 58.3,64.38 57.61,64.38 54.91,61.68 54.91,61.21 54.31,60.6 53.48,60.6 v2(52.92,61.16)
  BOTTOM w0.152: v2(113.49,66.41) 113.48,66.39 113.48,66.34 CPU1.AP55 ; v2(52.92,61.16) 51.95,60.2 50.48,60.2 49.61,59.32 48.65,59.32 DM2.110
M_B_CLK0: length 75
  TOP w0.102: v1(53.39,51.32) v2(53.68,50.82)
  L6 w0.089: 110.11,61.19 110.11,61.22 110.15,61.27 112.43,61.27 112.8,60.9 112.8,60.03 v2(112.82,60)
  L6 w0.127: 110.11,61.19 109.45,60.54 108.25,60.54 107.74,61.05 107.74,61.71 107.44,62.01 106.88,62.01 106.53,61.65 105.8,61.65 105.51,61.94 105.51,62.12 105.39,62.24 105.13,62.24 105.01,62.12 105.01,61.94 104.72,61.65 102.84,61.65 101.75,60.56 101.26,60.56 100.74,60.04 98.86,60.04 98.45,59.63 84.37,59.63 79.15,54.41 78.64,53.9 66.94,53.9 66.32,53.28 63.57,53.28 63.21,52.92 62.64,52.92 62.45,52.73 62.45,52.16 62.11,51.82 61.55,51.82 61.36,51.63 61.36,51.07 60.4,50.11 58.87,50.11 58.59,50.4 58.59,50.75 58.46,50.88 58.21,50.88 58.08,50.75 58.08,50.4 57.8,50.11 56.76,50.11 56.37,50.5 55.91,50.5 55.53,50.11 54.39,50.11 v2(53.68,50.82)
  BOTTOM w0.102: v2(53.68,50.82) 53.68,51.69 54,52.01 55.2,52.01 55.77,52.57 DM2.137 ; CPU1.AP45 v2(112.82,60)
M_B_CLK1: length 73.9
  TOP w0.102: v1(52.04,51.32) v2(51.7,50.8)
  L6 w0.127: v2(51.7,50.8) 51.62,50.87 51.62,51.27 51.75,51.39 57.22,51.39 58.07,52.25 60.88,52.25 62.68,54.05 65.99,54.05 66.62,54.67 78.32,54.67 84.05,60.41 98.5,60.41 98.63,60.53 100.48,60.53 100.99,61.04 101.55,61.04 103.25,62.74 108.02,62.74 109.01,61.75 113.63,61.75 113.81,61.57 113.81,61.22 v2(113.43,60.85)
  BOTTOM w0.102: v2(113.43,60.85) 113.15,61.13 CPU1.AP46 ; v2(51.7,50.8) 51.7,51.07 51.59,51.18 51.39,51.18 51.27,51.31 51.27,51.4 50.54,52.13 49.73,52.13 49.54,52.32 48.65,52.32 DM2.138
M_B_CLK#0: length 74.9
  TOP w0.102: v1(54.66,51.32) v2(54.34,50.82)
  L6 w0.089: v2(113.5,59.94) 112.99,60.45 112.99,60.98 112.51,61.46 110,61.46 109.88,61.34
  L6 w0.127: 109.88,61.34 109.34,60.81 108.36,60.81 108,61.16 108,61.82 107.55,62.27 106.77,62.27 106.42,61.92 105.91,61.92 105.78,62.05 105.78,62.23 105.5,62.51 105.02,62.51 104.74,62.23 104.74,62.05 104.61,61.92 102.73,61.92 101.64,60.83 101.15,60.83 100.63,60.3 98.75,60.3 98.34,59.9 84.26,59.9 79.04,54.67 79.03,54.67 78.53,54.16 66.83,54.16 66.21,53.54 63.46,53.54 63.1,53.18 62.53,53.18 62.19,52.84 62.19,52.27 62,52.09 61.44,52.09 61.09,51.74 61.09,51.18 60.29,50.38 58.98,50.38 58.86,50.51 58.86,50.86 58.57,51.14 58.1,51.14 57.82,50.86 57.82,50.51 57.69,50.38 56.87,50.38 56.48,50.77 55.8,50.77 55.42,50.38 54.5,50.38 54.34,50.54 v2(54.34,50.82)
  BOTTOM w0.102: v2(54.34,50.82) 54.35,50.83 54.35,51.06 54.22,51.19 54.02,51.19 53.91,51.3 53.91,51.59 54.09,51.78 55.29,51.78 55.75,52.23 55.93,52.23 56.08,52.07 DM2.139 ; CPU1.AN45 v2(113.5,59.94)
M_B_CLK#1: length 73.9
  TOP w0.102: v1(50.82,51.35) v2(51.06,50.81)
  L6 w0.127: v2(114.08,60.84) 114.08,61.68 113.74,62.02 109.12,62.02 108.13,63.01 103.14,63.01 101.44,61.31 100.88,61.31 100.37,60.8 98.52,60.8 98.39,60.67 83.94,60.67 78.21,54.94 66.51,54.94 65.88,54.32 62.57,54.32 60.77,52.51 57.96,52.51 57.1,51.66 51.64,51.66 51.36,51.38 51.36,51.11 v2(51.06,50.81)
  BOTTOM w0.102: DM2.140 49.62,51.82 49.7,51.9 50.44,51.9 51.04,51.31 51.04,51.15 v2(51.06,50.81) ; CPU1.AN46 v2(114.08,60.84)
M_B_CS#0: length 72.7
  TOP w0.152: v1(53.03,46.72) v2(53.34,46.19)
  L6 w0.102: v2(104.16,59.09) 104.16,58.56 103.84,58.25 101.43,58.25 99,55.82
  L6 w0.165: 99,55.82 87.25,55.82 80.34,48.91 73.12,48.91 72.19,47.97 72.19,47.49 71.93,47.24 71,47.24 70.83,47.07 70.83,46.4 70.67,46.23 70.34,46.23 70.17,46.4 70.17,47.07 70.01,47.24 69.54,47.24 69.37,47.07 69.37,46.4 69.21,46.23 68.88,46.23 68.71,46.4 68.71,47.07 68.55,47.24 66.85,47.24 66.48,46.87 62.58,46.87 61.3,45.58 59.79,45.58 59.62,45.75 59.62,46.04 59.46,46.21 59.13,46.21 58.96,46.04 58.96,45.75 58.8,45.58 58.47,45.58 58.3,45.75 58.3,46.04 58.14,46.21 57.81,46.21 57.64,46.04 57.64,45.75 57.48,45.58 57.15,45.58 56.98,45.75 56.98,46.04 56.82,46.21 56.49,46.21 56.32,46.04 56.32,45.75 56.16,45.58 53.58,45.58 53.34,45.83 v2(53.34,46.19)
  BOTTOM w0.089: 106.03,58.48 106.42,58.48 106.55,58.34 107.9,58.34 107.93,58.31 CPU1.BB42
  BOTTOM w0.152: v2(104.16,59.09) 104.16,58.66 104.34,58.48 106.03,58.48 ; v2(53.34,46.19) 53.36,46.21 53.36,46.53 54.18,47.34 55.71,47.34 55.94,47.57 DM2.149
M_B_CS#1: length 75
  TOP w0.152: v1(53.33,44.23) v2(53.68,43.7)
  L6 w0.102: 98.03,54.88 98.71,54.88 101.67,57.84 105.71,57.84 106.06,58.19 v2(106.06,59.09)
  L6 w0.165: 98.03,54.88 87.64,54.88 79.28,46.52 78.26,46.52 77.87,46.92 77.87,47.78 77.74,47.91 76.96,47.91 76.8,47.74 76.8,47.46 76.63,47.3 76.3,47.3 76.14,47.46 76.14,47.74 75.97,47.91 75.5,47.91 74.77,47.18 74.77,45.42 74.65,45.29 74.18,45.29 74.01,45.46 74.01,46.88 73.85,47.05 73.52,47.05 73.35,46.88 73.35,45.46 73.19,45.29 62.57,45.29 61.92,44.64 53.93,44.64 53.7,44.41 53.7,43.72 v2(53.68,43.7)
  BOTTOM w0.089: CPU1.AY42 108.93,58.54 108.83,58.57 108.65,58.57 108.45,58.51 108.32,58.51 108.19,58.57 107.79,58.57 107.74,58.52 106.63,58.52 v2(106.06,59.09)
  BOTTOM w0.152: v2(53.68,43.7) 53.7,43.72 53.7,44.4 54.58,45.29 55.28,45.29 55.57,45.57 DM2.157
M_B_DIMB_ODT0: length 72.8
  TOP w0.152: v1(51.53,46.47) v2(52.07,46.21)
  L6 w0.102: v2(102.89,59.09) 102.45,58.65 101.24,58.65 100.12,57.53 99.61,57.53
  L6 w0.165: v2(52.07,46.21) 52.07,46.76 52.21,46.9 53.89,46.9 54.17,47.18 61.57,47.18 62.68,48.29 71.18,48.29 72.73,49.85 72.73,49.85 73.91,51.02 79.83,51.02 79.84,51.03 80.3,51.03 81.22,51.95 81.45,51.95 81.63,51.77 81.87,51.77 82.1,52 82.1,52.24 81.92,52.42 81.92,52.65 82.15,52.89 82.39,52.89 82.57,52.7 82.8,52.7 83.03,52.94 83.03,53.17 82.85,53.35 82.85,53.59 83.09,53.82 83.32,53.82 83.5,53.64 83.74,53.64 83.97,53.87 83.97,54.1 83.79,54.29 83.79,54.52 84.02,54.75 84.25,54.75 84.44,54.57 84.67,54.57 84.9,54.81 84.9,55.04 84.72,55.22 84.72,55.45 84.95,55.69 85.19,55.69 85.37,55.51 85.6,55.51 85.84,55.74 85.84,55.97 85.66,56.16 85.66,56.39 86.02,56.76 98.84,56.76 99.61,57.53
  BOTTOM w0.102: CPU1.BA42 108.27,58.04 107.93,58.04 107.92,58.05 107.88,58.05 107.78,58.15 103.82,58.15 v2(102.89,59.09)
  BOTTOM w0.152: DM2.155 55.53,46.07 55.19,45.73 54.26,45.73 53.93,45.4 52.87,45.4 52.12,46.15 52.12,46.16 v2(52.07,46.21)
M_B_DIMB_ODT1: length 73.9
  TOP w0.152: v1(54.6,44.21) v2(54.97,43.69)
  L6 w0.102: v2(106.7,59.12) 106.7,58.27 106.06,57.64 101.8,57.64 98.57,54.41 98.03,54.41
  L6 w0.165: 98.03,54.41 87.83,54.41 78.25,44.82 77.4,44.82 77.23,44.99 77.23,46.66 77.07,46.83 76.74,46.83 76.57,46.66 76.57,44.99 76.41,44.82 76.08,44.82 75.91,44.99 75.91,46.66 75.75,46.83 75.41,46.83 75.25,46.66 75.25,44.99 75.08,44.82 62.76,44.82 61.55,43.61 57.97,43.61 57.81,43.78 57.81,44.01 57.64,44.17 57.31,44.17 57.15,44.01 57.15,43.78 56.98,43.61 56.51,43.61 56.35,43.78 56.35,44.01 56.18,44.17 55.85,44.17 55.68,44.01 55.68,43.78 55.52,43.61 55.04,43.61 v2(54.97,43.69)
  BOTTOM w0.089: v2(106.7,59.12) 107.12,58.7 107.64,58.7 107.69,58.75 108.23,58.75 108.31,58.71 108.49,58.71 108.59,58.74 108.68,58.76 108.86,58.75 108.94,58.72 109.41,58.61 CPU1.AW42
  BOTTOM w0.152: v2(54.97,43.69) 55.57,44.3 55.7,44.3 55.98,44.57 DM2.161
M_B_DQ0: length 80.4
  TOP w0.089: v1(53.84,82.03) v2(54.04,81.47)
  L6 w0.102: v2(117.71,71.29) 117.95,71.53 118.16,71.87 118.22,72.16 118.31,72.24 118.31,72.91 118.11,73.34 116.59,74.86 114.35,75.83 114.09,76.08 114.09,78.19 113.65,79.52 112.03,81.14 110.25,81.14 109.27,80.96 105.97,80.96 104.95,81.27 102.88,83.33 94.87,83.33 92.79,81.25 69.08,81.25 68.42,81.91 63.59,81.91 62.86,81.73 61.75,81.26 60.36,80.91 59.79,80.91 59.34,81.03 54.58,81.03 54.38,81.13 v2(54.04,81.47)
  BOTTOM w0.089: DM2.28 51.01,79.82 51.46,79.94 51.82,80.08 53.41,80.92 53.71,81.14 v2(54.04,81.47) ; CPU1.AF65 v2(117.71,71.29)
M_B_DQ1: length 78.5
  TOP w0.089: v2(54.76,79.01) 54.96,79.43 v1(54.96,79.56)
  L6 w0.102: v2(54.76,79.01) 54.76,79.31 54.63,79.44 53.92,79.44 53.82,79.54 53.82,79.94 53.92,80.04 55.32,80.04 55.43,79.94 55.43,79.81 55.53,79.7 55.73,79.7 55.83,79.81 55.83,79.94 55.93,80.04 56.14,80.04 56.24,79.94 56.24,79.81 56.34,79.7 56.54,79.7 56.64,79.81 56.64,79.94 56.75,80.04 57.08,80.04 57.16,79.95 57.16,79.83 57.26,79.73 57.47,79.73 57.57,79.83 57.57,79.95 57.66,80.04 57.89,80.04 57.98,79.95 57.98,79.83 58.08,79.73 58.28,79.73 58.38,79.83 58.38,79.95 58.47,80.04 58.7,80.04 58.79,79.95 58.79,79.83 58.9,79.72 61.71,79.72 62.16,80.16 93.1,80.16 95.28,82.34 102.47,82.34 104.92,79.89 109.55,79.89 110.74,78.7 111.29,78.7 111.94,78.06 111.94,76.81 112.65,76.1 113.21,76.1 115.19,74.12 116.52,74.12 117.2,73.44 117.2,71.69 v2(116.8,71.29)
  BOTTOM w0.089: v2(54.76,79.01) 54.76,79.3 55.03,79.57 56.85,79.57 DM2.29 ; CPU1.AF64 v2(116.8,71.29)
M_B_DQ2: length 78.9
  TOP w0.089: v1(52.73,77.89) v2(53.03,77.39)
  L6 w0.102: v2(115.88,71.29) 115.26,71.29 115.08,71.47 115.08,72.08 115.31,72.31 115.31,72.87 115.08,73.1 114.77,73.1 112.8,75.07 112.8,75.07 112.78,75.09 110.92,75.09 110.34,75.67 109.24,75.67 108.8,76.12 108.8,76.78 108.8,76.79 108.8,77.31 108.19,77.92 104.59,77.92 101.89,80.62 95.86,80.62 93.78,78.54 72.67,78.54 71.68,77.56 68.66,77.56 68.4,77.82 68.26,77.82 63.06,77.82 62.34,77.1 59.69,77.1 59.59,77.2 59.59,77.64 59.49,77.75 59.29,77.75 59.18,77.64 59.18,77.2 59.08,77.1 55.96,77.1 55.48,76.62 54.39,76.62 54.28,76.73 54.28,76.84 54.18,76.94 53.98,76.94 53.88,76.84 53.88,76.73 53.78,76.62 53.45,76.62 53.03,77.04 v2(53.03,77.39)
  BOTTOM w0.089: v2(53.03,77.39) 52.77,77.12 52.77,76.59 53.25,76.11 53.83,76.11 54.29,76.57 56.85,76.57 DM2.41 ; CPU1.AK65 v2(115.88,71.29)
M_B_DQ3: length 80.1
  TOP w0.089: v1(51.3,77.89) v2(51.61,77.39)
  L6 w0.102: v2(115.88,70.64) 116.29,71.04 116.29,72.11 115.7,72.7 115.7,73.02 115.23,73.49 114.93,73.49 112.96,75.46 112.95,75.46 112.94,75.47 111.1,75.47 110.44,76.13 110.22,76.13 109.32,77.02 109.32,77.45 108.33,78.45 105,78.45 102.16,81.29 95.59,81.29 93.5,79.2 70.7,79.2 70.6,79.1 70.6,78.32 70.49,78.22 70.29,78.22 70.19,78.32 70.19,78.92 70.07,79.04 69.9,79.04 69.78,78.92 69.78,78.63 69.63,78.48 62.92,78.48 62.66,78.74 59.1,78.74 58.51,78.15 57.8,78.15 57.7,78.25 57.7,78.63 57.6,78.73 57.4,78.73 57.29,78.63 57.29,78.25 57.19,78.15 56.03,78.15 55.7,77.82 52.84,77.82 52.48,78.17 51.83,78.17 51.61,77.96 v2(51.61,77.39)
  BOTTOM w0.089: v2(51.61,77.39) 50.57,76.34 49.66,76.34 49.64,76.32 DM2.42 ; CPU1.AK64 v2(115.88,70.64)
M_B_DQ4: length 79.6
  TOP w0.089: v1(52.19,82) v2(51.99,81.47)
  L6 w0.102: v2(117.71,71.94) 118.12,72.34 118.12,72.82 117.9,73.03 117.9,73.28 116.61,74.58 115.33,74.58 113.76,76.14 113.76,78.11 113.36,78.51 113.36,79.34 111.89,80.81 110.38,80.81 110.2,80.63 105.12,80.63 102.75,83 95.01,83 92.83,80.82 61.78,80.82 61.33,80.38 59.35,80.38 59.03,80.7 52.76,80.7 v2(51.99,81.47)
  BOTTOM w0.089: CPU1.AF66 v2(117.71,71.94) ; DM2.24 51.35,80.82 v2(51.99,81.47)
M_B_DQ5: length 78.8
  TOP w0.089: v1(53.21,79.51) v2(53.49,79.01)
  L6 w0.102: v2(53.49,79.01) 53.49,80.15 53.71,80.37 58.9,80.37 59.22,80.05 61.47,80.05 61.91,80.49 92.97,80.49 95.14,82.67 102.61,82.67 105.05,80.22 110.29,80.22 110.55,80.48 111.69,80.48 112.45,79.71 112.45,78.88 112.14,78.56 112.14,78.12 112.48,77.78 113.23,77.78 113.54,77.47 113.54,76.04 115.23,74.36 116.56,74.36 117.71,73.2 v2(117.71,72.59)
  BOTTOM w0.089: v2(117.71,72.59) CPU1.AF67 ; v2(53.49,79.01) 55.06,80.57 56.85,80.57 DM2.25
M_B_DQ6: length 77.1
  TOP w0.089: v1(49.93,77.91) v2(50.19,77.39)
  L6 w0.102: v2(114.91,72.7) 114.91,72.32 114.71,72.13 114.23,72.13 114.05,72.31 114.05,73.11 113.64,73.52 113.64,73.97 112.72,74.88 110.84,74.88 110.28,75.44 108.89,75.44 108.25,76.08 107.61,76.08 107.14,76.55 107,76.55 106.68,76.87 106.68,76.88 106.39,77.17 104.88,77.17 101.75,80.29 96,80.29 93.92,78.21 72.8,78.21 71.82,77.23 68.93,77.23 68.47,76.77 56.1,76.77 55.62,76.29 53.01,76.29 52.91,76.39 52.91,76.7 52.8,76.8 52.6,76.8 52.5,76.7 52.5,76.39 52.4,76.29 52.19,76.29 52.09,76.39 52.09,76.74 51.99,76.84 51.79,76.84 51.69,76.74 51.69,76.39 51.58,76.29 51.38,76.29 51.28,76.39 51.28,76.74 51.18,76.84 50.97,76.84 50.87,76.74 50.87,76.39 50.77,76.29 50.44,76.29 50.19,76.55 v2(50.19,77.39)
  BOTTOM w0.089: CPU1.AK67 v2(114.91,72.7) ; v2(50.19,77.39) 50.13,77.32 DM2.38
M_B_DQ7: length 78.2
  TOP w0.089: v1(54.17,77.89) v2(54.46,77.39)
  L6 w0.102: v2(54.46,77.39) 54.46,77.15 54.65,76.95 55.35,76.95 55.6,77.21 55.6,77.25 56.17,77.82 56.76,77.82 56.87,77.72 56.87,77.53 56.97,77.43 57.17,77.43 57.27,77.53 57.27,77.72 57.37,77.82 57.7,77.82 57.8,77.72 57.8,77.53 57.91,77.43 58.11,77.43 58.21,77.53 58.21,77.72 58.31,77.82 58.64,77.82 58.97,78.15 59.92,78.15 60.02,78.05 60.02,77.53 60.12,77.43 60.45,77.43 60.56,77.53 60.56,78.31 60.66,78.41 60.86,78.41 60.96,78.31 60.96,77.53 61.06,77.43 61.27,77.43 61.37,77.53 61.37,78.31 61.47,78.41 61.67,78.41 61.77,78.31 61.77,77.53 61.88,77.43 62.21,77.43 62.92,78.15 68.4,78.15 68.53,78.15 68.79,77.89 71.55,77.89 72.53,78.87 93.64,78.87 95.73,80.95 102.03,80.95 104.86,78.12 108.39,78.12 108.99,77.51 108.99,76.71 108.99,76.7 108.99,76.19 109.31,75.87 110.41,75.87 111.01,75.28 112.86,75.28 112.87,75.27 112.88,75.27 114.85,73.3 115.16,73.3 115.5,72.95 115.5,72.31 v2(115.88,71.94)
  BOTTOM w0.089: v2(54.46,77.39) 54.46,77.83 54.66,78.03 55.33,78.03 55.78,77.57 56.85,77.57 DM2.37 ; CPU1.AK66 v2(115.88,71.94)
M_B_DQ8: length 82.1
  TOP w0.089: v1(51.61,86.52) v2(51.74,85.95)
  L6 w0.102: v2(51.74,85.95) 52.5,85.18 92.91,85.18 94,86.28 102.11,86.28 104.36,88.53 108.44,88.53 109.19,87.77 110.59,87.77 118.51,79.85 118.51,78.14 118.31,77.93 v2(118.31,77.07)
  BOTTOM w0.089: CPU1.AF70 118.06,75.37 118.32,75.37 118.55,75.6 118.55,75.93 118.54,75.94 118.54,76.15 118.7,76.31 118.7,76.63 v2(118.31,77.07) ; DM2.8 50.62,84.82 v2(51.74,85.95)
M_B_DQ9: length 83.6
  TOP w0.089: v1(53.41,86.47) v2(53.16,85.95)
  L6 w0.102: v2(119.02,77.54) 119.17,77.69 119.17,80.12 110.86,88.44 109.47,88.44 108.72,89.19 104.08,89.19 101.83,86.94 93.73,86.94 92.66,85.87 83.61,85.87 83.1,86.38 53.59,86.38 v2(53.16,85.95)
  BOTTOM w0.089: CPU1.AF68 117.76,74.02 117.76,74.04 117.8,74.07 117.8,74.07 117.8,74.28 118.04,74.52 118.43,74.52 118.74,74.83 118.74,76.05 119.02,76.33 119.02,77.54 v2(119.02,77.54) ; DM2.7 54.03,85.07 v2(53.16,85.95)
M_B_DQ10: length 80.7
  TOP w0.089: v1(50.46,81.98) v2(50.72,81.47)
  L6 w0.102: v2(50.72,81.47) 51.69,82.44 60.78,82.44 60.91,82.57 81.46,82.57 81.56,82.47 81.56,82.31 81.66,82.21 81.86,82.21 81.97,82.31 81.97,82.47 82.07,82.57 82.4,82.57 82.5,82.47 82.5,82.3 82.6,82.2 82.8,82.2 82.91,82.3 82.91,82.47 83.01,82.57 83.21,82.57 83.31,82.47 83.31,82.3 83.41,82.2 83.62,82.2 83.72,82.3 83.72,82.47 83.82,82.57 84.02,82.57 84.13,82.47 84.13,82.3 84.23,82.2 84.43,82.2 84.53,82.3 84.53,82.47 84.63,82.57 84.84,82.57 84.94,82.47 84.94,82.3 85.04,82.2 85.24,82.2 85.34,82.3 85.34,82.47 85.45,82.57 85.65,82.57 85.75,82.47 85.75,82.3 85.85,82.2 86.06,82.2 86.16,82.3 86.16,82.47 86.26,82.57 86.59,82.57 86.69,82.47 86.69,82.3 86.79,82.2 87,82.2 87.1,82.3 87.1,82.47 87.2,82.57 93.18,82.57 94.79,84.18 102.78,84.18 105.17,86.57 107.63,86.57 113.91,80.29 114.97,80.29 115.57,79.7 115.57,78.14 v2(116.1,77.6)
  BOTTOM w0.089: v2(116.1,77.6) 116.32,77.16 116.32,76.04 116.23,75.95 CPU1.AH71 ; DM2.20 49.73,81.82 49.8,81.89 50.26,81.89 50.69,81.47 v2(50.72,81.47)
M_B_DQ11: length 83.5
  TOP w0.089: v1(55.44,82.03) v2(55.31,81.47)
  L6 w0.102: v2(115.75,76.91) 115.24,77.43 115.24,79.56 114.86,79.94 113.8,79.94 107.49,86.24 105.31,86.24 102.91,83.85 94.92,83.85 92.94,81.87 81.24,81.87 81.13,81.97 81.13,82.14 81.03,82.24 80.83,82.24 80.73,82.14 80.73,81.97 80.63,81.87 80.42,81.87 80.32,81.97 80.32,82.14 80.22,82.24 80.02,82.24 79.92,82.14 79.92,81.97 79.81,81.87 79.48,81.87 79.38,81.97 79.38,82.14 79.28,82.24 79.08,82.24 78.98,82.14 78.98,81.97 78.87,81.87 78.67,81.87 78.57,81.97 78.57,82.14 78.47,82.24 78.26,82.24 78.16,82.14 78.16,81.97 78.06,81.87 77.86,81.87 77.76,81.97 77.76,82.14 77.66,82.24 77.45,82.24 77.35,82.14 77.35,81.97 77.25,81.87 76.92,81.87 76.82,81.97 76.82,82.14 76.72,82.24 76.51,82.24 76.41,82.14 76.41,81.97 76.31,81.87 76.11,81.87 76,81.97 76,82.14 75.9,82.24 75.7,82.24 75.6,82.14 75.6,81.97 75.5,81.87 75.29,81.87 75.19,81.97 75.19,82.14 75.09,82.24 74.89,82.24 74.78,82.14 74.78,81.97 74.68,81.87 74.35,81.87 74.25,81.97 74.25,82.14 74.15,82.24 73.95,82.24 73.85,82.14 73.85,81.97 73.74,81.87 73.54,81.87 73.44,81.97 73.44,82.14 73.34,82.24 73.13,82.24 73.03,82.14 73.03,81.97 72.93,81.87 72.73,81.87 72.63,81.97 72.63,82.14 72.52,82.24 72.32,82.24 72.22,82.14 72.22,81.97 72.12,81.87 71.79,81.87 71.69,81.97 71.69,82.14 71.58,82.24 71.38,82.24 71.28,82.14 71.28,81.97 71.18,81.87 70.97,81.87 70.87,81.97 70.87,82.14 70.77,82.24 70.57,82.24 70.47,82.14 70.47,81.97 70.37,81.87 70.16,81.87 70.06,81.97 70.06,82.14 69.96,82.24 69.76,82.24 69.65,82.14 69.65,81.97 69.55,81.87 69.22,81.87 68.85,82.24 61.24,82.24 61.11,82.11 60.07,82.11 59.63,81.67 59.3,81.67 59.2,81.77 59.2,82.01 59.1,82.11 58.89,82.11 58.79,82.01 58.79,81.77 58.69,81.67 58.49,81.67 58.38,81.77 58.38,82.01 58.28,82.11 58.08,82.11 57.98,82.01 57.98,81.77 57.88,81.67 57.67,81.67 57.57,81.77 57.57,82.01 57.47,82.11 57.27,82.11 57.16,82.01 57.16,81.77 57.06,81.67 56.86,81.67 56.76,81.77 56.76,82.01 56.66,82.11 56.45,82.11 56.35,82.01 56.35,81.77 56.25,81.67 55.51,81.67 v2(55.31,81.47)
  BOTTOM w0.089: v2(115.75,76.91) 115.75,76.84 116.14,76.44 116.14,76.11 115.86,75.83 115.86,74.1 115.83,74.07 CPU1.AH68 ; v2(55.31,81.47) 55.41,81.57 56.85,81.57 DM2.21
M_B_DQ12: length 80.7
  TOP w0.089: v1(49.75,85.91) v2(50.32,85.95)
  L6 w0.102: v2(50.32,85.95) 50.32,85.33 50.79,84.85 93.04,84.85 94.14,85.95 102.24,85.95 104.49,88.2 108.31,88.2 109.06,87.44 110.45,87.44 118.18,79.71 118.18,78.64 117.75,77.47 117.75,76.16 v2(118.15,75.77)
  BOTTOM w0.089: v2(50.32,85.95) 50.2,85.82 DM2.4 ; CPU1.AF71 v2(118.15,75.77)
M_B_DQ13: length 82.4
  TOP w0.089: v1(54.88,86.45) v2(54.58,85.95)
  L6 w0.102: v2(118.23,74.95) 118.23,74.96 118.72,75.44 118.72,77.24 118.61,77.34 118.61,77.71 118.84,77.94 118.84,79.99 110.72,88.1 109.33,88.1 108.58,88.86 104.22,88.86 101.97,86.61 93.86,86.61 92.77,85.51 74.27,85.51 74.17,85.62 74.17,85.92 74.07,86.02 73.86,86.02 73.76,85.92 73.76,85.62 73.66,85.51 73.46,85.51 73.36,85.62 73.36,85.92 73.26,86.02 73.05,86.02 72.95,85.92 72.95,85.62 72.85,85.51 72.65,85.51 72.54,85.62 72.54,85.92 72.44,86.02 72.24,86.02 72.14,85.92 72.14,85.62 72.04,85.51 71.83,85.51 71.73,85.62 71.73,85.92 71.63,86.02 71.43,86.02 71.32,85.92 71.32,85.62 71.22,85.51 55.01,85.51 v2(54.58,85.95)
  BOTTOM w0.089: DM2.3 55.82,86.07 55.45,86.44 54.78,86.44 54.58,86.24 v2(54.58,85.95) ; v2(118.23,74.95) 118.02,74.74 117.95,74.74 117.46,74.26 CPU1.AF69
M_B_DQ14: length 81.2
  L6 w0.102: v2(50.99,83.58) 51.76,82.8 60.67,82.8 60.77,82.9 68.78,82.9 68.88,83 68.88,83.17 68.98,83.28 69.18,83.28 69.28,83.17 69.28,83 69.39,82.9 69.59,82.9 69.69,83 69.69,83.17 69.79,83.28 70,83.28 70.1,83.17 70.1,83 70.2,82.9 70.4,82.9 70.5,83 70.5,83.17 70.61,83.28 70.81,83.28 70.91,83.17 70.91,83 71.01,82.9 71.34,82.9 71.44,83 71.44,83.17 71.54,83.28 71.75,83.28 71.85,83.17 71.85,83 71.95,82.9 72.15,82.9 72.26,83 72.26,83.17 72.36,83.28 72.56,83.28 72.66,83.17 72.66,83 72.76,82.9 73.42,82.9 73.7,83.18 74.2,83.18 74.48,82.9 93.04,82.9 94.65,84.51 102.64,84.51 105.03,86.9 107.77,86.9 108.53,86.14 109.63,86.14 115.9,79.86 115.9,78.59 v2(116.28,78.21)
  BOTTOM w0.089: DM2.16 50.3,82.82 50.99,83.51 v2(50.99,83.58) ; v1(116.28,78.77) 116.28,78.77 v2(116.28,78.21) 116.5,77.99 116.5,77.09 116.5,77.09 116.5,75.97 116.49,75.43 116.47,75.34 116.23,75.1 CPU1.AH70
M_B_DQ15: length 83
  TOP w0.089: v1(52.14,84.09) v2(52.42,83.58)
  L6 w0.102: v2(52.42,83.58) 52.88,83.13 60.54,83.13 60.64,83.23 68.2,83.23 68.58,83.61 74.66,83.61 74.77,83.5 74.77,83.33 74.87,83.23 75.07,83.23 75.17,83.33 75.17,83.5 75.27,83.61 75.48,83.61 75.58,83.5 75.58,83.33 75.68,83.23 75.88,83.23 75.99,83.33 75.99,83.5 76.09,83.61 76.29,83.61 76.39,83.5 76.39,83.33 76.49,83.23 76.7,83.23 76.8,83.33 76.8,83.5 76.9,83.61 77.23,83.61 77.33,83.5 77.33,83.33 77.43,83.23 77.64,83.23 77.74,83.33 77.74,83.5 77.84,83.61 78.04,83.61 78.14,83.5 78.14,83.33 78.25,83.23 92.9,83.23 94.51,84.84 102.5,84.84 104.89,87.23 107.91,87.23 108.67,86.47 109.76,86.47 116.67,79.56 116.67,78.33 116.79,78.22 116.79,77.51 117.01,77.29 v2(117.01,77.05)
  BOTTOM w0.089: v2(117.01,77.05) 116.68,76.72 116.68,76.26 116.7,76.24 116.7,75.51 116.63,75.25 116.63,74.61 CPU1.AH69 ; DM2.17 56.85,82.57 53.43,82.57 v2(52.42,83.58)
M_B_DQ16: length 68.7
  TOP w0.089: v1(51.71,75.86) v2(51.51,75.33)
  L6 w0.102: v2(111.58,72.83) 111.58,73.53 110.94,74.17 110.6,74.17 109.96,74.81 106.15,74.81 104.47,76.48 104.04,76.48 102.4,78.12 96.31,78.12 94.97,76.79 73.66,76.79 72.75,75.88 69.03,75.88 68.91,75.76 58.47,75.76 57.93,75.22 55.57,75.22 55.24,74.9 51.94,74.9 v2(51.51,75.33)
  BOTTOM w0.089: DM2.50 48.65,74.32 50.56,74.32 51.51,75.27 v2(51.51,75.33) ; v2(111.58,72.83) CPU1.AT66
M_B_DQ17: length 68.5
  TOP w0.089: v1(53.18,72.17) v2(52.87,72.71)
  L6 w0.102: v2(52.87,72.71) 53.31,72.27 53.69,72.27 53.69,72.27 55.59,72.27 57.46,74.14 72.47,74.14 74.14,75.81 95.36,75.81 95.37,75.82 96.7,77.15 101.97,77.15 103.63,75.49 104.32,75.49 106.94,72.88 107.28,72.88 107.46,73.06 108.8,73.06 109.83,72.04 110.67,72.04 v2(110.87,71.84)
  BOTTOM w0.089: CPU1.AU66 v2(110.87,71.84) ; v2(52.87,72.71) 54.53,74.36 55.47,74.36 55.69,74.57 DM2.49
M_B_DQ18: length 71.5
  TOP w0.089: v1(51.99,70.27) v2(52.25,70.78)
  L6 w0.102: v2(112.83,70.92) 112.42,70.51 110.63,70.51 109.97,71.18 109.12,71.18 108.56,71.73 107.21,71.73 104.44,74.5 103.15,74.5 102.19,75.46 96.42,75.46 95.77,74.82 74.55,74.82 72.88,73.15 58.81,73.15 58.71,73.05 58.71,72.61 58.6,72.51 58.4,72.51 58.3,72.61 58.3,73.05 58.2,73.15 57.87,73.15 56,71.28 54.1,71.28 52.43,71.28 52.25,71.09 v2(52.25,70.78)
  BOTTOM w0.089: CPU1.AP65 v2(112.83,70.92) ; DM2.62 51.1,71.32 51.42,71.65 51.94,71.65 52.25,71.34 v2(52.25,70.78)
M_B_DQ19: length 72.1
  TOP w0.089: v1(54.86,70.22) v2(55.09,70.78)
  L6 w0.102: v2(113.48,70.92) 112.88,70.32 110.55,70.32 109.93,70.95 109.04,70.95 108.46,71.53 107.13,71.53 104.49,74.17 102.84,74.17 102.52,74.49 97.67,74.49 97.56,74.59 97.56,75.02 97.46,75.12 97.26,75.12 97.16,75.02 97.16,74.59 97.06,74.49 74.69,74.49 72.52,72.33 71.94,72.33 71.84,72.43 71.84,72.72 71.73,72.82 71.53,72.82 71.43,72.72 71.43,72.43 71.33,72.33 71.12,72.33 71.02,72.43 71.02,72.72 70.92,72.82 70.72,72.82 70.62,72.72 70.62,72.43 70.51,72.33 70.31,72.33 70.21,72.43 70.21,72.72 70.11,72.82 69.91,72.82 69.8,72.72 69.8,72.43 69.7,72.33 69.5,72.33 69.4,72.43 69.4,72.72 69.3,72.82 69.09,72.82 68.99,72.72 68.99,72.43 68.89,72.33 68.56,72.33 68.41,72.18 62.14,72.18 62.04,72.28 62.04,72.71 61.94,72.81 61.73,72.81 61.63,72.71 61.63,72.28 61.53,72.18 61.33,72.18 61.23,72.28 61.23,72.71 61.12,72.81 60.92,72.81 60.82,72.71 60.82,72.28 60.72,72.18 58.34,72.18 57.79,71.63 57.64,71.63 57.3,71.97 57.16,71.97 57.01,71.83 57.01,71.68 57.35,71.34 57.35,71.2 57.11,70.95 55.26,70.95 v2(55.09,70.78)
  BOTTOM w0.089: v2(55.09,70.78) 55.09,70.78 55.39,71.07 DM2.63 ; CPU1.AN65 v2(113.48,70.92)
M_B_DQ20: length 71.2
  TOP w0.089: v1(49.85,75.86) v2(50.09,75.33)
  L6 w0.102: v2(113.48,71.84) 113.1,72.21 113.1,73 111.44,74.66 110.67,74.66 110.08,75.24 106.26,75.24 102.17,79.33 99.23,79.33 99.23,79.33 98.87,79.33 98.86,79.33 96.58,79.33 94.7,77.45 73.38,77.45 72.83,76.9 69.11,76.9 68.64,76.42 56.3,76.42 55.77,75.88 50.64,75.88 50.64,75.88 v2(50.09,75.33)
  BOTTOM w0.089: CPU1.AN66 v2(113.48,71.84) ; DM2.46 50.08,75.32 v2(50.09,75.33)
M_B_DQ21: length 70.5
  TOP w0.089: v1(54.12,75.83) v2(54.42,75.34)
  L6 w0.102: v2(112.83,71.84) 112.09,72.58 112.09,73.29 110.93,74.45 110.59,74.45 109.99,75.05 106.18,75.05 104.55,76.67 104.33,76.67 102.55,78.45 98.6,78.45 98.49,78.55 98.49,78.9 98.39,79 98.19,79 98.09,78.9 98.09,78.55 97.99,78.45 97.78,78.45 97.68,78.55 97.68,78.9 97.58,79 97.38,79 97.28,78.9 97.28,78.55 97.17,78.45 96.43,78.45 96.17,78.45 94.84,77.12 73.52,77.12 72.97,76.57 71.82,76.57 71.71,76.47 71.71,76.31 71.61,76.21 71.41,76.21 71.31,76.31 71.31,76.47 71.21,76.57 71,76.57 70.9,76.47 70.9,76.31 70.8,76.21 70.6,76.21 70.49,76.31 70.49,76.47 70.39,76.57 70.19,76.57 70.09,76.47 70.09,76.31 69.99,76.21 69.78,76.21 69.68,76.31 69.68,76.47 69.58,76.57 69.25,76.57 68.77,76.09 57.38,76.09 57.28,75.99 57.28,75.65 57.18,75.55 56.97,75.55 56.87,75.65 56.87,75.99 56.77,76.09 56.44,76.09 55.9,75.55 54.63,75.55 v2(54.42,75.34)
  BOTTOM w0.089: CPU1.AP66 v2(112.83,71.84) ; v2(54.42,75.34) 55.08,75.34 55.31,75.57 56.85,75.57 DM2.45
M_B_DQ22: length 69.9
  TOP w0.089: v1(50.87,72.15) v2(50.72,72.71)
  L6 w0.102: v2(50.72,72.71) 51.34,73.33 52.22,73.33 52.44,73.11 52.44,72.53 53.03,71.94 53.83,71.94 55.73,71.94 57.59,73.81 72.61,73.81 74.28,75.48 95.5,75.48 95.51,75.49 96.84,76.82 101.84,76.82 103.49,75.16 104.34,75.16 107.36,72.14 109.29,72.14 109.85,71.58 110.13,71.58 110.38,71.33 111.12,71.33 v2(111.53,70.92)
  BOTTOM w0.089: DM2.58 49.63,72.32 49.68,72.28 50.29,72.28 v2(50.72,72.71) ; CPU1.AT65 v2(111.53,70.92)
M_B_DQ23: length 69.7
  TOP w0.089: v1(52.39,73.16) v2(51.99,72.71)
  L6 w0.102: v2(110.87,70.93) 110.51,70.93 110.06,71.38 109.27,71.38 108.71,71.94 107.29,71.94 104.39,74.83 103.29,74.83 102.32,75.79 96.28,75.79 95.63,75.15 74.42,75.15 72.74,73.48 57.73,73.48 55.87,71.61 53.96,71.61 53.96,71.61 52.46,71.61 51.99,72.09 v2(51.99,72.71)
  BOTTOM w0.089: v2(51.99,72.71) 52.01,72.71 52.65,72.07 DM2.59 ; CPU1.AU65 v2(110.87,70.93)
M_B_DQ24: length 69.6
  TOP w0.089: v1(52.57,69.13) v2(53.03,68.72)
  L6 w0.102: v2(53.03,68.72) 53.47,69.16 57.2,69.16 59.23,71.19 68.62,71.19 68.73,71.09 68.73,70.86 68.82,70.76 69.03,70.76 69.13,70.86 69.13,71.09 69.23,71.19 73.58,71.19 75.56,73.17 98.75,73.17 99.08,73.5 99.76,73.5 99.77,73.5 99.92,73.5 101.89,73.5 102.18,73.21 104.56,73.21 106.63,71.14 106.63,70.76 107.11,70.28 108.83,70.28 109.6,69.51 110.37,69.51 110.39,69.53 111.74,69.53 v2(112.18,69.09)
  BOTTOM w0.089: v2(53.03,68.72) 52.43,69.32 DM2.70 ; v2(112.18,69.09) CPU1.AT61
M_B_DQ25: length 68.6
  TOP w0.089: v1(54.15,69.2) v2(54.46,68.72)
  L6 w0.102: v2(54.46,68.72) 54.46,68.35 54.72,68.08 56.59,68.08 57.66,69.15 58.41,69.15 59.48,70.22 69.46,70.22 69.56,70.32 69.56,70.74 69.66,70.84 69.87,70.84 69.97,70.74 69.97,70.32 70.07,70.22 70.27,70.22 70.38,70.32 70.38,70.74 70.48,70.84 70.68,70.84 70.78,70.74 70.78,70.32 70.88,70.22 71.09,70.22 71.19,70.32 71.19,70.74 71.29,70.84 71.49,70.84 71.6,70.74 71.6,70.32 71.7,70.22 71.9,70.22 72,70.32 72,70.74 72.1,70.84 72.31,70.84 72.41,70.74 72.41,70.32 72.51,70.22 73.08,70.22 75.7,72.84 98.89,72.84 99.05,73 99.22,73.17 101.95,73.17 102.11,73 104.49,73 106.42,71.08 106.42,70.69 107.08,70.03 108.63,70.03 109.37,69.29 110.67,69.29 v2(110.84,69.12)
  BOTTOM w0.089: v2(54.46,68.72) 54.46,68.72 54.88,69.15 55.5,69.15 55.57,69.07 DM2.71 ; CPU1.AU61 v2(110.84,69.12)
M_B_DQ26: length 71.6
  TOP w0.089: v1(54.73,66.2) v2(54.41,65.73)
  L6 w0.102: v2(54.41,65.73) 54.41,66.08 54.62,66.29 55.55,66.29 55.65,66.19 55.65,65.73 55.75,65.63 55.95,65.63 56.06,65.73 56.06,66.19 56.16,66.29 56.49,66.29 56.59,66.19 56.59,66.01 56.69,65.91 56.89,65.91 57,66.01 57,66.19 57.1,66.29 58.22,66.29 59.82,67.9 69.07,67.9 69.17,68 69.17,68.37 69.27,68.47 69.48,68.47 69.58,68.37 69.58,68 69.68,67.9 69.88,67.9 69.98,68 69.98,68.37 70.09,68.47 70.29,68.47 70.39,68.37 70.39,68 70.49,67.9 71.72,67.9 71.82,68 71.82,68.41 71.92,68.52 72.13,68.52 72.23,68.41 72.23,68 72.33,67.9 73.05,67.9 76.35,71.19 100.31,71.19 100.84,70.67 104.59,70.67 106.45,68.81 107.85,68.81 108.66,68 109.89,68 110.38,67.51 111.49,67.51 111.81,67.82 113.12,67.82 v2(113.48,68.18)
  BOTTOM w0.089: CPU1.AP60 v2(113.48,68.18) ; v2(54.41,65.73) 54.83,66.15 55.47,66.15 55.55,66.07 DM2.83
M_B_DQ27: length 72.3
  TOP w0.089: v1(49.8,66.2) v2(50.14,65.73)
  L6 w0.102: v2(50.14,65.73) 50.53,65.33 50.91,65.24 56.22,65.24 57.46,65.68 58.29,65.9 59.96,67.57 73.19,67.57 76.48,70.86 100.18,70.86 100.56,70.48 104.51,70.48 106.37,68.61 107.72,68.61 108.74,67.59 109.55,67.18 109.97,67.18 110.1,67.32 111.57,67.32 112.68,67.62 113.61,67.62 114.11,67.77 114.3,67.77 114.53,68.01 114.53,68.34 v2(114.13,69.09)
  BOTTOM w0.089: v2(50.14,65.73) 50.04,65.82 DM2.84 ; v2(114.13,69.09) CPU1.AN60
M_B_DQ28: length 71.2
  TOP w0.089: v1(50.57,70.24) v2(50.82,70.78)
  L6 w0.102: v2(113.48,69.09) 112.69,69.88 110.41,69.88 109.83,70.47 107.19,70.47 106.83,70.83 106.83,71.21 104.53,73.51 102.14,73.51 101.82,73.83 100.06,73.83 99.75,73.83 99.75,73.83 98.94,73.83 98.62,73.5 75.42,73.5 73.44,71.52 59.09,71.52 57.1,69.53 51.11,69.53 50.82,69.81 v2(50.82,70.78)
  BOTTOM w0.089: CPU1.AN61 v2(113.48,69.09) ; DM2.66 48.65,70.32 50.37,70.32 v2(50.82,70.78)
M_B_DQ29: length 71
  TOP w0.089: v1(53.41,70.24) v2(53.67,70.78)
  L6 w0.102: v2(53.67,70.78) 53.31,70.42 53.31,70.03 53.48,69.86 55.21,69.86 55.31,69.96 55.31,70.23 55.41,70.33 55.62,70.33 55.72,70.23 55.72,69.96 55.82,69.86 56.02,69.86 56.12,69.96 56.12,70.23 56.23,70.33 56.43,70.33 56.53,70.23 56.53,69.96 56.63,69.86 56.96,69.86 58.95,71.85 73.3,71.85 75.29,73.83 98.48,73.83 98.81,74.16 101.84,74.16 102.27,73.74 104.57,73.74 107.03,71.28 107.03,70.89 107.27,70.66 109.91,70.66 110.46,70.12 113.37,70.12 v2(113.48,70.01)
  BOTTOM w0.089: v2(113.48,70.01) CPU1.AP61 ; v2(53.67,70.78) 54.53,69.92 55.68,69.92 55.83,70.07 DM2.67
M_B_DQ30: length 71.4
  TOP w0.089: v1(53.33,66.2) v2(52.98,65.73)
  L6 w0.102: v2(111.53,68.18) 111.05,67.7 110.52,67.7 109.97,68.25 109.05,68.25 108.28,69.02 106.81,69.02 105.31,70.52 105.31,70.93 104.07,72.17 99.74,72.17 99.1,71.52 76.21,71.52 73.53,68.85 73.26,68.85 68.98,68.85 68.36,68.23 62.79,68.23 62.69,68.33 62.69,68.83 62.58,68.93 62.38,68.93 62.28,68.83 62.28,68.33 62.18,68.23 61.85,68.23 61.75,68.33 61.75,68.83 61.64,68.93 61.44,68.93 61.34,68.83 61.34,68.33 61.24,68.23 59.69,68.23 58.14,66.68 53.94,66.68 v2(52.98,65.73)
  BOTTOM w0.089: DM2.79 54.33,67.07 v2(52.98,65.73) ; v2(111.53,68.18) CPU1.AT60
M_B_DQ31: length 70.3
  TOP w0.089: v1(51.23,66.2) v2(51.56,65.73)
  L6 w0.102: v2(110.79,68.1) 110.41,68.1 110.08,68.44 109.15,68.44 108.21,69.37 106.72,69.37 105.5,70.6 105.5,71.01 104.15,72.36 99.54,72.36 99.14,71.96 99.03,71.85 76.07,71.85 73.48,69.26 61.01,69.26 60.91,69.16 60.91,68.67 60.81,68.57 60.6,68.57 60.5,68.67 60.5,69.16 60.4,69.26 59.88,69.26 58.84,68.21 58.84,67.92 57.93,67.01 53.35,67.01 52.95,66.61 51.85,66.61 51.56,66.32 v2(51.56,65.73)
  BOTTOM w0.089: v2(51.56,65.73) 50.46,66.82 DM2.80 ; CPU1.AU60 v2(110.79,68.1)
M_B_DQ32: length 72.3
  TOP w0.089: v2(51.38,42.3) v1(51.76,41.79)
  L6 w0.102: v2(111.48,57.18) 111.46,57.16 109.24,57.16 107.73,55.64 101.74,55.64 98.17,52.08 88.67,52.08 77.86,41.26 59.78,41.26 59.43,40.91 51.97,40.91 51.38,41.5 v2(51.38,42.3)
  BOTTOM w0.089: CPU1.AU40 111.2,57.45 v2(111.48,57.18) ; DM2.174 50.4,41.32 v2(51.38,42.3)
M_B_DQ33: length 73.1
  TOP w0.089: v1(52.93,42.23) v2(53.09,41.67)
  L6 w0.102: v2(112.13,58.12) 111.21,58.12 110.94,58.4 109.68,58.4 107.31,56.04 101.47,56.04 98.26,52.82 88.49,52.82 78.12,42.46 69.22,42.46 68.68,41.92 62.94,41.92 62.71,42.15 56.85,42.15 56.75,42.05 56.75,41.81 56.63,41.69 56.46,41.69 56.34,41.81 56.34,42.05 56.24,42.15 56.04,42.15 55.94,42.05 55.94,41.67 55.83,41.57 55.63,41.57 55.53,41.67 55.53,42.05 55.43,42.15 53.6,42.15 53.11,41.67 v2(53.09,41.67)
  BOTTOM w0.089: CPU1.AT40 v2(112.13,58.12) ; v2(53.09,41.67) 53.52,41.24 55.3,41.24 55.63,41.57 DM2.173
M_B_DQ34: length 73.5
  TOP w0.089: v1(54.54,39.06) v2(54.85,38.58)
  L6 w0.102: v2(112.18,56.29) 112.13,56.34 111.15,56.34 110.96,56.53 109.74,56.53 108.66,55.45 108.66,55.2 107.62,54.16 104.38,54.16 104.27,54.26 101.37,54.26 98.2,51.09 89.05,51.09 77.61,39.65 72.08,39.65 71.98,39.75 71.98,40.16 71.88,40.26 71.55,40.26 71.44,40.16 71.44,39.65 71.34,39.55 71.14,39.55 71.04,39.65 71.04,40.16 70.94,40.26 70.73,40.26 70.63,40.16 70.63,39.65 70.53,39.55 70.33,39.55 70.23,39.65 70.23,40.16 70.12,40.26 69.92,40.26 69.82,40.16 69.82,39.65 69.72,39.55 69.39,39.55 69.29,39.65 69.29,40.16 69.18,40.26 68.98,40.26 68.88,40.16 68.88,39.65 68.78,39.55 61.49,39.55 61.38,39.65 61.38,39.79 61.28,39.89 61.08,39.89 60.98,39.79 60.98,39.65 60.88,39.55 60.55,39.55 60.35,39.36 55.62,39.36 v2(54.85,38.58)
  BOTTOM w0.089: v2(54.85,38.58) 55.35,38.07 DM2.187 ; CPU1.AT37 v2(112.18,56.29)
M_B_DQ35: length 73.3
  TOP w0.089: v1(50.87,38.44) v2(51.19,37.96)
  L6 w0.102: v2(51.19,37.96) 51.62,38.39 53.17,38.39 53.74,37.82 55.16,37.82 55.65,38.31 56.04,38.31 56.14,38.41 56.14,38.59 56.24,38.7 56.45,38.7 56.55,38.59 56.55,38.41 56.65,38.31 61.55,38.31 62.13,38.89 77.79,38.89 89.32,50.43 98.21,50.43 101.66,53.88 104.03,53.88 104.13,53.78 107.78,53.78 109.04,55.04 109.04,55.3 109.9,56.15 110.77,56.15 v2(111.54,55.38)
  BOTTOM w0.089: v2(51.19,37.96) 51.19,37.96 50.76,38.38 50.01,38.38 49.95,38.32 DM2.186 ; CPU1.AU37 v2(111.54,55.38)
M_B_DQ36: length 73.3
  TOP w0.089: v1(50.54,41.77) v2(50.11,42.3)
  L6 w0.102: v2(50.11,42.3) 50.11,42.7 50.68,43.27 51.71,43.27 52.5,42.48 62.18,42.48 62.58,42.89 69.3,42.89 69.37,42.81 78.01,42.81 88.35,53.16 98.28,53.16 101.37,56.24 107.25,56.24 109.6,58.59 111.01,58.59 111.07,58.53 112.4,58.53 v2(112.81,58.12)
  BOTTOM w0.089: DM2.170 50.09,42.32 v2(50.11,42.3) ; CPU1.AR40 v2(112.81,58.12)
M_B_DQ37: length 74.3
  TOP w0.089: v1(54.22,42.23) v2(54.36,41.67)
  L6 w0.102: v2(54.36,41.67) 54.79,41.24 59.29,41.24 59.64,41.59 69.35,41.59 69.45,41.69 69.45,42.02 69.55,42.12 69.76,42.12 69.86,42.02 69.86,41.69 69.96,41.59 70.16,41.59 70.27,41.69 70.27,42.02 70.37,42.12 70.57,42.12 70.67,42.02 70.67,41.69 70.77,41.59 70.98,41.59 71.08,41.69 71.08,42.02 71.18,42.12 71.38,42.12 71.49,42.02 71.49,41.69 71.59,41.59 71.79,41.59 71.89,41.69 71.89,42.02 71.99,42.12 72.2,42.12 72.3,42.02 72.3,41.69 72.4,41.59 72.73,41.59 72.83,41.69 72.83,41.94 72.93,42.04 73.14,42.04 73.24,41.94 73.24,41.69 73.34,41.59 77.72,41.59 88.54,52.41 98.19,52.41 101.62,55.83 107.64,55.83 109.17,57.36 111.01,57.36 111.33,57.68 113.03,57.68 v2(113.47,58.12)
  BOTTOM w0.089: v2(54.36,41.67) 54.38,41.67 55.29,42.57 56.85,42.57 DM2.169 ; CPU1.AP40 v2(113.47,58.12)
M_B_DQ38: length 75.6
  TOP w0.089: v1(52.15,38.44) v2(52.46,37.96)
  L6 w0.102: v2(113.48,56.29) 112.97,55.78 112.55,55.78 112.44,55.67 111.74,54.97 111.35,54.97 110.98,55.34 110.42,55.34 110.28,55.48 109.49,55.48 109.24,55.23 109.24,54.98 107.85,53.59 104.02,53.59 103.92,53.69 101.74,53.69 98.12,50.07 89.43,50.07 77.92,38.56 62.27,38.56 61.69,37.98 55.79,37.98 55.3,37.49 53.42,37.49 52.95,37.96 v2(52.46,37.96)
  BOTTOM w0.089: CPU1.AP37 v2(113.48,56.29) ; v2(52.46,37.96) 52.65,37.96 53.77,39.07 DM2.183
M_B_DQ39: length 74.9
  TOP w0.089: v1(51.84,40.35) v2(52.15,39.84)
  L6 w0.102: v2(52.15,39.84) 52.95,39.04 52.99,39.04 53.88,38.15 55.03,38.15 55.9,39.03 57.06,39.03 57.16,38.92 57.16,38.74 57.27,38.64 57.47,38.64 57.57,38.74 57.57,38.92 57.67,39.03 60.49,39.03 60.68,39.22 77.65,39.22 89.19,50.76 98.23,50.76 101.55,54.07 104.11,54.07 104.21,53.97 107.7,53.97 108.85,55.12 108.85,55.38 109.82,56.34 110.88,56.34 111.34,55.88 112.35,55.88 112.75,56.29 v2(112.83,56.29)
  BOTTOM w0.089: DM2.182 51.64,39.32 v2(52.15,39.84) ; CPU1.AR37 v2(112.83,56.29)
M_B_DQ40: length 75.3
  TOP w0.089: v1(53.89,35.62) v2(54.1,36.18)
  L6 w0.102: v2(54.1,36.18) 54.7,36.78 62.68,36.78 62.87,36.98 71.08,36.98 71.18,37.08 71.18,37.45 71.29,37.55 71.49,37.55 71.59,37.45 71.59,37.08 71.69,36.98 71.9,36.98 72,37.08 72,37.45 72.1,37.55 72.3,37.55 72.4,37.45 72.4,37.08 72.5,36.98 72.84,36.98 72.94,37.08 72.94,37.46 73.04,37.56 73.24,37.56 73.34,37.46 73.34,37.08 73.44,36.98 73.65,36.98 73.75,37.08 73.75,37.46 73.85,37.56 74.05,37.56 74.16,37.46 74.16,37.08 74.26,36.98 74.46,36.98 74.56,37.08 74.56,37.46 74.66,37.56 74.87,37.56 74.97,37.46 74.97,37.08 75.07,36.98 75.4,36.98 75.5,37.08 75.5,37.46 75.6,37.56 75.81,37.56 75.91,37.46 75.91,37.08 76.01,36.98 77.89,36.98 89.72,48.81 98.48,48.81 101.81,52.14 107.49,52.14 107.99,52.65 107.99,52.88 109.42,54.31 112.03,54.31 v2(112.18,54.46)
  BOTTOM w0.089: v2(54.1,36.18) 55.59,36.18 55.7,36.07 DM2.195 ; CPU1.AT33 v2(112.18,54.46)
M_B_DQ41: length 74.5
  TOP w0.089: v1(50.62,36.66) v2(50.92,36.18)
  L6 w0.102: v2(110.81,53.67) 109.32,53.67 108.38,52.73 108.38,52.49 107.64,51.76 102.18,51.76 98.57,48.15 89.99,48.15 77.78,35.93 77.03,35.93 76.93,36.03 76.93,36.22 76.83,36.32 76.63,36.32 76.52,36.22 76.52,36.03 76.42,35.93 76.22,35.93 76.12,36.03 76.12,36.22 76.02,36.32 75.81,36.32 75.71,36.22 75.71,36.03 75.61,35.93 75.28,35.93 75.18,36.03 75.18,36.22 75.08,36.32 74.87,36.32 74.77,36.22 74.77,36.03 74.67,35.93 74.47,35.93 74.36,36.03 74.36,36.22 74.26,36.32 74.06,36.32 73.96,36.22 73.96,36.03 73.86,35.93 73.65,35.93 73.55,36.03 73.55,36.22 73.45,36.32 73.25,36.32 73.15,36.22 73.15,36.03 73.04,35.93 69.28,35.93 68.89,36.32 63.15,36.32 62.95,36.12 55.11,36.12 54.41,35.42 52.51,35.42 52.18,35.75 51.35,35.75 v2(50.92,36.18)
  BOTTOM w0.089: v2(50.92,36.18) 50.5,36.61 49.91,36.61 49.63,36.32 DM2.194 ; CPU1.AU33 v2(110.81,53.67)
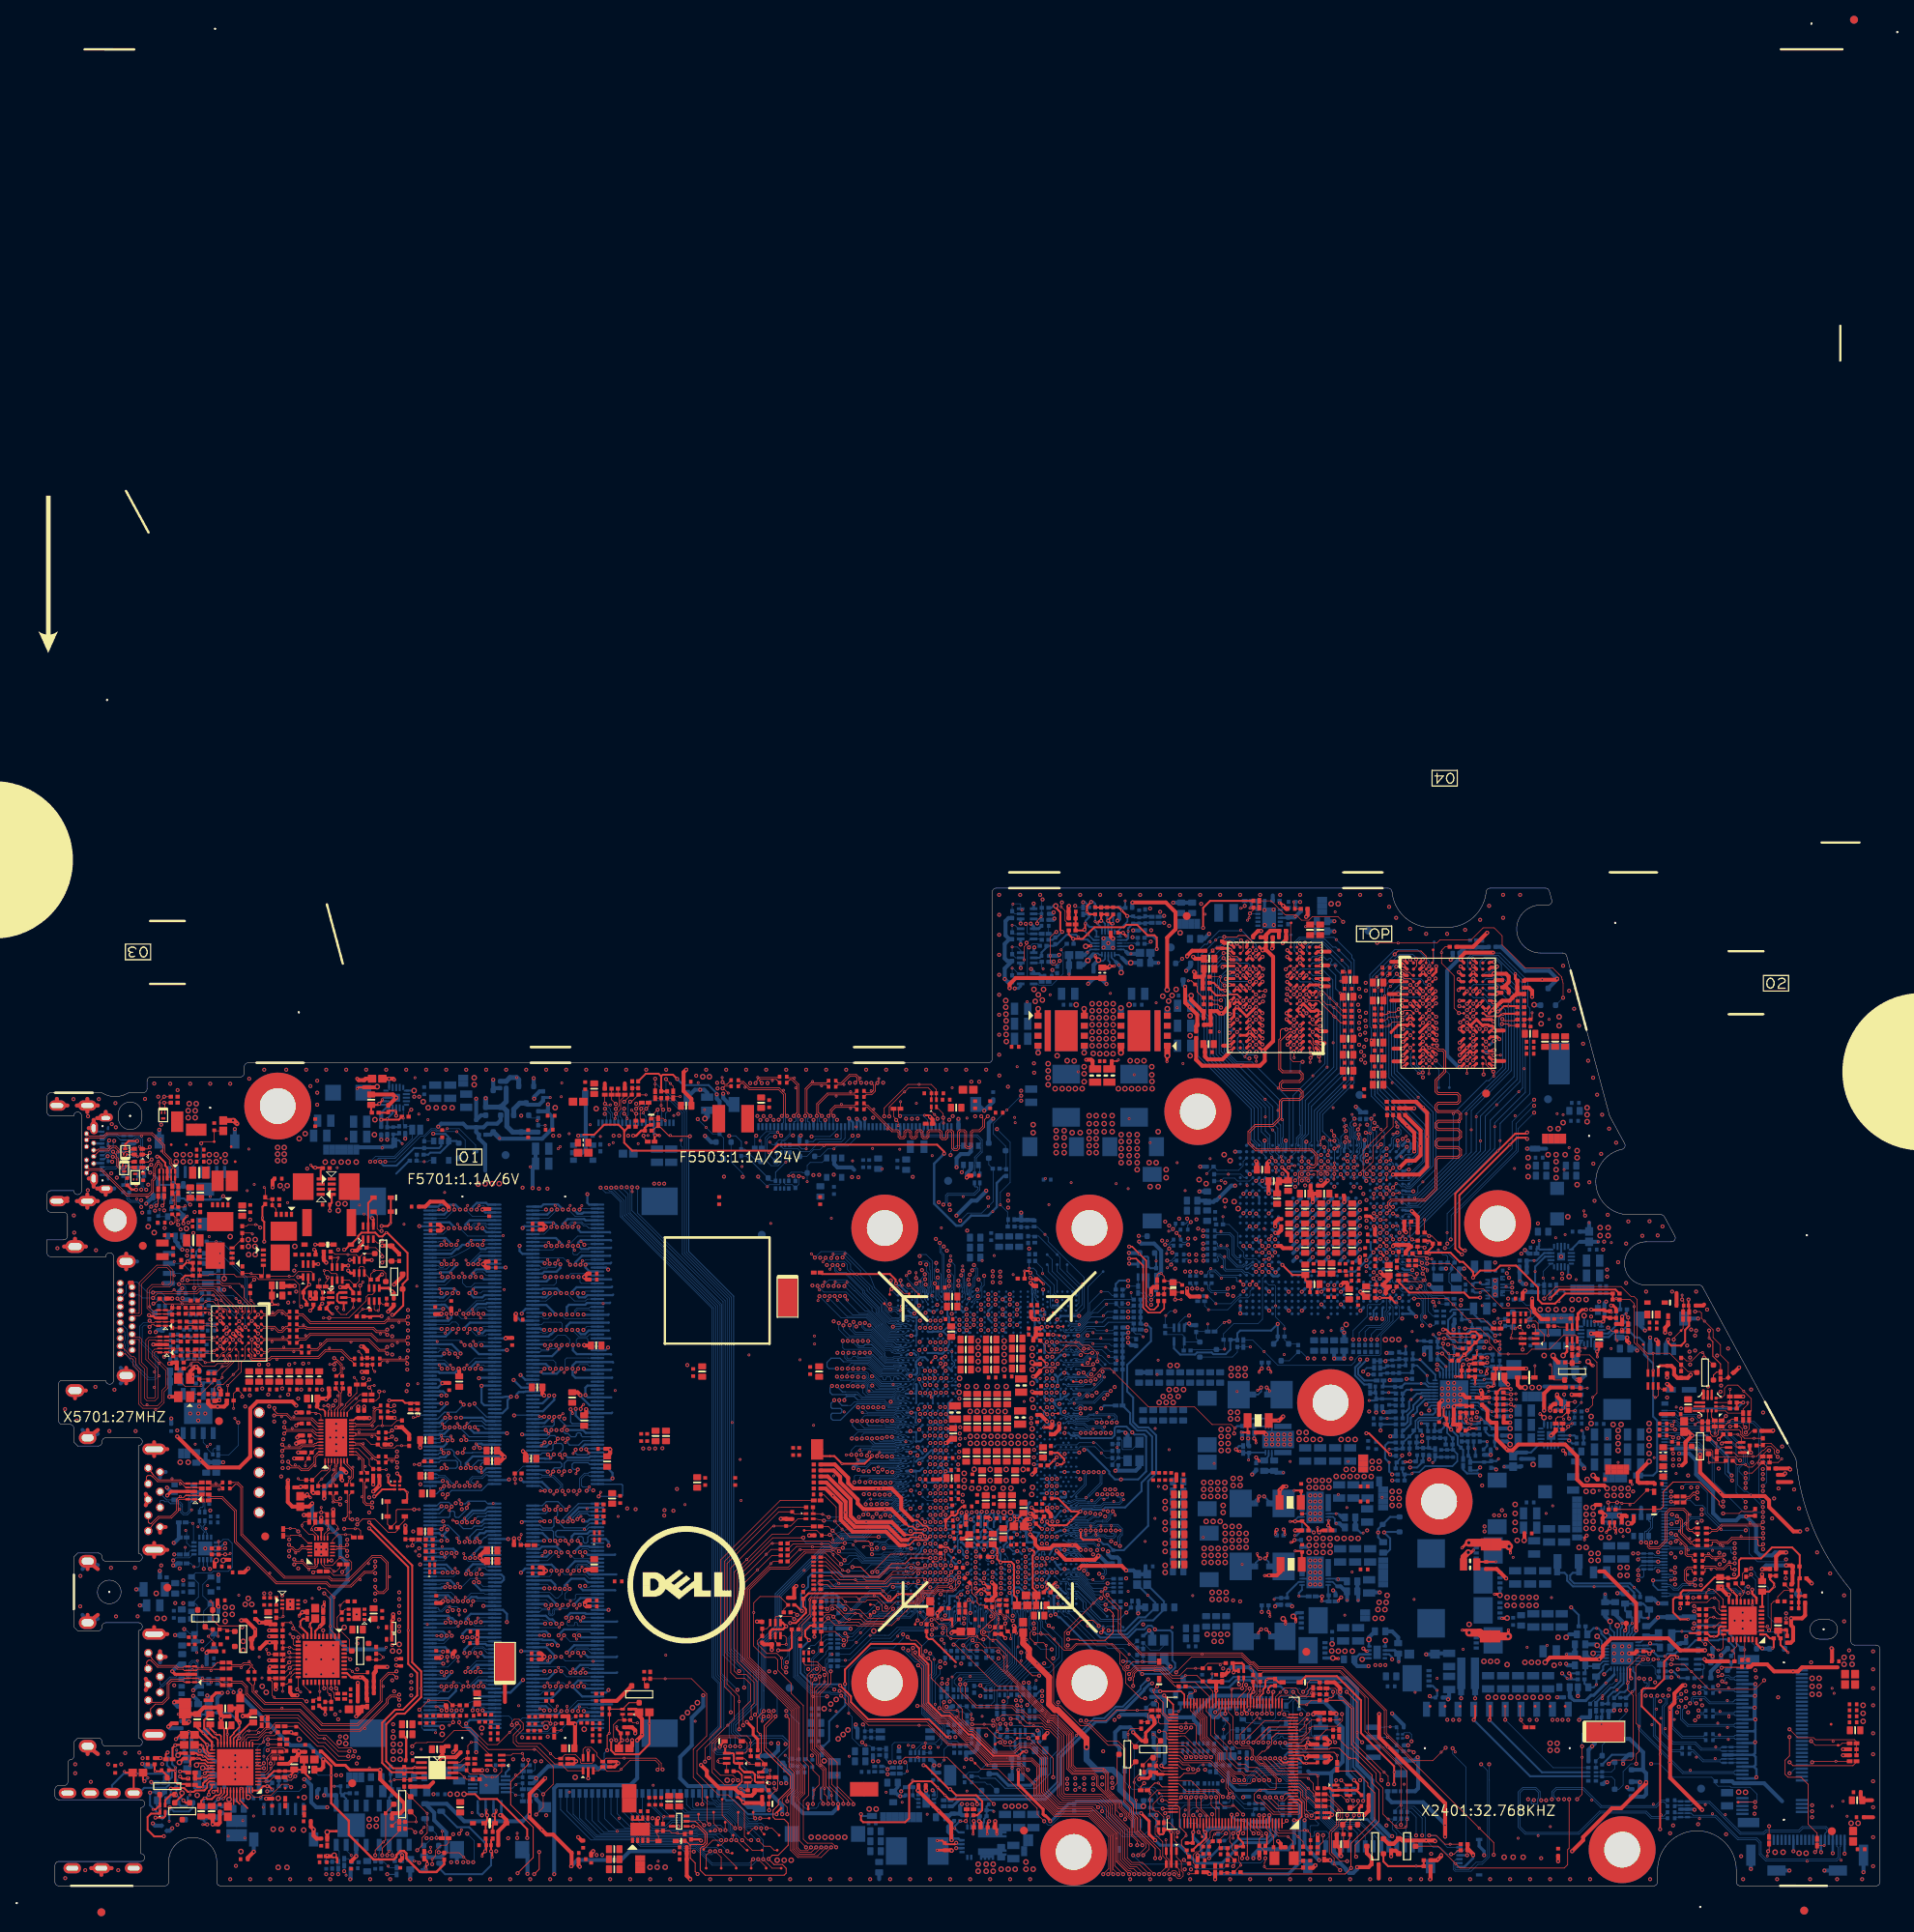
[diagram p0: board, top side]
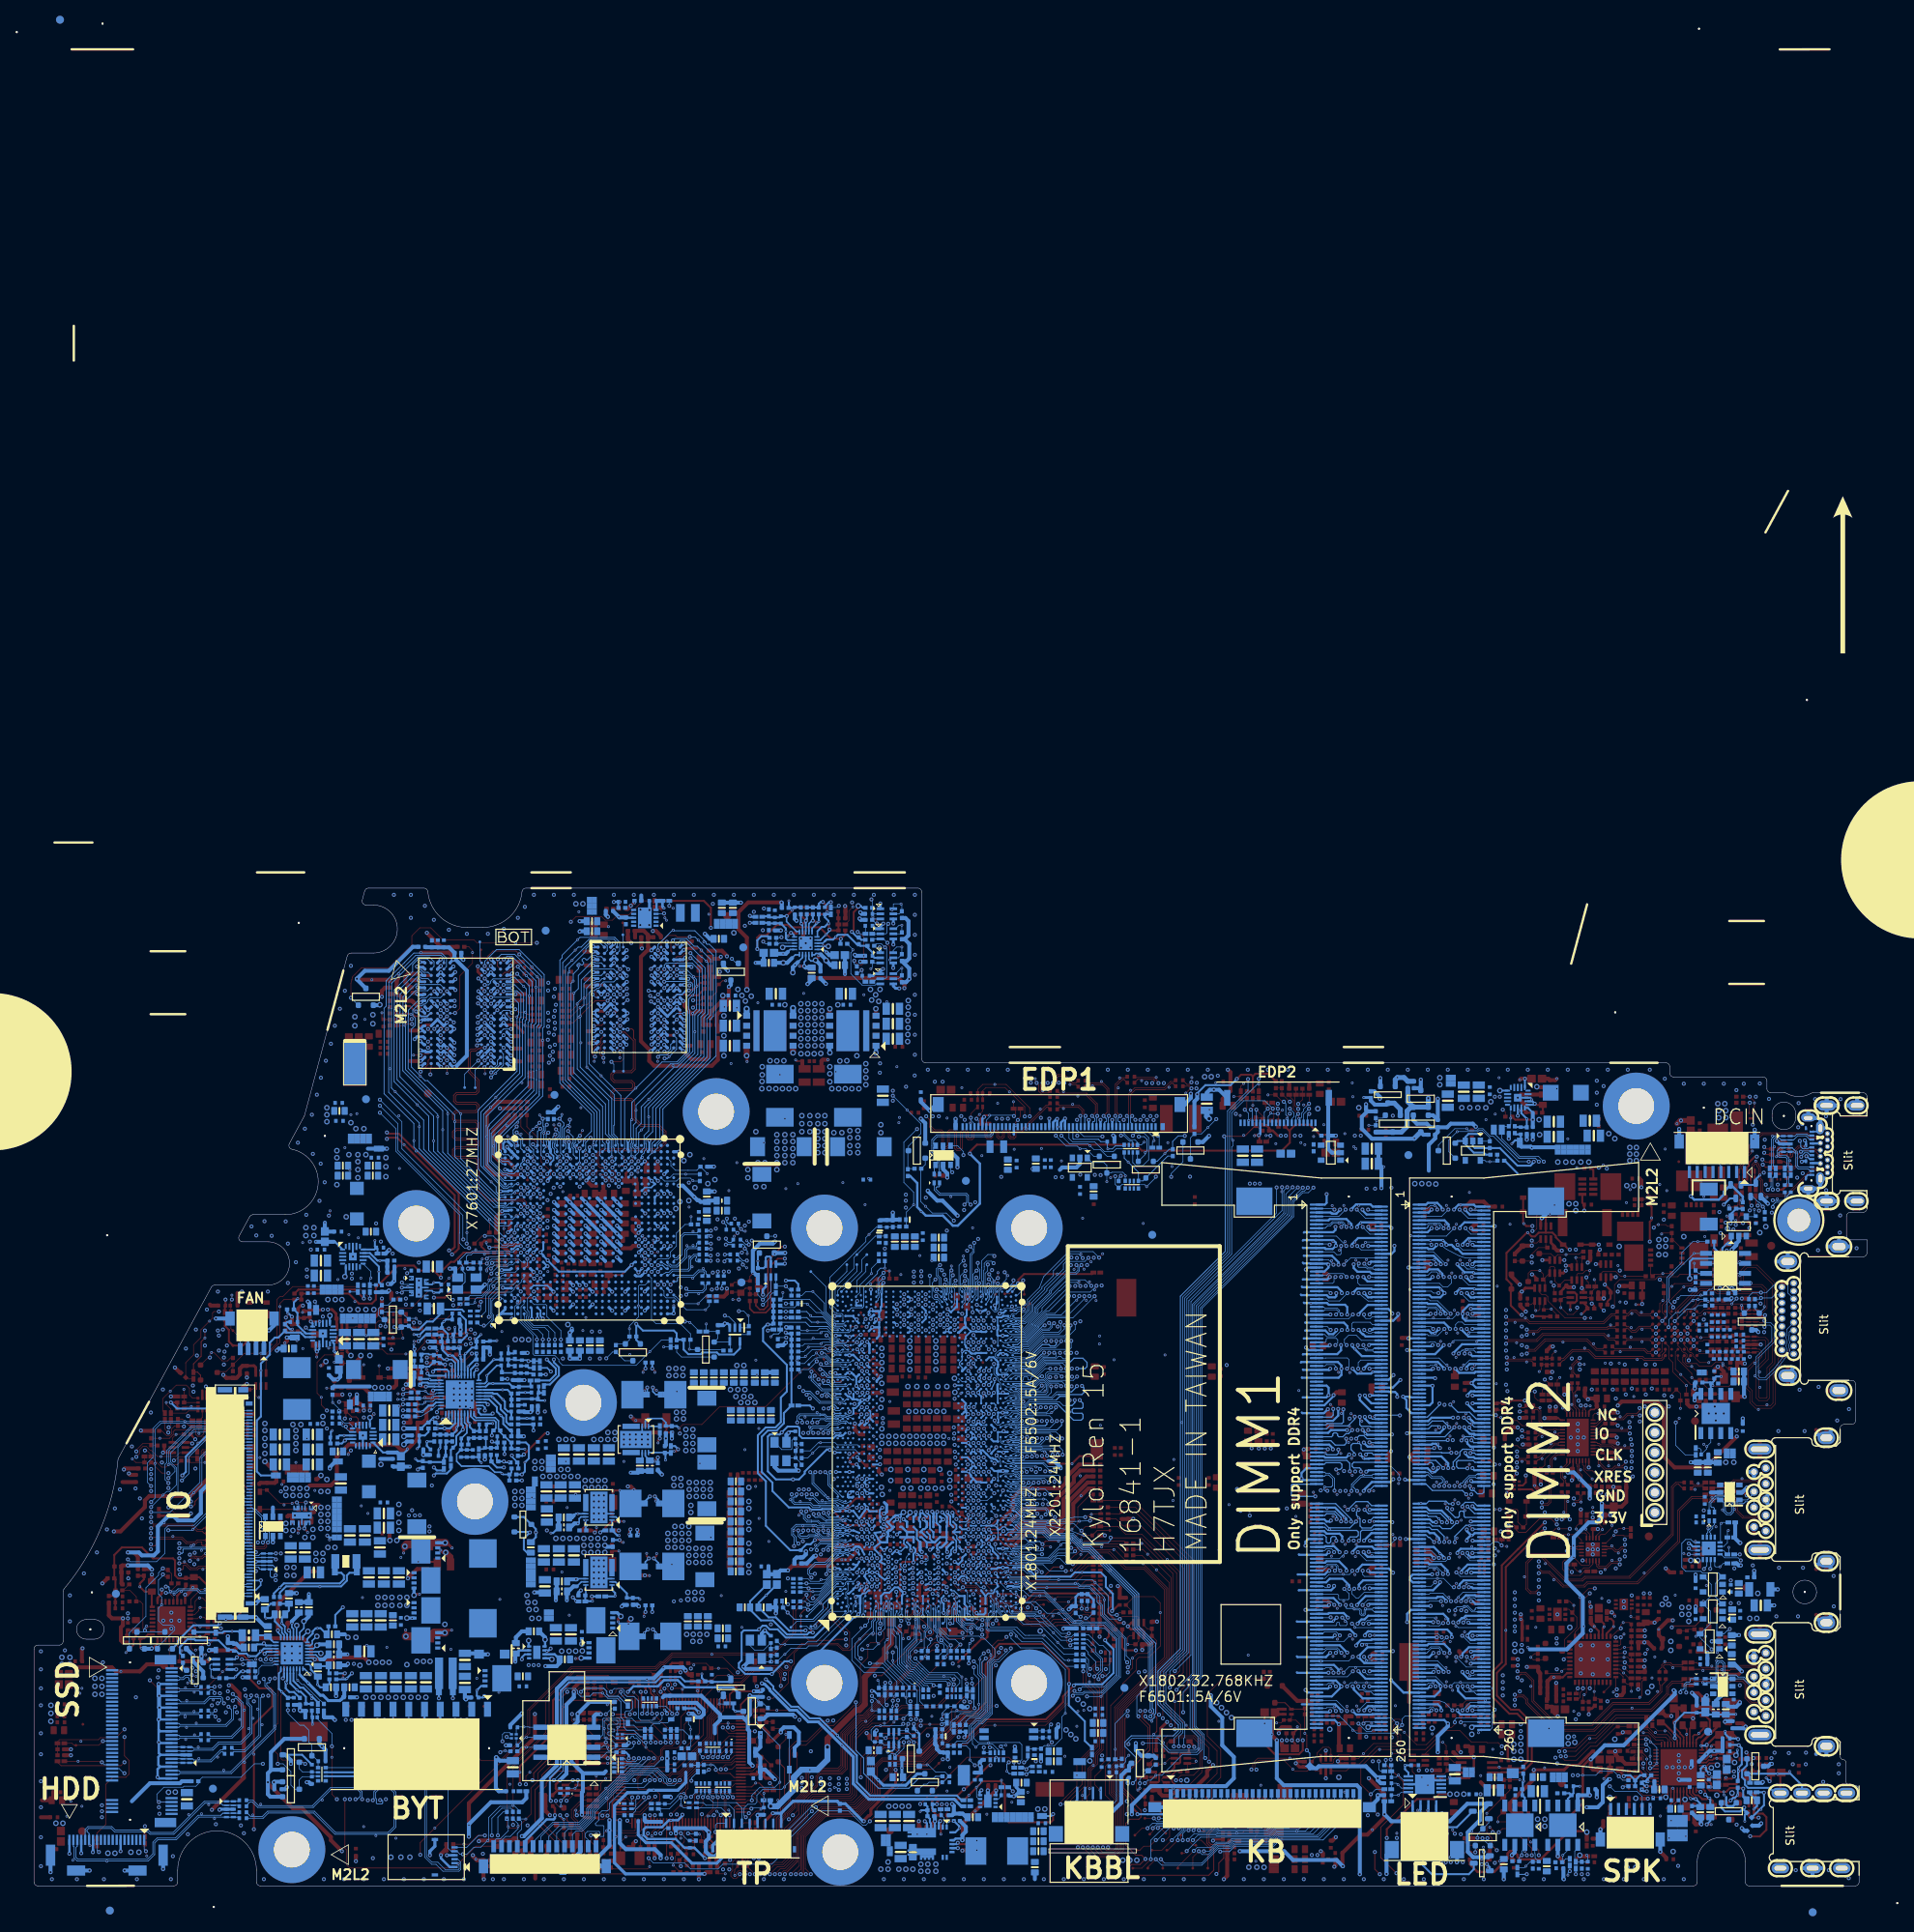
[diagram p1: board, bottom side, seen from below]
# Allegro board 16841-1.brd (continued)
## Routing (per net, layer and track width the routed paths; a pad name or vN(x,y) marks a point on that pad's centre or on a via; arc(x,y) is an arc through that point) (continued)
M_B_DQ42: length 73.9
  TOP w0.089: v1(53.49,33.95) v2(53.82,33.4)
  L6 w0.102: v2(111.53,52.63) 110.49,52.63 109.93,52.08 109.64,52.08 107.76,50.19 103.28,50.19 98.85,45.75 89.43,45.75 82.03,38.35 77.36,33.68 71.17,33.68 71.07,33.58 71.07,33.4 70.95,33.28 70.79,33.28 70.67,33.4 70.67,33.58 70.56,33.68 70.23,33.68 69.78,33.22 68.93,33.22 68.83,33.33 68.83,33.48 68.73,33.58 68.52,33.58 68.42,33.48 68.42,33.33 68.32,33.22 68.12,33.22 68.02,33.33 68.02,33.48 67.92,33.58 67.71,33.58 67.61,33.48 67.61,33.33 67.51,33.22 67.31,33.22 67.2,33.33 67.2,33.48 67.1,33.58 66.9,33.58 66.8,33.48 66.8,33.33 66.7,33.22 66.11,33.22 65.38,33.96 62.81,33.96 62.71,33.86 62.71,33.33 62.61,33.22 62.4,33.22 62.3,33.33 62.3,33.86 62.2,33.96 54.29,33.96 53.82,33.5 v2(53.82,33.4)
  BOTTOM w0.089: v2(53.82,33.4) 53.97,33.4 54.32,33.04 55.56,33.04 55.59,33.07 DM2.207 ; CPU1.AU30 v2(111.53,52.63)
M_B_DQ43: length 74.4
  TOP w0.089: v1(52.22,33.01) v2(52.55,33.49)
  L6 w0.102: v2(112.18,52.63) 111.77,53.04 111.33,53.04 111.12,52.83 110.41,52.83 109.85,52.28 109.43,52.28 107.53,50.39 102.96,50.39 99.89,47.32 98.15,47.32 98.01,47.18 90.39,47.18 81.89,38.68 77.24,34.03 69.76,34.03 69.66,33.93 69.66,33.66 69.56,33.56 69.35,33.56 69.25,33.66 69.25,33.93 69.15,34.03 68.82,34.03 68.29,34.57 55.88,34.57 55.6,34.29 54.12,34.29 53.7,33.87 52.93,33.87 v2(52.55,33.49)
  BOTTOM w0.089: DM2.208 51.89,32.82 v2(52.55,33.49) ; CPU1.AT30 v2(112.18,52.63)
M_B_DQ44: length 76
  TOP w0.089: v1(53.11,36.69) v2(52.83,36.18)
  L6 w0.102: v2(112.82,54.46) 112.41,54.87 111.99,54.87 111.9,54.78 111.18,54.78 110.84,55.12 110.31,55.12 109.83,54.64 109.32,54.64 108.07,53.4 103.94,53.4 103.84,53.5 102.11,53.5 101.74,53.13 101.74,52.73 98.16,49.14 89.58,49.14 78.33,37.89 70.85,37.89 70.75,37.79 70.75,37.41 70.65,37.31 70.45,37.31 70.35,37.41 70.35,37.79 70.24,37.89 70.04,37.89 69.94,37.79 69.94,37.41 69.84,37.31 69.63,37.31 69.53,37.41 69.53,37.79 69.43,37.89 69.1,37.89 68.52,37.31 62.74,37.31 62.54,37.11 53.76,37.11 v2(52.83,36.18)
  BOTTOM w0.089: v2(52.83,36.18) 53.83,37.18 55.49,37.18 55.59,37.07 DM2.191 ; CPU1.AR33 v2(112.82,54.46)
M_B_DQ45: length 76.7
  TOP w0.089: v1(51.89,36.66) v2(52.19,36.18)
  L6 w0.102: v2(113.45,54.42) 113.09,54.05 111.01,54.05 110.98,54.08 109.46,54.08 108.19,52.81 108.19,52.57 107.57,51.95 102.1,51.95 98.63,48.48 89.85,48.48 78.02,36.65 72.79,36.65 72.69,36.55 72.69,36.36 72.59,36.26 72.39,36.26 72.29,36.36 72.29,36.55 72.18,36.65 71.98,36.65 71.88,36.55 71.88,36.36 71.78,36.26 71.57,36.26 71.47,36.36 71.47,36.55 71.37,36.65 71.04,36.65 70.94,36.55 70.94,36.36 70.84,36.26 70.63,36.26 70.53,36.36 70.53,36.55 70.43,36.65 70.23,36.65 70.13,36.55 70.13,36.36 70.02,36.26 69.82,36.26 69.72,36.36 69.72,36.55 69.62,36.65 63.01,36.65 62.81,36.45 54.98,36.45 54.27,35.75 52.65,35.75 52.21,36.18 v2(52.19,36.18)
  BOTTOM w0.089: DM2.190 51.3,37.32 52.19,36.44 v2(52.19,36.18) ; CPU1.AP33 v2(113.45,54.42)
M_B_DQ46: length 74.6
  TOP w0.089: v1(54.71,34.05) v2(54.45,33.51)
  L6 w0.102: v2(54.45,33.51) 54.96,33.01 55.22,33.01 55.33,32.89 56.97,32.89 57.08,33 57.08,33.23 57.18,33.33 57.38,33.33 57.48,33.23 57.48,33 57.58,32.89 60.44,32.89 60.54,33 60.54,33.53 60.64,33.63 60.84,33.63 60.95,33.53 60.95,33 61.05,32.89 61.25,32.89 61.35,33 61.35,33.53 61.45,33.63 61.66,33.63 61.76,33.53 61.76,33 61.86,32.89 71.4,32.89 71.5,33 71.5,33.24 71.6,33.34 71.8,33.34 71.9,33.24 71.9,33 72.01,32.89 72.21,32.89 72.31,33 72.31,33.24 72.41,33.34 77.48,33.34 82.16,38.02 82.16,38.02 89.56,45.42 98.88,45.42 102.62,49.16 107.27,49.16 108.75,50.64 108.75,50.65 109.8,51.7 109.81,51.7 109.92,51.81 109.96,51.81 110.03,51.87 110.09,51.87 110.54,52.33 111.26,52.33 111.36,52.23 112.42,52.23 v2(112.83,52.63)
  BOTTOM w0.089: v2(54.45,33.51) 55.01,34.07 DM2.203 ; CPU1.AR30 v2(112.83,52.63)
M_B_DQ47: length 75.7
  TOP w0.089: v1(50.95,33.97) v2(51.26,33.47)
  L6 w0.102: v2(113.48,52.63) 112.88,52.04 111.14,52.04 111.04,52.13 110.62,52.13 110.11,51.62 110,51.62 109.89,51.51 109.88,51.51 108.94,50.57 108.94,50.56 107.35,48.97 102.75,48.97 99.17,45.39 99.17,45.39 98.88,45.09 89.7,45.09 82.3,37.69 77.62,33.01 73.75,33.01 73.65,32.91 73.65,32.67 73.55,32.56 73.35,32.56 73.25,32.67 73.25,32.91 73.14,33.01 72.94,33.01 72.84,32.91 72.84,32.67 72.74,32.56 55.2,32.56 55.08,32.68 52.05,32.68 v2(51.26,33.47)
  BOTTOM w0.089: CPU1.AP30 v2(113.48,52.63) ; v2(51.26,33.47) 50.84,33.89 50.45,33.89 50.38,33.82 DM2.204
M_B_DQ48: length 76
  TOP w0.089: v1(51.1,32.27) v2(51.4,31.79)
  L6 w0.102: v2(51.4,31.79) 51.14,31.52 51.14,30.82 51.7,30.26 52.03,30.26 52.13,30.37 52.13,30.65 52.23,30.75 52.44,30.75 52.54,30.65 52.54,30.37 52.64,30.26 52.84,30.26 52.95,30.37 52.95,30.65 53.05,30.75 53.25,30.75 53.35,30.65 53.35,30.37 53.45,30.26 60.58,30.26 61.06,29.78 65.53,29.78 65.84,30.1 77.04,30.1 89.73,42.78 99.22,42.78 102.9,46.46 107.13,46.46 107.92,47.25 107.92,48.35 109.21,49.64 110.11,49.64 110.36,49.89 v2(110.84,49.89)
  BOTTOM w0.089: v2(51.4,31.79) 51.37,31.79 50.9,31.32 50.41,30.82 DM2.216 ; v2(110.84,49.89) CPU1.AU27
M_B_DQ49: length 76.7
  TOP w0.089: v1(52.93,31.05) v2(53.36,31.58)
  L6 w0.102: v2(53.36,31.58) 53.36,31.22 53.91,30.67 61.08,30.67 61.19,30.57 61.19,30.33 61.29,30.23 61.49,30.23 61.59,30.33 61.59,30.57 61.69,30.67 61.9,30.67 62,30.57 62,30.33 62.1,30.23 62.3,30.23 62.41,30.33 62.41,30.57 62.51,30.67 63.48,30.67 64.04,30.11 65.39,30.11 65.71,30.43 66.07,30.43 66.18,30.53 66.18,30.64 66.28,30.74 66.48,30.74 66.58,30.64 66.58,30.53 66.68,30.43 66.89,30.43 66.99,30.53 66.99,30.64 67.09,30.74 67.29,30.74 67.4,30.64 67.4,30.53 67.5,30.43 67.7,30.43 67.8,30.53 67.8,30.64 67.9,30.74 68.11,30.74 68.21,30.64 68.21,30.53 68.31,30.43 68.51,30.43 68.61,30.53 68.61,30.64 68.72,30.74 68.92,30.74 69.02,30.64 69.02,30.53 69.12,30.43 69.45,30.43 69.55,30.53 69.55,30.64 69.66,30.74 69.86,30.74 69.96,30.64 69.96,30.53 70.06,30.43 70.27,30.43 70.37,30.53 70.37,30.64 70.47,30.74 70.67,30.74 70.77,30.64 70.77,30.53 70.87,30.43 71.08,30.43 71.18,30.53 71.18,30.64 71.28,30.74 71.48,30.74 71.59,30.64 71.59,30.53 71.69,30.43 76.91,30.43 89.59,43.11 99.09,43.11 102.71,46.73 102.71,47.04 103.37,47.69 106.99,47.69 109.14,49.84 109.98,49.84 110.44,50.3 111.02,50.3 v2(111.53,50.8)
  BOTTOM w0.089: DM2.215 53.9,31.07 53.39,31.58 v2(53.36,31.58) ; v2(111.53,50.8) CPU1.AT27
M_B_DQ50: length 75.3
  TOP w0.089: v1(52.22,28.51) v2(52.17,29.09)
  L6 w0.102: v2(112.18,49.89) 111.98,49.89 111.15,49.06 109.67,49.06 108.61,47.99 108.61,47.03 107.26,45.68 104.37,45.68 100.25,41.57 89.88,41.57 76.36,28.04 55.73,28.04 55.4,28.37 52.89,28.37 v2(52.17,29.09)
  BOTTOM w0.089: CPU1.AT25 v2(112.18,49.89) ; v2(52.17,29.09) 50.89,27.81 48.67,27.81 DM2.228
M_B_DQ51: length 74.8
  TOP w0.089: v1(54.73,27.75) v2(54.4,27.19)
  L6 w0.102: v2(112.83,48.98) 112.51,48.98 111.97,48.96 111.68,48.68 109.83,48.68 109.07,47.91 109.07,46.95 107.42,45.3 104.64,45.3 100.08,40.74 89.99,40.74 75.9,26.66 69.68,26.66 69.58,26.76 69.58,27.14 69.48,27.25 69.27,27.25 69.18,27.15 69.18,26.76 69.07,26.66 63.14,26.66 62.41,27.38 55.46,27.38 55.22,27.62 54.86,27.62 54.43,27.19 v2(54.4,27.19)
  BOTTOM w0.089: CPU1.AU25 111.76,48.98 v2(112.83,48.98) ; DM2.229 55.62,27.58 55.58,27.62 54.86,27.62 54.44,27.19 v2(54.4,27.19)
M_B_DQ52: length 76.9
  TOP w0.089: v1(113.15,50.35) v2(113.48,50.8)
  L6 w0.102: v2(113.48,50.8) 113.08,51.21 111.36,51.21 111.1,50.95 111.1,50.81 110.78,50.5 110.45,50.5 110.29,50.65 109.56,50.65 109.32,50.42 109.32,50.29 106.94,47.91 103.31,47.91 102.52,47.12 102.52,46.81 99.15,43.44 89.45,43.44 77.08,31.07 75.98,31.07 75.88,30.97 75.88,30.86 75.78,30.76 75.57,30.76 75.47,30.86 75.47,30.97 75.37,31.07 75.17,31.07 75.06,30.97 75.06,30.86 74.96,30.76 74.76,30.76 74.66,30.86 74.66,30.97 74.56,31.07 74.23,31.07 74.13,30.97 74.13,30.86 74.02,30.76 73.82,30.76 73.72,30.86 73.72,30.97 73.62,31.07 73.41,31.07 73.31,30.97 73.31,30.86 73.21,30.76 73.01,30.76 72.91,30.86 72.91,30.97 72.8,31.07 72.6,31.07 72.5,30.97 72.5,30.86 72.4,30.76 72.19,30.76 72.09,30.86 72.09,30.97 71.99,31.07 71.66,31.07 71.56,31.17 71.56,31.31 71.46,31.41 71.25,31.41 71.15,31.31 71.15,31.17 71.05,31.07 70.85,31.07 70.75,31.17 70.75,31.31 70.65,31.41 70.44,31.41 70.34,31.31 70.34,31.17 70.24,31.07 70.04,31.07 69.93,31.17 69.93,31.31 69.83,31.41 69.63,31.41 69.53,31.31 69.53,31.17 69.43,31.07 69.22,31.07 69.12,31.17 69.12,31.31 69.02,31.41 68.82,31.41 68.71,31.31 68.71,31.17 68.61,31.07 55.76,31.07 54.81,32.02 54.43,32.02 v2(54,31.58)
  BOTTOM w0.089: CPU1.AP27 v2(113.48,50.8) ; DM2.211 54.49,32.07 v2(54,31.58)
M_B_DQ53: length 77.4
  TOP w0.089: v1(49.5,31.79) v2(50.08,31.79)
  L6 w0.102: v2(50.08,31.79) 50.08,32.48 50.35,32.75 51.3,32.75 51.71,32.35 54.95,32.35 55.9,31.4 56.23,31.4 56.33,31.5 56.33,31.64 56.43,31.75 56.63,31.75 56.73,31.64 56.73,31.5 56.84,31.4 67.86,31.4 68.2,31.74 77.28,31.74 89.32,43.77 89.37,43.77 99.21,43.77 101.53,46.09 101.53,46.61 103.02,48.1 106.86,48.1 109.13,50.37 109.13,50.49 109.96,51.32 111.08,51.32 111.16,51.4 113.22,51.4 113.31,51.31 113.62,51.31 v2(114.13,50.8)
  BOTTOM w0.089: v2(50.08,31.79) 50.06,31.79 50.02,31.82 DM2.212 ; CPU1.AN27 v2(114.13,50.8)
M_B_DQ54: length 77
  TOP w0.089: v1(50.87,28.54) v2(50.82,29.11)
  L6 w0.102: v2(50.82,29.11) 52.59,27.35 52.59,27.12 53.11,26.6 62.61,26.6 62.88,26.33 76.04,26.33 90.13,40.41 100.95,40.41 105.52,44.99 107.39,44.99 110.23,47.83 110.23,47.99 110.73,48.49 111.76,48.49 111.93,48.66 112.57,48.66 112.66,48.57 113.07,48.57 v2(113.48,48.98)
  BOTTOM w0.089: DM2.224 49.71,28.82 49.85,28.68 50.4,28.68 v2(50.82,29.11) ; CPU1.AN25 v2(113.48,48.98)
M_B_DQ55: length 76.8
  TOP w0.089: v1(53.46,27.75) v2(53.13,27.19)
  L6 w0.102: v2(53.13,27.19) 53.89,27.95 55.36,27.95 55.6,27.71 70.14,27.71 70.24,27.61 70.24,27.32 70.34,27.22 70.54,27.22 70.64,27.32 70.64,27.61 70.74,27.71 76.49,27.71 89.85,41.07 100.13,41.07 104.55,45.49 107.34,45.49 108.86,47.01 108.86,47.98 109.75,48.87 111.32,48.87 111.91,49.46 113.05,49.46 v2(113.48,49.89)
  BOTTOM w0.089: v2(53.13,27.19) 54.52,28.57 DM2.225 ; CPU1.AP25 v2(113.48,49.89)
M_B_DQ56: length 80.3
  TOP w0.089: v1(55.09,25.84) v2(54.78,25.36)
  L6 w0.102: v2(112.18,48.06) 112.15,48.04 111.72,48.04 111.11,47.43 110.38,47.43 108.34,45.39 108.34,43.86 105.96,41.48 102.65,41.48 100.31,39.15 90.27,39.15 76.59,25.46 75.72,25.46 75.62,25.36 75.62,24.85 75.52,24.74 75.32,24.74 75.22,24.85 75.22,25.36 75.12,25.46 74.91,25.46 74.81,25.36 74.81,24.85 74.71,24.74 74.51,24.74 74.4,24.85 74.4,25.36 74.3,25.46 73.97,25.46 73.87,25.36 73.87,24.85 73.77,24.75 73.57,24.75 73.46,24.85 73.46,25.36 73.36,25.46 73.16,25.46 73.06,25.36 73.06,24.85 72.96,24.75 72.75,24.75 72.65,24.85 72.65,25.36 72.55,25.46 72.35,25.46 72.24,25.36 72.24,24.85 72.14,24.75 71.94,24.75 71.84,24.85 71.84,25.36 71.74,25.46 70.64,25.46 70.54,25.36 70.54,24.85 70.44,24.74 70.24,24.74 70.13,24.85 70.13,25.36 70.03,25.46 69.83,25.46 69.73,25.36 69.73,24.85 69.63,24.74 69.42,24.74 69.32,24.85 69.32,25.36 69.22,25.46 68.89,25.46 68.35,24.92 63.01,24.92 62.83,24.74 54.98,24.74 54.78,24.94 v2(54.78,25.36)
  BOTTOM w0.089: DM2.237 56.85,25.57 55.88,25.57 55.67,25.79 55.22,25.79 54.79,25.36 v2(54.78,25.36) ; CPU1.AT22 v2(112.18,48.06)
M_B_DQ57: length 80.4
  TOP w0.089: v1(52.62,24.85) v2(52.87,25.36)
  L6 w0.102: v2(110.6,47.02) 110.24,47.02 108.53,45.31 108.53,43.78 106.04,41.29 103.74,41.29 101.27,38.82 97.09,38.82 96.99,38.71 96.99,38.16 96.89,38.06 96.68,38.06 96.58,38.16 96.58,38.71 96.48,38.82 94.04,38.82 93.94,38.71 93.94,38.23 93.84,38.13 93.64,38.13 93.54,38.23 93.54,38.71 93.43,38.82 93.1,38.82 93,38.71 93,38.22 92.9,38.12 92.7,38.12 92.6,38.22 92.6,38.71 92.49,38.82 92.29,38.82 92.19,38.71 92.19,38.22 92.09,38.12 91.88,38.12 91.78,38.22 91.78,38.71 91.68,38.82 91.35,38.82 91.25,38.71 91.25,38.2 91.15,38.1 90.94,38.1 90.84,38.2 90.84,38.71 90.74,38.82 90.41,38.82 76.01,24.41 53.42,24.41 52.87,24.96 v2(52.87,25.36)
  BOTTOM w0.089: DM2.236 52.41,25.82 v2(52.87,25.36) ; CPU1.AU22 v2(110.6,47.02)
M_B_DQ58: length 78.7
  TOP w0.089: v1(111.14,46.64) v2(111.53,46.23)
  L6 w0.102: v2(111.53,46.23) 111.53,46.17 110.56,45.19 110.55,45.19 109.67,44.32 109.67,43.68 106.31,40.31 104.51,40.31 100.89,36.7 90.16,36.7 75.71,22.24 74.92,22.24 74.82,22.35 74.82,23 74.72,23.1 74.52,23.1 74.42,23 74.42,22.35 74.31,22.24 70.77,22.24 70.67,22.35 70.67,23.02 70.56,23.12 70.36,23.12 70.26,23.02 70.26,22.35 70.16,22.24 69.72,22.24 68.84,23.12 58.2,23.12 58.1,23.02 58.1,22.53 58,22.43 57.8,22.43 57.69,22.53 57.69,23.02 57.59,23.12 57.26,23.12 57.16,23.02 57.16,22.32 57.06,22.22 56.86,22.22 56.75,22.32 56.75,23.02 56.65,23.12 56.45,23.12 56.35,23.02 56.35,22.32 56.25,22.22 56.04,22.22 55.94,22.32 55.94,23.02 55.84,23.12 55.51,23.12 54.7,22.31 v2(54.68,22.31)
  BOTTOM w0.089: CPU1.AU21 v2(111.53,46.23) ; DM2.249 56.85,22.57 55.66,22.57 55.49,22.74 55.14,22.74 54.71,22.31 v2(54.68,22.31)
M_B_DQ59: length 79.9
  TOP w0.089: v2(50.11,22.31) 49.65,22.77 v1(49.4,22.77)
  L6 w0.102: v2(50.11,22.31) 50.54,22.74 53,22.74 53.87,21.88 58.47,21.88 58.57,21.98 58.57,22.69 58.67,22.79 58.87,22.79 58.98,22.69 58.98,21.98 59.08,21.88 59.28,21.88 59.38,21.98 59.38,22.69 59.48,22.79 59.69,22.79 59.79,22.69 59.79,21.98 59.89,21.88 61.83,21.88 62.73,22.79 68.62,22.79 69.5,21.91 75.84,21.91 90.28,36.35 101.2,36.35 104.08,39.23 105.47,39.23 106.12,39.88 106.15,39.88 109.88,43.62 109.88,44.25 110.63,45 110.64,45 111.36,45.72 111.67,45.72 v2(112.18,46.23)
  BOTTOM w0.089: DM2.250 50.1,22.32 v2(50.11,22.31) ; CPU1.AT21 v2(112.18,46.23)
M_B_DQ60: length 82.1
  TOP w0.089: v1(50.44,26.71) v2(50.74,27.19)
  L6 w0.102: v2(50.74,27.19) 50.74,26.61 51.19,26.16 51.94,26.16 52.42,25.68 52.42,24.48 52.82,24.08 76.15,24.08 89.74,37.67 97.39,37.67 97.49,37.77 97.49,38.38 97.59,38.49 97.79,38.49 97.89,38.38 97.89,37.77 98,37.67 98.33,37.67 98.43,37.77 98.43,38.38 98.53,38.49 98.73,38.49 98.83,38.38 98.83,37.77 98.94,37.67 100.51,37.67 103.93,41.1 106.12,41.1 108.73,43.71 108.73,45.24 110.1,46.61 110.8,46.61 111.74,47.55 112.97,47.55 v2(113.48,48.06)
  BOTTOM w0.089: v2(50.74,27.19) 50.71,27.19 50.29,26.76 49.93,26.76 49.87,26.82 DM2.232 ; CPU1.AN22 v2(113.48,48.06)
M_B_DQ61: length 82.1
  TOP w0.089: v1(53.41,25.95) v2(53.51,25.36)
  L6 w0.102: v2(112.83,48.06) 112.75,48.06 112.35,48.47 112.01,48.47 111.84,48.3 111.69,48.3 111.05,47.65 110.34,47.65 108.15,45.47 108.15,43.94 105.88,41.67 102.55,41.67 100.35,39.48 90.14,39.48 76.45,25.79 62.56,25.79 62.46,25.69 62.46,25.21 62.36,25.11 62.15,25.11 62.05,25.21 62.05,25.69 61.95,25.79 61.62,25.79 61.52,25.69 61.52,25.18 61.42,25.07 61.21,25.07 61.11,25.18 61.11,25.69 61.01,25.79 60.81,25.79 60.7,25.69 60.7,25.18 60.6,25.07 60.4,25.07 60.3,25.18 60.3,25.69 60.2,25.79 59.99,25.79 59.89,25.69 59.89,25.18 59.79,25.07 59.59,25.07 59.49,25.18 59.49,25.69 59.38,25.79 57.8,25.79 57.7,25.69 57.7,25.18 57.6,25.07 57.39,25.07 57.29,25.18 57.29,25.69 57.19,25.79 56.99,25.79 56.88,25.69 56.88,25.18 56.78,25.07 56.58,25.07 56.48,25.18 56.48,25.69 56.38,25.79 53.97,25.79 53.53,25.36 v2(53.51,25.36)
  BOTTOM w0.089: v2(53.51,25.36) 53.54,25.36 54.75,26.57 56.85,26.57 DM2.233 ; CPU1.AP22 v2(112.83,48.06)
M_B_DQ62: length 80.9
  TOP w0.089: v2(112.83,46.23) 112.83,46.36 v1(112.5,46.69)
  L6 w0.102: v2(112.83,46.23) 113.34,45.73 114.29,45.73 114.53,45.48 114.53,45.15 114.26,44.87 114.21,44.82 110.73,44.82 110.72,44.81 110.71,44.81 110.11,44.22 110.11,43.07 110.14,43.04 110.14,42.7 107.74,40.3 106.2,39.7 105.53,39.02 104.34,39.02 101.34,36.02 90.42,36.02 75.95,21.55 53.78,21.55 53.55,21.67 v2(52.65,22.31)
  BOTTOM w0.089: DM2.245 54.42,23.58 53.63,23.3 v2(52.65,22.31) ; CPU1.AP21 113.15,46.56 v2(112.83,46.23)
M_B_DQ63: length 81.8
  TOP w0.089: v1(113.85,47.63) v2(113.48,47.15)
  L6 w0.102: v2(113.48,47.15) 114.72,45.9 114.72,45.07 114.34,44.68 114.34,44.68 113.55,43.9 110.59,43.9 110.3,43.61 110.3,43.27 110.36,43.21 110.36,42.55 106.44,38.63 104.46,38.63 101.52,35.69 90.56,35.69 76.09,21.22 51.64,21.22 51.38,21.48 v2(51.38,22.31)
  BOTTOM w0.089: v2(51.38,22.31) 50.37,23.32 DM2.246 ; CPU1.AN21 v2(113.48,47.15)
M_B_DQS_DN0: length 78.3
  TOP w0.089: v1(50.44,79.49) v2(50.74,79.01)
  L6 w0.127: v2(116.8,72.59) 116.49,72.59 116.13,72.95 116.13,73.57 115.78,73.92 115.11,73.92 113.14,75.89 113.13,75.89 113.12,75.9 111.48,75.9 111.05,76.33 111.05,77.58 109.19,79.43 108.13,79.43 107.74,79.05 107.16,79.05 106.69,79.52 106.24,79.52 105.77,79.05 105.25,79.05 102.32,81.97 95.43,81.97 93.26,79.8 69.82,79.8 69.58,79.56 68.75,79.56 68.52,79.8 62.59,79.8 62.13,79.34 56.37,79.34 55.45,78.41 53.15,78.41 52.87,78.69 52.87,79.53 52.57,79.83 51.57,79.83 v2(50.74,79.01)
  BOTTOM w0.089: v2(50.74,79.01) 50.71,79.01 50.29,78.58 49.93,78.58 49.69,78.82 DM2.32 ; CPU1.AH66 v2(116.8,72.59)
M_B_DQS_DN1: length 82
  TOP w0.089: v1(53.51,84.06) v2(53.77,83.56)
  L6 w0.127: v2(117.73,78.9) 117.27,79.35 117.27,80.04 110.23,87.08 108.91,87.08 108.15,87.83 104.65,87.83 102.4,85.58 94.29,85.58 93.2,84.48 58.47,84.48 58.21,84.22 58.21,83.86 58.08,83.73 57.83,83.73 57.7,83.86 57.7,84.22 57.44,84.48 56.86,84.48 56.6,84.22 56.6,83.86 56.47,83.74 56.22,83.74 56.09,83.86 56.09,84.22 55.83,84.48 54.3,84.48 54.01,84.2 54.01,83.8 v2(53.77,83.56)
  BOTTOM w0.089: CPU1.AG69 117.28,74.57 117.28,74.89 117.34,75.09 117.34,75.29 117.29,75.44 117.29,75.72 117.81,76.23 117.81,77.16 118.18,77.54 118.18,78.44 v2(117.73,78.9) ; DM2.11 55.84,84.07 55.69,84.22 54.22,84.22 54,84.01 v2(53.77,83.56)
M_B_DQS_DN2: length 69.9
  TOP w0.089: v1(54.02,73.27) v2(54.14,72.71)
  L6 w0.127: v2(54.14,72.71) 54.15,72.71 54.15,73.23 55.77,74.85 58.29,74.85 58.41,74.98 58.41,75.13 58.67,75.39 59.12,75.39 59.38,75.13 59.38,74.98 59.5,74.85 59.89,74.85 60.01,74.98 60.01,75.13 60.27,75.39 60.72,75.39 60.98,75.13 60.98,74.98 61.1,74.85 61.36,74.85 61.49,74.98 61.49,75.13 61.75,75.39 62.19,75.39 62.45,75.13 62.45,74.98 62.58,74.85 69.25,74.85 69.36,74.96 69.36,75.22 69.62,75.48 70.06,75.48 70.32,75.22 70.32,74.96 70.43,74.85 72.34,74.85 73.44,75.95 73.91,76.42 76.8,76.42 95.13,76.42 96.46,77.75 102.23,77.75 103.21,76.78 103.88,76.1 104.49,76.1 106,74.59 108.54,74.59 109.22,73.91 109.69,73.46 110.35,73.46 110.93,72.89 110.93,72.89 111.98,71.84 v2(112.18,71.84)
  BOTTOM w0.089: v2(54.14,72.71) 54.34,73.18 54.73,73.57 56.85,73.57 DM2.53 ; CPU1.AR66 v2(112.18,71.84)
M_B_DQS_DN3: length 70.6
  TOP w0.089: v1(52.19,67.17) v2(51.84,67.65)
  L6 w0.089: 110.23,68.97 110.24,68.97 110.26,68.95 110.32,68.95 110.57,68.7 110.71,68.7 111.22,68.7 111.28,68.77 111.85,68.77 111.93,68.69 112.45,68.69 v2(112.82,69.07)
  L6 w0.127: 110.23,68.97 109.36,68.97 108.5,69.83 106.87,69.83 106.22,70.48 106.22,70.99 104.41,72.8 99.37,72.8 99.04,72.47 75.85,72.47 73.23,69.85 59.64,69.85 58.57,68.78 58,68.78 56.85,67.63 53.13,67.63 52.71,67.21 51.87,67.21 51.78,67.3 51.78,67.59 v2(51.84,67.65)
  BOTTOM w0.089: CPU1.AR61 v2(112.82,69.07) ; v2(51.84,67.65) 51.41,68.08 51.21,68.08 51.01,68.27 49.91,68.27 49.86,68.32 DM2.74
M_B_DQS_DN4: length 73.5
  TOP w0.089: v1(53.54,40.12) v2(53.85,39.63)
  L6 w0.102: v2(112.12,57.23) 112.12,57.16 111.73,56.77 111.28,56.77 111.12,56.93 109.4,56.93 107.9,55.43 107.57,55.43
  L6 w0.127: v2(53.85,39.63) 54.49,40.27 59.31,40.27 59.89,40.85 61.71,40.85 61.97,40.59 61.97,40.27 62.1,40.15 62.35,40.15 62.48,40.27 62.48,40.59 62.74,40.85 72.44,40.85 72.7,40.59 72.7,40.41 72.83,40.28 73.08,40.28 73.21,40.41 73.21,40.59 73.47,40.85 74.04,40.85 74.3,40.59 74.3,40.37 74.43,40.25 74.68,40.25 74.81,40.37 74.81,40.59 75.07,40.85 75.64,40.85 75.9,40.59 75.9,40.37 76.03,40.25 76.28,40.25 76.41,40.37 76.41,40.59 76.67,40.85 77.98,40.85 88.8,51.68 98.06,51.68 101.82,55.44 103.69,55.44 103.71,55.43 107.57,55.43
  BOTTOM w0.089: CPU1.AT38 v2(112.12,57.23) ; DM2.177 55.73,40.57 55.72,40.56 54.65,40.56 53.85,39.76 v2(53.85,39.63)
M_B_DQS_DN5: length 75.2
  TOP w0.089: v1(52.34,34.43) v2(52.29,35.04)
  L6 w0.089: v2(112.15,53.59) 111.98,53.42 111.14,53.42 111,53.27 110.64,53.27 110.53,53.38 110.37,53.38 109.52,53.38 109.52,53.38 109.34,53.38 109.34,53.38 109.31,53.38
  L6 w0.127: 109.31,53.38 109.18,53.25 108.58,52.64 108.58,52.06 107.34,50.82 102.45,50.82 99.41,47.78 90.14,47.78 82.62,40.26 77,34.63 69.27,34.63 68.74,35.16 55.63,35.16 55.37,34.9 53.89,34.9 53.47,34.48 52.18,34.48 52.02,34.64 52.02,34.78 v2(52.29,35.04)
  BOTTOM w0.089: CPU1.AT32 111.85,53.29 v2(112.15,53.59) ; v2(52.29,35.04) 52.29,35.24 52.07,35.46 51.38,35.46 51.22,35.63 50.71,35.63 50.09,35.01 49.86,35.01 49.75,35.11 49.75,35.25 49.67,35.32 DM2.198
M_B_DQS_DN6: length 76.1
  TOP w0.089: v1(53.33,29.12) v2(53.66,29.6)
  L6 w0.089: 109.4,49.2 109.43,49.24 111.07,49.24 111.68,49.85 111.68,49.96 112.01,50.29 112.34,50.29 112.74,49.89 v2(112.83,49.89)
  L6 w0.127: 109.4,49.2 109.39,49.2 108.87,48.69 108.35,48.17 108.35,47.06 107.2,45.9 103.05,45.9 99.33,42.18 89.97,42.18 76.2,28.41 57.48,28.41 57.22,28.67 57.22,29.24 57.1,29.37 56.85,29.37 56.72,29.24 56.72,28.67 56.46,28.41 55.88,28.41 55.77,28.53 55.55,28.74 54.21,28.74 53.94,29.01 53.94,29.32 v2(53.66,29.6)
  BOTTOM w0.089: v2(53.66,29.6) 54.02,29.95 54.02,30.09 54.3,30.37 55.39,30.37 55.69,30.07 DM2.219 ; CPU1.AR25 v2(112.83,49.89)
M_B_DQS_DN7: length 80.3
  TOP w0.089: v1(50.41,24.88) v2(50.72,25.36)
  L6 w0.089: v2(112.83,47.15) 112.32,46.64 111.35,46.64 110.93,46.22 110.24,46.22 109.16,45.14 109.16,44.84 109.17,44.84
  L6 w0.127: v2(50.72,25.36) 50.9,25.18 50.9,24.11 51.52,23.49 71.31,23.49 71.44,23.36 71.44,22.87 71.7,22.61 72.14,22.61 72.4,22.87 72.4,23.36 72.53,23.49 72.79,23.49 72.91,23.36 72.91,22.87 73.17,22.61 73.62,22.61 73.88,22.87 73.88,23.36 74,23.49 76.41,23.49 89.99,37.06 100.74,37.06 104.19,40.52 106.22,40.52 109.17,43.46 109.17,44.84
  BOTTOM w0.089: v2(50.72,25.36) 50.18,24.82 DM2.240 ; CPU1.AR22 v2(112.83,47.15)
M_B_DQS_DP0: length 78.4
  TOP w0.089: v1(51.66,79.51) v2(51.38,79.01)
  L6 w0.127: v2(116.8,71.94) 116.8,71.95 115.9,72.85 115.9,73.48 115.69,73.69 115.01,73.69 113.04,75.66 113.04,75.66 113.02,75.67 111.38,75.67 110.82,76.24 110.82,77.48 109.1,79.2 108.22,79.2 107.84,78.82 107.06,78.82 106.59,79.29 106.34,79.29 105.87,78.82 105.15,78.82 102.23,81.74 95.53,81.74 93.35,79.57 69.91,79.57 69.67,79.33 68.66,79.33 68.42,79.57 62.69,79.57 62.23,79.11 56.47,79.11 55.55,78.19 53.05,78.19 52.64,78.6 52.64,79.44 52.47,79.61 51.98,79.61 v2(51.38,79.01)
  BOTTOM w0.089: CPU1.AH65 v2(116.8,71.94) ; v2(51.38,79.01) 50.76,78.39 49.7,78.39 49.64,78.32 DM2.34
M_B_DQS_DP1: length 81.8
  TOP w0.089: v1(54.86,84.09) v2(54.62,83.56)
  L6 w0.127: v2(54.62,83.56) 54.37,83.56 54.24,83.69 54.24,84.1 54.39,84.26 55.73,84.26 55.86,84.13 55.86,83.77 56.12,83.51 56.57,83.51 56.83,83.77 56.83,84.13 56.95,84.26 57.34,84.26 57.47,84.13 57.47,83.76 57.73,83.5 58.17,83.5 58.43,83.76 58.43,84.13 58.56,84.26 93.29,84.26 94.38,85.35 102.49,85.35 104.74,87.6 108.06,87.6 108.81,86.85 110.14,86.85 117.04,79.95 117.04,78.45 117.25,78.24 v2(117.5,78.24)
  BOTTOM w0.089: v2(54.62,83.56) 54.57,83.51 54.29,83.51 54.2,83.61 54.2,83.93 54.3,84.03 55.61,84.03 55.76,83.88 55.76,83.72 55.76,83.72 55.9,83.57 56.85,83.57 DM2.13 ; CPU1.AG70 117,74.54 117.1,74.64 117.1,74.92 117.16,75.12 117.16,75.26 117.12,75.41 117.12,75.81 117.62,76.31 117.62,77.24 117.99,77.61 117.99,78.36 117.88,78.47 117.6,78.47 117.5,78.37 v2(117.5,78.24)
M_B_DQS_DP2: length 69.9
  TOP w0.089: v1(55.06,72.17) v2(54.78,72.71)
  L6 w0.127: v2(54.78,72.71) 54.6,72.88 54.6,73.37 55.86,74.62 58.38,74.62 58.64,74.89 58.64,75.04 58.77,75.16 59.02,75.16 59.15,75.04 59.15,74.89 59.41,74.62 59.98,74.62 60.24,74.89 60.24,75.04 60.37,75.16 60.62,75.16 60.75,75.04 60.75,74.89 61.01,74.62 61.45,74.62 61.71,74.89 61.71,75.04 61.84,75.16 62.1,75.16 62.22,75.04 62.22,74.89 62.48,74.62 69.35,74.62 69.59,74.86 69.59,75.12 69.71,75.25 69.97,75.25 70.09,75.12 70.09,74.86 70.33,74.62 72.43,74.62 73.54,75.73 74,76.19 76.85,76.19 95.22,76.19 96.55,77.53 102.14,77.53 103.79,75.87 104.4,75.87 105.91,74.36 108.45,74.36 109.06,73.75 109.6,73.23 110.26,73.23 110.66,72.84 110.66,72.84 110.7,72.8 110.7,72.79 111.73,71.76 111.73,71.57 112.18,71.12 v2(112.18,70.92)
  BOTTOM w0.089: v2(54.78,72.71) 54.59,72.89 54.59,73.17 54.81,73.38 55.69,73.38 56,73.07 DM2.55 ; CPU1.AR65 v2(112.18,70.92)
M_B_DQS_DP3: length 70.5
  TOP w0.089: v1(50.82,68.16) v2(51.1,67.65)
  L6 w0.089: 110.23,68.74 110.26,68.74 110.49,68.51 110.78,68.51 111.3,68.51 111.36,68.58 111.77,68.58 111.85,68.5 112.55,68.5 v2(112.82,68.23)
  L6 w0.127: 110.23,68.74 109.27,68.74 108.4,69.6 106.78,69.6 105.99,70.39 105.99,70.9 104.32,72.57 99.47,72.57 99.37,72.48 99.14,72.25 75.94,72.25 73.33,69.63 59.73,69.63 58.66,68.56 58.1,68.56 56.95,67.4 53.22,67.4 52.8,66.98 51.77,66.98 v2(51.1,67.65)
  BOTTOM w0.089: v2(51.1,67.65) 51.1,67.91 50.94,68.08 49.94,68.08 49.69,67.82 DM2.76 ; CPU1.AR60 v2(112.82,68.23)
M_B_DQS_DP4: length 73.6
  TOP w0.089: v1(54.96,40.22) v2(54.56,39.63)
  L6 w0.102: v2(112.77,57.21) 112.77,56.92 112.65,56.8 112.05,56.8 111.81,56.57 111.19,56.57 111.04,56.72 109.48,56.72 107.97,55.21 107.67,55.21 107.66,55.2 107.57,55.2
  L6 w0.127: 107.57,55.2 103.61,55.2 103.6,55.21 101.98,55.21 101.97,55.2 101.9,55.2 98.16,51.45 88.9,51.45 78.07,40.63 76.77,40.63 76.64,40.5 76.64,40.28 76.38,40.02 75.93,40.02 75.67,40.28 75.67,40.5 75.55,40.63 75.17,40.63 75.04,40.5 75.04,40.28 74.78,40.02 74.33,40.02 74.07,40.28 74.07,40.5 73.95,40.63 73.57,40.63 73.44,40.5 73.44,40.31 73.18,40.05 72.73,40.05 72.47,40.31 72.47,40.5 72.35,40.63 62.84,40.63 62.71,40.5 62.71,40.18 62.45,39.92 62,39.92 61.74,40.18 61.74,40.5 61.62,40.63 59.99,40.63 59.4,40.04 54.76,40.04 54.56,39.84 v2(54.56,39.63)
  BOTTOM w0.089: DM2.179 55.91,40.07 55.62,40.37 54.73,40.37 54.4,40.04 54.4,39.78 v2(54.56,39.63) ; CPU1.AR38 v2(112.77,57.21)
M_B_DQS_DP5: length 75.1
  TOP w0.089: v1(51.1,35.44) v2(51.54,35.04)
  L6 w0.089: 109.43,53.17 109.45,53.19 110.37,53.19 110.48,53.08 111.07,53.08 111.22,53.23 111.94,53.23 111.98,53.19 112.4,53.19 v2(112.79,53.57) ; 109.35,53.09 109.41,53.15
  L6 w0.127: 109.41,53.15 109.43,53.17 ; 109.35,53.09 108.81,52.55 108.81,51.96 107.43,50.59 102.54,50.59 99.5,47.55 90.24,47.55 82.72,40.03 82.72,40.03 77.09,34.4 69.17,34.4 68.64,34.93 55.73,34.93 55.47,34.67 53.99,34.67 53.57,34.25 52.09,34.25 51.8,34.54 51.8,34.78 v2(51.54,35.04)
  BOTTOM w0.089: DM2.200 49.52,34.82 49.53,34.82 50.17,34.82 50.79,35.44 51.14,35.44 v2(51.54,35.04) ; CPU1.AR32 v2(112.79,53.57)
M_B_DQS_DP6: length 76.1
  TOP w0.089: v1(54.71,29.12) v2(54.38,29.6)
  L6 w0.089: v2(112.83,50.8) 113.09,50.54 113.09,50.41 112.98,50.29 112.61,50.29 112.42,50.48 111.93,50.48 111.49,50.04 111.49,49.93 111,49.43 109.29,49.43
  L6 w0.127: 109.29,49.43 108.13,48.27 108.13,47.16 107.1,46.13 102.95,46.13 99.23,42.41 89.88,42.41 76.11,28.64 57.58,28.64 57.45,28.77 57.45,29.34 57.19,29.6 56.75,29.6 56.49,29.33 56.49,28.77 56.36,28.64 55.98,28.64 55.65,28.97 54.3,28.97 54.17,29.1 54.17,29.4 v2(54.38,29.6)
  BOTTOM w0.089: DM2.221 55.92,29.57 55.31,30.18 54.38,30.18 54.21,30.01 54.21,29.77 v2(54.38,29.6) ; v2(112.83,50.8) CPU1.AR27
M_B_DQS_DP7: length 80.3
  TOP w0.089: v1(51.63,25.87) v2(51.35,25.36)
  L6 w0.089: v2(112.18,47.15) 112.18,46.95 112.06,46.83 111.27,46.83 110.85,46.41 110.16,46.41 108.97,45.22 108.97,44.94 108.94,44.9 108.94,44.84
  L6 w0.127: 108.94,44.84 108.94,43.56 108.92,43.54 108.92,43.54 106.13,40.75 104.1,40.75 100.65,37.29 89.89,37.29 76.32,23.71 73.91,23.71 73.65,23.45 73.65,22.97 73.52,22.84 73.27,22.84 73.14,22.97 73.14,23.45 72.88,23.71 72.44,23.71 72.18,23.45 72.18,22.97 72.05,22.84 71.79,22.84 71.67,22.97 71.67,23.45 71.41,23.71 51.62,23.71 51.13,24.2 51.13,25.13 v2(51.35,25.36)
  BOTTOM w0.089: v2(51.35,25.36) 51.35,25.01 50.97,24.63 49.89,24.63 49.58,24.32 DM2.242 ; v2(112.18,47.15) CPU1.AR21
M_B_PARITY: length 76.9
  TOP w0.152: v1(50.59,49.26) v2(50.88,49.76)
  L6 w0.089: v2(113.47,58.99) 113.05,59.41 111.16,59.41 110.99,59.57 110.26,59.57
  L6 w0.165: v2(50.88,49.76) 50.88,50.07 51.09,50.28 53.43,50.28 53.63,50.07 53.63,49.79 53.84,49.59 60.62,49.59 62.7,51.66 62.73,51.66 63.18,52.12 67.29,52.12 68.54,53.37 78.86,53.37 79.36,53.88 84.59,59.1 98.34,59.1 98.98,59.74 101.04,59.74 101.6,60.31 101.73,60.31 101.74,60.32 101.85,60.32 102.8,61.28 106.62,61.28 108.32,59.57 110.26,59.57
  BOTTOM w0.152: DM2.143 56.01,51.07 55.19,50.25 51.38,50.25 v2(50.88,49.76) ; CPU1.AP43 v2(113.47,58.99)
M_VREF_CA_DIMMA: length 1.5
  BOTTOM w0.279: DM1.164 61.7,43.82 63.09,43.82 v2(63.14,43.87)
  vias: v1(68.24,45.33)
M_VREF_CA_DIMMB: length 1.5
  BOTTOM w0.279: DM2.164 48.65,43.82 50.04,43.82 v2(50.08,43.87)
  vias: v1(50.19,43.12)
MASK_SATA_LED#: length 115.7
  TOP w0.089: v2(53.49,3.01) 53.49,3.09 v1(52.93,3.64) 52.37,4.2 R6120.2 50.36,4.28 v2(49.74,4.28) ; v2(137.51,26.3) 137.89,26.68 137.89,27.04 138.41,27.56 140.64,27.56 140.71,27.48 141.43,27.48 143.05,25.87 145.82,25.87 147.64,24.04 KBC24.56
  L6 w0.089: v2(53.49,3.01) 53.98,3.5 69.61,3.5 69.62,3.5 72.5,3.5 75.2,6.2 77.82,6.2 79.87,8.25 80.41,8.25 82.1,9.95 83.38,9.95 85.1,11.67 85.78,11.67 87.05,12.94 90.9,12.94 91.76,13.8 94.98,13.8 98.09,16.91 99.24,16.91 99.59,16.56 101.4,16.56 102.63,17.79 103.7,17.79 104.4,18.5 109.64,18.5 110.14,19 113.75,19 114.38,18.38 120.16,18.38 120.85,19.07 123.19,19.07 127.26,23.13 127.26,24.55 131.55,28.85 133.8,28.85 136.14,26.5 137.31,26.5 v2(137.51,26.3)
  BOTTOM w0.089: Q6105.G v2(49.74,4.28)
ME_FWP: length 109.9
  TOP w0.089: v2(83.56,15.79) 83.56,17.51 v1(86.46,20.42) 87.27,21.22 87.27,24.07 86.04,25.29 86.04,41.25 92.89,48.1 R1909.1 ; KBC24.80 143.83,15.78 144.22,15.39 145,15.39 v2(145.56,14.82)
  L3 w0.089: v2(135.28,13.73) 135.94,14.39 145.14,14.39 v2(145.56,14.82)
  L4 w0.089: v2(135.28,13.73) 135.28,14.18 134.65,14.81 127.62,14.81 126.09,13.28 118.46,13.28 117.52,14.22 114.11,14.22 113.55,13.67 108.59,13.67 107.56,12.64 107.45,12.53 96.74,12.53 93.43,15.84 84.7,15.84 84.65,15.79 v2(83.56,15.79)
ME_SUS_PWR_ACK_R: length 28.5
  L3 w0.089: v2(112.16,29.55) 113.03,30.42 113.03,34.12 110.97,36.18 110.97,37.11 110.24,37.83 110.24,38.88 110.47,39.11 110.8,39.11 111.11,39.42 111.11,40.92 111.42,41.24 112.4,41.24 v2(112.83,41.66)
  BOTTOM w0.089: R1708.1 R1738.2 115.18,20.48 115.18,20.81 114.36,21.64 112.86,21.64 112.69,21.8 112.67,21.8 112.14,22.33 112.14,26.46 112.66,26.98 v1(112.66,28.79) 112.66,29.06 v2(112.16,29.55) ; CPU1.AR13 112.5,41.99 v2(112.83,41.66)
MEC_XTAL1_R: length 4.9
  TOP w0.089: KBC24.123 154.84,7.32 155.66,6.5 155.66,6.38 v1(155.7,6.34) 155.77,6.26 C2425.2 155.89,4.8 X2401.1
MEC_XTAL2: length 7.5
  TOP w0.089: R2461.2 158.68,3.19 X2401.2 158.35,4.78 C2424.2 158.21,5.65 v1(157.65,6.21) 157.55,6.31 156.42,6.31 155.64,7.09 KBC24.125
MEM_SMBCLK: length 74.4
  TOP w0.089: Q1801.3 70.08,14.63 RN1811.4 71.13,14.57 72.66,14.57 v1(72.92,14.82) 74.06,15.96 77.24,15.96 77.74,15.45 77.74,14.97 v2(77.54,14.77)
  L3 w0.127: v2(122.25,37.88) 122.68,37.45 122.68,36.02 123.23,35.47 123.23,31.73 122.19,30.69 122.19,26.63 118.5,22.94 116.73,22.94 114.64,20.84 105.47,20.84 104.36,21.95 104.06,21.95 101.91,21.95 99.37,19.41 91.99,19.41 88.69,16.11 85.17,16.11 84.57,16.71 83.71,16.71 82.76,15.76 82.44,15.76 80.54,15.76 79.09,14.31 78,14.31 v2(77.54,14.77)
  BOTTOM w0.089: CPU1.R7 v2(122.25,37.88)
MEM_SMBDATA: length 76.2
  TOP w0.089: v2(78.18,14.79) 78.01,14.96 78.01,15.57 77.68,15.9 77.35,16.23 v1(73.3,16.23) 71.01,16.23 RN1811.3 69.84,16.52 69.84,16.88 69.11,17.61 68.35,17.61 68.08,17.34 Q1801.6
  L3 w0.127: v2(122.25,38.51) 121.83,38.09 121.83,36.82 122.17,36.48 122.17,31.16 121.81,30.8 121.81,26.79 118.34,23.32 116.58,23.32 114.48,21.22 105.63,21.22 104.52,22.33 103.9,22.33 101.75,22.33 99.21,19.79 91.83,19.79 88.53,16.49 85.33,16.49 84.73,17.09 83.55,17.09 82.6,16.14 80.38,16.14 79.03,14.79 v2(78.18,14.79)
  BOTTOM w0.089: CPU1.R8 v2(122.25,38.51)
MIC2_VREFO_L: length 2.8
  TOP w0.203: HDA27.28 20.47,16.07 20.1,16.45 19.86,16.45 v1(19.83,16.47)
  TOP w0.254: RN2901.2 18.98,16.86 19.19,16.65 19.65,16.65 v1(19.83,16.47)
MIC2_VREFO_R: length 3.7
  TOP w0.203: 19.43,16.19 19.63,15.99 20.09,15.99 20.4,15.67 HDA27.29
  TOP w0.254: v1(18.18,15.28) 18.18,15.9 RN2901.1 19.43,16.19
MIC_CAP: length 3.6
  TOP w0.203: v2(20.02,14.3) 20.2,14.47 HDA27.32
  BOTTOM w0.254: C2735.1 21.1,14.91 20.81,15.2 v1(20.59,15.2) 20.45,15.05 20.45,14.72 v2(20.02,14.3)
MIC_GND: length 3.1
  TOP w0.254: v1(111.45,97.93) 111.93,97.93 v2(112.14,97.73)
  TOP w0.508: v2(112.14,97.73) 112.47,97.4 R5501.1
  BOTTOM w0.305: v2(112.14,97.73) 112.35,97.51 LCD1.45
MODEL_ID: length 9.8
  TOP w0.089: v1(145,1.54) 145.82,1.54 R2442.2 R2441.1 145.56,2.96 145.56,3.94 145.94,4.32 146.24,4.32 146.83,4.91 C2407.2 146.83,5.26 147.72,6.15 147.72,6.82 147.98,7.07 148.99,7.07 149.24,7.32 KBC24.109
MSATA_CLK_CPU: length 121.4
  L4 w0.14: v2(132.56,57.56) 132.56,57.19 132.43,57.06 132.24,57.06 132.19,57.01 132.19,56.45 132.44,56.2 140.89,56.2 144.34,52.75 144.34,52.75 144.5,52.59 144.5,36.77 146.75,34.52 146.75,31.69 148.62,29.82 150.4,29.82 154.06,26.16 165.89,26.16 166.28,25.78 176.94,25.78 177.07,25.65 201.35,25.65 201.42,25.72 202.67,25.72 202.84,25.89 v2(202.84,26.3)
  BOTTOM w0.102: v2(202.84,26.3) 202.84,25.9 202.92,25.82 203.17,25.82 203.25,25.74 203.25,25.51 202.13,24.4 202.13,19.88 206.19,15.81 ; v1(206.06,15.68) 206.19,15.81 ; 206.19,15.81 207.72,14.29 214.27,14.29 214.4,14.15 SSD1.55 ; v2(132.56,57.56) 132.56,57.82 132.42,57.96 131.84,57.96 131.61,58.19 130.75,58.19 CPU1.A40
MSATA_CLK_CPU#: length 121.5
  L4 w0.14: v2(203.63,26.3) 202.78,25.45 201.53,25.45 201.46,25.39 176.96,25.39 176.83,25.51 166.17,25.51 165.78,25.89 153.95,25.89 150.29,29.55 148.5,29.55 146.48,31.58 146.48,34.41 144.23,36.66 144.23,52.48 140.78,55.93 132.33,55.93 131.92,56.34 v2(131.92,57.56)
  BOTTOM w0.102: CPU1.B40 130.58,57.97 131.51,57.97 v2(131.92,57.56) ; v1(208.71,14.69) 208.71,14.51 ; 208.71,14.51 214.27,14.51 214.4,14.65 SSD1.53 ; 208.71,14.51 207.81,14.51 202.36,19.97 202.36,24.3 203.47,25.42 203.47,26.15 v2(203.63,26.3)
MSATA_DEVSLP_R: length 6.4
  TOP w0.089: v2(224.05,18.4) 224.58,17.87 AFTP6301.1 227.73,17.87 227.99,18.12 R6301.2
  BOTTOM w0.089: SSD1.38 v2(224.05,18.4)
MSATA_RST#: length 6.3
  TOP w0.089: R6308.2 v1(227.2,15.84) 224.3,15.84 v2(224.18,15.71)
  BOTTOM w0.089: SSD1.50 223.87,15.4 v2(224.18,15.71)
MSM#: length 1.8
  TOP w0.089: v2(114.09,67.26) 113.81,67.26 TP617.1
  BOTTOM w0.089: v2(114.09,67.26) 113.69,67.27 113.4,67.05 CPU1.AP56
MUX_ENA_L: length 3.8
  TOP w0.089: U3802.16 33.15,43.56 32.18,44.54 v1(32.15,44.54) 30.93,44.54 30.88,44.49 R3859.1
MUX_ENB_L: length 3.5
  TOP w0.089: U3802.10 36.25,43.94 36.95,44.64 v1(37.92,44.64) 38.6,44.64 R3860.1
MUX_HPD_PD: length 5.7
  TOP w0.089: U3801.23 37.32,60.44 37.9,61.02 37.9,61.21 39.34,62.65 R3849.2 39.34,64.27 v1(39.01,64.6)
MUX_INB_N: length 9.3
  TOP w0.089: R3854.2 35.91,39.97 36.41,39.46 37.9,39.46 38.68,40.25 38.68,41.13 38.4,41.41 37.89,41.41 37.56,41.74 v1(37.23,41.74) 36.52,41.03 36.52,41.01 36.24,40.73 35.33,40.73 35.22,40.84 U3802.4
MUX_INB_P: length 3.8
  TOP w0.089: R3853.2 37.18,40.42 36.72,39.97 v1(36.42,39.97) 35.96,40.42 35.28,40.42 34.82,40.88 U3802.3
MUX_SAI: length 2.6
  TOP w0.089: R3855.2 34.06,46.01 33.6,45.56 v1(33.6,45.27) 34.42,44.46 U3802.14
MUX_SAO: length 3.8
  TOP w0.089: R3857.2 32.66,46.27 32.38,45.99 v1(32.38,45.81) 32.38,45.55 33.24,44.69 33.78,44.69 34.02,44.45 U3802.15
MUX_SBI: length 2.3
  TOP w0.089: U3802.12 35.22,44.71 35.71,45.2 v1(35.71,45.33) 35.71,46.14 R3856.2
MUX_SBO: length 3.2
  TOP w0.089: R3858.2 36.93,45.68 v1(36.93,45.35) 36.43,44.86 35.77,44.86 35.62,44.7 U3802.11
MUX_TYPEC_RXN1: length 47.9
  TOP w0.102: v2(14.65,86.45) 14.88,86.67 R3835.1 ; v1(29.79,59.63) 29.79,59.78 ; 29.79,59.78 30.41,59.78 30.94,59.24 33.57,59.24 34.43,58.38 U3801.31 ; 29.79,59.78 v2(28.84,59.78)
  L4 w0.14: v2(14.65,86.45) 14.43,86.22 14.43,82.32 15.88,80.87 15.88,79.12 17.23,77.77 18.34,77.77 19.59,76.53 19.59,75.11 19.73,74.97 20.09,74.97 20.38,74.68 20.38,74.02 20.09,73.74 19.35,73.74 19.22,73.61 19.22,73.16 19.35,73.04 19.97,73.04 20.27,72.74 20.27,72.1 19.97,71.81 19.73,71.81 19.59,71.67 19.59,68.91 24.26,64.24 28.07,64.24 30.16,62.15 30.16,60.2 29.74,59.78 v2(28.84,59.78)
MUX_TYPEC_RXN2: length 56.5
  TOP w0.102: 31.52,53.35 32.02,53.35 32.37,53 33.11,53 33.9,53.79 33.9,54.55 34.29,54.93 34.29,54.96 34.52,55.18 U3801.39 ; 31.52,53.35 31.09,53.35 30.63,53.81 v2(30.63,53.91) ; 31.52,53.35 v1(31.52,53.5)
  L4 w0.14: v2(11.96,88.48) 12.12,88.32 12.12,88.31 12.32,88.1 12.32,88.01 12.87,87.46 15.77,87.46 19.29,83.95 19.29,81.24 23.39,77.14 23.39,76.7 27.29,72.8 27.29,71.25 28.16,70.37 28.16,70.18 27.87,69.88 27.87,69.48 28.34,69 28.74,69 29.04,69.3 29.23,69.3 29.53,69.01 29.53,68.45 30.04,67.94 30.6,67.94 31.81,66.73 31.81,64.44 32.86,63.38 32.86,54.71 31.84,53.69 30.85,53.69 v2(30.63,53.91)
  BOTTOM w0.102: v2(11.96,88.48) 11.96,89.96 R3837.1
MUX_TYPEC_RXP1: length 48.3
  TOP w0.102: R3834.1 14.12,86.7 v2(13.86,86.45) ; 31.34,59.47 31.03,59.47 30.5,60.01 29.26,60.01 28.87,60.39 v2(28.87,60.72) ; 31.34,59.47 33.67,59.47 34.36,58.78 U3801.30 ; 31.34,59.47 v1(31.34,59.63)
  L4 w0.14: v2(13.86,86.45) 14.16,86.15 14.16,82.21 15.62,80.76 15.62,79.01 17.12,77.51 18.23,77.51 19.32,76.41 19.32,75 19.62,74.7 19.98,74.7 20.11,74.57 20.11,74.13 19.98,74 19.24,74 18.96,73.72 18.96,73.05 19.24,72.77 19.86,72.77 20,72.63 20,72.21 19.86,72.07 19.62,72.07 19.32,71.78 19.32,68.79 24.15,63.97 27.96,63.97 29.89,62.04 29.89,60.31 29.63,60.04 29.22,60.04 28.87,60.39 v2(28.87,60.72)
MUX_TYPEC_RXP2: length 56.6
  TOP w0.102: U3801.40 34.47,54.78 34.13,54.45 34.13,53.7 33.93,53.5 ; 33.93,53.5 33.2,52.77 32.28,52.77 31.92,53.12 v2(30.63,53.12) ; 33.93,53.5 v1(34.06,53.38)
  L4 w0.14: v2(12.59,88.47) 12.59,88.12 12.98,87.73 15.88,87.73 19.55,84.06 19.55,81.35 23.65,77.25 23.65,76.81 27.55,72.91 27.55,71.36 28.43,70.48 28.43,70.06 28.13,69.77 28.13,69.59 28.45,69.27 28.63,69.27 28.93,69.57 29.34,69.57 29.8,69.12 29.8,68.56 30.15,68.2 30.71,68.2 32.07,66.84 32.07,64.55 33.13,63.49 33.13,54.6 31.95,53.43 30.93,53.43 v2(30.63,53.12)
  BOTTOM w0.102: v2(12.59,88.47) 12.58,88.47 12.18,88.86 12.18,90.18 R3836.1
MUX_TYPEC_TXN1: length 54.1
  TOP w0.102: v2(30.12,57.49) 30.4,57.77 33.65,57.77 34.07,57.36 34.13,57.36 34.31,57.18 U3801.34
  L4 w0.14: v2(30.12,57.49) 28.98,57.49 27.72,58.75 26.07,58.75 22.87,61.95 22.87,63.35 17.7,68.51 17.51,68.51 16.9,67.9 16.48,67.9 16.03,68.36 16.03,68.78 16.63,69.38 16.63,69.58 16.27,69.95 16.27,70.37 17.48,71.58 17.48,71.76 17.16,72.07 16.98,72.07 15.77,70.86 15.35,70.86 14.83,71.39 14.83,80.43 10.64,84.62 10.64,86.83 10.92,87.11 11.93,87.11 v2(11.96,87.13)
  BOTTOM w0.102: 11.4,87.11 11.93,87.11 v2(11.96,87.13) ; 11.4,87.11 10.61,87.11 10.37,87.35 10.37,88.09 C3863.1 ; 11.4,87.11 v1(11.4,87.31)
MUX_TYPEC_TXN1_C: length 1.5
  BOTTOM w0.102: R3833.1 10.15,90.05 10.15,89.34 C3863.2
MUX_TYPEC_TXN2: length 47.2
  TOP w0.102: v1(30.75,55.94) 30.75,55.79 ; 30.75,55.79 30.15,55.79 v2(29.87,56.07) ; 30.75,55.79 32.09,55.79 32.34,56.04 33.81,56.04 33.98,56.21 34.17,56.21 34.35,56.38 U3801.36 ; C3862.1 16.25,85 16.25,84.37 15.99,84.11 15.87,84.11 15.74,84.24 v2(15.74,84.24)
  L4 w0.14: v2(29.87,56.07) 29.87,55.92 30.24,55.55 30.61,55.55 30.74,55.67 30.74,61.54 31.12,61.92 31.12,62.99 29.13,64.98 25.42,64.98 22.88,67.52 21.74,67.52 21.22,68.05 21.22,75.79 18.71,78.29 17.44,78.29 16.4,79.34 16.4,82.38 16.15,82.64 16.15,83.97 15.88,84.24 v2(15.74,84.24)
MUX_TYPEC_TXN2_C: length 2.1
  TOP w0.102: C3862.2 16.15,86.52 16.15,87.13 ; 16.15,87.13 v1(16,87.13) ; 16.15,87.13 16.15,87.79 R3839.1
MUX_TYPEC_TXP1: length 54.6
  TOP w0.102: v1(31.14,58.15) 31.14,58 ; 31.14,58 30.4,58 v2(30.12,58.28) ; 31.14,58 33.74,58 34.16,57.58 U3801.33
  L4 w0.14: v2(11.96,86.27) 11.96,86.45 11.56,86.84 11.03,86.84 10.91,86.72 10.91,84.73 15.09,80.54 15.09,71.5 15.46,71.13 15.66,71.13 16.87,72.34 17.27,72.34 17.75,71.87 17.75,71.47 16.53,70.26 16.53,70.06 16.9,69.69 16.9,69.27 16.3,68.66 16.3,68.47 16.59,68.17 16.79,68.17 17.4,68.78 17.82,68.78 23.13,63.46 23.13,62.06 26.18,59.02 27.83,59.02 29.09,57.76 29.6,57.76 v2(30.12,58.28)
  BOTTOM w0.102: v2(11.96,86.27) 11.96,86.5 11.58,86.88 10.52,86.88 10.14,87.26 10.14,87.68 C3864.1
MUX_TYPEC_TXP1_C: length 1.5
  BOTTOM w0.102: C3864.2 9.93,89.32 9.93,90.08 R3832.1
MUX_TYPEC_TXP2: length 46.6
  TOP w0.102: v1(16.66,84.57) 16.48,84.57 ; 16.48,84.57 16.48,85.18 C3861.1 ; 16.48,84.57 16.48,84.19 v2(16.66,84.01) ; v2(29.87,55.28) 30.15,55.56 32.18,55.56 32.43,55.82 33.9,55.82 34.07,55.98 U3801.37
  L4 w0.14: v2(29.87,55.28) 30.72,55.28 31.01,55.56 31.01,61.43 31.39,61.81 31.39,63.1 29.24,65.25 25.53,65.25 22.99,67.79 21.85,67.79 21.48,68.16 21.48,75.9 18.82,78.56 17.55,78.56 16.67,79.45 16.67,82.49 16.42,82.75 16.42,83.77 v2(16.66,84.01)
MUX_TYPEC_TXP2_C: length 3
  TOP w0.102: v1(17.55,86.42) 17.39,86.27 C3861.2 16.38,86.55 16.38,87.77 R3838.1
N12P_JTAG_TCK: length 8.4
  BOTTOM w0.089: GPU1.AE5 152.78,75.58 152.78,75 152.51,74.73 151.46,74.73 149.94,73.21 v1(147.51,73.21) 147.02,73.71 RN7602.4
N12P_JTAG_TDI: length 1.1
  TOP w0.089: TP7605.1 v2(152.75,76.4)
  BOTTOM w0.089: GPU1.AE6 v2(152.75,76.4)
N12P_JTAG_TDO: length 1.2
  TOP w0.089: TP7601.1 v2(151.95,76.4)
  BOTTOM w0.089: GPU1.AF6 v2(151.95,76.4)
N12P_JTAG_TMS: length 1.2
  TOP w0.089: TP7602.1 153.97,75.98 v2(153.55,76.4)
  BOTTOM w0.089: GPU1.AD6 v2(153.55,76.4)
N12P_JTAG_TRST: length 5.4
  BOTTOM w0.089: GPU1.AG4 151.39,74.93 151.3,74.93 150.35,73.99 v1(148.45,73.99) 147.47,74.97 RN7602.3
N12P_XTAL_OUTBUFF: length 3.2
  TOP w0.089: v1(170.56,80.91) 170.56,80.86 v2(170.94,80.48) 171.05,80.59 R7602.1 171.67,79.67 R7617.2
  BOTTOM w0.089: GPU1.C10 171.34,80.08 v2(170.94,80.48)
NB_MODE#: length 72.5
  TOP w0.089: v2(93.87,27.14) 93.82,27.14 93.28,27.68 v1(93.28,28.94) 92.68,29.54 91.42,29.54 90.24,30.72 90.24,31.18 R2050.1 R2002.2 91.41,32.68 91.85,33.11 Q2001.3 ; KBC24.96 142.16,9.38 v2(142.01,9.23)
  L4 w0.089: v2(93.87,27.14) 93.87,23.51 93.26,22.89 93.26,21.36 97.53,17.09 99.93,17.09 100.56,16.46 109.11,16.46 109.3,16.26 111.81,16.26 112.26,16.71 117.53,16.71 118.64,15.61 125.94,15.61 126.78,16.45 135.93,16.45 137.4,14.97 137.4,13.31 141.48,9.23 v2(142.01,9.23)
NB_MUTE#: length 140.9
  TOP w0.089: v2(153.87,6.67) 153.24,7.29 KBC24.119 ; v2(31.52,13.93) 31.01,13.42 30.55,13.42 R2737.1
  L4 w0.089: v2(36.72,14.06) 36.72,13.93 39.56,11.09 71.73,11.09 74.82,14.18 79.27,14.18 82.45,17.37 85.14,17.37 85.59,16.91 93.57,16.91 97.1,13.38 107.09,13.38 108.24,14.52 113.13,14.52 113.69,15.07 117.87,15.07 118.82,14.13 125.73,14.13 127.26,15.66 135.01,15.66 136.61,14.05 136.61,10.65 139.53,7.73 141.55,7.73 142.01,7.26 144.52,7.26 145.54,6.24 153.44,6.24 v2(153.87,6.67)
  BOTTOM w0.089: v2(36.72,14.06) v1(36.09,14.06) 34.44,14.06 33.93,14.57 32.15,14.57 v2(31.52,13.93) 31.01,13.42 R2743.1
NCT7718_DXN: length 314.6
  TOP w0.254: v2(40.91,45.43) 40.96,45.43 43.95,42.44 45.01,41.37 45.87,40.52 v1(45.87,32.47) 45.87,28.2 47.01,27.06 47.01,24.19 45.21,22.39 44.21,22.39 42.57,20.75 42.57,15.63 43.75,14.44 45.16,14.44 C2607.2 45.56,14.44 46.43,14.44 46.5,14.37 THM261.3
  L3 w0.254: v2(62.48,88.61) 62.76,88.89 62.76,91.65 61.62,92.8 40.43,92.8 39.36,93.86 34.26,93.86 31.64,91.24 31.64,88.14 30.25,86.75 30.25,76.16 31.77,74.64 31.77,69.89 32.62,69.05 37.82,69.05 45.49,61.39 45.49,51.57 43.01,49.09 43.01,47.18 41.63,45.81 41.55,45.81 41.17,45.43 v2(40.91,45.43)
  L4 w0.254: v2(62.48,88.61) 62.76,88.89 62.76,89.75 65.04,92.04 82.44,92.04 82.82,92.42 112.43,92.42 124.23,80.62 124.23,76.37 125.58,75.02 127.06,75.02 127.38,75.34 128.73,75.34 130.32,73.75 130.32,69.77 130.79,69.3 135.36,69.3 140.18,64.48 145.14,64.48 146.2,63.42 146.2,57.07 148.59,54.67 151.93,54.67 152.72,55.46 161.82,55.46 162.71,56.35 162.71,57.49 163.34,58.13 165.5,58.13 166.39,59.02 171.09,59.02 174.14,55.97 183.75,55.97 185.31,54.4 185.31,52.71 185.31,52.29 178.66,45.63 170.4,45.63 169.82,45.05 v2(169.82,44.92)
  BOTTOM w0.254: C2606.2 170.17,42.35 170.58,42.76 170.58,44.16 v2(169.82,44.92) 169.89,44.98 Q2603.E
NCT7718_DXP: length 313.6
  TOP w0.254: v2(40.91,46.19) 41.17,45.93 44.31,42.79 45.37,41.73 46.38,40.73 46.38,28.41 47.52,27.27 v1(47.52,25.11) 47.52,23.98 45.42,21.88 44.42,21.88 43.07,20.53 43.07,15.84 43.96,14.95 45.16,14.95 C2607.1 45.56,14.95 46.43,14.95 46.5,15.02 THM261.2
  L3 w0.254: v2(63.55,88.61) 63.27,88.89 63.27,91.87 61.83,93.31 40.64,93.31 39.57,94.37 34.05,94.37 31.14,91.45 31.14,88.35 29.74,86.96 29.74,75.95 31.26,74.43 31.26,69.68 32.4,68.54 37.61,68.54 44.98,61.17 44.98,51.78 42.5,49.3 42.5,47.4 41.42,46.32 41.04,46.32 v2(40.91,46.19)
  L4 w0.254: v2(63.55,88.61) 63.27,88.89 63.27,89.54 65.25,91.53 82.65,91.53 83.03,91.91 112.22,91.91 123.72,80.41 123.72,76.16 125.37,74.51 127.27,74.51 127.59,74.83 128.52,74.83 129.81,73.54 129.81,69.56 130.58,68.79 135.15,68.79 139.97,63.97 144.93,63.97 145.69,63.21 145.69,56.86 148.38,54.16 152.14,54.16 152.93,54.95 162.03,54.95 163.22,56.14 163.22,57.28 163.55,57.62 165.71,57.62 166.6,58.51 170.88,58.51 173.93,55.46 183.54,55.46 184.81,54.19 184.81,52.5 178.45,46.14 170.19,46.14 169.06,45.01 v2(169.06,44.92)
  BOTTOM w0.254: Q2603.B 170.59,46.88 Q2603.C 169.06,45.36 v2(169.06,44.92) 169.06,44.31 C2606.1
NRB_BIT: length 26.5
  L4 w0.089: v2(112.83,38.92) 112.43,38.52 111.96,38.52 111.67,38.23 111.67,35.14 111.91,34.9 111.91,30.16 v2(111.59,29.84)
  BOTTOM w0.089: v2(111.59,29.84) 111.27,29.52 v1(111.27,29.3) 111.27,28.89 111.69,28.48 111.69,22.12 112.61,21.19 113.15,21.19 114.02,20.33 114.02,18.78 114.4,18.4 115.56,18.4 115.97,17.99 R2007.2 R2019.1 ; v2(112.83,38.92) 112.5,38.6 CPU1.AR7
OVERT_GPU#: length 7.2
  TOP w0.089: v1(174.01,75.86) 174.1,75.86 v2(174.45,76.21)
  BOTTOM w0.089: RN7610.1 176.02,72.41 175.41,73.02 175.41,74.99 174.45,75.95 v2(174.45,76.21) 174.45,76.23 173.88,76.8 GPU1.A6
P2800_VGA_DXN: length 1.2
  TOP w0.089: v2(170.13,81.33) TP7603.1
  BOTTOM w0.089: GPU1.E12 169.75,81.71 v2(170.13,81.33)
P2800_VGA_DXP: length 1.3
  TOP w0.089: v2(169.34,81.3) 169.14,81.3 TP7604.1
  BOTTOM w0.089: v2(169.34,81.3) 169.34,81.37 168.95,81.76 GPU1.F12
P_SYS: length 6.1
  BOTTOM w0.089: PU4401.30 199.45,26.26 v1(199.31,26.12) 198.78,25.59 198.5,25.59 196.48,23.58 196.42,23.58 195.98,23.14 PR4413.1
PANEL_BKEN: length 308.8
  TOP w0.089: D2401.3 135.91,16.49 135.91,13.07 v2(135.3,12.46) ; v1(92.81,95.77) v2(93.24,95.34)
  L3 w0.089: v2(170.12,7.69) 170.12,8.83 166.19,12.76 160.52,12.76 158.8,14.49 149.8,14.49 149.03,15.26 147.63,15.26 147.57,15.2 146.91,15.2 146.65,14.94 146.65,14.54 146.04,13.92 144.2,13.92 143.77,13.49 140.42,13.49 139.54,12.62 135.81,12.62 135.66,12.46 v2(135.3,12.46) ; v2(209.44,70.57) 209.79,70.23 209.79,69.35 211.32,67.81 211.32,66.27 213.72,63.87 213.72,60.73 214.9,59.55 214.9,57.49 215.92,56.48 215.92,53.49 217.32,52.09 217.32,50.16 217.82,49.66 218.29,49.66 219.8,48.15 219.8,41.64 220.1,41.34 220.1,35.5 219.62,35.02 219.62,32.1 219.1,31.58 219.1,24.73 v2(219.86,23.96)
  L4 w0.089: v2(209.44,70.57) 209.44,70.69 208.04,72.1 207.28,72.1 205.02,74.36 200.36,74.36 198.65,76.07 190.74,76.07 189.26,77.55 187.3,77.55 184.77,80.09 182.59,80.09 180.57,82.1 179.57,82.1 178.14,80.67 178.14,77.88 175.53,75.27 174.14,75.27 173.97,75.45 173.17,75.45 171.83,74.11 167.43,74.11 164.4,77.14 160.59,77.14 158.05,79.67 158.05,84.17 155.35,86.87 154.91,86.87 154.18,87.6 154.18,87.88 153.67,88.4 153.19,88.4 151.73,89.86 150.98,89.86 150.2,90.64 146.89,90.64 146.8,90.55 145.82,90.55 145.12,89.85 145.12,88.02 143,85.9 136.45,85.9 134.56,87.78 126.61,87.78 118.61,95.78 101.53,95.78 100.64,94.89 98.83,94.89 97.91,95.81 94.55,95.81 94.08,95.34 v2(93.24,95.34)
  L6 w0.089: v2(170.12,7.69) 171.41,8.99 181.16,8.99 181.39,9.22 194.06,9.22 196.57,11.73 197.97,11.73 199.8,13.57 200.98,13.57 201.28,13.87 204.57,13.87 204.76,14.06 212.6,14.06 215.49,16.95 216.57,16.95 219.17,19.55 219.17,23.28 v2(219.86,23.96)
  BOTTOM w0.089: v2(93.24,95.34) 92.92,95.66 91.8,95.66 91.23,95.08 91.23,92.26 91.97,91.53 92.86,91.53 93.24,91.91 RN5501.7
PANEL_BKEN_EC: length 30.8
  TOP w0.127: v2(140.74,3.52) 140.74,4.76 138.51,6.99 138.51,8.63 137.96,9.18 137.96,10.36 137.47,10.84 v1(137.47,12.56) 137.47,14.98 D2401.1 ; KBC24.117 152.44,5.1 152.45,5.09 v2(152.45,3.52)
  L3 w0.127: v2(140.74,3.52) 141.64,4.42 151.54,4.42 v2(152.45,3.52)
PBAT_CHG_SMBCLK: length 73.6
  TOP w0.089: KBC24.9 158.98,12.58 159.49,12.06 159.49,11.27 159.94,10.82 159.94,9.58 v2(160.6,8.93) 160.97,9.3 RN2402.3 ; v2(201.84,15.51) 201.84,16.74 202.2,17.11 v1(202.2,20.28) 201.84,20.64 201.84,24.18 201.78,24.25 201.78,27.86 v2(202.71,28.79)
  L6 w0.102: v2(201.84,15.51) 201.21,15.51 200.78,15.07 198.67,15.07 197.94,14.34 196.99,14.34 195.72,13.07 191.77,13.07 190.73,12.03 180.74,12.03 179.37,10.65 169.13,10.65 167.99,9.51 161.18,9.51 v2(160.6,8.93)
  BOTTOM w0.089: PU4401.22 202.55,28.95 v2(202.71,28.79) ; v2(201.84,15.51) 201.16,15.51 200.17,14.52 200.17,12.81 199.64,12.28 D4306.3 199.1,13.48 198.7,13.88 EC4309.1 197.45,13.93 RN4302.3
PBAT_CHG_SMBDAT: length 71.7
  TOP w0.089: v2(198.35,15.51) 198.84,15.99 201.25,15.99 201.44,16.18 201.44,24.21 200.71,24.94 v1(200.71,25.74) 200.71,27.66 202.26,29.22 202.92,29.22 v2(203.35,28.79) ; RN2402.4 161.18,8.47 160.42,8.47 159.96,8.93 v2(159.96,8.93) 159.68,9.21 159.68,10.71 159.23,11.16 159.23,11.91 158.95,12.18 KBC24.8
  L6 w0.102: v2(159.96,8.93) 160.85,9.82 167.86,9.82 169.01,10.96 179.24,10.96 180.61,12.33 190.6,12.33 191.64,13.37 195.59,13.37 196.86,14.64 197.45,14.64 198.32,15.51 v2(198.35,15.51)
  BOTTOM w0.089: PU4401.21 203.04,29.35 203.35,29.04 v2(203.35,28.79) ; v2(198.35,15.51) 198.41,15.51 198.62,15.71 D4305.3 199.1,14.89 198.7,14.49 EC4310.1 197.45,14.44 RN4302.2
PBAT_PRES1#: length 16.1
  TOP w0.089: AFTP4309.1 185.19,21.2 185.2,21.18 v2(185.2,21.11)
  BOTTOM w0.089: BATT1.6 v2(185.2,21.11) 191.28,15.02 RN4302.8
PBAT_PRES#: length 270
  TOP w0.089: PQ4313.5 41.55,75.4 41.3,75.14 40.81,75.14 40.53,74.87 40.53,74.37 38.34,72.17 v2(35.83,72.17) v1(35.1,72.17) ; v2(160.17,21.81) 158.94,20.58 KBC24.29
  L3 w0.089: v2(160.17,21.81) 158.86,20.5 146.69,20.5 146.04,21.15 137.83,21.15 136.46,19.79 132.81,19.79 129.13,16.1 129.13,13.4 v2(129.56,12.97)
  L4 w0.089: v2(129.56,12.97) 128.81,12.21 118.02,12.21 117.08,13.16 114.59,13.16 114.01,12.58 109.79,12.58 109.28,12.07 109.28,11.17 108.7,10.59 107.46,10.59 106.76,11.29 96.45,11.29 95.33,12.41 90.83,12.41 88.47,14.77 86.02,14.77 83.52,12.27 83.13,12.27 82.44,12.27 82.44,12.27 75.59,12.27 70.34,7.02 57.09,7.02 56.51,6.44 54.15,6.44 53.54,7.05 52.09,7.05 51.6,6.56 v2(51.58,6.56)
  L6 w0.089: v2(200.55,22.31) 200.55,22.95 200.3,23.2 199.02,23.2 198.58,22.76 190.23,22.76 189.4,21.93 174.77,21.93 173.5,20.66 165.14,20.66 164.64,21.17 160.68,21.17 160.17,21.68 v2(160.17,21.81) ; v2(51.58,6.56) 50.75,7.4 43.77,7.4 38.25,12.91 38.25,14.31 34.76,17.8 34.76,25.43 35.62,26.29 35.62,31.34 35.5,31.46 35.5,36.1 30.12,41.48 30.12,50.25 33.79,53.92 33.79,63.43 35.09,64.73 35.09,67.8 35.83,68.54 v2(35.83,72.17)
  BOTTOM w0.089: PR4409.2 v2(200.55,22.31) 200.55,21.93 199.03,20.41 198.52,20.41 197.89,19.77 197.89,18.25 197.51,17.87 D4304.3 197.4,16.54 EC4306.2 196.72,15.81 RN4302.1 ; R2415.1 159.46,22.52 v2(160.17,21.81)
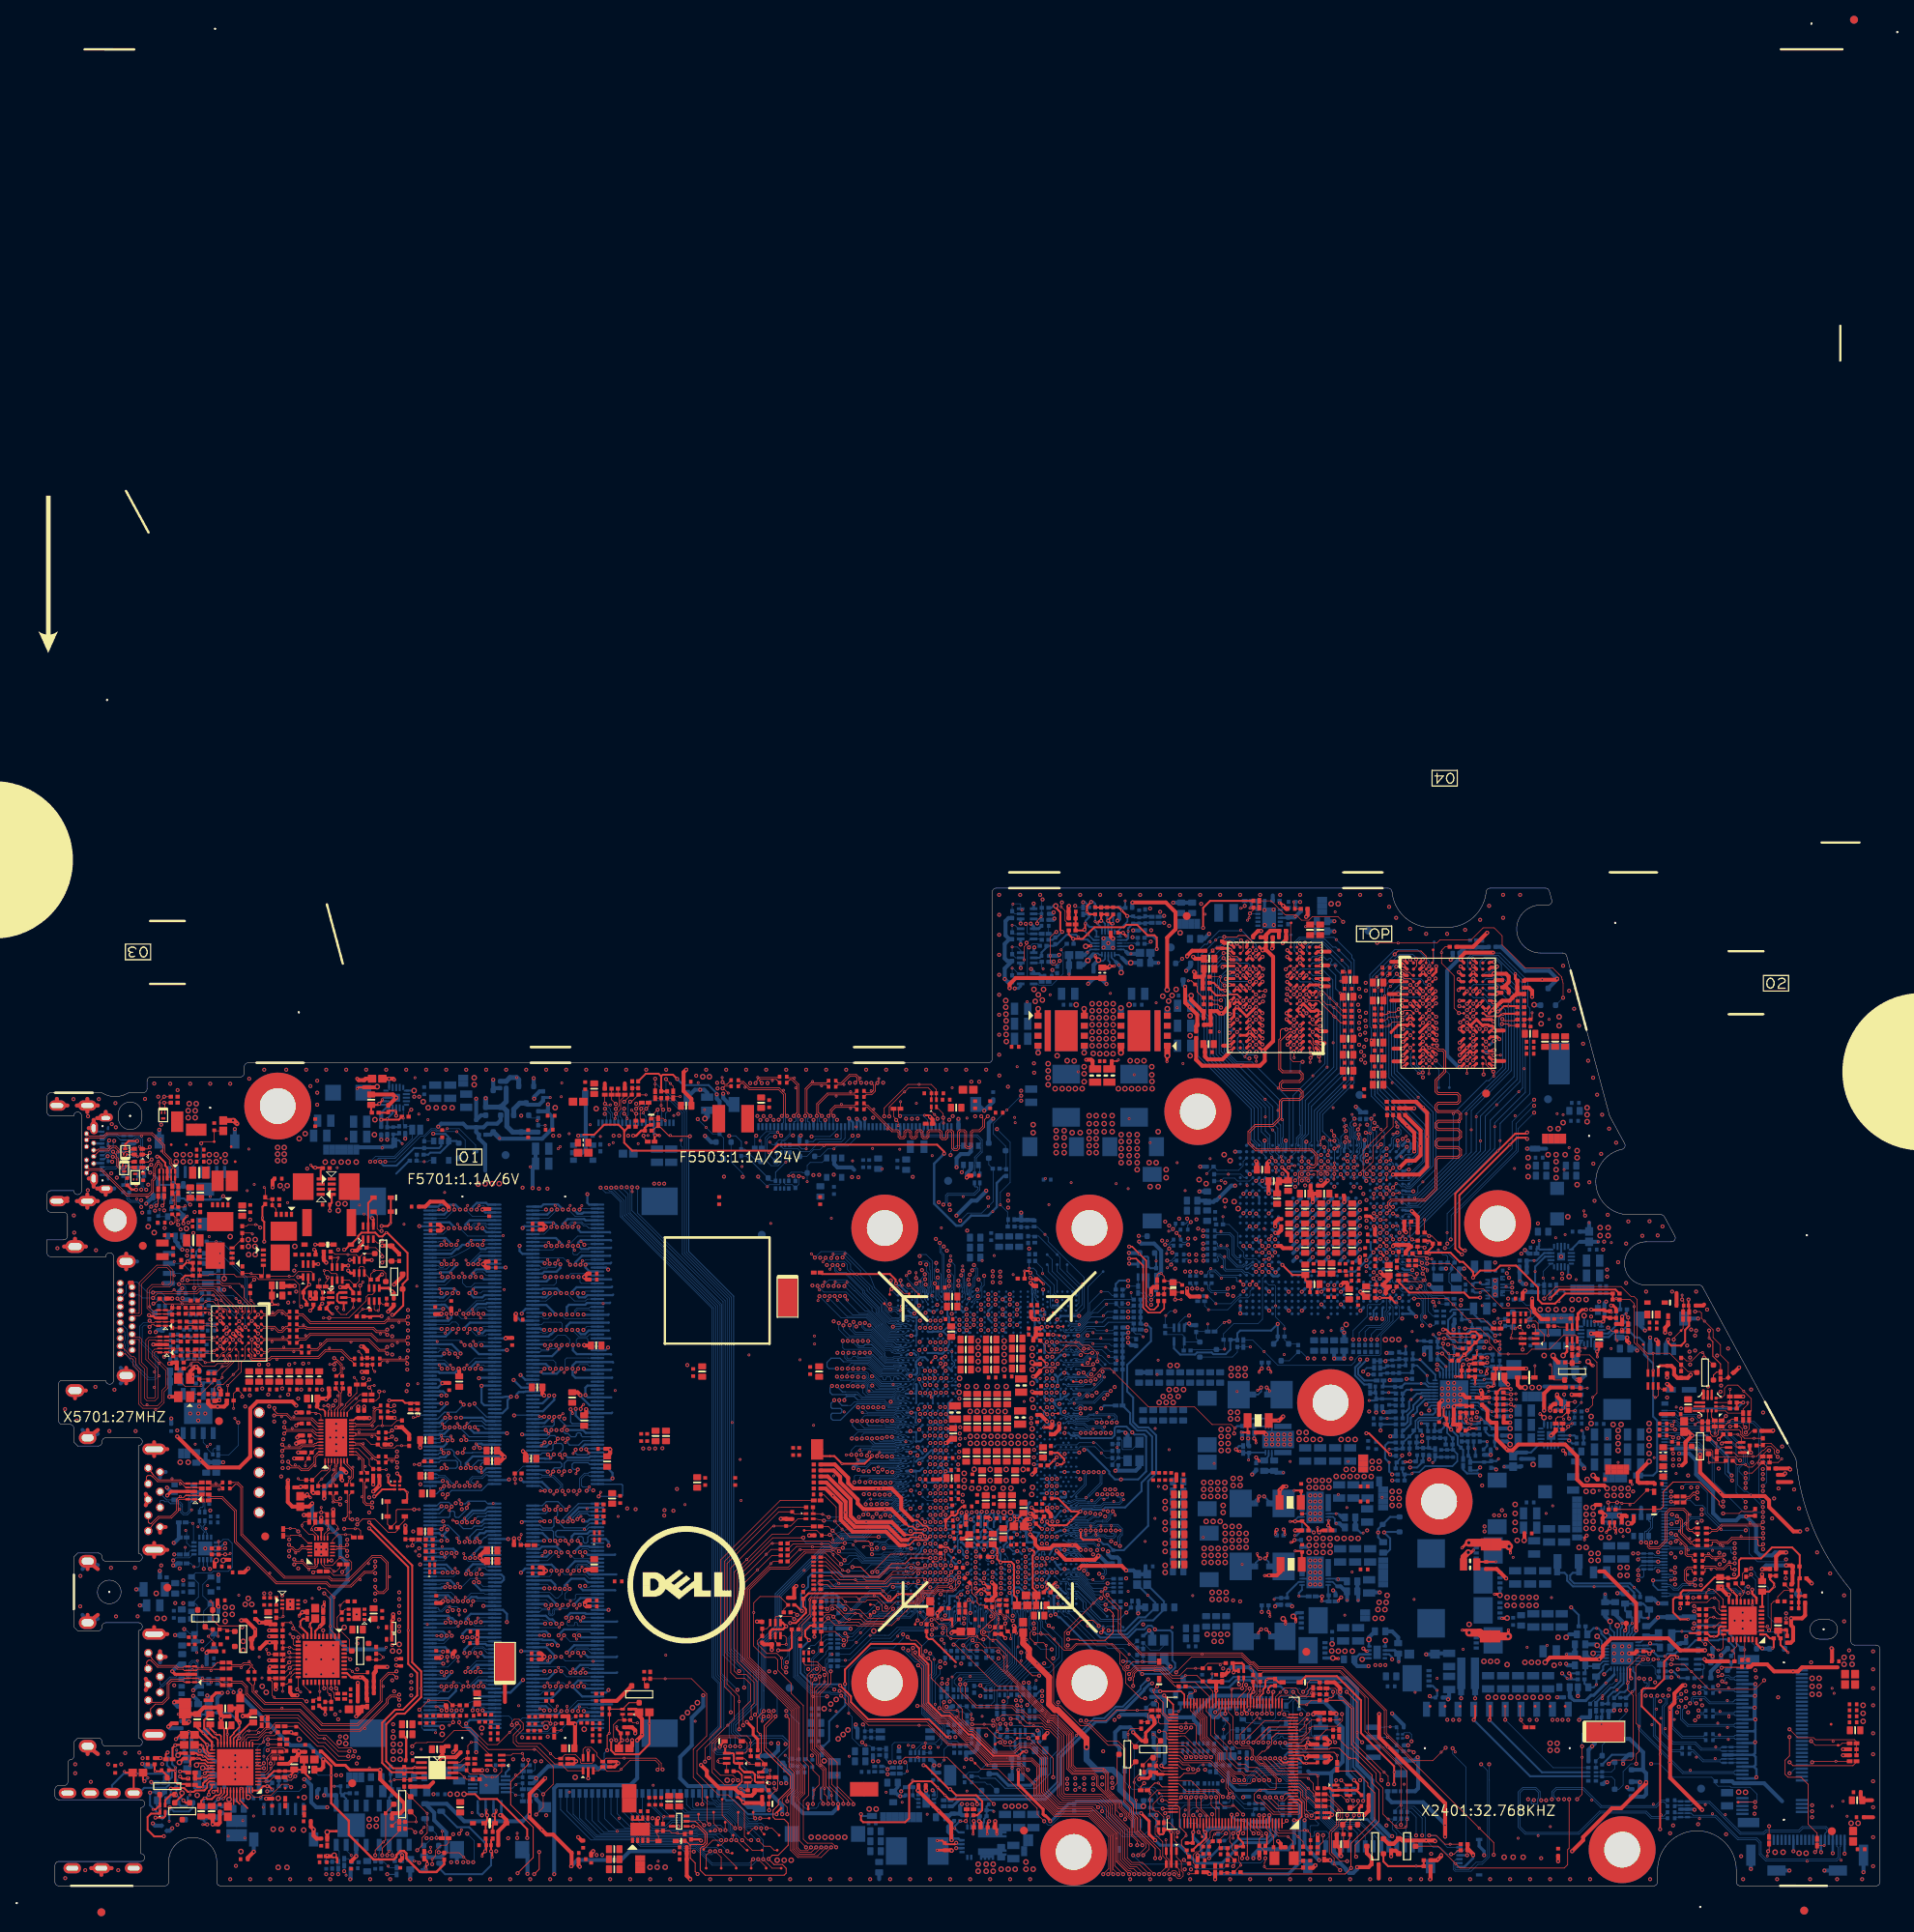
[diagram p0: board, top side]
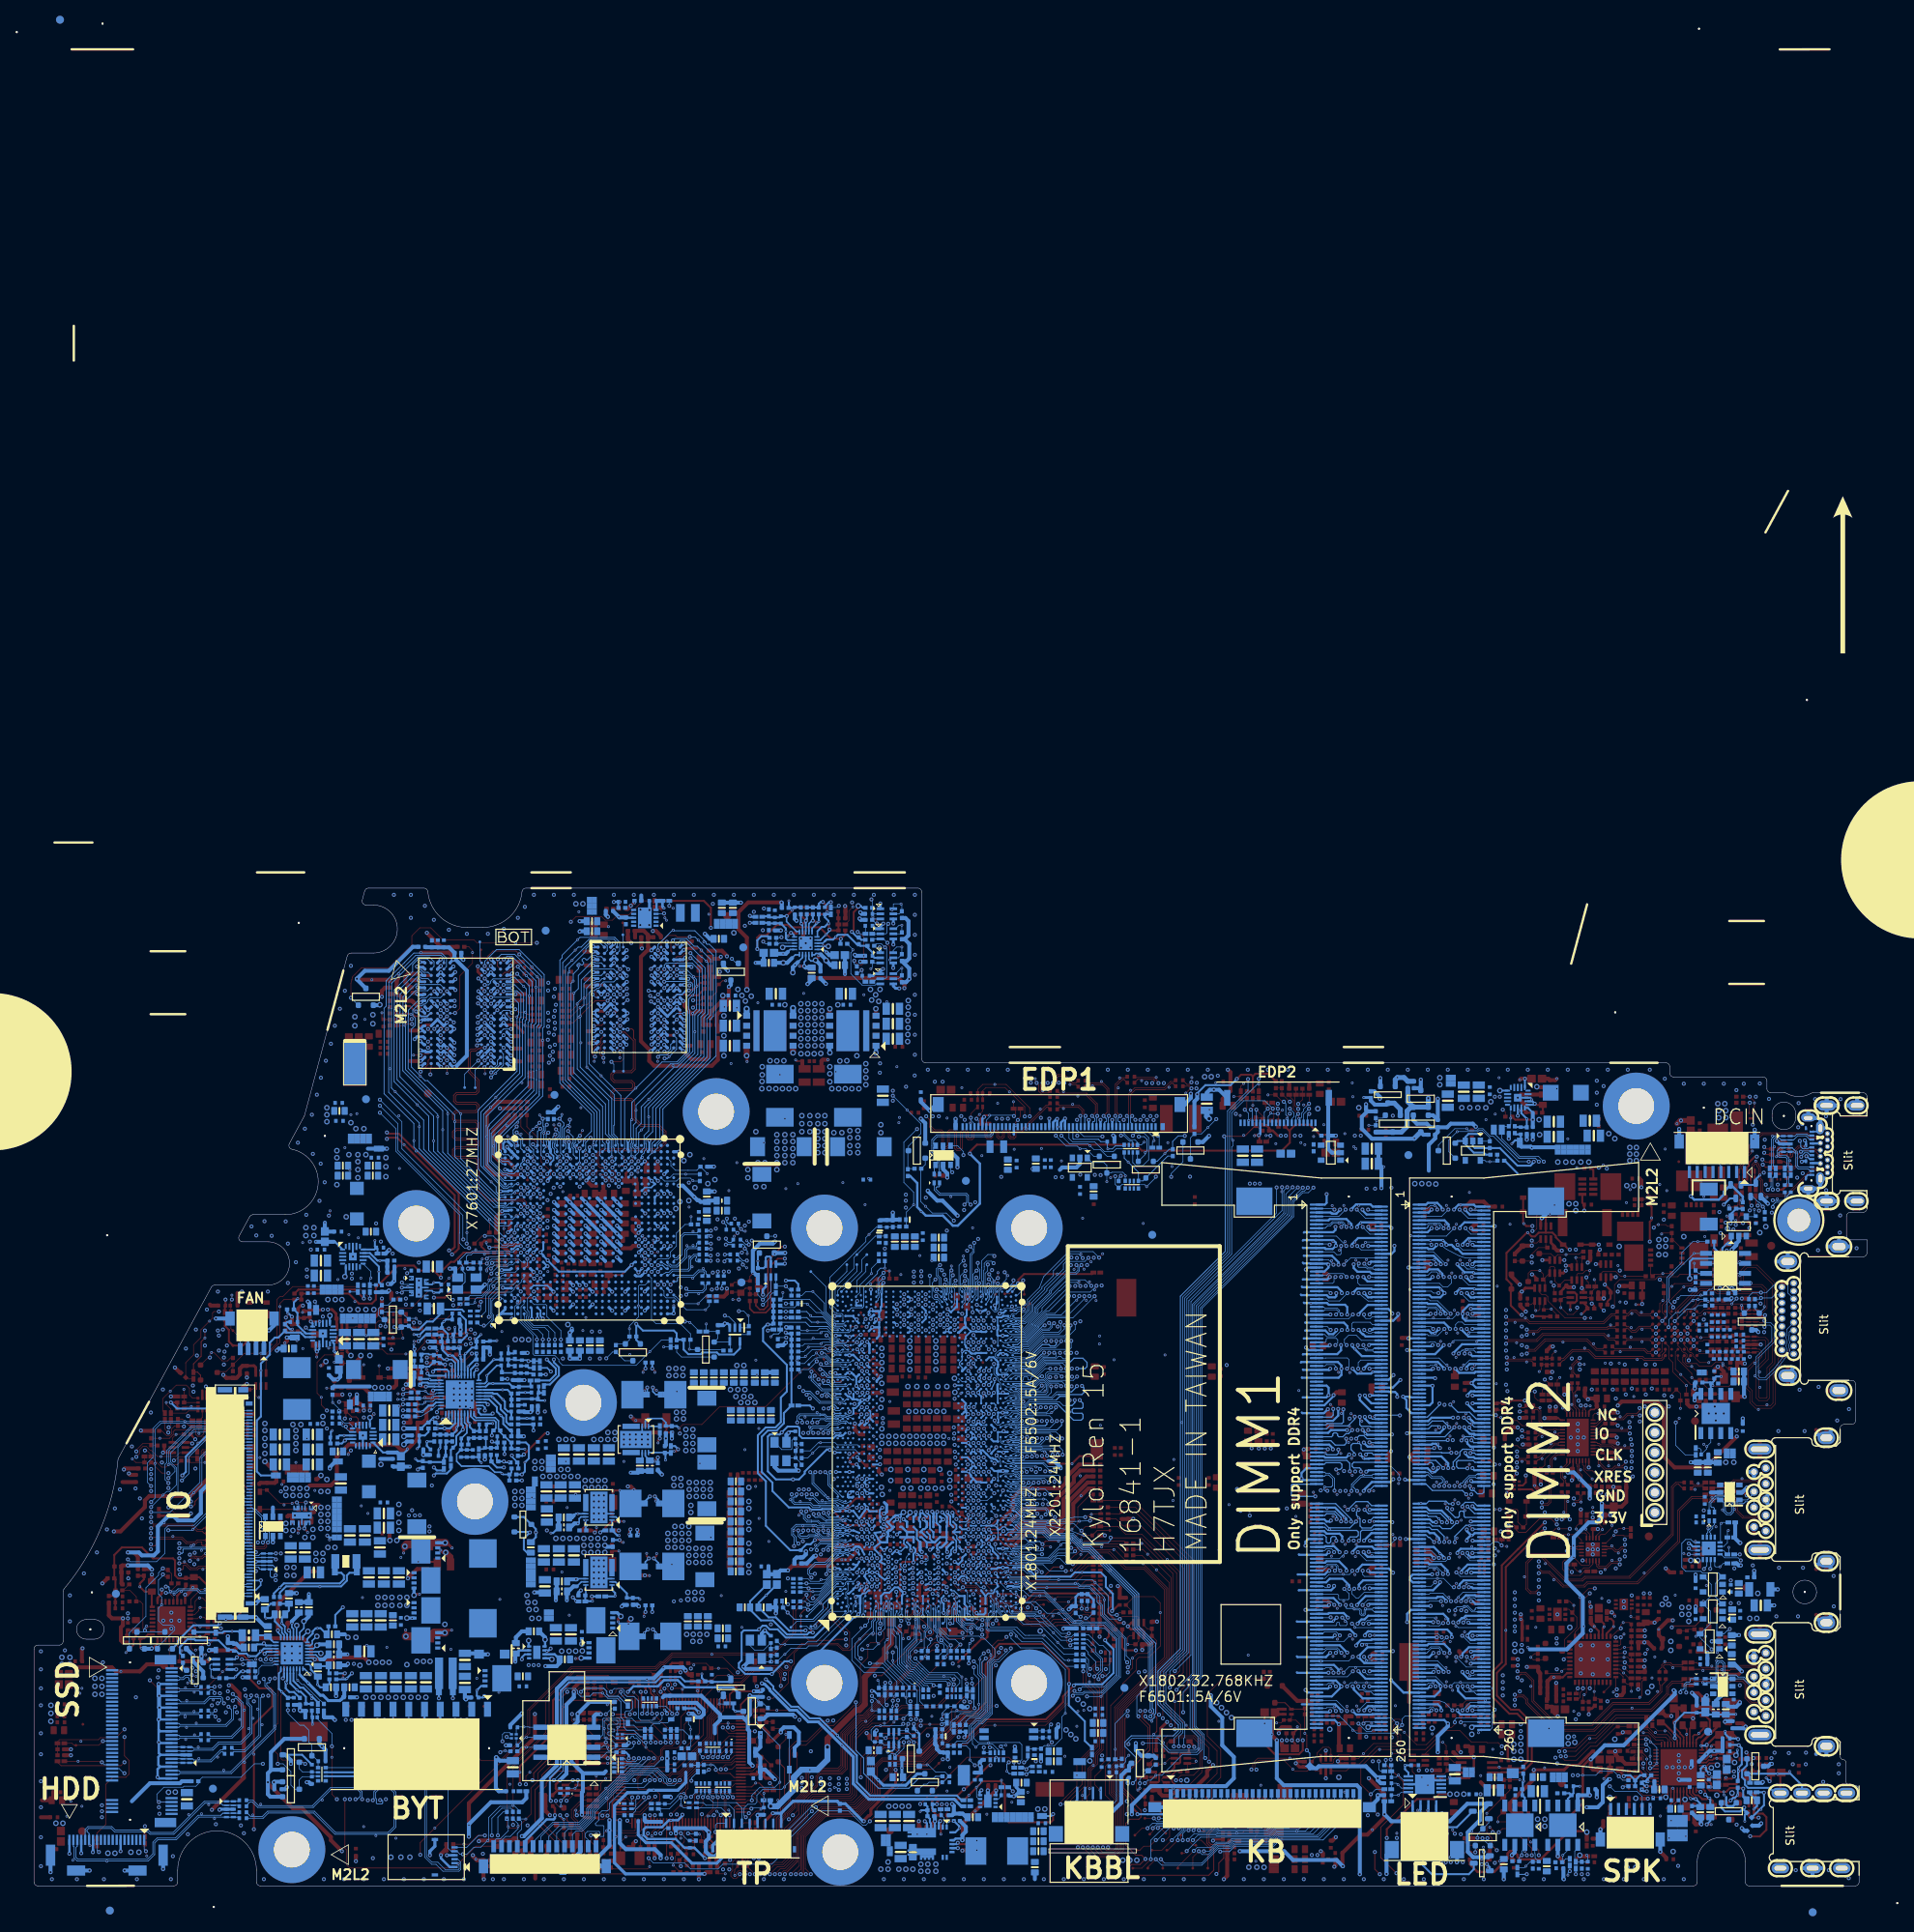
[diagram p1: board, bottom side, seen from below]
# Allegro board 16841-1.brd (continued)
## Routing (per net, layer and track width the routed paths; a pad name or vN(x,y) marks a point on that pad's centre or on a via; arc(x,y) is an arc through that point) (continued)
PBAT_SMBCLK1: length 20.7
  TOP w0.254: v2(181.2,21.09) 181.2,21.17 181.38,21.35 AFTP4311.1
  BOTTOM w0.254: BATT1.4 v2(181.2,21.09) 188.36,13.93 RN4302.6
PBAT_SMBDAT1: length 18.4
  TOP w0.254: AFTP4310.1 183.28,21.25 183.2,21.17 v2(183.2,21.09)
  BOTTOM w0.254: RN4302.7 189.86,14.44 v2(183.2,21.09) BATT1.5
PCH_BATLOW#: length 34.2
  L4 w0.089: v2(109.37,29.93) 109.37,30.31 108.29,31.4 108.29,33.03 108.73,33.48 108.73,40.86 110.44,42.58 v2(111.53,42.58)
  BOTTOM w0.089: RN1704.6 110.26,17.26 110.39,17.39 110.41,17.39 111.06,18.03 112.76,18.03 v1(113.18,17.61) 113.61,18.05 113.61,20.02 112.84,20.79 112.44,20.79 111.28,21.95 111.28,28.31 110.85,28.74 110.34,28.74 109.37,29.71 v2(109.37,29.93) ; CPU1.AU13 v2(111.53,42.58)
PCH_DPC_N0: length 163.8
  TOP w0.102: C3813.1 40.38,51.29 40.38,50.66 ; 40.38,50.66 40.38,48.82 40.63,48.58 41.14,48.58 v2(41.3,48.73) ; 40.38,50.66 v1(40.53,50.66)
  L6 w0.127: v2(129.2,62.7) 129.2,63.29 129.23,63.36 129.47,63.89 130.07,65.24 132.29,67.46 132.29,67.89 132.87,68.47 132.87,72.04 121.89,83.02 121.89,84.21 120.42,85.69 120.42,88.32 114.74,94 51.61,94 44.65,87.04 44.65,75.57 41.7,72.63 41.7,68.03 45.23,64.5 45.85,64.5 48.13,62.23 48.13,55.61 45.65,53.13 45.65,52.27 41.91,48.53 41.5,48.53 v2(41.3,48.73)
  BOTTOM w0.102: CPU1.C50 v2(129.2,62.7)
PCH_DPC_N0_C: length 4.1
  TOP w0.102: 40.25,53.3 40.25,54.18 39.25,55.18 U3801.10 ; 40.25,53.3 40.25,52.79 40.56,52.49 C3813.2 ; 40.25,53.3 v1(40.41,53.3)
PCH_DPC_N1: length 161.6
  TOP w0.102: v2(44.44,54.57) 44.19,54.32 43.28,54.32 C3807.1
  L6 w0.127: v2(44.44,54.57) 44.7,54.32 45.11,54.32 46.12,55.33 46.12,55.99 46.4,56.28 46.78,56.28 46.91,56.4 46.91,56.78 46.78,56.91 46.09,56.91 45.8,57.19 45.8,57.93 46.09,58.21 47.2,58.21 47.33,58.34 47.33,58.72 47.2,58.85 46.41,58.85 46.12,59.14 46.12,60.8 43.58,63.34 43.58,64.86 40.51,67.93 40.51,73.86 41.11,74.47 41.51,74.47 41.83,74.15 42.01,74.15 42.28,74.42 42.28,74.6 41.96,74.92 41.96,75.32 43.87,77.23 43.87,87.36 51.29,94.77 68.2,94.77 68.33,94.9 68.33,95.05 68.61,95.34 69.21,95.34 69.49,95.05 69.49,94.9 69.62,94.77 115.36,94.77 121.31,88.83 121.31,86.06 122.67,84.7 122.67,84.07 125.62,81.11 125.62,80.38 133.5,72.51 133.5,67.58 134.08,67 134.08,66 133.09,65.02 v2(132.63,65.02)
  BOTTOM w0.089: CPU1.C52 129.62,64.52 129.83,64.52 129.96,64.58 130.16,64.58 130.25,64.54 130.52,64.54 130.61,64.58 132,64.58 132.15,64.73
  BOTTOM w0.102: v2(132.63,65.02) 132.62,65.01 132.43,65.01 132.15,64.73
PCH_DPC_N1_C: length 4.5
  TOP w0.102: U3801.13 39.06,56.38 39.17,56.27 39.85,56.27 40.04,56.08 ; C3807.2 41.98,54.44 41.68,54.44 40.04,56.08 ; 40.04,56.08 v1(40.15,56.2)
PCH_DPC_N2: length 162.4
  TOP w0.102: v2(43.81,57.89) 43.54,57.62 C3808.1
  L6 w0.127: v2(43.81,57.89) 43.81,57.72 44.08,57.45 44.43,57.45 44.98,58 44.98,59.13 45.35,59.49 45.35,59.92 44.98,60.29 44.98,60.79 42.43,63.35 42.43,64.64 39.14,67.93 39.14,69.48 39.42,69.76 39.61,69.76 39.73,69.89 39.73,70.27 39.61,70.4 39.42,70.4 39.14,70.68 39.14,71.28 39.42,71.57 39.61,71.57 39.73,71.69 39.73,72.07 39.61,72.2 39.42,72.2 39.14,72.48 39.14,73.59 43.1,77.55 43.1,83.99 42.97,84.12 42.86,84.12 42.58,84.4 42.58,85.01 42.86,85.29 42.97,85.29 43.1,85.42 43.1,85.8 42.97,85.92 42.86,85.92 42.58,86.21 42.58,86.81 42.86,87.09 42.97,87.09 43.1,87.22 43.1,87.74 50.91,95.55 61.45,95.55 61.86,95.96 62.02,96.11 77.96,96.11 78.24,95.83 78.24,95.67 78.37,95.55 78.75,95.55 78.88,95.67 78.88,95.83 79.16,96.11 79.89,96.11 80.29,95.71 80.55,95.71 80.96,96.11 84.32,96.11 84.6,95.83 84.6,95.67 84.73,95.55 85.11,95.55 85.23,95.67 85.23,95.83 85.52,96.11 87.29,96.11 87.58,95.83 87.58,95.67 87.7,95.55 87.96,95.55 88.08,95.67 88.08,95.83 88.37,96.11 97.95,96.11 98.23,95.83 98.23,95.67 98.36,95.55 98.61,95.55 98.74,95.67 98.74,95.83 99.02,96.11 115.12,96.11 124.48,86.75 124.48,83.35 126.4,81.43 126.4,80.7 134.27,72.83 134.27,67.91 134.87,67.31 134.87,65.52 134.06,64.71 133.77,64.71 v2(133.65,64.83)
  BOTTOM w0.102: CPU1.A50 130.75,63.15 132.67,63.15 133.14,63.62 ; v1(133.01,63.74) 133.14,63.62 ; 133.14,63.62 133.86,64.34 133.86,64.62 v2(133.65,64.83)
PCH_DPC_N2_C: length 3.7
  TOP w0.102: U3801.16 39.11,57.58 39.19,57.5 39.22,57.5 39.23,57.5 39.62,57.5 ; v1(39.62,57.67) 39.62,57.5 ; 39.62,57.5 41.99,57.5 C3808.2
PCH_DPC_N3: length 160.5
  TOP w0.102: v2(44.09,61.05) 43.81,60.77 43.53,60.77 43.4,60.9 43.4,60.92 C3810.1
  L6 w0.127: v2(44.09,61.05) 44.09,60.9 43.92,60.73 43.9,60.73 43.73,60.55 41.77,60.55 41.63,60.7 41.63,61.31 41.34,61.59 40.53,61.59 40.41,61.72 40.41,62.1 40.53,62.22 41.34,62.22 41.63,62.51 41.63,64.68 38.63,67.67 38.63,74.01 42.04,77.41 42.04,87.4 50.87,96.23 61.23,96.23 61.63,96.62 84.07,96.62 84.35,96.9 84.35,97.28 84.48,97.41 84.86,97.41 84.99,97.28 84.99,96.9 85.27,96.62 115.33,96.62 115.78,96.17 125.05,86.9 125.05,83.5 126.92,81.63 126.92,80.9 134.78,73.04 134.78,68.12 135.4,67.51 135.4,65.74 133.61,63.95 132.75,63.95 132.56,64.14 v2(132.56,64.19)
  BOTTOM w0.102: v2(132.56,64.19) 132.63,64.12 132.63,63.84 132.53,63.73 131.84,63.73 131.56,63.45 130.87,63.45 130.87,63.46 129.62,63.46 129.33,63.75 CPU1.D51
PCH_DPC_N3_C: length 5.6
  TOP w0.102: C3810.2 42.06,60.74 41.75,60.74 41.65,60.64 ; 41.65,60.64 v1(41.52,60.77) ; 41.65,60.64 41.42,60.41 41.42,59.13 40.99,58.7 39.23,58.7 39.14,58.78 U3801.19
PCH_DPC_P0: length 164.3
  TOP w0.102: v1(40,49.44) 40.15,49.44 ; 40.15,49.44 40.15,51.32 C3812.1 ; 40.15,49.44 40.15,48.73 40.53,48.35 41.04,48.35 v2(41.3,48.09)
  L6 w0.127: v2(128.24,62.7) 128.24,62.72 128.99,63.46 129.22,64 129.84,65.39 132.02,67.57 132.02,68 132.6,68.58 132.6,71.93 121.62,82.91 121.62,84.1 120.15,85.58 120.15,88.21 114.62,93.73 51.72,93.73 44.91,86.92 44.91,75.46 41.97,72.52 41.97,68.14 45.34,64.77 45.96,64.77 48.39,62.34 48.39,55.5 45.92,53.02 45.92,52.16 42.02,48.26 41.46,48.26 v2(41.3,48.09)
  BOTTOM w0.102: CPU1.D50 128.76,62.99 128.47,62.7 v2(128.24,62.7)
PCH_DPC_P0_C: length 3.5
  TOP w0.102: 39.7,54.4 39.32,54.78 U3801.9 ; 39.7,54.4 v1(39.59,54.29) ; 39.7,54.4 40.03,54.08 40.03,52.62 C3812.2
PCH_DPC_P1: length 161.6
  TOP w0.102: C3814.1 43.3,54.09 43.81,54.09 ; 43.81,54.09 v1(43.81,53.94) ; 43.81,54.09 44.19,54.09 v2(44.47,53.81)
  L6 w0.127: v2(44.47,53.81) 44.71,54.05 45.22,54.05 46.39,55.22 46.39,55.88 46.51,56.01 46.89,56.01 47.18,56.29 47.18,56.89 46.89,57.18 46.2,57.18 46.07,57.31 46.07,57.82 46.2,57.95 47.31,57.95 47.59,58.23 47.59,58.83 47.31,59.12 46.52,59.12 46.39,59.25 46.39,60.91 43.85,63.45 43.85,64.97 40.77,68.04 40.77,73.75 41.22,74.2 41.4,74.2 41.72,73.88 42.12,73.88 42.54,74.31 42.54,74.71 42.23,75.03 42.23,75.21 43.98,76.96 44.14,77.12 44.14,87.25 51.4,94.51 68.31,94.51 68.59,94.79 68.59,94.94 68.72,95.07 69.1,95.07 69.23,94.94 69.23,94.79 69.51,94.51 115.25,94.51 121.04,88.72 121.04,85.95 122.4,84.59 122.4,83.96 125.36,81 125.36,80.27 133.23,72.4 133.23,67.47 133.81,66.89 133.81,66.11 133.35,65.65 v2(132.95,65.65)
  BOTTOM w0.089: 132.07,64.98 131.84,64.75 130.58,64.75 130.49,64.72 130.29,64.72 130.2,64.75 129.93,64.75 129.79,64.7 129.35,64.7 128.96,64.32 CPU1.D52
  BOTTOM w0.102: 132.07,64.98 132.14,65.05 132.14,65.11 132.68,65.65 v2(132.95,65.65)
PCH_DPC_P1_C: length 4.6
  TOP w0.102: 41.39,54.41 39.75,56.04 39.2,56.04 39.14,55.98 U3801.12 ; 41.39,54.41 v1(41.27,54.29) ; 41.39,54.41 41.58,54.22 41.66,54.14 41.78,54.14 C3814.2
PCH_DPC_P2: length 162.2
  TOP w0.102: C3809.1 43.57,56.86 v2(43.81,57.1)
  L6 w0.127: v2(134.06,65.36) 134.27,65.36 134.61,65.69 134.61,67.19 134.01,67.8 134.01,72.72 126.13,80.59 126.13,81.32 124.21,83.24 124.21,86.64 115.01,95.85 99.13,95.85 99.01,95.72 99.01,95.56 98.72,95.28 98.25,95.28 97.97,95.56 97.97,95.72 97.84,95.85 88.48,95.85 88.35,95.72 88.35,95.56 88.07,95.28 87.59,95.28 87.31,95.56 87.31,95.72 87.18,95.85 85.63,95.85 85.5,95.72 85.5,95.56 85.22,95.28 84.62,95.28 84.33,95.56 84.33,95.72 84.21,95.85 81.07,95.85 80.66,95.44 80.18,95.44 79.78,95.85 79.27,95.85 79.14,95.72 79.14,95.56 78.86,95.28 78.26,95.28 77.97,95.56 77.97,95.72 77.85,95.85 62.13,95.85 61.56,95.28 51.02,95.28 43.37,87.63 43.37,87.11 43.08,86.83 42.97,86.83 42.84,86.7 42.84,86.32 42.97,86.19 43.08,86.19 43.37,85.91 43.37,85.3 43.08,85.02 42.97,85.02 42.84,84.89 42.84,84.51 42.97,84.39 43.08,84.39 43.37,84.1 43.37,77.44 39.41,73.48 39.41,72.59 39.53,72.47 39.72,72.47 40,72.18 40,71.58 39.72,71.3 39.53,71.3 39.41,71.17 39.41,70.79 39.53,70.66 39.72,70.66 40,70.38 40,69.78 39.72,69.5 39.53,69.5 39.41,69.37 39.41,68.04 42.69,64.75 42.69,63.46 45.24,60.9 45.24,60.4 45.61,60.03 45.61,59.38 45.24,59.02 45.24,57.89 44.54,57.19 43.9,57.19 v2(43.81,57.1)
  BOTTOM w0.102: 134.08,64.65 134.08,65.33 v2(134.06,65.36) ; 134.08,64.65 v1(134.28,64.65) ; 134.08,64.65 134.08,64.24 132.76,62.92 130.33,62.92 CPU1.B50
PCH_DPC_P2_C: length 3.8
  TOP w0.102: C3809.2 41.7,57.27 41.27,57.27 ; v1(41.27,57.09) 41.27,57.27 ; 41.27,57.27 39.23,57.27 39.22,57.27 39.15,57.27 39.06,57.18 U3801.15
PCH_DPC_P3: length 160.6
  TOP w0.102: v2(44.09,60.29) C3811.1
  L6 w0.127: v2(131.93,64.14) 132.29,63.77 132.63,63.68 133.72,63.68 135.66,65.63 135.66,67.62 135.05,68.23 135.05,73.15 127.19,81.01 127.19,81.74 125.32,83.61 125.32,87.01 116.05,96.28 115.59,96.73 115.44,96.89 85.38,96.89 85.26,97.01 85.26,97.39 84.97,97.67 84.37,97.67 84.09,97.39 84.09,97.01 83.96,96.89 61.52,96.89 61.36,96.73 61.12,96.49 50.76,96.49 41.77,87.51 41.77,77.52 38.37,74.12 38.37,67.56 41.36,64.57 41.36,62.62 41.23,62.49 40.42,62.49 40.14,62.21 40.14,61.61 40.42,61.32 41.23,61.32 41.36,61.19 41.36,60.59 41.66,60.29 v2(44.09,60.29)
  BOTTOM w0.102: v2(131.93,64.14) 131.47,63.68 130.97,63.68 130.96,63.68 129.81,63.68 CPU1.C51
PCH_DPC_P3_C: length 5.6
  TOP w0.102: 41.19,58.58 41.08,58.47 39.23,58.47 39.14,58.38 U3801.18 ; 41.19,58.58 v1(41.32,58.46) ; 41.19,58.58 41.65,59.04 41.65,60.32 41.85,60.51 42.16,60.51 42.36,60.31 C3811.2
PCH_DPWROK: length 60.3
  L4 w0.127: v2(91.64,21.55) 91.64,21.49 96.16,16.96 96.16,16.34 97.24,15.26 106.95,15.26 106.99,15.22 108.62,15.22 108.99,15.58 v2(108.99,15.71)
  BOTTOM w0.127: CPU1.BB20 108.07,45.85 107.68,45.46 104.45,45.46 103.59,44.59 101.77,44.59 101.76,44.6 100.88,44.6 99.51,43.23 98.61,43.23 92.49,37.11 92.49,32.98 90.33,30.82 90.33,21.92 90.51,21.74 90.51,21.39 90.82,21.08 91.19,21.08 91.64,21.53 v2(91.64,21.55) ; R1704.2 108.94,14.26 v1(109.24,14.57) 109.24,15.45 v2(108.99,15.71)
PCH_ESPI_CLK: length 19.6
  TOP w0.089: R1805.1 94.94,34.76 v2(95.27,34.43)
  BOTTOM w0.089: v2(95.27,34.43) 95.35,34.43 95.36,34.44 95.56,34.44 95.59,34.41 96.01,34.41 96.36,34.75 96.36,36.88 v1(98.03,38.55) 98.39,38.92 105.53,38.92 106.31,39.71 106.65,39.71 107.12,40.17 107.82,40.17 107.94,40.22 108.21,40.22 108.32,40.19 108.51,40.19 108.62,40.23 108.95,40.23 108.99,40.19 109,40.19 109.12,40.06 109.52,40.06 109.8,39.78 CPU1.AW9
PCH_ESPI_IO0: length 17.5
  TOP w0.089: R1827.2 95.56,42.75 95.64,42.75 v1(95.65,42.73) 97.06,42.73 97.06,42.73 97.35,42.73 97.36,42.73 99.54,42.73 99.68,42.6 99.94,42.6 100.42,42.12 100.55,42.12 v2(101.29,41.38)
  BOTTOM w0.089: v2(101.29,41.38) 101.29,41.41 101.88,41.99 102.82,41.99 103.6,41.2 106.14,41.2 106.47,41.53 107.62,41.53 107.77,41.69 108.63,41.69 108.87,41.92 109.1,41.92 CPU1.AY13
PCH_ESPI_IO1: length 16.2
  TOP w0.089: v2(100.58,42.52) 100.33,42.78 99.75,42.78 99.43,43.1 97.23,43.1 v1(97.21,43.08) 97.15,43.14 95.19,43.14 R1828.2
  BOTTOM w0.089: CPU1.BA13 108.49,42.2 108.49,42.2 108.49,42.2 108.16,41.86 107.69,41.86 107.54,41.71 106.4,41.71 106.07,41.38 103.78,41.38 103.27,41.89 103.17,41.89 102.77,42.3 100.81,42.3 v2(100.58,42.52)
PCH_ESPI_IO2: length 15.4
  TOP w0.089: R1829.2 94.74,43.45 v1(98.37,43.45) 99.33,43.45 99.82,42.96 v2(101.06,42.96)
  BOTTOM w0.089: CPU1.BB13 107.92,42.04 107.62,42.04 107.47,41.89 106.32,41.89 105.99,41.56 103.86,41.56 102.64,42.78 101.24,42.78 v2(101.06,42.96)
PCH_ESPI_IO3: length 17.7
  TOP w0.089: v2(101.32,43.57) 99.63,43.57 99.4,43.8 94.33,43.8 R1830.2
  BOTTOM w0.089: v2(101.32,43.57) 102.16,43.57 v1(102.39,43.34) 103.99,41.74 105.92,41.74 106.25,42.07 107.39,42.07 107.54,42.22 107.6,42.22 107.85,42.46 108.19,42.46 108.28,42.43 108.52,42.43 108.66,42.46 109.01,42.46 109.07,42.52 109.48,42.52 109.71,42.29 CPU1.AY12
PCH_JTAG_TCK: length 11.6
  TOP w0.089: R407.1 126.77,68.67 126.77,68.11 127.15,67.73 128.55,67.73 v1(129.45,68.63) 129.49,68.67 130.68,68.67 131.44,67.91 131.48,67.91 131.53,67.86 131.59,67.86 131.8,67.65 132.33,67.65 132.42,67.73 v2(132.75,67.73)
  BOTTOM w0.089: v2(132.75,67.73) 132.37,67.73 131.53,66.89 131.51,66.89 131.51,66.89 131.03,66.89 130.87,67.05 130.61,67.05 130.52,67.02 130.45,67.02 CPU1.B56
PCH_JTAG_TDI: length 7.8
  BOTTOM w0.089: R408.1 134.97,67.14 v1(134.82,67.3) 133.95,68.16 132.25,68.16 131.94,67.86 131.58,67.86 131.54,67.89 131.15,67.89 131.13,67.87 131.12,67.87 131.02,67.76 130.93,67.73 130.89,67.71 130.54,67.71 130.48,67.73 130.24,67.73 130.12,67.85 129.06,67.85 CPU1.D59
PCH_JTAG_TDO: length 6
  BOTTOM w0.089: CPU1.A56 130.8,66.71 131.58,66.71 131.59,66.71 131.6,66.71 132.22,67.33 133.03,67.33 v1(133.42,67.73) 133.75,67.4 133.75,67.39 133.93,67.39 134.94,66.38 R409.1
PCH_JTAG_TMS: length 6.9
  BOTTOM w0.089: CPU1.C59 129.63,68.14 130.14,68.66 131.01,68.66 131.1,68.74 131.34,68.74 131.69,69.08 132.66,69.08 v1(132.84,68.91) 134.9,68.91 135.14,68.67 R416.1
PCH_PLTRST#: length 26.8
  L3 w0.089: v2(113.43,27.77) 113.01,28.19 113.01,29.51 114.19,30.69 114.19,33.58 114.64,34.03 114.64,35.01 115.43,35.8 115.43,36.94 115.94,37.44 115.98,37.44 116.24,37.7 116.24,40 116.01,40.24 115.04,40.24 115.01,40.26 114.36,40.26 114.13,40.03 v2(114.13,39.83)
  BOTTOM w0.089: CPU1.AN10 113.8,40.16 v2(114.13,39.83) ; v2(113.43,27.77) 113.43,26.94 112.8,26.3 v1(112.8,23.07) 112.8,22.5 113.15,22.15 116.32,22.15 R1713.2
PCH_POPIRCOMP: length 17.7
  TOP w0.203: 109.29,43.96 109.63,44.3 110.79,44.3 v2(110.89,44.4)
  TOP w0.508: 109.29,43.96 108.5,43.96 106.83,45.63 102.56,45.63 101.42,46.77 v1(101.42,47.46) 101.42,48.83 98.98,51.27 R413.1
  BOTTOM w0.305: CPU1.AU16 111.18,43.95 110.93,44.2 110.93,44.37 v2(110.89,44.4)
PCH_RSMRST#: length 96.7
  TOP w0.089: v2(153.84,18.22) 155.4,19.78 KBC24.27 159.16,19.78 159.67,20.29 159.67,20.8 TP2401.1 ; v2(87.12,13.42) 87.12,13.14 86.81,12.83 86.06,12.83 84.48,14.41 84.48,18.09 85.46,19.07 88.86,19.07 89.35,18.58 v1(89.35,18.2) EC1712.1 89.38,17.21 R1702.2
  L3 w0.089: v2(153.84,18.22) 152.86,17.24 149.79,17.24 149.54,17.49 136.94,17.49 134.77,15.32 133.85,15.32 132.44,13.91 132.44,12.92 v2(131.72,12.2)
  L4 w0.089: v2(131.72,12.2) 130.88,11.36 116.94,11.36 116.76,11.55 115.29,11.55 114.74,11 110.31,11 108,8.69 96.95,8.69 94.23,11.41 88.39,11.41 87.12,12.69 v2(87.12,13.42)
PCH_SMBCLK: length 32.4
  TOP w0.089: v2(59.04,20.44) 59.04,20.88 59.33,21.17 59.96,21.17 60.47,20.66 60.47,19.9 59.58,19.01 59.58,18.38 59.86,18.1 62.66,18.1 v1(63.95,16.8) 64.58,16.17 RN1810.3 65.77,16.7 67.09,16.7 67.73,16.06 67.73,15.69 67.84,15.58 69.24,15.58 69.38,15.72 Q1801.4
  BOTTOM w0.089: DM1.253 66.97,21.57 64.81,19.41 60.08,19.41 v2(59.04,20.44) 59.04,21.2 58.67,21.58 DM2.253
PCH_SMBDATA: length 29.7
  TOP w0.089: v2(52.34,20.79) 52.34,20.53 52.77,20.11 53.8,20.11 55.96,17.95 57.19,17.95 v1(58.76,19.52) 59.58,20.35 59.58,20.55 v2(59.68,20.65) 59.87,20.65 60.1,20.41 60.1,20.05 59.21,19.16 59.21,18.22 59.71,17.73 62.22,17.73 64.45,15.5 RN1810.4 66.11,14.63 Q1801.1
  BOTTOM w0.089: DM2.254 52.14,21.32 52.34,21.12 v2(52.34,20.79) ; v2(59.68,20.65) 60.36,21.32 DM1.254
PCH_THERMTRIP#: length 10.3
  BOTTOM w0.089: CPU1.C63 129.65,70.62 130.12,71.1 131.1,71.1 132.86,72.86 133.46,72.86 134.17,73.56 134.2,73.56 v1(134.56,73.93) 134.64,74 EC401.1 136.21,73.49 137.76,73.49 R419.2
PCIE_CLK_XDP_N: length 1.8
  TOP w0.102: TP1802.1 126.99,59.93 v2(127.03,59.93)
  BOTTOM w0.102: v2(127.03,59.93) 127.34,59.62 CPU1.F43
PCIE_CLK_XDP_P: length 1.3
  TOP w0.102: v2(127.71,59.93) 127.81,60.03 TP1803.1
  BOTTOM w0.102: CPU1.E43 127.99,59.64 v2(127.71,59.93)
PCIE_RCOMPN: length 2.1
  TOP w0.305: v1(126.9,38.59) 127.02,38.47 v2(127.02,38.04) 127.02,37.81 126.59,37.38 R1604.1
  BOTTOM w0.254: CPU1.F5 v2(127.02,38.04)
PCIE_RCOMPP: length 2.2
  TOP w0.305: R1604.2 127.66,37.5 v2(127.66,38.04) 127.66,38.16 128.07,38.57 v1(128.14,38.57)
  BOTTOM w0.254: CPU1.E5 v2(127.66,38.04)
PCIE_RX_CPU_N5: length 148.6
  L4 w0.089: 128.61,41.99 128.64,42.02 128.64,42.73 128.26,43.12 127.81,43.12 127.63,43.29 v2(127.63,44.37)
  L4 w0.14: v2(214.35,42.9) 215.47,42.9 217.28,41.09 217.28,32.82 216.35,31.89 216.35,19.58 216.35,19.04 210.42,13.11 204.42,13.11 202.98,11.66 188.81,11.66 188.22,12.25 172.44,12.25 170.03,14.67 149,14.67 148.37,15.3 144.58,15.3 140.02,19.85 140.02,21.12 135.7,25.45 135.7,26.67 131.36,31.01 131.36,34.74 129.72,36.38 129.72,40.7 128.61,41.8 128.61,41.99
  BOTTOM w0.102: CPU1.F16 v2(127.63,44.37) ; 212.85,43.03 214.22,43.03 v2(214.35,42.9) ; 212.85,43.03 206.17,43.03 206,43.2 IOBD1.17 ; 212.85,43.03 v1(212.85,43.19)
PCIE_RX_CPU_N6: length 144.3
  L4 w0.14: v2(216.05,37.24) 214.84,37.24 213.76,36.16 213.76,32.85 215.56,31.05 215.56,19.36 210.09,13.89 197.86,13.89 196.42,12.45 189.14,12.45 188.55,13.04 172.77,13.04 170.36,15.45 149.42,15.45 147.62,17.26 143.76,17.26 141.88,19.14 141.88,20.41 136.49,25.8 136.49,27 132.86,30.62 132.86,34.25 130.39,36.72 130.39,40.92 129.78,41.53 129.78,43.61 128.55,44.84 127.5,44.84 v2(127.03,45.32)
  BOTTOM w0.102: CPU1.G18 126.69,44.98 v2(127.03,45.32) ; 215.01,37.24 214.68,37.24 214.4,37.52 212.08,37.52 211.72,37.16 208.64,37.16 208.36,36.89 206.08,36.89 206,36.8 IOBD1.1 ; 215.01,37.24 v1(215.01,37.07) ; 215.01,37.24 v2(216.05,37.24)
PCIE_RX_CPU_N9: length 124.8
  TOP w0.102: v2(212.75,26.79) 212.57,26.62 v1(212.21,26.62)
  L4 w0.14: v2(127.66,48.07) 127.84,48.25 127.84,48.83 128.23,49.22 132.99,49.22 133.75,48.46 135.72,48.46 137,47.18 137,41.21 136.52,40.73 136.52,34.02 140.18,30.36 140.18,28.42 149.6,19 170.62,19 173.92,15.69 179.25,15.69 180.51,16.95 188.89,16.95 190.69,15.16 195.41,15.16 197.72,17.47 209.81,17.47 212.86,20.53 212.86,23.82 211.42,25.27 211.42,26.24 211.84,26.66 212.61,26.66 v2(212.75,26.79)
  BOTTOM w0.102: v2(212.75,26.79) 212.8,26.74 213.61,26.74 213.9,26.45 214.26,26.45 214.45,26.65 SSD1.5 ; CPU1.E22 v2(127.66,48.07)
PCIE_RX_CPU_N10: length 115
  L4 w0.089: v2(127.6,49.9) 127.9,50.19 128.37,50.39 128.71,50.39 128.78,50.45
  L4 w0.14: 128.78,50.45 128.94,50.61 132.54,50.61 133.04,51.12 137.53,51.12 139.69,48.95 139.69,35.77 142.56,32.91 142.56,30.31 150.67,22.19 150.67,21.8 150.67,21.69 151.01,21.36 173.87,21.36 174.56,20.67 176.38,20.67 177.22,19.84 206.97,19.84 208.88,21.75 208.88,22.24 208.67,22.45 v2(208.67,23.2)
  BOTTOM w0.102: v1(213.41,23.56) 213.41,23.38 ; 213.41,23.38 211.22,23.38 210.55,24.04 209.37,24.04 209.37,24.04 209.02,24.04 208.81,23.83 208.81,23.34 v2(208.67,23.2) ; 213.41,23.38 214.13,23.38 214.4,23.65 SSD1.17 ; CPU1.F25 v2(127.6,49.9)
PCIE_RX_CPU_N11: length 115.2
  L4 w0.089: 129.48,51.01 129.46,51.01 129.43,51.04 128.47,51.04 v2(128.24,50.81)
  L4 w0.14: 129.48,51.01 131.94,51.01 132.61,51.68 135.56,51.68 136.03,52.15 137.24,52.15 140.22,49.17 140.22,35.98 143.08,33.12 143.08,30.53 151.24,22.36 173.96,22.36 175.13,21.2 176.66,21.2 177.49,20.36 206.47,20.36 207.75,21.64 207.75,22.29 207.8,22.34 208,22.34 208.09,22.44 v2(208.09,22.77)
  BOTTOM w0.102: 212.19,20.51 214.27,20.51 214.4,20.65 SSD1.29 ; 212.19,20.51 208.45,20.51 207.71,21.25 207.71,22.38 v2(208.09,22.77) ; 212.19,20.51 v1(212.19,20.68) ; CPU1.E28 128.34,51.26 128.44,51.16 128.44,50.91 128.34,50.81 v2(128.24,50.81)
PCIE_RX_CPU_P5: length 148.6
  L4 w0.089: v2(128.27,44.37) 128.37,44.28 128.37,43.95 128.29,43.88 127.89,43.88 127.82,43.82 127.82,43.37 127.89,43.31 128.34,43.31 128.83,42.81 128.83,42.04 128.88,41.99
  L4 w0.14: 128.88,41.99 128.88,41.92 129.99,40.81 129.99,36.49 131.63,34.85 131.63,31.12 135.96,26.78 135.96,25.56 140.29,21.23 140.29,19.96 144.69,15.57 148.48,15.57 148.6,15.45 149.11,14.93 170.14,14.93 172.55,12.52 188.33,12.52 188.92,11.93 202.87,11.93 204.31,13.37 210.31,13.37 216.09,19.15 216.09,19.47 216.09,32 217.01,32.93 217.01,40.98 215.36,42.63 214.85,42.63 214.78,42.56 214.78,42.35 214.69,42.27 v2(214.35,42.27)
  BOTTOM w0.102: 211.53,42.8 v1(211.53,42.63) ; 211.53,42.8 213.81,42.8 213.89,42.72 213.89,42.35 213.98,42.27 v2(214.35,42.27) ; 211.53,42.8 IOBD1.16 ; CPU1.E16 128.26,43.95 128.33,44.02 128.33,44.31 v2(128.27,44.37)
PCIE_RX_CPU_P6: length 144.3
  L4 w0.14: v2(216.05,38.03) 215.52,37.51 214.73,37.51 213.49,36.27 213.49,32.74 215.3,30.94 215.3,19.47 209.98,14.16 197.75,14.16 196.31,12.72 189.25,12.72 188.66,13.31 172.88,13.31 170.47,15.72 149.53,15.72 147.73,17.53 143.87,17.53 142.15,19.25 142.15,20.52 136.75,25.91 136.75,27.11 133.13,30.73 133.13,34.37 130.66,36.84 130.66,41.03 130.04,41.64 130.04,43.72 128.66,45.1 127.9,45.1 127.69,45.31 v2(127.69,45.33)
  BOTTOM w0.102: v2(127.69,45.33) 127.34,44.99 CPU1.F18 ; 212.62,37.75 211.98,37.75 211.62,37.39 208.54,37.39 208.27,37.11 206.08,37.11 206,37.2 IOBD1.2 ; 212.62,37.75 214.5,37.75 214.78,37.47 215.49,37.47 215.64,37.62 215.64,37.96 215.71,38.03 v2(216.05,38.03) ; 212.62,37.75 v1(212.62,37.93)
PCIE_RX_CPU_P9: length 124.7
  TOP w0.102: v1(213.28,25.79) 212.96,25.79 v2(212.75,26)
  L4 w0.14: v2(212.75,26) 212.36,26.39 211.95,26.39 211.68,26.13 211.68,25.38 213.13,23.93 213.13,20.42 209.92,17.21 197.83,17.21 195.52,14.9 190.57,14.9 188.78,16.69 180.62,16.69 179.36,15.42 173.81,15.42 170.5,18.73 149.49,18.73 139.91,28.31 139.91,30.25 136.25,33.91 136.25,40.84 136.74,41.32 136.74,47.07 135.61,48.2 133.64,48.2 132.88,48.95 128.34,48.95 128.11,48.71 128.11,48.25 v2(128.29,48.07)
  BOTTOM w0.102: CPU1.E23 v2(128.29,48.07) ; SSD1.7 214.4,26.15 214.33,26.22 213.8,26.22 213.52,26.51 213.25,26.51 213.1,26.36 213.1,26.12 212.98,26 v2(212.75,26)
PCIE_RX_CPU_P10: length 114.9
  L4 w0.089: 128.9,50.2 128.44,50.2 128.24,50 v2(128.24,49.9)
  L4 w0.14: v2(209.46,23.2) 209.46,22.99 209.33,22.86 209.06,22.86 208.94,22.74 208.94,22.56 209.15,22.35 209.15,21.64 207.08,19.57 177.11,19.57 176.27,20.41 174.45,20.41 173.76,21.09 150.9,21.09 150.41,21.58 150.41,21.91 150.41,21.92 150.41,22.08 142.29,30.2 142.29,32.8 139.43,35.66 139.43,48.84 137.42,50.85 133.15,50.85 132.65,50.35 129.05,50.35 128.9,50.2
  BOTTOM w0.102: 210.03,23.81 209.46,23.81 209.46,23.81 209.11,23.81 209.04,23.74 209.04,23.48 209.32,23.2 v2(209.46,23.2) ; 210.03,23.81 v1(210.03,23.63) ; 210.03,23.81 210.46,23.81 211.12,23.15 SSD1.19 ; v2(128.24,49.9) 127.99,49.65 CPU1.E25
PCIE_RX_CPU_P11: length 115.3
  L4 w0.089: v2(127.6,50.81) 128.02,51.23 128.38,51.23 128.39,51.23 129.42,51.23 129.47,51.28 129.48,51.28
  L4 w0.14: v2(207.25,22.77) 207.49,22.53 207.49,21.75 206.36,20.62 177.6,20.62 176.77,21.46 175.24,21.46 174.07,22.63 151.35,22.63 143.34,30.64 143.34,33.23 140.48,36.09 140.48,49.28 137.35,52.41 135.92,52.41 135.45,51.95 132.5,51.95 131.83,51.28 129.48,51.28
  BOTTOM w0.102: CPU1.E27 v2(127.6,50.81) ; v2(207.25,22.77) 207.48,22.54 207.48,21.16 208.35,20.29 213.43,20.29 ; 213.43,20.29 214.27,20.29 214.4,20.15 SSD1.31 ; 213.43,20.29 v1(213.43,20.13)
PCIE_TX_CON_N9: length 4.1
  BOTTOM w0.102: 213.56,25.01 211.85,25.01 C6316.1 ; 213.56,25.01 v1(213.56,25.17) ; 213.56,25.01 214.27,25.01 214.4,25.15 SSD1.11
PCIE_TX_CON_N10: length 4.1
  BOTTOM w0.102: SSD1.23 214.4,22.15 214.27,22.01 212.47,22.01 ; C6314.1 211.85,22.01 212.47,22.01 ; v1(212.47,22.17) 212.47,22.01
PCIE_TX_CON_N11: length 4.1
  BOTTOM w0.102: 212.41,19.01 211.85,19.01 C6312.1 ; 212.41,19.01 v1(212.41,19.19) ; 212.41,19.01 214.27,19.01 214.4,19.15 SSD1.35
PCIE_TX_CON_P9: length 4.1
  BOTTOM w0.102: 212.45,24.79 214.27,24.79 214.4,24.65 SSD1.13 ; 212.45,24.79 v1(212.45,24.61) ; 212.45,24.79 211.85,24.79 C6315.1
PCIE_TX_CON_P10: length 4.1
  BOTTOM w0.102: SSD1.25 214.4,21.65 214.27,21.79 213.62,21.79 ; C6313.1 211.85,21.79 213.62,21.79 ; v1(213.62,21.62) 213.62,21.79
PCIE_TX_CON_P11: length 4.1
  BOTTOM w0.102: SSD1.37 214.4,18.65 214.27,18.79 213.53,18.79 ; 213.53,18.79 211.85,18.79 C6311.1 ; 213.53,18.79 v1(213.53,18.6)
PCIE_TX_CPU_N5: length 138
  TOP w0.102: C1601.2 210.46,41.31 210.56,41.41 210.56,41.74 210.66,41.85 211.16,41.85 211.43,41.58 211.96,41.58 ; 211.96,41.58 212.24,41.58 212.33,41.67 212.87,41.67 213,41.54 v2(213,41.3) ; 211.96,41.58 v1(211.96,41.44)
  L4 w0.14: v2(136.27,43.19) 135.47,42.39 135.47,33.96 139.39,30.04 139.39,28.09 149.76,17.72 170.69,17.72 173.53,14.88 189.69,14.88 190.29,14.29 195.65,14.29 198.05,16.69 210.28,16.69 213.72,20.13 213.72,29.21 211.06,31.87 211.06,36.76 212.01,37.71 212.01,39.23 213.62,40.84 213.62,41.76 213.56,41.82 213.37,41.82 213,41.45 v2(213,41.3)
  BOTTOM w0.089: 133.6,45.93 133.5,45.93 133.46,45.9 133.42,45.9 133.28,45.76 131.04,45.76 130.87,45.58 130.6,45.58 130.48,45.62 130.26,45.62 130.16,45.58 129.96,45.58 129.68,45.68 CPU1.C19
  BOTTOM w0.102: 133.6,45.93 136.03,45.93 136.57,45.39 136.57,44.6 136.27,44.29 v2(136.27,43.19)
PCIE_TX_CPU_N6: length 145.2
  TOP w0.102: 213.68,41 213.46,41 212.89,40.42 212.11,40.42 211.92,40.61 210.32,40.61 C1613.2 ; 213.68,41 v2(214.35,41) ; 213.68,41 v1(213.68,41.19)
  L4 w0.14: v2(133.14,47.26) 133.14,46.52 132.66,46.04 130.98,46.04 130.55,45.6 130.55,42 132.85,39.7 132.85,35.09 138.34,29.6 138.34,26.44 142.9,21.88 142.9,19.65 144.15,18.39 147.61,18.39 149.33,16.67 170.26,16.67 173.1,13.83 189.1,13.83 189.69,13.24 196.09,13.24 197.53,14.68 209.77,14.68 214.78,19.69 214.78,30.72 212.97,32.52 212.97,37.02 213.42,37.47 213.67,37.47 215.54,39.33 215.54,40.42 215.15,40.81 214.53,40.81 v2(214.35,41)
  BOTTOM w0.089: v2(133.14,47.26) 132.97,47.13 132.18,46.53 132.06,46.53 132.06,46.53 130.25,46.53 130.08,46.58 129.81,46.69 129.62,46.69 129.55,46.62 129.18,46.44 CPU1.D20
PCIE_TX_CPU_N9: length 115.3
  L4 w0.14: v2(134.03,49.76) 134.03,49.01 134.26,48.78 136.16,48.78 137.55,47.4 137.55,33.76 140.7,30.61 140.7,28.64 149.82,19.52 173.11,19.52 173.84,18.78 175.67,18.78 176.45,17.99 188.75,17.99 190.96,15.79 195.29,15.79 197.5,17.99 209.59,17.99 212.11,20.52 212.11,23.72 210.73,25.1 210.07,25.1 v2(209.87,25.29)
  BOTTOM w0.089: 132.27,48.81 132.25,48.81 132.25,48.81 130.93,48.81 CPU1.B23
  BOTTOM w0.102: C6316.2 209.89,25.28 v2(209.87,25.29) ; v2(134.03,49.76) 133.07,48.81 132.68,48.81 ; 132.27,48.81 132.68,48.81 ; 132.68,48.81 v1(132.68,48.98)
PCIE_TX_CPU_N10: length 111.6
  L4 w0.14: v2(209.75,22.29) 210.96,22.29 211.32,21.93 211.32,20.84 209.26,18.78 176.78,18.78 175.99,19.57 174.17,19.57 173.43,20.31 150.14,20.31 148.85,21.6 148.85,22.52 141.5,29.87 141.5,32.47 138.6,35.37 138.6,48.5 137.34,49.76 v2(136.57,49.76)
  BOTTOM w0.089: CPU1.D23 129.33,48.04 129.6,48 129.93,47.88 130.2,47.88 130.29,47.92 130.45,47.92 130.58,47.88 130.59,47.88 130.6,47.87 130.95,47.87 131.26,48.18 132.98,48.18 132.98,48.18 133.02,48.18 133.05,48.14 133.07,48.14
  BOTTOM w0.102: v2(136.57,49.76) 136.57,49.08 ; 136.57,49.08 136.57,48.8 136.24,48.47 134.25,48.47 133.92,48.14 133.07,48.14 ; 136.57,49.08 v1(136.72,49.08) ; v2(209.75,22.29) 210.03,22.01 210.4,22.01 C6314.2
PCIE_TX_CPU_N11: length 114.9
  L4 w0.14: v2(207.55,23.53) 207.26,23.82 206.89,23.82 205.6,22.54 201.95,22.54 201.67,22.82 198.11,22.82 196.97,21.68 177.54,21.68 177.19,22.03 175.46,22.03 174.34,23.15 151.56,23.15 143.86,30.85 143.86,33.45 141.1,36.21 141.1,49.39 139.25,51.25 138.65,51.85 137.07,53.43 134.15,53.43 133.98,53.25 133.98,52.81 v2(134.21,52.58)
  BOTTOM w0.089: 132.43,49.57 132.43,49.56 132.4,49.56 131.84,49 130.74,49 130.07,48.71 129.81,48.6 129.66,48.6 CPU1.D24
  BOTTOM w0.102: 206.5,21.14 206.5,23.2 207.14,23.84 207.24,23.84 v2(207.55,23.53) ; 206.5,21.14 206.5,20.25 207.73,19.01 210.4,19.01 C6312.2 ; 206.5,21.14 v1(206.67,21.14) ; v2(134.21,52.58) 133.98,52.35 133.98,51.11 132.43,49.57
PCIE_TX_CPU_P5: length 138.7
  TOP w0.102: 211.02,42.07 211.26,42.07 211.53,41.81 212.14,41.81 212.23,41.9 212.81,41.9 v2(213,42.09) ; 211.02,42.07 C1602.2 ; 211.02,42.07 v1(211.02,42.23)
  L4 w0.14: v2(213,42.09) 213.67,42.09 213.89,41.87 213.89,40.73 212.28,39.12 212.28,37.6 211.33,36.65 211.33,31.98 213.99,29.32 213.99,20.02 210.39,16.42 198.16,16.42 195.76,14.03 190.17,14.03 189.58,14.62 173.42,14.62 170.58,17.46 149.65,17.46 139.12,27.98 139.12,29.93 135.2,33.85 135.2,42.51 135.68,42.99 135.68,43.47 v2(135.71,43.5)
  BOTTOM w0.089: 133.6,45.71 133.5,45.71 133.36,45.57 131.1,45.57 130.94,45.4 130.58,45.4 130.45,45.44 130.29,45.44 130.2,45.4 129.93,45.4 129.6,45.52 129.33,45.56 CPU1.D19
  BOTTOM w0.102: 133.6,45.71 135.94,45.71 136.34,45.3 136.34,44.69 135.99,44.33 135.99,43.77 v2(135.71,43.5)
PCIE_TX_CPU_P6: length 145.1
  TOP w0.102: v1(211.35,40.22) 211.35,40.38 ; 211.35,40.38 211.82,40.38 212.02,40.19 212.99,40.19 213.56,40.77 213.75,40.77 213.85,40.67 213.85,40.29 213.93,40.21 v2(214.35,40.21) ; 211.35,40.38 210.67,40.38 210.59,40.3 210.59,39.92 210.43,39.76 C1614.2
  L4 w0.14: v2(133.78,47.26) 133.78,47.23 133.41,46.86 133.41,46.41 132.77,45.77 131.09,45.77 130.82,45.49 130.82,42.11 133.12,39.81 133.12,35.2 138.6,29.71 138.6,26.55 143.16,22 143.16,19.76 144.26,18.65 147.72,18.65 149.44,16.93 170.37,16.93 173.21,14.1 189.21,14.1 189.8,13.51 195.98,13.51 197.42,14.95 209.66,14.95 214.51,19.8 214.51,30.61 212.71,32.41 212.71,37.13 213.31,37.73 213.56,37.73 215.27,39.45 215.27,40.31 215.04,40.54 214.61,40.54 214.35,40.28 v2(214.35,40.21)
  BOTTOM w0.089: 133.34,46.84 132.9,46.84 132.56,46.58 132.24,46.34 132.15,46.34 132.15,46.34 129.8,46.34 CPU1.C20
  BOTTOM w0.102: v2(133.78,47.26) 133.78,47.03 133.59,46.84 133.34,46.84
PCIE_TX_CPU_P9: length 115.2
  L4 w0.14: v2(134.66,49.76) 134.29,49.39 134.29,49.12 134.37,49.05 136.27,49.05 137.82,47.51 137.82,33.87 140.96,30.72 140.96,28.75 149.93,19.79 173.22,19.79 173.95,19.05 175.78,19.05 176.56,18.26 188.86,18.26 191.07,16.05 195.18,16.05 197.39,18.26 209.48,18.26 211.84,20.63 211.84,23.61 210.62,24.83 210.29,24.83 210.21,24.75 210.21,24.57 210.14,24.5 v2(209.87,24.5)
  BOTTOM w0.089: CPU1.A23 131.01,48.61 132.23,48.61 132.26,48.58 132.27,48.58
  BOTTOM w0.102: 132.27,48.58 133.17,48.58 133.85,49.26 134.23,49.26 ; v1(134.23,49.11) 134.23,49.26 ; 134.23,49.26 134.71,49.26 134.79,49.34 134.79,49.63 v2(134.66,49.76) ; C6315.2 210.67,24.62 210.4,24.89 210.07,24.89 209.87,24.7 v2(209.87,24.5)
PCIE_TX_CPU_P10: length 111.5
  L4 w0.14: v2(135.93,49.76) 135.93,50.04 136.17,50.28 136.8,50.28 137.05,50.03 137.45,50.03 138.87,48.61 138.87,35.48 141.77,32.58 141.77,29.98 149.12,22.63 149.12,21.71 150.25,20.57 173.54,20.57 174.28,19.84 176.1,19.84 176.89,19.05 209.15,19.05 211.06,20.95 211.06,21.82 210.85,22.03 210.27,22.03 210.18,21.94 210.18,21.6 210.08,21.5 v2(209.75,21.5)
  BOTTOM w0.089: CPU1.C23 129.68,48.16 129.96,48.06 130.16,48.06 130.26,48.1 130.48,48.1 130.6,48.06 130.87,48.06 131.18,48.37 133.07,48.37
  BOTTOM w0.102: C6313.2 210.4,21.79 210.03,21.79 v2(209.75,21.5) ; 135.48,48.7 134.16,48.7 133.83,48.37 133.07,48.37 ; 135.48,48.7 136.15,48.7 136.34,48.89 136.34,49.36 136.28,49.41 135.99,49.41 135.93,49.47 v2(135.93,49.76) ; 135.48,48.7 v1(135.48,48.86)
PCIE_TX_CPU_P11: length 115
  L4 w0.14: v2(133.57,52.58) 133.71,52.72 133.71,53.36 134.04,53.69 137.18,53.69 138.84,52.04 139.52,51.36 139.52,51.36 141.37,49.5 141.37,36.32 144.13,33.56 144.13,30.96 151.67,23.42 174.45,23.42 175.57,22.29 177.3,22.29 177.65,21.94 196.86,21.94 198,23.09 201.78,23.09 202.06,22.81 205.49,22.81 206.78,24.09 207.26,24.09 v2(207.55,24.38)
  BOTTOM w0.089: 132.27,49.73 132.26,49.71 132.26,49.68 131.76,49.19 130.7,49.19 130,48.89 CPU1.C24
  BOTTOM w0.102: v1(206.09,22.34) 206.27,22.34 ; 206.27,22.34 206.27,20.15 207.64,18.79 210.4,18.79 C6311.2 ; 206.27,22.34 206.27,23.29 207.05,24.07 207.24,24.07 v2(207.55,24.38) ; 132.27,49.73 133.75,51.2 133.75,52.4 v2(133.57,52.58)
PCIE_TX_LAN_N5: length 6.5
  TOP w0.102: 207.6,43.59 v1(207.49,43.47) ; 207.6,43.59 208.05,43.15 208.05,42.11 208.31,41.85 208.85,41.85 208.97,41.72 208.97,41.44 209.1,41.31 C1601.1 ; 207.6,43.59 207.16,44.03 207,44.03 206.88,43.9 v2(206.88,43.8)
  BOTTOM w0.102: v2(206.88,43.8) 206.88,44.06 206.77,44.16 206.57,44.16 206.54,44.14 206.09,44.14 205.95,44 IOBD1.19
PCIE_TX_LAN_P5: length 5.8
  TOP w0.102: v2(206.88,44.59) 206.92,44.59 208.27,43.24 208.27,42.68 ; 208.27,42.68 208.27,42.2 208.4,42.07 C1602.1 ; 208.27,42.68 v1(208.43,42.68)
  BOTTOM w0.102: v2(206.88,44.59) 206.67,44.59 206.54,44.46 206.45,44.37 206.09,44.37 206.06,44.4 IOBD1.20
PCIE_TX_WLAN_N6: length 8.9
  TOP w0.102: v2(209.32,38.19) 209.04,38.47 208.63,38.47 ; 208.63,38.47 v1(208.63,38.31) ; 208.63,38.47 208.33,38.47 207.98,38.82 207.98,40.16 208.35,40.52 C1613.1
  BOTTOM w0.102: v2(209.32,38.19) 207.78,38.19 207.19,37.6 206.56,37.6 206.11,38.05 205.81,38.05 205.76,38 IOBD1.4
PCIE_TX_WLAN_P6: length 8.9
  TOP w0.102: v1(208.38,39.53) 208.2,39.53 ; 208.2,39.53 208.2,40.06 208.44,40.3 208.82,40.3 208.95,40.17 208.95,39.89 209.08,39.76 C1614.1 ; 208.2,39.53 208.2,38.92 208.43,38.7 209.04,38.7 v2(209.32,38.98)
  BOTTOM w0.102: IOBD1.5 205.76,38.4 205.88,38.28 206.2,38.28 206.65,37.83 207.1,37.83 207.69,38.42 208.93,38.42 209.32,38.8 v2(209.32,38.98)
PCIE_WAKE#: length 39.1
  TOP w0.089: R2406.1 R2407.1 161.39,26.12 160.42,26.12 160.07,25.78 160.07,25.2 v2(159.53,24.66) ; KBC24.4 158.85,10.58 159.07,10.36 159.07,9.21 158.96,9.1 155.72,9.1 154.32,10.5 153.69,10.5 153.31,10.88 153.31,11.64 153.94,12.28 155.98,12.28 156.1,12.41 156.1,13.63 154.35,15.39 154.01,15.39 153.44,15.96 153.44,16.37 153.21,16.6 153.21,17.31 152.72,17.8 151.76,17.8 151.51,18.05 151.51,18.4 151.53,18.42 151.53,19.26 153.66,21.4 v2(153.66,21.88)
  BOTTOM w0.089: v2(153.66,21.88) 153.66,21.63 v1(154.02,21.28) 154.25,21.04 155.72,21.04 156.03,21.35 156.03,23.51 156.59,24.07 157.48,24.07 157.84,24.42 157.84,24.83 158.09,25.08 159.11,25.08 v2(159.53,24.66)
PCIE_WAKE#_CPU: length 50.5
  TOP w0.089: v2(111.4,17.6) 111.55,17.75 v1(111.55,18.17)
  L4 w0.089: v2(111.4,17.6) 110.83,17.04 109.72,17.04 109.52,17.23 100.93,17.23 100.31,17.86 97.85,17.86 95.16,20.55 95.16,31.5 98.06,34.4 98.06,35.37 98.8,36.11 99.82,36.11 105.71,42 105.71,42.63 v2(105.38,42.96)
  BOTTOM w0.089: RN1704.7 110.76,17.3 111.07,17.6 111.4,17.6 v2(111.4,17.6) ; CPU1.BB15 107.92,43.26 106.87,43.26 106.61,43.53 105.75,43.53 105.38,43.16 v2(105.38,42.96)
PD4403_A: length 3.5
  TOP w0.089: v1(190.93,66.23) 191.11,66.04 PD4404.A 191.42,64.29 PQ4408.B
PD4403_K: length 2.8
  TOP w0.089: v1(188.97,66.1) 188.97,64.66 PD4404.K PR4477.2
PD_CC1: length 3.3
  TOP w0.254: R3728.1 32.51,33.95 32.18,33.62 v1(32.18,32.96) 33.07,32.06 U3701.9
PD_CC2: length 2.7
  TOP w0.254: v1(34.64,32.96) 34.07,32.38 U3701.7
  TOP w0.508: R3727.1 35.07,33.39 v1(34.64,32.96)
PD_SWD_CLK: length 28
  TOP w0.089: U3701.2 36.57,31.99 35.96,32.6 v1(35.96,32.98) 35.96,36.41 v2(35.2,37.17)
  L3 w0.089: v2(35.2,37.17) 34.06,37.17 29.72,41.51 29.72,50.14 28.47,51.4 28.47,53.55 CCGDB1.4
PD_SWD_IO: length 31
  TOP w0.089: U3701.1 37.07,32.25 36.47,32.85 v1(36.47,36.66) 35.33,37.81 v2(34.56,37.81)
  L3 w0.089: CCGDB1.5 28.85,55.71 28.85,51.4 29.99,50.25 29.99,41.62 33.8,37.81 v2(34.56,37.81)
PD_VBUS_C_CTRL1: length 72.1
  TOP w0.089: v1(30.86,31.99) 30.86,31.99 v2(31.26,31.59) 31.26,30.69 31.42,30.54 U3701.12 ; PR4323.1 44.71,79.4 PQ4312.G 42.76,79.4 v2(42.57,79.21)
  L4 w0.089: v2(42.57,79.21) 40.22,76.86 40.22,76.1 39.28,75.17 39.28,63.28 41.04,61.52 41.04,60.41 40.28,59.65 40.28,47.97 40.41,47.84 40.41,45.05 42.95,42.51 42.95,40.69 45.85,37.79 45.85,31.83 45.26,31.25 43.53,31.25 42.9,31.88 39.18,31.88 38.45,31.15 31.7,31.15 v2(31.26,31.59)
PD_VBUS_C_CTRL1_A: length 12.2
  TOP w0.089: PQ4311.3 38.39,76.99 PC4311.1 39.64,76.85 PQ4307.5 39.64,78.57 39.77,78.7 40.17,78.7 40.29,78.57 PQ4307.6 41.12,77.05 ; PQ4306.D 43.02,77.83 42.66,78.19 v1(41.55,78.19) 41.12,77.76 41.12,77.05 ; 41.12,77.05 PR4319.2 40.9,76.83 PQ4313.6
PD_VBUS_C_CTRL1_R: length 6.5
  TOP w0.089: PR4342.2 36.22,80.61 36.55,80.27 38.17,80.27 v1(38.22,80.22) 39.26,80.22 39.64,79.84 ; 39.64,79.84 40.15,80.35 PQ4312.D ; 39.64,79.84 PQ4307.2
PD_VBUS_DISCHG: length 87.4
  TOP w0.089: v1(32.2,24.62) 32.13,24.62 v2(31.77,24.98) 31.91,25.12 U3701.20 ; v2(42.57,79.97) 42.57,80.27 41.72,81.11 PR4332.1 40.79,81.32 PQ4310.2
  L4 w0.089: v2(42.57,79.97) 42.99,79.55 42.99,79.01 40.47,76.48 40.47,76 39.47,75 39.47,64.27 39.9,63.84 42.44,63.84 43.07,63.21 43.07,62.06 42.44,61.43 42.44,51.91 44.22,50.13 44.22,50 44.22,40.98 47.51,37.69 47.51,23.31 45.88,21.68 42.31,21.68 41.3,22.69 36.58,22.69 35.56,23.71 35.2,23.71 33.93,24.98 v2(31.77,24.98)
PD_VBUS_P_CTRL1: length 75.7
  TOP w0.089: PR4310.1 39.77,75.45 v2(39.77,76.29) 40.1,76.62 v1(40.1,76.75) ; v2(31.9,31.57) 31.9,31.05 U3701.11 ; PD4308.A 41.93,85.22 41.93,83.53 42.23,83.22 v2(42.48,83.22)
  L3 w0.089: v2(39.77,76.29) 39.77,80.1 42.48,82.81 v2(42.48,83.22)
  L4 w0.089: v2(31.9,31.57) 38.42,31.57 38.92,32.07 43.09,32.07 43.72,31.44 45.19,31.44 45.66,31.91 45.66,37.71 42.76,40.61 42.76,42.38 40.15,44.98 40.15,47.46 40.03,47.59 40.03,59.78 40.79,60.54 40.79,61.41 39.09,63.11 39.09,75.61 v2(39.77,76.29)
PD_VBUS_P_CTRL1_R: length 42.4
  TOP w0.089: PR4324.1 v1(38.88,73.49) 38.02,72.63 38.02,72.62 37.32,72.62 36.81,73.13 v2(36.81,73.49) ; PR4324.1 38.58,74.76 PQ4309.5 ; PR4324.1 PR4310.2
  L6 w0.089: v2(42.95,92.04) 38.88,87.97 38.88,83.91 36.47,81.49 36.47,80.73 36.81,80.4 v2(36.81,73.49)
  BOTTOM w0.089: PQ4314.D 54.43,94.14 52.34,96.23 v1(50.82,96.23) 50.65,96.06 49.5,96.06 49.33,96.23 48.78,96.23 47.84,95.29 47.47,95.29 44.22,92.04 v2(42.95,92.04)
PD_VBUS_R: length 3.7
  TOP w0.089: R3730.2 R3726.2 29.94,30.92 C3717.2 30.07,30.31 v1(30.8,30.31) 31.01,30.31 31.28,30.04 U3701.13
PD_VCCD: length 3.3
  TOP w0.089: C3715.1 40.58,27.01 39.01,27.01 v1(38.76,27.27) 38.48,27.54 U3701.33
PD_XRES: length 26.1
  TOP w0.089: U3701.10 32.41,31.7 31.65,32.46 31.53,32.46 v2(31.26,32.73) 31.26,33.16 v1(30.96,33.46) 30.17,33.46 C3716.1 29.94,32.5 R3724.2
  L6 w0.089: CCGDB1.3 27.96,51.52 27.96,39.97 31.34,36.58 31.34,32.81 v2(31.26,32.73)
PEG_CLK1_CPU: length 114
  TOP w0.102: v2(206.76,39.79) 206.46,40.09 v1(206.22,40.09)
  L4 w0.14: v2(133.95,58.89) 133.86,58.8 133.86,58.52 133.99,58.39 136.97,58.39 137.39,58.82 140.75,58.82 146.11,53.46 146.11,37.38 148.23,35.27 148.85,35.27 149.5,35.27 151.68,33.08 151.68,30.77 154.71,27.74 166.55,27.74 166.83,27.45 191.66,27.45 191.94,27.73 194.16,27.73 194.47,28.04 204,28.04 204.77,28.81 204.77,32.75 205.37,33.35 205.37,39.03 205.75,39.42 206.38,39.42 v2(206.76,39.79)
  BOTTOM w0.089: CPU1.A42 130.78,59.29 130.95,59.29 130.97,59.27 132.17,59.27 132.35,59.45 133.85,59.45 133.93,59.37
  BOTTOM w0.102: IOBD1.8 206,39.6 206.08,39.51 206.48,39.51 v2(206.76,39.79) ; 133.93,59.37 133.95,59.35 v2(133.95,58.89)
PEG_CLK1_CPU#: length 114.1
  TOP w0.102: v2(206.76,39) 206.6,38.85 v1(206.22,38.85)
  L4 w0.14: v2(206.76,39) 206.61,39.15 205.86,39.15 205.63,38.92 205.63,33.24 205.04,32.64 205.04,28.7 204.11,27.77 194.58,27.77 194.27,27.46 192.05,27.46 191.77,27.18 166.72,27.18 166.44,27.47 154.6,27.47 151.42,30.66 151.42,32.97 149.39,35 148.96,35 148.11,35 145.84,37.27 145.84,53.35 140.64,58.55 137.5,58.55 137.08,58.13 133.88,58.13 133.32,58.69 v2(133.32,58.89)
  BOTTOM w0.089: CPU1.B42 130.38,59.21 130.6,59.1 130.87,59.1 130.89,59.08 132.25,59.08 132.43,59.26 132.95,59.26 133.17,59.04 v2(133.32,58.89)
  BOTTOM w0.102: v2(206.76,39) 206.48,39.29 206.08,39.29 206,39.2 IOBD1.7
PEG_TX_CPU_N0: length 59.2
  TOP w0.102: v2(133.83,45.17) 133.85,45.19 v1(133.85,45.76)
  L6 w0.127: v2(149.96,75.14) 150.21,75.39 150.84,75.39 151.16,75.06 151.16,74.47 150.71,74.02 150.71,71.43 150.99,71.15 151.77,71.15 151.9,71.02 151.9,70.77 151.77,70.64 150.99,70.64 150.71,70.36 150.71,68.21 149.41,66.92 149.41,60.17 140.14,50.9 140.14,42.71 139.94,42.51 139.42,42.51 139.21,42.71 139.21,45.21 138.88,45.54 138.15,45.54 137.82,45.21 137.82,44.69 137.69,44.56 134.21,44.56 133.83,44.95 v2(133.83,45.17)
  BOTTOM w0.089: v2(133.83,45.17) 133.43,44.77 133.27,44.77 132.69,44.18 130.7,44.18 CPU1.B17
  BOTTOM w0.102: v1(148.38,75.25) 148.38,75.4 ; 148.38,75.4 147.86,75.4 147.42,75.84 147.42,76.33 C1606.2 ; 148.38,75.4 149.69,75.4 v2(149.96,75.14)
PEG_TX_CPU_N1: length 57.9
  TOP w0.102: v1(136.29,45.17) 135.74,45.17 v2(135.73,45.17)
  L6 w0.127: v2(135.73,45.17) 136.61,46.05 139.2,46.05 139.63,46.48 139.63,51.11 148.9,60.38 148.9,67.13 149.34,67.56 149.34,68.18 149.46,68.3 149.85,68.3 150.13,68.59 150.13,69.06 149.85,69.35 149.46,69.35 149.34,69.47 149.34,69.73 149.46,69.85 149.85,69.85 150.13,70.14 150.13,70.61 149.85,70.9 149.46,70.9 149.34,71.02 149.34,73.19 149.46,73.32 149.98,73.32 150.26,73.6 150.26,74.08 149.98,74.36 149.46,74.36 149.34,74.49 149.34,76.77 149.46,76.9 149.98,76.9 150.26,77.18 150.26,77.66 149.98,77.94 149.46,77.94 149.34,78.07 149.34,78.99 148.23,80.1 v2(146.86,80.1)
  BOTTOM w0.089: 133.59,44.39 133.47,44.39 132.9,43.82 130.22,43.82 130.04,43.74 129.81,43.64 129.66,43.64 CPU1.D16
  BOTTOM w0.102: 133.59,44.39 134.32,44.39 134.49,44.21 135.5,44.21 135.73,44.44 v2(135.73,45.17) ; v2(146.86,80.1) 147.26,80.1 C1608.2
PEG_TX_CPU_N2: length 57.9
  TOP w0.102: v1(131.92,44.59) v2(131.92,45.17)
  L6 w0.127: v2(146.83,81.62) 145.74,81.62 145.1,80.99 144.67,80.99 144.28,80.59 144.28,79.17 144.88,78.57 147.8,78.57 148.15,78.23 148.15,74.26 148.15,67.84 147.86,67.56 147.86,60.81 138.59,51.54 138.59,47.22 138.46,47.09 137.83,47.09 137.7,47.22 137.7,48.08 137.42,48.36 136.36,48.36 136.07,48.08 136.07,47.17 135.48,46.58 134.9,46.58 134.78,46.46 133.21,46.46 v2(131.92,45.17)
  BOTTOM w0.089: CPU1.D17 129.28,44.76 129.43,44.79 129.63,44.79 129.82,44.88 129.94,44.94 130.19,44.94 130.32,44.88 130.37,44.88 130.47,44.88 130.52,44.91 130.57,44.93 130.61,44.94 130.95,44.94 131.13,44.76 131.51,44.76 v2(131.92,45.17)
  BOTTOM w0.102: v2(146.83,81.62) 147.26,81.62 C1610.2
PEG_TX_CPU_N3: length 58.8
  TOP w0.102: v2(134.72,47.61) 134.61,47.71 v1(134.13,47.71)
  L6 w0.127: v2(146.83,83.27) 146.63,83.07 144.34,83.07 143.4,82.13 143.4,78.95 143.77,78.59 143.77,77.7 144.93,76.54 146.71,76.54 147.27,75.98 147.27,68.06 147.06,67.85 147.06,61.11 137.82,51.86 137.82,50.19 136.79,49.16 132.75,49.16 132.47,48.88 132.47,48.38 132.75,48.09 134.59,48.09 134.72,47.97 v2(134.72,47.61)
  BOTTOM w0.089: 134.05,46.46 134.03,46.46 134.01,46.44 133.19,46.44 132.91,46.16 130.77,46.16 130.74,46.14 130.58,46.11 CPU1.B19
  BOTTOM w0.102: v2(134.72,47.61) 134.84,47.48 134.84,46.77 134.53,46.46 134.05,46.46 ; C1612.2 v2(146.83,83.27)
PEG_TX_CPU_P0: length 59
  TOP w0.102: v1(133.22,44.59) 133.22,45.14 v2(133.19,45.17)
  L6 w0.127: v2(133.19,45.17) 133.19,44.87 133.29,44.77 133.63,44.77 134.1,44.3 137.8,44.3 138.08,44.58 138.08,45.1 138.26,45.27 138.77,45.27 138.95,45.1 138.95,42.6 139.3,42.24 140.05,42.24 140.41,42.6 140.41,50.79 149.68,60.06 149.68,66.81 150.97,68.1 150.97,70.25 151.1,70.38 151.88,70.38 152.17,70.66 152.17,71.13 151.88,71.42 151.1,71.42 150.97,71.54 150.97,73.91 151.43,74.36 151.43,75.18 150.95,75.65 150.19,75.65 v2(149.96,75.89)
  BOTTOM w0.089: CPU1.A17 130.83,44.37 132.61,44.37 133.19,44.96 v2(133.19,45.17)
  BOTTOM w0.102: C1605.2 147.65,76.33 147.65,75.93 147.95,75.63 149.69,75.63 v2(149.96,75.89)
PEG_TX_CPU_P1: length 58
  TOP w0.102: v2(135.1,45.17) 135.15,45.22 v1(135.15,45.78)
  L6 w0.127: v2(135.1,45.17) 134.92,45.34 134.92,45.68 135.05,45.81 136,45.81 136.5,46.32 139.09,46.32 139.36,46.6 139.36,51.22 148.64,60.49 148.64,67.24 149.07,67.67 149.07,68.29 149.35,68.57 149.74,68.57 149.87,68.7 149.87,68.95 149.74,69.08 149.35,69.08 149.07,69.36 149.07,69.84 149.35,70.12 149.74,70.12 149.87,70.25 149.87,70.5 149.74,70.63 149.35,70.63 149.07,70.91 149.07,73.3 149.35,73.58 149.87,73.58 149.99,73.71 149.99,73.97 149.87,74.09 149.35,74.09 149.07,74.38 149.07,76.88 149.35,77.17 149.87,77.17 149.99,77.29 149.99,77.55 149.87,77.67 149.35,77.67 149.07,77.96 149.07,78.88 148.12,79.83 147.57,79.83 147.45,79.72 147.45,79.45 147.36,79.35 146.94,79.35 v2(146.86,79.44)
  BOTTOM w0.089: CPU1.C16 130,43.93 130.18,44.01 132.82,44.01 133.39,44.58 133.5,44.58 133.51,44.58 133.55,44.58 133.58,44.61 133.59,44.61
  BOTTOM w0.102: v2(146.86,79.44) 146.99,79.56 147.29,79.56 C1607.2 ; v2(135.1,45.17) 135.1,44.89 135.17,44.82 135.42,44.82 135.5,44.73 135.5,44.53 135.41,44.44 134.59,44.44 134.41,44.61 133.59,44.61
PEG_TX_CPU_P2: length 57.7
  TOP w0.102: v1(132.56,45.73) v2(132.56,45.17)
  L6 w0.127: v2(146.83,80.94) 146.72,80.94 146.3,81.36 145.85,81.36 145.22,80.72 144.78,80.72 144.55,80.48 144.55,79.28 144.99,78.84 147.91,78.84 148.41,78.34 148.41,74.38 148.41,74.37 148.41,67.73 148.13,67.45 148.13,60.7 138.86,51.43 138.86,47.11 138.57,46.82 137.72,46.82 137.43,47.11 137.43,47.97 137.31,48.09 136.47,48.09 136.34,47.97 136.34,47.06 135.6,46.32 135.01,46.32 134.89,46.19 133.32,46.19 132.56,45.42 v2(132.56,45.17)
  BOTTOM w0.089: CPU1.C17 129.96,44.75 129.96,44.75 130.15,44.75 130.28,44.71 130.33,44.69 130.48,44.69 130.6,44.75 130.61,44.75 130.87,44.75 131.05,44.57 131.59,44.57 131.79,44.77 132.48,44.77 132.56,44.84 v2(132.56,45.17)
  BOTTOM w0.102: v2(146.83,80.94) 146.88,80.99 C1609.2
PEG_TX_CPU_P3: length 58.7
  TOP w0.102: v1(135.66,47.1) 135.66,47.31 v2(135.35,47.61)
  L6 w0.127: v2(146.83,82.56) 146.59,82.8 144.45,82.8 143.67,82.02 143.67,79.07 144.04,78.7 144.04,77.81 145.04,76.81 146.82,76.81 147.54,76.09 147.54,67.95 147.33,67.74 147.33,61 138.08,51.75 138.08,50.08 136.9,48.89 132.86,48.89 132.74,48.77 132.74,48.49 132.86,48.36 134.72,48.36 135.11,47.97 135.28,47.97 135.35,47.89 v2(135.35,47.61)
  BOTTOM w0.089: CPU1.A19 130.84,45.97 132.99,45.97 133.27,46.25 134.01,46.25 134.03,46.23 134.05,46.23
  BOTTOM w0.102: v2(146.83,82.56) 147.04,82.76 147.26,82.76 147.39,82.64 C1611.2 ; v2(135.35,47.61) 135.35,47.31 135.28,47.23 135.12,47.23 135.07,47.18 135.07,46.68 134.63,46.23 134.05,46.23
PEX_TERMP: length 6.6
  BOTTOM w0.089: v1(147.29,90.51) 147.29,90.54 R7301.1 148.56,90.99 148.62,90.94 149.72,90.94 151.32,90.94 151.91,91.53 151.91,92.06 GPU1.AF25
PEXTSTCLK_OUT: length 4.3
  BOTTOM w0.089: R7307.1 148.39,90.44 148.4,90.44 v1(150.03,90.44) 151.6,90.44 152.04,90 GPU1.AF22
PEXTSTCLK_OUT#: length 5.4
  BOTTOM w0.089: GPU1.AE22 152.72,89.57 151.2,89.57 150.83,89.95 149.43,89.95 v1(149.12,89.64) 149.05,89.57 R7307.2
PIRQA#: length 13.4
  TOP w0.089: v2(104.8,39.86) 107.11,42.17 v1(108.48,42.17) 113,42.17 113.11,42.28 R1607.2
  BOTTOM w0.089: CPU1.BB11 108.02,40.95 106.73,40.95 106.3,40.52 105.46,40.52 v2(104.8,39.86)
PLT_RST#: length 374.5
  TOP w0.102: R9110.1 209.57,36.69 209.49,36.61 v2(209.07,36.61) ; R2616.1 46.3,7.28 v2(46.76,6.82) ; EC6602.1 206.27,57.24 v2(206.52,56.98) ; R6308.1 229.81,15.73 229.36,15.28 221.74,15.28 v2(221.31,15.71) ; v2(120.17,20.36) 120,20.53 v1(119.02,20.53) v2(117.5,20.53)
  L3 w0.102: v2(120.17,20.36) 118.01,20.36 117.01,19.37 103.33,19.37 101.73,17.77 94.69,17.77 94.03,17.11 90.99,17.11 89.37,15.48 84.8,15.48 83.68,14.36 80.68,14.36 77.79,11.47 74.44,11.47 71.01,8.04 60.27,8.04 58.8,6.56 54.32,6.56 53.63,7.25 47.19,7.25 v2(46.76,6.82)
  L4 w0.102: v2(145.05,72.48) 147.99,72.48 148.23,72.24 149.57,72.24 150.49,73.16 154.12,73.16 154.67,72.6 164.77,72.6 167.17,70.2 172.09,70.2 173.93,68.36 180.62,68.36 183.4,71.14 184.84,71.14 185.65,70.32 187.09,70.32 187.27,70.14 192.22,70.14 193.33,69.04 193.33,64.28 195.36,62.25 196.66,62.25 198.05,60.87 205.91,60.87 208.56,58.22 209.25,58.22 210.09,57.38 210.09,56.22 213.53,52.78 213.53,51.98 213.99,51.52 v2(214.02,51.52) 215.41,50.13 216.56,50.13 217.67,51.24 219.78,51.24 220.42,50.61 220.42,49.07 218.46,47.11 218.46,46.43 222.33,42.57 222.33,23.23 220.62,21.52 220.62,16.4 v2(221.31,15.71) ; v2(135.58,21.09) 135.05,20.57 130.19,20.57 128.72,22.03 124.63,22.03 122.73,20.13 120.41,20.13 v2(120.17,20.36)
  L6 w0.102: v2(135.58,21.09) 135.76,20.92 145.98,20.92 146.46,20.44 157.15,20.44 157.63,20.92 164.61,20.92 165.14,20.39 173.56,20.39 174.9,21.73 189.48,21.73 190.31,22.56 198.17,22.56 198.85,21.88 205.07,21.88 206.78,23.58 206.78,25.87 208.12,27.21 208.12,30.07 207.47,30.71 207.47,33.57 208.05,34.15 208.05,35.59 v2(209.07,36.61) 209.38,36.92 210.46,36.92 210.84,37.3 210.84,39.94 210.47,40.32 210.47,45.46 210.72,45.71 210.72,55.89 210.17,56.43 207.07,56.43 v2(206.52,56.98)
  BOTTOM w0.102: IOBD1.52 206.31,57.2 v2(206.52,56.98) 206.9,57.36 207.41,57.36 208.1,56.68 210.97,56.68 213.13,54.52 213.13,52.39 213.99,51.52 v2(214.02,51.52) ; U7301.2 143.78,71.59 144.55,72.35 144.93,72.35 v2(145.05,72.48) ; C1701.1 EC1703.1 117.42,19.87 R1715.1 116.86,20.48 R1713.1 117.29,20.74 v2(117.5,20.53)
PLT_RST#_Q_TPM2: length 4.4
  TOP w0.102: R9110.2 210.71,37.3 v1(211.09,37.68) 211.6,37.68 212.87,36.41 U9101.17
PM_PCH_PWROK: length 57.7
  TOP w0.127: v2(91,21.53) 90.83,21.35 v1(90.83,20.92)
  L4 w0.127: v2(91,21.53) 91.42,21.11 91.55,21.11 94.28,18.38 94.28,17.42 96.89,14.82 v2(106.76,14.82)
  BOTTOM w0.127: CPU1.BA20 108.53,45.85 107.9,45.22 104.54,45.22 103.7,44.37 101.68,44.37 101.67,44.39 100.97,44.39 99.56,42.98 98.71,42.98 92.74,37.01 92.74,32.87 90.76,30.89 90.76,22.57 90.58,22.4 90.58,22.03 91,21.61 v2(91,21.53) ; R1706.2 107.02,15.03 106.81,14.82 v2(106.76,14.82) 106.76,14.82 106.4,15.18 RN1703.3
PM_RSMRST#: length 68.2
  TOP w0.127: Q1701.3 91.13,14.95 R1720.2 91.13,15.58 R1702.1 90.71,16.94 90.71,19.13 v1(90.57,19.26) 90.19,19.65 90.19,21.37 v2(91.03,22.21)
  L4 w0.127: v2(106.76,14.18) 106.38,14.57 96.78,14.57 93.8,17.55 91.14,17.55 90.56,18.13 90.56,21.74 v2(91.03,22.21)
  BOTTOM w0.127: CPU1.AY17 109.05,44.96 104.62,44.96 103.81,44.16 101.59,44.16 101.58,44.17 101.06,44.17 99.64,42.75 98.84,42.75 92.99,36.9 92.99,32.77 91.02,30.8 91.02,24.82 91.03,24.82 v2(91.03,22.21) ; R1704.1 106.92,14.26 106.84,14.18 v2(106.76,14.18) 106.68,14.18 106.35,14.51 RN1703.4
PM_RSMRST#_M: length 3.7
  TOP w0.089: R1737.2 86.32,14.58 Q1702.6 85.36,15.57 85.21,15.72 v1(85.21,15.84) 85.21,16.06 85.36,16.22 Q1702.5
PM_RSMRST#_R: length 2.6
  TOP w0.089: R1720.1 89.3,15.45 v1(89.17,15.58) 88.54,16.22 Q1702.2
POWER_SW_IN#: length 7.6
  TOP w0.089: R2451.1 R2432.2 160.47,4.94 C2426.1 160.47,6.62 v1(160.07,7.02) 156.53,7.02 156.44,7.11 KBC24.127
PQ3802_1: length 3.5
  BOTTOM w0.635: PQ4302.B 59.9,102.46 v1(59.63,102.73) 58.8,102.73 PR4309.2 PR4302.1
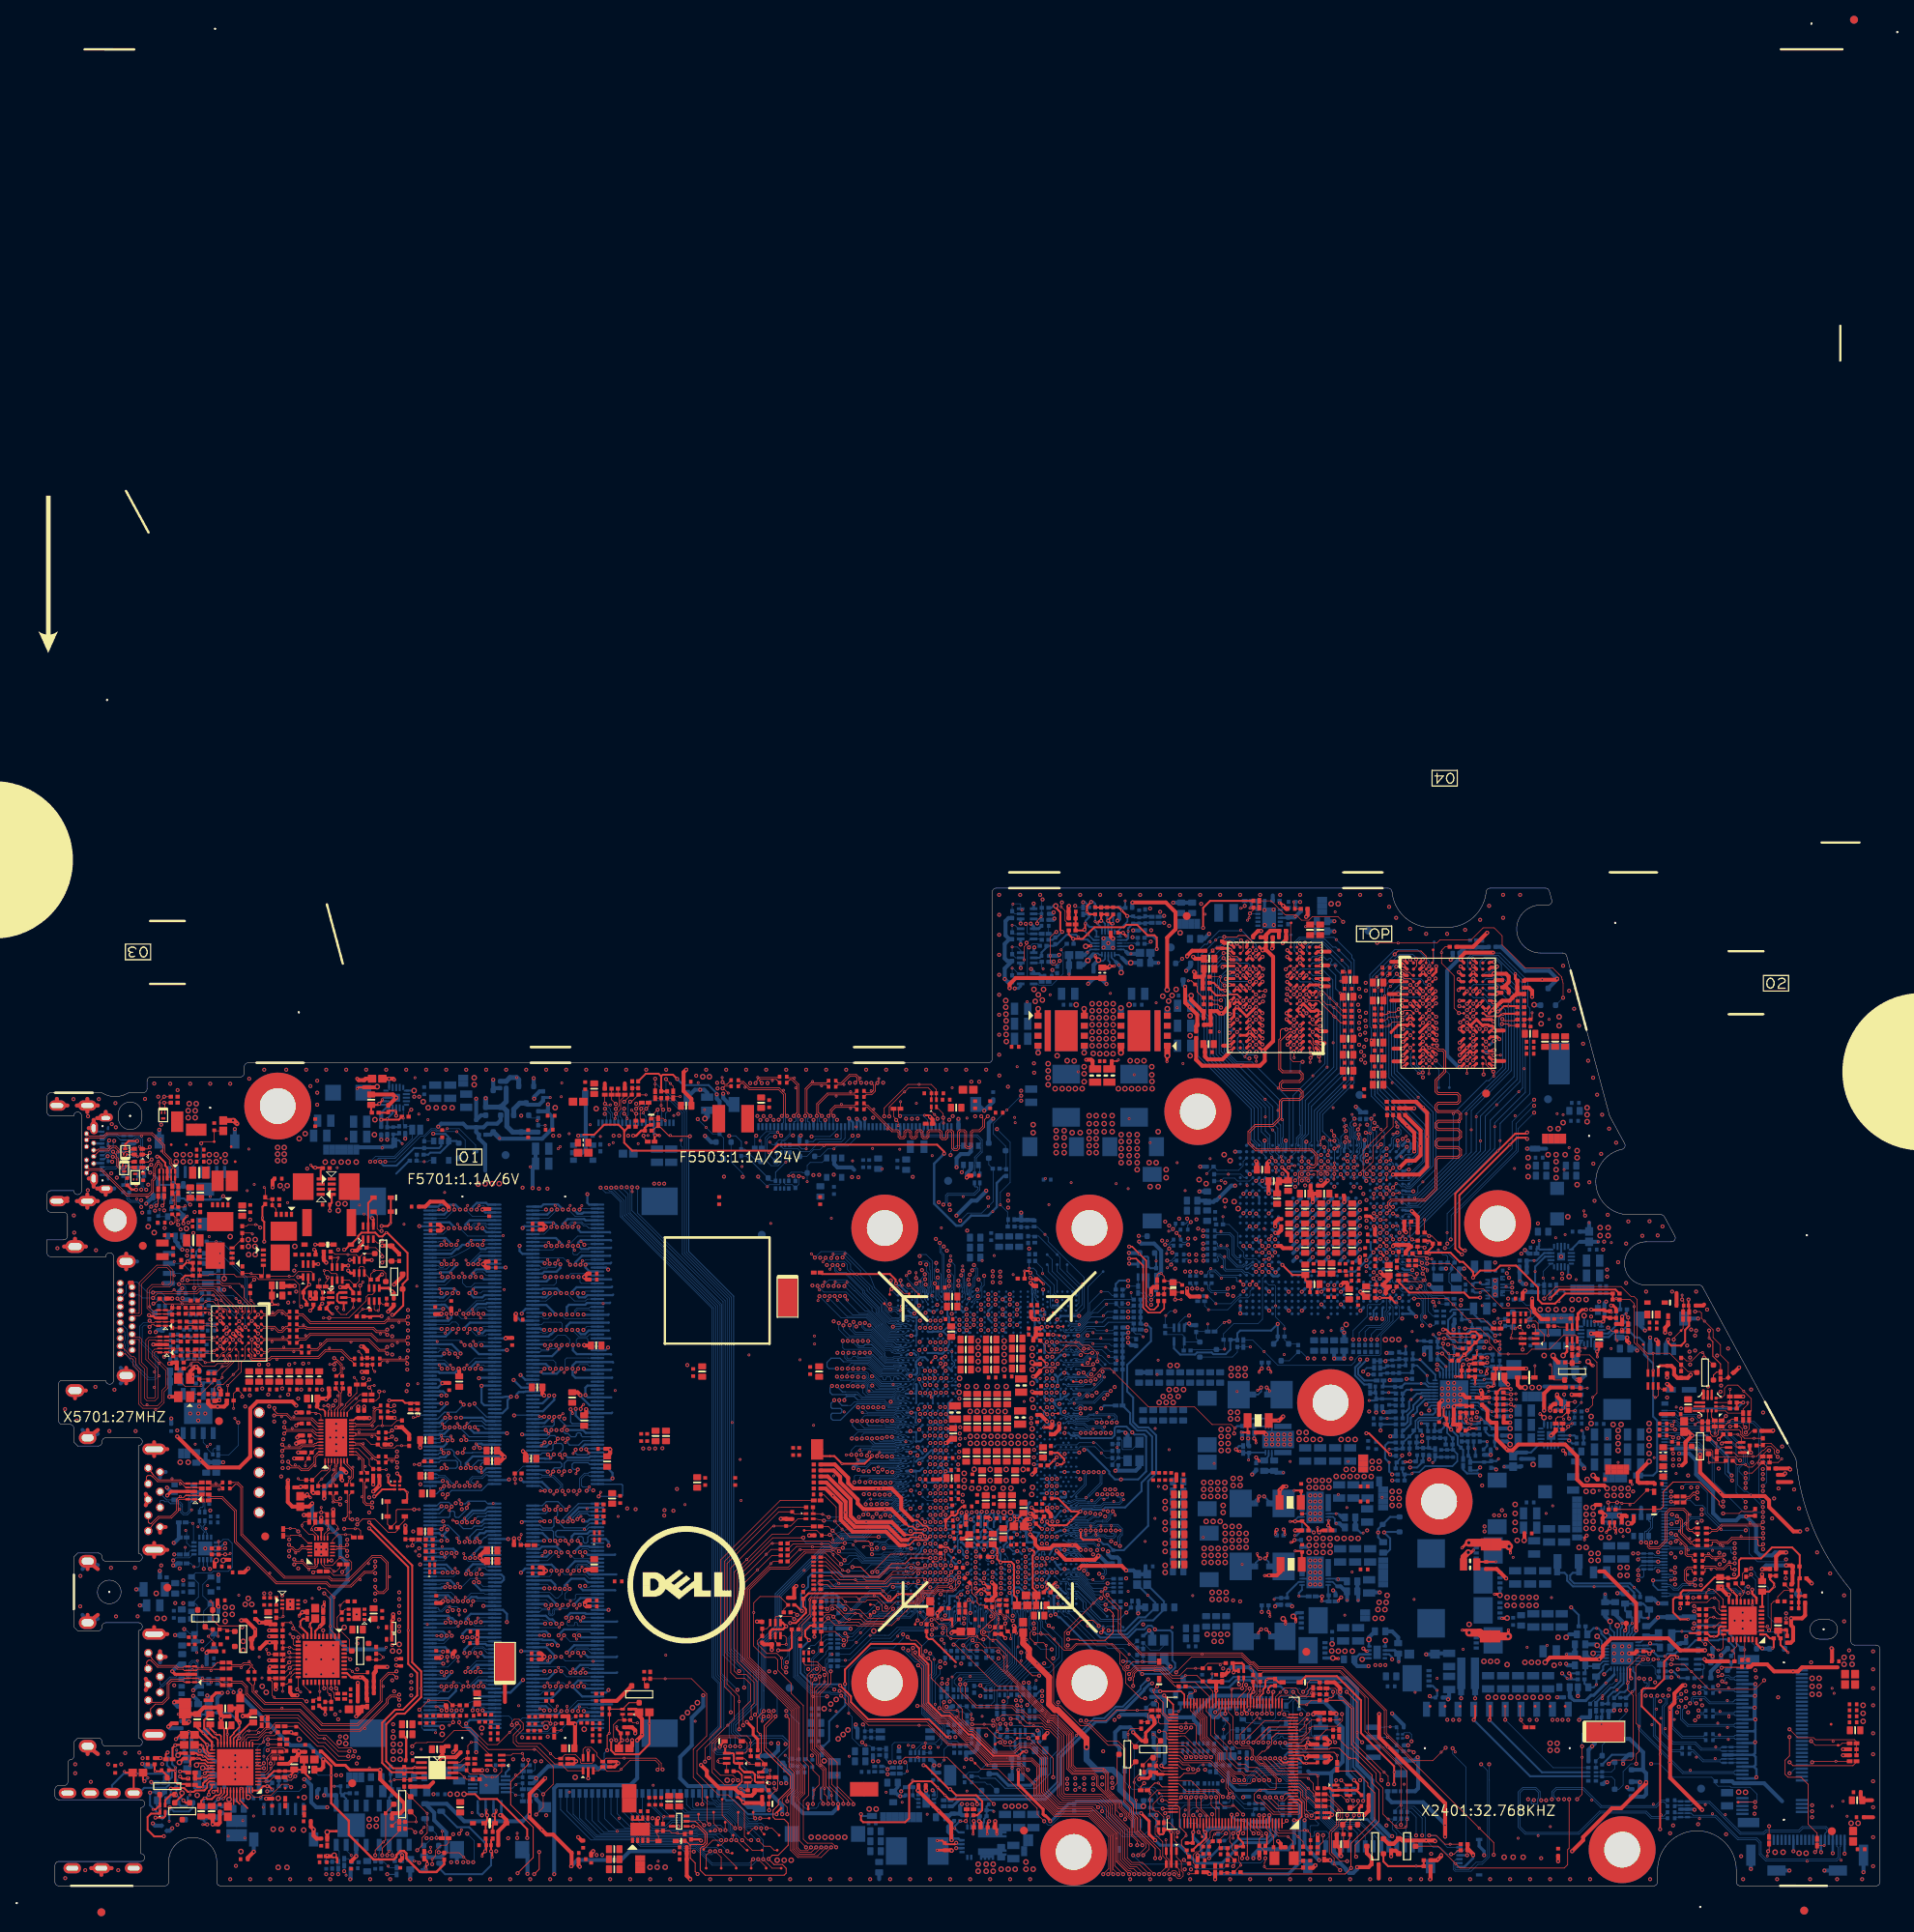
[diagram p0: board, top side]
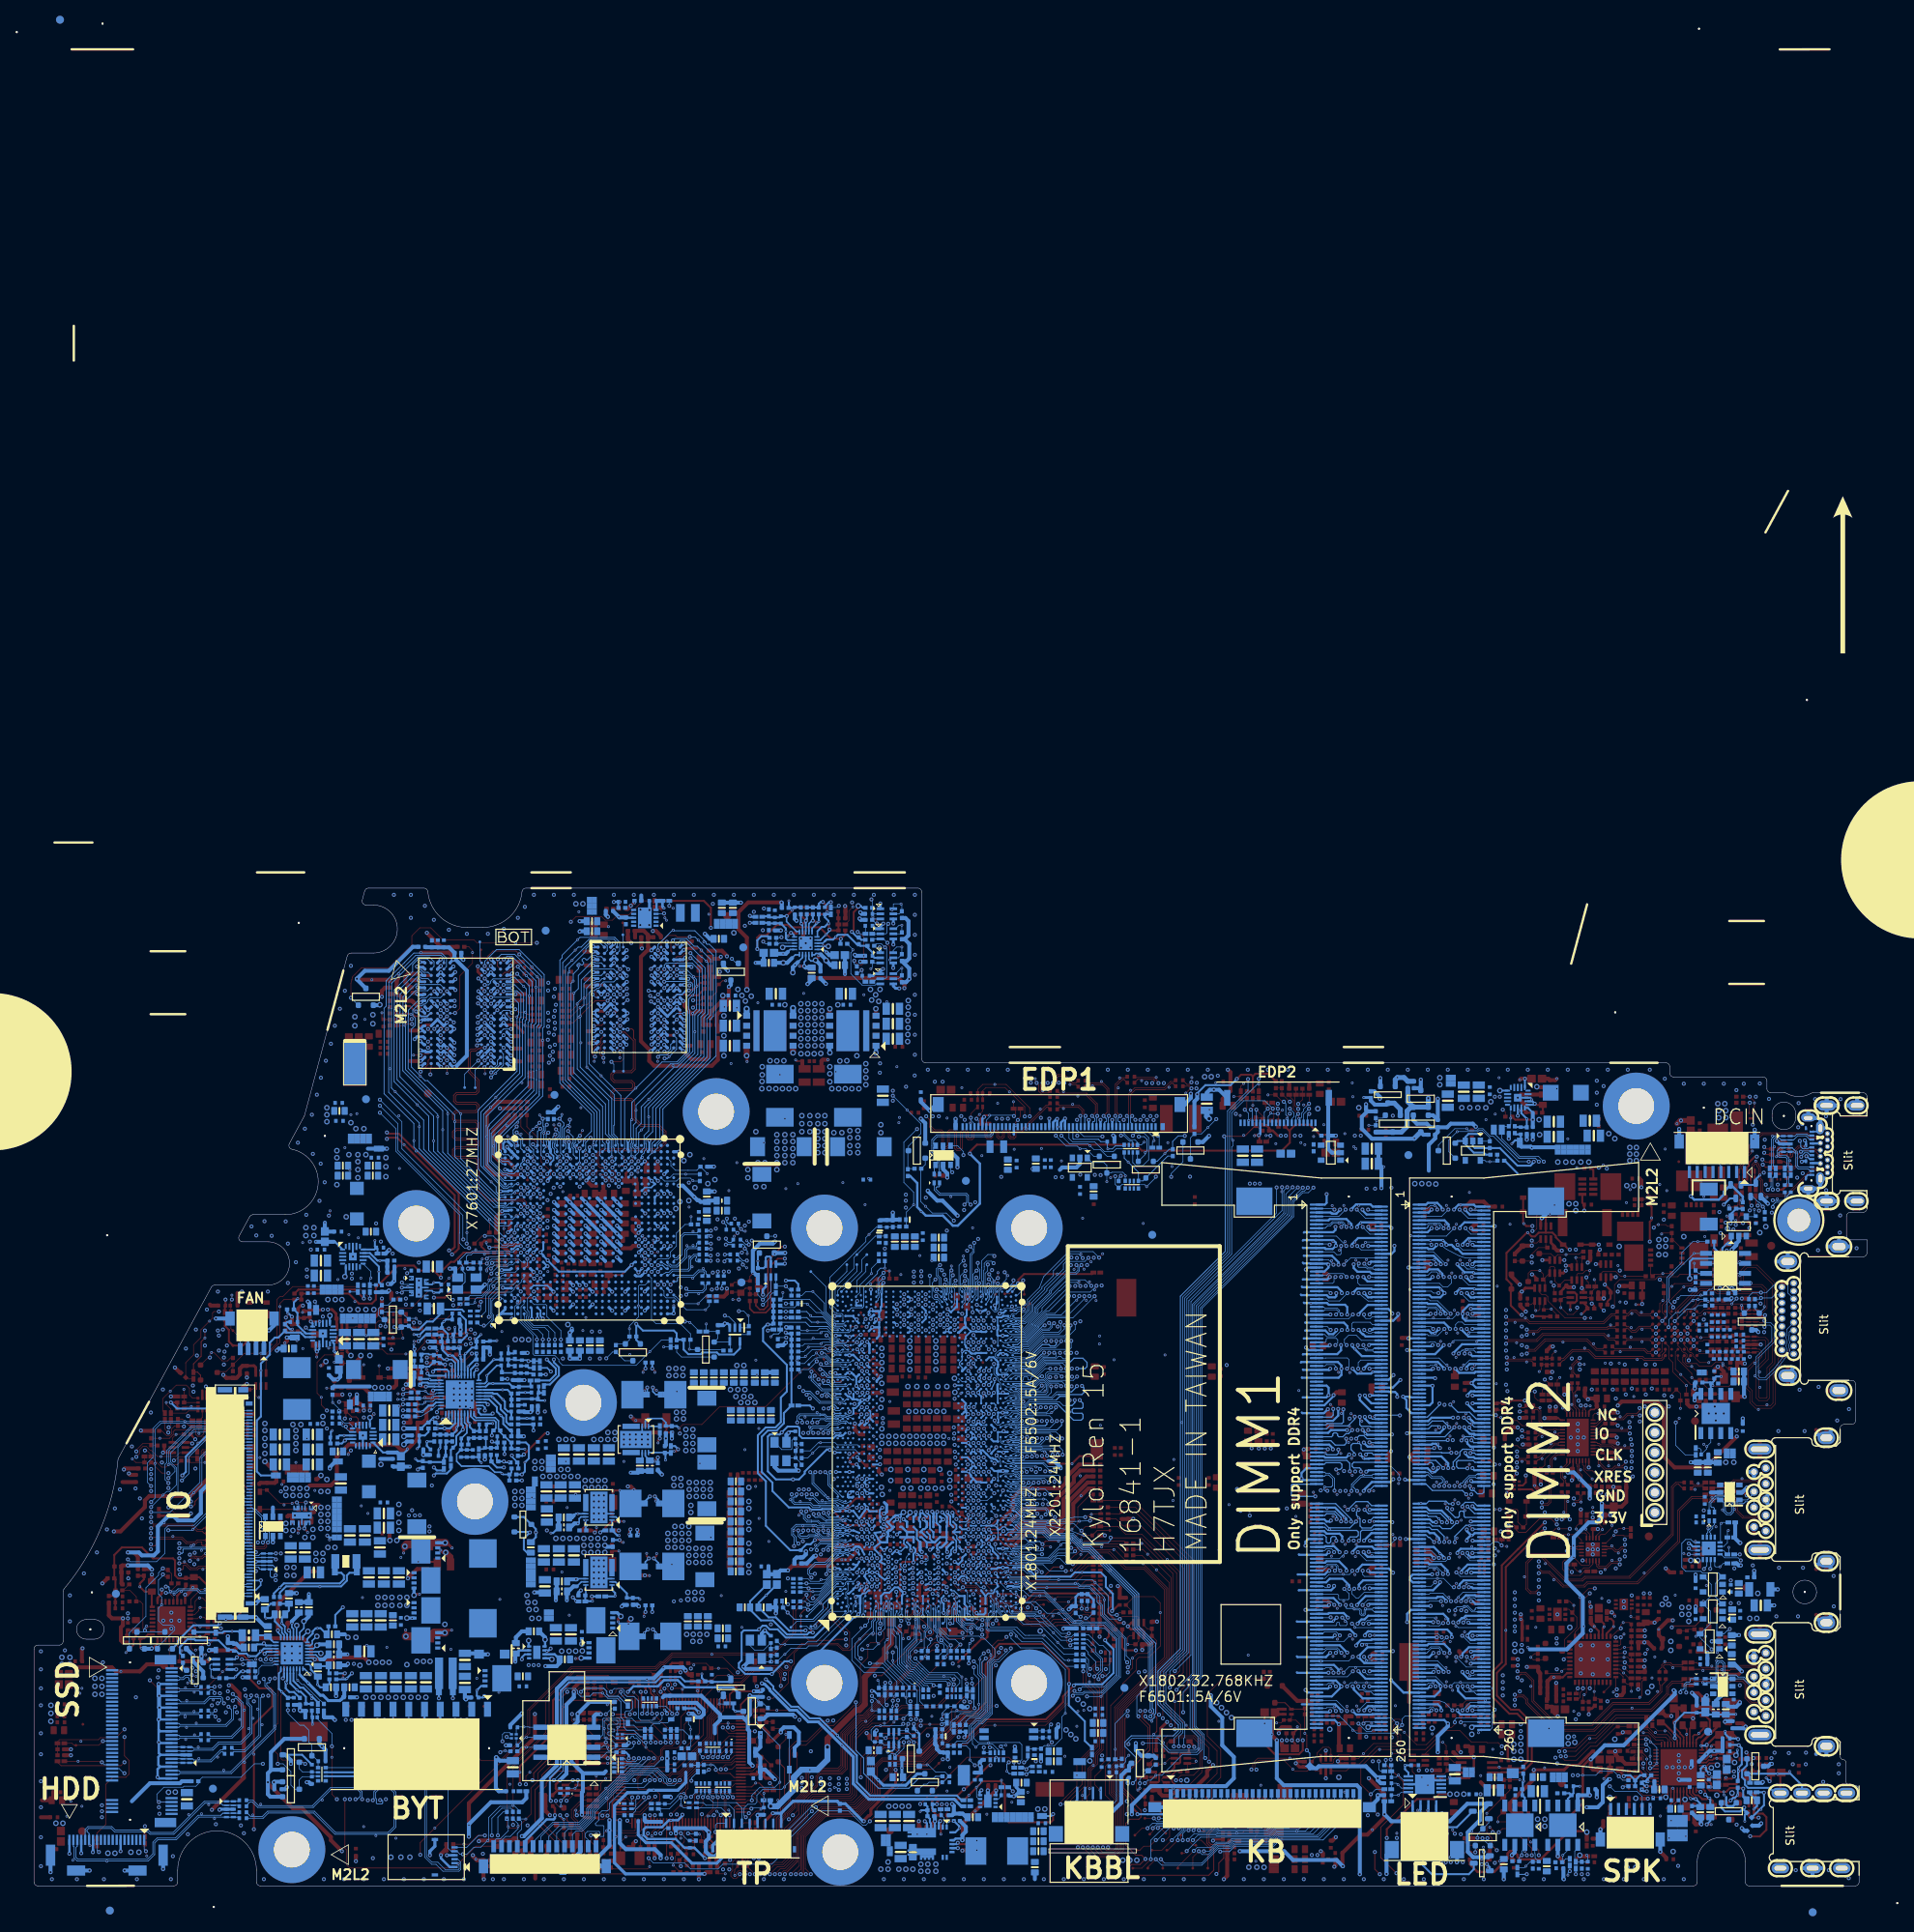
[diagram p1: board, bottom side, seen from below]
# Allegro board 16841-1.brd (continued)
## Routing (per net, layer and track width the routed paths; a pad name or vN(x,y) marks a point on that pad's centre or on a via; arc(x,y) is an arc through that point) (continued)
PQ4405_2: length 2.7
  TOP w0.089: PQ4405.2 PR4462.1 PR4463.1 v1(195.37,68.34)
PQ4405_3: length 63.6
  TOP w0.089: v2(180.11,70.83) 182.01,70.83 183.2,69.64 183.2,68.97 183.71,68.46 183.71,68.4 184.51,67.59 v1(185.57,67.59) 187.96,67.59 188.57,68.2 190.82,68.2 192.63,70.02 194.12,70.02 194.35,69.8 PQ4405.3
  L4 w0.127: v2(180.11,70.83) 180.11,70.95 179.85,71.21 177.19,71.21 175.92,69.94 174,69.94 173.3,70.64 167.35,70.64 164.95,73.04 161.8,73.04 161.02,73.81 152.92,73.81 152.76,73.66 149.97,73.66 149.61,73.3 148.67,73.3 148.21,73.76 144.79,73.76 143.5,75.05 141.66,75.05 140.48,73.87 140.25,73.87 v2(140.23,73.85)
  BOTTOM w0.089: PR4476.1 139.01,75.35 139.34,75.02 139.34,74.74 v2(140.23,73.85)
PQ4405_5: length 3.3
  TOP w0.089: PC4438.1 191.51,72.15 v1(192.32,72.15) 193.47,72.15 PR4474.2 193.7,71.92 PQ4405.5
PQ4405_6: length 3.7
  TOP w0.089: PQ4405.6 192.03,71.02 191.92,71.13 PC4438.2 191.38,71.16 PR4450.1 v1(190.65,69.94)
PQ4408_C: length 3
  TOP w0.089: PR4462.2 PQ4408.C ; PQ4408.C 192.93,66.44 PR4475.1 ; PQ4408.C 194.54,66.44 v1(194.66,66.56)
PQ4408_E: length 3
  TOP w0.089: PQ4408.E 194.65,63.32 PR4473.2 ; PR4473.2 v1(195.63,63.26) ; PR4473.2 193.82,63.26 PR4436.1
PRIM_PWRGD: length 135.8
  TOP w0.089: v2(151.94,18.22) 151.94,18.27 154.65,20.98 KBC24.30
  L3 w0.089: v2(151.94,18.22) 151.35,17.63 149.95,17.63 149.7,17.89 136.78,17.89 134.61,15.72 133.56,15.72 131.72,13.88 v2(131.72,13.68)
  L4 w0.089: v2(37.74,1.87) 38.73,1.87 39.56,2.7 45.96,2.7 46.81,3.55 47.2,3.55 48.56,4.91 57.82,4.91 58.26,5.35 64.53,5.35 64.67,5.5 71.09,5.5 76.98,11.39 83.48,11.39 86.26,14.17 88.13,14.17 90.49,11.81 91.08,11.81 94.1,11.81 96.11,9.8 103.3,9.8 104.04,9.05 108.09,9.05 110.23,11.19 114.66,11.19 115.21,11.74 116.83,11.74 117.02,11.55 130.53,11.55 131.01,12.03 131.01,12.96 v2(131.72,13.68)
  BOTTOM w0.089: v2(151.94,18.22) 151.91,18.25 R4030.1 ; PR5408.1 v2(37.74,1.87) 37.98,1.63 v1(37.98,1.36)
PROC_SELECT#: length 10.7
  BOTTOM w0.089: v1(137.69,75.4) 137.69,74.84 R603.1 134.27,74.51 133.07,73.31 133.06,73.31 132.59,72.84 132.59,72.84 131.03,71.28 129.83,71.28 CPU1.C64
PROCHOT: length 8
  TOP w0.089: v1(140.48,19.26) 140.6,19.26 Q2408.G 140.99,17.99 140.99,16.74 141,16.73 141,15.85 140.86,15.72 R2417.1 ; R2418.1 140.1,15.25 R2417.1 ; R2417.1 141.51,14.61 141.93,14.61 141.95,14.58 KBC24.83
PROJECT_ID0: length 21.3
  TOP w0.089: R1916.2 98.47,34.76 99.26,34.76 v2(99.74,35.24) 100.15,35.24 101.52,33.87 v1(101.87,33.87) 103.33,33.87 103.78,33.43 106,33.43 106.01,33.44 106.52,33.44 108.88,35.8 110.24,35.8 111.12,36.68 111.12,37.02 111.45,37.35 112.59,37.35 113.19,37.95 v2(114.82,37.95)
  BOTTOM w0.089: v2(114.82,37.95) 115.16,37.61 CPU1.AK6 ; R1920.1 v2(99.74,35.24)
PROJECT_ID1: length 22.9
  TOP w0.089: v2(115.84,38.57) 115.84,38.16 115.06,37.37 113.76,37.37 113.66,37.47 113.22,37.47 112.75,36.99 111.73,36.99 111.48,36.74 111.48,36.53 110.39,35.44 109.62,35.44 v1(108.1,33.92) 107.26,33.08 106.17,33.08 106.13,33.04 102.89,33.04 102.83,33.11 100.12,33.11 v2(99.21,34.02) 99.21,33.97 R1919.2
  BOTTOM w0.089: v2(99.21,34.02) 98.93,34.02 R1915.1 ; CPU1.AK7 115.54,38.26 v2(115.84,38.57)
PROJECT_ID2: length 22.9
  TOP w0.089: v2(115.84,39.2) 115.39,38.75 115.39,37.95 114.99,37.55 113.86,37.55 113.77,37.65 113.15,37.65 112.67,37.17 111.53,37.17 111.3,36.94 111.3,36.6 110.32,35.62 108.96,35.62 106.59,33.26 106.09,33.26 106.07,33.23 103.37,33.23 103.12,33.49 v1(100.6,33.49) 100.58,33.49 v2(99.87,34.2) 99.61,34.45 98.93,34.45 R1914.2
  BOTTOM w0.089: v2(99.87,34.2) 100.02,34.2 R1918.1 ; CPU1.AK9 115.48,39.57 v2(115.84,39.2)
PROJECT_ID3: length 23.4
  TOP w0.089: v2(115.84,39.84) 115.18,39.17 115.18,38.71 114.84,38.37 114.57,38.37 114.34,38.13 113.12,38.13 112.52,37.53 111.37,37.53 110.94,37.1 110.94,36.75 110.17,35.98 108.81,35.98 106.45,33.62 104.08,33.62 v1(103.4,34.3) 103.07,34.63 101.19,34.63 100.15,35.67 99.56,35.67 v2(99.08,35.19) 98.9,35.37 R1913.2
  BOTTOM w0.089: CPU1.AK10 115.47,40.22 v2(115.84,39.84) ; R1917.1 98.98,35.29 v2(99.08,35.19)
PS175_CEC_EN: length 8.3
  TOP w0.089: U5701.E7 24.33,67.86 24.33,65.68 v1(23.64,64.98) 22.37,63.71 21.61,63.71 21.23,63.33 R5757.2 R5756.2
PS175_CSCL: length 9.6
  TOP w0.089: U5701.E6 24,68.65 23.55,68.2 23.55,68.05 23.25,67.74 23.06,67.74 22.85,67.54 22.85,67.25 23.06,67.04 23.06,66.56 22.88,66.38 21.64,66.38 21.28,66.03 19.76,66.03 19.2,66.59 18.51,66.59 v1(18.31,66.38) 17.67,65.75 R5739.2
PS175_CSDA: length 7.6
  TOP w0.089: U5701.F6 23.2,68.72 22.83,68.35 22.83,68.12 22.47,67.77 22.28,67.77 22.03,67.51 22.03,67.32 21.22,66.51 v1(20.09,66.51) 19.74,66.85 17.69,66.85 R5738.2
PS175_GPIO0: length 7.3
  TOP w0.089: v2(25.19,71) U5701.C4
  BOTTOM w0.089: v2(25.19,71) 25.17,71.03 25.17,71.97 24.28,72.86 23.77,72.86 22.12,74.51 v1(21.46,74.51) R5735.2
PS175_GPIO2: length 5.3
  TOP w0.089: U5701.E3 24.03,71.39 v2(24.4,71.77)
  BOTTOM w0.089: v2(24.4,71.77) 22.85,73.32 v1(21.89,73.32) 21.46,73.75 R5754.2
PS175_PD#: length 14.1
  TOP w0.089: U5701.C3 v2(26,71.79)
  BOTTOM w0.089: v2(26,71.79) 25.42,72.38 25.42,77.3 23.52,79.21 23.52,80.48 22.12,81.88 v1(21.48,81.88) R5736.2
PS175_RST#: length 13.7
  TOP w0.089: U5701.B8 26.4,67.56 26.03,67.93 26.03,69.4 v2(26,69.43) ; v2(24.79,62.19) 24.79,62.5 C5725.2 23.69,62.57 R5737.2 v1(23.69,60.68)
  L3 w0.089: v2(24.79,62.19) 24.79,68.21 v2(26,69.43)
PS_ID: length 309.3
  TOP w0.203: KBC24.36 155.64,24.55 v2(155.75,24.66)
  L3 w0.635: 156.56,25.35 165.36,25.35 166.27,24.45 172.96,24.45 177.06,20.34 183.87,20.34 189.4,14.81 198.64,14.81 199.05,15.22 199.05,15.43 203.97,20.34 209.6,20.34 214.99,25.73 214.99,31.24 218.07,34.31 218.07,35.66 218.52,36.12 218.52,40.51 215.86,43.18 215.86,44.09 214.9,45.04 214.9,48.94 213.04,50.81 213.04,54.47 211.23,56.27 211.23,57.89 212.17,58.83 212.17,61.26 209.57,63.87 209.57,67.78 v2(209.32,68.03)
  L4 w0.254: v2(198.14,77.43) 196.91,78.66 187.54,78.66 185.15,81.04 182.97,81.04 180.62,83.4 177.95,83.4 175.63,81.08 175.63,80.83 175.02,80.22 174.52,80.22 170.62,76.33 167.75,76.33 166.02,78.07 161.63,78.07 160.08,79.62 160.08,85.69 159.35,86.42 158.22,86.42 154.55,90.08 153.88,90.08 152.38,91.58 148.56,91.58 147.59,92.54 145.44,92.54 143.75,90.85 143.75,89.28 141.76,87.3 136.66,87.3 134.53,89.43 126.95,89.43 122,94.38 122,97.13 119.5,99.64 89.89,99.64 88.56,98.31 82.27,98.31 80.3,100.27 76.4,100.27 76,100.67 64.97,100.67 v2(63.62,99.33)
  L6 w0.635: v2(209.32,68.03) 209.32,68.82 208.36,69.77 208.36,70.15 204.07,74.45 201.35,74.45 198.36,77.43 v2(198.14,77.43)
  BOTTOM w0.508: 63.44,98.44 64.16,97.73 64.16,96.23 62.89,94.96 57.53,94.96 v1(57.47,95.01) ; 63.44,98.44 63.62,98.61 v2(63.62,99.33) ; 63.44,98.44 PR4305.2 ; PR4304.2 56.33,95.46 PD4302.3
  BOTTOM w0.635: PD4302.3 56.69,95.79 v1(57.47,95.01)
PS_ID_R: length 8.4
  TOP w0.089: v2(19.58,94.37) 19.78,94.58 AFTP4304.1 EC4311.1 21.31,95.95 PR4317.1
  BOTTOM w0.089: v2(19.58,94.37) 19.58,92.54 18.55,91.52 DCIN1.4
PS_ID_R1: length 3.2
  BOTTOM w0.089: v1(63.27,96.66) PR4306.2 PR4305.1 61.53,97.57 PQ4301.S
PS_ID_R2: length 52.1
  TOP w0.635: v1(24.12,96.86) 23.72,97.27 v2(23.62,97.27) PR4317.2
  L4 w0.635: v2(55.71,100.1) 49.81,94.19 47.61,94.19 45.96,95.85 42.47,95.85 41.83,96.48 39.64,96.48 39.01,97.12 32.15,97.12 30.5,95.46 27.07,95.46 25.27,97.27 v2(23.62,97.27)
  BOTTOM w0.635: PD4303.1 PD4303.2 v2(55.71,100.1) ; PD4303.1 58.31,99.67 PR4309.1 ; PD4303.1 57.92,98.97 58.4,98.48 58.4,96.52 59.13,95.79 PQ4301.D 60.22,95.8 PR4306.1
PSID_DISABLE#_R_C: length 6.4
  BOTTOM w0.356: v1(63.9,100.19) 63.09,100.19 PR4303.2
  BOTTOM w0.508: PQ4302.C 61.05,99.27 62.5,99.27 63.01,99.78 PR4303.2
  BOTTOM w0.635: PQ4301.G 59.27,98.71 60.03,99.47 PQ4302.C
PSYS: length 3.3
  TOP w0.089: PR4614.1 181,59.4 v2(180.87,59.27) 181.12,59.02 181.88,59.02 v1(182.14,59.27)
  BOTTOM w0.089: v2(180.87,59.27) 180.51,59.63 PU4601.1
PTP_DIS#: length 13.2
  TOP w0.089: AFTP6537.1 141.25,11.78 KBC24.90 146.95,11.78 147.21,11.52 v2(147.21,11.26)
  BOTTOM w0.089: TPCON1.3 142.9,9.9 143.58,10.58 146.53,10.58 v2(147.21,11.26)
PURE_HW_SHUTDOWN#: length 144.7
  TOP w0.102: v2(166.52,10.81) 166.52,10.45 165.99,9.92 D4001.3 ; v2(41.68,3.9) 41.68,4.53 v1(42.72,5.57) 43,5.85 C2610.1 43,9.34 Q2602.D
  L3 w0.102: v2(166.52,10.81) 164.79,12.53 159.94,12.53 158.26,14.22 149.76,14.22 149.21,14.77 v2(147.09,14.77) 147.09,14.13 146.65,13.7 144.29,13.7 143.86,13.27 140.51,13.27 139.62,12.38 136.11,12.38 135.76,12.03 134.51,12.03 134.01,12.53 v2(134.01,12.89)
  L4 w0.102: v2(134.01,12.89) 134.01,12.01 132.2,10.2 125.6,10.2 124.66,9.26 110.62,9.26 103.64,2.27 84.7,2.27 83.84,3.14 68.98,3.14 68.24,3.87 64.19,3.87 63.8,3.49 51.8,3.49 v2(51.33,3.01)
  L6 w0.102: v2(51.33,3.01) 50.87,3.47 42.11,3.47 v2(41.68,3.9)
  BOTTOM w0.102: R2615.1 147.3,14.52 147.09,14.72 v2(147.09,14.77)
PWR_0D6V_S3EN: length 4.1
  BOTTOM w0.089: PU5102.7 58.84,13.42 v1(59.51,14.08) 59.79,13.8 PC5120.1 60.4,14.54 PR5125.2 PR5126.2
PWR_0D6V_S5EN: length 3.2
  BOTTOM w0.089: PR5114.2 60.4,12.31 PC5119.1 59.74,13.04 v1(59.56,12.86) 59.11,12.41 PU5102.9
PWR_0D6V_VCNTL: length 3.1
  BOTTOM w0.089: PR5118.1 60.42,11.49 PC5121.1 59.53,11.52 v1(59.51,11.54) 59.14,11.91 PU5102.10
PWR_1D0V_BT: length 3.5
  TOP w0.254: v1(113.05,5.75) 113.71,5.75 PC5204.1 114.17,5.29 115.29,5.29 v2(115.47,5.47)
  BOTTOM w0.254: PU5201.20 115.64,5.3 v2(115.47,5.47)
PWR_1D0V_EN: length 2.5
  BOTTOM w0.089: PR5210.2 117.65,9.05 PC5215.1 117.24,8.65 117.24,8.01 117.38,7.87 PU5201.2
PWR_1D0V_FB: length 4.2
  BOTTOM w0.254: PU5201.5 118.88,7.94 119.02,8.08 119.02,8.51 119.32,8.82 PR5204.1 PR5202.2 ; PC5212.2 119.32,10.1 PR5202.2 ; PR5202.2 120.09,9.61 v1(120.24,9.46)
PWR_1D0V_FB_A: length 24.2
  TOP w0.254: v2(103.37,9.12) 103.37,8.37 103.65,8.09 108.99,8.09 109.49,8.6 109.49,12.79 110,13.3 112.29,13.3 v1(114.06,11.52) 114.57,11.01 117.75,11.01 118.13,10.63 v2(118.13,10.37)
  BOTTOM w0.254: PR5202.1 118.69,9.84 PC5212.1 v2(118.13,10.37) ; v2(103.37,9.12) 103.62,8.88 PG5223.1
PWR_1D0V_PFM: length 2.6
  TOP w0.254: v1(117.62,6.56) 117.62,7.38 PR5203.1 v2(117.7,8.24)
  BOTTOM w0.254: PU5201.3 117.88,7.99 117.87,8 117.87,8.07 v2(117.7,8.24)
PWR_1D0V_PG: length 3.1
  TOP w0.089: PR5209.2 PR5208.2 116.81,8.37 v2(116.68,8.24) 116.66,8.22 v1(115.97,8.22)
  BOTTOM w0.089: v2(116.68,8.24) 116.88,8.04 PU5201.1
PWR_1D0V_PH: length 1.9
  TOP w0.356: v1(113.05,4.53) PC5204.2
  TOP w0.508: PC5204.2 114.83,4.53 114.88,4.48 v2(114.89,4.48)
PWR_1D0V_SS: length 2.4
  BOTTOM w0.254: PC5213.1 115.29,7.58 v1(115.29,7.3) 115.79,6.8 PU5201.22
PWR_1D0V_TON: length 2.6
  TOP w0.254: v1(119.4,6.56) 119.4,7.38 PR5201.2 119.48,8.04 v2(119.65,8.22)
  BOTTOM w0.254: PU5201.6 119.38,7.94 v2(119.65,8.22)
PWR_1D2V:
  vias: v1(18.31,66.13)
PWR_1D05V_EN: length 2.9
  BOTTOM w0.305: PC8302.1 153.73,125.17 PU8301.5
  BOTTOM w0.356: PR8308.2 152.98,124.45 v1(152.78,124.26)
  BOTTOM w0.508: PC8302.1 PR8308.2
PWR_1D05V_FB: length 1.4
  TOP w0.356: v2(156.99,124.56) 156.62,124.93 v1(156.51,124.93)
  TOP w0.508: PC8312.1 157.38,124.17 v2(156.99,124.56)
PWR_1D05V_FB_R: length 1.7
  TOP w0.089: PR8313.1 PC8312.2 158.34,124.29 v1(158.34,125.06)
PWR_1D05V_PGOOD: length 3.3
  TOP w0.089: PR8320.1 PR8304.2 153.21,124.01 v2(152.78,123.58) 152.67,123.48 v1(152.67,123.02)
  BOTTOM w0.089: v2(152.78,123.58) 152.83,123.52 PU8301.4
PWR_1D05V_PHASE:
  vias: v1(152.47,122.72)
PWR_1D05V_PVDD:
  vias: v1(159.84,121.91)
PWR_1D05V_SVIN: length 2.9
  BOTTOM w0.305: PU8301.8 157.45,123.02 157.5,123.07
  BOTTOM w0.508: PC8301.1 v1(158.52,123.15) 158.44,123.07 PR8301.2 157.5,123.07
PWR_1D8V_EN: length 4.8
  BOTTOM w0.089: v1(35.58,3.9) 35.45,3.77 PC5406.1 35.48,3.06 PR5401.1 PR5406.2 37.1,3.19 37.1,4.41 36.72,4.79 PU5401.8
PWR_1D8V_POK: length 3.5
  BOTTOM w0.089: 38.63,3.09 38.27,3.44 PR5408.2 ; 38.63,3.09 v1(38.63,3.9) 37.99,4.53 PU5401.7 ; 38.63,3.09 PR5402.2
PWR_1D35V_BOOT: length 3.8
  BOTTOM w0.254: 194.7,81.85 194.57,81.85 PU8302.1
  BOTTOM w0.508: v1(197,81.85) PR8324.1 194.7,81.85
PWR_1D35V_BOOT_R: length 2.3
  BOTTOM w0.508: PC8319.1 195.83,83.15 PR8324.2 v1(195.85,84.29)
PWR_1D35V_BYP: length 3.6
  BOTTOM w0.254: PU8302.15 189.57,80.87 PC8318.1 ; PR8325.1 189.17,80.96 PC8318.1 ; PC8318.1 189.5,81.29 v1(189.5,82)
PWR_1D35V_EN: length 4
  BOTTOM w0.089: PU8302.11 190.01,78.08 v1(190.01,77.25) 190.14,77.13 PR8322.2 190.11,76.36 PC8316.1
PWR_1D35V_IMAX: length 5.1
  BOTTOM w0.254: PR8323.2 189,76.72 v1(189,78.07) 189,78.7 190.25,79.96 190.25,79.97 PU8302.13
PWR_1D35V_LDO_P5:
  vias: v1(191.61,82.36)
PWR_1D35V_PGOOD:
  vias: v1(191.28,77.24)
PWR_1D35V_PHASE: length 9
  L3 w1.016: v3(193.31,77.43) 193.31,84.86 v3(193.15,85.03)
  BOTTOM w0.254: PU8302.6 193.2,77.55 v3(193.31,77.43)
  vias: v1(192.81,82.76)
PWR_1D35V_VFB: length 5
  BOTTOM w0.254: PR8326.1 v1(188.87,79.46) 189.18,79.46 190.14,80.42 PU8302.14
  BOTTOM w0.508: PR8326.1 187.93,79.44 PC8308.2 187.93,77.96 PR8327.2
PWR_1D35V_VFB1: length 22.1
  L3 w0.508: v2(187.85,76.49) 188.49,77.13 188.49,81.11 188.11,81.49 188.11,88.73 189,89.62 189,93.05 188.36,93.69 v2(187.98,93.69)
  BOTTOM w0.508: PC8308.1 187.01,77.96 PR8327.1 187.04,76.9 v1(187.05,76.88) 187.45,76.49 v2(187.85,76.49) ; PG8313.2 v2(187.98,93.69)
PWR_2D5V:
  vias: v1(46.71,15.1)
PWR_2D5V_EN: length 5.4
  BOTTOM w0.089: PR5417.2 43.5,2.32 v1(43.33,2.5) 42.77,3.06 PR5409.1 42.41,3.09 PC5427.1 42.14,3.55 42.14,4.07 42.18,4.12 PU5403.8
PWR_2D5V_FB: length 4.3
  BOTTOM w0.254: PR5420.1 43.61,14.21 v1(43.61,13.3) 43.71,13.19 43.71,12.36 PR5419.2 43.78,11.54 PC5411.2 43.45,11.21 PU5403.2
PWR_2D5V_PG: length 141.8
  TOP w0.089: v2(62.12,9.06) 63.01,9.95 v2(63.01,11.64) 64.28,12.91 64.28,15.15 62.1,17.33 v1(61.89,17.33) 56.05,17.33 55.8,17.58 55.8,17.58 53.64,19.74 51.7,19.74 50.25,18.29 48.34,18.29 48.24,18.2 46.83,18.2 v2(46.38,17.74)
  L4 w0.089: v2(46.38,17.74) 47.29,17.74 48.16,18.61 48.16,37.91 44.66,41.4 44.66,47.92 45.53,48.79 45.53,61.75 44.53,62.75 44.53,68.22 44.62,68.3 45.22,68.91 45.22,87.85 v2(41.04,92.04) ; v2(43.84,3.9) 44.43,3.31 45.4,3.31 45.87,3.77 45.87,6.69 47.52,8.34 61.36,8.34 62.08,9.06 v2(62.12,9.06)
  BOTTOM w0.089: PR5410.2 44.17,3.57 v2(43.84,3.9) 43.84,4.41 43.45,4.79 PU5403.7 ; v2(63.01,11.64) 62.38,12.28 PR5114.1 ; v2(41.04,92.04) 41.72,92.72 44.11,92.72 46.38,94.98 PG5112.1
PWR_3D3V:
  vias: v1(190.39,47.33)
PWR_3D3V_BOOT: length 5.5
  BOTTOM w0.254: PU4501.1 188.47,55.08 187.92,55.08 ; v1(185.39,55.54) 185.39,55.41 PR4501.1
  BOTTOM w0.508: 187.92,55.08 186.68,55.08 PR4501.1
PWR_3D3V_BOOT_A: length 2.2
  BOTTOM w0.508: v1(185.06,53.28) PR4501.2 187.14,53.28 PC4506.1
PWR_3D3V_EN: length 5.7
  BOTTOM w0.089: PU4501.11 192.32,58.38 192.76,58.81 193.36,58.81 194,59.45 PC4508.1 194,60.26 PR4508.1 194.03,60.59 v1(194.86,61.43) 194.89,61.45 PR4509.2
PWR_3D3V_EN1: length 4.6
  TOP w0.089: v1(193.7,58.76) 193.57,58.76 v2(193.19,58.38) 193.19,58.25 192.93,58 PR4514.1 PR4516.2
  BOTTOM w0.089: PC4532.1 193.62,58.38 v2(193.19,58.38) 193.19,58.17 192.7,57.69 PU4501.12
PWR_3D3V_FB: length 2
  BOTTOM w0.254: PU4501.13 v1(193.42,57.24) 194,57.24 PC4533.1
PWR_3D3V_FB2: length 1.8
  BOTTOM w0.254: PR4506.2 195.14,56.96 PC4533.2 195.09,57.06 195.09,57.7 v1(194.91,57.87)
PWR_3D3V_LDO: length 0.6
  TOP w0.254: v2(192.55,55.33) 192.88,55 v1(192.88,54.82)
PWR_3D3V_PH: length 9.8
  TOP w0.254: v1(189.61,59.93) 189.71,59.93 v3(190.13,59.51)
  L6 w0.762: v3(190.13,59.51) 188.74,58.13 v3(188.74,53.55)
  BOTTOM w0.254: PU4501.6 v3(190.13,59.51)
  BOTTOM w0.508: PC4506.2 188.82,54.27
PWR_3D3V_VOUT: length 17.2
  TOP w0.254: v2(195.55,44.51) 195.27,44.23 v1(195.27,43.98)
  L4 w0.254: v2(193.31,56.6) 193.31,46.21 194.99,44.54 195.52,44.54 v2(195.55,44.51)
  BOTTOM w0.254: PU4501.14 193.13,56.79 v2(193.31,56.6) 193.7,56.22 PR4506.1 ; PG4530.1 195.32,44.28 v2(195.55,44.51)
PWR_3V_PG:
  vias: v1(192.6,59.32)
PWR_5V:
  vias: v1(198.14,56.86) v1(199.54,53.81) v3(198.9,58.63) v3(199.54,57.87) v3(199.54,57.03) v3(199.54,56.2) v3(199.54,55.33) v3(199.92,58.63)
PWR_5V_BOOT: length 2.7
  BOTTOM w0.254: v1(194.68,67.94) 194.68,68.89 194.81,69.02 194.81,69.29 PU4502.1
  BOTTOM w0.305: v1(194.68,67.94) 194.08,67.34 PR4502.1
PWR_5V_BOOT_A: length 2.8
  BOTTOM w0.508: PC4521.1 194.79,64.35 v1(194.25,64.35) 193.9,64.71 193.9,65.42 PR4502.2
PWR_5V_EN: length 4
  TOP w0.254: PR4511.2 PR4512.1 198.27,72.17 198.17,72.27 PC4530.1 197.76,71.84 v2(197.63,71.72) v1(196.49,71.72)
  BOTTOM w0.254: PU4502.11 197.4,71.49 v2(197.63,71.72)
PWR_5V_EN1: length 5
  TOP w0.089: v1(199.41,69.3) 199.26,69.45 199.26,70.47 PC4531.1 ; PC4531.1 199.31,70.52 PR4513.1 PR4504.2 ; PC4531.1 198.72,70.5 v2(198.27,70.95)
  BOTTOM w0.089: PU4502.12 197.96,70.64 v2(198.27,70.95)
PWR_5V_EN1_R: length 29.2
  TOP w0.089: PR4530.1 PR4503.2 192.43,60.36 192.73,60.67 192.73,60.97 192.98,61.23 PR4515.2 193.47,61.51 v2(194.05,61.51) ; v1(200.55,72.73) 200.55,72.48 v2(200.81,72.22) PR4504.1
  L6 w0.089: v2(200.81,72.22) 200.81,71.87 204.7,67.98 204.7,61.77 202.31,59.37 197.28,59.37 195.14,61.51 v2(194.05,61.51)
PWR_5V_FB: length 6.1
  BOTTOM w0.254: v1(199.31,74.64) 199.79,74.15 PR4551.1 199.33,72.81 PC4526.1 199.33,71.27 198.39,70.33 198.39,70.32 198.27,70.19 PU4502.13
PWR_5V_FB_A: length 2
  BOTTOM w0.254: PC4526.2 200.65,71.67 PR4507.1 200.3,70.75 v1(199.99,70.75)
PWR_5V_LDO:
  vias: v1(198.65,68.29)
PWR_5V_PG:
  vias: v1(198.7,72.88)
PWR_5V_PH: length 7.9
  TOP w0.356: v1(196.37,66.12) 196.24,66.12 v3(195.73,66.64)
  L6 w0.762: v3(195.73,66.64) 195.22,67.14 v3(195.22,72.47)
  BOTTOM w0.254: PU4502.6 195.21,71.81 195.22,71.82 v3(195.22,72.47)
PWR_5V_VCC: length 3.8
  TOP w0.254: PC4524.1 197.12,68.16 v2(196.87,67.91) 196.9,67.88 v1(196.9,67.22)
  BOTTOM w0.254: PU4502.17 196.56,68.22 v2(196.87,67.91) 197.01,68.04 PU4502.16
PWR_5V_VOUT: length 25.8
  BOTTOM w0.254: PG4527.1 203.98,52.16 204.49,52.67 204.49,59.14 203.98,59.65 v1(203.98,65.49) 203.98,66.38 202.84,67.52 202.84,69.05 202.2,69.68 201.77,69.68 PR4507.2 200.73,70.32 198.92,70.32 198.78,70.17 198.78,70.16 198.36,69.74 PU4502.14
PWR_CHG_ACIN: length 15.3
  BOTTOM w0.203: PU4401.19 202.71,30.15
  BOTTOM w0.254: 202.71,30.15 203.61,30.15 204.57,29.2 205.46,29.2 v1(205.48,29.17) 205.84,29.53 206.79,29.53 207.12,29.86 PC4420.2 207.56,30.01 PR4406.1 209.37,31.2 210.39,31.2 210.4,31.22 210.83,31.22 210.84,31.2 212.28,31.2 212.41,31.33 213.31,31.33 214.27,30.37 214.27,29.6 PR4404.2
PWR_CHG_ACOK: length 62.8
  TOP w0.089: v2(195.6,60.41) 196.31,61.12 v1(196.31,62.09) 196.84,62.62 196.84,66.53 195.9,67.47 PR4463.2
  L4 w0.089: v2(207.54,42.37) 207.54,45.05 207.16,45.43 206.27,45.43 205.9,45.79 205.9,47.6 208.11,49.81 208.11,50.97 208.85,51.71 208.85,53.05 208.22,53.68 208.22,55.16 207.52,55.86 206.14,55.86 205,57 205,58.76 204.46,59.3 197.35,59.3 196.24,60.41 v2(195.6,60.41)
  L6 w0.089: v2(206.4,28.79) 206.4,35.9 208.1,37.61 208.1,41.81 207.55,42.37 v2(207.54,42.37)
  BOTTOM w0.089: v2(206.4,28.79) 206.32,28.71 205.03,28.71 204.92,28.61 204.92,28.26 PG4408.1 204.82,27.39 PR4429.2 PR4426.1 204.24,26.96 204.24,27.65 203.86,28.03 202.48,28.03 202.36,28.15 PU4401.24
PWR_CHG_AIN: length 1.2
  BOTTOM w0.254: PD4408.3 213.57,27.39 213.89,27.72 PR4404.1
PWR_CHG_AMON: length 6
  BOTTOM w0.203: PU4401.29 199.85,27.01
  BOTTOM w0.254: 199.85,27.01 199.85,26.05 198.98,25.18 198.6,25.18 v1(197.57,24.15) 196.74,23.33 PR4412.1
PWR_CHG_ASGATE: length 2
  TOP w0.254: TP4401.1 200.55,32.6 v2(200.43,32.47)
  BOTTOM w0.203: PU4401.13 200.24,32.29 v2(200.43,32.47)
PWR_CHG_BATGONE: length 5.1
  BOTTOM w0.203: 201.7,27.01 201.45,27.26 PU4401.25
  BOTTOM w0.254: PC4430.1 200.53,23.91 PR4409.1 v1(201.32,24.65) 201.7,25.03 201.7,27.01
PWR_CHG_BGATE: length 28.1
  L3 w0.254: v2(175.61,24.12) 175.7,24.12 175.72,24.09 177.44,24.09 180.11,26.76 191.41,26.76 192.17,27.52 194.21,27.52 194.84,26.89 v2(197.76,26.89)
  BOTTOM w0.203: 197.77,26.89 198.47,27.59 PU4401.32
  BOTTOM w0.254: PU4412.4 176,25.4 v1(176.55,24.85) 176.55,24.14 PC4429.1 175.79,23.94 v2(175.61,24.12) ; v2(197.76,26.89) 197.77,26.89
PWR_CHG_BOOT1: length 3.7
  BOTTOM w0.203: PU4401.12 199.85,32.65 200.05,32.85 v1(200.05,33.36) 200.05,33.51
  BOTTOM w0.508: PR4402.2 199.16,34.5 200.05,33.62 200.05,33.51
PWR_CHG_BOOT2: length 3.2
  BOTTOM w0.203: 196.44,28.79 197,29.35 PU4401.4
  BOTTOM w0.508: 196.44,28.79 196.01,28.79 PR4408.2
PWR_CHG_BT1_R: length 2.3
  BOTTOM w0.508: PR4402.1 PC4436.2 v1(197.89,37.08)
PWR_CHG_BT2_R: length 2.3
  BOTTOM w0.508: v1(192.98,29.42) PR4408.1 PC4423.1
PWR_CHG_COMP: length 6.2
  BOTTOM w0.203: PU4401.28 200.24,27.01
  BOTTOM w0.254: PR4411.1 198.24,23.13 PC4433.1 198.27,24.02 198.93,24.68 199.18,24.68 v1(199.41,24.9) 200.24,25.74 200.24,27.01
PWR_CHG_COMP_R: length 1.8
  BOTTOM w0.254: PR4411.2 197.51,21.5 PC4431.1 v1(197.43,20.53)
PWR_CHG_CSIN: length 6.2
  BOTTOM w0.203: PU4401.14 200.65,31.98 200.93,32.26 200.93,32.98
  BOTTOM w0.254: PR4423.2 200.45,35.85 PC4417.2 200.43,34.99 PC4415.1 201.32,34.1 v1(201.32,33.36) 200.93,32.98
PWR_CHG_CSIN_R: length 11.8
  BOTTOM w0.254: PR4423.1 201.57,37.27 200.78,38.06 196.54,38.06 v1(196.49,38.01) 196.44,38.06 193.79,38.06 193.06,38.79 193.06,39.46 192.73,39.79 PG4402.2
PWR_CHG_CSIP: length 7.4
  BOTTOM w0.203: 201.32,32.73 201.32,32.18 201.05,31.91 PU4401.15
  BOTTOM w0.254: PR4422.2 202.74,35.85 PC4416.2 203.47,34.16 v1(203.35,34.03) 202.7,34.03 PC4415.2 202.23,34.2 202.2,34.17 202.2,33.62 201.32,32.73
PWR_CHG_CSIP_R: length 11.9
  BOTTOM w0.254: PG4401.2 193.77,39.79 193.44,39.46 193.44,38.95 193.95,38.44 201.06,38.44 v1(201.57,37.93) 202.33,37.17 PR4422.1
PWR_CHG_CSON: length 5.7
  BOTTOM w0.203: PU4401.1 197.88,28.15 197.63,27.9
  BOTTOM w0.254: 197.63,27.9 197.63,27.49 PC4425.2 196.78,26.57 v1(196.78,25.58) 196.44,25.23 PC4426.2 195.27,25.72 PR4425.2
PWR_CHG_CSON_R: length 17.2
  L3 w0.254: v2(192.43,27.01) 191.54,26.12 181.88,26.12 v2(179.6,23.84)
  BOTTOM w0.254: v2(192.43,27.01) v1(193.06,26.38) 193.19,26.25 PR4425.1 ; PG4406.2 v2(179.6,23.84)
PWR_CHG_CSOP: length 4.1
  BOTTOM w0.203: 197.02,27.93 197.65,28.55 PU4401.2
  BOTTOM w0.254: 197.02,27.93 PC4425.1 195.47,27.93 PC4424.2 195.37,27.11 PR4424.2
PWR_CHG_CSOP_R: length 16.1
  TOP w0.254: v2(193.31,27.01) 193.54,26.78 v1(193.54,26.43)
  L3 w0.254: v2(181.38,23.84) 181.38,24.47 182.52,25.61 191.92,25.61 v2(193.31,27.01)
  BOTTOM w0.254: PR4424.1 v2(193.31,27.01) ; PG4405.2 v2(181.38,23.84)
PWR_CHG_DCIN: length 3
  BOTTOM w0.203: 202.6,31.19 202.36,30.95 PU4401.17
  BOTTOM w0.254: 202.6,31.19 PC4419.1 203.25,31.84 PR4403.1
PWR_CHG_DCIN_R: length 6.5
  BOTTOM w0.254: PD4401.3 209.78,32.26 PD4407.K 208.85,32.18 208.68,32.35 v1(207.64,32.35) 206.85,32.35 PR4403.2
PWR_CHG_HG1_R: length 4.2
  TOP w0.356: v3(180.57,43.61) 180.37,43.61 v1(179.7,42.94)
  TOP w1.016: v3(180.57,43.61) 182.36,43.61 PR4414.1
  BOTTOM w0.406: PU4403.4 v3(180.57,43.61)
PWR_CHG_HG2_R: length 3.9
  TOP w0.356: v3(180.61,32.18) 180.29,32.5 v1(179.75,32.5)
  TOP w1.016: v3(180.61,32.18) 181.98,32.18 PR4420.2
  BOTTOM w0.406: PU4405.4 v3(180.61,32.18)
PWR_CHG_LGATE1: length 19.9
  TOP w0.356: v1(183.84,37.07) 184.4,37.07 v3(184.53,36.93)
  L6 w0.762: v3(198.01,32.35) 197.51,32.85 197.51,33.62 192.68,38.44 186,38.44 184.58,37.02 184.58,36.98 v3(184.53,36.93)
  BOTTOM w0.203: v3(198.01,32.35) 198.65,31.71 PU4401.9
  BOTTOM w0.406: PU4404.4 v3(184.53,36.93)
PWR_CHG_LGATE2: length 16
  TOP w0.356: v1(184.78,34) 185.4,34 v3(185.44,34.04)
  L6 w0.762: v3(185.44,34.04) 185.53,34.12 194.46,34.12 v3(196.87,31.71)
  BOTTOM w0.203: v3(196.87,31.71) 196.9,31.71 197.45,31.15 197.45,30.77 197.67,30.55 PU4401.7
  BOTTOM w0.406: PU4406.4 v3(185.44,34.04)
PWR_CHG_OTGEN: length 3.2
  TOP w0.254: PR4417.2 203.2,29.81 v2(203.52,29.49) 203.88,29.86 v1(204.03,29.86)
  BOTTOM w0.203: 202.71,29.75 PU4401.20
  BOTTOM w0.254: v2(203.52,29.49) 203.26,29.75 202.71,29.75
PWR_CHG_OTGPG: length 2.5
  TOP w0.254: v2(201.19,26.38) 201.06,26.5 TP8304.1
  BOTTOM w0.203: 201.05,27.01 PU4401.26
  BOTTOM w0.254: 201.05,27.01 201.05,26.52 v2(201.19,26.38)
PWR_CHG_PHASE1: length 28.7
  TOP w0.356: v3(180.51,42.38) 180.87,42.38 v1(181.15,42.66)
  TOP w0.762: PR4416.1 179.9,41.79 180.49,42.38 v3(180.51,42.38)
  L6 w0.762: v3(180.51,42.38) 184.3,42.38 185.44,41.24 192.3,41.24 198.52,35.01 v3(198.52,33.62)
  BOTTOM w0.203: PU4401.10 199.05,32.2 198.52,32.73 v3(198.52,33.62)
  BOTTOM w0.508: v3(198.52,33.62) 197.89,34.25 PC4436.1
PWR_CHG_PHASE2: length 20.3
  L6 w0.762: v3(196.87,30.57) 191.66,30.57 189.5,32.73 181.5,32.73 181,33.23 v3(180.61,33.23)
  BOTTOM w0.203: v3(196.87,30.57) 197.29,30.15 PU4401.6
  BOTTOM w0.508: v3(196.87,30.57) 196.7,30.57 196.57,30.69 PC4423.2
  vias: v1(179.85,30.06)
PWR_CHG_PROCHOT#: length 131.2
  TOP w0.089: v1(204.64,28.79) v2(204.03,28.79)
  L4 w0.127: v2(204.03,28.79) 204.03,30.63 204.05,30.64 204.05,33.23 203.6,33.68 203.6,37.43 204.74,38.57 204.74,39.46 206.27,40.98 207.54,40.98 208.94,42.38 208.94,46.57 209.32,46.95 209.32,48.4 209.09,48.62 209.09,50.35 v2(208.81,50.63) ; v2(140.23,74.49) 140.25,74.51 140.48,74.51 141.4,75.43 143.66,75.43 144.95,74.14 148.37,74.14 148.83,73.68 149.61,73.68 149.81,73.89 152.67,73.89 152.82,74.04 161.12,74.04 161.89,73.27 165.04,73.27 167.44,70.86 173.41,70.86 174.05,70.23 175.67,70.23 177.03,71.59 182.28,71.59 183.36,72.67 186.13,72.67 186.54,72.26 192.76,72.26 193.72,71.31 196.34,71.31 197.25,72.22 198.46,72.22 200.55,70.13 202.52,70.13 206.4,66.25 v2(208.68,66.25)
  L6 w0.102: v2(208.68,66.25) 209.19,65.75 209.19,64.48 208.68,63.97 208.68,60.19 207.63,59.14 206.42,59.14 205.96,58.69 205.96,58.63 205.89,58.55 205.89,57.01 206.77,56.13 209.92,56.13 210.41,55.63 210.41,52.07 208.98,50.63 v2(208.81,50.63)
  BOTTOM w0.089: v2(204.03,28.79) 203.54,28.3 202.59,28.3 202.34,28.55 PU4401.23 ; PQ4416.2 139.21,75.55 139.73,75.03 139.73,74.99 v2(140.23,74.49) 140.86,75.12 PR4435.2
PWR_CHG_PROCHOT#_R: length 5.8
  BOTTOM w0.254: PQ4416.5 139.21,79.84 139.34,79.97 139.74,79.97 139.86,79.84 PQ4416.6 139.86,78.75 140.12,78.5 PR4472.2 v1(140.86,79.41) 140.86,80.23 PQ4402.G
PWR_CHG_PROG: length 4.9
  BOTTOM w0.203: PU4401.27 200.65,27.01
  BOTTOM w0.254: PR4410.2 199.78,24.64 200.36,24.64 200.83,25.11 v1(200.83,25.92) 200.65,26.11 200.65,27.01
PWR_CHG_SNB: length 2.5
  TOP w0.254: v1(183.99,41.19) PC4435.1 181.91,41.19 PR4416.2
PWR_CHG_UGATE1: length 23.5
  TOP w0.356: v3(185.69,43.14) 185.85,42.99 v1(185.85,42.3)
  TOP w1.016: PR4414.2 185.44,43.39 v3(185.69,43.14)
  L6 w0.762: v3(185.69,43.14) 186.58,42.25 192.81,42.25 199.54,35.52 199.54,33.2 v3(199.43,33.1)
  BOTTOM w0.203: PU4401.11 199.45,33.09 v3(199.43,33.1)
PWR_CHG_UGATE2: length 15.8
  TOP w0.356: v3(185.57,31.71) 185.59,31.74 v1(185.59,32.52)
  TOP w1.016: PR4420.1 v3(185.57,31.71)
  L6 w0.762: v3(185.57,31.71) 189.08,31.71 191.24,29.55 v3(196.36,29.55)
  BOTTOM w0.203: v3(196.36,29.55) 196.56,29.75 PU4401.5
PWR_CHG_VBAT1: length 9.2
  BOTTOM w0.203: PU4401.31 199.05,26.84
  BOTTOM w0.381: 199.05,26.84 198.48,26.27 198.46,26.27 v1(197.99,25.79) 197.88,25.69 197.88,25.67 196.43,24.22 196.09,24.22 195.42,23.54 193.95,23.54 193.78,23.72 193.74,23.72 PR4478.1
  BOTTOM w0.508: PC4440.2 193.39,24.07 PR4478.1
PWR_CHG_VBATIN:
  vias: v1(176.55,26.38)
PWR_CHG_VDDP: length 5.1
  BOTTOM w0.203: PU4401.8 198.09,31.38
  BOTTOM w0.254: 198.09,31.38 197.4,32.07 197.4,32.35 197.02,32.73 v1(196.82,32.73) 196.79,32.75 196.41,32.75 PC4421.1 195.4,32.19 PR4405.1
PWR_DCBATOUT_1D0V: length 1.8
  TOP w0.356: v1(120.62,6.56) 120.62,7.17 PR5201.1
  TOP w0.508: v2(120.42,8.22) 120.42,7.53 PR5201.1
PWR_DCBATOUT_1D35V:
  vias: v1(194.2,77.05)
PWR_DCBATOUT_3D3V:
  vias: v1(189.63,60.03)
PWR_DCBATOUT_5V:
  vias: v1(187.22,69.68)
PWR_DCBATOUT_VCCGTA:
  vias: v1(165.75,39.89)
PWR_DCBATOUT_VCCGTB:
  vias: v1(165.09,48.08)
PWR_DCBATOUT_VCCSA:
  vias: v1(164.82,34.41)
PWR_DCBATOUT_VCORE:
  vias: v1(157.88,53.94) v1(165.25,53.94) v3(164.99,52.92) v3(165.88,52.92)
PWR_DCBATOUT_VDDQ:
  vias: v1(46.73,102.7)
PWR_VCCGT_BOOTA: length 4
  BOTTOM w0.203: PU4801.7 163.27,38.64 163.85,38.06
  BOTTOM w0.508: 163.85,38.06 164.29,38.06 164.92,37.43 PR4804.2 165.12,37.4 v1(165.12,36.28)
PWR_VCCGT_BOOTA_RC: length 2.5
  BOTTOM w0.508: PC4808.1 PR4804.1 166.52,37.32 v1(166.52,36.28)
PWR_VCCGT_BOOTB: length 2.9
  BOTTOM w0.203: v1(163.72,46.06) 163.56,46.23 163.56,46.66 163.32,46.89 PU4802.7
  BOTTOM w0.508: PR4810.2 164.66,45.55 164.15,46.06 v1(163.72,46.06)
PWR_VCCGT_BOOTB_RC: length 2.6
  BOTTOM w0.254: PR4810.1 166.87,44.84 v1(167.15,44.84)
  BOTTOM w0.508: PC4811.1 PR4810.1
PWR_VCCGT_BOOTRA: length 2.5
  BOTTOM w0.203: 163.85,38.95 163.76,39.04 PU4801.6
  BOTTOM w0.508: 163.85,38.95 v1(163.98,38.95) 164.84,38.95 PC4808.2
PWR_VCCGT_BOOTRB: length 2.3
  BOTTOM w0.203: 164.23,47.08 164.02,47.29 v1(163.72,47.29) 163.62,47.29 163.1,47.29 163.09,47.29 162.97,47.29 PU4802.6
  BOTTOM w0.508: PC4811.2 164.49,46.82 164.23,47.08
PWR_VCCGT_COMP: length 5.6
  TOP w0.254: PC4610.2 180.36,57.85 v2(180.66,58.15) 180.69,58.13 v1(181.5,58.13)
  BOTTOM w0.203: 179.31,59.42 PU4601.4
  BOTTOM w0.254: PR4626.2 181.81,58.15 v2(180.66,58.15) 179.95,58.15 179.31,58.8 179.31,59.42
PWR_VCCGT_COMP1: length 3.6
  BOTTOM w0.254: v1(184.14,55.56) 183.87,55.84 PC4612.1 PC4651.1 183.15,57.24 182.7,57.7 PR4626.1
PWR_VCCGT_FB: length 5.3
  BOTTOM w0.203: PU4601.5 178.91,59.35
  BOTTOM w0.254: PR4630.2 PR4636.2 PR4633.2 PR4671.2 179.13,57.88 v1(179.13,58.25) 178.91,58.48 178.91,59.35
PWR_VCCGT_FB1: length 2.1
  BOTTOM w0.254: PR4630.1 182.87,56.48 v1(182.9,56.45) 182.9,55.92 PC4614.1
PWR_VCCGT_FB2: length 7.3
  BOTTOM w0.254: PR4671.1 PR4633.1 180.49,56.43 PC4619.1 180.51,55.66 PC4618.2 180.74,54.42 PR4665.2 PC4615.2 183.28,53.86 PR4631.1 184.07,53.99 v1(184.35,54.27)
PWR_VCCGT_FB_RC: length 1.9
  BOTTOM w0.254: PC4618.1 181.43,55.43 v1(181.3,55.56) 181.2,55.66 PR4636.1
PWR_VCCGT_FCCM#: length 46.9
  TOP w0.254: v1(161.89,36.21) 161.89,36.74 v2(161.95,36.79)
  L3 w0.254: v2(160.88,44.92) 159.91,44.92 159.41,44.41 159.41,38.49 159.9,38 160.18,37.72 160.26,37.64 PR4806.2 v2(161.95,36.79) 163.6,36.79 166.14,39.33 166.14,40.38 173.63,47.87 173.63,50.09 176.93,53.4 176.93,57.64 v2(174.54,60.03)
  BOTTOM w0.254: PR4806.2 v2(161.95,36.79) ; PR4812.2 160.55,45.17 160.8,44.92 v2(160.88,44.92) ; PU4601.11 176.32,60.18 176.04,59.9 174.67,59.9 v2(174.54,60.03)
PWR_VCCGT_FCCM#_RA: length 2.8
  BOTTOM w0.203: PU4801.1 159.39,37.63
  BOTTOM w0.254: 159.39,37.63 159,37.23 v1(159,36.84) 159.05,36.79 PR4806.1
PWR_VCCGT_FCCM#_RB: length 2.5
  BOTTOM w0.203: PU4802.1 159.39,45.21 PR4812.1
  BOTTOM w0.254: v1(158.47,44.54) 158.72,44.54 PR4812.1
PWR_VCCGT_IMON: length 3.7
  TOP w0.254: v1(180.44,58.79) 180.22,59.01 v2(180.22,59.31) 180.23,59.32 PR4608.2 180.16,60.18 PC4604.2 PR4672.2
  BOTTOM w0.203: PU4601.2 180.11,59.42 v2(180.22,59.31)
PWR_VCCGT_ISEN1: length 13.2
  TOP w0.203: v2(173.12,53.94) 173.07,53.89 v1(172.49,53.89)
  L3 w0.203: v2(173.12,53.94) 173.63,54.44 173.63,56.73 174.14,57.24 v2(174.65,57.24)
  BOTTOM w0.203: PC4625.1 174.01,54.11 PR4824.2 v2(173.12,53.94) 172.99,53.81 PR4821.1 ; v2(174.65,57.24) 174.65,57.67 PR4669.2 174.14,58.18 174.14,58.96 174.35,59.17 176.82,59.17 177.31,59.66 PU4601.9
PWR_VCCGT_ISEN2: length 9.7
  BOTTOM w0.203: v1(170.45,55.51) PR4635.2 172.11,55.51 PR4822.2 172.16,55.61 PR4823.1 172.23,56.35 172.99,57.11 PC4626.1 173.58,57.64 PR4669.1 173.81,58.1 173.81,59.09 174.22,59.5 176.65,59.5 176.91,59.76 PU4601.10
PWR_VCCGT_ISUMN: length 36.3
  TOP w0.203: v2(157.04,45.3) 157.22,45.12 v1(157.22,44.66)
  L3 w0.203: v2(157.04,45.3) 157.42,45.68 159.2,45.68 159.56,46.04 162.24,46.04 162.64,46.44 166.39,46.44 166.74,46.8 169.29,46.8 169.95,47.46 169.95,50.25 170.58,50.89 172.48,50.89 174.26,52.67 174.26,56.09 v2(174.65,56.48)
  BOTTOM w0.203: PR4809.2 174.52,56.35 v2(174.65,56.48) ; PR4809.2 173.96,56.37 PC4626.2 ; PR4809.2 173.93,55.74 PC4625.2 174.75,55.66 PR4815.2 175.51,55.64 PC4633.1 ; PR4647.1 175.69,55.51 PC4633.1 ; PC4633.1 175.41,55.79 PR4645.2 PR4642.2 PR4670.2 177.54,56.93 PC4630.2 177.64,56.83 PR4643.2 ; PR4646.2 v2(157.04,45.3)
PWR_VCCGT_ISUMN_GA: length 41.7
  TOP w0.203: v2(154.07,41.62) 153.72,41.97 v1(153.72,42.23)
  L3 w0.203: v2(154.07,41.62) 154.07,42.02 154.26,42.21 154.26,45.38 152.99,46.66 152.99,50.42 153.75,51.18 153.75,53.82 155.53,55.6 162.13,55.6 162.83,56.31 162.83,57.24 164.49,58.89 171.47,58.89 172.61,57.75 172.61,55.31 v2(173.04,54.88)
  BOTTOM w0.203: v2(154.07,41.62) 153.49,41.03 PG4809.1 ; PR4809.1 173.07,55.61 PR4822.1 v2(173.04,54.88)
PWR_VCCGT_ISUMN_GB: length 29.8
  TOP w0.254: v2(153.94,49.49) 153.84,49.39 v1(153.84,48.91)
  L3 w0.254: v2(173.12,53.17) 172.56,53.17 171.6,54.14 171.6,55.52 171.09,56.03 164.8,56.03 163.34,54.57 156.61,54.57 154.71,52.67 154.71,50.34 154.07,49.7 154.07,49.62 v2(153.94,49.49)
  BOTTOM w0.254: PR4815.1 174.77,54.01 PR4824.1 174.7,53.86 174.01,53.17 v2(173.12,53.17) ; PG4815.1 153.49,49.03 v2(153.94,49.49)
PWR_VCCGT_ISUMN_P_1: length 3.3
  BOTTOM w0.254: v1(175.99,53.78) 176.3,54.09 PR4647.2 176.45,54.49 PC4653.2 PC4609.2 PC4628.2
PWR_VCCGT_ISUMN_P_2: length 21.8
  TOP w0.254: v2(156.18,45.25) 156,45.07 v1(156,44.69)
  L4 w0.254: v2(156.18,45.25) 156.27,45.25 156.83,45.81 162,45.81 162.56,46.37 168.98,46.37 169.44,46.82 169.44,51.14 169.82,51.52 v2(170.84,51.52)
  BOTTOM w0.254: PR4641.2 v2(170.84,51.52) ; PR4646.1 v2(156.18,45.25)
PWR_VCCGT_ISUMN_RC: length 1.7
  BOTTOM w0.254: v1(174.54,58.76) 175.2,58.76 PC4623.1 175.33,57.87 PR4645.1
PWR_VCCGT_ISUMNB: length 4.2
  BOTTOM w0.203: PU4601.8 177.71,59.45
  BOTTOM w0.254: 177.71,59.45 177.71,59.03 v1(177.44,58.76) 177.44,58.3 PR4670.1 PR4642.1 176.25,57.87 PC4623.2
PWR_VCCGT_ISUMP: length 17.3
  BOTTOM w0.203: PR4641.1 PR4816.1 ; PR4816.1 173.25,52.28 v1(173.38,52.41) 173.53,52.56 174.26,52.56 175.04,53.34 178.5,53.34 179.12,53.96 179.12,54.88 PC4628.1 ; PR4816.1 172.16,52.54 PR4808.1 ; PC4628.1 PC4609.1 PC4653.1 ; PC4628.1 178.51,55.49 PR4643.1 178.53,56.12 PC4630.1 177.82,57.57 177.82,58.57 178.11,58.86 PU4601.7
PWR_VCCGT_ISUMP_GA: length 41
  TOP w0.203: v2(154.71,41.62) 154.99,41.9 v1(154.99,42.25)
  L3 w0.203: v2(172.11,54.7) 172.28,54.88 172.28,57.61 171.33,58.56 164.62,58.56 163.16,57.1 163.16,56.17 162.26,55.27 155.67,55.27 154.08,53.69 154.08,51.05 153.32,50.28 153.32,46.79 154.59,45.52 154.59,42.13 154.71,42.02 v2(154.71,41.62)
  BOTTOM w0.203: v2(172.11,54.7) 172.11,54.55 171.42,53.87 PR4821.2 171.29,53.68 PR4808.2 ; v2(154.71,41.62) 155.16,41.16 PG4808.1
PWR_VCCGT_ISUMP_GB: length 31.4
  L3 w0.254: v2(170.84,52.28) 171.22,52.67 171.22,55.33 170.9,55.65 165.03,55.65 163.57,54.19 156.77,54.19 155.09,52.51 155.09,50 v2(154.58,49.49)
  BOTTOM w0.254: v2(154.58,49.49) 155.16,48.91 PG4813.1 ; PR4823.2 170.33,56.35 169.95,55.97 169.95,54.32 v1(170.45,53.81) 170.45,52.67 v2(170.84,52.28) PR4816.2
PWR_VCCGT_NTC: length 3.4
  BOTTOM w0.203: PU4601.3 179.71,59.03
  BOTTOM w0.254: PR4616.1 181.63,58.69 v1(180.89,58.69) 180.82,58.76 179.98,58.76 179.71,59.03
PWR_VCCGT_NTC1: length 44.8
  TOP w0.254: v2(158.44,43.95) 158.14,43.65 v1(157.96,43.65)
  L3 w0.254: v2(181.55,59.55) 181.2,59.9 177.57,59.9 175.64,61.84 174.52,61.84 173.63,60.95 173.63,59.52 176.04,57.11 176.04,53.59 172.87,50.41 172.87,48.25 170.8,46.19 166.99,46.19 165.98,45.17 162.28,45.17 162.03,45.43 159.81,45.43 158.44,44.06 v2(158.44,43.95)
  BOTTOM w0.254: PR4617.1 v2(158.44,43.95) ; v2(181.55,59.55) 182.04,59.55 PR4616.2 182.85,58.89 PR4621.2
PWR_VCCGT_PWMA: length 32.6
  TOP w0.254: v2(164.36,36.66) 164,36.31 v1(164,36.21)
  L3 w0.254: v2(175.53,60.41) 177.31,58.63 177.31,53.24 174.08,50.01 174.08,47.79 166.52,40.22 166.52,38.82 v2(164.36,36.66)
  BOTTOM w0.203: 175.53,60.79 175.79,61.04 PU4601.12
  BOTTOM w0.254: v2(164.36,36.66) 163.85,36.16 PR4802.2 ; v2(175.53,60.41) 175.53,60.79
PWR_VCCGT_PWMA_RA: length 3
  BOTTOM w0.203: PU4801.8 162.72,36.98 PR4817.1
  BOTTOM w0.254: PR4817.1 PR4802.1 162.76,36.18 v1(161.87,36.18)
PWR_VCCGT_PWMB: length 32.2
  TOP w0.254: v1(161.36,45.53) 161.36,45.12 v2(161.56,44.92) 161.82,45.17 PR4811.2
  L3 w0.254: v2(161.56,44.92) 161.69,44.79 166.14,44.79 167.15,45.81 170.96,45.81 173.25,48.09 173.25,50.25 176.55,53.55 176.55,57.14 174.01,59.68 174.01,60.54 174.65,61.17 v2(175.15,61.17)
  BOTTOM w0.203: 175.42,61.44 PU4601.13
  BOTTOM w0.254: v2(175.15,61.17) 175.42,61.44
PWR_VCCGT_PWMB_RA: length 2.8
  TOP w0.254: v1(162.76,46.44) 162.76,45.85 v2(162.72,45.81) 163.14,45.39 PR4811.1
  BOTTOM w0.203: PU4802.8 v2(162.72,45.81) 162.72,45.23 PR4818.1
PWR_VCCGT_RTN: length 9.7
  TOP w0.254: v1(177.39,60.76) 177.39,59.75 PC4622.1 177.77,59.37 PR4639.1 177.77,58.54 v2(178.33,57.99)
  BOTTOM w0.203: PU4601.6 178.51,59.4
  BOTTOM w0.254: PR4666.2 179.85,55.41 PC4619.2 179.17,56.09 179.17,57.15 v2(178.33,57.99) 178.33,58.48 178.51,58.66 178.51,59.4
PWR_VCCGT_SNB1: length 2.5
  TOP w0.254: v1(158.52,42.56) 159.28,42.56 PC4810.1 159.35,42.38 PR4805.2
PWR_VCCGT_SNB2: length 2.4
  TOP w0.254: PR4814.2 159.28,48.78 PC4813.1 159.2,50.25 v1(158.39,50.25)
PWR_VCCGT_SWA: length 3.2
  TOP w0.356: v2(155.21,39.46) 155.19,39.43 v1(154.63,39.43)
  TOP w0.508: v2(155.21,39.46) 156.18,39.46 156.66,39.94 PR4805.1
PWR_VCCGT_SWB: length 2.6
  TOP w0.508: PR4814.1 156.53,50.28 v1(156.61,50.35) 157.02,50.76 v2(157.37,50.76)
PWR_VCCGT_VCCDA: length 4.8
  BOTTOM w0.203: PU4801.2 158.97,38.64 158.64,38.31
  BOTTOM w0.254: v1(155.85,36.41) 156.03,36.59 PR4803.1 157.47,36.59 PC4809.1 157.5,37.17 158.64,38.31
PWR_VCCGT_VCCDB: length 4.3
  TOP w0.254: PR4813.1 160.22,45.55 PC4812.1 159.35,46.32 v2(158.52,46.32) v1(157.88,46.32)
  BOTTOM w0.203: PU4802.2 158.9,46.89 158.52,46.51 v2(158.52,46.32)
PWR_VCCSA_BST: length 2.9
  BOTTOM w0.305: PR5001.2 171.19,29.93 PU5001.2
  BOTTOM w0.508: v1(171.67,28.49) 171.67,29.46 PR5001.2
PWR_VCCSA_BST_RC: length 2.7
  BOTTOM w0.508: PR5001.1 171.6,31.58 170.84,32.35 PC5005.1
PWR_VCCSA_COMP: length 6.4
  BOTTOM w0.203: 178.11,65.49 PU4601.24
  BOTTOM w0.254: v1(176.04,70.06) 176.6,69.51 PR4640.1 176.6,68.44 PC4624.1 177.19,68.41 178.11,67.49 178.11,65.49
PWR_VCCSA_COMP_RC: length 1.8
  BOTTOM w0.254: PR4640.2 174.98,69.18 PC4601.1 174.06,69.25 v1(174.01,69.3)
PWR_VCCSA_DRVH: length 15.8
  TOP w0.356: v1(158.59,33.57) 158.59,33.92 v3(158.26,34.25)
  L3 w0.762: v3(169.97,31.18) 168.17,32.98 159.53,32.98 v3(158.26,34.25)
  BOTTOM w0.305: PU5001.1 v3(169.97,31.18)
  BOTTOM w0.406: v3(158.26,34.25) 158.73,34.72 PU5002.4
PWR_VCCSA_DRVL: length 6.5
  TOP w0.356: v1(164.03,28.89) 163.37,28.89 v3(163.3,28.96)
  L3 w0.762: v3(167.03,28.79) 163.47,28.79 v3(163.3,28.96)
  BOTTOM w0.305: v3(167.03,28.79) 167.16,28.93 PU5001.5
  BOTTOM w0.406: v3(163.3,28.96) PU5003.4
PWR_VCCSA_FB: length 5.1
  BOTTOM w0.203: PU4601.25 178.51,65.59
  BOTTOM w0.254: 178.51,65.59 178.51,66.89 178.62,67 178.62,67.31 v1(178.71,67.4) PR4632.2 PR4638.2 PR4637.1
PWR_VCCSA_FB1: length 1.8
  BOTTOM w0.254: PR4638.1 179.47,69.99 PC4621.2 179.34,70.27 v1(179.34,70.95)
PWR_VCCSA_FB2: length 5.7
  BOTTOM w0.254: PR4601.1 181.07,70.83 PC4616.2 ; PC4616.2 180.23,70.14 PR4637.2 ; PC4616.2 181,71.46 v1(180.74,71.72) 180.49,71.97 PC4620.1 PC4617.2
PWR_VCCSA_FB_RC: length 4.4
  BOTTOM w0.254: PR4632.1 178.53,69.23 177.82,69.94 v1(177.82,70.19) 177.95,70.32 177.95,71.92 PC4617.1
PWR_VCCSA_FCCM: length 53.4
  TOP w0.254: v1(167.66,29.81) 167.53,29.81 v2(167.18,30.16)
  L3 w0.254: v2(167.18,30.16) 170.81,30.16 171.57,30.92 171.57,41.2 173.95,43.59 178.26,43.59 178.61,43.59 182.2,47.18 182.2,48.03 184.93,50.76 184.93,55.11 183.89,56.15 183.89,57.93 184.45,58.49 184.45,63.05 182.9,64.6 182.61,64.6 182.12,65.1 v2(182.12,65.34)
  BOTTOM w0.203: PU4601.29 180.11,65.37 180.36,65.62
  BOTTOM w0.254: 180.36,65.62 181.84,65.62 v2(182.12,65.34) ; PU5001.7 167.41,29.93 v2(167.18,30.16)
PWR_VCCSA_IMON: length 3.4
  BOTTOM w0.203: PU4601.23 177.71,65.42
  BOTTOM w0.254: 177.71,65.42 177.71,65.97 v1(177.67,66) 176.78,66.89 PR4644.1 176.63,66.92 PC4629.2
PWR_VCCSA_ISUMN: length 63.4
  TOP w0.203: v2(155.14,34.81) 155.32,34.63 v1(155.32,34.25) ; PR5004.2 180.72,66.38 v2(180.59,66.25) 180.61,66.23 180.61,65.57 180.59,65.54 ; 180.59,65.54 PR4615.1 ; 180.59,65.54 PR4620.1
  L3 w0.203: v2(180.59,66.25) 181.51,65.33 181.51,64.84 182.54,63.81 182.54,63.18 183.84,61.89 183.84,58.87 183.19,58.22 183.19,56.89 181.5,55.21 181.5,47.47 178.32,44.28 173.79,44.28 168.96,39.45 168.96,37.76 165.72,34.53 160.04,34.53 158.56,36.01 155.51,36.01 155.14,35.64 v2(155.14,34.81)
  BOTTOM w0.203: PR4611.1 v2(155.14,34.81) ; PC4603.2 183.59,65.98 PR4613.1 182.6,66 PR4618.2 181.4,66.59 PC4605.1 181.05,66.43 180.87,66.25 v2(180.59,66.25)
PWR_VCCSA_ISUMN_P_1: length 0.8
  BOTTOM w0.254: PC4608.2 184.5,66.03 PR4613.2
PWR_VCCSA_ISUMN_P_2: length 66.3
  L3 w0.254: v2(154.27,34.81) 154.27,35.64 155.26,36.62 158.94,36.62 159.1,36.46 160.42,35.14 165.47,35.14 168.35,38.01 168.35,39.7 173.63,44.98 178.15,44.98 180.8,47.63 180.8,55.5 182.58,57.27 182.58,58.47 183.2,59.1 183.2,61.14 181.46,62.89 181.46,64.03 179.82,65.68 179.65,65.68 179.34,65.98 179.34,66.59 180.15,67.4 180.66,67.4 181.24,66.83 181.59,66.83 182.61,65.81 183.47,65.81 184.47,66.81 v2(184.47,68.24)
  BOTTOM w0.254: v1(184.55,68.79) 184.55,68.31 v2(184.47,68.24) PR4625.2 ; PR4611.2 v2(154.27,34.81)
PWR_VCCSA_ISUMN_R: length 69.1
  TOP w0.203: v1(153.84,32.12) 153.84,32.24 v2(154.2,32.6) ; v2(182.9,66.51) 182.77,66.38 PR5004.1
  L3 w0.203: v2(182.9,66.51) 183.15,66.51 183.41,66.76 183.41,67.4 183.03,67.78 181.63,67.78 181.06,68.35 179.75,68.35 178.39,66.99 178.39,65.43 179,64.82 179.21,64.61 179.38,64.61 180.39,63.6 180.39,62.53 182.27,60.65 182.27,59.49 181.64,58.86 181.64,57.68 179.85,55.89 179.85,48.01 177.78,45.93 173.25,45.93 167.41,40.09 167.41,38.4 165.09,36.09 160.8,36.09 159.76,37.13 159.33,37.56 154.87,37.56 153.13,35.82 153.13,34.37 154.33,33.17 154.33,32.73 v2(154.2,32.6)
  BOTTOM w0.203: PG5001.1 153.74,32.14 v2(154.2,32.6)
PWR_VCCSA_ISUMN_RC: length 1.7
  TOP w0.254: PC4611.2 181.33,64.73 PR4615.2 v1(181.38,63.77)
PWR_VCCSA_ISUMNB: length 3.9
  TOP w0.254: v1(178.84,64.73) PC4611.1 179.65,65.47 PR4620.2 179.67,66.08 v2(179.85,66.25)
  BOTTOM w0.203: PU4601.28 179.71,66.11 v2(179.85,66.25)
PWR_VCCSA_ISUMP: length 9.3
  TOP w0.203: v2(180.36,66.89) 181.07,66.89 PR5003.2 181.6,67.42 v1(181.6,68.03)
  BOTTOM w0.203: PC4608.1 183.61,66.79 PR4625.1 183.38,67.52 183.28,67.63 182.7,67.63 182.6,67.52 182.09,67.52 PR4618.1 181.35,67.45 PC4605.2 180.79,66.89 v2(180.36,66.89) 179.73,66.89 179.31,66.47 PU4601.27
PWR_VCCSA_ISUMP_R: length 66.8
  TOP w0.203: PR5003.1 v2(182.9,67.14) ; v1(155.29,32.14) v2(154.83,32.6)
  L3 w0.203: v2(182.9,67.14) 182.6,67.45 181.49,67.45 180.92,68.02 179.89,68.02 178.72,66.85 178.72,65.57 179.35,64.94 179.51,64.94 180.72,63.74 180.72,62.67 182.6,60.79 182.6,59.35 181.97,58.73 181.97,57.54 180.18,55.75 180.18,47.87 177.91,45.6 173.38,45.6 167.74,39.96 167.74,38.27 165.23,35.76 160.66,35.76 160.05,36.38 159.53,36.9 159.19,37.23 155,37.23 153.46,35.69 153.46,34.5 154.66,33.31 154.66,32.78 v2(154.83,32.6)
  BOTTOM w0.203: v2(154.83,32.6) 155.42,32.02 PG5011.1
PWR_VCCSA_PWM: length 51.5
  TOP w0.254: v2(182.82,65.11) 182.82,65.54 v1(182.95,65.67)
  L3 w0.254: v2(170.83,28.79) 171.34,28.79 172.08,29.53 172.08,40.99 174.16,43.08 178.82,43.08 182.71,46.97 182.71,47.52 185.44,50.25 185.44,55.32 184.4,56.36 184.4,57.72 184.96,58.28 184.96,63.31 183.15,65.11 v2(182.82,65.11)
  BOTTOM w0.203: 181.02,64.83 PU4601.30
  BOTTOM w0.254: PU5001.3 170.45,29.43 170.83,29.05 v2(170.83,28.79) ; v2(182.82,65.11) 182.82,65.08 182.58,64.83 181.02,64.83
PWR_VCCSA_RTN: length 7.3
  BOTTOM w0.203: PU4601.26 178.91,65.54
  BOTTOM w0.254: 178.91,65.54 178.91,66.71 179.6,67.4 v1(179.98,67.4) 180.23,67.4 180.92,68.08 PC4613.1 180.92,69.02 PR4627.2 181,69.25 PC4616.1 181.76,69.99 PR4602.1
PWR_VCCSA_SW: length 15
  TOP w0.356: v1(157.3,33.29) 157.3,33.64 v3(156.99,33.95)
  L3 w0.762: v3(167.89,31.3) 167.23,31.96 158.97,31.96 v3(156.99,33.95)
  BOTTOM w0.305: v3(167.89,31.3) PU5001.8
  BOTTOM w0.508: PC5005.2 167.89,31.58 v3(167.89,31.3)
PWR_VCORE_ALERT#: length 3
  BOTTOM w0.114: PU4601.36 182.01,62.24 v1(182.14,62.11) 182.3,61.95 PR4623.2
PWR_VCORE_BOOT: length 1.2
  BOTTOM w0.203: 154.58,54.06 155.16,54.64 PU4701.7
PWR_VCORE_BOOT_RC: length 2.5
  BOTTOM w0.508: PR4705.1 PC4707.1 156.08,52.51 v1(157.02,52.51)
PWR_VCORE_BOOTR: length 1.1
  BOTTOM w0.203: 155.85,54.06 155.56,54.35 PU4701.6
PWR_VCORE_COMP: length 6.5
  BOTTOM w0.203: PU4601.16 175.51,62.64
  BOTTOM w0.254: 175.51,62.64 174.56,62.64 174.45,62.54 173.98,62.54 v1(173.25,61.81) 172.99,61.56 172.99,60.67 172.61,60.29 PC4639.1 172.17,60.28 PR4656.1
PWR_VCORE_COMP1: length 1.9
  BOTTOM w0.254: PC4640.1 v1(170.2,59.41) PR4656.2
PWR_VCORE_FB: length 5.9
  BOTTOM w0.203: PU4601.17 175.64,63.04
  BOTTOM w0.254: 175.64,63.04 v1(173.28,63.04) 172.65,63.04 PR4658.1 172.16,62.55 PR4660.1 PR4657.1
PWR_VCORE_FB1: length 0.9
  BOTTOM w0.254: PR4657.2 171.22,61.12 PC4641.1
PWR_VCORE_FB2: length 5.8
  BOTTOM w0.254: v1(167.91,61.68) 168.63,61.68 PR4663.2 ; PC4643.2 168.65,62.65 PR4667.2 ; PC4643.2 PC4642.2 ; PC4643.2 168.8,62.6 PR4663.2 ; PR4660.2 171.22,61.89 PC4644.1 168.83,61.89 PR4663.2
PWR_VCORE_FB_RC: length 1.8
  BOTTOM w0.254: PC4643.1 v1(170.4,62.7) 171.19,62.7 PR4658.2
PWR_VCORE_FCCM#: length 37.3
  TOP w0.254: v1(153.54,56.3) 153.54,56.63 v2(153.31,56.86)
  L3 w0.254: v2(176.55,65.62) 175.03,65.62 172.36,68.29 165.33,68.29 164.95,67.91 154.17,67.91 153.44,67.17 153.44,56.98 v2(153.31,56.86)
  BOTTOM w0.203: PU4601.21 176.91,65.26 v2(176.55,65.62)
  BOTTOM w0.254: PR4706.2 v2(153.31,56.86)
PWR_VCORE_FCCM#_R: length 1.5
  BOTTOM w0.203: PU4701.1 153.35,58.39 PR4706.1
PWR_VCORE_IMON: length 7.4
  BOTTOM w0.203: PU4601.14 175.6,61.84
  BOTTOM w0.254: 175.6,61.84 175.02,61.84 174.01,60.84 174.01,60.29 v1(173.5,59.78) 173.2,59.47 173.2,58.71 172.38,57.89 PC4638.1 172.11,57.8 172.11,57.2 PR4661.1
PWR_VCORE_ISUMN: length 23.3
  TOP w0.203: v1(155.44,65.26) 155.44,65.44 v2(155.14,65.75)
  L3 w0.203: v2(155.14,65.75) 155.52,66.13 165.88,66.13 166.29,66.53 166.29,67.09 166.57,67.37 168.72,67.37 169.41,66.69 v2(170,66.69)
  BOTTOM w0.203: v2(155.14,65.75) PR4650.1 ; PR4701.2 PR4649.2 v2(170,66.69) 170.12,66.81 PC4631.1 171.57,66.81 PR4651.2 171.78,66.91 PR4648.2 172.58,66.17 PC4634.1 171.82,66.15 PR4652.2
PWR_VCORE_ISUMN_G: length 17.7
  TOP w0.203: v1(153.74,62.98) 153.84,62.98 v2(154.2,63.33)
  L3 w0.203: v2(154.2,63.33) 154.2,63.55 155.18,64.53 155.64,64.53 155.84,64.72 166.51,64.72 v2(167.15,65.37)
  BOTTOM w0.203: v2(167.15,65.37) 167.61,65.82 PR4701.1 ; PG4708.1 153.82,62.44 154.2,62.83 v2(154.2,63.33)
PWR_VCORE_ISUMN_P_1: length 1.8
  BOTTOM w0.254: PC4635.1 PC4652.1 169.95,65.82 PR4649.1
PWR_VCORE_ISUMN_P_2: length 21.7
  TOP w0.254: v2(154.27,65.75) 153.94,65.42 v1(153.94,65.26)
  L3 w0.254: v2(172.66,64.43) 172.16,64.43 170.59,65.99 166.63,65.99 166.14,65.49 155.75,65.49 155.39,65.14 154.89,65.14 154.53,65.49 154.53,65.49 v2(154.27,65.75)
  BOTTOM w0.254: PR4650.2 v2(154.27,65.75) ; PR4653.2 v2(172.66,64.43)
PWR_VCORE_ISUMN_RC: length 1.8
  BOTTOM w0.254: v1(172.55,68.56) PC4632.1 171.88,67.67 PR4651.1
PWR_VCORE_ISUMNA: length 5.2
  BOTTOM w0.203: PU4601.20 176.32,64.95
  BOTTOM w0.254: 176.32,64.95 v1(174.39,66.88) 173.47,66.88 PR4648.1 173.47,66.93 PC4632.2
PWR_VCORE_ISUMP: length 9.3
  BOTTOM w0.203: PU4601.19 175.53,63.84 175.28,64.1 v1(175.28,64.86) 173.99,66.15 PC4634.2 173.38,66.05 PR4653.1 173.27,65.19 PR4652.1 171.7,65.16 PC4635.2 PC4652.2 169.54,65.16 PR4708.2
PWR_VCORE_ISUMP_G: length 16
  TOP w0.203: v2(154.91,63.33) 155.26,62.98 v1(155.26,62.9)
  L3 w0.203: v2(167.79,64.98) 167.55,64.75 167,64.75 166.65,64.39 155.97,64.39 155.78,64.2 155.32,64.2 154.91,63.79 v2(154.91,63.33)
  BOTTOM w0.203: v2(154.91,63.33) PG4707.1 ; PR4708.1 v2(167.79,64.98)
PWR_VCORE_NTC: length 6.5
  BOTTOM w0.203: PU4601.15 175.56,62.24
  BOTTOM w0.254: 175.56,62.24 174.7,62.24 v1(174.52,62.06) 173.53,61.07 173.53,60.57 172.82,59.85 172.82,58.97 172.5,58.65 PR4662.1
PWR_VCORE_NTC1: length 21.6
  TOP w0.254: v1(153.92,53.96) 153.92,54.09 v2(153.56,54.44)
  L6 w0.254: v2(153.56,54.44) 166.44,54.44 169.36,57.36 v2(169.36,57.87)
  BOTTOM w0.254: PR4662.2 PR4655.2 169.38,57.89 v2(169.36,57.87) ; PR4654.1 v2(153.56,54.44)
PWR_VCORE_PROG1: length 2.8
  BOTTOM w0.203: 181.76,63.84 181.25,63.84 181.25,63.84 PU4601.32
  BOTTOM w0.254: 181.76,63.84 182.71,63.84 182.82,63.95 183.5,63.95 PR4629.1
PWR_VCORE_PROG2: length 2.7
  BOTTOM w0.203: PU4601.31 181.76,64.24
  BOTTOM w0.254: PR4628.1 183.69,64.43 182.6,64.43 v1(182.52,64.35) 182.41,64.24 181.76,64.24
PWR_VCORE_PWM: length 42.3
  TOP w0.254: v1(151.51,55.23) 151.25,55.23 v2(151,55.49)
  L3 w0.254: v2(151,55.49) 151,57 151.49,57.49 152.67,57.49 152.93,57.75 152.93,67.55 153.79,68.41 164.74,68.41 165.12,68.79 172.61,68.79 175.15,66.25 v2(176.55,66.25)
  BOTTOM w0.203: 177.31,65.62 PU4601.22
  BOTTOM w0.254: v2(151,55.49) 151,55.51 151.38,55.89 PR4702.2 ; v2(176.55,66.25) 176.68,66.25 177.31,65.62
PWR_VCORE_PWM_R: length 3.8
  BOTTOM w0.203: PR4712.1 152.71,55.07 PU4701.8
  BOTTOM w0.254: PR4702.1 PR4712.1 152.6,54.95 v1(152.6,54.11)
PWR_VCORE_RTN: length 7.9
  BOTTOM w0.203: PU4601.18 175.42,63.44
  BOTTOM w0.254: 175.42,63.44 175.03,63.84 v1(174.52,63.84) 172.44,63.84 PC4637.1 171.95,63.41 PR4659.2 171.17,63.46 PC4642.1 169.74,63.59 PR4668.2
PWR_VCORE_SCLK: length 3.6
  BOTTOM w0.114: PU4601.37 181.85,61.84 182.12,61.57 183.03,61.57 v1(183.16,61.44) 183.41,61.19 PR4624.2
PWR_VCORE_SDIO: length 3.2
  BOTTOM w0.114: PU4601.35 181.7,62.64 181.83,62.51 182.73,62.51 v1(183.1,62.88) 183.85,62.88 PR4622.2
PWR_VCORE_SNB: length 2.5
  TOP w0.254: PR4703.2 152.47,57.75 PC4706.1 151.71,57.62 v1(151.68,57.64)
PWR_VCORE_SW: length 2
  TOP w0.508: v2(156.99,59.65) 156.48,59.14 v1(156.36,59.14) PR4703.1
PWR_VCORE_VCC: length 3.7
  TOP w0.508: PR4610.2 182.27,62.7 182.14,62.83 182.14,62.93 v2(182.11,62.95) ; PR4610.2 182.34,62.06 v1(183.15,62.06) ; PR4610.2 182.19,62.06 PC4607.1
  BOTTOM w0.203: v2(182.11,62.95) 182.02,63.04 PU4601.34
PWR_VCORE_VCC_R: length 5.8
  BOTTOM w0.203: PC4708.1 152.55,58.89 153.06,59.4 154.83,59.4 155.16,59.07 PU4701.2
  BOTTOM w0.254: v1(150.9,58.18) 151.15,58.43 PR4704.1 151.81,58.46 PC4708.1
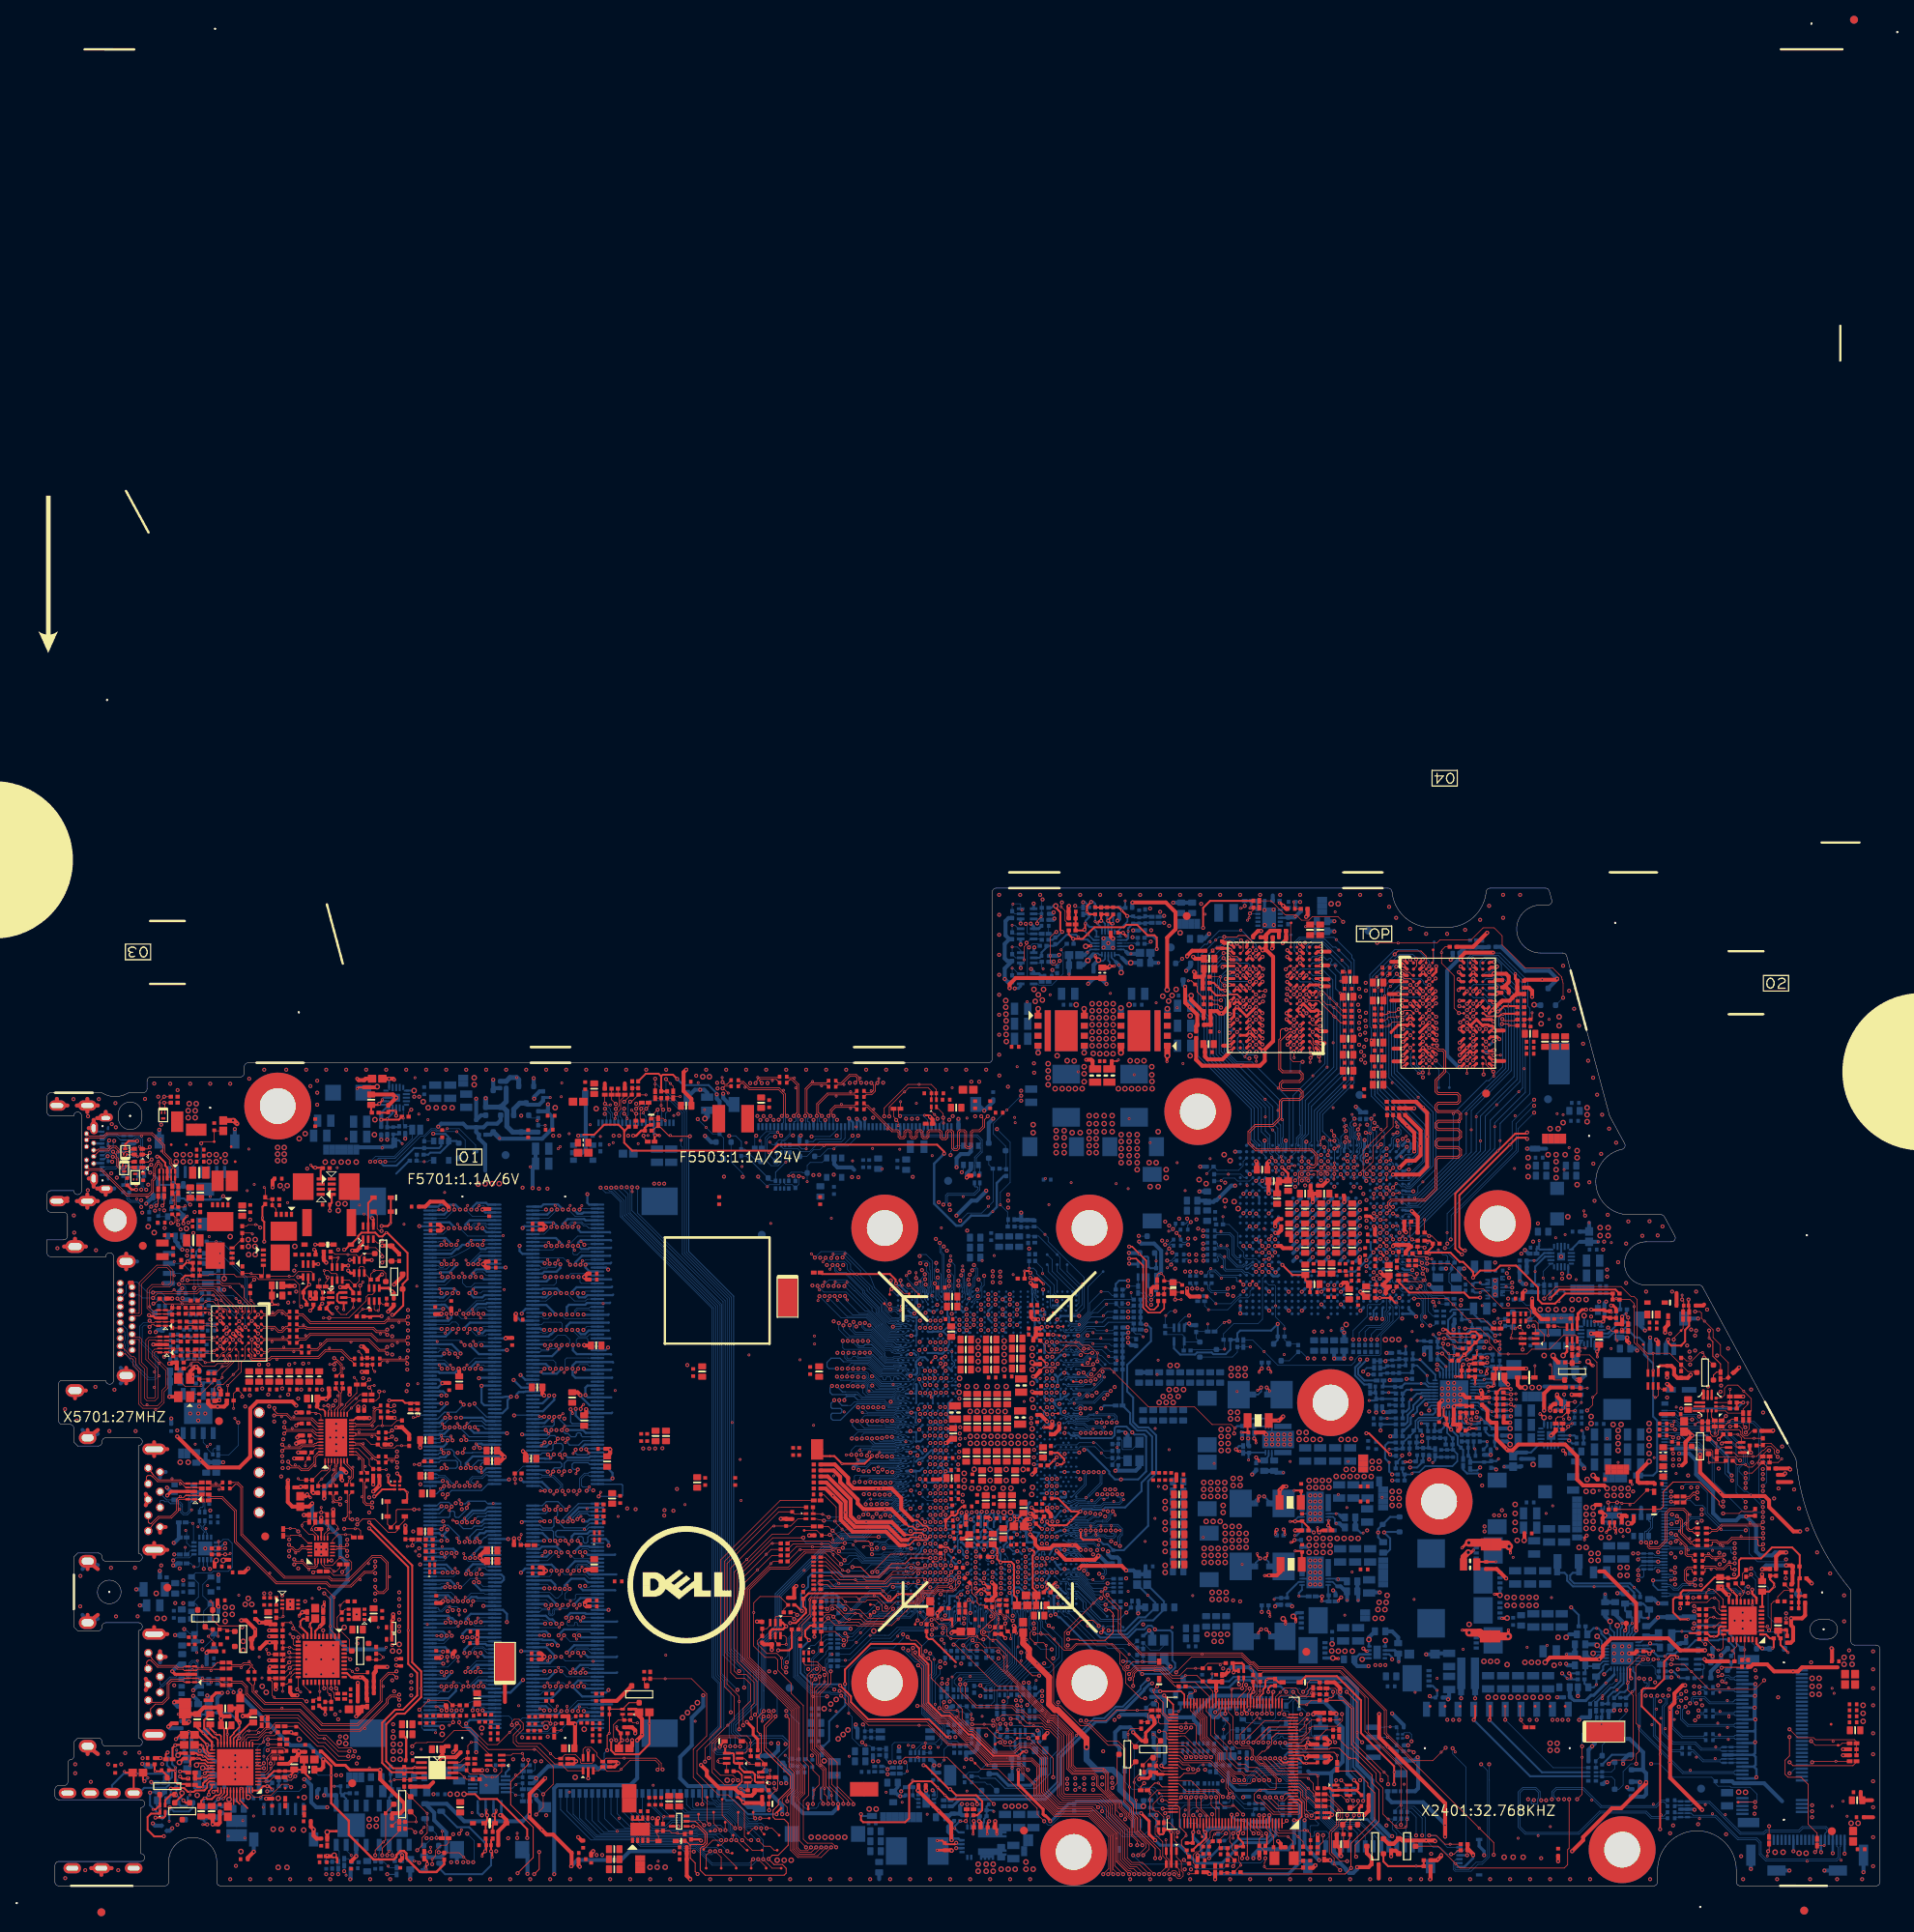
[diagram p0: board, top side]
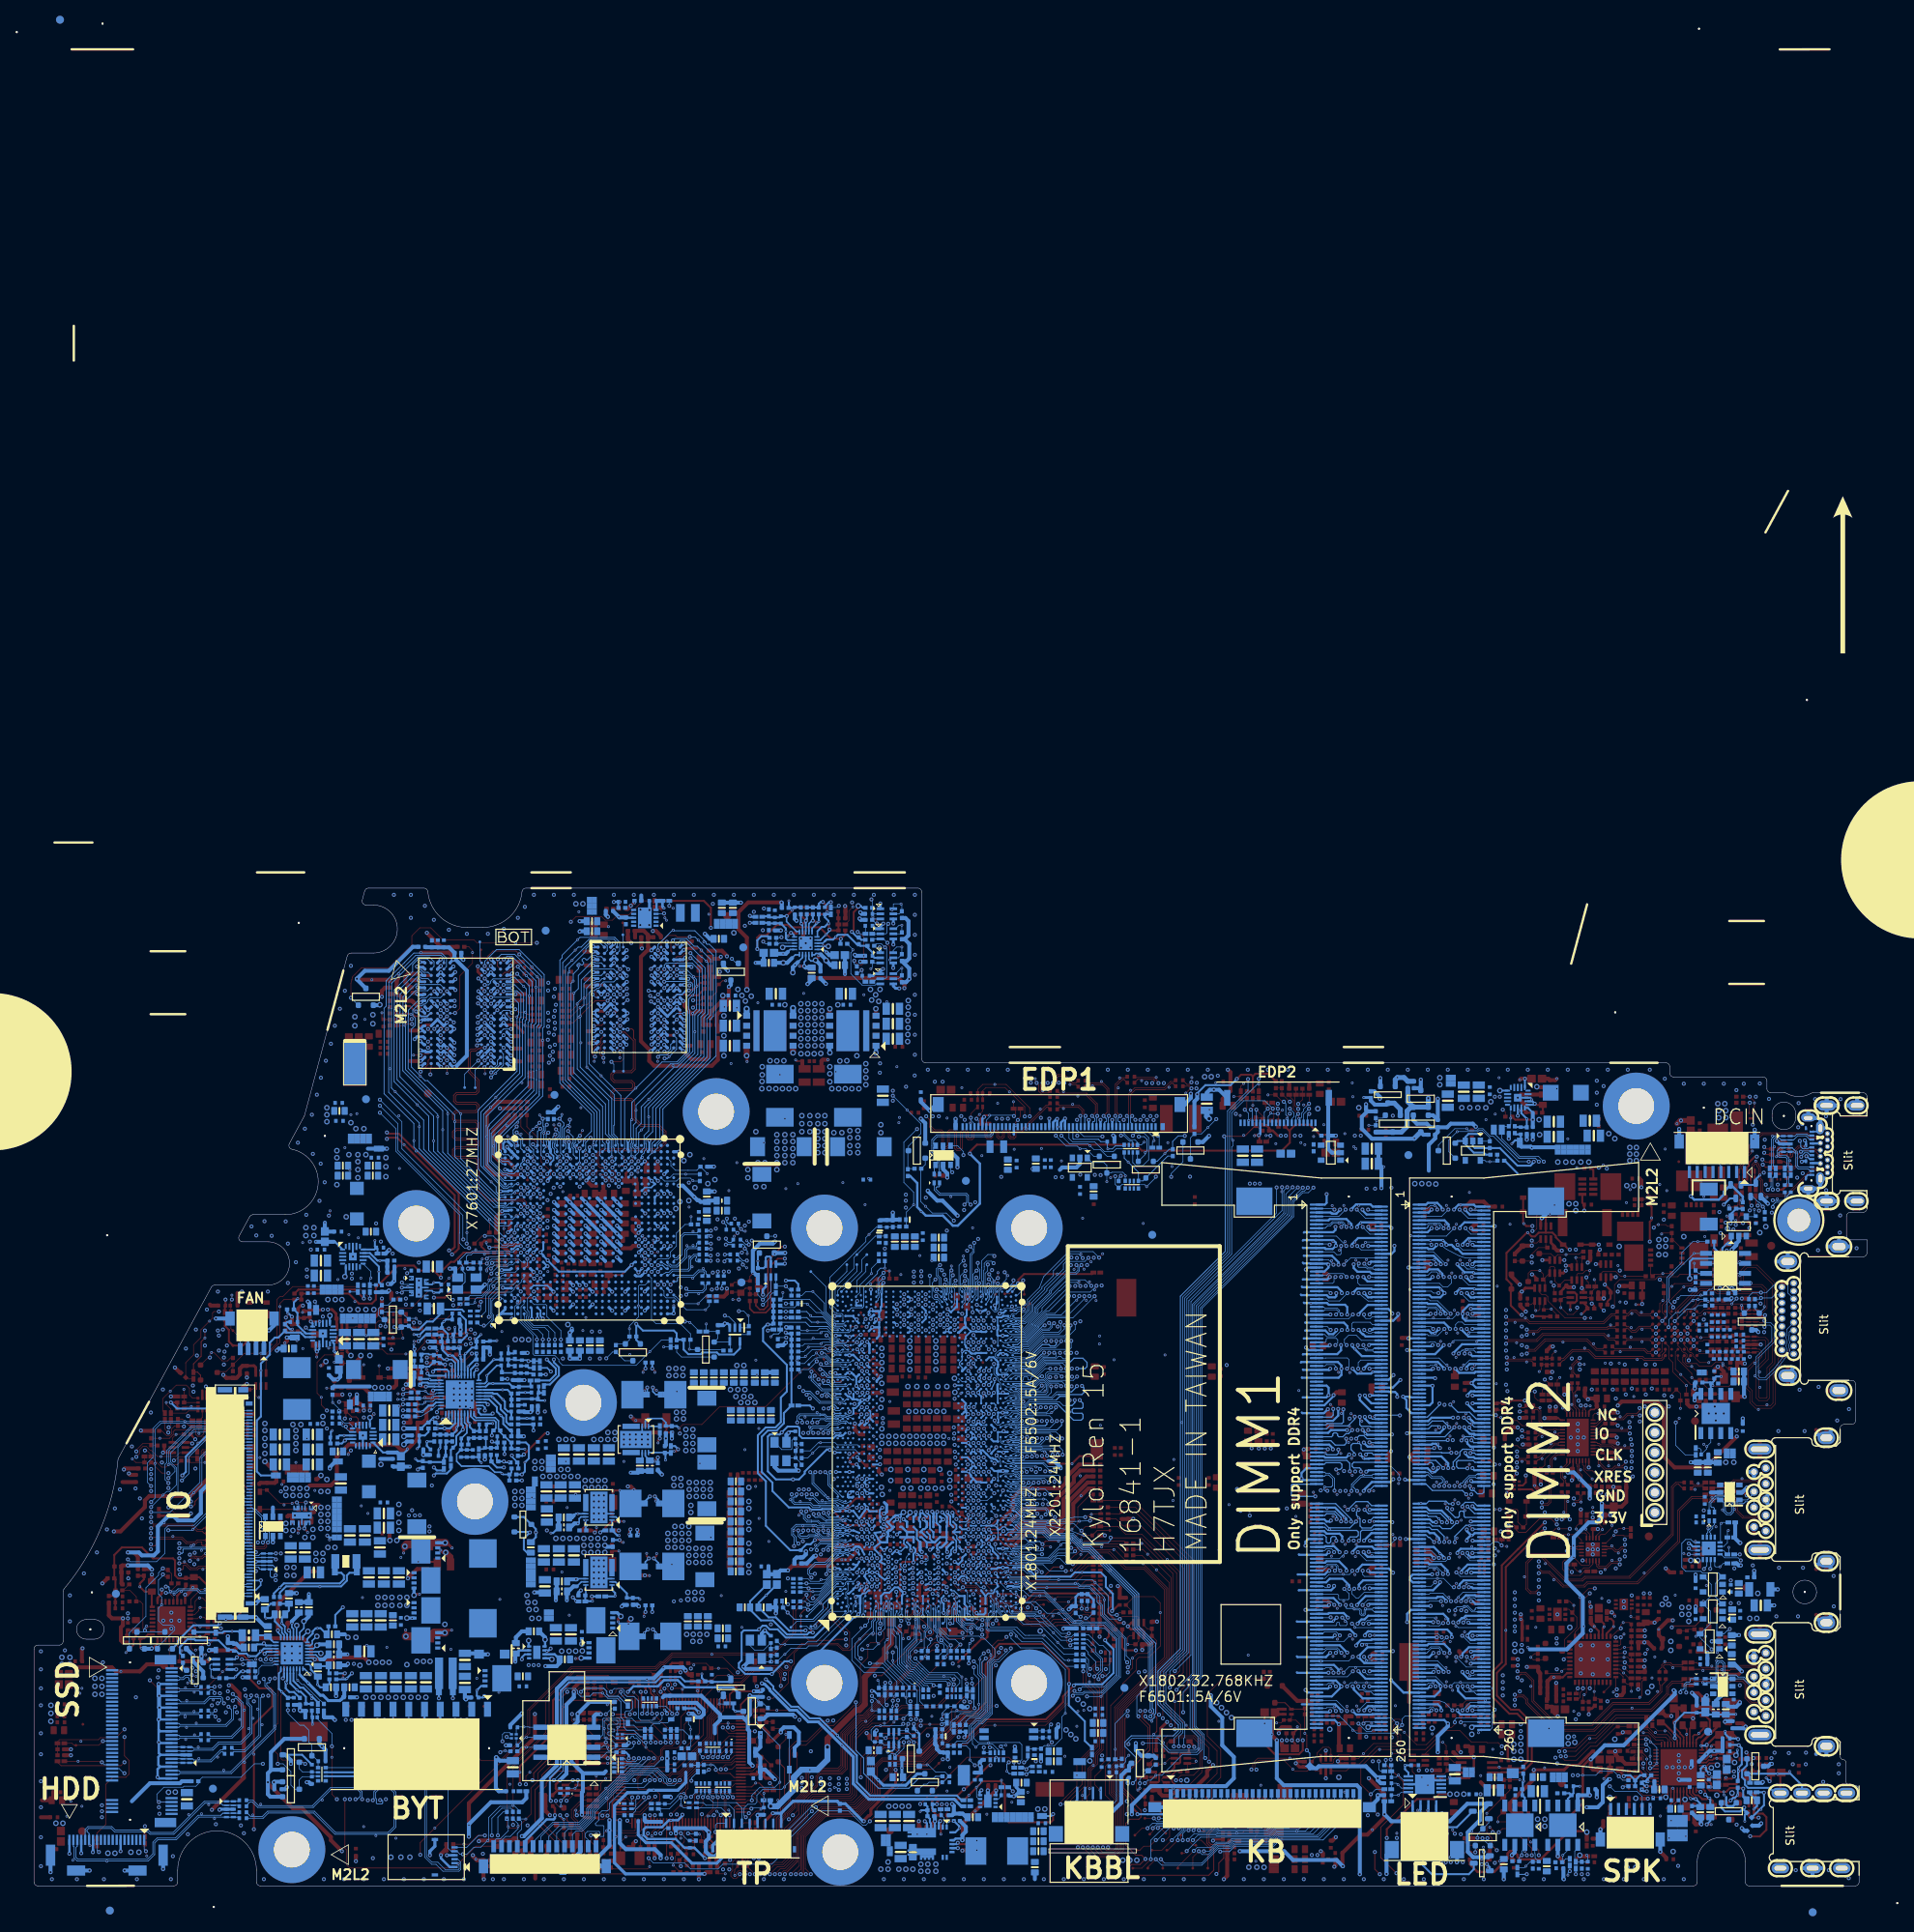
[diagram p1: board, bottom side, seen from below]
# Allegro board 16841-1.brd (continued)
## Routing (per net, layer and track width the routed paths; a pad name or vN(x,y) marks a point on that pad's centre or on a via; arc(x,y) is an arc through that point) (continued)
PWR_VCORE_VIN: length 5
  TOP w0.254: v2(183.03,63.44) 183.63,63.44 v1(183.76,63.58) PC4606.1 183.99,64.96 PR4612.2
  BOTTOM w0.203: 181.91,63.44 PU4601.33
  BOTTOM w0.254: 181.91,63.44 181.93,63.46 183.01,63.46 v2(183.03,63.44)
PWR_VCORE_VRHOT#: length 3.9
  BOTTOM w0.203: PU4601.38 181.74,61.44
  BOTTOM w0.254: 181.74,61.44 182.14,61.05 182.69,61.05 v1(183.48,60.26) 184.22,60.26 PR4607.2
PWR_VDDQ: length 5
  BOTTOM w0.508: PG5109.1 42.51,93.86 v1(42.57,93.81) 42.69,93.94 43.89,93.94 PG5113.2
PWR_VDDQ_BOOT: length 2.7
  TOP w0.508: PR5102.1 v2(43.44,102.58) 43.96,102.58 v1(44.09,102.45)
  BOTTOM w0.254: PU5101.1 v2(43.44,102.58)
PWR_VDDQ_BOOT_A: length 2
  TOP w0.508: v1(39.39,102.58) 39.57,102.4 PC5114.1 40.46,102.58 PR5102.2
PWR_VDDQ_EN: length 3.4
  BOTTOM w0.089: PU5101.11 v1(45.24,97.57) 45.24,96.77 PR5105.1 46.25,96.53 PG5112.2
PWR_VDDQ_FB: length 4.3
  BOTTOM w0.254: PR5107.2 44.62,96.43 PC5113.2 43.94,96.4 PR5101.1 v1(43.2,97.47) 43.2,97.5 43.89,98.19 PU5101.14
PWR_VDDQ_FB_A: length 2.8
  BOTTOM w0.254: v1(45.11,94.32) 44.67,94.75 PG5113.1 43.96,94.88 PC5113.1 44.57,95.52 PR5107.1
PWR_VDDQ_ILMT: length 3.9
  TOP w0.254: PR5103.1 43.25,98.26 PR5106.2 43.5,98.51 v1(44.22,98.51) 44.34,98.39 v2(44.34,97.88)
  BOTTOM w0.254: PU5101.13 v2(44.34,97.88)
PWR_VDDQ_PG: length 1
  TOP w0.089: PR5104.2 45.92,98.31 v2(46.25,98.64)
  vias: v1(47.21,98.08)
PWR_VDDQ_PH: length 8.5
  TOP w0.254: PC5114.2 39.57,101.48 v1(39.39,101.31)
  TOP w0.508: v3(41.93,101.56) 41.85,101.48 PC5114.2
  L3 w0.762: v3(46.62,101.06) 44.09,101.06 44.07,101.05 42.44,101.05 v3(41.93,101.56)
  BOTTOM w0.254: PU5101.6 v3(46.62,101.06)
PWR_VDDQ_VCC: length 4.7
  TOP w0.254: v1(42.57,99.91) 42.57,99.78 v2(42.18,99.4) 42.03,99.25 PC5112.1 41.17,98.34 PR5103.2
  BOTTOM w0.254: PU5101.16 42.32,99.26 v2(42.18,99.4) 42.5,99.71 PU5101.17
PWR_VGA_CORE_BOOT1: length 2.5
  BOTTOM w0.203: v1(132.15,118.66) 132.5,119 PU8201.1
  BOTTOM w0.508: PR8210.1 131.77,118.28 v1(132.15,118.66)
PWR_VGA_CORE_BOOT1_1: length 2.4
  BOTTOM w0.508: v1(129.8,115.87) PC8211.1 PR8210.2
PWR_VGA_CORE_BOOT2: length 2.8
  BOTTOM w0.203: 137.05,118.71 136.76,119 PU8201.15
  BOTTOM w0.508: PR8211.1 138.68,118.45 v1(137.66,118.45) 137.31,118.45 137.05,118.71
PWR_VGA_CORE_BOOT2_1: length 2.3
  BOTTOM w0.508: PR8211.2 PC8216.1 v1(141.16,117.31)
PWR_VGA_CORE_EN: length 10
  BOTTOM w0.203: PU8201.3 132.6,119.8 132.38,120.03
  BOTTOM w0.254: 132.38,120.03 132.35,120.06 132.34,120.06 132.13,120.26 131.31,120.26 v1(130.96,120.61) 130.7,120.86 129.48,120.86 128.29,119.67 PR8256.2 127.83,119.47 PR8260.2 126.94,119.26 126.31,118.63 PC8225.2 126.05,117.94 PQ8305.2
PWR_VGA_CORE_EN#: length 3.8
  BOTTOM w0.089: PQ8305.6 123.67,118.88 123.24,119.32 v1(122.58,119.32) PR8315.1 122.58,118.38 123.01,117.94 PQ8305.5
PWR_VGA_CORE_LGATE1: length 18.4
  TOP w0.356: v3(133.54,117.64) 133.14,118.04 v1(133.14,118.22)
  TOP w0.508: v3(131.72,111.47) 131.74,111.44 PU8204.8
  L3 w1.016: v3(131.72,105.88) 131.56,106.03 131.56,111.31 v3(131.72,111.47) 131.72,112.53 133.5,114.32 133.5,117.61 v3(133.54,117.64)
  BOTTOM w0.203: v3(133.54,117.64) 133.64,117.54 134.13,117.54 134.38,117.79 PU8201.19
  BOTTOM w0.508: v3(133.54,117.64) 133.51,117.64 132.91,117.04 PR8224.1 ; v3(131.72,105.88) 131.74,105.9 PU8202.8
PWR_VGA_CORE_LGATE2: length 14.8
  TOP w0.762: PU8206.8 v3(136.39,105.88)
  L3 w1.016: v3(136.42,116.06) 136.42,111.59 v3(136.39,111.57) v3(136.39,105.88)
  BOTTOM w0.203: PU8201.17 135.18,117.99 135.76,117.41
  BOTTOM w0.508: 135.76,117.41 v1(136.13,117.04) 136.42,116.75 v3(136.42,116.06)
  BOTTOM w0.762: PU8208.8 v3(136.39,111.57)
PWR_VGA_CORE_PHASE1: length 17.3
  L3 w1.016: v3(128.29,105.5) 128.29,108.4 128.93,109.04 128.93,112.85 131.5,115.42 131.5,116.91 v3(132.19,117.6)
  BOTTOM w0.203: 132.9,118.37 133.03,118.5 133.48,118.5 133.66,118.32 PU8201.20
  BOTTOM w0.508: PC8211.2 131.6,117.01 v3(132.19,117.6) 132.19,117.69 132.87,118.37 132.9,118.37
  vias: v1(130.96,103.46) v3(127.15,104.48) v3(127.15,103.59) v3(127.15,102.7) v3(127.15,101.81) v3(128.04,101.31) v3(128.93,101.31) v3(129.56,104.86) v3(129.76,101.31) v3(130.45,104.84) v3(130.6,101.31) v3(131.47,101.31) v3(131.72,104.1) v3(131.72,103.21) v3(131.72,102.2)
PWR_VGA_CORE_PHASE2: length 18
  L3 w1.016: v3(140.31,104.1) 140.31,107.31 139.21,108.4 139.21,115.73 v3(137.64,117.31)
  BOTTOM w0.203: 136.52,117.92 136.12,118.32 PU8201.16
  BOTTOM w0.508: 136.52,117.92 137.13,117.31 v3(137.64,117.31) PC8216.2
  vias: v1(138.07,103.08) v3(136.06,101.31) v3(136.9,101.31) v3(137.56,104.86) v3(137.74,101.31) v3(138.45,104.84) v3(138.58,101.31) v3(139.32,104.86) v3(139.44,101.33) v3(140.31,103.07) v3(140.33,102.23) v3(140.36,101.31)
PWR_VGA_CORE_PSI: length 6.5
  TOP w0.254: PC8226.2 130.66,122.99 PR8259.1 130.63,122.19 PR8257.2 PR8258.2 131.62,121.42 131.73,121.53 v2(131.76,121.53) 131.85,121.62 v1(131.85,122.26)
  BOTTOM w0.203: PU8201.4 132.91,120.2 v1(132.23,120.89) 131.76,121.35 v2(131.76,121.53)
PWR_VGA_CORE_REFADJ: length 2.5
  BOTTOM w0.203: 133.7,121.98 133.98,121.7 PU8201.6
  BOTTOM w0.254: PR8222.1 v1(133.12,122.57) 133.7,121.98
PWR_VGA_CORE_REFIN: length 4.7
  TOP w0.254: PC8204.1 134.61,123.48 PR8209.1 133.88,122.66 v2(133.88,122.65) 133.8,122.57 133.6,122.57 v1(133.4,122.36)
  BOTTOM w0.203: PU8201.7 134.38,122.28 134.01,122.65 v2(133.88,122.65)
  BOTTOM w0.254: v2(133.88,122.65) 133.88,122.66 PR8209.1
PWR_VGA_CORE_RGND: length 10.7
  TOP w0.254: v2(137.2,123.25) 137.2,123.26 v1(136.49,123.96) 136.09,124.37 PC8201.1 PC8204.2 133.9,124.37 PR8209.2 133.17,124.34 PC8223.2
  BOTTOM w0.203: PU8201.10 135.95,121.29 137.22,122.55 137.22,123.23
  BOTTOM w0.254: PR8220.1 140.23,123.23 PR8213.1 139.31,123.07 PC8322.1 138.09,123.07 PC8219.2 137.22,123.23 v2(137.2,123.25)
PWR_VGA_CORE_SS: length 2
  TOP w0.254: v1(137.05,120.71) 136.88,120.89 136.88,120.9 v2(136.66,121.12) 136.63,121.14 PC8205.1
  BOTTOM w0.203: v2(136.66,121.12) 136.55,121.12 136.27,120.84 PU8201.11
PWR_VGA_CORE_TON: length 2.3
  BOTTOM w0.203: PU8201.9 135.18,122.04 135.28,122.13
  BOTTOM w0.254: 135.28,122.13 v1(135.4,122.26) PR8201.2
PWR_VGA_CORE_TON_1: length 2.5
  BOTTOM w0.254: PR8201.1 135.43,124.37 PC8202.2 136.24,124.29 PR8202.2 136.93,124.32 v1(136.93,125.18)
PWR_VGA_CORE_UGATE1: length 23.2
  TOP w0.356: v3(131.91,119.4) 131.95,119.44 v1(132.58,119.44)
  TOP w0.508: v3(125.88,111.47) 125.85,111.44 PU8204.1
  L3 w1.016: v3(125.88,111.47) 125.88,108.67 ; 125.88,108.67 126.77,108.67 127.66,109.56 127.66,113.37 130.23,115.94 130.23,117.72 v3(131.91,119.4) ; 125.88,108.67 v3(125.88,105.88)
  BOTTOM w0.203: PU8201.2 v3(131.91,119.4)
  BOTTOM w0.508: v3(125.88,105.88) 125.85,105.9 PU8202.1
PWR_VGA_CORE_UGATE2: length 23.8
  TOP w0.356: v1(142.23,104.76) 142.23,105.45 v3(142.29,105.5)
  TOP w0.762: PU8206.1 v3(142.29,105.5)
  L3 w1.016: v3(137.71,119.26) 140.48,116.5 140.48,108.93 140.86,108.55 142.29,108.55 ; 142.29,108.55 v3(142.29,111.47) ; 142.29,108.55 v3(142.29,105.5)
  BOTTOM w0.203: PU8201.14 137.58,119.4 v3(137.71,119.26)
  BOTTOM w0.762: PU8208.1 v3(142.29,111.47)
PWR_VGA_CORE_VID: length 4.6
  BOTTOM w0.203: PU8201.5 133.29,121.32
  BOTTOM w0.254: PR8207.2 132.33,123.48 PC8203.2 132.35,123.1 131.9,122.64 v1(131.9,122.36) 132.39,121.87 132.75,121.87 133.29,121.32
PWR_VGA_CORE_VREF: length 4
  TOP w0.254: PC8201.2 135.4,123.36 134.76,122.72 v2(134.76,122.64) 135.11,122.29 v1(135.3,122.29)
  BOTTOM w0.203: 134.78,122 PU8201.8
  BOTTOM w0.254: PR8206.1 134.64,122.88 134.76,122.76 v2(134.76,122.64) 134.78,122.62 134.78,122
PWR_VGA_CORE_VSNS: length 5.7
  BOTTOM w0.203: PU8201.12 137.09,120.2 137.11,120.23
  BOTTOM w0.254: 137.11,120.23 137.31,120.42 v1(137.31,121.32) 137.31,121.68 PC8219.1 137.97,122.34 PC8222.1 138.73,122.31 PR8212.2 139.54,122.39 PR8221.1
PWR_VGA_SNUB1: length 2
  TOP w0.508: v1(131.97,104.99) 132.61,104.99 PC8206.1 132.79,104.15 PR8216.2
PWR_VGA_SNUB2: length 2
  TOP w0.203: v1(136.06,104.96) 135.91,104.81 PC8218.1
  TOP w0.508: PC8218.1 135.22,104.13 PR8215.2
Q6204_G: length 48.1
  TOP w0.254: v2(124.35,17.07) 123.93,17.07 v1(123.46,16.6) 123.41,16.54 120.16,16.54 117.46,19.24 117.03,19.24 114.67,21.6 113.61,21.6 111.93,23.28 111.93,28.18 110.76,29.35 110.76,30.17 110.18,30.76 104.6,30.76 101.34,27.49 v2(101.34,25.67)
  BOTTOM w0.203: v2(124.35,17.07) 124.26,17.16 123.79,17.16 123.59,17.36 Q6504.2
  BOTTOM w0.254: R6510.2 99.33,18.43 99.33,20.92 101.37,22.95 101.37,25.64 v2(101.34,25.67) ; Q6504.5 Q6504.2
Q6205_Q: length 2.5
  BOTTOM w0.381: Q6503.D 122.58,16.09 v1(122.58,14.97) 122.58,13.96 R6503.2
Q6502_D: length 8.3
  BOTTOM w0.381: R6514.1 126.51,14.39 v1(125.6,13.48) 124.91,12.79 122.07,12.79 120.62,14.24 Q6502.D
Q7601_G: length 5.5
  TOP w0.089: R7657.2 186.08,71.54 186.08,70.19 185.95,70.06 v1(185.95,69.61) 186,69.56 Q7601.5 Q7601.2
Q9102_G: length 13.3
  TOP w0.089: v2(216.43,39.58) 216.12,39.28 R9129.1
  BOTTOM w0.089: v2(216.43,39.58) 216.43,39.43 216.99,38.87 216.99,37.1 216.58,36.69 v1(216.58,35.72) 216.99,35.31 216.99,33.72 216.4,33.12 215.18,33.12 214.92,32.87 214.92,32.51 217.12,30.31 Q9102.G
REFIN_VREF: length 5.2
  TOP w0.254: PC8223.1 132.38,123.48 v1(132.07,123.79) 132.07,124.51 v2(132.61,125.04)
  BOTTOM w0.254: PR8206.2 PR8208.2 PR8222.2 133.12,124.81 132.89,125.04 v2(132.61,125.04)
RESET_OUT#: length 144.4
  TOP w0.102: KBC24.73 142.44,18.58 142.31,18.7 142.21,18.81 142.21,19.39 141.96,19.65 v2(141.24,19.65) ; R2617.1 44.72,6.95 42.57,4.79 v2(42.57,3.9) ; v2(108.35,15.71) 108.99,16.34 v1(110.59,16.34) 114.29,16.34 v2(120.24,10.4)
  L3 w0.102: v2(141.24,19.65) 139.67,19.65 138.49,18.47 136.82,18.47 134.45,16.1 133.26,16.1 131.04,13.88 131.04,13.37 v2(130.58,12.91)
  L4 w0.102: v2(42.57,3.9) 43.57,2.89 45.88,2.89 46.76,3.77 47.14,3.77 48.48,5.11 57.74,5.11 58.17,5.55 64.44,5.55 64.59,5.69 70.65,5.69 76.6,11.64 83.46,11.64 86.18,14.37 88.3,14.37 90.61,12.05 90.62,12.05 90.67,12.01 91,12.01 94.18,12.01 95.31,10.88 106.51,10.88 107.29,10.1 108.85,10.1 110.15,11.39 114.58,11.39 115.13,11.94 116.92,11.94 117.1,11.75 129.62,11.75 130,12.13 130,12.33 v2(130.58,12.91)
  L6 w0.102: v2(120.24,10.4) 120.68,10.84 126.32,10.84 127.35,11.87 129.74,11.87 130,12.13 130,12.33 v2(130.58,12.91)
  BOTTOM w0.102: EC1704.1 108.2,15.86 v2(108.35,15.71) 108.35,15.66 108.3,15.61 R1706.1
RESET_OUT#_G: length 4.9
  TOP w0.089: Q2602.G 46.88,8.72 v1(46.88,8.14) R2616.2 R2617.2 44.32,8.14 C2614.1
REXT: length 7.7
  TOP w0.089: R5734.1 v1(22.93,63.59) 24.66,65.32 24.66,66.51 25.17,67.02 25.17,68.55 U5701.C6
RING2: length 4
  TOP w0.203: HDA27.30 20.32,15.27 20.01,15.58 19.22,15.58 v3(18.99,15.35)
  TOP w0.406: RN2901.3 16.89,16.86 v3(16.63,16.6)
  BOTTOM w0.254: v3(16.63,16.6) 16.46,16.77 v1(16.46,17.26)
RING2_R: length 26.2
  L6 w1.016: HPMIC1.3 4.5,0.95 12.04,0.95 13.48,2.39 13.48,6.6 16.85,9.97 18.28,9.97 19.07,10.76 v3(19.07,11.52)
  BOTTOM w0.305: ED2901.1 17.03,10.12 17.67,10.12 17.87,10.32 17.87,11.29
  vias: v1(18.15,11.57)
RSMRST_PWRGD#: length 7.6
  BOTTOM w0.089: R4032.2 v1(149.42,19.9) 149.42,20.28 149.67,20.53 D4002.K ; R4032.2 150.36,19.82 R4029.2 R4030.2 R4033.2 ; R4032.2 149.37,18.83 149.37,17.82 R4031.2
RSVD_F65: length 1.7
  TOP w0.089: v2(127.16,72.04) 127.78,72.66 TP612.1
  BOTTOM w0.089: CPU1.F65 127.4,71.8 v2(127.16,72.04)
RSVD_G65: length 1.2
  TOP w0.089: TP613.1 127.08,71.08 v2(127.05,71.05)
  BOTTOM w0.089: CPU1.G65 126.75,71.35 v2(127.05,71.05)
RT8812_PVCC: length 4.1
  TOP w0.356: v2(134.97,116.88) v1(135.55,116.88)
  TOP w0.508: PR8223.2 134.79,116.7 v2(134.97,116.88)
  BOTTOM w0.203: PU8201.18 134.78,117.6 134.97,117.41 v2(134.97,116.88)
  BOTTOM w0.508: PR8223.2 134.79,116.7 v2(134.97,116.88)
RTC_AUX_S5: length 235.2
  TOP w0.254: R2753.1 17.78,14.54 v2(16.89,14.54) ; R1730.1 94.58,30.26 94.25,29.93 v2(92.86,29.93)
  TOP w0.356: RN1801.2 74.78,22.46 R2106.1 74.93,21.81 RN1801.1
  TOP w0.508: R2472.2 162.28,3.26 v2(162.96,3.26) ; v2(166.39,2.37) 167.84,2.37 C2503.1 168.22,3.55 167.62,4.15 D2501.3 ; R2106.1 75.18,21.6 75.56,21.22 v1(75.56,19.24) 75.56,19.12 v2(74.95,18.5)
  L3 w0.508: v2(23.98,2.54) 23.18,3.34 23.18,7.76 19.81,11.14 19.81,12.53 17.8,14.54 v2(16.89,14.54)
  L4 w0.508: v2(64.41,1.48) 64.55,1.63 79.94,1.63 80.46,2.15 83.31,2.15 83.84,1.61 103.91,1.61 110.9,8.6 115.43,8.6 116.45,7.58 123.94,7.58 125.88,9.51 133.07,9.51 136.14,6.44 141.01,6.44 142.54,4.91 160.62,4.91 160.7,4.84 161.95,4.84 162.96,3.83 v2(162.96,3.26)
  L6 w0.254: v2(74.95,18.5) 76.14,18.5 81.53,23.9 82.85,23.9 83.03,23.71 83.54,23.71 89.16,29.32 92.25,29.32 v2(92.86,29.93)
  L6 w0.508: v2(64.41,1.48) 63.27,1.48 62.5,2.25 55.55,2.25 54.82,1.52 49.79,1.52 49.77,1.54 47.98,1.54 47.98,1.54 45.94,1.54 45.3,2.18 38.94,2.18 38.87,2.25 38.62,2.5 33.68,2.5 32.79,1.61 24.91,1.61 v2(23.98,2.54)
  BOTTOM w0.508: v2(166.39,2.37) 166.39,2.14 165.89,1.64 165.36,1.64 164.99,2.01 164.99,2.13 164.24,2.88 163.34,2.88 v2(162.96,3.26) ; v2(74.95,18.5) 74.95,13.68 74.06,12.79 64.79,12.79 64.41,12.41 v2(64.41,1.48)
RTC_DET#: length 134.4
  TOP w0.102: v2(118.54,25.49) 118.54,25.46 119.15,24.85 123.33,24.85 126.7,21.48 126.71,21.48 127.21,20.97 127.69,20.97 129.53,19.13 129.53,14.85 130.2,14.18 132.97,14.18 133.3,13.86 133.3,12.69 134.68,11.3 134.96,11.03 135.64,10.35 135.64,9.11 137.47,7.29 137.47,5.36 v2(137.64,5.19) ; Q2505.D 176.68,5.04 v1(178.9,2.82) 179.45,2.27 192.7,2.27 193.12,2.69 193.12,4.6 193.31,4.79 v2(193.31,11.01)
  L6 w0.102: v2(137.64,5.19) 138.79,6.35 140.82,6.35 141.67,5.5 144.38,5.5 145.13,6.25 145.13,7 145.43,7.3 149.57,7.3 150.3,8.04 156.8,8.04 157.25,7.58 159.95,7.58 160.66,8.29 164.09,8.29 164.29,8.09 167.85,8.09 169.6,9.84 180.81,9.84 181.04,10.07 192.37,10.07 v2(193.31,11.01)
  BOTTOM w0.102: R2040.2 118.43,25.41 118.51,25.49 v2(118.54,25.49) 118.54,25.51 118.76,25.74 119.65,25.74 120.4,26.48 120.44,26.48 121.18,27.23 121.48,27.23 122.59,28.34 122.59,32.15 123.42,32.98 123.42,34.39 CPU1.P1
RTC_RST#: length 72.1
  TOP w0.127: v2(71.14,17.23) 71.14,19.14 v1(71.39,19.39) 71.42,19.42 EC1807.1 C1806.1 71.53,22.46 RN1801.3 73.91,23.28 Q1802.D
  L3 w0.127: v2(71.14,17.23) 71.27,17.11 74.57,17.11 77.19,19.72 81.08,19.72 87.25,25.89 88.93,25.89 89.38,25.45 94.03,25.45 95.84,27.26 95.84,27.94 96.22,28.31 100.43,28.31 103.52,31.4 103.93,31.4 105.97,31.4 108.95,34.38 108.95,42.67 110.18,43.91 113.71,43.91 v2(114.13,43.49)
  BOTTOM w0.127: CPU1.AM16 114.45,43.81 v2(114.13,43.49) ; v2(71.14,17.23) 70.76,16.85 G1801.2
RTC_X1: length 35.9
  TOP w0.089: v1(114.06,44.41) v2(113.49,44.42)
  L4 w0.127: v2(103.63,20.51) 103.78,20.66 103.78,23.53 103.01,24.3 103.01,31.2 104.22,32.41 104.22,32.68 104.84,33.29 104.84,33.7 105.3,34.17 105.32,34.17 106.14,35 106.14,35.55 106.65,36.06 107.25,36.06 108.12,36.93 108.12,41.42 109.07,42.36 109.07,43.17 110.72,44.83 113.08,44.83 v2(113.49,44.42)
  BOTTOM w0.089: v2(113.49,44.42) 114.01,44.42 CPU1.AM18 ; v2(103.63,20.51) 103.86,20.28 C1804.2 103.91,19.7 R1815.1 105.81,19.7 X1802.1
RTC_X2: length 38.9
  TOP w0.089: v2(103.53,18.25) 103.89,17.88 v1(104.01,17.88)
  L4 w0.127: v2(113.48,46.21) 113.05,45.78 111.36,45.78 108.61,43.02 108.61,42.21 107.91,41.51 107.91,37.02 107.16,36.27 106.56,36.27 105.93,35.64 105.93,35.09 105.23,34.38 105.21,34.38 102.5,31.67 102.5,23.9 103.17,23.23 103.17,18.6 v2(103.53,18.25)
  BOTTOM w0.089: X1802.4 105.81,18.83 R1815.2 103.91,18.83 C1803.2 103.86,18.58 v2(103.53,18.25) ; v2(113.48,46.21) 114.15,46.21 114.45,45.91 CPU1.AM20
RTCRST_ON: length 105.8
  TOP w0.089: KBC24.31 157.54,21.38 157.12,21.8 v2(157.12,21.81) ; v2(83.21,10.37) 83.21,12.66 82.07,13.79 82.07,17.36 83.78,19.06 83.78,24.4 81.85,26.33 v1(78.51,26.33) R1816.1 76.58,26.3 EC1808.1 75.84,25.73 Q1802.G
  L3 w0.089: v2(83.21,10.37) 84.29,10.37 85.19,11.28 87.37,11.28 87.94,11.85 92.78,11.85 94.14,11.85 95.74,13.45 106.74,13.45 107.8,14.52 122.28,14.52 122.69,14.1 126.3,14.1 132.48,20.28 136.25,20.28 137.52,21.55 146.31,21.55 146.98,20.88 156.19,20.88 v2(157.12,21.81)
RUNPWROK: length 278.3
  TOP w0.089: KBC24.48 150.84,22.16 v2(151.12,21.88)
  L3 w0.089: v2(211.09,68.67) 211.09,68.42 211.56,67.96 211.56,66.37 213.96,63.97 213.96,60.83 216.99,57.8 216.99,54.52 218.36,53.15 218.36,50.84 220.03,49.16 220.03,41.74 220.34,41.44 220.34,35.4 219.86,34.92 219.86,31.71 219.48,31.33 219.48,25.92 221.51,23.89 221.51,20.38 221.81,20.08 221.81,18.74 220.68,17.61 218.45,17.61 214.69,13.85 210.1,13.85 207.5,11.25 197.19,11.25 195.49,12.95 192.92,12.95 176.87,12.95 167.51,22.31 151.56,22.31 v2(151.12,21.88)
  L4 w0.089: v2(120.64,96.18) 120.64,94.35 126.51,88.48 134.49,88.48 136.65,86.32 142.82,86.32 144.67,88.18 144.67,90 145.64,90.98 146.63,90.98 146.72,91.06 150.34,91.06 151.15,90.26 151.9,90.26 153.36,88.8 154.01,88.8 154.58,88.22 154.58,87.76 155.07,87.27 155.52,87.27 157.48,85.31 159.02,85.31 159.28,85.05 159.28,79.07 160.81,77.54 165.65,77.54 168.06,75.13 171.13,75.13 172.61,76.61 174.96,76.61 176.8,78.45 176.8,81.3 178.29,82.78 180.5,82.78 182.73,80.54 184.94,80.54 187.51,77.98 189.43,77.98 190.91,76.5 198.83,76.5 200.54,74.79 205.39,74.79 206.23,73.95 207.59,73.95 208.68,72.86 208.68,72.22 210.22,70.69 210.22,69.42 210.97,68.67 v2(211.09,68.67)
  BOTTOM w0.089: D4003.A 157.08,20.41 156.61,20.41 156.03,19.82 R4002.1 R4011.2 154.45,20.28 154.13,20.6 153.36,20.6 153.24,20.71 152.33,20.71 D4002.A 151.83,21.21 151.82,21.21 151.15,21.88 v2(151.12,21.88) 151.12,22.52 R4005.2 ; v2(120.64,96.18) 122.32,94.5 122.32,89.4 121.08,88.15 v1(121.08,86.55) 121.99,85.64 EC1709.1 122.02,84.64 R1716.1
SA0_CHA_DIM0: length 5.5
  TOP w0.089: R1204.1 R1205.1 63.94,21.31 v2(63.94,20.62) 63.94,20.62 63.65,20.92 63.17,20.92 v1(62.92,20.66)
  BOTTOM w0.089: DM1.256 63.74,20.82 63.94,20.62 v2(63.94,20.62)
SA0_CHB_DIM0: length 5.3
  TOP w0.089: v1(51.07,20.41) 51.2,20.41 v2(51.58,20.79) R1302.1 R1303.1
  BOTTOM w0.089: DM2.256 51.55,20.82 v2(51.58,20.79)
SA1_CHA_DIM0: length 6
  TOP w0.089: R1208.1 64.62,20.66 v2(64.58,20.62) 64.41,20.45 R1210.1 64.46,19.77 v1(65.3,19.77)
  BOTTOM w0.089: v2(64.58,20.62) 63.59,19.63 62.95,19.63 62.76,19.82 DM1.260
SA1_CHB_DIM0: length 9.5
  TOP w0.089: v2(47.29,22.39) 47.29,22.41 v1(48.46,23.58) 50.87,23.58 R1307.1 R1306.1
  BOTTOM w0.089: DM2.260 47.85,19.82 47.58,20.09 47.58,22.1 v2(47.29,22.39)
SA2_CHA_DIM0: length 4.6
  TOP w0.089: v1(60.22,44.66) 60.22,44.41 v2(59.96,44.16) 59.96,43.52 R1211.1 61.01,43.32 R1212.1
  BOTTOM w0.089: DM1.166 60.58,43.32 59.96,43.94 v2(59.96,44.16)
SA2_CHB_DIM0: length 5
  TOP w0.089: v1(45.74,43.14) 46.27,43.14 v2(46.4,43.27) 46.38,43.29 R1311.1 46.35,44.06 R1310.1
  BOTTOM w0.089: v2(46.4,43.27) 46.86,43.73 47.44,43.73 47.84,43.32 DM2.166
SATA_LED#: length 105.2
  TOP w0.089: v1(127.79,32.8) 127.51,32.8 v2(127.23,33.08)
  L3 w0.089: v2(124.05,25.82) 124.91,24.95 124.91,22.08 122.5,19.66 118.09,19.66 116.56,18.13 113.87,18.13 113.18,18.82 103.49,18.82 101.94,17.27 94.89,17.27 94.23,16.61 91.2,16.61 89.57,14.98 85,14.98 83.89,13.87 80.89,13.87 77.99,10.97 74.49,10.97 71.11,7.59 60.61,7.59 59.08,6.05 59.08,5.96 58.74,5.63 58.39,5.63 58.03,5.99 54.6,5.99 53.54,7.05 49.83,7.05 49.05,6.27 49.05,6.26 v2(48.84,6.05)
  BOTTOM w0.089: Q6105.S 47.92,5.11 48.84,6.03 v2(48.84,6.05) ; CPU1.H1 126.54,34.14 126.82,33.86 126.82,33.48 v2(127.23,33.08) 128.93,31.38 128.93,28.66 127.4,27.14 124.93,27.14 124.05,26.26 v2(124.05,25.82) 123.97,25.74 R1606.2
SATA_RX_CPU_N0: length 127.9
  L4 w0.089: 125.64,36.94 125.55,37.03 125.52,37.03 125.27,37.28 125.27,41.75 125.89,42.37 125.89,46.48 126.22,46.81 127.77,46.81 127.92,46.65 127.92,46.49 127.73,46.3 127.67,46.3 v2(127.67,46.3)
  L4 w0.14: 125.64,36.94 126.34,36.24 128.83,36.24 130.84,34.23 130.84,28.81 129.7,27.66 129.7,24.58 131.19,23.09 137.29,23.09 139.5,20.87 139.5,19.58 144.93,14.15 148.12,14.15 167.26,14.15 169.69,11.72 186.59,11.72 188.09,10.22 188.87,10.22 189.15,10.5 189.31,10.7 189.31,10.8 189.28,10.91 189.17,10.98 v2(188.84,10.91)
  BOTTOM w0.102: v2(188.84,10.91) 188.64,10.91 188.51,10.78 188.51,10.53 188.64,10.4 189.2,10.4 189.33,10.53 189.33,11.06 189.4,11.14 189.4,11.87 189,12.28 187.52,12.28 187.07,11.82 187.07,7.55 187.82,6.79 194.49,6.79 197.18,9.49 203.12,9.49 203.78,8.83 205,8.83 ; v2(127.67,46.3) 127.73,45.99 127.67,45.87 127.57,45.78 CPU1.F20 ; v1(205,9.02) 205,8.83 ; 205,8.83 205.28,8.83 C6006.1
SATA_RX_CPU_N2: length 121
  L4 w0.14: v2(128.26,51.73) 128.26,52.08 128.19,52.16 128,52.16 127.92,52.23 127.92,52.56 128.17,52.81 128.61,52.81 129.38,53.58 130.93,53.58 132.35,55 137.72,55 139.58,53.15 142.42,53.15 143.44,52.12 143.44,36.22 145.44,34.22 145.44,31.5 148.53,28.41 150.26,28.41 153.57,25.11 165.46,25.11 165.84,24.73 176.5,24.73 176.63,24.6 202.33,24.6 202.39,24.66 203.92,24.66 204.27,25.02 204.94,25.02 205.4,24.56 205.4,24.36 205.23,24.19 v2(205.22,24.19)
  BOTTOM w0.102: 205.13,21.3 205.13,19.39 206.48,18.03 209.28,18.03 210.07,17.25 212.52,17.25 212.63,17.14 ED6301.4 ED6301.7 213.98,17.14 213.99,17.15 SSD1.43 ; 205.13,21.3 205.13,22.82 205.56,23.25 205.56,23.76 205.51,23.81 205.3,23.81 205.22,23.9 v2(205.22,24.19) ; 205.13,21.3 v1(204.97,21.3) ; v2(128.26,51.73) 128.26,51.98 128.07,52.18 CPU1.E30
SATA_RX_CPU_P0: length 127.7
  L4 w0.089: 125.45,36.75 125.44,36.77 125.44,36.84 125.43,36.85 125.43,36.85 125.08,37.2 125.08,41.83 125.7,42.45 125.7,46.56 126.14,47 127.85,47 128.06,46.79 128.11,46.73 v2(128.35,46.3)
  L4 w0.14: 125.45,36.75 126.07,36.13 126.23,35.98 128.72,35.98 130.58,34.12 130.58,28.92 129.43,27.77 129.43,24.47 131.08,22.82 137.18,22.82 139.24,20.76 139.24,19.46 144.82,13.88 148.23,13.88 167.15,13.88 169.58,11.45 186.48,11.45 187.98,9.96 188.98,9.96 189.42,10.39 v2(189.76,10.88)
  BOTTOM w0.102: v2(189.76,10.88) 189.63,11.01 189.63,11.97 189.09,12.51 187.43,12.51 186.84,11.92 186.84,7.45 187.73,6.56 189.38,6.56 ; CPU1.E20 v2(128.35,46.3) ; 189.38,6.56 194.58,6.56 197.28,9.26 203.03,9.26 203.69,8.6 C6005.1 ; 189.38,6.56 v1(189.38,6.39)
SATA_RX_CPU_P2: length 121.3
  L4 w0.14: v2(127.63,51.73) 127.66,51.75 127.66,52.67 128.06,53.07 128.5,53.07 129.27,53.85 130.82,53.85 132.24,55.27 137.83,55.27 139.69,53.42 142.53,53.42 143.71,52.23 143.71,36.33 145.7,34.33 145.7,31.62 148.64,28.68 150.38,28.68 153.68,25.37 165.57,25.37 165.95,24.99 176.61,24.99 176.74,24.87 202.22,24.87 202.28,24.93 203.81,24.93 204.16,25.28 205.05,25.28 205.91,24.42 v2(205.91,24.17)
  BOTTOM w0.102: v2(205.91,24.17) 205.79,24.04 205.79,23.16 205.35,22.73 205.35,19.98 ; v1(205.53,19.98) 205.35,19.98 ; 205.35,19.98 205.35,19.49 206.58,18.26 209.37,18.26 210.16,17.48 211.94,17.48 ; SSD1.41 213.99,17.65 213.98,17.64 ED6301.6 ED6301.5 212.68,17.64 212.52,17.48 211.94,17.48 ; CPU1.F30 v2(127.63,51.73) ; v1(211.94,17.65) 211.94,17.48
SATA_RXN0_R: length 26.7
  BOTTOM w0.102: 211.53,8.97 211.94,8.97 214.83,6.08 217.16,6.08 217.7,5.55 217.7,4.08 218.38,3.39 227.22,3.39 227.48,3.64 227.48,4.88 227.3,5.05 HDD1.18 ; 211.53,8.97 v1(211.53,9.16) ; 211.53,8.97 209.08,8.97 208.81,9.24 ED6001.4 ED6001.7 206.84,9.24 C6006.2
SATA_RXP0_R: length 26.9
  BOTTOM w0.102: C6005.2 206.87,8.74 ED6001.6 ED6001.5 209.87,8.74 ; 209.87,8.74 211.85,8.74 214.74,5.85 217.07,5.85 217.47,5.45 217.47,3.98 218.29,3.16 227.32,3.16 227.71,3.55 227.71,4.96 227.8,5.05 HDD1.19 ; 209.87,8.74 v1(209.87,8.55)
SATA_TX_CPU_N0: length 124.7
  L4 w0.089: 124.9,37.06 124.9,37.07 124.86,37.12 124.86,39.58 124.87,39.6 124.87,41.88 125.47,42.48 125.47,46.77 125.99,47.3 128.25,47.3 128.77,46.78 132.04,46.78 132.28,47.02 132.28,47.19 v2(132.51,47.41)
  L4 w0.14: v2(191.12,11.01) 191.12,10.44 189.78,9.1 188.09,9.1 186.26,10.93 169.36,10.93 167.39,12.9 145.06,12.9 138.72,19.25 138.72,20.52 136.97,22.26 130.75,22.26 128.91,24.1 128.91,28.24 129.19,28.52 129.19,28.74 129.19,34.72 128.53,35.39 125.77,35.39 124.9,36.25 124.9,37.06
  BOTTOM w0.089: v2(132.51,47.41) 131.81,46.71 130.32,46.71 CPU1.B21
  BOTTOM w0.102: C6003.1 204.97,10.88 204.29,10.2 204.01,10.2 ; 204.01,10.2 v1(204.01,10.37) ; 204.01,10.2 197.43,10.2 195.14,12.48 191.64,12.48 191.12,11.97 v2(191.12,11.01)
SATA_TX_CPU_N2: length 112.1
  L4 w0.14: v2(204.52,24.17) 203.75,23.41 202.2,23.41 202,23.61 197.79,23.61 196.65,22.47 178.05,22.47 177.7,22.81 175.79,22.81 174.66,23.94 151.89,23.94 144.65,31.18 144.65,33.9 142.64,35.91 142.64,51.81 142.1,52.35 139.26,52.35 137.4,54.22 132.87,54.22 132.02,53.36 132.02,52.86 v2(132.3,52.58)
  BOTTOM w0.102: 204.24,22.47 204.24,19.14 206.09,17.28 207.41,17.28 C6303.2 ; 204.24,22.47 204.24,23.89 v2(204.52,24.17) ; 204.24,22.47 v1(204.41,22.47) ; v2(132.3,52.58) 131.97,52.25 131.97,50.95 130.68,49.65 130.68,49.48 CPU1.A25
SATA_TX_CPU_N2_C: length 7.6
  BOTTOM w0.102: v1(211.86,16.18) 211.86,16 ; 211.86,16 210.39,16 209.11,17.28 208.86,17.28 C6303.1 ; 211.86,16 212.5,16 212.64,16.14 ED6301.2 ED6301.9 213.98,16.14 213.99,16.15 SSD1.47
SATA_TX_CPU_P0: length 124.8
  L4 w0.089: v2(131.87,47.41) 132.09,47.19 132.09,47.1 131.96,46.97 128.85,46.97 128.33,47.49 125.91,47.49 125.28,46.85 125.28,42.56 124.68,41.96 124.68,39.67 124.66,39.66 124.66,37.11 124.64,37.08 124.64,37.06
  L4 w0.14: 124.64,37.06 124.64,36.14 125.65,35.12 128.42,35.12 128.93,34.61 128.93,28.63 128.65,28.35 128.65,23.99 130.64,22 136.86,22 138.45,20.41 138.45,19.14 144.95,12.64 167.28,12.64 169.25,10.67 186.15,10.67 187.98,8.84 189.89,8.84 191.97,10.91 v2(191.97,11.01)
  BOTTOM w0.089: v2(131.87,47.41) 131.87,47.04 131.73,46.9 130.78,46.9 CPU1.A21
  BOTTOM w0.102: v2(191.97,11.01) 191.74,11.01 191.35,11.4 191.35,11.87 191.73,12.25 195.05,12.25 196.29,11.01 ; 196.29,11.01 197.33,9.97 204.38,9.97 205.07,10.65 205.38,10.65 205.81,10.22 C6001.1 ; 196.29,11.01 v1(196.18,10.91)
SATA_TX_CPU_P2: length 112.3
  L4 w0.14: v2(203.73,24.17) 203.73,23.86 203.54,23.67 202.31,23.67 202.11,23.87 197.9,23.87 197.68,23.88 196.53,22.73 178.16,22.73 177.81,23.08 175.9,23.08 174.77,24.21 152,24.21 144.92,31.29 144.92,34.01 142.91,36.02 142.91,51.92 142.21,52.62 139.37,52.62 137.51,54.48 132.76,54.48 131.75,53.47 131.75,52.66 v2(131.67,52.58)
  BOTTOM w0.102: 204.01,20.48 204.01,23.89 v2(203.73,24.17) ; 204.01,20.48 204.01,19.04 206,17.06 207.41,17.06 C6302.2 ; 204.01,20.48 v1(203.83,20.48) ; v2(131.67,52.58) 131.74,52.5 131.74,51.04 130.15,49.45 CPU1.B25
SATA_TX_CPU_P2_C: length 7.6
  BOTTOM w0.102: 209.59,16.48 v1(209.48,16.36) ; 209.59,16.48 210.3,15.77 212.5,15.77 212.64,15.64 ED6301.1 ED6301.10 213.98,15.64 213.99,15.65 SSD1.49 ; 209.59,16.48 209.01,17.06 208.86,17.06 C6302.1
SATA_TXN0_R: length 23.3
  BOTTOM w0.102: 213.01,8.91 211.18,10.74 ED6001.1 ED6001.10 206.87,10.74 C6003.2 ; 213.01,8.91 v1(213.15,9.05) ; 213.01,8.91 215.13,6.79 217.98,6.79 218.29,7.1 222.48,7.1 222.91,7.53 225.95,7.53 226.3,7.18 HDD1.16
SATA_TXP0_R: length 23.1
  BOTTOM w0.102: 210.61,10.51 209.08,10.51 208.81,10.24 ED6001.2 ED6001.9 206.84,10.24 C6001.2 ; 210.61,10.51 211.08,10.51 215.03,6.56 218.08,6.56 218.39,6.87 222.58,6.87 223.01,7.3 225.86,7.3 226.07,7.09 226.07,6.92 225.8,6.65 HDD1.15 ; 210.61,10.51 v1(210.61,10.32)
SD_RCOMP: length 2.1
  TOP w0.152: v2(118.95,38.46) 118.87,38.46 v1(118.51,38.82)
  TOP w0.254: R1901.1 119.53,37.93 119,38.46 v2(118.95,38.46)
  BOTTOM w0.254: CPU1.AB7 119,38.46 v2(118.95,38.46)
SENSOR_I2C_SCL: length 314.9
  TOP w0.089: v2(215.69,58.28) 215.41,58.56 R7014.1 ; v2(139.34,1.48) 138.38,2.44 137.56,2.44 136.6,3.4 136.6,7.01 134.78,8.83 134.78,10.07 133.72,11.13 129.07,11.13 128.6,11.59 128.6,18.92 127.36,20.16 126.88,20.16 126.37,20.67 v1(124.79,20.67) 124.5,20.67 123.43,21.74 121.3,21.74 v2(120.76,21.2)
  L3 w0.127: v2(70.86,98.77) 71.39,98.23 71.39,96.87 70.9,96.38 70.9,95.35 70.91,95.35 70.91,94.04 71.38,93.57 71.38,89.93 71.76,89.55 71.76,89.29 v2(72.28,88.76) ; v2(120.76,21.2) 120.35,21.61 117.14,21.61 115.26,19.73 103.18,19.73 102.97,19.52 101.58,18.13 93.91,18.13 v2(93.8,18.02)
  L4 w0.127: v2(217.93,52.97) 217.39,53.51 217.39,54.36 217.08,54.67 217.08,57.35 216.15,58.28 v2(215.69,58.28)
  L6 w0.102: v2(139.34,1.48) 140.48,2.63 143.58,2.63 143.65,2.56 144.7,2.56 144.71,2.57 149.97,2.57 150.43,3.02 150.86,3.02 151.1,2.78 156.52,2.78 157.54,3.81 162.86,3.81 163.43,4.38 167.28,4.38 169.09,2.57 193.85,2.57 198.83,7.55 203.62,7.55 206.17,10.1 212.11,10.1 215.36,6.84 224.96,6.84 226.39,8.27 226.39,22.82 226.61,23.05 226.61,27.02 223.95,29.68 223.86,29.68 222.17,31.36 222.17,33.62 222.24,33.69 222.24,35.39 221.81,35.82 221.81,37.25 222.24,37.68 222.24,43.22 220.82,44.64 220.82,47.41 220.14,48.1 220.14,49.56 219.48,50.22 219.48,51.4 219.35,51.53 217.93,52.95 v2(217.93,52.97)
  BOTTOM w0.089: v2(72.28,88.76) 73.54,87.5 73.54,85.37 73.65,85.27 73.65,85.26 85.2,73.71 85.2,26.8 85.96,26.04 85.96,19.98 84.96,18.98 84.96,17.54 85.27,17.24 88.54,17.24 90.08,18.78 93.32,18.78 93.8,18.3 v2(93.8,18.02) ; R2020.2 120.64,21.32 v2(120.76,21.2) ; TCBD1.4 71.55,98.08 v2(70.86,98.77)
SENSOR_I2C_SCL_2G: length 5.1
  TOP w0.089: U7001.1 213.17,60.37 213.46,60.08 R7014.2 215.41,60.59 216,61.17 v1(216,61.43)
SENSOR_I2C_SDA: length 313.9
  TOP w0.089: v2(215.74,57.61) 216.17,58.04 R7015.1 ; v2(138.7,1.48) 138.01,2.18 137.45,2.18 136.34,3.29 136.34,6.9 134.51,8.72 134.51,9.96 133.61,10.86 128.95,10.86 128.33,11.48 128.33,18.75 127.23,19.85 126.81,19.85 126.43,20.23 124.15,20.23 v1(123.57,20.81) 123.14,21.24 v2(122.39,21.24)
  L3 w0.127: v2(71.65,88.73) 71.38,89.01 71.38,89.39 70.99,89.77 70.99,93.42 70.52,93.89 70.52,96.53 70.84,96.85 v2(70.84,98.11) ; v2(91.97,18.12) 92.53,18.69 99.67,18.69 102.09,21.11 104.12,21.11 104.41,20.82 105.12,20.12 115.1,20.12 116.98,22 121.63,22 v2(122.39,21.24)
  L4 w0.127: v2(217.93,52.34) 217.01,53.26 217.01,53.99 216.74,54.25 216.59,54.25 216.2,54.64 215.74,55.11 v2(215.74,57.61)
  L6 w0.102: v2(138.7,1.48) 138.7,1.61 140.03,2.93 143.71,2.93 143.77,2.87 143.78,2.87 143.79,2.86 144.57,2.86 144.58,2.87 149.84,2.87 150.3,3.33 151.36,3.33 151.61,3.09 156.39,3.09 157.42,4.11 162.73,4.11 163.3,4.69 167.41,4.69 169.18,2.91 173.35,2.91 175.13,4.69 191.71,4.69 192.43,3.97 194.83,3.97 198.7,7.85 203.49,7.85 206.04,10.4 212.23,10.4 215.49,7.15 224.84,7.15 226.08,8.39 226.08,22.95 226.31,23.18 226.31,26.89 223.82,29.38 223.73,29.38 221.87,31.24 221.87,33.75 221.94,33.82 221.94,35.26 221.51,35.69 221.51,37.38 221.94,37.81 221.94,43.09 220.52,44.51 220.52,47.29 219.83,47.97 219.83,49.44 219.17,50.1 219.17,51.07 218.36,51.88 217.93,52.31 v2(217.93,52.34)
  BOTTOM w0.089: v2(122.39,21.24) 121.73,21.9 R2021.2 ; v2(91.97,18.12) 89.81,18.12 88.66,16.97 85.15,16.97 84.7,17.43 84.7,19.09 85.69,20.09 85.69,25.93 84.93,26.69 84.93,73.59 73.38,85.15 73.38,85.15 73.27,85.26 73.27,87.11 v2(71.65,88.73) ; TCBD1.3 71.05,97.89 v2(70.84,98.11)
SENSOR_I2C_SDA_2G: length 8.3
  TOP w0.089: U7001.4 212.67,61.98 213.05,62.37 213.05,63.23 213.46,63.64 214.73,63.64 v1(215.49,62.88) 216.45,61.91 216.45,60.36 R7015.2
SERIRQ_TPM: length 3.1
  TOP w0.089: U9101.27 214.61,30.45 v1(214.04,29.88) 214.32,29.6 R9148.1
SIO_EXT_SCI#: length 15
  BOTTOM w0.089: CPU1.J2 126.01,35.44 126.01,35.19 126.1,35.09 126.15,34.94 126.15,33.87 126.41,33.61 126.41,32.9 v1(127.94,31.37) 128.54,30.77 128.54,29.04 127.26,27.76 125,27.76 123.21,25.97 R1608.2
SIO_EXT_SMI#: length 17.1
  L4 w0.089: v2(126.64,28.28) 126.64,29.58 124.86,31.36 124.86,34.24 124.41,34.7 124.41,37.72 v2(124.2,37.93)
  BOTTOM w0.089: CPU1.L6 v2(124.2,37.93) ; v2(126.64,28.28) v1(125.75,28.28) 124.99,28.28 122.45,25.74 R802.1
SIO_EXT_WAKE#: length 77.3
  TOP w0.089: v2(151.91,6.67) 152.04,6.8 KBC24.116
  L4 w0.089: v2(151.91,6.67) 151.36,7.22 147.29,7.22 147.26,7.24 146.71,7.24 146.5,7.45 142.09,7.45 141.63,7.92 139.61,7.92 136.81,10.73 136.81,14.72 135.68,15.85 127.18,15.85 125.65,14.32 118.9,14.32 117.93,15.28 113.35,15.28 v2(113.3,15.33)
  BOTTOM w0.089: v2(113.3,15.33) 113.94,15.96 v1(113.94,16) 113.94,17.36 114.37,17.79 R2041.2 114.85,18.15 114.22,18.15 113.81,18.55 113.81,20.25 113.07,20.99 112.53,20.99 111.5,22.02 111.5,28.38 110.76,29.11 110.76,30.11 112.16,31.5 112.53,31.5 112.76,31.73 116.63,31.73 117.74,32.85 117.74,34.65 117.66,34.73 117.66,35.93 CPU1.AD3
SIO_PWRBTN#: length 99.6
  TOP w0.089: KBC24.52 149.24,22.5 149.06,22.31 149.06,21.66 150.21,20.51 v2(150.21,18.25) ; v2(104.77,42.79) 104.34,43.21 103.83,43.21 v1(103.69,43.07)
  L3 w0.089: v2(134.13,17.11) 134.62,17.11 136.57,19.06 138.25,19.06 139.74,20.56 145.79,20.56 147.09,19.26 149.19,19.26 v2(150.21,18.25)
  L4 w0.089: v2(134.13,17.11) 133.88,16.86 126.65,16.86 125.79,15.99 118.8,15.99 117.68,17.11 112.1,17.11 111.65,16.66 109.56,16.66 109.37,16.85 100.74,16.85 100.11,17.48 97.69,17.48 94.78,20.39 94.78,31.75 97.53,34.5 97.53,36.23 98.14,36.84 99.74,36.84 100.99,38.09 100.99,38.09 103.4,40.5 103.4,41.41 v2(104.77,42.79)
  BOTTOM w0.089: v2(104.77,42.79) 105,42.56 105.56,42.56 105.79,42.79 105.79,43.1 106.03,43.34 106.47,43.34 106.74,43.07 108.19,43.07 108.55,43.43 CPU1.BA15
SIO_RCIN#: length 22
  TOP w0.089: R1820.2 100.65,36.13 101.09,35.7 101.54,35.7 v1(102.13,35.11) 103.19,35.11 104.3,34 106.24,34 106.86,34.63 106.89,34.63 v2(107.46,35.2)
  L4 w0.127: v2(107.46,35.2) 108.03,35.2 108.53,35.7 108.53,41.07 110.71,43.25 v2(110.71,43.44)
  BOTTOM w0.089: v2(110.71,43.44) 110.74,43.4 110.74,42.79 110.15,42.2 CPU1.AW13
SIO_SLP_S0#: length 224.5
  TOP w0.127: R9142.2 215.21,27.77 212.75,27.77 v2(212.69,27.71) ; v2(91.66,22.24) 92.08,21.82 92.08,21.37 91.08,20.36 91.08,17.26 94.4,13.94 94.4,12.41 92.88,10.9 92.88,10.29 92.21,9.61 92.21,8.74 92.48,8.47 93.62,8.47 94.13,7.96 94.13,5.17 92.86,3.9 92.12,3.9 v2(91.64,3.42) 92.33,2.72 93.39,2.72 93.87,2.24 93.87,1.61 93.62,1.36 83.59,1.36 82.96,1.98 82.96,4.74 83.23,5 83.4,5 83.81,5.42 83.81,6.72 82.32,8.22 U4007.2 ; v2(112.18,41.66) v1(111.15,41.66) 109.68,41.66 108.96,40.95 107.24,40.95 105.63,39.33 104.52,39.33 103.33,40.52 v2(102.28,40.52) ; R2478.1 138.91,12.61 v2(139.34,13.04)
  L3 w0.127: v2(139.34,13.04) 139.29,13.09 v2(135.28,13.09)
  L4 w0.127: v2(91.64,3.42) 91.69,3.42 92.59,2.51 103.54,2.51 110.52,9.5 124.56,9.5 125.5,10.44 132.1,10.44 133.53,11.87 133.53,13.12 133.75,13.35 135,13.35 135.25,13.09 v2(135.28,13.09) ; v2(91.66,22.24) 91.66,22.26 93.43,24.03 93.43,28.76 94.13,29.46 94.13,31.79 96.79,34.46 96.79,36.41 98.22,37.84 98.78,37.84 101.46,40.52 v2(102.28,40.52)
  L6 w0.127: v2(212.69,27.71) 212.69,27.48 213.25,26.92 213.25,21.85 210.33,18.92 207.38,18.92 207.09,19.2 190.28,19.2 189.71,18.63 179.98,18.63 178.96,17.61 178.96,17.05 176.82,14.9 148.46,14.9 147.51,13.94 140.24,13.94 v2(139.34,13.04)
  BOTTOM w0.127: CPU1.AT11 111.85,41.34 v2(112.18,41.66)
SIO_SLP_S3#: length 404.7
  TOP w0.127: 81.69,5.16 81.12,5.73 R4017.1 79.89,5.73 D4004.K ; 81.69,5.16 81.8,5.26 83.29,5.26 83.56,5.53 83.56,6.61 82.61,7.57 v2(82.05,7.57) U4007.1 ; 81.69,5.16 81.69,3.53 82.32,2.91 82.32,1.82 v2(82.62,1.51) ; v2(212.87,48.22) 212.62,48.22 212.35,48.49 212.35,48.85 209.89,51.32 206.51,51.32 205.29,50.1 205.29,48.25 204.91,47.88 D4005.K 204.07,47.84 R4010.1 ; v2(59.76,1.61) 61.74,3.59 61.74,7.45 58.88,10.31 58.88,13.23 61.11,15.45 v2(61.11,16) ; v1(20.77,36.18) 21.04,35.92 Q2701.G 21.04,33.81 21.8,33.04 24.59,33.04 v2(24.79,32.85) ; v2(163.34,24.66) 163.34,24.09 163.15,23.9 162.82,23.9 R2479.1 164.63,23.58 165.68,22.53 165.68,17.97 169.34,14.31 169.34,13.58 v2(169.49,13.42)
  L3 w0.127: v2(82.62,1.51) 82.44,1.33 75.63,1.33 74.57,1.33 74.54,1.36 65.39,1.36 64.76,1.99 60.14,1.99 v2(59.76,1.61) 59.48,1.33 44.87,1.33 44.21,1.99 39.06,1.99 38.14,2.91 38.14,9.39 32.83,14.69 30.63,14.69 29.61,13.68 27.75,13.68 26.46,14.98 26.46,22.6 25.44,23.61 25.44,28.52 24.28,29.68 24.28,32.35 v2(24.79,32.85) ; v2(61.11,16) 62.21,17.11 67.84,17.11 68.47,16.47 72.41,16.47 72.73,16.79 74.64,16.79 77.32,19.47 81.19,19.47 87.36,25.64 88.83,25.64 89.27,25.2 97.9,25.2 99.52,26.82 99.8,26.82 104.13,31.15 106.07,31.15 109.32,34.39 109.32,40.96 111.37,43.01 112.35,43.01 v2(112.83,43.49) ; v2(169.49,13.42) 169.49,13.52 168.32,14.69 159.19,14.69 158.97,14.92 149.98,14.92 149.01,15.89 143.73,15.89 143.21,16.41 136.86,16.41 135.07,14.62 134.17,14.62 133.57,14.01 133.57,12.9 v2(132.87,12.2)
  L4 w0.127: v2(82.05,7.57) 83.75,9.27 88.17,9.27 89.14,10.24 94.8,10.24 96.77,8.27 108.26,8.27 110.57,10.58 114.92,10.58 115.46,11.12 116.58,11.12 116.78,10.92 131.58,10.92 v2(132.87,12.2)
  L6 w0.127: v2(169.49,13.42) 169.9,13.83 177.33,13.83 180.92,17.42 187.96,17.42 189.61,15.77 193.94,15.77 195.73,17.55 195.73,17.86 196.15,18.28 205.76,18.28 206.01,18.03 210.68,18.03 214.21,21.56 214.21,29.79 213.11,30.88 213.11,33.47 212.73,33.86 212.73,39.28 213.47,40.02 213.47,45.38 213.55,45.46 213.55,47.61 213.15,48 213.09,48 v2(212.87,48.22)
  BOTTOM w0.127: PR5126.1 61.11,15.51 v2(61.11,16) ; D4003.K 158.56,24.09 159.79,24.09 160.04,24.34 160.04,24.73 160.42,25.11 162.89,25.11 v2(163.34,24.66) ; CPU1.AP15 113.15,43.16 v2(112.83,43.49)
SIO_SLP_S3#_EC: length 6.8
  TOP w0.089: R2479.2 160.55,23.58 v1(159.99,23.02) 159.2,23.02 158.01,24.22 156.74,24.22 156.44,23.92 KBC24.34
SIO_SLP_S4#: length 120.7
  TOP w0.127: v2(61.87,1.48) 62.5,2.12 v2(62.5,4.3) ; v2(104.71,43.42) 104.34,43.79 v1(102.66,43.79) ; v2(94,10.76) 94,11.35 94.89,12.24 94.89,14.47 94.24,15.12 94.24,21.26 v2(93.9,21.6)
  L3 w0.127: v2(108.48,12.02) 96.03,12.02 94.76,10.76 v2(94,10.76) 93.97,10.76 93.75,10.98 89.53,10.98 88.74,10.19 85.33,10.19 83.38,8.23 83.36,8.23 82.76,7.64 82.76,7.52 82.32,7.07 81.17,7.07 78.38,4.28 75.57,4.28 74.77,3.48 69.54,3.48 68.53,4.49 65.48,4.49 65.48,4.5 62.72,4.5 62.53,4.3 v2(62.5,4.3)
  L4 w0.127: v2(43.2,1.48) 43.64,1.93 46.06,1.93 46.25,1.74 55.01,1.74 55.33,2.06 61.3,2.06 v2(61.87,1.48) ; v2(104.71,43.42) 104.34,43.42 103.15,42.23 103.15,40.58 100.08,37.52 98.31,37.52 97.15,36.36 97.15,34.46 94.55,31.85 94.55,22.25 v2(93.9,21.6)
  BOTTOM w0.127: R4024.1 108.99,12.53 v2(108.48,12.02) ; v2(104.71,43.42) 105.06,43.77 105.48,43.77 105.52,43.73 106.5,43.73 106.88,44.11 109,44.11 CPU1.BA16 ; v2(43.2,1.48) 43.23,1.46 PR5417.1
SKTOCC#: length 7.9
  BOTTOM w0.089: TP402.1 132.23,76.16 132.23,72.99 130.99,71.75 CPU1.A65
SLEEVE: length 2.2
  TOP w0.203: v3(19.77,15) 19.89,14.87 HDA27.31
  TOP w0.406: RN2901.4 17.31,16.19 v3(16.81,15.68)
  vias: v1(19.07,16.22)
SLEEVE_R: length 18.4
  TOP w0.254: v3(17.14,11.8) 17.14,11.48 ED2903.2
  L6 w1.016: v3(17.14,11.8) 17.14,12.23 15.18,14.18 5.25,14.18 2.87,11.8 HPMIC1.4
  vias: v1(17.91,13.76)
SM_DRAMRST#: length 36.3
  L4 w0.089: v2(112.18,42.58) 111.32,41.71 109.87,41.71 108.93,40.78 108.93,32.19 v2(108.72,31.97)
  BOTTOM w0.089: v2(108.72,31.97) 108.72,31.45 107.51,30.24 104.56,30.24 101.81,27.5 v1(101.81,21.93) 102.26,21.49 102.26,20.06 102.27,20.05 102.27,18.74 103.19,17.82 104.5,17.82 R505.2 104.92,17.45 D502.2 105.78,17.41 R504.1 ; CPU1.AT13 v2(112.18,42.58)
SM_INTRUDER#: length 28.9
  TOP w0.089: R1730.2 95.45,33.15 96.81,34.52 96.81,36.53 97.02,36.75 102.81,36.75 v1(103.14,36.41) 103.48,36.75 105.47,36.75 106.57,35.65 106.57,35.39 v2(106.58,35.39)
  L4 w0.089: v2(106.58,35.39) 107.05,35.86 107.33,35.86 108.32,36.85 108.32,37.13 108.33,37.14 108.33,41.34 109.27,42.28 109.27,42.98 110.27,43.98 112.4,43.98 v2(112.83,44.4)
  BOTTOM w0.089: v2(112.83,44.4) 113.15,44.08 CPU1.AP16
SM_PGCNTL: length 38.2
  TOP w0.089: v1(108.35,73.11) v2(108.58,73.63)
  L4 w0.089: v2(108.58,73.63) 107.58,74.64 106.87,74.64 101.75,79.76 101.75,86.52 100.05,88.23 90.24,88.23 v2(88.36,90.11)
  BOTTOM w0.089: v2(108.58,73.63) 108.83,73.39 109.55,73.39 109.72,73.22 CPU1.AW67 ; Q501.S 86.87,92.02 88.36,90.53 v2(88.36,90.11)
SM_PGCNTL_R: length 147.4
  L3 w0.089: v2(82.64,97.44) 82.57,97.51 82.57,97.88 80.46,99.99 77.71,99.99 75.34,102.36 69.27,102.36 68.13,101.22 68.13,97.91 68.26,97.77 68.26,94.74 67.54,94.02 63.28,94.02 61.76,95.54 61.76,96.33 v2(60.22,97.88)
  L4 w0.089: v2(62,15.84) 61.72,15.56 61.08,15.56 60.72,15.2 52.73,15.2 48.41,19.52 48.41,38.19 45.07,41.53 45.07,47.93 45.72,48.58 45.72,61.83 44.72,62.83 44.72,68.14 45.41,68.83 45.41,73.36 45.42,73.36 45.42,86.4 56.9,97.88 v2(60.22,97.88)
  BOTTOM w0.089: v2(62,15.84) 62,14.79 61.77,14.57 PR5125.1 ; Q501.D 85.92,95.06 R506.2 84.52,95.57 v1(83.72,96.37) v2(82.64,97.44)
SM_RCOMP_0: length 19.2
  TOP w0.203: 109.01,43.3 109.49,43.3 110.14,43.95 111.71,43.95 111.98,44.22 v2(112.17,44.41)
  TOP w0.508: 109.01,43.3 108.27,43.3 106.55,45.02 102.31,45.02 100.81,46.52 100.81,48.58 v1(99.81,49.57) 98.88,50.51 R501.1
  BOTTOM w0.152: CPU1.AR18 112.5,44.74 v2(112.17,44.41)
SM_RCOMP_1: length 19.1
  TOP w0.203: 109.95,46.44 110.59,46.44 111.26,45.78 111.67,45.78 v2(112.17,45.28)
  TOP w0.508: 109.95,46.44 108.48,47.92 108.48,49.29 107.26,50.51 v1(105.94,50.51) 102.43,50.51 101.75,51.19 101.75,51.85 100.05,53.55 R502.1
  BOTTOM w0.152: v2(112.17,45.28) 111.85,44.95 CPU1.AT18
SM_RCOMP_2: length 17.6
  TOP w0.203: 109.06,46.04 109.42,45.68 109.95,45.68 110.34,45.28 v2(111.5,45.28)
  TOP w0.508: R503.1 99.92,52.79 100.73,51.98 100.73,51.32 102.97,49.09 102.97,48.6 103.67,47.89 v1(106.45,47.89) 107.21,47.89 109.06,46.04
  BOTTOM w0.152: v2(111.5,45.28) 111.2,44.99 CPU1.AU18
SMB_ALERT#: length 20.5
  L4 w0.089: v2(123.72,29.68) 123.87,29.83 123.87,34.07 122.88,35.06 122.88,39.43 v2(123.31,39.86)
  BOTTOM w0.089: v2(123.31,39.86) 122.96,40.22 CPU1.R10 ; v2(123.72,29.68) v1(123.72,28.61) 123.72,28.32 121.81,26.41 121.52,26.41 120.77,25.67 120.73,25.67 120.29,25.23 120.29,23.46 119.65,22.82 R1836.2
SMBC_THERM_NV: length 27.7
  TOP w0.089: Q7601.1 189.8,68.91 190.14,69.24 190.14,70.06 189.38,70.83 189.38,71.46 189.06,71.78 RN7601.2 188.41,72.39 188.41,73.06 188.01,73.45 184.85,73.45 182.44,75.86 181.45,75.86 v1(180.09,77.22) 178.22,79.08 v2(175.28,79.08)
  BOTTOM w0.089: GPU1.D9 170.84,79.28 171.2,79.64 174.72,79.64 v2(175.28,79.08)
SMBD_THERM_NV: length 29.8
  TOP w0.089: RN7601.1 187.15,71.14 v2(187.02,71.01) ; Q7601.4 187.41,70.64 187.03,71.01 v2(187.02,71.01) ; v2(187.02,71.01) 186.66,71.01 v1(186.45,70.8)
  L3 w0.127: v2(170.14,79.68) 169.54,79.08 168.68,79.08 167.87,78.27 167.87,76.92 168.54,76.25 169.18,76.25 169.73,75.7 169.73,75.49 172.19,73.03 182.2,73.03 182.56,72.67 185.38,72.67 186.84,71.21 186.84,71.2 v2(187.02,71.01)
  BOTTOM w0.089: v2(170.14,79.68) 170.14,78.85 GPU1.D8
SML0_ALERT#: length 23.3
  TOP w0.089: v1(117.37,21.8) 117.37,21.3 v2(117.5,21.17)
  L4 w0.089: v2(117.5,21.17) 117.23,21.44 117.23,24.27 117.11,24.39 117.11,26 116.86,26.25 v2(115.97,26.25)
  BOTTOM w0.089: CPU1.W1 120.53,34.84 120.53,32.77 120.62,32.68 120.62,31.02 121.77,29.87 121.77,28.68 121.14,28.04 120.85,28.04 120.11,27.3 120.07,27.3 119.32,26.55 116.4,26.55 116.1,26.25 v2(115.97,26.25) ; v2(117.5,21.17) 117.5,21.92 116.81,22.61 R1822.2 R1823.1
SML0_SMBCLK: length 20.4
  L4 w0.127: v2(120.85,28.92) 122.24,30.3 122.24,34.16 121.83,34.56 121.83,38.73 v2(122.25,39.15)
  BOTTOM w0.089: RN1807.5 114.96,25.09 v1(114.96,26.55) 115.5,27.09 119.09,27.09 119.44,27.45 119.68,27.68 120.85,28.85 v2(120.85,28.92) ; CPU1.R9 v2(122.25,39.15)
SML0_SMBDATA: length 16.4
  BOTTOM w0.089: CPU1.W2 120.19,35.15 120.19,34.83 120.34,34.67 120.34,32.27 120.12,32.05 v1(120.12,31.15) 121.5,29.76 121.5,28.79 121.02,28.31 120.73,28.31 120,27.58 119.96,27.58 119.87,27.5 119.2,26.83 115.91,26.83 115.22,26.14 115.22,25.76 115.72,25.26 RN1807.6
SML1_SMBCLK: length 324.3
  TOP w0.089: Q2601.3 58.95,16.61 59.16,16.83 v1(60.37,16.83) 60.47,16.72 v2(60.47,16.05) ; v2(165.12,3.14) 164.23,3.14 163.13,4.23 163.13,6.74 164.04,7.64 164.04,8.15 164.54,8.66 164.54,9.68 162.58,11.64 R2459.2 ; v2(139.97,1.48) 138.75,2.71 137.67,2.71 136.93,3.46 136.87,3.51 136.87,7.12 135.05,8.94 135.05,10.18 134.73,10.49 133.83,11.39 129.18,11.39 128.87,11.7 128.87,19.03 127.47,20.43 126.99,20.43 126.48,20.94 126.48,20.94 126.01,21.41 124.47,21.41 123.79,22.09 123.09,22.09 122.54,22.64 118,22.64 115.97,24.66 v2(115.97,25.61) ; Q7601.6 v2(187.41,68.16)
  L3 w0.127: v2(115.97,25.61) 115.97,25.62 115.41,26.19 110.48,26.19 107.86,28.8 104.05,28.8 101.47,26.23 100.86,26.23 100.23,25.6 99.95,25.6 97.62,23.27 90.08,23.27 89.57,22.76 85.59,22.76 81.53,18.71 77.63,18.71 71.04,12.11 67.11,12.11 64.03,15.2 60.85,15.2 60.47,15.58 v2(60.47,16.05)
  L4 w0.127: v2(219.91,50.51) 219.98,50.43 219.98,49.24 219.53,48.79 218.79,48.79 218.33,49.25 214.04,49.25 208.85,54.44 208.85,55.41 207.78,56.48 206.4,56.48 205.76,57.12 205.76,59.65 205.49,59.92 197.65,59.92 196.33,61.24 195.02,61.24 194.31,61.95 193.5,61.95 193.19,62.26 193.19,62.7 192.11,63.78 192.11,64.82 190.69,66.24 190.69,67.62 190.02,68.29 187.54,68.29 v2(187.41,68.16)
  L6 w0.102: v2(219.91,50.51) 219.91,50.22 220.44,49.69 220.44,48.23 221.13,47.54 221.13,44.77 222.55,43.34 222.55,33.56 222.48,33.49 222.48,31.49 223.98,29.99 224.08,29.99 226.92,27.15 226.92,22.92 226.69,22.7 226.69,8.14 225.09,6.54 215.23,6.54 212.68,9.09 205.59,9.09 203.74,7.24 198.96,7.24 193.98,2.26 168.85,2.26 168,3.11 165.15,3.11 v2(165.12,3.14) 164.41,2.42 164.05,2.42 163.29,1.66 148.55,1.66 147.95,2.26 147.23,2.26 146.59,1.63 144.15,1.63 143.53,2.25 140.74,2.25 v2(139.97,1.48)
  BOTTOM w0.089: CPU1.W3 120.79,35.97 120.79,35.74 120.83,35.63 120.83,35.43 120.8,35.36 120.8,35.07 120.83,34.98 120.83,34.58 120.71,34.46 120.71,32.85 120.81,32.76 120.81,31.22 122.05,29.98 122.05,28.56 121.25,27.77 120.96,27.77 120.22,27.03 120.18,27.03 119.43,26.28 116.64,26.28 v2(115.97,25.61) 116.22,25.36 RN1807.7
SML1_SMBDATA: length 327.1
  TOP w0.089: Q7601.3 189.06,70.92 v2(188.79,71.18) ; R2447.2 162.96,10.88 164.28,9.57 164.28,8.77 163.77,8.26 163.77,7.75 162.87,6.85 162.87,4.12 163.47,3.52 v1(163.47,2.75) v2(164.23,1.99) ; Q2601.6 56.42,15.31 56.92,14.82 v2(56.92,14.69) ; v2(116.61,25.64) 116.61,24.4 118.09,22.92 119.9,22.92 119.92,22.92 119.95,22.9 122.65,22.9 123.2,22.36 123.9,22.36 124.58,21.67 126.12,21.67 126.59,21.2 126.59,21.2 127.1,20.7 127.58,20.7 129.13,19.14 129.13,11.81 129.29,11.66 133.94,11.66 134.41,11.19 134.41,11.19 134.84,10.76 135.31,10.29 135.31,9.05 137.19,7.17 137.19,3.57 137.78,2.98 139.12,2.98 v2(140.61,1.48)
  L3 w0.127: v2(62.76,15.84) 64.03,15.84 67.37,12.5 70.88,12.5 77.47,19.09 81.38,19.09 86.25,23.96 89.6,23.96 89.92,23.65 97.46,23.65 99.79,25.98 100.07,25.98 100.7,26.61 101.31,26.61 104.28,29.57 107.64,29.57 110.64,26.57 114.19,26.57 114.44,26.82 116.19,26.82 116.61,26.4 v2(116.61,25.64)
  L4 w0.127: v2(62.76,15.84) 62.12,15.2 61.23,15.2 60.73,14.69 v2(56.92,14.69) ; v2(216.56,53.81) 216.03,53.29 213.9,53.29 210.71,56.48 210.71,57.63 209.57,58.77 208.8,58.77 206.14,61.43 198.28,61.43 196.89,62.81 195.59,62.81 193.95,64.45 193.95,69.29 192.48,70.76 189.67,70.76 189.25,71.18 v2(188.79,71.18)
  L6 w0.102: v2(216.56,53.81) 216.96,53.4 218.11,53.4 220.42,51.09 220.42,50.76 220.67,50.13 220.79,49.73 220.87,49.49 220.87,48.23 221.43,47.67 221.43,44.89 222.85,43.47 222.85,33.44 222.78,33.37 222.78,31.62 224.11,30.29 224.2,30.29 227.22,27.27 227.22,22.8 226.99,22.57 226.99,8.01 225.22,6.23 215.11,6.23 212.55,8.79 205.85,8.79 203,5.94 203,3.81 201.14,1.96 168.72,1.96 167.87,2.81 165.42,2.81 164.61,1.99 v2(164.23,1.99) 164.1,1.99 163.47,1.36 148.42,1.36 147.82,1.96 147.35,1.96 146.72,1.32 144.02,1.32 143.4,1.94 141.07,1.94 v2(140.61,1.48)
  BOTTOM w0.089: RN1807.8 116.81,25.35 116.61,25.55 v2(116.61,25.64) 116.98,26.01 119.54,26.01 120.29,26.76 120.33,26.76 121.07,27.5 121.36,27.5 122.31,28.45 122.31,30.09 120.98,31.42 120.98,32.83 120.89,32.92 120.89,34.34 121.01,34.46 121.01,35.02 120.98,35.12 120.98,35.32 121.01,35.39 121.01,35.67 120.98,35.77 120.98,36.25 CPU1.V3
SML1ALERT#: length 27.1
  TOP w0.089: R1837.2 95.91,31.63 95.91,33.15 97,34.25 97,36.46 97.1,36.56 98.67,36.56 98.69,36.54 100.97,36.54 v1(101.41,36.1) 101.45,36.05 103.88,36.05 104.15,36.32 105.39,36.32 106.07,35.65 106.07,35.01 106.16,34.92 106.67,34.92 107.06,35.31 107.06,35.37 107.85,36.16 110.1,36.16 110.76,36.82 110.76,37.17 112.11,38.52 112.99,38.52 112.99,38.52 114.42,38.52 v2(114.78,38.87)
  BOTTOM w0.089: v2(114.78,38.87) 114.45,38.55 CPU1.AM7
SP_PLLVDD: length 1.1
  BOTTOM w0.254: GPU1.N6 v2(162.69,76.34) ; GPU1.M6 v2(163.49,76.34)
  vias: v1(163.09,70.57) v2(160.93,70.45) v2(161.95,70.45)
SPI_CK_OUT_HDMI: length 13.2
  TOP w0.089: v1(24,74.66) v2(24.43,74.23) 24.53,74.23 25.13,73.63 25.13,72.86 24.8,72.53 U5701.D2
  BOTTOM w0.089: v2(24.43,74.23) 23.65,75.01 20.83,75.01 R5743.2 20.04,75.8 19.75,75.8 19.17,76.38 19.17,78.98 19.3,79.11 U5702.6
SPI_CLK_CPU: length 13.1
  BOTTOM w0.089: RN1803.8 100.8,30.24 100.88,30.15 101.97,30.15 102.77,30.95 v1(102.79,30.95) 102.79,30.96 105.06,33.24 107.1,33.24 107.9,34.04 109.66,34.04 110.31,34.69 110.31,35.04 110.6,35.33 CPU1.AV2
SPI_CLK_ROM: length 159.9
  TOP w0.089: R9132.1 209.57,35.17 v2(209.19,35.55) ; v2(97.76,27.57) 97.34,27.57 96.55,26.78 96.55,16.07 97.28,15.34 97.28,14.71 98.05,13.93 98.05,12.83 97.4,12.18 v1(97.4,12.18) 97.4,11.49 97.28,11.36 v2(97.28,10.4)
  L6 w0.102: v2(209.19,35.55) 209.01,35.37 208.99,35.37 208.73,35.11 208.73,33.88 208.58,33.73 208.58,32.44 209.38,31.65 209.38,28.07 210.33,27.12 210.33,23.43 210.64,23.13 210.64,22.77 210.33,22.46 210.33,21.17 209.77,20.61 208.86,20.61 208.26,21.21 198.57,21.21 197.89,21.89 190.7,21.89 189.45,20.64 189.45,20.64 174.88,20.64 173.17,18.93 v2(172.77,18.93) 172.11,19.59 164.99,19.59 164.73,19.85 163.39,19.85 157.51,19.85 157.39,19.73 148.22,19.73 148.14,19.65 143.91,19.65 143.4,20.15 134.24,20.15 133.75,19.66 128.81,19.66 125.03,15.89 119.2,15.89 118.89,15.58 114.14,15.58 113.95,15.77 111.14,15.77 110.69,15.32 109.23,15.32 109.17,15.25 103.32,15.25 100.5,12.43 98.34,12.43 97.28,11.36 v2(97.28,10.4)
  BOTTOM w0.089: v2(97.76,27.57) 97.96,27.77 97.96,28.51 98.9,29.45 98.9,29.7 99.44,30.24 RN1803.1 ; RN2502.4 172.59,18.76 v2(172.77,18.93)
SPI_CLK_ROM_R: length 4.2
  BOTTOM w0.089: SPI25.6 v1(170.25,18.88) 170.38,18.88 EC2503.1 171.55,18.02 RN2502.1
SPI_CLK_ROM_TPM2: length 2.8
  TOP w0.089: U9101.19 212.41,34.46 211.87,35 211.87,35.21 v1(211.71,35.37) 210.92,35.37 R9132.2
SPI_CS2#_R_TPM2: length 3.2
  TOP w0.089: R9130.1 R9140.2 211.22,34.15 v1(211.66,34.15) 211.86,34.15 212.05,33.96 U9101.20
SPI_CS_CPU_N0: length 16.8
  BOTTOM w0.089: R1812.2 v1(101.39,28.66) 101.91,28.66 104.71,31.46 107.09,31.46 107.92,32.29 107.92,32.3 108.23,32.6 111.55,32.6 111.7,32.75 111.7,33.82 111.03,34.49 111.03,35.62 111.06,35.73 111.29,35.96 CPU1.AU3
SPI_CS_CPU_N1: length 16
  BOTTOM w0.089: CPU1.AU1 111.55,34.63 111.55,34.22 111.88,33.89 111.88,32.68 111.6,32.39 108.54,32.39 108.05,31.9 v1(108.05,31.74) 107.33,31.02 104.78,31.02 101.67,27.9 R1838.2
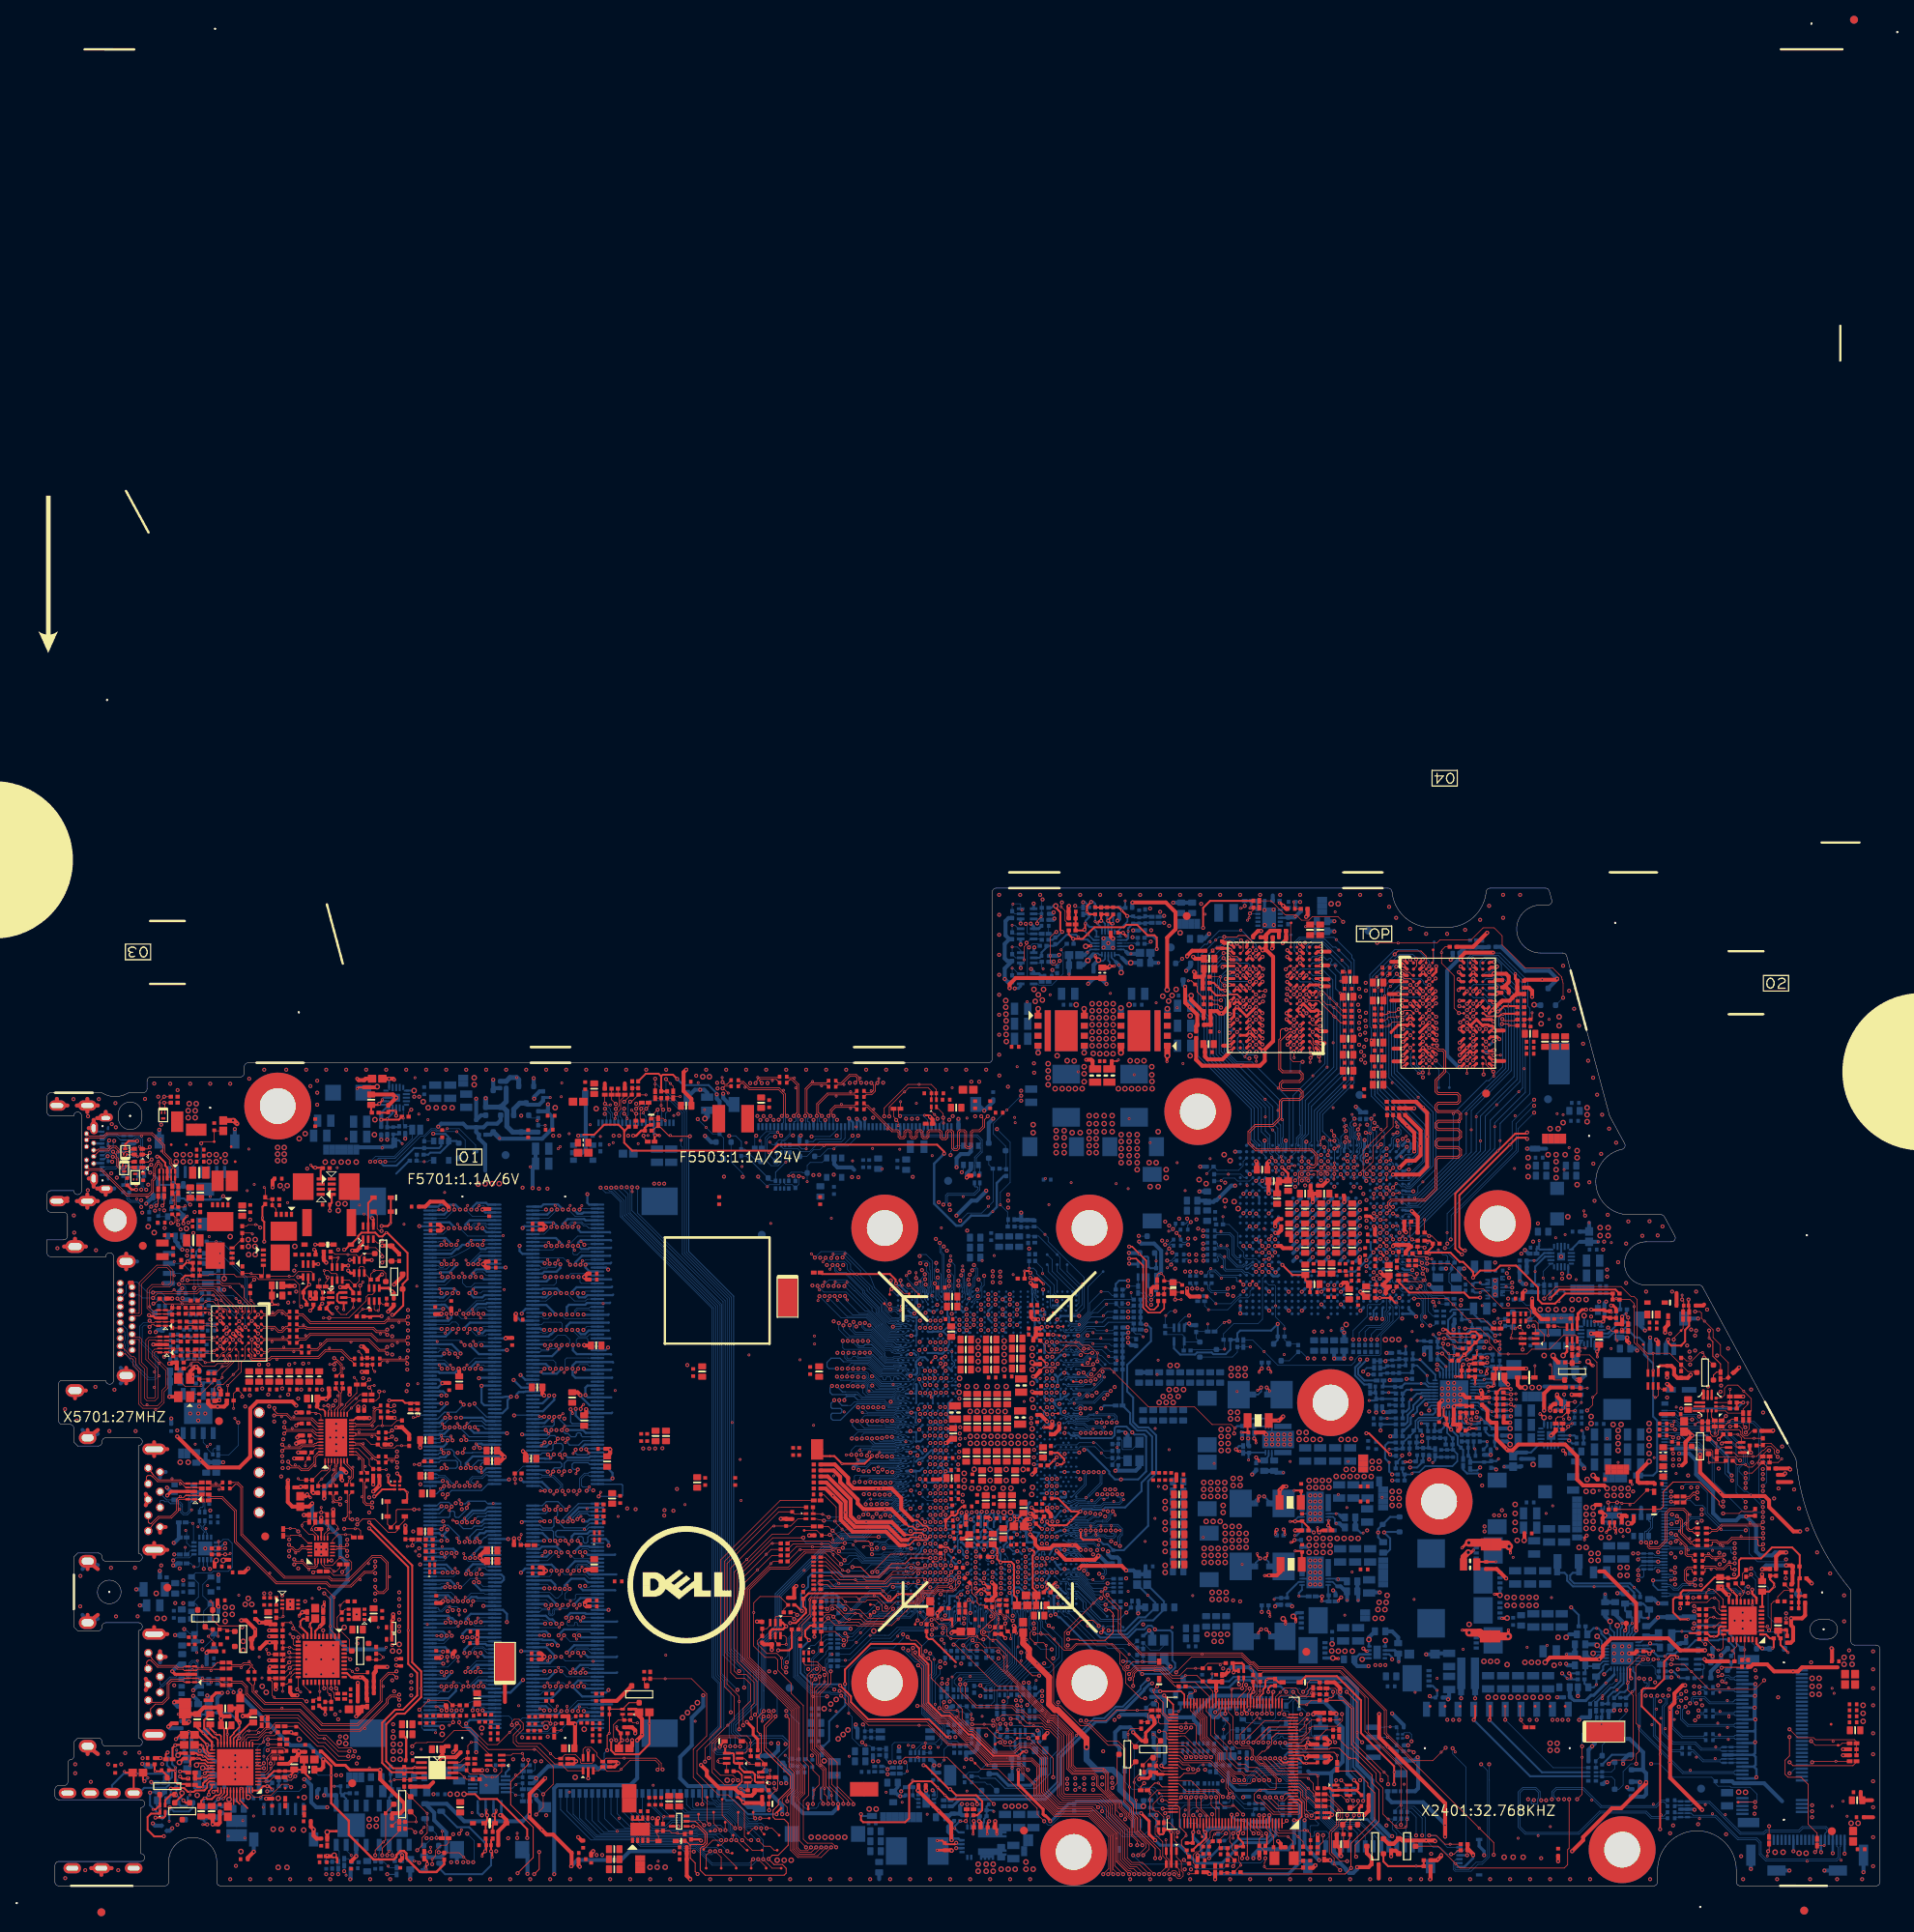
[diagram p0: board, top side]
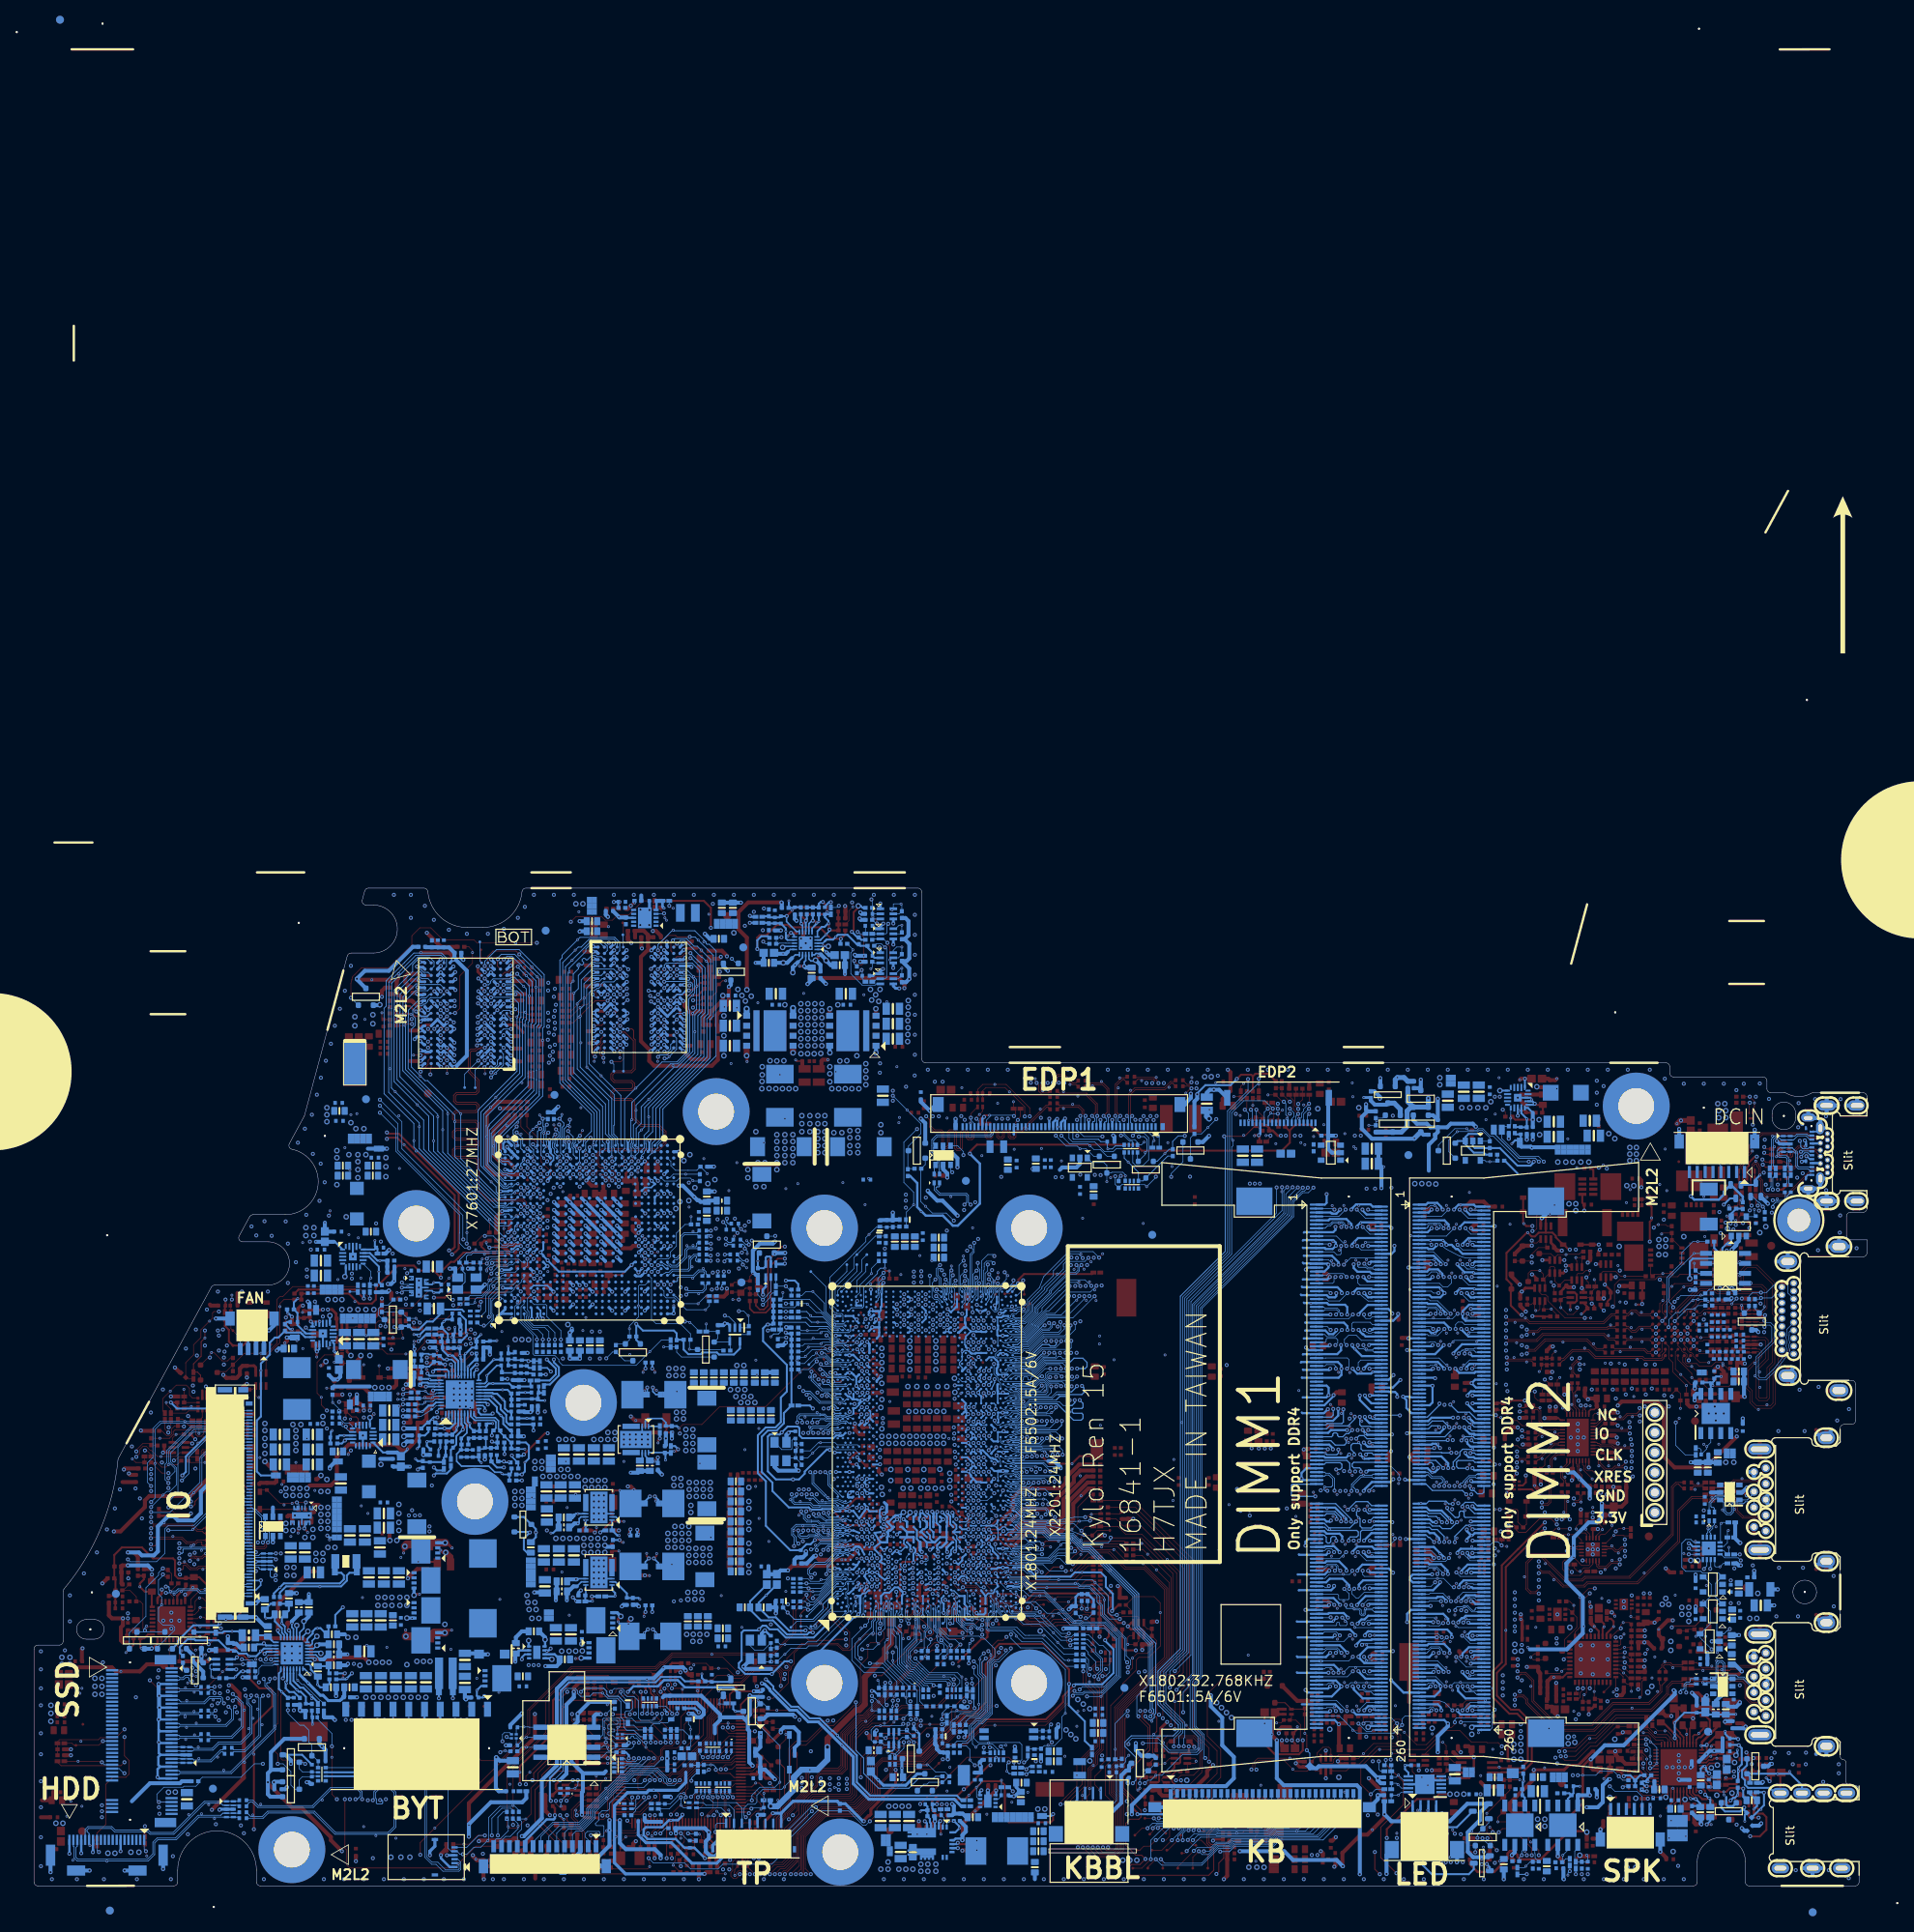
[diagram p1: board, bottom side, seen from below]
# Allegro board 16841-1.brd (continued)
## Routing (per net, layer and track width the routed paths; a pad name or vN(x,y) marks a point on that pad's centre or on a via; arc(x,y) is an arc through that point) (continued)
SPI_CS_HDMI: length 13.9
  TOP w0.089: v2(16.76,76.47) 22.04,76.47 22.27,76.24 23.13,76.24 v1(23.26,76.11) 23.31,76.11 25.6,73.82 U5701.C1
  BOTTOM w0.089: R5740.1 17.6,76.14 17.27,76.47 v2(16.76,76.47) 16.66,76.57 U5702.1
SPI_CS_ROM_N0: length 104.3
  TOP w0.089: v2(98.75,26.81) v1(98.75,25.95) 98.75,25.85 97.66,24.77 97.66,17.73 99.33,16.06 99.33,12.69 101.13,10.89 v2(101.13,10.43)
  L6 w0.102: v2(101.13,10.43) 101.13,10.69 100.99,10.83 100.99,11.26 101.11,11.39 101.37,11.39 101.62,11.14 101.87,11.14 102,11.26 102,11.27 102.11,11.37 102.11,12.29 102.22,12.41 102.39,12.41 102.51,12.29 102.51,11.39 102.61,11.29 102.82,11.29 102.92,11.39 102.92,11.52 103.05,11.65 103.3,11.65 103.43,11.77 103.43,12.2 103.53,12.31 103.74,12.31 103.84,12.2 103.84,11.75 103.94,11.65 104.14,11.65 104.24,11.75 104.24,12.2 104.35,12.31 104.55,12.31 104.65,12.2 104.65,11.75 104.75,11.65 104.96,11.65 105.06,11.75 105.06,12.2 105.16,12.31 105.36,12.31 105.46,12.2 105.46,11.75 105.57,11.65 105.81,11.65 105.94,11.77 105.94,12.36 106.12,12.54 106.12,12.91 106.25,13.04 107.22,13.04 108.24,14.06 109.63,14.06 109.72,14.15 121.44,14.15 121.55,14.03 121.84,14.03 121.96,14.15 122.25,14.15 122.36,14.03 124.83,14.03 128,17.21 128.72,17.21 128.82,17.31 128.82,18 128.94,18.12 129.11,18.12 129.23,18 129.23,17.31 129.33,17.21 129.56,17.21 129.69,17.33 129.69,18.22 129.81,18.35 130.06,18.35 130.16,18.25 130.16,17.31 130.26,17.21 130.46,17.21 130.57,17.31 130.57,18.25 130.67,18.35 130.87,18.35 130.97,18.25 130.97,17.31 131.07,17.21 131.28,17.21 131.38,17.31 131.38,18.25 131.48,18.35 132.48,18.35 132.61,18.22 132.61,17.36 132.74,17.23 132.98,17.23 133.12,17.37 133.12,18.22 133.24,18.35 133.72,18.35 133.82,18.25 133.82,18.1 133.93,18 133.93,18 134.13,17.99 134.23,18.1 134.23,18.25 134.33,18.35 134.54,18.35 134.64,18.25 134.64,18.1 134.74,17.99 134.94,17.99 135.04,18.1 135.04,18.25 135.15,18.35 135.35,18.35 135.45,18.25 135.45,18.1 135.55,17.99 135.76,17.99 135.86,18.1 135.86,18.25 135.96,18.35 136.16,18.35 136.26,18.25 136.26,18.1 136.36,17.99 136.57,17.99 136.67,18.1 136.67,18.25 136.77,18.35 136.97,18.35 137.08,18.25 137.08,18.1 137.18,17.99 137.38,17.99 137.48,18.1 137.48,18.25 137.58,18.35 148.36,18.35 148.48,18.22 148.48,17.58 148.75,17.32 149.84,17.32 156.48,17.32 156.61,17.45 v2(156.61,18.19)
  BOTTOM w0.089: R1812.1 99.09,28.21 99.09,27.15 v2(98.75,26.81) ; v2(156.61,18.19) 156.61,17.74 156.95,17.4 158.4,17.4 R2501.1 160.04,16.98 160.68,16.34 SPI25.1
SPI_CS_ROM_N1: length 176.9
  TOP w0.089: v2(209.19,34.89) 209.19,34.89 209.67,34.4 R9130.2 ; v2(216.43,40.35) 216.22,40.14 R9129.2 215.34,39.69 R9133.2 ; v2(99.54,27.27) 99.54,25.73 98.15,24.34 98.15,24.34 98.15,17.86 100.35,15.66 v1(100.35,14.06) 100.35,12.69 101.75,11.28 101.75,11.28 101.85,11.18 102.41,10.63 v2(102.41,10.37)
  L3 w0.127: v2(209.19,34.89) 210.08,34.89 212.87,37.68 213.76,37.68 v2(216.43,40.35)
  L6 w0.102: v2(102.41,10.37) 102.66,10.63 102.84,10.63 103.4,11.19 106.01,11.19 108.42,13.6 109.82,13.6 109.91,13.69 121.25,13.69 121.36,13.58 125.02,13.58 128.19,16.75 133.14,16.75 133.93,17.54 137.84,17.54 138.2,17.89 147.53,17.89 148.56,16.86 149.54,16.86 150.02,16.86 150.03,16.86 158.17,16.86 159.99,18.68 163.88,18.68 166.64,15.91 175.19,15.91 178.98,19.7 189.86,19.7 190.31,20.15 207.99,20.15 208.47,19.67 210.16,19.67 211.27,20.78 211.27,22.07 211.58,22.38 211.58,23.52 211.27,23.82 211.27,28.49 211.09,28.66 211.09,31.99 210.87,32.22 210.87,33.22 v2(209.19,34.89)
  BOTTOM w0.089: v2(99.54,27.27) R1838.1 ; v2(216.43,40.35) 216.98,39.79 216.98,39.48 218.59,37.88 218.59,34.25 220.68,32.16 Q9104.G
SPI_D_IN_HDMI: length 14.7
  TOP w0.089: U5701.C2 25.6,72.5 26.02,72.92 26.02,73.78 25.04,74.76 25.04,75.93 v1(24.79,76.19) 24.43,76.54 22.32,76.54 21.89,76.97 v2(17.83,76.97)
  BOTTOM w0.089: v2(17.83,76.97) 16.96,77.84 U5702.2
SPI_D_OUT_HDMI: length 10.5
  TOP w0.089: v2(24.61,73.52) 24.8,73.32 U5701.D1
  BOTTOM w0.089: v2(24.61,73.52) 24.61,73.7 25.14,74.23 25.14,77.2 v1(21.97,80.38) U5702.5
SPI_HOLD_CPU: length 16.8
  BOTTOM w0.089: CPU1.AU4 111.29,36.67 110.89,36.28 110.89,35.8 110.85,35.64 110.85,34.41 111.53,33.74 111.53,33.11 111.27,32.85 107.96,32.85 106.94,31.83 106.45,31.83 106.44,31.84 v1(104.54,31.84) 104.39,31.84 101.98,29.42 R1811.2
SPI_HOLD_ROM: length 105.7
  TOP w0.089: v2(101.76,10.42) 101.76,10.82 99.67,12.91 99.67,16.03 97.88,17.82 97.88,24.43 99.18,25.72 99.18,26.98 98.65,27.51 v2(98.65,27.57) 98.65,27.61 97.77,28.49 96.96,28.49 RN1802.4 ; v2(173.58,16.98) 173.35,17.21 v1(172.94,17.21)
  L6 w0.102: v2(173.58,16.98) 173.43,16.83 171.33,16.83 171.23,16.93 171.23,17.39 171.13,17.49 170.93,17.49 170.83,17.39 170.83,16.93 170.72,16.83 170.52,16.83 170.42,16.93 170.42,17.39 170.32,17.49 170.11,17.49 170.01,17.39 170.01,16.93 169.91,16.83 166.05,16.83 163.97,18.91 159.26,18.91 157.44,17.09 149.93,17.09 149.31,17.09 149.31,17.09 148.65,17.09 147.62,18.12 138.1,18.12 137.75,17.77 133.83,17.77 133.05,16.98 128.1,16.98 124.92,13.8 121.46,13.8 121.34,13.92 109.81,13.92 109.72,13.83 108.33,13.83 105.92,11.42 103.31,11.42 102.95,11.06 102.15,11.06 101.76,10.67 v2(101.76,10.42)
  BOTTOM w0.089: R1811.1 98.87,28.76 98.87,27.79 v2(98.65,27.57) ; R2503.2 173.45,17.11 v2(173.58,16.98)
SPI_HOLD_ROM_R: length 3.1
  BOTTOM w0.089: R2503.1 170.91,17.61 v1(170.28,17.61) SPI25.7
SPI_IRQ#_TPM2: length 6.9
  TOP w0.089: R9119.2 R9150.2 208.68,35.9 208.81,36.03 210.81,36.03 211.38,36.59 v1(211.78,36.59) 211.92,36.59 212.34,36.17 212.34,35.19 212.57,34.96 U9101.18
SPI_SI_CPU: length 18.1
  TOP w0.089: R1824.2 98.32,30.8 R1825.1 100.09,32.32 v2(101.2,31.21)
  BOTTOM w0.089: RN1803.6 100.76,31.33 100.87,31.21 101.2,31.21 v2(101.2,31.21) 102.37,31.21 103.32,32.16 v1(103.32,32.17) 104.63,33.47 105.04,33.47 105.79,34.22 109.59,34.22 110.13,34.77 110.13,35.13 110.34,35.34 110.34,35.99 110.6,36.25 CPU1.AV3
SPI_SI_ROM: length 158.9
  TOP w0.089: v2(209.06,32.73) 209.09,32.73 209.24,32.88 R9139.1 ; v2(99.21,10.43) 99.21,10.68 99.05,10.83 99.05,11.34 98.74,11.66 v1(98.74,12.36) 98.74,14.79 97.95,15.57 97.95,16.66 97.23,17.37 97.23,25.91 v2(97.59,26.27)
  L6 w0.102: v2(209.06,32.73) 209.09,32.73 209.86,31.95 209.86,28.27 210.81,27.32 210.81,23.63 211.12,23.33 211.12,22.57 210.81,22.26 210.81,20.97 209.97,20.13 208.66,20.13 208.06,20.73 198.37,20.73 197.82,21.27 195.37,21.27 194.76,20.66 194.4,20.66 194.15,20.91 193.63,20.91 193.38,20.66 191.02,20.66 190.77,20.91 190.41,20.91 189.65,20.15 175.08,20.15 v2(173.3,18.38) 173.22,18.45 172.54,18.45 171.89,19.1 164.79,19.1 164.53,19.37 157.71,19.37 157.59,19.25 156.1,19.25 155.54,18.69 155.54,18.02 155.3,17.78 150.03,17.78 149,18.81 128.96,18.81 125.32,15.18 119.49,15.18 119.32,15 119.19,14.87 113.81,14.87 113.54,14.6 109.53,14.6 109.44,14.52 108.05,14.52 107.03,13.5 102.58,13.5 100.8,11.72 99.92,11.72 99.21,11.01 v2(99.21,10.43)
  BOTTOM w0.089: RN2502.3 172.36,19.47 173.07,19.47 173.3,19.24 v2(173.3,18.38) ; RN1803.3 98.96,31.33 97.98,30.35 97.98,29.75 97.1,28.87 97.1,27.26 97.59,26.77 v2(97.59,26.27)
SPI_SI_ROM_R: length 3.8
  BOTTOM w0.089: SPI25.5 169.92,20.15 169.97,20.2 v1(170.58,20.2) 171.34,20.2 EC2501.1 171.55,20 RN2502.2
SPI_SI_ROM_TPM2: length 2.4
  TOP w0.089: R9139.2 211.67,32.88 v1(211.71,32.92) 211.85,32.92 212.38,33.46 U9101.21
SPI_SO_CPU: length 13.5
  TOP w0.089: v2(101.18,30.58) 101.65,31.05 101.65,31.83 101.39,32.08 v2(101.36,32.08)
  BOTTOM w0.089: RN1803.7 100.93,30.83 v2(101.18,30.58) ; CPU1.AW3 109.84,36.16 109.48,35.8 109.25,35.8 109.01,35.57 109.01,35.23 108.86,35.08 108.86,34.76 108.68,34.57 105.64,34.57 105.59,34.53 105.59,34.53 105.46,34.4 104.67,34.4 v1(104.57,34.3) 104.56,34.3 102.34,32.08 v2(101.36,32.08)
SPI_SO_ROM: length 162.3
  TOP w0.089: v2(98.13,26.61) 98.13,25.75 97.45,25.08 97.45,17.46 98.17,16.75 98.17,15.66 98.95,14.88 98.95,12.63 99.64,11.95 v1(99.64,11.49) 99.64,10.88 99.84,10.68 v2(99.84,10.43) ; R9134.1 210.49,30.71 v2(210.62,30.71)
  L6 w0.102: v2(210.62,30.71) 210.09,30.19 210.09,28.37 211.04,27.41 211.04,23.73 211.35,23.42 211.35,22.47 211.04,22.17 211.04,20.88 210.07,19.9 208.57,19.9 207.97,20.5 198.28,20.5 198.26,20.51 194.93,20.51 194.86,20.43 194.31,20.43 194.23,20.51 193.55,20.51 193.47,20.43 190.27,20.43 189.77,19.93 175.65,19.93 173.16,17.44 172.69,17.44 171.25,18.88 164.69,18.88 164.43,19.14 157.81,19.14 157.69,19.02 156.48,19.02 155.98,18.52 v2(155.98,18.2) 155.98,17.74 155.79,17.55 149.93,17.55 148.9,18.58 129.05,18.58 128.51,18.04 128.51,17.58 128.37,17.44 127.91,17.44 124.73,14.26 123.21,14.26 123.09,14.38 109.62,14.38 109.53,14.29 108.14,14.29 107.12,13.27 105.99,13.27 105.89,13.17 105.89,12.64 105.79,12.53 105.59,12.53 105.49,12.64 105.49,13.17 105.38,13.27 105.18,13.27 105.08,13.17 105.08,12.64 104.98,12.53 104.77,12.53 104.67,12.64 104.67,13.17 104.57,13.27 104.37,13.27 104.27,13.17 104.27,12.64 104.16,12.53 103.96,12.53 103.86,12.64 103.86,13.17 103.76,13.27 103.56,13.27 103.45,13.17 103.45,12.64 103.35,12.53 103.15,12.53 103.05,12.64 103.05,13.17 102.95,13.27 102.67,13.27 100.89,11.49 100.12,11.49 99.84,11.21 v2(99.84,10.43)
  BOTTOM w0.089: RN2503.1 157.06,18.76 156.97,18.85 156.97,18.96 156.88,19.05 156.7,19.05 156.62,18.96 156.62,18.85 156.53,18.76 156.24,18.76 155.98,18.49 v2(155.98,18.2) ; RN1803.2 99.18,30.83 98.45,30.09 98.45,29.91 97.31,28.78 97.31,27.4 98.1,26.61 v2(98.13,26.61)
SPI_SO_ROM_R: length 15.4
  BOTTOM w0.089: SPI25.2 160.68,17.61 160.47,17.82 160.15,17.82 v1(159.94,17.61) 159.94,17.32 159.81,17.19 159.53,17.19 159.41,17.32 159.41,17.36 159.28,17.49 158.97,17.49 158.85,17.61 EC2502.1 158.85,17.94 159.58,18.67 160.24,18.67 160.37,18.8 160.37,20.92 160.24,21.04 158.77,21.04 158.64,20.92 158.64,20.66 158.77,20.53 159.79,20.53 159.91,20.41 159.91,20.02 159.82,19.93 159.14,19.93 159.05,19.84 159.05,19.66 159.14,19.57 159.82,19.57 159.91,19.48 159.91,19.26 159.79,19.14 159.31,19.14 158.93,18.76 RN2503.4
SPI_SO_ROM_TPM2: length 4.6
  TOP w0.089: R9134.2 212.09,29.97 v1(212.27,29.97) 212.27,29.98 212.61,29.98 212.87,30.24 U9101.24
SPI_WP_CPU: length 11.6
  BOTTOM w0.089: CPU1.AW2 109.84,35.51 109.56,35.24 109.56,34.83 109.13,34.4 105.71,34.4 105.54,34.23 105.01,34.23 103.86,33.08 103.7,33.08 102.25,31.63 v1(101.7,31.63) 101.38,31.63 101.37,31.64 101.06,31.64 100.78,31.91 RN1803.5
SPI_WP_ROM: length 108.1
  TOP w0.089: RN1802.3 96.09,28.29 96.34,28.04 97.92,28.04 98.22,27.73 98.22,27.31 97.8,26.88 97.32,26.88 v2(97.1,26.66) 97.02,26.58 97.02,17.28 97.73,16.57 97.73,15.48 98.52,14.7 98.52,12.63 98.24,12.35 98.24,11.01 98.57,10.68 v2(98.57,10.43)
  L6 w0.102: v2(155.11,18.22) 155.11,18.48 154.91,18.68 151.21,18.68 151.11,18.78 151.11,19.14 151.01,19.25 150.8,19.25 150.7,19.14 150.7,18.78 150.6,18.68 150.4,18.68 150.29,18.78 150.29,19.14 150.19,19.25 149.99,19.25 149.89,19.14 149.89,18.78 149.79,18.68 149.45,18.68 149.09,19.04 147.99,19.04 147.86,19.16 147.58,19.16 147.46,19.04 147.18,19.04 147.05,19.16 146.77,19.16 146.64,19.04 146.36,19.04 146.24,19.16 145.96,19.16 145.83,19.04 145.55,19.04 145.42,19.16 145.14,19.16 145.02,19.04 144.74,19.04 144.61,19.16 144.33,19.16 144.2,19.04 143.1,19.04 143,19.14 143,19.57 142.9,19.67 142.7,19.67 142.59,19.57 142.59,19.14 142.49,19.04 142.29,19.04 142.19,19.14 142.19,19.57 142.09,19.67 141.88,19.67 141.78,19.57 141.78,19.14 141.68,19.04 140.51,19.04 140.41,19.14 140.41,19.57 140.31,19.67 140.1,19.67 140,19.57 140,19.14 139.9,19.04 139.7,19.04 139.6,19.14 139.6,19.57 139.49,19.67 139.29,19.67 139.19,19.57 139.19,19.14 139.09,19.04 137.31,19.04 137.21,19.14 137.21,19.57 137.11,19.67 136.9,19.67 136.8,19.57 136.8,19.14 136.7,19.04 136.5,19.04 136.39,19.14 136.39,19.57 136.29,19.67 136.09,19.67 135.99,19.57 135.99,19.14 135.89,19.04 135.68,19.04 135.58,19.14 135.58,19.57 135.48,19.67 135.28,19.67 135.18,19.57 135.18,19.14 135.07,19.04 134.81,19.04 134.68,19.16 134.68,19.39 134.56,19.52 134.36,19.52 134.23,19.39 134.23,19.16 134.1,19.04 133.87,19.04 133.72,19.18 133.55,19.18 133.46,19.18 133.32,19.04 133.06,19.04 132.91,19.18 132.65,19.18 132.5,19.04 132.24,19.04 132.1,19.18 131.84,19.18 131.69,19.04 131.43,19.04 131.29,19.18 131.03,19.18 130.88,19.04 130.62,19.04 130.47,19.18 130.21,19.18 130.07,19.04 129.81,19.04 129.66,19.18 129.4,19.18 129.25,19.04 128.86,19.04 125.23,15.4 119.4,15.4 119.09,15.1 113.71,15.1 113.44,14.83 109.43,14.83 109.34,14.74 107.95,14.74 106.94,13.73 106.05,13.73 105.95,13.83 105.95,13.96 105.85,14.06 105.65,14.06 105.55,13.96 105.55,13.83 105.45,13.73 105.24,13.73 105.14,13.83 105.14,13.96 105.04,14.06 104.84,14.06 104.73,13.96 104.73,13.83 104.63,13.73 104.43,13.73 104.33,13.83 104.33,13.96 104.23,14.06 104.02,14.06 103.92,13.96 103.92,13.83 103.82,13.73 103.62,13.73 103.51,13.83 103.51,13.96 103.41,14.06 103.21,14.06 103.11,13.96 103.11,13.83 103.01,13.73 102.48,13.73 100.7,11.95 98.57,11.95 98.24,11.62 98.24,11.01 98.57,10.68 v2(98.57,10.43)
  BOTTOM w0.089: v1(155.09,17.61) 155.09,18.2 v2(155.11,18.22) 155.4,18.22 156.44,19.26 RN2503.2 ; v2(97.1,26.66) 96.69,26.66 96.18,27.16 96.18,29.71 97.02,30.55 97.49,30.55 98.85,31.91 RN1803.4
SPI_WP_ROM_R: length 7.6
  BOTTOM w0.089: RN2503.3 158.69,20.1 v1(158.64,20.15) 158.52,20.15 158.39,20.28 158.39,21.17 158.52,21.3 160.46,21.3 160.59,21.17 160.59,19.18 160.88,18.88 SPI25.3
SPI_WR_PROT_HDMI: length 15.3
  TOP w0.089: U5701.E2 24,72.53 24.33,72.86 24.33,73.19 21.86,75.65 v1(21.86,76.03) 21.74,76.16 18.87,76.16 v2(18.69,75.98)
  BOTTOM w0.089: R5741.1 18.69,74.69 v2(18.69,75.98) 18.69,77.61 17.19,79.11 U5702.3
SPK_I2C_CLK: length 4.9
  TOP w0.089: v2(28.06,17.99) 28.09,17.97 RN2701.2 ; v2(27.53,15.59) 27.21,15.27 HDA27.7
  BOTTOM w0.089: v2(28.06,17.99) 27.53,17.46 v1(27.53,16.47) v2(27.53,15.59)
SPK_I2C_DATA: length 7.1
  TOP w0.089: v2(28.06,18.63) 28.44,18.63 28.45,18.64 RN2701.1 ; v2(27.55,14.96) 27.41,14.96 27.33,14.87 HDA27.6
  BOTTOM w0.089: v2(28.06,18.63) 27.76,18.63 26.69,17.56 v1(26.69,15.58) 27.31,14.96 v2(27.55,14.96)
SPK_ID: length 112.4
  TOP w0.089: v2(111.02,33.3) 111.94,34.22 112.5,34.22 112.74,33.98 112.74,33.8 113.31,33.23 113.92,33.23 114.3,32.86 114.3,31.86 114.73,31.43 v1(114.8,31.43) 116.85,31.43 117.06,31.64 118.12,31.64 118.43,31.33 v2(118.92,31.33)
  L4 w0.089: v2(92.48,27.14) 92.47,27.13 92.47,25.86 90.7,24.09 90.44,24.09 84.98,18.63 81.17,18.63 79.14,16.6 74.57,16.6 71.22,13.25 39.82,13.25 37.95,15.12 36.29,15.12 33.84,12.66 v2(32.66,12.66)
  L6 w0.089: v2(111.02,33.3) 108.19,33.3 106.54,31.66 100.07,31.66 98.58,30.17 94.19,30.17 92.48,28.45 v2(92.48,27.14)
  BOTTOM w0.089: R2047.2 119.32,29.91 119.32,30.44 118.92,30.85 v2(118.92,31.33) 119.25,31.33 119.55,31.63 119.55,32.3 119.12,32.72 119.12,34.76 CPU1.AB1 ; SPK1.5 28.55,11.35 29.23,12.03 32.02,12.03 v2(32.66,12.66)
SPKR: length 118.6
  TOP w0.254: v2(110.31,36.94) 110.17,37.08 108.06,37.08 v1(108.04,37.06) 107.19,36.21 106.79,36.21 105.83,37.17 96.72,37.17 R1910.2 96.03,35.5 96.39,35.15 96.39,34.7 95.4,33.71 95.4,33.7 95.1,33.41 v2(94.38,33.41) ; RN2702.2 15,8.87 14.8,8.67 v2(13.76,8.67)
  L4 w0.254: v2(13.76,8.67) 14.22,9.13 26.59,9.13 28.45,10.99 28.45,11.52 28.96,12.03 33.8,12.03 36.47,14.69 37.77,14.69 39.64,12.83 71.4,12.83 74.75,16.17 79.32,16.17 81.35,18.2 85.16,18.2 90.62,23.67 90.87,23.67 92.98,25.78 92.98,28.94 93.49,29.45 93.49,31.88 94.38,32.77 v2(94.38,33.41)
  BOTTOM w0.254: CPU1.AW5 v2(110.31,36.94)
SRTC_RST#: length 66
  TOP w0.089: C1805.1 73.1,21.27 RN1801.4 ; C1805.1 EC1806.1 74.41,20.72 v1(74.98,20.72) ; C1805.1 72.54,21.07 71.95,20.48 71.95,18.83 v2(72.28,18.5)
  L3 w0.089: v2(72.28,18.5) 72.28,18.88 73.6,20.2 80.84,20.2 87.02,26.38 87.66,26.38 87.66,26.38 89.07,26.38 89.56,25.89 93.87,25.89 95.42,27.43 95.42,28.46 95.72,28.77 100.21,28.77 103.32,31.88 103.72,31.88 104.78,32.94 105.23,32.94 105.62,32.55 106.43,32.55 108.46,34.57 108.46,42.84 111.36,45.74 113.06,45.74 v2(113.48,45.32)
  BOTTOM w0.089: CPU1.AN18 113.8,44.99 v2(113.48,45.32)
SSD_DEVSLP: length 126.1
  TOP w0.089: R6304.1 R6303.2 R6301.1 229.81,18.33 229.56,18.58 224.61,18.58 224.36,18.83 222.37,18.83 v2(221.3,19.9)
  L3 w0.089: v2(221.3,19.9) 220.16,19.9 214.57,14.31 210,14.31 207.33,11.64 197.35,11.64 195.66,13.34 188.79,13.34 183.9,18.23 176.75,18.23 172.25,22.73 147.48,22.73 147.26,22.95 130.65,22.95 129.13,24.47 129.13,28.53 v2(127.6,30.05)
  BOTTOM w0.089: CPU1.J3 125.58,35.88 125.58,33.74 125.8,33.51 125.8,31.04 v1(125.52,30.76) 126.24,30.05 v2(127.6,30.05)
SSEQ0_A0: length 5.9
  TOP w0.089: U3801.11 39.52,55.58 40.91,54.19 40.91,53.48 R3846.1 R3845.2 42.26,52.89 v1(43.07,52.89)
SSEQ1: length 4.7
  TOP w0.089: R3852.2 R3844.1 34.44,51.27 v1(34.89,51.73) 35.97,52.8 35.97,53.39 36.12,53.54 U3801.3
STRAP0: length 18.5
  TOP w0.089: v2(177.95,68.79) 178.58,68.79 v1(178.82,68.55) 179.09,68.29 R7619.2
  L3 w0.089: v2(168.17,69.43) 169.01,70.27 172.76,70.27 174.62,68.41 177.57,68.41 v2(177.95,68.79)
  BOTTOM w0.089: R7608.1 v2(168.17,69.43) 168.17,70.06 168.83,70.73 169.51,70.73 170.48,71.7 170.48,72.38 170.55,72.45 GPU1.D1
STRAP1: length 21
  TOP w0.089: v2(177.31,68.92) 177.31,68.34 v1(177.98,67.68) 178.13,67.52 R7609.2
  L3 w0.089: v2(167.41,69.43) 168.47,70.5 172.9,70.5 174.72,68.67 177.06,68.67 v2(177.31,68.92)
  BOTTOM w0.089: GPU1.D2 170.55,73.24 170.19,72.88 170.19,72.42 170.26,72.35 170.26,71.8 169.41,70.95 167.91,70.95 167.41,70.45 v2(167.41,69.43) R7611.1
STRAP2: length 24.9
  TOP w0.089: v1(176.8,69.56) v2(177.44,69.56) 177.65,69.56 177.71,69.49 178.68,69.49 179.12,69.05 R7614.2
  L3 w0.089: v2(177.44,69.56) 174.19,69.56 173.03,70.73 167.94,70.73 v2(166.64,69.43)
  BOTTOM w0.089: R7615.1 v2(166.64,69.43) 166.64,70.32 167.53,71.21 169.33,71.21 169.53,71.41 169.54,71.41 170,71.87 170,72.25 169.94,72.31 169.94,72.99 170.12,73.16 170.12,74.68 GPU1.E4
STRAP3: length 24.7
  TOP w0.089: v2(176.8,70.19) 177.76,70.19 178.2,69.75 v1(179.73,69.75) 181.13,69.75 R7625.2
  L3 w0.089: v2(176.8,70.19) 176.55,69.94 174.14,69.94 173.12,70.95 167.41,70.95 v2(165.88,69.43)
  BOTTOM w0.089: GPU1.E3 169.28,73.88 167.79,73.88 167.66,73.75 167.66,72.35 165.88,70.57 v2(165.88,69.43) R7626.1
STRAP4: length 18.3
  TOP w0.089: v1(176.55,67.65) v2(177.19,67.65) 178.07,66.76 R7628.2
  L3 w0.089: v2(168.93,69.43) 169.54,70.04 172.63,70.04 174.51,68.16 176.68,68.16 v2(177.19,67.65)
  BOTTOM w0.089: GPU1.D3 170.55,73.98 170.94,73.58 170.94,71.82 168.93,69.81 v2(168.93,69.43) R7629.1
STRAP_REF0_GND_N9: length 2.1
  TOP w0.089: R7607.2 168.8,76.85 v2(168.45,77.2) 168.86,77.6 v1(168.91,77.6)
  BOTTOM w0.089: v2(168.45,77.2) GPU1.F6
SUS_CLK: length 133
  TOP w0.089: R1813.1 93.11,48.98 85.57,41.45 85.57,20.19 82.54,17.16 82.54,14.29 85.26,11.57 86.48,11.57 88.56,9.49 88.56,6.29 89.03,5.82 v2(89.43,5.82) ; v2(154.73,3.52) 154.73,3.09 154.6,2.96 v1(154.6,2.45) 154.6,2.42 154.87,2.15 159.19,2.15 159.36,2.32 R2461.1
  L3 w0.127: v2(89.43,5.82) 90.08,6.46 91.82,6.46 92.78,7.43 103.88,7.43 104.48,8.03 109.85,8.03 111.6,9.78 115.64,9.78 116.11,9.31 124.11,9.31 125.75,7.67 128.16,7.67 128.69,8.2 132.05,8.2 134.25,5.99 134.58,5.67 135.84,4.41 137.43,4.41 v2(137.94,3.9)
  BOTTOM w0.089: v2(154.73,3.52) 154.14,2.93 150.18,2.93 149.4,2.15 145.91,2.15 145.31,2.75 139.09,2.75 v2(137.94,3.9)
SUSACK#_R: length 29.6
  L3 w0.089: v2(113.44,28.54) 113.44,29.43 114.37,30.37 114.37,33.51 114.82,33.96 114.82,34.75 116.5,36.43 116.5,37.2 116.42,37.28 116.42,40.08 116.08,40.42 116.03,40.42 115.3,41.15 113.88,41.15 113.5,40.77 v2(113.48,40.77)
  BOTTOM w0.089: R1708.2 116.15,19.6 116.42,19.86 116.42,20.79 116.03,21.18 115.86,21.18 v1(115.54,21.5) 115.15,21.89 112.96,21.89 112.4,22.46 112.4,26.36 112.91,26.87 112.91,28.01 v2(113.44,28.54) ; CPU1.AP11 v2(113.48,40.77)
SUSCLK: length 14.8
  TOP w0.089: v2(105.61,44.35) 101.95,44.35 v1(100.96,45.34) 100.23,46.08 100.23,48.13 98.61,49.74 EC1803.2 98.27,49.01 R1813.2
  BOTTOM w0.089: v2(105.61,44.35) 105.62,44.36 108.48,44.36 CPU1.BA17
SYS_PEX_RST_MON#: length 10.4
  BOTTOM w0.089: R7313.1 144.37,69.14 U7301.4 ; U7301.4 144.43,69.81 144.18,70.06 142.21,70.06 R7304.2 ; U7301.4 144.53,69.11 D7301.2 145.94,69.58 R7306.1 145.99,70.45 R7634.2 v1(147.42,71.41)
SYS_PEX_RST_MON_GPU#: length 31.7
  TOP w0.089: v1(149.5,71.59) 149.63,71.72 v2(150.13,71.72) ; R7643.1 169.32,79.64 v2(169.35,79.67)
  L3 w0.089: v2(169.35,79.67) 167.94,79.67 167.72,79.9 167.39,79.9 167.15,79.66 167.15,79.08 165.82,77.75 165.82,73.43 161.88,69.49 152.36,69.49 v2(150.13,71.72)
  BOTTOM w0.089: GPU1.E9 169.74,79.28 v2(169.35,79.67) ; v2(150.13,71.72) 149.55,71.72 R7634.1
SYS_PRES1#: length 4.3
  TOP w0.089: R4301.2 187.8,20.31 187.2,20.92 v2(187.2,21.09) 187.2,21.17 187.09,21.28 AFTP4315.1
  BOTTOM w0.089: BATT1.7 v2(187.2,21.09)
SYS_PWROK: length 74.4
  TOP w0.127: v2(167.03,18.25) 166.39,18.88 v1(166.39,19.53) 166.39,23.34 v2(165.07,24.66) ; KBC24.28 155.17,20.18 v2(153.21,18.22)
  L3 w0.127: v2(153.21,18.22) 153.75,18.77 158.12,18.77 159.41,17.49 166.26,17.49 v2(167.03,18.25) ; v2(165.07,24.66) 164.61,24.19 154.55,24.19 154.22,24.52 154.22,25.26 153.19,26.29 141.96,26.29 137.08,31.17 v2(137.08,34.73)
  BOTTOM w0.127: CPU1.B6 129.95,37.73 130.26,37.43 130.56,37.43 130.59,37.46 130.92,37.46 132.6,35.78 132.6,35.15 133.88,33.87 136.22,33.87 v2(137.08,34.73) R1717.1 EC1702.1
SYSPWR_PRES: length 4.6
  TOP w0.089: KBC24.120 153.64,7.37 153.87,7.15 154,7.15 154.33,6.81 v1(154.33,6.36) 153.97,5.99 R2454.1 154.73,4.33 R2463.2
T_CRIT#: length 3.6
  TOP w0.102: v1(44.09,13.47) R2601.1 R2604.2 46.36,13.72 THM261.4
TCH_I2C_SCL: length 48.1
  TOP w0.089: v1(80.41,100.32) 79.73,100.32 R5521.1 R5517.2 78.76,98.89 v2(79.01,98.64)
  L4 w0.127: v2(116.17,90.69) 116.17,92.47 114.36,94.28 86.77,94.28 84.91,96.14 80.75,96.14 79.01,97.88 v2(79.01,98.64)
  BOTTOM w0.089: v2(116.17,90.69) 116.38,90.89 116.38,91.61 ED5501.3 ; v2(79.01,98.64) 78.55,98.18 TCBD1.18
TCH_I2C_SDA: length 46
  TOP w0.089: R5522.1 R5518.2 v1(78,99.2) 78,98.89 v2(78.25,98.64)
  L4 w0.127: v2(114.75,92.87) 114.75,93.35 114.2,93.9 86.61,93.9 84.75,95.76 80.5,95.76 78.25,98 v2(78.25,98.64)
  BOTTOM w0.089: ED5501.4 115.49,94.06 114.75,93.32 v2(114.75,92.87) ; TCBD1.17 78.05,98.44 v2(78.25,98.64)
TCH_INTR#: length 5
  TOP w0.089: v1(78.51,97.27) 78.23,97.55 R5523.1 77.59,97.57 ED5502.1 76.73,97.82 v2(77.55,98.64)
  BOTTOM w0.089: TCBD1.16 v2(77.55,98.64)
TCH_REPORT_SWITCH: length 3.6
  TOP w0.089: v1(75.74,98.23) 75.74,98.41 v2(76.09,98.77) 76.4,99.07 R5543.1
  BOTTOM w0.089: v2(76.09,98.77) 76.55,98.31 TCBD1.14
TCH_RST#: length 3.1
  TOP w0.305: R5544.1 77.16,95.33 v2(77.24,95.4) 77.73,95.4 v1(77.79,95.34)
  BOTTOM w0.305: TCBD1.15 77.05,95.59 v2(77.24,95.4)
TESTMODE: length 8.9
  BOTTOM w0.089: v1(149.35,85.05) R7302.1 150.11,84.06 151.21,82.96 151.21,81.31 151.96,80.56 151.96,79.95 152.22,79.69 152.52,79.69 153.54,79.69 GPU1.AD9
THERM_SYS_SHDN#: length 119.5
  TOP w0.102: R2601.2 45.36,12.14 Q2602.S v1(48.28,9.22) 48.28,6.74 47.65,6.11 47.65,5.17 v2(47.01,4.53)
  L3 w0.102: v2(47.01,4.53) 47.41,4.93 50.38,4.93 50.56,5.11 57.62,5.11 57.98,4.75 61.45,4.75 61.89,5.18 78.52,5.18 82.27,8.93 83.42,8.93 85.36,10.87 87.54,10.87 88.11,11.44 94.31,11.44 95.84,12.97 107.22,12.97 108.32,14.06 122.15,14.06 122.52,13.69 127.11,13.69 129.02,11.77 135.95,11.77 136.33,12.15 139.71,12.15 140.57,13.01 144.39,13.01 144.73,13.35 v2(149.3,13.35)
  BOTTOM w0.102: v2(149.3,13.35) 149.28,13.37 149.28,13.71 R2602.1
THM_SML1_CLK: length 7.4
  TOP w0.089: THM261.8 52.43,15.67 52.93,16.17 RN2602.3 53.41,16.19 53.41,16.95 C2608.1 53.44,17.82 v1(53.87,18.25) 54.63,18.25 56.09,16.79 Q2601.4
THM_SML1_DATA: length 8.9
  TOP w0.089: THM261.7 52.54,15.02 53.03,15.5 RN2602.4 53.43,14.84 C2609.1 53.28,14.64 53.71,14.22 55.36,14.22 55.77,13.8 v1(56.54,13.8) 57.01,13.8 57.74,14.53 Q2601.1
TOP_MUX_N: length 6
  TOP w0.102: v2(8.39,93.3) 8.78,92.9 8.78,92.71 9.09,92.4 9.09,91.54 9.26,91.38 9.47,91.38 ED3804.1 9.6,91.71 9.75,91.86 10.28,91.86 10.46,92.04 R3862.2
  BOTTOM w0.102: v2(8.39,93.3) 8.19,93.3 8.1,93.4 7.3,93.4 7.25,93.35 USB1.A7
TOP_MUX_N_L: length 65.1
  TOP w0.102: EL3801.4 12.88,92 13.19,92.3 v2(13.28,92.3) ; 32.41,43.07 32.27,43.07 31.87,42.68 31.6,42.68 31.2,43.07 31.01,43.07 30.73,43.35 v2(30.73,43.36) ; 32.41,43.07 32.95,43.07 33.04,43.16 U3802.17 ; 32.41,43.07 v1(32.41,43.22)
  L4 w0.14: v2(13.28,92.3) 13.4,92.18 13.98,92.18 14.28,91.87 20.18,85.97 20.34,85.81 20.34,81.68 24.44,77.58 24.44,77.42 28.34,73.52 28.34,71.84 33.92,66.27 33.92,54.28 29.87,50.22 29.87,43.34 30.06,43.14 30.52,43.14 v2(30.73,43.36)
TOP_MUX_P: length 6.1
  TOP w0.102: v2(8.35,92.66) 8.51,92.66 8.86,92.3 8.86,91.45 9.16,91.15 9.93,91.15 10,91.22 ED3804.2 10.39,91.5 10.61,91.27 R3861.2
  BOTTOM w0.102: USB1.A6 7.21,92.85 7.52,93.17 7.91,93.17 8.35,92.72 v2(8.35,92.66)
TOP_MUX_P_L: length 65.2
  TOP w0.102: 31.57,42.45 31.5,42.45 31.11,42.85 31.01,42.85 v2(30.73,42.57) ; 31.57,42.45 31.97,42.45 32.36,42.85 32.91,42.85 33,42.76 U3802.18 ; 31.57,42.45 v1(31.57,42.3) ; EL3801.1 12.89,91.31 v2(13.23,91.65)
  L4 w0.14: v2(13.23,91.65) 13.3,91.65 13.56,91.91 13.87,91.91 14.24,91.54 20.07,85.7 20.07,81.57 24.18,77.47 24.18,77.3 28.07,73.41 28.07,71.73 33.65,66.16 33.65,54.39 29.6,50.33 29.6,43.23 29.95,42.88 30.42,42.88 v2(30.73,42.57)
TOUCH_DETECT: length 4.6
  TOP w0.089: R5504.1 74.75,97.22 R2039.1 74.77,98.08 v2(74.82,98.13) 74.7,98.13 v1(74.24,98.59)
  BOTTOM w0.089: v2(74.82,98.13) 75.71,98.13 76.05,97.79 TCBD1.13
TOUCH_PAD_INTR#: length 12
  BOTTOM w0.089: R410.2 R404.2 99.99,33.18 101.19,33.18 v1(102.65,34.64) 104.15,34.64 105.63,36.12 107.06,36.12 108.02,37.09 108.38,37.09 CPU1.BA5
TOUCH_PANEL_INTR#: length 165.5
  TOP w0.127: R5545.2 76.91,95.97 R5523.2 79.04,95.26 v2(81.64,95.26) ; v2(129.69,31.33) 130.96,31.33 131.08,31.2 134.39,31.2 135.4,32.22 v1(135.4,34.31) 135.4,34.63 134.94,35.09 v2(134.49,35.09)
  L3 w0.127: v2(93.24,13.04) 94.37,14.17 104.53,14.17 106.89,16.53 122.08,16.53 123.95,18.41 123.95,18.99 127.4,22.44 127.4,26.84 126.02,28.22 126.02,29.1 128.25,31.33 v2(129.69,31.33)
  BOTTOM w0.127: v2(81.64,95.26) 81.5,95.12 81.5,80.63 87.2,74.94 87.2,30.15 90.05,27.29 90.05,23.05 87.46,20.45 87.46,19.72 88.11,19.06 93.44,19.06 94.24,18.26 94.24,17.73 92.85,16.33 92.85,13.43 v2(93.24,13.04) ; CPU1.A7 130.81,38.41 134.13,35.09 v2(134.49,35.09) 134.79,35.39 R2429.1
TOUCH_PANEL_PD#: length 106
  TOP w0.089: v2(75.76,95.34) 75.76,95.12 R5544.2
  L3 w0.089: v2(109.75,36.6) 109.75,34.48 106.17,30.91 104.22,30.91 99.84,26.53 99.56,26.53 97.99,24.96 88.77,24.96 v2(88.54,25.2) ; v2(74.98,88.76) 74.98,92.06 75.76,92.84 v2(75.76,95.34)
  BOTTOM w0.089: v2(75.76,95.34) 75.78,95.36 v1(76.32,95.36) ; CPU1.AY5 109.71,36.64 v2(109.75,36.6) ; v2(88.54,25.2) 88.54,27.27 86.13,29.68 86.13,74.37 74.98,85.52 v2(74.98,88.76)
TOUCH_REPORT_SW: length 283
  TOP w0.089: D2402.A v1(139.09,28.49) 137.91,28.49 v2(137.24,27.82) ; v2(74.82,98.77) 75.53,99.48 R5543.2
  L3 w0.089: v2(74.82,98.77) 75.46,99.4 75.46,100.42 74.95,100.93 69.49,100.93 68.98,100.42 68.98,98.26 69.36,97.88 69.36,93.56 64.41,88.61 64.41,87.97 63.9,87.46 61.74,87.46 60.98,88.23 60.98,89.75 58.82,91.91 43.96,91.91 43.58,91.53 40.91,91.53 39.22,93.22 39.21,93.22 39.12,93.31 34.56,93.31 32.28,91.02 32.28,87.46 30.94,86.12 30.94,77.63 32.79,75.78 32.79,70.32 33.42,69.68 37.99,69.68 47.56,60.11 47.56,59.19 46.38,58 46.38,51.27 43.96,48.86 43.96,35.9 41.68,33.62 41.68,28.08 40.35,26.76 38.88,26.76 38.25,26.12 38.25,20.96 36.51,19.23 36.51,16.43 38.27,14.67 38.27,13.78 46.43,5.63 49.6,5.63 49.78,5.8 57.93,5.8 58.29,5.44 59.6,5.44 59.82,5.66 59.89,5.66 60.14,5.91 60.14,5.97 61.36,7.2 76.98,7.2 83.21,13.42 84.48,13.42 85.11,14.06 89.43,14.06 91.08,15.71 97.56,15.71 98.42,16.57 104.26,16.57 106.07,18.38 112.8,18.38 113.94,17.23 122.45,17.23 123.72,18.5 123.72,19.14 127.15,22.57 127.15,26.76 125.62,28.28 125.62,30.06 128.16,32.6 129.94,32.6 134.72,27.82 v2(137.24,27.82)
TP_EN#: length 50.6
  TOP w0.127: RN2406.2 151.98,25.87 151.84,25.73 151.84,25.17 v2(151.79,25.11) 150.57,25.11 v1(150.44,24.98) KBC24.49
  L6 w0.127: v2(128.42,23.33) 129.12,22.62 133.69,22.62 134.76,23.69 136.42,23.69 137.01,24.28 140.65,24.28 141.24,23.69 143.38,23.69 144.8,25.11 v2(151.79,25.11)
  BOTTOM w0.127: v2(128.42,23.33) 128.42,22.82 128.39,22.8 128.39,18.2 128.4,18.19 128.4,17.22 127.43,16.24 127.43,14.31 125.53,12.41 121.69,12.41 120.42,13.68 118.54,13.68 118.28,13.93 R6504.1
TP_ON#_GATE: length 9.3
  BOTTOM w0.089: Q6503.G 120.2,15.38 v1(119.35,15.38) 119.2,15.38 118.27,14.45 117.08,14.45 R6504.2 116.87,13.61 116.88,13.61 117.32,13.18 117.32,13.17 C6502.2 119.13,13.17 119.38,12.91 119.79,12.91 Q6502.G
TP_VDD: length 46.7
  TOP w0.381: v2(123.36,14.74) 123.36,12.89 126.51,9.74 AFTP6531.1 126.71,8.91 126.82,8.91 127.4,8.33 v2(127.4,8.22) ; v2(138.96,9.23) 139.97,8.22 139.97,6.56 v2(140.74,5.8)
  BOTTOM w0.305: 137.92,9.23 137.9,9.22 TPCON1.8
  BOTTOM w0.381: C6505.1 156.05,6.47 155.07,5.49 151.85,5.49 149.25,2.88 146.07,2.88 143.78,5.17 141.37,5.17 v2(140.74,5.8) ; v2(127.4,8.22) 127.52,8.22 129.23,9.92 129.24,9.92 129.75,10.44 130.44,10.44 R6511.1 130.78,10.76 136.39,10.76 137.92,9.23 v2(138.96,9.23)
TP_VPPNC3: length 1.7
  TOP w0.089: VRAM2.A5 176.04,117.39 TP7803.1
TP_VPPNC4: length 4.8
  TOP w0.089: VRAM2.U5 175.95,104.56 176.28,104.88 v2(176.38,104.88)
  BOTTOM w0.089: v2(176.38,104.88) 178.1,103.15 TP7804.1
TP_VPPNC5: length 4.4
  TOP w0.089: v2(159.46,104.72) 158.28,104.72 157.92,105.07 157.92,106.47 VRAM3.A5
  BOTTOM w0.089: v2(159.46,104.72) 159.16,104.42 TP7901.1
TP_VPPNC6: length 3.1
  TOP w0.089: VRAM3.U5 157.95,122.33 TP7902.1
TP_VPPNC7: length 1.6
  BOTTOM w0.089: TP7903.1 158.01,119.36 VRAM4.A5
TP_VPPNC8: length 3
  BOTTOM w0.089: VRAM4.U5 157.92,106.47 157.92,103.54 TP7904.1
TP_WAKE_KBC#: length 127.8
  TOP w0.089: v2(126.64,8.22) 125.75,9.1 125.75,9.87 120.8,14.82 118.64,14.82 AFTP6536.1 v2(117.37,16.09) ; v2(156.48,21.88) 156.84,22.24 KBC24.33
  L3 w0.089: v2(117.37,16.09) 120.97,16.09 122.77,14.29 125.6,14.29 128.54,17.23 131.7,20.38 132.24,20.38 132.33,20.47 136.17,20.47 137.44,21.74 146.39,21.74 147.06,21.07 155.68,21.07 v2(156.48,21.88) ; v2(92.3,22.24) 92.77,22.71 98.08,22.71 98.85,23.48 99.16,23.48 99.59,23.91 99.59,24.55 v2(99.99,24.95)
  L4 w0.089: v2(117.37,16.09) 116.94,16.52 112.34,16.52 111.89,16.07 109.23,16.07 109.03,16.27 102.49,16.27 101.86,15.63 100.38,15.63 99.11,16.9 97.45,16.9 93.07,21.28 93.07,21.62 92.71,21.98 92.55,21.98 v2(92.3,22.24)
  BOTTOM w0.089: v2(126.64,8.22) 127.15,7.71 127.53,7.71 129.38,9.56 R6511.2 133.29,9.56 136.59,6.27 141.24,6.27 141.9,6.92 TPCON1.4 ; R410.1 96.81,32.73 95.4,31.31 95.4,26.78 96.87,25.31 99.64,25.31 v2(99.99,24.95)
TPAN_VDD:
  vias: v1(75.08,94.32) v1(79.17,95.39) v1(79.6,97.9) v2(80.16,98.11)
TPCLK_C: length 8.5
  TOP w0.089: AFTP6532.1 146.71,6.39 v2(146.25,6.84)
  BOTTOM w0.089: v2(146.25,6.84) 146.25,7.73 146.03,7.95 TPCON1.1 144.9,9.31 145.52,9.92 RN6502.3
TPDATA_C: length 8.8
  TOP w0.089: AFTP6533.1 143.53,6.72 v2(143.63,6.82)
  BOTTOM w0.089: v2(143.63,6.82) 143.9,7.09 TPCON1.2 143.9,9.68 144.47,10.25 147.46,10.25 147.78,10.57 RN6502.4
TPM_GPIO0: length 3.4
  TOP w0.089: U9101.29 v1(215.61,30.01) 215.61,29.03 R9142.1 R9141.1
TPM_GPIO2: length 13.7
  TOP w0.089: 221.46,37.55 R9138.2 ; 221.46,37.55 R9120.1 ; 221.46,37.55 220.62,37.55 219.81,36.74 R9131.1 219.31,36.16 218.97,35.81 218.97,32.73 v2(218.71,32.47) 218.23,32.96 U9101.3
  BOTTOM w0.089: v2(218.71,32.47) 218.51,32.27 Q9102.D ; v2(218.71,32.47) 218.91,32.27 Q9104.D ; v2(218.71,32.47) 218.71,32.83 v1(218.51,33.03)
TPM_GPIO4: length 2.9
  TOP w0.089: U9101.13 215.11,36.71 215.47,37.08 v1(215.47,37.41) 214.47,38.4 R9133.1
TPM_ID: length 39.5
  TOP w0.089: R1912.2 149.68,28.28 147.42,28.28 R1911.1 144.77,27.65 143.84,26.71 142.94,26.71 141.74,27.92 140.89,27.92 140.82,27.99 138.2,27.99 137.6,27.39 137.07,27.39 136.82,27.64 136.82,28 137.18,28.36 137.18,28.92 135.28,30.82 130.7,30.82 130.02,30.14 129.46,30.14 129.21,30.39 129.21,32.23 v1(132.9,35.91) 133.55,36.56 v2(133.88,36.56)
  BOTTOM w0.089: CPU1.D8 129.33,38.97 129.62,39.27 130,39.27 130.2,39.08 131.01,39.08 131.9,38.19 133.1,36.99 133.65,36.99 133.88,36.77 v2(133.88,36.56)
TPM_SPI_IRQ#: length 107.5
  TOP w0.089: v2(139.47,23.84) 138.92,23.84 137.73,25.02 137,25.75 137,27.19 136.81,27.38 136.63,27.56 136.63,27.83 136.25,28.21 136.25,29.58 135.9,29.93 135.2,30.63 130.78,30.63 130.08,29.93 129.18,29.93 127.15,31.96 v1(126.26,31.96) 126.17,32.05 v2(125.38,32.05) ; R9150.1 207.49,35.34 v2(207.41,35.27)
  L6 w0.089: v2(139.47,23.84) 140.23,23.07 152.8,23.07 153.44,22.44 160.78,22.44 161.86,21.37 164.72,21.37 165.23,20.86 173.42,20.86 174.69,22.13 189.32,22.13 190.15,22.95 198.49,22.95 198.94,23.4 200.38,23.4 201.7,22.08 204.99,22.08 206.57,23.67 206.57,25.95 207.91,27.29 207.91,29.98 207.27,30.63 207.27,33.66 207.41,33.8 v2(207.41,35.27)
  BOTTOM w0.089: CPU1.M2 124.8,35.02 124.81,34.97 124.81,34.96 124.84,34.86 124.84,34.3 124.73,34.2 124.73,32.7 v2(125.38,32.05)
TPM_VDD14: length 2.6
  TOP w0.254: R9147.2 213.51,37.98 v1(214.08,37.41) 214.6,36.88 214.61,36.88 U9101.14
TPM_VDD22: length 3.3
  TOP w0.254: U9101.22 212.54,32.96 212.31,32.73 212.31,31.96 212.06,31.7 v1(211.72,31.7) 211.25,31.7 210.83,32.12 R9149.2
TPM_VSB: length 3
  TOP w0.254: v1(219.17,30.21) 219.3,30.34 R9144.2 218.81,31.46 218.31,31.96 U9101.1
TPS70933_EN: length 9
  TOP w0.089: R3739.2 37.86,35.15 U3702.4 ; R3739.2 36.85,34.15 36.85,32.85 38.42,31.29 38.42,30.14 Q3701.D ; R3739.2 37.23,34.94 v1(37.23,35.65) 37.74,36.16 R3740.1
TPS70933_EN_G: length 3.1
  TOP w0.089: R3738.2 42.23,29.5 v1(42.69,29.04) 42.39,28.74 C3720.2 41.01,28.74 Q3701.G
TS#_DIMM0_1: length 4.6
  TOP w0.089: R1215.2 59.41,51.73 v2(59.42,51.71) v1(59.48,51.14)
  BOTTOM w0.089: DM1.134 60.45,53.32 59.42,52.3 v2(59.42,51.71)
TS#_DIMM1_1: length 2.9
  TOP w0.089: R1312.2 47.67,53.96 v2(47.26,53.55) v1(46.63,53.55)
  BOTTOM w0.089: v2(47.26,53.55) 47.49,53.33 DM2.134
TYPEC_5V: length 2
  TOP w0.254: v1(36.27,72.68) 36.19,72.68 PR4339.2 35.5,73.59 PQ4309.3
TYPEC_5V_L: length 3.6
  TOP w0.254: v1(37.69,73.21) 37.68,73.23 PQ4309.4 37.09,74.11 36.85,74.36 36.85,75.14 37.12,75.41 PQ4309.6
TYPEC_5V_SW:
  vias: v1(36.85,91.27)
TYPEC_5V_SW_R: length 24.6
  TOP w0.254: PR4339.1 34.64,73.7 v2(34.95,74) ; PU4305.4 34.75,90.95 PR4330.1 34.97,91.27 v2(34.06,91.27) 33.83,91.27 v1(33.5,91.6) ; v2(35.91,85.81) PC4312.1 36.15,86.82 PU4306.4
  L6 w0.254: v2(34.95,74) 34.95,81.24 35.91,82.21 v2(35.91,85.81) 35.91,89.42 v2(34.06,91.27)
TYPEC_CON_RXN1: length 18
  TOP w0.102: 14.12,91.93 13.94,91.93 13.74,91.73 13.74,91.55 13.53,91.34 13.53,89.95 13.28,89.69 13.28,88.29 12.88,87.9 10.2,87.9 6.95,91.15 5.27,91.15 USB1.B10 ; 14.12,91.93 14.34,91.93 14.63,91.65 14.63,91.15 14.76,91.01 ED3801.4 ED3801.7 14.76,88.65 R3835.2 ; 14.12,91.93 v1(14.12,92.11)
TYPEC_CON_RXN2: length 9.5
  BOTTOM w0.102: 11.91,93.91 11.91,91.53 R3837.2 ; 11.91,93.91 11.91,94.81 11.63,95.09 11.19,95.09 10.89,94.79 ED3802.2 ED3802.9 9.32,94.79 8.8,95.31 7.74,95.31 7.28,94.85 USB1.A10 ; 11.91,93.91 v1(11.75,93.91)
TYPEC_CON_RXP1: length 17.6
  TOP w0.102: v1(12.69,87.51) 12.69,87.67 ; 12.69,87.67 10.1,87.67 6.85,90.92 5.33,90.92 USB1.B11 ; 12.69,87.67 12.98,87.67 13.51,88.2 13.51,89.6 13.76,89.85 13.76,91.25 13.96,91.45 13.96,91.64 14.03,91.71 14.24,91.71 14.4,91.55 14.4,91.17 14.26,91.04 ED3801.5 ED3801.6 14.26,88.67 R3834.2
TYPEC_CON_RXP2: length 9.5
  BOTTOM w0.102: 11.88,95.16 12.14,94.91 12.14,91.4 R3836.2 ; 11.88,95.16 v1(12.01,95.29) ; 11.88,95.16 11.72,95.32 11.1,95.32 11.07,95.29 ED3802.1 ED3802.10 9.15,95.29 8.9,95.54 7.65,95.54 7.46,95.35 USB1.A11
TYPEC_CON_TXN1: length 10
  BOTTOM w0.102: v1(11.5,92.67) 11.38,92.79 ; 11.38,92.79 11.16,92.57 10.31,92.57 10.18,92.44 10.18,91.45 R3833.2 ; 11.38,92.79 11.42,92.83 11.42,93.42 11.05,93.79 ED3802.4 ED3802.7 9.48,93.79 9.24,93.55 9.24,93.54 8.81,93.11 8.81,91.52 8.64,91.35 USB1.A3
TYPEC_CON_TXN2: length 16.5
  TOP w0.102: R3839.2 15.76,89.05 ED3801.9 ED3801.2 15.76,91.01 15.9,91.15 15.9,91.43 15.54,91.79 15.54,92.26 14.7,93.1 14.7,93.38 ; 14.7,93.38 v1(14.55,93.38) ; 14.7,93.38 14.7,94.05 13.28,95.47 7.65,95.47 7.21,95.04 5.25,95.04 USB1.B3
TYPEC_CON_TXP1: length 9.5
  BOTTOM w0.102: R3832.2 9.95,91.48 9.95,92.16 ; 9.95,92.16 9.95,92.54 10.21,92.8 11.07,92.8 11.2,92.92 11.2,93.18 11.09,93.29 ED3802.5 ED3802.6 9.31,93.29 9.04,93.02 9.04,91.43 8.73,91.12 7.47,91.12 7.2,90.85 USB1.A2 ; 9.95,92.16 v1(9.77,92.16)
TYPEC_CON_TXP2: length 17
  TOP w0.102: v1(14.42,94.91) 14.29,94.78 ; 14.29,94.78 14.93,94.14 14.93,93.2 15.77,92.36 15.77,91.88 16.12,91.53 16.12,91.15 16.26,91.01 ED3801.1 ED3801.10 16.26,89.31 R3838.2 ; 14.29,94.78 13.37,95.7 7.55,95.7 7.12,95.27 5.35,95.27 USB1.B2
TYPEC_SMBCLK: length 171
  TOP w0.089: v2(37.49,39.89) 38.04,40.45 R3853.1 ; v2(143.15,1.48) 143.15,1.38 143.61,0.93 143.96,0.93 144.29,1.26 144.29,1.7 144.07,1.92 144.07,3.02 143.97,3.12 143.97,3.15 143.44,3.67 Q2417.1 143.44,5.53 143.18,5.8 143.18,6.63 143.19,6.64 143.19,7.41 142.58,8.02 RN2413.3 141.83,8.77 141.12,9.49 140.74,9.49 v1(140.48,9.74) 140.48,10.41 141.45,11.38 KBC24.91
  L3 w0.127: v2(143.15,1.48) 143.15,2.25 142.32,3.07 134.13,3.07 133.44,3.77 133.44,5.27 133.44,5.27 133.44,5.59 131.69,7.34 129.14,7.34 128.63,6.82 125.27,6.82 124.32,7.77 116.42,7.77 115.26,8.93 111.97,8.93 110.22,7.18 105.55,7.18 100.96,2.59 84.2,2.59 83.65,3.14 79.64,3.14 79.1,3.68 78.78,3.68 75.82,3.68 75.02,2.88 69.3,2.88 68.28,3.9 64.6,3.9 64.22,3.52 59.42,3.52 58.79,2.88 55.96,2.88 54.67,4.18 54.66,4.18 54.62,4.22 50.79,4.22 49.98,3.41 48.18,3.41 47.71,2.94 47.71,2.74 47.45,2.48 45.96,2.48 45.06,3.37 40.84,3.37 39.81,4.4 39.81,9.81 35.58,14.03 35.58,19.77 v2(36.98,21.17)
  L6 w0.102: v2(37.49,39.89) 36.31,38.71 36.31,32 37.23,31.08 37.23,26.25 37.61,25.87 37.61,21.8 v2(36.98,21.17)
TYPEC_SMBDA: length 162
  TOP w0.089: v2(141.24,1.48) 142.14,2.38 Q2417.4 142.14,3.35 141.7,3.79 141.7,5.6 140.74,6.56 140.74,7.59 RN2413.4 140.05,9.13 v1(140.05,10.96) 140.05,11.21 141.02,12.18 KBC24.89 ; R3854.1 33.93,39.97 v2(33.8,39.84)
  L3 w0.127: v2(141.24,1.48) 141.24,1.68 140.99,1.93 133.43,1.93 132.74,1.23 128.79,1.23 123.39,6.62 116.89,6.62 115.95,6.62 114.79,7.78 112.44,7.78 110.69,6.03 106.02,6.03 101.44,1.45 83.72,1.45 83.22,1.95 81.13,1.95 80.92,1.74 65.55,1.74 64.92,2.37 59.89,2.37 59.23,1.71 55.42,1.71 v2(54.12,3.01)
  L6 w0.102: v2(53.36,6.63) 53.3,6.63 52.23,7.7 43.89,7.7 38.55,13.04 38.55,14.44 35.15,17.83 35.15,19.98 35.96,20.79 35.96,21.8 37.23,23.07 37.23,25.74 36.92,26.06 36.92,30.92 36.01,31.83 36.01,37.64 v2(33.8,39.84)
  BOTTOM w0.089: v2(54.12,3.01) 54.25,3.14 54.25,5.74 v2(53.36,6.63)
U22_POWER_K52: length 4.2
  TOP w0.127: R738.2 126.57,65.88 128.02,65.88 v1(128.05,65.86)
  TOP w0.508: v2(125.24,64.73) 125.27,64.76 125.52,64.76 125.98,65.22 125.98,65.29 R738.2
  BOTTOM w0.305: CPU1.K52 125.76,64.21 v2(125.24,64.73)
U4006_CT: length 2.9
  BOTTOM w0.089: U4006.6 112.81,11.03 113.08,11.31 113.08,12.52 v1(113.1,12.53) 112.54,13.09 C4017.1
UART_2_CRXD_DTXD: length 84.2
  TOP w0.089: v2(115.14,30.66) 115.38,30.66 v1(116.99,29.06) 120.69,25.36 123.1,25.36 126.79,21.67 127.29,21.17 127.77,21.17 129.74,19.2 129.74,14.92 130.28,14.38 133.05,14.38 133.5,13.94 133.5,12.77 134.88,11.39 135.83,10.43 135.83,9.56 v2(136.42,8.98)
  L3 w0.089: v2(173.88,6.41) 172.01,6.41 171.65,6.77 168.04,6.77 167.61,7.2 160.71,7.2 160.29,6.79 156.22,6.79 155.28,7.73 155.25,7.76 153.35,7.76 153.13,7.98 148.91,7.98 148.48,7.55 137.08,7.55 136.42,8.22 v2(136.42,8.98)
  BOTTOM w0.089: v2(173.88,6.41) 173.88,8.72 173.2,9.41 R6803.1 ; R2048.2 115.59,30.21 v2(115.14,30.66) 115.8,31.33 116.58,31.33 117.92,32.67 CPU1.AD1
UART_2_CRXD_DTXD_CON: length 4.7
  BOTTOM w0.089: R6803.2 172.56,8.37 v1(172.56,7.5) 172.56,7 173.59,5.97 174.09,5.97 174.41,5.65 DB1.14
UART_2_CTXD_DRXD: length 85.6
  TOP w0.089: v2(116.35,30.57) 116.93,29.99 118.74,29.99 v1(119.55,29.18) 119.73,29 126.87,21.86 127.37,21.36 127.85,21.36 129.93,19.28 129.93,15.09 130.44,14.57 134.04,14.57 134.44,14.18 134.44,12.1 135.07,11.47 136.1,10.44 136.1,9.93 136.93,9.1 v2(136.93,8.47)
  L3 w0.089: v2(136.93,8.47) 137.61,7.78 148.38,7.78 148.81,8.21 153.23,8.21 153.45,7.99 155.34,7.99 156.32,7.02 159.94,7.02 160.38,7.45 167.69,7.45 168.18,6.96 171.84,6.96 171.96,6.83 174.22,6.83 v2(174.65,6.41)
  BOTTOM w0.089: R6802.1 171.98,9.61 172.23,9.87 173.38,9.87 174.65,8.6 v2(174.65,6.41) ; CPU1.AD2 118.13,35.33 118.13,35.12 118.18,34.99 118.18,34.79 118.18,34.77 118.18,32.67 117.57,32.06 117.57,31.78 v2(116.35,30.57) R2049.2
UART_2_CTXD_DRXD_CON: length 5
  BOTTOM w0.089: DB1.13 173.41,5.76 172.89,6.29 172.31,6.29 171.32,7.28 v1(171.32,7.58) 171.32,7.89 R6802.2
USB2_ID: length 2
  TOP w0.089: R1609.1 116.61,35.89 v2(117.07,36.35) v1(117.62,36.03)
  BOTTOM w0.089: v2(117.07,36.35) 116.9,36.19 CPU1.AG3
USB2_VBUSSENSE: length 2.3
  TOP w0.089: v2(116.1,37.04) 115.96,37.04 v1(115.59,36.66) 115.84,36.41 R1610.1
  BOTTOM w0.089: CPU1.AG4 v2(116.1,37.04)
USB20_DN0_C: length 11.1
  BOTTOM w0.102: 19.55,49.24 v1(19.68,49.36) ; 19.55,49.24 19.55,49.24 19.26,49.53 18.15,49.53 17.98,49.36 17.98,47.64 17.73,47.4 17.37,47.4 17.19,47.57 17.19,48.22 17.19,48.5 16.9,48.79 16.45,48.79 ED3602.1 15.19,49.05 14.7,49.54 USB2.2 ; 19.55,49.24 19.87,48.92 20.05,48.74 EL3602.2
USB20_DN1_C: length 11.8
  BOTTOM w0.102: USB3.2 14.35,25.66 14.45,25.56 14.63,25.56 15.6,26.54 16.35,26.54 16.61,26.79 17.57,26.79 17.82,26.54 17.94,26.54 18.06,26.66 18.06,28.31 18.39,28.64 18.85,28.64 18.98,28.5 ; v1(19.1,28.61) 18.98,28.5 ; 18.98,28.5 19.17,28.31 19.17,26.49 19.35,26.31 ED3604.1 20.51,26.31 EL3603.2
USB20_DP0_C: length 11.1
  BOTTOM w0.102: 18.2,47.79 18.2,48.76 18.49,49.05 ED3602.6 18.88,49.29 19.18,49.29 19.32,49.14 19.71,48.76 19.82,48.65 19.82,48.21 19.71,48.09 19.48,48.09 19.36,47.98 EL3602.3 ; 18.2,47.79 18.2,47.54 17.83,47.17 17.27,47.17 16.96,47.48 16.96,48.31 16.96,48.41 16.8,48.57 15.68,48.57 15.42,48.82 14.96,48.82 14.8,48.98 14.45,48.98 14.35,48.88 USB2.3 ; 18.2,47.79 v1(18.36,47.79)
USB20_DP1_C: length 11.8
  BOTTOM w0.102: 18.29,27.47 18.29,26.56 18.04,26.31 ED3604.6 15.7,26.31 14.72,25.33 14.42,25.33 14.35,25.26 USB3.3 ; 18.29,27.47 18.29,28.22 18.48,28.41 18.75,28.41 18.95,28.22 18.95,25.95 19.07,25.83 20.37,25.83 EL3603.3 ; 18.29,27.47 v1(18.46,27.47)
USB30_RX_CPU_N1: length 174.8
  TOP w0.102: v1(39.77,38.9) 39.65,39.02 ; 39.65,39.02 38.88,38.25 38.62,37.98 35.87,37.98 35.46,38.39 29.09,38.39 28.96,38.52 28.96,38.52 28.96,38.52 23.79,43.69 23.79,47.62 22.18,49.24 20.77,49.24 R3609.1 ; 39.65,39.02 40.37,39.74 v2(41.68,39.74)
  L6 w0.127: v2(125.71,38.92) 126.13,39.34 127,39.34 127.5,38.83 129.3,38.83 130.34,39.87 130.34,40.62 130.8,41.08 131.75,41.08 133.12,39.71 133.12,38.06 131.07,36.02 127.26,36.02 124.57,33.33 124.57,31.3 122.35,29.07 122.35,28.23 120.99,26.87 119.6,26.87 119.38,26.87 119.38,26.87 119.27,26.87 118.09,25.7 118.09,25.02 117.2,24.13 116.55,24.13 116.55,24.13 111.05,24.13 108.25,21.33 104.55,21.33 104,21.88 101.8,21.88 99.91,19.99 96.28,19.99 95.51,19.23 90.86,19.23 88.45,16.81 85.68,16.81 82.78,13.92 81.97,13.92 79.51,11.47 73.63,11.47 72.01,9.85 59.78,9.85 59.12,10.51 47.26,10.51 42.34,15.43 42.34,34.53 43.44,35.64 43.44,39.5 43.2,39.74 v2(41.68,39.74)
  BOTTOM w0.102: CPU1.H8 v2(125.71,38.92)
USB30_RX_CPU_N2: length 131.5
  TOP w0.102: v1(40.38,20) 40.25,20.13 ; 40.25,20.13 39.8,19.67 34.6,19.67 32.07,22.2 27.35,22.2 25.22,24.33 25.22,25.23 24.67,25.78 23.45,25.78 R3612.1 ; 40.25,20.13 43.33,23.2 43.33,23.64 43.7,24.01 44.39,24.01 44.72,23.68 v2(44.72,23.66)
  L6 w0.127: v2(125.75,38.04) 125.76,38.04 126.12,37.68 126.12,37.54 123.34,34.76 123.34,32.22 121.94,30.82 120.49,30.82 116.67,27 114.9,27 114.45,26.55 110.91,26.55 107.5,23.15 105.3,23.15 104.74,23.71 101.06,23.71 99.16,21.8 95.52,21.8 94.76,21.04 90.01,21.04 88.36,19.39 84.79,19.39 78.69,13.28 71.54,13.28 70.72,12.46 66.51,12.46 66.04,12.93 59.48,12.93 59.19,12.64 54.5,12.64 53.85,13.28 48.91,13.28 45.88,16.32 45.88,20.9 44.15,22.63 44.15,23.65 44.33,23.82 44.56,23.82 v2(44.72,23.66)
  BOTTOM w0.102: CPU1.J6 v2(125.75,38.04)
USB30_RX_CPU_N3: length 108.9
  L6 w0.127: v2(125.67,40.75) 126.16,40.26 128.6,40.26 130.67,42.33 130.67,42.94 130.97,43.24 134.67,43.24 135.55,42.35 137.13,42.35 142.46,37.02 142.46,34.34 146.92,29.88 152.09,29.88 155.34,26.63 165.76,26.63 166.98,25.41 199.59,25.41 201,26.82 203.13,26.82 204.87,28.57 204.87,31.81 203.49,33.19 203.49,39.79 203.16,40.12 v2(202.08,40.12)
  BOTTOM w0.102: v2(202.08,40.12) 202.08,40.37 202.43,40.73 202.78,40.73 ED6602.2 ED6602.9 204.81,40.74 204.87,40.8 IOBD1.11 ; CPU1.J10 v2(125.67,40.75)
USB30_RX_CPU_N4: length 164.7
  TOP w0.102: 36.43,48.89 36.6,48.71 36.99,48.71 v2(37.23,48.47) ; 36.43,48.89 36.25,49.07 36.25,49.64 C3806.1 ; 36.43,48.89 v1(36.32,48.78)
  L6 w0.127: v2(37.23,48.47) 37.41,48.65 38.25,48.65 39.89,47.01 39.89,32.74 40.79,31.84 40.79,12.59 44.42,8.97 53.71,8.97 55.21,7.47 73.82,7.47 76.27,9.92 80.16,9.92 82.61,12.37 83.42,12.37 86.32,15.26 89.09,15.26 90.36,16.53 95.28,16.53 97.19,18.44 99.5,18.44 100.09,17.86 100.91,17.86 102.83,19.78 108.89,19.78 110.01,20.89 114.88,20.89 116.57,22.58 119.94,22.58 120.84,23.47 120.84,24.53 126.11,29.81 126.11,30.3 130.18,34.37 134.88,34.37 135.58,35.07 135.58,38.77 133.61,40.74 132.97,40.74 131.96,41.75 130.56,41.75 129.83,41.02 129.83,40.09 129.28,39.55 128.55,39.55 v2(128.25,39.84)
  BOTTOM w0.102: CPU1.E10 v2(128.25,39.84)
USB30_RX_CPU_N4_C: length 3.7
  TOP w0.102: C3806.2 36.18,51.05 36.18,52.19 36.52,52.54 36.52,52.87 ; v1(36.37,52.87) 36.52,52.87 ; 36.52,52.87 36.52,53.34 36.61,53.44 36.61,53.61 36.52,53.69 U3801.4
USB30_RX_CPU_P1: length 174
  TOP w0.102: R3610.1 20.8,49.47 22.27,49.47 24.02,47.71 24.02,43.78 28.17,39.64 ; v2(41.68,40.6) 41.68,40.35 41.29,39.97 40.28,39.97 39.49,39.18 38.53,38.21 35.96,38.21 35.56,38.62 29.19,38.62 28.17,39.64 ; 28.17,39.64 v1(28.29,39.76)
  L6 w0.127: v2(41.68,40.6) 41.68,40.37 42.04,40 43.31,40 43.71,39.61 43.71,35.52 42.6,34.42 42.6,15.54 47.37,10.78 59.23,10.78 59.89,10.12 71.9,10.12 73.36,11.58 73.51,11.73 79.4,11.73 81.85,14.19 82.67,14.19 85.57,17.08 88.34,17.08 90.75,19.49 95.4,19.49 96.17,20.26 99.8,20.26 101.69,22.15 104.11,22.15 104.66,21.6 108.14,21.6 110.94,24.4 116.61,24.4 117.09,24.4 117.83,25.14 117.83,25.81 119.16,27.14 119.49,27.14 120.88,27.14 122.08,28.34 122.08,29.18 124.3,31.41 124.3,33.44 127.15,36.28 130.96,36.28 132.85,38.18 132.85,39.6 131.64,40.81 130.91,40.81 130.61,40.51 130.61,39.76 129.41,38.56 127.39,38.56 126.89,39.07 126.51,39.07 v2(126.36,38.92)
  BOTTOM w0.102: CPU1.G8 126.52,39.37 126.36,39.15 v2(126.36,38.92)
USB30_RX_CPU_P2: length 132.5
  TOP w0.102: v2(44.72,24.29) 44.67,24.24 43.61,24.24 43.1,23.74 43.1,23.3 39.7,19.9 34.7,19.9 32.17,22.43 29.84,22.43 ; v1(29.84,22.59) 29.84,22.43 ; 29.84,22.43 27.44,22.43 25.45,24.42 25.45,25.33 24.77,26.01 23.45,26.01 R3613.1
  L6 w0.127: v2(44.72,24.29) 44.52,24.09 44.22,24.09 43.89,23.76 43.89,22.52 45.61,20.79 45.61,16.21 48.8,13.02 53.74,13.02 54.39,12.37 59.3,12.37 59.59,12.66 65.93,12.66 66.4,12.19 70.6,12.19 70.61,12.19 70.83,12.19 71.65,13.02 78.8,13.02 84.9,19.13 88.47,19.13 90.12,20.78 94.87,20.78 95.63,21.54 99.27,21.54 101.17,23.44 104.63,23.44 105.19,22.88 107.61,22.88 111.02,26.29 114.56,26.29 115.01,26.73 116.78,26.73 120.6,30.56 122.05,30.56 123.6,32.11 123.6,34.64 126.39,37.43 v2(126.39,38.04)
  BOTTOM w0.102: CPU1.H6 v2(126.39,38.04)
USB30_RX_CPU_P3: length 108.9
  L6 w0.127: v2(202.1,39.48) 202.4,39.19 202.55,39.19 202.66,39.31 202.66,39.66 202.85,39.85 203.05,39.85 203.22,39.68 203.22,33.08 204.6,31.7 204.6,28.68 203.02,27.09 200.89,27.09 199.48,25.68 167.09,25.68 165.87,26.9 155.45,26.9 152.2,30.15 147.04,30.15 142.73,34.45 142.73,37.13 137.24,42.62 135.66,42.62 134.78,43.51 130.86,43.51 130.4,43.05 130.4,42.44 128.49,40.52 126.37,40.52 126.3,40.59 v2(126.3,40.75)
  BOTTOM w0.102: CPU1.H10 126,40.33 126,40.51 126.08,40.58 126.08,40.6 126.23,40.75 v2(126.3,40.75) ; IOBD1.10 204.87,40.4 204.77,40.51 204.27,40.51 204.21,40.45 204.21,40.35 204.1,40.24 ED6602.10 ED6602.1 202.78,39.35 202.64,39.2 202.38,39.2 v2(202.1,39.48)
USB30_RX_CPU_P4: length 164.4
  TOP w0.102: C3805.1 36.47,49.67 36.47,49.16 36.7,48.94 36.94,48.94 v2(37.23,49.24)
  L6 w0.127: v2(37.23,49.24) 37.55,48.92 38.36,48.92 40.15,47.12 40.15,32.85 41.05,31.95 41.05,12.7 44.53,9.23 53.82,9.23 55.32,7.73 73.71,7.73 76.16,10.18 80.05,10.18 82.5,12.64 83.31,12.64 86.21,15.53 88.98,15.53 90.25,16.8 95.17,16.8 97.08,18.71 99.61,18.71 100.2,18.12 100.8,18.12 102.72,20.05 108.78,20.05 109.89,21.16 114.77,21.16 116.46,22.85 119.83,22.85 120.57,23.58 120.57,24.64 125.85,29.92 125.85,30.41 130.07,34.63 134.77,34.63 135.31,35.18 135.31,38.66 133.5,40.47 132.86,40.47 131.85,41.48 130.67,41.48 130.1,40.91 130.1,39.98 129.39,39.28 127.83,39.28 127.62,39.49 v2(127.62,39.84)
  BOTTOM w0.102: CPU1.F10 127.49,40.29 127.62,40.16 v2(127.62,39.84)
USB30_RX_CPU_P4_C: length 3.7
  TOP w0.102: C3805.2 36.41,51.15 36.41,51.62 ; 36.41,51.62 36.41,52.1 36.75,52.44 36.75,53.25 36.84,53.34 36.84,53.61 36.92,53.69 U3801.5 ; 36.41,51.62 v1(36.55,51.62)
USB30_RXDN1_C: length 9.6
  TOP w0.102: USB2.5 13.48,45.99 14.21,46.72 15.79,46.72 16.68,47.62 16.68,47.87 ; v1(16.83,47.87) 16.68,47.87 ; 16.68,47.87 16.68,49.02 16.78,49.13 ED3601.10 ED3601.1 19.51,49.13 R3609.2
USB30_RXDN2_C: length 13.2
  TOP w0.102: 20.85,26.01 19.34,26.01 19.22,25.88 ED3603.1 ED3603.10 17.4,25.88 17.27,26.01 15.85,26.01 15.49,25.65 15.49,23.87 14.72,23.1 13.76,23.1 13.15,22.49 13.15,21.9 12.85,21.6 USB3.5 ; 20.85,26.01 21.82,26.01 R3612.2 ; 20.85,26.01 v1(20.85,25.84)
USB30_RXDP1_C: length 10.2
  TOP w0.102: v1(16.91,49.49) 16.91,49.35 ; 16.91,49.35 16.69,49.35 16.45,49.12 16.45,47.71 15.69,46.95 14.12,46.95 13.3,46.13 13.24,46.05 13.1,46.03 12.95,46.13 12.85,46.23 USB2.6 ; 16.91,49.35 17.33,49.35 17.6,49.63 ED3601.9 ED3601.2 19.54,49.63 R3610.2
USB30_RXDP2_C: length 12.1
  TOP w0.102: 19.73,26.24 22.28,26.24 R3613.2 ; 19.73,26.24 v1(19.73,26.4) ; 19.73,26.24 19.34,26.24 19.2,26.38 ED3603.2 ED3603.9 17.42,26.38 17.27,26.24 15.76,26.24 15.26,25.74 15.26,23.96 14.63,23.33 13.12,23.33 USB3.6
USB30_TX_CPU_N1: length 178.8
  TOP w0.102: v2(41.68,38.01) 41.68,37.76 42.06,37.38 42.67,37.38 43.1,37.8 43.1,41.01 42.36,41.74 41.36,41.74 40.71,41.09 ; v1(40.84,40.96) 40.71,41.09 ; 40.71,41.09 38.37,38.75 36.11,38.75 35.76,39.1 30.1,39.1 24.61,44.59 24.61,50.62 24.18,51.04 23.92,51.04 23.38,50.51 C3601.1
  L6 w0.127: v2(133.62,39.66) 133.62,39.38 133.43,39.18 133.43,37.23 131.53,35.33 127.21,35.33 126.26,34.38 126.26,31.71 124.23,29.68 124.23,29.39 119.79,24.96 119.79,24.15 119.26,23.62 116.14,23.62 114.45,21.93 109.57,21.93 108.46,20.82 104.34,20.82 103.81,21.35 101.99,21.35 100.12,19.48 96.76,19.48 94.85,17.58 89.93,17.58 88.66,16.31 85.89,16.31 82.99,13.41 82.18,13.41 79.72,10.96 74.24,10.96 71.79,8.51 59.29,8.51 57.79,10.01 44.85,10.01 41.83,13.02 41.83,34.74 42.5,35.41 42.5,36.95 41.68,37.78 v2(41.68,38.01)
  BOTTOM w0.089: 131.21,41.89 131.2,41.91 131.2,41.95 130.87,42.27 130.61,42.27 130.6,42.27 130.48,42.21 130.33,42.21 130.29,42.23 130.15,42.27 129.96,42.27 129.96,42.27 CPU1.C13
  BOTTOM w0.102: v2(133.62,39.66) 134.22,39.66 134.28,39.73 134.28,40.13 133.53,40.88 132.23,40.88 131.21,41.89
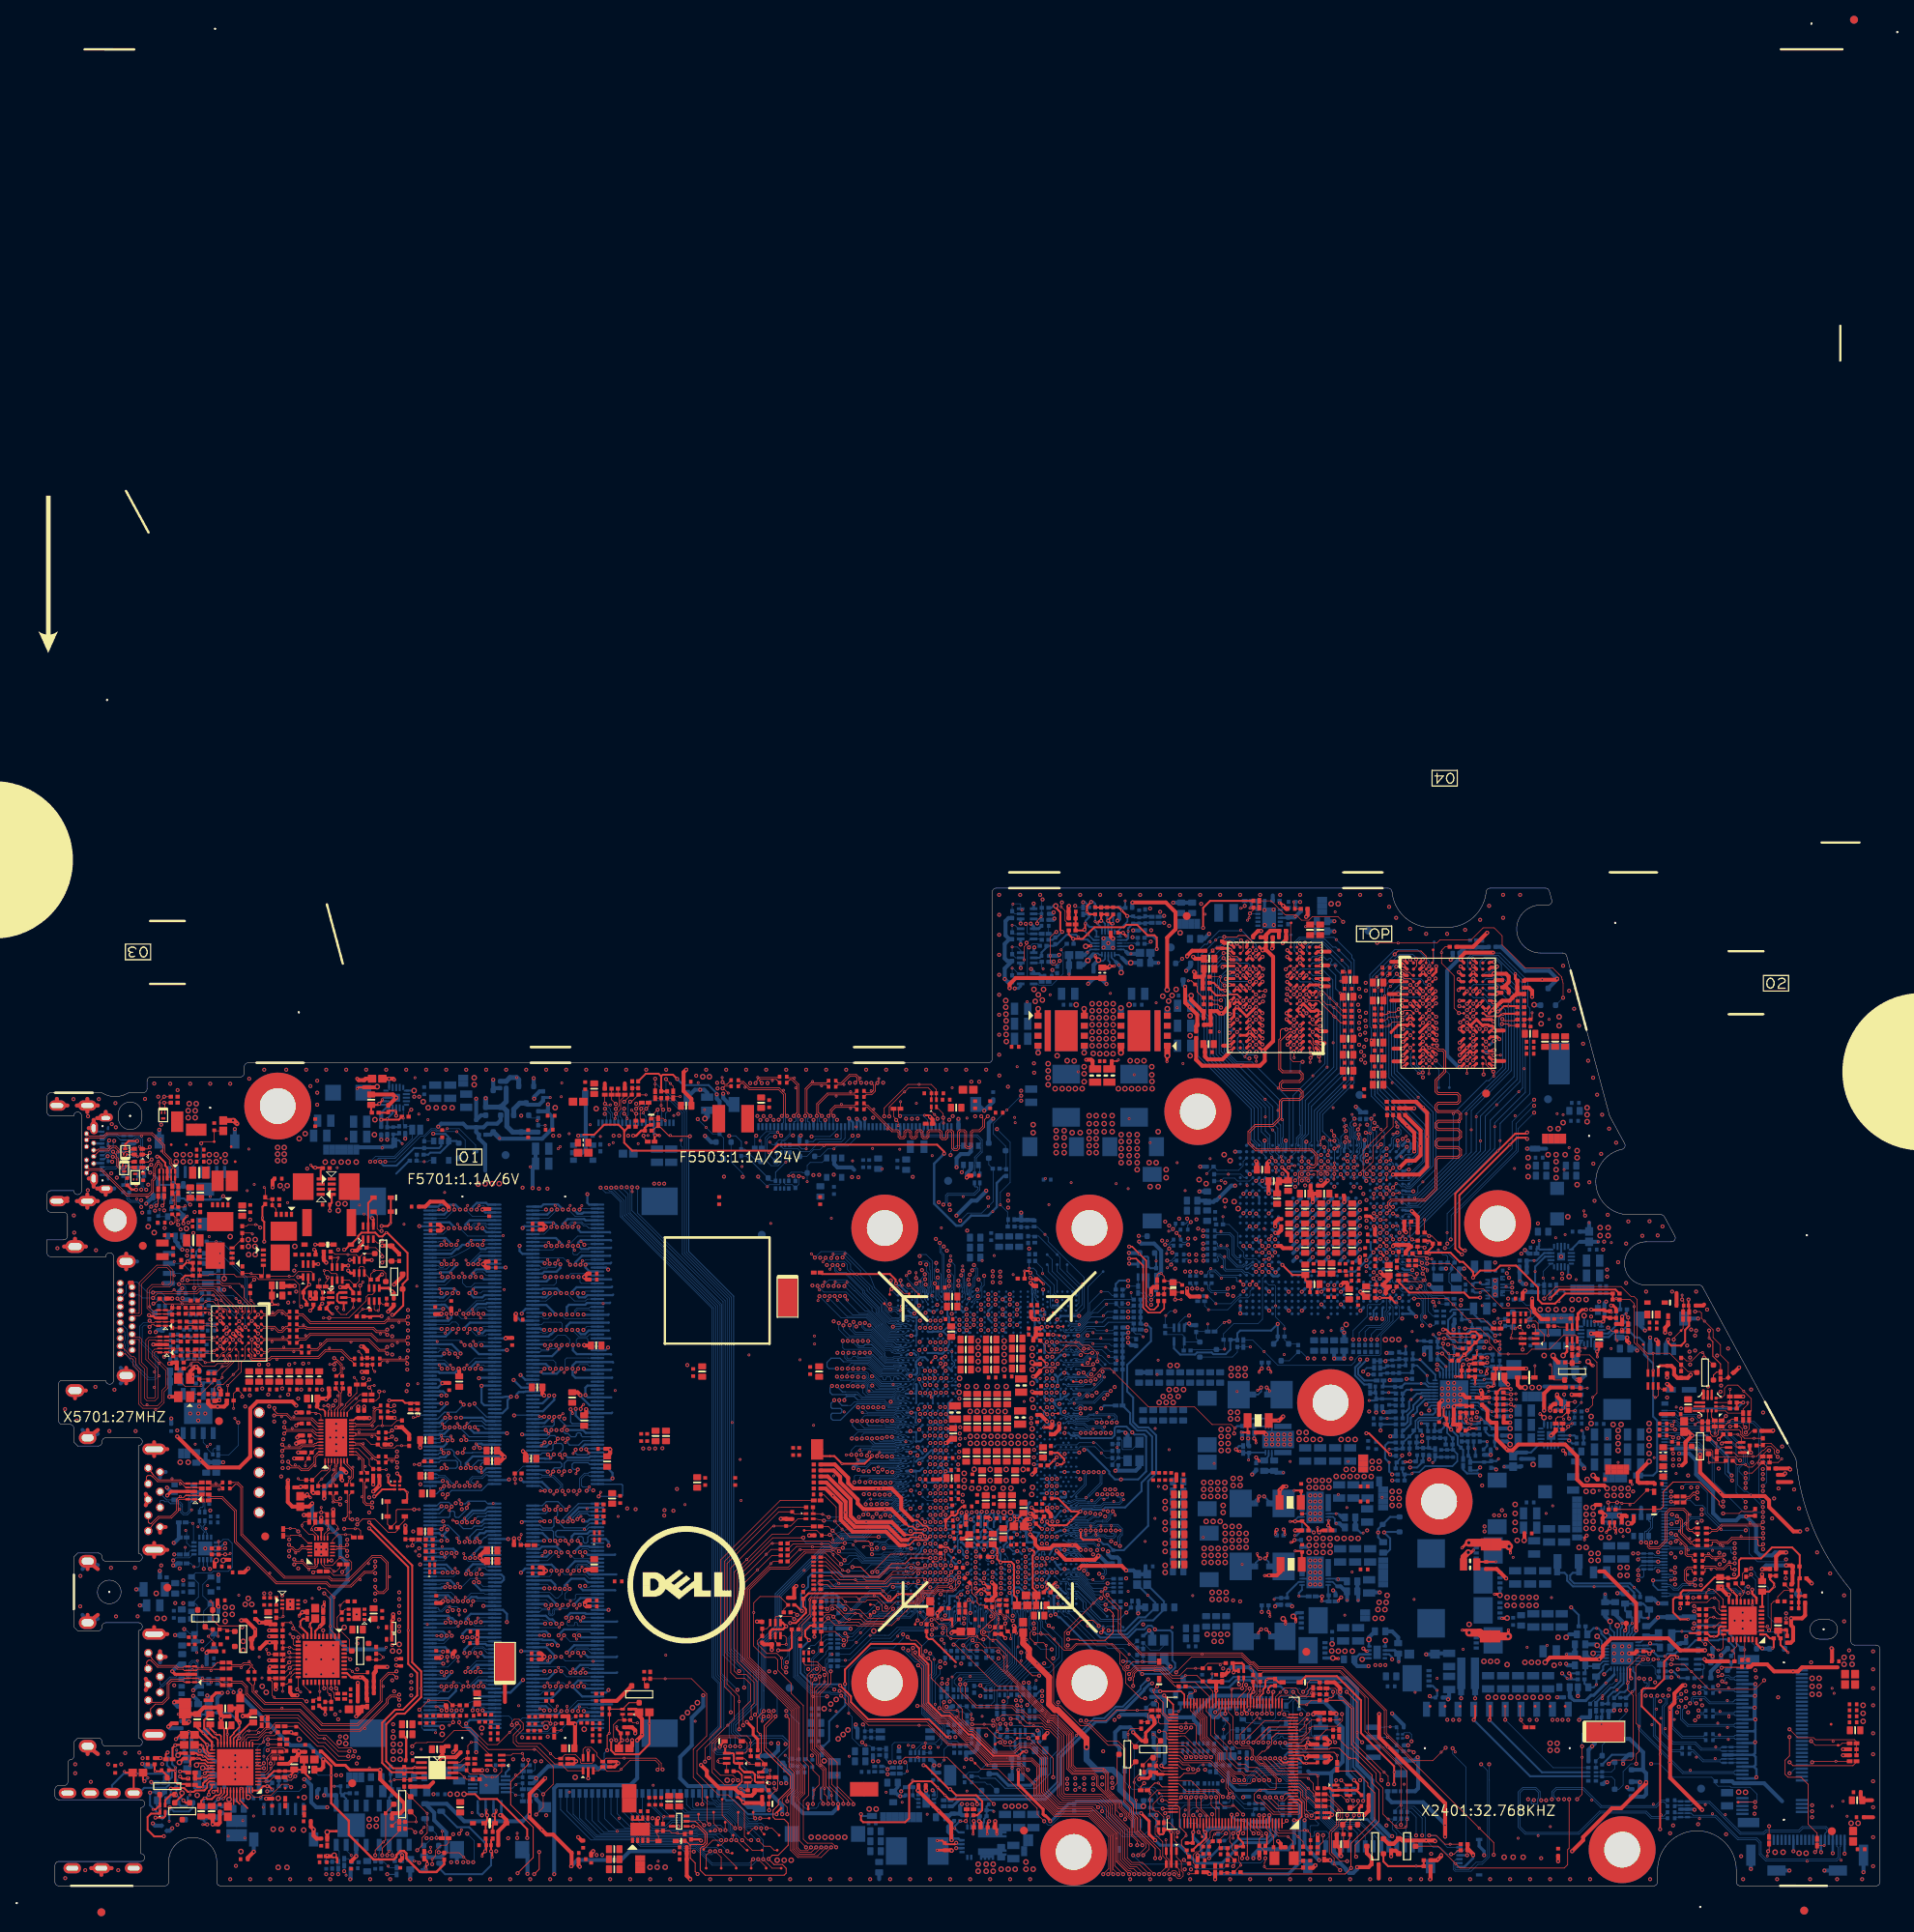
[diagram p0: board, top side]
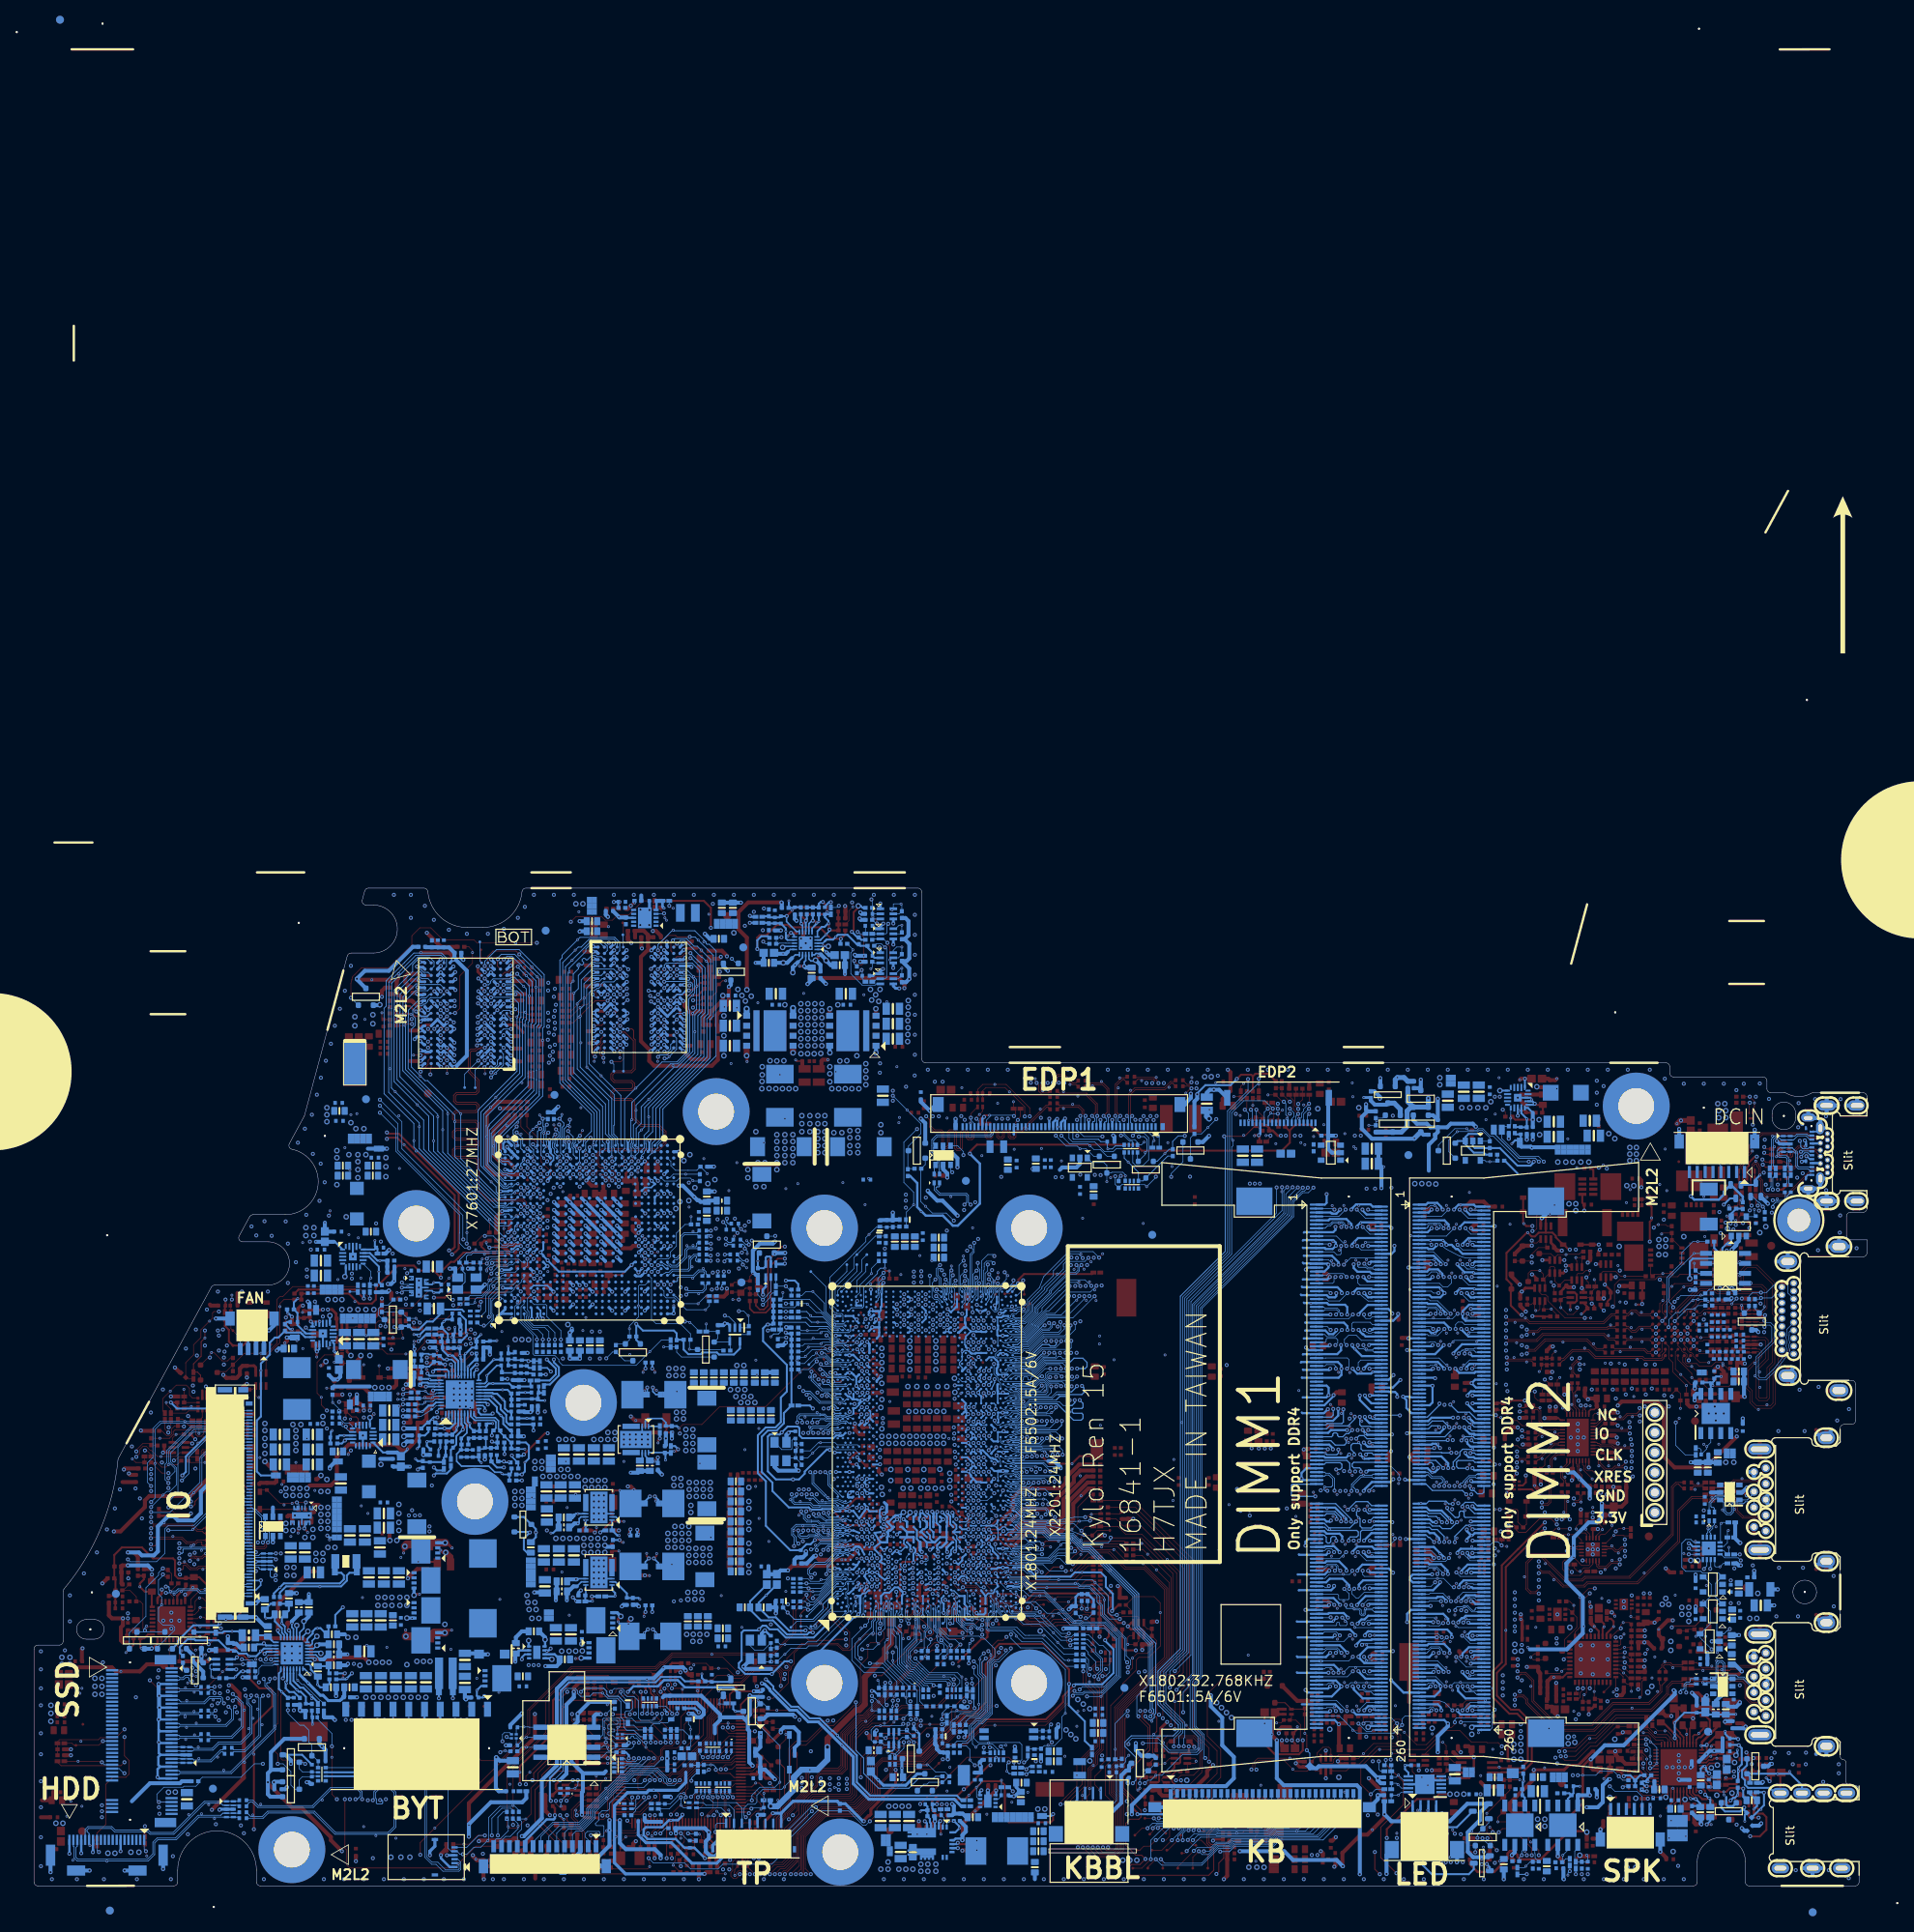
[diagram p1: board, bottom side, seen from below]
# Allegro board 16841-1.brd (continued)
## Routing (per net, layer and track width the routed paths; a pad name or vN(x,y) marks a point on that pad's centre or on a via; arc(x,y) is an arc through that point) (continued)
USB30_TX_CPU_N2: length 147.1
  TOP w0.102: 42.54,25.36 42.54,26.03 43.42,26.91 43.95,26.91 v2(44.38,26.48) ; 42.54,25.36 42.54,23.43 39.49,20.38 34.9,20.38 34.81,20.47 32.19,23.09 27.62,23.09 26.06,24.66 26.06,25.49 25.55,26 C3603.1 ; 42.54,25.36 v1(42.69,25.36)
  L6 w0.127: v2(44.38,26.48) 43.99,26.87 43.69,26.87 43.38,26.56 43.38,15.91 43.42,15.87 43.42,15.86 43.74,15.54 43.74,15.54 46.78,12.51 53.53,12.51 54.38,11.66 61.09,11.66 61.74,11.01 71.52,11.01 73.02,12.51 79.08,12.51 85.19,18.62 88.78,18.62 90.43,20.27 95.08,20.27 95.85,21.03 99.48,21.03 101.38,22.94 104.41,22.94 104.98,22.37 107.82,22.37 110.62,25.17 116.76,25.17 117.05,25.46 117.05,26.28 118.92,28.15 120.8,28.15 121.31,28.66 121.31,29.5 123.82,32.02 123.82,34.23 127.02,37.43 129.94,37.43 131.59,39.08 131.59,39.94 v2(131.7,40.05)
  BOTTOM w0.089: v2(131.7,40.05) 131.91,40.26 131.91,40.59 131.85,40.65 130.88,41.62 130.8,41.66 CPU1.B13
USB30_TX_CPU_N3: length 107.8
  L6 w0.127: v2(134.11,42.76) 134.11,42.48 135.06,41.53 136.62,41.53 141.96,36.2 141.96,34.13 146.71,29.37 151.88,29.37 155.24,26.01 165.67,26.01 166.77,24.9 204.54,24.9 205.38,25.74 205.38,32.02 205.09,32.31 205.09,41.5 204.92,41.67 204.19,41.67 203.87,41.99 202.57,41.99 v2(202.08,41.49)
  BOTTOM w0.089: CPU1.B15 130.58,43.64 130.72,43.64 133,43.64 133.43,43.2 ; 133.43,43.2 133.88,42.76 v2(134.11,42.76) ; 133.43,43.2 v1(133.55,43.32)
  BOTTOM w0.102: IOBD1.13 204.88,41.6 204.74,41.74 204.14,41.74 204.13,41.74 ED6602.7 ED6602.4 202.32,41.74 v2(202.08,41.49)
USB30_TX_CPU_N4: length 165.6
  TOP w0.102: 38.13,48.86 38.13,49.91 C3804.1 ; 38.13,48.86 v1(37.99,48.86) ; 38.13,48.86 38.13,46.96 v2(37.74,46.57)
  L6 w0.127: v2(132.56,42.69) 132.43,42.56 132.43,41.96 132.88,41.52 133.98,41.52 136.35,39.14 136.35,34.75 135.2,33.59 130.42,33.59 127.02,30.19 127.02,29.48 124.67,27.13 122.21,24.66 122.21,22.96 121.01,21.77 117.07,21.77 115.42,20.12 110.33,20.12 109.83,19.62 109.2,18.99 103.13,18.99 101.23,17.08 99.77,17.08 99.18,17.66 97.51,17.66 95.6,15.76 90.68,15.76 89.41,14.49 89.19,14.49 86.64,14.49 83.75,11.59 82.93,11.59 80.48,9.14 76.76,9.14 74.31,6.69 54.88,6.69 53.39,8.19 44.09,8.19 40.01,12.27 40.01,31.49 38.23,33.27 38.23,35.64 38.39,35.8 38.87,36.28 38.87,45.01 37.98,45.9 37.98,46.33 v2(37.74,46.57)
  BOTTOM w0.089: CPU1.C15 129.68,43.2 129.96,43.1 130.16,43.1 130.26,43.14 130.48,43.14 130.6,43.1 130.87,43.1 131.03,43.27 131.98,43.27 v2(132.56,42.69)
USB30_TX_CPU_N4_C: length 4
  TOP w0.102: U3801.7 37.72,53.72 38.54,52.91 38.68,52.77 38.68,51.99 38.5,51.8 ; v1(38.35,51.95) 38.5,51.8 ; 38.5,51.8 38.26,51.57 38.26,51.23 C3804.2
USB30_TX_CPU_P1: length 179.6
  TOP w0.102: C3602.1 24.28,51.27 24.84,50.71 24.84,44.69 30.19,39.33 35.85,39.33 36.21,38.98 38.27,38.98 41.27,41.97 42.46,41.97 43.33,41.1 43.33,39.28 ; v2(41.68,37.15) 42.77,37.15 43.33,37.71 43.33,39.28 ; 43.33,39.28 v1(43.5,39.28)
  L6 w0.127: v2(134.06,39.18) 133.7,38.82 133.7,37.12 131.64,35.06 127.32,35.06 126.52,34.27 126.52,31.6 124.49,29.57 124.49,29.28 120.06,24.85 120.06,24.04 119.37,23.35 116.25,23.35 114.56,21.67 109.68,21.67 108.57,20.55 104.23,20.55 103.7,21.08 102.1,21.08 100.23,19.21 96.87,19.21 94.96,17.31 90.04,17.31 88.77,16.04 86,16.04 83.1,13.14 82.29,13.14 79.83,10.69 74.35,10.69 71.9,8.24 59.18,8.24 57.68,9.74 44.74,9.74 41.56,12.91 41.56,34.85 42.23,35.52 42.23,36.84 41.93,37.15 v2(41.68,37.15)
  BOTTOM w0.089: 131.38,42.06 131.36,42.07 131.32,42.07 130.94,42.45 130.57,42.45 130.52,42.43 130.47,42.4 130.37,42.4 130.32,42.4 130.19,42.46 129.94,42.46 129.82,42.4 129.63,42.31 129.43,42.31 129.28,42.28 CPU1.D13
  BOTTOM w0.102: 131.38,42.06 132.32,41.11 133.62,41.11 134.51,40.22 134.51,39.64 v2(134.06,39.18)
USB30_TX_CPU_P2: length 147.3
  TOP w0.102: v2(44.38,27.27) 44.34,27.27 44.22,27.14 43.33,27.14 42.31,26.12 42.31,23.53 39.4,20.61 34.99,20.61 34.97,20.64 32.29,23.32 27.72,23.32 26.46,24.57 ; 26.46,24.57 26.28,24.75 26.28,25.56 26.36,25.64 C3604.1 ; 26.46,24.57 v1(26.59,24.7)
  L6 w0.127: v2(132.17,39.62) 131.86,39.31 131.86,38.97 130.05,37.16 127.13,37.16 124.09,34.11 124.09,31.91 121.57,29.39 121.57,28.55 120.91,27.89 119.03,27.89 117.32,26.17 117.32,25.35 116.88,24.9 110.73,24.9 107.93,22.1 104.87,22.1 104.3,22.67 101.49,22.67 99.59,20.76 95.96,20.76 95.19,20 90.54,20 88.89,18.35 85.3,18.35 79.19,12.24 73.13,12.24 71.63,10.74 61.63,10.74 60.98,11.39 54.27,11.39 53.42,12.24 46.67,12.24 43.63,15.28 43.63,15.28 43.11,15.79 43.11,26.67 43.58,27.14 44.11,27.14 v2(44.38,27.27)
  BOTTOM w0.089: v2(132.17,39.62) 132.1,39.69 132.1,40.67 131.98,40.79 130.99,41.78 130.91,41.82 CPU1.A13
USB30_TX_CPU_P3: length 107.7
  L6 w0.127: v2(133.38,42.66) 133.55,42.66 134.95,41.26 136.51,41.26 141.69,36.09 141.69,34.02 146.6,29.11 151.77,29.11 155.13,25.74 165.55,25.74 166.66,24.64 204.65,24.64 205.65,25.63 205.65,32.13 205.35,32.42 205.35,41.62 205.03,41.94 204.3,41.94 203.98,42.25 v2(202.08,42.25)
  BOTTOM w0.089: v2(133.38,42.66) 133.43,42.71 133.43,42.94 132.92,43.45 130.8,43.45 CPU1.A15
  BOTTOM w0.102: IOBD1.14 204.83,42 204.8,41.97 204.27,41.97 204,42.24 ED6602.6 ED6602.5 202.09,42.24 v2(202.08,42.25)
USB30_TX_CPU_P4: length 165.6
  TOP w0.102: v2(38.76,46.57) 38.42,46.57 38.36,46.63 38.36,47.48 ; 38.36,47.48 v1(38.5,47.48) ; 38.36,47.48 38.36,49.66 C3803.1
  L6 w0.127: v2(131.92,42.69) 132.16,42.45 132.16,41.85 132.77,41.25 133.87,41.25 136.09,39.03 136.09,34.86 135.09,33.86 130.31,33.86 126.75,30.3 126.75,29.59 124.4,27.24 124.4,27.24 121.94,24.77 121.94,23.07 120.9,22.03 116.96,22.03 115.31,20.38 110.22,20.38 109.09,19.25 103.02,19.25 101.12,17.35 99.88,17.35 99.29,17.93 97.4,17.93 95.49,16.03 90.57,16.03 89.3,14.76 86.53,14.76 83.63,11.86 82.82,11.86 80.37,9.41 76.65,9.41 74.2,6.96 54.99,6.96 53.5,8.46 44.2,8.46 40.28,12.38 40.28,31.6 38.5,33.38 38.5,35.53 39.14,36.17 39.14,45.12 38.25,46.01 38.25,46.49 38.37,46.62 38.7,46.62 v2(38.76,46.57)
  BOTTOM w0.089: v2(131.92,42.69) 131.92,43.01 131.85,43.09 131.1,43.09 130.94,42.93 130.58,42.93 130.45,42.96 130.29,42.96 130.2,42.93 129.93,42.93 129.6,43.04 129.33,43.08 CPU1.D15
USB30_TX_CPU_P4_C: length 3.9
  TOP w0.102: 38.7,53.07 v1(38.83,53.2) ; 38.7,53.07 38.91,52.86 38.91,51.89 38.49,51.47 38.49,51.23 C3803.2 ; 38.7,53.07 38.12,53.65 U3801.8
USB30_TXDN1_C: length 8.9
  TOP w0.102: 17.03,51.21 16.86,51.37 14.03,51.37 13.42,51.99 13.34,52.06 13.15,52.15 12.8,52.15 12.62,51.98 12.6,51.72 USB2.8 ; 17.03,51.21 17.6,50.63 ED3601.7 ED3601.4 19.54,50.63 R3605.2 ; 17.03,51.21 v1(16.91,51.09)
USB30_TXDN1_R: length 2
  TOP w0.102: C3601.2 22.03,50.77 20.78,50.77 R3605.1
USB30_TXDN2_C: length 11.4
  TOP w0.102: USB3.8 12.64,28.33 12.69,28.51 12.82,28.64 12.97,28.69 13.19,28.66 13.25,28.57 13.34,28.49 14.04,27.78 16.31,27.78 16.56,27.53 17.27,27.53 17.42,27.39 ED3603.7 ED3603.4 18.98,27.39 19.12,27.53 20.82,27.53 ; R3611.2 22.21,27.53 20.82,27.53 ; 20.82,27.53 v1(20.82,27.37)
USB30_TXDN2_R: length 4
  TOP w0.102: R3611.1 23.43,27.89 24.66,27.89 ; 24.66,27.89 v1(24.66,27.72) ; 24.66,27.89 24.79,27.89 25.01,28.1 25.71,28.1 25.84,27.97 25.84,27.78 25.55,27.49 C3603.2
USB30_TXDP1_C: length 7.9
  TOP w0.102: USB2.9 13.26,52.55 13.29,52.51 13.29,52.51 13.38,52.4 13.41,52.35 13.51,52.21 14.13,51.6 15.87,51.6 ; R3606.2 19.51,51.13 ED3601.5 ED3601.6 17.43,51.13 16.96,51.6 15.87,51.6 ; 15.87,51.6 v1(15.87,51.75)
USB30_TXDP1_R: length 2.1
  TOP w0.102: R3606.1 20.78,51 21.43,51 ; C3602.2 22.03,51 21.43,51 ; 21.43,51 v1(21.43,51.14)
USB30_TXDP2_C: length 10.8
  TOP w0.102: 19.71,27.76 21,27.76 21.63,28.38 R3614.2 ; 19.71,27.76 19.07,27.76 18.94,27.88 ED3603.5 ED3603.6 17.4,27.88 17.27,27.76 16.66,27.76 16.4,28.01 14.13,28.01 13.43,28.71 USB3.9 ; 19.71,27.76 v1(19.71,27.93)
USB30_TXDP2_R: length 4.4
  TOP w0.102: R3614.1 23.43,28.12 24.7,28.12 24.91,28.33 25.67,28.33 ; 25.67,28.33 25.8,28.33 26.07,28.07 26.07,27.78 26.36,27.49 C3604.2 ; 25.67,28.33 v1(25.67,28.51)
USB30_VCCA: length 2.6
  BOTTOM w0.508: ED3602.5 19.83,50 ; 15.06,52.6 USB2.1 14.35,51.89
  vias: v1(21.84,50.38)
USB30_VCCB:
  vias: v1(39.68,86.52) v3(13.86,37.17) v3(13.99,34) v3(14.88,34) v3(25.17,35.77) v3(25.55,36.54) v3(26,35.77) v3(36.98,86.68) v3(36.98,85.81) v3(37.84,86.68)
USB30_VCCC: length 7.9
  TOP w0.508: 14.35,29.81 USB3.1 15.06,29.1
  L3 w0.508: USB3.1 14.35,28.05 15.26,27.13 15.26,26.37 v2(16.15,25.49)
  BOTTOM w0.508: USB3.1 14.35,29.81 ; USB3.1 14.35,28.39 ; USB3.1 15.06,29.1
  vias: v1(19.02,29.65)
USB_ADT: length 279.8
  TOP w0.254: v2(211.54,29.17) 211.33,29.37 v1(211,29.37)
  L3 w0.508: v2(211.54,29.17) 211.54,30.88 212.86,32.19 212.86,33.12 215.09,35.36 215.16,35.36 217.2,37.39 217.2,37.92 217.19,37.93 217.19,40.48 215.03,42.64 215.03,43.75 213.51,45.27 213.51,49.12 211.76,50.86 211.76,51.68 211.67,51.77 211.67,54.25 210.41,55.51 210.41,58.33 211.35,59.27 211.35,60.92 209.38,62.89 208.87,62.89 207.92,63.84 207.92,68.29 v2(208.3,68.67)
  L4 w0.254: v3(31.47,81.27) 32.91,82.71 32.91,90 33.55,90.64 33.55,91.48 35.09,93.03 45.45,93.03 46.03,92.44 50.65,92.44 59.11,100.9 63.87,100.9 64.66,101.69 76.15,101.69 76.74,101.1 80.65,101.1 82.61,99.14 88.22,99.14 89.55,100.46 119.84,100.46 120.32,99.98 122.83,97.47 122.83,94.72 127.29,90.26 134.87,90.26 137.01,88.12 141.42,88.12 142.92,89.62 142.92,90.79 145.92,93.79 151.18,93.79 152.29,92.67 152.29,92.17 152.96,91.5 154.02,90.44 154.7,90.44 157.5,87.64 160.75,87.64 161.44,86.96 161.44,79.21 161.95,78.7 165.89,78.7 167.9,76.69 169.71,76.69 174.9,81.88 174.9,83.02 178.96,87.08 185.35,87.08 187.09,85.34 187.09,82.63 190.38,79.34 197.12,79.34 v2(198.14,78.32)
  L6 w0.508: v2(208.3,68.67) 207.54,69.43 207.54,69.81 204.49,72.86 204.24,72.86 203.47,73.62 200.93,73.62 197.95,76.61 197.8,76.61 197.31,77.09 197.31,77.77 197.86,78.32 v2(198.14,78.32)
  BOTTOM w0.508: PD4408.2 211.54,28.58 v2(211.54,29.17) PD4401.2
USB_ADT_R1:
  vias: v1(31.62,78.83)
USB_ADT_SW: length 4.1
  TOP w0.089: PR4320.2 25.88,77.86 v1(25.93,77.81) 26,77.74 26.97,77.74 PR4321.1 27.47,77.73 PU4304.4
USB_ADT_SW_R: length 6.5
  TOP w0.089: PR4321.2 v1(30.75,77.48) 31.31,77.48 31.9,78.07 33.55,78.07 33.82,77.8 PQ4308.3
USB_CAMERA_N: length 13.7
  BOTTOM w0.102: LCD1.43 111.35,95.89 111.21,95.75 111.21,95.59 111.37,95.44 118.16,95.44 118.77,94.83 118.77,93.24 118.03,92.51 118.03,91.87 ED5501.1 118.47,91.44 EL5501.2
USB_CAMERA_P: length 13.7
  BOTTOM w0.102: EL5501.3 117.8,90.48 117.8,92.6 118.54,93.34 118.54,93.8 118.29,94.05 ED5501.6 118.54,94.31 118.54,94.73 118.06,95.21 111.27,95.21 110.99,95.5 110.99,95.75 110.85,95.89 LCD1.42
USB_CPU_PN0: length 141.4
  L4 w0.14: v2(44.72,33.85) 44.24,33.85 44.17,33.77 44.17,33.39 44.03,33.25 42.3,33.25 39.52,36.03 38.25,36.03 35.4,38.88 20.51,38.88 20.17,39.21 20.17,39.75 20.29,39.86 20.59,39.86 20.7,39.97 v2(20.7,40.27)
  L6 w0.089: v2(119.02,39.1) 119.12,39.1 119.38,38.84 119.38,36.21 119.71,35.88 119.71,35.82 119.79,35.75
  L6 w0.127: 119.79,35.75 120.03,35.51 120.42,35.12 120.42,31.89 116.3,27.77 114.57,27.77 114.13,27.33 110.01,27.33 108.53,28.82 104.39,28.82 102.03,26.45 100.45,26.45 99.1,25.11 98.96,25.11 97.18,23.33 90.14,23.33 87.34,20.53 84.84,20.53 78.36,14.06 71.22,14.06 70.39,13.23 66.83,13.23 65.65,14.41 59.87,14.41 58.87,13.41 55.24,13.41 54.82,13.41 54.17,14.06 50.23,14.06 47.24,17.05 47.24,20.69 45.63,22.3 45.63,32.46 45.22,32.87 45.22,33.68 45.05,33.85 v2(44.72,33.85)
  BOTTOM w0.102: CPU1.AB9 119.48,39.57 v2(119.02,39.1) ; U3401.2 20.34,40.66 20.7,40.3 v2(20.7,40.27)
USB_CPU_PN1: length 124.8
  L4 w0.14: v2(23.69,24.6) 23.31,24.22 23.31,24.09 23.47,23.93 29.45,23.93 31.52,26 37.74,26 38.63,25.11 41.68,25.11 42.18,25.61 45.96,25.61 v2(46.25,25.9)
  L6 w0.127: v2(117.94,37.8) 117.94,36.85 118.38,36.4 118.38,33.1 116.86,31.58 116.86,30.44 115.7,29.29 113.04,29.29 112.23,28.48 111.64,28.48 110.97,29.15 109.34,29.15 108.87,29.62 103.24,29.62 102.13,28.51 101.41,28.51 98.83,25.93 98.25,25.93 96.43,24.1 89.81,24.1 87.12,21.41 84.62,21.41 78.73,15.52 75.9,15.52 75.21,14.83 70.98,14.83 70.62,15.19 58.71,15.19 57.71,14.18 55.14,14.18 54.57,14.75 54.49,14.83 50.55,14.83 48.01,17.37 48.01,23.68 46.69,25 46.69,25.45 v2(46.25,25.9)
  BOTTOM w0.102: EL3603.1 22.39,26.34 22.45,26.28 22.45,25.99 22.55,25.88 22.94,25.88 23.23,25.6 23.23,25.05 23.32,24.95 23.64,24.95 23.69,24.9 v2(23.69,24.6) ; CPU1.AD6 v2(117.94,37.8)
USB_CPU_PN2: length 174.5
  TOP w0.102: 216.28,45.96 217.65,45.96 v2(217.93,46.24) ; 216.28,45.96 v1(216.28,46.14) ; 216.28,45.96 212.68,45.96 212.02,45.3 211.42,45.3 211.25,45.48 EL6601.2
  L4 w0.14: v2(217.93,46.24) 217.96,46.24 217.96,46.23 218.75,45.44 220.17,44.02 220.17,34.97 220.42,34.72 220.42,32.29 221.83,30.89 221.83,24.28 219.6,22.06 219.6,17.27 215.21,12.88 214.1,12.88 211.94,10.72 205.38,10.72 203.8,9.14 196.03,9.14 193.2,6.31 187.17,6.31 185.27,8.2 164.88,8.2 164.4,8.68 164.4,9.12 163.25,10.27 157.99,10.27 157.46,9.74 144.46,9.74 143.4,9.74 138.48,14.66 138.48,15.71 135.97,18.23 129.92,18.23 129.47,17.78 124.11,17.78 123.06,16.72 119.03,16.72 116.47,19.29 116.47,23.95 114.79,25.63 114.79,28.81 114.38,29.22 114.38,31.49 v2(113.74,32.14)
  BOTTOM w0.089: 115.63,34.19 115.62,34.21 115.62,34.4 115.71,34.49 115.71,35.02 115.67,35.12 115.67,35.32 115.71,35.39 115.71,35.67 115.67,35.77 115.67,36.03 CPU1.AH3
  BOTTOM w0.102: 115.63,34.19 115.63,33.88 115.63,33.6 114.33,32.3 113.89,32.3 v2(113.74,32.14)
USB_CPU_PN2_C: length 18.7
  TOP w0.102: 208.48,47.18 v1(208.66,47.18) ; 208.48,47.18 208.48,45.45 208.57,45.36 208.63,45.3 208.96,45.3 209.14,45.48 EL6601.1 ; 208.48,47.18 208.48,47.41 207.92,47.97 206.07,47.97 205.51,47.4 205.51,43.9 204.66,43.06 203.61,43.06 203.49,43.18 203.49,43.41 v2(203.73,43.65)
  BOTTOM w0.102: v2(203.73,43.65) 203.41,43.97 ED6601.1 203.41,45.01 203.89,45.49 203.89,46.77 204.78,47.66 205,47.66 205.06,47.6 IOBD1.28
USB_CPU_PN3: length 125.8
  TOP w0.102: 33.27,40.37 33.05,40.37 32.44,40.98 31.52,40.98 v2(31.39,40.85) ; 33.27,40.37 v1(33.27,40.19) ; 33.27,40.37 34.08,40.37 34.31,40.6 34.31,40.85 34.42,40.96 U3802.2
  L4 w0.14: v2(31.39,40.85) 31.58,41.05 32.12,41.05 32.81,40.35 34.69,40.35 38.38,36.66 40.03,36.66 41.13,35.57 44.71,35.57 v2(44.72,35.57)
  L6 w0.089: v2(117.94,39.79) 117.71,40.03 117.57,40.03 117.5,39.95 117.5,37.68 117.62,37.55 117.62,36.66 117.75,36.54 117.75,35.95 117.51,35.72 117.51,35.66 117.5,35.65
  L6 w0.127: 117.5,35.65 115.86,34.01 115.86,31.98 114.41,30.53 112.69,30.53 112.41,30.81 108.31,30.81 107.62,30.13 103.01,30.13 101.9,29.02 99.89,29.02 98.9,28.03 96.23,28.03 95.94,27.74 95.94,27 93.91,24.97 89.96,24.97 87.55,22.55 85.05,22.55 78.52,16.03 72.35,16.03 72.02,15.7 67.97,15.7 67.39,16.28 61.55,16.28 61.26,16.57 57.65,16.57 57.16,16.08 50.96,16.08 48.52,18.52 48.52,26.14 46.6,28.05 46.6,34.76 45.46,35.9 45.05,35.9 v2(44.72,35.57)
  BOTTOM w0.102: CPU1.AD9 v2(117.94,39.79)
USB_CPU_PN4: length 219.4
  L6 w0.127: v2(114.63,86.57) 114.36,86.84 114.36,87.22 112.21,89.37 109.62,89.37 109.04,89.95 103.72,89.95 102.52,88.75 80.58,88.75 79.2,90.12 53.23,90.12 49.3,86.19 49.3,19 50.75,17.55 55.46,17.55 55.65,17.36 61.66,17.36 61.97,17.06 67.71,17.06 68.29,16.48 71.71,16.48 72.03,16.8 78.2,16.8 87.14,25.74 93.59,25.74 95.17,27.32 95.17,28.18 95.79,28.8 98.58,28.8 99.57,29.79 101.58,29.79 102.69,30.9 106.91,30.9 108.59,32.58 112.38,32.58 v2(112.42,32.54)
  BOTTOM w0.102: 116.35,87.77 117.8,87.77 118.47,88.44 EL5501.1 ; 116.35,87.77 114.45,87.77 114.35,87.67 114.35,86.86 v2(114.63,86.57) ; 116.35,87.77 v1(116.35,87.59) ; CPU1.AJ1 115.26,34.89 115.18,34.81 115.18,33.75 114.61,33.18 113.62,33.18 113.02,32.57 112.45,32.57 v2(112.42,32.54)
USB_CPU_PN5: length 171.6
  TOP w0.102: v2(217.95,43.42) 217.95,43.34 217.83,43.22 217.44,43.22 217.32,43.34 217.32,43.93 217.19,44.06 214.04,44.06 213.49,43.51 212.52,43.51 ; 212.52,43.51 v1(212.52,43.34) ; 212.52,43.51 212.18,43.51 211.98,43.71 211.53,43.71 211.48,43.67 211.48,43.35 211.39,43.26 EL6603.3
  L4 w0.14: v2(116.91,37.32) 116.43,37.32 116.38,37.38 116.38,37.56 116.25,37.69 115.61,37.69 115.09,37.17 115.09,32.96 115.92,32.14 115.92,29.65 118.04,27.53 118.04,22.7 118.77,21.98 118.77,19.01 119.97,17.8 122.59,17.8 125.32,20.53 128.4,20.53 129.65,19.28 136.4,19.28 139.54,16.15 139.54,15.13 143.87,10.79 157,10.79 157.53,11.33 163.98,11.33 165.06,10.25 167.53,10.25 168.42,9.36 185.61,9.36 187.5,7.47 192.87,7.47 195.6,10.2 203.36,10.2 204.94,11.77 211.33,11.77 213.69,14.13 214.98,14.13 218.55,17.7 218.55,24.18 219.37,25 219.37,34.28 219.11,34.53 219.11,43.58 218.78,43.91 218.52,43.91 218.43,43.83 218.43,43.47 218.38,43.42 v2(217.95,43.42)
  BOTTOM w0.102: CPU1.AF6 117.21,37.61 v2(116.91,37.32)
USB_CPU_PN5_C: length 6.9
  TOP w0.102: v1(207.33,45.1) 207.49,45.1 ; 207.49,45.1 207.49,46.38 207.39,46.49 207.29,46.49 v2(207,46.2) ; 207.49,45.1 207.49,44.74 208.13,44.1 208.53,43.7 208.74,43.48 208.95,43.48 209.18,43.26 EL6603.4
  BOTTOM w0.102: IOBD1.25 206,46.4 206.08,46.49 206.72,46.49 v2(207,46.2)
USB_CPU_PN7: length 169.6
  TOP w0.102: R6606.2 208.38,49.26 208.65,49.26 209.06,49.67 209.34,49.67 209.61,49.4 v2(209.61,49.22)
  L4 w0.14: v2(209.61,49.22) 209.95,48.88 210.18,48.88 210.31,49.01 210.31,49.59 210.46,49.75 210.89,49.75 211.49,49.15 211.49,47.37 212.01,46.85 212.01,45.39 212.86,44.54 214.91,44.54 218.28,41.17 218.28,33.05 218,32.77 218,32.77 217.13,31.9 217.13,31.68 217.13,29.49 218.57,28.04 218.57,25.73 217.42,24.57 217.42,17.69 214.96,15.23 213.61,15.23 210.97,12.58 204.64,12.58 203.04,10.98 195.27,10.98 192.6,8.32 187.76,8.32 185.94,10.15 169.04,10.15 167.07,12.11 143.82,12.11 140.32,15.61 140.32,16.47 136.73,20.07 129.98,20.07 128.62,21.42 124.73,21.42 122.92,19.61 120.07,19.61 119.65,20.03 119.65,27.19 117.12,29.73 117.12,30.91 116.71,31.31 116.71,32.2 115.7,33.21 115.7,33.61 115.83,33.73 116.09,33.73 v2(116.45,33.36)
  BOTTOM w0.102: CPU1.AH1 115.97,35.17 115.97,33.31 116.04,33.24 116.33,33.24 v2(116.45,33.36)
USB_CPU_PN7_C: length 1.6
  TOP w0.102: R6606.1 206.37,48.73 v2(206.27,48.83)
  BOTTOM w0.102: v2(206.27,48.83) 206.24,48.8 IOBD1.31
USB_CPU_PP0: length 141.4
  L4 w0.14: v2(44.72,32.98) 42.19,32.98 41.81,33.36 39.41,35.76 38.14,35.76 35.29,38.61 20.4,38.61 19.91,39.1 v2(19.91,40.3)
  L6 w0.089: v2(119.02,39.76) 119.17,39.76 119.57,39.36 119.57,36.29 119.85,36.01 119.9,36.01
  L6 w0.127: v2(44.72,32.98) 45.36,32.35 45.36,22.19 46.97,20.58 46.97,16.94 50.12,13.79 54.06,13.79 54.71,13.14 55.35,13.14 58.98,13.14 59.13,13.3 59.98,14.15 65.54,14.15 66.72,12.97 70.5,12.97 71.33,13.79 78.47,13.79 84.95,20.27 87.45,20.27 90.25,23.06 97.29,23.06 99.07,24.84 99.21,24.84 100.56,26.19 102.14,26.19 104.5,28.55 108.42,28.55 109.9,27.06 114.24,27.06 114.68,27.51 116.41,27.51 120.68,31.78 120.68,35.23 120.22,35.7 119.9,36.01
  BOTTOM w0.102: v2(119.02,39.76) 119.47,40.22 CPU1.AB10 ; v2(19.91,40.3) 19.84,40.37 U3401.3
USB_CPU_PP1: length 124.8
  L4 w0.14: v2(22.96,24.57) 22.96,24.07 23.36,23.66 29.56,23.66 31.63,25.73 37.63,25.73 38.52,24.84 41.79,24.84 42.29,25.35 45.97,25.35 v2(46.25,25.07)
  L6 w0.127: v2(117.93,38.45) 118.35,38.03 118.35,37.44 118.2,37.29 118.2,36.96 118.64,36.51 118.64,32.99 117.13,31.47 117.13,30.33 115.81,29.02 113.15,29.02 112.34,28.21 111.53,28.21 110.86,28.88 109.23,28.88 108.76,29.35 103.35,29.35 102.24,28.24 101.52,28.24 98.94,25.67 98.37,25.67 96.54,23.84 89.92,23.84 87.23,21.14 84.73,21.14 78.84,15.25 76.01,15.25 75.32,14.57 70.87,14.57 70.51,14.92 58.82,14.92 57.82,13.92 55.03,13.92 54.38,14.57 50.44,14.57 47.75,17.26 47.75,23.57 v2(46.25,25.07)
  BOTTOM w0.102: v2(22.96,24.57) 23,24.61 23,25.5 22.85,25.66 EL3603.4 ; CPU1.AD7 v2(117.93,38.45)
USB_CPU_PP2: length 173.3
  TOP w0.102: v1(212.62,45.3) 212.48,45.44 ; 212.48,45.44 212.11,45.07 211.45,45.07 211.17,44.8 EL6601.3 ; 212.48,45.44 212.77,45.73 217.65,45.73 v2(217.93,45.45)
  L4 w0.14: v2(217.93,45.45) 218.05,45.58 218.23,45.58 218.56,45.25 219.9,43.91 219.9,34.86 220.16,34.61 220.16,32.18 221.56,30.77 221.56,24.39 219.34,22.17 219.34,17.38 215.1,13.14 213.99,13.14 211.83,10.98 205.27,10.98 203.69,9.41 195.92,9.41 193.09,6.58 187.28,6.58 185.38,8.47 164.99,8.47 164.67,8.79 164.67,9.23 163.36,10.54 157.88,10.54 157.35,10.01 144.57,10.01 144.57,10.01 143.51,10.01 138.75,14.77 138.75,15.82 136.08,18.49 129.81,18.49 129.36,18.05 124,18.05 122.95,16.99 119.14,16.99 116.73,19.4 116.73,24.07 115.06,25.74 115.06,28.92 114.65,29.33 114.65,31.6 114.16,32.09 114.16,32.4 v2(113.79,32.77)
  BOTTOM w0.089: CPU1.AJ3 115.41,36.19 115.49,36.11 115.49,35.74 115.53,35.63 115.53,35.43 115.49,35.36 115.49,35.07 115.53,34.98 115.53,34.58 115.4,34.46 115.4,34.24
  BOTTOM w0.102: v2(113.79,32.77) 113.79,32.65 113.91,32.52 114.23,32.52 115.4,33.69 115.4,33.79 115.4,34.24
USB_CPU_PP2_C: length 20
  TOP w0.102: 208.25,46.06 208.25,45.78 208.25,45.78 208.25,45.36 208.4,45.2 208.54,45.07 208.94,45.07 209.21,44.8 EL6601.4 ; 208.25,46.06 208.25,47.31 207.82,47.74 206.17,47.74 205.73,47.31 205.73,43.81 204.76,42.83 203.51,42.83 203.26,43.08 203.26,43.48 v2(203.09,43.65) ; 208.25,46.06 v1(208.1,46.06)
  BOTTOM w0.102: IOBD1.29 205.06,48 204.96,47.89 204.68,47.89 203.82,47.03 203.54,47.03 ED6601.6 203.41,46.42 203.51,46.32 203.58,46.32 203.66,46.23 203.66,45.58 203.15,45.07 203.02,45.07 202.93,44.98 202.93,43.82 v2(203.09,43.65)
USB_CPU_PP3: length 125.6
  TOP w0.102: v2(31.39,41.49) 31.67,41.21 32.38,41.21 ; U3802.1 34.02,40.92 34.08,40.85 34.08,40.7 33.99,40.6 33.14,40.6 32.53,41.21 32.38,41.21 ; 32.38,41.21 v1(32.38,41.36)
  L4 w0.14: v2(44.72,36.44) 44.12,35.83 41.24,35.83 40.14,36.93 38.49,36.93 34.8,40.62 32.92,40.62 32.23,41.32 31.56,41.32 v2(31.39,41.49)
  L6 w0.089: v2(117.91,40.49) 117.64,40.22 117.5,40.22 117.3,40.03 117.3,37.6 117.43,37.47 117.43,36.58 117.56,36.46 117.56,36.03 117.38,35.85 117.32,35.85 117.31,35.84
  L6 w0.127: v2(44.72,36.44) 44.99,36.17 45.57,36.17 46.87,34.87 46.87,28.16 48.63,26.4 48.79,26.25 48.79,18.63 51.07,16.34 57.05,16.34 57.54,16.84 61.37,16.84 61.66,16.55 67.5,16.55 68.08,15.96 71.91,15.96 72.24,16.29 78.41,16.29 84.94,22.82 87.44,22.82 89.85,25.23 93.8,25.23 95.68,27.11 95.68,27.85 96.12,28.29 98.79,28.29 99.78,29.29 101.79,29.29 102.9,30.39 107.51,30.39 108.2,31.08 112.52,31.08 112.8,30.8 114.29,30.8 115.59,32.09 115.59,34.12 117.31,35.84
  BOTTOM w0.102: CPU1.AD10 v2(117.91,40.49)
USB_CPU_PP4: length 220
  TOP w0.102: v1(112.94,32.73) 112.81,32.73 v2(112.37,33.18)
  L6 w0.127: v2(113.84,86.57) 114.1,86.84 114.1,87.11 112.1,89.1 109.51,89.1 108.93,89.68 103.84,89.68 102.63,88.48 80.47,88.48 79.09,89.86 53.34,89.86 49.56,86.08 49.56,19.11 50.86,17.82 55.57,17.82 55.76,17.63 61.77,17.63 62.08,17.32 67.82,17.32 68.4,16.74 71.6,16.74 71.92,17.07 78.09,17.07 87.03,26.01 93.48,26.01 94.9,27.43 94.9,28.29 95.68,29.07 98.47,29.07 99.46,30.06 101.47,30.06 102.58,31.17 106.8,31.17 108.48,32.85 111.6,32.85 111.73,32.97 111.73,33.31 111.86,33.44 112.12,33.44 112.37,33.19 v2(112.37,33.18)
  BOTTOM w0.102: v2(113.84,86.57) 114.12,86.86 114.12,87.76 114.35,88 117.7,88 118.24,88.54 118.24,88.72 118.13,88.84 117.88,88.84 117.79,88.92 EL5501.4 ; v2(112.37,33.18) 112.59,32.96 112.59,32.95 112.73,32.8 112.92,32.8 113.53,33.41 114.52,33.41 114.96,33.84 114.96,35.22 CPU1.AJ2
USB_CPU_PP5: length 171.5
  TOP w0.102: 215.16,44.28 217.85,44.28 v2(217.95,44.18) ; 215.16,44.28 213.95,44.28 213.4,43.74 212.28,43.74 212.07,43.94 EL6603.2 ; 215.16,44.28 v1(215.16,44.41)
  L4 w0.14: v2(217.95,44.18) 218.89,44.18 219.38,43.69 219.38,34.65 219.63,34.39 219.63,24.88 218.82,24.07 218.82,17.59 215.09,13.87 213.8,13.87 211.44,11.51 205.05,11.51 203.48,9.93 195.71,9.93 192.98,7.2 187.39,7.2 185.5,9.09 168.31,9.09 167.42,9.98 164.95,9.98 163.87,11.06 157.64,11.06 157.11,10.53 143.76,10.53 139.27,15.02 139.27,16.04 136.29,19.01 129.54,19.01 128.29,20.27 125.43,20.27 122.7,17.53 119.86,17.53 118.5,18.9 118.5,21.87 117.77,22.59 117.77,27.42 115.65,29.54 115.65,32.03 114.83,32.85 114.83,37.28 115.5,37.95 v2(116.86,37.95)
  BOTTOM w0.102: CPU1.AF7 117.39,38.26 117.17,38.26 v2(116.86,37.95)
USB_CPU_PP5_C: length 7
  TOP w0.102: 208.51,44.04 207.72,44.83 207.72,46.48 207.48,46.71 207.29,46.71 v2(207,46.99) ; 208.51,44.04 v1(208.63,44.16) ; 208.51,44.04 208.84,43.71 208.95,43.71 209.18,43.94 EL6603.1
  BOTTOM w0.102: IOBD1.26 206,46.8 206.08,46.71 206.72,46.71 v2(207,46.99)
USB_CPU_PP7: length 169.5
  TOP w0.102: v2(209.61,50.01) 209.08,50.01 208.55,49.49 R6605.2
  L4 w0.14: v2(209.61,50.01) 211,50.01 211.75,49.26 211.75,47.48 212.28,46.96 212.28,45.5 212.98,44.8 215.02,44.8 218.54,41.28 218.54,32.94 218.26,32.66 218.26,32.66 217.4,31.79 217.4,29.6 218.84,28.15 218.84,25.61 217.69,24.46 217.69,17.58 215.07,14.96 213.72,14.96 211.08,12.32 204.75,12.32 203.15,10.72 195.38,10.72 192.71,8.05 187.65,8.05 185.82,9.88 168.92,9.88 166.96,11.85 143.71,11.85 140.06,15.5 140.06,16.36 136.62,19.8 129.87,19.8 128.51,21.16 124.84,21.16 123.03,19.34 119.96,19.34 119.39,19.92 119.39,27.08 116.85,29.62 116.85,30.8 116.45,31.2 116.45,32.09 115.6,32.94 115.44,33.1 115.44,33.72 115.72,34 v2(116.48,34)
  BOTTOM w0.102: v2(116.48,34) 116.2,34.28 116.2,35.37 CPU1.AH2
USB_CPU_PP7_C: length 1.7
  TOP w0.102: R6605.1 206.29,49.49 v2(206.27,49.47)
  BOTTOM w0.102: IOBD1.32 206,49.2 v2(206.27,49.47)
USB_EN#: length 292.6
  TOP w0.089: R2434.2 v1(161.39,13.96) 161.16,14.18 KBC24.13 156.11,14.18 v2(154.07,16.22)
  L3 w0.089: v2(132.87,12.91) 133.31,13.36 133.31,14.09 134.07,14.85 134.97,14.85 137.14,17.02 149.34,17.02 149.6,16.77 153.52,16.77 v2(154.07,16.22)
  L4 w0.089: v2(132.87,12.91) 132.33,12.38 132.33,12.21 131.3,11.17 116.86,11.17 116.68,11.36 115.37,11.36 114.82,10.81 110.47,10.81 108.17,8.5 96.87,8.5 94.19,11.18 77.15,11.18 71.28,5.31 64.75,5.31 64.6,5.16 58.33,5.16 57.9,4.72 57.36,4.72 v2(57.04,4.41)
  L6 w0.089: v2(19.73,30.06) 19.73,28.36 22.17,25.92 24.41,25.92 25.04,25.3 25.04,23.07 26.94,21.17 26.94,5.55 28.21,4.28 34.18,4.28 34.95,5.04 56.41,5.04 v2(57.04,4.41) ; v2(154.07,16.22) 154.5,16.64 157.42,16.64 158.58,15.48 176.17,15.48 178.07,17.39 178.07,17.64 179.38,18.95 189.69,18.95 190.18,19.44 207.34,19.44 207.56,19.22 210.3,19.22 211.68,20.61 211.68,21.9 211.99,22.21 211.99,23.69 211.68,23.99 211.68,27.76 213.04,29.12 213.04,29.52 212.22,30.34 212.22,33.11 211.84,33.49 211.84,39.95 211.25,40.54 211.25,44.55 211.43,44.72 211.43,56.25 209.57,58.11 209.57,58.64 v2(208.94,59.27)
  BOTTOM w0.089: v2(208.94,59.27) 207.19,59.27 206.87,59.6 IOBD1.58 ; v2(19.73,30.06) 19.73,30.09 21.19,31.55 U3503.4 21.17,32.03 19.9,33.3 19.9,34.92 U3501.4 19.78,36.87 19.78,38.31 20.73,39.27 U3502.4
USB_OC0#: length 294.1
  TOP w0.102: v2(134.41,37.81) 134.13,37.53 134.13,36.92 134.31,36.74 134.31,36.74 136.06,34.99 136.06,32.24 138.93,29.37 151.73,29.37 152.81,28.29 153.17,28.29 153.83,27.63 164.51,27.63 169.84,22.3 169.84,19.39 v1(181.89,7.35) 183.74,5.5 v2(183.74,3.95)
  L4 w0.102: v2(183.74,3.95) 183.05,4.63 172.92,4.63 172.28,5.27 160.88,5.27 160.04,6.11 155.47,6.11 154.74,5.38 142.68,5.38 141.19,6.87 137.66,6.87 134.11,10.43 132.75,10.43 132.29,9.97 125.72,9.97 124.79,9.03 110.72,9.03 103.73,2.04 84.42,2.04 83.56,2.91 68.83,2.91 68.09,3.64 64.28,3.64 63.89,3.26 55.11,3.26 54.4,2.55 53.31,2.55 v2(52.85,3.01)
  L6 w0.102: v2(52.85,3.01) 52.17,3.69 46.63,3.69 45.48,4.84 35.03,4.84 34.26,4.08 28.13,4.08 26.75,5.47 26.75,18.7 21.98,23.46 20.29,23.46 19.58,24.17 19.58,25.87 17.44,28 17.44,30.28 17.42,30.3 v2(17.42,32.64)
  BOTTOM w0.102: CPU1.A9 130.79,39.46 131.17,39.46 132.17,38.46 132.82,37.81 v2(134.41,37.81) 134.54,37.94 RN1601.6 ; U3401.13 21.98,43.64 22.37,44.03 23.01,44.03 23.52,43.52 23.52,40.47 23.02,39.98 21.09,39.98 20.9,39.79 18.87,39.79 U3502.3 18.42,39.27 19.22,38.46 19.22,36.71 U3501.3 18.88,35.84 19.07,35.65 19.07,32.37 U3503.3 18.15,32.03 17.75,32.43 17.62,32.43 v2(17.42,32.64)
USB_OC1#: length 155.2
  L3 w0.089: v2(217.93,48.78) 218.4,48.31 218.4,41.91 219.44,40.87 219.44,35.76 218.97,35.29 218.97,33.94 215.92,30.89 215.92,25.33 209.81,19.21 206.47,19.21 201.75,14.5 199.6,14.5 199.01,13.91 189.03,13.91 183.73,19.21 176.92,19.21 172.58,23.54 147.81,23.54 147.59,23.76 140.93,23.76 138.58,26.12 138.58,27.82 135.47,30.94 135.47,32.94 135.15,33.26 135.15,37.98 v2(134.69,38.44)
  BOTTOM w0.089: CPU1.C9 129.58,39.64 129.71,39.7 129.97,39.8 130.18,39.8 130.24,39.77 130.37,39.74 130.64,39.8 130.8,39.8 130.9,39.76 131.14,39.65 131.25,39.65 132.02,38.88 132.46,38.44 v2(134.69,38.44) 134.69,38.44 RN1601.7 ; IOBD1.57 206.93,59.2 207.31,58.81 216.63,58.81 217.42,58.03 v1(217.42,53.68) 217.42,49.29 v2(217.93,48.78)
USB_OC2#: length 7.5
  BOTTOM w0.089: CPU1.D9 129.07,39.84 129.57,39.84 129.94,39.97 130.22,39.97 130.27,39.95 130.47,39.95 130.56,39.97 130.89,39.97 131.21,39.83 131.32,39.83 131.64,39.51 131.85,39.31 132.23,38.92 v1(132.84,38.92) 133.06,38.7 134.16,38.7 134.49,39.03 RN1601.8
USB_OC3#: length 6.3
  BOTTOM w0.102: RN1601.5 135.41,37.4 v1(133.88,37.4) 132.96,37.4 132.03,38.33 131.09,39.27 130.33,39.27 CPU1.B9
USB_PN0_R: length 2.5
  BOTTOM w0.102: v1(20.19,45.4) 20.06,45.27 ; 20.06,45.27 20.2,45.13 20.2,44.92 20.34,44.79 U3401.11 ; 20.06,45.27 19.82,45.51 19.82,45.7 20.05,45.92 EL3602.1
USB_POWERSHARE_VBUS_EN: length 179.9
  TOP w0.089: v1(43.45,4.41) 43.2,4.15 v2(43.2,3.9) ; KBC24.71 144.56,19.38 v2(145.31,20.13)
  L3 w0.089: v2(130.58,13.68) 130.58,13.71 133.17,16.3 134.37,16.3 136.73,18.67 138.41,18.67 139.9,20.15 143.41,20.15 143.97,19.6 144.78,19.6 v2(145.31,20.13)
  L4 w0.089: v2(43.2,3.9) 44.01,3.09 45.46,3.09 46.06,3.69 46.06,4.51 49.4,7.85 53.28,7.85 70.22,7.85 75.24,12.87 82.88,12.87 85.38,15.37 93.23,15.37 96.54,12.06 107.64,12.06 108.76,13.18 113.74,13.18 114.32,13.75 117.32,13.75 118.27,12.81 127.79,12.81 127.91,12.93 128.28,12.93 129.38,14.03 130.23,14.03 v2(130.58,13.68)
  L6 w0.089: v2(16.02,41.36) 16.02,41.34 15.59,40.91 15.59,40.55 15.77,40.37 15.77,30.44 17.24,28.97 17.24,27.82 19.38,25.68 19.38,24.09 20.21,23.27 21.8,23.27 26.55,18.52 26.55,5.39 28.05,3.88 34.35,3.88 35.11,4.65 42.45,4.65 v2(43.2,3.9)
  BOTTOM w0.089: U3401.5 18.52,42.14 18.08,41.69 16.35,41.69 v2(16.02,41.36)
USB_PP0_R: length 2.3
  BOTTOM w0.102: U3401.10 19.84,44.79 19.97,44.92 19.97,45.03 19.59,45.41 19.59,45.7 19.36,45.92 EL3602.4
USB_PWR_SHR_EN_L#: length 185.5
  TOP w0.089: v2(47.26,2.92) 47.05,3.14 v1(46.63,3.14) ; KBC24.118 152.84,7.06 v2(153.23,6.67)
  L3 w0.089: v2(47.26,2.92) 47.26,3.01 48.03,3.77 49.83,3.77 50.64,4.58 54.77,4.58 54.81,4.54 54.82,4.54 56.11,3.24 58.64,3.24 59.27,3.88 64.07,3.88 64.45,4.26 64.77,4.26 68.43,4.26 69.45,3.24 74.86,3.24 75.67,4.04 78.63,4.04 79.26,4.04 79.8,3.5 83.8,3.5 84.35,2.95 91.77,2.95 92.06,3.24 92.06,3.36 92.55,3.84 101.31,3.84 105.01,7.54 110.07,7.54 111.82,9.29 115.44,9.29 115.97,8.76 123.97,8.76 125.55,7.18 128.48,7.18 128.99,7.7 131.84,7.7 132.97,6.56 132.99,6.56 136.12,3.43 139.59,3.43 140.82,4.66 146.81,4.66 149.27,7.12 152.78,7.12 153,6.9 v2(153.23,6.67)
  L6 w0.089: v2(16.15,42.12) 16.15,42.1 15.39,41.34 15.39,40.46 15.56,40.29 15.56,30.26 17.04,28.79 17.04,27.74 19.19,25.59 19.19,23.96 20.08,23.07 21.7,23.07 26.3,18.48 26.3,5.37 27.97,3.69 34.43,3.69 35.19,4.46 40.23,4.46 41.44,3.24 46.94,3.24 v2(47.26,2.92)
  BOTTOM w0.089: v2(153.23,6.67) 152.57,7.33 R2473.1 ; v2(16.15,42.12) R3401.1
USB_TYPEC_DIS:
  vias: v1(40.25,85.38)
USB_TYPEC_R: length 4.5
  TOP w0.089: v1(27.58,88.76) 27.71,88.63 PR4322.1 27.96,87.26 PR4336.1 28.62,86.52 PC4310.1 29.09,86 PU4303.4
USB_TYPEC_SW: length 19.8
  TOP w0.254: PR4322.2 27.35,86.3 v1(27.35,84.9) 27.35,84.62 27.58,84.39 v2(27.58,81.88) ; v2(38.44,79.53) PQ4307.3
  L4 w0.254: v2(38.44,79.53) 38.44,79.7 38.25,79.89 38.25,81.11 37.36,82 33.85,82 31.95,80.11 29.34,80.11 v2(27.58,81.88)
USBC1_CC1_CONN: length 82.1
  TOP w0.356: v2(32.41,34.76) 32.02,34.38 v1(32.02,34.28)
  TOP w0.508: v2(32.41,34.76) 32.46,34.81 R3728.2
  L4 w0.508: v2(14.5,40.73) 14.55,40.68 15.06,40.68 16.15,39.58 17.43,39.58 19.74,37.27 26.24,37.27 28.75,34.76 v2(32.41,34.76) ; v2(8.86,90) 8.89,90.03 8.89,90.91 8.53,91.27 7.77,91.27 7.39,91.65 7.39,92.45 7.68,92.73 v2(7.7,92.73)
  L6 w0.508: v2(14.5,40.73) 14.5,41.24 15.48,42.22 15.48,43.15 15.45,43.18 15.45,43.98 15.9,44.42 15.9,50.85 15.48,51.27 15.48,56.06 11.68,59.87 11.68,80.18 9.6,82.26 8.02,82.26 6.61,83.67 6.61,85.81 8.86,88.07 v2(8.86,90)
  BOTTOM w0.191: v2(7.7,92.73) 7.65,92.73 7.26,92.35 USB1.A5
USBC1_CC2_CONN: length 98.1
  TOP w0.356: v1(35.2,36.08) 35.2,35.6 v2(35.07,35.47)
  TOP w0.508: R3727.2 v2(35.07,35.47)
  L3 w0.089: 5.99,95.21 5.54,94.76 5.28,94.22 USB1.B5 5.47,92.48 5.5,92.42 5.5,92.07 5.43,91.91 5.43,91.67 5.56,91.42 5.86,91.27 6.88,91.27
  L3 w0.254: v2(8.73,96.4) 7.54,95.21 5.99,95.21
  L3 w0.508: 9.55,91.27 11.3,89.52 11.3,89.14 v2(11.32,89.11) ; 9.55,91.27 6.88,91.27 ; 9.55,91.27 9.55,95.59 v2(8.73,96.4)
  L4 w0.089: 6.8,95.21 5.99,95.21 5.61,94.83 5.5,94.67 5.34,94.41 USB1.B5
  L4 w0.254: v2(8.73,96.4) 8.71,96.4 8.09,95.79 7.37,95.79 6.8,95.21
  L4 w0.508: v2(35.07,35.47) 32.63,37.91 20,37.91 17.56,40.35 v2(16.84,40.35)
  L6 w0.508: v2(11.32,89.11) 11.06,89.11 10.56,88.62 10.56,86.96 11.2,86.32 11.2,82.64 12.31,81.52 12.31,60.18 16.17,56.31 16.17,51.47 16.84,50.8 v2(16.84,40.35)
USBC_DPAUX1: length 65
  TOP w0.102: ED3803.2 14.96,99.45 v2(14.88,99.53) R3830.1 ; v1(35.15,61) 35.66,61 v2(35.71,61.05) 35.81,60.95 35.81,60.49 35.72,60.4 U3801.27
  L4 w0.14: v2(8.53,94.68) 9.19,95.34 11.95,95.34 13.49,96.88 13.49,98.53 14.49,99.53 v2(14.88,99.53) 15.37,99.03 15.37,95.86 17.18,94.06 18.32,94.06 18.83,93.55 18.83,91.64 21.65,88.82 21.65,82.22 25.18,78.69 27.09,78.69 31.33,74.45 31.33,70.81 35.57,66.57 35.57,65.22 36.2,64.59 36.2,62.3 35.92,62.02 35.92,61.26 v2(35.71,61.05)
  BOTTOM w0.102: USB1.A8 7.33,93.85 7.51,93.67 8.14,93.67 8.4,93.93 8.4,94.55 v2(8.53,94.68)
USBC_DPAUX2: length 71.4
  TOP w0.102: ED3803.1 14.55,98.72 14.29,98.97 v1(14.29,99.5) 14.29,99.71 v2(14.88,100.29) R3831.1 ; U3801.26 36.12,60.4 36.04,60.49 36.04,60.74 v2(36.34,61.05)
  L4 w0.089: 5.99,91.15 5.64,91.29 5.43,91.67 USB1.B8
  L4 w0.14: v2(36.34,61.05) 36.18,61.21 36.18,61.91 36.47,62.19 36.47,64.7 35.83,65.33 35.83,66.68 31.59,70.92 31.59,74.56 27.2,78.95 25.29,78.95 21.92,82.33 21.92,88.93 19.1,91.75 19.1,93.66 18.44,94.32 17.29,94.32 15.64,95.97 15.64,99.53 v2(14.88,100.29) 13.23,98.64 13.23,96.99 11.84,95.6 9.08,95.6 8.69,95.21 7.61,95.21 6.62,94.22 6.62,91.53 6.24,91.15 5.99,91.15
USBCOMP: length 2.7
  TOP w0.254: R1603.1 119.44,37.16 119,37.59 119,37.67 v2(118.97,37.71) 118.53,37.71 v1(118.01,37.19)
  BOTTOM w0.254: v2(118.97,37.71) 119.24,37.71 CPU1.AB6
V_SM_VREF_CNTA: length 53.3
  L4 w0.508: v2(110.16,72.73) 109.42,71.99 105.1,71.99 104.41,72.67 98.45,72.67 93.83,68.05 93.83,57.57 84.98,48.73 75.62,48.73 v2(74.75,47.87)
  BOTTOM w0.254: v2(110.16,72.73) 110.06,72.83 109.66,72.83 CPU1.AY67
  vias: v1(72.54,46.95)
V_SM_VREF_CNTB: length 76.9
  L4 w0.508: v2(47.26,42.89) 47.31,42.94 51,42.94 51.58,43.52 51.58,44.16 52.6,45.17 55.52,45.17 61.48,51.14 74.19,51.14 75.34,52.28 79.9,52.28 92.81,65.19 92.81,68.47 98.28,73.94 v2(107.03,73.94)
  BOTTOM w0.089: CPU1.BA67 108.38,73.28 108.14,73.4 107.98,73.46 107.87,73.56 107.41,73.56 v2(107.03,73.94)
  vias: v1(46.81,42.53)
VCONN_MON_P1: length 3.7
  TOP w0.089: v1(29.92,24.73) R3706.2 30.45,25.61 R3735.1 30.97,26.14 30.97,26.59 31.42,27.04 U3701.19
VCREF0: length 7.3
  TOP w0.089: KBC24.25 159.38,18.98 159.91,19.52 159.91,20.41 160.6,21.09 C2409.1 161.46,21.12 R2448.1 R2424.1 164.15,21.12 v1(164.18,21.14)
VD_IN1_C: length 4.9
  TOP w0.114: C2613.2 143.83,76.69 R2610.2 142.84,76.87 C2612.2 141.88,77.45 v1(141.5,77.84) 141.19,77.84 140.99,77.63 R2611.1
VGA_CORE: length 57.2
  TOP w0.508: v2(166.75,79.9) 166.72,79.87 C7711.1
  L3 w0.508: v2(140.23,121.45) 139.23,122.44 137.09,122.44 136.21,123.32 132.65,123.32 131.22,121.89 127.95,121.89 127.92,121.87 127.92,121.87 127.55,121.49 127.55,121.49 127.25,121.19 127.25,118.86 127.86,118.25 v2(127.86,117.47) 127.57,117.18 126.76,117.18 123.64,114.06 123.64,102.78 126.83,99.59 126.83,97.94
  BOTTOM w0.457: GPU1.T16 v2(160.75,85.9) ; GPU1.V10 v2(158.75,79.9) ; GPU1.V12 v2(158.75,81.9) ; GPU1.T14 v2(160.75,83.9) ; GPU1.T12 v2(160.75,81.9) ; GPU1.P14 v2(162.75,83.9) ; GPU1.P10 v2(162.75,79.9) ; GPU1.K16 v2(166.75,85.9) ; GPU1.K14 v2(166.75,83.9) ; GPU1.M16 v2(164.75,85.9) ; GPU1.P12 v2(162.75,81.9) ; GPU1.M12 v2(164.75,81.9) ; GPU1.P16 v2(162.75,85.9) ; GPU1.K10 v2(166.75,79.9) ; GPU1.M14 v2(164.75,83.9) ; GPU1.V16 v2(158.75,85.9) ; GPU1.T10 v2(160.75,79.9) ; GPU1.V14 v2(158.75,83.9) ; GPU1.K12 v2(166.75,81.9) ; GPU1.M10 v2(164.75,79.9)
  BOTTOM w0.508: v2(127.86,117.47) 127.83,117.44 PR8309.1
  vias: v1(130.07,89.37) v1(135.78,89.24) v1(137.43,97.5) v1(140.1,94.45) v1(143.53,91.91) v1(152.42,88.99) v1(154.58,83.53) v3(128.16,95.97) v3(128.16,95.08) v3(128.16,94.07) v3(128.16,93.18) v3(129.18,95.97) v3(129.18,95.08) v3(129.18,94.07) v3(129.18,93.18) v3(130.2,95.72) v3(131.21,95.72) v3(132.35,97.88) v3(132.35,96.86) v3(132.35,95.85) v3(132.35,94.96) v3(132.35,94.07) v3(132.35,93.18) v3(133.24,97.88) v3(133.24,96.86) v3(133.24,95.85) v3(133.24,94.96) v3(133.24,94.07) v3(133.24,93.18) v3(134.26,97.88) v3(134.26,96.86) v3(134.26,95.85) v3(135.28,97.88) v3(135.28,96.86) v3(135.28,95.85) v3(136.42,95.46) v3(136.42,94.6) v3(136.42,93.69) v3(136.42,92.8) v3(136.42,91.91) v3(137.43,95.46) v3(137.43,94.6) v3(137.43,93.69) v3(137.43,92.8) v3(137.43,91.91) v3(138.45,95.46) v3(138.45,94.6) v3(138.45,93.69) v3(138.45,92.8) v3(138.45,91.91) v3(138.45,91.02) v3(139.97,91.91) v3(140.1,88.86) v3(140.86,91.91) v3(141.12,88.86) v3(142.13,91.02) v3(142.13,90) v3(146.32,89.75) v3(147.21,89.24) v3(148.86,88.73) v3(149.63,87.08) v3(150.77,86.96) v3(151.28,86.07)
VGA_CORE_DISCHG: length 2
  BOTTOM w0.089: v1(126.51,116.55) 126.33,116.72 PR8309.2 126.19,117.29 PQ8305.3
VGA_CORE_PSI: length 120.8
  TOP w0.089: v2(128.9,124.98) 128.8,124.88 v1(128.8,124.42) 129.3,123.92 129.3,122.65 PR8257.1
  L3 w0.089: v2(171.75,74.72) 172.11,75.07 172.11,77.54 174.79,80.22 176.04,80.22 176.88,81.06 v2(177.54,81.06)
  L4 w0.089: v2(128.9,124.98) 129.12,125.21 130.64,125.21 131.37,124.48 137.4,124.48 137.92,123.95 139.3,123.95 141.4,121.85 141.4,120.14 142.24,119.3 148.41,119.3 148.46,119.35 149.25,119.35 150.52,120.61 152.42,120.61 153.06,119.98 156.1,119.98 157.15,121.03 162.11,121.03 162.96,121.88 169.08,121.88 172.33,118.63 184.24,118.63 184.93,117.94 184.94,117.94 185.37,117.51 185.44,117.44 185.44,115.4 187.73,113.12 187.73,102.58 189.69,100.61 189.69,99.08 v2(188.87,98.26)
  BOTTOM w0.089: v2(188.87,98.26) 186.84,96.23 186.84,93.37 178.75,85.28 178.75,82.97 178.77,82.95 178.77,81.71 178.07,81.01 177.59,81.01 v2(177.54,81.06) ; v2(171.75,74.72) 171.77,74.72 GPU1.B4
VGA_CORE_VID: length 118.4
  L3 w0.127: v2(169.27,77.17) 170.3,76.15 170.3,75.55 170.74,75.12 171.15,75.12 171.72,75.69 171.72,77.48 174.94,80.69 175.62,80.69 176.55,81.62 v2(177.85,81.62)
  L4 w0.127: v2(188.87,99.91) 187.19,101.59 187.19,112.92 184.92,115.19 184.92,117.23 184.73,117.43 183.87,118.29 183.74,118.41 172.25,118.41 170.62,120.05 170.19,120.05 169.5,120.74 162.55,120.74 162.32,120.51 158.42,120.51 156.61,118.71 155.21,118.71 154.45,119.47 152.55,119.47 151.53,118.45 150.13,118.45 149.63,118.96 148.86,118.96 148.48,118.57 142.1,118.57 140.87,119.81 140.87,121.62 139.07,123.42 137.7,123.42 137.18,123.94 131.18,123.94 v2(130.58,124.55)
  BOTTOM w0.089: PR8207.1 130.78,124.34 v2(130.58,124.55) ; v2(169.27,77.17) 169.29,77.2 169.35,77.2 GPU1.E7 ; v2(188.87,99.91) 186.08,97.12 186.08,93.69 177.82,85.43 v1(177.82,83.02) 177.82,82.98 177.81,82.98 177.81,81.65 v2(177.85,81.62)
VGACORE_GND_SENSE_1: length 119.9
  TOP w0.254: v2(187.98,94.93) 187.82,95.08 186.68,95.08 v1(185.8,94.19) 179.37,87.77 179.37,81.19 179.58,80.98 179.87,80.76 v2(180.08,80.76)
  L4 w0.254: v2(141.88,123.28) 142.08,123.08 144.49,123.08 147.09,120.48 147.92,120.48 149.06,121.63 152.51,121.63 153.27,120.86 155.31,120.86 156.71,122.26 160.85,122.26 162.37,123.79 168.86,123.79 171.92,120.73 172.84,119.81 184.8,119.81 186.84,117.77 186.84,116.25 191.41,111.68 191.41,98 188.33,94.93 v2(187.98,94.93) ; v2(168.85,72.1) 169.36,72.6 173.38,72.6 173.63,72.86 176.17,72.86 176.93,73.62 177.9,73.62 179.68,75.4 182.48,75.4 183.41,76.33 183.41,77.84 182.55,78.7 182.01,78.7 180.08,80.63 v2(180.08,80.76)
  BOTTOM w0.203: v2(168.85,72.1) GPU1.F1
  BOTTOM w0.254: PR8220.2 141.75,123.15 v2(141.88,123.28)
VGACORE_VDD_SENSE_1: length 120
  TOP w0.254: v2(187.98,95.75) 187.82,95.59 186.47,95.59 v1(184.27,93.39) 178.86,87.98 178.86,80.98 179.24,80.59 v2(179.7,80.25)
  L4 w0.254: v2(168.17,72.1) 168.17,72.13 169.15,73.11 173.16,73.11 173.42,73.37 175.96,73.37 176.72,74.13 177.69,74.13 179.47,75.91 182.27,75.91 182.9,76.54 182.9,77.63 182.34,78.19 181.8,78.19 179.74,80.25 v2(179.7,80.25) ; v2(141.88,122.39) 142.06,122.57 144.28,122.57 146.88,119.98 148.13,119.98 149.27,121.12 152.3,121.12 153.06,120.36 154.89,120.36 155.52,120.36 156.92,121.75 160.85,121.75 161.06,121.75 162.58,123.28 168.65,123.28 172.63,119.3 184.59,119.3 186.33,117.56 186.33,116.04 190.9,111.47 190.9,98.22 188.43,95.75 v2(187.98,95.75)
  BOTTOM w0.203: v2(168.17,72.1) 168.46,72.39 168.46,72.5 168.46,73.11 GPU1.F2
  BOTTOM w0.254: v2(141.88,122.39) PR8221.2
VIDEO_CLK_XTAL_SS: length 5.2
  TOP w0.089: R7601.1 173.81,79.97 175.03,79.97 v2(175.28,79.72) 175.33,79.67 v1(175.87,79.67)
  BOTTOM w0.089: GPU1.A10 173.65,80.08 173.76,79.97 175.03,79.97 v2(175.28,79.72)
VPP1: length 3.4
  BOTTOM w0.089: VRAM1.A5 176.76,103.69 TP7801.1
VPP2: length 2.8
  BOTTOM w0.089: TP7802.1 176.17,117.52 VRAM1.U5
VR_CAP: length 3.4
  TOP w0.203: 159.56,15.58 158.96,16.18 KBC24.18
  TOP w0.254: 159.56,15.58 v1(159.94,15.58) 161.23,15.58 C2418.1
VR_EN: length 165.9
  L4 w0.102: v2(212.3,53.04) 212.3,53.32 209.37,56.26 209.37,57.42 209.11,57.67 208.55,57.67 205.75,60.48 197.88,60.48 196.5,61.86 195.19,61.86 192.67,64.39 192.67,65.05 192.01,65.71 192.01,67.7 190.52,69.18 188.41,69.18 187.85,69.75 185.51,69.75 184.6,70.66 183.64,70.66 182.09,69.1 182.09,68.23 182.34,67.98 182.98,67.98 v2(183.28,68.29)
  L6 w0.102: v2(183.28,68.29) 181.5,66.51 181.5,62.7 182.14,62.06 182.14,60.72 181.63,60.21 v2(181.63,60.2) ; v2(166.77,13.42) 167.42,14.07 177.23,14.07 180.82,17.66 188.06,17.66 189.71,16.01 193.84,16.01 195.49,17.65 195.49,17.96 196.05,18.53 205.86,18.53 206.11,18.27 210.58,18.27 213.97,21.66 213.97,29.69 212.87,30.78 212.87,33.37 212.49,33.76 212.49,40.22 211.86,40.85 211.86,44.23 213.3,45.68 213.3,47.51 213.05,47.76 212.72,47.76 212.36,48.12 212.36,52.97 v2(212.3,53.04)
  BOTTOM w0.102: v2(181.63,60.2) 181.63,60.36 181.35,60.64 PU4601.40 ; R4002.2 155.8,18.96 156.61,19.77 157.5,19.77 157.88,20.15 157.88,21.04 158.26,21.42 158.26,23.4 158.7,23.84 159.91,23.84 v1(160.59,24.51) 161.78,24.51 162.2,24.09 163.39,24.09 163.77,24.48 163.77,24.81 164.05,25.09 165.25,25.09 165.6,24.73 165.6,14.59 v2(166.77,13.42)
VR_RDY: length 3.8
  BOTTOM w0.089: PU4601.39 181.7,61.04 182.17,60.57 TP4601.1 182.44,60.43 182.99,60.07 183.64,59.67 PR4609.2
VR_SVID_ALERT#: length 60.5
  TOP w0.114: v2(185.93,61.83) 185.09,61.83 PR4605.2
  L4 w0.114: v2(185.93,61.83) 185.88,61.78 181.37,61.78 179.37,59.78 177.69,59.78 176.78,58.86 174.19,58.86 171.48,61.57 167.33,61.57 164.35,64.55 161.23,64.55 158.55,67.24 151.6,67.24 151.04,67.8 141.44,67.8 138.42,70.82 138.42,71.87 v2(137.31,72.99)
  BOTTOM w0.114: PR4623.1 185,61.83 v2(185.93,61.83) 185.94,61.82 v1(186.61,61.82) ; R728.1 v2(137.31,72.99) R727.2
VR_SVID_CLK: length 59.8
  TOP w0.114: PR4606.2 185.91,61.17 v2(185.93,61.19) 186.18,60.95 v1(186.43,60.95)
  L4 w0.114: v2(185.93,61.19) 181.48,61.19 179.56,59.27 177.95,59.27 177.05,58.37 173.98,58.37 171.28,61.07 167.13,61.07 164.14,64.06 161.03,64.06 158.34,66.74 151.39,66.74 150.92,67.22 141.32,67.22 137.92,70.62 137.92,71.61 v2(137.31,72.22)
  BOTTOM w0.114: R723.2 v2(137.31,72.22) R732.2 ; PR4624.1 v2(185.93,61.19)
VR_SVID_DATA: length 56
  TOP w0.114: PR4604.2 185.22,62.46 v2(185.93,62.46) 186.01,62.55 v1(186.56,62.55)
  L4 w0.114: v2(139.59,70.57) 139.59,70.35 141.65,68.29 151.25,68.29 151.81,67.73 156.69,67.73 158.75,67.73 161.44,65.05 164.55,65.05 167.54,62.06 171.69,62.06 174.39,59.36 176.57,59.36 177.49,60.27 179.16,60.27 181.16,62.27 185.32,62.27 185.51,62.46 v2(185.93,62.46)
  BOTTOM w0.114: v2(185.93,62.46) 185.68,62.72 PR4622.1 ; R709.2 139.47,70.7 v2(139.59,70.57)
VRALERT#: length 1.8
  TOP w0.089: v2(114.83,40.7) 114.83,41.39 TP1708.1
  BOTTOM w0.089: CPU1.AM11 114.45,41.08 v2(114.83,40.7)
VRAM_ID1: length 16
  L3 w0.089: v2(113.46,39.83) 113.46,39.61 113.28,39.43 111.37,39.43 111.13,39.19 111.13,38.46 111.27,38.31 111.27,37.04 113.18,35.14 113.95,35.14 114.46,34.63 114.46,34.1 113.34,32.98 113.34,31.58 v2(113.63,31.29)
  BOTTOM w0.089: CPU1.AP8 113.15,39.51 113.46,39.81 v2(113.46,39.83) ; R2029.2 R2030.1 114.07,30.7 v1(113.94,30.82) 113.63,31.13 113.63,31.28 v2(113.63,31.29)
VRAM_ID2: length 5.4
  TOP w0.089: v1(122.4,31.41) 122.4,31.96 R2037.1 121.72,32.65 v2(121.72,33.36) 121.24,32.88 R2038.2
  BOTTOM w0.089: CPU1.U2 122.11,35.16 122.16,34.97 122.16,34.25 122.12,34.12 122.07,34.07 122.07,33.66 121.77,33.36 121.72,33.36 v2(121.72,33.36)
VREF_CPU: length 4.9
  TOP w0.089: KBC24.95 141.72,9.78 v2(141.69,9.82)
  BOTTOM w0.089: v2(141.69,9.82) 141.56,9.94 C2406.1 140.15,9.99 R2402.2 140.1,10.93 v1(140.1,11.77)
VREG3PD:
  vias: v1(42.06,32.85)
WHITE_LED_BAT: length 10.8
  TOP w0.254: R6402.2 55.78,5.93 EC6402.1 55.78,4.54 v2(55.65,4.41) 55.27,4.02 v1(55.27,3.77)
  BOTTOM w0.254: Q6401.C 52.09,7.45 53.61,7.45 55.65,5.42 v2(55.65,4.41)
WIFI_RF_EN: length 153
  TOP w0.089: v1(206.65,59.04) 206.65,58.76 v2(206.4,58.51) 206.14,58.76 EC6603.1
  L3 w0.089: v2(215.72,51.83) 216.43,51.12 216.43,50.42 217.63,49.21 218.11,49.21 218.59,48.73 218.59,42.22 219.63,41.18 219.63,35.66 219.17,35.2 219.17,33.85 216.17,30.86 216.17,25.31 209.87,19.01 206.53,19.01 201.83,14.31 199.68,14.31 199.09,13.72 188.95,13.72 183.66,19.01 176.83,19.01 172.5,23.34 147.73,23.34 147.51,23.56 140.85,23.56 138.37,26.03 138.37,27.72 135.28,30.82 135.28,32.61 134.91,32.98 134.91,34.91 134.91,34.91 134.91,35.27 134.91,35.27 134.91,35.28 134.46,35.72 v2(134.44,35.72)
  BOTTOM w0.089: v2(215.72,51.83) 214.9,52.65 214.9,53.06 215.67,53.82 215.67,55.3 212.74,58.23 207.32,58.23 207.04,58.51 v2(206.4,58.51) 206.29,58.4 IOBD1.55 ; R1503.2 134.87,36.16 v2(134.44,35.72) 133.83,35.72 130.86,38.69 130.34,38.69 CPU1.B7
XCLK_BIASREF: length 2.3
  TOP w0.356: v1(126.59,58.27) 127.49,58.27 R1803.1
  TOP w0.508: v2(127.66,59.02) 127.66,58.41 R1803.1
  BOTTOM w0.305: v2(127.66,59.02) 127.66,58.91 127.99,58.58 CPU1.E42
XDP_BPM0: length 3.2
  TOP w0.089: TP405.1 132.48,66.77 v2(132.17,66.46)
  BOTTOM w0.089: v2(132.17,66.46) 132.06,66.35 130.35,66.35 130.23,66.23 CPU1.C55
XDP_BPM1: length 5.7
  TOP w0.089: v2(132.86,66.31) 132.61,66.06 131.63,66.06 TP406.1
  BOTTOM w0.089: CPU1.D55 129.28,66.23 129.56,65.94 130.25,65.94 130.38,66.08 130.39,66.08 130.41,66.11 131.38,66.11 131.44,66.05 131.94,66.05 131.95,66.06 132.63,66.06 132.86,66.28 v2(132.86,66.31)
XDP_DBRESET#: length 37.3
  TOP w0.114: v2(133.57,33.03) 132.86,33.74 131.34,33.74 v2(129.69,32.09) ; v2(126,26.71) 125.15,26.71 120.54,31.32 119.79,31.32 119.3,31.81 118.84,31.81 118.58,32.07 118.58,32.42 118.89,32.73 118.93,32.73 119.37,33.17 120,33.79 120.07,33.79 120.37,34.08 120.37,34.38 119.33,35.42 119.3,35.42 EC1706.1 119.04,35.67 118.43,35.67 118.13,35.98 118.13,36.55 117.44,37.24 117.44,38.24 R1701.2
  L6 w0.114: v2(129.69,32.09) 128.54,30.95 128.54,28.41 126.85,26.71 v2(126,26.71)
  BOTTOM w0.114: TP1709.1 133.65,32.98 133.6,33.03 v2(133.57,33.03) 133.57,33.29 131.59,35.27 131.59,36.06 130.81,36.84 130.37,36.84 CPU1.B5
XDP_PRDY#: length 6.3
  BOTTOM w0.089: CPU1.D56 129.15,66.56 129.2,66.51 129.62,66.51 129.64,66.53 131.66,66.53 131.66,66.53 131.68,66.53 132.26,67.12 133.32,67.12 133.37,67.07 133.57,67.07 TP1605.1
XDP_PREQ#: length 2.1
  TOP w0.089: v2(127.78,70.04) 128.44,70.04 TP1606.1
  BOTTOM w0.089: v2(127.78,70.04) 128,70.04 CPU1.D61
XDP_TCK_JTAGX: length 5.6
  BOTTOM w0.089: R417.1 135.01,67.91 v1(134.46,68.46) 134.38,68.54 132.48,68.54 132.26,68.77 131.62,68.77 131.42,68.56 131.17,68.56 131.09,68.48 131.05,68.48 CPU1.A59
XDP_TCLK: length 6.8
  BOTTOM w0.089: R406.1 135.34,70.57 v1(134.58,70.57) 133.29,70.57 133.03,70.83 132.1,70.83 131.36,70.08 131.36,69.76 131.13,69.53 130.79,69.53 130.79,69.53 130.54,69.53 130.28,69.27 CPU1.B61
XDP_TDI: length 10.5
  TOP w0.089: v2(133.39,66.66) 133.39,67.68 132.38,68.69 131.46,68.69 131.06,69.09 v1(130.67,69.09) v2(128.26,69.09)
  BOTTOM w0.089: CPU1.D60 128.76,68.71 128.37,69.09 v2(128.26,69.09) ; v2(133.39,66.66) 133.39,66.63 134.4,65.62 R422.1
XDP_TDO_CPU: length 5.8
  BOTTOM w0.089: R423.1 132.95,70.19 v1(132.85,70.3) 132.7,70.45 131.97,70.45 131.53,70.01 131.53,69.69 131.12,69.27 CPU1.A61
XDP_TMS: length 6.4
  BOTTOM w0.089: R421.1 134.01,69.43 v1(133.84,69.6) 133.75,69.51 131.86,69.51 131.27,68.92 131.02,68.92 130.94,68.83 129.86,68.83 CPU1.C60
XDP_TRST#: length 13.9
  TOP w0.089: v1(132.28,68.27) v2(131.7,68.27)
  L4 w0.127: v2(132.15,69.96) 136.99,69.96 v2(137.27,69.68)
  L6 w0.102: v2(132.15,69.96) 132.1,69.91 132.1,69.39 131.7,68.99 v2(131.7,68.27)
  BOTTOM w0.089: R402.1 138.12,69.68 v2(137.27,69.68) ; v2(131.7,68.27) 131.64,68.21 131.48,68.21 131.04,68.04 130.91,67.92 130.85,67.88 130.59,67.88 130.51,67.92 130.44,67.92 130.21,68.14 CPU1.B59 ; v2(132.15,69.96) 132.06,69.96 131.2,69.09 130.95,69.09 130.87,69.01 129.67,69.01 CPU1.C61
XTAL24_IN: length 8
  BOTTOM w0.089: R1809.2 134.22,55.28 133.18,56.32 v1(132.91,56.32) 131.06,56.32 130.78,56.04 129.87,56.04 129.86,56.03 129.62,56.03 129.61,56.04 129.22,56.04 129.21,56.03 128.97,56.03 128.96,56.04 128.2,56.04 CPU1.E37
XTAL24_IN_R: length 5.7
  BOTTOM w0.089: X1801.1 137.82,55.45 136.63,55.45 136.55,55.54 136.55,56.62 136.31,56.85 C1801.2 136.06,56.81 R1802.1 R1809.1
XTAL24_IN_R_U42: length 2.9
  BOTTOM w0.089: R2203.1 139.11,29.35 R2201.1 C2201.2 139.96,28.49 X2201.1
XTAL24_IN_U42: length 13.8
  BOTTOM w0.089: R2203.2 137.51,29.42 v1(137.43,29.42) 136.67,30.19 134.72,30.19 134.41,30.49 133.29,30.49 133.24,30.54 131.83,31.95 129.57,34.22 129.35,34.22 128.73,34.84 128.73,35.65 128.44,35.94 CPU1.E3
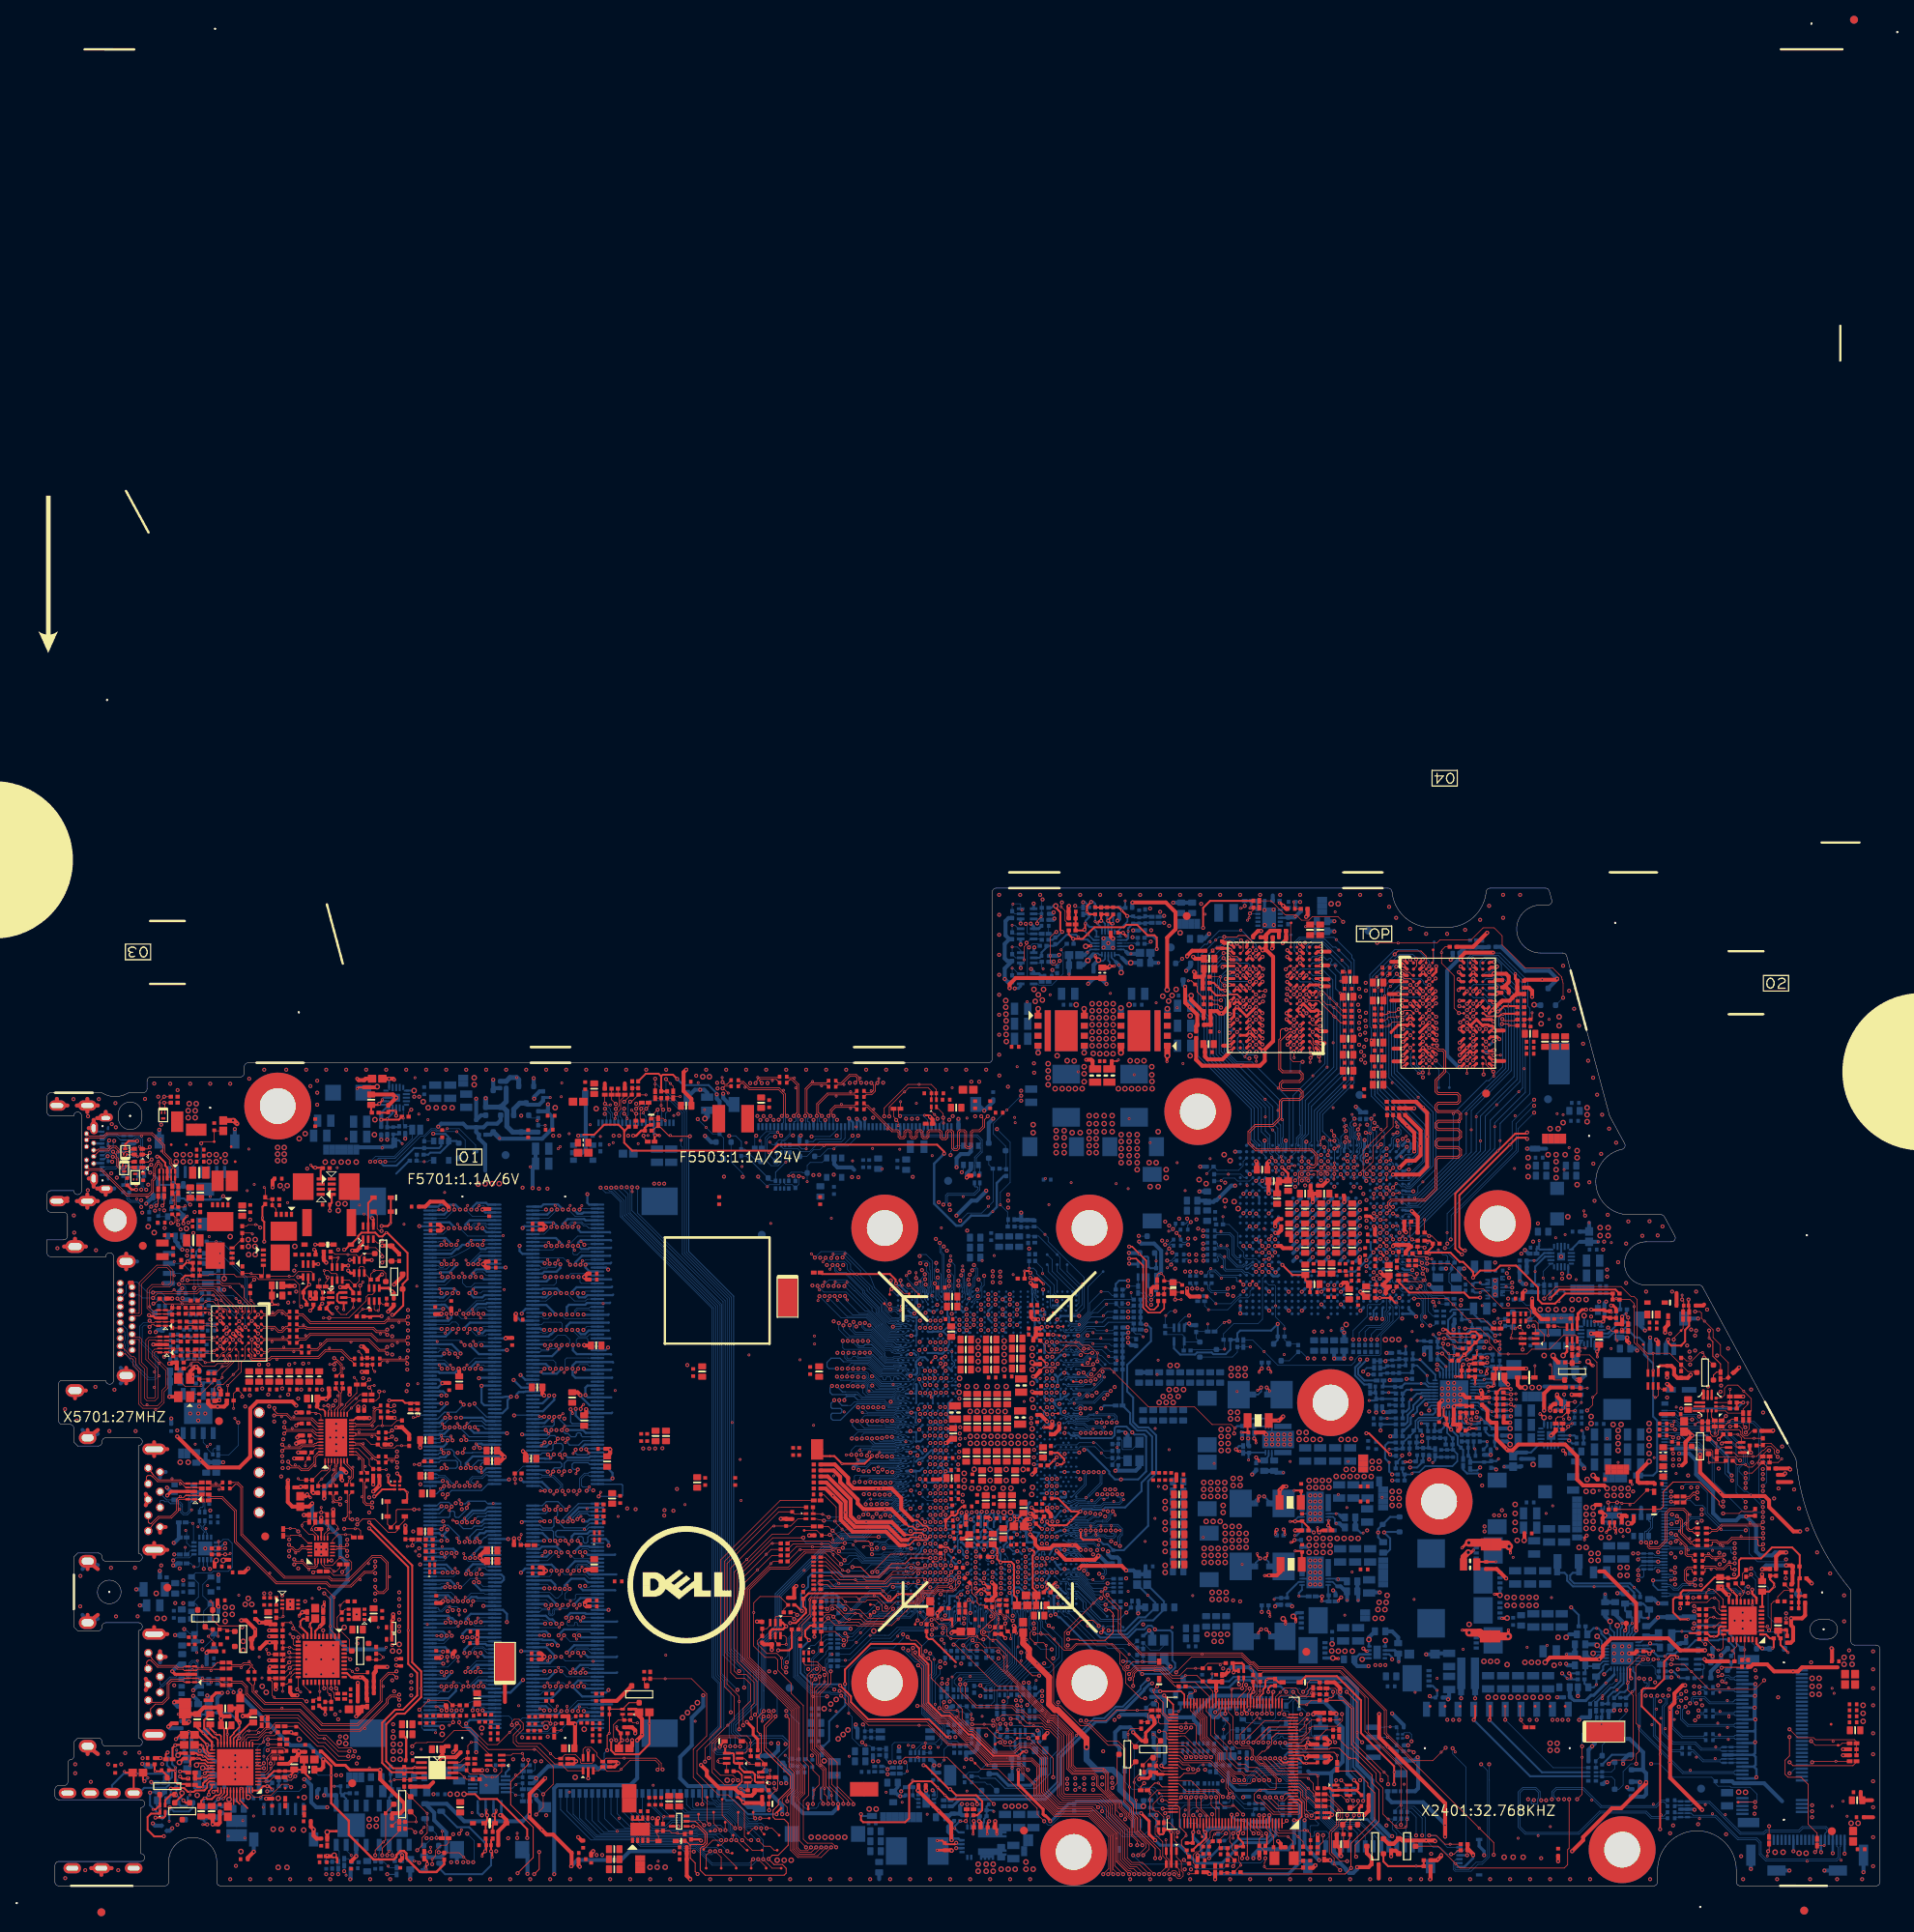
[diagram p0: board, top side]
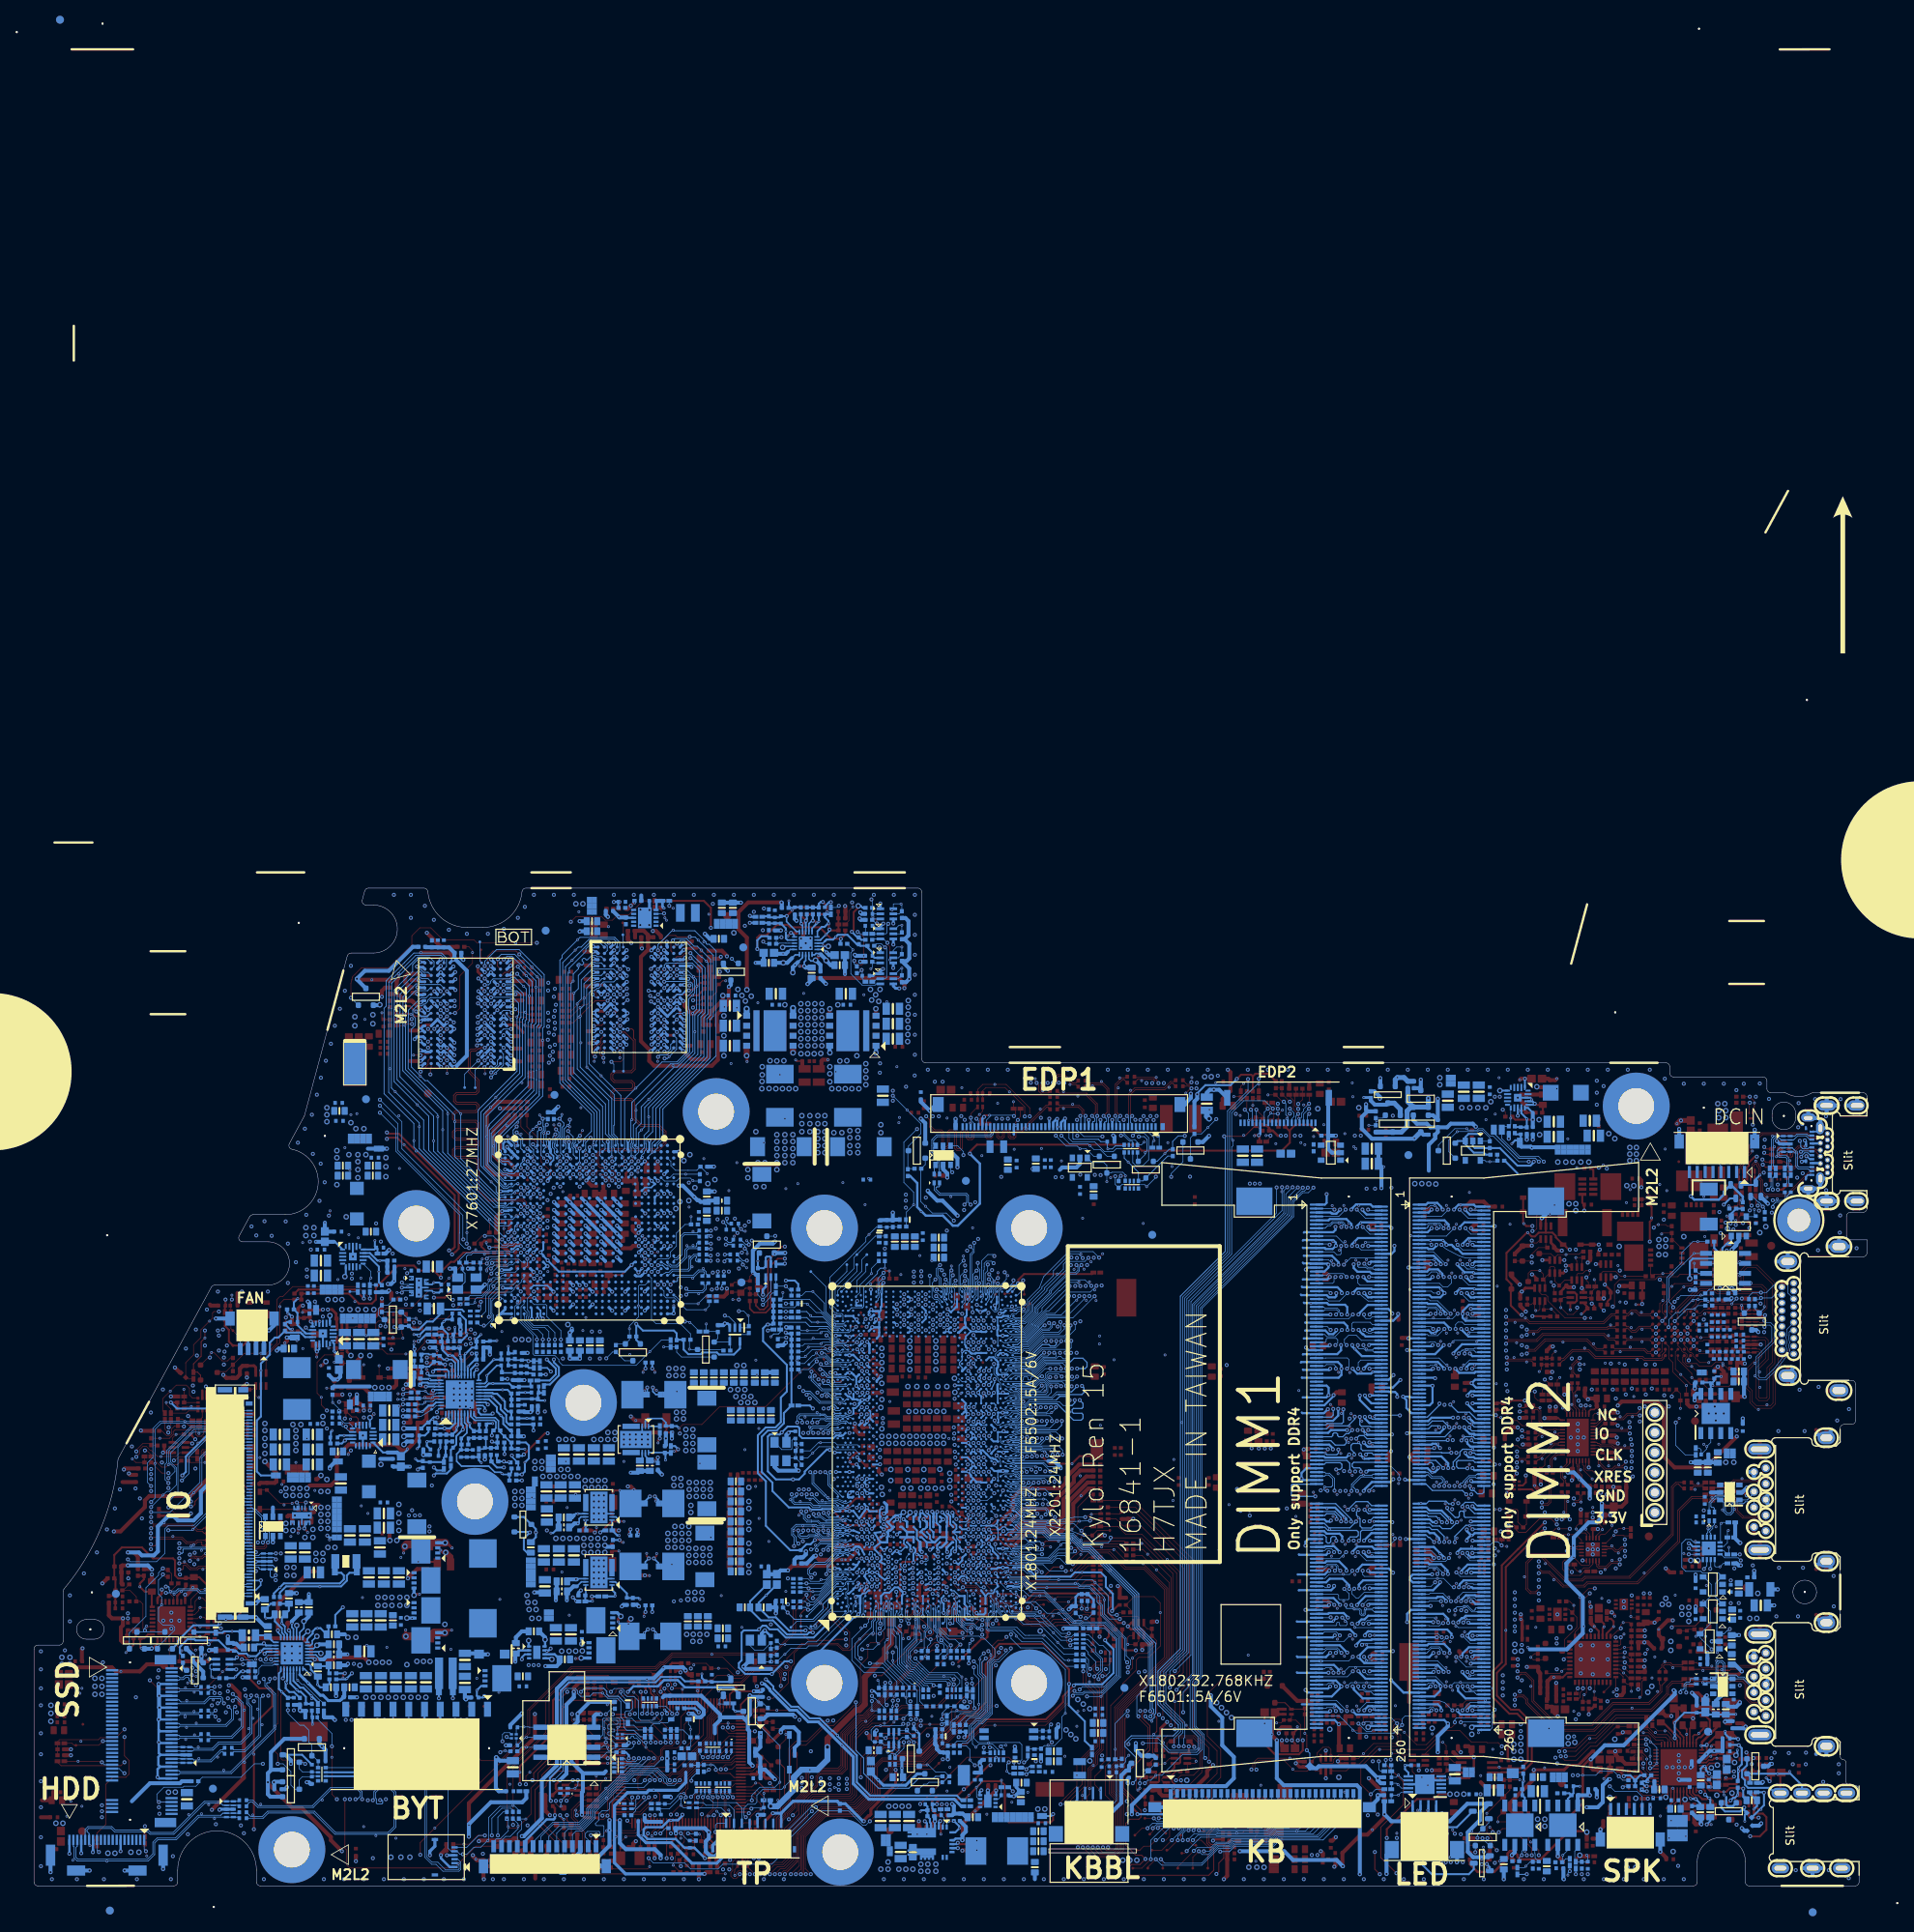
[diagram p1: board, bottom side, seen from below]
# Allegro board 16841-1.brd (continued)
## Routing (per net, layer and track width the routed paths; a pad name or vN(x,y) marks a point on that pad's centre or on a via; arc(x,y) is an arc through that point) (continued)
XTAL24_OUT: length 8.3
  BOTTOM w0.089: CPU1.E35 128.51,55.43 130.86,55.43 131.22,55.8 131.23,55.81 133.1,55.81 v1(133.89,55.02) 134.54,54.37 R1810.2
XTAL24_OUT_R: length 3.4
  BOTTOM w0.089: C1802.2 135.3,53.63 R1810.1 ; C1802.2 136.88,54.39 X1801.3 ; C1802.2 R1802.2
XTAL24_OUT_R_U42: length 5.5
  BOTTOM w0.089: X2201.3 141.87,30.56 141.28,29.96 140.12,29.96 C2202.2 R2201.2 139.06,30.26 R2202.1
XTAL24_OUT_U42: length 14.9
  BOTTOM w0.089: CPU1.C7 129.41,37.56 129.7,37.27 129.7,36.95 129.45,36.7 129.45,35.8 129.3,35.64 129.3,35.4 129.4,35.3 129.4,34.8 129.62,34.57 129.87,34.57 133.43,31.01 134.56,31.01 134.88,30.69 v1(137.43,30.69) 138.02,30.69 R2202.2
XTLI_HDMI: length 8.6
  TOP w0.089: U5701.E8 24,66.87 22.25,65.11 v1(22.25,64.6) 21.94,64.3 R5750.1 21.23,64.22 19.53,62.52 C5729.1 18.53,62.52 X5701.1
XTLO_HDMI: length 4.4
  TOP w0.089: R5748.2 R5750.2 21.41,65.16 v1(22.26,66.01) 22.82,66.01 23.39,66.59 23.39,67.21 U5701.F8
ZVM#: length 1.4
  TOP w0.089: v2(112.82,67.21) 112.29,66.68 TP618.1
  BOTTOM w0.089: CPU1.AR56 v2(112.82,67.21)

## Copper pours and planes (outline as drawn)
3V3_AON_S0 on TOP: 171.34,76.54 171.09,76.8 171.09,77.94 170.71,78.32 168.55,78.32 168.3,78.57 168.3,78.95 168.04,79.21 167.41,79.21 167.15,79.46 167.15,80.35 167.28,80.48 167.91,80.48 168.17,80.73 168.17,82.13 168.3,82.26 168.8,82.26 168.93,82.13 168.93,80.48 168.3,79.84 168.3,79.46 168.42,79.34 170.84,79.34 171.22,78.95 171.72,78.95 172.11,79.34 172.11,79.59 172.36,79.84 173.25,79.84 173.38,79.72 173.38,78.7 172.99,78.32 172.49,78.32 172.11,77.94 172.11,76.67 171.98,76.54 ; 3 cut-outs
3V3_AON_S0 on TOP: 183.28,72.1 181.5,73.87 181.5,75.02 181.63,75.14 182.14,75.14 183.66,73.62 184.3,73.62 184.68,73.24 187.98,73.24 188.23,72.99 188.23,72.35 188.11,72.22 186.96,72.22 186.84,72.35 184.93,72.35 184.68,72.1 ; 2 cut-outs
3V3_AON_S0 on BOTTOM: 177.19,70.32 176.93,70.57 176.93,73.11 177.06,73.24 178.2,73.24 178.33,73.11 178.33,72.73 177.82,72.22 177.82,70.45 177.69,70.32
3V3_AON_S0 on BOTTOM: 180.74,72.48 180.61,72.6 180.61,74.76 181.08,75.23 182.13,75.23 182.24,75.35 183.28,75.35 183.28,74.38 183.15,74.26 182.27,74.26 182.01,74 182.01,72.86 181.63,72.48
5V_HDD_SIP on TOP: 222.52,1.87 222.14,2.25 222.14,4.41 222.4,4.66 226.59,4.66 227.99,6.06 230.02,6.06 230.27,5.8 230.27,2.25 229.89,1.87 ; 2 cut-outs
5V_HDD_SIP on BOTTOM: 222.4,3.64 222.14,3.9 222.14,6.44 222.27,6.56 224.05,6.56 224.18,6.44 224.18,3.77 224.05,3.64
5V_HDMI_S5 on TOP: 10.43,75.65 10.18,75.91 10.18,77.56 11.83,79.21 11.83,79.72 12.72,80.61 16.28,80.61 16.35,80.53 16.35,79.23 16.23,79.11 15.69,79.11 15.46,79.34 13.74,79.34 11.32,76.92 11.32,75.91 11.07,75.65 ; 1 cut-out
5V_S0 on TOP: 13.86,81.11 12.21,82.76 12.21,84.03 12.97,84.8 14.12,84.8 14.37,84.54 14.37,83.4 14.74,83.03 15.2,83.03 15.31,82.92 15.31,82.46 15.51,82.26 15.51,81.24 15.39,81.11 ; 2 cut-outs
5V_S0 on TOP: 24.4,2.75 23.9,3.26 23.9,4.28 22.37,5.8 22.37,9.1 22.5,9.23 23.26,9.23 23.39,9.1 23.39,6.69 25.04,5.04 25.04,2.88 24.91,2.75 ; 1 cut-out
5V_S0 on TOP: 228.49,6.56 228.24,6.82 228.24,8.72 228.62,9.1 230.14,9.1 230.27,8.98 230.27,8.22 230.53,7.96 230.53,6.95 230.14,6.56 ; 1 cut-out
5V_S0 on TOP: 64.92,92.67 63.9,93.69 63.9,96.35 64.03,96.48 64.54,96.48 65.43,95.59 65.43,94.7 66.44,93.69 67.71,93.69 67.84,93.56 67.84,92.8 67.71,92.67 ; 1 cut-out
5V_S0 on BOTTOM: 199.79,42.51 199.66,42.63 199.66,44.16 199.41,44.41 199.41,46.44 200.93,46.44 201.19,46.19 201.19,45.05 201.06,44.92 201.06,42.76 200.81,42.51
5V_S0 on BOTTOM: 99.08,14.82 98.83,15.07 98.83,15.3 98.5,15.63 98.27,15.63 97.94,15.96 97.94,16.72 98.06,16.85 100.1,16.85 100.99,15.96 100.99,14.95 100.86,14.82
5V_S0 on BOTTOM: 63.14,90.89 63.01,91.02 63.01,94.45 64.28,95.72 65.93,95.72 66.95,94.7 67.08,94.7 67.33,94.45 67.33,91.27 66.95,90.89
5V_S0 on BOTTOM: 212.62,11.39 212.49,11.52 212.49,12.41 212.62,12.53 213.68,12.53 213.86,12.36 216.02,12.36 216.12,12.25 216.12,11.59 215.92,11.39
5V_S0 on BOTTOM: 27.45,1.54 27.41,1.57 24.44,1.57 24.15,1.87 24.15,8.57 24.16,8.58 24.16,8.74 24.53,9.1 26.18,9.1 26.46,8.83 29.59,8.83 30.5,7.91 30.5,5.07 30.88,4.69 31.64,4.69 32.02,4.3 32.02,1.99 31.57,1.54 ; 1 cut-out
5V_S0 on L2GND: 27.67,0.51 27.67,2.32 28.62,3.28 29.92,3.28 29.92,3.27 29.99,3.28 45.79,3.28 46.25,3.73 68.93,3.73 69.31,3.35 70.74,3.35 71.14,3.76 88.26,3.76 89.08,4.57 94.56,4.57 95.24,3.89 115.29,3.89 116.53,5.13 125.14,5.13 128.55,8.53 132.53,8.53 134.76,6.3 149.04,6.3 149.27,6.07 160.14,6.07 160.75,6.68 167.66,6.68 169.62,8.63 197.63,8.63 200.91,11.91 203.38,11.91 206.89,15.43 206.89,22.67 207.37,23.15 207.37,26.22 207.75,26.6 207.75,29.58 205.16,32.17 205.16,37.35 203.82,38.7 203.82,41.29 202.71,42.39 200.38,42.39 199.68,43.09 199.68,45.63 200.33,46.28 205.17,46.28 205.65,45.81 205.65,43.42 207.4,41.66 207.4,38.39 208.25,37.54 211.22,37.54 211.41,37.35 211.74,37.02 211.74,33.84 216,29.58 216.19,29.4 216.19,18.2 220.69,13.69 226.66,13.69 230.56,9.79 230.56,7.51 230.14,7.09 228.17,7.09 224.43,10.82 218.54,10.82 218.06,11.3 209.08,11.3 207.96,10.17 207.96,7.27 205.13,5.28 204.04,2 204.04,0.51
5V_S0 on L3: 199.79,46.7 204.87,46.7 205.89,45.68 207.54,45.68 208.43,44.79 208.43,41.87 207.67,41.11 205.38,41.11 204.87,41.62 203.6,41.62 202.59,42.63 200.93,42.63 199.54,44.03 199.54,46.44
5V_S0 on L6: 16.53,76.92 16.28,76.67 16.28,75.53 16.53,75.27 16.53,73.24 16.28,72.99 16.28,67.02 16.66,66.64 16.66,65.49 24.66,57.49 24.66,46.95 27.45,44.16 27.45,39.46 30.88,36.03 30.88,17.36 32.15,16.09 32.15,10.37 31.14,9.36 31.14,7.33 30.25,6.44 28.47,6.44 28.09,6.82 28.09,32.47 26.18,34.38 26.18,35.9 26.25,35.97 26.25,36.47 24.66,38.06 24.66,42.12 21.1,45.68 21.1,53.81 12.47,62.44 12.47,66.89 12.48,66.9 12.48,69.16 13.48,70.17 13.48,70.83 13.86,71.21 13.86,81.11 12.47,82.51 12.47,84.16 12.72,84.42 13.61,84.42 16.53,81.49
5V_S5 on TOP: 80.06,3.01 79.62,3.44 79.62,3.8 78.89,4.53 75.71,4.53 75.46,4.79 75.46,6.18 75.84,6.18 75.84,5.55 76.22,5.17 79.9,5.17 80.16,5.42 80.67,5.42 80.79,5.29 80.79,4.15 80.77,4.13 80.77,3.19 80.59,3.01 ; 2 cut-outs
5V_S5 on TOP: 197.89,49.11 197.51,49.49 197.51,52.67 197.63,52.79 201.06,52.79 201.32,52.54 201.32,51.01 201.7,50.63 201.7,49.36 201.44,49.11 ; 4 cut-outs
5V_S5 on TOP: 22.37,33.23 22.12,33.49 22.12,36.41 23.39,37.68 26.31,37.68 26.94,37.04 26.94,36.41 27.2,36.16 29.36,36.16 29.48,36.03 29.99,36.03 30.12,35.9 30.12,35.65 29.61,35.65 29.48,35.52 29.48,34.89 29.1,34.5 28.72,34.5 28.6,34.38 24.4,34.38 23.26,33.23 ; 6 cut-outs
5V_S5 on BOTTOM: 199.54,47.59 199.41,47.71 199.41,48.35 199.54,48.47 199.66,48.47 199.79,48.6 199.79,48.98 199.66,49.11 199.28,49.11 199.03,48.86 199.03,48.6 198.9,48.47 198.9,47.71 198.65,47.71 198.65,48.86 198.39,49.11 198.14,49.11 197.63,49.62 197.63,51.78 200.81,51.78 201.19,51.4 202.97,51.4 203.45,51.88 204.11,51.88 204.74,52.51 205.84,52.51 205.84,50.71 204.95,50.71 204.62,50.38 204.62,48.73 203.47,47.59
5V_S5 on BOTTOM: 20.85,40.98 20.72,41.11 20.72,41.87 22.5,41.87 22.75,41.62 22.75,41.11 22.63,40.98
5V_S5 on BOTTOM: 43.45,16.72 43.2,16.98 43.2,21.3 42.44,22.06 32.66,22.06 28.21,26.5 23.52,26.5 22.12,27.9 20.85,27.9 20.72,28.03 20.72,30.57 20.85,30.69 22.12,30.69 22.25,30.82 22.25,33.23 22.12,33.36 20.34,33.36 20.21,33.49 20.21,34.25 20.34,34.38 22.12,34.38 22.25,34.5 22.25,36.66 22.12,36.79 20.34,36.79 20.21,36.92 20.21,38.06 20.47,38.31 23.52,38.31 23.64,38.19 24.15,38.19 24.4,37.93 24.4,35.65 24.91,35.14 30.75,35.14 31.64,34.25 31.77,34.25 34.31,31.71 35.2,31.71 37.61,29.3 46.63,29.3 47.52,28.41 47.52,18.63 45.61,16.72 ; 6 cut-outs
5V_S5 on BOTTOM: 14.63,56.73 14.5,56.86 14.5,58.13 14.63,58.25 16.73,58.25 16.81,58.33 17.62,58.33 17.67,58.28 17.67,56.86 17.55,56.73 ; 2 cut-outs
5V_S5 on L2GND: outline of 98 points within 40.09,11.28 202.93,60.91
5V_S5 on L4: 15.51,58.51 19.32,58.51 22.25,55.59 22.25,42.25 22.88,41.62 22.88,41.24 22.37,40.73 16.53,40.73 16.28,40.47 15.9,40.47 15.13,41.24 15.13,58.13
5V_S5 on L6: 24.02,41.11 24.02,33.74 23.39,33.11 22.25,33.11 20.59,34.76 20.59,41.62 20.85,41.87 23.26,41.87
5V_VCONN_P1 on TOP: 33.55,34.76 33.42,34.89 33.42,35.52 33.29,35.65 31.64,35.65 31.64,36.92 31.9,37.17 33.93,37.17 34.69,36.41 34.69,34.89 34.56,34.76
20V_DCBATOUT on BOTTOM: 185.82,39.46 185.57,39.71 185.57,40.47 185.19,40.85 182.52,40.85 182.39,40.98 182.39,44.41 182.52,44.54 185.19,44.54 186.71,43.01 192.55,43.01 192.81,42.76 192.81,40.6 192.55,40.35 191.28,40.35 191.16,40.22 191.16,39.58 191.03,39.46
+5V_AVDD on TOP: 22.5,9.61 22.25,9.87 21.61,9.87 21.48,9.74 20.47,9.74 20.34,9.87 20.34,10.5 20.47,10.63 21.61,10.63 22.4,11.42 22.58,11.42 22.65,11.34 22.65,10.78 22.91,10.53 23.36,10.53 23.39,10.5 23.39,9.74 23.26,9.61 ; 1 cut-out
+5V_KB_BL on BOTTOM: 96.41,10.12 96.29,10.25 96.29,11.64 96.41,11.77 96.41,14.06 96.92,14.57 96.92,15.2 97.05,15.33 97.94,15.33 98.06,15.45 98.45,15.45 98.57,15.33 98.57,14.82 98.83,14.57 100.6,14.57 100.86,14.31 100.86,13.55 100.1,12.79 97.81,12.79 97.56,12.53 97.56,11.01 97.05,11.01 96.92,10.88 96.92,10.25 96.79,10.12 ; 1 cut-out
+5V_PVDD on BOTTOM: 22.88,5.55 22.75,5.68 22.75,9.36 22.79,9.4 22.79,11.17 23.26,11.64 23.26,12.15 24.02,12.91 26.18,12.91 26.44,12.66 26.44,11.64 26.56,11.52 26.56,10.88 26.31,10.63 25.67,10.63 24.91,11.39 24.4,11.39 24.28,11.26 24.28,9.49 23.9,9.1 23.9,5.68 23.77,5.55 ; 6 cut-outs
+V1.00A_SIP on TOP: 114.03,46.88 113.94,46.97 113.94,47.22 114.63,47.91 115.03,47.91 115.21,48.09 115.21,49.28 115.36,49.43 115.87,49.43 115.95,49.36 115.95,48.19 115.21,47.45 115.21,47.3 115.03,47.12 114.45,47.12 114.21,46.88
+V1.00A_SIP on TOP: 123.59,32.87 123.25,33.22 123.25,33.66 122.93,33.97 122.5,33.97 122.37,34.1 122.37,34.38 122.5,34.5 123.21,34.5 123.97,35.26 123.97,36.16 124.1,36.28 124.86,36.28 125.12,36.03 125.12,35.03 125.24,34.9 125.5,34.9 125.63,34.78 125.63,33 125.5,32.87 ; 1 cut-out
+V1.00A_SIP on L3: 114.07,47.59 113.81,47.33 113.81,46.82 114.32,46.32 114.32,45.68 115.46,44.54 115.46,44.16 115.84,43.78 120.67,43.78 121.18,44.28 121.18,46.7 120.92,46.95 116.23,46.95 115.59,47.59
+V1.00A_SIP on L6: 121.81,46.95 119.4,46.95 119.27,46.82 119.27,44.28 119.4,44.16 119.4,43.78 121.43,41.74 121.43,36.92 121.81,36.54 121.81,36.28 122.07,36.03 122.07,34.25 122.32,34 123.03,34 123.21,34.17 123.21,35.9 125.24,37.93 125.24,41.74 125.62,42.12 125.62,43.27 125.24,43.65 125.24,46.7 124.61,47.33 123.59,47.33 123.46,47.2 123.46,46.57 123.21,46.32 122.07,46.32 121.94,46.44 121.94,46.82
+V1.00U_CPU on BOTTOM: 112.16,8.22 111.53,8.85 111.53,9.23 111.65,9.36 112.16,9.36 112.29,9.49 112.29,10.76 113.05,10.76 113.43,11.14 114.07,11.14 114.19,11.01 114.19,9.74 113.69,9.23 113.69,8.47 113.43,8.22 ; 2 cut-outs
+V1.8A on TOP: 27.58,23.96 26.69,24.85 26.69,28.15 26.06,28.79 24.66,28.79 24.28,29.17 22.37,29.17 21.86,29.68 21.86,30.31 21.74,30.44 21.74,30.95 22.75,31.96 23.26,31.96 23.77,31.46 25.17,31.46 25.42,31.2 25.42,30.31 25.93,29.81 26.94,29.81 27.83,28.92 27.83,26.25 28.21,25.87 28.21,24.98 28.34,24.85 28.34,24.22 28.09,23.96 ; 6 cut-outs
+V1.8A on BOTTOM: 37.99,13.93 37.87,14.06 37.87,14.44 37.49,14.82 36.22,14.82 35.45,15.58 35.45,16.34 31.45,20.34 29.67,20.34 26.18,23.84 26.18,25.36 26.82,26 28.21,26 37.87,16.34 39.01,16.34 40.28,15.07 40.28,14.06 40.15,13.93
+V1.8A on BOTTOM: 16.53,53.43 16.4,53.55 16.4,54.7 16.53,54.82 18.05,54.82 18.31,54.57 18.31,53.55 18.18,53.43
+V1.8A on L6: 16.78,54.57 18.56,54.57 19.32,53.81 19.32,44.41 19.71,44.03 19.71,40.98 19.32,40.6 19.32,40.09 19.58,39.84 19.58,35.14 22.25,32.47 25.8,32.47 27.01,31.27 27.01,30 25.55,28.54 24.66,28.54 23.77,29.42 21.1,29.42 17.67,32.85 17.67,39.2 17.17,39.71 17.17,50.89 16.53,51.52 16.53,54.32
+V1.8A_SIP on TOP: 116.94,31.79 116.86,31.86 116.86,32.8 117.43,33.37 118.14,33.37 118.38,33.62 118.38,34.05 118.94,34.61 120.01,34.61 120.22,34.4 120.22,34.09 119.83,33.71 119.83,33.71 119.13,33.01 118.69,33.01 118.26,32.57 118.26,32.19 118.16,32.09 118.13,32.09 117.83,31.79 ; 2 cut-outs
+V1.8A_SIP on BOTTOM: 116.23,40.09 116.1,40.22 116.1,41.62 116.23,41.74 116.35,41.74 116.61,41.49 118,41.49 118.26,41.24 118.26,40.98 118,40.73 117.62,40.73 116.99,40.09
+V1.8A_SIP on L4: 117.37,42.89 118.26,42.89 118.77,42.38 118.77,37.68 118.38,37.3 118.38,36.54 120.16,34.76 120.16,34 119.91,33.74 118.89,33.74 116.99,35.65 116.99,40.19 116.56,40.63 116.56,41.29 116.63,41.36 116.86,41.36 116.99,41.49 116.99,42.51
+V3.3A_SIP on TOP: 111.81,35.74 111.65,35.9 111.65,36.54 111.78,36.66 112.67,36.66 113.3,37.3 115.34,37.3 116.23,38.19 116.23,38.57 116.2,38.59 116.2,39.99 115.91,40.29 115.91,41.17 115.34,41.74 115.34,42.63 114.45,43.52 114.45,44.66 114.83,44.66 114.96,44.54 115.47,44.54 115.72,44.79 115.72,45.83 115.98,46.09 115.98,46.83 115.9,46.92 115.9,47.53 116.05,47.68 116.28,47.68 116.41,47.55 116.41,46.36 116.56,46.21 116.97,46.21 117.14,46.04 117.14,45.65 117.06,45.57 116.86,45.57 116.61,45.32 116.61,43.92 116.86,43.67 119.15,43.67 119.53,43.29 119.53,43.03 119.78,42.78 120.17,42.78 120.29,42.65 120.29,42.27 120.17,42.14 119.78,42.14 119.69,42.05 119.68,42.05 119.63,42 119.63,41.52 119.53,41.41 118.49,41.41 118.36,41.54 118.36,42.56 118.21,42.71 117.75,42.71 117.75,42.27 117.63,42.14 117.63,40.75 117.6,40.72 117.6,39.18 116.53,38.11 116.53,37.62 116.36,37.44 115.95,37.44 115.76,37.25 115.76,37.24 115.57,37.05 115.57,36.38 114.93,35.74 ; 5 cut-outs
+V3.3A_SIP on L3: 118.64,43.01 121.69,43.01 121.81,42.89 121.81,42.38 121.56,42.12 118.64,42.12 118.38,42.38 118.38,42.76
+V3.3A_SIP on L6: 113.56,36.54 114.19,36.54 115.84,38.19 115.84,39.97 116.61,40.73 116.61,42 116.73,42.12 116.99,42.12 117.11,42.25 117.11,42.63 116.99,42.76 116.48,42.76 116.23,42.51 116.23,42.38 115.97,42.12 115.97,41.49 114.96,40.47 114.96,39.08 113.18,37.3 113.18,36.92
+VCCGT on TOP: 148.1,58.89 145.94,61.05 140.23,61.05 137.05,64.22 137.05,64.35 131.9,69.51 130.35,69.51 129.28,70.57 129.28,71.08 129.26,71.11 125.47,71.11 125.12,70.75 125.12,69.18 125.5,68.79 126.26,68.79 126.51,68.54 126.51,67.65 126.39,67.52 125.88,67.52 125.62,67.27 125.62,65.37 125.37,65.11 125.12,65.11 124.61,64.6 124.61,63.97 124.48,63.84 122.58,63.84 122.19,64.22 122.19,64.98 122.32,65.11 123.08,65.11 123.21,65.24 123.21,69.94 122.96,70.19 120.16,70.19 119.91,69.94 119.91,64.35 119.78,64.22 117.37,64.22 116.61,64.98 116.61,69.94 116.48,70.06 116.48,70.19 116.35,70.32 114.32,70.32 114.07,70.57 114.07,71.33 114.57,71.84 114.57,72.86 114.83,73.11 114.83,75.27 114.57,75.53 113.81,75.53 113.56,75.78 113.56,76.41 113.69,76.54 113.69,79.97 113.94,80.22 120.54,80.22 125.12,75.65 126.39,75.65 126.45,75.72 126.77,75.72 128.48,74 129.94,74 137.31,66.64 151.79,66.64 152.55,65.87 152.55,60.16 151.28,58.89 ; 40 cut-outs
+VCCGT on BOTTOM: 149.37,59.02 148.61,59.78 138.83,59.78 138.45,60.16 138.45,63.84 138.96,64.35 149.63,64.35 150.01,64.73 150.01,66 150.13,66.13 152.55,66.13 152.8,65.87 152.8,60.03 151.79,59.02 ; 19 cut-outs
+VCCGT on BOTTOM: 125.75,64.73 125.24,65.24 124.52,65.24 124.4,65.37 124.4,68.93 124.27,69.06 124.23,69.06 124.23,69.58 123.72,70.08 122.83,70.08 122.45,69.7 121.94,69.7 121.56,70.08 121.05,70.08 120.67,69.7 120.25,69.7 119.25,70.71 119.11,70.71 119.1,70.71 118.91,70.9 118.91,73.63 119.02,73.74 119.02,74.05 118.91,74.16 118.91,75.78 119.48,76.34 119.48,77.99 118.13,79.34 118.13,82.89 118.89,82.89 119.4,82.38 120.16,82.38 120.8,81.75 123.85,81.75 124.1,81.49 124.1,77.18 124.59,76.69 124.59,75.76 124.83,75.52 124.83,70.79 125.21,70.41 125.21,69.8 125.31,69.69 125.31,69.68 125.7,69.29 126.35,69.29 126.42,69.23 126.42,68.8 126.31,68.68 126.31,68.42 126.44,68.29 126.44,65.16 126,64.73 ; 8 cut-outs
+VCCGT on L2GND: 148.31,58.04 145.72,60.63 139.55,60.63 135.74,64.44 133.9,64.44 133.42,63.96 131.06,63.96 130.78,64.24 130.73,64.24 129.98,64.98 126.14,64.98 125.64,64.48 124.62,64.48 124.31,64.78 117.33,64.78 116.91,65.2 116.91,68.93 117.99,70.01 118.8,70.01 119.17,70.38 119.17,76.55 119.7,77.09 119.7,78.16 120.01,78.46 120.06,78.46 120.09,78.48 142.26,78.48 144.2,76.54 144.2,75.68 145.03,74.85 145.05,74.85 152.38,67.52 152.38,59.15 151.78,58.55 149.42,58.55 148.91,58.04 ; 2 cut-outs
+VCCGT on L3: 119.02,77.94 119.02,71.08 117.24,69.3 117.24,65.24 117.75,64.73 135.78,64.73 139.47,61.05 145.94,61.05 148.23,58.76 151.79,58.76 152.67,59.65 152.67,67.02 151.28,68.41 151.28,69.05 145.82,74.51 144.67,74.51 140.74,78.45 120.04,78.45 119.53,77.94
+VCCIO on TOP: 115.39,49.69 115.34,49.74 115.34,51.16 115.21,51.29 115.21,52.3 115.47,52.56 115.47,53.07 115.54,53.14 116.28,53.14 116.86,52.56 116.86,51.85 116.96,51.74 117.55,51.74 117.65,51.64 117.65,51.16 117.57,51.08 117.17,51.08 116.94,50.86 116.94,50.6 116.61,50.27 116.23,50.27 115.92,49.97 115.92,49.74 115.87,49.69 ; 3 cut-outs
+VCCIO on TOP: 133.37,60.41 132.86,60.92 129.31,60.92 128.8,61.43 128.54,61.43 128.16,61.05 126.64,61.05 126.26,61.43 126.26,61.94 125.88,62.32 125.88,62.83 126,62.95 126.51,62.95 127.02,62.44 128.8,62.44 129.69,61.56 133.62,61.56 134.26,60.92 134.26,60.54 134.13,60.41
+VCCIO on TOP: 73.05,10.88 72.54,11.39 72.54,13.68 73.05,14.18 78.13,14.18 78.63,14.69 78.63,20.03 82.44,23.84 82.7,23.84 83.33,23.2 83.33,19.14 81.94,17.74 81.94,11.64 81.17,10.88 ; 7 cut-outs
+VCCIO on BOTTOM: 116.35,50.25 115.58,51.03 114.4,51.03 114.24,51.19 114.24,52.23 114.42,52.41 115.05,52.41 115.71,53.07 116,53.07 116.26,53.32 116.26,57.56 115.92,57.89 114.86,57.89 114.22,58.53 114.22,58.66 114.35,58.78 114.73,58.78 115.22,58.3 115.52,58.3 115.92,58.7 116.56,58.7 116.76,58.5 116.76,51.8 116.74,51.77 116.74,51.27 116.73,51.27 116.73,50.38 116.61,50.25
+VCCIO on L2GND: 87.58,19.63 87.27,19.94 80.85,19.94 80.32,20.46 80.32,21.52 86.09,27.29 86.09,27.34 86.24,27.49 93.3,27.49 93.73,27.93 94.47,27.93 105.28,38.73 105.28,42.21 110.46,47.4 110.46,48.26 111.32,49.12 111.32,51.71 111.77,52.16 114.76,52.16 115.35,52.74 116.67,52.74 116.94,52.48 116.94,48.95 117.6,48.28 117.6,46.13 117.56,46.09 117.56,45.63 117.41,45.48 117.41,37.5 116.15,36.24 113.73,36.24 111.49,34 111.49,33.36 109.31,31.19 107.74,31.19 102.99,26.44 100.58,26.44 95.82,21.68 95.82,20.31 95.45,19.94 88.49,19.94 88.18,19.63
+VCCIO_SIP on TOP: 72.66,8.22 72.41,8.47 72.41,10.25 72.66,10.5 75.59,10.5 75.84,10.25 75.84,8.22 ; 2 cut-outs
+VCCPDSW_3P3 on L6: 110.88,41.24 110.88,41.48 111.78,42.38 115.21,42.38 115.21,42.51 115.46,42.76 115.97,42.76 116.1,42.63 116.1,42.38 115.59,41.87 115.59,41.49 115.08,40.98 111.14,40.98
+VCCPRIM_CORE on TOP: 102.41,10.88 100.86,12.43 100.86,15.84 99.72,16.98 99.08,16.98 98.32,17.74 98.32,22.82 99.54,24.04 100.25,24.04 100.86,23.43 100.86,23.07 103.65,20.28 103.65,11.14 103.4,10.88
+VCCPRIM_CORE on BOTTOM: 97.81,17.99 97.68,18.12 97.68,22.82 98.45,23.58 98.83,23.58 99.33,24.09 100.35,24.09 100.73,23.71 100.73,23.07 99.21,21.55 99.21,18.63 98.57,17.99 ; 7 cut-outs
+VCCPRIM_CORE on L2GND: 97.58,18.44 96.2,19.83 96.2,21.52 100.73,26.06 103.15,26.06 107.9,30.81 109.47,30.81 111.87,33.21 111.87,33.84 113.89,35.86 116.3,35.86 117.79,37.35 117.79,45.32 117.94,45.47 117.94,46.09 117.9,46.13 117.9,47.73 118.09,47.92 120.86,47.92 121,47.78 121,47.09 121.32,46.77 121.32,46.72 122.14,45.9 123.41,45.9 124.16,45.14 124.16,44.13 125.05,43.24 125.05,35.33 121.78,35.33 120.53,34.08 120.53,32.6 118.37,30.44 118.37,26.38 111.17,19.18 102.91,19.18 102.18,18.44
+VCCSA on TOP: 142.64,30.19 137.05,35.77 137.05,46.44 135.66,47.84 131.59,47.84 130.17,49.26 128.16,49.26 128.16,49.62 127.91,49.87 126.62,49.87 126,49.26 117.12,49.26 116.48,48.62 116.36,48.62 116.1,48.87 116.1,49.76 116.36,50.02 116.74,50.02 117.12,50.4 117.12,50.58 117.37,50.83 117.93,50.83 118,50.9 118,50.89 123.83,50.89 123.84,50.9 124.49,50.9 125.51,51.92 125.62,51.92 126.49,52.79 126.51,52.79 126.77,53.05 127.53,53.05 127.78,53.3 129.96,53.3 131.34,51.92 138.94,51.92 141.31,49.55 141.31,39.14 145.18,35.27 149.5,35.27 150.77,34 150.77,30.44 150.52,30.19 ; 8 cut-outs
+VCCSA on BOTTOM: 116,48.24 116,48.24 115.37,48.24 115.24,48.37 115.24,49.64 115.62,50.02 116.35,50.02 116.48,49.89 116.48,48.37 116.36,48.24
+VCCSA on BOTTOM: 148.86,27.9 148.36,28.41 146.71,28.41 145.56,29.55 145.56,33.23 145.94,33.62 153.18,33.62 153.31,33.49 153.31,28.92 152.8,28.41 150.01,28.41 149.5,27.9 ; 10 cut-outs
+VCCSA on BOTTOM: 125.6,47.96 125.21,48.35 124.89,48.35 124.63,48.61 124.63,49.05 124.68,49.11 124.68,51.19 125.52,52.04 125.52,52.23 125.62,52.33 125.83,52.33 125.93,52.23 125.93,51.62 126.08,51.48 126.78,51.48 126.88,51.38 126.88,51.38 126.88,51.17 126.69,50.97 126.69,50.64 126.89,50.44 126.89,50.24 126.69,50.05 126.69,49.71 126.88,49.52 126.88,49.34 126.68,49.13 126.68,48.81 126.87,48.63 126.87,48.4 126.6,48.13 126.6,48.06 126.49,47.96
+VCCSA on L3: 116.99,50.89 116.99,50.51 116.61,50.13 115.97,50.13 115.84,50 115.84,49.62 116.1,49.36 123.21,49.36 124.1,48.47 125.37,48.47 126.77,47.08 130.32,47.08 132.74,49.49 135.4,49.49 136.04,50.13 136.04,50.51 134.64,51.9 125.5,51.9 124.73,51.14 117.24,51.14
+VCCSFR on L3: 125.75,45.05 128.67,45.05 129.05,44.66 129.05,43.78 128.93,43.65 126,43.65 125.62,44.03 125.62,44.92
+VDDQ_CPU_CLK on L4: 112.21,58.6 114.12,58.6 114.4,58.32 114.4,57.71 114.2,57.51 111.35,57.51 111.2,57.66 111.2,58.17 111.66,58.63 112.19,58.63
GND on TOP: 229.76,18.76 229.51,19.01 229.51,23.33 229.64,23.46 231.16,23.46 231.29,23.33 231.29,18.88 231.16,18.76 ; 7 cut-outs
GND on TOP: 189.38,2.88 188.87,3.39 188.87,9.23 187.73,10.37 187.73,19.01 187.98,19.26 187.98,22.82 187.47,23.33 182.01,23.33 181.76,23.58 181.76,24.85 182.27,25.36 199.79,25.36 201.19,23.96 201.19,16.98 200.55,16.34 198.01,16.34 197.76,16.09 197.76,15.2 198.14,14.82 202.59,14.82 202.84,14.57 202.84,13.42 199.79,10.37 196.62,10.37 195.35,11.64 195.35,17.99 194.84,18.5 192.68,18.5 192.04,17.87 192.04,16.85 192.55,16.34 194.46,16.34 194.71,16.09 194.71,11.9 194.2,11.39 193.19,11.39 193.06,11.26 193.06,10.76 192.93,10.63 192.93,4.53 192.68,4.28 191.54,4.28 191.41,4.15 191.41,3.52 190.77,2.88 ; 2 cut-outs
GND on TOP: 188.74,105.37 188.49,105.62 188.49,108.8 188.23,109.05 188.11,109.05 188.11,109.31 188.23,109.43 188.74,109.43 188.87,109.56 188.87,110.45 188.74,110.58 187.35,110.58 187.22,110.7 187.22,112.1 187.09,112.23 186.58,112.23 186.46,112.36 186.46,112.74 186.58,112.86 188.11,112.86 188.49,112.48 191.92,112.48 193.57,110.83 193.57,107.28 189.5,107.28 189.38,107.15 189.38,105.62 189.12,105.37 ; 13 cut-outs
GND on TOP: 165.5,110.96 165.37,111.09 165.37,114.26 165.5,114.39 165.5,115.78 165.37,115.91 165.37,119.09 162.83,121.63 159.91,121.63 159.66,121.88 159.66,122.39 159.91,122.64 160.93,122.64 161.18,122.9 163.85,122.9 164.61,122.13 166.39,122.13 168.42,120.1 168.42,119.47 168.93,118.96 169.44,118.96 169.95,118.45 169.95,115.78 169.82,115.66 169.06,115.66 168.93,115.53 168.93,113.24 168.8,113.12 168.8,111.72 168.93,111.59 168.93,111.34 168.8,111.21 168.17,111.21 168.04,111.34 167.15,111.34 166.77,110.96 ; 19 cut-outs
GND on TOP: 202.59,70.32 202.33,70.57 202.33,74.26 202.71,74.64 203.6,74.64 203.86,74.38 203.86,70.7 203.47,70.32 ; 4 cut-outs
GND on TOP: 120.29,64.22 120.16,64.35 120.16,69.94 120.29,70.06 122.96,70.06 123.08,69.94 123.08,65.37 122.96,65.24 122.19,65.24 122.07,65.11 122.07,64.35 121.94,64.22 ; 8 cut-outs
GND on TOP: 133.5,104.48 133.37,104.61 133.37,104.99 133.12,105.24 132.74,105.24 132.35,105.62 132.35,106.39 132.23,106.51 131.47,106.51 131.21,106.77 131.21,110.83 131.34,110.96 132.23,110.96 132.35,111.09 132.35,112.36 132.48,112.48 135.66,112.48 136.16,111.97 136.67,111.97 136.93,111.72 136.93,107.53 136.8,107.4 135.91,107.4 135.78,107.28 135.78,105.37 135.53,105.12 134.64,105.12 134.64,104.61 134.51,104.48 ; 1 cut-out
GND on TOP: 121.56,105.88 121.33,106.11 121.33,112.76 121.56,112.99 122.19,112.99 122.77,112.42 122.77,106.2 122.45,105.88 ; 2 cut-outs
GND on TOP: 49.17,39.46 49.04,39.58 49.04,40.22 50.19,40.22 50.44,39.97 50.44,39.58 50.31,39.46
GND on TOP: 63.65,42.12 63.52,42.25 63.52,42.51 63.27,42.76 61.87,42.76 61.62,43.01 61.62,43.65 61.74,43.78 62.12,43.78 62.5,43.39 63.52,43.39 64.16,42.76 64.16,42.25 64.03,42.12
GND on TOP: 141.75,39.46 141.5,39.71 141.5,50 140.1,51.4 140.1,51.78 140.23,51.9 143.17,51.9 143.19,51.89 143.64,51.89 143.73,51.8 143.73,51.22 143.66,51.14 143.66,39.84 143.28,39.46 ; 13 cut-outs
GND on TOP: 64.66,16.85 63.14,18.38 59.96,18.38 59.84,18.5 59.84,19.14 59.96,19.26 64.66,19.26 66.19,17.74 66.19,16.98 66.06,16.85 ; 4 cut-outs
GND on TOP: 54.76,4.91 54.63,5.04 54.63,6.69 52.85,8.47 51.46,8.47 50.95,8.98 50.95,9.74 51.07,9.87 55.14,9.87 55.52,9.49 55.52,8.85 55.14,8.47 55.14,4.91 ; 2 cut-outs
GND on TOP: 12.72,88.73 12.59,88.86 12.59,90 12.34,90.26 10.82,90.26 10.69,90.38 8.53,90.38 8.4,90.26 8.15,90.26 7.77,90.64 7.77,92.16 7.89,92.29 8.53,92.29 8.66,92.16 8.66,91.27 8.91,91.02 10.56,91.02 10.69,90.89 12.47,90.89 12.72,91.15 13.1,91.15 13.36,90.89 13.36,90 13.23,89.88 13.23,88.99 12.97,88.73
GND on TOP: 111.91,71.59 111.27,72.22 111.27,76.54 111.65,76.92 113.18,76.92 113.43,76.67 113.43,75.65 113.69,75.4 114.57,75.4 114.7,75.27 114.7,73.11 114.45,72.86 114.45,71.84 114.19,71.59 ; 3 cut-outs
GND on TOP: 164.94,74.1 164.87,74.18 164.87,74.56 164.79,74.64 162.45,74.64 162.45,75.02 162.58,75.14 163.85,75.14 163.98,75.27 163.98,75.53 164.23,75.78 164.49,75.78 164.61,75.65 164.61,75.27 164.74,75.14 165.5,75.14 165.5,76.29 164.74,77.05 162.45,77.05 161.95,76.54 161.95,75.91 162.07,75.78 162.07,75.02 161.95,74.89 161.06,74.89 160.93,75.02 160.93,77.05 160.42,77.56 160.42,78.32 160.55,78.45 164.99,78.45 165.25,78.7 165.25,79.59 165.37,79.72 166.01,79.72 166.14,79.59 166.14,75.53 166.82,74.84 166.82,74.43 166.72,74.33 166.24,74.33 166.21,74.36 166.09,74.36 165.83,74.1 ; 12 cut-outs
GND on TOP: 38.88,33.49 38.76,33.62 38.76,36.54 38.88,36.66 42.18,36.66 42.82,36.03 42.82,34.63 41.04,34.63 40.79,34.89 39.9,34.89 39.9,33.62 39.77,33.49 ; 4 cut-outs
GND on TOP: 182.9,78.95 179.73,82.13 179.73,87.34 185.44,93.05 188.62,93.05 189,92.67 189,85.81 189.89,84.92 189.89,80.61 188.74,79.46 184.68,79.46 184.17,78.95
GND on TOP: 73.05,24.98 72.66,25.36 72.66,43.01 71.9,43.78 70.89,43.78 70.76,43.65 69.87,43.65 69.87,44.28 70.89,44.28 71.14,44.54 71.14,45.33 70.38,46.09 70.38,48.98 77.11,48.98 79.4,51.27 89.43,51.27 93.24,55.08 96.03,55.08 97.18,53.94 97.68,53.94 97.81,53.81 97.81,49.36 97.68,49.24 92.86,49.24 85.36,41.74 85.36,28.41 83.84,26.88 75.59,26.88 75.33,26.63 75.33,25.36 74.95,24.98 ; 23 cut-outs
GND on TOP: 126.41,73 126.04,73.37 124.74,73.37 124.73,73.37 124.61,73.37 124.51,73.47 124.51,74 124.76,74.26 126.51,74.26 126.77,74 126.77,73.2 126.57,73
GND on TOP: 160.42,37.17 160.04,37.55 160.04,42 159.91,42.12 159.91,42.76 159.79,42.89 159.15,42.89 159.02,43.01 159.02,44.16 159.41,44.54 163.47,44.54 163.6,44.66 163.6,45.93 163.22,46.32 160.17,46.32 159.53,46.95 159.15,46.95 159.02,47.08 159.02,47.46 159.15,47.59 159.79,47.59 159.91,47.71 159.91,50.38 159.53,50.76 158.26,50.76 154.33,54.7 154.33,57.62 154.58,57.87 157.5,57.87 158.52,58.89 158.52,64.6 159.15,65.24 164.74,65.24 166.9,63.08 166.9,56.6 165.5,55.21 164.87,55.21 164.36,54.7 164.36,52.67 164.61,52.41 168.3,52.41 168.55,52.16 168.55,51.9 168.3,51.65 167.41,51.65 167.15,51.4 167.15,48.35 166.39,47.59 166.39,45.05 166.9,44.54 166.9,43.78 166.52,43.39 166.52,41.24 167.15,40.6 167.15,39.33 164.99,37.17 ; 9 cut-outs
GND on TOP: 115.72,96.99 115.46,97.24 115.46,97.62 115.72,97.88 115.72,99.27 115.84,99.4 116.73,99.4 116.99,99.15 120.54,99.15 120.8,98.89 120.8,97.24 120.54,96.99 120.04,96.99 119.78,97.24 119.78,97.88 119.53,98.13 118.51,98.13 118.38,98 118.38,97.24 118.13,96.99 ; 6 cut-outs
GND on TOP: 126.26,33.62 126.13,33.74 126.13,35.38 126.13,35.39 126.13,36.17 126.24,36.28 126.26,36.28 126.77,36.79 127.69,36.79 127.94,37.04 128.54,37.04 128.67,36.92 128.67,34.5 128.42,34.25 127.66,34.25 127.02,33.62 ; 3 cut-outs
GND on TOP: 108.73,96.61 108.61,96.73 108.61,98.13 108.86,98.39 108.86,100.29 109.62,101.05 111.65,101.05 111.78,100.93 111.78,96.61 ; 1 cut-out
GND on TOP: 88.79,99.53 88.29,100.04 85.75,100.04 85.49,100.29 85.49,100.67 85.75,100.93 91.97,100.93 92.1,100.8 92.1,99.66 91.97,99.53 ; 2 cut-outs
GND on TOP: 74.18,54.86 73.54,55.49 73.54,56.38 73.93,56.76 81.8,56.76 82.05,56.51 82.05,55.75 81.16,54.86 ; 5 cut-outs
GND on TOP: 44.6,18.76 43.71,19.65 43.71,20.66 44.98,21.93 49.93,21.93 50.19,21.68 50.19,21.42 49.93,21.17 45.87,21.17 45.49,20.79 45.49,18.88 45.36,18.76 ; 2 cut-outs
GND on TOP: 24.28,84.29 24.15,84.42 24.15,85.81 24.28,85.94 26.18,85.94 26.31,85.81 26.31,84.54 26.06,84.29 ; 2 cut-outs
GND on TOP: 25.04,61.3 24.79,61.56 24.79,64.1 25.29,64.6 26.06,64.6 26.18,64.48 26.18,61.81 25.67,61.3 ; 2 cut-outs
GND on TOP: 207.06,55.97 206.93,56.09 206.14,56.09 205.89,56.35 204.74,56.35 204.49,56.6 204.49,59.14 202.97,60.67 202.97,64.1 203.09,64.22 203.47,64.22 203.6,64.1 203.6,63.08 203.98,62.7 208.17,62.7 209.57,64.1 211.98,64.1 212.11,63.97 212.11,63.08 211.73,62.7 209.82,62.7 209.57,62.44 209.57,61.3 209.52,61.25 206.34,61.25 205.25,60.16 205.25,56.98 205.38,56.86 206.14,56.86 206.4,56.6 206.93,56.6 207.03,56.5 207.46,56.5 207.51,56.45 207.51,56.02 207.46,55.97 ; 2 cut-outs
GND on TOP: 32.79,60.67 31.64,61.81 31.64,62.19 31.9,62.44 32.53,62.44 32.79,62.7 32.79,64.48 32.91,64.6 33.68,64.6 33.8,64.48 33.8,60.92 33.55,60.67 ; 4 cut-outs
GND on TOP: 30.37,62.19 30.25,62.32 30.25,64.48 30.37,64.6 31.14,64.6 31.26,64.48 31.26,62.44 31.01,62.19 ; 2 cut-outs
GND on TOP: 27.71,62.19 27.71,64.48 27.83,64.6 28.6,64.6 28.72,64.48 28.72,62.32 28.6,62.19 ; 2 cut-outs
GND on TOP: 148.23,26.38 148.1,26.5 148.1,27.14 147.98,27.27 147.47,27.27 147.34,27.39 147.34,27.9 147.47,28.03 149.5,28.03 149.63,27.9 149.63,27.39 149.37,27.14 148.99,27.14 148.86,27.01 148.86,26.5 148.74,26.38
GND on TOP: 30.37,35.01 30.37,36.03 30.25,36.16 29.61,36.16 29.48,36.28 27.33,36.28 27.2,36.41 27.2,37.3 27.45,37.55 31.14,37.55 31.39,37.3 31.39,35.01 ; 3 cut-outs
GND on TOP: 116.86,58.89 116.35,59.4 116.35,61.68 116.48,61.81 122.32,61.81 122.58,61.56 122.58,59.02 122.45,58.89 ; 8 cut-outs
GND on TOP: 39.26,30.19 39.01,30.44 39.01,31.46 39.64,32.09 39.64,32.98 39.77,33.11 40.41,33.11 40.53,32.98 40.53,31.33 40.66,31.2 41.17,31.2 41.3,31.08 41.3,30.31 41.17,30.19
GND on TOP: 115.34,64.98 114.57,65.75 114.57,67.4 114.32,67.65 114.07,67.65 113.81,67.91 113.81,69.68 114.32,70.19 116.1,70.19 116.48,69.81 116.48,65.11 116.35,64.98 ; 4 cut-outs
GND on TOP: 81.17,65.62 78.38,68.41 78.38,84.49 80.72,86.83 109.62,86.83 109.75,86.7 111.02,86.7 115.34,82.38 115.34,81.24 114.57,80.48 110,80.48 108.35,78.83 103.4,78.83 101.37,80.86 99.33,80.86 97.68,79.21 97.68,72.1 99.33,70.45 99.33,66.38 98.57,65.62 ; 10 cut-outs
GND on TOP: 121.66,34.61 121.61,34.66 121.61,35.22 121.51,35.32 121.51,36.61 121.69,36.79 121.79,36.79 121.97,36.97 121.97,37.32 122.12,37.48 122.4,37.48 122.58,37.3 122.58,36.79 122.7,36.66 122.7,34.76 122.55,34.61 ; 1 cut-out
GND on TOP: 70,17.99 69.87,18.12 69.87,21.17 69.74,21.3 66.95,21.3 66.82,21.42 66.82,21.68 66.57,21.93 63.27,21.93 63.14,21.8 63.14,21.17 59.08,21.17 58.31,20.41 58.31,19.26 57.3,18.25 57.04,18.25 56.92,18.38 56.92,21.04 56.66,21.3 53.87,21.3 53.87,23.46 54.25,23.84 70.76,23.84 70.89,23.71 70.89,18.25 70.63,17.99 ; 24 cut-outs
GND on TOP: 158.26,78.57 157.25,79.59 157.25,80.21 157.26,80.22 157.26,80.83 157.57,81.13 166.54,81.13 166.69,81.28 166.99,81.28 167.27,81.56 167.27,82.4 167.25,82.43 157.31,82.43 157.31,82.43 157.17,82.43 157.04,82.56 157.04,83.12 157.26,83.34 167.65,83.34 167.96,83.04 167.96,80.95 167.7,80.7 167.32,80.7 167.09,80.47 167.09,80.07 167.02,79.99 166.48,79.99 166.47,79.97 165.25,79.97 164.87,80.35 164.61,80.35 164.23,79.97 163.34,79.97 162.96,80.35 162.58,80.35 162.2,79.97 161.44,79.97 161.06,80.35 160.55,80.35 160.29,80.1 160.29,78.7 160.17,78.57 ; 12 cut-outs
GND on TOP: 94.13,94.58 93.62,95.08 93.62,95.46 92.73,96.35 92.73,96.91 101.11,96.91 102.07,97.88 104.16,97.88 104.29,97.75 104.29,94.83 104.03,94.58
GND on TOP: 47.39,41.36 46.88,41.87 46.88,42.12 47.01,42.25 47.52,42.25 47.77,42 48.28,42 48.41,41.87 48.41,41.36
GND on TOP: 157.34,84.79 157.19,84.94 157.19,85.53 157.31,85.65 167.09,85.65 167.17,85.73 167.18,85.73 167.18,85.97 166.49,86.65 166.49,87.03 166.67,87.21 166.9,87.21 167.89,86.22 167.89,85.71 167.88,85.7 167.88,85.22 167.45,84.79
GND on TOP: 219.35,33.11 219.22,33.23 219.22,34.89 220.24,35.9 220.24,36.79 220.49,37.04 221.76,37.04 221.89,36.92 221.89,35.01 221.13,34.25 221.13,33.23 221,33.11 ; 7 cut-outs
GND on TOP: 76.09,8.22 75.97,8.34 75.97,10.5 76.09,10.63 82.7,10.63 82.82,10.5 82.82,9.74 81.68,8.6 80.67,8.6 79.9,9.36 78.76,9.36 77.62,8.22 ; 8 cut-outs
GND on TOP: outline of 440 points within 0.51,0.51 232.29,126.29 ; 54 cut-outs
GND on TOP: 122.32,42.25 122.07,42.51 122.07,43.65 123.46,43.65 123.46,42.38 123.34,42.25 ; 1 cut-out
GND on TOP: 47.01,43.65 47.01,44.41 46.76,44.66 46.5,44.66 46.25,44.92 46.25,45.43 46.5,45.68 47.77,45.68 47.9,45.55 47.9,44.41 48.03,44.28 48.28,44.28 48.41,44.16 48.41,43.78 48.28,43.65
GND on TOP: 115.84,32.98 115.34,33.49 115.34,34.38 115.21,34.5 114.57,34.5 114.19,34.12 113.94,34.12 113.69,34.38 113.69,34.5 114.07,34.89 114.07,35.52 114.19,35.65 115.08,35.65 115.59,35.14 116.61,35.14 116.73,35.27 116.99,35.27 117.04,35.21 118.08,35.21 118.23,35.06 118.23,33.7 118.13,33.6 117.62,33.6 117.01,32.98 ; 2 cut-outs
GND on TOP: 114.83,44.66 114.45,45.05 114.45,46.59 114.58,46.72 115.34,46.72 115.47,46.84 115.72,46.84 115.85,46.72 115.85,46.33 115.47,45.95 115.47,44.66 ; 2 cut-outs
GND on TOP: 165.5,100.93 165.37,101.05 165.37,108.93 165.63,109.18 167.03,109.18 167.41,109.56 168.8,109.56 168.93,109.43 168.93,101.31 168.55,100.93 ; 31 cut-outs
GND on TOP: 46.88,49.24 46.63,49.49 46.63,52.67 46.76,52.79 47.77,52.79 48.03,52.54 48.03,49.36 47.9,49.24 ; 2 cut-outs
GND on TOP: 120.79,43.78 120.5,44.07 119.4,44.07 119.23,43.9 116.89,43.9 116.81,43.97 116.81,45.22 116.94,45.34 117.42,45.34 117.5,45.27 117.5,44.66 117.6,44.56 118.36,44.56 118.56,44.76 118.56,46.31 118.39,46.49 117.96,46.49 117.07,47.38 117.07,48.6 117.55,49.08 126.1,49.08 126.51,49.49 126.89,49.49 126.97,49.41 126.97,48.44 127.12,48.29 127.12,47.88 127.08,47.84 126.89,47.84 126.64,48.09 124.9,48.09 124.62,47.82 123.32,47.82 122.62,47.12 121.38,47.12 121.13,47.38 121.13,47.73 120.9,47.96 120.62,47.96 120.47,47.81 120.47,47.25 120.72,47 120.72,46.33 120.52,46.13 120.29,46.13 120.11,45.95 120.11,45.34 120.55,44.91 121.61,44.91 121.69,44.84 121.69,43.9 121.56,43.78 ; 17 cut-outs
GND on TOP: 150.26,92.8 148.86,94.19 145.56,94.19 141.5,98.26 141.5,102.96 144.55,106.01 144.55,110.96 144.67,111.09 145.31,111.09 145.56,110.83 145.56,104.74 146.45,103.85 149.37,103.85 151.4,101.81 151.4,92.92 151.28,92.8
GND on TOP: 114.55,48.06 114.5,48.11 114.5,48.27 113.89,48.87 113.89,49.69 113.82,49.76 113.82,50.91 113.18,51.54 113.18,53.7 113.43,53.95 113.54,53.95 113.76,53.73 113.76,53.4 113.94,53.22 114.42,53.22 114.73,53.52 114.73,54.62 114.75,54.62 114.8,54.67 115.29,54.67 115.39,54.57 124.71,54.57 125.19,54.09 125.62,54.09 125.8,54.27 125.8,54.62 126.13,54.95 126.89,54.95 127.02,54.82 127.02,54.06 126.64,53.68 126.64,53.19 126.39,52.94 125.14,52.94 124.49,52.28 124.33,52.28 124.3,52.31 124,52.31 123.99,52.3 118.39,52.3 118.08,52 117.09,52 117.02,52.08 117.02,53.24 116.94,53.32 115.39,53.32 115.24,53.17 115.24,52.61 115.09,52.46 115.09,48.14 115.01,48.06 ; 18 cut-outs
GND on TOP: 28.85,52.41 27.71,53.55 27.71,61.05 27.83,61.17 28.34,61.17 28.47,61.05 28.47,59.65 28.85,59.27 30.25,59.27 30.5,59.02 30.5,58.76 30.37,58.63 29.99,58.63 29.87,58.51 29.87,57.36 30.37,56.86 30.37,56.6 30.12,56.35 29.87,56.35 29.61,56.09 29.61,55.08 29.74,54.95 29.99,54.95 30.25,54.7 30.25,52.79 29.87,52.41
GND on BOTTOM: 120.67,8.6 120.29,8.98 120.29,10.25 120.54,10.5 125.75,10.5 126.26,9.99 126.26,8.72 126.13,8.6
GND on BOTTOM: 219.35,3.77 219.1,4.02 219.1,6.69 219.22,6.82 220.87,6.82 221,6.69 221,3.9 220.87,3.77
GND on BOTTOM: 118.38,69.68 118,70.06 118,70.19 118.03,70.22 118.03,70.98 118.01,71 118.01,74.25 118.11,74.35 118.59,74.35 118.77,74.17 118.77,71.15 118.77,71.15 118.77,70.83 118.89,70.7 118.89,69.81 118.77,69.68
GND on BOTTOM: 160.29,37.55 159.91,37.93 159.91,44.54 161.69,44.54 161.82,44.66 161.82,45.05 161.56,45.3 160.68,45.3 160.42,45.55 160.17,45.55 159.91,45.81 159.91,52.03 160.29,52.41 168.3,52.41 168.55,52.16 168.55,50.51 168.3,50.25 162.33,50.25 162.2,50.13 162.2,46.06 162.33,45.93 162.33,44.79 162.58,44.54 162.96,44.54 163.22,44.79 163.22,45.43 163.34,45.55 163.85,45.55 163.98,45.43 163.98,44.66 164.1,44.54 167.28,44.54 167.41,44.66 167.41,45.05 166.77,45.68 166.77,46.7 166.9,46.82 168.42,46.82 168.8,46.44 168.8,42.25 168.68,42.12 166.77,42.12 166.64,42 162.45,42 162.2,41.74 162.2,37.68 162.07,37.55
GND on BOTTOM: 40.03,94.32 40.03,98 40.15,98.13 41.3,98.13 41.68,97.75 41.8,97.75 42.06,97.5 42.06,94.7 41.68,94.32
GND on BOTTOM: 103.53,20.92 102.13,22.31 102.13,27.52 104.67,30.06 108.22,30.06 110.89,27.39 110.89,21.17 110.64,20.92
GND on BOTTOM: 189.38,102.07 189,102.45 189,110.83 189.38,111.21 192.43,111.21 193.57,110.07 193.57,102.32 193.31,102.07
GND on BOTTOM: 146.07,26.38 143.34,29.11 143.34,33.04 142.51,33.87 142.51,35.9 142.26,36.16 141.63,36.16 140.1,37.68 140.1,51.65 140.48,52.03 143.4,52.03 143.53,51.9 143.53,39.2 143.66,39.08 145.18,39.08 146.2,40.09 148.61,40.09 150.26,38.44 150.26,35.39 150.52,35.14 150.52,34.12 150.26,33.87 145.94,33.87 145.18,33.11 145.18,29.42 147.34,27.27 147.34,26.5 147.21,26.38 ; 26 cut-outs
GND on BOTTOM: 190.55,56.6 190.44,56.7 190.44,59.19 190.52,59.27 190.52,59.78 190.39,59.9 190.14,59.9 189.89,60.16 189.89,60.54 190.01,60.67 190.39,60.67 190.65,60.92 190.65,61.3 190.77,61.43 191.03,61.43 191.28,61.17 191.28,59.35 191.16,59.22 191.16,58.03 191.26,57.92 191.49,57.92 191.66,57.75 191.66,56.73 191.54,56.6
GND on BOTTOM: 191.41,27.52 190.9,28.03 190.9,31.33 191.79,32.22 193.19,32.22 193.44,31.96 193.44,27.77 193.19,27.52
GND on BOTTOM: 194.46,95.34 194.2,95.59 194.2,99.91 194.46,100.16 195.98,100.16 196.49,99.66 196.49,95.72 196.11,95.34 ; 5 cut-outs
GND on BOTTOM: 96.03,14.06 95.91,14.18 95.91,22.95 96.16,23.2 97.3,23.2 97.56,22.95 97.56,15.58 97.43,15.45 96.92,15.45 96.67,15.2 96.67,14.44 96.29,14.06 ; 8 cut-outs
GND on BOTTOM: 118,1.48 117.75,1.74 117.75,4.02 123.46,4.02 123.59,3.9 123.59,1.74 123.65,1.68 123.46,1.48 ; 2 cut-outs
GND on BOTTOM: 164.66,78.77 164.54,78.89 164.54,79.15 167.01,81.62 167.01,82.12 166.86,82.27 166.52,82.27 163.44,79.19 163.14,79.19 162.97,79.36 162.97,79.62 167.03,83.68 167.03,84.1 166.88,84.25 166.46,84.25 161.44,79.22 161.14,79.22 160.98,79.37 160.98,79.53 166.92,85.47 166.92,86.21 166.39,86.21 159.33,79.15 159.2,79.15 158.95,79.4 158.95,79.53 166.63,87.21 166.9,87.21 167.03,87.08 167.03,86.77 167.2,86.59 167.2,80.92 165.04,78.77
GND on BOTTOM: 109.21,96.05 109.21,96.99 108.61,97.6 108.61,97.88 108.68,97.95 110.81,97.95 110.89,97.88 110.89,97.42 110.48,97.01 110.48,96.07 110.46,96.05
GND on BOTTOM: 202.08,52.67 201.7,53.05 201.7,59.02 201.82,59.14 203.98,59.14 204.24,58.89 204.24,52.92 203.98,52.67
GND on BOTTOM: 178.4,73.54 178.33,73.62 178.33,74.89 178.46,75.02 179.6,75.02 179.85,75.27 179.85,76.54 180.11,76.8 180.49,76.8 180.61,76.67 180.61,75.14 179.98,74.51 179.98,73.62 179.9,73.54
GND on BOTTOM: 75.71,17.23 75.33,17.61 75.33,18.76 75.08,19.01 72.03,19.01 71.39,19.65 71.39,23.84 71.78,24.22 71.78,42.89 72.28,43.39 72.28,48.09 73.68,49.49 73.68,51.65 71.27,54.06 71.27,83.27 71.39,83.4 82.57,72.22 82.57,24.73 80.28,22.44 80.28,17.61 79.9,17.23
GND on BOTTOM: 214.52,7.33 214.27,7.58 214.27,8.72 213.38,9.61 212.75,9.61 212.36,9.99 212.36,10.76 212.49,10.88 214.02,10.88 214.52,10.37 218.08,10.37 218.33,10.12 218.33,7.58 218.08,7.33
GND on BOTTOM: 113,44.73 112.42,45.32 112.42,45.85 112.49,45.93 113.18,45.93 113.28,45.83 113.28,45.65 113.15,45.52 113.15,45.14 113.33,44.96 113.33,44.81 113.26,44.73
GND on BOTTOM: 130.7,79.21 126,83.91 126,85.3 122.45,88.86 122.45,98.13 123.85,99.53 123.97,99.53 123.97,99.91 124.35,100.29 126,100.29 126.64,99.66 126.64,99.63 126.87,99.4 126.87,89.39 128.04,88.23 134.51,88.23 136.55,86.19 142.39,86.19 143.02,85.56 143.02,84.03 142.13,83.15 138.45,83.15 134.51,79.21 ; 2 cut-outs
GND on BOTTOM: 26.69,8.98 26.44,9.23 24.66,9.23 24.53,9.36 24.53,11.14 25.04,11.14 25.67,10.5 26.44,10.5 26.69,10.76 26.69,11.64 26.56,11.77 26.56,12.66 26.82,12.91 27.33,12.91 27.58,12.66 27.58,11.77 28.09,11.26 28.09,9.1 27.96,8.98 ; 4 cut-outs
GND on BOTTOM: 75.71,84.92 75.33,85.3 75.33,88.73 76.47,89.88 76.47,92.42 76.6,92.54 80.03,92.54 80.16,92.42 80.16,85.18 79.9,84.92
GND on BOTTOM: 47.77,11.26 47.65,11.39 47.65,13.04 47.52,13.17 47.52,14.31 47.65,14.44 48.28,14.44 48.41,14.31 48.41,13.17 49.17,12.41 49.42,12.41 49.93,11.9 49.93,11.39 49.8,11.26 ; 1 cut-out
GND on BOTTOM: 175.03,44.54 172.49,47.08 172.49,50.76 174.9,53.17 178.84,53.17 180.11,51.9 182.14,51.9 182.77,52.54 185.69,52.54 186.08,52.16 186.08,50.63 185.31,49.87 182.14,49.87 181.12,48.86 181.12,46.95 178.71,44.54
GND on BOTTOM: 119.69,36.64 119.69,36.65 119.69,37.39 119.73,37.43 119.73,38.44 119.49,38.68 119.32,38.68 119.32,39.09 119.42,39.19 119.89,39.19 119.91,39.2 120.04,39.2 120.37,38.87 120.37,38.15 120.8,37.72 120.8,37.41 120.1,36.71 120.1,36.64
GND on BOTTOM: 109.34,47.3 108.96,47.68 108.96,47.78 109.09,47.91 109.24,47.91 109.5,47.66 109.93,47.66 110.21,47.93 110.21,50.3 110.34,50.42 110.46,50.42 110.56,50.32 110.56,49.76 111.12,49.2 111.43,49.2 111.88,48.75 113.51,48.75 114.07,49.31 114.07,49.59 113.89,49.76 113.89,50.02 114.55,50.68 114.55,50.81 114.56,50.81 114.68,50.93 115.26,50.93 115.64,50.55 115.64,50.32 115.06,49.74 115.06,48.77 114.7,48.42 114.68,48.42 114.6,48.34 111.68,48.34 111.4,48.62 111.4,48.65 111.33,48.72 111.05,48.72 110.56,48.24 110.56,47.6 110.26,47.3
GND on BOTTOM: 104.16,14.18 104.03,14.31 104.03,14.95 103.53,15.45 103.53,17.61 104.29,17.61 104.41,17.49 104.41,16.98 104.54,16.85 105.18,16.85 105.3,16.98 105.94,16.98 106.19,16.72 106.19,15.96 105.56,15.33 105.56,14.31 105.43,14.18 ; 1 cut-out
GND on BOTTOM: 139.59,64.6 139.34,64.86 139.34,66.25 140.29,67.21 144.74,67.21 145.44,66.51 147.09,66.51 147.47,66.13 149.5,66.13 149.75,65.87 149.75,64.86 149.5,64.6 ; 14 cut-outs
GND on BOTTOM: 54.88,11.64 54.88,14.31 54.63,14.57 51.71,14.57 51.58,14.69 51.58,16.34 51.84,16.6 59.2,16.6 59.58,16.22 59.58,15.96 59.33,15.71 57.55,15.71 57.42,15.58 57.42,11.64 ; 1 cut-out
GND on BOTTOM: 168.04,24.85 165.37,27.52 164.36,27.52 163.72,28.15 163.72,29.17 163.49,29.4 161.97,29.4 161.95,29.42 161.95,31.58 162.07,31.71 167.28,31.71 167.41,31.58 167.41,30.69 167.66,30.44 168.17,30.44 168.55,30.82 169.44,30.82 169.57,30.69 169.57,29.3 169.69,29.17 170.2,29.17 170.33,29.04 170.33,28.66 170.71,28.28 170.71,25.11 170.45,24.85 ; 11 cut-outs
GND on BOTTOM: 103.27,3.9 102.64,4.53 101.37,4.53 100.35,5.55 96.54,5.55 96.03,5.04 93.24,5.04 92.73,5.55 92.73,7.33 93.62,8.22 104.54,8.22 104.67,8.09 104.67,7.71 104.8,7.58 104.92,7.58 105.05,7.45 105.05,4.02 104.92,3.9 ; 3 cut-outs
GND on BOTTOM: 145.56,81.75 145.44,81.88 145.44,84.67 145.82,85.05 148.61,85.05 148.86,84.8 148.86,83.91 148.61,83.65 146.71,83.65 146.58,83.53 146.58,82.13 146.2,81.75 ; 2 cut-outs
GND on BOTTOM: 182.39,72.35 182.27,72.48 182.27,74 182.39,74.13 183.28,74.13 183.41,74.26 183.41,77.68 183.28,77.81 182.52,77.81 182.39,77.94 182.39,79.59 179.85,82.13 179.85,85.81 182.52,88.48 187.22,88.48 189.76,85.94 189.76,82.64 189.63,82.51 189.38,82.51 189,82.13 189,81.75 188.74,81.49 188.74,80.99 188.62,80.86 188.23,80.86 187.98,81.11 187.6,81.11 187.47,80.99 187.47,79.34 187.35,79.21 184.68,79.21 184.3,78.83 184.3,72.48 184.17,72.35 ; 8 cut-outs
GND on BOTTOM: 160.55,66.76 160.17,67.14 160.17,68.41 160.29,68.54 162.58,68.54 162.71,68.41 162.71,67.02 162.45,66.76 ; 1 cut-out
GND on BOTTOM: 197,75.91 196.74,76.16 196.74,76.54 196.49,76.8 196.49,83.65 196.87,84.03 198.78,84.03 199.03,83.78 199.03,81.49 198.65,81.11 198.65,76.16 198.39,75.91 ; 4 cut-outs
GND on BOTTOM: 48.03,98.39 46.38,100.04 45.11,100.04 45.03,99.96 45.03,99.81 44.88,99.66 43.84,99.66 43.71,99.78 43.71,100.54 43.84,100.67 44.98,100.67 45.05,100.75 46.96,100.75 47.14,100.93 51.71,100.93 52.09,100.54 52.09,100.16 52.6,99.66 53.87,99.66 54,99.53 54,98.51 53.87,98.39 ; 2 cut-outs
GND on BOTTOM: 15.9,37.93 15.64,38.19 15.64,39.08 15.9,39.33 17.29,39.33 17.95,38.67 18.79,38.67 18.79,37.96 17.85,37.96 17.83,37.93 ; 3 cut-outs
GND on BOTTOM: 139.85,92.67 139.72,92.8 139.72,95.85 140.61,96.73 140.61,99.78 144.67,103.85 144.67,112.61 144.29,112.99 144.29,113.63 144.93,114.26 145.69,114.26 145.74,114.21 145.74,105.32 150.52,100.54 150.52,96.35 147.98,93.81 144.29,93.81 143.15,92.67 ; 1 cut-out
GND on BOTTOM: 185.57,55.59 185.31,55.84 185.31,59.02 185.57,59.27 186.08,59.27 186.33,59.52 186.33,61.17 187.35,61.17 187.35,55.84 187.09,55.59
GND on BOTTOM: 186.96,43.14 185.82,44.28 185.82,48.73 186.2,49.11 188.23,49.11 188.23,44.92 188.62,44.54 189.89,44.54 190.14,44.28 193.44,44.28 193.57,44.16 193.57,43.39 193.31,43.14 ; 1 cut-out
GND on BOTTOM: 14.78,66.92 13.08,68.62 13.08,69.15 13.63,69.71 14.78,69.71 15.26,70.19 15.26,71.59 17.8,74.13 19.2,74.13 19.32,74.26 19.32,75.53 19.45,75.65 19.83,75.65 20.09,75.4 20.09,73.62 19.96,73.49 18.31,73.49 17.55,72.73 17.55,72.22 17.8,71.97 20.21,71.97 20.47,72.22 20.85,72.22 20.98,72.1 20.98,71.84 20.72,71.59 20.72,70.45 20.59,70.32 17.17,70.32 16.91,70.57 16.15,70.57 16.02,70.45 16.02,68.29 16.15,68.16 20.47,68.16 20.59,68.03 20.59,67.52 20.47,67.4 15.31,67.4 15.21,67.3 15.21,67.09 15.03,66.92 ; 14 cut-outs
GND on BOTTOM: 87.62,31.84 87.35,32.12 87.35,74.97 81.73,80.58 81.73,90.69 81.81,90.77 87.55,90.77 88.72,89.6 90.19,89.6 90.83,88.96 94.48,88.96 95.22,88.23 101.26,88.23 101.75,88.71 101.75,91.22 102.23,91.71 109.65,91.71 109.77,91.58 109.77,90.92 111.4,89.29 111.4,87.21 115.08,83.53 116.23,83.53 117.24,84.54 120.29,84.54 121.69,83.15 124.1,83.15 124.23,83.02 124.23,82.26 124.35,82.13 125.88,82.13 126,82 126,80.1 125.75,79.84 124.48,79.84 124.23,80.1 124.23,81.62 123.97,81.88 120.8,81.88 120.16,82.51 119.53,82.51 119.02,83.02 118,83.02 117.88,82.89 117.88,79.46 117.75,79.34 115.97,79.34 114.96,80.35 114.19,80.35 113.94,80.61 113.94,80.73 114.19,80.99 114.19,81.49 113.56,82.13 113.18,82.13 112.92,81.88 111.6,81.88 108.4,78.68 104.13,78.68 101.39,81.42 97.86,81.42 97.1,80.66 97.1,79.54 97.53,79.11 97.53,74.46 98.83,73.16 98.83,57.47 101.9,54.39 102.46,54.39 102.66,54.19 102.66,52.72 101.7,51.75 101.7,50.96 95.63,44.89 95.63,40.88 92.12,37.38 92.12,33.13 90.83,31.84 ; 26 cut-outs
GND on BOTTOM: 20.59,45.78 20.47,45.91 20.47,47.97 20.34,48.09 20.34,48.86 20.85,48.86 21.1,48.6 21.1,45.88 21,45.78
GND on BOTTOM: 88.54,95.72 86.25,98 86.25,100.04 86.38,100.16 87.65,100.16 87.9,99.91 87.9,97.62 88.56,96.96 89.68,96.96 89.73,96.91 89.73,95.9 89.56,95.72
GND on BOTTOM: 214.52,27.01 214.52,29.17 214.78,29.42 217.7,29.42 217.83,29.3 217.83,27.27 217.57,27.01
GND on BOTTOM: 73.55,94.96 73.43,95.08 73.43,95.85 73.65,96.07 73.81,96.07 73.88,96.15 73.88,97.57 73.93,97.62 75.64,97.62 75.71,97.55 75.71,95.59 75.08,94.96
GND on BOTTOM: 115.87,46.03 115.19,46.72 114.78,46.72 114.6,46.54 114.37,46.54 114.32,46.59 114.32,46.79 114.75,47.22 114.75,47.66 114.88,47.78 115.44,47.78 115.59,47.63 115.59,47.02 116.18,46.44 116.18,46.21 116,46.03
GND on BOTTOM: 204.74,60.79 204.36,61.17 204.36,63.84 204.49,63.97 211.48,63.97 211.86,63.59 211.86,61.68 211.35,61.17 206.65,61.17 206.27,60.79
GND on BOTTOM: 127.81,52.35 126.79,53.37 126.16,53.37 126.08,53.45 126.08,53.68 126.16,53.75 126.95,53.75 127.23,54.03 127.23,54.87 126.92,55.17 126.18,55.17 126.06,55.3 126.06,55.48 126.13,55.55 126.79,55.55 127.23,55.99 127.23,56.6 126.82,57 126.16,57 126.08,57.08 126.08,57.31 126.13,57.36 126.82,57.36 127.28,57.82 127.38,57.82 127.71,57.49 128.27,57.49 129.06,58.27 129.81,58.27 129.81,56.42 128.24,56.42 127.66,55.83 127.66,53.12 127.86,52.91 128.78,52.91 128.93,53.07 129.84,53.07 130.02,52.89 130.02,52.58 129.79,52.35
GND on BOTTOM: 41.93,9.36 41.8,9.49 41.8,11.14 42.06,11.39 42.06,14.44 40.79,15.71 39.77,15.71 39.26,16.22 39.26,16.98 38.63,17.61 38.5,17.61 38.37,17.74 38.37,21.3 38.63,21.55 42.69,21.55 43.07,21.17 43.07,15.58 43.2,15.45 43.96,15.45 44.09,15.33 44.09,14.95 43.84,14.69 43.33,14.69 43.2,14.57 43.2,11.26 42.69,10.76 42.69,9.61 42.44,9.36 ; 2 cut-outs
GND on BOTTOM: 144.8,72.86 144.67,72.99 144.67,75.02 144.29,75.4 144.29,76.03 144.55,76.29 144.8,76.29 145.05,76.03 145.05,75.65 146.07,75.65 146.2,75.78 146.2,76.16 146.32,76.29 146.71,76.29 146.96,76.03 146.96,75.53 146.58,75.14 146.58,73.87 146.83,73.62 146.83,72.99 146.71,72.86
GND on BOTTOM: 158.9,55.08 158.39,55.59 154.33,55.59 154.33,57.75 154.45,57.87 158.52,57.87 158.77,58.13 158.77,63.59 160.93,65.75 164.74,65.75 167.53,62.95 167.53,61.17 168.8,59.9 168.8,57.49 169.18,57.11 169.18,56.22 169.06,56.09 167.15,56.09 166.14,55.08 ; 5 cut-outs
GND on BOTTOM: 188.23,20.53 187.98,20.79 187.98,23.2 187.6,23.58 182.65,23.58 182.27,23.96 182.27,25.49 191.28,25.49 191.66,25.87 192.43,25.87 192.55,25.74 192.55,24.85 192.04,24.34 191.66,24.34 191.54,24.22 191.54,23.84 191.92,23.46 193.57,23.46 193.7,23.33 193.7,20.79 193.44,20.53 ; 1 cut-out
GND on BOTTOM: 197.63,39.08 197.63,42.12 197.76,42.25 200.93,42.25 201.06,42.12 201.06,39.33 200.81,39.08
GND on BOTTOM: 195.85,50.89 195.35,51.4 193.06,51.4 192.81,51.65 192.81,52.41 192.93,52.54 195.47,52.54 195.6,52.67 195.6,54.57 195.35,54.82 194.46,54.82 194.33,54.95 194.33,55.97 194.46,56.09 195.22,56.09 195.6,56.48 195.6,57.49 195.35,57.75 194.58,57.75 194.46,57.87 194.46,60.54 194.58,60.67 195.09,60.67 195.22,60.54 195.22,60.29 195.47,60.03 196.87,60.03 197.12,59.78 197.12,51.01 197,50.89 ; 5 cut-outs
GND on BOTTOM: 186.05,33.62 185.92,33.74 185.92,34.23 185.67,34.48 184.2,34.48 184.17,34.5 184.17,36.16 184.22,36.21 184.81,36.21 185.01,36.41 185.01,38.24 184.96,38.29 184.22,38.29 184.17,38.34 184.17,40.09 184.3,40.22 185.31,40.22 185.44,40.09 185.44,39.58 185.82,39.2 190.77,39.2 191.54,38.44 191.66,38.44 192.93,37.17 192.93,34.12 192.43,33.62 ; 4 cut-outs
GND on BOTTOM: 121.46,106.89 121.33,107.02 121.33,112.76 121.56,112.99 123.34,112.99 123.46,112.86 123.46,107.02 123.34,106.89
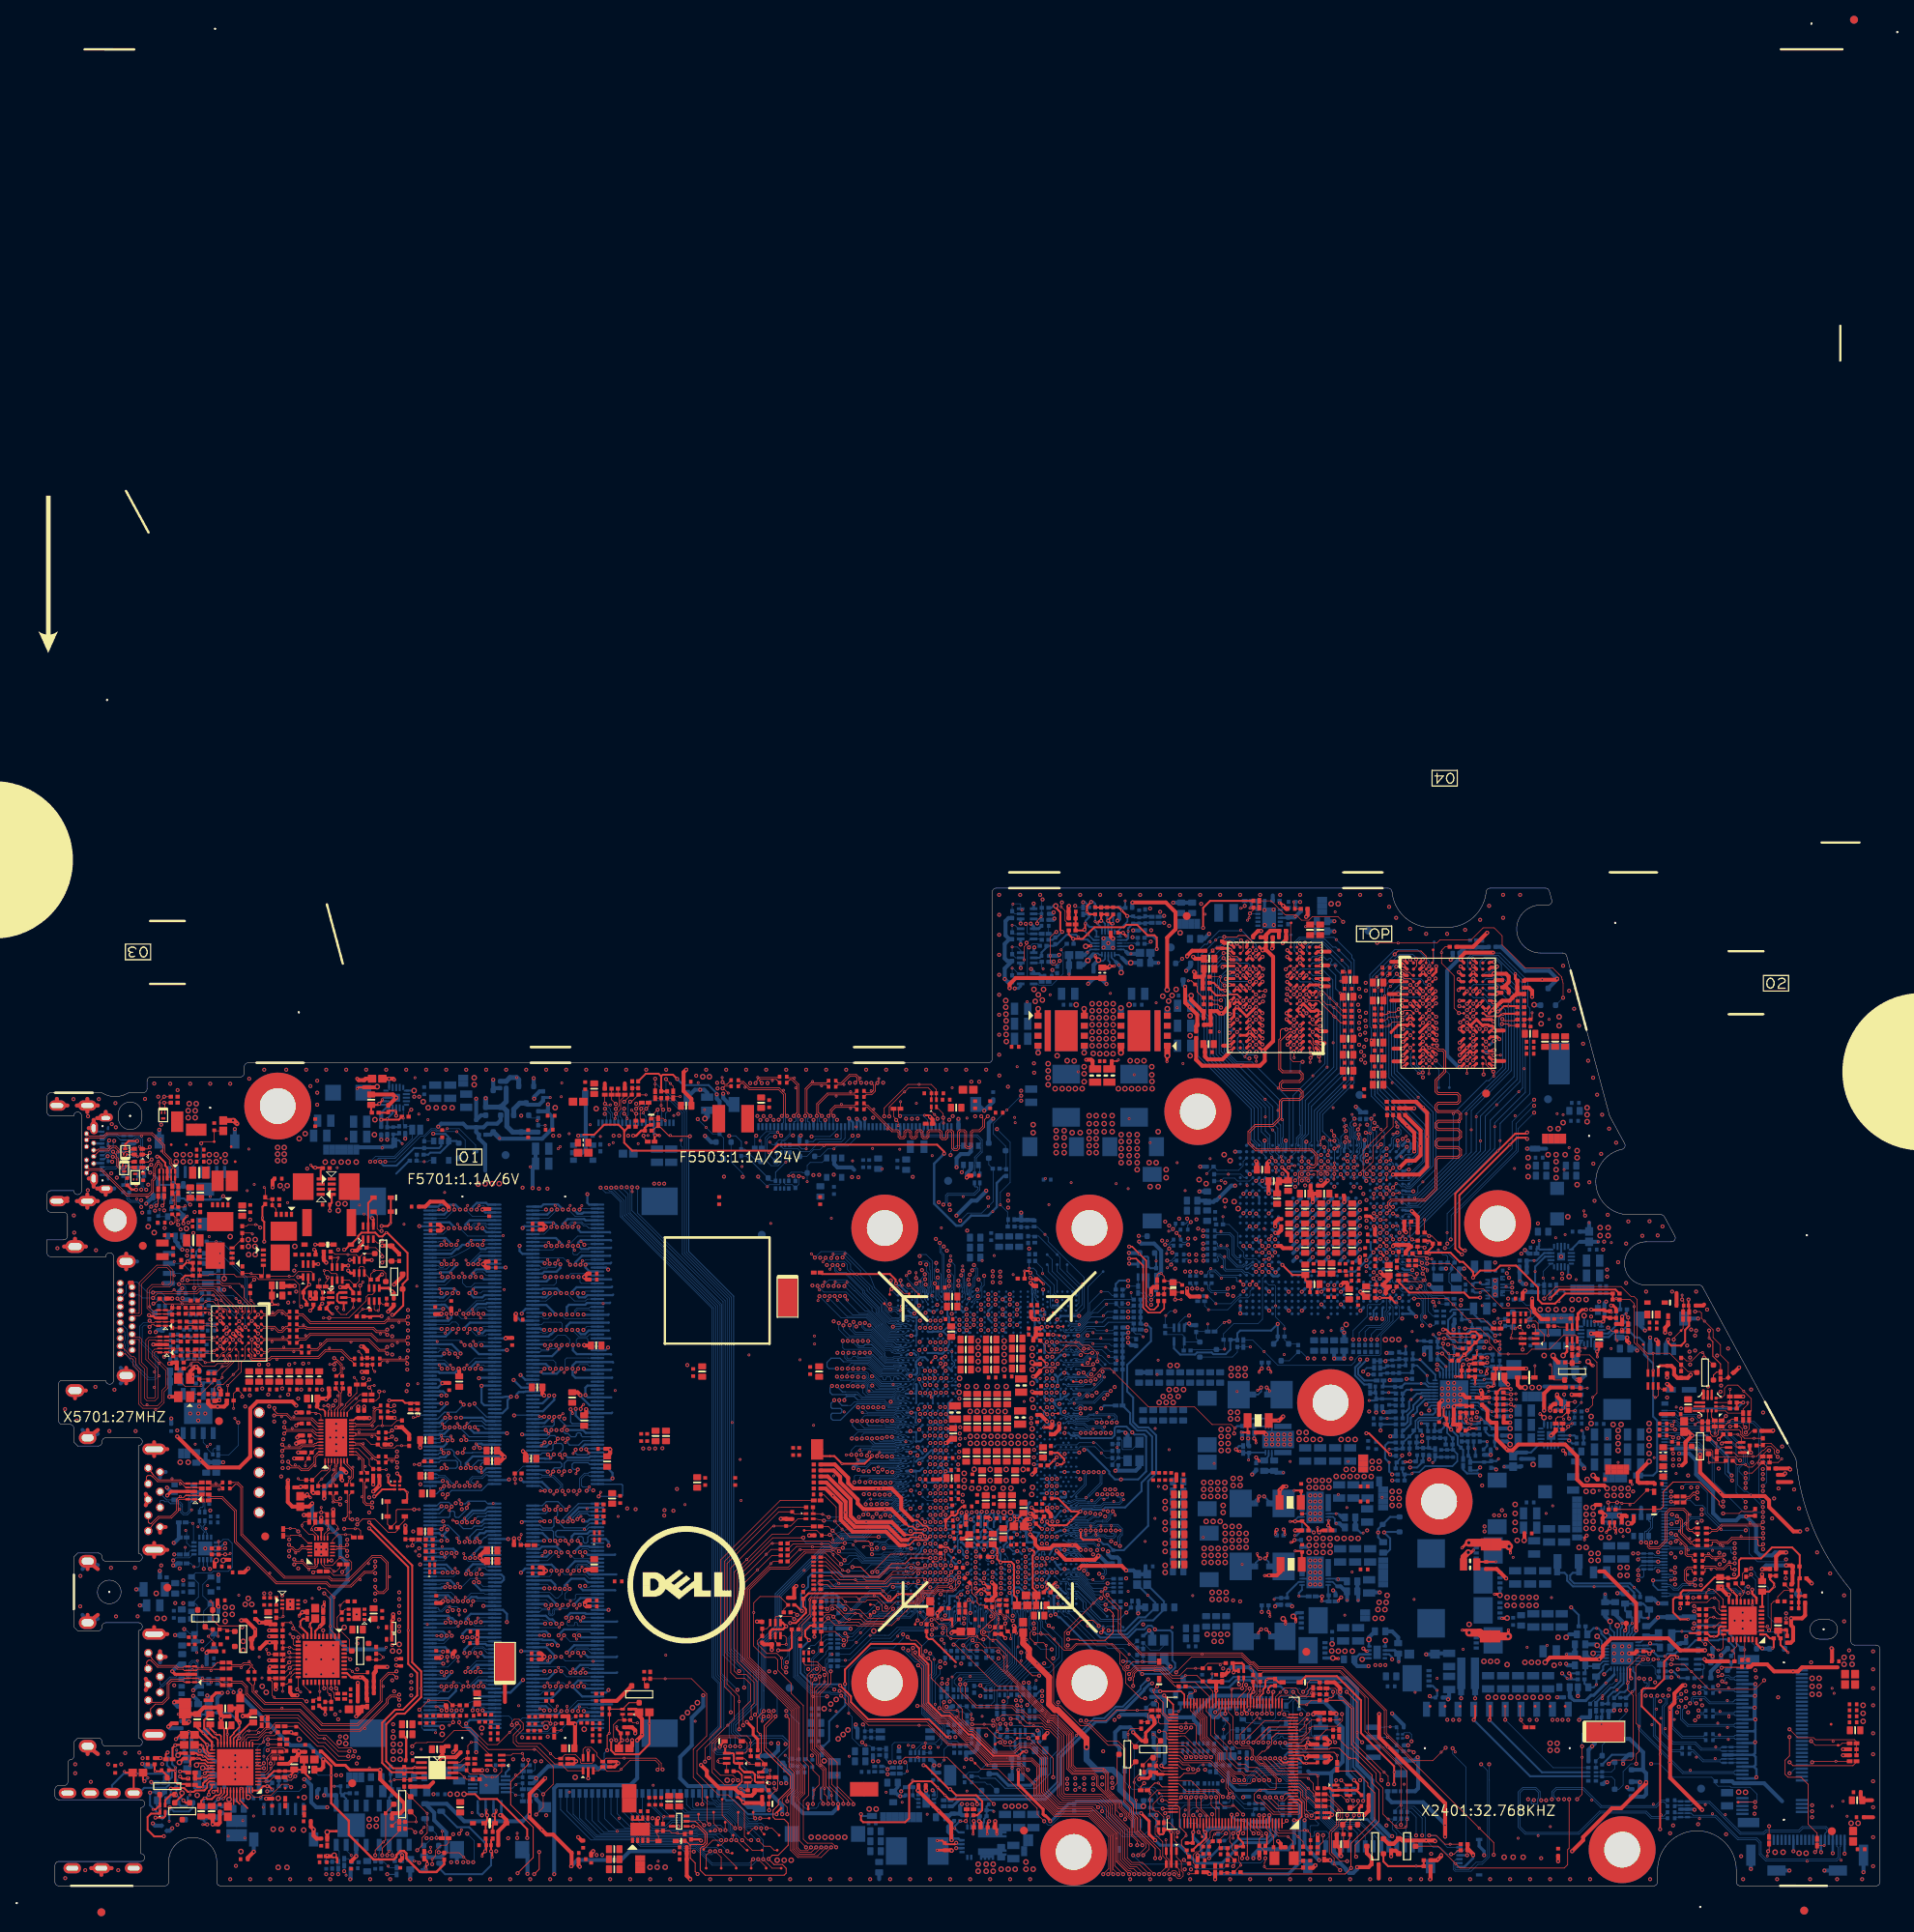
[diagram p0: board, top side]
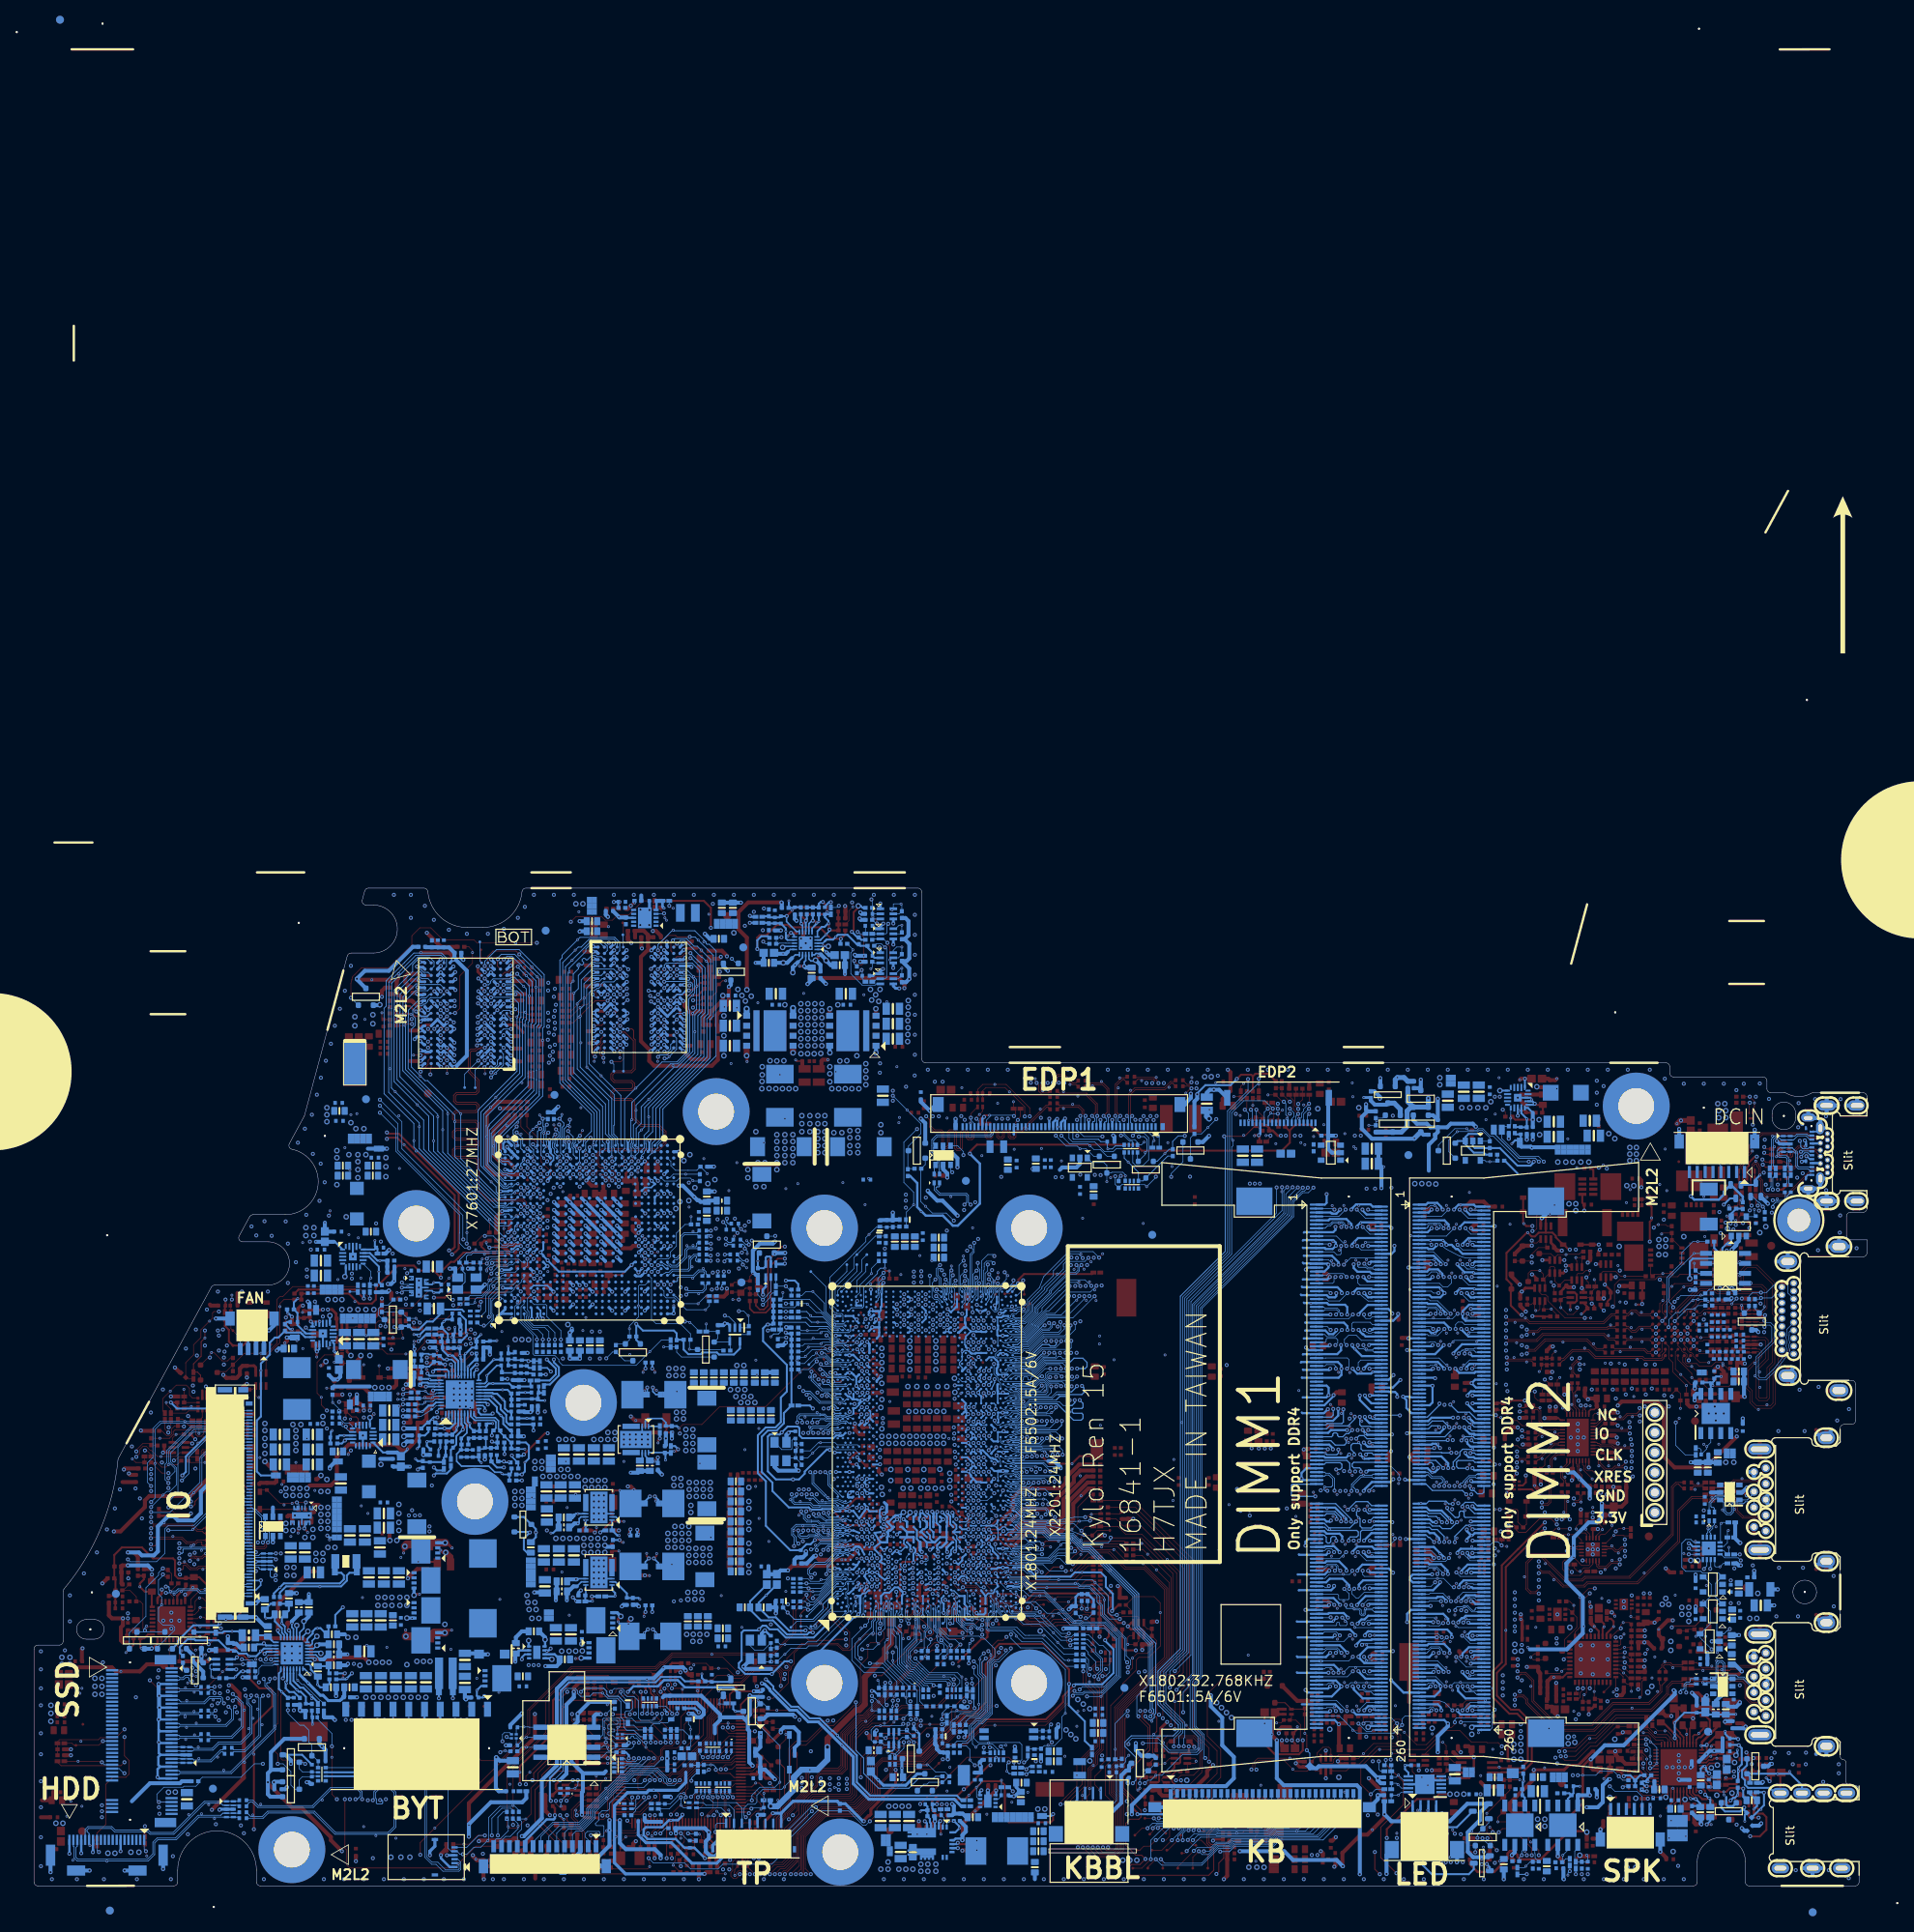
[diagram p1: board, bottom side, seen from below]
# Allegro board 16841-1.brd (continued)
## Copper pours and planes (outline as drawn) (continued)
GND on BOTTOM: 165.5,66.76 165.37,66.89 165.37,68.03 165.63,68.29 169.06,68.29 169.18,68.16 169.18,67.65 169.06,67.52 166.52,67.52 165.76,66.76
GND on BOTTOM: 187.35,89.5 187.09,89.75 187.09,92.67 187.6,93.18 189.12,93.18 189.5,92.8 189.5,89.75 189.25,89.5 ; 3 cut-outs
GND on BOTTOM: 15.9,34.5 15.77,34.63 15.77,35.9 16.02,36.16 17.44,36.16 17.74,35.86 17.74,35.41 17.9,35.24 18.79,35.24 18.79,34.53 17.9,34.53 17.88,34.5 ; 2 cut-outs
GND on BOTTOM: 192.17,76.41 192.04,76.54 192.04,77.68 192.17,77.81 192.17,79.21 192.04,79.34 191.79,79.34 191.66,79.46 191.66,80.48 191.79,80.61 192.81,80.61 192.93,80.48 192.93,76.67 192.68,76.41
GND on BOTTOM: 190.52,64.22 189,65.75 189,67.91 188.74,68.16 188.11,68.16 187.98,68.29 187.98,68.92 188.11,69.05 188.74,69.05 189,69.3 193.95,69.3 194.08,69.18 194.08,68.16 193.31,67.4 193.31,64.35 193.19,64.22 ; 1 cut-out
GND on BOTTOM: 141.5,52.54 141.12,52.92 141.12,57.62 140.23,58.51 139.59,58.51 139.47,58.63 138.83,58.63 138.58,58.89 138.58,59.14 138.96,59.52 148.48,59.52 149.25,58.76 150.39,58.76 150.52,58.63 150.52,53.94 149.12,52.54 ; 4 cut-outs
GND on BOTTOM: outline of 338 points within 0.51,0.51 232.29,126.29 ; 15 cut-outs
GND on BOTTOM: 195.6,69.56 195.47,69.68 195.47,70.9 195.52,70.95 195.52,72.68 195.09,73.11 195.09,73.49 195.22,73.62 196.11,73.62 196.36,73.37 196.36,72.17 196.24,72.05 196.24,70.93 196.26,70.9 196.54,70.9 196.74,70.7 196.74,69.68 196.62,69.56
GND on BOTTOM: 194.08,87.97 193.82,88.23 193.82,93.94 194.08,94.19 194.71,94.19 194.97,93.94 194.97,88.23 194.71,87.97 ; 3 cut-outs
GND on BOTTOM: 132.74,105.12 132.35,105.5 132.35,107.48 132.18,107.66 131.34,107.66 131.21,107.78 131.21,111.21 130.96,111.47 129.94,111.47 129.69,111.72 129.69,114.01 129.81,114.13 138.32,114.13 138.45,114.01 138.45,111.72 138.32,111.59 135.88,111.59 135.78,111.49 135.78,109.89 135.96,109.71 136.85,109.71 136.93,109.64 136.93,106.39 136.8,106.26 136.16,106.26 135.91,106.01 135.91,105.37 135.66,105.12 ; 2 cut-outs
GND on BOTTOM: 128.8,54.44 128.54,54.7 128.54,55.21 128.67,55.33 131.08,55.33 131.41,55.66 131.82,55.66 131.97,55.51 131.97,54.82 131.59,54.44
GND on BOTTOM: 130.58,21.55 128.04,24.09 128.04,27.52 130.58,30.06 134.26,30.06 135.53,28.79 136.93,28.79 137.05,28.66 137.05,24.34 134.26,21.55
GND on L2GND: outline of 369 points within 0.51,0.51 208.34,126.29 ; 38 cut-outs
GND on L2GND: 215.06,0.51 215.06,2 212.99,6.3 208.34,7.37 208.34,10.02 209.24,10.92 217.9,10.92 218.38,10.44 224.27,10.44 228.01,6.7 230.3,6.7 230.94,7.35 230.94,9.95 226.82,14.07 220.85,14.07 216.57,18.35 216.57,29.55 212.12,34 212.12,37.17 211.38,37.92 208.4,37.92 207.78,38.55 207.78,41.82 206.03,43.58 206.03,50.15 206.75,50.88 210.08,50.88 211.98,48.97 218.03,48.97 218.17,48.83 218.17,42.64 217.02,41.49 217.02,32.93 220.4,29.55 223.03,26.92 232.29,26.92 232.29,0.51
GND on L3: outline of 234 points within 0.51,0.51 232.29,126.29
GND on L3: 13.15,73.8 20.57,73.8 21,73.37 21,67.68 20.21,66.89 13.99,66.89 13.23,67.65 13.23,69.68 12.47,70.45 12.47,73.11
GND on L3, L4: 159.79,52.03 162.71,52.03 163.09,52.41 168.42,52.41 168.68,52.16 168.68,51.52 167.66,50.51 163.6,50.51 162.07,48.98 162.07,46.57 161.82,46.32 160.29,46.32 159.66,46.95 159.66,51.9
GND on L3, L4: 160.04,44.54 166.52,44.54 167.41,45.43 168.04,45.43 168.17,45.3 168.17,44.54 167.15,43.52 163.85,43.52 163.34,43.01 163.34,38.31 162.96,37.93 160.42,37.93 159.91,38.44 159.91,44.41
GND on L4: 164.49,119.98 166.01,118.45 170.84,118.45 172.11,117.18 181.12,117.18 183.66,114.64 184.17,114.64 186.46,112.36 186.46,99.4 171.22,84.16 166.14,84.16 164.1,86.19 164.1,87.59 162.96,88.73 158.14,88.73 154.83,92.04 154.83,92.54 150.52,96.86 150.52,102.07 148.1,104.48 148.1,115.66 149.88,117.44 159.41,117.44 160.04,118.07 160.04,119.39 160.62,119.98
GND on L4: outline of 237 points within 0.51,0.51 232.29,126.29 ; 1 cut-out
GND on L5VCC: outline of 156 points within 0.51,0.51 232.29,126.29 ; 3 cut-outs
GND on L6: 159.91,52.03 162.83,52.03 163.22,52.41 167.53,52.41 167.66,52.28 167.66,51.52 167.41,51.27 165.76,51.27 165.37,50.89 165.37,45.93 166.9,44.41 166.9,43.27 164.99,41.36 164.99,37.81 164.36,37.17 159.79,37.17 159.28,37.68 159.28,51.4
GND on L6: 154.33,57.87 154.33,55.84 154.58,55.59 166.39,55.59 167.03,56.22 167.03,61.81 165.12,63.71 160.17,63.71
GND on L6: outline of 234 points within 0.51,0.51 232.29,126.29 ; 1 cut-out
GND on L7GND: outline of 169 points within 0.51,0.51 232.29,126.29 ; 3 cut-outs
VCC1R05VIDEO_PEX_PLLVDD on BOTTOM: 151.79,82.76 149.25,85.3 145.82,85.3 145.69,85.43 145.69,86.19 145.82,86.32 148.41,86.32 148.53,86.45 149.7,86.45 150.18,85.97 150.18,85.89 151.28,84.8 156.19,84.8 156.68,84.31 156.68,83.34 156.53,83.19 156.02,83.19 155.74,83.47 155.74,83.42 155.09,82.76 ; 2 cut-outs
VCC_CORE on TOP: 116.48,62.06 116.23,62.32 116.23,63.71 116.48,63.97 122.19,63.97 122.58,63.59 122.58,62.32 122.32,62.06 ; 4 cut-outs
VCC_CORE on TOP: 118.26,51.01 118.13,51.14 118.13,51.78 118.38,52.03 124.48,52.03 124.99,52.54 125.37,52.54 125.5,52.41 125.5,52.03 124.48,51.01
VCC_CORE on TOP: 144.17,39.71 143.91,39.97 143.91,51.9 143.8,52.02 143.34,52.02 143.33,52.03 139.72,52.03 138.18,53.57 129.94,53.57 128.42,55.1 128.42,55.1 128.18,55.33 126.13,55.33 125.67,54.88 125.67,54.34 125.55,54.22 125.22,54.22 124.61,54.82 114.73,54.82 114.53,54.62 114.53,53.55 114.3,53.32 114.07,53.32 113.92,53.47 113.92,53.95 113.76,54.11 113.76,56.19 114.2,56.62 115.21,56.62 115.72,57.13 115.72,58.63 115.72,58.63 114.83,58.63 114.57,58.89 114.57,59.9 114.7,60.03 115.97,60.03 116.23,59.78 116.23,59.65 116.73,59.14 117.75,59.14 117.75,59.14 122.44,59.14 122.45,59.14 123.85,59.14 123.85,59.14 124.43,59.14 124.43,59.14 124.71,59.42 124.71,59.6 124.89,59.78 125.12,59.78 125.55,59.35 126.18,59.35 126.39,59.14 126.49,59.14 126.57,59.06 126.57,58.96 126.77,58.76 126.77,57.89 127.27,57.38 128.04,57.38 128.55,57.89 128.55,59.14 129.69,60.29 131.97,60.29 132.48,59.78 135.28,59.78 136.04,60.54 145.69,60.54 148.74,57.49 148.74,54.95 148.99,54.7 151.28,54.7 152.93,53.05 152.93,40.35 152.29,39.71 ; 40 cut-outs
VCC_CORE on BOTTOM: 126.46,51.9 125.9,52.46 125.57,52.46 125.45,52.34 125.42,52.31 125.42,52.13 125.24,51.95 124.94,51.95 124.81,52.08 124.81,59.73 124.99,59.9 125.69,59.9 126.08,59.52 126.08,59.14 126.33,58.89 126.84,58.89 127.09,58.63 127.09,57.78 126.85,57.54 126.13,57.54 125.96,57.36 125.96,57.03 126.08,56.9 126.71,56.9 127.09,56.52 127.09,56.03 126.74,55.68 126.11,55.68 125.96,55.53 125.96,55.25 126.13,55.07 126.79,55.07 127.09,54.77 127.09,54.18 127.07,54.18 127.05,54.16 127.05,52.44 126.83,52.22 126.9,52.15 126.9,52 126.79,51.9
VCC_CORE on BOTTOM: 150.39,38.57 148.48,40.47 146.2,40.47 145.05,39.33 144.04,39.33 143.91,39.46 143.91,51.78 144.17,52.03 151.91,52.03 153.06,50.89 153.06,38.82 152.8,38.57 ; 9 cut-outs
VCC_CORE on BOTTOM: 114.8,52.87 114.8,52.87 114.4,52.87 113.97,53.3 113.97,53.73 114.47,54.23 114.47,54.67 113.93,55.2 113.93,55.51 114.49,56.06 114.49,56.48 113.93,57.03 113.93,57.26 114.11,57.44 114.9,57.44 115.28,57.82 115.77,57.82 116.13,57.46 116.13,53.5 115.97,53.34 115.32,53.34 114.85,52.87
VCC_CORE on L2GND: 142.56,38.48 141.7,39.34 141.7,49.66 139.07,52.28 126.14,52.28 125.05,51.19 117.61,51.19 117.24,51.56 117.24,52.6 116.8,53.05 115.86,53.05 115.46,53.44 115.46,60.48 116.33,61.34 116.33,63.98 116.82,64.48 124.19,64.48 124.49,64.17 125.76,64.17 126.27,64.68 129.85,64.68 130.51,64.02 130.51,63.97 130.9,63.58 133.58,63.58 134.06,64.06 135.58,64.06 139.39,60.25 145.56,60.25 148.42,57.39 148.42,55.1 149.12,54.41 151.25,54.41 151.98,53.68 151.98,50.66 151.16,49.85 151.16,46.59 152.66,45.09 152.66,39.89 151.25,38.48
VCC_CORE on L3: 115.97,64.48 135.15,64.48 136.42,63.21 136.55,63.21 139.21,60.54 145.69,60.54 148.74,57.49 148.74,54.95 148.99,54.7 151.4,54.7 151.85,54.25 151.85,50.57 151.53,50.25 151.53,46.57 152.67,45.43 152.67,41.36 149.5,38.19 142.51,38.19 141.37,39.33 141.37,49.62 138.96,52.03 131.47,52.03 131.34,52.16 130.83,52.16 130.58,51.9 125.12,51.9 124.35,51.14 117.75,51.14 116.86,52.03 116.86,52.74 116.61,53 115.77,53 115.34,53.43 115.34,63.84
VCCPD_VBUS on TOP: 32.53,82.26 32.28,82.51 32.28,84.67 32.02,84.92 29.61,84.92 29.48,85.05 29.48,85.94 29.1,86.32 29.1,90.13 29.74,90.77 33.68,90.77 34.06,90.38 34.06,86.19 34.69,85.56 34.69,82.64 34.31,82.26 ; 5 cut-outs
VCCPD_VBUS on TOP: 38.02,31.99 37.05,32.96 37.05,34.2 37.1,34.25 37.61,34.25 37.79,34.07 38.55,34.07 38.58,34.05 38.58,33.31 38.78,33.11 39.14,33.11 39.21,33.03 39.21,32.09 39.11,31.99 ; 1 cut-out
VCCPD_VBUS on BOTTOM: 36.85,32.22 36.6,32.47 36.6,35.8 39.01,38.21 39.01,43.39 41.8,46.19 41.8,51.27 38.25,54.82 38.25,58.76 37.87,59.14 37.87,67.02 34.5,70.38 34.5,74.26 39.74,79.49 39.74,82.48 42.18,84.92 42.95,84.92 43.2,85.18 43.2,88.86 43.07,88.99 35.83,88.99 34.69,87.84 29.61,87.84 29.23,88.23 29.23,89.62 29.61,90 33.29,90 34.69,91.4 43.84,91.4 45.49,89.75 45.49,82.26 43.58,80.35 43.58,72.73 43.45,72.6 43.07,72.6 42.57,73.11 40.15,73.11 38.95,71.91 38.95,67.97 39.52,67.4 39.52,61.56 39.14,61.17 39.14,60.67 40.41,59.4 40.41,55.08 43.01,52.48 43.01,43.71 41.17,41.87 41.17,37.27 39.01,35.11 39.01,32.98 38.25,32.22
VCCPD_VBUS on L6: 5.35,91.53 5.35,94.96 6.12,95.72 15.26,95.72 16.02,94.96 16.02,92.04 16.4,91.65 31.39,91.65 32.02,91.02 32.02,89.11 31.39,88.48 14.37,88.48 13.36,89.5 11.45,89.5 11.2,89.75 11.2,90.26 10.56,90.89 5.99,90.89
VDD12 on TOP: 27.83,64.86 27.71,64.98 27.71,66.51 27.83,66.64 28.47,66.64 28.6,66.51 28.6,66 28.72,65.87 29.87,65.87 29.99,65.75 29.99,64.98 29.87,64.86
VDD12 on BOTTOM: 21.36,67.52 20.59,68.29 16.4,68.29 16.28,68.41 16.28,70.32 16.78,70.32 16.78,69.43 17.04,69.18 20.72,69.18 21.74,68.16 22.37,68.16 23.13,68.92 23.13,69.43 23.52,69.81 24.66,69.81 24.91,69.56 24.91,68.41 24.02,67.52 ; 1 cut-out
VDD12 on L6: 26.06,67.78 26.44,67.4 28.72,67.4 28.85,67.27 28.85,66 28.72,65.87 27.83,65.87 27.71,66 27.71,66.51 27.58,66.64 23.64,66.64 23.39,66.89 23.39,69.56 23.52,69.68 25.55,69.68 26.06,69.18
VDD33 on BOTTOM: 22.63,70.7 22.25,71.08 22.25,71.97 22.12,72.1 21.48,72.1 21.1,72.48 20.47,72.48 20.21,72.22 17.93,72.22 17.8,72.35 17.8,72.86 18.31,73.37 22.5,73.37 23.77,72.1 23.77,71.21 23.26,70.7 ; 3 cut-outs
VDD33 on L6: 18.94,75.78 28.72,75.78 29.1,75.4 29.1,72.86 28.47,72.22 18.94,72.22 18.82,72.35 18.82,75.65
VDDA12 on TOP: 32.91,64.86 32.79,64.98 32.79,66 32.66,66.13 32.28,66.13 32.15,66.25 32.15,66.76 32.28,66.89 33.55,66.89 33.68,66.76 33.68,66 33.8,65.87 34.95,65.87 35.07,65.75 35.07,64.98 34.95,64.86
VDDA12 on BOTTOM: 21.99,69.94 21.61,70.32 21.1,70.32 20.98,70.45 20.98,71.59 21.1,71.72 21.48,71.72 22.63,70.57 23.01,70.57 23.13,70.45 23.13,70.19 22.88,69.94 ; 1 cut-out
VDDD on TOP: 34.95,20.92 33.55,22.31 33.55,22.69 33.68,22.82 36.85,22.82 37.41,23.38 37.41,26.66 37.43,26.68 38.07,26.68 39.01,25.74 39.01,22.06 38.63,21.68 37.36,21.68 36.6,20.92 ; 5 cut-outs
VDDRX12 on TOP: 30.37,64.86 30.25,64.98 30.25,66.51 30.37,66.64 31.01,66.64 31.02,66.62 31.58,66.62 31.67,66.53 31.67,65.98 31.77,65.87 32.41,65.87 32.53,65.75 32.53,64.98 32.41,64.86 ; 1 cut-out
VDDRX12 on BOTTOM: 22.37,65.75 21.48,66.64 15.51,66.64 15.39,66.76 15.39,67.27 21.74,67.27 22.5,66.51 23.13,66.51 23.9,67.27 24.28,67.27 25.93,68.92 25.93,70.06 26.44,70.57 27.33,70.57 27.71,70.19 27.71,68.67 29.74,66.64 30.75,66.64 31.01,66.38 31.01,66 30.75,65.75 29.1,65.75 27.58,67.27 26.56,67.27 25.04,65.75
VDDRX12 on L6: 26.56,67.52 26.31,67.78 26.31,69.62 26.34,69.65 26.34,70.22 26.56,70.45 31.01,70.45 31.39,70.06 31.39,66.13 31.14,65.87 29.48,65.87 29.23,66.13 29.23,67.14 28.85,67.52
VDDTX12 on TOP: 25.29,64.86 25.17,64.98 25.17,65.75 25.29,65.87 26.31,65.87 26.44,66 26.44,66.51 26.56,66.64 27.33,66.64 27.45,66.51 27.45,64.98 27.33,64.86
VDDTX12 on BOTTOM: 21.74,68.41 21.48,68.67 21.48,69.05 21.23,69.3 17.17,69.3 17.04,69.43 17.04,69.94 17.17,70.06 21.61,70.06 22.37,69.3 22.37,68.54 22.25,68.41 ; 4 cut-outs
VDDTX12 on L6: 22.25,69.81 20.85,69.81 20.59,69.56 20.59,68.67 19.96,68.03 19.96,66 21.1,64.86 27.33,64.86 27.45,64.98 27.45,66.25 27.2,66.51 21.86,66.51 21.61,66.76 21.61,67.65 22.5,68.54 22.5,69.56
0D6V_PWR on BOTTOM: 50.7,12.65 50.69,12.66 49.17,12.66 48.92,12.91 48.92,14.18 49.04,14.31 53.26,14.31 53.49,14.08 54.71,14.08 54.71,13.75 53.36,13.75 53.31,13.7 53.31,13.12 53.36,13.07 54.71,13.07 54.71,12.76 53.39,12.76 53.28,12.66 50.71,12.66
0D6V_S0 on TOP: 46.12,18.5 45.87,18.76 45.87,20.92 45.99,21.04 50.31,21.04 50.69,20.66 50.69,19.26 49.93,18.5 ; 5 cut-outs
0D6V_S0 on TOP: 60.98,19.39 60.85,19.52 60.85,20.92 60.98,21.04 63.14,21.04 63.77,20.41 63.77,19.65 63.52,19.39 ; 5 cut-outs
0D6V_S0 on BOTTOM: 48.92,14.57 48.79,14.69 48.79,18.38 49.68,19.26 49.68,20.28 49.93,20.53 50.44,20.53 50.69,20.28 50.69,16.98 51.33,16.34 51.33,14.57
0D6V_S0 on L4: 49.3,20.66 49.3,19.01 51.07,17.23 53.49,17.23 54.63,18.38 63.77,18.38 64.28,18.88 64.28,19.9 63.65,20.53 63.14,20.53 62.12,19.52 55.14,19.52 54.38,20.28 53.11,20.28 52.98,20.41 51.33,20.41 50.95,20.79 49.42,20.79
1D0V_PWR on TOP: 75.59,1.36 75.46,1.48 75.46,4.28 75.59,4.41 78.76,4.41 79.4,3.77 79.4,1.74 79.01,1.36
1D0V_PWR on BOTTOM: 92.6,1.23 92.35,1.48 92.35,4.28 92.73,4.66 100.86,4.66 101.24,4.28 102.64,4.28 103.14,3.77 105.05,3.77 105.3,4.02 105.3,7.45 104.85,7.91 104.85,9.26 105.43,9.26 105.43,8.72 105.56,8.6 111.02,8.6 111.15,8.47 111.15,7.71 110.13,6.69 110.13,2.88 109.62,2.37 106.45,2.37 106.19,2.12 106.19,1.36 106.07,1.23 ; 9 cut-outs
1D0V_PWR on L6: 76.09,2.88 76.09,1.74 76.47,1.36 94.64,1.36 94.89,1.61 94.89,3.39 94.64,3.64 92.35,3.64 91.84,3.14 84.09,3.14 83.59,3.64 76.86,3.64
1D0V_S5 on TOP: 104.03,8.47 103.91,8.6 103.91,13.17 104.29,13.55 106.83,13.55 107.34,13.04 107.34,9.1 106.7,8.47
1D0V_S5 on TOP: 124.28,36.33 124,36.61 124,37.04 123.64,37.4 123.64,42.68 123.72,42.76 123.72,43.65 123.57,43.79 122.07,43.79 121.94,43.92 121.94,44.94 121.69,45.19 120.55,45.19 120.29,45.45 120.29,45.83 120.42,45.95 120.67,45.95 120.93,46.21 120.93,46.84 121.05,46.97 122.45,46.97 122.58,46.84 122.58,46.46 122.32,46.21 122.32,45.19 122.58,44.94 122.71,44.94 122.83,44.81 122.83,44.43 122.96,44.3 123.47,44.3 123.72,44.56 124.48,44.56 124.61,44.43 124.61,44.15 124.86,43.9 124.86,42.58 124.99,42.46 124.99,37.76 125.24,37.5 125.24,36.44 125.14,36.33 ; 4 cut-outs
1D0V_S5 on TOP: 117.75,44.79 117.68,44.86 117.68,45.88 117.07,46.49 117.07,46.72 117.19,46.84 117.5,46.84 118.08,46.26 118.31,46.26 118.41,46.16 118.41,44.99 118.21,44.79 ; 1 cut-out
1D0V_S5 on BOTTOM: 105.81,8.85 105.68,8.98 105.68,9.23 105.53,9.38 104.01,9.38 102.51,10.88 101.75,10.88 101.24,11.39 101.24,15.84 99.59,17.49 99.59,20.79 99.87,21.07 101.85,21.07 102.13,20.79 102.13,18.63 103.4,17.36 103.4,15.33 103.91,14.82 103.91,14.18 104.16,13.93 106.45,13.93 106.57,13.8 106.95,13.8 107.21,13.55 107.21,12.79 106.7,12.28 106.7,11.64 106.83,11.52 107.72,11.52 107.97,11.26 108.22,11.26 108.73,10.76 110.89,10.76 111.02,10.63 111.02,9.74 111.15,9.61 111.15,8.85 ; 11 cut-outs
1D0V_S5 on BOTTOM: 124.08,42.34 123.66,42.76 122.83,42.76 122.6,42.99 122.6,43.77 122.73,43.9 123.01,43.9 123.57,44.46 123.57,44.79 123.39,44.96 123.39,45.06 123.47,45.14 123.69,45.14 124.04,44.79 124.04,42.99 124.35,42.68 124.35,42.68 124.35,42.48 124.21,42.34
1D0V_S5 on L4: 108.23,43.67 108.23,42.37 107.59,41.73 107.59,39.17 105.6,37.18 105.6,36.91 105.6,36.91 105.6,36.52 102.2,33.13 101.82,33.13 101.11,32.42 101.11,26.63 97.94,23.46 97.94,21.55 98.95,20.53 101.49,20.53 102.13,19.9 102.13,18.76 101.62,18.25 98.06,18.25 95.78,20.53 95.78,27.65 97.94,29.81 97.94,32.09 98.95,33.11 99.21,33.11 104.41,38.31 104.41,38.82 105.89,40.3 105.89,41.64 105.9,41.65 105.9,44.17 106.14,44.41 106.14,45.71 106.17,45.71 106.83,46.37 107.82,46.37 108.71,47.26 109.37,47.26 109.95,47.84 109.95,49.71 110.64,50.4 115.09,50.4 115.12,50.43 116.25,50.43 116.58,50.1 124.05,50.1 124.61,49.54 124.61,42.55 124.31,42.25 123.75,42.25 123.62,42.37 123.62,42.8 123.44,42.98 122.45,42.98 122.1,43.34 122.1,47.58 121.79,47.88 119.12,47.88 118.87,47.63 118.87,46.82 117.8,45.75 115.11,45.75 114.58,46.28 110.84,46.28
1D0V_S5_VCCIO on TOP: 72.28,1.48 72.03,1.74 72.03,7.58 72.54,8.09 76.6,8.09 76.6,6.31 75.33,6.31 75.2,6.18 75.2,1.61 75.08,1.48 ; 6 cut-outs
1D2V_HDMI on TOP: 34.06,62.83 33.93,62.95 33.93,64.48 34.06,64.6 35.45,64.6 35.58,64.48 35.58,63.71 35.2,63.33 35.2,62.95 35.07,62.83 ; 2 cut-outs
1D2V_HDMI on TOP: 26.44,62.83 26.31,62.95 26.31,64.48 26.44,64.6 27.45,64.6 27.58,64.48 27.58,62.95 27.45,62.83 ; 1 cut-out
1D2V_HDMI on TOP: 31.52,62.7 31.39,62.83 31.39,64.35 31.52,64.48 32.53,64.48 32.66,64.35 32.66,62.83 32.53,62.7 ; 1 cut-out
1D2V_HDMI on TOP: 29.1,62.01 28.85,62.27 28.85,64.48 28.98,64.6 29.99,64.6 30.12,64.48 30.12,62.09 30.04,62.01 ; 2 cut-outs
1D2V_HDMI on BOTTOM: 23.77,62.57 23.13,63.21 23.13,64.43 22.7,64.86 21.36,64.86 21.23,64.98 21.23,65.75 21.36,65.87 21.99,65.87 22.25,65.62 23.9,65.62 24.4,65.11 24.4,64.35 24.72,64.03 32.34,64.03 32.53,63.84 32.53,62.83 32.28,62.57
1D2V_HDMI on L3: 31.9,63.97 35.33,63.97 35.58,63.71 35.58,62.7 35.2,62.32 31.9,62.32 31.64,62.57 31.64,63.71
1D2V_HDMI_VIN on BOTTOM: 18.56,54.57 18.18,54.95 18.18,55.08 16.78,55.08 16.66,55.21 16.66,56.22 16.96,56.53 18.1,56.53 18.23,56.65 18.23,58.3 18.87,58.3 18.87,58.2 18.89,58.18 18.89,56.53 19.2,56.22 19.22,56.22 19.49,55.96 19.49,54.61 19.45,54.57 ; 1 cut-out
1D2V_S3 on TOP: 51.07,10.12 50.57,10.63 50.57,11.9 50.69,12.03 53.49,12.03 53.61,11.9 53.61,10.5 53.23,10.12 ; 2 cut-outs
1D2V_S3 on TOP: outline of 113 points within 47.01,24.09 111.91,85.43 ; 140 cut-outs
1D2V_S3 on BOTTOM: 51.33,10.5 50.69,11.14 50.44,11.14 50.19,11.39 50.19,12.41 50.31,12.53 54.76,12.53 54.76,11.26 54.63,11.14 53.23,11.14 52.6,10.5 ; 1 cut-out
1D2V_S3 on BOTTOM: 34.82,91.53 34.44,91.91 34.44,93.05 34.82,93.43 39.64,93.43 40.15,92.92 40.15,91.65 40.03,91.53
1D2V_S3 on L3: 53.61,38.57 60.47,38.57 61.23,39.33 61.23,87.72 60.73,88.23 60.73,88.86 60.35,89.24 59.71,89.24 57.42,91.53 40.66,91.53 38.88,93.31 34.95,93.31 34.69,93.05 34.56,93.05 34.44,92.92 34.44,88.86 35.07,88.23 37.1,88.23 39.52,85.81 43.58,85.81 46.38,83.02 46.38,64.35 48.41,62.32 48.41,58.51 46.82,56.92 46.82,49.17 46.38,48.73 46.38,20.66 46.44,20.6 46.44,16.92 50.06,13.3 50.06,11.52 50.31,11.26 53.36,11.26 54.5,12.41 54.5,23.33 52.98,24.85 52.98,33.36 53.61,34
1D2V_S3 on L3: 107.08,46.79 107.74,46.79 109.37,48.42 110.23,48.42 110.79,47.86 114.24,47.86 114.42,48.04 114.42,48.49 113.63,49.28 109.09,49.28 106.98,47.17 106.98,46.89
1D05V_PWR on BOTTOM: 146.2,122.26 146.07,122.39 143.4,122.39 143.4,124.17 145.94,124.17 146.2,124.42 146.22,124.42 146.22,124.85 146.63,125.26 147.75,125.26 147.82,125.18 149.25,125.18 149.37,125.06 149.37,122.39 149.25,122.26 ; 2 cut-outs
1D05V_VGA_S0 on BOTTOM: 143.66,119.72 143.4,119.98 143.4,122.13 146.45,122.13 146.45,121.12 146.07,120.74 146.07,119.98 145.82,119.72 ; 2 cut-outs
1D05V_VGA_S0 on BOTTOM: 156.15,79.89 155.94,80.09 155.94,82.86 156.12,83.04 156.53,83.04 156.73,83.24 156.73,84.48 156.71,84.51 156.71,84.58 156.48,84.8 156.23,84.8 155.94,85.08 155.94,86.68 155.75,86.88 155.09,86.88 154.88,87.08 154.88,88.15 154.96,88.23 155.85,88.23 155.94,88.32 155.94,89.46 151.75,93.65 151.22,93.65 150.96,93.4 150.96,91.57 150.43,91.04 148.98,91.04 148.88,91.14 148.88,91.4 148.5,91.78 146.07,91.78 145.31,91.02 145.31,85.05 145.18,84.92 143.91,84.92 143.53,85.3 143.53,92.29 144.8,93.56 148.36,93.56 149.87,95.08 151.78,95.08 152.54,94.31 153.17,94.31 153.35,94.14 153.35,93.37 153.76,92.97 153.96,92.97 157.31,89.62 157.31,80.04 157.16,79.89 ; 2 cut-outs
1D05V_VGA_S0 on L6: 143.78,121.88 143.4,121.5 143.4,119.98 143.66,119.72 146.07,119.72 146.45,119.34 146.45,115.66 145.69,114.9 145.69,105.37 145.56,105.24 143.02,105.24 141.75,103.97 141.75,93.81 144.67,90.89 150.77,90.89 150.9,91.02 150.9,92.42 149.88,93.43 146.58,93.43 143.66,96.35 143.66,99.66 145.94,101.94 146.32,101.94 147.4,103.02 147.4,103.15 147.59,103.34 147.59,112.61 148.61,113.63 148.61,121.25 147.98,121.88
1D05V_VGA_S0 on L6: 163.09,67.27 165.12,67.27 165.25,67.14 165.25,65.11 164.87,64.73 156.74,64.73 154.83,66.64 154.83,77.35 155.57,78.09 155.57,82.38 155.7,82.51 156.36,82.51 157.37,81.49 157.37,79.46 158.39,78.45 158.39,68.79 160.55,66.64 162.45,66.64
1D8V_PWR on BOTTOM: 38.88,9.36 38.88,11.77 38.5,12.15 38.12,12.15 37.87,12.41 37.87,13.55 37.99,13.68 40.15,13.68 40.41,13.93 40.41,14.95 40.66,15.2 41.04,15.2 41.68,14.57 41.68,11.39 41.04,10.76 41.04,9.61 40.79,9.36 ; 5 cut-outs
1D35V_PWR on TOP: 190.01,89.11 189.63,89.5 189.63,94.58 189.89,94.83 193.44,94.83 193.57,94.7 193.57,89.24 193.44,89.11
1D35V_PWR on BOTTOM: 190.01,87.72 189.63,88.1 189.63,93.05 189.89,93.31 189.89,94.83 193.31,94.83 193.57,94.58 193.57,88.1 193.19,87.72 ; 13 cut-outs
1D35V_VGA_S0 on TOP: 169.31,111.34 169.06,111.59 169.06,115.28 169.18,115.4 169.82,115.4 170.07,115.66 170.07,117.82 170.2,117.94 170.84,117.94 170.96,117.82 170.96,111.59 170.71,111.34 ; 10 cut-outs
1D35V_VGA_S0 on TOP: 164.49,111.72 162.58,113.63 162.58,119.59 161.95,120.23 160.68,120.23 160.04,119.59 159.79,119.59 159.02,120.36 159.02,121.25 159.15,121.37 162.83,121.37 165.12,119.09 165.12,111.72 ; 9 cut-outs
1D35V_VGA_S0 on TOP: 148.99,114.9 147.72,116.17 147.72,117.18 147.34,117.56 146.83,117.56 146.71,117.69 146.71,119.98 146.96,120.23 148.36,120.23 148.86,119.72 148.86,117.94 150.01,116.8 150.01,115.15 149.75,114.9 ; 4 cut-outs
1D35V_VGA_S0 on TOP: 189.63,95.08 188.49,96.23 185.19,96.23 184.3,97.12 184.3,102.96 184.68,103.34 184.68,106.26 184.3,106.64 183.15,106.64 183.03,106.77 183.03,107.15 183.54,107.66 183.92,107.66 184.3,107.28 184.68,107.28 184.68,108.8 184.93,109.05 185.82,109.05 186.08,108.8 187.98,108.8 188.23,108.55 188.23,105.5 188.62,105.12 189.25,105.12 189.5,105.37 189.5,106.89 189.63,107.02 193.31,107.02 193.95,106.39 193.95,95.34 193.7,95.08 ; 8 cut-outs
1D35V_VGA_S0 on TOP: 165.5,109.31 165.37,109.43 165.37,110.83 166.77,110.83 167.15,111.21 167.79,111.21 167.91,111.09 168.93,111.09 169.06,110.96 169.06,109.82 168.93,109.69 167.28,109.69 166.9,109.31 ; 2 cut-outs
1D35V_VGA_S0 on TOP: 147.21,105.37 146.71,105.88 146.71,108.55 147.21,109.05 148.36,109.05 148.61,109.31 148.61,109.94 149.12,110.45 150.26,110.45 150.52,110.2 150.52,109.18 150.77,109.18 150.9,109.05 150.9,108.67 149.63,107.4 149.63,105.88 149.12,105.37 ; 7 cut-outs
1D35V_VGA_S0 on TOP: outline of 86 points within 156.87,86.83 173.12,111.21 ; 40 cut-outs
1D35V_VGA_S0 on BOTTOM: 189.76,95.08 189.38,95.46 189.38,96.99 192.43,100.04 193.7,100.04 193.95,99.78 193.95,95.34 193.7,95.08 ; 6 cut-outs
1D35V_VGA_S0 on BOTTOM: 178.96,104.99 178.33,105.62 178.33,116.17 178.71,116.55 179.85,116.55 180.23,116.17 180.23,107.4 179.98,107.15 179.98,106.26 180.23,106.01 180.23,105.5 179.73,104.99
1D35V_VGA_S0 on BOTTOM: 167.55,82.39 167.33,82.61 167.33,86.73 167.26,86.81 167.26,87.1 166.51,87.84 165.96,87.84 165.41,88.4 157.7,88.4 157.5,88.59 157.5,89.28 157.78,89.56 158.14,89.56 158.35,89.34 158.71,89.34 158.84,89.47 158.98,89.47 159.29,89.16 160.21,89.16 160.51,89.47 160.72,89.47 160.87,89.32 161.2,89.32 161.35,89.47 161.35,89.63 161.71,89.98 161.93,89.98 161.93,89.98 162.61,89.29 162.83,89.29 163,89.47 163.18,89.47 163.36,89.29 163.64,89.29 163.84,89.5 163.89,89.5 164.7,90.31 164.83,90.31 164.93,90.2 164.93,90.19 164.95,90.19 165.2,89.94 166.03,89.94 166.67,89.29 167.89,89.29 168.03,89.43 168.98,89.43 169.11,89.31 169.11,89.16 168.13,88.19 168.13,87.82 168.31,87.64 168.31,87.44 168.16,87.29 168.16,86.96 168.35,86.77 168.35,85.03 168.13,84.82 168.13,84.52 168.34,84.31 168.39,84.31 168.97,83.73 168.97,83.63 169.11,83.49 169.11,83.32 168.17,82.39
1D35V_VGA_S0 on BOTTOM: 176.3,105.12 175.66,105.75 175.66,113.24 175.28,113.63 175.28,114.13 175.66,114.51 175.66,117.05 175.92,117.31 177.06,117.31 177.19,117.18 177.19,105.5 176.8,105.12
1D35V_VGA_S0 on BOTTOM: 154.33,107.28 153.31,108.29 152.42,108.29 152.04,108.67 152.04,109.43 152.29,109.69 152.9,109.69 154.07,110.86 154.07,112.43 153.69,112.81 153.69,115.15 152.93,115.91 152.93,117.05 153.69,117.82 153.69,118.71 154.45,119.47 156.36,119.47 157.37,118.45 157.63,118.45 158.14,117.94 158.14,107.78 157.63,107.28
1D35V_VGA_S0 on L6: 166.01,75.4 163.53,77.88 163.53,87.53 164.61,88.61 164.61,90.51 163.98,91.15 163.98,91.4 164.36,91.78 164.36,93.43 164.61,93.69 164.61,94.83 164.74,94.96 164.74,96.86 165.12,97.24 165.12,98.13 165.25,98.26 165.25,109.69 162.58,112.36 160.29,112.36 159.66,111.72 159.66,110.83 159.41,110.58 158.01,110.58 157.75,110.32 157.75,109.31 158.14,108.93 159.41,108.93 160.93,107.4 161.95,107.4 162.07,107.28 162.07,106.64 161.95,106.51 158.9,106.51 158.77,106.64 158.77,107.15 158.52,107.4 154.45,107.4 154.33,107.28 152.42,107.28 152.17,107.53 152.17,109.43 152.42,109.69 154.71,109.69 154.83,109.82 154.83,110.96 154.45,111.34 151.02,111.34 150.77,111.59 150.77,111.85 151.02,112.1 154.96,112.1 155.34,112.48 155.34,114.01 155.09,114.26 154.33,114.26 153.94,113.88 150.39,113.88 148.74,115.53 148.74,119.09 149.12,119.47 158.64,119.47 159.28,120.1 160.55,120.1 161.18,119.47 183.41,119.47 191.6,111.28 191.6,110.01 192.55,109.05 192.55,102.32 193.82,101.05 193.82,95.21 193.06,94.45 189.89,94.45 187.73,92.29 187.73,81.37 185.82,79.46 182.14,79.46 178.07,75.4 ; 1 cut-out
2D5V_S3 on TOP: 56.03,18.12 54.5,19.65 54.5,21.04 54.63,21.17 56.66,21.17 56.79,21.04 56.79,18.38 56.54,18.12 ; 4 cut-outs
2D5V_S3 on TOP: 69.11,17.99 68.98,18.12 68.98,18.88 68.73,19.14 67.71,19.14 67.46,19.39 67.46,20.92 67.58,21.04 69.74,21.04 69.74,18.25 69.49,17.99 ; 3 cut-outs
2D5V_S3 on BOTTOM: 44.34,14.57 44.22,14.69 44.22,15.45 43.96,15.71 43.71,15.71 43.45,15.96 43.45,16.22 43.71,16.47 45.61,16.47 45.87,16.22 45.87,14.69 45.74,14.57
2D5V_S3 on BOTTOM: 57.55,16.72 54.76,19.52 54.76,20.53 54.96,20.74 57.86,20.74 57.93,20.66 57.93,19.65 59.33,18.25 66.31,18.25 66.7,18.63 66.7,19.52 67.89,20.71 70.96,20.71 71.01,20.66 71.01,19.52 69.11,17.61 67.97,17.61 67.08,16.72
2D5V_S3 on L3: 45.74,13.04 47.65,11.14 53.49,11.14 54.88,12.53 54.88,20.41 55.39,20.92 68.6,20.92 69.87,19.65 69.87,18.76 68.73,17.61 60.47,17.61 59.84,16.98 59.84,14.06 55.01,9.23 46.38,9.23 42.31,13.3 42.31,15.96 42.82,16.47 45.23,16.47 45.74,15.96
3D3V_CABLE on TOP: 204.74,52.79 204.49,53.05 204.49,53.94 204.36,54.06 203.98,54.06 203.86,54.19 203.86,54.57 204.11,54.82 205.76,54.82 206.14,54.44 207.54,54.44 207.67,54.32 207.67,54.06 207.41,53.81 206.27,53.81 206.01,53.55 206.01,53.05 205.76,52.79 ; 1 cut-out
3D3V_CABLE on BOTTOM: 205.02,53.91 205.02,54.52 207.54,54.52 207.67,54.39 207.67,53.99 207.59,53.91
3D3V_CAMERA_S0 on BOTTOM: 109.95,91.86 109.93,91.88 107.72,91.88 107.46,92.14 107.46,95.46 107.67,95.67 110.31,95.67 110.64,95.34 110.64,92.54 ; 4 cut-outs
3D3V_GSEN2 on TOP: 207.41,58.63 207.16,58.89 207.16,60.41 207.03,60.54 206.65,60.54 206.52,60.67 206.52,60.92 206.65,61.05 209.27,61.05 209.32,61 209.32,58.76 209.19,58.63 ; 3 cut-outs
3D3V_LDO on TOP: 68.47,92.67 68.35,92.8 68.35,94.96 69.36,94.96 70.12,95.72 72.79,95.72 72.92,95.59 72.92,93.18 72.41,92.67 ; 1 cut-out
3D3V_LDO on BOTTOM: 68.85,91.53 68.6,91.78 68.6,93.31 68.98,93.69 70.63,93.69 70.89,93.94 70.89,94.58 71.27,94.96 71.27,95.34 71.52,95.59 72.92,95.59 73.05,95.46 73.05,94.83 73.55,94.32 73.55,91.78 73.3,91.53 ; 2 cut-outs
3D3V_LDO_SET on BOTTOM: 68.98,93.81 68.85,93.94 68.85,95.34 69.11,95.59 69.49,95.59 69.5,95.58 70.29,95.58 70.51,95.36 70.51,93.94 70.38,93.81 ; 2 cut-outs
3D3V_MUX on BOTTOM: 31.14,53.94 30.88,54.19 30.88,60.29 31.14,60.54 32.15,60.54 32.41,60.29 32.41,54.57 31.77,53.94
3D3V_MUX on BOTTOM: 40.91,59.14 40.66,59.4 40.66,61.81 39.77,62.7 39.77,65.11 40.03,65.37 40.28,65.37 40.53,65.11 40.53,62.95 41.42,62.06 41.42,59.27 41.3,59.14
3D3V_S0 on TOP: 53.11,20.28 52.98,20.41 52.98,20.92 52.73,21.17 52.34,21.17 52.09,21.42 52.09,21.8 52.34,22.06 52.85,22.06 52.98,22.19 52.98,24.34 53.61,24.98 55.14,24.98 55.27,24.85 55.27,24.22 55.14,24.09 54,24.09 53.74,23.84 53.74,21.3 54.12,20.92 54.12,20.41 54,20.28 ; 1 cut-out
3D3V_S0 on TOP: 118.13,23.07 116.99,24.22 116.99,26.12 115.08,28.03 115.08,28.28 115.46,28.66 116.73,28.66 118,27.39 118,24.85 118.51,24.34 122.7,24.34 123.34,23.71 123.34,23.46 122.96,23.07
3D3V_S0 on TOP: 204.74,50.76 204.62,50.89 204.62,52.41 204.74,52.54 205.89,52.54 206.27,52.92 206.27,53.55 206.4,53.68 207.67,53.68 207.79,53.55 207.79,51.9 207.41,51.52 206.27,51.52 205.51,50.76 ; 2 cut-outs
3D3V_S0 on TOP: 30.25,73.75 29.48,74.51 29.48,75.53 29.61,75.65 31.39,75.65 31.64,75.4 31.64,74.13 31.26,73.75 ; 3 cut-outs
3D3V_S0 on TOP: 49.42,12.41 48.79,13.04 48.79,14.95 48.28,15.45 46.5,15.45 46.12,15.84 46.12,18.25 46.25,18.38 47.01,18.38 47.52,17.87 48.15,17.87 48.41,18.12 49.3,18.12 49.55,17.87 49.55,14.06 50.44,13.17 54.5,13.17 54.63,13.3 54.63,13.8 54.76,13.93 57.55,13.93 58.31,14.69 58.31,15.58 58.19,15.71 55.65,15.71 55.01,15.07 53.87,15.07 53.87,17.23 54,17.36 55.14,17.36 55.39,17.11 55.39,16.47 55.65,16.22 58.57,16.22 58.95,15.84 58.95,13.93 57.42,12.41 ; 4 cut-outs
3D3V_S0 on TOP: 33.6,15.53 33.55,15.58 33.55,16.9 32.81,17.64 30.86,17.64 30.82,17.68 30.78,17.64 30.27,17.64 30.09,17.82 30.09,18.86 30.2,18.96 32.61,18.96 34.08,17.49 34.28,17.49 34.46,17.31 34.46,15.68 34.31,15.53 ; 2 cut-outs
3D3V_S0 on TOP: 227.73,26.5 227.1,27.14 227.1,29.04 227.6,29.55 230.14,29.55 230.4,29.3 230.4,26.76 230.14,26.5 ; 2 cut-outs
3D3V_S0 on TOP: 66.57,93.81 65.55,94.83 65.55,95.85 64.16,97.24 64.16,99.91 65.04,100.8 67.08,100.8 67.2,100.67 67.2,96.73 68.09,95.85 68.09,95.08 67.97,94.96 67.97,94.07 67.71,93.81 ; 2 cut-outs
3D3V_S0 on TOP: 95.65,37.04 95.4,37.3 95.4,40.98 96.54,42.12 97.68,42.12 97.68,38.06 96.79,38.06 96.41,37.68 96.41,37.17 96.29,37.04 ; 1 cut-out
3D3V_S0 on TOP: 184.81,73.62 184.68,73.75 184.68,78.19 184.93,78.45 186.2,78.45 186.84,77.81 186.84,73.75 186.71,73.62 ; 1 cut-out
3D3V_S0 on BOTTOM: 184.55,73.24 184.42,73.37 184.42,74.46 184.55,74.59 184.55,75.35 185.62,75.35 186.08,74.89 186.46,74.89 186.58,74.76 186.58,74.26 185.95,73.62 185.95,73.49 185.69,73.24 ; 3 cut-outs
3D3V_S0 on BOTTOM: 197.63,42.76 197,43.39 197,46.32 197.12,46.44 198.14,46.44 198.14,45.3 198.39,45.05 199.03,45.05 199.16,44.92 199.16,44.41 199.28,44.28 199.28,42.76
3D3V_S0 on BOTTOM: 126.45,16.69 126.37,16.77 126.37,17.83 126.41,17.86 126.41,17.86 126.51,17.96 126.51,20.26 126.23,20.53 122.96,20.53 122.7,20.79 122.7,21.3 122.32,21.68 122.32,22.06 122.07,22.31 122.07,24.47 122.19,24.6 124.23,24.6 124.35,24.47 124.35,23.96 124.23,23.84 123.72,23.84 123.21,23.33 123.08,23.33 122.83,23.07 122.83,22.19 123.21,21.8 127.02,21.8 127.62,21.2 127.62,16.88 127.43,16.69 ; 2 cut-outs
3D3V_S0 on BOTTOM: 118.89,23.28 118.51,23.65 118.51,23.66 118.23,23.94 118.23,24.19 118.43,24.4 118.79,24.4 118.88,24.48 118.89,24.47 120.04,24.47 120.16,24.34 120.16,23.48 119.96,23.28
3D3V_S0 on BOTTOM: 205.02,53.1 205.02,53.71 205.91,53.71 206.01,53.81 207.92,53.81 208.17,53.55 208.17,53.3 207.97,53.1
3D3V_S0 on BOTTOM: 184.55,76.72 184.55,77.41 184.42,77.53 184.42,78.57 184.55,78.7 185.82,78.7 185.95,78.57 185.95,77.13 185.54,76.72 ; 1 cut-out
3D3V_S0 on BOTTOM: 162.2,123.4 162.07,123.53 162.07,125.44 162.2,125.56 164.23,125.56 164.49,125.31 164.49,123.53 164.36,123.4
3D3V_S0 on BOTTOM: 115.08,27.39 114.45,28.03 114.45,29.42 116.48,29.42 117.24,28.66 118.13,28.66 118.77,29.3 120.29,29.3 120.42,29.17 120.42,28.79 119.02,27.39 ; 7 cut-outs
3D3V_S0 on BOTTOM: 112.08,92.67 112.06,92.7 111.25,92.7 110.89,93.05 110.89,94.7 113.13,94.7 113.18,94.75 114.02,94.75 114.32,94.45 114.32,92.8 114.19,92.67
3D3V_S0 on BOTTOM: 121.05,23.2 120.67,23.58 120.67,24.47 120.8,24.6 121.81,24.6 121.81,23.33 121.69,23.2
3D3V_S0 on BOTTOM: 19.71,76.29 19.71,76.92 21.1,76.92 21.23,77.05 21.23,77.3 21.61,77.68 22.75,77.68 22.88,77.56 22.88,76.54 22.63,76.29 ; 2 cut-outs
3D3V_S0 on BOTTOM: 136.16,35.01 136.04,35.14 136.04,36.54 136.16,36.66 137.05,36.66 137.31,36.41 137.31,35.27 137.05,35.01 ; 1 cut-out
3D3V_S0 on L2GND: outline of 153 points within 30.59,3.66 232.29,81.25
3D3V_S0 on L3: 167.91,125.31 162.83,125.31 162.58,125.06 162.58,123.91 162.96,123.53 166.77,123.53 171.6,118.71 184.3,118.71 187.35,115.66 187.47,115.66 190.39,112.74 190.39,99.15 189,97.75 186.33,97.75 185.19,96.61 185.19,93.69 179.6,88.1 179.6,82 184.42,77.18 184.42,74 184.93,73.49 186.58,73.49 187.22,74.13 187.22,78.19 181.76,83.65 181.76,86.57 187.73,92.54 187.73,93.69 188.23,94.19 192.68,94.19 194.46,95.97 194.46,98.77 193.7,99.53 193.7,112.48 185.57,120.61 172.61,120.61
3D3V_S0 on L4: 197,45.55 197,42.89 197.63,42.25 200.81,42.25 201.19,42.63 205.38,42.63 205.89,43.14 205.89,44.92 205.25,45.55 205.25,49.87 207.54,52.16 207.54,53.55 207.41,53.68 206.27,53.68 201.32,48.73 201.32,44.92 201.06,44.66 198.78,44.66 197.63,45.81 197.25,45.81
3D3V_S0 on L4: 60.83,19.72 61.77,20.66 65.93,20.66 66.31,20.28 66.31,20.28 66.31,18.63 65.55,17.87 54.38,17.87 54,17.49 54,16.85 54.25,16.6 65.3,16.6 66.31,15.58 67.84,15.58 69.62,17.36 69.62,18.76 70.63,19.77 74.37,19.77 74.5,19.89 74.5,20.78 73.99,21.29 70.08,21.29 70.06,21.31 63.68,21.31 63.44,21.54 61.21,21.54 61.16,21.5 53.74,21.5 53.74,21.42 53.23,21.42 52.98,21.17 52.98,20.53 53.11,20.41 55.39,20.41 56.08,19.72
3D3V_S0 on L6: 29.74,71.46 30.88,71.46 31.14,71.72 31.14,77.18 30.37,77.94 22.12,77.94 21.86,77.68 21.86,76.41 22.12,76.16 28.85,76.16 29.61,75.4 29.61,71.59
3D3V_S0 on L6: 197,45.68 197.89,45.68 198.78,44.79 201.32,44.79 203.22,46.7 203.22,52.79 204.24,53.81 207.54,53.81 207.79,53.55 207.79,52.79 205.76,50.76 205.76,44.03 204.74,43.01 198.01,43.01 196.87,44.16 196.87,45.55
3D3V_S5 on TOP: 43.07,29.3 42.31,30.06 41.55,30.06 41.42,30.19 41.42,31.58 41.8,31.96 43.33,31.96 43.33,31.2 43.45,31.08 44.98,31.08 45.23,30.82 45.23,29.55 44.98,29.3 ; 1 cut-out
3D3V_S5 on TOP: 206.4,54.57 205.89,55.08 204.74,55.08 204.49,55.33 204.49,56.09 204.62,56.22 205.89,56.22 206.14,55.97 206.88,55.97 207,55.84 207.67,55.84 207.79,55.71 207.79,54.82 207.54,54.57 ; 2 cut-outs
3D3V_S5 on TOP: 44.98,62.44 44.72,62.7 44.72,65.11 44.85,65.24 45.99,65.24 46.5,65.75 46.5,80.73 44.85,82.38 44.85,88.1 45.87,89.11 50.44,89.11 51.58,90.26 57.17,90.26 57.81,89.62 57.81,88.61 57.55,88.35 53.74,88.35 53.36,88.73 52.34,88.73 51.2,87.59 47.14,87.59 46.63,87.08 46.63,82.76 47.9,81.49 47.9,62.95 47.39,62.44 ; 2 cut-outs
3D3V_S5 on TOP: 63.14,8.47 62.76,8.85 62.76,9.36 66.19,12.79 66.19,13.93 66.44,14.18 67.33,14.18 67.71,13.8 67.71,12.28 63.9,8.47
3D3V_S5 on BOTTOM: 39.26,1.99 39.14,2.12 39.14,3.26 39.26,3.39 39.52,3.39 39.77,3.64 39.77,6.21 36.85,6.21 36.85,9.21 41.27,9.21 41.3,9.23 46.25,9.23 46.76,8.72 46.76,2.75 46.63,2.63 44.85,2.63 44.72,2.75 44.72,3.39 44.85,3.52 45.23,3.52 45.49,3.77 45.49,5.93 45.23,6.18 41.55,6.18 41.17,5.8 41.17,2.75 41.04,2.63 40.28,2.63 40.03,2.37 40.03,2.12 39.9,1.99 ; 3 cut-outs
3D3V_S5 on BOTTOM: 82.19,12.91 81.43,13.68 81.43,16.34 82.32,17.23 82.32,20.66 83.59,21.93 83.59,24.47 82.82,25.23 82.82,72.73 70.89,84.67 70.89,86.7 70.76,86.83 69.74,86.83 68.98,87.59 68.98,88.1 68.47,88.61 66.19,88.61 64.28,86.7 58.95,86.7 56.92,88.73 49.3,88.73 47.52,86.96 47.52,61.05 46.63,60.16 46.63,45.68 46.12,45.17 46.12,30.19 45.36,29.42 42.82,29.42 42.57,29.68 42.57,30.06 42.5,30.12 42.5,42.44 43.33,43.27 43.33,52.41 41.55,54.19 41.55,61.68 42.82,62.95 42.82,65.75 44.47,67.4 44.47,80.22 45.61,81.37 45.61,89.88 47.01,91.27 57.55,91.27 58.06,90.77 58.06,89.88 59.84,88.1 62.5,88.1 62.76,88.35 62.76,89.5 63.27,90 68.73,90 70.76,87.97 71.39,87.97 72.54,86.83 72.54,85.05 84.35,73.24 84.35,26.25 84.98,25.61 84.98,20.53 84.09,19.65 84.09,15.96 86.13,13.93 86.51,13.93 86.76,13.68 86.76,13.04 86.63,12.91
3D3V_S5 on BOTTOM: 196.11,44.41 195.6,44.92 194.46,44.92 194.46,49.36 194.58,49.49 194.71,49.49 194.97,49.74 194.97,50.51 195.09,50.63 197.12,50.63 197.38,50.38 197.38,50.35 197.4,50.33 197.4,49.72 197.76,49.36 197.76,48.73 198.14,48.35 198.14,47.71 197,47.71 196.74,47.46 196.74,44.79 196.36,44.41
3D3V_S5 on BOTTOM: 66.7,13.3 66.31,13.68 66.31,14.31 66.82,14.82 69.24,14.82 69.74,14.31 72.66,14.31 73.55,15.2 73.55,17.49 73.93,17.87 73.93,18.63 74.06,18.76 74.57,18.76 74.7,18.63 74.7,15.96 74.57,15.84 74.57,14.06 73.81,13.3
3D3V_S5 on BOTTOM: 109.62,15.07 109.24,15.45 109.24,16.34 109.37,16.47 111.65,16.47 111.78,16.34 111.78,15.33 111.53,15.07
3D3V_S5 on BOTTOM: 206.19,54.65 206.14,54.7 205.02,54.7 205.02,55.31 207.44,55.31 207.54,55.21 207.54,54.75 207.44,54.65
3D3V_S5 on BOTTOM: 97.4,88.51 96.95,88.96 96.95,90.79 97.18,91.02 101.21,91.02 101.47,90.77 101.47,89.19 100.78,88.51 ; 4 cut-outs
3D3V_S5 on BOTTOM: 149.88,14.31 149.75,14.44 149.75,17.61 149.88,17.74 151.66,17.74 151.91,17.49 151.91,14.44 151.79,14.31 ; 5 cut-outs
3D3V_S5 on BOTTOM: 165.63,11.26 165.5,11.39 165.5,13.42 165.76,13.68 166.14,13.68 166.77,13.04 166.77,11.52 166.52,11.26
3D3V_S5 on BOTTOM: 114.57,11.77 113.05,13.3 113.05,13.8 113.69,13.8 113.81,13.68 115.72,13.68 115.97,13.42 116.86,13.42 117.11,13.17 117.11,12.91 117.24,12.79 118.77,12.79 119.15,12.41 119.15,11.9 119.02,11.77 ; 2 cut-outs
3D3V_S5 on L2GND: outline of 83 points within 34.04,5.84 202.01,49.45
3D3V_S5 on L2GND: 54.43,88.7 53.42,89.7 53.42,92.06 53.82,92.45 100.32,92.45 100.59,92.19 100.59,90.39 100.25,90.04 96.77,90.04 96.03,90.78 85.46,90.78 84.83,90.14 60.49,90.14 59.05,88.7
3D3V_S5 on L3: 36.6,19.01 36.6,17.74 36.98,17.36 38.12,17.36 38.5,17.74 41.42,17.74 45.87,22.19 45.87,28.03 46.12,28.28 46.12,31.33 45.74,31.71 43.2,31.71 42.57,31.08 42.57,26.5 41.3,25.23 41.3,22.31 39.9,20.92 38.5,20.92
3D3V_S5 on L3: 194.84,50.51 196.62,50.51 196.87,50.25 196.87,43.78 199.28,41.36 199.28,39.2 202.46,36.03 202.46,28.41 203.98,28.41 205.13,27.27 205.13,24.73 204.87,24.47 202.84,24.47 202.46,24.09 202.46,20.53 197.51,15.58 189.89,15.58 189.12,16.34 189.12,19.9 189.76,20.53 194.84,20.53 196.62,22.31 196.62,25.36 198.01,26.76 198.01,27.14 197.51,27.65 196.11,27.65 194.33,29.42 194.33,33.23 192.3,35.27 192.3,47.97
3D3V_S5 on L4: 207.79,54.57 207.67,54.44 206.27,54.44 205.76,53.94 205.76,53.68 203.47,51.4 198.52,51.4 196.87,49.74 196.87,45.3 196.36,44.79 195.09,44.79 194.46,45.43 194.46,51.78 196.36,53.68 203.73,53.68 204.24,54.19 204.24,55.08 204.87,55.71 207.54,55.71 207.79,55.46
3D3V_S5_KBC on BOTTOM: 153.06,23.2 152.8,23.46 152.8,24.73 153.06,24.98 155.47,24.98 155.98,24.47 155.98,23.46 155.72,23.2
3D3V_S5_KBC on BOTTOM: 148.94,16.01 148.74,16.22 148.74,17.36 148.36,17.74 143.78,17.74 143.53,17.99 143.53,19.39 143.78,19.65 148.81,19.65 148.99,19.47 148.99,17.99 149.27,17.72 149.27,17.23 149.55,16.95 149.55,16.14 149.42,16.01 ; 2 cut-outs
3D3V_S5_KBC on BOTTOM: 158.77,14.18 158.77,16.47 160.17,16.47 160.68,15.96 160.68,14.31 160.55,14.18
3D3V_S5_KBC on BOTTOM: 158.14,8.09 157.37,8.85 157.37,10.63 157.5,10.76 158.14,10.76 158.64,10.25 158.64,8.09 ; 2 cut-outs
3D3V_S5_KBC on BOTTOM: 141.88,12.53 141.12,13.3 141.12,15.58 141.24,15.71 142.34,15.71 144.11,13.93 148.61,13.93 148.99,13.55 148.99,12.66 148.86,12.53 ; 2 cut-outs
3D3V_S5_PCH on TOP: 97.56,28.66 97.05,29.17 95.14,29.17 94.89,29.42 94.89,30.69 95.14,30.95 96.16,30.95 96.79,30.31 101.24,30.31 101.87,30.95 101.87,32.73 102,32.85 107.97,32.85 110.38,35.27 112.54,35.27 112.67,35.14 112.67,34.5 112.54,34.38 110.76,34.38 108.22,31.84 105.05,31.84 101.87,28.66 ; 4 cut-outs
3D3V_S5_PCH on BOTTOM: 113.94,14.18 113.81,14.31 113.81,15.2 113.94,15.33 114.7,15.33 114.83,15.45 114.83,16.98 115.08,17.23 116.23,17.23 116.35,17.11 116.35,15.84 116.48,15.71 116.99,15.71 118.77,17.49 118.77,20.15 118.64,20.28 118.13,20.28 117.88,20.53 117.88,21.93 117.5,22.31 117.5,22.44 117.5,22.44 117.37,22.57 117.37,22.97 117.24,23.09 115.08,23.09 115.06,23.07 114.57,23.07 114.45,23.2 114.45,24.34 114.59,24.49 117.24,24.49 117.5,24.74 117.5,24.85 117.57,24.93 118,24.93 118.1,24.83 118.1,23.84 118.13,23.84 118.89,23.07 118.89,22.69 119.78,21.8 119.78,16.22 118.13,14.57 116.48,14.57 116.1,14.18 ; 4 cut-outs
3D3V_S5_PCH on BOTTOM: 136.04,36.92 135.91,37.04 135.91,39.46 136.16,39.71 137.43,39.71 137.69,39.46 137.69,37.04 137.56,36.92
3D3V_S5_PCH on L4: 105.05,32.85 112.92,24.98 114.32,24.98 115.08,24.22 115.08,23.07 114.96,22.95 114.7,22.95 113.94,23.71 112.03,23.71 104.41,31.33 104.41,32.6 104.67,32.85
3D3V_S5_PCH on L6: 102,33.03 104.98,33.03 105.41,32.59 105.41,32.14 105.21,31.93 102.29,31.93 101.73,32.49 101.73,32.75
3D3V_SEN_S0 on TOP: 68.47,95.72 67.58,96.61 67.58,101.43 67.71,101.56 68.73,101.56 69.11,101.18 70.12,101.18 70.25,101.05 70.25,96.48 69.49,95.72 ; 3 cut-outs
3D3V_SEN_S0 on BOTTOM: 69.39,96.23 69.24,96.38 69.24,99.27 69.36,99.4 70,99.4 70.2,99.2 70.2,96.25 70.17,96.23
3D3V_SPIVCC1 on BOTTOM: 171.09,11.26 170.84,11.52 170.84,13.04 168.3,15.58 167.79,15.58 167.28,16.09 167.28,16.6 167.41,16.72 169.57,16.72 171.22,15.07 172.74,15.07 172.99,14.82 172.99,13.17 172.36,12.53 172.36,11.52 172.11,11.26 ; 2 cut-outs
3D3V_SSD on TOP: 224.68,18.76 223.54,19.9 223.54,26.88 223.92,27.27 226.59,27.27 227.73,26.12 230.02,26.12 230.14,26 230.14,24.22 229.38,23.46 229.38,18.88 229.26,18.76 ; 6 cut-outs
3D3V_SSD on TOP: 224.18,8.22 223.92,8.47 223.92,12.28 224.56,12.91 229.26,12.91 229.64,12.53 229.64,10.12 229.26,9.74 227.35,9.74 225.83,8.22 ; 4 cut-outs
3D3V_SSD on BOTTOM: 222.4,8.22 222.02,8.6 222.02,9.87 221.89,9.99 220.62,9.99 219.98,10.63 219.98,10.76 220.24,11.01 220.49,11.01 220.87,10.63 224.81,10.63 225.06,10.88 225.06,22.69 224.51,23.25 222.14,23.25 222.14,27.65 226.21,27.65 227.6,26.25 227.6,18.12 227.73,17.99 228.24,17.99 228.49,17.74 228.49,17.11 228.37,16.98 227.73,16.98 227.6,16.85 227.6,9.49 226.33,8.22
3D3V_TPM on TOP: 208.43,31.84 208.05,32.22 208.05,34 208.3,34.25 208.68,34.25 208.94,34 210.08,34 210.21,33.87 210.21,33.49 210.08,33.36 209.57,33.36 209.32,33.11 208.81,33.11 208.68,32.98 208.68,31.96 208.55,31.84
3D3V_VGA_S0 on TOP: 166.77,75.78 166.26,76.29 166.26,78.7 166.39,78.83 167.03,78.83 167.28,79.08 167.91,79.08 168.17,78.83 168.17,76.92 168.3,76.8 168.3,75.91 168.17,75.78 ; 3 cut-outs
3D3V_VGA_S0 on BOTTOM: 182.65,76.72 182.58,76.78 180.88,76.78 180.74,76.92 180.74,79.46 180.87,79.59 182.01,79.59 182.14,79.46 182.14,77.94 182.39,77.68 183.15,77.68 183.28,77.56 183.28,76.72
+DC_IN on TOP: 21.36,86.07 21.36,87.84 21.1,88.1 17.8,88.1 17.55,88.35 17.55,89.24 17.67,89.37 25.93,89.37 26.69,88.61 26.69,86.32 26.44,86.07 ; 5 cut-outs
+DC_IN_C on TOP: 19.83,89.5 19.58,89.75 19.58,93.81 19.96,94.19 21.36,94.19 21.99,94.83 23.64,94.83 24.02,94.45 24.02,92.92 24.28,92.67 24.28,89.88 23.9,89.5 ; 4 cut-outs
+DC_IN_C on BOTTOM: 18.94,87.72 18.82,87.84 18.82,89.32 19.04,89.55 20.06,89.55 20.34,89.83 20.34,91.71 20.21,91.83 20.21,93.05 20.47,93.31 22.88,93.31 23.01,93.18 23.01,91.81 22.75,91.55 22.75,89.11 21.36,87.72
+SDC_IN on TOP: 23.26,78.32 23.13,78.45 23.13,80.61 23.26,80.73 24.28,80.73 24.4,80.86 24.4,81.24 24.53,81.37 25.04,81.37 25.17,81.49 25.17,82.26 25.42,82.51 26.94,82.51 27.07,82.38 27.07,81.75 27.71,81.11 27.71,79.34 27.07,79.34 26.94,79.21 26.94,78.7 26.56,78.32 ; 3 cut-outs
+SDC_IN on TOP: outline of 97 points within 28.34,39.46 197.38,96.99 ; 14 cut-outs
+SDC_IN on BOTTOM: 195.6,39.08 195.22,39.46 195.22,40.22 195.09,40.35 194.08,40.35 193.95,40.47 193.95,43.14 194.2,43.39 196.62,43.39 197.38,42.63 197.38,39.33 197.12,39.08
+SDC_IN on BOTTOM: 24.66,78.45 24.28,78.83 24.28,92.8 25.67,94.19 30.37,94.19 30.75,93.81 30.75,91.91 29.61,90.77 28.98,90.77 28.09,89.88 28.09,79.34 27.2,78.45
+V_VREF_PATH1 on TOP: 68.65,47.46 68.37,47.74 68.37,48.42 68.68,48.73 70.12,48.73 70.12,47.59 70,47.46 ; 1 cut-out
+V_VREF_PATH2 on TOP: 48.66,43.01 48.66,44.16 48.79,44.28 49.3,44.28 49.7,44.69 50.31,44.69 50.39,44.61 50.39,44.41 50.29,44.31 49.78,44.31 49.42,43.95 49.42,43.27 49.17,43.01 ; 1 cut-out
AD+ on TOP: 20.34,78.19 19.71,78.83 19.2,78.83 19.07,78.95 19.07,84.92 19.32,85.18 19.71,85.18 20.34,85.81 23.64,85.81 23.77,85.69 23.77,82.38 22.88,81.49 22.88,78.45 22.63,78.19 ; 6 cut-outs
AD_OFF_R on TOP: 17.93,86.07 17.55,86.45 17.55,87.72 17.67,87.84 20.98,87.84 21.23,87.59 21.23,86.07 ; 2 cut-outs
AUD_AGND on TOP: 1.54,11.52 1.51,11.55 1.51,12.24 2.15,12.24 2.86,12.54 3.16,13.25 3.16,14.66 3.2,14.69 8.91,14.69 9.67,13.93 9.67,11.77 9.42,11.52 ; 2 cut-outs
AUD_AGND on TOP: 1.51,0.51 1.51,2.59 11.9,2.59 12.87,3.34 12.41,4.47 12.41,6.44 12.85,6.44 13.48,5.8 13.48,0.51
AUD_AGND on BOTTOM: 1.51,0.51 1.51,2.59 11.9,2.59 12.87,3.34 12.41,4.47 12.41,8.03 12.59,8.22 13.48,8.22 13.61,8.09 14.63,8.09 14.88,7.83 14.88,7.58 13.61,6.31 13.61,0.6 13.52,0.51 ; 1 cut-out
AUD_AGND on BOTTOM: 21.1,11.52 20.59,12.03 19.96,12.03 19.71,12.28 19.71,12.79 19.83,12.91 20.21,12.91 20.59,13.3 21.48,13.3 21.99,12.79 22.63,12.79 22.88,12.53 22.88,11.77 22.63,11.52 ; 3 cut-outs
AUD_AGND on BOTTOM: 3.45,12.79 3.2,13.04 3.2,14.69 8.28,14.69 8.53,14.44 8.53,13.8 7.51,12.79
AUD_AGND on L2GND: 13.38,15.14 13.38,16.66 17.06,20.34 17.06,21.11 16.58,21.59 16.58,22.22 16.8,22.44 18.57,22.44 19.11,22.97 21.42,22.97 21.65,23.2 24.87,23.2 25.12,22.96 25.12,22.44 24.97,22.26 24.57,22.26 24.28,21.97 24.28,21.41 24.63,21.06 24.63,20.29 23.36,19.02 23.36,17.6 23.27,17.51 21.67,17.51 21.41,17.25 21.41,12.93 21.72,12.61 22.72,12.61 22.93,12.39 22.93,11.61 22.55,11.23 22.55,10.72 22.82,10.45 23.22,10.45 23.29,10.39 23.29,9.65 23.25,9.61 22.44,9.61 22.14,9.32 22.14,7.54 22.03,7.43 20.05,7.43 18.24,9.23 15.68,9.23 14.73,8.28 14.73,7.44 13.51,6.22 13.51,0.51 1.51,0.51 1.51,2.59 11.9,2.59 12.87,3.34 12.41,4.47 12.41,9.58 12.87,10.71 11.9,11.46 1.51,11.46 1.51,12.24 2.15,12.24 2.86,12.54 3.16,13.25 3.16,14.92 13.16,14.92
AUD_AGND on L3: 1.51,0.51 1.51,2.59 11.9,2.59 12.19,2.63 12.45,2.75 13.1,2.75 13.48,2.37 13.48,0.51
AUD_AGND on L3: 3.32,14.95 13.36,14.95 13.48,14.82 13.48,12.91 13.23,12.66 3.45,12.66 3.2,12.91 3.2,14.82
AUD_AGND on L4: 1.51,0.51 1.51,2.59 11.9,2.59 12.87,3.34 12.41,4.47 12.41,9.58 12.87,10.71 11.9,11.46 3,11.46 2.69,11.77 2.69,12.4 3.03,12.76 3.16,13.25 3.16,14.4 3.7,14.95 13.36,14.95 13.48,14.82 13.48,8.47 13.74,8.22 13.74,6.44 13.48,6.18 13.48,0.51
AUD_AGND on L7GND: 14.12,15.11 14.12,16.99 16.71,19.58 16.71,20.7 17.08,21.07 21.06,21.07 21.47,21.47 22.41,21.47 22.63,21.26 22.63,18.9 21.64,17.91 21.64,13.36 22.13,12.86 22.87,12.86 23.01,12.72 23.01,11.94 22.55,11.48 22.55,7.75 22.28,7.48 20.05,7.48 18.35,9.18 16.87,9.18 14.29,6.6 14.29,0.51 1.51,0.51 1.51,2.59 11.9,2.59 12.87,3.34 12.41,4.47 12.41,9.58 12.87,10.71 11.9,11.46 1.51,11.46 1.51,12.24 2.15,12.24 2.86,12.54 3.16,13.25 3.16,14.72 13.72,14.72
AUD_SPK_L+ on TOP: 34.44,2.75 34.31,2.88 28.47,2.88 25.93,5.42 25.17,5.42 23.52,7.07 23.52,10.37 23.64,10.5 23.9,10.5 24.02,10.37 24.02,7.96 25.55,6.44 26.31,6.44 28.85,3.9 34.18,3.9 34.31,4.02 34.95,4.02 34.95,2.75 ; 1 cut-out
AUD_SPK_L+_C on BOTTOM: 32.28,6.56 32.02,6.82 32.02,8.6 32.28,8.85 32.28,10.37 32.41,10.5 33.04,10.5 33.17,10.37 33.17,6.82 32.91,6.56
AUD_SPK_L- on TOP: 28.72,4.41 26.44,6.69 25.67,6.69 24.15,8.22 24.15,10.37 24.28,10.5 24.53,10.5 24.66,10.37 24.66,9.1 26.06,7.71 26.82,7.71 29.1,5.42 35.83,5.42 35.96,5.29 35.96,4.66 35.71,4.41 ; 2 cut-outs
AUD_SPK_L-_C on BOTTOM: 30.75,6.56 30.63,6.69 30.63,8.47 31.14,8.98 31.14,10.37 31.26,10.5 31.77,10.5 31.9,10.37 31.9,8.72 31.77,8.6 31.77,6.69 31.64,6.56
AUD_SPK_R+ on TOP: 26.56,9.49 25.93,10.12 25.55,10.12 24.79,10.88 24.79,11.01 24.91,11.14 25.17,11.14 25.36,10.95 25.42,11.01 26.56,11.01 27.07,10.5 30.5,10.5 30.63,10.37 30.63,9.74 30.37,9.49 ; 2 cut-outs
AUD_SPK_R+_C on TOP: 29.1,10.76 28.98,10.88 28.98,11.9 29.74,12.66 30.5,12.66 30.75,12.41 30.75,10.88 30.63,10.76
AUD_SPK_R+_C on BOTTOM: 29.23,8.98 28.98,9.23 28.98,11.39 29.1,11.52 29.61,11.52 29.87,11.26 29.87,8.98
AUD_SPK_R- on TOP: 31.64,7.83 31.39,8.09 26.18,8.09 24.91,9.36 24.91,10.25 25.04,10.37 25.17,10.37 25.55,9.99 25.8,9.99 26.69,9.1 31.01,9.1 31.26,9.36 32.79,9.36 32.91,9.23 32.91,7.96 32.79,7.83 ; 1 cut-out
AUD_SPK_R-_C on TOP: 31.77,9.61 31.52,9.87 31.52,11.52 31.64,11.64 32.91,11.64 33.04,11.52 33.04,9.74 32.91,9.61
AUD_SPK_R-_C on BOTTOM: 30.25,8.98 30.12,9.1 30.12,11.26 30.5,11.64 32.91,11.64 33.04,11.52 33.04,10.88 32.91,10.76 31.01,10.76 30.88,10.63 30.88,8.98
BT+ on TOP: 176.55,20.79 175.41,21.93 175.41,23.07 175.53,23.2 179.73,23.2 179.98,22.95 179.98,20.92 179.85,20.79
BT+ on BOTTOM: 173.76,19.52 170.84,22.44 170.84,28.28 171.09,28.54 171.98,28.54 172.23,28.79 172.23,29.93 172.36,30.06 173.63,30.06 174.77,28.92 174.77,23.84 175.2,23.41 179.65,23.41 179.65,20.1 179.06,19.52 ; 4 cut-outs
CFG_RCOMP on TOP: 127.09,68.4 127.04,68.45 127.04,68.78 127.21,68.95 127.21,69.11 126.77,69.56 126.77,70.32 126.89,70.45 127.4,70.45 127.66,70.19 127.66,69.94 127.91,69.68 127.91,68.92 127.9,68.91 127.9,68.54 127.76,68.4
DCBATOUT on TOP: 169.82,68.92 168.93,69.81 155.21,69.81 153.69,71.33 148.74,71.33 146.83,73.24 146.83,75.65 146.45,76.03 144.42,76.03 137.05,83.4 137.05,85.43 134.26,88.23 124.35,88.23 121.05,91.53 121.05,99.02 120.67,99.4 117.24,99.4 116.99,99.66 116.99,102.58 117.5,103.08 120.16,103.08 123.21,106.13 123.21,113.5 124.35,114.64 127.02,114.64 127.66,114.01 127.66,105.88 126.13,104.35 126.13,93.69 127.4,92.42 135.02,92.42 136.16,91.27 137.43,91.27 138.07,90.64 141.12,90.64 143.02,88.73 145.56,88.73 153.06,81.24 153.06,78.7 154.77,76.99 157.69,76.99 160.17,74.51 164.59,74.51 164.74,74.36 164.74,74.13 164.87,74 165.91,74 166.03,74.13 166.03,74.18 166.11,74.26 166.9,74.26 167.03,74.13 168.55,74.13 168.8,73.87 169.69,73.87 169.95,74.13 171.72,74.13 174.52,71.33 174.52,69.43 174.01,68.92 ; 11 cut-outs
DCBATOUT on TOP: 83.46,95.72 82.44,96.73 82.44,100.16 81.43,101.18 81.43,102.96 81.68,103.21 84.48,103.21 84.6,103.08 84.6,100.29 85.3,99.59 86.57,99.59 86.76,99.4 86.76,96.35 86.13,95.72 ; 2 cut-outs
DCBATOUT on TOP: 140.61,106.01 140.48,106.13 140.48,113.75 140.99,114.26 143.78,114.26 144.17,113.88 144.17,106.13 144.04,106.01
